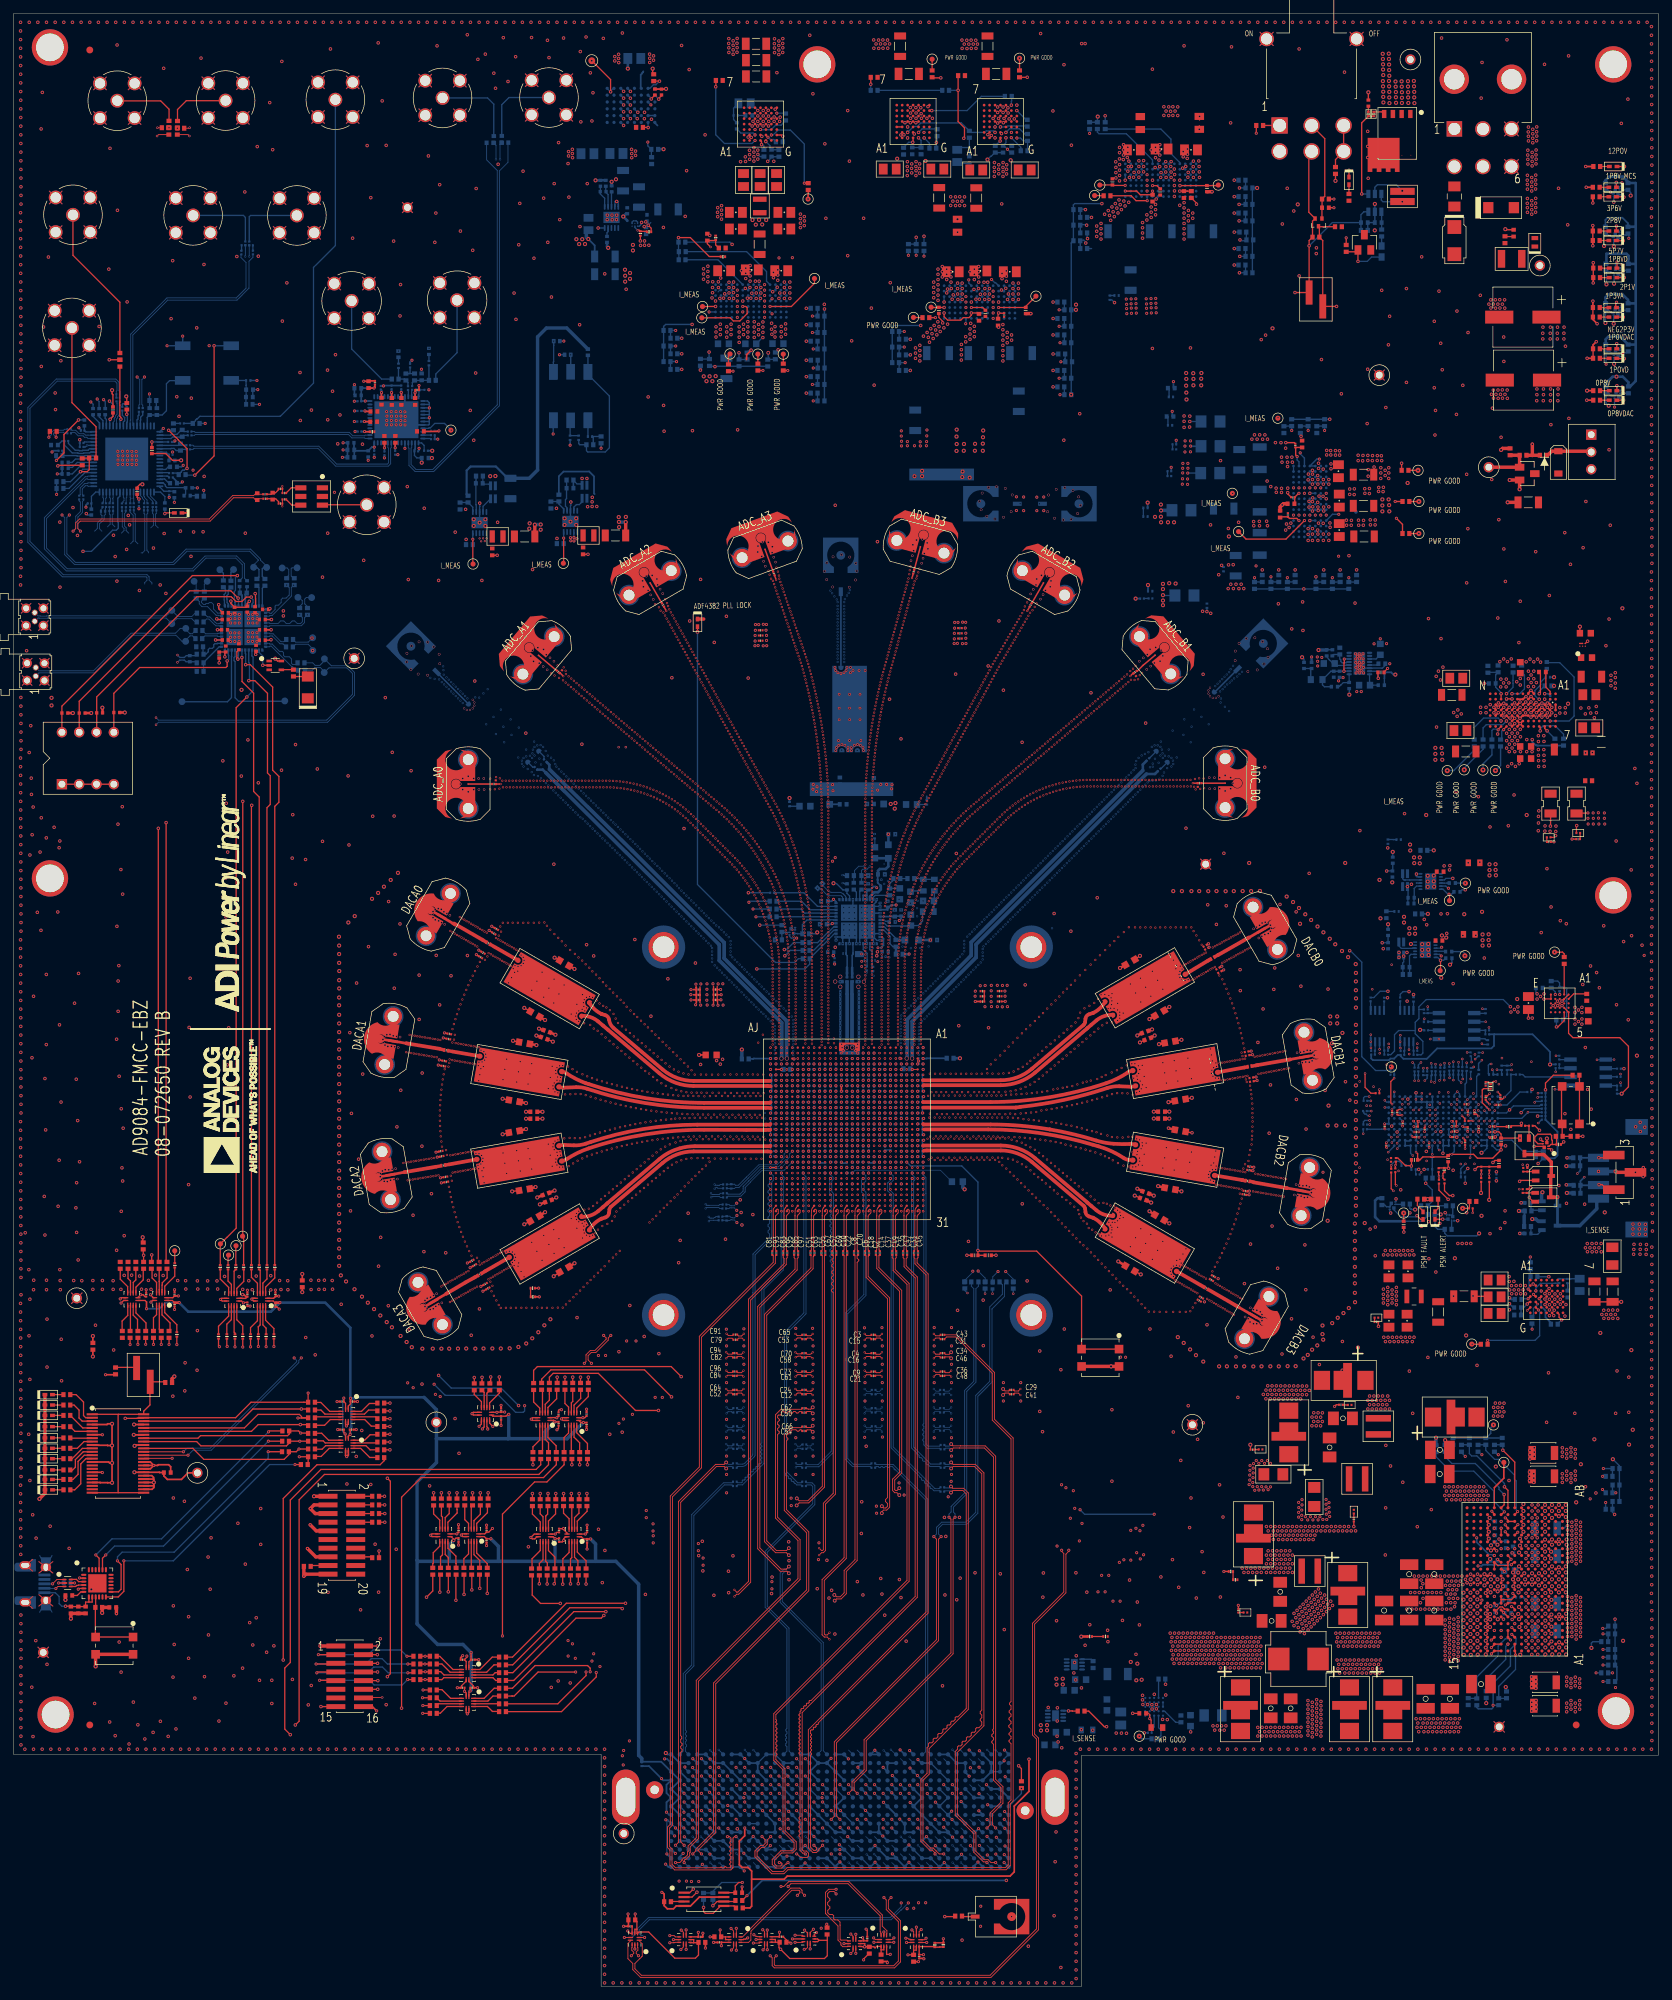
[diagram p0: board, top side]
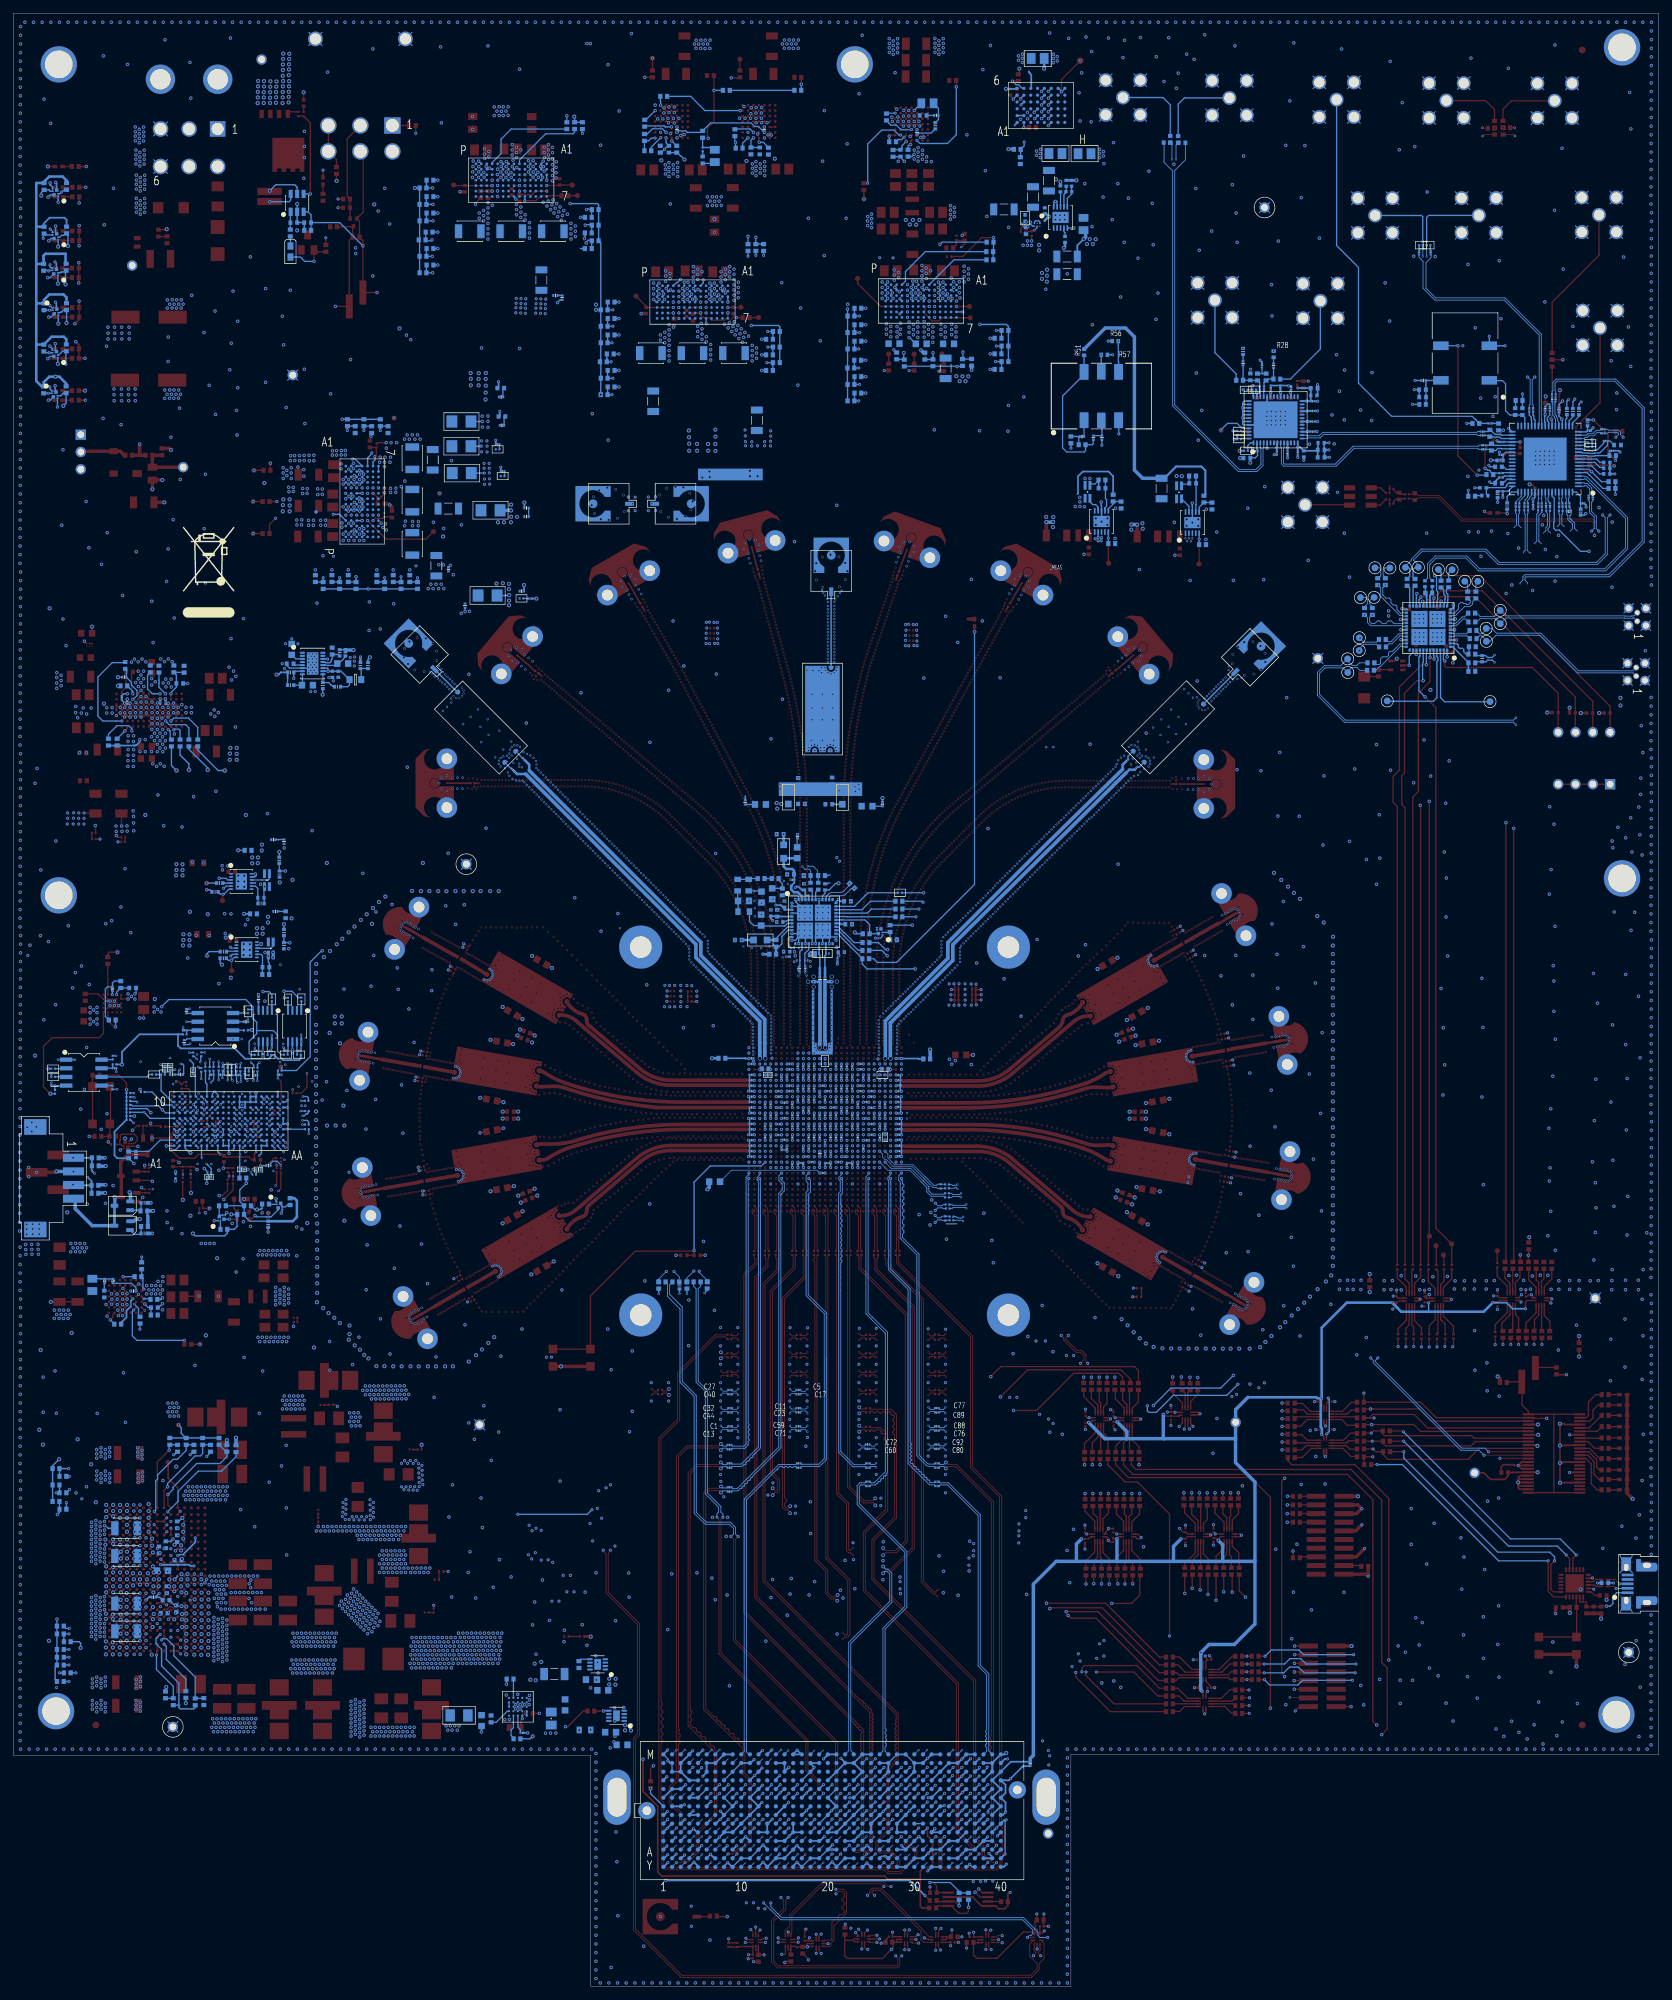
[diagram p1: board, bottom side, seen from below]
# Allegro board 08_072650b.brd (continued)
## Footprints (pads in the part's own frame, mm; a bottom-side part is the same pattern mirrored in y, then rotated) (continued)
BGA330_22X15H337
  round 0.457 smd: A1(-10.5,-7) A2(-10.5,-6) A3(-10.5,-5) A4(-10.5,-4) A5(-10.5,-3) A6(-10.5,-2) A7(-10.5,-1) A8(-10.5,0) A9(-10.5,1) A10(-10.5,2) A11(-10.5,3) A12(-10.5,4) A13(-10.5,5) A14(-10.5,6) A15(-10.5,7) AA1(9.5,-7) AA2(9.5,-6) AA3(9.5,-5) AA4(9.5,-4) AA5(9.5,-3) AA6(9.5,-2) AA7(9.5,-1) AA8(9.5,0) AA9(9.5,1) AA10(9.5,2) AA11(9.5,3) AA12(9.5,4) AA13(9.5,5) AA14(9.5,6) AA15(9.5,7) AB1(10.5,-7) AB2(10.5,-6) AB3(10.5,-5) AB4(10.5,-4) AB5(10.5,-3) AB6(10.5,-2) AB7(10.5,-1) AB8(10.5,0) AB9(10.5,1) AB10(10.5,2) AB11(10.5,3) AB12(10.5,4) AB13(10.5,5) AB14(10.5,6) AB15(10.5,7) B1(-9.5,-7) B2(-9.5,-6) B3(-9.5,-5) B4(-9.5,-4) B5(-9.5,-3) B6(-9.5,-2) B7(-9.5,-1) B8(-9.5,0) B9(-9.5,1) B10(-9.5,2) B11(-9.5,3) B12(-9.5,4) B13(-9.5,5) B14(-9.5,6) B15(-9.5,7) C1(-8.5,-7) C2(-8.5,-6) C3(-8.5,-5) C4(-8.5,-4) C5(-8.5,-3) C6(-8.5,-2) C7(-8.5,-1) C8(-8.5,0) C9(-8.5,1) C10(-8.5,2) C11(-8.5,3) C12(-8.5,4) C13(-8.5,5) C14(-8.5,6) C15(-8.5,7) D1(-7.5,-7) D2(-7.5,-6) D3(-7.5,-5) D4(-7.5,-4) D5(-7.5,-3) D6(-7.5,-2) D7(-7.5,-1) D8(-7.5,0) D9(-7.5,1) D10(-7.5,2) D11(-7.5,3) D12(-7.5,4) D13(-7.5,5) D14(-7.5,6) D15(-7.5,7) E1(-6.5,-7) E2(-6.5,-6) E3(-6.5,-5) E4(-6.5,-4) E5(-6.5,-3) E6(-6.5,-2) E7(-6.5,-1) E8(-6.5,0) E9(-6.5,1) E10(-6.5,2) E11(-6.5,3) E12(-6.5,4) E13(-6.5,5) E14(-6.5,6) E15(-6.5,7) F1(-5.5,-7) F2(-5.5,-6) F3(-5.5,-5) F4(-5.5,-4) F5(-5.5,-3) F6(-5.5,-2) F7(-5.5,-1) F8(-5.5,0) F9(-5.5,1) F10(-5.5,2) F11(-5.5,3) F12(-5.5,4) F13(-5.5,5) F14(-5.5,6) F15(-5.5,7) G1(-4.5,-7) G2(-4.5,-6) G3(-4.5,-5) G4(-4.5,-4) G5(-4.5,-3) G6(-4.5,-2) G7(-4.5,-1) G8(-4.5,0) G9(-4.5,1) G10(-4.5,2) G11(-4.5,3) G12(-4.5,4) G13(-4.5,5) G14(-4.5,6) G15(-4.5,7) H1(-3.5,-7) H2(-3.5,-6) H3(-3.5,-5) H4(-3.5,-4) H5(-3.5,-3) H6(-3.5,-2) H7(-3.5,-1) H8(-3.5,0) H9(-3.5,1) H10(-3.5,2) H11(-3.5,3) H12(-3.5,4) H13(-3.5,5) H14(-3.5,6) H15(-3.5,7) J1(-2.5,-7) J2(-2.5,-6) J3(-2.5,-5) J4(-2.5,-4) J5(-2.5,-3) J6(-2.5,-2) J7(-2.5,-1) J8(-2.5,0) J9(-2.5,1) J10(-2.5,2) J11(-2.5,3) J12(-2.5,4) J13(-2.5,5) J14(-2.5,6) J15(-2.5,7) K1(-1.5,-7) K2(-1.5,-6) K3(-1.5,-5) K4(-1.5,-4) K5(-1.5,-3) K6(-1.5,-2) K7(-1.5,-1) K8(-1.5,0) K9(-1.5,1) K10(-1.5,2) K11(-1.5,3) K12(-1.5,4) K13(-1.5,5) K14(-1.5,6) K15(-1.5,7) L1(-0.5,-7) L2(-0.5,-6) L3(-0.5,-5) L4(-0.5,-4) L5(-0.5,-3) L6(-0.5,-2) L7(-0.5,-1) L8(-0.5,0) L9(-0.5,1) L10(-0.5,2) L11(-0.5,3) L12(-0.5,4) L13(-0.5,5) L14(-0.5,6) L15(-0.5,7) M1(0.5,-7) M2(0.5,-6) M3(0.5,-5) M4(0.5,-4) M5(0.5,-3) M6(0.5,-2) M7(0.5,-1) M8(0.5,0) M9(0.5,1) M10(0.5,2) M11(0.5,3) M12(0.5,4) M13(0.5,5) M14(0.5,6) M15(0.5,7) N1(1.5,-7) N2(1.5,-6) N3(1.5,-5) N4(1.5,-4) N5(1.5,-3) N6(1.5,-2) N7(1.5,-1) N8(1.5,0) N9(1.5,1) N10(1.5,2) N11(1.5,3) N12(1.5,4) N13(1.5,5) N14(1.5,6) N15(1.5,7) P1(2.5,-7) P2(2.5,-6) P3(2.5,-5) P4(2.5,-4) P5(2.5,-3) P6(2.5,-2) P7(2.5,-1) P8(2.5,0) P9(2.5,1) P10(2.5,2) P11(2.5,3) P12(2.5,4) P13(2.5,5) P14(2.5,6) P15(2.5,7) R1(3.5,-7) R2(3.5,-6) R3(3.5,-5) R4(3.5,-4) R5(3.5,-3) R6(3.5,-2) R7(3.5,-1) R8(3.5,0) R9(3.5,1) R10(3.5,2) R11(3.5,3) R12(3.5,4) R13(3.5,5) R14(3.5,6) R15(3.5,7) T1(4.5,-7) T2(4.5,-6) T3(4.5,-5) T4(4.5,-4) T5(4.5,-3) T6(4.5,-2) T7(4.5,-1) T8(4.5,0) T9(4.5,1) T10(4.5,2) T11(4.5,3) T12(4.5,4) T13(4.5,5) T14(4.5,6) T15(4.5,7) U1(5.5,-7) U2(5.5,-6) U3(5.5,-5) U4(5.5,-4) U5(5.5,-3) U6(5.5,-2) U7(5.5,-1) U8(5.5,0) U9(5.5,1) U10(5.5,2) U11(5.5,3) U12(5.5,4) U13(5.5,5) U14(5.5,6) U15(5.5,7) V1(6.5,-7) V2(6.5,-6) V3(6.5,-5) V4(6.5,-4) V5(6.5,-3) V6(6.5,-2) V7(6.5,-1) V8(6.5,0) V9(6.5,1) V10(6.5,2) V11(6.5,3) V12(6.5,4) V13(6.5,5) V14(6.5,6) V15(6.5,7) W1(7.5,-7) W2(7.5,-6) W3(7.5,-5) W4(7.5,-4) W5(7.5,-3) W6(7.5,-2) W7(7.5,-1) W8(7.5,0) W9(7.5,1) W10(7.5,2) W11(7.5,3) W12(7.5,4) W13(7.5,5) W14(7.5,6) W15(7.5,7) Y1(8.5,-7) Y2(8.5,-6) Y3(8.5,-5) Y4(8.5,-4) Y5(8.5,-3) Y6(8.5,-2) Y7(8.5,-1) Y8(8.5,0) Y9(8.5,1) Y10(8.5,2) Y11(8.5,3) Y12(8.5,4) Y13(8.5,5) Y14(8.5,6) Y15(8.5,7)
BGA899
  round 0.356 smd: A1(-11.2,-12) A2(-11.2,-11.2) A3(-11.2,-10.4) A4(-11.2,-9.6) A5(-11.2,-8.8) A6(-11.2,-8) A7(-11.2,-7.2) A8(-11.2,-6.4) A9(-11.2,-5.6) A10(-11.2,-4.8) A11(-11.2,-4) A12(-11.2,-3.2) A13(-11.2,-2.4) A14(-11.2,-1.6) A15(-11.2,-0.8) A16(-11.2,0) A17(-11.2,0.8) A18(-11.2,1.6) A19(-11.2,2.4) A20(-11.2,3.2) A21(-11.2,4) A22(-11.2,4.8) A23(-11.2,5.6) A24(-11.2,6.4) A25(-11.2,7.2) A26(-11.2,8) A27(-11.2,8.8) A28(-11.2,9.6) A29(-11.2,10.4) A30(-11.2,11.2) A31(-11.2,12) AA1(4.8,-12) AA2(4.8,-11.2) AA3(4.8,-10.4) AA4(4.8,-9.6) AA5(4.8,-8.8) AA6(4.8,-8) AA7(4.8,-7.2) AA8(4.8,-6.4) AA9(4.8,-5.6) AA10(4.8,-4.8) AA11(4.8,-4) AA12(4.8,-3.2) AA13(4.8,-2.4) AA14(4.8,-1.6) AA15(4.8,-0.8) AA16(4.8,0) AA17(4.8,0.8) AA18(4.8,1.6) AA19(4.8,2.4) AA20(4.8,3.2) AA21(4.8,4) AA22(4.8,4.8) AA23(4.8,5.6) AA24(4.8,6.4) AA25(4.8,7.2) AA26(4.8,8) AA27(4.8,8.8) AA28(4.8,9.6) AA29(4.8,10.4) AA30(4.8,11.2) AA31(4.8,12) AB1(5.6,-12) AB2(5.6,-11.2) AB3(5.6,-10.4) AB4(5.6,-9.6) AB5(5.6,-8.8) AB6(5.6,-8) AB7(5.6,-7.2) AB8(5.6,-6.4) AB9(5.6,-5.6) AB10(5.6,-4.8) AB11(5.6,-4) AB12(5.6,-3.2) AB13(5.6,-2.4) AB14(5.6,-1.6) AB15(5.6,-0.8) AB16(5.6,0) AB17(5.6,0.8) AB18(5.6,1.6) AB19(5.6,2.4) AB20(5.6,3.2) AB21(5.6,4) AB22(5.6,4.8) AB23(5.6,5.6) AB24(5.6,6.4) AB25(5.6,7.2) AB26(5.6,8) AB27(5.6,8.8) AB28(5.6,9.6) AB29(5.6,10.4) AB30(5.6,11.2) AB31(5.6,12) AC1(6.4,-12) AC2(6.4,-11.2) AC3(6.4,-10.4) AC4(6.4,-9.6) AC5(6.4,-8.8) AC6(6.4,-8) AC7(6.4,-7.2) AC8(6.4,-6.4) AC9(6.4,-5.6) AC10(6.4,-4.8) AC11(6.4,-4) AC12(6.4,-3.2) AC13(6.4,-2.4) AC14(6.4,-1.6) AC15(6.4,-0.8) AC16(6.4,0) AC17(6.4,0.8) AC18(6.4,1.6) AC19(6.4,2.4) AC20(6.4,3.2) AC21(6.4,4) AC22(6.4,4.8) AC23(6.4,5.6) AC24(6.4,6.4) AC25(6.4,7.2) AC26(6.4,8) AC27(6.4,8.8) AC28(6.4,9.6) AC29(6.4,10.4) AC30(6.4,11.2) AC31(6.4,12) AD1(7.2,-12) AD2(7.2,-11.2) AD3(7.2,-10.4) AD4(7.2,-9.6) AD5(7.2,-8.8) AD6(7.2,-8) AD7(7.2,-7.2) AD8(7.2,-6.4) AD9(7.2,-5.6) AD10(7.2,-4.8) AD11(7.2,-4) AD12(7.2,-3.2) AD13(7.2,-2.4) AD14(7.2,-1.6) AD15(7.2,-0.8) AD16(7.2,0) AD17(7.2,0.8) AD18(7.2,1.6) AD19(7.2,2.4) AD20(7.2,3.2) AD21(7.2,4) AD22(7.2,4.8) AD23(7.2,5.6) AD24(7.2,6.4) AD25(7.2,7.2) AD26(7.2,8) AD27(7.2,8.8) AD28(7.2,9.6) AD29(7.2,10.4) AD30(7.2,11.2) AD31(7.2,12) AE1(8,-12) AE2(8,-11.2) AE3(8,-10.4) AE4(8,-9.6) AE5(8,-8.8) AE6(8,-8) AE7(8,-7.2) AE8(8,-6.4) AE9(8,-5.6) AE10(8,-4.8) AE11(8,-4) AE12(8,-3.2) AE13(8,-2.4) AE14(8,-1.6) AE15(8,-0.8) AE16(8,0) AE17(8,0.8) AE18(8,1.6) AE19(8,2.4) AE20(8,3.2) AE21(8,4) AE22(8,4.8) AE23(8,5.6) AE24(8,6.4) AE25(8,7.2) AE26(8,8) AE27(8,8.8) AE28(8,9.6) AE29(8,10.4) AE30(8,11.2) AE31(8,12) AF1(8.8,-12) AF2(8.8,-11.2) AF3(8.8,-10.4) AF4(8.8,-9.6) AF5(8.8,-8.8) AF6(8.8,-8) AF7(8.8,-7.2) AF8(8.8,-6.4) AF9(8.8,-5.6) AF10(8.8,-4.8) AF11(8.8,-4) AF12(8.8,-3.2) AF13(8.8,-2.4) AF14(8.8,-1.6) AF15(8.8,-0.8) AF16(8.8,0) AF17(8.8,0.8) AF18(8.8,1.6) AF19(8.8,2.4) AF20(8.8,3.2) AF21(8.8,4) AF22(8.8,4.8) AF23(8.8,5.6) AF24(8.8,6.4) AF25(8.8,7.2) AF26(8.8,8) AF27(8.8,8.8) AF28(8.8,9.6) AF29(8.8,10.4) AF30(8.8,11.2) AF31(8.8,12) AG1(9.6,-12) AG2(9.6,-11.2) AG3(9.6,-10.4) AG4(9.6,-9.6) AG5(9.6,-8.8) AG6(9.6,-8) AG7(9.6,-7.2) AG8(9.6,-6.4) AG9(9.6,-5.6) AG10(9.6,-4.8) AG11(9.6,-4) AG12(9.6,-3.2) AG13(9.6,-2.4) AG14(9.6,-1.6) AG15(9.6,-0.8) AG16(9.6,0) AG17(9.6,0.8) AG18(9.6,1.6) AG19(9.6,2.4) AG20(9.6,3.2) AG21(9.6,4) AG22(9.6,4.8) AG23(9.6,5.6) AG24(9.6,6.4) AG25(9.6,7.2) AG26(9.6,8) AG27(9.6,8.8) AG28(9.6,9.6) AG29(9.6,10.4) AG30(9.6,11.2) AG31(9.6,12) AH1(10.4,-12) AH2(10.4,-11.2) AH3(10.4,-10.4) AH4(10.4,-9.6) AH5(10.4,-8.8) AH6(10.4,-8) AH7(10.4,-7.2) AH8(10.4,-6.4) AH9(10.4,-5.6) AH10(10.4,-4.8) AH11(10.4,-4) AH12(10.4,-3.2) AH13(10.4,-2.4) AH14(10.4,-1.6) AH15(10.4,-0.8) AH16(10.4,0) AH17(10.4,0.8) AH18(10.4,1.6) AH19(10.4,2.4) AH20(10.4,3.2) AH21(10.4,4) AH22(10.4,4.8) AH23(10.4,5.6) AH24(10.4,6.4) AH25(10.4,7.2) AH26(10.4,8) AH27(10.4,8.8) AH28(10.4,9.6) AH29(10.4,10.4) AH30(10.4,11.2) AH31(10.4,12) AJ1(11.2,-12) AJ2(11.2,-11.2) AJ3(11.2,-10.4) AJ4(11.2,-9.6) AJ5(11.2,-8.8) AJ6(11.2,-8) AJ7(11.2,-7.2) AJ8(11.2,-6.4) AJ9(11.2,-5.6) AJ10(11.2,-4.8) AJ11(11.2,-4) AJ12(11.2,-3.2) AJ13(11.2,-2.4) AJ14(11.2,-1.6) AJ15(11.2,-0.8) AJ16(11.2,0) AJ17(11.2,0.8) AJ18(11.2,1.6) AJ19(11.2,2.4) AJ20(11.2,3.2) AJ21(11.2,4) AJ22(11.2,4.8) AJ23(11.2,5.6) AJ24(11.2,6.4) AJ25(11.2,7.2) AJ26(11.2,8) AJ27(11.2,8.8) AJ28(11.2,9.6) AJ29(11.2,10.4) AJ30(11.2,11.2) AJ31(11.2,12) B1(-10.4,-12) B2(-10.4,-11.2) B3(-10.4,-10.4) B4(-10.4,-9.6) B5(-10.4,-8.8) B6(-10.4,-8) B7(-10.4,-7.2) B8(-10.4,-6.4) B9(-10.4,-5.6) B10(-10.4,-4.8) B11(-10.4,-4) B12(-10.4,-3.2) B13(-10.4,-2.4) B14(-10.4,-1.6) B15(-10.4,-0.8) B16(-10.4,0) B17(-10.4,0.8) B18(-10.4,1.6) B19(-10.4,2.4) B20(-10.4,3.2) B21(-10.4,4) B22(-10.4,4.8) B23(-10.4,5.6) B24(-10.4,6.4) B25(-10.4,7.2) B26(-10.4,8) B27(-10.4,8.8) B28(-10.4,9.6) B29(-10.4,10.4) B30(-10.4,11.2) B31(-10.4,12) C1(-9.6,-12) C2(-9.6,-11.2) C3(-9.6,-10.4) C4(-9.6,-9.6) C5(-9.6,-8.8) C6(-9.6,-8) C7(-9.6,-7.2) C8(-9.6,-6.4) C9(-9.6,-5.6) C10(-9.6,-4.8) C11(-9.6,-4) C12(-9.6,-3.2) C13(-9.6,-2.4) C14(-9.6,-1.6) C15(-9.6,-0.8) C16(-9.6,0) C17(-9.6,0.8) C18(-9.6,1.6) C19(-9.6,2.4) C20(-9.6,3.2) C21(-9.6,4) C22(-9.6,4.8) C23(-9.6,5.6) C24(-9.6,6.4) C25(-9.6,7.2) C26(-9.6,8) C27(-9.6,8.8) C28(-9.6,9.6) C29(-9.6,10.4) C30(-9.6,11.2) C31(-9.6,12) D1(-8.8,-12) D2(-8.8,-11.2) D3(-8.8,-10.4) D4(-8.8,-9.6) D5(-8.8,-8.8) D6(-8.8,-8) D7(-8.8,-7.2) D8(-8.8,-6.4) D9(-8.8,-5.6) D10(-8.8,-4.8) D11(-8.8,-4) D12(-8.8,-3.2) D13(-8.8,-2.4) D14(-8.8,-1.6) D15(-8.8,-0.8) D16(-8.8,0) D17(-8.8,0.8) D18(-8.8,1.6) D19(-8.8,2.4) D20(-8.8,3.2) D21(-8.8,4) D22(-8.8,4.8) D23(-8.8,5.6) D24(-8.8,6.4) D25(-8.8,7.2) D26(-8.8,8) D27(-8.8,8.8) D28(-8.8,9.6) D29(-8.8,10.4) D30(-8.8,11.2) D31(-8.8,12) E1(-8,-12) E2(-8,-11.2) E3(-8,-10.4) E4(-8,-9.6) E5(-8,-8.8) E6(-8,-8) E7(-8,-7.2) E8(-8,-6.4) E9(-8,-5.6) E10(-8,-4.8) E11(-8,-4) E12(-8,-3.2) E13(-8,-2.4) E14(-8,-1.6) E15(-8,-0.8) E16(-8,0) E17(-8,0.8) E18(-8,1.6) E19(-8,2.4) E20(-8,3.2) E21(-8,4) E22(-8,4.8) E23(-8,5.6) E24(-8,6.4) E25(-8,7.2) E26(-8,8) E27(-8,8.8) E28(-8,9.6) E29(-8,10.4) E30(-8,11.2) E31(-8,12) F1(-7.2,-12) F2(-7.2,-11.2) F3(-7.2,-10.4) F4(-7.2,-9.6) F5(-7.2,-8.8) F6(-7.2,-8) F7(-7.2,-7.2) F8(-7.2,-6.4) F9(-7.2,-5.6) F10(-7.2,-4.8) F11(-7.2,-4) F12(-7.2,-3.2) F13(-7.2,-2.4) F14(-7.2,-1.6) F15(-7.2,-0.8) F16(-7.2,0) F17(-7.2,0.8) F18(-7.2,1.6) F19(-7.2,2.4) F20(-7.2,3.2) F21(-7.2,4) F22(-7.2,4.8) F23(-7.2,5.6) F24(-7.2,6.4) F25(-7.2,7.2) F26(-7.2,8) F27(-7.2,8.8) F28(-7.2,9.6) F29(-7.2,10.4) F30(-7.2,11.2) F31(-7.2,12) G1(-6.4,-12) G2(-6.4,-11.2) G3(-6.4,-10.4) G4(-6.4,-9.6) G5(-6.4,-8.8) G6(-6.4,-8) G7(-6.4,-7.2) G8(-6.4,-6.4) G9(-6.4,-5.6) G10(-6.4,-4.8) G11(-6.4,-4) G12(-6.4,-3.2) G13(-6.4,-2.4) G14(-6.4,-1.6) G15(-6.4,-0.8) G16(-6.4,0) G17(-6.4,0.8) G18(-6.4,1.6) G19(-6.4,2.4) G20(-6.4,3.2) G21(-6.4,4) G22(-6.4,4.8) G23(-6.4,5.6) G24(-6.4,6.4) G25(-6.4,7.2) G26(-6.4,8) G27(-6.4,8.8) G28(-6.4,9.6) G29(-6.4,10.4) G30(-6.4,11.2) G31(-6.4,12) H1(-5.6,-12) H2(-5.6,-11.2) H3(-5.6,-10.4) H4(-5.6,-9.6) H5(-5.6,-8.8) H6(-5.6,-8) H7(-5.6,-7.2) H8(-5.6,-6.4) H9(-5.6,-5.6) H10(-5.6,-4.8) H11(-5.6,-4) H12(-5.6,-3.2) H13(-5.6,-2.4) H14(-5.6,-1.6) H15(-5.6,-0.8) H16(-5.6,0) H17(-5.6,0.8) H18(-5.6,1.6) H19(-5.6,2.4) H20(-5.6,3.2) H21(-5.6,4) H22(-5.6,4.8) H23(-5.6,5.6) H24(-5.6,6.4) H25(-5.6,7.2) H26(-5.6,8) H27(-5.6,8.8) H28(-5.6,9.6) H29(-5.6,10.4) H30(-5.6,11.2) H31(-5.6,12) J1(-4.8,-12) J2(-4.8,-11.2) J3(-4.8,-10.4) J4(-4.8,-9.6) J5(-4.8,-8.8) J6(-4.8,-8) J7(-4.8,-7.2) J8(-4.8,-6.4) J9(-4.8,-5.6) J10(-4.8,-4.8) J11(-4.8,-4) J12(-4.8,-3.2) J13(-4.8,-2.4) J14(-4.8,-1.6) J15(-4.8,-0.8) J16(-4.8,0) J17(-4.8,0.8) J18(-4.8,1.6) J19(-4.8,2.4) J20(-4.8,3.2) J21(-4.8,4) J22(-4.8,4.8) J23(-4.8,5.6) J24(-4.8,6.4) J25(-4.8,7.2) J26(-4.8,8) J27(-4.8,8.8) J28(-4.8,9.6) J29(-4.8,10.4) J30(-4.8,11.2) J31(-4.8,12) K1(-4,-12) K2(-4,-11.2) K3(-4,-10.4) K4(-4,-9.6) K5(-4,-8.8) K6(-4,-8) K7(-4,-7.2) K8(-4,-6.4) K9(-4,-5.6) K10(-4,-4.8) K11(-4,-4) K12(-4,-3.2) K13(-4,-2.4) K14(-4,-1.6) K15(-4,-0.8) K16(-4,0) K17(-4,0.8) K18(-4,1.6) K19(-4,2.4) K20(-4,3.2) K21(-4,4) K22(-4,4.8) K23(-4,5.6) K24(-4,6.4) K25(-4,7.2) K26(-4,8) K27(-4,8.8) K28(-4,9.6) K29(-4,10.4) K30(-4,11.2) K31(-4,12) L1(-3.2,-12) L2(-3.2,-11.2) L3(-3.2,-10.4) L4(-3.2,-9.6) L5(-3.2,-8.8) L6(-3.2,-8) L7(-3.2,-7.2) L8(-3.2,-6.4) L9(-3.2,-5.6) L10(-3.2,-4.8) L11(-3.2,-4) L12(-3.2,-3.2) L13(-3.2,-2.4) L14(-3.2,-1.6) L15(-3.2,-0.8) L16(-3.2,0) L17(-3.2,0.8) L18(-3.2,1.6) L19(-3.2,2.4) L20(-3.2,3.2) L21(-3.2,4) L22(-3.2,4.8) L23(-3.2,5.6) L24(-3.2,6.4) L25(-3.2,7.2) L26(-3.2,8) L27(-3.2,8.8) L28(-3.2,9.6) L29(-3.2,10.4) L30(-3.2,11.2) L31(-3.2,12) M1(-2.4,-12) M2(-2.4,-11.2) M3(-2.4,-10.4) M4(-2.4,-9.6) M5(-2.4,-8.8) M6(-2.4,-8) M7(-2.4,-7.2) M8(-2.4,-6.4) M9(-2.4,-5.6) M10(-2.4,-4.8) M11(-2.4,-4) M12(-2.4,-3.2) M13(-2.4,-2.4) M14(-2.4,-1.6) M15(-2.4,-0.8) M16(-2.4,0) M17(-2.4,0.8) M18(-2.4,1.6) M19(-2.4,2.4) M20(-2.4,3.2) M21(-2.4,4) M22(-2.4,4.8) M23(-2.4,5.6) M24(-2.4,6.4) M25(-2.4,7.2) M26(-2.4,8) M27(-2.4,8.8) M28(-2.4,9.6) M29(-2.4,10.4) M30(-2.4,11.2) M31(-2.4,12) N1(-1.6,-12) N2(-1.6,-11.2) N3(-1.6,-10.4) N4(-1.6,-9.6) N5(-1.6,-8.8) N6(-1.6,-8) N7(-1.6,-7.2) N8(-1.6,-6.4) N9(-1.6,-5.6) N10(-1.6,-4.8) N11(-1.6,-4) N12(-1.6,-3.2) N13(-1.6,-2.4) N14(-1.6,-1.6) N15(-1.6,-0.8) N16(-1.6,0) N17(-1.6,0.8) N18(-1.6,1.6) N19(-1.6,2.4) N20(-1.6,3.2) N21(-1.6,4) N22(-1.6,4.8) N23(-1.6,5.6) N24(-1.6,6.4) N25(-1.6,7.2) N26(-1.6,8) N27(-1.6,8.8) N28(-1.6,9.6) N29(-1.6,10.4) N30(-1.6,11.2) N31(-1.6,12) P1(-0.8,-12) P2(-0.8,-11.2) P3(-0.8,-10.4) P4(-0.8,-9.6) P5(-0.8,-8.8) P6(-0.8,-8) P7(-0.8,-7.2) P8(-0.8,-6.4) P9(-0.8,-5.6) P10(-0.8,-4.8) P11(-0.8,-4) P12(-0.8,-3.2) P13(-0.8,-2.4) P14(-0.8,-1.6) P15(-0.8,-0.8) P16(-0.8,0) P17(-0.8,0.8) P18(-0.8,1.6) P19(-0.8,2.4) P20(-0.8,3.2) P21(-0.8,4) P22(-0.8,4.8) P23(-0.8,5.6) P24(-0.8,6.4) P25(-0.8,7.2) P26(-0.8,8) P27(-0.8,8.8) P28(-0.8,9.6) P29(-0.8,10.4) P30(-0.8,11.2) P31(-0.8,12) R1(0,-12) R2(0,-11.2) R3(0,-10.4) R4(0,-9.6) R5(0,-8.8) R6(0,-8) R7(0,-7.2) R8(0,-6.4) R9(0,-5.6) R10(0,-4.8) R11(0,-4) R12(0,-3.2) R13(0,-2.4) R14(0,-1.6) R15(0,-0.8) R16(0,0) R17(0,0.8) R18(0,1.6) R19(0,2.4) R20(0,3.2) R21(0,4) R22(0,4.8) R23(0,5.6) R24(0,6.4) R25(0,7.2) R26(0,8) R27(0,8.8) R28(0,9.6) R29(0,10.4) R30(0,11.2) R31(0,12) T1(0.8,-12) T2(0.8,-11.2) T3(0.8,-10.4) T4(0.8,-9.6) T5(0.8,-8.8) T6(0.8,-8) T7(0.8,-7.2) T8(0.8,-6.4) T9(0.8,-5.6) T10(0.8,-4.8) T11(0.8,-4) T12(0.8,-3.2) T13(0.8,-2.4) T14(0.8,-1.6) T15(0.8,-0.8) T16(0.8,0) T17(0.8,0.8) T18(0.8,1.6) T19(0.8,2.4) T20(0.8,3.2) T21(0.8,4) T22(0.8,4.8) T23(0.8,5.6) T24(0.8,6.4) T25(0.8,7.2) T26(0.8,8) T27(0.8,8.8) T28(0.8,9.6) T29(0.8,10.4) T30(0.8,11.2) T31(0.8,12) U1(1.6,-12) U2(1.6,-11.2) U3(1.6,-10.4) U4(1.6,-9.6) U5(1.6,-8.8) U6(1.6,-8) U7(1.6,-7.2) U8(1.6,-6.4) U9(1.6,-5.6) U10(1.6,-4.8) U11(1.6,-4) U12(1.6,-3.2) U13(1.6,-2.4) U14(1.6,-1.6) U15(1.6,-0.8) U16(1.6,0) U17(1.6,0.8) U18(1.6,1.6) U19(1.6,2.4) U20(1.6,3.2) U21(1.6,4) U22(1.6,4.8) U23(1.6,5.6) U24(1.6,6.4) U25(1.6,7.2) U26(1.6,8) U27(1.6,8.8) U28(1.6,9.6) U29(1.6,10.4) U30(1.6,11.2) U31(1.6,12) V1(2.4,-12) V2(2.4,-11.2) V3(2.4,-10.4) V4(2.4,-9.6) V5(2.4,-8.8) V6(2.4,-8) V7(2.4,-7.2) V8(2.4,-6.4) V9(2.4,-5.6) V10(2.4,-4.8) V11(2.4,-4) V12(2.4,-3.2) V13(2.4,-2.4) V14(2.4,-1.6) V15(2.4,-0.8) V16(2.4,0) V17(2.4,0.8) V18(2.4,1.6) V19(2.4,2.4) V20(2.4,3.2) V21(2.4,4) V22(2.4,4.8) V23(2.4,5.6) V24(2.4,6.4) V25(2.4,7.2) V26(2.4,8) V27(2.4,8.8) V28(2.4,9.6) V29(2.4,10.4) V30(2.4,11.2) V31(2.4,12) W1(3.2,-12) W2(3.2,-11.2) W3(3.2,-10.4) W4(3.2,-9.6) W5(3.2,-8.8) W6(3.2,-8) W7(3.2,-7.2) W8(3.2,-6.4) W9(3.2,-5.6) W10(3.2,-4.8) W11(3.2,-4) W12(3.2,-3.2) W13(3.2,-2.4) W14(3.2,-1.6) W15(3.2,-0.8) W16(3.2,0) W17(3.2,0.8) W18(3.2,1.6) W19(3.2,2.4) W20(3.2,3.2) W21(3.2,4) W22(3.2,4.8) W23(3.2,5.6) W24(3.2,6.4) W25(3.2,7.2) W26(3.2,8) W27(3.2,8.8) W28(3.2,9.6) W29(3.2,10.4) W30(3.2,11.2) W31(3.2,12) Y1(4,-12) Y2(4,-11.2) Y3(4,-10.4) Y4(4,-9.6) Y5(4,-8.8) Y6(4,-8) Y7(4,-7.2) Y8(4,-6.4) Y9(4,-5.6) Y10(4,-4.8) Y11(4,-4) Y12(4,-3.2) Y13(4,-2.4) Y14(4,-1.6) Y15(4,-0.8) Y16(4,0) Y17(4,0.8) Y18(4,1.6) Y19(4,2.4) Y20(4,3.2) Y21(4,4) Y22(4,4.8) Y23(4,5.6) Y24(4,6.4) Y25(4,7.2) Y26(4,8) Y27(4,8.8) Y28(4,9.6) Y29(4,10.4) Y30(4,11.2) Y31(4,12)
C0201
  rect 0.305x0.33 smd: 1(-0.27,0) 2(0.27,0)
C0402
  rect 0.584x0.66 smd: 1(-0.5,0) 2(0.5,0)
C0402#2
  rect 0.483x0.559 smd: 1(-0.438,0) 2(0.438,0)
C0402H22
  rect 0.483x0.559 smd: 1(-0.438,0) 2(0.438,0)
C0402H22#2
  rect 0.559x0.508 smd: 1(-0.479,0) 2(0.479,0)
C0603
  rect 0.94x0.991 smd: 1(-0.8,0) 2(0.8,0)
C0805H53
  rect 1.295x1.6 smd: 1(-0.953,0) 2(0.953,0)
C0805H55
  rect 1.143x1.448 smd: 1(-0.9,0) 2(0.9,0)
C0805H60
  rect 1.295x1.6 smd: 1(-0.953,0) 2(0.953,0)
C0805H60_SP
  rect 1.295x0.457 smd: 1(-0.953,-0.356) 2(0.953,-0.356) 3(0.953,0.356) 4(-0.953,0.356)
C1206
  rect 1.143x1.803 smd: 1(-1.5,0) 2(1.5,0)
C1206H71
  rect 1.6x2.007 smd: 1(-1.397,0) 2(1.397,0)
C1210
  rect 1.575x2.692 smd: 1(-1.397,0) 2(1.397,0)
C1210H106
  rect 1.092x2.057 smd: 1(-1.646,0) 2(1.646,0)
C7343H79
  rect 2.388x2.794 smd: N1(3.194,0) P(-3.194,0)
  custom 0.673x0.673 smd: N2(0.138,0)
CNAMPHENOLSF1521-60070-XS
  round 2.616 hole 1.6 unplated: (-3.581,0) (3.581,0)
  custom 0.102x0.102 smd: 1(0,0)
  custom 1.206x1.206 smd: 2(0,1.27)
CNAMPHENOLSF1521-60070-XS#2
  round 2.616 hole 1.6 unplated: (-3.581,0) (3.581,0)
  round 0.254 smd: 1(0,0)
  custom 1.41x1.41 smd: 2(0,1.791)
CNFCI10103594-0001LF
  rect 0.406x1.753 smd: 1(-1.3,4.524) 2(-0.65,4.524) 3(0,4.524) 4(0.65,4.524) 5(1.3,4.524)
  oval 1.219x1.702 hole 0.711x1.194: 6(2.725,1.7) 7(-2.725,1.7)
  oval 1.168x1.549 hole 1.041x0.66: 8(2.425,4.73) 9(-2.425,4.73)
CNHDR2X8H251
  rect 0.737x2.794 smd: 1(-4.445,-2.032) 2(-4.445,2.032) 3(-3.175,-2.032) 4(-3.175,2.032) 5(-1.905,-2.032) 6(-1.905,2.032) 7(-0.635,-2.032) 8(-0.635,2.032) 9(0.635,-2.032) 10(0.635,2.032) 11(1.905,-2.032) 12(1.905,2.032) 13(3.175,-2.032) 14(3.175,2.032) 15(4.445,-2.032) 16(4.445,2.032)
CNHDR2X10H251
  rect 0.737x2.794 smd: 1(-5.715,-2.032) 2(-5.715,2.032) 3(-4.445,-2.032) 4(-4.445,2.032) 5(-3.175,-2.032) 6(-3.175,2.032) 7(-1.905,-2.032) 8(-1.905,2.032) 9(-0.635,-2.032) 10(-0.635,2.032) 11(0.635,-2.032) 12(0.635,2.032) 13(1.905,-2.032) 14(1.905,2.032) 15(3.175,-2.032) 16(3.175,2.032) 17(4.445,-2.032) 18(4.445,2.032) 19(5.715,-2.032) 20(5.715,2.032)
CNHDRRA2X3H451
  round 4.318 hole 2.997 unplated: (-0.013,7.29) (8.395,7.29)
  rect 2.286x2.286 hole 1.778: 1(0,0)
  round 2.286 hole 1.778: 2(4.191,0) 3(8.382,0) 4(0,-5.512) 5(4.191,-5.512) 6(8.382,-5.512)
CNHIROSEDF3EA-2P-2H
  rect 1.194x3.099 smd: 1(-3,4.749) 2(-1,4.749) 3(1,4.749) 4(3,4.749)
  rect 2.311x3.302 smd: G1(-7.526,-0.849) G2(7.526,-0.849)
CNJOHNSON142-0701-201
  round 2.032 hole 1.524: 1(0,0) 2(-2.54,2.54) 3(2.54,2.54) 4(2.54,-2.54) 5(-2.54,-2.54)
CNKEY5001TP
  round 1.524 hole 1.016: 1(0,0)
CNMOLEX22-23-2031
  rect 1.524x1.524 hole 1.016: 1(0,0)
  round 1.524 hole 1.016: 2(2.54,0) 3(5.08,0)
CNSAMTECASP-188588-01
  round 2.54 hole 1.27 unplated: (-27.191,0) (27.191,3.048)
  round 0.635 smd: A1(-24.765,-5.715) A2(-23.495,-5.715) A3(-22.225,-5.715) A4(-20.955,-5.715) A5(-19.685,-5.715) A6(-18.415,-5.715) A7(-17.145,-5.715) A8(-15.875,-5.715) A9(-14.605,-5.715) A10(-13.335,-5.715) A11(-12.065,-5.715) A12(-10.795,-5.715) A13(-9.525,-5.715) A14(-8.255,-5.715) A15(-6.985,-5.715) A16(-5.715,-5.715) A17(-4.445,-5.715) A18(-3.175,-5.715) A19(-1.905,-5.715) A20(-0.635,-5.715) A21(0.635,-5.715) A22(1.905,-5.715) A23(3.175,-5.715) A24(4.445,-5.715) A25(5.715,-5.715) A26(6.985,-5.715) A27(8.255,-5.715) A28(9.525,-5.715) A29(10.795,-5.715) A30(12.065,-5.715) A31(13.335,-5.715) A32(14.605,-5.715) A33(15.875,-5.715) A34(17.145,-5.715) A35(18.415,-5.715) A36(19.685,-5.715) A37(20.955,-5.715) A38(22.225,-5.715) A39(23.495,-5.715) A40(24.765,-5.715) B1(-24.765,-4.445) B2(-23.495,-4.445) B3(-22.225,-4.445) B4(-20.955,-4.445) B5(-19.685,-4.445) B6(-18.415,-4.445) B7(-17.145,-4.445) B8(-15.875,-4.445) B9(-14.605,-4.445) B10(-13.335,-4.445) B11(-12.065,-4.445) B12(-10.795,-4.445) B13(-9.525,-4.445) B14(-8.255,-4.445) B15(-6.985,-4.445) B16(-5.715,-4.445) B17(-4.445,-4.445) B18(-3.175,-4.445) B19(-1.905,-4.445) B20(-0.635,-4.445) B21(0.635,-4.445) B22(1.905,-4.445) B23(3.175,-4.445) B24(4.445,-4.445) B25(5.715,-4.445) B26(6.985,-4.445) B27(8.255,-4.445) B28(9.525,-4.445) B29(10.795,-4.445) B30(12.065,-4.445) B31(13.335,-4.445) B32(14.605,-4.445) B33(15.875,-4.445) B34(17.145,-4.445) B35(18.415,-4.445) B36(19.685,-4.445) B37(20.955,-4.445) B38(22.225,-4.445) B39(23.495,-4.445) B40(24.765,-4.445) C1(-24.765,-3.175) C2(-23.495,-3.175) C3(-22.225,-3.175) C4(-20.955,-3.175) C5(-19.685,-3.175) C6(-18.415,-3.175) C7(-17.145,-3.175) C8(-15.875,-3.175) C9(-14.605,-3.175) C10(-13.335,-3.175) C11(-12.065,-3.175) C12(-10.795,-3.175) C13(-9.525,-3.175) C14(-8.255,-3.175) C15(-6.985,-3.175) C16(-5.715,-3.175) C17(-4.445,-3.175) C18(-3.175,-3.175) C19(-1.905,-3.175) C20(-0.635,-3.175) C21(0.635,-3.175) C22(1.905,-3.175) C23(3.175,-3.175) C24(4.445,-3.175) C25(5.715,-3.175) C26(6.985,-3.175) C27(8.255,-3.175) C28(9.525,-3.175) C29(10.795,-3.175) C30(12.065,-3.175) C31(13.335,-3.175) C32(14.605,-3.175) C33(15.875,-3.175) C34(17.145,-3.175) C35(18.415,-3.175) C36(19.685,-3.175) C37(20.955,-3.175) C38(22.225,-3.175) C39(23.495,-3.175) C40(24.765,-3.175) D1(-24.765,-1.905) D2(-23.495,-1.905) D3(-22.225,-1.905) D4(-20.955,-1.905) D5(-19.685,-1.905) D6(-18.415,-1.905) D7(-17.145,-1.905) D8(-15.875,-1.905) D9(-14.605,-1.905) D10(-13.335,-1.905) D11(-12.065,-1.905) D12(-10.795,-1.905) D13(-9.525,-1.905) D14(-8.255,-1.905) D15(-6.985,-1.905) D16(-5.715,-1.905) D17(-4.445,-1.905) D18(-3.175,-1.905) D19(-1.905,-1.905) D20(-0.635,-1.905) D21(0.635,-1.905) D22(1.905,-1.905) D23(3.175,-1.905) D24(4.445,-1.905) D25(5.715,-1.905) D26(6.985,-1.905) D27(8.255,-1.905) D28(9.525,-1.905) D29(10.795,-1.905) D30(12.065,-1.905) D31(13.335,-1.905) D32(14.605,-1.905) D33(15.875,-1.905) D34(17.145,-1.905) D35(18.415,-1.905) D36(19.685,-1.905) D37(20.955,-1.905) D38(22.225,-1.905) D39(23.495,-1.905) D40(24.765,-1.905) E1(-24.765,-0.635) E2(-23.495,-0.635) E3(-22.225,-0.635) E4(-20.955,-0.635) E5(-19.685,-0.635) E6(-18.415,-0.635) E7(-17.145,-0.635) E8(-15.875,-0.635) E9(-14.605,-0.635) E10(-13.335,-0.635) E11(-12.065,-0.635) E12(-10.795,-0.635) E13(-9.525,-0.635) E14(-8.255,-0.635) E15(-6.985,-0.635) E16(-5.715,-0.635) E17(-4.445,-0.635) E18(-3.175,-0.635) E19(-1.905,-0.635) E20(-0.635,-0.635) E21(0.635,-0.635) E22(1.905,-0.635) E23(3.175,-0.635) E24(4.445,-0.635) E25(5.715,-0.635) E26(6.985,-0.635) E27(8.255,-0.635) E28(9.525,-0.635) E29(10.795,-0.635) E30(12.065,-0.635) E31(13.335,-0.635) E32(14.605,-0.635) E33(15.875,-0.635) E34(17.145,-0.635) E35(18.415,-0.635) E36(19.685,-0.635) E37(20.955,-0.635) E38(22.225,-0.635) E39(23.495,-0.635) E40(24.765,-0.635) F1(-24.765,0.635) F2(-23.495,0.635) F3(-22.225,0.635) F4(-20.955,0.635) F5(-19.685,0.635) F6(-18.415,0.635) F7(-17.145,0.635) F8(-15.875,0.635) F9(-14.605,0.635) F10(-13.335,0.635) F11(-12.065,0.635) F12(-10.795,0.635) F13(-9.525,0.635) F14(-8.255,0.635) F15(-6.985,0.635) F16(-5.715,0.635) F17(-4.445,0.635) F18(-3.175,0.635) F19(-1.905,0.635) F20(-0.635,0.635) F21(0.635,0.635) F22(1.905,0.635) F23(3.175,0.635) F24(4.445,0.635) F25(5.715,0.635) F26(6.985,0.635) F27(8.255,0.635) F28(9.525,0.635) F29(10.795,0.635) F30(12.065,0.635) F31(13.335,0.635) F32(14.605,0.635) F33(15.875,0.635) F34(17.145,0.635) F35(18.415,0.635) F36(19.685,0.635) F37(20.955,0.635) F38(22.225,0.635) F39(23.495,0.635) F40(24.765,0.635) G1(-24.765,1.905) G2(-23.495,1.905) G3(-22.225,1.905) G4(-20.955,1.905) G5(-19.685,1.905) G6(-18.415,1.905) G7(-17.145,1.905) G8(-15.875,1.905) G9(-14.605,1.905) G10(-13.335,1.905) G11(-12.065,1.905) G12(-10.795,1.905) G13(-9.525,1.905) G14(-8.255,1.905) G15(-6.985,1.905) G16(-5.715,1.905) G17(-4.445,1.905) G18(-3.175,1.905) G19(-1.905,1.905) G20(-0.635,1.905) G21(0.635,1.905) G22(1.905,1.905) G23(3.175,1.905) G24(4.445,1.905) G25(5.715,1.905) G26(6.985,1.905) G27(8.255,1.905) G28(9.525,1.905) G29(10.795,1.905) G30(12.065,1.905) G31(13.335,1.905) G32(14.605,1.905) G33(15.875,1.905) G34(17.145,1.905) G35(18.415,1.905) G36(19.685,1.905) G37(20.955,1.905) G38(22.225,1.905) G39(23.495,1.905) G40(24.765,1.905) H1(-24.765,3.175) H2(-23.495,3.175) H3(-22.225,3.175) H4(-20.955,3.175) H5(-19.685,3.175) H6(-18.415,3.175) H7(-17.145,3.175) H8(-15.875,3.175) H9(-14.605,3.175) H10(-13.335,3.175) H11(-12.065,3.175) H12(-10.795,3.175) H13(-9.525,3.175) H14(-8.255,3.175) H15(-6.985,3.175) H16(-5.715,3.175) H17(-4.445,3.175) H18(-3.175,3.175) H19(-1.905,3.175) H20(-0.635,3.175) H21(0.635,3.175) H22(1.905,3.175) H23(3.175,3.175) H24(4.445,3.175) H25(5.715,3.175) H26(6.985,3.175) H27(8.255,3.175) H28(9.525,3.175) H29(10.795,3.175) H30(12.065,3.175) H31(13.335,3.175) H32(14.605,3.175) H33(15.875,3.175) H34(17.145,3.175) H35(18.415,3.175) H36(19.685,3.175) H37(20.955,3.175) H38(22.225,3.175) H39(23.495,3.175) H40(24.765,3.175) J1(-24.765,4.445) J2(-23.495,4.445) J3(-22.225,4.445) J4(-20.955,4.445) J5(-19.685,4.445) J6(-18.415,4.445) J7(-17.145,4.445) J8(-15.875,4.445) J9(-14.605,4.445) J10(-13.335,4.445) J11(-12.065,4.445) J12(-10.795,4.445) J13(-9.525,4.445) J14(-8.255,4.445) J15(-6.985,4.445) J16(-5.715,4.445) J17(-4.445,4.445) J18(-3.175,4.445) J19(-1.905,4.445) J20(-0.635,4.445) J21(0.635,4.445) J22(1.905,4.445) J23(3.175,4.445) J24(4.445,4.445) J25(5.715,4.445) J26(6.985,4.445) J27(8.255,4.445) J28(9.525,4.445) J29(10.795,4.445) J30(12.065,4.445) J31(13.335,4.445) J32(14.605,4.445) J33(15.875,4.445) J34(17.145,4.445) J35(18.415,4.445) J36(19.685,4.445) J37(20.955,4.445) J38(22.225,4.445) J39(23.495,4.445) J40(24.765,4.445) K1(-24.765,5.715) K2(-23.495,5.715) K3(-22.225,5.715) K4(-20.955,5.715) K5(-19.685,5.715) K6(-18.415,5.715) K7(-17.145,5.715) K8(-15.875,5.715) K9(-14.605,5.715) K10(-13.335,5.715) K11(-12.065,5.715) K12(-10.795,5.715) K13(-9.525,5.715) K14(-8.255,5.715) K15(-6.985,5.715) K16(-5.715,5.715) K17(-4.445,5.715) K18(-3.175,5.715) K19(-1.905,5.715) K20(-0.635,5.715) K21(0.635,5.715) K22(1.905,5.715) K23(3.175,5.715) K24(4.445,5.715) K25(5.715,5.715) K26(6.985,5.715) K27(8.255,5.715) K28(9.525,5.715) K29(10.795,5.715) K30(12.065,5.715) K31(13.335,5.715) K32(14.605,5.715) K33(15.875,5.715) K34(17.145,5.715) K35(18.415,5.715) K36(19.685,5.715) K37(20.955,5.715) K38(22.225,5.715) K39(23.495,5.715) K40(24.765,5.715) L1(-24.765,6.985) L2(-23.495,6.985) L3(-22.225,6.985) L4(-20.955,6.985) L5(-19.685,6.985) L6(-18.415,6.985) L7(-17.145,6.985) L8(-15.875,6.985) L9(-14.605,6.985) L10(-13.335,6.985) L11(-12.065,6.985) L12(-10.795,6.985) L13(-9.525,6.985) L14(-8.255,6.985) L15(-6.985,6.985) L16(-5.715,6.985) L17(-4.445,6.985) L18(-3.175,6.985) L19(-1.905,6.985) L20(-0.635,6.985) L21(0.635,6.985) L22(1.905,6.985) L23(3.175,6.985) L24(4.445,6.985) L25(5.715,6.985) L26(6.985,6.985) L27(8.255,6.985) L28(9.525,6.985) L29(10.795,6.985) L30(12.065,6.985) L31(13.335,6.985) L32(14.605,6.985) L33(15.875,6.985) L34(17.145,6.985) L35(18.415,6.985) L36(19.685,6.985) L37(20.955,6.985) L38(22.225,6.985) L39(23.495,6.985) L40(24.765,6.985) M1(-24.765,8.255) M2(-23.495,8.255) M3(-22.225,8.255) M4(-20.955,8.255) M5(-19.685,8.255) M6(-18.415,8.255) M7(-17.145,8.255) M8(-15.875,8.255) M9(-14.605,8.255) M10(-13.335,8.255) M11(-12.065,8.255) M12(-10.795,8.255) M13(-9.525,8.255) M14(-8.255,8.255) M15(-6.985,8.255) M16(-5.715,8.255) M17(-4.445,8.255) M18(-3.175,8.255) M19(-1.905,8.255) M20(-0.635,8.255) M21(0.635,8.255) M22(1.905,8.255) M23(3.175,8.255) M24(4.445,8.255) M25(5.715,8.255) M26(6.985,8.255) M27(8.255,8.255) M28(9.525,8.255) M29(10.795,8.255) M30(12.065,8.255) M31(13.335,8.255) M32(14.605,8.255) M33(15.875,8.255) M34(17.145,8.255) M35(18.415,8.255) M36(19.685,8.255) M37(20.955,8.255) M38(22.225,8.255) M39(23.495,8.255) M40(24.765,8.255) Y1(-24.765,-8.255) Y2(-23.495,-8.255) Y3(-22.225,-8.255) Y4(-20.955,-8.255) Y5(-19.685,-8.255) Y6(-18.415,-8.255) Y7(-17.145,-8.255) Y8(-15.875,-8.255) Y9(-14.605,-8.255) Y10(-13.335,-8.255) Y11(-12.065,-8.255) Y12(-10.795,-8.255) Y13(-9.525,-8.255) Y14(-8.255,-8.255) Y15(-6.985,-8.255) Y16(-5.715,-8.255) Y17(-4.445,-8.255) Y18(-3.175,-8.255) Y19(-1.905,-8.255) Y20(-0.635,-8.255) Y21(0.635,-8.255) Y22(1.905,-8.255) Y23(3.175,-8.255) Y24(4.445,-8.255) Y25(5.715,-8.255) Y26(6.985,-8.255) Y27(8.255,-8.255) Y28(9.525,-8.255) Y29(10.795,-8.255) Y30(12.065,-8.255) Y31(13.335,-8.255) Y32(14.605,-8.255) Y33(15.875,-8.255) Y34(17.145,-8.255) Y35(18.415,-8.255) Y36(19.685,-8.255) Y37(20.955,-8.255) Y38(22.225,-8.255) Y39(23.495,-8.255) Y40(24.765,-8.255) Z1(-24.765,-6.985) Z2(-23.495,-6.985) Z3(-22.225,-6.985) Z4(-20.955,-6.985) Z5(-19.685,-6.985) Z6(-18.415,-6.985) Z7(-17.145,-6.985) Z8(-15.875,-6.985) Z9(-14.605,-6.985) Z10(-13.335,-6.985) Z11(-12.065,-6.985) Z12(-10.795,-6.985) Z13(-9.525,-6.985) Z14(-8.255,-6.985) Z15(-6.985,-6.985) Z16(-5.715,-6.985) Z17(-4.445,-6.985) Z18(-3.175,-6.985) Z19(-1.905,-6.985) Z20(-0.635,-6.985) Z21(0.635,-6.985) Z22(1.905,-6.985) Z23(3.175,-6.985) Z24(4.445,-6.985) Z25(5.715,-6.985) Z26(6.985,-6.985) Z27(8.255,-6.985) Z28(9.525,-6.985) Z29(10.795,-6.985) Z30(12.065,-6.985) Z31(13.335,-6.985) Z32(14.605,-6.985) Z33(15.875,-6.985) Z34(17.145,-6.985) Z35(18.415,-6.985) Z36(19.685,-6.985) Z37(20.955,-6.985) Z38(22.225,-6.985) Z39(23.495,-6.985) Z40(24.765,-6.985)
CNSAMTECCJT-T-P-GF-RA-TH1
  round 0.889 hole 0.635: 1(0,0) 2(1.27,0)
  round 1.397 hole 0.889: GND1(-0.635,-1.27) GND2(1.905,-1.27) GND3(1.905,1.27) GND4(-0.635,1.27)
CNSAMTECTMM-102-01-G-S-SM
  rect 1.016x3.556 smd: 1(-1,1.017) 2(1,-1.017)
CNSM1X3H380
  rect 1.27x3.175 smd: 1(-2.54,1.587) 2(0,-1.587) 3(2.54,1.587)
CNSMASQ197H161
  rect 0.61x1.295 smd: 1(0,-3.051)
  custom 1.302x1.302 smd: 2(0,2.299)
CPLSMSQ327H472
  rect 4.14x1.905 smd: N(3.47,0) P(-3.47,0)
D0603H33
  rect 1.092x0.889 smd: A(0.813,0) C(-0.813,0)
DFN6_1_3X1
  oval 0.203x0.381 smd: 1(-0.535,-0.41) 2(-0.182,-0.41) 4(0.535,0.41) 5(0.182,0.41)
  rect 0.508x0.508 smd: 3(0.344,-0.194) 6(-0.344,0.194)
DFN10_3X3_PAD2_38X1_64
  oval 0.254x0.889 smd: 1(-1,-1.555) 2(-0.5,-1.555) 3(0,-1.555) 4(0.5,-1.555) 5(1,-1.555) 6(1,1.555) 7(0.5,1.555) 8(0,1.555) 9(-0.5,1.555) 10(-1,1.555)
  rect 2.388x1.651 smd: PAD(0,0)
DFN12_3X3_PAD2_38X1_65
  oval 0.254x0.61 smd: 1(-1.125,-1.5) 2(-0.675,-1.5) 3(-0.225,-1.5) 4(0.225,-1.5) 5(0.675,-1.5) 6(1.125,-1.5) 7(1.125,1.5) 8(0.675,1.5) 9(0.225,1.5) 10(-0.225,1.5) 11(-0.675,1.5) 12(-1.125,1.5)
  rect 2.388x1.651 smd: PAD(0,0)
DFN16_4X3_PAD3_3X1_7
  oval 0.305x0.787 smd: 1(-1.575,-1.5) 2(-1.125,-1.5) 3(-0.675,-1.5) 4(-0.225,-1.5) 5(0.225,-1.5) 6(0.675,-1.5) 7(1.125,-1.5) 8(1.575,-1.5) 9(1.575,1.5) 10(1.125,1.5) 11(0.675,1.5) 12(0.225,1.5) 13(-0.225,1.5) 14(-0.675,1.5) 15(-1.125,1.5) 16(-1.575,1.5)
  rect 3.302x1.702 smd: PAD(0,0)
DO214AC_A
  rect 1.524x1.651 smd: A(1.88,0) C(-1.88,0)
F1206H46
  rect 1.448x1.803 smd: 1(-1.473,0) 2(1.473,0)
L0201
  rect 0.305x0.33 smd: 1(-0.27,0) 2(0.27,0)
L0201_A
  rect 0.203x0.406 smd: 1(-0.217,0) 2(0.217,0)
L0402
  rect 0.508x0.559 smd: 1(-0.434,0) 2(0.434,0)
L0402#2
  rect 0.584x0.711 smd: 1(-0.475,0) 2(0.475,0)
L0603
  rect 0.94x0.991 smd: 1(-0.8,0) 2(0.8,0)
L0603_A
  rect 0.991x0.991 smd: 1(-0.995,0) 2(0.995,0)
L0806
  rect 0.914x1.016 smd: 1(-0.857,0) 2(0.857,0)
L0806_DFE
  rect 0.787x1.803 smd: 1(-0.794,0) 2(0.794,0)
L1008H47
  rect 0.787x2.007 smd: 1(-0.994,0) 2(0.994,0)
L1206-3
  rect 1.6x1.803 smd: 1(-1.397,0) 2(1.397,0)
L1206H71
  rect 1.194x1.803 smd: 1(-1.45,0) 2(1.45,0)
L1210H47
  rect 1.092x2.616 smd: 1(-1.491,0) 2(1.491,0)
L2520H47
  rect 0.711x2.007 smd: 1(-1.056,0) 2(1.056,0)
LCC4H210
  rect 1.27x2.286 smd: 1(-2.54,-3.556) 2(2.54,-3.556) 3(2.54,3.556) 4(-2.54,3.556)
LED0402_A
  rect 0.711x0.508 smd: A(0.555,0) C(-0.555,0)
LED0402H24
  rect 0.711x0.508 smd: A(0.555,0) C(-0.555,0)
LEDSML126W63H43
  rect 1.499x1.753 smd: A(1.6,0) C(-1.6,0)
LGA48_7X7_PAD2_375X2_375
  custom 0.089x0.089 smd: 1(-2.75,-3.226) 12(2.75,-3.226) 13(3.226,-2.75) 24(3.226,2.75) 25(2.75,3.226) 36(-2.75,3.226) 37(-3.226,2.75) 48(-3.226,-2.75)
  rect 0.356x0.483 smd: 2(-2.25,-3.226) 3(-1.75,-3.226) 4(-1.25,-3.226) 5(-0.75,-3.226) 6(-0.25,-3.226) 7(0.25,-3.226) 8(0.75,-3.226) 9(1.25,-3.226) 10(1.75,-3.226) 11(2.25,-3.226) 26(2.25,3.226) 27(1.75,3.226) 28(1.25,3.226) 29(0.75,3.226) 30(0.25,3.226) 31(-0.25,3.226) 32(-0.75,3.226) 33(-1.25,3.226) 34(-1.75,3.226) 35(-2.25,3.226)
  rect 0.483x0.356 smd: 14(3.226,-2.25) 15(3.226,-1.75) 16(3.226,-1.25) 17(3.226,-0.75) 18(3.226,-0.25) 19(3.226,0.25) 20(3.226,0.75) 21(3.226,1.25) 22(3.226,1.75) 23(3.226,2.25) 38(-3.226,2.25) 39(-3.226,1.75) 40(-3.226,1.25) 41(-3.226,0.75) 42(-3.226,0.25) 43(-3.226,-0.25) 44(-3.226,-0.75) 45(-3.226,-1.25) 46(-3.226,-1.75) 47(-3.226,-2.25)
  rect 2.388x2.388 smd: PAD1(-1.312,-1.312) PAD2(1.312,-1.312) PAD3(1.312,1.312) PAD4(-1.312,1.312)
LSML299W295H195
  rect 3.15x3.327 smd: 1(-2.88,0) 2(2.88,0)
LSMSQ157H122
  rect 0.965x3.708 smd: 1(-1.181,0) 2(1.181,0)
MLP12_1_8X1_8
  oval 0.203x0.813 smd: 1(-0.2,-0.9) 2(0.2,-0.9) 7(0.2,0.9) 8(-0.2,0.9)
  oval 0.813x0.203 smd: 3(0.9,-0.6) 4(0.9,-0.2) 5(0.9,0.2) 6(0.9,0.6) 9(-0.9,0.6) 10(-0.9,0.2) 11(-0.9,-0.2) 12(-0.9,-0.6)
MSOP8
  rect 0.305x1.321 smd: 1(-0.975,-2.3) 2(-0.325,-2.3) 3(0.325,-2.3) 4(0.975,-2.3) 5(0.975,2.3) 6(0.325,2.3) 7(-0.325,2.3) 8(-0.975,2.3)
QFN8_2X2_PAD1_6X1
  oval 0.305x0.864 smd: 1(-0.75,-1.13) 2(-0.25,-1.13) 3(0.25,-1.13) 4(0.75,-1.13) 5(0.75,1.13) 6(0.25,1.13) 7(-0.25,1.13) 8(-0.75,1.13)
  rect 1.6x0.991 smd: PAD(0,0)
QFN10_1_6X1_3
  oval 0.61x0.203 smd: 1(-0.8,-0.4) 4(0.8,-0.4) 5(0.8,0) 6(0.8,0.4) 9(-0.8,0.4) 10(-0.8,0)
  oval 0.203x0.813 smd: 2(-0.2,-0.65) 3(0.2,-0.65) 7(0.2,0.65) 8(-0.2,0.65)
QFN24_4X4_PAD2_7X2_7
  oval 0.305x0.787 smd: 1(-1.25,-2) 2(-0.75,-2) 3(-0.25,-2) 4(0.25,-2) 5(0.75,-2) 6(1.25,-2) 13(1.25,2) 14(0.75,2) 15(0.25,2) 16(-0.25,2) 17(-0.75,2) 18(-1.25,2)
  oval 0.787x0.305 smd: 7(2,-1.25) 8(2,-0.75) 9(2,-0.25) 10(2,0.25) 11(2,0.75) 12(2,1.25) 19(-2,1.25) 20(-2,0.75) 21(-2,0.25) 22(-2,-0.25) 23(-2,-0.75) 24(-2,-1.25)
  rect 2.692x2.692 smd: PAD(0,0)
QFN52_8X7_PAD6_45X5_41
  oval 0.279x0.762 smd: 1(-3.25,-3.386) 2(-2.75,-3.386) 3(-2.25,-3.386) 4(-1.75,-3.386) 5(-1.25,-3.386) 6(-0.75,-3.386) 7(-0.25,-3.386) 8(0.25,-3.386) 9(0.75,-3.386) 10(1.25,-3.386) 11(1.75,-3.386) 12(2.25,-3.386) 13(2.75,-3.386) 14(3.25,-3.386) 27(3.25,3.386) 28(2.75,3.386) 29(2.25,3.386) 30(1.75,3.386) 31(1.25,3.386) 32(0.75,3.386) 33(0.25,3.386) 34(-0.25,3.386) 35(-0.75,3.386) 36(-1.25,3.386) 37(-1.75,3.386) 38(-2.25,3.386) 39(-2.75,3.386) 40(-3.25,3.386)
  oval 0.762x0.279 smd: 15(3.886,-2.75) 16(3.886,-2.25) 17(3.886,-1.75) 18(3.886,-1.25) 19(3.886,-0.75) 20(3.886,-0.25) 21(3.886,0.25) 22(3.886,0.75) 23(3.886,1.25) 24(3.886,1.75) 25(3.886,2.25) 26(3.886,2.75) 41(-3.886,2.75) 42(-3.886,2.25) 43(-3.886,1.75) 44(-3.886,1.25) 45(-3.886,0.75) 46(-3.886,0.25) 47(-3.886,-0.25) 48(-3.886,-0.75) 49(-3.886,-1.25) 50(-3.886,-1.75) 51(-3.886,-2.25) 52(-3.886,-2.75)
  rect 6.452x5.41 smd: PAD(0,0)
QFN68_10X10_PAD6_3X6_3
  oval 0.254x1.041 smd: 1(-4,-4.851) 2(-3.5,-4.851) 3(-3,-4.851) 4(-2.5,-4.851) 5(-2,-4.851) 6(-1.5,-4.851) 7(-1,-4.851) 8(-0.5,-4.851) 9(0,-4.851) 10(0.5,-4.851) 11(1,-4.851) 12(1.5,-4.851) 13(2,-4.851) 14(2.5,-4.851) 15(3,-4.851) 16(3.5,-4.851) 17(4,-4.851) 35(4,4.851) 36(3.5,4.851) 37(3,4.851) 38(2.5,4.851) 39(2,4.851) 40(1.5,4.851) 41(1,4.851) 42(0.5,4.851) 43(0,4.851) 44(-0.5,4.851) 45(-1,4.851) 46(-1.5,4.851) 47(-2,4.851) 48(-2.5,4.851) 49(-3,4.851) 50(-3.5,4.851) 51(-4,4.851)
  oval 1.041x0.254 smd: 18(4.851,-4) 19(4.851,-3.5) 20(4.851,-3) 21(4.851,-2.5) 22(4.851,-2) 23(4.851,-1.5) 24(4.851,-1) 25(4.851,-0.5) 26(4.851,0) 27(4.851,0.5) 28(4.851,1) 29(4.851,1.5) 30(4.851,2) 31(4.851,2.5) 32(4.851,3) 33(4.851,3.5) 34(4.851,4) 52(-4.851,4) 53(-4.851,3.5) 54(-4.851,3) 55(-4.851,2.5) 56(-4.851,2) 57(-4.851,1.5) 58(-4.851,1) 59(-4.851,0.5) 60(-4.851,0) 61(-4.851,-0.5) 62(-4.851,-1) 63(-4.851,-1.5) 64(-4.851,-2) 65(-4.851,-2.5) 66(-4.851,-3) 67(-4.851,-3.5) 68(-4.851,-4)
  rect 6.299x6.299 smd: PAD(0,0)
R0201
  rect 0.305x0.33 smd: 1(-0.27,0) 2(0.27,0)
R0402
  rect 0.635x0.737 smd: 1(-0.5,0) 2(0.5,0)
R0402#2
  rect 0.483x0.508 smd: 1(-0.43,0) 2(0.43,0)
R0603
  rect 0.787x0.991 smd: 1(-0.85,0) 2(0.85,0)
R0805
  rect 1.041x1.397 smd: 1(-0.95,0) 2(0.95,0)
R1206
  rect 1.041x1.753 smd: 1(-1.5,0) 2(1.5,0)
R1206-2
  rect 1.397x1.803 smd: 1(-1.298,0) 2(1.298,0)
R1206H20
  rect 1.041x3.607 smd: 1(-0.75,0) 2(0.75,0)
SC70-5
  rect 0.406x0.813 smd: 1(-0.65,-0.89) 2(0,-0.89) 3(0.65,-0.89) 4(0.65,0.89) 5(-0.65,0.89)
SC-70-3
  rect 0.584x1.118 smd: 1(-0.65,-1.144) 2(0.65,-1.144) 3(0,1.144)
SMA
  rect 2.032x2.032 smd: A(1.994,0) C(-1.994,0)
SO8NB-5
  rect 0.635x1.829 smd: 1(-1.905,-2.591) 2(-0.635,-2.591) 3(0.635,-2.591) 4(1.905,-2.591) 5(1.905,2.591) 6(0.635,2.591) 7(-0.635,2.591) 8(-1.905,2.591)
SOD123-2
  rect 0.914x1.219 smd: A(1.638,0) C(-1.638,0)
SOD523FH33
  rect 0.61x0.991 smd: A(0.622,0) C(-0.622,0)
SON8
  rect 0.66x1.194 smd: 1(-1.92,-2.828) 2(-0.64,-2.828) 3(0.64,-2.828) 4(1.92,-2.828)
  custom 1.175x1.175 smd: 5(2,3.171)
  round 0.127 smd: 6(0.678,3.211) 7(-0.68,3.236) 8(-2.002,3.223)
SOT23
  rect 1.016x1.397 smd: 1(-0.94,-1.118) 2(0.94,-1.118) 3(0,1.118)
SOT523F
  rect 0.508x0.66 smd: 1(-0.5,-0.57) 2(0.5,-0.57) 3(0,0.57)
SWDIP8H335
  rect 1.524x1.524 hole 1.016: 1A(0,0)
  round 1.524 hole 1.016: 1B(0,7.62) 2A(2.54,0) 2B(2.54,7.62) 3A(5.08,0) 3B(5.08,7.62) 4A(7.62,0) 4B(7.62,7.62)
SWSMSQ197H165-2
  rect 1.27x1.27 smd: 1A(-2.75,-1.27) 1B(2.75,-1.27) 2A(-2.75,1.27) 2B(2.75,1.27)
SWTHRAL500W900H450
  rect 2.413x2.413 hole 1.905: 1(0,0)
  round 2.413 hole 1.905: 2(4.699,0) 3(9.398,0) 4(0,-3.81) 5(4.699,-3.81) 6(9.398,-3.81)
  round 2.159 hole 1.651: GND1(-1.905,12.7) GND2(11.303,12.7)
TPSMC30
  round 0.762 smd: 1(0,0)
TPSMC40
  round 1.016 smd: 1(0,0)
TSML150W160H160
  rect 0.762x1.651 smd: 1(-1.27,1.587) 2(0,1.587) 3(1.27,1.587) 4(1.27,-1.587) 5(0,-1.587) 6(-1.27,-1.587)
TSML500W200H110
  custom 0.159x0.159 smd: 1(-6.032,1.27) 2(6.032,-1.143) 3(6.032,1.143)
  custom 1.27x1.27 smd: PAD(0,0)
TSOT23_6
  rect 0.61x1.219 smd: 1(-0.95,-1.31) 2(0,-1.31) 3(0.95,-1.31) 4(0.95,1.31) 5(0,1.31) 6(-0.95,1.31)
TSSOP8
  rect 0.33x1.651 smd: 1(-0.975,-2.92) 2(-0.325,-2.92) 3(0.325,-2.92) 4(0.975,-2.92) 5(0.975,2.92) 6(0.325,2.92) 7(-0.325,2.92) 8(-0.975,2.92)
TSSOP48
  rect 0.305x1.651 smd: 1(-5.75,-3.774) 2(-5.25,-3.774) 3(-4.75,-3.774) 4(-4.25,-3.774) 5(-3.75,-3.774) 6(-3.25,-3.774) 7(-2.75,-3.774) 8(-2.25,-3.774) 9(-1.75,-3.774) 10(-1.25,-3.774) 11(-0.75,-3.774) 12(-0.25,-3.774) 13(0.25,-3.774) 14(0.75,-3.774) 15(1.25,-3.774) 16(1.75,-3.774) 17(2.25,-3.774) 18(2.75,-3.774) 19(3.25,-3.774) 20(3.75,-3.774) 21(4.25,-3.774) 22(4.75,-3.774) 23(5.25,-3.774) 24(5.75,-3.774) 25(5.75,3.774) 26(5.25,3.774) 27(4.75,3.774) 28(4.25,3.774) 29(3.75,3.774) 30(3.25,3.774) 31(2.75,3.774) 32(2.25,3.774) 33(1.75,3.774) 34(1.25,3.774) 35(0.75,3.774) 36(0.25,3.774) 37(-0.25,3.774) 38(-0.75,3.774) 39(-1.25,3.774) 40(-1.75,3.774) 41(-2.25,3.774) 42(-2.75,3.774) 43(-3.25,3.774) 44(-3.75,3.774) 45(-4.25,3.774) 46(-4.75,3.774) 47(-5.25,3.774) 48(-5.75,3.774)
unnamed#2
  round 4.445 hole 3.175 unplated: (0,0)
unnamed#3
  rect 0.305x0.33 smd: 1(-0.27,0) 2(0.27,0)
UQFN6_1_45X1
  oval 0.254x0.66 smd: 1(-0.508,-0.483) 2(0,-0.483) 3(0.508,-0.483) 4(0.508,0.483) 5(0,0.483) 6(-0.508,0.483)
WLCSP6_B
  round 0.203 smd: A1(-0.4,-0.2) A2(-0.4,0.2) B1(0,-0.2) B2(0,0.2) C1(0.4,-0.2) C2(0.4,0.2)
YSML560W360H210_6P
  rect 1.27x2.286 smd: 1(-2.54,-3.556) 2(0,-3.556) 3(2.54,-3.556) 4(2.54,3.556) 5(0,3.556) 6(-2.54,3.556)

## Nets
5VBIAS: C649.2(N2) R31.2(N2) R33.2(N2) R35.2(N2) R38.2(N2) R40.2(N2) R42.2(N2) R44.2(N2) R46.2(N2) R48.2(N2) R83.2(N2) R85.2(N2) R87.2(N2) R89.2(N2) R91.2(N2) R93.2(N2) R95.2(N2) R97.2(N2) R99.2(N2) R104.2(N2) R106.2(N2) R108.2(N2) R110.2(N2) R112.2(N2) R114.2(N2) R116.2(N2) R118.2(N2) R120.2(N2) R746.2(N2) R748.2(N2) R754.2(N2) R765.2(N2) R767.2(N2) R769.2(N2) R771.2(N2) R773.2(N2) R775.2(N2) U7.A3 U7.A4 U7.F4 U7.L4 U8.A3 U8.A4 U8.F3 U8.F4 U8.L3 U8.L4 U34.A4 U34.F4 U34.L4 U52.A3 U52.A4 U52.F4 U52.L4 U53.A2(VOUT) U53.B2
AVDD1P0_CK: C105.1 C120.1 C121.1 C204.1 C205.1 C206.1 C207.1 E27.2(N2) R557.1 U1A.AB6 U1A.AC6 U1A.G6 U1A.H6 U1A.P6 U1A.R6 U1A.T6
AVDD1P0_MCS: C430.1 C433.1 E24.2(N2) R560.1 U1A.AC10 U1A.G10
AVDD1P0_PLL_SYN: C459.1 E26.2(N2) R559.1 U1A.U12
AVDD1P8: C447.1 C452.1 E20.2(N2) R572.1 U1A.A4 U1A.AJ4
AVDD1P8_ADC: C337.1 C342.1 C347.1 C351.1 C354.1 C359.1 C364.1 C369.1 E23.2(N2) R575.1 U1A.K8 U1A.L8 U1A.M8 U1A.N8 U1A.U8 U1A.V8 U1A.W8 U1A.Y8
AVDD1P8_MCS: C443.1 C448.1 E21.2(N2) R573.1 U1A.AC9 U1A.G9
AVDD1P8_PLL: C461.1 E22.2(N2) R574.1 U1A.R12
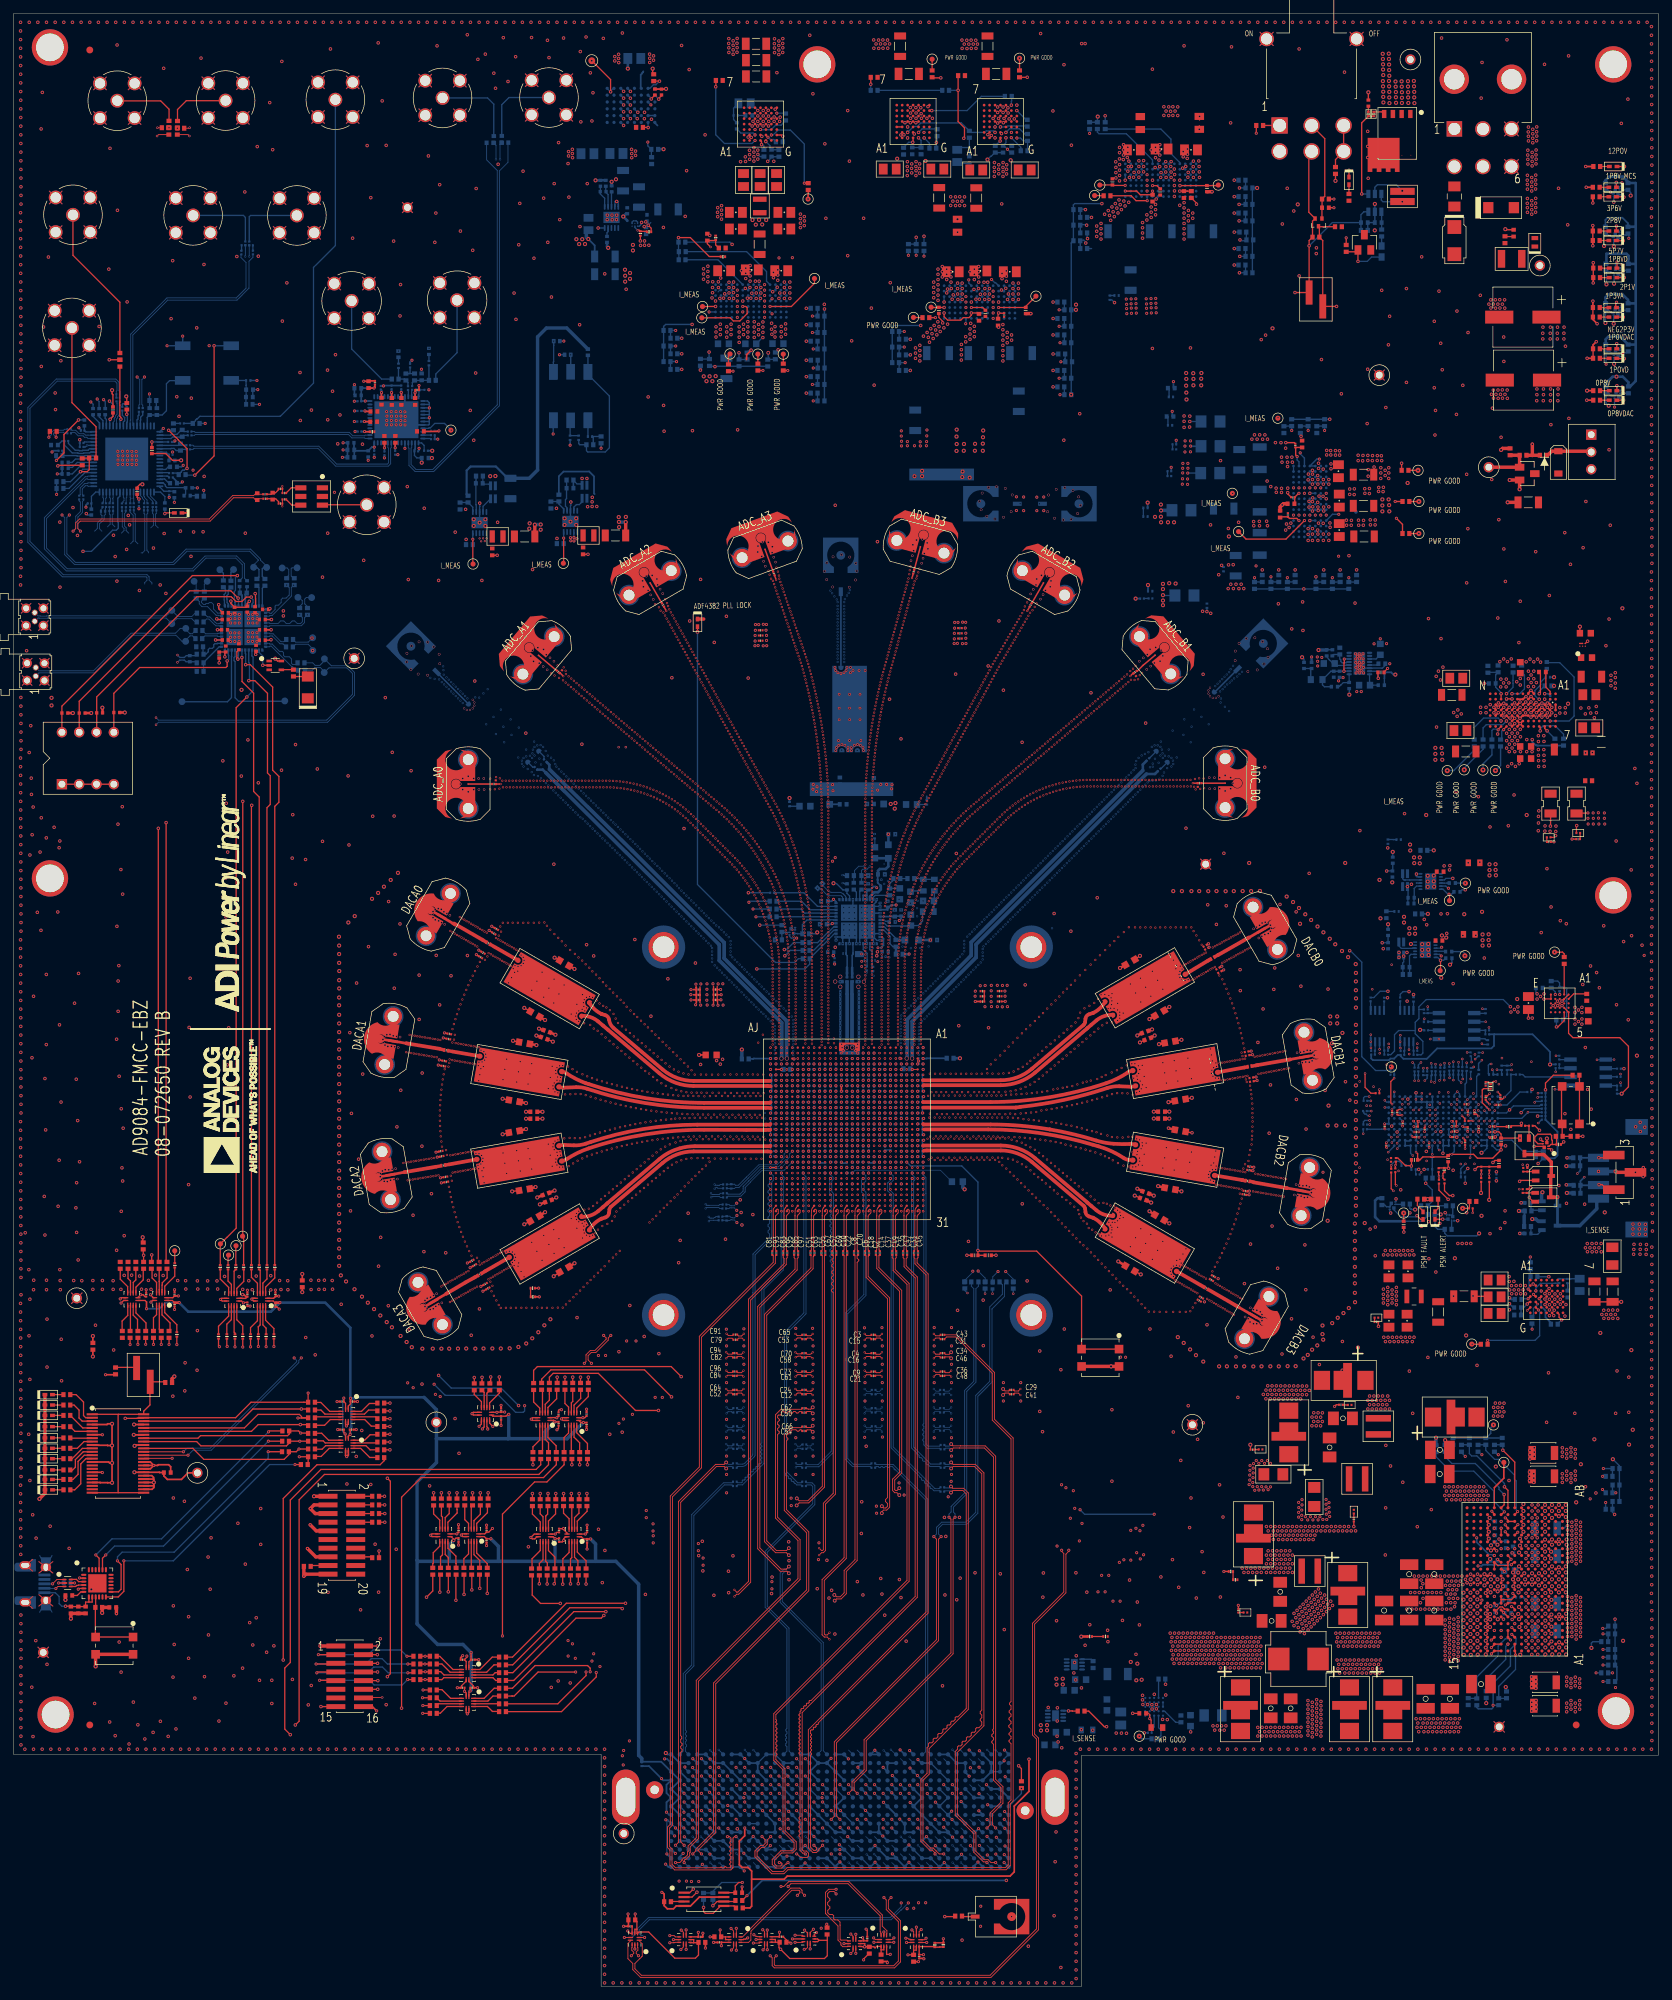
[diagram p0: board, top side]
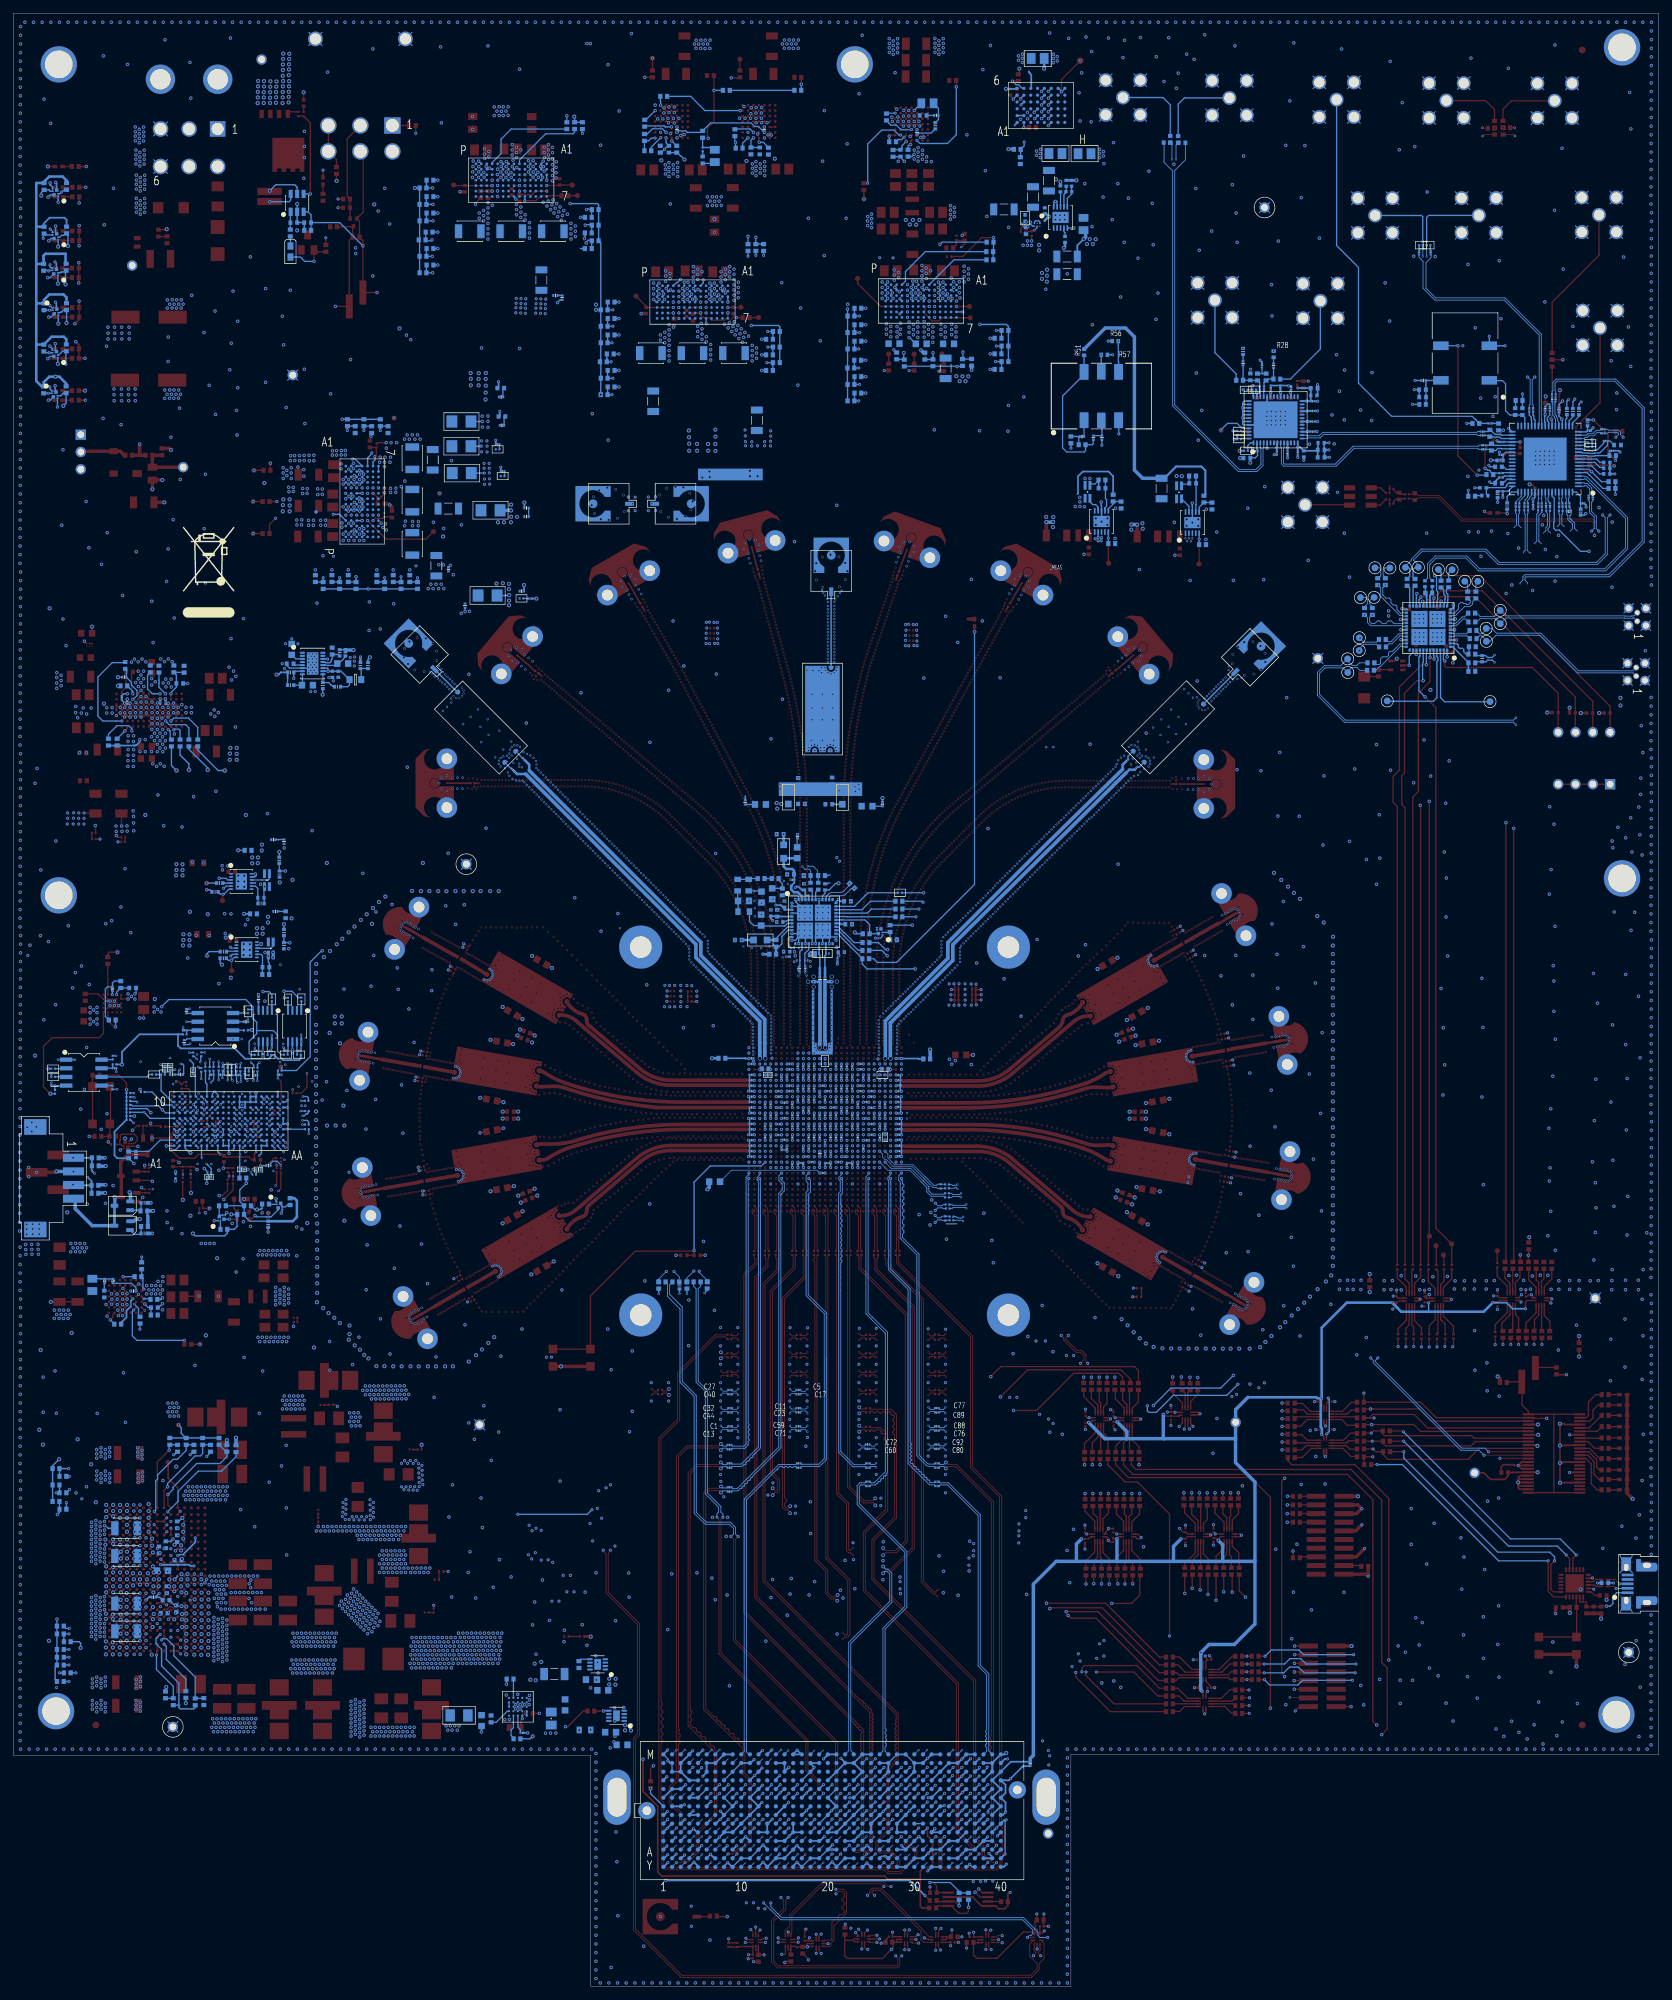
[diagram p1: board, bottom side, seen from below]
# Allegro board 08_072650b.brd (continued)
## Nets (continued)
DGND: A1.8 A2.8 A3.1 A4.1 ADC_A0.2 ADC_A1.2 ADC_A2.2 ADC_A3.2 ADC_B0.2 ADC_B1.2 ADC_B2.2 ADC_B3.2 C1WA.2(N2) C1WB.2(N2) C1XA.2(N2) C1XB.2(N2) C1YA.2(N2) C1YB.2(N2) C1ZA.2(N2) C1ZB.2(N2) C2WA.2(N2) C2WB.2(N2) C2XA.2(N2) C2XB.2(N2) C2YA.2(N2) C2YB.2(N2) C2ZA.2(N2) C2ZB.2(N2) C3WA.2(N2) C3WB.2(N2) C3XA.2(N2) C3XB.2(N2) C3YA.2(N2) C3YB.2(N2) C3ZA.2(N2) C3ZB.2(N2) C4WA.2(N2) C4WB.2(N2) C4XA.2(N2) C4XB.2(N2) C4YA.2(N2) C4YB.2(N2) C4ZA.2(N2) C4ZB.2(N2) C6WA.2(N2) C6WB.2(N2) C6XA.2(N2) C6XB.2(N2) C6YA.2(N2) C6YB.2(N2) C6ZA.2(N2) C6ZB.2(N2) C7WA.2(N2) C7WB.2(N2) C7XA.2(N2) C7XB.2(N2) C7YA.2(N2) C7YB.2(N2) C7ZA.2(N2) C7ZB.2(N2) C98.2(N2) C99.2(N2) C100.2(N2) C101.2(N2) C102.2(N2) C103.2(N2) C104.2(N2) C105.2(N2) C107.2(N2) C108.2(N2) C109.2(N2) C110.2(N2) C111.2(N2) C112.2(N2) C113.1 C114.2(N2) C117.2(N2) C118.2(N2) C119.2(N2) C120.2(N2) C121.2(N2) C122.2(N2) C123.2(N2) C124.2(N2) C125.2(N2) C126.2(N2) C128.2(N2) C130.2(N2) C131.2(N2) C132.1 C133.1 C134.1 C135.1 C135.4(N4) C136.1 C137.1 C138.1 C139.1 C140.1 C141.2(N2) C142.2(N2) C143.1 C144.2(N2) C145.2(N2) C146.2(N2) C147.2(N2) C148.2(N2) C149.2(N2) C150.1 C151.2(N2) C152.2(N2) C153.1 C157.1 C158.1 C159.1 C160.1 C161.1 C162.1 C163.1 C164.1 C165.1 C166.1 C167.1 C168.1 C169.1 C170.1 C171.1 C172.1 C173.1 C174.1 C175.1 C177.2(N2) C178.1 C179.1 C180.1 C181.1 C182.1 C183.1 C184.1 C185.1 C186.1 C187.1 C188.1 C189.1 C190.1 C191.1 C192.1 C193.1 C194.1 C195.1 C196.1 C197.1 C197.4(N4) C198.1 C198.4(N4) C199.1 C200.1 C201.2(N2) C202.2(N2) C203.2(N2) C204.2(N2) C205.2(N2) C206.2(N2) C207.2(N2) C208.2(N2) C209.2(N2) C210.2(N2) C211.2(N2) C215.1 C218.1 C219.1 C220.1 C221.1 C222.2(N2) C223.1 C224.2(N2) C225.2(N2) C226.1 C227.2(N2) C228.2(N2) C229.2(N2) C234.1 C235.1 C236.1 C237.2(N2) C238.1 C239.1 C240.1 C241.2(N2) C242.2(N2) C243.2(N2) C244.2(N2) C245.2(N2) C246.2(N2) C247.2(N2) C248.2(N2) C249.1 C250.2(N2) C251.2(N2) C252.2(N2) C253.1 C254.2(N2) C255.1 C256.2(N2) C257.2(N2) C258.2(N2) C259.1 C260.2(N2) C261.2(N2) C262.1 C263.1 C264.1 C265.1 C266.1 C267.1 C268.1 C269.2(N2) C270.2(N2) C271.2(N2) C272.2(N2) C273.1 C274.1 C275.1 C276.2(N2) C277.2(N2) C278.2(N2) C279.2(N2) C280.2(N2) C281.2(N2) C282.2(N2) C283.2(N2) C284.2(N2) C285.2(N2) C286.2(N2) C287.2(N2) C288.2(N2) C289.2(N2) C290.2(N2) C291.2(N2) C292.2(N2) C293.2(N2) C294.2(N2) C295.2(N2) C296.2(N2) C297.2(N2) C298.2(N2) C299.2(N2) C300.2(N2) C301.2(N2) C302.2(N2) C303.2(N2) C304.2(N2) C305.2(N2) C306.2(N2) C307.2(N2) C308.2(N2) C309.2(N2) C310.2(N2) C316.1 C320.1 C321.1 C322.1 C336.2(N2) C337.2(N2) C338.2(N2) C341.2(N2) C342.2(N2) C343.2(N2) C346.2(N2) C347.2(N2) C348.2(N2) C351.2(N2) C352.2(N2) C354.2(N2) C355.2(N2) C356.2(N2) C357.2(N2) C359.2(N2) C360.2(N2) C362.2(N2) C364.2(N2) C365.2(N2) C367.2(N2) C369.2(N2) C370.2(N2) C371.2(N2) C372.2(N2) C373.2(N2) C374.2(N2) C376.2(N2) C377.2(N2) C378.2(N2) C379.2(N2) C380.2(N2) C382.2(N2) C383.2(N2) C384.2(N2) C386.2(N2) C387.2(N2) C388.2(N2) C390.2(N2) C391.2(N2) C392.2(N2) C394.2(N2) C395.2(N2) C396.2(N2) C398.2(N2) C399.2(N2) C400.2(N2) C402.2(N2) C403.2(N2) C404.2(N2) C406.2(N2) C407.2(N2) C408.2(N2) C409.2(N2) C410.2(N2) C411.2(N2) C412.2(N2) C413.2(N2) C414.2(N2) C415.2(N2) C416.2(N2) C417.2(N2) C418.2(N2) C419.2(N2) C420.2(N2) C421.2(N2) C422.2(N2) C423.2(N2) C424.2(N2) C425.2(N2) C426.2(N2) C427.2(N2) C428.2(N2) C429.2(N2) C430.2(N2) C431.2(N2) C432.2(N2) C433.2(N2) C434.2(N2) C435.2(N2) C436.2(N2) C437.2(N2) C438.2(N2) C439.2(N2) C440.2(N2) C441.2(N2) C442.2(N2) C443.2(N2) C444.2(N2) C445.2(N2) C446.2(N2) C447.2(N2) C448.2(N2) C449.2(N2) C450.2(N2) C451.2(N2) C452.2(N2) C453.2(N2) C454.2(N2) C455.2(N2) C456.2(N2) C457.2(N2) C458.2(N2) C459.2(N2) C460.2(N2) C461.2(N2) C462.2(N2) C463.2(N2) C464.2(N2) C465.2(N2) C466.2(N2) C467.2(N2) C468.2(N2) C469.2(N2) C470.2(N2) C471.2(N2) C472.2(N2) C473.2(N2) C474.2(N2) C475.2(N2) C476.2(N2) C477.2(N2) C478.2(N2) C479.2(N2) C480.2(N2) C481.2(N2) C482.2(N2) C483.2(N2) C484.2(N2) C485.2(N2) C486.2(N2) C487.2(N2) C488.2(N2) C489.2(N2) C490.2(N2) C491.2(N2) C492.2(N2) C493.2(N2) C494.2(N2) C495.2(N2) C496.2(N2) C497.2(N2) C498.2(N2) C499.2(N2) C500.2(N2) C501.2(N2) C502.2(N2) C503.2(N2) C504.2(N2) C505.2(N2) C506.2(N2) C507.2(N2) C508.2(N2) C509.2(N2) C510.2(N2) C511.2(N2) C512.1 C513.1 C514.1 C515.1 C516.1 C517.2(N2) C518.1 C519.1 C520.1 C521.1 C522.1 C523.1 C524.1 C525.1 C526.1 C527.1 C528.1 C529.1 C530.1 C531.1 C534.1 C535.1 C538.1 C540.2(N2) C544.2(N2) C548.2(N2) C549.2(N2) C550.2(N2) C551.2(N2) C552.2(N2) C553.1 C572.1 C573.1 C574.2(N2) C575.2(N2) C576.2(N2) C577.1 C578.1 C579.1 C580.1 C581.1 C582.1 C583.1 C584.N1 C584.N2 C585.N1 C585.N2 C586.1 C587.1 C588.1 C589.1 C590.1 C591.1 C592.N1 C592.N2 C593.N1 C593.N2 C594.N1 C594.N2 C595.N1 C595.N2 C596.N1 C596.N2 C597.1 C598.1 C599.1 C600.N1 C600.N2 C601.1 C602.1 C603.1 C603.4(N4) C604.1 C605.2(N2) C606.1 C607.1 C608.1 C609.1 C610.1 C611.1 C612.1 C613.1 C614.1 C615.1 C616.1 C617.1 C618.2(N2) C619.2(N2) C620.2(N2) C622.1 C623.2(N2) C624.2(N2) C625.2(N2) C626.2(N2) C627.2(N2) C628.2(N2) C630.2(N2) C631.2(N2) C632.2(N2) C633.2(N2) C634.2(N2) C635.2(N2) C636.2(N2) C637.1 C638.2(N2) C639.1 C640.1 C641.1 C642.1 C643.1 C644.1 C645.1 C648.1 C649.1 C663.2(N2) C664.2(N2) C665.2(N2) C666.2(N2) C667.2(N2) C668.2(N2) C669.2(N2) C670.2(N2) C671.2(N2) C672.2(N2) C673.2(N2) C674.2(N2) C675.2(N2) C676.2(N2) C677.2(N2) C678.1 C679.1 C680.1 C681.2(N2) C682.2(N2) C683.2(N2) C684.1 C685.1 C686.2(N2) C687.2(N2) C688.1 C689.1 C690.2(N2) C691.2(N2) C692.2(N2) C693.2(N2) C694.2(N2) C695.2(N2) C696.2(N2) C697.2(N2) C704.N(N2) C705.N(N2) C706.2(N2) C707.1 C708.1 C709.2(N2) C710.2(N2) C711.2(N2) C712.2(N2) C713.2(N2) C714.1 C715.2(N2) C716.2(N2) C717.2(N2) C719.1 C720.2(N2) C721.2(N2) C722.2(N2) C748.2(N2) C753.1 C754.1 C755.1 C756.1 C757.1 C758.1 C759.1 C763.1 C764.1 C773.2(N2) C774.2(N2) C775.2(N2) C776.2(N2) C777.2(N2) C778.2(N2) C779.2(N2) C780.2(N2) C781.2(N2) C782.2(N2) C783.2(N2) C784.2(N2) C785.2(N2) C786.2(N2) C845.2(N2) C847.2(N2) C852.2(N2) C853.2(N2) C854.2(N2) C855.2(N2) C856.2(N2) C857.2(N2) C858.2(N2) C859.2(N2) C864.2(N2) CLK.2(SHIELD) CLK_A.2(SHIELD) CLK_B.2(SHIELD) D2.A(P) D3.A(P) DACA0.2 DACA1.2 DACA2.2 DACA3.2 DACB0.2 DACB1.2 DACB2.2 DACB3.2 DS1.C DS2.C DS3.C DS16.C DS18.C DS19.C DS20.C DS21.C DS22.C DS23.C DS24.C DS25.C DS26.C DS27.C DS29.C EXT_HMCREF.2 EXT_HMCREF.3 EXT_HMCREF.4 EXT_HMCREF.5(SH4) EXT_SYNC.2 EXT_SYNC.3 EXT_SYNC.4 EXT_SYNC.5(SH4) EXT_SYS_N.2 EXT_SYS_N.3 EXT_SYS_N.4 EXT_SYS_N.5(SH4) EXT_SYS_P.2 EXT_SYS_P.3 EXT_SYS_P.4 EXT_SYS_P.5(SH4) EXT_TRIG.2 EXT_TRIG.3 EXT_TRIG.4 EXT_TRIG.5(SH4) GND1.1(N1) GND2.1(N1) GND3.1(N1) GND4.1(N1) GND5.1(N1) GND6.1(N1) GND7.1(N1) GND8.1(N1) J3.2(SHIELD) J12.2 J12.3 J12.4 J12.5(SH4) J13.2 J13.3 J13.4 J13.5(SH4) J17.2 J17.3 J17.4 J17.5(SH4) J18.2 J18.3 J18.4 J18.5(SH4) JP1.1 JP1.2(S2) JP2.1 JP2.2(S2) P1.A1 P1.A4 P1.A5 P1.A8 P1.A9 P1.A12 P1.A13 P1.A16 P1.A17 P1.A20 P1.A21 P1.A24 P1.A25 P1.A28 P1.A29 P1.A32 P1.A33 P1.A36 P1.A37 P1.A40 P1.B2 P1.B3 P1.B6 P1.B7 P1.B10 P1.B11 P1.B14 P1.B15 P1.B18 P1.B19 P1.B22 P1.B23 P1.B26 P1.B27 P1.B30 P1.B31 P1.B34 P1.B35 P1.B38 P1.B39 P1.C1 P1.C4 P1.C5 P1.C8 P1.C9 P1.C12 P1.C13 P1.C16 P1.C17 P1.C20 P1.C21 P1.C24 P1.C25 P1.C28 P1.C29 P1.C32 P1.C33 P1.C36 P1.C38 P1.C40 P1.D2 P1.D3 P1.D6 P1.D7 P1.D10 P1.D13 P1.D16 P1.D19 P1.D22 P1.D25 P1.D28 P1.D37 P1.D39 P1.E1 P1.E4 P1.E5 P1.E8 P1.E11 P1.E14 P1.E17 P1.E20 P1.E23 P1.E26 P1.E29 P1.E32 P1.E35 P1.E38 P1.E40 P1.F2 P1.F3 P1.F6 P1.F9 P1.F12 P1.F15 P1.F18 P1.F21 P1.F24 P1.F27 P1.F30 P1.F33 P1.F36 P1.F39 P1.G1 P1.G4 P1.G5 P1.G8 P1.G11 P1.G14 P1.G17 P1.G20 P1.G23 P1.G26 P1.G29 P1.G32 P1.G35 P1.G38 P1.G40 P1.H2 P1.H3 P1.H6 P1.H9 P1.H12 P1.H15 P1.H18 P1.H21 P1.H24 P1.H27 P1.H30 P1.H33 P1.H36 P1.H39 P1.J1 P1.J4 P1.J5 P1.J8 P1.J11 P1.J14 P1.J17 P1.J20 P1.J23 P1.J26 P1.J29 P1.J32 P1.J35 P1.J38 P1.J40 P1.K2 P1.K3 P1.K6 P1.K9 P1.K12 P1.K15 P1.K18 P1.K21 P1.K24 P1.K27 P1.K30 P1.K33 P1.K36 P1.K39 P1.L2 P1.L3 P1.L6 P1.L7 P1.L10 P1.L11 P1.L14 P1.L15 P1.L18 P1.L19 P1.L22 P1.L23 P1.L26 P1.L27 P1.L30 P1.L31 P1.L34 P1.L35 P1.L38 P1.L39 P1.M1 P1.M4 P1.M5 P1.M8 P1.M9 P1.M12 P1.M13 P1.M16 P1.M17 P1.M20 P1.M21 P1.M24 P1.M25 P1.M28 P1.M29 P1.M32 P1.M33 P1.M36 P1.M37 P1.M40 P1.Y1 P1.Y4 P1.Y5 P1.Y8 P1.Y9 P1.Y12 P1.Y13 P1.Y16 P1.Y17 P1.Y20 P1.Y21 P1.Y24 P1.Y25 P1.Y28 P1.Y29 P1.Y32 P1.Y33 P1.Y36 P1.Y37 P1.Y40(GND_238) P1.Z1 P1.Z2 P1.Z3 P1.Z6 P1.Z7 P1.Z10 P1.Z11 P1.Z14 P1.Z15 P1.Z18 P1.Z19 P1.Z22 P1.Z23 P1.Z26 P1.Z27 P1.Z30 P1.Z31 P1.Z34 P1.Z35 P1.Z38 P1.Z39 P2.16(N8) P3.3 P3.5 P3.9 P3.15 P3.19 P4.5(N5) P4.6 P4.7 P4.8 P4.9 P5.2 P5.G1 P5.G2 P7.2 P18.GND1 P18.GND2 P18.GND3 P18.GND4(N6) P19.GND1 P19.GND2 P19.GND3 P19.GND4(N6) P22.3 P22.6(N6) Q1.1 Q1.4(S2) Q2.1 Q2.4(S2) Q3.1 Q3.4(S2) Q4.1 Q4.4(S2) Q5.1 Q5.4(S2) Q6.1 Q6.4(S2) Q8.1 Q9.1 Q9.4(S2) Q10.1 Q10.4(S2) Q11.1 Q11.4(S2) Q17.2(S) R2.2(N2) R8.2(N2) R9.2(N2) R10.2(N2) R11.2(N2) R26.2(N2) R32.1 R34.1 R36.1 R39.1 R41.1 R43.1 R45.1 R47.1 R50.1 R53.2(N2) R54.1 R56.2(N2) R57.2(N2) R59.1 R61.1 R64.2(N2) R72.2(N2) R75.2(N2) R76.2(N2) R77.2(N2) R84.1 R86.1 R88.1 R90.1 R92.1 R94.1 R96.1 R98.1 R100.1 R105.1 R107.1 R109.1 R111.1 R113.1 R115.1 R117.1 R119.1 R121.1 R124.2(N2) R125.2(N2) R126.1 R127.1 R128.1 R129.1 R133.2(N2) R140.1 R144.2(N2) R145.2(N2) R161.2(N2) R163.2(N2) R292.2(N2) R296.1 R308.1 R309.1 R310.1 R312.1 R313.2(N2) R314.2(N2) R334.2(N2) R368.1 R372.1 R380.2(N2) R381.2(N2) R382.2(N2) R396.2(N2) R397.2(N2) R398.2(N2) R399.2(N2) R400.2(N2) R401.2(N2) R402.2(N2) R403.2(N2) R419.1 R441.2(N2) R442.2(N2) R443.2(N2) R444.1 R445.1 R447.1 R449.1 R450.1 R455.2(N2) R456.1 R472.1 R474.2(N2) R485.1 R487.1 R490.2(N2) R491.2(N2) R495.2(N2) R504.2(N2) R507.1 R510.1 R511.1 R515.2(N2) R518.1 R529.1 R533.2(N2) R536.1 R538.2(N2) R551.2(N2) R577.1 R579.1 R595.2(N2) R615.1 R616.1 R621.1 R630.1 R632.2(N2) R637.2(N2) R640.1 R641.1 R642.1 R651.2(N2) R660.2(N2) R677.1 R682.1 R686.2(N2) R709.2(N2) R710.2(N2) R729.2(N2) R730.2(N2) R731.2(N2) R736.2(N2) R737.2(N2) R738.2(N2) R739.2(N2) R747.1 R753.1 R755.1 R757.1 R759.1 R762.1 R766.1 R768.1 R770.1 R772.1 R774.1 R776.1 R778.2(N2) R780.2(N2) R781.2(N2) R786.2(N2) R788.2(N2) R797.2(N2) R807.1 R809.2(N2) R811.2(N2) R816.1 REFCLK.2 REFCLK.3 REFCLK.4 REFCLK.5(SH4) REFN.2 REFN.3 REFN.4 REFN.5(SH4) REFP.2 REFP.3 REFP.4 REFP.5(SH4) RFOUT_2N.2(SHIELD) RFOUT_2P.2(SHIELD) S1.2A S1.2B(N4) S2.2A S2.2B(N4) S4.GND1 S4.GND2 T1.PAD T2.PAD T3.PAD T4.1 T4.2 T4.5 U1.B1 U1.B2 U1.B4 U1.C4 U1.C5 U1.C6 U1.C7 U1.D2 U1.D4 U1.D5 U1.D6 U1.D7 U1.E3 U1.E4 U1.E5 U1.E6 U1.E7 U1.F4 U1.F5 U1.G4 U1.G5 U1.G7 U1A.A1 U1A.A2 U1A.A5 U1A.A22 U1A.A23 U1A.A26 U1A.A27 U1A.A30 U1A.A31 U1A.AA1 U1A.AA2 U1A.AA3 U1A.AA6 U1A.AA7 U1A.AA10 U1A.AA11 U1A.AA13 U1A.AA16 U1A.AA18 U1A.AA23 U1A.AA24 U1A.AA25 U1A.AA28 U1A.AA29 U1A.AB2 U1A.AB3 U1A.AB4 U1A.AB5 U1A.AB7 U1A.AB8 U1A.AB9 U1A.AB10 U1A.AB11 U1A.AB12 U1A.AB13 U1A.AB14 U1A.AB15 U1A.AB16 U1A.AB17 U1A.AB18 U1A.AB20 U1A.AB21 U1A.AB22 U1A.AB23 U1A.AB24 U1A.AB25 U1A.AB26 U1A.AB27 U1A.AB30 U1A.AB31 U1A.AC1 U1A.AC2 U1A.AC3 U1A.AC4 U1A.AC5 U1A.AC7 U1A.AC8 U1A.AC13 U1A.AC16 U1A.AC23 U1A.AC26 U1A.AC27 U1A.AC28 U1A.AC29 U1A.AC30 U1A.AC31 U1A.AD1 U1A.AD2 U1A.AD3 U1A.AD4 U1A.AD5 U1A.AD6 U1A.AD7 U1A.AD8 U1A.AD9 U1A.AD10 U1A.AD11 U1A.AD13 U1A.AD16 U1A.AD18 U1A.AD23 U1A.AD24 U1A.AD25 U1A.AD28 U1A.AD29 U1A.AE2 U1A.AE3 U1A.AE4 U1A.AE5 U1A.AE7 U1A.AE8 U1A.AE9 U1A.AE11 U1A.AE13 U1A.AE16 U1A.AE18 U1A.AE24 U1A.AE25 U1A.AE26 U1A.AE27 U1A.AE30 U1A.AE31 U1A.AF1 U1A.AF2 U1A.AF4 U1A.AF5 U1A.AF9 U1A.AF10 U1A.AF11 U1A.AF13 U1A.AF16 U1A.AF18 U1A.AF23 U1A.AF24 U1A.AF25 U1A.AF28 U1A.AF29 U1A.AG1 U1A.AG2 U1A.AG4 U1A.AG6 U1A.AG7 U1A.AG8 U1A.AG9 U1A.AG10 U1A.AG11 U1A.AG12 U1A.AG13 U1A.AG14 U1A.AG18 U1A.AG19 U1A.AG20 U1A.AG22 U1A.AG23 U1A.AG26 U1A.AG27 U1A.AG30 U1A.AG31 U1A.AH2 U1A.AH3 U1A.AH4 U1A.AH7 U1A.AH8 U1A.AH11 U1A.AH12 U1A.AH15 U1A.AH16 U1A.AH19 U1A.AH20 U1A.AH22 U1A.AH23 U1A.AH24 U1A.AH25 U1A.AH28 U1A.AH29 U1A.AJ1 U1A.AJ2 U1A.AJ5 U1A.AJ22 U1A.AJ23 U1A.AJ26 U1A.AJ27 U1A.AJ30 U1A.AJ31(GND_498) U1A.B2 U1A.B3 U1A.B4 U1A.B7 U1A.B8 U1A.B11 U1A.B12 U1A.B15 U1A.B16 U1A.B19 U1A.B20 U1A.B22 U1A.B23 U1A.B24 U1A.B25 U1A.B28 U1A.B29 U1A.C1 U1A.C2 U1A.C4 U1A.C6 U1A.C7 U1A.C8 U1A.C9 U1A.C10 U1A.C11 U1A.C12 U1A.C13 U1A.C14 U1A.C18 U1A.C19 U1A.C20 U1A.C22 U1A.C23 U1A.C26 U1A.C27 U1A.C30 U1A.C31 U1A.D1 U1A.D2 U1A.D4 U1A.D5 U1A.D9 U1A.D10 U1A.D11 U1A.D13 U1A.D16 U1A.D18 U1A.D23 U1A.D24 U1A.D25 U1A.D28 U1A.D29 U1A.E2 U1A.E3 U1A.E4 U1A.E5 U1A.E7 U1A.E8 U1A.E9 U1A.E11 U1A.E13 U1A.E16 U1A.E18 U1A.E24 U1A.E25 U1A.E26 U1A.E27 U1A.E30 U1A.E31 U1A.F1 U1A.F2 U1A.F3 U1A.F4 U1A.F5 U1A.F6 U1A.F7 U1A.F8 U1A.F9 U1A.F10 U1A.F11 U1A.F13 U1A.F16 U1A.F18 U1A.F23 U1A.F24 U1A.F25 U1A.F28 U1A.F29 U1A.G1 U1A.G2 U1A.G3 U1A.G4 U1A.G5 U1A.G7 U1A.G8 U1A.G13 U1A.G16 U1A.G23 U1A.G26 U1A.G27 U1A.G28 U1A.G29 U1A.G30 U1A.G31 U1A.H2 U1A.H3 U1A.H4 U1A.H5 U1A.H7 U1A.H8 U1A.H9 U1A.H10 U1A.H11 U1A.H12 U1A.H13 U1A.H14 U1A.H15 U1A.H16 U1A.H17 U1A.H18 U1A.H20 U1A.H21 U1A.H22 U1A.H23 U1A.H24 U1A.H25 U1A.H26 U1A.H27 U1A.H30 U1A.H31 U1A.J1 U1A.J2 U1A.J3 U1A.J6 U1A.J7 U1A.J10 U1A.J11 U1A.J13 U1A.J16 U1A.J18 U1A.J23 U1A.J24 U1A.J25 U1A.J28 U1A.J29 U1A.K1 U1A.K2 U1A.K3 U1A.K4 U1A.K7 U1A.K9 U1A.K11 U1A.K12 U1A.K14 U1A.K15 U1A.K17 U1A.K18 U1A.K23 U1A.K24 U1A.K25 U1A.K26 U1A.K27 U1A.K30 U1A.K31 U1A.L2 U1A.L3 U1A.L4 U1A.L7 U1A.L9 U1A.L11 U1A.L13 U1A.L20 U1A.L22 U1A.L23 U1A.L24 U1A.L25 U1A.L28 U1A.L29 U1A.M1 U1A.M2 U1A.M3 U1A.M4 U1A.M7 U1A.M9 U1A.M11 U1A.M13 U1A.M15 U1A.M17 U1A.M20 U1A.M21 U1A.M22 U1A.M23 U1A.M26 U1A.M27 U1A.M30 U1A.M31 U1A.N1 U1A.N2 U1A.N3 U1A.N4 U1A.N7 U1A.N9 U1A.N11 U1A.N13 U1A.N15 U1A.N17 U1A.N23 U1A.N24 U1A.N25 U1A.N28 U1A.N29 U1A.P3 U1A.P4 U1A.P5 U1A.P7 U1A.P10 U1A.P11 U1A.P12 U1A.P13 U1A.P15 U1A.P17 U1A.P20 U1A.P23 U1A.P26 U1A.P27 U1A.P30 U1A.P31 U1A.R5 U1A.R7 U1A.R8 U1A.R9 U1A.R10 U1A.R13 U1A.R15 U1A.R17 U1A.R19 U1A.R20 U1A.R22 U1A.R23 U1A.R24 U1A.R25 U1A.R28 U1A.R29 U1A.T1 U1A.T2 U1A.T3 U1A.T4 U1A.T5 U1A.T7 U1A.T10 U1A.T11 U1A.T12 U1A.T13 U1A.T15 U1A.T17 U1A.T20 U1A.T23 U1A.T26 U1A.T27 U1A.T30 U1A.T31 U1A.U1 U1A.U2 U1A.U3 U1A.U4 U1A.U7 U1A.U9 U1A.U11 U1A.U13 U1A.U15 U1A.U17 U1A.U23 U1A.U24 U1A.U25 U1A.U28 U1A.U29 U1A.V1 U1A.V2 U1A.V3 U1A.V4 U1A.V7 U1A.V9 U1A.V11 U1A.V13 U1A.V15 U1A.V17 U1A.V20 U1A.V21 U1A.V22 U1A.V23 U1A.V26 U1A.V27 U1A.V30 U1A.V31 U1A.W2 U1A.W3 U1A.W4 U1A.W7 U1A.W9 U1A.W11 U1A.W13 U1A.W20 U1A.W22 U1A.W23 U1A.W24 U1A.W25 U1A.W28 U1A.W29 U1A.Y1 U1A.Y2 U1A.Y3 U1A.Y4 U1A.Y7 U1A.Y9 U1A.Y11 U1A.Y12 U1A.Y14 U1A.Y15 U1A.Y17 U1A.Y18 U1A.Y23 U1A.Y24 U1A.Y25 U1A.Y26 U1A.Y27 U1A.Y30 U1A.Y31 U1B.35 U1B.PAD U2.36 U2.41 U2.42 U2.43 U2.44 U2.45 U2.46 U2.47 U2.48 U2.PAD U3.4 U3.PAD U4.8 U4.PAD U5.B1 U5.B2 U5.B4 U5.C4 U5.C5 U5.C6 U5.C7 U5.D2 U5.D4 U5.D5 U5.D6 U5.D7 U5.E3 U5.E4 U5.E5 U5.E6 U5.E7 U5.F4 U5.F5 U5.G4 U5.G5 U5.G7 U6.E1 U6.E2(VOUT_2) U7.A2 U7.A7 U7.B1 U7.B2 U7.B7 U7.F2 U7.F7 U7.G1 U7.G2 U7.G7 U7.L2 U7.L7 U7.M1 U7.M2 U7.M7 U8.A2 U8.A7 U8.B1 U8.B2 U8.B7 U8.F2 U8.F7 U8.G1 U8.G2 U8.G7 U8.L2 U8.L7 U8.M1 U8.M2 U8.M7 U9.9 U10.9 U11.A10 U11.AA5 U11.AA6 U11.AA8 U11.AA9 U11.B8 U11.B9 U11.B10 U11.C3 U11.C4 U11.C10 U11.D3 U11.D4 U11.D10 U11.E3 U11.E4 U11.E6 U11.E8 U11.E9 U11.F3 U11.F5 U11.F8 U11.F10 U11.G5 U11.G6 U11.G8 U11.G9 U11.H9 U11.H10 U11.J10 U11.K3 U11.K4 U11.K10 U11.L3 U11.L4 U11.L10 U11.M4 U11.M9 U11.N3 U11.N5 U11.N8 U11.N9 U11.N10 U11.P5 U11.P6 U11.P8 U11.P9 U11.R9 U11.R10 U11.T9 U11.T10 U11.U3 U11.U4 U11.U9 U11.U10 U11.V3 U11.V4 U11.V10 U11.W3 U11.W4 U11.W6 U11.W8 U11.W9 U11.Y5 U11.Y8 U11.Y10 U12.10 U13.10 U14.10 U15.10 U16.10 U17.10 U18.10 U19.10 U20.4 U20.7(WC_N) U21.2 U22.2 U22.PAD U23.7 U23.8 U24.7 U24.8 U25.7 U25.8 U26.7 U26.8 U27.7 U27.8 U28.7 U28.8 U29.7 U29.8 U30.1 U30.2 U30.4 U30.10 U30.12 U30.14 U30.16 U30.18 U30.19 U30.21 U30.23 U30.25 U30.26 U30.41 U30.48 U30.PAD1 U30.PAD2 U30.PAD3 U30.PAD4 U31.B1 U31.B2 U31.B4 U31.C4 U31.C5 U31.C6 U31.C7 U31.D2 U31.D4 U31.D5 U31.D6 U31.D7 U31.E3 U31.E4 U31.E5 U31.E6 U31.E7 U31.F4 U31.F5 U31.G4 U31.G5 U31.G7 U32.B3 U32.B4 U32.B5 U32.C3 U32.C4 U32.C5 U32.D3 U32.D4 U32.D5 U32.E1 U32.E2 U32.E3 U32.E4 U32.E5 U32.F1 U32.F2 U32.F3 U32.F4 U32.F5 U32.G2 U32.G3 U32.G4 U32.G5 U32.G6 U32.G7 U32.H2 U32.H3 U32.H4 U32.H5 U32.H6 U32.H7 U32.J3 U32.J4 U32.J5 U32.J6 U32.J7 U32.K3 U32.K4 U32.K5 U32.L3 U32.L4 U32.L5 U32.M3 U32.M4 U32.M5 U33.A1 U33.A2 U33.A3 U33.A4 U33.A7 U33.A12 U33.AA1 U33.AA2 U33.AA3 U33.AA4 U33.AA7 U33.AA12 U33.AB1 U33.AB2 U33.AB3 U33.AB4 U33.AB7 U33.AB12 U33.B1 U33.B2 U33.B3 U33.B4 U33.B7 U33.B12 U33.C3 U33.C4 U33.C7 U33.C12 U33.D3 U33.D4 U33.D7 U33.D12 U33.E3 U33.E4 U33.E7 U33.E9 U33.E12 U33.F1 U33.F2 U33.F3 U33.F4 U33.F7 U33.F8 U33.F10 U33.F11 U33.F12 U33.G3 U33.G4 U33.G7 U33.G12 U33.H3 U33.H4 U33.H7 U33.H11 U33.H12 U33.J3 U33.J4 U33.J7 U33.J12 U33.K1 U33.K2 U33.K3 U33.K4 U33.K7 U33.K8 U33.K9 U33.K10 U33.K11 U33.K12 U33.L1 U33.L2 U33.L3 U33.L4 U33.L5 U33.L6 U33.L7 U33.L8 U33.L9 U33.L10 U33.L11 U33.L12 U33.L13 U33.L14 U33.L15 U33.M1 U33.M2 U33.M3 U33.M4 U33.M5 U33.M6 U33.M7 U33.M8 U33.M9 U33.M10 U33.M11 U33.M12 U33.M13 U33.M14 U33.M15 U33.N1 U33.N2 U33.N3 U33.N4 U33.N7 U33.N8 U33.N12 U33.P3 U33.P4 U33.P7 U33.P12 U33.R3 U33.R4 U33.R7 U33.R8 U33.R12 U33.T3 U33.T4 U33.T7 U33.T11 U33.T12 U33.U1 U33.U2 U33.U3 U33.U4 U33.U7 U33.U10 U33.U11(SGND23_2) U33.U12 U33.V3 U33.V4 U33.V7 U33.V12 U33.W3 U33.W4 U33.W7 U33.W12 U33.Y3 U33.Y4 U33.Y7 U33.Y11 U33.Y12 U34.A2 U34.A7 U34.B1 U34.B2 U34.B7 U34.F2 U34.F7 U34.G1 U34.G2 U34.G7 U34.L2 U34.L7 U34.M1 U34.M2 U34.M7 U35.4 U35.10 U35.15 U35.21 U35.26 U35.27 U35.28 U35.29 U35.30 U35.32 U35.33 U35.34 U35.39 U35.45 U36.B1 U36.B2 U36.B4 U36.C4 U36.C5 U36.C6 U36.C7 U36.D2 U36.D4 U36.D5 U36.D6 U36.D7 U36.E3 U36.E4 U36.E5 U36.E6 U36.E7 U36.F4 U36.F5 U36.G4 U36.G5 U36.G7 U37.1 U37.2 U37.6 U37.PAD U38.8 U38.PAD U39.2 U40.A1 U40.A5 U40.B2 U40.B3 U40.B4 U40.C2 U40.C3 U40.C4 U40.C5 U40.D2 U40.D3 U40.D4 U40.E3 U40.E4 U40.E5 U41.7 U41.8 U42.7 U42.8 U43.7 U43.8 U44.7 U44.8 U45.7 U45.8 U46.7 U46.8 U47.7 U47.8 U48.7 U48.8 U49.3 U50.1 U50.3 U51.37 U51.PAD1 U51.PAD2 U51.PAD3 U51.PAD4 U52.A2 U52.A7 U52.B1 U52.B2 U52.B7 U52.F2 U52.F7 U52.G1 U52.G2 U52.G7 U52.L2 U52.L7 U52.M1 U52.M2 U52.M7 U53.C2 U54.4 U54.PAD U72.A1 U72.A6 U72.B3 U72.C1 U72.C2 U72.D1 U72.D2 U72.D3 U72.D4 U72.D5 U72.D6 U72.E1 U72.E2 U72.E3 U72.E4 U72.E5 U72.E6 U72.F1 U72.F2 U72.F3 U72.F4 U72.F5 U72.F6 U73.PAD U74.C2 Y1.2 Y3.2
SVDD1P0_RX: C431.1 C434.1 C437.1 C440.1 C444.1 C449.1 E30.2(N2) R567.1 U1A.AA22 U1A.J22 U1A.K22 U1A.Y22
SVDD1P0_TX: C458.1 C460.1 C466.1 C470.1 C474.1 E31.2(N2) R566.1 U1A.N22 U1A.P22 U1A.T22 U1A.U22
VCC23: U32.A3 U32.A4
VDD_1P8_MCS_I+: R412.2(N2) R541.1 R652.1
VDD_1P8_MCS_I-: R369.1 R541.2(N2) R648.1
VDD_1V8: C785.1 C864.1 E15.2(N2) R815.2(N2) S5.1A S5.2A S5.3A S5.4A(N4) U51.44 U74.A2(VOUT)
VDD_3V3_ADF4030: C773.1 C774.1 C775.1 C776.1 C777.1 C778.1 C779.1 C780.1 C781.1 C782.1 C783.1 C784.1 C859.1 R363.2(N2) R364.2(N2) U50.5 U51.3 U51.6 U51.9 U51.12 U51.15 U51.20 U51.22 U51.25 U51.28 U51.31 U51.34 U51.39(VDD33_TDC)
VDDA1P0_ADC: C480.1 C484.1 C487.1 C492.1 C496.1 C501.1 C506.1 C510.1 C660.1 C661.1 C662.1 C669.1 C670.1 C671.1 R134.1 R562.2(N2) U1A.K5 U1A.L5 U1A.M5 U1A.N5 U1A.U5 U1A.V5 U1A.W5 U1A.Y5
VDDA1P0_ADC_EN: R20.1 R150.1 R763.1 U11.A7
VDDA1P0_ADC_REF: C713.1 C763.2(N2) R498.2(N2) R789.1 U7.L6(VREF3)
VDDA1P0_ADC_SCLK: C479.1 C483.1 C486.1 C491.1 C495.1 C500.1 C505.1 C509.1 C663.1 C664.1 C665.1 C672.1 C673.1 C674.1 C759.2(N2) R558.1 U1A.K6 U1A.L6 U1A.M6 U1A.N6 U1A.U6 U1A.V6 U1A.W6 U1A.Y6 U52.M5 U52.M6 U52.N5 U52.N6 U52.N7 U52.P5 U52.P6 U52.P7
VDDA1P0_ADCBK: C202.1 C203.1 C478.1 C490.1 C494.1 C499.1 C504.1 C508.1 C666.1 C667.1 C668.1 C675.1 C676.1 C677.1 R492.1 R756.2(N2) U1A.K10 U1A.L10 U1A.M10 U1A.N10 U1A.U10 U1A.V10 U1A.W10 U1A.Y10
VDDA1P0_ADCBK_EN: R21.1 R58.1 R157.1 U11.A6
VDDA1P0_ADCBK_REF: C707.2(N2) C710.1 R505.2(N2) U7.A6 U7.F6
VDDA1P0_CK: E24.1 E26.1 E27.1 R135.1 R493.2(N2)
VDDA1P0_CK_IMON: R670.1 TP8.1(N1) U8.A5
VDDA1P0_DAC: C481.1 C485.1 C488.1 C493.1 C497.1 C502.1 C507.1 C511.1 R568.2(N2) R777.2(N2) U1A.AA12 U1A.AA14 U1A.AA15 U1A.AA17 U1A.J12 U1A.J14 U1A.J15 U1A.J17
VDDA1P0_DAC_IMON: R664.1 R762.2(N2) TP36.1(N1) U52.A5 UNK80B_V4.1
VDDA1P0_EN: R151.1 R517.1 R542.1 R761.1 U8.E3 U11.D7
VDDA1P0_REF: C321.2(N2) C712.1 C753.2(N2) R499.2(N2) U8.A6 U52.A6 U52.F6
VDDA1P0_SCLK_IMON: R759.2(N2) TP39.1(N1) U52.L5
VDDA_1P8: E23.1 R139.1 R494.2(N2)
VDDA_1P8_DAC: C1WA.1 C1WB.1 C1XA.1 C1XB.1 C1YA.1 C1YB.1 C1ZA.1 C1ZB.1 C2WA.1 C2WB.1 C2XA.1 C2XB.1 C2YA.1 C2YB.1 C2ZA.1 C2ZB.1 C3WA.1 C3WB.1 C3XA.1 C3XB.1 C3YA.1 C3YB.1 C3ZA.1 C3ZB.1 C4WA.1 C4WB.1 C4XA.1 C4XB.1 C4YA.1 C4YB.1 C4ZA.1 C4ZB.1 C6WA.1 C6WB.1 C6XA.1 C6XB.1 C6YA.1 C6YB.1 C6ZA.1 C6ZB.1 C7WA.1 C7WB.1 C7XA.1 C7XB.1 C7YA.1 C7YB.1 C7ZA.1 C7ZB.1 C335.1 C338.1 C339.1 C340.1 C343.1 C344.1 C345.1 C348.1 C349.1 C350.1 C352.1 C353.1 C355.1 C358.1 C360.1 C361.1 C363.1 C365.1 C366.1 C368.1 C370.1 C375.1 C378.1 C381.1 C382.1 C385.1 C386.1 C389.1 C390.1 C393.1 C394.1 C397.1 C398.1 C401.1 C402.1 C405.1 C406.1 C418.1 C419.1 C420.1 C421.1 C422.1 C423.1 C424.1 C425.1 C426.1 C427.1 C629.1 C698.2(N2) C699.2(N2) C700.2(N2) C701.2(N2) C702.2(N2) C703.2(N2) E20.1 R141.1 R476.1 R479.2(N2) R506.2(N2) R576.1 T1WA.PAD T1WB.PAD T1XA.PAD T1XB.PAD T1YA.PAD T1YB.PAD T1ZA.PAD T1ZB.PAD U1A.A6 U1A.A9 U1A.A10 U1A.A13 U1A.A14 U1A.A17 U1A.A18 U1A.A21 U1A.AD12 U1A.AD14 U1A.AD15 U1A.AD17 U1A.AE12 U1A.AE14 U1A.AE15 U1A.AE17 U1A.AJ6 U1A.AJ9 U1A.AJ10 U1A.AJ13 U1A.AJ14 U1A.AJ17 U1A.AJ18 U1A.AJ21 U1A.E12 U1A.E14 U1A.E15 U1A.E17 U1A.F12 U1A.F14 U1A.F15 U1A.F17
VDDA_1P8_DAC_EN: R154.1 R418.1 U8.L1 U11.D6
VDDA_1P8_DAC_IMON: R663.1 TP10.1(N1) U8.L5
VDDA_1P8_DAC_REF: C320.2(N2) C709.1 R502.2(N2) U8.L6(VREF3)
VDDA_1P8_EN: R153.1 U8.F1 U11.B7
VDDA_1P8_IMON: R662.1 TP9.1(N1) U8.F5
VDDA_1P8_REF: C606.2(N2) C711.1 R501.2(N2) U8.F6
VDDD_0P8: C371.1 C372.1 C373.1 C374.1 C376.1 C377.1 C379.1 C380.1 C383.1 C384.1 C387.1 C388.1 C391.1 C392.1 C395.1 C396.1 C399.1 C400.1 C403.1 C404.1 C407.1 C408.1 C409.1 C410.1 C597.2(N2) C598.2(N2) C599.2(N2) C600.P(N3) L5.2(N2) R571.2(N2) U1A.L19 U1A.L21 U1A.M14 U1A.M16 U1A.M18 U1A.M19 U1A.N14 U1A.N16 U1A.N18 U1A.P14 U1A.P16 U1A.P18 U1A.R14 U1A.R16 U1A.T14 U1A.T16 U1A.T18 U1A.U14 U1A.U16 U1A.U18 U1A.V14 U1A.V16 U1A.V18 U1A.V19 U1A.W19 U1A.W21
VDDD_1P0: C454.1 C457.1 C467.1 C471.1 C590.2(N2) C594.P(N3) L9.2(N2) R565.2(N2) U1A.AB19 U1A.H19 U1A.R21 U1A.T21
VDDD_1P0_ADC: C442.1 C446.1 C451.1 C455.1 C589.2(N2) C593.P(N3) L8.2(N2) R564.2(N2) U1A.L12 U1A.M12 U1A.V12 U1A.W12
VDDD_1P0_SERDES: C591.2(N2) C595.P(N3) E30.1 E31.1 L18.2(N2)
VDDD_1P8: C150.2(N2) C453.1 C456.1 C477.1 R138.1 R326.1 R556.2(N2) U1A.AC19 U1A.G19 U1A.P21 U1A.R18 U3.1 U3.2 U3.3(VOUT_SENSE)
VDDD_1P8_EN: C172.2(N2) R152.1 R534.1 U11.C7 U32.C2
VDDD_1P8_GP: C144.1 C169.2(N2) C265.2(N2) C266.2(N2) C267.2(N2) C268.2(N2) C273.2(N2) C274.2(N2) C275.2(N2) C637.2(N2) C678.2(N2) C679.2(N2) C680.2(N2) C684.2(N2) C685.2(N2) C688.2(N2) C689.2(N2) P2.1 P3.1 R469.1 R687.1 U22.5(VIO) U23.2 U24.2 U25.2 U26.2 U27.2 U28.2 U29.2 U41.2 U42.2 U43.2 U44.2 U45.2 U46.2 U47.2 U48.2 U54.1 U54.2 U54.3(VOUT_SENSE)
VDDD_1P8_I+: C132.2(N2) C153.2(N2) L11.2(N2) R25.2(N2) R496.1 R649.1 U54.7 U54.8
VDDD_1P8_I-: C143.2(N2) R496.2(N2) R645.1 U3.7 U3.8
VDDD_1P8_MCS: E21.1 E22.1 R369.2(N2)
0P8V_PG: Q1.2 R331.1 R530.1
0P8V_PG_LED: DS6.C Q1.6
0P8VADC_PG: Q1.5 R333.1 R531.1
0P8VADC_PG_LED: DS7.C Q1.3
1P0VD: C579.2(N2) C582.2(N2) C585.P(N3) L9.1 L18.1 R524.2(N2) U33.AA13 U33.AA14 U33.AA15 U33.AB13 U33.AB14 U33.AB15 U33.R11 U33.V13 U33.V14 U33.V15 U33.W13 U33.W14 U33.W15 U33.Y13 U33.Y14 U33.Y15
1P0VD_PG: Q3.2 R338.1 R532.1
1P0VD_PG_LED: DS8.C Q3.6
1P0VDAC: C438.1 C441.1 C445.1 C450.1 C610.2(N2) C611.2(N2) C612.2(N2) C613.2(N2) L21.2(N2) R563.2(N2) U1A.K13 U1A.K16 U1A.Y13 U1A.Y16
1P0VDAC_PG: Q3.5 R342.1 R522.2(N2) TP18.1(N1)
1P0VDAC_PG_LED: DS9.C Q3.3
1P0VDACDIG_I+: C529.2(N2) C535.2(N2) C609.2(N2) R521.2(N2) R523.1 R624.1 U1.A1 U1.A2 U1.A3 U1.B3 U1.F3 U1.G1 U1.G2 U1.G3(VOUT_8)
1P0VDACDIG_I-: L21.1 R523.2(N2) R524.1 R625.1 U1.F1
1P0VDACINTVCC: R520.1 U1.D3
1P3V_I-_ADC1PO: C181.2(N2) C182.2(N2) C183.2(N2) R415.2(N2) R669.1 U7.B3 U7.B4 U7.C1 U7.C2 U7.C3 U7.C4 U7.D1 U7.D2 U7.D3 U7.D4 U7.G3 U7.G4 U7.H1 U7.H2 U7.H3 U7.H4 U7.J1 U7.J2 U7.J3 U7.J4 U7.M3 U7.M4 U7.N1 U7.N2 U7.N3 U7.N4 U7.P1 U7.P2 U7.P3 U7.P4
1P3V_I-_DAC1PO: C754.2(N2) C755.2(N2) R760.2(N2) U52.B3 U52.B4 U52.C1 U52.C2 U52.C3 U52.C4 U52.D1 U52.D2 U52.D3 U52.D4 U52.G3 U52.G4 U52.H1 U52.H2 U52.H3 U52.H4 U52.J1 U52.J2 U52.J3 U52.J4
1P3V_I-_SCLK: C756.2(N2) R656.1 R758.2(N2) U52.M3 U52.M4 U52.N1 U52.N2 U52.N3 U52.N4 U52.P1 U52.P2 U52.P3 U52.P4
1P3VA_PG: Q5.2 R340.2(N2) R357.1 TP2.1(N1)
1P3VA_PG_LED: DS10.C Q5.6
1P3VAINTVCC_A: R147.1 U31.D3
1P4V: R101.1 R365.2(N2) R366.2(N2) R415.1 R655.1 R668.1 R758.1 R760.1
1P8V_MCS_PG: Q6.5 R360.1 R387.2(N2) TP5.1(N1)
1P8V_MCS_PG_LED: DS15.C Q6.3
1P8VD_PG: Q4.5 R343.1 R537.2(N2) TP21.1(N1)
1P8VD_PG_LED: DS11.C Q4.3
2P1V: R102.1 R411.2(N2) R644.1 R779.2(N2)
2P1V_PG: Q4.2 R339.1 R386.2(N2) TP4.1(N1)
2P1V_PG_LED: DS12.C Q4.6
2P1V_VOUT4_PG: Q2.5 R336.1 R408.2(N2) TP7.1(N1)
2P8V_PG_LED: DS13.C Q2.3
3P6V_PG: Q6.2 R63.2(N2) R358.1 TP27.1(N1)
3P6V_PG_LED: DS5.C Q6.6
3P6VAINTVCC: R60.1 U36.D3
3P8V: C531.2(N2) C534.2(N2) C604.2(N2) C616.2(N2) L20.2(N2) R361.1 R416.1 R550.1
5P7V_PG: Q2.2 R332.1 R388.2(N2) TP6.1(N1)
5P7V_PG_LED: DS4.C Q2.6
5P88V: R331.2(N2) R332.2(N2) R333.2(N2) R336.2(N2) R338.2(N2) R339.2(N2) R342.2(N2) R343.2(N2) R357.2(N2) R358.2(N2) R359.2(N2) R360.2(N2) R409.2(N2) R417.1 R516.1 R546.1 R606.1 R608.1 R706.1 R707.1 U32.A5 U32.N3
2980_RESETB: R142.2(N2) U11.B2 U11.J2 U11.T2
ADC_A0: C533.1 R72.1 U1A.AH1
ADC_A0_CONN: ADC_A0.1(N1) C533.2(N2)
ADC_A1: C545.1 R76.1 U1A.AE1
ADC_A1_CONN: ADC_A1.1(N1) C545.2(N2)
ADC_A2: C532.1 U1A.AB1
ADC_A2_CONN: ADC_A2.1(N1) C532.2(N2)
ADC_A3: C546.1 U1A.W1
ADC_A3_CONN: ADC_A3.1(N1) C546.2(N2)
ADC_B0: C647.1 R77.1 U1A.B1
ADC_B0_CONN: ADC_B0.1(N1) C647.2(N2)
ADC_B1: C536.1 R75.1 U1A.E1
ADC_B1_CONN: ADC_B1.1(N1) C536.2(N2)
ADC_B2: C646.1 U1A.H1
ADC_B2_CONN: ADC_B2.1(N1) C646.2(N2)
ADC_B3: C537.1 U1A.L1
ADC_B3_CONN: ADC_B3.1(N1) C537.2(N2)
ADDR0: R736.1 S5.1B U51.16
ADDR1: R737.1 S5.2B U51.17
ADDR2: R738.1 S5.3B U51.21
ADDR3: R739.1 S5.4B U51.47
ADF4030_3P3V: R304.2(N2) R363.1
ADF4382_3P3_1: C112.1 C118.1 C119.1 C122.1 C123.1 C201.1 C752.1 E4.2(N2) R303.1 U30.3 U30.30 U30.36 U30.40 U30.44 U30.45
ADF4382_3P3_2: C102.1 C114.1 C117.1 C131.1 C255.2(N2) C259.2(N2) C310.1 C750.1 E5.2(N2) L1.1 L3.1 L4.2(N2) L10.2(N2) R290.2(N2) U30.5 U30.11 U30.13 U30.24
ADF4382_3P3V: C125.1 C130.1 C184.2(N2) E4.1 E5.1 R304.1 U34.B5 U34.B6 U34.C5 U34.C6 U34.C7 U34.D5 U34.D6 U34.D7
ADF4382_5P0V: C108.1 C111.1 C135.2 E2.1 E3.1 R19.1 U4.10
ADF4382_CE: Q8.6 R303.2(N2) U30.31
ADF4382_CE_LS: R240.1 R318.1
ADF4382_LKDET: R259.1 R295.1 U30.27
ADF4382_OUTN: C325.1 L4.1 U30.20
ADF4382_OUTP: C323.1 L3.2(N2) U30.22
ADS10_HMC7044_REFCLK_N: C565.1 U1B.30
ADS10_HMC7044_REFCLK_P: C564.1 U1B.29
ADS10_REFCLK_N: C565.2(N2) P1.L25
ADS10_REFCLK_P: C564.2(N2) P1.L24
AION_REFIN_N: C771.1 U1B.4
AION_REFIN_P: C772.1 U1B.3
APOLLO_DELADJ: R316.1 U30.28
APOLLO_DELSTR: R317.1 U30.29
APOLLO_RESET: R325.2(N2) R326.2(N2) S2.1A S2.1B U1A.D22
APOLLO_RESET_LS: R255.1 R325.1
APOLLO_SYSREF_N: R14.1 R724.2(N2) TP51.1(N1)
APOLLO_SYSREF_P: R12.1 R723.2(N2) TP50.1(N1)
APOLLO_TRIG_A0: R525.1 U1B.24
ARTEMIS_REFIN_N: C311.1 U2.3
ARTEMIS_REFIN_P: C314.1 U2.4
ARTEMIS_SYNC_N: C233.2(N2) R713.1
ARTEMIS_SYNC_P: C232.2(N2) R714.1
AUX_GPIO0_FMC: P1.H38 R273.2(N2)
AUX_GPIO1_FMC: P1.E34 R267.2(N2)
AUX_GPIO2: R5.1 R245.1
AUX_GPIO2_FMC: P1.F37 R264.2(N2)
AUX_GPIO3_FMC: P1.F38 R270.2(N2)
AUX_GPIO4_FMC: P1.E36 R276.2(N2)
AUX_GPIO5_FMC: P1.E37 R285.2(N2)
BRD_12V: Q16.5 Q16.6 Q16.7 Q16.8 R71.2(N2) R337.2(N2) R643.1 U39.5
BSYNC0_N: R385.2(N2) R721.2(N2) R722.2(N2) U1B.14
BSYNC0_P: R103.2(N2) R720.2(N2) R722.1 U1B.13
BSYNC1_N: R745.1 U51.4
BSYNC1_P: R740.1 U51.5
BSYNC2_N: R752.1 U51.7
BSYNC2_P: R751.1 U51.8
BSYNC3_N: R733.1 U51.10
BSYNC3_P: R732.1 U51.11
BSYNC4_N: R750.1 U51.13
BSYNC4_P: R749.1 U51.14
BSYNC5_N: R724.1 U51.23
BSYNC5_P: R723.1 U51.24
BSYNC6_N: R716.2(N2) R744.1 U51.26
BSYNC6_P: R718.2(N2) R743.1 U51.27
BSYNC7_N: R719.2(N2) R726.1 U51.29
BSYNC7_P: R717.2(N2) R725.1 U51.30
BSYNC8_N: R742.1 U51.32
BSYNC8_P: R741.1 U51.33
BSYNC9_N: R17.1 U51.35
BSYNC9_P: R16.1 U51.36
CLK_M2C_N_0: C569.2(N2) P1.H5 R394.2(N2)
CLK_M2C_N_1: C571.2(N2) P1.G3 R395.2(N2)
CLK_M2C_P_0: C568.2(N2) P1.H4 R394.1
CLK_M2C_P_1: C570.2(N2) P1.G2 R395.1
CLKA_N: C328.1 U1A.AF3
CLKA_P: C329.1 U1A.AG3
CLKB_N: C327.1 U1A.D3
CLKB_P: C326.1 U1A.C3
CLKC_N: C323.2(N2) C324.1 U1A.R1
CLKC_P: C325.2(N2) C330.1 U1A.P1
DACA0_N: T1WA.2 U1A.AJ8
DACA0_P: T1WA.3 U1A.AJ7
DACA1_N: T1XA.3 U1A.AJ11
DACA1_P: T1XA.2 U1A.AJ12
DACA2_N: T1YA.2 U1A.AJ16
DACA2_P: T1YA.3 U1A.AJ15
DACA3_N: T1ZA.3 U1A.AJ19
DACA3_P: T1ZA.2 U1A.AJ20
DACB0_N: T1WB.3 U1A.A8
DACB0_P: T1WB.2 U1A.A7
DACB1_N: T1XB.2 U1A.A11
DACB1_P: T1XB.3 U1A.A12
DACB2_N: T1YB.3 U1A.A16
DACB2_P: T1YB.2 U1A.A15
DACB3_N: T1ZB.2 U1A.A19
DACB3_P: T1ZB.3 U1A.A20
DUT_CSB: R176.2(N2) R177.1 U1A.T19
DUT_CSB_FMC: P1.H8 R218.2(N2)
DUT_CSB_HDR: P2.5 R176.1
DUT_SCLK: R180.2(N2) R181.1 U1A.U19
DUT_SCLK_FMC: P1.H7 R230.2(N2)
DUT_SCLK_HDR: P2.3 R180.1
DUT_SDIO: R173.2(N2) R174.1 U1A.P19
DUT_SDIO_FMC: P1.G9 R210.2(N2)
DUT_SDIO_HDR: P2.7 R173.1
DUT_SDO: R170.2(N2) R171.1 U1A.N19
DUT_SDO_FMC: P1.G10 R206.2(N2)
DUT_SDO_HDR: P2.9 R170.1
EXT_3P3V: P5.4(N4) Q13.3 Q14.3 Q15.3 Q18.3 Q22.3
EXT_CLK: REFCLK.1 T4.3
EXT_REF: C213.1 EXT_HMCREF.1 R2.1
EXT_SYNC: EXT_SYNC.1 R7.2(N2)
FAN_PWM: FANPWM.1(N1) Q17.1 R61.2(N2) R337.1
FMC_3P3V: C250.1 C251.1 C254.1 C256.1 C257.1 C258.1 C260.1 C261.1 C605.1 P1.C39 P1.D36 P1.D38 P1.D40 P1.Z40 R458.2(N2) U12.6(VDD) U13.6(VDD) U14.6(VDD) U15.6(VDD) U16.6(VDD) U17.6(VDD) U18.6(VDD) U19.6(VDD) U35.7 U35.18 U35.31 U35.42(VCC_4) UNK3P3V.1
FMC_3P3VAUX: C141.1 P1.D32 R711.1 R712.1 U20.8
FMC_12P0V: FMC12O.1(N1) P1.C35 P1.C37 P1.L36 P1.L37 P1.L40
FMC_GA0: P1.C34 U20.2
FMC_GA1: P1.D35 U20.1
FMC_SCL: P1.C30 R160.2(N2) R433.2(N2)
FMC_SDA: P1.C31 R162.1 R434.2(N2)
FMC_VADJ: C269.1 C270.1 C271.1 C272.1 C276.1 C277.1 C278.1 C638.1 C681.1 C682.1 C683.1 C686.1 C687.1 C690.1 C691.1 P1.E39 P1.F40 P1.G39 P1.H40 P1.J39 P1.K40 U23.1(VCCB) U24.1(VCCB) U25.1(VCCB) U26.1(VCCB) U27.1(VCCB) U28.1(VCCB) U29.1(VCCB) U41.1(VCCB) U42.1(VCCB) U43.1(VCCB) U44.1(VCCB) U45.1(VCCB) U46.1(VCCB) U47.1(VCCB) U48.1(VCCB) UNK1P8V.1
FPGA_REFCLK_0_N: C555.2(N2) P1.D5 R389.2(N2)
FPGA_REFCLK_0_P: C554.2(N2) P1.D4 R389.1
FPGA_REFCLK_1_N: C557.2(N2) P1.B21 R390.2(N2)
FPGA_REFCLK_1_P: C556.2(N2) P1.B20 R390.1
FPGA_REFCLK_2_N: C559.2(N2) P1.L13 R391.2(N2)
FPGA_REFCLK_2_P: C558.2(N2) P1.L12 R391.1
FPGA_REFCLK_3_N: C561.2(N2) P1.L9 R392.2(N2)
FPGA_REFCLK_3_P: C560.2(N2) P1.L8 R392.1
FPGA_REFCLK_4_N: C563.2(N2) P1.L5 R393.2(N2)
FPGA_REFCLK_4_P: C562.2(N2) P1.L4 R393.1
FPGA_REFCLK_5_N: C567.2(N2) P1.Z21 R715.2(N2)
FPGA_REFCLK_5_P: C566.2(N2) P1.Z20 R715.1
GPIO0: R178.1 U1A.AC22
GPIO0_FMC: P1.K25 R213.2(N2)
GPIO1: R172.1 U1A.AD22
GPIO1_FMC: P1.K26 R221.2(N2)
GPIO2: R175.1 U1A.AE23
GPIO2_FMC: P1.J24 R231.2(N2)
GPIO3: R179.1 U1A.AG21
GPIO3_FMC: P1.J25 R225.2(N2)
GPIO4: P2.15 R191.1 U1A.AD19 U35.47
GPIO4_FMC: P1.F22 R232.2(N2)
GPIO5: P2.2 R182.1 U1A.AA21 U35.46
GPIO5_FMC: P1.F23 R219.2(N2)
GPIO6: P2.4 R197.1 U1A.Y21 U35.44
GPIO6_FMC: P1.E21 R211.2(N2)
GPIO7: P2.6 R184.1 U1A.W18 U35.43
GPIO7_FMC: P1.E22 R207.2(N2)
GPIO8: P2.8 R198.1 R407.2(N2) U1A.W17 U35.41
GPIO8_FMC: P1.F25 R214.2(N2)
GPIO8_HDR: R407.1 U22.21
GPIO9: P2.10 R185.1 R406.2(N2) U1A.W16 U35.40
GPIO9_FMC: P1.F26 R222.2(N2)
GPIO9_HDR: R406.1 U22.20
GPIO10: P2.12 R192.1 R405.2(N2) U1A.W15 U35.38
GPIO10_FMC: P1.E24 R233.2(N2)
GPIO10_HDR: R405.1 U22.13
GPIO11: R199.1 R404.2(N2) U1A.W14
GPIO11_FMC: P1.E25 R226.2(N2)
GPIO11_HDR: R404.1 U22.12
GPIO12: R193.1 U1A.L14
GPIO12_FMC: P1.K28 R234.2(N2)
GPIO13: R183.1 U1A.L15
GPIO13_FMC: P1.K29 R220.2(N2)
GPIO14: R200.1 U1A.L16
GPIO14_FMC: P1.J27 R212.2(N2)
GPIO15: R186.1 R317.2(N2) U1A.L17
GPIO15_FMC: P1.C10 R208.2(N2)
GPIO16: R201.1 R316.2(N2) U1A.L18
GPIO16_FMC: P1.C11 R215.2(N2)
GPIO17: R187.1 U1A.K21
GPIO17_FMC: P1.H13 R223.2(N2)
GPIO18: R194.1 U1A.J21
GPIO18_FMC: P1.H14 R235.2(N2)
GPIO19: R202.1 U1A.F19
GPIO19_FMC: P1.H16 R227.2(N2)
GPIO20: R195.1 U1A.C21
GPIO20_FMC: P1.H17 R236.2(N2)
GPIO21: R188.1 U1A.E23
GPIO21_FMC: P1.G15 R224.2(N2)
GPIO22: R203.1 U1A.F22
GPIO22_FMC: P1.G16 R216.2(N2)
GPIO23: R189.1 U1A.G22
GPIO23_FMC: P1.C18 R209.2(N2)
GPIO24: R204.1 U1A.E19
GPIO24_FMC: P1.C19 R217.2(N2)
GPIO25: R190.1 U1A.E20
GPIO25_FMC: P1.H19 R228.2(N2)
GPIO26: R166.2(N2) R196.1 U1A.D19
GPIO26_FMC: P1.H20 R237.2(N2)
GPIO27: R168.2(N2) R205.1 U1A.D20
GPIO27_FMC: P1.C22 R229.2(N2)
GPIO28: R165.2(N2) R247.1 U1A.E21
GPIO28_FMC: P1.C23 R280.2(N2)
GPIO29: R167.2(N2) R238.1 U1A.E22
GPIO29_FMC: P1.H22 R271.2(N2)
GPIO30: R164.2(N2) R253.1 U1A.D21
GPIO30_FMC: P1.H23 R265.2(N2)
GPIO31: R241.1 U1A.N20
GPIO31_FMC: P1.J28 R262.2(N2)
GPIO32: R254.1 U1A.N21
GPIO32_FMC: P1.F34 R268.2(N2)
GPIO33: R242.1 U1A.U20
GPIO33_FMC: P1.F35 R274.2(N2)
GPIO34: R248.1 U1A.U21
GPIO34_FMC: P1.K37 R281.2(N2)
HMC7044_3P3V: C185.2(N2) E1.1 E2B.1 E7.1 E8.2(N2) E9.2(N2) E10.2(N2) E11.2(N2) E12.2(N2) E13.2(N2) E14.2(N2) R103.1 R385.1 U34.G5 U34.G6 U34.H5 U34.H6 U34.H7 U34.J5 U34.J6 U34.J7
HMC7044_CLK0_N: C231.2(N2) C318.1 L15.1
HMC7044_CLK0_P: C230.2(N2) C318.2(N2) L16.1
HMC7044_CLK2_N: C567.1 U1B.16
HMC7044_CLK2_P: C566.1 U1B.15
HMC7044_CLK5_N: C563.1 U1B.23
HMC7044_CLK5_P: C562.1 U1B.22
HMC7044_CLK8_N: C569.1 U1B.56
HMC7044_CLK8_P: C568.1 U1B.55
HMC7044_CLK9_N: C571.1 U1B.54
HMC7044_CLK9_P: C570.1 U1B.53
HMC7044_CLK10_N: C555.1 U1B.59
HMC7044_CLK10_P: C554.1 U1B.58
HMC7044_CLK11_N: C557.1 U1B.61
HMC7044_CLK11_P: C556.1 U1B.60
HMC7044_CLK12_N: C559.1 U1B.67
HMC7044_CLK12_P: C558.1 U1B.66
HMC7044_CLK13_N: C561.1 U1B.65
HMC7044_CLK13_P: C560.1 U1B.64
HMC7044_FIN_N: C156.1 U2.15
HMC7044_FIN_P: C155.1 U2.16
HMC7044_GPIO3: R260.1 R687.2(N2) U1B.62
HMC7044_REFIN_N: C217.1 U2.9
HMC7044_REFIN_P: C216.1 U2.10
HMC_CPOUT1: C128.1 C129.1 U1B.32 Y1.1
HSCI_CKIN_N: R319.1 R321.1 U1A.AE20
HSCI_CKIN_N_FMC: P1.C27 R321.2(N2)
HSCI_CKIN_P: R319.2(N2) R322.1 U1A.AF20
HSCI_CKIN_P_FMC: P1.C26 R322.2(N2)
HSCI_CKO_N: R327.1 U1A.AE22
HSCI_CKO_N_FMC: P1.G34 R327.2(N2)
HSCI_CKO_P: R328.1 U1A.AF22
HSCI_CKO_P_FMC: P1.G33 R328.2(N2)
HSCI_DIN_N: R320.1 R323.1 U1A.AE19
HSCI_DIN_N_FMC: P1.G28 R323.2(N2)
HSCI_DIN_P: R320.2(N2) R324.1 U1A.AF19
HSCI_DIN_P_FMC: P1.G27 R324.2(N2)
HSCI_DO_N: R329.1 U1A.AE21
HSCI_DO_N_FMC: P1.H32 R329.2(N2)
HSCI_DO_P: R330.1 U1A.AF21
HSCI_DO_P_FMC: P1.H31 R330.2(N2)
LTC6955_3P3V: C186.2(N2) C279.1 C280.1 C281.1 C282.1 C283.1 C284.1 C285.1 C286.1 C287.1 C288.1 C289.1 C290.1 C291.1 C292.1 C293.1 C294.1 C295.1 C296.1 C297.1 C298.1 C299.1 C300.1 C301.1 C302.1 C303.1 C304.1 C305.1 C306.1 C307.1 C308.1 C309.1 R307.1 R311.1 U2.2 U2.5 U2.8 U2.11 U2.14 U2.17 U2.20 U2.23 U2.26 U2.29(VOUT+_9) U2.32 U2.35 U2.39 U34.M5 U34.M6 U34.N5 U34.N6 U34.N7 U34.P5 U34.P6 U34.P7
LTM4681_VDD25_01: R435.1 R436.1 R437.1 R438.1 R439.1 R440.1 TP19.1(N1) U33.C8
LTM4681_VDD25_23: TP20.1(N1) U33.AB11
LTM4681_VDD33_01: Q14.2(S) R379.2(N2) R425.2(N2) R426.2(N2) R427.2(N2) R428.2(N2) R429.2(N2) R430.2(N2) R431.2(N2) R432.2(N2) U33.E8
LTM4681_VDD33_23: Q15.2(S) U33.Y10
LTM4681_VOUT01: C577.2(N2) C580.2(N2) C583.2(N2) C586.2(N2) C587.2(N2) C588.2(N2) C592.P(N3) C596.P(N3) L5.1 U33.A13 U33.A14 U33.A15 U33.B13 U33.B14 U33.B15 U33.C13 U33.C14 U33.C15 U33.D13 U33.D14 U33.D15 U33.E13 U33.E14 U33.E15 U33.F13 U33.F14 U33.F15 U33.G8 U33.G13 U33.G14 U33.G15 U33.H13 U33.H14 U33.H15 U33.J11 U33.J13 U33.J14 U33.J15 U33.K13 U33.K14 U33.K15
LTM4681_VOUT2: C578.2(N2) C581.2(N2) C584.P(N3) L8.1 U33.N13 U33.N14 U33.N15 U33.P8 U33.P13 U33.P14 U33.P15 U33.R13 U33.R14 U33.R15 U33.T13 U33.T14 U33.T15 U33.U13 U33.U14 U33.U15
MUXOUT1: TP42.1(N1) U51.45
MUXOUT2: TP43.1(N1) U51.46
NEG2P3V_PG_LED: DS14.C Q5.3
NEG2P4V: C176.1 C177.1 R18.1 R79.1 R81.1 R123.1 R497.2(N2) R500.2(N2) R596.1 R607.1 R704.1 R705.1 U6.A1 U6.A5 U6.B2 U6.B3 U6.B4 U6.C2 U6.C3 U6.C4 U6.C5 U6.D2 U6.D3 U6.D4 U6.E3 U6.E4 U6.E5
NEG2P4V_PG: Q5.5 R359.1 R540.2(N2) TP22.1(N1)
PG_C2M: P1.D1 R482.1
PG_M2C: P1.F1 R586.2(N2)
PSM_ALERT: R528.2(N2) R604.1 R633.1 U11.F2 U11.N2 U11.Y2
PSM_CONTROL: Q9.6 R136.2(N2) R628.1 U11.AA3 U11.F1 U11.G3 U11.N1 U11.P3 U11.Y1
PSM_FAULT: R62.1 R602.1 R634.1 U11.C1 U11.C2 U11.D1 U11.D2 U11.K1 U11.K2 U11.L1 U11.L2 U11.U1 U11.U2 U11.V1 U11.V2
PSM_PGOOD: R555.2(N2) R586.1 TP33.1(N1)
PSM_RUN: Q9.3 R136.1 R429.1 U33.B10 U33.B11 U33.Y8 U33.Y9
PSM_SCL: P5.3 P7.1 R149.2(N2) R433.1 R597.1 R646.1 R672.1
PSM_SDA: P5.1 P7.3(N3) R374.2(N2) R434.1 R598.1 R647.1 R673.1
PSM_SHARE_CLK: R143.2(N2) R379.1 R653.2(N2) R679.2(N2) U11.B1 U11.J1 U11.T1 U33.AA11 U33.D8
PSM_VDD3_A: C210.1 Q18.2(S) R142.1 R143.1 R150.2(N2) R151.2(N2) R152.2(N2) R153.2(N2) R154.2(N2) R155.2(N2) R156.2(N2) R157.2(N2) R599.1 R600.1 R602.2(N2) R603.2(N2) R604.2(N2) R626.1 R628.2(N2) R629.1 R635.2(N2) R636.2(N2) R665.2(N2) R666.2(N2) U11.A4 U11.B4
PSM_VDD3_B: C721.1 Q22.2(S) R78.1 R676.1 R679.1 R708.1 U11.R4 U11.T4
PSM_VDD3_C: C716.1 Q13.2(S) R68.1 R650.1 R653.1 R703.1 U11.H4 U11.J4
RBIAS_EXT_F_A: R314.1 U1A.AG5 U1A.AH5
RBIAS_EXT_F_B: R313.1 U1A.B5 U1A.C5
REFCLK_N: C333.2(N2) C334.1 U1A.P2
REFCLK_P: C331.2(N2) C332.1 U1A.R2
REFIN_DUT_N: C771.2(N2) R735.1 U51.18
REFIN_DUT_P: C772.2(N2) R735.2(N2) U51.19
REFN_OSC: C766.1 R29.2(N2)
REFP_OSC: C765.1 R28.2(N2)
RESETB_FMC: P1.D8 R277.2(N2)
SPI2_CS0: R243.1 R584.2(N2)
SPI2_CS0_FMC: P1.D27 R263.2(N2)
SPI2_CS1: R257.1 R514.1 TP64.1(N1)
SPI2_CS1_FMC: P1.G30 R269.2(N2)
SPI2_CS2: R244.1 TP58.1(N1)
SPI2_CS2_FMC: P1.G31 R275.2(N2)
SPI2_CS3: R250.1 TP41.1(N1)
SPI2_CS3_FMC: P1.H34 R283.2(N2)
SPI2_CS4: R258.1 TP40.1(N1) U51.40
SPI2_CS4_FMC: P1.H35 R278.2(N2)
SPI2_CS5: R251.1 TP59.1(N1)
SPI2_CS5_FMC: P1.H37 R284.2(N2)
SPI2_SCLK: R249.1 R413.1 R582.2(N2) U51.42
SPI2_SCLK_FMC: P1.H28 R282.2(N2)
SPI2_SDIO: R239.1 R410.1 R583.2(N2) U51.41
SPI2_SDIO_FMC: P1.H29 R272.2(N2)
SPI2_SDO: R256.1 R581.2(N2) U51.43
SPI2_SDO_FMC: P1.D26 R266.2(N2)
SRXA_0N: C86.2(N2) U1A.AG25
SRXA_0N_FMC: C86.1 P1.M39
SRXA_0P: C74.2(N2) U1A.AG24
SRXA_0P_FMC: C74.1 P1.M38
SRXA_1N: C87.2(N2) U1A.AJ25
SRXA_1N_FMC: C87.1 P1.A39
SRXA_1P: C75.2(N2) U1A.AJ24
SRXA_1P_FMC: C75.1 P1.A38
SRXA_2N: C88.2(N2) U1A.AF27
SRXA_2N_FMC: C88.1 P1.M35
SRXA_2P: C76.2(N2) U1A.AF26
SRXA_2P_FMC: C76.1 P1.M34
SRXA_3N: C89.2(N2) U1A.AH27
SRXA_3N_FMC: C89.1 P1.B37
SRXA_3P: C77.2(N2) U1A.AH26
SRXA_3P_FMC: C77.1 P1.B36
SRXA_4N: C90.2(N2) U1A.AC25
SRXA_4N_FMC: C90.1 P1.M27
SRXA_4P: C78.2(N2) U1A.AC24
SRXA_4P_FMC: C78.1 P1.M26
SRXA_5N: C91.2(N2) U1A.AJ29
SRXA_5N_FMC: C91.1 P1.A35
SRXA_5P: C79.2(N2) U1A.AJ28
SRXA_5P_FMC: C79.1 P1.A34
SRXA_6N: C92.2(N2) U1A.AD27
SRXA_6N_FMC: C92.1 P1.M31
SRXA_6P: C80.2(N2) U1A.AD26
SRXA_6P_FMC: C80.1 P1.M30
SRXA_7N: C93.2(N2) U1A.AH31
SRXA_7N_FMC: C93.1 P1.B33
SRXA_7P: C81.2(N2) U1A.AH30
SRXA_7P_FMC: C81.1 P1.B32
SRXA_8N: C94.2(N2) U1A.AG29
SRXA_8N_FMC: C94.1 P1.Y31
SRXA_8P: C82.2(N2) U1A.AG28
SRXA_8P_FMC: C82.1 P1.Y30
SRXA_9N: C95.2(N2) U1A.AF31
SRXA_9N_FMC: C95.1 P1.M19
SRXA_9P: C83.2(N2) U1A.AF30
SRXA_9P_FMC: C83.1 P1.M18
SRXA_10N: C96.2(N2) U1A.AE29
SRXA_10N_FMC: C96.1 P1.Z29
SRXA_10P: C84.2(N2) U1A.AE28
SRXA_10P_FMC: C84.1 P1.Z28
SRXA_11N: C97.2(N2) U1A.AD31
SRXA_11N_FMC: C97.1 P1.M23
SRXA_11P: C85.2(N2) U1A.AD30
SRXA_11P_FMC: C85.1 P1.M22
SRXB_0N: C38.2(N2) U1A.C25
SRXB_0N_FMC: C38.1 P1.Y3
SRXB_0P: C25.2(N2) U1A.C24
SRXB_0P_FMC: C25.1 P1.Y2
SRXB_1N: C39.2(N2) U1A.A25
SRXB_1N_FMC: C39.1 P1.C3
SRXB_1P: C26.2(N2) U1A.A24
SRXB_1P_FMC: C26.1 P1.C2
SRXB_2N: C40.2(N2) U1A.D27
SRXB_2N_FMC: C40.1 P1.Z5
SRXB_2P: C27.2(N2) U1A.D26
SRXB_2P_FMC: C27.1 P1.Z4
SRXB_3N: C41.2(N2) U1A.B27
SRXB_3N_FMC: C41.1 P1.A31
SRXB_3P: C29.2(N2) U1A.B26
SRXB_3P_FMC: C29.1 P1.A30
SRXB_4N: C42.2(N2) U1A.G25
SRXB_4N_FMC: C42.1 P1.Z9
SRXB_4P: C30.2(N2) U1A.G24
SRXB_4P_FMC: C30.1 P1.Z8
SRXB_5N: C43.2(N2) U1A.A29
SRXB_5N_FMC: C43.1 P1.B29
SRXB_5P: C31.2(N2) U1A.A28
SRXB_5P_FMC: C31.1 P1.B28
SRXB_6N: C44.2(N2) U1A.F27
SRXB_6N_FMC: C44.1 P1.Y7
SRXB_6P: C32.2(N2) U1A.F26
SRXB_6P_FMC: C32.1 P1.Y6
SRXB_7N: C45.2(N2) U1A.B31
SRXB_7N_FMC: C45.1 P1.A23
SRXB_7P: C33.2(N2) U1A.B30
SRXB_7P_FMC: C33.1 P1.A22
SRXB_8N: C46.2(N2) U1A.C29
SRXB_8N_FMC: C46.1 P1.B25
SRXB_8P: C34.2(N2) U1A.C28
SRXB_8P_FMC: C34.1 P1.B24
SRXB_9N: C47.2(N2) U1A.D31
SRXB_9N_FMC: C47.1 P1.Z25
SRXB_9P: C35.2(N2) U1A.D30
SRXB_9P_FMC: C35.1 P1.Z24
SRXB_10N: C48.2(N2) U1A.E29
SRXB_10N_FMC: C48.1 P1.A27
SRXB_10P: C36.2(N2) U1A.E28
SRXB_10P_FMC: C36.1 P1.A26
SRXB_11N: C49.2(N2) U1A.F31
SRXB_11N_FMC: C49.1 P1.Y27
SRXB_11P: C37.2(N2) U1A.F30
SRXB_11P_FMC: C37.1 P1.Y26
STATUS_LED: DS1.A(P) R4.2(N2)
STXA_0N: C62.2(N2) U1A.AA27
STXA_0N_FMC: C62.1 P1.Y39
STXA_0P: C50.2(N2) U1A.AA26
STXA_0P_FMC: C50.1 P1.Y38
STXA_1N: C63.2(N2) U1A.AA31
STXA_1N_FMC: C63.1 P1.Y19
STXA_1P: C51.2(N2) U1A.AA30
STXA_1P_FMC: C51.1 P1.Y18
STXA_2N: C64.2(N2) U1A.AB29
STXA_2N_FMC: C64.1 P1.Y23
STXA_2P: C52.2(N2) U1A.AB28
STXA_2P_FMC: C52.1 P1.Y22
STXA_3N: C65.2(N2) U1A.Y29
STXA_3N_FMC: C65.1 P1.A19
STXA_3P: C53.2(N2) U1A.Y28
STXA_3P_FMC: C53.1 P1.A18
STXA_4N: C66.2(N2) U1A.W27
STXA_4N_FMC: C66.1 P1.Z37
STXA_4P: C54.2(N2) U1A.W26
STXA_4P_FMC: C54.1 P1.Z36
STXA_5N: C67.2(N2) U1A.W31
STXA_5N_FMC: C67.1 P1.Z17
STXA_5P: C55.2(N2) U1A.W30
STXA_5P_FMC: C55.1 P1.Z16
STXA_6N: C68.2(N2) U1A.V25
STXA_6N_FMC: C68.1 P1.Y35
STXA_6P: C56.2(N2) U1A.V24
STXA_6P_FMC: C56.1 P1.Y34
STXA_7N: C69.2(N2) U1A.U31
STXA_7N_FMC: C69.1 P1.Y15
STXA_7P: C57.2(N2) U1A.U30
STXA_7P_FMC: C57.1 P1.Y14
STXA_8N: C70.2(N2) U1A.V29
STXA_8N_FMC: C70.1 P1.B17
STXA_8P: C58.2(N2) U1A.V28
STXA_8P_FMC: C58.1 P1.B16
STXA_9N: C71.2(N2) U1A.R27
STXA_9N_FMC: C71.1 P1.B13
STXA_9P: C59.2(N2) U1A.R26
STXA_9P_FMC: C59.1 P1.B12
STXA_10N: C72.2(N2) U1A.U27
STXA_10N_FMC: C72.1 P1.Z33
STXA_10P: C60.2(N2) U1A.U26
STXA_10P_FMC: C60.1 P1.Z32
STXA_11N: C73.2(N2) U1A.T29
STXA_11N_FMC: C73.1 P1.A15
STXA_11P: C61.2(N2) U1A.T28
STXA_11P_FMC: C61.1 P1.A14
STXB_0N: C13.2(N2) U1A.J27
STXB_0N_FMC: C13.1 P1.M3
STXB_0P: C1.2(N2) U1A.J26
STXB_0P_FMC: C1.1 P1.M2
STXB_1N: C14.2(N2) U1A.J31
STXB_1N_FMC: C14.1 P1.B5
STXB_1P: C2.2(N2) U1A.J30
STXB_1P_FMC: C2.1 P1.B4
STXB_2N: C15.2(N2) U1A.H29
STXB_2N_FMC: C15.1 P1.A3
STXB_2P: C3.2(N2) U1A.H28
STXB_2P_FMC: C3.1 P1.A2
STXB_3N: C16.2(N2) U1A.K29
STXB_3N_FMC: C16.1 P1.C7
STXB_3P: C4.2(N2) U1A.K28
STXB_3P_FMC: C4.1 P1.C6
STXB_4N: C17.2(N2) U1A.L27
STXB_4N_FMC: C17.1 P1.M7
STXB_4P: C5.2(N2) U1A.L26
STXB_4P_FMC: C5.1 P1.M6
STXB_5N: C18.2(N2) U1A.L31
STXB_5N_FMC: C18.1 P1.A7
STXB_5P: C6.2(N2) U1A.L30
STXB_5P_FMC: C6.1 P1.A6
STXB_6N: C19.2(N2) U1A.M25
STXB_6N_FMC: C19.1 P1.M11
STXB_6P: C7.2(N2) U1A.M24
STXB_6P_FMC: C7.1 P1.M10
STXB_7N: C20.2(N2) U1A.N31
STXB_7N_FMC: C20.1 P1.A11
STXB_7P: C8.2(N2) U1A.N30
STXB_7P_FMC: C8.1 P1.A10
STXB_8N: C21.2(N2) U1A.M29
STXB_8N_FMC: C21.1 P1.B9
STXB_8P: C9.2(N2) U1A.M28
STXB_8P_FMC: C9.1 P1.B8
STXB_9N: C22.2(N2) U1A.R31
STXB_9N_FMC: C22.1 P1.Z13
STXB_9P: C10.2(N2) U1A.R30
STXB_9P_FMC: C10.1 P1.Z12
STXB_10N: C23.2(N2) U1A.N27
STXB_10N_FMC: C23.1 P1.M15
STXB_10P: C11.2(N2) U1A.N26
STXB_10P_FMC: C11.1 P1.M14
STXB_11N: C24.2(N2) U1A.P29
STXB_11N_FMC: C24.1 P1.Y11
STXB_11P: C12.2(N2) U1A.P28
STXB_11P_FMC: C12.1 P1.Y10
SYNC_B: R159.1 U31.F7
SYNC_IN: R5.2(N2) R7.1 R8.1 U1B.6
SYNCINB_A0_N: U1A.Y19 U12.8
SYNCINB_A0_N_FMC: P1.H11 U12.7
SYNCINB_A0_N_GPIO_FMC: P1.J34 U12.9
SYNCINB_A0_P: U1A.AA19 U12.2
SYNCINB_A0_P_FMC: P1.H10 U12.3
SYNCINB_A0_P_GPIO_FMC: P1.J33 U12.1
SYNCINB_A1_N: U1A.Y20 U13.8 U35.35
SYNCINB_A1_N_FMC: P1.E28 U13.7
SYNCINB_A1_N_GPIO_FMC: P1.G22 U13.9
SYNCINB_A1_P: U1A.AA20 U13.2
SYNCINB_A1_P_FMC: P1.E27 U13.3
SYNCINB_A1_P_GPIO_FMC: P1.G21 U13.1
SYNCINB_AB_SEL_0_FMC: P1.K38 R396.1 R398.1 U12.4 U12.5 U14.4 U14.5
SYNCINB_AB_SEL_1_FMC: P1.J36 R397.1 R399.1 U13.4 U13.5 U15.4 U15.5
SYNCINB_B0_N: U1A.K19 U14.8
SYNCINB_B0_N_FMC: P1.G13 U14.7
SYNCINB_B0_N_GPIO_FMC: P1.K35 U14.9
SYNCINB_B0_P: U1A.J19 U14.2
SYNCINB_B0_P_FMC: P1.G12 U14.3
SYNCINB_B0_P_GPIO_FMC: P1.K34 U14.1
SYNCINB_B1_N: U1A.K20 U15.8
SYNCINB_B1_N_FMC: P1.K32 U15.7
SYNCINB_B1_N_GPIO_FMC: P1.G25 U15.9
SYNCINB_B1_P: U1A.J20 U15.2
SYNCINB_B1_P_FMC: P1.K31 U15.3
SYNCINB_B1_P_GPIO_FMC: P1.G24 U15.1
SYNCOUTB_A0_N: U1A.AC21 U16.8
SYNCOUTB_A0_N_FMC: P1.D12 U16.7
SYNCOUTB_A0_N_GPIO_FMC: P1.E31 U16.9
SYNCOUTB_A0_P: U1A.AD21 U16.2
SYNCOUTB_A0_P_FMC: P1.D11 U16.3
SYNCOUTB_A0_P_GPIO_FMC: P1.E30 U16.1
SYNCOUTB_A1_N: P2.14 U1A.AC20 U17.8 U35.37
SYNCOUTB_A1_N_FMC: P1.F29 U17.7
SYNCOUTB_A1_N_GPIO_FMC: P1.H26 U17.9
SYNCOUTB_A1_P: U1A.AD20 U17.2 U35.36
SYNCOUTB_A1_P_FMC: P1.F28 U17.3
SYNCOUTB_A1_P_GPIO_FMC: P1.H25 U17.1
SYNCOUTB_AB_SEL_0_FMC: P1.J37 R400.1 R402.1 U16.4 U16.5 U18.4 U18.5
SYNCOUTB_AB_SEL_1_FMC: P1.E33 R401.1 R403.1 U17.4 U17.5 U19.4 U19.5
SYNCOUTB_B0_N: U1A.G21 U18.8
SYNCOUTB_B0_N_FMC: P1.D15 U18.7
SYNCOUTB_B0_N_GPIO_FMC: P1.F32 U18.9
SYNCOUTB_B0_P: U1A.F21 U18.2
SYNCOUTB_B0_P_FMC: P1.D14 U18.3
SYNCOUTB_B0_P_GPIO_FMC: P1.F31 U18.1
SYNCOUTB_B1_N: U1A.G20 U19.8
SYNCOUTB_B1_N_FMC: P1.J31 U19.7
SYNCOUTB_B1_N_GPIO_FMC: P1.D24 U19.9
SYNCOUTB_B1_P: U1A.F20 U19.2
SYNCOUTB_B1_P_FMC: P1.J30 U19.3
SYNCOUTB_B1_P_GPIO_FMC: P1.D23 U19.1
SYS_12V: C166.2(N2) C167.2(N2) C171.2(N2) C175.2(N2) C199.2(N2) C200.2(N2) C264.2(N2) C512.2(N2) C513.2(N2) C514.2(N2) C515.2(N2) C516.2(N2) C524.2(N2) C525.2(N2) C614.2(N2) C704.P C705.P C845.1 Q16.1 Q16.2 Q16.3(S3) R49.1 R137.1 R158.2(N2) R344.2(N2) R345.2(N2) R346.2(N2) R347.2(N2) R348.2(N2) R349.2(N2) R350.2(N2) R351.2(N2) R352.2(N2) R353.2(N2) R354.2(N2) R355.2(N2) R356.2(N2) R367.1 R371.1 R373.1 R446.1 R448.1 R451.1 R452.1 R453.1 R578.1 R601.1 R605.2(N2) R631.1 R658.1 R659.1 R684.1 R685.1 R794.1 U6.A3 U6.A4 U11.B5 U11.J5 U11.T5 U32.E7 U32.F7 U32.G1 U32.H1 U33.A5 U33.A6 U33.AA5 U33.AA6 U33.AB5 U33.AB6 U33.B5 U33.B6 U33.C5 U33.C6 U33.D5 U33.D6 U33.E5 U33.E6 U33.F5 U33.F6 U33.G5 U33.G6 U33.H5 U33.H6 U33.J5 U33.J6 U33.K5 U33.K6 U33.N5 U33.N6 U33.P5 U33.P6 U33.R5 U33.R6 U33.T5 U33.T6 U33.U5 U33.U6 U33.V5 U33.V6 U33.W5 U33.W6 U33.Y5 U33.Y6 U36.A4 U36.A5 U36.A6 U36.A7 U36.B5 U36.B6 U36.B7 U72.C3 U72.C4 U72.C5 U72.C6 UNK12P0V.1
SYSREF_A_N: R299.2(N2) R589.1 R716.1 U1A.AF6
SYSREF_A_N_FMC: P1.G19 R589.2(N2)
SYSREF_A_P: R299.1 R561.1 R718.1 U1A.AE6
SYSREF_A_P_FMC: P1.G18 R561.2(N2)
SYSREF_B_N: R300.2(N2) R588.1 R719.1 U1A.D6
SYSREF_B_N_FMC: P1.D21 R588.2(N2)
SYSREF_B_P: R300.1 R587.1 R717.1 U1A.E6
SYSREF_B_P_FMC: P1.D20 R587.2(N2)
SYSREF_IN_N_FMC: P1.G37 R742.2(N2) TP47.1(N1)
SYSREF_IN_P_FMC: P1.G36 R741.2(N2) TP46.1(N1)
SYSREF_N: R14.2(N2) R15.1 R298.2(N2) R783.1 U1A.R3
SYSREF_N_FMC: P1.G7 R783.2(N2)
SYSREF_OUT_N_FMC: P1.K5 R17.2(N2) TP45.1(N1)
SYSREF_OUT_P_FMC: P1.K4 R16.2(N2) TP44.1(N1)
SYSREF_P: R12.2(N2) R298.1 R526.1 R782.1 U1A.R4
SYSREF_P_FMC: P1.G6 R782.2(N2)
TRIG_A0: R525.2(N2) R527.1 R593.1 U1A.AF7
TRIG_A0_FMC: P1.C14 U41.12
TRIG_A1: R591.1 U1A.AF8
TRIG_A1_FMC: P1.C15 U41.11
TRIG_B0: R594.1 U1A.D7
TRIG_B0_FMC: P1.D17 U41.10
TRIG_B1: R592.1 U1A.D8
TRIG_B1_FMC: P1.D18 U41.9
TRIG_IN_FMC: P1.D9 R590.1
UART_RST: R469.2(N2) S1.1A S1.1B U22.9
UNNAMED_7_CAP_I46_N1: C5WB.1 T1WB.1(IN)
UNNAMED_7_CAP_I46_N2: C5WB.2(N2) DACB0.1(N1)
UNNAMED_7_CAP_I61_N1: C5XB.1 T1XB.1(IN)
UNNAMED_7_CAP_I61_N2: C5XB.2(N2) DACB1.1(N1)
UNNAMED_7_CAP_I73_N1: C5WA.1 T1WA.1(IN)
UNNAMED_7_CAP_I73_N2: C5WA.2(N2) DACA0.1(N1)
UNNAMED_7_CAP_I85_N1: C5XA.1 T1XA.1(IN)
UNNAMED_7_CAP_I85_N2: C5XA.2(N2) DACA1.1(N1)
UNNAMED_7_CAP_I103_N1: C5YA.1 T1YA.1(IN)
UNNAMED_7_CAP_I103_N2: C5YA.2(N2) DACA2.1(N1)
UNNAMED_7_CAP_I117_N1: C5ZA.1 T1ZA.1(IN)
UNNAMED_7_CAP_I117_N2: C5ZA.2(N2) DACA3.1(N1)
UNNAMED_7_CAP_I131_N1: C5YB.1 T1YB.1(IN)
UNNAMED_7_CAP_I131_N2: C5YB.2(N2) DACB2.1(N1)
UNNAMED_7_CAP_I145_N1: C5ZB.1 T1ZB.1(IN)
UNNAMED_7_CAP_I145_N2: C5ZB.2(N2) DACB3.1(N1)
UNNAMED_9_CAP_I66_N1: C319.1 C333.1 L15.2(N2)
UNNAMED_9_CAP_I66_N2: C319.2(N2) C331.1 L16.2(N2)
UNNAMED_9_CAP_I76_N2: C324.2(N2) T3.3
UNNAMED_9_CAP_I78_N2: C330.2(N2) T3.2
UNNAMED_9_CAP_I79_N2: C329.2(N2) T2.3
UNNAMED_9_CAP_I80_N2: C328.2(N2) T2.2
UNNAMED_9_CAP_I81_N2: C327.2(N2) T1.3
UNNAMED_9_CAP_I82_N2: C326.2(N2) T1.2
UNNAMED_9_CAP_I85_N2: C332.2(N2) T4.4
UNNAMED_9_CAP_I87_N2: C334.2(N2) T4.6(SEC_DOT)
UNNAMED_9_CNBNC2P_I100_CNTR: CLK_A.1 T2.1(IN)
UNNAMED_9_CNBNC2P_I101_CNTR: CLK_B.1 T1.1(IN)
UNNAMED_9_CNBNC2P_I102_CNTR: CLK.1 T3.1(IN)
UNNAMED_10_ADLTC6955_I209_FLT: R311.2(N2) R312.2(N2) U2.40
UNNAMED_10_ADLTC6955_I209_IN: C106.2(N2) U2.37
UNNAMED_10_ADLTC6955_I209_IN_1: C315.2(N2) U2.38
UNNAMED_10_ADLTC6955_I209_SEL0: R307.2(N2) U2.50
UNNAMED_10_ADLTC6955_I209_SEL1: R309.2(N2) U2.51
UNNAMED_10_ADLTC6955_I209_SEL2: R310.2(N2) U2.52
UNNAMED_10_ADLTC6955_I209_SEL3: R308.2(N2) U2.1
UNNAMED_10_ADLTC6955_I209_TEMP: TP1.1(N1) U2.49
UNNAMED_10_CAP_I161_N2: C316.2(N2) R305.2(N2) R306.1
UNNAMED_10_CAP_I193_N2: C315.1 C322.2(N2) C766.2(N2) R306.2(N2) R639.2(N2)
UNNAMED_10_CAP_I207_N1: C106.1 C765.2(N2) R305.1 R638.2(N2)
UNNAMED_10_CAP_I211_N2: C749.2(N2) U49.1 Y3.1
UNNAMED_10_CNBNC5P_I196_CNTR: J17.1 R638.1
UNNAMED_10_CNBNC5P_I201_CNTR: J18.1 R639.1
UNNAMED_10_RES_I166_N1: C749.1 R52.2(N2) R53.1
UNNAMED_10_RES_I169_N1: R51.2(N2) R52.1 R473.1 U49.6(VDD) Y3.4(VDD)
UNNAMED_10_RES_I171_N1: R28.1 R56.1 U49.4 Y3.3
UNNAMED_10_RES_I173_N1: R29.1 R57.1 U49.5
UNNAMED_10_RES_I184_N2: R473.2(N2) R474.1 U49.2
UNNAMED_11_ADHMC7044_I155_BGABYP1: C98.1 U1B.7
UNNAMED_11_ADHMC7044_I155_CLKIN0: C216.2(N2) R6.1 U1B.39
UNNAMED_11_ADHMC7044_I155_CLKIN0N: C217.2(N2) R6.2(N2) U1B.40
UNNAMED_11_ADHMC7044_I155_CLKIN1: C155.2(N2) R132.1 U1B.36
UNNAMED_11_ADHMC7044_I155_CLKIN1N: C156.2(N2) R132.2(N2) U1B.37
UNNAMED_11_ADHMC7044_I155_CLKOUT0: C230.1 U1B.1
UNNAMED_11_ADHMC7044_I155_CLKOUT0N: C231.1 U1B.2
UNNAMED_11_ADHMC7044_I155_CLKOUT4N: C748.1 U1B.25
UNNAMED_11_ADHMC7044_I155_CLKOUT6: C232.1 U1B.27
UNNAMED_11_ADHMC7044_I155_CLKOUT6N: C233.1 U1B.28
UNNAMED_11_ADHMC7044_I155_CPOUT2: C126.1 C127.1 U1B.50
UNNAMED_11_ADHMC7044_I155_GPIO2: R4.1 U1B.52
UNNAMED_11_ADHMC7044_I155_LDOBYP2: C99.1 U1B.8
UNNAMED_11_ADHMC7044_I155_LDOBYP3: C101.1 U1B.9
UNNAMED_11_ADHMC7044_I155_LDOBYP4: C103.1 C212.2(N2) U1B.11
UNNAMED_11_ADHMC7044_I155_LDOBYP5: C212.1 U1B.12
UNNAMED_11_ADHMC7044_I155_LDOBYP6: C107.1 U1B.46
UNNAMED_11_ADHMC7044_I155_LDOBYP7: C110.1 U1B.49
UNNAMED_11_ADHMC7044_I155_OSCIN: C214.2(N2) U1B.47
UNNAMED_11_ADHMC7044_I155_OSCINN: C215.2(N2) U1B.48
UNNAMED_11_ADHMC7044_I155_RESET: R9.1 U1B.5
UNNAMED_11_ADHMC7044_I155_SCLK: R413.2(N2) U1B.19
UNNAMED_11_ADHMC7044_I155_SDATA: R410.2(N2) U1B.20
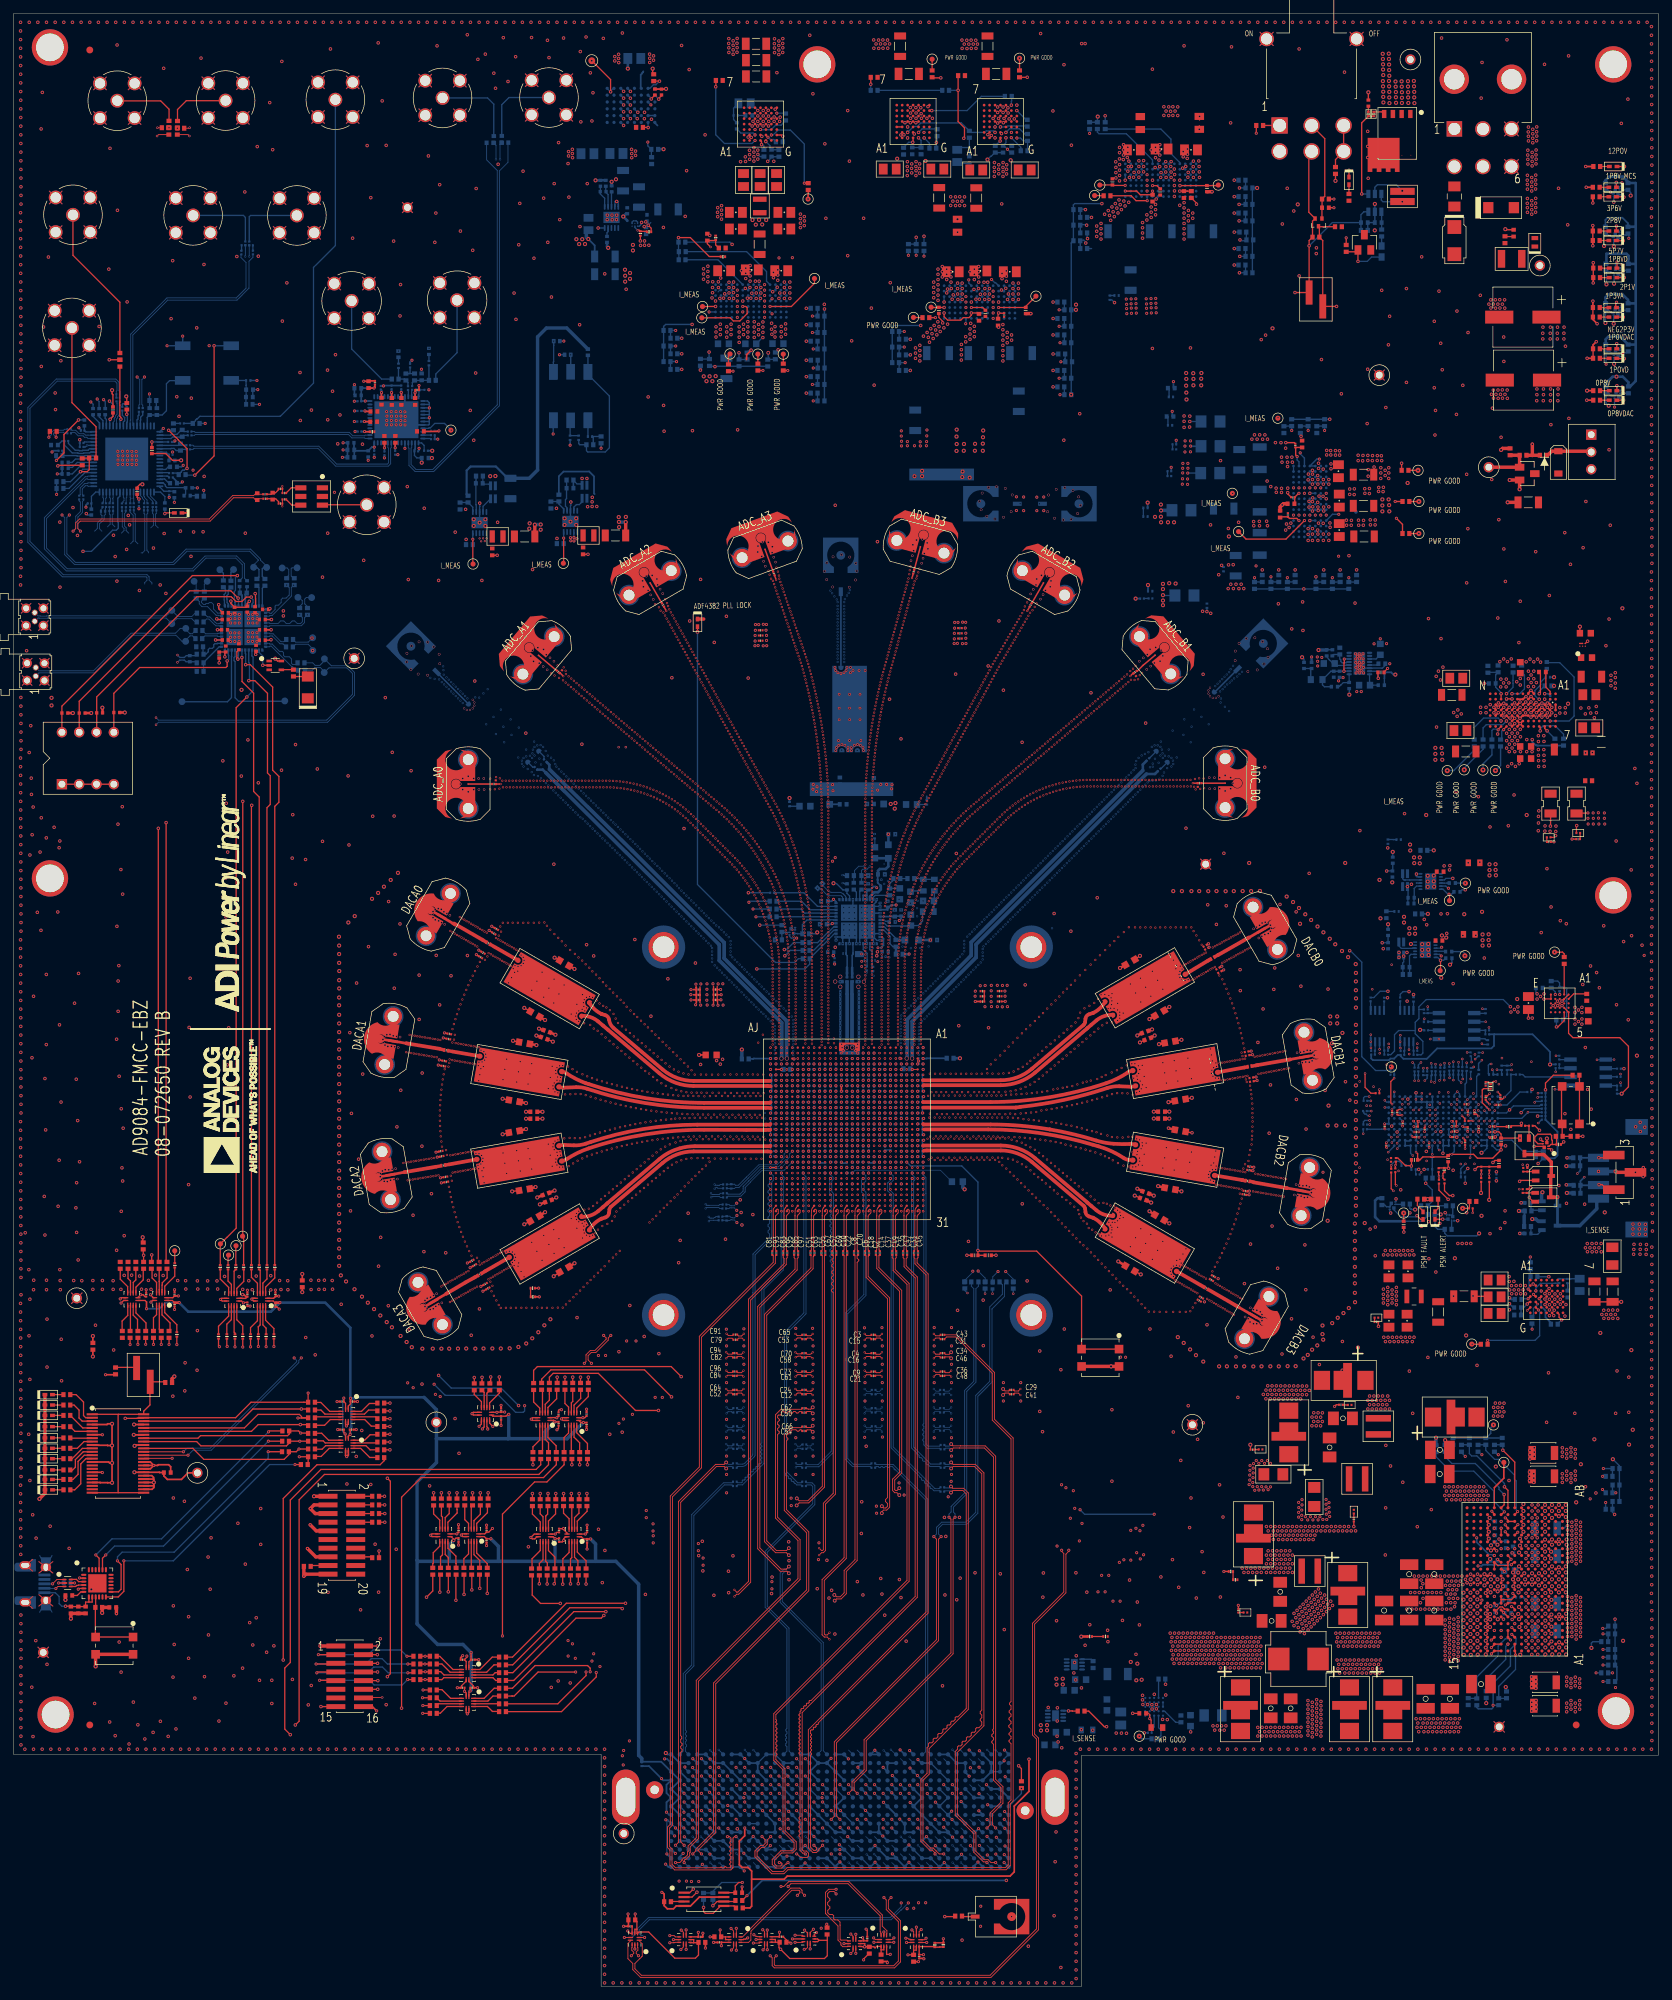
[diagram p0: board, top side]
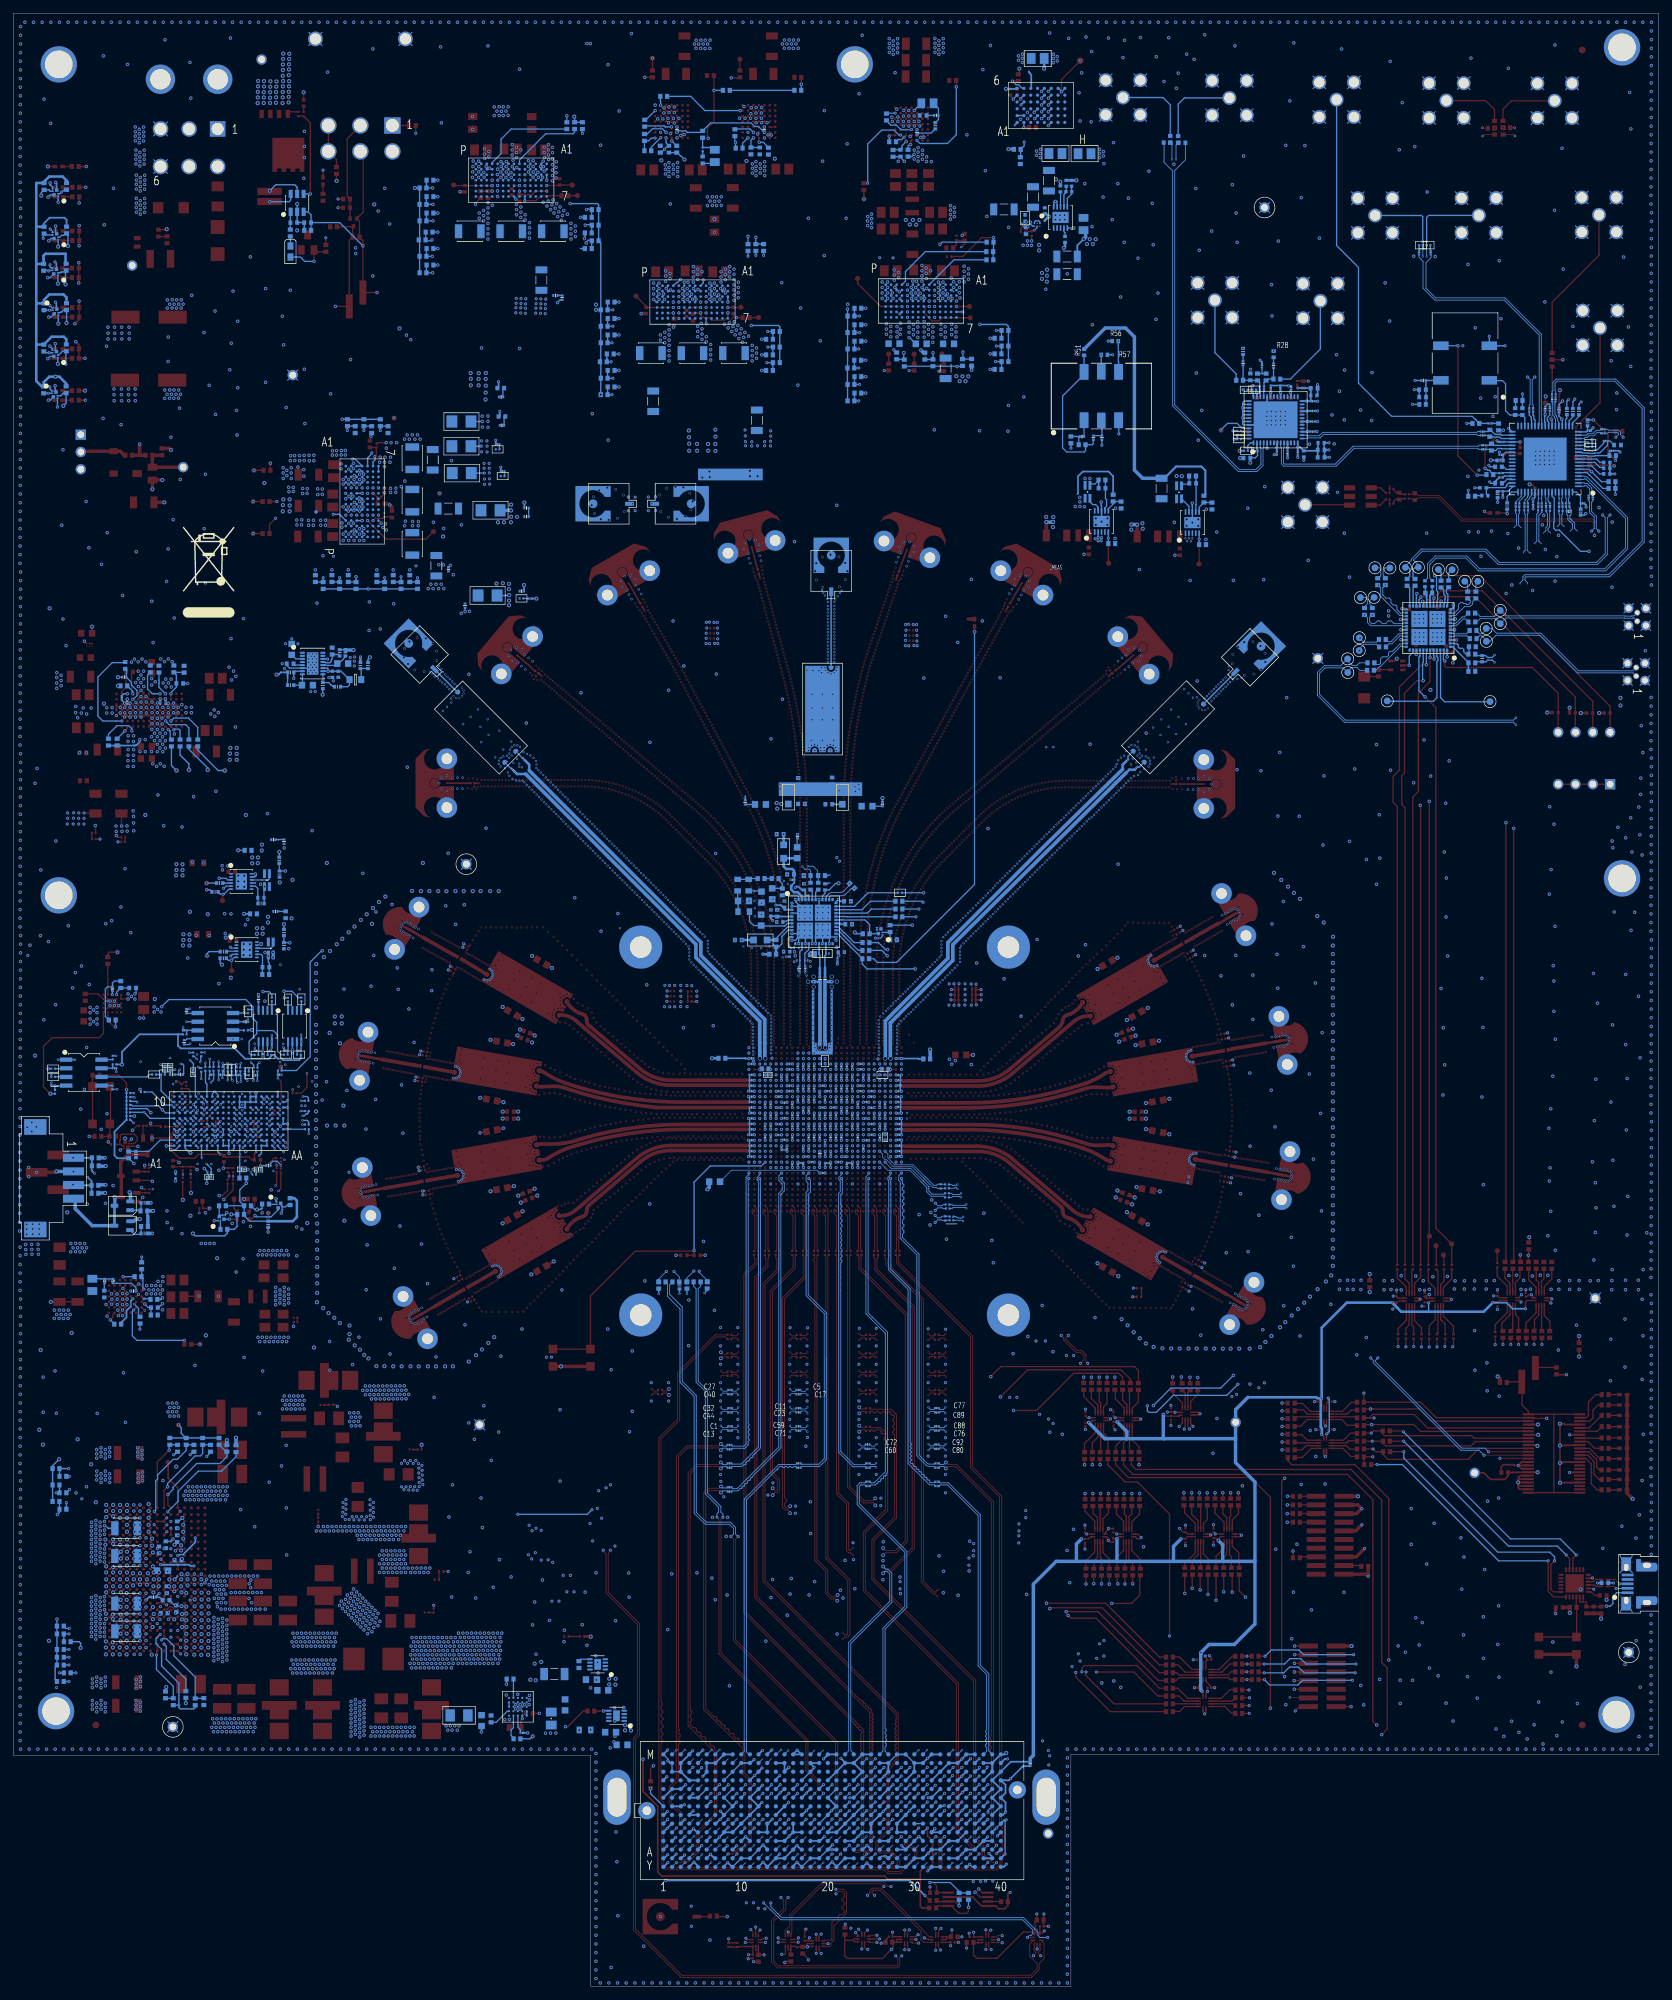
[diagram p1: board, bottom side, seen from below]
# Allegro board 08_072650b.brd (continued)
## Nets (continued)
UNNAMED_11_ADHMC7044_I155_SLEN: R514.2(N2) U1B.18
UNNAMED_11_ADHMC7044_I155_VCC1VCO: C218.2(N2) E7.2(N2) U1B.10
UNNAMED_11_ADHMC7044_I155_VCC2OUT: C219.2(N2) E1.2(N2) U1B.17
UNNAMED_11_ADHMC7044_I155_VCC3SYSREF: C220.2(N2) E8.1 U1B.21
UNNAMED_11_ADHMC7044_I155_VCC4OUT: C221.2(N2) E10.1 U1B.26
UNNAMED_11_ADHMC7044_I155_VCC5PLL1: C223.2(N2) E14.1 U1B.38
UNNAMED_11_ADHMC7044_I155_VCC6OSCOUT: C226.2(N2) E9.1 U1B.41
UNNAMED_11_ADHMC7044_I155_VCC7PLL2: C229.1 E13.1 U1B.51
UNNAMED_11_ADHMC7044_I155_VCC8OUT: C228.1 E11.1 U1B.57
UNNAMED_11_ADHMC7044_I155_VCC9OUT: C227.1 E12.1 U1B.68(VCC9_OUT)
UNNAMED_11_CAP_I254_N2: C127.2(N2) R10.1
UNNAMED_11_CAP_I257_N2: C129.2(N2) R11.1
UNNAMED_11_CAP_I291_N1: C100.1 C104.1 C208.1 E2B.2(N2) Y1.4(VDD)
UNNAMED_11_CAP_I307_N2: C213.2(N2) R3.1
UNNAMED_11_CAP_I323_N1: C214.1 R1.2(N2) R3.2(N2)
UNNAMED_11_CNBNC2P_I350_CNTR: J3.1 R590.2(N2)
UNNAMED_11_CNBNC5P_I351_CNTR: EXT_SYS_P.1 R526.2(N2)
UNNAMED_11_CNBNC5P_I353_CNTR: EXT_SYS_N.1 R15.2(N2)
UNNAMED_11_CNBNC5P_I356_CNTR: EXT_TRIG.1 R527.2(N2)
UNNAMED_11_RES_I294_N1: R1.1 Y1.3
UNNAMED_14_ADLTC4210_I253_GATE: R488.1 R489.2(N2) U39.4
UNNAMED_14_ADLTC4210_I253_ON: C640.2(N2) PWRDBG.2(N2) Q7.2(S) R55.2(N2) R485.2(N2) S4.5 U39.3
UNNAMED_14_ADLTC4210_I253_TIMER: C607.2(N2) R486.1 U39.1
UNNAMED_14_ADLTC4210_I253_VCC: D2.C D4.C D6.3 F1.2(N2) R65.2(N2) R71.1 R484.2(N2) U39.6(VCC)
UNNAMED_14_CAP_I258_N2: C608.2(N2) R489.1
UNNAMED_14_CAP_I283_N2: C136.2(N2) R483.1
UNNAMED_14_CN3P_I249_N2: D1.C P23.2 R643.2(N2)
UNNAMED_14_CN3P_I249_N3: D1.A(P) P23.3(N3) Q17.3 R334.1
UNNAMED_14_CN6P_I246_N1: F1.1 P22.1 P22.4
UNNAMED_14_DIO_I266_N: D5.C R486.2(N2)
UNNAMED_14_DIO_I266_P: D5.A(P) D6.1(P) R487.2(N2)
UNNAMED_14_DIOLED_I232_P: DS3.A(P) R344.1
UNNAMED_14_DIOLED_I233_P: DS4.A(P) R345.1
UNNAMED_14_DIOLED_I234_P: DS5.A(P) R346.1
UNNAMED_14_DIOLED_I235_P: DS6.A(P) R347.1
UNNAMED_14_DIOLED_I236_P: DS7.A(P) R348.1
UNNAMED_14_DIOLED_I237_P: DS8.A(P) R349.1
UNNAMED_14_DIOLED_I238_P: DS9.A(P) R350.1
UNNAMED_14_DIOLED_I239_P: DS10.A(P) R351.1
UNNAMED_14_DIOLED_I240_P: DS11.A(P) R352.1
UNNAMED_14_DIOLED_I241_P: DS12.A(P) R353.1
UNNAMED_14_DIOLED_I242_P: DS13.A(P) R354.1
UNNAMED_14_DIOLED_I243_P: DS14.A(P) R355.1
UNNAMED_14_DIOLED_I244_P: DS15.A(P) R356.1
UNNAMED_14_DIOLED_I280_P: DS16.A(P) R65.1
UNNAMED_14_DIOSCHOTTKY_I285_P: D4.A(P) L17.1 R483.2(N2)
UNNAMED_14_DIOSCHOTTKY_I318_N: D3.C FMC12I.1(N1) L17.2(N2)
UNNAMED_14_RES_I259_N2: Q16.4 R488.2(N2)
UNNAMED_14_RES_I262_N1: PWRDBG.1 Q7.3 R55.1 R484.1
UNNAMED_14_RES_I274_N1: R64.1 S4.3 S4.6(NO2)
UNNAMED_14_RES_I288_N2: R482.2(N2) S4.1
UNNAMED_14_RES_I322_N2: C639.2(N2) Q7.1 R529.2(N2) S4.2
UNNAMED_15_ADLTM4681_I3_ALERT01N: R528.1 U33.C11 U33.W8
UNNAMED_15_ADLTM4681_I3_ASEL01: R449.2(N2) U33.B9
UNNAMED_15_ADLTM4681_I3_ASEL23: R450.2(N2) U33.AA10
UNNAMED_15_ADLTM4681_I3_COMP0A: C518.2(N2) U33.G9 U33.G11
UNNAMED_15_ADLTM4681_I3_COMP0B: C519.2(N2) U33.F9 U33.G10
UNNAMED_15_ADLTM4681_I3_COMP2A: C520.2(N2) U33.T8
UNNAMED_15_ADLTM4681_I3_COMP2B: C521.2(N2) U33.T9
UNNAMED_15_ADLTM4681_I3_COMP3A: C572.2(N2) U33.V11
UNNAMED_15_ADLTM4681_I3_COMP3B: C573.2(N2) U33.W11
UNNAMED_15_ADLTM4681_I3_FAULT0N: R62.2(N2) R428.1 U33.A10 U33.A11 U33.V10 U33.W10
UNNAMED_15_ADLTM4681_I3_INTVCC01: C574.1 U33.J9
UNNAMED_15_ADLTM4681_I3_INTVCC23: C575.1 U33.P10
UNNAMED_15_ADLTM4681_I3_PGOOD0: R427.1 R530.2(N2) U33.H8 U33.H9
UNNAMED_15_ADLTM4681_I3_PGOOD2: R426.1 R531.2(N2) U33.R10
UNNAMED_15_ADLTM4681_I3_PGOOD3: R425.1 R532.2(N2) U33.T10
UNNAMED_15_ADLTM4681_I3_RUNP: C517.1 R578.2(N2) U33.H10 U33.J8 U33.J10 U33.N9 U33.N11 U33.P9 U33.P11 U33.R9
UNNAMED_15_ADLTM4681_I3_SCL01: R149.1 R430.1 U33.D10 U33.W9
UNNAMED_15_ADLTM4681_I3_SDA01: R374.1 R431.1 U33.C10 U33.V8
UNNAMED_15_ADLTM4681_I3_SYNC01: R432.1 U33.D11 U33.V9
UNNAMED_15_ADLTM4681_I3_VBIAS: C576.1 U33.N10
UNNAMED_15_ADLTM4681_I3_VOUT0CFG: R438.2(N2) R444.2(N2) U33.A8 U33.B8
UNNAMED_15_ADLTM4681_I3_VOUT2CFG: R439.2(N2) R445.2(N2) U33.AA8
UNNAMED_15_ADLTM4681_I3_VOUT3CFG: R440.2(N2) R447.2(N2) U33.AB8
UNNAMED_15_ADLTM4681_I3_VTRIM0CFG: R435.2(N2) R441.1 U33.C9 U33.D9
UNNAMED_15_ADLTM4681_I3_VTRIM2CFG: R436.2(N2) R442.1 U33.AB10
UNNAMED_15_ADLTM4681_I3_VTRIM3CFG: R437.2(N2) R443.1 U33.AB9
UNNAMED_15_RES_I202_N2: Q14.1 R446.2(N2) R490.1
UNNAMED_15_RES_I206_N2: Q15.1 R448.2(N2) R491.1
UNNAMED_32_CAP_I380_N2: C660.2(N2) C661.2(N2) C662.2(N2)
UNNAMED_33_CAP_I144_N1: C237.1 R556.1
UNNAMED_34_AD90888T8RSEB0_I517_VPLL1P0VREG: C432.1 C435.1 U1A.R11
UNNAMED_34_AD90888T8RSEB0_I517_VSPLL1P0VREG: C428.1 C429.1 U1A.P24
UNNAMED_34_CAP_I450_N1: C619.1 R559.2(N2)
UNNAMED_34_CAP_I453_N1: C620.1 R560.2(N2)
UNNAMED_34_CAP_I473_N1: C626.1 R566.2(N2)
UNNAMED_34_CAP_I476_N1: C627.1 R567.2(N2)
UNNAMED_34_CAP_I479_N1: C624.1 R564.1
UNNAMED_34_CAP_I483_N1: C625.1 R565.1
UNNAMED_34_CAP_I486_N1: C628.1 R568.1
UNNAMED_34_CAP_I490_N1: C623.1 R563.1
UNNAMED_34_CAP_I504_N1: C436.1 R557.2(N2)
UNNAMED_34_CAP_I505_N1: C439.1 R558.2(N2)
UNNAMED_35_CAP_I439_N1: C635.1 R575.2(N2)
UNNAMED_35_CAP_I451_N1: C636.1 R576.2(N2)
UNNAMED_35_CAP_I457_N1: C630.1 R570.1
UNNAMED_35_CAP_I466_N1: C631.1 R571.1
UNNAMED_35_CAP_I468_N1: C633.1 R573.2(N2)
UNNAMED_35_CAP_I470_N1: C634.1 R574.2(N2)
UNNAMED_35_CAP_I484_N1: C356.1 R569.1
UNNAMED_35_CAP_I524_N1: C632.1 R572.2(N2)
UNNAMED_36_ADF4382_I312_CP: R291.2(N2) U30.47
UNNAMED_36_ADF4382_I312_CSB: R584.1 U30.32
UNNAMED_36_ADF4382_I312_REFN: C115.2(N2) U30.43
UNNAMED_36_ADF4382_I312_REFP: C116.2(N2) U30.42
UNNAMED_36_ADF4382_I312_RFOUT2N: C317.2(N2) L1.2(N2) U30.15
UNNAMED_36_ADF4382_I312_RFOUT2P: C28.2(N2) L10.1 U30.17
UNNAMED_36_ADF4382_I312_SCLK: R582.1 U30.34
UNNAMED_36_ADF4382_I312_SDIO: R583.1 U30.33
UNNAMED_36_ADF4382_I312_SDO: R581.1 U30.35
UNNAMED_36_ADF4382_I312_SYNCN: R293.1 R297.1 R713.2(N2) U30.39
UNNAMED_36_ADF4382_I312_SYNCP: R294.1 R297.2(N2) R714.2(N2) U30.38
UNNAMED_36_ADF4382_I312_V5CAL: E2.2(N2) R288.1 U30.8
UNNAMED_36_ADF4382_I312_V5CP: C113.2(N2) C253.2(N2) C751.1 E3.2(N2) U30.46
UNNAMED_36_ADF4382_I312_V5VCO: R288.2(N2) R290.1 U30.9
UNNAMED_36_ADF4382_I312_VGBIAS: C109.1 U30.6
UNNAMED_36_ADF4382_I312_VTUNE: C242.1 R286.2(N2) U30.7(VTUNE)
UNNAMED_36_CAP_I371_N1: C115.1 C311.2(N2) C312.2(N2) R292.1
UNNAMED_36_CAP_I372_N1: C116.1 C313.2(N2) C314.2(N2) R296.2(N2)
UNNAMED_36_CAP_I396_N1: C317.1 RFOUT_2N.1
UNNAMED_36_CAP_I397_N1: C28.1 RFOUT_2P.1
UNNAMED_36_CAP_I403_N1: C312.1 REFN.1
UNNAMED_36_CAP_I404_N1: C313.1 REFP.1
UNNAMED_36_CAP_I433_N1: C241.1 R286.1 R287.1
UNNAMED_36_CAP_I434_N1: C252.1 R291.1 R315.2(N2)
UNNAMED_36_CAP_I436_N1: C243.1 R289.2(N2)
UNNAMED_36_CAP_I441_N2: C752.2(N2) R731.1
UNNAMED_36_CAP_I444_N2: C751.2(N2) R730.1
UNNAMED_36_CAP_I446_N2: C750.2(N2) R729.1
UNNAMED_36_CNBNC5P_I422_CNTR: J12.1 R293.2(N2)
UNNAMED_36_CNBNC5P_I424_CNTR: J13.1 R294.2(N2)
UNNAMED_36_DIOLED_I317_P: DS2.A(P) R295.2(N2)
UNNAMED_36_RES_I357_N1: R13.1 R287.2(N2) R289.1
UNNAMED_36_RES_I357_N2: R13.2(N2) R315.1
UNNAMED_36_RES_I398_N2: Q8.2 R318.2(N2) R595.1
UNNAMED_36_TRANNMOSFETV11_I414_G2: Q8.4(S2) Q8.5
UNNAMED_38_ADLTM4702_I15_COMPA: R73.1 R470.1 U1.C2
UNNAMED_38_ADLTM4702_I15_COMPB: R470.2(N2) U1.C3
UNNAMED_38_ADLTM4702_I15_PG: R522.1 U1.F2
UNNAMED_38_ADLTM4702_I15_PGSET: R521.1 U1.E2
UNNAMED_38_ADLTM4702_I15_RT: R518.2(N2) U1.D1
UNNAMED_38_ADLTM4702_I15_RUN: R517.2(N2) R519.1 U1.C1
UNNAMED_38_ADLTM4702_I15_SET: C191.2(N2) R515.1 U1.E1
UNNAMED_38_ADLTM4702_I15_SVIN: C192.2(N2) C617.2(N2) R451.2(N2) R519.2(N2) U1.A4 U1.A5 U1.A6 U1.A7 U1.B5 U1.B6 U1.B7
UNNAMED_38_ADLTM4702_I15_SYNC: R520.2(N2) U1.G6
UNNAMED_38_ADP124_I99_EN: R534.2(N2) U3.5
UNNAMED_38_ADP124_I100_EN: R25.1 U54.5
UNNAMED_38_CAP_I48_N2: C235.2(N2) R452.2(N2) R535.2(N2) U40.A3 U40.A4
UNNAMED_38_CAP_I49_N2: C234.2(N2) U40.C1
UNNAMED_38_CAP_I52_N2: C236.2(N2) C621.2(N2) L11.1 U40.E1 U40.E2(VOUT_2)
UNNAMED_38_CAP_I85_N2: C641.2(N2) R66.2(N2) R73.2(N2)
UNNAMED_38_CAP_I86_N2: C553.2(N2) R66.1
UNNAMED_38_CAP_I92_N1: C621.1 R538.1 U40.D1
UNNAMED_38_LINLTM8074_I46_PG: R537.1 U40.B1
UNNAMED_38_LINLTM8074_I46_RT: R536.2(N2) U40.B5
UNNAMED_38_LINLTM8074_I46_RUN: R535.1 U40.A2
UNNAMED_39_ADLTM4702_I7_COMPB: R69.2(N2) U31.C3
UNNAMED_39_ADLTM4702_I7_PG: R340.1 U31.F2
UNNAMED_39_ADLTM4702_I7_PGSET: R169.1 U31.E2
UNNAMED_39_ADLTM4702_I7_RT: R140.2(N2) U31.D1
UNNAMED_39_ADLTM4702_I7_RUN: R22.1 R146.2(N2) U31.C1
UNNAMED_39_ADLTM4702_I7_SVIN: C159.2(N2) R22.2(N2) R137.2(N2) U31.A4 U31.A5 U31.A6 U31.A7 U31.B5 U31.B6 U31.B7
UNNAMED_39_ADLTM4702_I7_SYNC: R147.2(N2) U31.G6
UNNAMED_39_ADLTM4702_I7_VOSNS: R727.1 U31.F1
UNNAMED_39_ADLTM4702_I7_VOUT1: C161.2(N2) C164.2(N2) R169.2(N2) R365.1 R727.2(N2) U31.A1 U31.A2 U31.A3 U31.B3 U31.F3 U31.G1 U31.G2 U31.G3(VOUT_8)
UNNAMED_39_ADLTM4702_I63_COMPA: R69.1 R70.1 R74.2(N2) U5.C2 U31.C2
UNNAMED_39_ADLTM4702_I63_COMPB: R70.2(N2) U5.C3
UNNAMED_39_ADLTM4702_I63_PG: R341.1 U5.F2
UNNAMED_39_ADLTM4702_I63_PGSET: R335.1 U5.E2
UNNAMED_39_ADLTM4702_I63_RT: R145.1 U5.D1
UNNAMED_39_ADLTM4702_I63_RUN: R148.2(N2) R512.1 U5.C1
UNNAMED_39_ADLTM4702_I63_SET: C157.2(N2) C158.2(N2) R133.1 R144.1 U5.E1 U31.E1
UNNAMED_39_ADLTM4702_I63_SVIN: C160.2(N2) R49.2(N2) R512.2(N2) U5.A4 U5.A5 U5.A6 U5.A7 U5.B5 U5.B6 U5.B7
UNNAMED_39_ADLTM4702_I63_SYNC: R159.2(N2) U5.G6
UNNAMED_39_ADLTM4702_I63_VOSNS: R728.1 U5.F1
UNNAMED_39_ADLTM4702_I63_VOUT1: C162.2(N2) C165.2(N2) R335.2(N2) R366.1 R728.2(N2) U5.A1 U5.A2 U5.A3 U5.B3 U5.F3 U5.G1 U5.G2 U5.G3(VOUT_8)
UNNAMED_39_CAP_I75_N2: C642.2(N2) R67.1
UNNAMED_39_CAP_I78_N2: C643.2(N2) R67.2(N2) R74.1
UNNAMED_39_NCTESTPAD_I70_N1: R341.2(N2) TP3.1(N1)
UNNAMED_39_RES_I53_N1: R146.1 R148.1
UNNAMED_40_ADLTM8051_I7_FB1: C760.2(N2) R380.1 R382.1 U32.L1 U32.L2
UNNAMED_40_ADLTM8051_I7_FB2: C761.2(N2) R381.1 U32.D2
UNNAMED_40_ADLTM8051_I7_FB3: C762.1 R778.1 U32.D1
UNNAMED_40_ADLTM8051_I7_PG1: R386.1 U32.L6
UNNAMED_40_ADLTM8051_I7_PG2: R387.1 U32.K6
UNNAMED_40_ADLTM8051_I7_PG3: R388.1 U32.K7
UNNAMED_40_ADLTM8051_I7_PG4: R408.1 U32.L7
UNNAMED_40_ADLTM8051_I7_RT14: R368.2(N2) U32.K1
UNNAMED_40_ADLTM8051_I7_RT23: R372.2(N2) U32.J1
UNNAMED_40_ADLTM8051_I7_RUN14: R367.2(N2) U32.D7
UNNAMED_40_ADLTM8051_I7_RUN23: R371.2(N2) U32.C7
UNNAMED_40_ADLTM8051_I7_TRSS1: C168.2(N2) C174.2(N2) U32.J2 U32.K2
UNNAMED_40_ADLTM8051_I7_TRSS3: C173.2(N2) U32.C1
UNNAMED_40_ADLTM8051_I7_VOUT11: C190.2(N2) C760.1 R411.1 U32.M1 U32.M2 U32.N1 U32.N2
UNNAMED_40_ADLTM8051_I7_VOUT21: C178.2(N2) C761.1 R412.1 U32.A6 U32.A7 U32.B6 U32.B7
UNNAMED_40_ADLTM8051_I7_VOUT31: C179.2(N2) C648.2(N2) C762.2(N2) R409.1 U32.A1 U32.A2 U32.B1 U32.B2 U53.A1 U53.C1
UNNAMED_40_ADLTM8051_I7_VOUT41: C180.2(N2) R779.1 U32.M6 U32.M7 U32.N6 U32.N7(VOUT4_4)
UNNAMED_40_CAP_I214_N2: C176.2(N2) U6.C1
UNNAMED_40_CAP_I312_N2: C622.2(N2) R500.1 U6.D1
UNNAMED_40_LINLTM8074_I217_PG: R540.1 U6.B1
UNNAMED_40_LINLTM8074_I217_RT: R497.1 U6.B5
UNNAMED_40_LINLTM8074_I217_RUN: R373.2(N2) U6.A2
UNNAMED_41_ADLTM4709_I2_EN1: R58.2(N2) U7.E3
UNNAMED_41_ADLTM4709_I2_EN2: R21.2(N2) U7.F1
UNNAMED_41_ADLTM4709_I2_EN3: R20.2(N2) U7.L1
UNNAMED_41_ADLTM4709_I2_IMON1: R642.2(N2) TP15.1(N1) U7.A5
UNNAMED_41_ADLTM4709_I2_IMON2: R640.2(N2) U7.F5
UNNAMED_41_ADLTM4709_I2_IMON3: R641.2(N2) TP65.1(N1) U7.L5
UNNAMED_41_ADLTM4709_I2_PG1: R547.1 U7.E7
UNNAMED_41_ADLTM4709_I2_VO10: R95.1 R96.2(N2) U7.E4
UNNAMED_41_ADLTM4709_I2_VO11: R89.1 R90.2(N2) U7.E5
UNNAMED_41_ADLTM4709_I2_VO12: R83.1 R84.2(N2) U7.E6
UNNAMED_41_ADLTM4709_I2_VO20: R97.1 R98.2(N2) U7.K5
UNNAMED_41_ADLTM4709_I2_VO21: R91.1 R92.2(N2) U7.K6
UNNAMED_41_ADLTM4709_I2_VO22: R85.1 R86.2(N2) U7.K7
UNNAMED_41_ADLTM4709_I2_VO30: R99.1 R100.2(N2) U7.K2
UNNAMED_41_ADLTM4709_I2_VO31: R93.1 R94.2(N2) U7.K3
UNNAMED_41_ADLTM4709_I2_VO32: R87.1 R88.2(N2) U7.K4
UNNAMED_41_ADLTM4709_I2_VOUT11: C249.2(N2) C262.2(N2) R756.1 U7.B5 U7.B6 U7.C5 U7.C6 U7.C7 U7.D5 U7.D6 U7.D7 U7.G5 U7.G6 U7.H5 U7.H6 U7.H7 U7.J5 U7.J6 U7.J7
UNNAMED_41_ADLTM4709_I2_VOUT31: C263.2(N2) R562.1 U7.M5 U7.M6 U7.N5 U7.N6 U7.N7 U7.P5 U7.P6 U7.P7
UNNAMED_41_ADLTM4709_I15_PG1: R543.1 U8.E7
UNNAMED_41_ADLTM4709_I15_PG2: R544.1 U8.E2
UNNAMED_41_ADLTM4709_I15_PG3: R545.1 U8.K1
UNNAMED_41_ADLTM4709_I15_VIN11: C187.2(N2) R101.2(N2) U8.B3 U8.B4 U8.C1 U8.C2 U8.C3 U8.C4 U8.D1 U8.D2 U8.D3 U8.D4
UNNAMED_41_ADLTM4709_I15_VIN21: C188.2(N2) R102.2(N2) U8.G3 U8.G4 U8.H1 U8.H2 U8.H3 U8.H4 U8.J1 U8.J2 U8.J3 U8.J4
UNNAMED_41_ADLTM4709_I15_VIN31: C189.2(N2) R644.2(N2) U8.M3 U8.M4 U8.N1 U8.N2 U8.N3 U8.N4 U8.P1 U8.P2 U8.P3 U8.P4
UNNAMED_41_ADLTM4709_I15_VO10: R116.1 R117.2(N2) U8.E4
UNNAMED_41_ADLTM4709_I15_VO11: R110.1 R111.2(N2) U8.E5
UNNAMED_41_ADLTM4709_I15_VO12: R104.1 R105.2(N2) U8.E6
UNNAMED_41_ADLTM4709_I15_VO20: R118.1 R119.2(N2) U8.K5
UNNAMED_41_ADLTM4709_I15_VO21: R112.1 R113.2(N2) U8.K6
UNNAMED_41_ADLTM4709_I15_VO22: R106.1 R107.2(N2) U8.K7
UNNAMED_41_ADLTM4709_I15_VO30: R120.1 R121.2(N2) U8.K2
UNNAMED_41_ADLTM4709_I15_VO31: R114.1 R115.2(N2) U8.K3
UNNAMED_41_ADLTM4709_I15_VO32: R108.1 R109.2(N2) U8.K4
UNNAMED_41_ADLTM4709_I15_VOUT11: C238.2(N2) R493.1 U8.B5 U8.B6 U8.C5 U8.C6 U8.C7 U8.D5 U8.D6 U8.D7
UNNAMED_41_ADLTM4709_I15_VOUT21: C239.2(N2) R494.1 U8.G5 U8.G6 U8.H5 U8.H6 U8.H7 U8.J5 U8.J6 U8.J7
UNNAMED_41_ADLTM4709_I15_VOUT31: C240.2(N2) R506.1 U8.M5 U8.M6 U8.N5 U8.N6 U8.N7 U8.P5 U8.P6 U8.P7
UNNAMED_41_CAP_I140_N1: C245.1 U37.3
UNNAMED_41_CAP_I142_N1: C246.1 U37.5
UNNAMED_41_CAP_I151_N1: C247.1 R421.1 U37.8
UNNAMED_41_CAP_I153_N1: C248.1 R423.1 U37.12
UNNAMED_41_CAP_I168_N2: C196.2(N2) R127.2(N2) U10.8
UNNAMED_41_CAP_I180_N2: C195.2(N2) R126.2(N2) U9.8
UNNAMED_41_CAP_I205_N1: C140.2(N2) C244.1 L2.2(N2) R420.1 U37.10 U37.11 U37.14
UNNAMED_41_CAPSP_I345_N2: C197.2 U9.10
UNNAMED_41_CAPSP_I347_N2: C198.2 U10.10
UNNAMED_41_IND_I208_N1: L2.1 R416.2(N2) R417.2(N2)
UNNAMED_41_LINLT3094_I169_ILIM: R124.1 TP17.1(N1) U10.6
UNNAMED_41_LINLT3094_I169_PG: R549.1 U10.4
UNNAMED_41_LINLT3094_I169_PGFB: R129.2(N2) R131.1 U10.5
UNNAMED_41_LINLT3094_I176_ILIM: R125.1 TP23.1(N1) U9.6
UNNAMED_41_LINLT3094_I176_PG: R548.1 U9.4
UNNAMED_41_LINLT3094_I176_PGFB: R128.2(N2) R130.1 U9.5
UNNAMED_41_LINLT6658_I148_ODN: R418.2(N2) R420.2(N2) U37.9
UNNAMED_41_LINLT6658_I148_VOUT1S: R424.1 R579.2(N2) U37.13
UNNAMED_41_LINLT6658_I148_VOUT2S: R422.1 R507.2(N2) U37.7(VOUT2_S)
UNNAMED_41_NCTESTPAD_I283_N1: R547.2(N2) TP16.1(N1)
UNNAMED_41_NCTESTPAD_I289_N1: R543.2(N2) TP11.1(N1)
UNNAMED_41_NCTESTPAD_I290_N1: R544.2(N2) TP13.1(N1)
UNNAMED_41_NCTESTPAD_I291_N1: R545.2(N2) TP12.1(N1)
UNNAMED_42_ADLTM4709_I91_EN1: R761.2(N2) U52.E3
UNNAMED_42_ADLTM4709_I91_EN2: R542.2(N2) U52.F1
UNNAMED_42_ADLTM4709_I91_EN3: R763.2(N2) U52.L1
UNNAMED_42_ADLTM4709_I91_IMON2: R757.2(N2) U52.F5
UNNAMED_42_ADLTM4709_I91_PG1: R764.1 U52.E7
UNNAMED_42_ADLTM4709_I91_VO10: R754.1 R755.2(N2) U52.E4
UNNAMED_42_ADLTM4709_I91_VO11: R748.1 R753.2(N2) U52.E5
UNNAMED_42_ADLTM4709_I91_VO12: R746.1 R747.2(N2) U52.E6
UNNAMED_42_ADLTM4709_I91_VO20: R773.1 R774.2(N2) U52.K5
UNNAMED_42_ADLTM4709_I91_VO21: R769.1 R770.2(N2) U52.K6
UNNAMED_42_ADLTM4709_I91_VO22: R765.1 R766.2(N2) U52.K7
UNNAMED_42_ADLTM4709_I91_VO30: R775.1 R776.2(N2) U52.K2
UNNAMED_42_ADLTM4709_I91_VO31: R771.1 R772.2(N2) U52.K3
UNNAMED_42_ADLTM4709_I91_VO32: R767.1 R768.2(N2) U52.K4
UNNAMED_42_ADLTM4709_I91_VOUT11: C757.2(N2) C758.2(N2) R777.1 U52.B5 U52.B6 U52.C5 U52.C6 U52.C7 U52.D5 U52.D6 U52.D7 U52.G5 U52.G6 U52.H5 U52.H6 U52.H7 U52.J5 U52.J6 U52.J7
UNNAMED_42_ADLTM4709_I91_VREF3: C764.2(N2) R789.2(N2) U52.L6(VREF3)
UNNAMED_42_NCTESTPAD_I74_N1: R764.2(N2) TP37.1(N1)
UNNAMED_43_ADLTM4702_I295_COMPA: R471.1 R680.2(N2) U36.C2
UNNAMED_43_ADLTM4702_I295_COMPB: R471.2(N2) U36.C3
UNNAMED_43_ADLTM4702_I295_PG: R63.1 U36.F2
UNNAMED_43_ADLTM4702_I295_PGSET: R539.1 U36.E2
UNNAMED_43_ADLTM4702_I295_RT: R504.1 U36.D1
UNNAMED_43_ADLTM4702_I295_RUN: R453.2(N2) U36.C1
UNNAMED_43_ADLTM4702_I295_SET: C163.2(N2) R54.2(N2) U36.E1
UNNAMED_43_ADLTM4702_I295_SYNC: R60.2(N2) U36.G6
UNNAMED_43_ADLTM4702_I295_VOSNS: C170.2(N2) C528.2(N2) C615.2(N2) L20.1 R539.2(N2) U36.A1 U36.A2 U36.A3 U36.B3 U36.F1 U36.F3 U36.G1 U36.G2 U36.G3(VOUT_8)
UNNAMED_43_ADLTM4709_I340_EN1: R617.2(N2) U34.E3
UNNAMED_43_ADLTM4709_I340_EN2: R619.2(N2) U34.F1
UNNAMED_43_ADLTM4709_I340_EN3: R620.2(N2) U34.L1
UNNAMED_43_ADLTM4709_I340_IMON1: TP28.1(N1) U34.A5
UNNAMED_43_ADLTM4709_I340_IMON2: TP34.1(N1) U34.F5
UNNAMED_43_ADLTM4709_I340_IMON3: TP35.1(N1) U34.L5
UNNAMED_43_ADLTM4709_I340_PG1: R552.1 U34.E7
UNNAMED_43_ADLTM4709_I340_PG2: R553.1 U34.E2
UNNAMED_43_ADLTM4709_I340_PG3: R554.1 U34.K1
UNNAMED_43_ADLTM4709_I340_VIN11: C137.2(N2) C138.2(N2) C139.2(N2) R550.2(N2) R585.1 R787.1 U34.B3 U34.B4 U34.C1 U34.C2 U34.C3 U34.C4 U34.D1 U34.D2 U34.D3 U34.D4 U34.G3 U34.G4 U34.H1 U34.H2 U34.H3 U34.H4 U34.J1 U34.J2 U34.J3 U34.J4 U34.M3 U34.M4 U34.N1 U34.N2 U34.N3 U34.N4 U34.P1 U34.P2 U34.P3 U34.P4
UNNAMED_43_ADLTM4709_I340_VO10: R44.1 R45.2(N2) U34.E4
UNNAMED_43_ADLTM4709_I340_VO11: R38.1 R39.2(N2) U34.E5
UNNAMED_43_ADLTM4709_I340_VO12: R31.1 R32.2(N2) U34.E6
UNNAMED_43_ADLTM4709_I340_VO20: R46.1 R47.2(N2) U34.K5
UNNAMED_43_ADLTM4709_I340_VO21: R40.1 R41.2(N2) U34.K6
UNNAMED_43_ADLTM4709_I340_VO22: R33.1 R34.2(N2) U34.K7
UNNAMED_43_ADLTM4709_I340_VO30: R48.1 R50.2(N2) U34.K2
UNNAMED_43_ADLTM4709_I340_VO31: R42.1 R43.2(N2) U34.K3
UNNAMED_43_ADLTM4709_I340_VO32: R35.1 R36.2(N2) U34.K4
UNNAMED_43_ADLTM4709_I340_VREF1: R23.2(N2) R615.2(N2) U34.A6
UNNAMED_43_ADLTM4709_I340_VREF2: R24.2(N2) R616.2(N2) U34.F6
UNNAMED_43_ADLTM4709_I340_VREF3: R618.2(N2) R621.2(N2) U34.L6(VREF3)
UNNAMED_43_CAP_I177_N2: C133.2(N2) L6.2(N2) U4.1 U4.2 U4.3
UNNAMED_43_CAP_I180_N2: C134.2(N2) R59.2(N2) U4.7(SET)
UNNAMED_43_CAP_I257_N2: C601.2(N2) L19.2(N2) U38.1 U38.2 U38.3
UNNAMED_43_CAP_I261_N2: C602.2(N2) R456.2(N2) U38.7(SET)
UNNAMED_43_CAP_I418_N2: C708.2(N2) R23.1 R24.1 R585.2(N2) R618.1 R786.1
UNNAMED_43_CAP_I420_N2: C644.2(N2) R681.1
UNNAMED_43_CAP_I423_N2: C645.2(N2) R680.1 R681.2(N2)
UNNAMED_43_CAPSP_I428_N2: C603.2 R457.1 U38.10
UNNAMED_43_CAPSP_I428_N3: C603.3 U38.9
UNNAMED_43_CAPSP_I429_N3: C135.3 U4.9
UNNAMED_43_IND_I175_N1: L6.1 R546.2(N2)
UNNAMED_43_IND_I260_N1: L19.1 R516.2(N2)
UNNAMED_43_LINLT3045V2_I181_ILIM: R551.1 TP29.1(N1) U4.5
UNNAMED_43_LINLT3045V2_I181_PGFB: R19.2(N2) R26.1 U4.6
UNNAMED_43_LINLT3045V2_I256_ILIM: R533.1 TP26.1(N1) U38.5
UNNAMED_43_LINLT3045V2_I256_PGFB: R454.2(N2) R455.1 U38.6
UNNAMED_43_NCTESTPAD_I395_N1: R552.2(N2) TP30.1(N1)
UNNAMED_43_NCTESTPAD_I396_N1: R553.2(N2) TP31.1(N1)
UNNAMED_43_NCTESTPAD_I397_N1: R554.2(N2) TP32.1(N1)
UNNAMED_43_RES_I405_N1: R617.1 R619.1 R620.1 R787.2(N2)
UNNAMED_44_ADLT1990_I356_: A3.2 R370.2(N2)
UNNAMED_44_ADLT1990_I356__1: A3.3 R682.2(N2)
UNNAMED_44_ADLT1990_I356_GAIN1: A3.8 R577.2(N2)
UNNAMED_44_ADLT1990_I356_GAIN2: A3.5 R472.2(N2)
UNNAMED_44_ADLT1990_I356_OUT: A3.6 R609.1
UNNAMED_44_ADLT1990_I356_V: A3.4(V-) C714.2(N2) R596.2(N2)
UNNAMED_44_ADLT1990_I356_V_1: A3.7 C530.2(N2) R606.2(N2)
UNNAMED_44_ADLT1990_I365_: A4.2 R683.2(N2)
UNNAMED_44_ADLT1990_I365__1: A4.3 R419.2(N2)
UNNAMED_44_ADLT1990_I365_GAIN1: A4.8 R511.2(N2)
UNNAMED_44_ADLT1990_I365_GAIN2: A4.5 R510.2(N2)
UNNAMED_44_ADLT1990_I365_OUT: A4.6 R667.1
UNNAMED_44_ADLT1990_I365_V: A4.4(V-) C538.2(N2) R607.2(N2)
UNNAMED_44_ADLT1990_I365_V_1: A4.7 C719.2(N2) R608.2(N2)
UNNAMED_44_ADLTC298024_I313_PWRGD: R555.1 R603.1 U11.A1
UNNAMED_44_ADLTC298024_I313_REFM: C154.2(N2) U11.G1
UNNAMED_44_ADLTC298024_I313_REFP: C154.1 U11.G2
UNNAMED_44_ADLTC298024_I313_SCL: R597.2(N2) R599.2(N2) U11.E2
UNNAMED_44_ADLTC298024_I313_SDA: R598.2(N2) R600.2(N2) U11.E1
UNNAMED_44_ADLTC298024_I313_VDACP0: R498.1 U11.F4
UNNAMED_44_ADLTC298024_I313_VDACP1: R499.1 U11.F6
UNNAMED_44_ADLTC298024_I313_VDACP3: R501.1 U11.G10
UNNAMED_44_ADLTC298024_I313_VDACP4: R502.1 U11.E10
UNNAMED_44_ADLTC298024_I313_VDACP7: R505.1 U11.C8
UNNAMED_44_ADLTC298024_I313_VDD251: C211.1 U11.A3 U11.B3
UNNAMED_44_ADLTC298024_I313_VPWR: C209.1 R631.2(N2) U11.A5
UNNAMED_44_ADLTC298024_I313_VSENSEP0: C618.1 R134.2(N2) U11.G4
UNNAMED_44_ADLTC298024_I313_VSENSEP1: C152.1 R135.2(N2) U11.E5
UNNAMED_44_ADLTC298024_I313_VSENSEP2: C151.1 R138.2(N2) U11.F7
UNNAMED_44_ADLTC298024_I313_VSENSEP3: C149.1 R139.2(N2) U11.E7
UNNAMED_44_ADLTC298024_I313_VSENSEP4: C148.1 R141.2(N2) U11.F9
UNNAMED_44_ADLTC298024_I313_VSENSEP5: C147.1 R609.2(N2) R622.2(N2) U11.C9
UNNAMED_44_ADLTC298024_I313_VSENSEP6: C146.1 R623.2(N2) R667.2(N2) U11.A9
UNNAMED_44_ADLTC298024_I313_VSENSEP7: C145.1 R492.2(N2) U11.A8
UNNAMED_44_ADLTC298024_I313_WP: R495.1 R626.2(N2) U11.A2
UNNAMED_44_CAP_I261_N1: C706.1 Q9.2 Q9.5 R627.1
UNNAMED_44_DIOLED_I227_N: DS31.C Q11.3
UNNAMED_44_DIOLED_I227_P: DS31.A(P) R605.1
UNNAMED_44_DIOLED_I310_N: DS17.C Q10.3
UNNAMED_44_DIOLED_I310_P: DS17.A(P) R158.1
UNNAMED_44_RES_I240_N2: Q18.1 R601.2(N2) R632.1
UNNAMED_44_RES_I260_N2: R627.2(N2) R630.2(N2) S3.2A S3.2B(N4)
UNNAMED_44_RES_I282_N2: R629.2(N2) S3.1A S3.1B
UNNAMED_44_RES_I286_N1: Q11.5 Q11.6 R636.1
UNNAMED_44_RES_I292_N1: Q10.5 Q10.6 R635.1
UNNAMED_44_RES_I295_N2: Q11.2 R634.2(N2)
UNNAMED_44_RES_I296_N2: Q10.2 R633.2(N2)
UNNAMED_45_ADLT199010_I200_: A1.4 R80.2(N2)
UNNAMED_45_ADLT199010_I200__1: A1.1 R79.2(N2)
UNNAMED_45_ADLT199010_I200_OUT: A1.6 R661.1
UNNAMED_45_ADLT199010_I200_V: A1.7 C522.2(N2) R706.2(N2)
UNNAMED_45_ADLT199010_I200_V_1: A1.5(V-) C523.2(N2) R704.2(N2)
UNNAMED_45_ADLT199010_I201_: A2.4 R671.2(N2)
UNNAMED_45_ADLT199010_I201__1: A2.1 R81.2(N2)
UNNAMED_45_ADLT199010_I201_OUT: A2.6 R657.1
UNNAMED_45_ADLT199010_I201_V: A2.7 C526.2(N2) R707.2(N2)
UNNAMED_45_ADLT199010_I201_V_1: A2.5(V-) C527.2(N2) R705.2(N2)
UNNAMED_45_ADLTC298024_I19_REFM: C723.2(N2) U11.AA1
UNNAMED_45_ADLTC298024_I19_REFP: C723.1 U11.AA2
UNNAMED_45_ADLTC298024_I19_SCL: R672.2(N2) R708.2(N2) U11.W2
UNNAMED_45_ADLTC298024_I19_SDA: R78.2(N2) R673.2(N2) U11.W1
UNNAMED_45_ADLTC298024_I19_VDD251: C722.1 U11.R3 U11.T3
UNNAMED_45_ADLTC298024_I19_VPWR: C720.1 R684.2(N2) U11.R5
UNNAMED_45_ADLTC298024_I19_VSENSEM7: C547.2(N2) R656.2(N2) U11.T8
UNNAMED_45_ADLTC298024_I19_VSENSEP0: C549.1 R662.2(N2) U11.AA4
UNNAMED_45_ADLTC298024_I19_VSENSEP1: C550.1 R663.2(N2) U11.W5
UNNAMED_45_ADLTC298024_I19_VSENSEP2: C551.1 R661.2(N2) U11.Y7
UNNAMED_45_ADLTC298024_I19_VSENSEP3: C548.1 R657.2(N2) U11.W7
UNNAMED_45_ADLTC298024_I19_VSENSEP4: C552.1 R664.2(N2) U11.Y9
UNNAMED_45_ADLTC298024_I19_VSENSEP7: C547.1 R655.2(N2) U11.R8
UNNAMED_45_ADLTC298024_I19_WP: R676.2(N2) R677.2(N2) U11.R2(WP)
UNNAMED_45_RES_I109_N1: Q22.1 R685.2(N2) R686.1
UNNAMED_46_ADLTC298024_I23_REFM: C718.2(N2) U11.P1
UNNAMED_46_ADLTC298024_I23_REFP: C718.1 U11.P2
UNNAMED_46_ADLTC298024_I23_SCL: R68.2(N2) R646.2(N2) U11.M2
UNNAMED_46_ADLTC298024_I23_SDA: R647.2(N2) R703.2(N2) U11.M1
UNNAMED_46_ADLTC298024_I23_VDD251: C717.1 U11.H3 U11.J3
UNNAMED_46_ADLTC298024_I23_VPWR: C715.1 R658.2(N2) U11.H5
UNNAMED_46_ADLTC298024_I23_VSENSEM1: C539.2(N2) R669.2(N2) U11.M6
UNNAMED_46_ADLTC298024_I23_VSENSEM3: C541.2(N2) R625.2(N2) U11.M8
UNNAMED_46_ADLTC298024_I23_VSENSEM5: C542.2(N2) R645.2(N2) U11.J9
UNNAMED_46_ADLTC298024_I23_VSENSEM7: C543.2(N2) R648.2(N2) U11.J8
UNNAMED_46_ADLTC298024_I23_VSENSEP0: C544.1 R654.1 U11.P4
UNNAMED_46_ADLTC298024_I23_VSENSEP1: C539.1 R668.2(N2) U11.M5
UNNAMED_46_ADLTC298024_I23_VSENSEP2: C540.1 R670.2(N2) U11.N7
UNNAMED_46_ADLTC298024_I23_VSENSEP3: C541.1 R624.2(N2) U11.M7
UNNAMED_46_ADLTC298024_I23_VSENSEP5: C542.1 R649.2(N2) U11.K9
UNNAMED_46_ADLTC298024_I23_VSENSEP7: C543.1 R652.2(N2) U11.H8
UNNAMED_46_ADLTC298024_I23_WP: R650.2(N2) R651.1 U11.H2
UNNAMED_46_NCTESTPAD_I77_N1: R654.2(N2) R788.1 UNK80A_V0.1
UNNAMED_46_RES_I50_N2: Q13.1 R659.2(N2) R660.1
UNNAMED_47_CN560PYMV2_I18_TDI: P1.D30 P1.D31
UNNAMED_48_FXLA104_I244_A0: R593.2(N2) U41.3
UNNAMED_48_FXLA104_I244_A1: R591.2(N2) U41.4
UNNAMED_48_FXLA104_I244_A2: R594.2(N2) U41.5
UNNAMED_48_FXLA104_I244_A3: R592.2(N2) U41.6
UNNAMED_48_FXLA104_I257_A0: R178.2(N2) U24.3
UNNAMED_48_FXLA104_I257_A1: R172.2(N2) U24.4
UNNAMED_48_FXLA104_I257_A2: R175.2(N2) U24.5
UNNAMED_48_FXLA104_I257_A3: R179.2(N2) U24.6
UNNAMED_48_FXLA104_I257_B0: R213.1 U24.12
UNNAMED_48_FXLA104_I257_B1: R221.1 U24.11
UNNAMED_48_FXLA104_I257_B2: R231.1 U24.10
UNNAMED_48_FXLA104_I257_B3: R225.1 U24.9
UNNAMED_48_FXLA104_I258_A0: R181.2(N2) U23.3
UNNAMED_48_FXLA104_I258_A1: R177.2(N2) U23.4
UNNAMED_48_FXLA104_I258_A2: R174.2(N2) U23.5
UNNAMED_48_FXLA104_I258_A3: R171.2(N2) U23.6
UNNAMED_48_FXLA104_I258_B0: R230.1 U23.12
UNNAMED_48_FXLA104_I258_B1: R218.1 U23.11
UNNAMED_48_FXLA104_I258_B2: R210.1 U23.10
UNNAMED_48_FXLA104_I258_B3: R206.1 U23.9
UNNAMED_48_FXLA104_I264_A0: R191.2(N2) U25.3
UNNAMED_48_FXLA104_I264_A1: R182.2(N2) U25.4
UNNAMED_48_FXLA104_I264_A2: R197.2(N2) U25.5
UNNAMED_48_FXLA104_I264_A3: R184.2(N2) U25.6
UNNAMED_48_FXLA104_I264_B0: R232.1 U25.12
UNNAMED_48_FXLA104_I264_B1: R219.1 U25.11
UNNAMED_48_FXLA104_I264_B2: R211.1 U25.10
UNNAMED_48_FXLA104_I264_B3: R207.1 U25.9
UNNAMED_48_FXLA104_I265_A0: R198.2(N2) U26.3
UNNAMED_48_FXLA104_I265_A1: R185.2(N2) U26.4
UNNAMED_48_FXLA104_I265_A2: R192.2(N2) U26.5
UNNAMED_48_FXLA104_I265_A3: R199.2(N2) U26.6
UNNAMED_48_FXLA104_I265_B0: R214.1 U26.12
UNNAMED_48_FXLA104_I265_B1: R222.1 U26.11
UNNAMED_48_FXLA104_I265_B2: R233.1 U26.10
UNNAMED_48_FXLA104_I265_B3: R226.1 U26.9
UNNAMED_48_FXLA104_I271_A0: R193.2(N2) U27.3
UNNAMED_48_FXLA104_I271_A1: R183.2(N2) U27.4
UNNAMED_48_FXLA104_I271_A2: R200.2(N2) U27.5
UNNAMED_48_FXLA104_I271_A3: R186.2(N2) U27.6
UNNAMED_48_FXLA104_I271_B0: R234.1 U27.12
UNNAMED_48_FXLA104_I271_B1: R220.1 U27.11
UNNAMED_48_FXLA104_I271_B2: R212.1 U27.10
UNNAMED_48_FXLA104_I271_B3: R208.1 U27.9
UNNAMED_48_FXLA104_I276_A0: R201.2(N2) U28.3
UNNAMED_48_FXLA104_I276_A1: R187.2(N2) U28.4
UNNAMED_48_FXLA104_I276_A2: R194.2(N2) U28.5
UNNAMED_48_FXLA104_I276_A3: R202.2(N2) U28.6
UNNAMED_48_FXLA104_I276_B0: R215.1 U28.12
UNNAMED_48_FXLA104_I276_B1: R223.1 U28.11
UNNAMED_48_FXLA104_I276_B2: R235.1 U28.10
UNNAMED_48_FXLA104_I276_B3: R227.1 U28.9
UNNAMED_48_FXLA104_I281_A0: R195.2(N2) U29.3
UNNAMED_48_FXLA104_I281_A1: R188.2(N2) U29.4
UNNAMED_48_FXLA104_I281_A2: R203.2(N2) U29.5
UNNAMED_48_FXLA104_I281_A3: R189.2(N2) U29.6
UNNAMED_48_FXLA104_I281_B0: R236.1 U29.12
UNNAMED_48_FXLA104_I281_B1: R224.1 U29.11
UNNAMED_48_FXLA104_I281_B2: R216.1 U29.10
UNNAMED_48_FXLA104_I281_B3: R209.1 U29.9
UNNAMED_48_FXLA104_I287_A0: R254.2(N2) U44.3
UNNAMED_48_FXLA104_I287_A1: R242.2(N2) U44.4
UNNAMED_48_FXLA104_I287_A2: R248.2(N2) U44.5
UNNAMED_48_FXLA104_I287_A3: R255.2(N2) U44.6
UNNAMED_48_FXLA104_I287_B0: R268.1 U44.12
UNNAMED_48_FXLA104_I287_B1: R274.1 U44.11
UNNAMED_48_FXLA104_I287_B2: R281.1 U44.10
UNNAMED_48_FXLA104_I287_B3: R277.1 U44.9
UNNAMED_48_FXLA104_I293_A0: R204.2(N2) U42.3
UNNAMED_48_FXLA104_I293_A1: R190.2(N2) U42.4
UNNAMED_48_FXLA104_I293_A2: R196.2(N2) U42.5
UNNAMED_48_FXLA104_I293_A3: R205.2(N2) U42.6
UNNAMED_48_FXLA104_I293_B0: R217.1 U42.12
UNNAMED_48_FXLA104_I293_B1: R228.1 U42.11
UNNAMED_48_FXLA104_I293_B2: R237.1 U42.10
UNNAMED_48_FXLA104_I293_B3: R229.1 U42.9
UNNAMED_48_FXLA104_I296_A0: R247.2(N2) U43.3
UNNAMED_48_FXLA104_I296_A1: R238.2(N2) U43.4
UNNAMED_48_FXLA104_I296_A2: R253.2(N2) U43.5
UNNAMED_48_FXLA104_I296_A3: R241.2(N2) U43.6
UNNAMED_48_FXLA104_I296_B0: R280.1 U43.12
UNNAMED_48_FXLA104_I296_B1: R271.1 U43.11
UNNAMED_48_FXLA104_I296_B2: R265.1 U43.10
UNNAMED_48_FXLA104_I296_B3: R262.1 U43.9
UNNAMED_48_FXLA104_I300_A0: R249.2(N2) U45.3
UNNAMED_48_FXLA104_I300_A1: R239.2(N2) U45.4
UNNAMED_48_FXLA104_I300_A2: R256.2(N2) U45.5
UNNAMED_48_FXLA104_I300_A3: R243.2(N2) U45.6
UNNAMED_48_FXLA104_I300_B0: R282.1 U45.12
UNNAMED_48_FXLA104_I300_B1: R272.1 U45.11
UNNAMED_48_FXLA104_I300_B2: R266.1 U45.10
UNNAMED_48_FXLA104_I300_B3: R263.1 U45.9
UNNAMED_48_FXLA104_I305_A0: R257.2(N2) U46.3
UNNAMED_48_FXLA104_I305_A1: R244.2(N2) U46.4
UNNAMED_48_FXLA104_I305_A2: R250.2(N2) U46.5
UNNAMED_48_FXLA104_I305_A3: R258.2(N2) U46.6
UNNAMED_48_FXLA104_I305_B0: R269.1 U46.12
UNNAMED_48_FXLA104_I305_B1: R275.1 U46.11
UNNAMED_48_FXLA104_I305_B2: R283.1 U46.10
UNNAMED_48_FXLA104_I305_B3: R278.1 U46.9
UNNAMED_48_FXLA104_I312_A0: R260.2(N2) U48.3
UNNAMED_48_FXLA104_I312_A1: R246.2(N2) U48.4
UNNAMED_48_FXLA104_I312_A2: R252.2(N2) U48.5
UNNAMED_48_FXLA104_I312_A3: R261.2(N2) U48.6
UNNAMED_48_FXLA104_I312_B0: R270.1 U48.12
UNNAMED_48_FXLA104_I312_B1: R276.1 U48.11
UNNAMED_48_FXLA104_I312_B2: R285.1 U48.10
UNNAMED_48_FXLA104_I312_B3: R279.1 U48.9
UNNAMED_48_FXLA104_I318_A0: R251.2(N2) U47.3
UNNAMED_48_FXLA104_I318_A1: R240.2(N2) U47.4
UNNAMED_48_FXLA104_I318_A2: R259.2(N2) U47.5
UNNAMED_48_FXLA104_I318_A3: R245.2(N2) U47.6
UNNAMED_48_FXLA104_I318_B0: R284.1 U47.12
UNNAMED_48_FXLA104_I318_B1: R273.1 U47.11
UNNAMED_48_FXLA104_I318_B2: R267.1 U47.10
UNNAMED_48_FXLA104_I318_B3: R264.1 U47.9
UNNAMED_50_7416244V3_I101_O0: R468.1 U35.2
UNNAMED_50_7416244V3_I101_O1: R467.1 U35.3
UNNAMED_50_7416244V3_I101_O2: R466.1 U35.5
UNNAMED_50_7416244V3_I101_O3: R465.1 U35.6
UNNAMED_50_7416244V3_I101_O4: R464.1 U35.8
UNNAMED_50_7416244V3_I101_O5: R462.1 U35.9
UNNAMED_50_7416244V3_I101_O6: R461.1 U35.11
UNNAMED_50_7416244V3_I101_O7: R463.1 U35.12
UNNAMED_50_7416244V3_I101_O8: R460.1 U35.13
UNNAMED_50_7416244V3_I101_O9: R459.1 U35.14
UNNAMED_50_7416244V3_I101_OE1N: BUFDIS.2(N2) R637.1 U35.1 U35.24 U35.25 U35.48
UNNAMED_50_CAP_I45_N1: C225.1 U22.6
UNNAMED_50_CAP_I132_N1: C124.1 U21.5
UNNAMED_50_CN2P_I136_N1: BUFDIS.1 R458.1
UNNAMED_50_CN20PV2_I15_N9: P3.17 R163.1
UNNAMED_50_CN20PV2_I16_N1: P3.2 R164.1
UNNAMED_50_CN20PV2_I16_N2: P3.4 R167.1
UNNAMED_50_CN20PV2_I16_N3: P3.6 R165.1
UNNAMED_50_CN20PV2_I16_N4: P3.8 R168.1
UNNAMED_50_CN20PV2_I16_N8: P3.16 R166.1
UNNAMED_50_DIOLED_I70_P: DS27.A(P) R468.2(N2)
UNNAMED_50_DIOLED_I73_P: DS26.A(P) R467.2(N2)
UNNAMED_50_DIOLED_I76_P: DS25.A(P) R466.2(N2)
UNNAMED_50_DIOLED_I79_P: DS24.A(P) R465.2(N2)
UNNAMED_50_DIOLED_I82_P: DS23.A(P) R464.2(N2)
UNNAMED_50_DIOLED_I85_P: DS22.A(P) R463.2(N2)
UNNAMED_50_DIOLED_I88_P: DS21.A(P) R462.2(N2)
UNNAMED_50_DIOLED_I91_P: DS20.A(P) R461.2(N2)
UNNAMED_50_DIOLED_I94_P: DS19.A(P) R460.2(N2)
UNNAMED_50_DIOLED_I97_P: DS18.A(P) R459.2(N2)
UNNAMED_50_ICM24CXX_I130_E2: R161.1 U20.3
UNNAMED_50_ICM24CXX_I130_SCL: R160.1 R711.2(N2) U20.6
UNNAMED_50_ICM24CXX_I130_SDA: R162.2(N2) R712.2(N2) U20.5
UNNAMED_51_ADP7112_I30_EN: C858.1 R361.2(N2) R362.2(N2) U74.A1 U74.C1
UNNAMED_51_ADP7112_I30_SENSE: R815.1 R816.2(N2) U74.B2
UNNAMED_51_ADP7159V2_I59_BYP: C852.1 U73.4
UNNAMED_51_ADP7159V2_I59_EN: C855.1 R362.1 R784.2(N2) U73.5 U73.9 U73.10
UNNAMED_51_ADP7159V2_I59_REF: C857.1 R808.1 U73.7
UNNAMED_51_ADP7159V2_I59_REFSENSE: R808.2(N2) R809.1 U73.6
UNNAMED_51_ADP7159V2_I59_VOUT1: R364.1 U73.1 U73.2 U73.3
UNNAMED_51_ADP7159V2_I59_VREG: C854.1 U73.8(VREG)
UNNAMED_51_CAP_I15_N1: C853.1 C856.1 R784.1 R810.1 TP78.1(N1) U72.G1 U72.G2 U72.G3 U72.G4 U72.G5 U72.G6 U72.H1 U72.H2 U72.H3(VOUT_9) U72.H4 U72.H5 U72.H6
UNNAMED_51_CAP_I20_N1: C847.1 U72.B5
UNNAMED_51_LINLTM8053_I4_AUX: U72.A2 U72.B2
UNNAMED_51_LINLTM8053_I4_FB: R807.2(N2) U72.B1
UNNAMED_51_LINLTM8053_I4_RT: R797.1 U72.A5
UNNAMED_51_LINLTM8053_I4_RUN: R794.2(N2) U72.B6
UNNAMED_51_LINLTM8053_I4_SYNC: R810.2(N2) R811.1 U72.B4
UNNAMED_52_741G04_I115_A: U50.2 U51.38
UNNAMED_52_741G04_I115_Y: R734.2(N2) U50.4(Y)
UNNAMED_52_ADF4030_I1_BSYNC0: R721.1 R781.1 U51.1
UNNAMED_52_ADF4030_I1_BSYNC0_1: R720.1 R780.1 U51.2
UNNAMED_52_ADF4030_I1_VDD18TDC: C786.1 E15.1 U51.48
UNNAMED_52_CN2P4GNDV2_I35_N1: P19.1 R752.2(N2) TP63.1(N1)
UNNAMED_52_CN2P4GNDV2_I35_N2: P19.2 R751.2(N2) TP62.1(N1)
UNNAMED_52_CN2P4GNDV2_I39_N1: P18.1 R745.2(N2) TP61.1(N1)
UNNAMED_52_CN2P4GNDV2_I39_N2: P18.2 R740.2(N2) TP60.1(N1)
UNNAMED_52_DIOLED_I118_P: DS29.A(P) R734.1
UNNAMED_52_NCTESTPAD_I164_N1: R732.2(N2) TP54.1(N1)
UNNAMED_52_NCTESTPAD_I165_N1: R749.2(N2) TP56.1(N1)
UNNAMED_52_NCTESTPAD_I167_N1: R743.2(N2) TP48.1(N1)
UNNAMED_52_NCTESTPAD_I168_N1: R733.2(N2) TP55.1(N1)
UNNAMED_52_NCTESTPAD_I170_N1: R744.2(N2) TP49.1(N1)
UNNAMED_52_NCTESTPAD_I175_N1: R725.2(N2) TP52.1(N1)
UNNAMED_52_NCTESTPAD_I176_N1: R726.2(N2) TP53.1(N1)
UNNAMED_52_NCTESTPAD_I177_N1: R750.2(N2) TP57.1(N1)
USB_DN: P4.2 U21.3
USB_DP: P4.3 U21.1
USB_UART_DN: U21.4(I/O2_1) U22.4
USB_UART_DP: U21.6 U22.3
VCMA_A0: C482.1 U1A.AA5
VCMA_A1: C489.1 U1A.AA4
VCMA_B0: C498.1 U1A.J5
VCMA_B1: C503.1 U1A.J4
VCMD_A: C465.1 C469.1 C473.1 C476.1 R476.2(N2) U1A.AF12 U1A.AF14 U1A.AF15 U1A.AF17
VCMD_B: C464.1 C468.1 C472.1 C475.1 R479.1 U1A.D12 U1A.D14 U1A.D15 U1A.D17
VNEGM1P0_ADC: C198.3 C411.1 C412.1 C413.1 C414.1 C415.1 C416.1 C417.1 R131.2(N2) R570.2(N2) R683.1 R710.1 U1A.AA8 U1A.AA9 U1A.J8 U1A.J9 U1A.P8 U1A.P9 U1A.T8 U1A.T9 U10.11 U10.12
VNEGM1P0_ADC_I+: C194.2(N2) R18.2(N2) R671.1 U10.1 U10.2 U10.PAD
VNEGM1P0_ADC_PG: R549.2(N2) R623.1 R665.1 TP25.1(N1)
VNEGM1P0_DAC: C197.3 C335.2(N2) C336.1 C339.2(N2) C340.2(N2) C341.1 C344.2(N2) C345.2(N2) C346.1 C349.2(N2) C350.2(N2) C353.2(N2) C357.1 C358.2(N2) C361.2(N2) C362.1 C363.2(N2) C366.2(N2) C367.1 C368.2(N2) C375.2(N2) C381.2(N2) C385.2(N2) C389.2(N2) C393.2(N2) C397.2(N2) C401.2(N2) C405.2(N2) C629.2(N2) C692.1 C693.1 C694.1 C695.1 C696.1 C697.1 C698.1 C699.1 C700.1 C701.1 C702.1 C703.1 R130.2(N2) R370.1 R569.2(N2) R709.1 U1A.AC11 U1A.AC12 U1A.AC14 U1A.AC15 U1A.AC17 U1A.AC18 U1A.AH6 U1A.AH9 U1A.AH10 U1A.AH13 U1A.AH14 U1A.AH17 U1A.AH18 U1A.AH21 U1A.B6 U1A.B9 U1A.B10 U1A.B13 U1A.B14 U1A.B17 U1A.B18 U1A.B21 U1A.G11 U1A.G12 U1A.G14 U1A.G15 U1A.G17 U1A.G18 U9.11 U9.12
VNEGM1P0_DAC_I+: C193.2(N2) R80.1 R123.2(N2) U9.1 U9.2 U9.PAD
VNEGM1P0_DAC_PG: R548.2(N2) R622.1 R666.1 TP24.1(N1)
VNEGM1P0_EN_ADC: R156.1 U10.3 U11.B6
VNEGM1P0_EN_DAC: R155.1 U9.3 U11.C6
VREF_1P2_A: C462.1 R302.1 U1A.AJ3
VREF_1P2_A_F: R302.2(N2) R423.2(N2) R424.2(N2)
VREF_1P2_B: C463.1 R301.1 U1A.A3
VREF_1P2_B_F: R301.2(N2) R421.2(N2) R422.2(N2)
VSUP_VCXO: R51.1 R454.1 R457.2(N2)
VUSB: C142.1 C222.1 C224.1 P4.1 U22.7 U22.8

Pads without a net: A1 2 3; A2 2 3; D6 2; NOREF#39 1 2; P1 B1 B40 D29 D33 D34 E2 E3 E6 E7 E9 E10 E12 E13 E15 E16 E18 E19 F4 F5 F7 F8 F10 F11 F13 F14 F16 F17 F19 F20 H1 J2 J3 J6 J7 J9 J10 J12 J13 J15 J16 J18 J19 J21 J22 K1 K7 K8 K10 K11 K13 K14 K16 K17 K19 K20 K22 K23 L1 L16 L17 L20 L21 L28 L29 L32 L33; P2 11 13; P3 7 10 11 12 13 14 18 20; P4 4; P22 2 5; P23 1; Q8 3; R246 1; R252 1; R261 1; R279 2; S4 4; U1 F6 F7; U1A AE10 AG15 AG16 AG17 C15 C16 C17 E10 N12 P25 T24 T25; U1B 31 33 34 42 43 44 45 63; U2 6 7 12 13 18 19 21 22 24 25 27 28 30 31 33 34; U3 6; U4 4; U5 D3 F6 F7; U6 D5; U7 A1 E1 E2 F3 K1 L3; U8 A1 E1; U9 7; U10 7; U11 AA7 AA10 C5 D5 D8 D9 G7 H1 H6 H7 J6 J7 K5 K6 K7 K8 L5 L6 L7 L8 L9 M3 M10 N4 N6 P7 P10 R1 R6 R7 T6 T7 U5 U6 U7 U8 V5 V6 V7 V8 V9 W10 Y3 Y4 Y6; U22 1 10 11 14 15 16 17 18 19 22 23 24; U30 37; U31 F6; U32 C6 D6 E6 F6 N4 N5; U33 A9 AA9 C1 C2 D1 D2 E1 E2 E10 E11 G1 G2 H1 H2 J1 J2 P1 P2 R1 R2 T1 T2 U8 U9 V1 V2 W1 W2 Y1 Y2; U34 A1 A3 E1 F3 L3; U35 16 17 19 20 22 23; U36 F6 F7; U37 4 15 16; U38 4; U40 D5; U52 A1 E1 E2 F3 K1 L3; U53 B1; U54 6; U72 A3 A4; U74 B1

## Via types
v1: diameter 0.508, hole 0.254, TOP to BOTTOM, 4260 vias
v2: diameter 0.356, hole 0.203, TOP to BOTTOM, 255 vias
v3: diameter 0.61, hole 0.305, TOP to BOTTOM, 758 vias
v4: diameter 0.457, hole 0.203, TOP to BOTTOM, 1934 vias
v5: diameter 0.33, hole 0.178, TOP to L2_GROUND, 4096 vias
v6: diameter 0.406, hole 0.203, TOP to BOTTOM, 102 vias
v7: diameter 0.356, hole 0.203, L2_GROUND to L3_SIGNAL, 3898 vias
v8: diameter 0.356, hole 0.178, L24_SIGNAL to L25_GROUND, 217 vias
v9: diameter 0.33, hole 0.178, L25_GROUND to BOTTOM, 866 vias
v10: diameter 0.559, hole 0.305, TOP to BOTTOM, 30 vias
v11: diameter 0.305, hole 0.152, TOP to BOTTOM, 5 vias
v12: diameter 0.61, hole 0.457, TOP to BOTTOM, 12 vias
v13: diameter 0.381, hole 0.305, TOP to BOTTOM, 55 vias
v14: diameter 0.305, hole 0.254, TOP to BOTTOM, 14 vias
v15: diameter 0.356, hole 0.254, TOP to BOTTOM, 192 vias

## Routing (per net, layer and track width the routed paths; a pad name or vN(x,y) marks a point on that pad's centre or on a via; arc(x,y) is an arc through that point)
5VBIAS: length 440.8
  TOP w0.197: C649.2 v3(229.91,199.49) ; U53.B2 U53.A2
  L3_SIGNAL w0.203: 139.75,253.59 142.42,253.59 144.53,251.48 144.53,247.17 v1(144.58,247.12) 145.16,247.12 146,246.28 150.29,246.28 151.87,247.85 153.42,247.85 155.3,245.97 v3(155.93,245.97) ; 139.75,253.59 138.94,253.59 138.51,253.16 135.33,253.16 134.04,251.87 134.04,247.88 135.05,246.86 136.33,246.86 v1(136.58,247.12) ; 139.75,253.59 139.75,249.33 140.58,248.49 v1(140.58,247.12) ; 166.34,271.48 168.68,271.48 170.89,269.27 170.89,266.17 171.13,265.93 171.13,265.05 v1(171.18,265) 171.56,264.62 175.79,264.62 177.27,263.14 181.81,263.14 v3(182.52,263.86) ; 166.34,271.48 166.34,268.91 166.9,268.35 166.9,266.68 167.18,266.41 v1(167.18,265) ; 166.34,271.48 162.36,271.48 160.63,269.75 160.63,264.97 161.24,264.36 162.53,264.36 v1(163.17,265)
  L18_POWER w0.508: v1(193.19,229.92) 184.37,238.75 163.16,238.75 v3(155.93,245.97) 155.93,253.09 150.72,258.29 130.51,258.29 v1(119,246.79) 119,246.13 v1(119.02,246.1)
  L24_SIGNAL w0.203: 194.97,219.86 194.64,219.53 192.41,219.53 192.05,219.18 190.39,219.18 v1(190.27,219.06) ; 194.97,219.86 195.34,220.23 195.34,228.66 194.08,229.92 v1(193.19,229.92) 193.32,229.79 193.32,226.97 191.67,225.32 v4(191.67,224.08) ; 194.97,219.86 195.38,219.46 195.38,215.77 194.78,215.18 193.02,215.18 193.01,215.16 191.32,215.16 191.21,215.06 v1(190.27,215.06) 189.13,213.91 189.13,205.28 v1(189.38,205.03) ; 110.69,254.63 115.54,254.63 119.89,250.29 119.89,247.68 v1(119,246.79) ; 110.69,254.63 106.17,254.63 ; 110.69,254.63 110.69,248.23 v4(111.33,247.6) ; v1(99.59,243.83) 99.59,246.86 100.67,247.94 ; 100.67,247.94 101.35,247.27 102.31,247.27 102.32,247.26 102.71,247.26 102.72,247.27 v1(103.03,247.27) ; 100.67,247.94 100.05,248.56 100.05,252.94 100.06,252.96 100.06,253.2 101.5,254.63 106.17,254.63 ; v1(159.74,261.56) 163.17,264.99 v1(163.17,265) ; v1(136.58,247.12) v1(133.15,243.68) ; 106.17,254.63 106.17,251.56 106.76,250.97 106.76,248.16 107.03,247.88 v1(107.03,247.27)
  L24_SIGNAL w0.254: v3(155.94,246.74) v3(155.93,245.97) ; v3(229.91,199.49) 229.95,199.53 229.95,201.02 225.93,205.03 v1(189.38,205.03)
  L24_SIGNAL w0.508: v1(119.02,246.1) 119,246.13 v1(119,246.79)
  BOTTOM w0.203: R31.2 R38.2 R44.2 95.41,243.54 95.7,243.83 v1(99.59,243.83) ; v1(189.38,205.03) 189.5,205.03 189.51,205.04 ; R85.2 155.24,238.23 ; 155.24,238.23 R87.2 R93.2 R99.2 ; 155.24,238.23 R91.2 v3(155.24,233.53) ; v1(119.02,246.1) 119.02,246.09 R48.2 R42.2 R35.2 119.02,237.46 R33.2 119.04,235.05 R40.2 R46.2 ; 181.83,256.11 R767.2 R771.2 R775.2 v3(182.52,263.86) ; 181.83,256.11 R769.2 R773.2 ; 181.83,256.11 R765.2 ; R99.2 155.24,255.79 R746.2 R748.2 R754.2 155.56,261.37 155.75,261.56 v1(159.74,261.56) ; R99.2 v3(155.93,245.97) ; R83.2 R89.2 R95.2 128.96,243.49 129.16,243.68 v1(133.15,243.68) ; U8.A3 U8.A4 191.29,224.08 v4(191.67,224.08) ; U34.L4 111.03,247.3 v4(111.33,247.6) ; R104.2 R110.2 R116.2 192.44,229.92 v1(193.19,229.92) ; 189.51,205.04 R108.2 R114.2 R120.2 ; 189.51,205.04 R106.2 R112.2 R118.2 ; U52.A3 U52.A4 ; U8.L3 v1(190.27,215.06) ; U7.A3 v1(136.58,247.12) ; U8.F3 v1(190.27,219.06)
AVDD1P0_CK: length 2
  BOTTOM w0.191: E27.2 v1(172.64,229.59) ; C207.1 116.72,133.71 v4(116.7,133.73) ; C105.1 v4(115.9,133.73) ; C204.1 121.52,133.71 v4(121.5,133.73)
  vias: v1(171.81,230.4) v1(171.81,229.62) v1(171.81,228.73) v1(172.64,230.38) v1(172.62,228.78) v4(122.3,133.73) v4(123.1,133.73) v4(127.9,133.73) v4(128.7,133.73)
AVDD1P0_MCS: length 1.8
  BOTTOM w0.254: v4(172.77,225.98) 172.77,225.96 E24.2 ; v4(128.7,130.53) 128.72,130.54 C430.1
  vias: v4(115.9,130.53) v4(171.96,226.75) v4(171.93,225.98) v4(171.93,225.12) v4(172.75,226.75) v4(172.75,225.15)
AVDD1P0_PLL_SYN: length 1.9
  BOTTOM w0.191: E26.2 v4(172.34,222.02)
  vias: v4(120.7,128.93) v4(171.58,221.18) v4(171.55,220.4) v4(171.63,223.44) v4(171.6,222.73) v4(171.6,222.05) v4(172.36,223.44) v4(172.36,222.73) v4(172.31,221.16) v4(172.31,220.37)
AVDD1P8: length 1.9
  BOTTOM w0.191: v3(168.71,204.11) 168.76,204.06 E20.2 ; v4(133.5,135.33) 133.49,135.35 C447.1
  vias: v3(168.71,205.77) v3(168.71,205) v3(168.71,203.33) v3(168.71,202.64) v3(169.62,205.87) v3(170.56,205.82) v4(111.1,135.33)
AVDD1P8_ADC: length 1.6
  BOTTOM w0.508: v3(168.43,216.54) 168.45,216.56 E23.2
  vias: v3(167.54,215.6) v3(168.4,217.4) v3(168.4,215.62) v3(168.43,214.81) v3(169.44,214.81) v3(170.33,214.81) v4(118.3,132.13) v4(119.1,132.13) v4(119.9,132.13) v4(120.7,132.13) v4(123.9,132.13) v4(124.7,132.13) v4(125.5,132.13) v4(126.3,132.13)
AVDD1P8_MCS: length 2.8
  TOP w0.191: v4(231.09,172.16) 231.06,172.14 229.41,172.14 ; v1(229.44,170.31) 229.4,170.27 R573.1
  vias: v4(115.9,131.33) v4(128.7,131.33) v4(231.09,171.37) v4(231.11,170.54) v4(231.85,172.16) v4(231.88,171.37) v4(231.88,170.54) v4(232.61,172.19) v4(232.64,171.4) v4(232.69,170.54) v4(233.5,172.16) v4(233.5,171.37) v4(233.55,170.54)
AVDD1P8_PLL: length 2.8
  TOP w0.191: R574.1 226.09,168.58 v1(226.34,168.83) ; v1(225.58,170.23) 225.6,170.26 E22.2 225.6,172.14
  vias: v1(223.88,172.47) v1(223.82,171.65) v1(223.82,170.69) v1(223.8,169.55) v1(224.76,169.49) v1(224.79,170.26) v1(225.53,169.47) v1(226.36,169.44) v1(226.39,170.23) v4(122.3,128.93)
DGND: length 9487.6
  TOP w0.152: J13.2 24.74,261.44 ; J13.2 22.88,261.44 ; J13.2 24.74,263.3 ; J13.2 22.88,263.3 ; J12.4 45.05,258.21 ; J12.4 43.19,256.35 ; J12.4 43.19,258.21 ; J12.4 45.05,256.35 ; 48.37,218.99 REFCLK.4 ; REFCLK.4 50.23,220.84 ; REFCLK.4 48.37,220.84 ; REFCLK.4 50.23,218.99 ; P18.GND4 2.68,190.89 ; P18.GND4 1.28,190.89 ; P18.GND4 1.28,192.3 ; EXT_TRIG.5 7.1,256.45 ; EXT_TRIG.5 5.24,256.45 ; EXT_TRIG.5 5.24,258.31 ; EXT_TRIG.5 7.1,258.31 ; J13.3 29.82,263.3 ; J13.3 27.96,263.3 ; J13.3 29.82,261.44 ; J13.3 27.96,261.44 ; 38.11,261.43 J12.2 ; J12.2 38.11,263.29 ; J12.2 39.97,263.29 ; J12.2 39.97,261.43 ; EXT_SYNC.3 12.03,246.79 ; EXT_SYNC.3 12.03,244.93 ; EXT_SYNC.3 10.17,246.79 ; EXT_SYNC.3 10.17,244.93 ; EXT_SYS_P.4 34.58,275.07 ; EXT_SYS_P.4 32.73,275.07 ; EXT_SYS_P.4 32.73,273.21 ; EXT_SYS_P.4 34.58,273.21 ; 174.23,165.39 GND8.1 ; GND8.1 175.73,165.39 ; GND8.1 174.23,163.9 ; GND8.1 175.73,163.9 ; REFP.2 76.97,278.73 ; REFP.2 76.97,280.59 ; REFP.2 75.12,278.73 ; REFP.2 75.12,280.59 ; 182.95,284.75 S4.GND1 ; S4.GND1 184.89,286.7 ; S4.GND1 182.95,286.7 ; S4.GND1 184.89,284.75 ; 59.49,275.45 REFN.5 ; REFN.5 61.35,273.6 ; REFN.5 61.35,275.45 ; REFN.5 59.49,273.6 ; 51.22,250.75 J17.2 ; J17.2 53.08,248.9 ; J17.2 53.08,250.75 ; J17.2 51.22,248.9 ; EXT_HMCREF.3 45.62,275.2 ; EXT_HMCREF.3 43.76,275.2 ; EXT_HMCREF.3 43.76,273.34 ; EXT_HMCREF.3 45.62,273.34 ; GND6.1 218.83,38.84 ; GND6.1 217.29,37.3 ; GND6.1 218.83,37.3 ; GND6.1 217.29,38.84 ; REFP.3 82.05,280.59 ; REFP.3 80.2,278.73 ; REFP.3 80.2,280.59 ; REFP.3 82.05,278.73 ; J12.5 39.97,258.21 ; J12.5 39.97,256.35 ; J12.5 38.11,258.21 ; J12.5 38.11,256.35 ; 5.24,261.53 EXT_TRIG.2 ; EXT_TRIG.2 7.1,261.53 ; EXT_TRIG.2 7.1,263.39 ; EXT_TRIG.2 5.24,263.39 ; 10.17,239.85 EXT_SYNC.4 ; EXT_SYNC.4 10.17,241.71 ; EXT_SYNC.4 12.03,239.85 ; EXT_SYNC.4 12.03,241.71 ; 2.81,55.47 P4.7 2.81,57.19 ; 16.83,280.12 EXT_SYS_N.3 ; EXT_SYS_N.3 16.83,278.27 ; EXT_SYS_N.3 18.68,278.27 ; EXT_SYS_N.3 18.68,280.12 ; 3.57,49.77 GND5.1 ; GND5.1 5.11,49.77 ; GND5.1 3.57,48.23 ; GND5.1 5.11,48.23 ; 46.14,250.75 J17.5 ; J17.5 46.14,248.9 ; J17.5 48,250.75 ; J17.5 48,248.9 ; 48.37,213.91 REFCLK.3 ; REFCLK.3 50.23,215.76 ; REFCLK.3 48.37,215.76 ; REFCLK.3 50.23,213.91 ; EXT_SYS_N.2 13.6,278.27 ; EXT_SYS_N.2 11.75,278.27 ; EXT_SYS_N.2 11.75,280.12 ; EXT_SYS_N.2 13.6,280.12 ; REFP.4 82.05,273.65 ; REFP.4 82.05,275.51 ; REFP.4 80.2,275.51 ; REFP.4 80.2,273.65 ; EXT_SYNC.2 6.95,244.93 ; EXT_SYNC.2 5.09,244.93 ; EXT_SYNC.2 5.09,246.79 ; EXT_SYNC.2 6.95,246.79 ; P22.3 220.88,271.5 ; P22.3 218.85,273.53 ; P22.3 218.85,271.5 ; P22.3 220.88,273.53 ; REFN.3 66.43,280.53 ; REFN.3 64.57,278.68 ; REFN.3 66.43,278.68 ; REFN.3 64.57,280.53 ; EXT_SYS_P.3 34.58,278.29 ; EXT_SYS_P.3 34.58,280.15 ; EXT_SYS_P.3 32.73,278.29 ; EXT_SYS_P.3 32.73,280.15 ; EXT_SYS_P.5 29.5,275.07 ; EXT_SYS_P.5 29.5,273.21 ; EXT_SYS_P.5 27.65,275.07 ; EXT_SYS_P.5 27.65,273.21 ; 27.96,256.36 J13.4 ; J13.4 29.82,258.22 ; J13.4 29.82,256.36 ; J13.4 27.96,258.22 ; P4.9 5.76,57.47 ; P4.9 3.7,57.47 ; P4.9 3.7,55.79 ; P4.9 5.76,55.79 ; 8.5,101.73 GND1.1 ; GND1.1 10.04,101.73 ; GND1.1 10.04,100.2 ; GND1.1 8.5,100.2 ; 27.65,278.29 EXT_SYS_P.2 ; EXT_SYS_P.2 29.5,278.29 ; EXT_SYS_P.2 27.65,280.15 ; EXT_SYS_P.2 29.5,280.15 ; 61.63,245.77 J18.2 ; J18.2 63.48,243.92 ; J18.2 61.63,243.92 ; J18.2 63.48,245.77 ; 57.06,260.24 GND3.1 ; GND3.1 57.06,261.73 ; GND3.1 58.56,261.73 ; GND3.1 58.56,260.24 ; 59.49,280.53 REFN.2 ; REFN.2 59.49,278.68 ; REFN.2 61.35,280.53 ; REFN.2 61.35,278.68 ; EXT_HMCREF.2 50.7,275.2 ; EXT_HMCREF.2 48.84,273.34 ; EXT_HMCREF.2 50.7,273.34 ; EXT_HMCREF.2 48.84,275.2 ; 46.14,243.82 J17.4 ; J17.4 46.14,245.67 ; J17.4 48,245.67 ; J17.4 48,243.82 ; GND2.1 201.2,235.65 ; GND2.1 201.2,237.15 ; GND2.1 199.71,237.15 ; GND2.1 199.71,235.65 ; J18.5 68.56,243.92 ; J18.5 66.71,245.77 ; J18.5 66.71,243.92 ; J18.5 68.56,245.77 ; 48.84,280.28 EXT_HMCREF.5 ; EXT_HMCREF.5 50.7,280.28 ; EXT_HMCREF.5 50.7,278.42 ; EXT_HMCREF.5 48.84,278.42 ; 22.88,258.22 J13.5 ; J13.5 22.88,256.36 ; J13.5 24.74,256.36 ; J13.5 24.74,258.22 ; 53.45,220.84 REFCLK.5 ; REFCLK.5 55.31,218.99 ; REFCLK.5 53.45,218.99 ; REFCLK.5 55.31,220.84 ; P18.GND1 5.22,192.3 ; P18.GND1 5.22,190.89 ; P18.GND1 3.82,190.89 ; 5.09,239.85 EXT_SYNC.5 ; EXT_SYNC.5 6.95,239.85 ; EXT_SYNC.5 6.95,241.71 ; EXT_SYNC.5 5.09,241.71 ; P18.GND2 5.22,193.43 ; P18.GND2 3.82,194.84 ; P18.GND2 5.22,194.84 ; P19.GND2 5.07,202.89 ; P19.GND2 5.07,201.48 ; P19.GND2 3.67,202.89 ; 64.57,273.6 REFN.4 ; REFN.4 64.57,275.45 ; REFN.4 66.43,273.6 ; REFN.4 66.43,275.45 ; GND7.1 173.79,81.63 ; GND7.1 173.79,83.17 ; GND7.1 172.26,83.17 ; GND7.1 172.26,81.63 ; 3.67,198.94 P19.GND1 ; P19.GND1 5.07,198.94 ; P19.GND1 5.07,200.35 ; EXT_TRIG.4 12.18,256.45 ; EXT_TRIG.4 10.32,256.45 ; EXT_TRIG.4 12.18,258.31 ; EXT_TRIG.4 10.32,258.31 ; 1.28,193.43 P18.GND3 ; P18.GND3 2.68,194.84 ; P18.GND3 1.28,194.84 ; 196.16,284.75 S4.GND2 ; S4.GND2 198.1,286.7 ; S4.GND2 196.16,286.7 ; S4.GND2 198.1,284.75 ; EXT_SYS_N.4 18.68,273.19 ; EXT_SYS_N.4 16.83,273.19 ; EXT_SYS_N.4 16.83,275.04 ; EXT_SYS_N.4 18.68,275.04 ; 218.85,268.02 P22.6 ; P22.6 220.88,268.02 ; P22.6 218.85,265.99 ; P22.6 220.88,265.99 ; 43.19,263.29 J12.3 ; J12.3 43.19,261.43 ; J12.3 45.05,263.29 ; J12.3 45.05,261.43 ; 1.13,200.35 P19.GND4 ; P19.GND4 2.53,198.94 ; P19.GND4 1.13,198.94 ; EXT_TRIG.3 12.18,263.39 ; EXT_TRIG.3 12.18,261.53 ; EXT_TRIG.3 10.32,263.39 ; EXT_TRIG.3 10.32,261.53 ; J17.3 53.08,243.82 ; J17.3 53.08,245.67 ; J17.3 51.22,243.82 ; J17.3 51.22,245.67 ; 11.75,273.19 EXT_SYS_N.5 ; EXT_SYS_N.5 13.6,275.04 ; EXT_SYS_N.5 13.6,273.19 ; EXT_SYS_N.5 11.75,275.04 ; J18.4 68.56,249 ; J18.4 66.71,250.85 ; J18.4 68.56,250.85 ; J18.4 66.71,249 ; GND4.1 50.73,194.1 ; GND4.1 49.24,195.59 ; GND4.1 50.73,195.59 ; GND4.1 49.24,194.1 ; 43.76,278.42 EXT_HMCREF.4 ; EXT_HMCREF.4 45.62,280.28 ; EXT_HMCREF.4 43.76,280.28 ; EXT_HMCREF.4 45.62,278.42 ; 3.7,62.32 P4.8 ; P4.8 5.76,60.64 ; P4.8 3.7,60.64 ; P4.8 5.76,62.32 ; 61.63,249 J18.3 ; J18.3 63.48,250.85 ; J18.3 61.63,250.85 ; J18.3 63.48,249 ; REFP.5 76.97,275.51 ; REFP.5 75.12,273.65 ; REFP.5 76.97,273.65 ; REFP.5 75.12,275.51 ; 2.81,60.92 P4.6 2.81,62.64 ; 53.45,215.76 REFCLK.2 ; REFCLK.2 55.31,213.91 ; REFCLK.2 55.31,215.76 ; REFCLK.2 53.45,213.91 ; P19.GND3 2.53,202.89 ; P19.GND3 1.13,201.48 ; P19.GND3 1.13,202.89
  TOP w0.178: v1(136.37,244.05) 136.37,244.29 135.81,244.84 R642.1 ; C549.2 201.24,126.57 v2(201.24,126.57) ; v1(93.14,258.39) 93.59,257.95 R816.1 ; v4(201.68,193.36) 201.16,192.84 R507.1 ; 211.12,150.14 210.88,149.89 v3(210.84,149.89) ; C4YB.2 181.12,116.68 v4(181.39,116.68) ; v2(202.31,128.65) 202.31,128.49 C551.2 ; Q9.1 225.55,122.91 v1(225.76,122.71) ; v2(216.66,130.99) 216.32,130.65 C147.2 ; U6.E1 U6.E2 224.65,144.87 v1(224.64,144.86) ; Q9.4 224.46,123.98 v1(224.13,124.31) ; C146.2 218.24,130.84 v2(217.86,131.22) ; v2(203.89,126.95) C550.2
  TOP w0.191: C261.2 125.3,8.23 v4(125.13,8.39) ; U47.8 20.4,100.64 v4(20.15,100.39) ; U45.8 35.23,100.56 v4(34.96,100.83) 35.1,100.96 U45.7 ; U12.10 v4(96.85,6.86) ; U18.10 v4(108.98,6.88) ; U46.8 30.61,100.56 v4(30.38,100.79) 30.55,100.96 U46.7 ; v4(20.09,101.47) 20.53,101.04 U47.7 ; U16.10 v4(114.33,6.96) ; C625.2 194.14,85.33 v4(193.9,85.09) ; U44.8 76.18,83.03 v4(75.98,83.22) 76.19,83.43 U44.7 ; 212.59,126.19 v2(212.7,126.19) 212.81,126.08 C618.2 ; C626.2 v1(196.72,67.46) ; DS3.C v3(236.4,267) ; R632.2 223.32,126.26 v1(223.98,125.6) ; v4(114.1,6.32) 113.94,6.48 R402.2 113.44,6.81 C260.2 ; v4(38.99,99.36) 38.66,99.69 C277.2 ; v2(203.81,128.65) 203.28,128.65 C548.2 ; R403.2 125.55,4.81 124.76,4.02 v4(124.76,3.89) ; U23.7 66.43,44.78 65.74,44.1 65.74,43.92 C678.1 ; R630.1 v1(230.33,124.71) ; v4(15.77,100.25) 16.15,100.63 U48.8 ; C149.2 214.72,127.97 v2(215.01,127.69) ; U22.2 9.71,59.88 v4(9.68,59.92) ; C706.2 227.15,123.52 v1(227.53,123.9) ; 207.18,127.07 v2(207.06,126.95) ; C275.1 v4(23.62,102.21) ; v4(15.65,100.86) 15.82,101.03 U48.7 ; C717.2 210.93,124.61 v2(210.88,124.66) ; U15.10 107.11,6.86 107.19,6.93 107.47,6.93 107.65,7.11 v4(107.75,7.11) ; v2(205.27,124.74) 205.42,124.59 C722.2 ; C721.2 v2(205.55,125.35) ; v4(177.65,60.87) 177.66,60.88 177.94,60.88 177.95,60.87 C624.2 ; U21.2 v4(6.6,59.18) ; C631.2 179.78,55.91 v4(179.77,55.91) ; C690.2 v4(34.71,99.81) ; C274.1 v4(38.43,102.16) ; C683.2 67.48,43.92 67.48,44.1 66.83,44.75 U23.8 ; U13.10 v4(132.51,8.69) ; U14.10 v4(91.19,5.49) ; C627.2 181.56,79.44 v3(181.53,79.46) ; C133.1 v1(84.31,210.11) ; U17.10 v4(127.74,7.98) ; U19.10 v4(121.88,6.27) ; C192.1 C617.1 v3(235.97,100.43) ; C688.1 v4(34.32,102.13) ; v5(111.9,120.13) v5(111.1,120.13)
  TOP w0.197: v1(231.04,197.36) 230.7,197.02 U53.C2
  TOP w0.198: U42.8 61.42,65.99 v4(61.21,66.19) 61.41,66.39 U42.7 ; U27.8 81.03,65.96 80.75,65.68 v4(80.75,65.43) 80.53,65.21 C681.2 ; C638.2 v4(71.55,82.3) ; U29.7 65.88,66.39 v4(65.71,66.22) 65.94,65.99 U29.8 ; U24.7 66.43,40.15 v4(66.6,39.98) 66.83,40.21 U24.8 ; C680.1 80.69,67.15 v4(80.72,67.18) 80.72,67.02 81.23,66.51 U27.7 ; U41.7 67.48,84.22 v4(67.28,84.02) 67.48,83.82 U41.8 ; U28.8 76.81,65.96 76.5,65.66 76.12,65.66 v4(75.92,65.86) 76.42,66.36 U28.7 ; v4(80.42,84.61) 80.39,84.63 80.11,84.63 79.98,84.51 C685.1 ; C687.2 79.98,81.89 v4(79.76,81.66) ; U43.8 80.64,83.03 v4(80.42,83.26) 80.59,83.43 U43.7
  TOP w0.203: C341.2 v3(77.63,127.3) ; C601.1 v1(70.98,209.96) ; C6YA.2 v4(62,122.39) ; C257.2 136.45,6.39 C258.2 v4(136.47,6.98) ; C7XA.2 v4(62.49,135.93) ; C7XB.2 v4(181.84,136.69) ; C3XA.2 v4(63.07,139.15) ; C689.1 v4(19.46,102.21) ; C4YA.2 v4(62.18,121.66) ; C3XB.2 v4(182.37,133.41) ; C7WA.2 v4(68.28,152.03) ; C3YB.2 181.73,119.67 v4(181.91,119.67) ; C2WB.2 v3(165.33,151.19) ; 100.75,144.32 C669.2 C670.2 C671.2 100.75,146.64 ; C6XA.2 v4(62.33,135.17) ; C634.2 v4(226.11,167.92) ; C2YA.2 v3(73.18,116.63) ; C362.2 v3(167.36,127.32) ; v1(186.74,226.49) 187.98,226.49 C712.2 ; C3YA.2 v4(62.66,118.63) ; C6YB.2 v4(182.04,120.18) ; C3WB.2 v4(175.39,152.97) ; C2YB.2 v3(171.42,116.65) ; C1ZA.2 v3(74.96,111.81) ; C357.2 v3(165.33,138.49) ; v1(200.34,96.84) 200.31,96.87 C623.2 ; C1YA.2 v3(71.78,125.02) ; C336.2 v3(79.15,138.61) ; C633.2 v4(228.75,168.33) ; C1ZB.2 v3(169.64,111.95) ; C608.1 v3(198.86,277.89) ; v1(187.02,219.15) 187.02,218.98 C711.2 ; C2XB.2 v3(172.95,130.36) ; C2ZA.2 v3(79.28,104.19) ; R64.2 v3(194.03,264.9) ; C7YB.2 180.92,116.14 v4(181.35,116.14) ; C4WB.2 v4(177.34,149.67) ; C639.1 v4(193.8,260.96) ; C3WA.2 v4(69.8,154.93) ; R487.1 v4(195.61,256.54) ; C3ZA.2 v4(68.58,102.7) ; C2WA.2 v3(74.96,143.56) ; C636.2 v4(77.06,102.44) ; C6ZA.2 v4(67.01,105.45) ; C4WA.2 v4(70.18,155.54) ; R529.1 v4(193.8,262.23) ; 78.97,115.39 v3(79.66,115.75) ; C367.2 v3(164.56,116.01) ; 102.73,146.73 C675.2 C676.2 C677.2 102.73,144.19 ; C1XA.2 v3(73.31,138.73) ; C2XA.2 v3(71.78,130.22) ; C136.1 219.04,257.73 v3(218.96,257.81) ; C6WA.2 v4(67.92,151.37) ; C1WA.2 v3(79.4,150.92) ; DS16.C v4(196.01,266.47) ; C7ZA.2 v4(68.89,101.99) ; C2ZB.2 v3(165.45,104.46) ; C4XA.2 v4(63.25,139.89) ; C1YB.2 v1(172.97,125.23) ; C1WB.2 v3(169.64,143.7) ; C7WB.2 v4(177.62,149.14) ; C4ZA.2 v4(66.6,106.13) ; R538.2 168.67,38.07 ; C6XB.2 v4(181.66,137.22) ; C278.2 v4(23.62,99.31) ; C6WB.2 v4(175.49,152.46) ; C4XB.2 v4(182.52,132.9) ; U25.7 48.72,82.34 v4(48.84,82.22) 49.12,82.5 U25.8 ; C1XB.2 v3(171.42,138.87) ; C7YA.2 v4(62.79,117.89)
  TOP w0.254: v3(14.45,76.8) 14.09,76.8 13.95,76.93 U35.15 ; v3(14.45,76.8) v3(14.45,79.35) ; v3(14.45,76.8) v3(14.45,73.89) 13.81,73.89 13.8,73.9 12.73,73.9 12.7,73.93 U35.21 ; C250.2 101.17,7.26 v4(101.17,7.8) ; v1(220.33,185.27) 219.94,184.87 U32.J7 ; U32.G4 221.56,187.25 v1(221.96,187.64) ; v1(224.33,186.87) 223.94,186.47 U32.D5 ; v4(89.53,8.81) C254.2 90.24,8.81 R398.2 90.2,9.75 v4(90.2,10.62) ; v3(17.76,79.3) 17.82,79.3 17.95,79.43 U35.39 ; U21.2 7.76,59.18 ; v1(221.12,188.44) 220.74,188.06 U32.H3 ; v1(221.96,188.44) 221.56,188.05 U32.G3 ; C271.2 v4(84.18,64.16) ; 20.54,74.43 20.58,74.39 v3(20.58,73.94) ; 20.54,74.43 U35.29 ; 20.54,74.43 20.54,74.68 20.28,74.93 U35.30 ; C266.1 v4(47.47,85.8) ; C683.2 v4(68.1,43.81) ; JP2.1 v3(42.37,104.52) ; v1(221.13,185.27) 220.75,185.65 U32.H6 ; v1(221.13,185.27) 220.74,184.87 U32.H7 ; v1(221.13,185.27) 221.54,184.86 U32.G7 ; v1(221.13,185.27) 221.51,185.65 U32.G6 ; U35.33 v4(20.57,76.43) ; v4(20.57,76.43) 20.07,76.93 U35.34 ; v4(20.57,76.43) 20.07,75.93 U35.32 ; v4(20.57,76.43) 21.13,76.43 21.23,76.53 22.76,76.53 23.06,76.23 C605.2 ; v4(119.35,9.12) 119.35,8.62 R400.2 ; C281.2 v4(59.5,234.87) ; C682.2 v4(50.29,81.69) ; C251.2 133.6,4.11 133.6,4.04 v4(133.61,4.04) ; U32.J6 v1(220.33,186.04) 219.94,186.44 U32.J5 ; v1(222.73,186.87) 223.11,187.25 U32.E4 223.14,187.27 v1(223.53,187.67) 223.91,188.05 U32.D3 ; U32.J4 219.94,187.27 v1(220.33,187.67) ; C141.2 v4(106.93,14.6) ; v1(223.47,188.37) 223.15,188.05 U32.E3 ; U1.D2 223.41,101.22 v4(223.1,101.52) ; C679.1 v4(47.57,81.69) ; 219.53,186.06 219.14,186.45 U32.K5 ; v1(218.72,186.86) 218.34,186.47 U32.L5 ; R396.2 101.55,6.45 v4(101.55,5.61) ; U32.F3 v1(222.73,188.44) ; U32.B4 225.53,187.25 v1(225.12,187.66) 224.74,188.04 U32.C3 ; U32.E2 223.13,188.85 v1(222.73,189.24) U32.F2 ; U32.M4 217.54,187.4 v1(217.28,187.66) ; U32.F4 v1(222.73,187.64) ; U26.7 48.73,77.89 v4(48.89,77.72) 49.13,77.96 U26.8 ; v1(218.73,187.66) 218.34,187.26 U32.L4 ; C276.2 v4(84.1,81.71) ; v4(65.91,48.51) 65.63,48.23 C265.1 ; 221.95,189.23 221.56,188.85 U32.G2 U32.H2 ; v1(223.53,186.87) 223.56,186.87 U32.D4 223.94,187.26 v1(224.33,187.66) U32.C4 ; U35.28 20.57,73.93 v3(20.58,73.94) ; v1(222.73,186.22) 222.96,186.45 U32.E5 ; 107.59,238.68 107.59,239.4 v1(108.25,240.06) ; C678.1 v4(65.13,43.81) ; JP1.1 v3(11.63,95.41) ; U32.B3 225.31,188.28 v1(225.13,188.28) ; v3(14.45,79.35) 13.81,79.35 13.77,79.39 12.51,79.39 12.5,79.4 11.57,79.4 U35.10 ; v3(14.45,79.35) v3(14.45,82.54) 13.81,82.54 13.7,82.43 U35.4 ; DS1.C 25.3,216.18 v4(25.53,216.41) ; U32.K4 219.14,187.26 v1(219.53,187.66) ; U32.M3 217.55,188.05 v1(217.93,187.67) 218.31,188.05 U32.L3 ; 20.58,73.41 20.55,73.43 U35.27 ; 20.58,73.41 20.58,73.19 20.32,72.93 U35.26 ; 20.58,73.41 v3(20.58,73.94) ; C270.2 v4(50.47,85.8) ; R397.2 v4(132.82,3.63) ; U32.F5 U32.G5 221.51,186.45 v1(221.11,186.04) 220.74,186.41 U32.H5 ; R399.2 v4(102.24,7.26) ; C256.2 v4(102.74,6.45) ; U32.H4 v1(221.13,187.64) ; U32.C5 v1(225.13,186.84) ; C267.1 v4(84.18,67.67) ; v3(17.68,82.43) U35.45 ; v1(217.93,186.87) 217.54,186.47 U32.M5 ; U32.E1 223.14,189.73 v1(222.72,190.14) 222.34,189.76 U32.F1 ; JP1.2 v3(11.63,92.41) ; C269.2 v4(68.28,47.93) ; C273.1 v4(84.1,84.68) ; C686.2 v4(65.3,64.74) ; C272.2 v4(69.42,64.67) ; v4(53.29,40.41) 52.65,41.05 P2.16 ; v3(95.77,278.39) 95.73,278.36 R797.2 94.14,278.36 C847.2 ; 168.16,262.82 R757.1 ; JP2.2 v3(42.37,101.85) ; U20.7 100.66,13.1 99.35,11.8 U20.4 97.27,11.8 96.85,11.38 95.96,11.38 95.49,11.85 R161.2 95.49,13.54 95.23,13.79 v4(95.15,13.79) ; R401.2 128.24,3.65 v4(128.24,3.48) ; C268.1 v4(69.42,67.67) ; C435.2 v3(100.61,136.65) ; C684.1 v4(65.3,67.74) ; C308.2 52.14,235.55 C307.2 v4(51.39,235.5) ; C637.1 v4(71.55,85.24)
  TOP w0.381: R736.2 v3(8.7,186.82) ; v3(13.02,187.6) 13.05,187.57 R738.2 ; R737.2 v3(11.39,186.82) ; R739.2 v3(16.32,186.89)
  TOP w0.508: v4(15.09,54.69) 15.09,55.6 C144.2 ; S2.2B v3(161.09,90.96) S2.2A ; v4(43.54,67.72) 44.42,66.83 P3.9 ; P3.19 42.89,60.48 v4(42.6,60.19) R163.2 ; P3.3 44.09,70.64 v4(43.55,70.09) 44.27,69.37 P3.5 ; C606.1 186.39,217.53 v1(186.21,217.35) 185.9,217.04 C320.1 ; v3(221.06,219.65) Q17.2 v3(219.61,221.01) ; R334.2 v3(219.3,217.73) ; v3(8.41,53.95) C224.2 C142.2 C222.2 ; P3.15 44.35,63.02 v4(43.13,64.24) ; v3(235.14,119.57) 235.28,119.43 v1(238.06,119.43) ; C225.2 v3(7.6,56.7) ; DS27.C DS26.C DS25.C DS24.C DS23.C DS21.C DS20.C DS22.C DS19.C 4.6,74.36 DS18.C 4.6,72.34 v3(3.78,71.53) ; R641.1 v1(149.31,245.42) ; R637.2 23.26,89.15 v3(23.6,89.48) ; S1.2A S1.2B v3(12.03,46.95) ; R61.1 218.56,225.65 v3(218.34,225.43) ; R759.1 v1(175.9,263.3) ; DS2.C 101.29,200.61
  L2_GROUND w0.152: J12.3 45.05,263.29 ; J12.3 43.19,261.43 ; J12.3 45.05,261.43 ; J12.3 43.19,263.29 ; 3.7,55.79 P4.9 ; P4.9 3.7,57.47 ; P4.9 5.76,57.47 ; P4.9 5.76,55.79 ; 75.12,278.73 REFP.2 ; REFP.2 76.97,278.73 ; REFP.2 76.97,280.59 ; REFP.2 75.12,280.59 ; 51.22,250.75 J17.2 ; J17.2 53.08,248.9 ; J17.2 51.22,248.9 ; J17.2 53.08,250.75 ; GND8.1 175.73,163.9 ; GND8.1 174.23,163.9 ; GND8.1 175.73,165.39 ; GND8.1 174.23,165.39 ; 64.57,275.45 REFN.4 ; REFN.4 66.43,273.6 ; REFN.4 64.57,273.6 ; REFN.4 66.43,275.45 ; 27.65,280.15 EXT_SYS_P.2 ; EXT_SYS_P.2 29.5,280.15 ; EXT_SYS_P.2 27.65,278.29 ; EXT_SYS_P.2 29.5,278.29 ; 80.2,273.65 REFP.4 ; REFP.4 82.05,275.51 ; REFP.4 82.05,273.65 ; REFP.4 80.2,275.51 ; REFN.2 61.35,280.53 ; REFN.2 61.35,278.68 ; REFN.2 59.49,278.68 ; REFN.2 59.49,280.53 ; 43.76,278.42 EXT_HMCREF.4 ; EXT_HMCREF.4 45.62,278.42 ; EXT_HMCREF.4 43.76,280.28 ; EXT_HMCREF.4 45.62,280.28 ; 199.71,235.65 GND2.1 ; GND2.1 201.2,237.15 ; GND2.1 199.71,237.15 ; GND2.1 201.2,235.65 ; 1.13,201.48 P19.GND3 ; P19.GND3 2.53,202.89 ; P19.GND3 1.13,202.89 ; REFCLK.5 55.31,218.99 ; REFCLK.5 55.31,220.84 ; REFCLK.5 53.45,220.84 ; REFCLK.5 53.45,218.99 ; 5.09,239.85 EXT_SYNC.5 ; EXT_SYNC.5 6.95,239.85 ; EXT_SYNC.5 5.09,241.71 ; EXT_SYNC.5 6.95,241.71 ; 196.16,286.7 S4.GND2 ; S4.GND2 196.16,284.75 ; S4.GND2 198.1,286.7 ; S4.GND2 198.1,284.75 ; 5.09,246.79 EXT_SYNC.2 ; EXT_SYNC.2 6.95,244.93 ; EXT_SYNC.2 5.09,244.93 ; EXT_SYNC.2 6.95,246.79 ; REFP.3 82.05,278.73 ; REFP.3 80.2,278.73 ; REFP.3 80.2,280.59 ; REFP.3 82.05,280.59 ; J12.4 45.05,256.35 ; J12.4 45.05,258.21 ; J12.4 43.19,258.21 ; J12.4 43.19,256.35 ; 61.63,243.92 J18.2 ; J18.2 63.48,245.77 ; J18.2 63.48,243.92 ; J18.2 61.63,245.77 ; 10.17,241.71 EXT_SYNC.4 ; EXT_SYNC.4 10.17,239.85 ; EXT_SYNC.4 12.03,239.85 ; EXT_SYNC.4 12.03,241.71 ; 3.7,60.64 P4.8 ; P4.8 5.76,60.64 ; P4.8 5.76,62.32 ; P4.8 3.7,62.32 ; EXT_TRIG.4 12.18,256.45 ; EXT_TRIG.4 10.32,258.31 ; EXT_TRIG.4 12.18,258.31 ; EXT_TRIG.4 10.32,256.45 ; 66.71,250.85 J18.4 ; J18.4 68.56,249 ; J18.4 68.56,250.85 ; J18.4 66.71,249 ; 11.75,278.27 EXT_SYS_N.2 ; EXT_SYS_N.2 13.6,278.27 ; EXT_SYS_N.2 13.6,280.12 ; EXT_SYS_N.2 11.75,280.12 ; P18.GND2 5.22,193.43 ; P18.GND2 5.22,194.84 ; P18.GND2 3.82,194.84 ; 1.28,194.84 P18.GND3 ; P18.GND3 2.68,194.84 ; P18.GND3 1.28,193.43 ; 57.06,261.73 GND3.1 ; GND3.1 58.56,261.73 ; GND3.1 57.06,260.24 ; GND3.1 58.56,260.24 ; 3.57,48.23 GND5.1 ; GND5.1 3.57,49.77 ; GND5.1 5.11,49.77 ; GND5.1 5.11,48.23 ; 48.37,220.84 REFCLK.4 ; REFCLK.4 48.37,218.99 ; REFCLK.4 50.23,218.99 ; REFCLK.4 50.23,220.84 ; REFN.3 66.43,278.68 ; REFN.3 66.43,280.53 ; REFN.3 64.57,280.53 ; REFN.3 64.57,278.68 ; EXT_HMCREF.5 50.7,280.28 ; EXT_HMCREF.5 48.84,280.28 ; EXT_HMCREF.5 50.7,278.42 ; EXT_HMCREF.5 48.84,278.42 ; 1.13,200.35 P19.GND4 ; P19.GND4 2.53,198.94 ; P19.GND4 1.13,198.94 ; REFCLK.3 50.23,215.76 ; REFCLK.3 50.23,213.91 ; REFCLK.3 48.37,213.91 ; REFCLK.3 48.37,215.76 ; 61.63,249 J18.3 ; J18.3 63.48,249 ; J18.3 63.48,250.85 ; J18.3 61.63,250.85 ; 66.71,245.77 J18.5 ; J18.5 66.71,243.92 ; J18.5 68.56,245.77 ; J18.5 68.56,243.92 ; 51.22,243.82 J17.3 ; J17.3 53.08,243.82 ; J17.3 51.22,245.67 ; J17.3 53.08,245.67 ; 53.45,215.76 REFCLK.2 ; REFCLK.2 55.31,215.76 ; REFCLK.2 53.45,213.91 ; REFCLK.2 55.31,213.91 ; EXT_SYS_P.3 34.58,280.15 ; EXT_SYS_P.3 34.58,278.29 ; EXT_SYS_P.3 32.73,278.29 ; EXT_SYS_P.3 32.73,280.15 ; J13.5 24.74,258.22 ; J13.5 24.74,256.36 ; J13.5 22.88,256.36 ; J13.5 22.88,258.22 ; EXT_SYS_N.3 18.68,278.27 ; EXT_SYS_N.3 18.68,280.12 ; EXT_SYS_N.3 16.83,280.12 ; EXT_SYS_N.3 16.83,278.27 ; GND1.1 10.04,101.73 ; GND1.1 10.04,100.2 ; GND1.1 8.5,101.73 ; GND1.1 8.5,100.2 ; REFP.5 76.97,273.65 ; REFP.5 75.12,273.65 ; REFP.5 76.97,275.51 ; REFP.5 75.12,275.51 ; 48.84,275.2 EXT_HMCREF.2 ; EXT_HMCREF.2 48.84,273.34 ; EXT_HMCREF.2 50.7,273.34 ; EXT_HMCREF.2 50.7,275.2 ; 46.14,245.67 J17.4 ; J17.4 48,245.67 ; J17.4 46.14,243.82 ; J17.4 48,243.82 ; P19.GND1 5.07,198.94 ; P19.GND1 3.67,198.94 ; P19.GND1 5.07,200.35 ; 16.83,275.04 EXT_SYS_N.4 ; EXT_SYS_N.4 18.68,275.04 ; EXT_SYS_N.4 16.83,273.19 ; EXT_SYS_N.4 18.68,273.19 ; S4.GND1 184.89,286.7 ; S4.GND1 182.95,286.7 ; S4.GND1 184.89,284.75 ; S4.GND1 182.95,284.75 ; REFN.5 61.35,273.6 ; REFN.5 61.35,275.45 ; REFN.5 59.49,273.6 ; REFN.5 59.49,275.45 ; 27.96,258.22 J13.4 ; J13.4 29.82,256.36 ; J13.4 27.96,256.36 ; J13.4 29.82,258.22 ; 5.24,256.45 EXT_TRIG.5 ; EXT_TRIG.5 7.1,258.31 ; EXT_TRIG.5 5.24,258.31 ; EXT_TRIG.5 7.1,256.45 ; 49.24,194.1 GND4.1 ; GND4.1 50.73,194.1 ; GND4.1 49.24,195.59 ; GND4.1 50.73,195.59 ; 10.32,263.39 EXT_TRIG.3 ; EXT_TRIG.3 12.18,261.53 ; EXT_TRIG.3 10.32,261.53 ; EXT_TRIG.3 12.18,263.39 ; J13.2 24.74,261.44 ; J13.2 22.88,261.44 ; J13.2 22.88,263.3 ; J13.2 24.74,263.3 ; EXT_HMCREF.3 45.62,275.2 ; EXT_HMCREF.3 43.76,273.34 ; EXT_HMCREF.3 45.62,273.34 ; EXT_HMCREF.3 43.76,275.2 ; 2.81,55.47 P4.7 2.81,57.19 ; EXT_TRIG.2 7.1,261.53 ; EXT_TRIG.2 7.1,263.39 ; EXT_TRIG.2 5.24,261.53 ; EXT_TRIG.2 5.24,263.39 ; 11.75,275.04 EXT_SYS_N.5 ; EXT_SYS_N.5 13.6,275.04 ; EXT_SYS_N.5 13.6,273.19 ; EXT_SYS_N.5 11.75,273.19 ; P19.GND2 5.07,202.89 ; P19.GND2 5.07,201.48 ; P19.GND2 3.67,202.89 ; 27.65,273.21 EXT_SYS_P.5 ; EXT_SYS_P.5 29.5,273.21 ; EXT_SYS_P.5 29.5,275.07 ; EXT_SYS_P.5 27.65,275.07 ; 3.82,190.89 P18.GND1 ; P18.GND1 5.22,192.3 ; P18.GND1 5.22,190.89 ; GND6.1 218.83,38.84 ; GND6.1 217.29,38.84 ; GND6.1 218.83,37.3 ; GND6.1 217.29,37.3 ; 38.11,263.29 J12.2 ; J12.2 39.97,261.43 ; J12.2 39.97,263.29 ; J12.2 38.11,261.43 ; 32.73,273.21 EXT_SYS_P.4 ; EXT_SYS_P.4 34.58,275.07 ; EXT_SYS_P.4 32.73,275.07 ; EXT_SYS_P.4 34.58,273.21 ; P22.3 220.88,271.5 ; P22.3 218.85,271.5 ; P22.3 218.85,273.53 ; P22.3 220.88,273.53 ; 1.28,192.3 P18.GND4 ; P18.GND4 2.68,190.89 ; P18.GND4 1.28,190.89 ; 172.26,81.63 GND7.1 ; GND7.1 173.79,83.17 ; GND7.1 172.26,83.17 ; GND7.1 173.79,81.63 ; 2.81,60.92 P4.6 2.81,62.64 ; J17.5 48,250.75 ; J17.5 46.14,250.75 ; J17.5 46.14,248.9 ; J17.5 48,248.9 ; 218.85,265.99 P22.6 ; P22.6 218.85,268.02 ; P22.6 220.88,265.99 ; P22.6 220.88,268.02 ; 38.11,256.35 J12.5 ; J12.5 39.97,256.35 ; J12.5 38.11,258.21 ; J12.5 39.97,258.21 ; J13.3 29.82,261.44 ; J13.3 29.82,263.3 ; J13.3 27.96,261.44 ; J13.3 27.96,263.3 ; EXT_SYNC.3 12.03,246.79 ; EXT_SYNC.3 12.03,244.93 ; EXT_SYNC.3 10.17,246.79 ; EXT_SYNC.3 10.17,244.93
  L2_GROUND w0.178: v7(176.41,103.16) v7(176.74,102.95) v7(177.07,102.77) v7(177.39,102.56) v7(177.72,102.38) v7(178.05,102.17) v7(178.38,102) v7(178.71,101.79) v7(179.04,101.61) v7(179.36,101.4) v7(179.69,101.22) v7(180.02,101.01) v7(180.35,100.84) ; v7(64.04,100.4) v7(64.36,100.6) v7(64.71,100.78) v7(65.03,100.97) v7(65.37,101.15) v7(65.69,101.35) v7(66.03,101.53) v7(66.35,101.72) v7(66.7,101.91) v7(67.01,102.1) v7(67.36,102.28) v7(67.68,102.48) v7(68.02,102.66) ; v7(62.77,102.69) v7(63.09,102.88) v7(63.44,103.06) v7(63.76,103.26) v7(64.1,103.44) v7(64.42,103.64) v7(64.76,103.82) v7(65.08,104.01) v7(65.43,104.19) v7(65.74,104.39) v7(66.09,104.57) v7(66.41,104.76) v7(66.75,104.94) ; v7(175.19,100.87) v7(175.52,100.66) v7(175.85,100.48) v7(176.18,100.27) v7(176.5,100.1) v7(176.83,99.89) v7(177.16,99.71) v7(177.49,99.5) v7(177.82,99.32) v7(178.15,99.11) v7(178.47,98.94) v7(178.8,98.73) v7(179.13,98.55) ; v7(65.49,156.88) v7(65.82,156.68) v7(66.15,156.5) v7(66.48,156.29) v7(66.81,156.12) v7(67.14,155.91) v7(67.47,155.74) v7(67.8,155.53) v7(68.13,155.36) v7(68.46,155.15) v7(68.79,154.98) v7(69.12,154.77) v7(69.45,154.6) ; v7(176.02,152.43) v7(176.37,152.6) v7(176.69,152.79) v7(177.03,152.97) v7(177.35,153.16) v7(177.7,153.34) v7(178.02,153.53) v7(178.37,153.7) v7(178.69,153.9) v7(179.04,154.07) v7(179.36,154.26) v7(179.7,154.44) v7(180.03,154.63) ; v7(181.42,152.37) v7(181.1,152.18) v7(180.75,152) v7(180.43,151.81) v7(180.09,151.64) v7(179.77,151.44) v7(179.42,151.27) v7(179.1,151.08) v7(178.75,150.9) v7(178.43,150.71) v7(178.08,150.53) v7(177.76,150.34) v7(177.42,150.17) ; v7(68.05,152.56) v7(67.73,152.74) v7(67.4,152.94) v7(67.07,153.12) v7(66.74,153.33) v7(66.41,153.5) v7(66.08,153.71) v7(65.75,153.88) v7(65.42,154.09) v7(65.09,154.26) v7(64.76,154.47) v7(64.43,154.64) v7(64.1,154.85)
  L2_GROUND w0.191: 110.26,139.09 v7(109.65,139.09) ; 109.73,138.46 v7(109.3,138.46)
  L2_GROUND w0.203: v7(62.13,136.31) 62.08,136.36 v7(61.76,136.36) 61.68,136.44 v7(61.38,136.44) 61.33,136.48 v7(61,136.48) 60.93,136.56 v7(60.62,136.56) 60.58,136.61 v7(60.25,136.61) 60.18,136.69 v7(59.87,136.69) 59.82,136.73 v7(59.5,136.73) 59.42,136.81 v7(59.12,136.81) 59.07,136.86 v7(58.75,136.86) 58.67,136.93 v7(58.37,136.93) 58.32,136.98 v7(58,136.98) 57.92,137.06 v7(57.62,137.06) ; v7(187.22,134.72) 186.94,134.72 v7(186.86,134.64) 186.53,134.64 v7(186.47,134.58) 186.19,134.58 v7(186.11,134.5) 185.78,134.5 v7(185.72,134.44) 185.44,134.44 v7(185.36,134.36) 185.3,134.3 v7(184.98,134.3) 184.89,134.22 v7(184.61,134.22) 184.55,134.16 v7(184.23,134.16) 184.14,134.08 v7(183.86,134.08) 183.8,134.02 v7(183.48,134.02) 183.4,133.94 v7(183.11,133.94) 183.05,133.88 v7(182.73,133.88) ; v7(186.66,137.23) 186.38,137.23 v7(186.3,137.15) 185.97,137.15 v7(185.91,137.09) 185.63,137.09 v7(185.55,137.01) 185.22,137.01 v7(185.17,136.95) 184.88,136.95 v7(184.8,136.87) 184.48,136.87 v7(184.42,136.81) 184.34,136.73 v7(184.05,136.73) 183.99,136.67 v7(183.67,136.67) 183.59,136.59 v7(183.3,136.59) 183.24,136.53 v7(182.92,136.53) 182.84,136.45 v7(182.55,136.45) 182.49,136.39 v7(182.17,136.39) ; v7(62.63,138.85) 62.59,138.9 v7(62.26,138.9) 62.19,138.98 v7(61.88,138.98) 61.84,139.02 v7(61.51,139.02) 61.44,139.1 v7(61.13,139.1) 61.08,139.15 v7(60.76,139.15) 60.68,139.23 v7(60.38,139.23) 60.06,139.23 v7(60.01,139.27) 59.93,139.35 v7(59.63,139.35) 59.58,139.4 v7(59.26,139.4) 59.18,139.47 v7(58.88,139.47) 58.83,139.52 v7(58.51,139.52) 58.43,139.6 v7(58.12,139.6) ; v7(57.85,118.27) 58.14,118.27 v7(58.21,118.34) 58.55,118.34 v7(58.6,118.39) 58.89,118.39 v7(58.97,118.46) 59.3,118.46 v7(59.35,118.51) 59.65,118.51 v7(59.72,118.58) 60.05,118.58 v7(60.1,118.63) 60.4,118.63 v7(60.47,118.7) 60.81,118.7 v7(60.86,118.75) 61.15,118.75 v7(61.22,118.82) 61.56,118.82 v7(61.61,118.87) 61.68,118.95 v7(61.97,118.95) 62.02,118.99 v7(62.36,118.99) ; v7(57.21,120.81) 57.28,120.88 v7(57.58,120.88) 57.63,120.93 v7(57.96,120.93) 58.04,121 v7(58.33,121) 58.38,121.05 v7(58.72,121.05) 58.79,121.12 v7(59.08,121.12) 59.13,121.17 v7(59.47,121.17) 59.54,121.24 v7(59.84,121.24) 59.88,121.29 v7(60.22,121.29) 60.29,121.36 v7(60.59,121.36) 60.64,121.41 v7(60.97,121.41) 61.05,121.49 v7(61.34,121.49) 61.39,121.53 v7(61.73,121.53) ; v7(182.26,119.23) 182.57,119.23 v7(182.65,119.15) 182.97,119.15 v7(183.02,119.1) 183.32,119.1 v7(183.4,119.03) 183.72,119.03 v7(183.77,118.98) 184.07,118.98 v7(184.15,118.9) 184.47,118.9 v7(184.52,118.85) 184.82,118.85 v7(184.9,118.77) 185.22,118.77 v7(185.27,118.72) 185.57,118.72 v7(185.65,118.65) 185.97,118.65 v7(186.02,118.6) 186.33,118.6 v7(186.4,118.52) 186.72,118.52 v7(186.77,118.47) ; v7(186.44,115.88) 186.12,115.88 v7(186.07,115.93) 185.77,115.93 v7(185.69,116.01) 185.37,116.01 v7(185.32,116.06) 185.02,116.06 v7(184.94,116.13) 184.62,116.13 v7(184.57,116.18) 184.27,116.18 v7(184.19,116.26) 183.87,116.26 v7(183.82,116.31) 183.51,116.31 v7(183.44,116.39) 183.12,116.39 v7(183.07,116.44) 182.76,116.44 v7(182.69,116.51) 182.36,116.51 v7(182.32,116.56) 182.01,116.56 v7(181.93,116.64)
  L3_SIGNAL w0.152: EXT_TRIG.3 12.18,263.39 ; EXT_TRIG.3 12.18,261.53 ; EXT_TRIG.3 10.32,261.53 ; EXT_TRIG.3 10.32,263.39 ; EXT_TRIG.5 7.1,256.45 ; EXT_TRIG.5 5.24,258.31 ; EXT_TRIG.5 7.1,258.31 ; EXT_TRIG.5 5.24,256.45 ; REFCLK.4 50.23,218.99 ; REFCLK.4 48.37,218.99 ; REFCLK.4 50.23,220.84 ; REFCLK.4 48.37,220.84 ; 80.2,278.73 REFP.3 ; REFP.3 80.2,280.59 ; REFP.3 82.05,278.73 ; REFP.3 82.05,280.59 ; J12.2 39.97,263.29 ; J12.2 38.11,263.29 ; J12.2 38.11,261.43 ; J12.2 39.97,261.43 ; 218.85,265.99 P22.6 ; P22.6 220.88,265.99 ; P22.6 218.85,268.02 ; P22.6 220.88,268.02 ; 49.24,194.1 GND4.1 ; GND4.1 49.24,195.59 ; GND4.1 50.73,194.1 ; GND4.1 50.73,195.59 ; P19.GND2 5.07,202.89 ; P19.GND2 5.07,201.48 ; P19.GND2 3.67,202.89 ; 51.22,243.82 J17.3 ; J17.3 53.08,243.82 ; J17.3 53.08,245.67 ; J17.3 51.22,245.67 ; 48.37,213.91 REFCLK.3 ; REFCLK.3 50.23,213.91 ; REFCLK.3 50.23,215.76 ; REFCLK.3 48.37,215.76 ; EXT_SYS_N.4 18.68,275.04 ; EXT_SYS_N.4 16.83,273.19 ; EXT_SYS_N.4 18.68,273.19 ; EXT_SYS_N.4 16.83,275.04 ; 59.49,275.45 REFN.5 ; REFN.5 59.49,273.6 ; REFN.5 61.35,273.6 ; REFN.5 61.35,275.45 ; 22.88,261.44 J13.2 ; J13.2 24.74,261.44 ; J13.2 22.88,263.3 ; J13.2 24.74,263.3 ; 66.71,243.92 J18.5 ; J18.5 68.56,243.92 ; J18.5 68.56,245.77 ; J18.5 66.71,245.77 ; EXT_TRIG.4 12.18,256.45 ; EXT_TRIG.4 12.18,258.31 ; EXT_TRIG.4 10.32,258.31 ; EXT_TRIG.4 10.32,256.45 ; 199.71,237.15 GND2.1 ; GND2.1 199.71,235.65 ; GND2.1 201.2,235.65 ; GND2.1 201.2,237.15 ; 3.82,194.84 P18.GND2 ; P18.GND2 5.22,194.84 ; P18.GND2 5.22,193.43 ; 64.57,280.53 REFN.3 ; REFN.3 64.57,278.68 ; REFN.3 66.43,280.53 ; REFN.3 66.43,278.68 ; 32.73,273.21 EXT_SYS_P.4 ; EXT_SYS_P.4 32.73,275.07 ; EXT_SYS_P.4 34.58,275.07 ; EXT_SYS_P.4 34.58,273.21 ; 38.11,256.35 J12.5 ; J12.5 39.97,258.21 ; J12.5 38.11,258.21 ; J12.5 39.97,256.35 ; 5.09,241.71 EXT_SYNC.5 ; EXT_SYNC.5 6.95,239.85 ; EXT_SYNC.5 6.95,241.71 ; EXT_SYNC.5 5.09,239.85 ; J12.4 45.05,258.21 ; J12.4 43.19,256.35 ; J12.4 45.05,256.35 ; J12.4 43.19,258.21 ; 61.63,243.92 J18.2 ; J18.2 63.48,243.92 ; J18.2 63.48,245.77 ; J18.2 61.63,245.77 ; 182.95,284.75 S4.GND1 ; S4.GND1 184.89,284.75 ; S4.GND1 184.89,286.7 ; S4.GND1 182.95,286.7 ; P22.3 220.88,273.53 ; P22.3 218.85,273.53 ; P22.3 220.88,271.5 ; P22.3 218.85,271.5 ; 1.28,192.3 P18.GND4 ; P18.GND4 1.28,190.89 ; P18.GND4 2.68,190.89 ; 27.65,278.29 EXT_SYS_P.2 ; EXT_SYS_P.2 27.65,280.15 ; EXT_SYS_P.2 29.5,278.29 ; EXT_SYS_P.2 29.5,280.15 ; 27.96,261.44 J13.3 ; J13.3 29.82,263.3 ; J13.3 27.96,263.3 ; J13.3 29.82,261.44 ; 27.65,273.21 EXT_SYS_P.5 ; EXT_SYS_P.5 29.5,275.07 ; EXT_SYS_P.5 27.65,275.07 ; EXT_SYS_P.5 29.5,273.21 ; EXT_HMCREF.4 45.62,278.42 ; EXT_HMCREF.4 43.76,280.28 ; EXT_HMCREF.4 45.62,280.28 ; EXT_HMCREF.4 43.76,278.42 ; EXT_SYS_N.5 13.6,275.04 ; EXT_SYS_N.5 11.75,275.04 ; EXT_SYS_N.5 11.75,273.19 ; EXT_SYS_N.5 13.6,273.19 ; 10.17,244.93 EXT_SYNC.3 ; EXT_SYNC.3 10.17,246.79 ; EXT_SYNC.3 12.03,244.93 ; EXT_SYNC.3 12.03,246.79 ; GND3.1 58.56,260.24 ; GND3.1 57.06,261.73 ; GND3.1 58.56,261.73 ; GND3.1 57.06,260.24 ; REFP.5 76.97,273.65 ; REFP.5 75.12,275.51 ; REFP.5 75.12,273.65 ; REFP.5 76.97,275.51 ; J17.5 48,248.9 ; J17.5 48,250.75 ; J17.5 46.14,248.9 ; J17.5 46.14,250.75 ; 5.24,261.53 EXT_TRIG.2 ; EXT_TRIG.2 5.24,263.39 ; EXT_TRIG.2 7.1,261.53 ; EXT_TRIG.2 7.1,263.39 ; REFCLK.2 55.31,215.76 ; REFCLK.2 53.45,213.91 ; REFCLK.2 53.45,215.76 ; REFCLK.2 55.31,213.91 ; REFN.4 66.43,273.6 ; REFN.4 66.43,275.45 ; REFN.4 64.57,273.6 ; REFN.4 64.57,275.45 ; J13.4 29.82,256.36 ; J13.4 27.96,256.36 ; J13.4 29.82,258.22 ; J13.4 27.96,258.22 ; 43.19,263.29 J12.3 ; J12.3 45.05,261.43 ; J12.3 43.19,261.43 ; J12.3 45.05,263.29 ; 59.49,278.68 REFN.2 ; REFN.2 61.35,278.68 ; REFN.2 61.35,280.53 ; REFN.2 59.49,280.53 ; EXT_HMCREF.5 50.7,280.28 ; EXT_HMCREF.5 48.84,280.28 ; EXT_HMCREF.5 48.84,278.42 ; EXT_HMCREF.5 50.7,278.42 ; EXT_SYNC.2 6.95,246.79 ; EXT_SYNC.2 6.95,244.93 ; EXT_SYNC.2 5.09,246.79 ; EXT_SYNC.2 5.09,244.93 ; 66.71,249 J18.4 ; J18.4 66.71,250.85 ; J18.4 68.56,249 ; J18.4 68.56,250.85 ; P19.GND4 2.53,198.94 ; P19.GND4 1.13,200.35 ; P19.GND4 1.13,198.94 ; EXT_HMCREF.3 45.62,275.2 ; EXT_HMCREF.3 45.62,273.34 ; EXT_HMCREF.3 43.76,273.34 ; EXT_HMCREF.3 43.76,275.2 ; 16.83,278.27 EXT_SYS_N.3 ; EXT_SYS_N.3 18.68,280.12 ; EXT_SYS_N.3 16.83,280.12 ; EXT_SYS_N.3 18.68,278.27 ; J17.4 48,245.67 ; J17.4 48,243.82 ; J17.4 46.14,245.67 ; J17.4 46.14,243.82 ; 3.67,198.94 P19.GND1 ; P19.GND1 5.07,200.35 ; P19.GND1 5.07,198.94 ; EXT_HMCREF.2 50.7,273.34 ; EXT_HMCREF.2 50.7,275.2 ; EXT_HMCREF.2 48.84,273.34 ; EXT_HMCREF.2 48.84,275.2 ; 10.17,241.71 EXT_SYNC.4 ; EXT_SYNC.4 10.17,239.85 ; EXT_SYNC.4 12.03,239.85 ; EXT_SYNC.4 12.03,241.71 ; 53.45,220.84 REFCLK.5 ; REFCLK.5 53.45,218.99 ; REFCLK.5 55.31,218.99 ; REFCLK.5 55.31,220.84 ; 3.82,190.89 P18.GND1 ; P18.GND1 5.22,190.89 ; P18.GND1 5.22,192.3 ; 80.2,273.65 REFP.4 ; REFP.4 82.05,275.51 ; REFP.4 80.2,275.51 ; REFP.4 82.05,273.65 ; 11.75,278.27 EXT_SYS_N.2 ; EXT_SYS_N.2 11.75,280.12 ; EXT_SYS_N.2 13.6,278.27 ; EXT_SYS_N.2 13.6,280.12 ; REFP.2 76.97,278.73 ; REFP.2 76.97,280.59 ; REFP.2 75.12,280.59 ; REFP.2 75.12,278.73 ; EXT_SYS_P.3 34.58,278.29 ; EXT_SYS_P.3 34.58,280.15 ; EXT_SYS_P.3 32.73,280.15 ; EXT_SYS_P.3 32.73,278.29 ; S4.GND2 198.1,284.75 ; S4.GND2 198.1,286.7 ; S4.GND2 196.16,284.75 ; S4.GND2 196.16,286.7 ; 175.73,165.39 GND8.1 174.23,165.39 ; 51.22,248.9 J17.2 ; J17.2 51.22,250.75 ; J17.2 53.08,248.9 ; J17.2 53.08,250.75 ; 22.88,258.22 J13.5 ; J13.5 22.88,256.36 ; J13.5 24.74,256.36 ; J13.5 24.74,258.22 ; 61.63,249 J18.3 ; J18.3 63.48,250.85 ; J18.3 63.48,249 ; J18.3 61.63,250.85 ; 1.13,201.48 P19.GND3 ; P19.GND3 1.13,202.89 ; P19.GND3 2.53,202.89 ; P18.GND3 2.68,194.84 ; P18.GND3 1.28,193.43 ; P18.GND3 1.28,194.84
  L3_SIGNAL w0.203: 218.94,170.09 218.95,170.07
  L4_GROUND w0.152: 218.85,273.53 P22.3 ; P22.3 218.85,271.5 ; P22.3 220.88,271.5 ; P22.3 220.88,273.53 ; 32.73,278.29 EXT_SYS_P.3 ; EXT_SYS_P.3 34.58,280.15 ; EXT_SYS_P.3 34.58,278.29 ; EXT_SYS_P.3 32.73,280.15 ; EXT_SYS_P.4 34.58,273.21 ; EXT_SYS_P.4 32.73,273.21 ; EXT_SYS_P.4 34.58,275.07 ; EXT_SYS_P.4 32.73,275.07 ; 11.75,278.27 EXT_SYS_N.2 ; EXT_SYS_N.2 13.6,278.27 ; EXT_SYS_N.2 11.75,280.12 ; EXT_SYS_N.2 13.6,280.12 ; 27.96,258.22 J13.4 ; J13.4 27.96,256.36 ; J13.4 29.82,256.36 ; J13.4 29.82,258.22 ; 80.2,275.51 REFP.4 ; REFP.4 82.05,273.65 ; REFP.4 82.05,275.51 ; REFP.4 80.2,273.65 ; 61.63,250.85 J18.3 ; J18.3 63.48,250.85 ; J18.3 63.48,249 ; J18.3 61.63,249 ; S4.GND1 184.89,284.75 ; S4.GND1 184.89,286.7 ; S4.GND1 182.95,286.7 ; S4.GND1 182.95,284.75 ; GND3.1 58.56,260.24 ; GND3.1 57.06,260.24 ; GND3.1 57.06,261.73 ; GND3.1 58.56,261.73 ; EXT_SYS_N.4 18.68,273.19 ; EXT_SYS_N.4 16.83,275.04 ; EXT_SYS_N.4 16.83,273.19 ; EXT_SYS_N.4 18.68,275.04 ; 217.29,38.84 GND6.1 ; GND6.1 218.83,37.3 ; GND6.1 217.29,37.3 ; GND6.1 218.83,38.84 ; 1.13,201.48 P19.GND3 ; P19.GND3 2.53,202.89 ; P19.GND3 1.13,202.89 ; 10.17,246.79 EXT_SYNC.3 ; EXT_SYNC.3 12.03,246.79 ; EXT_SYNC.3 12.03,244.93 ; EXT_SYNC.3 10.17,244.93 ; P18.GND2 5.22,193.43 ; P18.GND2 5.22,194.84 ; P18.GND2 3.82,194.84 ; REFP.2 76.97,280.59 ; REFP.2 76.97,278.73 ; REFP.2 75.12,280.59 ; REFP.2 75.12,278.73 ; 46.14,243.82 J17.4 ; J17.4 48,243.82 ; J17.4 48,245.67 ; J17.4 46.14,245.67 ; EXT_TRIG.2 7.1,263.39 ; EXT_TRIG.2 5.24,261.53 ; EXT_TRIG.2 7.1,261.53 ; EXT_TRIG.2 5.24,263.39 ; 199.71,235.65 GND2.1 ; GND2.1 201.2,235.65 ; GND2.1 201.2,237.15 ; GND2.1 199.71,237.15 ; REFN.4 66.43,275.45 ; REFN.4 64.57,275.45 ; REFN.4 64.57,273.6 ; REFN.4 66.43,273.6 ; EXT_HMCREF.3 45.62,275.2 ; EXT_HMCREF.3 45.62,273.34 ; EXT_HMCREF.3 43.76,273.34 ; EXT_HMCREF.3 43.76,275.2 ; 49.24,194.1 GND4.1 ; GND4.1 50.73,195.59 ; GND4.1 49.24,195.59 ; GND4.1 50.73,194.1 ; REFN.3 66.43,280.53 ; REFN.3 64.57,280.53 ; REFN.3 64.57,278.68 ; REFN.3 66.43,278.68 ; 51.22,243.82 J17.3 ; J17.3 53.08,245.67 ; J17.3 51.22,245.67 ; J17.3 53.08,243.82 ; GND8.1 175.73,163.9 ; GND8.1 174.23,165.39 ; GND8.1 175.73,165.39 ; GND8.1 174.23,163.9 ; GND7.1 173.79,81.63 ; GND7.1 172.26,81.63 ; GND7.1 173.79,83.17 ; GND7.1 172.26,83.17 ; 10.32,256.45 EXT_TRIG.4 ; EXT_TRIG.4 10.32,258.31 ; EXT_TRIG.4 12.18,256.45 ; EXT_TRIG.4 12.18,258.31 ; 53.45,215.76 REFCLK.2 ; REFCLK.2 55.31,215.76 ; REFCLK.2 53.45,213.91 ; REFCLK.2 55.31,213.91 ; P22.6 220.88,268.02 ; P22.6 218.85,265.99 ; P22.6 220.88,265.99 ; P22.6 218.85,268.02 ; P4.9 5.76,55.79 ; P4.9 5.76,57.47 ; P4.9 3.7,55.79 ; P4.9 3.7,57.47 ; J12.3 45.05,261.43 ; J12.3 45.05,263.29 ; J12.3 43.19,263.29 ; J12.3 43.19,261.43 ; J18.4 68.56,250.85 ; J18.4 68.56,249 ; J18.4 66.71,249 ; J18.4 66.71,250.85 ; 16.83,280.12 EXT_SYS_N.3 ; EXT_SYS_N.3 18.68,280.12 ; EXT_SYS_N.3 18.68,278.27 ; EXT_SYS_N.3 16.83,278.27 ; J18.5 68.56,245.77 ; J18.5 66.71,245.77 ; J18.5 66.71,243.92 ; J18.5 68.56,243.92 ; EXT_SYS_P.2 29.5,280.15 ; EXT_SYS_P.2 27.65,280.15 ; EXT_SYS_P.2 27.65,278.29 ; EXT_SYS_P.2 29.5,278.29 ; S4.GND2 198.1,286.7 ; S4.GND2 196.16,286.7 ; S4.GND2 198.1,284.75 ; S4.GND2 196.16,284.75 ; 10.17,239.85 EXT_SYNC.4 ; EXT_SYNC.4 12.03,241.71 ; EXT_SYNC.4 10.17,241.71 ; EXT_SYNC.4 12.03,239.85 ; REFCLK.5 55.31,218.99 ; REFCLK.5 53.45,220.84 ; REFCLK.5 55.31,220.84 ; REFCLK.5 53.45,218.99 ; 11.75,273.19 EXT_SYS_N.5 ; EXT_SYS_N.5 13.6,275.04 ; EXT_SYS_N.5 11.75,275.04 ; EXT_SYS_N.5 13.6,273.19 ; 2.81,57.19 P4.7 2.81,55.47 ; 2.81,62.64 P4.6 2.81,60.92 ; REFN.5 61.35,275.45 ; REFN.5 59.49,275.45 ; REFN.5 59.49,273.6 ; REFN.5 61.35,273.6 ; P18.GND1 5.22,192.3 ; P18.GND1 3.82,190.89 ; P18.GND1 5.22,190.89 ; 10.32,261.53 EXT_TRIG.3 ; EXT_TRIG.3 12.18,261.53 ; EXT_TRIG.3 12.18,263.39 ; EXT_TRIG.3 10.32,263.39 ; 3.67,198.94 P19.GND1 ; P19.GND1 5.07,200.35 ; P19.GND1 5.07,198.94 ; REFN.2 61.35,280.53 ; REFN.2 59.49,280.53 ; REFN.2 59.49,278.68 ; REFN.2 61.35,278.68 ; 38.11,258.21 J12.5 ; J12.5 38.11,256.35 ; J12.5 39.97,256.35 ; J12.5 39.97,258.21 ; EXT_HMCREF.5 50.7,280.28 ; EXT_HMCREF.5 50.7,278.42 ; EXT_HMCREF.5 48.84,278.42 ; EXT_HMCREF.5 48.84,280.28 ; P18.GND3 2.68,194.84 ; P18.GND3 1.28,194.84 ; P18.GND3 1.28,193.43 ; GND5.1 5.11,48.23 ; GND5.1 3.57,49.77 ; GND5.1 5.11,49.77 ; GND5.1 3.57,48.23 ; 51.22,250.75 J17.2 ; J17.2 51.22,248.9 ; J17.2 53.08,248.9 ; J17.2 53.08,250.75 ; EXT_SYS_P.5 29.5,273.21 ; EXT_SYS_P.5 27.65,275.07 ; EXT_SYS_P.5 29.5,275.07 ; EXT_SYS_P.5 27.65,273.21 ; J13.2 24.74,261.44 ; J13.2 22.88,263.3 ; J13.2 22.88,261.44 ; J13.2 24.74,263.3 ; EXT_HMCREF.4 45.62,278.42 ; EXT_HMCREF.4 43.76,278.42 ; EXT_HMCREF.4 43.76,280.28 ; EXT_HMCREF.4 45.62,280.28 ; P19.GND2 5.07,202.89 ; P19.GND2 5.07,201.48 ; P19.GND2 3.67,202.89 ; EXT_TRIG.5 7.1,258.31 ; EXT_TRIG.5 5.24,256.45 ; EXT_TRIG.5 5.24,258.31 ; EXT_TRIG.5 7.1,256.45 ; EXT_HMCREF.2 50.7,273.34 ; EXT_HMCREF.2 48.84,275.2 ; EXT_HMCREF.2 50.7,275.2 ; EXT_HMCREF.2 48.84,273.34 ; 48.37,213.91 REFCLK.3 ; REFCLK.3 48.37,215.76 ; REFCLK.3 50.23,215.76 ; REFCLK.3 50.23,213.91 ; J18.2 63.48,245.77 ; J18.2 61.63,243.92 ; J18.2 63.48,243.92 ; J18.2 61.63,245.77 ; 27.96,261.44 J13.3 ; J13.3 29.82,261.44 ; J13.3 29.82,263.3 ; J13.3 27.96,263.3 ; 22.88,258.22 J13.5 ; J13.5 24.74,256.36 ; J13.5 22.88,256.36 ; J13.5 24.74,258.22 ; 1.28,192.3 P18.GND4 ; P18.GND4 2.68,190.89 ; P18.GND4 1.28,190.89 ; 38.11,261.43 J12.2 ; J12.2 39.97,263.29 ; J12.2 38.11,263.29 ; J12.2 39.97,261.43 ; J12.4 45.05,258.21 ; J12.4 43.19,256.35 ; J12.4 43.19,258.21 ; J12.4 45.05,256.35 ; J17.5 48,248.9 ; J17.5 48,250.75 ; J17.5 46.14,248.9 ; J17.5 46.14,250.75 ; 3.7,62.32 P4.8 ; P4.8 5.76,62.32 ; P4.8 3.7,60.64 ; P4.8 5.76,60.64 ; REFP.3 82.05,278.73 ; REFP.3 80.2,278.73 ; REFP.3 80.2,280.59 ; REFP.3 82.05,280.59 ; EXT_SYNC.2 6.95,244.93 ; EXT_SYNC.2 5.09,244.93 ; EXT_SYNC.2 5.09,246.79 ; EXT_SYNC.2 6.95,246.79 ; 8.5,101.73 GND1.1 ; GND1.1 10.04,101.73 ; GND1.1 10.04,100.2 ; GND1.1 8.5,100.2 ; 1.13,198.94 P19.GND4 ; P19.GND4 1.13,200.35 ; P19.GND4 2.53,198.94 ; REFCLK.4 50.23,220.84 ; REFCLK.4 50.23,218.99 ; REFCLK.4 48.37,220.84 ; REFCLK.4 48.37,218.99 ; 75.12,273.65 REFP.5 ; REFP.5 76.97,275.51 ; REFP.5 76.97,273.65 ; REFP.5 75.12,275.51 ; 5.09,239.85 EXT_SYNC.5 ; EXT_SYNC.5 5.09,241.71 ; EXT_SYNC.5 6.95,239.85 ; EXT_SYNC.5 6.95,241.71
  L5_MIXED w0.152: 16.83,280.12 EXT_SYS_N.3 ; EXT_SYS_N.3 18.68,278.27 ; EXT_SYS_N.3 16.83,278.27 ; EXT_SYS_N.3 18.68,280.12 ; EXT_SYS_N.5 13.6,273.19 ; EXT_SYS_N.5 11.75,273.19 ; EXT_SYS_N.5 11.75,275.04 ; EXT_SYS_N.5 13.6,275.04 ; 199.71,235.65 GND2.1 ; GND2.1 201.2,237.15 ; GND2.1 201.2,235.65 ; GND2.1 199.71,237.15 ; REFN.5 61.35,273.6 ; REFN.5 59.49,273.6 ; REFN.5 59.49,275.45 ; REFN.5 61.35,275.45 ; REFCLK.2 55.31,215.76 ; REFCLK.2 53.45,215.76 ; REFCLK.2 53.45,213.91 ; REFCLK.2 55.31,213.91 ; REFP.3 82.05,278.73 ; REFP.3 82.05,280.59 ; REFP.3 80.2,278.73 ; REFP.3 80.2,280.59 ; 53.45,218.99 REFCLK.5 ; REFCLK.5 55.31,220.84 ; REFCLK.5 53.45,220.84 ; REFCLK.5 55.31,218.99 ; REFCLK.3 50.23,213.91 ; REFCLK.3 48.37,213.91 ; REFCLK.3 48.37,215.76 ; REFCLK.3 50.23,215.76 ; REFP.2 76.97,280.59 ; REFP.2 75.12,280.59 ; REFP.2 76.97,278.73 ; REFP.2 75.12,278.73 ; 16.83,273.19 EXT_SYS_N.4 ; EXT_SYS_N.4 18.68,275.04 ; EXT_SYS_N.4 16.83,275.04 ; EXT_SYS_N.4 18.68,273.19 ; 27.65,273.21 EXT_SYS_P.5 ; EXT_SYS_P.5 29.5,273.21 ; EXT_SYS_P.5 29.5,275.07 ; EXT_SYS_P.5 27.65,275.07 ; 196.16,284.75 S4.GND2 ; S4.GND2 198.1,284.75 ; S4.GND2 196.16,286.7 ; S4.GND2 198.1,286.7 ; 48.37,220.84 REFCLK.4 ; REFCLK.4 50.23,220.84 ; REFCLK.4 50.23,218.99 ; REFCLK.4 48.37,218.99 ; 1.28,194.84 P18.GND3 ; P18.GND3 2.68,194.84 ; P18.GND3 1.28,193.43 ; P4.8 5.76,60.64 ; P4.8 3.7,62.32 ; P4.8 5.76,62.32 ; P4.8 3.7,60.64 ; P19.GND2 5.07,201.48 ; P19.GND2 3.67,202.89 ; P19.GND2 5.07,202.89 ; EXT_HMCREF.3 45.62,273.34 ; EXT_HMCREF.3 45.62,275.2 ; EXT_HMCREF.3 43.76,273.34 ; EXT_HMCREF.3 43.76,275.2 ; 3.67,198.94 P19.GND1 ; P19.GND1 5.07,200.35 ; P19.GND1 5.07,198.94 ; S4.GND1 184.89,286.7 ; S4.GND1 182.95,284.75 ; S4.GND1 182.95,286.7 ; S4.GND1 184.89,284.75 ; 27.65,280.15 EXT_SYS_P.2 ; EXT_SYS_P.2 29.5,278.29 ; EXT_SYS_P.2 29.5,280.15 ; EXT_SYS_P.2 27.65,278.29 ; 32.73,278.29 EXT_SYS_P.3 ; EXT_SYS_P.3 34.58,280.15 ; EXT_SYS_P.3 34.58,278.29 ; EXT_SYS_P.3 32.73,280.15 ; P18.GND1 5.22,192.3 ; P18.GND1 3.82,190.89 ; P18.GND1 5.22,190.89 ; 8.5,100.2 GND1.1 ; GND1.1 10.04,100.2 ; GND1.1 8.5,101.73 ; GND1.1 10.04,101.73 ; 3.57,48.23 GND5.1 ; GND5.1 5.11,48.23 ; GND5.1 3.57,49.77 ; GND5.1 5.11,49.77 ; 3.7,57.47 P4.9 ; P4.9 5.76,57.47 ; P4.9 5.76,55.79 ; P4.9 3.7,55.79 ; 59.49,280.53 REFN.2 ; REFN.2 61.35,280.53 ; REFN.2 59.49,278.68 ; REFN.2 61.35,278.68 ; REFN.4 66.43,275.45 ; REFN.4 66.43,273.6 ; REFN.4 64.57,275.45 ; REFN.4 64.57,273.6 ; REFP.4 82.05,273.65 ; REFP.4 82.05,275.51 ; REFP.4 80.2,273.65 ; REFP.4 80.2,275.51 ; 48.84,278.42 EXT_HMCREF.5 ; EXT_HMCREF.5 50.7,280.28 ; EXT_HMCREF.5 50.7,278.42 ; EXT_HMCREF.5 48.84,280.28 ; 217.29,37.3 GND6.1 ; GND6.1 218.83,37.3 ; GND6.1 217.29,38.84 ; GND6.1 218.83,38.84 ; P18.GND4 2.68,190.89 ; P18.GND4 1.28,192.3 ; P18.GND4 1.28,190.89 ; 32.73,275.07 EXT_SYS_P.4 ; EXT_SYS_P.4 34.58,275.07 ; EXT_SYS_P.4 34.58,273.21 ; EXT_SYS_P.4 32.73,273.21 ; P19.GND4 2.53,198.94 ; P19.GND4 1.13,198.94 ; P19.GND4 1.13,200.35 ; 43.76,278.42 EXT_HMCREF.4 ; EXT_HMCREF.4 43.76,280.28 ; EXT_HMCREF.4 45.62,278.42 ; EXT_HMCREF.4 45.62,280.28 ; 2.81,57.19 P4.7 2.81,55.47 ; REFP.5 76.97,273.65 ; REFP.5 76.97,275.51 ; REFP.5 75.12,273.65 ; REFP.5 75.12,275.51 ; 1.13,202.89 P19.GND3 ; P19.GND3 1.13,201.48 ; P19.GND3 2.53,202.89 ; EXT_HMCREF.2 50.7,275.2 ; EXT_HMCREF.2 48.84,273.34 ; EXT_HMCREF.2 50.7,273.34 ; EXT_HMCREF.2 48.84,275.2 ; REFN.3 66.43,280.53 ; REFN.3 64.57,280.53 ; REFN.3 64.57,278.68 ; REFN.3 66.43,278.68 ; GND8.1 175.73,163.9 ; GND8.1 175.73,165.39 ; GND8.1 174.23,163.9 ; GND8.1 174.23,165.39 ; EXT_SYS_N.2 13.6,280.12 ; EXT_SYS_N.2 11.75,280.12 ; EXT_SYS_N.2 11.75,278.27 ; EXT_SYS_N.2 13.6,278.27 ; 218.85,268.02 P22.6 ; P22.6 218.85,265.99 ; P22.6 220.88,268.02 ; P22.6 220.88,265.99 ; 49.24,195.59 GND4.1 ; GND4.1 49.24,194.1 ; GND4.1 50.73,194.1 ; GND4.1 50.73,195.59 ; 218.85,271.5 P22.3 ; P22.3 220.88,273.53 ; P22.3 218.85,273.53 ; P22.3 220.88,271.5 ; 3.82,194.84 P18.GND2 ; P18.GND2 5.22,193.43 ; P18.GND2 5.22,194.84 ; 2.81,60.92 P4.6 2.81,62.64
  L5_MIXED w0.203: 189.46,211.9 189.46,211.91
  L6_GROUND w0.152: EXT_SYS_N.3 18.68,280.12 ; EXT_SYS_N.3 16.83,278.27 ; EXT_SYS_N.3 16.83,280.12 ; EXT_SYS_N.3 18.68,278.27 ; 46.14,245.67 J17.4 ; J17.4 48,243.82 ; J17.4 48,245.67 ; J17.4 46.14,243.82 ; 5.09,241.71 EXT_SYNC.5 ; EXT_SYNC.5 6.95,241.71 ; EXT_SYNC.5 6.95,239.85 ; EXT_SYNC.5 5.09,239.85 ; J12.3 45.05,261.43 ; J12.3 45.05,263.29 ; J12.3 43.19,263.29 ; J12.3 43.19,261.43 ; REFCLK.5 55.31,218.99 ; REFCLK.5 55.31,220.84 ; REFCLK.5 53.45,220.84 ; REFCLK.5 53.45,218.99 ; REFP.3 82.05,278.73 ; REFP.3 80.2,278.73 ; REFP.3 80.2,280.59 ; REFP.3 82.05,280.59 ; 51.22,245.67 J17.3 ; J17.3 53.08,243.82 ; J17.3 53.08,245.67 ; J17.3 51.22,243.82 ; P4.8 5.76,62.32 ; P4.8 3.7,60.64 ; P4.8 3.7,62.32 ; P4.8 5.76,60.64 ; P18.GND1 5.22,190.89 ; P18.GND1 3.82,190.89 ; P18.GND1 5.22,192.3 ; 182.95,286.7 S4.GND1 ; S4.GND1 184.89,286.7 ; S4.GND1 184.89,284.75 ; S4.GND1 182.95,284.75 ; GND1.1 10.04,100.2 ; GND1.1 8.5,101.73 ; GND1.1 8.5,100.2 ; GND1.1 10.04,101.73 ; 5.24,256.45 EXT_TRIG.5 ; EXT_TRIG.5 5.24,258.31 ; EXT_TRIG.5 7.1,258.31 ; EXT_TRIG.5 7.1,256.45 ; J13.4 29.82,256.36 ; J13.4 29.82,258.22 ; J13.4 27.96,258.22 ; J13.4 27.96,256.36 ; EXT_SYS_N.5 13.6,273.19 ; EXT_SYS_N.5 11.75,273.19 ; EXT_SYS_N.5 13.6,275.04 ; EXT_SYS_N.5 11.75,275.04 ; 11.75,280.12 EXT_SYS_N.2 ; EXT_SYS_N.2 13.6,278.27 ; EXT_SYS_N.2 13.6,280.12 ; EXT_SYS_N.2 11.75,278.27 ; 10.32,263.39 EXT_TRIG.3 ; EXT_TRIG.3 12.18,261.53 ; EXT_TRIG.3 10.32,261.53 ; EXT_TRIG.3 12.18,263.39 ; 43.76,278.42 EXT_HMCREF.4 ; EXT_HMCREF.4 45.62,278.42 ; EXT_HMCREF.4 45.62,280.28 ; EXT_HMCREF.4 43.76,280.28 ; J17.5 48,250.75 ; J17.5 48,248.9 ; J17.5 46.14,248.9 ; J17.5 46.14,250.75 ; EXT_HMCREF.2 50.7,275.2 ; EXT_HMCREF.2 48.84,273.34 ; EXT_HMCREF.2 50.7,273.34 ; EXT_HMCREF.2 48.84,275.2 ; 1.28,194.84 P18.GND3 ; P18.GND3 1.28,193.43 ; P18.GND3 2.68,194.84 ; 16.83,275.04 EXT_SYS_N.4 ; EXT_SYS_N.4 18.68,275.04 ; EXT_SYS_N.4 16.83,273.19 ; EXT_SYS_N.4 18.68,273.19 ; 217.29,37.3 GND6.1 ; GND6.1 217.29,38.84 ; GND6.1 218.83,38.84 ; GND6.1 218.83,37.3 ; 10.17,246.79 EXT_SYNC.3 ; EXT_SYNC.3 10.17,244.93 ; EXT_SYNC.3 12.03,246.79 ; EXT_SYNC.3 12.03,244.93 ; 64.57,278.68 REFN.3 ; REFN.3 66.43,280.53 ; REFN.3 66.43,278.68 ; REFN.3 64.57,280.53 ; 43.76,273.34 EXT_HMCREF.3 ; EXT_HMCREF.3 45.62,275.2 ; EXT_HMCREF.3 43.76,275.2 ; EXT_HMCREF.3 45.62,273.34 ; 5.24,261.53 EXT_TRIG.2 ; EXT_TRIG.2 7.1,263.39 ; EXT_TRIG.2 5.24,263.39 ; EXT_TRIG.2 7.1,261.53 ; GND2.1 201.2,237.15 ; GND2.1 199.71,235.65 ; GND2.1 199.71,237.15 ; GND2.1 201.2,235.65 ; 48.37,218.99 REFCLK.4 ; REFCLK.4 50.23,220.84 ; REFCLK.4 50.23,218.99 ; REFCLK.4 48.37,220.84 ; 27.65,278.29 EXT_SYS_P.2 ; EXT_SYS_P.2 29.5,278.29 ; EXT_SYS_P.2 29.5,280.15 ; EXT_SYS_P.2 27.65,280.15 ; 66.71,243.92 J18.5 ; J18.5 66.71,245.77 ; J18.5 68.56,245.77 ; J18.5 68.56,243.92 ; 3.7,57.47 P4.9 ; P4.9 5.76,57.47 ; P4.9 5.76,55.79 ; P4.9 3.7,55.79 ; 27.96,263.3 J13.3 ; J13.3 29.82,261.44 ; J13.3 27.96,261.44 ; J13.3 29.82,263.3 ; GND4.1 50.73,194.1 ; GND4.1 50.73,195.59 ; GND4.1 49.24,194.1 ; GND4.1 49.24,195.59 ; P19.GND2 5.07,202.89 ; P19.GND2 5.07,201.48 ; P19.GND2 3.67,202.89 ; 10.32,256.45 EXT_TRIG.4 ; EXT_TRIG.4 10.32,258.31 ; EXT_TRIG.4 12.18,258.31 ; EXT_TRIG.4 12.18,256.45 ; J17.2 53.08,248.9 ; J17.2 51.22,248.9 ; J17.2 51.22,250.75 ; J17.2 53.08,250.75 ; 196.16,286.7 S4.GND2 ; S4.GND2 196.16,284.75 ; S4.GND2 198.1,286.7 ; S4.GND2 198.1,284.75 ; REFN.5 61.35,273.6 ; REFN.5 61.35,275.45 ; REFN.5 59.49,275.45 ; REFN.5 59.49,273.6 ; EXT_SYNC.2 6.95,246.79 ; EXT_SYNC.2 5.09,244.93 ; EXT_SYNC.2 5.09,246.79 ; EXT_SYNC.2 6.95,244.93 ; P19.GND1 5.07,198.94 ; P19.GND1 5.07,200.35 ; P19.GND1 3.67,198.94 ; 38.11,258.21 J12.5 ; J12.5 39.97,258.21 ; J12.5 39.97,256.35 ; J12.5 38.11,256.35 ; 64.57,273.6 REFN.4 ; REFN.4 64.57,275.45 ; REFN.4 66.43,275.45 ; REFN.4 66.43,273.6 ; J13.2 24.74,261.44 ; J13.2 22.88,261.44 ; J13.2 24.74,263.3 ; J13.2 22.88,263.3 ; 1.13,201.48 P19.GND3 ; P19.GND3 2.53,202.89 ; P19.GND3 1.13,202.89 ; EXT_SYS_P.3 34.58,280.15 ; EXT_SYS_P.3 32.73,278.29 ; EXT_SYS_P.3 34.58,278.29 ; EXT_SYS_P.3 32.73,280.15 ; 66.71,250.85 J18.4 ; J18.4 66.71,249 ; J18.4 68.56,250.85 ; J18.4 68.56,249 ; 22.88,256.36 J13.5 ; J13.5 24.74,258.22 ; J13.5 22.88,258.22 ; J13.5 24.74,256.36 ; GND7.1 173.79,83.17 ; GND7.1 172.26,83.17 ; GND7.1 172.26,81.63 ; GND7.1 173.79,81.63 ; 218.85,268.02 P22.6 ; P22.6 218.85,265.99 ; P22.6 220.88,265.99 ; P22.6 220.88,268.02 ; EXT_HMCREF.5 50.7,280.28 ; EXT_HMCREF.5 48.84,278.42 ; EXT_HMCREF.5 50.7,278.42 ; EXT_HMCREF.5 48.84,280.28 ; 2.81,55.47 P4.7 2.81,57.19 ; J12.2 39.97,263.29 ; J12.2 38.11,261.43 ; J12.2 39.97,261.43 ; J12.2 38.11,263.29 ; J18.3 63.48,249 ; J18.3 61.63,249 ; J18.3 63.48,250.85 ; J18.3 61.63,250.85 ; 75.12,278.73 REFP.2 ; REFP.2 76.97,280.59 ; REFP.2 75.12,280.59 ; REFP.2 76.97,278.73 ; 1.13,198.94 P19.GND4 ; P19.GND4 2.53,198.94 ; P19.GND4 1.13,200.35 ; P18.GND2 5.22,193.43 ; P18.GND2 3.82,194.84 ; P18.GND2 5.22,194.84 ; 2.81,62.64 P4.6 2.81,60.92 ; 1.28,192.3 P18.GND4 ; P18.GND4 2.68,190.89 ; P18.GND4 1.28,190.89 ; GND5.1 5.11,48.23 ; GND5.1 5.11,49.77 ; GND5.1 3.57,48.23 ; GND5.1 3.57,49.77 ; 80.2,275.51 REFP.4 ; REFP.4 82.05,273.65 ; REFP.4 80.2,273.65 ; REFP.4 82.05,275.51 ; EXT_SYS_P.4 34.58,275.07 ; EXT_SYS_P.4 34.58,273.21 ; EXT_SYS_P.4 32.73,275.07 ; EXT_SYS_P.4 32.73,273.21 ; REFCLK.3 50.23,213.91 ; REFCLK.3 50.23,215.76 ; REFCLK.3 48.37,215.76 ; REFCLK.3 48.37,213.91 ; EXT_SYS_P.5 29.5,273.21 ; EXT_SYS_P.5 27.65,273.21 ; EXT_SYS_P.5 27.65,275.07 ; EXT_SYS_P.5 29.5,275.07 ; 43.19,258.21 J12.4 ; J12.4 43.19,256.35 ; J12.4 45.05,258.21 ; J12.4 45.05,256.35 ; J18.2 63.48,245.77 ; J18.2 61.63,245.77 ; J18.2 63.48,243.92 ; J18.2 61.63,243.92 ; 53.45,213.91 REFCLK.2 ; REFCLK.2 55.31,213.91 ; REFCLK.2 53.45,215.76 ; REFCLK.2 55.31,215.76 ; GND8.1 175.73,165.39 ; GND8.1 174.23,165.39 ; GND8.1 174.23,163.9 ; GND8.1 175.73,163.9 ; P22.3 220.88,271.5 ; P22.3 220.88,273.53 ; P22.3 218.85,271.5 ; P22.3 218.85,273.53 ; 75.12,275.51 REFP.5 ; REFP.5 76.97,273.65 ; REFP.5 76.97,275.51 ; REFP.5 75.12,273.65 ; GND3.1 58.56,261.73 ; GND3.1 58.56,260.24 ; GND3.1 57.06,260.24 ; GND3.1 57.06,261.73 ; 59.49,278.68 REFN.2 ; REFN.2 59.49,280.53 ; REFN.2 61.35,280.53 ; REFN.2 61.35,278.68 ; 10.17,241.71 EXT_SYNC.4 ; EXT_SYNC.4 12.03,241.71 ; EXT_SYNC.4 10.17,239.85 ; EXT_SYNC.4 12.03,239.85
  L7_POWER w0.152: 2.81,62.64 P4.6 2.81,60.92 ; EXT_HMCREF.4 45.62,278.42 ; EXT_HMCREF.4 45.62,280.28 ; EXT_HMCREF.4 43.76,278.42 ; EXT_HMCREF.4 43.76,280.28 ; EXT_TRIG.2 7.1,261.53 ; EXT_TRIG.2 7.1,263.39 ; EXT_TRIG.2 5.24,263.39 ; EXT_TRIG.2 5.24,261.53 ; REFP.2 76.97,280.59 ; REFP.2 75.12,278.73 ; REFP.2 75.12,280.59 ; REFP.2 76.97,278.73 ; J17.2 53.08,248.9 ; J17.2 51.22,248.9 ; J17.2 51.22,250.75 ; J17.2 53.08,250.75 ; 46.14,248.9 J17.5 ; J17.5 46.14,250.75 ; J17.5 48,248.9 ; J17.5 48,250.75 ; REFN.5 61.35,273.6 ; REFN.5 59.49,275.45 ; REFN.5 59.49,273.6 ; REFN.5 61.35,275.45 ; 8.5,100.2 GND1.1 ; GND1.1 10.04,100.2 ; GND1.1 8.5,101.73 ; GND1.1 10.04,101.73 ; 16.83,278.27 EXT_SYS_N.3 ; EXT_SYS_N.3 18.68,278.27 ; EXT_SYS_N.3 18.68,280.12 ; EXT_SYS_N.3 16.83,280.12 ; EXT_SYS_N.4 18.68,275.04 ; EXT_SYS_N.4 16.83,273.19 ; EXT_SYS_N.4 16.83,275.04 ; EXT_SYS_N.4 18.68,273.19 ; 5.24,258.31 EXT_TRIG.5 ; EXT_TRIG.5 7.1,256.45 ; EXT_TRIG.5 5.24,256.45 ; EXT_TRIG.5 7.1,258.31 ; 32.73,280.15 EXT_SYS_P.3 ; EXT_SYS_P.3 34.58,278.29 ; EXT_SYS_P.3 32.73,278.29 ; EXT_SYS_P.3 34.58,280.15 ; REFP.4 82.05,273.65 ; REFP.4 80.2,273.65 ; REFP.4 82.05,275.51 ; REFP.4 80.2,275.51 ; 22.88,258.22 J13.5 ; J13.5 22.88,256.36 ; J13.5 24.74,256.36 ; J13.5 24.74,258.22 ; 3.7,60.64 P4.8 ; P4.8 5.76,62.32 ; P4.8 3.7,62.32 ; P4.8 5.76,60.64 ; 22.88,263.3 J13.2 ; J13.2 24.74,263.3 ; J13.2 24.74,261.44 ; J13.2 22.88,261.44 ; 3.7,55.79 P4.9 ; P4.9 3.7,57.47 ; P4.9 5.76,55.79 ; P4.9 5.76,57.47 ; 66.71,245.77 J18.5 68.56,245.77 ; REFCLK.5 55.31,218.99 ; REFCLK.5 55.31,220.84 ; REFCLK.5 53.45,220.84 ; REFCLK.5 53.45,218.99 ; EXT_TRIG.4 12.18,256.45 ; EXT_TRIG.4 10.32,256.45 ; EXT_TRIG.4 10.32,258.31 ; EXT_TRIG.4 12.18,258.31 ; P19.GND3 2.53,202.89 ; P19.GND3 1.13,202.89 ; P19.GND3 1.13,201.48 ; EXT_HMCREF.2 50.7,275.2 ; EXT_HMCREF.2 50.7,273.34 ; EXT_HMCREF.2 48.84,275.2 ; EXT_HMCREF.2 48.84,273.34 ; 43.19,261.43 J12.3 ; J12.3 45.05,263.29 ; J12.3 43.19,263.29 ; J12.3 45.05,261.43 ; GND4.1 50.73,195.59 ; GND4.1 49.24,194.1 ; GND4.1 50.73,194.1 ; GND4.1 49.24,195.59 ; 2.81,55.47 P4.7 2.81,57.19 ; 66.71,249 J18.4 ; J18.4 68.56,249 ; J18.4 68.56,250.85 ; J18.4 66.71,250.85 ; 1.28,192.3 P18.GND4 ; P18.GND4 2.68,190.89 ; P18.GND4 1.28,190.89 ; 64.57,273.6 REFN.4 ; REFN.4 64.57,275.45 ; REFN.4 66.43,275.45 ; REFN.4 66.43,273.6 ; 59.49,280.53 REFN.2 ; REFN.2 59.49,278.68 ; REFN.2 61.35,280.53 ; REFN.2 61.35,278.68 ; P19.GND4 2.53,198.94 ; P19.GND4 1.13,200.35 ; P19.GND4 1.13,198.94 ; P22.6 220.88,268.02 ; P22.6 218.85,268.02 ; P22.6 218.85,265.99 ; P22.6 220.88,265.99 ; 218.85,273.53 P22.3 ; P22.3 218.85,271.5 ; P22.3 220.88,273.53 ; P22.3 220.88,271.5 ; 10.32,263.39 EXT_TRIG.3 ; EXT_TRIG.3 12.18,261.53 ; EXT_TRIG.3 12.18,263.39 ; EXT_TRIG.3 10.32,261.53 ; 63.48,245.77 J18.2 61.63,245.77 ; EXT_SYNC.2 6.95,246.79 ; EXT_SYNC.2 6.95,244.93 ; EXT_SYNC.2 5.09,244.93 ; EXT_SYNC.2 5.09,246.79 ; P19.GND2 5.07,201.48 ; P19.GND2 5.07,202.89 ; P19.GND2 3.67,202.89 ; 75.12,275.51 REFP.5 ; REFP.5 76.97,273.65 ; REFP.5 76.97,275.51 ; REFP.5 75.12,273.65 ; EXT_SYNC.5 6.95,241.71 ; EXT_SYNC.5 6.95,239.85 ; EXT_SYNC.5 5.09,241.71 ; EXT_SYNC.5 5.09,239.85 ; 43.19,258.21 J12.4 ; J12.4 45.05,258.21 ; J12.4 43.19,256.35 ; J12.4 45.05,256.35 ; 172.26,83.17 GND7.1 ; GND7.1 173.79,81.63 ; GND7.1 172.26,81.63 ; GND7.1 173.79,83.17 ; 53.45,213.91 REFCLK.2 ; REFCLK.2 55.31,215.76 ; REFCLK.2 53.45,215.76 ; REFCLK.2 55.31,213.91 ; REFCLK.4 50.23,218.99 ; REFCLK.4 48.37,218.99 ; REFCLK.4 50.23,220.84 ; REFCLK.4 48.37,220.84 ; S4.GND1 184.89,284.75 ; S4.GND1 182.95,284.75 ; S4.GND1 182.95,286.7 ; S4.GND1 184.89,286.7 ; S4.GND2 198.1,286.7 ; S4.GND2 196.16,284.75 ; S4.GND2 198.1,284.75 ; S4.GND2 196.16,286.7 ; 46.14,245.67 J17.4 48,245.67 ; REFCLK.3 50.23,213.91 ; REFCLK.3 48.37,215.76 ; REFCLK.3 48.37,213.91 ; REFCLK.3 50.23,215.76 ; 1.28,193.43 P18.GND3 ; P18.GND3 1.28,194.84 ; P18.GND3 2.68,194.84 ; 38.11,261.43 J12.2 ; J12.2 39.97,261.43 ; J12.2 38.11,263.29 ; J12.2 39.97,263.29 ; J18.3 63.48,250.85 ; J18.3 61.63,250.85 ; J18.3 63.48,249 ; J18.3 61.63,249 ; GND3.1 58.56,260.24 ; GND3.1 57.06,261.73 ; GND3.1 58.56,261.73 ; GND3.1 57.06,260.24 ; 48.84,280.28 EXT_HMCREF.5 ; EXT_HMCREF.5 50.7,278.42 ; EXT_HMCREF.5 50.7,280.28 ; EXT_HMCREF.5 48.84,278.42 ; 10.17,244.93 EXT_SYNC.3 ; EXT_SYNC.3 10.17,246.79 ; EXT_SYNC.3 12.03,244.93 ; EXT_SYNC.3 12.03,246.79 ; 51.22,245.67 J17.3 53.08,245.67 ; 80.2,280.59 REFP.3 ; REFP.3 82.05,278.73 ; REFP.3 82.05,280.59 ; REFP.3 80.2,278.73 ; REFN.3 66.43,280.53 ; REFN.3 66.43,278.68 ; REFN.3 64.57,278.68 ; REFN.3 64.57,280.53 ; EXT_SYS_P.5 29.5,275.07 ; EXT_SYS_P.5 27.65,275.07 ; EXT_SYS_P.5 29.5,273.21 ; EXT_SYS_P.5 27.65,273.21 ; 3.82,190.89 P18.GND1 ; P18.GND1 5.22,190.89 ; P18.GND1 5.22,192.3 ; EXT_SYS_P.2 29.5,280.15 ; EXT_SYS_P.2 29.5,278.29 ; EXT_SYS_P.2 27.65,278.29 ; EXT_SYS_P.2 27.65,280.15 ; 10.17,239.85 EXT_SYNC.4 ; EXT_SYNC.4 10.17,241.71 ; EXT_SYNC.4 12.03,239.85 ; EXT_SYNC.4 12.03,241.71 ; 27.96,256.36 J13.4 ; J13.4 29.82,258.22 ; J13.4 27.96,258.22 ; J13.4 29.82,256.36 ; EXT_SYS_N.5 13.6,273.19 ; EXT_SYS_N.5 11.75,273.19 ; EXT_SYS_N.5 13.6,275.04 ; EXT_SYS_N.5 11.75,275.04 ; 3.57,48.23 GND5.1 ; GND5.1 5.11,48.23 ; GND5.1 5.11,49.77 ; GND5.1 3.57,49.77 ; J13.3 29.82,263.3 ; J13.3 29.82,261.44 ; J13.3 27.96,263.3 ; J13.3 27.96,261.44 ; 217.29,38.84 GND6.1 ; GND6.1 218.83,38.84 ; GND6.1 217.29,37.3 ; GND6.1 218.83,37.3 ; P19.GND1 5.07,200.35 ; P19.GND1 3.67,198.94 ; P19.GND1 5.07,198.94 ; 32.73,275.07 EXT_SYS_P.4 ; EXT_SYS_P.4 32.73,273.21 ; EXT_SYS_P.4 34.58,275.07 ; EXT_SYS_P.4 34.58,273.21 ; 38.11,258.21 J12.5 ; J12.5 39.97,256.35 ; J12.5 39.97,258.21 ; J12.5 38.11,256.35 ; P18.GND2 5.22,193.43 ; P18.GND2 5.22,194.84 ; P18.GND2 3.82,194.84 ; EXT_HMCREF.3 45.62,275.2 ; EXT_HMCREF.3 43.76,273.34 ; EXT_HMCREF.3 43.76,275.2 ; EXT_HMCREF.3 45.62,273.34 ; 11.75,278.27 EXT_SYS_N.2 ; EXT_SYS_N.2 13.6,280.12 ; EXT_SYS_N.2 11.75,280.12 ; EXT_SYS_N.2 13.6,278.27
  L8_GROUND w0.152: EXT_SYS_N.2 13.6,278.27 ; EXT_SYS_N.2 11.75,280.12 ; EXT_SYS_N.2 13.6,280.12 ; EXT_SYS_N.2 11.75,278.27 ; J12.2 39.97,261.43 ; J12.2 39.97,263.29 ; J12.2 38.11,263.29 ; J12.2 38.11,261.43 ; 1.13,201.48 P19.GND3 ; P19.GND3 2.53,202.89 ; P19.GND3 1.13,202.89 ; GND3.1 58.56,261.73 ; GND3.1 57.06,261.73 ; GND3.1 57.06,260.24 ; GND3.1 58.56,260.24 ; 59.49,278.68 REFN.2 ; REFN.2 61.35,278.68 ; REFN.2 61.35,280.53 ; REFN.2 59.49,280.53 ; 199.71,237.15 GND2.1 ; GND2.1 199.71,235.65 ; GND2.1 201.2,235.65 ; GND2.1 201.2,237.15 ; 5.09,241.71 EXT_SYNC.5 ; EXT_SYNC.5 6.95,239.85 ; EXT_SYNC.5 5.09,239.85 ; EXT_SYNC.5 6.95,241.71 ; 10.17,244.93 EXT_SYNC.3 ; EXT_SYNC.3 12.03,244.93 ; EXT_SYNC.3 10.17,246.79 ; EXT_SYNC.3 12.03,246.79 ; 27.96,263.3 J13.3 ; J13.3 29.82,263.3 ; J13.3 29.82,261.44 ; J13.3 27.96,261.44 ; EXT_SYS_P.3 34.58,278.29 ; EXT_SYS_P.3 32.73,278.29 ; EXT_SYS_P.3 32.73,280.15 ; EXT_SYS_P.3 34.58,280.15 ; 1.28,192.3 P18.GND4 ; P18.GND4 2.68,190.89 ; P18.GND4 1.28,190.89 ; P18.GND2 5.22,193.43 ; P18.GND2 5.22,194.84 ; P18.GND2 3.82,194.84 ; J13.5 24.74,258.22 ; J13.5 22.88,258.22 ; J13.5 24.74,256.36 ; J13.5 22.88,256.36 ; J18.4 68.56,250.85 ; J18.4 68.56,249 ; J18.4 66.71,250.85 ; J18.4 66.71,249 ; 43.19,261.43 J12.3 ; J12.3 43.19,263.29 ; J12.3 45.05,263.29 ; J12.3 45.05,261.43 ; EXT_HMCREF.5 50.7,278.42 ; EXT_HMCREF.5 48.84,278.42 ; EXT_HMCREF.5 50.7,280.28 ; EXT_HMCREF.5 48.84,280.28 ; J13.2 24.74,263.3 ; J13.2 24.74,261.44 ; J13.2 22.88,263.3 ; J13.2 22.88,261.44 ; 3.67,202.89 P19.GND2 ; P19.GND2 5.07,201.48 ; P19.GND2 5.07,202.89 ; 49.24,195.59 GND4.1 ; GND4.1 49.24,194.1 ; GND4.1 50.73,195.59 ; GND4.1 50.73,194.1 ; 196.16,286.7 S4.GND2 ; S4.GND2 196.16,284.75 ; S4.GND2 198.1,284.75 ; S4.GND2 198.1,286.7 ; EXT_TRIG.4 12.18,256.45 ; EXT_TRIG.4 12.18,258.31 ; EXT_TRIG.4 10.32,258.31 ; EXT_TRIG.4 10.32,256.45 ; EXT_SYS_P.2 29.5,280.15 ; EXT_SYS_P.2 27.65,278.29 ; EXT_SYS_P.2 29.5,278.29 ; EXT_SYS_P.2 27.65,280.15 ; 182.95,286.7 S4.GND1 ; S4.GND1 184.89,284.75 ; S4.GND1 182.95,284.75 ; S4.GND1 184.89,286.7 ; 218.85,265.99 P22.6 ; P22.6 220.88,265.99 ; P22.6 218.85,268.02 ; P22.6 220.88,268.02 ; 1.28,193.43 P18.GND3 ; P18.GND3 1.28,194.84 ; P18.GND3 2.68,194.84 ; 11.75,275.04 EXT_SYS_N.5 ; EXT_SYS_N.5 11.75,273.19 ; EXT_SYS_N.5 13.6,275.04 ; EXT_SYS_N.5 13.6,273.19 ; 64.57,280.53 REFN.3 ; REFN.3 64.57,278.68 ; REFN.3 66.43,278.68 ; REFN.3 66.43,280.53 ; 16.83,275.04 EXT_SYS_N.4 ; EXT_SYS_N.4 18.68,273.19 ; EXT_SYS_N.4 18.68,275.04 ; EXT_SYS_N.4 16.83,273.19 ; REFCLK.5 55.31,218.99 ; REFCLK.5 55.31,220.84 ; REFCLK.5 53.45,218.99 ; REFCLK.5 53.45,220.84 ; 48.37,215.76 REFCLK.3 ; REFCLK.3 50.23,215.76 ; REFCLK.3 48.37,213.91 ; REFCLK.3 50.23,213.91 ; EXT_TRIG.5 7.1,256.45 ; EXT_TRIG.5 5.24,258.31 ; EXT_TRIG.5 7.1,258.31 ; EXT_TRIG.5 5.24,256.45 ; J17.3 53.08,243.82 ; J17.3 51.22,243.82 ; J17.3 53.08,245.67 ; J17.3 51.22,245.67 ; EXT_TRIG.3 12.18,261.53 ; EXT_TRIG.3 10.32,263.39 ; EXT_TRIG.3 12.18,263.39 ; EXT_TRIG.3 10.32,261.53 ; REFN.4 66.43,275.45 ; REFN.4 66.43,273.6 ; REFN.4 64.57,273.6 ; REFN.4 64.57,275.45 ; 2.81,57.19 P4.7 2.81,55.47 ; 32.73,275.07 EXT_SYS_P.4 ; EXT_SYS_P.4 34.58,273.21 ; EXT_SYS_P.4 34.58,275.07 ; EXT_SYS_P.4 32.73,273.21 ; 3.57,48.23 GND5.1 ; GND5.1 5.11,48.23 ; GND5.1 3.57,49.77 ; GND5.1 5.11,49.77 ; J12.5 39.97,258.21 ; J12.5 39.97,256.35 ; J12.5 38.11,256.35 ; J12.5 38.11,258.21 ; 8.5,101.73 GND1.1 ; GND1.1 8.5,100.2 ; GND1.1 10.04,101.73 ; GND1.1 10.04,100.2 ; J18.3 63.48,250.85 ; J18.3 61.63,250.85 ; J18.3 63.48,249 ; J18.3 61.63,249 ; 80.2,278.73 REFP.3 ; REFP.3 82.05,278.73 ; REFP.3 80.2,280.59 ; REFP.3 82.05,280.59 ; P4.9 5.76,57.47 ; P4.9 3.7,57.47 ; P4.9 3.7,55.79 ; P4.9 5.76,55.79 ; 51.22,248.9 J17.2 ; J17.2 53.08,250.75 ; J17.2 51.22,250.75 ; J17.2 53.08,248.9 ; 80.2,273.65 REFP.4 ; REFP.4 82.05,273.65 ; REFP.4 82.05,275.51 ; REFP.4 80.2,275.51 ; REFP.2 76.97,280.59 ; REFP.2 75.12,280.59 ; REFP.2 75.12,278.73 ; REFP.2 76.97,278.73 ; 3.7,60.64 P4.8 ; P4.8 5.76,60.64 ; P4.8 3.7,62.32 ; P4.8 5.76,62.32 ; 27.96,256.36 J13.4 ; J13.4 27.96,258.22 ; J13.4 29.82,258.22 ; J13.4 29.82,256.36 ; EXT_HMCREF.2 50.7,275.2 ; EXT_HMCREF.2 50.7,273.34 ; EXT_HMCREF.2 48.84,275.2 ; EXT_HMCREF.2 48.84,273.34 ; 5.09,246.79 EXT_SYNC.2 ; EXT_SYNC.2 6.95,244.93 ; EXT_SYNC.2 6.95,246.79 ; EXT_SYNC.2 5.09,244.93 ; P19.GND1 5.07,198.94 ; P19.GND1 3.67,198.94 ; P19.GND1 5.07,200.35 ; REFCLK.4 50.23,218.99 ; REFCLK.4 48.37,218.99 ; REFCLK.4 48.37,220.84 ; REFCLK.4 50.23,220.84 ; 1.13,200.35 P19.GND4 ; P19.GND4 2.53,198.94 ; P19.GND4 1.13,198.94 ; 10.17,241.71 EXT_SYNC.4 ; EXT_SYNC.4 10.17,239.85 ; EXT_SYNC.4 12.03,239.85 ; EXT_SYNC.4 12.03,241.71 ; EXT_SYS_P.5 29.5,273.21 ; EXT_SYS_P.5 29.5,275.07 ; EXT_SYS_P.5 27.65,275.07 ; EXT_SYS_P.5 27.65,273.21 ; 5.24,261.53 EXT_TRIG.2 ; EXT_TRIG.2 7.1,263.39 ; EXT_TRIG.2 7.1,261.53 ; EXT_TRIG.2 5.24,263.39 ; 217.29,38.84 GND6.1 ; GND6.1 218.83,37.3 ; GND6.1 218.83,38.84 ; GND6.1 217.29,37.3 ; 16.83,280.12 EXT_SYS_N.3 ; EXT_SYS_N.3 18.68,278.27 ; EXT_SYS_N.3 18.68,280.12 ; EXT_SYS_N.3 16.83,278.27 ; REFCLK.2 55.31,213.91 ; REFCLK.2 53.45,213.91 ; REFCLK.2 55.31,215.76 ; REFCLK.2 53.45,215.76 ; EXT_HMCREF.3 45.62,275.2 ; EXT_HMCREF.3 43.76,273.34 ; EXT_HMCREF.3 45.62,273.34 ; EXT_HMCREF.3 43.76,275.2 ; 46.14,243.82 J17.4 ; J17.4 46.14,245.67 ; J17.4 48,243.82 ; J17.4 48,245.67 ; 2.81,62.64 P4.6 2.81,60.92 ; J17.5 48,248.9 ; J17.5 48,250.75 ; J17.5 46.14,248.9 ; J17.5 46.14,250.75 ; EXT_HMCREF.4 45.62,280.28 ; EXT_HMCREF.4 43.76,280.28 ; EXT_HMCREF.4 43.76,278.42 ; EXT_HMCREF.4 45.62,278.42 ; REFN.5 61.35,273.6 ; REFN.5 61.35,275.45 ; REFN.5 59.49,275.45 ; REFN.5 59.49,273.6 ; 43.19,258.21 J12.4 ; J12.4 45.05,256.35 ; J12.4 45.05,258.21 ; J12.4 43.19,256.35 ; 61.63,243.92 J18.2 ; J18.2 63.48,243.92 ; J18.2 61.63,245.77 ; J18.2 63.48,245.77 ; REFP.5 76.97,273.65 ; REFP.5 75.12,273.65 ; REFP.5 76.97,275.51 ; REFP.5 75.12,275.51 ; GND7.1 173.79,83.17 ; GND7.1 173.79,81.63 ; GND7.1 172.26,83.17 ; GND7.1 172.26,81.63 ; J18.5 68.56,243.92 ; J18.5 66.71,245.77 ; J18.5 68.56,245.77 ; J18.5 66.71,243.92 ; 3.82,190.89 P18.GND1 ; P18.GND1 5.22,192.3 ; P18.GND1 5.22,190.89 ; P22.3 220.88,271.5 ; P22.3 220.88,273.53 ; P22.3 218.85,273.53 ; P22.3 218.85,271.5 ; 174.23,165.39 GND8.1 ; GND8.1 175.73,163.9 ; GND8.1 174.23,163.9 ; GND8.1 175.73,165.39
  L9_POWER w0.152: 3.7,57.47 P4.9 ; P4.9 3.7,55.79 ; P4.9 5.76,57.47 ; P4.9 5.76,55.79 ; 80.2,278.73 REFP.3 ; REFP.3 80.2,280.59 ; REFP.3 82.05,280.59 ; REFP.3 82.05,278.73 ; 3.57,49.77 GND5.1 ; GND5.1 3.57,48.23 ; GND5.1 5.11,48.23 ; GND5.1 5.11,49.77 ; 64.57,278.68 REFN.3 ; REFN.3 64.57,280.53 ; REFN.3 66.43,278.68 ; REFN.3 66.43,280.53 ; REFCLK.5 55.31,220.84 ; REFCLK.5 53.45,220.84 ; REFCLK.5 53.45,218.99 ; REFCLK.5 55.31,218.99 ; EXT_TRIG.4 12.18,256.45 ; EXT_TRIG.4 10.32,256.45 ; EXT_TRIG.4 12.18,258.31 ; EXT_TRIG.4 10.32,258.31 ; EXT_HMCREF.4 45.62,278.42 ; EXT_HMCREF.4 43.76,280.28 ; EXT_HMCREF.4 45.62,280.28 ; EXT_HMCREF.4 43.76,278.42 ; EXT_SYNC.2 6.95,246.79 ; EXT_SYNC.2 6.95,244.93 ; EXT_SYNC.2 5.09,244.93 ; EXT_SYNC.2 5.09,246.79 ; 59.49,280.53 REFN.2 ; REFN.2 59.49,278.68 ; REFN.2 61.35,278.68 ; REFN.2 61.35,280.53 ; P19.GND2 5.07,202.89 ; P19.GND2 3.67,202.89 ; P19.GND2 5.07,201.48 ; EXT_HMCREF.2 50.7,275.2 ; EXT_HMCREF.2 48.84,273.34 ; EXT_HMCREF.2 50.7,273.34 ; EXT_HMCREF.2 48.84,275.2 ; REFP.4 82.05,275.51 ; REFP.4 82.05,273.65 ; REFP.4 80.2,273.65 ; REFP.4 80.2,275.51 ; EXT_TRIG.5 7.1,258.31 ; EXT_TRIG.5 5.24,258.31 ; EXT_TRIG.5 5.24,256.45 ; EXT_TRIG.5 7.1,256.45 ; GND2.1 201.2,237.15 ; GND2.1 201.2,235.65 ; GND2.1 199.71,235.65 ; GND2.1 199.71,237.15 ; 48.37,215.76 REFCLK.3 ; REFCLK.3 50.23,215.76 ; REFCLK.3 48.37,213.91 ; REFCLK.3 50.23,213.91 ; 1.13,198.94 P19.GND4 ; P19.GND4 2.53,198.94 ; P19.GND4 1.13,200.35 ; 43.19,263.29 J12.3 ; J12.3 45.05,261.43 ; J12.3 43.19,261.43 ; J12.3 45.05,263.29 ; EXT_SYS_N.4 18.68,273.19 ; EXT_SYS_N.4 16.83,275.04 ; EXT_SYS_N.4 18.68,275.04 ; EXT_SYS_N.4 16.83,273.19 ; S4.GND2 198.1,286.7 ; S4.GND2 196.16,284.75 ; S4.GND2 198.1,284.75 ; S4.GND2 196.16,286.7 ; 48.84,280.28 EXT_HMCREF.5 ; EXT_HMCREF.5 50.7,278.42 ; EXT_HMCREF.5 50.7,280.28 ; EXT_HMCREF.5 48.84,278.42 ; 27.96,263.3 J13.3 ; J13.3 29.82,261.44 ; J13.3 29.82,263.3 ; J13.3 27.96,261.44 ; EXT_SYNC.3 12.03,244.93 ; EXT_SYNC.3 12.03,246.79 ; EXT_SYNC.3 10.17,246.79 ; EXT_SYNC.3 10.17,244.93 ; 1.28,194.84 P18.GND3 ; P18.GND3 1.28,193.43 ; P18.GND3 2.68,194.84 ; 11.75,280.12 EXT_SYS_N.2 ; EXT_SYS_N.2 13.6,280.12 ; EXT_SYS_N.2 11.75,278.27 ; EXT_SYS_N.2 13.6,278.27 ; 48.37,218.99 REFCLK.4 ; REFCLK.4 50.23,220.84 ; REFCLK.4 50.23,218.99 ; REFCLK.4 48.37,220.84 ; 32.73,275.07 EXT_SYS_P.4 ; EXT_SYS_P.4 34.58,273.21 ; EXT_SYS_P.4 32.73,273.21 ; EXT_SYS_P.4 34.58,275.07 ; EXT_TRIG.3 12.18,261.53 ; EXT_TRIG.3 10.32,263.39 ; EXT_TRIG.3 12.18,263.39 ; EXT_TRIG.3 10.32,261.53 ; EXT_SYS_N.5 13.6,275.04 ; EXT_SYS_N.5 11.75,275.04 ; EXT_SYS_N.5 11.75,273.19 ; EXT_SYS_N.5 13.6,273.19 ; EXT_HMCREF.3 45.62,273.34 ; EXT_HMCREF.3 43.76,273.34 ; EXT_HMCREF.3 43.76,275.2 ; EXT_HMCREF.3 45.62,275.2 ; 49.24,194.1 GND4.1 ; GND4.1 50.73,194.1 ; GND4.1 49.24,195.59 ; GND4.1 50.73,195.59 ; GND3.1 58.56,260.24 ; GND3.1 58.56,261.73 ; GND3.1 57.06,260.24 ; GND3.1 57.06,261.73 ; J13.2 24.74,263.3 ; J13.2 22.88,261.44 ; J13.2 24.74,261.44 ; J13.2 22.88,263.3 ; 22.88,258.22 J13.5 ; J13.5 24.74,258.22 ; J13.5 22.88,256.36 ; J13.5 24.74,256.36 ; 32.73,278.29 EXT_SYS_P.3 ; EXT_SYS_P.3 34.58,280.15 ; EXT_SYS_P.3 32.73,280.15 ; EXT_SYS_P.3 34.58,278.29 ; 27.65,280.15 EXT_SYS_P.2 ; EXT_SYS_P.2 29.5,278.29 ; EXT_SYS_P.2 29.5,280.15 ; EXT_SYS_P.2 27.65,278.29 ; EXT_SYNC.5 6.95,239.85 ; EXT_SYNC.5 6.95,241.71 ; EXT_SYNC.5 5.09,241.71 ; EXT_SYNC.5 5.09,239.85 ; REFP.5 76.97,273.65 ; REFP.5 75.12,273.65 ; REFP.5 75.12,275.51 ; REFP.5 76.97,275.51 ; REFN.5 61.35,275.45 ; REFN.5 61.35,273.6 ; REFN.5 59.49,275.45 ; REFN.5 59.49,273.6 ; GND1.1 10.04,100.2 ; GND1.1 10.04,101.73 ; GND1.1 8.5,100.2 ; GND1.1 8.5,101.73 ; 1.28,190.89 P18.GND4 ; P18.GND4 1.28,192.3 ; P18.GND4 2.68,190.89 ; EXT_SYS_N.3 18.68,280.12 ; EXT_SYS_N.3 18.68,278.27 ; EXT_SYS_N.3 16.83,278.27 ; EXT_SYS_N.3 16.83,280.12 ; 2.81,62.64 P4.6 2.81,60.92 ; 218.85,268.02 P22.6 ; P22.6 218.85,265.99 ; P22.6 220.88,268.02 ; P22.6 220.88,265.99 ; 75.12,278.73 REFP.2 ; REFP.2 76.97,280.59 ; REFP.2 76.97,278.73 ; REFP.2 75.12,280.59 ; REFN.4 66.43,273.6 ; REFN.4 64.57,273.6 ; REFN.4 64.57,275.45 ; REFN.4 66.43,275.45 ; EXT_TRIG.2 7.1,261.53 ; EXT_TRIG.2 5.24,263.39 ; EXT_TRIG.2 5.24,261.53 ; EXT_TRIG.2 7.1,263.39 ; P22.3 220.88,273.53 ; P22.3 218.85,271.5 ; P22.3 220.88,271.5 ; P22.3 218.85,273.53 ; 27.65,275.07 EXT_SYS_P.5 ; EXT_SYS_P.5 29.5,275.07 ; EXT_SYS_P.5 29.5,273.21 ; EXT_SYS_P.5 27.65,273.21 ; 217.29,37.3 GND6.1 ; GND6.1 218.83,38.84 ; GND6.1 218.83,37.3 ; GND6.1 217.29,38.84 ; 3.82,190.89 P18.GND1 ; P18.GND1 5.22,190.89 ; P18.GND1 5.22,192.3 ; J12.2 39.97,263.29 ; J12.2 38.11,263.29 ; J12.2 39.97,261.43 ; J12.2 38.11,261.43 ; 1.13,202.89 P19.GND3 ; P19.GND3 1.13,201.48 ; P19.GND3 2.53,202.89 ; 2.81,55.47 P4.7 2.81,57.19 ; P19.GND1 5.07,198.94 ; P19.GND1 5.07,200.35 ; P19.GND1 3.67,198.94 ; S4.GND1 184.89,284.75 ; S4.GND1 182.95,286.7 ; S4.GND1 182.95,284.75 ; S4.GND1 184.89,286.7 ; REFCLK.2 55.31,215.76 ; REFCLK.2 55.31,213.91 ; REFCLK.2 53.45,215.76 ; REFCLK.2 53.45,213.91 ; P18.GND2 5.22,194.84 ; P18.GND2 3.82,194.84 ; P18.GND2 5.22,193.43 ; 3.7,62.32 P4.8 ; P4.8 5.76,62.32 ; P4.8 5.76,60.64 ; P4.8 3.7,60.64
  L10_GROUND w0.152: P18.GND1 5.22,192.3 ; P18.GND1 3.82,190.89 ; P18.GND1 5.22,190.89 ; REFCLK.5 55.31,220.84 ; REFCLK.5 53.45,220.84 ; REFCLK.5 55.31,218.99 ; REFCLK.5 53.45,218.99 ; 218.85,271.5 P22.3 ; P22.3 218.85,273.53 ; P22.3 220.88,271.5 ; P22.3 220.88,273.53 ; EXT_TRIG.2 7.1,263.39 ; EXT_TRIG.2 5.24,261.53 ; EXT_TRIG.2 5.24,263.39 ; EXT_TRIG.2 7.1,261.53 ; GND3.1 58.56,260.24 ; GND3.1 58.56,261.73 ; GND3.1 57.06,260.24 ; GND3.1 57.06,261.73 ; J17.4 48,245.67 ; J17.4 46.14,245.67 ; J17.4 48,243.82 ; J17.4 46.14,243.82 ; 27.96,256.36 J13.4 ; J13.4 29.82,258.22 ; J13.4 27.96,258.22 ; J13.4 29.82,256.36 ; 59.49,273.6 REFN.5 ; REFN.5 59.49,275.45 ; REFN.5 61.35,273.6 ; REFN.5 61.35,275.45 ; 43.19,263.29 J12.3 ; J12.3 45.05,261.43 ; J12.3 43.19,261.43 ; J12.3 45.05,263.29 ; 27.65,273.21 EXT_SYS_P.5 ; EXT_SYS_P.5 29.5,273.21 ; EXT_SYS_P.5 29.5,275.07 ; EXT_SYS_P.5 27.65,275.07 ; 38.11,263.29 J12.2 ; J12.2 38.11,261.43 ; J12.2 39.97,263.29 ; J12.2 39.97,261.43 ; 10.32,261.53 EXT_TRIG.3 ; EXT_TRIG.3 12.18,261.53 ; EXT_TRIG.3 12.18,263.39 ; EXT_TRIG.3 10.32,263.39 ; 5.09,246.79 EXT_SYNC.2 ; EXT_SYNC.2 6.95,244.93 ; EXT_SYNC.2 6.95,246.79 ; EXT_SYNC.2 5.09,244.93 ; P18.GND3 2.68,194.84 ; P18.GND3 1.28,193.43 ; P18.GND3 1.28,194.84 ; 1.13,198.94 P19.GND4 ; P19.GND4 1.13,200.35 ; P19.GND4 2.53,198.94 ; 182.95,284.75 S4.GND1 ; S4.GND1 184.89,286.7 ; S4.GND1 182.95,286.7 ; S4.GND1 184.89,284.75 ; 53.45,215.76 REFCLK.2 ; REFCLK.2 53.45,213.91 ; REFCLK.2 55.31,215.76 ; REFCLK.2 55.31,213.91 ; 32.73,280.15 EXT_SYS_P.3 ; EXT_SYS_P.3 32.73,278.29 ; EXT_SYS_P.3 34.58,280.15 ; EXT_SYS_P.3 34.58,278.29 ; 196.16,286.7 S4.GND2 ; S4.GND2 198.1,286.7 ; S4.GND2 196.16,284.75 ; S4.GND2 198.1,284.75 ; EXT_SYS_P.2 29.5,278.29 ; EXT_SYS_P.2 27.65,278.29 ; EXT_SYS_P.2 29.5,280.15 ; EXT_SYS_P.2 27.65,280.15 ; J13.3 29.82,263.3 ; J13.3 29.82,261.44 ; J13.3 27.96,261.44 ; J13.3 27.96,263.3 ; GND1.1 10.04,101.73 ; GND1.1 8.5,101.73 ; GND1.1 10.04,100.2 ; GND1.1 8.5,100.2 ; EXT_TRIG.4 12.18,256.45 ; EXT_TRIG.4 10.32,256.45 ; EXT_TRIG.4 12.18,258.31 ; EXT_TRIG.4 10.32,258.31 ; J18.3 63.48,249 ; J18.3 63.48,250.85 ; J18.3 61.63,250.85 ; J18.3 61.63,249 ; EXT_SYNC.4 12.03,239.85 ; EXT_SYNC.4 12.03,241.71 ; EXT_SYNC.4 10.17,239.85 ; EXT_SYNC.4 10.17,241.71 ; EXT_SYS_N.5 13.6,273.19 ; EXT_SYS_N.5 11.75,273.19 ; EXT_SYS_N.5 11.75,275.04 ; EXT_SYS_N.5 13.6,275.04 ; GND6.1 218.83,37.3 ; GND6.1 217.29,37.3 ; GND6.1 218.83,38.84 ; GND6.1 217.29,38.84 ; 43.76,278.42 EXT_HMCREF.4 ; EXT_HMCREF.4 45.62,278.42 ; EXT_HMCREF.4 45.62,280.28 ; EXT_HMCREF.4 43.76,280.28 ; J17.3 53.08,243.82 ; J17.3 53.08,245.67 ; J17.3 51.22,245.67 ; J17.3 51.22,243.82 ; 51.22,248.9 J17.2 ; J17.2 51.22,250.75 ; J17.2 53.08,250.75 ; J17.2 53.08,248.9 ; 5.09,239.85 EXT_SYNC.5 ; EXT_SYNC.5 6.95,239.85 ; EXT_SYNC.5 6.95,241.71 ; EXT_SYNC.5 5.09,241.71 ; EXT_SYNC.3 12.03,244.93 ; EXT_SYNC.3 12.03,246.79 ; EXT_SYNC.3 10.17,246.79 ; EXT_SYNC.3 10.17,244.93 ; REFCLK.3 50.23,215.76 ; REFCLK.3 50.23,213.91 ; REFCLK.3 48.37,213.91 ; REFCLK.3 48.37,215.76 ; 61.63,243.92 J18.2 ; J18.2 63.48,245.77 ; J18.2 61.63,245.77 ; J18.2 63.48,243.92 ; GND2.1 201.2,237.15 ; GND2.1 201.2,235.65 ; GND2.1 199.71,235.65 ; GND2.1 199.71,237.15 ; J17.5 48,248.9 ; J17.5 46.14,250.75 ; J17.5 48,250.75 ; J17.5 46.14,248.9 ; EXT_HMCREF.2 50.7,275.2 ; EXT_HMCREF.2 48.84,273.34 ; EXT_HMCREF.2 48.84,275.2 ; EXT_HMCREF.2 50.7,273.34 ; 11.75,278.27 EXT_SYS_N.2 ; EXT_SYS_N.2 13.6,280.12 ; EXT_SYS_N.2 11.75,280.12 ; EXT_SYS_N.2 13.6,278.27 ; REFN.4 66.43,273.6 ; REFN.4 64.57,273.6 ; REFN.4 66.43,275.45 ; REFN.4 64.57,275.45 ; REFP.4 82.05,275.51 ; REFP.4 80.2,273.65 ; REFP.4 82.05,273.65 ; REFP.4 80.2,275.51 ; 3.67,202.89 P19.GND2 ; P19.GND2 5.07,201.48 ; P19.GND2 5.07,202.89 ; 43.19,256.35 J12.4 ; J12.4 45.05,258.21 ; J12.4 45.05,256.35 ; J12.4 43.19,258.21 ; 16.83,278.27 EXT_SYS_N.3 ; EXT_SYS_N.3 18.68,278.27 ; EXT_SYS_N.3 16.83,280.12 ; EXT_SYS_N.3 18.68,280.12 ; 80.2,278.73 REFP.3 ; REFP.3 82.05,278.73 ; REFP.3 80.2,280.59 ; REFP.3 82.05,280.59 ; EXT_SYS_P.4 34.58,275.07 ; EXT_SYS_P.4 32.73,273.21 ; EXT_SYS_P.4 32.73,275.07 ; EXT_SYS_P.4 34.58,273.21 ; 1.28,190.89 P18.GND4 ; P18.GND4 1.28,192.3 ; P18.GND4 2.68,190.89 ; 2.81,55.47 P4.7 2.81,57.19 ; EXT_HMCREF.3 45.62,273.34 ; EXT_HMCREF.3 43.76,275.2 ; EXT_HMCREF.3 43.76,273.34 ; EXT_HMCREF.3 45.62,275.2 ; 38.11,256.35 J12.5 ; J12.5 39.97,256.35 ; J12.5 39.97,258.21 ; J12.5 38.11,258.21 ; 22.88,258.22 J13.5 ; J13.5 24.74,258.22 ; J13.5 24.74,256.36 ; J13.5 22.88,256.36 ; 48.37,218.99 REFCLK.4 ; REFCLK.4 48.37,220.84 ; REFCLK.4 50.23,220.84 ; REFCLK.4 50.23,218.99 ; REFN.3 66.43,278.68 ; REFN.3 64.57,278.68 ; REFN.3 66.43,280.53 ; REFN.3 64.57,280.53 ; 174.23,163.9 GND8.1 ; GND8.1 174.23,165.39 ; GND8.1 175.73,163.9 ; GND8.1 175.73,165.39 ; P19.GND3 2.53,202.89 ; P19.GND3 1.13,201.48 ; P19.GND3 1.13,202.89 ; P22.6 220.88,265.99 ; P22.6 218.85,268.02 ; P22.6 218.85,265.99 ; P22.6 220.88,268.02 ; P4.8 5.76,60.64 ; P4.8 3.7,62.32 ; P4.8 5.76,62.32 ; P4.8 3.7,60.64 ; 172.26,83.17 GND7.1 ; GND7.1 173.79,83.17 ; GND7.1 173.79,81.63 ; GND7.1 172.26,81.63 ; 16.83,273.19 EXT_SYS_N.4 ; EXT_SYS_N.4 16.83,275.04 ; EXT_SYS_N.4 18.68,273.19 ; EXT_SYS_N.4 18.68,275.04 ; 75.12,275.51 REFP.5 ; REFP.5 76.97,275.51 ; REFP.5 76.97,273.65 ; REFP.5 75.12,273.65 ; GND5.1 5.11,48.23 ; GND5.1 5.11,49.77 ; GND5.1 3.57,48.23 ; GND5.1 3.57,49.77 ; P18.GND2 5.22,193.43 ; P18.GND2 5.22,194.84 ; P18.GND2 3.82,194.84 ; 48.84,278.42 EXT_HMCREF.5 ; EXT_HMCREF.5 48.84,280.28 ; EXT_HMCREF.5 50.7,280.28 ; EXT_HMCREF.5 50.7,278.42 ; REFP.2 76.97,280.59 ; REFP.2 76.97,278.73 ; REFP.2 75.12,278.73 ; REFP.2 75.12,280.59 ; J13.2 24.74,261.44 ; J13.2 22.88,263.3 ; J13.2 22.88,261.44 ; J13.2 24.74,263.3 ; J18.4 68.56,249 ; J18.4 66.71,250.85 ; J18.4 68.56,250.85 ; J18.4 66.71,249 ; 49.24,194.1 GND4.1 ; GND4.1 50.73,195.59 ; GND4.1 50.73,194.1 ; GND4.1 49.24,195.59 ; J18.5 68.56,245.77 ; J18.5 68.56,243.92 ; J18.5 66.71,245.77 ; J18.5 66.71,243.92 ; 3.7,57.47 P4.9 ; P4.9 5.76,57.47 ; P4.9 3.7,55.79 ; P4.9 5.76,55.79 ; 5.24,256.45 EXT_TRIG.5 ; EXT_TRIG.5 7.1,256.45 ; EXT_TRIG.5 7.1,258.31 ; EXT_TRIG.5 5.24,258.31 ; 3.67,198.94 P19.GND1 ; P19.GND1 5.07,198.94 ; P19.GND1 5.07,200.35 ; 59.49,280.53 REFN.2 ; REFN.2 61.35,280.53 ; REFN.2 61.35,278.68 ; REFN.2 59.49,278.68 ; 2.81,62.64 P4.6 2.81,60.92
  L11_POWER w0.152: EXT_SYS_N.2 13.6,280.12 ; EXT_SYS_N.2 11.75,278.27 ; EXT_SYS_N.2 11.75,280.12 ; EXT_SYS_N.2 13.6,278.27 ; EXT_TRIG.3 12.18,263.39 ; EXT_TRIG.3 10.32,261.53 ; EXT_TRIG.3 10.32,263.39 ; EXT_TRIG.3 12.18,261.53 ; REFCLK.3 50.23,215.76 ; REFCLK.3 50.23,213.91 ; REFCLK.3 48.37,213.91 ; REFCLK.3 48.37,215.76 ; 2.81,62.64 P4.6 2.81,60.92 ; 27.96,256.36 J13.4 ; J13.4 29.82,258.22 ; J13.4 27.96,258.22 ; J13.4 29.82,256.36 ; REFCLK.2 55.31,213.91 ; REFCLK.2 53.45,215.76 ; REFCLK.2 53.45,213.91 ; REFCLK.2 55.31,215.76 ; J17.2 53.08,248.9 ; J17.2 53.08,250.75 ; J17.2 51.22,250.75 ; J17.2 51.22,248.9 ; 1.13,202.89 P19.GND3 ; P19.GND3 1.13,201.48 ; P19.GND3 2.53,202.89 ; REFN.4 66.43,275.45 ; REFN.4 64.57,275.45 ; REFN.4 64.57,273.6 ; REFN.4 66.43,273.6 ; EXT_SYS_P.3 34.58,278.29 ; EXT_SYS_P.3 32.73,280.15 ; EXT_SYS_P.3 32.73,278.29 ; EXT_SYS_P.3 34.58,280.15 ; J18.2 63.48,243.92 ; J18.2 61.63,243.92 ; J18.2 63.48,245.77 ; J18.2 61.63,245.77 ; EXT_SYNC.4 12.03,241.71 ; EXT_SYNC.4 12.03,239.85 ; EXT_SYNC.4 10.17,239.85 ; EXT_SYNC.4 10.17,241.71 ; GND3.1 58.56,260.24 ; GND3.1 58.56,261.73 ; GND3.1 57.06,260.24 ; GND3.1 57.06,261.73 ; REFN.3 66.43,280.53 ; REFN.3 66.43,278.68 ; REFN.3 64.57,280.53 ; REFN.3 64.57,278.68 ; 3.7,60.64 P4.8 ; P4.8 5.76,60.64 ; P4.8 3.7,62.32 ; P4.8 5.76,62.32 ; 16.83,275.04 EXT_SYS_N.4 ; EXT_SYS_N.4 18.68,273.19 ; EXT_SYS_N.4 18.68,275.04 ; EXT_SYS_N.4 16.83,273.19 ; J17.3 53.08,245.67 ; J17.3 53.08,243.82 ; J17.3 51.22,245.67 ; J17.3 51.22,243.82 ; EXT_HMCREF.5 50.7,278.42 ; EXT_HMCREF.5 48.84,280.28 ; EXT_HMCREF.5 50.7,280.28 ; EXT_HMCREF.5 48.84,278.42 ; EXT_TRIG.5 7.1,256.45 ; EXT_TRIG.5 5.24,258.31 ; EXT_TRIG.5 5.24,256.45 ; EXT_TRIG.5 7.1,258.31 ; REFP.5 76.97,273.65 ; REFP.5 75.12,275.51 ; REFP.5 75.12,273.65 ; REFP.5 76.97,275.51 ; J13.2 24.74,261.44 ; J13.2 22.88,261.44 ; J13.2 24.74,263.3 ; J13.2 22.88,263.3 ; 61.63,249 J18.3 ; J18.3 61.63,250.85 ; J18.3 63.48,250.85 ; J18.3 63.48,249 ; 1.28,194.84 P18.GND3 ; P18.GND3 1.28,193.43 ; P18.GND3 2.68,194.84 ; 48.84,275.2 EXT_HMCREF.2 ; EXT_HMCREF.2 50.7,275.2 ; EXT_HMCREF.2 50.7,273.34 ; EXT_HMCREF.2 48.84,273.34 ; 66.71,245.77 J18.5 ; J18.5 68.56,243.92 ; J18.5 66.71,243.92 ; J18.5 68.56,245.77 ; GND2.1 201.2,237.15 ; GND2.1 201.2,235.65 ; GND2.1 199.71,235.65 ; GND2.1 199.71,237.15 ; 59.49,278.68 REFN.2 ; REFN.2 59.49,280.53 ; REFN.2 61.35,280.53 ; REFN.2 61.35,278.68 ; 10.17,244.93 EXT_SYNC.3 ; EXT_SYNC.3 12.03,246.79 ; EXT_SYNC.3 12.03,244.93 ; EXT_SYNC.3 10.17,246.79 ; 22.88,256.36 J13.5 ; J13.5 24.74,258.22 ; J13.5 22.88,258.22 ; J13.5 24.74,256.36 ; EXT_SYS_P.2 29.5,280.15 ; EXT_SYS_P.2 27.65,280.15 ; EXT_SYS_P.2 29.5,278.29 ; EXT_SYS_P.2 27.65,278.29 ; EXT_SYNC.5 6.95,239.85 ; EXT_SYNC.5 5.09,239.85 ; EXT_SYNC.5 6.95,241.71 ; EXT_SYNC.5 5.09,241.71 ; J12.3 45.05,261.43 ; J12.3 45.05,263.29 ; J12.3 43.19,261.43 ; J12.3 43.19,263.29 ; 1.28,190.89 P18.GND4 ; P18.GND4 2.68,190.89 ; P18.GND4 1.28,192.3 ; J18.4 68.56,250.85 ; J18.4 66.71,250.85 ; J18.4 68.56,249 ; J18.4 66.71,249 ; 10.32,256.45 EXT_TRIG.4 ; EXT_TRIG.4 12.18,256.45 ; EXT_TRIG.4 12.18,258.31 ; EXT_TRIG.4 10.32,258.31 ; 38.11,261.43 J12.2 ; J12.2 39.97,263.29 ; J12.2 39.97,261.43 ; J12.2 38.11,263.29 ; 3.57,48.23 GND5.1 ; GND5.1 3.57,49.77 ; GND5.1 5.11,48.23 ; GND5.1 5.11,49.77 ; 49.24,194.1 GND4.1 ; GND4.1 49.24,195.59 ; GND4.1 50.73,195.59 ; GND4.1 50.73,194.1 ; P18.GND1 5.22,192.3 ; P18.GND1 3.82,190.89 ; P18.GND1 5.22,190.89 ; P19.GND1 5.07,200.35 ; P19.GND1 3.67,198.94 ; P19.GND1 5.07,198.94 ; 3.7,55.79 P4.9 ; P4.9 3.7,57.47 ; P4.9 5.76,57.47 ; P4.9 5.76,55.79 ; REFP.3 82.05,280.59 ; REFP.3 82.05,278.73 ; REFP.3 80.2,280.59 ; REFP.3 80.2,278.73 ; P19.GND4 2.53,198.94 ; P19.GND4 1.13,200.35 ; P19.GND4 1.13,198.94 ; 8.5,101.73 GND1.1 ; GND1.1 10.04,100.2 ; GND1.1 8.5,100.2 ; GND1.1 10.04,101.73 ; 43.76,280.28 EXT_HMCREF.4 ; EXT_HMCREF.4 43.76,278.42 ; EXT_HMCREF.4 45.62,280.28 ; EXT_HMCREF.4 45.62,278.42 ; EXT_SYS_P.4 34.58,273.21 ; EXT_SYS_P.4 32.73,275.07 ; EXT_SYS_P.4 34.58,275.07 ; EXT_SYS_P.4 32.73,273.21 ; 27.65,273.21 EXT_SYS_P.5 ; EXT_SYS_P.5 29.5,275.07 ; EXT_SYS_P.5 27.65,275.07 ; EXT_SYS_P.5 29.5,273.21 ; 43.76,275.2 EXT_HMCREF.3 ; EXT_HMCREF.3 43.76,273.34 ; EXT_HMCREF.3 45.62,275.2 ; EXT_HMCREF.3 45.62,273.34 ; 75.12,280.59 REFP.2 ; REFP.2 76.97,278.73 ; REFP.2 76.97,280.59 ; REFP.2 75.12,278.73 ; J13.3 29.82,263.3 ; J13.3 27.96,261.44 ; J13.3 27.96,263.3 ; J13.3 29.82,261.44 ; J12.4 45.05,258.21 ; J12.4 43.19,256.35 ; J12.4 43.19,258.21 ; J12.4 45.05,256.35 ; 11.75,273.19 EXT_SYS_N.5 ; EXT_SYS_N.5 13.6,275.04 ; EXT_SYS_N.5 13.6,273.19 ; EXT_SYS_N.5 11.75,275.04 ; 198.1,286.7 S4.GND2 196.16,286.7 ; EXT_SYS_N.3 18.68,280.12 ; EXT_SYS_N.3 16.83,278.27 ; EXT_SYS_N.3 16.83,280.12 ; EXT_SYS_N.3 18.68,278.27 ; P19.GND2 5.07,201.48 ; P19.GND2 3.67,202.89 ; P19.GND2 5.07,202.89 ; 5.24,261.53 EXT_TRIG.2 ; EXT_TRIG.2 5.24,263.39 ; EXT_TRIG.2 7.1,263.39 ; EXT_TRIG.2 7.1,261.53 ; 53.45,220.84 REFCLK.5 ; REFCLK.5 55.31,220.84 ; REFCLK.5 53.45,218.99 ; REFCLK.5 55.31,218.99 ; REFN.5 61.35,273.6 ; REFN.5 59.49,275.45 ; REFN.5 61.35,275.45 ; REFN.5 59.49,273.6 ; 46.14,248.9 J17.5 ; J17.5 46.14,250.75 ; J17.5 48,248.9 ; J17.5 48,250.75 ; J12.5 39.97,256.35 ; J12.5 39.97,258.21 ; J12.5 38.11,256.35 ; J12.5 38.11,258.21 ; J17.4 48,243.82 ; J17.4 48,245.67 ; J17.4 46.14,245.67 ; J17.4 46.14,243.82 ; REFP.4 82.05,273.65 ; REFP.4 80.2,273.65 ; REFP.4 80.2,275.51 ; REFP.4 82.05,275.51 ; REFCLK.4 50.23,220.84 ; REFCLK.4 50.23,218.99 ; REFCLK.4 48.37,220.84 ; REFCLK.4 48.37,218.99 ; EXT_SYNC.2 6.95,246.79 ; EXT_SYNC.2 6.95,244.93 ; EXT_SYNC.2 5.09,246.79 ; EXT_SYNC.2 5.09,244.93 ; 2.81,55.47 P4.7 2.81,57.19 ; 3.82,194.84 P18.GND2 ; P18.GND2 5.22,193.43 ; P18.GND2 5.22,194.84 ; 182.95,286.7 S4.GND1 184.89,286.7
  L12_GROUND w0.152: 217.29,37.3 GND6.1 ; GND6.1 218.83,38.84 ; GND6.1 218.83,37.3 ; GND6.1 217.29,38.84 ; GND7.1 173.79,81.63 ; GND7.1 172.26,83.17 ; GND7.1 172.26,81.63 ; GND7.1 173.79,83.17 ; REFP.3 82.05,278.73 ; REFP.3 82.05,280.59 ; REFP.3 80.2,280.59 ; REFP.3 80.2,278.73 ; J12.3 45.05,263.29 ; J12.3 45.05,261.43 ; J12.3 43.19,261.43 ; J12.3 43.19,263.29 ; REFCLK.4 50.23,220.84 ; REFCLK.4 48.37,220.84 ; REFCLK.4 50.23,218.99 ; REFCLK.4 48.37,218.99 ; EXT_TRIG.4 12.18,256.45 ; EXT_TRIG.4 12.18,258.31 ; EXT_TRIG.4 10.32,258.31 ; EXT_TRIG.4 10.32,256.45 ; GND8.1 175.73,163.9 ; GND8.1 174.23,163.9 ; GND8.1 175.73,165.39 ; GND8.1 174.23,165.39 ; 66.71,250.85 J18.4 ; J18.4 68.56,249 ; J18.4 68.56,250.85 ; J18.4 66.71,249 ; EXT_SYNC.2 6.95,246.79 ; EXT_SYNC.2 5.09,246.79 ; EXT_SYNC.2 5.09,244.93 ; EXT_SYNC.2 6.95,244.93 ; 3.82,194.84 P18.GND2 ; P18.GND2 5.22,193.43 ; P18.GND2 5.22,194.84 ; 48.84,275.2 EXT_HMCREF.2 ; EXT_HMCREF.2 48.84,273.34 ; EXT_HMCREF.2 50.7,273.34 ; EXT_HMCREF.2 50.7,275.2 ; 10.17,239.85 EXT_SYNC.4 ; EXT_SYNC.4 10.17,241.71 ; EXT_SYNC.4 12.03,241.71 ; EXT_SYNC.4 12.03,239.85 ; 46.14,243.82 J17.4 ; J17.4 46.14,245.67 ; J17.4 48,245.67 ; J17.4 48,243.82 ; EXT_SYS_N.4 18.68,275.04 ; EXT_SYS_N.4 16.83,275.04 ; EXT_SYS_N.4 16.83,273.19 ; EXT_SYS_N.4 18.68,273.19 ; P19.GND4 2.53,198.94 ; P19.GND4 1.13,200.35 ; P19.GND4 1.13,198.94 ; J12.4 45.05,258.21 ; J12.4 43.19,258.21 ; J12.4 43.19,256.35 ; J12.4 45.05,256.35 ; 53.45,218.99 REFCLK.5 ; REFCLK.5 55.31,218.99 ; REFCLK.5 53.45,220.84 ; REFCLK.5 55.31,220.84 ; S4.GND1 184.89,286.7 ; S4.GND1 182.95,286.7 ; S4.GND1 182.95,284.75 ; S4.GND1 184.89,284.75 ; 8.5,100.2 GND1.1 ; GND1.1 10.04,100.2 ; GND1.1 10.04,101.73 ; GND1.1 8.5,101.73 ; 59.49,278.68 REFN.2 ; REFN.2 61.35,280.53 ; REFN.2 61.35,278.68 ; REFN.2 59.49,280.53 ; J12.2 39.97,263.29 ; J12.2 38.11,261.43 ; J12.2 39.97,261.43 ; J12.2 38.11,263.29 ; REFP.5 76.97,275.51 ; REFP.5 75.12,275.51 ; REFP.5 76.97,273.65 ; REFP.5 75.12,273.65 ; EXT_SYS_N.2 13.6,280.12 ; EXT_SYS_N.2 13.6,278.27 ; EXT_SYS_N.2 11.75,278.27 ; EXT_SYS_N.2 11.75,280.12 ; 32.73,275.07 EXT_SYS_P.4 ; EXT_SYS_P.4 34.58,275.07 ; EXT_SYS_P.4 32.73,273.21 ; EXT_SYS_P.4 34.58,273.21 ; 27.65,273.21 EXT_SYS_P.5 ; EXT_SYS_P.5 29.5,273.21 ; EXT_SYS_P.5 27.65,275.07 ; EXT_SYS_P.5 29.5,275.07 ; EXT_SYS_P.2 29.5,280.15 ; EXT_SYS_P.2 27.65,278.29 ; EXT_SYS_P.2 27.65,280.15 ; EXT_SYS_P.2 29.5,278.29 ; P18.GND1 5.22,192.3 ; P18.GND1 3.82,190.89 ; P18.GND1 5.22,190.89 ; 66.71,245.77 J18.5 ; J18.5 68.56,243.92 ; J18.5 66.71,243.92 ; J18.5 68.56,245.77 ; REFP.2 76.97,280.59 ; REFP.2 75.12,278.73 ; REFP.2 76.97,278.73 ; REFP.2 75.12,280.59 ; 1.13,202.89 P19.GND3 ; P19.GND3 1.13,201.48 ; P19.GND3 2.53,202.89 ; 218.85,268.02 P22.6 ; P22.6 220.88,268.02 ; P22.6 220.88,265.99 ; P22.6 218.85,265.99 ; REFN.3 66.43,280.53 ; REFN.3 66.43,278.68 ; REFN.3 64.57,278.68 ; REFN.3 64.57,280.53 ; 48.37,215.76 REFCLK.3 ; REFCLK.3 50.23,215.76 ; REFCLK.3 50.23,213.91 ; REFCLK.3 48.37,213.91 ; GND5.1 5.11,49.77 ; GND5.1 3.57,48.23 ; GND5.1 3.57,49.77 ; GND5.1 5.11,48.23 ; EXT_SYS_P.3 34.58,278.29 ; EXT_SYS_P.3 32.73,280.15 ; EXT_SYS_P.3 34.58,280.15 ; EXT_SYS_P.3 32.73,278.29 ; 5.09,241.71 EXT_SYNC.5 ; EXT_SYNC.5 6.95,241.71 ; EXT_SYNC.5 6.95,239.85 ; EXT_SYNC.5 5.09,239.85 ; J17.5 48,248.9 ; J17.5 46.14,250.75 ; J17.5 46.14,248.9 ; J17.5 48,250.75 ; 218.85,271.5 P22.3 ; P22.3 220.88,271.5 ; P22.3 218.85,273.53 ; P22.3 220.88,273.53 ; P19.GND1 5.07,200.35 ; P19.GND1 5.07,198.94 ; P19.GND1 3.67,198.94 ; 1.28,194.84 P18.GND3 ; P18.GND3 2.68,194.84 ; P18.GND3 1.28,193.43 ; J13.3 29.82,261.44 ; J13.3 27.96,261.44 ; J13.3 27.96,263.3 ; J13.3 29.82,263.3 ; EXT_HMCREF.4 45.62,278.42 ; EXT_HMCREF.4 43.76,278.42 ; EXT_HMCREF.4 43.76,280.28 ; EXT_HMCREF.4 45.62,280.28 ; EXT_TRIG.5 7.1,258.31 ; EXT_TRIG.5 5.24,256.45 ; EXT_TRIG.5 7.1,256.45 ; EXT_TRIG.5 5.24,258.31 ; 3.7,60.64 P4.8 ; P4.8 3.7,62.32 ; P4.8 5.76,60.64 ; P4.8 5.76,62.32 ; J13.2 24.74,261.44 ; J13.2 22.88,261.44 ; J13.2 24.74,263.3 ; J13.2 22.88,263.3 ; REFN.4 66.43,273.6 ; REFN.4 66.43,275.45 ; REFN.4 64.57,275.45 ; REFN.4 64.57,273.6 ; REFN.5 61.35,273.6 ; REFN.5 61.35,275.45 ; REFN.5 59.49,273.6 ; REFN.5 59.49,275.45 ; EXT_SYS_N.3 18.68,278.27 ; EXT_SYS_N.3 16.83,280.12 ; EXT_SYS_N.3 16.83,278.27 ; EXT_SYS_N.3 18.68,280.12 ; 61.63,245.77 J18.2 ; J18.2 61.63,243.92 ; J18.2 63.48,245.77 ; J18.2 63.48,243.92 ; 80.2,275.51 REFP.4 ; REFP.4 82.05,275.51 ; REFP.4 82.05,273.65 ; REFP.4 80.2,273.65 ; 3.67,202.89 P19.GND2 ; P19.GND2 5.07,201.48 ; P19.GND2 5.07,202.89 ; 53.45,213.91 REFCLK.2 ; REFCLK.2 53.45,215.76 ; REFCLK.2 55.31,215.76 ; REFCLK.2 55.31,213.91 ; J18.3 63.48,249 ; J18.3 63.48,250.85 ; J18.3 61.63,250.85 ; J18.3 61.63,249 ; 57.06,260.24 GND3.1 ; GND3.1 58.56,260.24 ; GND3.1 58.56,261.73 ; GND3.1 57.06,261.73 ; J13.4 29.82,258.22 ; J13.4 29.82,256.36 ; J13.4 27.96,258.22 ; J13.4 27.96,256.36 ; EXT_SYNC.3 12.03,244.93 ; EXT_SYNC.3 10.17,244.93 ; EXT_SYNC.3 10.17,246.79 ; EXT_SYNC.3 12.03,246.79 ; EXT_TRIG.3 12.18,261.53 ; EXT_TRIG.3 10.32,263.39 ; EXT_TRIG.3 10.32,261.53 ; EXT_TRIG.3 12.18,263.39 ; J13.5 24.74,258.22 ; J13.5 22.88,258.22 ; J13.5 24.74,256.36 ; J13.5 22.88,256.36 ; J17.2 53.08,250.75 ; J17.2 53.08,248.9 ; J17.2 51.22,250.75 ; J17.2 51.22,248.9 ; 2.81,57.19 P4.7 2.81,55.47 ; EXT_SYS_N.5 13.6,275.04 ; EXT_SYS_N.5 13.6,273.19 ; EXT_SYS_N.5 11.75,275.04 ; EXT_SYS_N.5 11.75,273.19 ; 2.81,62.64 P4.6 2.81,60.92 ; EXT_TRIG.2 7.1,261.53 ; EXT_TRIG.2 5.24,263.39 ; EXT_TRIG.2 7.1,263.39 ; EXT_TRIG.2 5.24,261.53 ; 199.71,237.15 GND2.1 ; GND2.1 199.71,235.65 ; GND2.1 201.2,235.65 ; GND2.1 201.2,237.15 ; 48.84,280.28 EXT_HMCREF.5 ; EXT_HMCREF.5 48.84,278.42 ; EXT_HMCREF.5 50.7,278.42 ; EXT_HMCREF.5 50.7,280.28 ; GND4.1 50.73,194.1 ; GND4.1 49.24,194.1 ; GND4.1 50.73,195.59 ; GND4.1 49.24,195.59 ; J12.5 39.97,258.21 ; J12.5 38.11,258.21 ; J12.5 38.11,256.35 ; J12.5 39.97,256.35 ; 3.7,55.79 P4.9 ; P4.9 3.7,57.47 ; P4.9 5.76,57.47 ; P4.9 5.76,55.79 ; P18.GND4 2.68,190.89 ; P18.GND4 1.28,190.89 ; P18.GND4 1.28,192.3 ; 43.76,275.2 EXT_HMCREF.3 ; EXT_HMCREF.3 45.62,273.34 ; EXT_HMCREF.3 43.76,273.34 ; EXT_HMCREF.3 45.62,275.2 ; J17.3 53.08,245.67 ; J17.3 51.22,245.67 ; J17.3 51.22,243.82 ; J17.3 53.08,243.82 ; 196.16,286.7 S4.GND2 ; S4.GND2 198.1,284.75 ; S4.GND2 196.16,284.75 ; S4.GND2 198.1,286.7
  L13_GROUND w0.108: 128.3,121.26 128.27,121.29
  L13_GROUND w0.152: 10.17,244.93 EXT_SYNC.3 ; EXT_SYNC.3 12.03,244.93 ; EXT_SYNC.3 10.17,246.79 ; EXT_SYNC.3 12.03,246.79 ; REFN.2 61.35,280.53 ; REFN.2 61.35,278.68 ; REFN.2 59.49,280.53 ; REFN.2 59.49,278.68 ; 5.24,263.39 EXT_TRIG.2 ; EXT_TRIG.2 7.1,261.53 ; EXT_TRIG.2 5.24,261.53 ; EXT_TRIG.2 7.1,263.39 ; 27.65,273.21 EXT_SYS_P.5 ; EXT_SYS_P.5 27.65,275.07 ; EXT_SYS_P.5 29.5,273.21 ; EXT_SYS_P.5 29.5,275.07 ; 8.5,100.2 GND1.1 ; GND1.1 10.04,101.73 ; GND1.1 8.5,101.73 ; GND1.1 10.04,100.2 ; 43.19,261.43 J12.3 ; J12.3 45.05,261.43 ; J12.3 45.05,263.29 ; J12.3 43.19,263.29 ; EXT_SYS_N.5 13.6,275.04 ; EXT_SYS_N.5 11.75,273.19 ; EXT_SYS_N.5 13.6,273.19 ; EXT_SYS_N.5 11.75,275.04 ; 75.12,275.51 REFP.5 ; REFP.5 76.97,273.65 ; REFP.5 76.97,275.51 ; REFP.5 75.12,273.65 ; REFN.5 61.35,275.45 ; REFN.5 59.49,275.45 ; REFN.5 61.35,273.6 ; REFN.5 59.49,273.6 ; 27.96,263.3 J13.3 ; J13.3 29.82,263.3 ; J13.3 29.82,261.44 ; J13.3 27.96,261.44 ; REFN.4 66.43,273.6 ; REFN.4 64.57,273.6 ; REFN.4 64.57,275.45 ; REFN.4 66.43,275.45 ; GND7.1 173.79,83.17 ; GND7.1 173.79,81.63 ; GND7.1 172.26,81.63 ; GND7.1 172.26,83.17 ; GND8.1 175.73,163.9 ; GND8.1 175.73,165.39 ; GND8.1 174.23,163.9 ; GND8.1 174.23,165.39 ; 3.57,49.77 GND5.1 ; GND5.1 5.11,48.23 ; GND5.1 5.11,49.77 ; GND5.1 3.57,48.23 ; P19.GND2 5.07,201.48 ; P19.GND2 5.07,202.89 ; P19.GND2 3.67,202.89 ; EXT_TRIG.4 12.18,256.45 ; EXT_TRIG.4 12.18,258.31 ; EXT_TRIG.4 10.32,256.45 ; EXT_TRIG.4 10.32,258.31 ; J17.3 53.08,243.82 ; J17.3 51.22,245.67 ; J17.3 51.22,243.82 ; J17.3 53.08,245.67 ; J17.2 53.08,250.75 ; J17.2 53.08,248.9 ; J17.2 51.22,250.75 ; J17.2 51.22,248.9 ; EXT_SYNC.2 6.95,244.93 ; EXT_SYNC.2 5.09,244.93 ; EXT_SYNC.2 6.95,246.79 ; EXT_SYNC.2 5.09,246.79 ; 3.7,60.64 P4.8 ; P4.8 3.7,62.32 ; P4.8 5.76,60.64 ; P4.8 5.76,62.32 ; J12.4 45.05,258.21 ; J12.4 43.19,258.21 ; J12.4 43.19,256.35 ; J12.4 45.05,256.35 ; 46.14,248.9 J17.5 ; J17.5 48,248.9 ; J17.5 46.14,250.75 ; J17.5 48,250.75 ; EXT_SYS_N.3 18.68,278.27 ; EXT_SYS_N.3 16.83,280.12 ; EXT_SYS_N.3 18.68,280.12 ; EXT_SYS_N.3 16.83,278.27 ; EXT_TRIG.3 12.18,263.39 ; EXT_TRIG.3 10.32,263.39 ; EXT_TRIG.3 12.18,261.53 ; EXT_TRIG.3 10.32,261.53 ; 2.81,55.47 P4.7 2.81,57.19 ; 16.83,275.04 EXT_SYS_N.4 ; EXT_SYS_N.4 16.83,273.19 ; EXT_SYS_N.4 18.68,273.19 ; EXT_SYS_N.4 18.68,275.04 ; P4.9 5.76,55.79 ; P4.9 3.7,57.47 ; P4.9 5.76,57.47 ; P4.9 3.7,55.79 ; 27.65,280.15 EXT_SYS_P.2 ; EXT_SYS_P.2 27.65,278.29 ; EXT_SYS_P.2 29.5,278.29 ; EXT_SYS_P.2 29.5,280.15 ; P18.GND2 5.22,193.43 ; P18.GND2 5.22,194.84 ; P18.GND2 3.82,194.84 ; 182.95,284.75 S4.GND1 ; S4.GND1 184.89,284.75 ; S4.GND1 184.89,286.7 ; S4.GND1 182.95,286.7 ; 75.12,278.73 REFP.2 ; REFP.2 76.97,278.73 ; REFP.2 76.97,280.59 ; REFP.2 75.12,280.59 ; 46.14,243.82 J17.4 ; J17.4 48,245.67 ; J17.4 48,243.82 ; J17.4 46.14,245.67 ; 66.71,243.92 J18.5 ; J18.5 68.56,245.77 ; J18.5 68.56,243.92 ; J18.5 66.71,245.77 ; REFP.4 82.05,275.51 ; REFP.4 82.05,273.65 ; REFP.4 80.2,273.65 ; REFP.4 80.2,275.51 ; REFCLK.2 55.31,213.91 ; REFCLK.2 55.31,215.76 ; REFCLK.2 53.45,213.91 ; REFCLK.2 53.45,215.76 ; P19.GND1 5.07,198.94 ; P19.GND1 3.67,198.94 ; P19.GND1 5.07,200.35 ; 48.37,218.99 REFCLK.4 ; REFCLK.4 50.23,220.84 ; REFCLK.4 48.37,220.84 ; REFCLK.4 50.23,218.99 ; 48.84,273.34 EXT_HMCREF.2 ; EXT_HMCREF.2 50.7,273.34 ; EXT_HMCREF.2 48.84,275.2 ; EXT_HMCREF.2 50.7,275.2 ; 1.13,202.89 P19.GND3 ; P19.GND3 2.53,202.89 ; P19.GND3 1.13,201.48 ; 64.57,278.68 REFN.3 ; REFN.3 66.43,278.68 ; REFN.3 66.43,280.53 ; REFN.3 64.57,280.53 ; 22.88,256.36 J13.5 ; J13.5 24.74,256.36 ; J13.5 22.88,258.22 ; J13.5 24.74,258.22 ; P22.6 220.88,265.99 ; P22.6 218.85,265.99 ; P22.6 220.88,268.02 ; P22.6 218.85,268.02 ; REFCLK.5 55.31,220.84 ; REFCLK.5 53.45,218.99 ; REFCLK.5 53.45,220.84 ; REFCLK.5 55.31,218.99 ; 43.76,280.28 EXT_HMCREF.4 ; EXT_HMCREF.4 45.62,280.28 ; EXT_HMCREF.4 43.76,278.42 ; EXT_HMCREF.4 45.62,278.42 ; 43.76,275.2 EXT_HMCREF.3 ; EXT_HMCREF.3 45.62,273.34 ; EXT_HMCREF.3 43.76,273.34 ; EXT_HMCREF.3 45.62,275.2 ; 48.84,280.28 EXT_HMCREF.5 ; EXT_HMCREF.5 50.7,278.42 ; EXT_HMCREF.5 50.7,280.28 ; EXT_HMCREF.5 48.84,278.42 ; GND6.1 218.83,37.3 ; GND6.1 217.29,38.84 ; GND6.1 218.83,38.84 ; GND6.1 217.29,37.3 ; J18.2 63.48,243.92 ; J18.2 61.63,245.77 ; J18.2 61.63,243.92 ; J18.2 63.48,245.77 ; EXT_SYS_P.4 34.58,275.07 ; EXT_SYS_P.4 32.73,273.21 ; EXT_SYS_P.4 34.58,273.21 ; EXT_SYS_P.4 32.73,275.07 ; 48.37,215.76 REFCLK.3 ; REFCLK.3 48.37,213.91 ; REFCLK.3 50.23,215.76 ; REFCLK.3 50.23,213.91 ; 1.28,190.89 P18.GND4 ; P18.GND4 1.28,192.3 ; P18.GND4 2.68,190.89 ; 1.28,193.43 P18.GND3 ; P18.GND3 2.68,194.84 ; P18.GND3 1.28,194.84 ; 1.13,200.35 P19.GND4 ; P19.GND4 1.13,198.94 ; P19.GND4 2.53,198.94 ; 80.2,280.59 REFP.3 ; REFP.3 80.2,278.73 ; REFP.3 82.05,280.59 ; REFP.3 82.05,278.73 ; J13.2 24.74,263.3 ; J13.2 22.88,261.44 ; J13.2 22.88,263.3 ; J13.2 24.74,261.44 ; S4.GND2 198.1,284.75 ; S4.GND2 198.1,286.7 ; S4.GND2 196.16,284.75 ; S4.GND2 196.16,286.7 ; J12.5 39.97,256.35 ; J12.5 38.11,258.21 ; J12.5 39.97,258.21 ; J12.5 38.11,256.35 ; EXT_TRIG.5 7.1,258.31 ; EXT_TRIG.5 7.1,256.45 ; EXT_TRIG.5 5.24,258.31 ; EXT_TRIG.5 5.24,256.45 ; 61.63,250.85 J18.3 ; J18.3 63.48,250.85 ; J18.3 63.48,249 ; J18.3 61.63,249 ; 10.17,241.71 EXT_SYNC.4 ; EXT_SYNC.4 10.17,239.85 ; EXT_SYNC.4 12.03,241.71 ; EXT_SYNC.4 12.03,239.85 ; 5.09,239.85 EXT_SYNC.5 ; EXT_SYNC.5 6.95,239.85 ; EXT_SYNC.5 5.09,241.71 ; EXT_SYNC.5 6.95,241.71 ; 218.85,273.53 P22.3 ; P22.3 220.88,273.53 ; P22.3 220.88,271.5 ; P22.3 218.85,271.5 ; 66.71,249 J18.4 ; J18.4 68.56,250.85 ; J18.4 68.56,249 ; J18.4 66.71,250.85 ; GND4.1 50.73,195.59 ; GND4.1 49.24,194.1 ; GND4.1 49.24,195.59 ; GND4.1 50.73,194.1 ; J13.4 29.82,258.22 ; J13.4 27.96,256.36 ; J13.4 29.82,256.36 ; J13.4 27.96,258.22 ; 199.71,237.15 GND2.1 ; GND2.1 201.2,237.15 ; GND2.1 201.2,235.65 ; GND2.1 199.71,235.65 ; P18.GND1 5.22,190.89 ; P18.GND1 3.82,190.89 ; P18.GND1 5.22,192.3 ; 57.06,261.73 GND3.1 ; GND3.1 58.56,261.73 ; GND3.1 57.06,260.24 ; GND3.1 58.56,260.24 ; 38.11,263.29 J12.2 ; J12.2 38.11,261.43 ; J12.2 39.97,261.43 ; J12.2 39.97,263.29 ; 32.73,280.15 EXT_SYS_P.3 ; EXT_SYS_P.3 34.58,280.15 ; EXT_SYS_P.3 34.58,278.29 ; EXT_SYS_P.3 32.73,278.29 ; EXT_SYS_N.2 13.6,280.12 ; EXT_SYS_N.2 11.75,280.12 ; EXT_SYS_N.2 11.75,278.27 ; EXT_SYS_N.2 13.6,278.27 ; 2.81,62.64 P4.6 2.81,60.92
  L14_POWER w0.152: GND2.1 201.2,235.65 ; GND2.1 199.71,235.65 ; GND2.1 199.71,237.15 ; GND2.1 201.2,237.15 ; EXT_SYS_P.5 29.5,273.21 ; EXT_SYS_P.5 27.65,275.07 ; EXT_SYS_P.5 29.5,275.07 ; EXT_SYS_P.5 27.65,273.21 ; 27.96,258.22 J13.4 ; J13.4 27.96,256.36 ; J13.4 29.82,258.22 ; J13.4 29.82,256.36 ; P18.GND3 2.68,194.84 ; P18.GND3 1.28,194.84 ; P18.GND3 1.28,193.43 ; GND5.1 5.11,48.23 ; GND5.1 3.57,48.23 ; GND5.1 5.11,49.77 ; GND5.1 3.57,49.77 ; 48.84,275.2 EXT_HMCREF.2 ; EXT_HMCREF.2 50.7,275.2 ; EXT_HMCREF.2 50.7,273.34 ; EXT_HMCREF.2 48.84,273.34 ; J12.5 39.97,258.21 ; J12.5 38.11,258.21 ; J12.5 39.97,256.35 ; J12.5 38.11,256.35 ; EXT_HMCREF.3 45.62,273.34 ; EXT_HMCREF.3 45.62,275.2 ; EXT_HMCREF.3 43.76,275.2 ; EXT_HMCREF.3 43.76,273.34 ; REFP.3 82.05,280.59 ; REFP.3 80.2,280.59 ; REFP.3 82.05,278.73 ; REFP.3 80.2,278.73 ; 59.49,278.68 REFN.2 ; REFN.2 61.35,280.53 ; REFN.2 61.35,278.68 ; REFN.2 59.49,280.53 ; 75.12,273.65 REFP.5 ; REFP.5 75.12,275.51 ; REFP.5 76.97,273.65 ; REFP.5 76.97,275.51 ; 53.45,215.76 REFCLK.2 ; REFCLK.2 53.45,213.91 ; REFCLK.2 55.31,213.91 ; REFCLK.2 55.31,215.76 ; P18.GND2 5.22,194.84 ; P18.GND2 3.82,194.84 ; P18.GND2 5.22,193.43 ; 32.73,280.15 EXT_SYS_P.3 ; EXT_SYS_P.3 32.73,278.29 ; EXT_SYS_P.3 34.58,280.15 ; EXT_SYS_P.3 34.58,278.29 ; P19.GND1 5.07,200.35 ; P19.GND1 5.07,198.94 ; P19.GND1 3.67,198.94 ; J18.4 68.56,250.85 ; J18.4 66.71,250.85 ; J18.4 68.56,249 ; J18.4 66.71,249 ; EXT_SYS_N.3 18.68,278.27 ; EXT_SYS_N.3 18.68,280.12 ; EXT_SYS_N.3 16.83,278.27 ; EXT_SYS_N.3 16.83,280.12 ; J17.2 53.08,250.75 ; J17.2 51.22,248.9 ; J17.2 53.08,248.9 ; J17.2 51.22,250.75 ; J12.2 39.97,263.29 ; J12.2 39.97,261.43 ; J12.2 38.11,263.29 ; J12.2 38.11,261.43 ; P4.9 5.76,57.47 ; P4.9 3.7,55.79 ; P4.9 5.76,55.79 ; P4.9 3.7,57.47 ; 5.24,261.53 EXT_TRIG.2 ; EXT_TRIG.2 7.1,261.53 ; EXT_TRIG.2 5.24,263.39 ; EXT_TRIG.2 7.1,263.39 ; GND3.1 58.56,260.24 ; GND3.1 57.06,261.73 ; GND3.1 58.56,261.73 ; GND3.1 57.06,260.24 ; EXT_TRIG.3 12.18,263.39 ; EXT_TRIG.3 10.32,263.39 ; EXT_TRIG.3 10.32,261.53 ; EXT_TRIG.3 12.18,261.53 ; 22.88,263.3 J13.2 ; J13.2 22.88,261.44 ; J13.2 24.74,261.44 ; J13.2 24.74,263.3 ; 174.23,165.39 GND8.1 ; GND8.1 175.73,163.9 ; GND8.1 174.23,163.9 ; GND8.1 175.73,165.39 ; 48.84,280.28 EXT_HMCREF.5 ; EXT_HMCREF.5 50.7,280.28 ; EXT_HMCREF.5 48.84,278.42 ; EXT_HMCREF.5 50.7,278.42 ; P19.GND4 2.53,198.94 ; P19.GND4 1.13,198.94 ; P19.GND4 1.13,200.35 ; 27.96,261.44 J13.3 ; J13.3 29.82,263.3 ; J13.3 29.82,261.44 ; J13.3 27.96,263.3 ; J18.2 63.48,245.77 ; J18.2 61.63,243.92 ; J18.2 61.63,245.77 ; J18.2 63.48,243.92 ; EXT_TRIG.5 7.1,256.45 ; EXT_TRIG.5 5.24,258.31 ; EXT_TRIG.5 5.24,256.45 ; EXT_TRIG.5 7.1,258.31 ; 10.32,258.31 EXT_TRIG.4 ; EXT_TRIG.4 12.18,258.31 ; EXT_TRIG.4 12.18,256.45 ; EXT_TRIG.4 10.32,256.45 ; 10.17,244.93 EXT_SYNC.3 ; EXT_SYNC.3 12.03,244.93 ; EXT_SYNC.3 12.03,246.79 ; EXT_SYNC.3 10.17,246.79 ; J17.4 48,245.67 ; J17.4 46.14,243.82 ; J17.4 46.14,245.67 ; J17.4 48,243.82 ; REFN.3 66.43,280.53 ; REFN.3 66.43,278.68 ; REFN.3 64.57,278.68 ; REFN.3 64.57,280.53 ; 53.45,218.99 REFCLK.5 ; REFCLK.5 53.45,220.84 ; REFCLK.5 55.31,218.99 ; REFCLK.5 55.31,220.84 ; 5.09,241.71 EXT_SYNC.5 ; EXT_SYNC.5 6.95,239.85 ; EXT_SYNC.5 5.09,239.85 ; EXT_SYNC.5 6.95,241.71 ; 16.83,273.19 EXT_SYS_N.4 ; EXT_SYS_N.4 18.68,273.19 ; EXT_SYS_N.4 18.68,275.04 ; EXT_SYS_N.4 16.83,275.04 ; EXT_SYS_P.4 34.58,273.21 ; EXT_SYS_P.4 32.73,275.07 ; EXT_SYS_P.4 34.58,275.07 ; EXT_SYS_P.4 32.73,273.21 ; EXT_SYS_N.5 13.6,275.04 ; EXT_SYS_N.5 13.6,273.19 ; EXT_SYS_N.5 11.75,273.19 ; EXT_SYS_N.5 11.75,275.04 ; 43.76,278.42 EXT_HMCREF.4 ; EXT_HMCREF.4 43.76,280.28 ; EXT_HMCREF.4 45.62,280.28 ; EXT_HMCREF.4 45.62,278.42 ; REFP.4 82.05,273.65 ; REFP.4 80.2,275.51 ; REFP.4 80.2,273.65 ; REFP.4 82.05,275.51 ; 3.7,62.32 P4.8 ; P4.8 5.76,60.64 ; P4.8 5.76,62.32 ; P4.8 3.7,60.64 ; 3.67,202.89 P19.GND2 ; P19.GND2 5.07,201.48 ; P19.GND2 5.07,202.89 ; J18.5 68.56,243.92 ; J18.5 68.56,245.77 ; J18.5 66.71,245.77 ; J18.5 66.71,243.92 ; 27.65,280.15 EXT_SYS_P.2 ; EXT_SYS_P.2 27.65,278.29 ; EXT_SYS_P.2 29.5,280.15 ; EXT_SYS_P.2 29.5,278.29 ; 5.09,244.93 EXT_SYNC.2 ; EXT_SYNC.2 6.95,244.93 ; EXT_SYNC.2 5.09,246.79 ; EXT_SYNC.2 6.95,246.79 ; REFN.5 61.35,275.45 ; REFN.5 59.49,275.45 ; REFN.5 61.35,273.6 ; REFN.5 59.49,273.6 ; REFP.2 76.97,280.59 ; REFP.2 76.97,278.73 ; REFP.2 75.12,280.59 ; REFP.2 75.12,278.73 ; 64.57,275.45 REFN.4 ; REFN.4 66.43,273.6 ; REFN.4 66.43,275.45 ; REFN.4 64.57,273.6 ; 3.82,190.89 P18.GND1 ; P18.GND1 5.22,190.89 ; P18.GND1 5.22,192.3 ; 48.37,213.91 REFCLK.3 ; REFCLK.3 50.23,215.76 ; REFCLK.3 50.23,213.91 ; REFCLK.3 48.37,215.76 ; 2.81,57.19 P4.7 2.81,55.47 ; J13.5 24.74,256.36 ; J13.5 22.88,258.22 ; J13.5 22.88,256.36 ; J13.5 24.74,258.22 ; 43.19,263.29 J12.3 ; J12.3 43.19,261.43 ; J12.3 45.05,263.29 ; J12.3 45.05,261.43 ; 51.22,243.82 J17.3 ; J17.3 51.22,245.67 ; J17.3 53.08,245.67 ; J17.3 53.08,243.82 ; P19.GND3 2.53,202.89 ; P19.GND3 1.13,202.89 ; P19.GND3 1.13,201.48 ; 46.14,250.75 J17.5 ; J17.5 48,248.9 ; J17.5 46.14,248.9 ; J17.5 48,250.75 ; 48.37,218.99 REFCLK.4 ; REFCLK.4 48.37,220.84 ; REFCLK.4 50.23,220.84 ; REFCLK.4 50.23,218.99 ; J12.4 45.05,256.35 ; J12.4 43.19,258.21 ; J12.4 43.19,256.35 ; J12.4 45.05,258.21 ; EXT_SYNC.4 12.03,241.71 ; EXT_SYNC.4 10.17,241.71 ; EXT_SYNC.4 12.03,239.85 ; EXT_SYNC.4 10.17,239.85 ; 61.63,250.85 J18.3 ; J18.3 61.63,249 ; J18.3 63.48,249 ; J18.3 63.48,250.85 ; 49.24,195.59 GND4.1 ; GND4.1 49.24,194.1 ; GND4.1 50.73,195.59 ; GND4.1 50.73,194.1 ; GND1.1 10.04,101.73 ; GND1.1 10.04,100.2 ; GND1.1 8.5,100.2 ; GND1.1 8.5,101.73 ; 2.81,60.92 P4.6 2.81,62.64 ; P18.GND4 2.68,190.89 ; P18.GND4 1.28,190.89 ; P18.GND4 1.28,192.3 ; EXT_SYS_N.2 13.6,280.12 ; EXT_SYS_N.2 13.6,278.27 ; EXT_SYS_N.2 11.75,278.27 ; EXT_SYS_N.2 11.75,280.12
  L15_GROUND w0.152: P18.GND4 2.68,190.89 ; P18.GND4 1.28,192.3 ; P18.GND4 1.28,190.89 ; 43.76,278.42 EXT_HMCREF.4 ; EXT_HMCREF.4 45.62,280.28 ; EXT_HMCREF.4 45.62,278.42 ; EXT_HMCREF.4 43.76,280.28 ; GND2.1 201.2,237.15 ; GND2.1 201.2,235.65 ; GND2.1 199.71,237.15 ; GND2.1 199.71,235.65 ; 11.75,280.12 EXT_SYS_N.2 ; EXT_SYS_N.2 13.6,278.27 ; EXT_SYS_N.2 13.6,280.12 ; EXT_SYS_N.2 11.75,278.27 ; REFP.5 76.97,273.65 ; REFP.5 75.12,273.65 ; REFP.5 76.97,275.51 ; REFP.5 75.12,275.51 ; 22.88,263.3 J13.2 ; J13.2 24.74,261.44 ; J13.2 24.74,263.3 ; J13.2 22.88,261.44 ; 3.7,60.64 P4.8 ; P4.8 5.76,62.32 ; P4.8 3.7,62.32 ; P4.8 5.76,60.64 ; J18.4 68.56,250.85 ; J18.4 68.56,249 ; J18.4 66.71,250.85 ; J18.4 66.71,249 ; EXT_SYNC.2 6.95,246.79 ; EXT_SYNC.2 5.09,246.79 ; EXT_SYNC.2 5.09,244.93 ; EXT_SYNC.2 6.95,244.93 ; 75.12,280.59 REFP.2 ; REFP.2 76.97,280.59 ; REFP.2 76.97,278.73 ; REFP.2 75.12,278.73 ; REFCLK.5 55.31,218.99 ; REFCLK.5 53.45,220.84 ; REFCLK.5 55.31,220.84 ; REFCLK.5 53.45,218.99 ; 48.37,213.91 REFCLK.3 ; REFCLK.3 48.37,215.76 ; REFCLK.3 50.23,213.91 ; REFCLK.3 50.23,215.76 ; EXT_SYS_P.5 29.5,273.21 ; EXT_SYS_P.5 27.65,273.21 ; EXT_SYS_P.5 29.5,275.07 ; EXT_SYS_P.5 27.65,275.07 ; 27.96,261.44 J13.3 ; J13.3 29.82,263.3 ; J13.3 27.96,263.3 ; J13.3 29.82,261.44 ; EXT_SYS_N.5 13.6,273.19 ; EXT_SYS_N.5 11.75,275.04 ; EXT_SYS_N.5 11.75,273.19 ; EXT_SYS_N.5 13.6,275.04 ; REFN.5 61.35,273.6 ; REFN.5 61.35,275.45 ; REFN.5 59.49,273.6 ; REFN.5 59.49,275.45 ; J12.2 39.97,261.43 ; J12.2 38.11,263.29 ; J12.2 39.97,263.29 ; J12.2 38.11,261.43 ; GND5.1 5.11,49.77 ; GND5.1 3.57,49.77 ; GND5.1 5.11,48.23 ; GND5.1 3.57,48.23 ; GND7.1 173.79,83.17 ; GND7.1 173.79,81.63 ; GND7.1 172.26,81.63 ; GND7.1 172.26,83.17 ; EXT_SYNC.3 12.03,244.93 ; EXT_SYNC.3 12.03,246.79 ; EXT_SYNC.3 10.17,246.79 ; EXT_SYNC.3 10.17,244.93 ; 2.81,57.19 P4.7 2.81,55.47 ; 64.57,278.68 REFN.3 ; REFN.3 66.43,278.68 ; REFN.3 66.43,280.53 ; REFN.3 64.57,280.53 ; 10.32,263.39 EXT_TRIG.3 ; EXT_TRIG.3 10.32,261.53 ; EXT_TRIG.3 12.18,263.39 ; EXT_TRIG.3 12.18,261.53 ; EXT_SYS_P.3 34.58,278.29 ; EXT_SYS_P.3 32.73,280.15 ; EXT_SYS_P.3 32.73,278.29 ; EXT_SYS_P.3 34.58,280.15 ; 32.73,273.21 EXT_SYS_P.4 ; EXT_SYS_P.4 32.73,275.07 ; EXT_SYS_P.4 34.58,275.07 ; EXT_SYS_P.4 34.58,273.21 ; 10.32,256.45 EXT_TRIG.4 ; EXT_TRIG.4 12.18,258.31 ; EXT_TRIG.4 10.32,258.31 ; EXT_TRIG.4 12.18,256.45 ; 49.24,195.59 GND4.1 ; GND4.1 49.24,194.1 ; GND4.1 50.73,194.1 ; GND4.1 50.73,195.59 ; S4.GND2 198.1,284.75 ; S4.GND2 196.16,284.75 ; S4.GND2 198.1,286.7 ; S4.GND2 196.16,286.7 ; J13.5 24.74,256.36 ; J13.5 22.88,258.22 ; J13.5 22.88,256.36 ; J13.5 24.74,258.22 ; REFCLK.4 50.23,218.99 ; REFCLK.4 48.37,218.99 ; REFCLK.4 50.23,220.84 ; REFCLK.4 48.37,220.84 ; 80.2,275.51 REFP.4 ; REFP.4 80.2,273.65 ; REFP.4 82.05,275.51 ; REFP.4 82.05,273.65 ; 1.28,194.84 P18.GND3 ; P18.GND3 1.28,193.43 ; P18.GND3 2.68,194.84 ; EXT_HMCREF.5 50.7,278.42 ; EXT_HMCREF.5 48.84,280.28 ; EXT_HMCREF.5 48.84,278.42 ; EXT_HMCREF.5 50.7,280.28 ; REFN.4 66.43,275.45 ; REFN.4 64.57,273.6 ; REFN.4 64.57,275.45 ; REFN.4 66.43,273.6 ; 1.13,201.48 P19.GND3 ; P19.GND3 2.53,202.89 ; P19.GND3 1.13,202.89 ; 174.23,163.9 GND8.1 ; GND8.1 175.73,163.9 ; GND8.1 175.73,165.39 ; GND8.1 174.23,165.39 ; EXT_HMCREF.3 45.62,273.34 ; EXT_HMCREF.3 45.62,275.2 ; EXT_HMCREF.3 43.76,273.34 ; EXT_HMCREF.3 43.76,275.2 ; 10.17,239.85 EXT_SYNC.4 ; EXT_SYNC.4 12.03,241.71 ; EXT_SYNC.4 12.03,239.85 ; EXT_SYNC.4 10.17,241.71 ; GND6.1 218.83,38.84 ; GND6.1 217.29,37.3 ; GND6.1 217.29,38.84 ; GND6.1 218.83,37.3 ; 43.19,256.35 J12.4 ; J12.4 45.05,256.35 ; J12.4 43.19,258.21 ; J12.4 45.05,258.21 ; 46.14,245.67 J17.4 ; J17.4 48,243.82 ; J17.4 48,245.67 ; J17.4 46.14,243.82 ; 3.82,190.89 P18.GND1 ; P18.GND1 5.22,192.3 ; P18.GND1 5.22,190.89 ; 61.63,245.77 J18.2 ; J18.2 63.48,243.92 ; J18.2 61.63,243.92 ; J18.2 63.48,245.77 ; 16.83,275.04 EXT_SYS_N.4 ; EXT_SYS_N.4 18.68,273.19 ; EXT_SYS_N.4 16.83,273.19 ; EXT_SYS_N.4 18.68,275.04 ; P19.GND2 5.07,202.89 ; P19.GND2 5.07,201.48 ; P19.GND2 3.67,202.89 ; J17.2 53.08,248.9 ; J17.2 51.22,250.75 ; J17.2 53.08,250.75 ; J17.2 51.22,248.9 ; J12.5 39.97,258.21 ; J12.5 38.11,256.35 ; J12.5 39.97,256.35 ; J12.5 38.11,258.21 ; 5.24,256.45 EXT_TRIG.5 ; EXT_TRIG.5 7.1,258.31 ; EXT_TRIG.5 5.24,258.31 ; EXT_TRIG.5 7.1,256.45 ; 3.7,57.47 P4.9 ; P4.9 5.76,57.47 ; P4.9 5.76,55.79 ; P4.9 3.7,55.79 ; S4.GND1 184.89,286.7 ; S4.GND1 182.95,286.7 ; S4.GND1 184.89,284.75 ; S4.GND1 182.95,284.75 ; 43.19,263.29 J12.3 ; J12.3 45.05,263.29 ; J12.3 43.19,261.43 ; J12.3 45.05,261.43 ; EXT_HMCREF.2 50.7,275.2 ; EXT_HMCREF.2 48.84,275.2 ; EXT_HMCREF.2 48.84,273.34 ; EXT_HMCREF.2 50.7,273.34 ; 2.81,60.92 P4.6 2.81,62.64 ; J13.4 29.82,256.36 ; J13.4 27.96,256.36 ; J13.4 29.82,258.22 ; J13.4 27.96,258.22 ; EXT_SYS_N.3 18.68,278.27 ; EXT_SYS_N.3 16.83,278.27 ; EXT_SYS_N.3 16.83,280.12 ; EXT_SYS_N.3 18.68,280.12 ; 80.2,278.73 REFP.3 ; REFP.3 82.05,280.59 ; REFP.3 82.05,278.73 ; REFP.3 80.2,280.59 ; 8.5,100.2 GND1.1 ; GND1.1 8.5,101.73 ; GND1.1 10.04,101.73 ; GND1.1 10.04,100.2 ; EXT_TRIG.2 7.1,263.39 ; EXT_TRIG.2 5.24,261.53 ; EXT_TRIG.2 7.1,261.53 ; EXT_TRIG.2 5.24,263.39 ; REFCLK.2 55.31,215.76 ; REFCLK.2 53.45,215.76 ; REFCLK.2 53.45,213.91 ; REFCLK.2 55.31,213.91 ; 61.63,250.85 J18.3 ; J18.3 63.48,250.85 ; J18.3 63.48,249 ; J18.3 61.63,249 ; 27.65,278.29 EXT_SYS_P.2 ; EXT_SYS_P.2 29.5,280.15 ; EXT_SYS_P.2 27.65,280.15 ; EXT_SYS_P.2 29.5,278.29 ; 218.85,273.53 P22.3 ; P22.3 220.88,273.53 ; P22.3 220.88,271.5 ; P22.3 218.85,271.5 ; 218.85,265.99 P22.6 ; P22.6 218.85,268.02 ; P22.6 220.88,265.99 ; P22.6 220.88,268.02 ; P19.GND1 5.07,200.35 ; P19.GND1 3.67,198.94 ; P19.GND1 5.07,198.94 ; J17.5 48,250.75 ; J17.5 48,248.9 ; J17.5 46.14,250.75 ; J17.5 46.14,248.9 ; J17.3 53.08,245.67 ; J17.3 51.22,243.82 ; J17.3 53.08,243.82 ; J17.3 51.22,245.67 ; 1.13,200.35 P19.GND4 ; P19.GND4 2.53,198.94 ; P19.GND4 1.13,198.94 ; EXT_SYNC.5 6.95,241.71 ; EXT_SYNC.5 5.09,239.85 ; EXT_SYNC.5 6.95,239.85 ; EXT_SYNC.5 5.09,241.71 ; 59.49,280.53 REFN.2 ; REFN.2 61.35,280.53 ; REFN.2 61.35,278.68 ; REFN.2 59.49,278.68 ; 3.82,194.84 P18.GND2 ; P18.GND2 5.22,193.43 ; P18.GND2 5.22,194.84 ; J18.5 68.56,243.92 ; J18.5 68.56,245.77 ; J18.5 66.71,245.77 ; J18.5 66.71,243.92 ; 57.06,260.24 GND3.1 ; GND3.1 58.56,261.73 ; GND3.1 58.56,260.24 ; GND3.1 57.06,261.73
  L16_POWER w0.152: 16.83,278.27 EXT_SYS_N.3 ; EXT_SYS_N.3 18.68,280.12 ; EXT_SYS_N.3 16.83,280.12 ; EXT_SYS_N.3 18.68,278.27 ; REFCLK.3 50.23,215.76 ; REFCLK.3 48.37,213.91 ; REFCLK.3 48.37,215.76 ; REFCLK.3 50.23,213.91 ; EXT_SYS_P.2 29.5,278.29 ; EXT_SYS_P.2 29.5,280.15 ; EXT_SYS_P.2 27.65,278.29 ; EXT_SYS_P.2 27.65,280.15 ; 66.71,243.92 J18.5 ; J18.5 68.56,243.92 ; J18.5 68.56,245.77 ; J18.5 66.71,245.77 ; 43.76,275.2 EXT_HMCREF.3 ; EXT_HMCREF.3 45.62,275.2 ; EXT_HMCREF.3 45.62,273.34 ; EXT_HMCREF.3 43.76,273.34 ; REFP.2 76.97,278.73 ; REFP.2 75.12,278.73 ; REFP.2 76.97,280.59 ; REFP.2 75.12,280.59 ; S4.GND1 184.89,286.7 ; S4.GND1 182.95,284.75 ; S4.GND1 182.95,286.7 ; S4.GND1 184.89,284.75 ; 43.19,261.43 J12.3 ; J12.3 45.05,263.29 ; J12.3 43.19,263.29 ; J12.3 45.05,261.43 ; 46.14,245.67 J17.4 ; J17.4 48,243.82 ; J17.4 48,245.67 ; J17.4 46.14,243.82 ; EXT_TRIG.2 7.1,263.39 ; EXT_TRIG.2 5.24,261.53 ; EXT_TRIG.2 5.24,263.39 ; EXT_TRIG.2 7.1,261.53 ; REFN.4 66.43,275.45 ; REFN.4 66.43,273.6 ; REFN.4 64.57,273.6 ; REFN.4 64.57,275.45 ; 5.24,258.31 EXT_TRIG.5 ; EXT_TRIG.5 7.1,256.45 ; EXT_TRIG.5 5.24,256.45 ; EXT_TRIG.5 7.1,258.31 ; 80.2,273.65 REFP.4 ; REFP.4 82.05,273.65 ; REFP.4 82.05,275.51 ; REFP.4 80.2,275.51 ; 11.75,278.27 EXT_SYS_N.2 ; EXT_SYS_N.2 13.6,278.27 ; EXT_SYS_N.2 11.75,280.12 ; EXT_SYS_N.2 13.6,280.12 ; 22.88,256.36 J13.5 ; J13.5 22.88,258.22 ; J13.5 24.74,256.36 ; J13.5 24.74,258.22 ; 49.24,194.1 GND4.1 ; GND4.1 49.24,195.59 ; GND4.1 50.73,195.59 ; GND4.1 50.73,194.1 ; J12.4 45.05,258.21 ; J12.4 45.05,256.35 ; J12.4 43.19,256.35 ; J12.4 43.19,258.21 ; 10.32,261.53 EXT_TRIG.3 ; EXT_TRIG.3 12.18,263.39 ; EXT_TRIG.3 12.18,261.53 ; EXT_TRIG.3 10.32,263.39 ; J12.5 39.97,256.35 ; J12.5 38.11,258.21 ; J12.5 38.11,256.35 ; J12.5 39.97,258.21 ; P19.GND2 5.07,201.48 ; P19.GND2 3.67,202.89 ; P19.GND2 5.07,202.89 ; EXT_SYNC.4 12.03,241.71 ; EXT_SYNC.4 10.17,239.85 ; EXT_SYNC.4 12.03,239.85 ; EXT_SYNC.4 10.17,241.71 ; EXT_SYS_N.5 13.6,275.04 ; EXT_SYS_N.5 11.75,275.04 ; EXT_SYS_N.5 13.6,273.19 ; EXT_SYS_N.5 11.75,273.19 ; 32.73,275.07 EXT_SYS_P.4 ; EXT_SYS_P.4 34.58,273.21 ; EXT_SYS_P.4 34.58,275.07 ; EXT_SYS_P.4 32.73,273.21 ; 218.85,271.5 P22.3 ; P22.3 220.88,273.53 ; P22.3 218.85,273.53 ; P22.3 220.88,271.5 ; 32.73,280.15 EXT_SYS_P.3 ; EXT_SYS_P.3 34.58,278.29 ; EXT_SYS_P.3 32.73,278.29 ; EXT_SYS_P.3 34.58,280.15 ; 53.45,213.91 REFCLK.2 ; REFCLK.2 55.31,215.76 ; REFCLK.2 53.45,215.76 ; REFCLK.2 55.31,213.91 ; REFN.3 66.43,280.53 ; REFN.3 64.57,280.53 ; REFN.3 64.57,278.68 ; REFN.3 66.43,278.68 ; 61.63,249 J18.3 ; J18.3 63.48,250.85 ; J18.3 63.48,249 ; J18.3 61.63,250.85 ; 199.71,235.65 GND2.1 ; GND2.1 201.2,237.15 ; GND2.1 201.2,235.65 ; GND2.1 199.71,237.15 ; P4.8 5.76,60.64 ; P4.8 5.76,62.32 ; P4.8 3.7,62.32 ; P4.8 3.7,60.64 ; 38.11,261.43 J12.2 ; J12.2 39.97,261.43 ; J12.2 39.97,263.29 ; J12.2 38.11,263.29 ; EXT_HMCREF.4 45.62,278.42 ; EXT_HMCREF.4 45.62,280.28 ; EXT_HMCREF.4 43.76,280.28 ; EXT_HMCREF.4 43.76,278.42 ; 3.57,49.77 GND5.1 ; GND5.1 5.11,49.77 ; GND5.1 5.11,48.23 ; GND5.1 3.57,48.23 ; P22.6 220.88,265.99 ; P22.6 220.88,268.02 ; P22.6 218.85,268.02 ; P22.6 218.85,265.99 ; EXT_SYS_N.4 18.68,273.19 ; EXT_SYS_N.4 16.83,275.04 ; EXT_SYS_N.4 16.83,273.19 ; EXT_SYS_N.4 18.68,275.04 ; 22.88,263.3 J13.2 ; J13.2 24.74,263.3 ; J13.2 22.88,261.44 ; J13.2 24.74,261.44 ; P4.9 5.76,55.79 ; P4.9 3.7,57.47 ; P4.9 3.7,55.79 ; P4.9 5.76,57.47 ; 1.28,190.89 P18.GND4 ; P18.GND4 2.68,190.89 ; P18.GND4 1.28,192.3 ; EXT_TRIG.4 12.18,258.31 ; EXT_TRIG.4 10.32,256.45 ; EXT_TRIG.4 10.32,258.31 ; EXT_TRIG.4 12.18,256.45 ; EXT_SYNC.5 6.95,241.71 ; EXT_SYNC.5 6.95,239.85 ; EXT_SYNC.5 5.09,239.85 ; EXT_SYNC.5 5.09,241.71 ; 1.13,202.89 P19.GND3 ; P19.GND3 2.53,202.89 ; P19.GND3 1.13,201.48 ; 53.45,218.99 REFCLK.5 ; REFCLK.5 55.31,218.99 ; REFCLK.5 55.31,220.84 ; REFCLK.5 53.45,220.84 ; EXT_HMCREF.5 50.7,280.28 ; EXT_HMCREF.5 50.7,278.42 ; EXT_HMCREF.5 48.84,278.42 ; EXT_HMCREF.5 48.84,280.28 ; 27.96,263.3 J13.3 ; J13.3 27.96,261.44 ; J13.3 29.82,263.3 ; J13.3 29.82,261.44 ; 59.49,278.68 REFN.2 ; REFN.2 61.35,280.53 ; REFN.2 61.35,278.68 ; REFN.2 59.49,280.53 ; GND6.1 218.83,37.3 ; GND6.1 217.29,37.3 ; GND6.1 218.83,38.84 ; GND6.1 217.29,38.84 ; REFCLK.4 50.23,220.84 ; REFCLK.4 48.37,220.84 ; REFCLK.4 50.23,218.99 ; REFCLK.4 48.37,218.99 ; EXT_SYNC.3 12.03,246.79 ; EXT_SYNC.3 10.17,244.93 ; EXT_SYNC.3 10.17,246.79 ; EXT_SYNC.3 12.03,244.93 ; 5.09,244.93 EXT_SYNC.2 ; EXT_SYNC.2 6.95,246.79 ; EXT_SYNC.2 6.95,244.93 ; EXT_SYNC.2 5.09,246.79 ; P19.GND1 5.07,198.94 ; P19.GND1 3.67,198.94 ; P19.GND1 5.07,200.35 ; 8.5,101.73 GND1.1 ; GND1.1 10.04,101.73 ; GND1.1 8.5,100.2 ; GND1.1 10.04,100.2 ; J13.4 29.82,258.22 ; J13.4 29.82,256.36 ; J13.4 27.96,256.36 ; J13.4 27.96,258.22 ; EXT_SYS_P.5 29.5,273.21 ; EXT_SYS_P.5 27.65,275.07 ; EXT_SYS_P.5 27.65,273.21 ; EXT_SYS_P.5 29.5,275.07 ; P18.GND1 5.22,190.89 ; P18.GND1 3.82,190.89 ; P18.GND1 5.22,192.3 ; 66.71,250.85 J18.4 ; J18.4 68.56,250.85 ; J18.4 68.56,249 ; J18.4 66.71,249 ; GND8.1 175.73,163.9 ; GND8.1 175.73,165.39 ; GND8.1 174.23,163.9 ; GND8.1 174.23,165.39 ; EXT_HMCREF.2 50.7,275.2 ; EXT_HMCREF.2 48.84,273.34 ; EXT_HMCREF.2 50.7,273.34 ; EXT_HMCREF.2 48.84,275.2 ; 51.22,248.9 J17.2 ; J17.2 51.22,250.75 ; J17.2 53.08,250.75 ; J17.2 53.08,248.9 ; J17.3 53.08,245.67 ; J17.3 53.08,243.82 ; J17.3 51.22,243.82 ; J17.3 51.22,245.67 ; 57.06,261.73 GND3.1 ; GND3.1 58.56,261.73 ; GND3.1 57.06,260.24 ; GND3.1 58.56,260.24 ; REFP.5 76.97,273.65 ; REFP.5 75.12,273.65 ; REFP.5 76.97,275.51 ; REFP.5 75.12,275.51 ; 2.81,55.47 P4.7 2.81,57.19 ; 59.49,275.45 REFN.5 ; REFN.5 61.35,275.45 ; REFN.5 59.49,273.6 ; REFN.5 61.35,273.6 ; 1.28,193.43 P18.GND3 ; P18.GND3 1.28,194.84 ; P18.GND3 2.68,194.84 ; 2.81,60.92 P4.6 2.81,62.64 ; J18.2 63.48,243.92 ; J18.2 63.48,245.77 ; J18.2 61.63,243.92 ; J18.2 61.63,245.77 ; REFP.3 82.05,280.59 ; REFP.3 82.05,278.73 ; REFP.3 80.2,280.59 ; REFP.3 80.2,278.73 ; 1.13,198.94 P19.GND4 ; P19.GND4 2.53,198.94 ; P19.GND4 1.13,200.35 ; 46.14,248.9 J17.5 ; J17.5 48,250.75 ; J17.5 48,248.9 ; J17.5 46.14,250.75 ; 196.16,286.7 S4.GND2 ; S4.GND2 198.1,284.75 ; S4.GND2 196.16,284.75 ; S4.GND2 198.1,286.7 ; P18.GND2 5.22,194.84 ; P18.GND2 3.82,194.84 ; P18.GND2 5.22,193.43
  L17_GROUND w0.152: EXT_SYNC.5 6.95,239.85 ; EXT_SYNC.5 5.09,241.71 ; EXT_SYNC.5 6.95,241.71 ; EXT_SYNC.5 5.09,239.85 ; 75.12,280.59 REFP.2 ; REFP.2 76.97,280.59 ; REFP.2 75.12,278.73 ; REFP.2 76.97,278.73 ; 61.63,245.77 J18.2 ; J18.2 61.63,243.92 ; J18.2 63.48,245.77 ; J18.2 63.48,243.92 ; 75.12,275.51 REFP.5 ; REFP.5 76.97,273.65 ; REFP.5 75.12,273.65 ; REFP.5 76.97,275.51 ; J17.2 53.08,250.75 ; J17.2 51.22,248.9 ; J17.2 53.08,248.9 ; J17.2 51.22,250.75 ; P22.3 220.88,271.5 ; P22.3 220.88,273.53 ; P22.3 218.85,271.5 ; P22.3 218.85,273.53 ; P19.GND2 5.07,202.89 ; P19.GND2 5.07,201.48 ; P19.GND2 3.67,202.89 ; EXT_TRIG.5 7.1,258.31 ; EXT_TRIG.5 5.24,258.31 ; EXT_TRIG.5 5.24,256.45 ; EXT_TRIG.5 7.1,256.45 ; GND3.1 58.56,261.73 ; GND3.1 57.06,260.24 ; GND3.1 58.56,260.24 ; GND3.1 57.06,261.73 ; 38.11,258.21 J12.5 ; J12.5 39.97,256.35 ; J12.5 38.11,256.35 ; J12.5 39.97,258.21 ; 80.2,278.73 REFP.3 ; REFP.3 80.2,280.59 ; REFP.3 82.05,280.59 ; REFP.3 82.05,278.73 ; 46.14,245.67 J17.4 ; J17.4 48,245.67 ; J17.4 48,243.82 ; J17.4 46.14,243.82 ; 48.84,275.2 EXT_HMCREF.2 ; EXT_HMCREF.2 50.7,275.2 ; EXT_HMCREF.2 50.7,273.34 ; EXT_HMCREF.2 48.84,273.34 ; J13.5 24.74,258.22 ; J13.5 22.88,256.36 ; J13.5 24.74,256.36 ; J13.5 22.88,258.22 ; REFCLK.4 50.23,218.99 ; REFCLK.4 48.37,218.99 ; REFCLK.4 48.37,220.84 ; REFCLK.4 50.23,220.84 ; GND4.1 50.73,195.59 ; GND4.1 49.24,195.59 ; GND4.1 49.24,194.1 ; GND4.1 50.73,194.1 ; 3.7,57.47 P4.9 ; P4.9 5.76,57.47 ; P4.9 3.7,55.79 ; P4.9 5.76,55.79 ; 27.65,280.15 EXT_SYS_P.2 ; EXT_SYS_P.2 27.65,278.29 ; EXT_SYS_P.2 29.5,280.15 ; EXT_SYS_P.2 29.5,278.29 ; EXT_SYS_N.4 18.68,273.19 ; EXT_SYS_N.4 16.83,273.19 ; EXT_SYS_N.4 16.83,275.04 ; EXT_SYS_N.4 18.68,275.04 ; GND5.1 5.11,49.77 ; GND5.1 3.57,48.23 ; GND5.1 5.11,48.23 ; GND5.1 3.57,49.77 ; P4.8 5.76,62.32 ; P4.8 3.7,62.32 ; P4.8 5.76,60.64 ; P4.8 3.7,60.64 ; J12.2 39.97,263.29 ; J12.2 38.11,263.29 ; J12.2 38.11,261.43 ; J12.2 39.97,261.43 ; J17.3 53.08,245.67 ; J17.3 51.22,245.67 ; J17.3 51.22,243.82 ; J17.3 53.08,243.82 ; 11.75,278.27 EXT_SYS_N.2 ; EXT_SYS_N.2 11.75,280.12 ; EXT_SYS_N.2 13.6,280.12 ; EXT_SYS_N.2 13.6,278.27 ; 8.5,101.73 GND1.1 ; GND1.1 10.04,100.2 ; GND1.1 8.5,100.2 ; GND1.1 10.04,101.73 ; 1.13,200.35 P19.GND4 ; P19.GND4 2.53,198.94 ; P19.GND4 1.13,198.94 ; 48.37,213.91 REFCLK.3 ; REFCLK.3 48.37,215.76 ; REFCLK.3 50.23,213.91 ; REFCLK.3 50.23,215.76 ; REFP.4 82.05,275.51 ; REFP.4 80.2,273.65 ; REFP.4 82.05,273.65 ; REFP.4 80.2,275.51 ; REFN.2 61.35,278.68 ; REFN.2 61.35,280.53 ; REFN.2 59.49,280.53 ; REFN.2 59.49,278.68 ; 66.71,250.85 J18.4 ; J18.4 66.71,249 ; J18.4 68.56,249 ; J18.4 68.56,250.85 ; 16.83,278.27 EXT_SYS_N.3 ; EXT_SYS_N.3 18.68,280.12 ; EXT_SYS_N.3 16.83,280.12 ; EXT_SYS_N.3 18.68,278.27 ; 10.17,244.93 EXT_SYNC.3 ; EXT_SYNC.3 10.17,246.79 ; EXT_SYNC.3 12.03,244.93 ; EXT_SYNC.3 12.03,246.79 ; J13.2 24.74,263.3 ; J13.2 22.88,263.3 ; J13.2 24.74,261.44 ; J13.2 22.88,261.44 ; GND7.1 173.79,83.17 ; GND7.1 172.26,83.17 ; GND7.1 173.79,81.63 ; GND7.1 172.26,81.63 ; 2.81,62.64 P4.6 2.81,60.92 ; 217.29,37.3 GND6.1 ; GND6.1 218.83,37.3 ; GND6.1 217.29,38.84 ; GND6.1 218.83,38.84 ; 10.32,258.31 EXT_TRIG.4 ; EXT_TRIG.4 12.18,256.45 ; EXT_TRIG.4 12.18,258.31 ; EXT_TRIG.4 10.32,256.45 ; J18.5 68.56,243.92 ; J18.5 66.71,243.92 ; J18.5 68.56,245.77 ; J18.5 66.71,245.77 ; 3.82,194.84 P18.GND2 ; P18.GND2 5.22,193.43 ; P18.GND2 5.22,194.84 ; J13.4 29.82,258.22 ; J13.4 29.82,256.36 ; J13.4 27.96,258.22 ; J13.4 27.96,256.36 ; 11.75,273.19 EXT_SYS_N.5 ; EXT_SYS_N.5 13.6,273.19 ; EXT_SYS_N.5 13.6,275.04 ; EXT_SYS_N.5 11.75,275.04 ; P18.GND1 5.22,190.89 ; P18.GND1 5.22,192.3 ; P18.GND1 3.82,190.89 ; 27.96,261.44 J13.3 ; J13.3 29.82,261.44 ; J13.3 27.96,263.3 ; J13.3 29.82,263.3 ; 64.57,273.6 REFN.4 ; REFN.4 64.57,275.45 ; REFN.4 66.43,273.6 ; REFN.4 66.43,275.45 ; EXT_TRIG.2 7.1,261.53 ; EXT_TRIG.2 5.24,261.53 ; EXT_TRIG.2 5.24,263.39 ; EXT_TRIG.2 7.1,263.39 ; S4.GND2 198.1,286.7 ; S4.GND2 196.16,284.75 ; S4.GND2 198.1,284.75 ; S4.GND2 196.16,286.7 ; EXT_SYS_P.5 29.5,273.21 ; EXT_SYS_P.5 27.65,273.21 ; EXT_SYS_P.5 27.65,275.07 ; EXT_SYS_P.5 29.5,275.07 ; REFCLK.5 55.31,218.99 ; REFCLK.5 53.45,220.84 ; REFCLK.5 55.31,220.84 ; REFCLK.5 53.45,218.99 ; 1.13,201.48 P19.GND3 ; P19.GND3 2.53,202.89 ; P19.GND3 1.13,202.89 ; P22.6 220.88,268.02 ; P22.6 218.85,265.99 ; P22.6 218.85,268.02 ; P22.6 220.88,265.99 ; EXT_HMCREF.5 50.7,280.28 ; EXT_HMCREF.5 48.84,280.28 ; EXT_HMCREF.5 48.84,278.42 ; EXT_HMCREF.5 50.7,278.42 ; 199.71,235.65 GND2.1 ; GND2.1 199.71,237.15 ; GND2.1 201.2,237.15 ; GND2.1 201.2,235.65 ; REFCLK.2 55.31,215.76 ; REFCLK.2 53.45,215.76 ; REFCLK.2 53.45,213.91 ; REFCLK.2 55.31,213.91 ; EXT_TRIG.3 12.18,261.53 ; EXT_TRIG.3 10.32,263.39 ; EXT_TRIG.3 12.18,263.39 ; EXT_TRIG.3 10.32,261.53 ; REFN.5 61.35,273.6 ; REFN.5 59.49,275.45 ; REFN.5 61.35,275.45 ; REFN.5 59.49,273.6 ; J18.3 63.48,249 ; J18.3 61.63,250.85 ; J18.3 61.63,249 ; J18.3 63.48,250.85 ; EXT_HMCREF.3 45.62,275.2 ; EXT_HMCREF.3 43.76,273.34 ; EXT_HMCREF.3 45.62,273.34 ; EXT_HMCREF.3 43.76,275.2 ; P19.GND1 5.07,200.35 ; P19.GND1 5.07,198.94 ; P19.GND1 3.67,198.94 ; J17.5 48,250.75 ; J17.5 48,248.9 ; J17.5 46.14,250.75 ; J17.5 46.14,248.9 ; S4.GND1 184.89,286.7 ; S4.GND1 182.95,286.7 ; S4.GND1 184.89,284.75 ; S4.GND1 182.95,284.75 ; REFN.3 66.43,280.53 ; REFN.3 64.57,280.53 ; REFN.3 64.57,278.68 ; REFN.3 66.43,278.68 ; EXT_HMCREF.4 45.62,278.42 ; EXT_HMCREF.4 43.76,278.42 ; EXT_HMCREF.4 45.62,280.28 ; EXT_HMCREF.4 43.76,280.28 ; 2.81,57.19 P4.7 2.81,55.47 ; 43.19,256.35 J12.4 ; J12.4 45.05,258.21 ; J12.4 43.19,258.21 ; J12.4 45.05,256.35 ; EXT_SYS_P.4 34.58,273.21 ; EXT_SYS_P.4 32.73,273.21 ; EXT_SYS_P.4 32.73,275.07 ; EXT_SYS_P.4 34.58,275.07 ; EXT_SYNC.2 6.95,244.93 ; EXT_SYNC.2 5.09,244.93 ; EXT_SYNC.2 6.95,246.79 ; EXT_SYNC.2 5.09,246.79 ; EXT_SYNC.4 12.03,241.71 ; EXT_SYNC.4 12.03,239.85 ; EXT_SYNC.4 10.17,241.71 ; EXT_SYNC.4 10.17,239.85 ; 174.23,165.39 GND8.1 ; GND8.1 175.73,165.39 ; GND8.1 174.23,163.9 ; GND8.1 175.73,163.9 ; 1.28,194.84 P18.GND3 ; P18.GND3 2.68,194.84 ; P18.GND3 1.28,193.43 ; J12.3 45.05,263.29 ; J12.3 45.05,261.43 ; J12.3 43.19,261.43 ; J12.3 43.19,263.29 ; 32.73,278.29 EXT_SYS_P.3 ; EXT_SYS_P.3 32.73,280.15 ; EXT_SYS_P.3 34.58,280.15 ; EXT_SYS_P.3 34.58,278.29 ; 1.28,192.3 P18.GND4 ; P18.GND4 1.28,190.89 ; P18.GND4 2.68,190.89
  L18_POWER w0.152: GND3.1 58.56,260.24 ; GND3.1 57.06,260.24 ; GND3.1 58.56,261.73 ; GND3.1 57.06,261.73 ; 3.67,202.89 P19.GND2 ; P19.GND2 5.07,202.89 ; P19.GND2 5.07,201.48 ; 27.96,261.44 J13.3 ; J13.3 29.82,261.44 ; J13.3 27.96,263.3 ; J13.3 29.82,263.3 ; 182.95,284.75 S4.GND1 ; S4.GND1 184.89,284.75 ; S4.GND1 182.95,286.7 ; S4.GND1 184.89,286.7 ; 48.84,275.2 EXT_HMCREF.2 ; EXT_HMCREF.2 50.7,275.2 ; EXT_HMCREF.2 50.7,273.34 ; EXT_HMCREF.2 48.84,273.34 ; 16.83,280.12 EXT_SYS_N.3 ; EXT_SYS_N.3 18.68,280.12 ; EXT_SYS_N.3 16.83,278.27 ; EXT_SYS_N.3 18.68,278.27 ; P4.9 5.76,57.47 ; P4.9 3.7,57.47 ; P4.9 3.7,55.79 ; P4.9 5.76,55.79 ; P18.GND4 2.68,190.89 ; P18.GND4 1.28,190.89 ; P18.GND4 1.28,192.3 ; GND6.1 218.83,37.3 ; GND6.1 217.29,38.84 ; GND6.1 217.29,37.3 ; GND6.1 218.83,38.84 ; 5.09,241.71 EXT_SYNC.5 ; EXT_SYNC.5 5.09,239.85 ; EXT_SYNC.5 6.95,241.71 ; EXT_SYNC.5 6.95,239.85 ; REFN.2 61.35,278.68 ; REFN.2 61.35,280.53 ; REFN.2 59.49,278.68 ; REFN.2 59.49,280.53 ; EXT_HMCREF.4 45.62,280.28 ; EXT_HMCREF.4 45.62,278.42 ; EXT_HMCREF.4 43.76,278.42 ; EXT_HMCREF.4 43.76,280.28 ; J12.3 45.05,261.43 ; J12.3 45.05,263.29 ; J12.3 43.19,261.43 ; J12.3 43.19,263.29 ; 10.17,244.93 EXT_SYNC.3 ; EXT_SYNC.3 12.03,244.93 ; EXT_SYNC.3 10.17,246.79 ; EXT_SYNC.3 12.03,246.79 ; 11.75,273.19 EXT_SYS_N.5 ; EXT_SYS_N.5 11.75,275.04 ; EXT_SYS_N.5 13.6,273.19 ; EXT_SYS_N.5 13.6,275.04 ; EXT_TRIG.3 12.18,263.39 ; EXT_TRIG.3 10.32,263.39 ; EXT_TRIG.3 12.18,261.53 ; EXT_TRIG.3 10.32,261.53 ; 80.2,275.51 REFP.4 ; REFP.4 82.05,275.51 ; REFP.4 80.2,273.65 ; REFP.4 82.05,273.65 ; EXT_SYS_N.4 18.68,273.19 ; EXT_SYS_N.4 16.83,273.19 ; EXT_SYS_N.4 16.83,275.04 ; EXT_SYS_N.4 18.68,275.04 ; 22.88,258.22 J13.5 ; J13.5 24.74,256.36 ; J13.5 24.74,258.22 ; J13.5 22.88,256.36 ; P19.GND1 5.07,200.35 ; P19.GND1 3.67,198.94 ; P19.GND1 5.07,198.94 ; 1.28,193.43 P18.GND3 ; P18.GND3 2.68,194.84 ; P18.GND3 1.28,194.84 ; 32.73,275.07 EXT_SYS_P.4 ; EXT_SYS_P.4 34.58,275.07 ; EXT_SYS_P.4 34.58,273.21 ; EXT_SYS_P.4 32.73,273.21 ; REFCLK.4 50.23,220.84 ; REFCLK.4 48.37,220.84 ; REFCLK.4 48.37,218.99 ; REFCLK.4 50.23,218.99 ; REFN.5 61.35,273.6 ; REFN.5 59.49,273.6 ; REFN.5 61.35,275.45 ; REFN.5 59.49,275.45 ; 43.19,256.35 J12.4 ; J12.4 43.19,258.21 ; J12.4 45.05,258.21 ; 22.88,261.44 J13.2 ; J13.2 22.88,263.3 ; J13.2 24.74,261.44 ; J13.2 24.74,263.3 ; 218.85,265.99 P22.6 ; P22.6 220.88,265.99 ; P22.6 220.88,268.02 ; P22.6 218.85,268.02 ; 196.16,284.75 S4.GND2 ; S4.GND2 198.1,286.7 ; S4.GND2 196.16,286.7 ; S4.GND2 198.1,284.75 ; 5.09,246.79 EXT_SYNC.2 ; EXT_SYNC.2 6.95,244.93 ; EXT_SYNC.2 5.09,244.93 ; EXT_SYNC.2 6.95,246.79 ; 53.45,220.84 REFCLK.5 ; REFCLK.5 55.31,220.84 ; REFCLK.5 53.45,218.99 ; REFCLK.5 55.31,218.99 ; 27.96,256.36 J13.4 ; J13.4 29.82,258.22 ; J13.4 27.96,258.22 ; J13.4 29.82,256.36 ; 5.24,258.31 EXT_TRIG.5 ; EXT_TRIG.5 7.1,256.45 ; EXT_TRIG.5 7.1,258.31 ; EXT_TRIG.5 5.24,256.45 ; REFP.5 76.97,275.51 ; REFP.5 76.97,273.65 ; REFP.5 75.12,273.65 ; REFP.5 75.12,275.51 ; 32.73,280.15 EXT_SYS_P.3 ; EXT_SYS_P.3 34.58,280.15 ; EXT_SYS_P.3 32.73,278.29 ; EXT_SYS_P.3 34.58,278.29 ; EXT_HMCREF.5 50.7,280.28 ; EXT_HMCREF.5 48.84,280.28 ; EXT_HMCREF.5 48.84,278.42 ; EXT_HMCREF.5 50.7,278.42 ; EXT_SYNC.4 12.03,241.71 ; EXT_SYNC.4 12.03,239.85 ; EXT_SYNC.4 10.17,241.71 ; EXT_SYNC.4 10.17,239.85 ; 27.65,280.15 EXT_SYS_P.2 ; EXT_SYS_P.2 27.65,278.29 ; EXT_SYS_P.2 29.5,278.29 ; EXT_SYS_P.2 29.5,280.15 ; GND5.1 5.11,49.77 ; GND5.1 3.57,49.77 ; GND5.1 3.57,48.23 ; GND5.1 5.11,48.23 ; REFN.4 66.43,275.45 ; REFN.4 64.57,275.45 ; REFN.4 64.57,273.6 ; REFN.4 66.43,273.6 ; EXT_SYS_P.5 29.5,273.21 ; EXT_SYS_P.5 29.5,275.07 ; EXT_SYS_P.5 27.65,273.21 ; EXT_SYS_P.5 27.65,275.07 ; GND1.1 10.04,101.73 ; GND1.1 10.04,100.2 ; GND1.1 8.5,100.2 ; GND1.1 8.5,101.73 ; P18.GND2 5.22,193.43 ; P18.GND2 3.82,194.84 ; P18.GND2 5.22,194.84 ; 64.57,280.53 REFN.3 ; REFN.3 66.43,278.68 ; REFN.3 64.57,278.68 ; REFN.3 66.43,280.53 ; 1.13,201.48 P19.GND3 ; P19.GND3 2.53,202.89 ; P19.GND3 1.13,202.89 ; GND2.1 201.2,237.15 ; GND2.1 199.71,235.65 ; GND2.1 201.2,235.65 ; GND2.1 199.71,237.15 ; P18.GND1 5.22,190.89 ; P18.GND1 5.22,192.3 ; P18.GND1 3.82,190.89 ; 53.45,213.91 REFCLK.2 ; REFCLK.2 55.31,213.91 ; REFCLK.2 53.45,215.76 ; REFCLK.2 55.31,215.76 ; 38.11,256.35 J12.5 ; J12.5 38.11,258.21 ; J12.5 39.97,258.21 ; J12.5 39.97,256.35 ; 2.81,57.19 P4.7 2.81,55.47 ; 218.85,273.53 P22.3 ; P22.3 218.85,271.5 ; P22.3 220.88,273.53 ; P22.3 220.88,271.5 ; 80.2,280.59 REFP.3 ; REFP.3 82.05,280.59 ; REFP.3 82.05,278.73 ; REFP.3 80.2,278.73 ; J12.2 39.97,261.43 ; J12.2 38.11,261.43 ; J12.2 38.11,263.29 ; J12.2 39.97,263.29 ; 2.81,60.92 P4.6 2.81,62.64 ; REFP.2 76.97,280.59 ; REFP.2 75.12,278.73 ; REFP.2 76.97,278.73 ; REFP.2 75.12,280.59 ; EXT_SYS_N.2 13.6,280.12 ; EXT_SYS_N.2 11.75,278.27 ; EXT_SYS_N.2 11.75,280.12 ; EXT_SYS_N.2 13.6,278.27 ; 3.7,60.64 P4.8 ; P4.8 5.76,62.32 ; P4.8 3.7,62.32 ; P4.8 5.76,60.64 ; 43.76,273.34 EXT_HMCREF.3 ; EXT_HMCREF.3 45.62,273.34 ; EXT_HMCREF.3 45.62,275.2 ; EXT_HMCREF.3 43.76,275.2 ; 174.23,163.9 GND8.1 ; GND8.1 175.73,163.9 ; GND8.1 174.23,165.39 ; GND8.1 175.73,165.39 ; 1.13,198.94 P19.GND4 ; P19.GND4 1.13,200.35 ; P19.GND4 2.53,198.94 ; 48.37,215.76 REFCLK.3 ; REFCLK.3 48.37,213.91 ; REFCLK.3 50.23,213.91 ; REFCLK.3 50.23,215.76 ; EXT_TRIG.2 7.1,261.53 ; EXT_TRIG.2 5.24,263.39 ; EXT_TRIG.2 5.24,261.53 ; EXT_TRIG.2 7.1,263.39 ; 10.32,258.31 EXT_TRIG.4 ; EXT_TRIG.4 12.18,256.45 ; EXT_TRIG.4 12.18,258.31 ; EXT_TRIG.4 10.32,256.45
  L19_GROUND w0.152: REFCLK.4 50.23,220.84 ; REFCLK.4 50.23,218.99 ; REFCLK.4 48.37,218.99 ; REFCLK.4 48.37,220.84 ; 174.23,165.39 GND8.1 ; GND8.1 174.23,163.9 ; GND8.1 175.73,163.9 ; GND8.1 175.73,165.39 ; REFN.2 61.35,280.53 ; REFN.2 59.49,278.68 ; REFN.2 59.49,280.53 ; REFN.2 61.35,278.68 ; GND7.1 173.79,83.17 ; GND7.1 172.26,83.17 ; GND7.1 173.79,81.63 ; GND7.1 172.26,81.63 ; EXT_HMCREF.5 50.7,278.42 ; EXT_HMCREF.5 48.84,278.42 ; EXT_HMCREF.5 50.7,280.28 ; EXT_HMCREF.5 48.84,280.28 ; 218.85,273.53 P22.3 ; P22.3 220.88,273.53 ; P22.3 218.85,271.5 ; P22.3 220.88,271.5 ; J13.5 24.74,256.36 ; J13.5 22.88,258.22 ; J13.5 22.88,256.36 ; J13.5 24.74,258.22 ; 66.71,245.77 J18.5 ; J18.5 68.56,245.77 ; J18.5 66.71,243.92 ; J18.5 68.56,243.92 ; 53.45,215.76 REFCLK.2 ; REFCLK.2 55.31,213.91 ; REFCLK.2 55.31,215.76 ; REFCLK.2 53.45,213.91 ; 11.75,273.19 EXT_SYS_N.5 ; EXT_SYS_N.5 13.6,275.04 ; EXT_SYS_N.5 13.6,273.19 ; EXT_SYS_N.5 11.75,275.04 ; S4.GND2 198.1,286.7 ; S4.GND2 198.1,284.75 ; S4.GND2 196.16,284.75 ; S4.GND2 196.16,286.7 ; 218.85,265.99 P22.6 ; P22.6 220.88,268.02 ; P22.6 218.85,268.02 ; P22.6 220.88,265.99 ; 2.81,57.19 P4.7 2.81,55.47 ; J12.2 39.97,261.43 ; J12.2 38.11,261.43 ; J12.2 39.97,263.29 ; J12.2 38.11,263.29 ; EXT_SYS_P.3 34.58,280.15 ; EXT_SYS_P.3 32.73,280.15 ; EXT_SYS_P.3 34.58,278.29 ; EXT_SYS_P.3 32.73,278.29 ; 217.29,38.84 GND6.1 ; GND6.1 218.83,37.3 ; GND6.1 218.83,38.84 ; GND6.1 217.29,37.3 ; 27.65,273.21 EXT_SYS_P.5 ; EXT_SYS_P.5 29.5,273.21 ; EXT_SYS_P.5 29.5,275.07 ; EXT_SYS_P.5 27.65,275.07 ; 48.84,273.34 EXT_HMCREF.2 ; EXT_HMCREF.2 50.7,275.2 ; EXT_HMCREF.2 48.84,275.2 ; EXT_HMCREF.2 50.7,273.34 ; J12.5 39.97,256.35 ; J12.5 39.97,258.21 ; J12.5 38.11,256.35 ; J12.5 38.11,258.21 ; 1.13,201.48 P19.GND3 ; P19.GND3 2.53,202.89 ; P19.GND3 1.13,202.89 ; P18.GND3 2.68,194.84 ; P18.GND3 1.28,194.84 ; P18.GND3 1.28,193.43 ; J12.3 45.05,263.29 ; J12.3 43.19,263.29 ; J12.3 45.05,261.43 ; J12.3 43.19,261.43 ; EXT_SYS_N.2 13.6,278.27 ; EXT_SYS_N.2 13.6,280.12 ; EXT_SYS_N.2 11.75,278.27 ; EXT_SYS_N.2 11.75,280.12 ; 10.17,246.79 EXT_SYNC.3 ; EXT_SYNC.3 12.03,246.79 ; EXT_SYNC.3 10.17,244.93 ; EXT_SYNC.3 12.03,244.93 ; 61.63,249 J18.3 ; J18.3 63.48,250.85 ; J18.3 61.63,250.85 ; J18.3 63.48,249 ; 53.45,220.84 REFCLK.5 ; REFCLK.5 55.31,218.99 ; REFCLK.5 53.45,218.99 ; REFCLK.5 55.31,220.84 ; REFP.5 76.97,273.65 ; REFP.5 75.12,273.65 ; REFP.5 76.97,275.51 ; REFP.5 75.12,275.51 ; EXT_SYNC.4 12.03,241.71 ; EXT_SYNC.4 12.03,239.85 ; EXT_SYNC.4 10.17,239.85 ; EXT_SYNC.4 10.17,241.71 ; J13.2 24.74,263.3 ; J13.2 22.88,263.3 ; J13.2 24.74,261.44 ; J13.2 22.88,261.44 ; 5.09,241.71 EXT_SYNC.5 ; EXT_SYNC.5 5.09,239.85 ; EXT_SYNC.5 6.95,241.71 ; EXT_SYNC.5 6.95,239.85 ; EXT_SYS_P.4 34.58,275.07 ; EXT_SYS_P.4 32.73,273.21 ; EXT_SYS_P.4 32.73,275.07 ; EXT_SYS_P.4 34.58,273.21 ; 3.7,57.47 P4.9 ; P4.9 5.76,57.47 ; P4.9 5.76,55.79 ; P4.9 3.7,55.79 ; S4.GND1 184.89,284.75 ; S4.GND1 184.89,286.7 ; S4.GND1 182.95,286.7 ; S4.GND1 182.95,284.75 ; 66.71,250.85 J18.4 ; J18.4 66.71,249 ; J18.4 68.56,250.85 ; J18.4 68.56,249 ; GND5.1 5.11,49.77 ; GND5.1 5.11,48.23 ; GND5.1 3.57,48.23 ; GND5.1 3.57,49.77 ; 80.2,273.65 REFP.4 ; REFP.4 82.05,275.51 ; REFP.4 82.05,273.65 ; REFP.4 80.2,275.51 ; GND2.1 201.2,237.15 ; GND2.1 199.71,235.65 ; GND2.1 199.71,237.15 ; GND2.1 201.2,235.65 ; 1.13,200.35 P19.GND4 ; P19.GND4 1.13,198.94 ; P19.GND4 2.53,198.94 ; 61.63,243.92 J18.2 ; J18.2 61.63,245.77 ; J18.2 63.48,245.77 ; J18.2 63.48,243.92 ; 46.14,245.67 J17.4 ; J17.4 48,243.82 ; J17.4 48,245.67 ; J17.4 46.14,243.82 ; P19.GND1 5.07,198.94 ; P19.GND1 5.07,200.35 ; P19.GND1 3.67,198.94 ; 10.32,261.53 EXT_TRIG.3 ; EXT_TRIG.3 12.18,261.53 ; EXT_TRIG.3 12.18,263.39 ; EXT_TRIG.3 10.32,263.39 ; 51.22,243.82 J17.3 ; J17.3 51.22,245.67 ; J17.3 53.08,245.67 ; J17.3 53.08,243.82 ; 46.14,248.9 J17.5 ; J17.5 48,250.75 ; J17.5 46.14,250.75 ; J17.5 48,248.9 ; REFN.4 66.43,273.6 ; REFN.4 64.57,273.6 ; REFN.4 64.57,275.45 ; REFN.4 66.43,275.45 ; EXT_SYS_P.2 29.5,280.15 ; EXT_SYS_P.2 27.65,280.15 ; EXT_SYS_P.2 29.5,278.29 ; EXT_SYS_P.2 27.65,278.29 ; 80.2,280.59 REFP.3 ; REFP.3 80.2,278.73 ; REFP.3 82.05,280.59 ; REFP.3 82.05,278.73 ; EXT_HMCREF.4 45.62,280.28 ; EXT_HMCREF.4 45.62,278.42 ; EXT_HMCREF.4 43.76,278.42 ; EXT_HMCREF.4 43.76,280.28 ; REFN.3 66.43,280.53 ; REFN.3 64.57,280.53 ; REFN.3 66.43,278.68 ; REFN.3 64.57,278.68 ; P18.GND4 2.68,190.89 ; P18.GND4 1.28,190.89 ; P18.GND4 1.28,192.3 ; EXT_SYNC.2 6.95,246.79 ; EXT_SYNC.2 6.95,244.93 ; EXT_SYNC.2 5.09,246.79 ; EXT_SYNC.2 5.09,244.93 ; J17.2 53.08,250.75 ; J17.2 51.22,248.9 ; J17.2 51.22,250.75 ; J17.2 53.08,248.9 ; P4.8 5.76,62.32 ; P4.8 3.7,62.32 ; P4.8 5.76,60.64 ; P4.8 3.7,60.64 ; REFP.2 76.97,278.73 ; REFP.2 75.12,280.59 ; REFP.2 75.12,278.73 ; REFP.2 76.97,280.59 ; EXT_SYS_N.4 18.68,275.04 ; EXT_SYS_N.4 16.83,275.04 ; EXT_SYS_N.4 16.83,273.19 ; EXT_SYS_N.4 18.68,273.19 ; 8.5,101.73 GND1.1 ; GND1.1 8.5,100.2 ; GND1.1 10.04,100.2 ; GND1.1 10.04,101.73 ; 57.06,261.73 GND3.1 ; GND3.1 58.56,261.73 ; GND3.1 57.06,260.24 ; GND3.1 58.56,260.24 ; 27.96,261.44 J13.3 ; J13.3 29.82,261.44 ; J13.3 29.82,263.3 ; J13.3 27.96,263.3 ; P18.GND2 5.22,194.84 ; P18.GND2 3.82,194.84 ; P18.GND2 5.22,193.43 ; 2.81,62.64 P4.6 2.81,60.92 ; 59.49,275.45 REFN.5 ; REFN.5 61.35,273.6 ; REFN.5 59.49,273.6 ; REFN.5 61.35,275.45 ; EXT_TRIG.5 7.1,258.31 ; EXT_TRIG.5 5.24,258.31 ; EXT_TRIG.5 5.24,256.45 ; EXT_TRIG.5 7.1,256.45 ; 48.37,213.91 REFCLK.3 ; REFCLK.3 50.23,215.76 ; REFCLK.3 48.37,215.76 ; REFCLK.3 50.23,213.91 ; EXT_SYS_N.3 18.68,278.27 ; EXT_SYS_N.3 18.68,280.12 ; EXT_SYS_N.3 16.83,278.27 ; EXT_SYS_N.3 16.83,280.12 ; P18.GND1 5.22,192.3 ; P18.GND1 5.22,190.89 ; P18.GND1 3.82,190.89 ; 10.32,258.31 EXT_TRIG.4 ; EXT_TRIG.4 12.18,258.31 ; EXT_TRIG.4 12.18,256.45 ; EXT_TRIG.4 10.32,256.45 ; EXT_HMCREF.3 45.62,273.34 ; EXT_HMCREF.3 43.76,273.34 ; EXT_HMCREF.3 45.62,275.2 ; EXT_HMCREF.3 43.76,275.2 ; J13.4 29.82,258.22 ; J13.4 27.96,256.36 ; J13.4 29.82,256.36 ; J13.4 27.96,258.22 ; J12.4 45.05,258.21 ; J12.4 43.19,256.35 ; J12.4 45.05,256.35 ; J12.4 43.19,258.21 ; 49.24,194.1 GND4.1 ; GND4.1 49.24,195.59 ; GND4.1 50.73,194.1 ; GND4.1 50.73,195.59 ; 5.24,261.53 EXT_TRIG.2 ; EXT_TRIG.2 5.24,263.39 ; EXT_TRIG.2 7.1,261.53 ; EXT_TRIG.2 7.1,263.39 ; P19.GND2 5.07,202.89 ; P19.GND2 5.07,201.48 ; P19.GND2 3.67,202.89
  L20_POWER w0.152: 27.65,273.21 EXT_SYS_P.5 ; EXT_SYS_P.5 29.5,273.21 ; EXT_SYS_P.5 27.65,275.07 ; EXT_SYS_P.5 29.5,275.07 ; 218.85,271.5 P22.3 ; P22.3 220.88,273.53 ; P22.3 220.88,271.5 ; P22.3 218.85,273.53 ; J18.3 63.48,250.85 ; J18.3 61.63,250.85 ; J18.3 63.48,249 ; J18.3 61.63,249 ; 3.7,60.64 P4.8 ; P4.8 5.76,60.64 ; P4.8 3.7,62.32 ; P4.8 5.76,62.32 ; 48.84,275.2 EXT_HMCREF.2 ; EXT_HMCREF.2 50.7,273.34 ; EXT_HMCREF.2 48.84,273.34 ; EXT_HMCREF.2 50.7,275.2 ; 61.63,245.77 J18.2 ; J18.2 63.48,243.92 ; J18.2 63.48,245.77 ; J18.2 61.63,243.92 ; 27.96,263.3 J13.3 ; J13.3 29.82,261.44 ; J13.3 27.96,261.44 ; J13.3 29.82,263.3 ; 49.24,194.1 GND4.1 ; GND4.1 50.73,194.1 ; GND4.1 49.24,195.59 ; GND4.1 50.73,195.59 ; 80.2,280.59 REFP.3 ; REFP.3 82.05,280.59 ; REFP.3 80.2,278.73 ; REFP.3 82.05,278.73 ; EXT_HMCREF.3 45.62,275.2 ; EXT_HMCREF.3 43.76,275.2 ; EXT_HMCREF.3 43.76,273.34 ; EXT_HMCREF.3 45.62,273.34 ; EXT_SYS_P.4 34.58,273.21 ; EXT_SYS_P.4 32.73,273.21 ; EXT_SYS_P.4 34.58,275.07 ; EXT_SYS_P.4 32.73,275.07 ; 59.49,273.6 REFN.5 ; REFN.5 61.35,275.45 ; REFN.5 61.35,273.6 ; REFN.5 59.49,275.45 ; REFP.4 82.05,275.51 ; REFP.4 80.2,273.65 ; REFP.4 80.2,275.51 ; REFP.4 82.05,273.65 ; J17.2 53.08,250.75 ; J17.2 51.22,248.9 ; J17.2 51.22,250.75 ; J17.2 53.08,248.9 ; 2.81,60.92 P4.6 2.81,62.64 ; 64.57,278.68 REFN.3 ; REFN.3 66.43,278.68 ; REFN.3 64.57,280.53 ; REFN.3 66.43,280.53 ; P19.GND2 5.07,202.89 ; P19.GND2 5.07,201.48 ; P19.GND2 3.67,202.89 ; 53.45,215.76 REFCLK.2 ; REFCLK.2 53.45,213.91 ; REFCLK.2 55.31,213.91 ; REFCLK.2 55.31,215.76 ; J12.2 39.97,261.43 ; J12.2 39.97,263.29 ; J12.2 38.11,261.43 ; J12.2 38.11,263.29 ; J17.4 48,243.82 ; J17.4 46.14,245.67 ; J17.4 48,245.67 ; J17.4 46.14,243.82 ; 59.49,280.53 REFN.2 ; REFN.2 61.35,280.53 ; REFN.2 61.35,278.68 ; REFN.2 59.49,278.68 ; REFP.5 76.97,275.51 ; REFP.5 75.12,275.51 ; REFP.5 75.12,273.65 ; REFP.5 76.97,273.65 ; EXT_SYNC.3 12.03,246.79 ; EXT_SYNC.3 10.17,246.79 ; EXT_SYNC.3 10.17,244.93 ; EXT_SYNC.3 12.03,244.93 ; 43.76,280.28 EXT_HMCREF.4 ; EXT_HMCREF.4 43.76,278.42 ; EXT_HMCREF.4 45.62,280.28 ; EXT_HMCREF.4 45.62,278.42 ; REFCLK.5 55.31,218.99 ; REFCLK.5 53.45,218.99 ; REFCLK.5 53.45,220.84 ; REFCLK.5 55.31,220.84 ; 46.14,248.9 J17.5 ; J17.5 46.14,250.75 ; J17.5 48,248.9 ; J17.5 48,250.75 ; P19.GND1 5.07,200.35 ; P19.GND1 3.67,198.94 ; P19.GND1 5.07,198.94 ; 11.75,280.12 EXT_SYS_N.2 ; EXT_SYS_N.2 13.6,280.12 ; EXT_SYS_N.2 11.75,278.27 ; EXT_SYS_N.2 13.6,278.27 ; 8.5,101.73 GND1.1 ; GND1.1 8.5,100.2 ; GND1.1 10.04,100.2 ; GND1.1 10.04,101.73 ; 218.85,265.99 P22.6 ; P22.6 218.85,268.02 ; P22.6 220.88,268.02 ; P22.6 220.88,265.99 ; 38.11,258.21 J12.5 ; J12.5 39.97,258.21 ; J12.5 38.11,256.35 ; J12.5 39.97,256.35 ; J13.2 24.74,261.44 ; J13.2 22.88,261.44 ; J13.2 24.74,263.3 ; J13.2 22.88,263.3 ; J12.4 45.05,256.35 ; J12.4 43.19,256.35 ; J12.4 43.19,258.21 ; J12.4 45.05,258.21 ; 32.73,278.29 EXT_SYS_P.3 ; EXT_SYS_P.3 34.58,280.15 ; EXT_SYS_P.3 32.73,280.15 ; EXT_SYS_P.3 34.58,278.29 ; P18.GND1 5.22,190.89 ; P18.GND1 3.82,190.89 ; P18.GND1 5.22,192.3 ; 182.95,286.7 S4.GND1 ; S4.GND1 184.89,286.7 ; S4.GND1 182.95,284.75 ; S4.GND1 184.89,284.75 ; 51.22,245.67 J17.3 ; J17.3 53.08,243.82 ; J17.3 53.08,245.67 ; J17.3 51.22,243.82 ; J13.5 24.74,256.36 ; J13.5 24.74,258.22 ; J13.5 22.88,258.22 ; J13.5 22.88,256.36 ; EXT_HMCREF.5 50.7,278.42 ; EXT_HMCREF.5 48.84,280.28 ; EXT_HMCREF.5 48.84,278.42 ; EXT_HMCREF.5 50.7,280.28 ; REFCLK.4 50.23,218.99 ; REFCLK.4 48.37,218.99 ; REFCLK.4 48.37,220.84 ; REFCLK.4 50.23,220.84 ; EXT_SYS_N.5 13.6,273.19 ; EXT_SYS_N.5 13.6,275.04 ; EXT_SYS_N.5 11.75,273.19 ; EXT_SYS_N.5 11.75,275.04 ; 1.28,192.3 P18.GND4 ; P18.GND4 2.68,190.89 ; P18.GND4 1.28,190.89 ; 3.57,48.23 GND5.1 ; GND5.1 5.11,48.23 ; GND5.1 3.57,49.77 ; GND5.1 5.11,49.77 ; P4.9 5.76,57.47 ; P4.9 3.7,57.47 ; P4.9 3.7,55.79 ; P4.9 5.76,55.79 ; 217.29,38.84 GND6.1 ; GND6.1 217.29,37.3 ; GND6.1 218.83,38.84 ; GND6.1 218.83,37.3 ; 75.12,280.59 REFP.2 ; REFP.2 76.97,278.73 ; REFP.2 75.12,278.73 ; REFP.2 76.97,280.59 ; EXT_SYNC.4 12.03,239.85 ; EXT_SYNC.4 12.03,241.71 ; EXT_SYNC.4 10.17,241.71 ; EXT_SYNC.4 10.17,239.85 ; EXT_SYS_P.2 29.5,278.29 ; EXT_SYS_P.2 27.65,278.29 ; EXT_SYS_P.2 27.65,280.15 ; EXT_SYS_P.2 29.5,280.15 ; J12.3 45.05,263.29 ; J12.3 43.19,261.43 ; J12.3 43.19,263.29 ; J12.3 45.05,261.43 ; 5.24,263.39 EXT_TRIG.2 ; EXT_TRIG.2 7.1,261.53 ; EXT_TRIG.2 7.1,263.39 ; EXT_TRIG.2 5.24,261.53 ; EXT_TRIG.3 12.18,261.53 ; EXT_TRIG.3 10.32,261.53 ; EXT_TRIG.3 12.18,263.39 ; EXT_TRIG.3 10.32,263.39 ; 16.83,280.12 EXT_SYS_N.3 ; EXT_SYS_N.3 16.83,278.27 ; EXT_SYS_N.3 18.68,280.12 ; EXT_SYS_N.3 18.68,278.27 ; J18.4 68.56,249 ; J18.4 68.56,250.85 ; J18.4 66.71,250.85 ; J18.4 66.71,249 ; EXT_TRIG.4 12.18,258.31 ; EXT_TRIG.4 10.32,258.31 ; EXT_TRIG.4 12.18,256.45 ; EXT_TRIG.4 10.32,256.45 ; REFCLK.3 50.23,215.76 ; REFCLK.3 48.37,213.91 ; REFCLK.3 48.37,215.76 ; REFCLK.3 50.23,213.91 ; 5.24,256.45 EXT_TRIG.5 ; EXT_TRIG.5 7.1,258.31 ; EXT_TRIG.5 5.24,258.31 ; EXT_TRIG.5 7.1,256.45 ; 64.57,275.45 REFN.4 ; REFN.4 66.43,273.6 ; REFN.4 66.43,275.45 ; REFN.4 64.57,273.6 ; 2.81,57.19 P4.7 2.81,55.47 ; 27.96,256.36 J13.4 ; J13.4 29.82,258.22 ; J13.4 29.82,256.36 ; J13.4 27.96,258.22 ; EXT_SYNC.5 6.95,241.71 ; EXT_SYNC.5 6.95,239.85 ; EXT_SYNC.5 5.09,239.85 ; EXT_SYNC.5 5.09,241.71 ; 5.09,244.93 EXT_SYNC.2 ; EXT_SYNC.2 5.09,246.79 ; EXT_SYNC.2 6.95,246.79 ; EXT_SYNC.2 6.95,244.93 ; 1.13,202.89 P19.GND3 ; P19.GND3 1.13,201.48 ; P19.GND3 2.53,202.89 ; GND3.1 58.56,261.73 ; GND3.1 57.06,261.73 ; GND3.1 57.06,260.24 ; GND3.1 58.56,260.24 ; EXT_SYS_N.4 18.68,275.04 ; EXT_SYS_N.4 16.83,275.04 ; EXT_SYS_N.4 18.68,273.19 ; EXT_SYS_N.4 16.83,273.19 ; P18.GND2 5.22,194.84 ; P18.GND2 5.22,193.43 ; P18.GND2 3.82,194.84 ; 1.28,194.84 P18.GND3 ; P18.GND3 1.28,193.43 ; P18.GND3 2.68,194.84 ; GND2.1 201.2,235.65 ; GND2.1 199.71,235.65 ; GND2.1 199.71,237.15 ; GND2.1 201.2,237.15 ; J18.5 68.56,245.77 ; J18.5 66.71,245.77 ; J18.5 66.71,243.92 ; J18.5 68.56,243.92 ; 1.13,200.35 P19.GND4 ; P19.GND4 2.53,198.94 ; P19.GND4 1.13,198.94 ; S4.GND2 198.1,284.75 ; S4.GND2 198.1,286.7 ; S4.GND2 196.16,284.75 ; S4.GND2 196.16,286.7
  L21_GROUND w0.152: 53.45,220.84 REFCLK.5 ; REFCLK.5 53.45,218.99 ; REFCLK.5 55.31,218.99 ; REFCLK.5 55.31,220.84 ; J17.4 48,243.82 ; J17.4 46.14,243.82 ; J17.4 46.14,245.67 ; J17.4 48,245.67 ; 2.81,62.64 P4.6 2.81,60.92 ; 64.57,273.6 REFN.4 ; REFN.4 64.57,275.45 ; REFN.4 66.43,275.45 ; REFN.4 66.43,273.6 ; 75.12,278.73 REFP.2 ; REFP.2 76.97,278.73 ; REFP.2 75.12,280.59 ; REFP.2 76.97,280.59 ; 43.76,275.2 EXT_HMCREF.3 ; EXT_HMCREF.3 43.76,273.34 ; EXT_HMCREF.3 45.62,273.34 ; EXT_HMCREF.3 45.62,275.2 ; 46.14,250.75 J17.5 ; J17.5 46.14,248.9 ; J17.5 48,248.9 ; J17.5 48,250.75 ; REFP.3 82.05,278.73 ; REFP.3 80.2,280.59 ; REFP.3 80.2,278.73 ; REFP.3 82.05,280.59 ; 59.49,280.53 REFN.2 ; REFN.2 59.49,278.68 ; REFN.2 61.35,278.68 ; REFN.2 61.35,280.53 ; 53.45,213.91 REFCLK.2 ; REFCLK.2 55.31,215.76 ; REFCLK.2 55.31,213.91 ; REFCLK.2 53.45,215.76 ; GND3.1 58.56,261.73 ; GND3.1 58.56,260.24 ; GND3.1 57.06,260.24 ; GND3.1 57.06,261.73 ; EXT_SYS_N.2 13.6,278.27 ; EXT_SYS_N.2 11.75,278.27 ; EXT_SYS_N.2 13.6,280.12 ; EXT_SYS_N.2 11.75,280.12 ; 43.19,263.29 J12.3 ; J12.3 45.05,261.43 ; J12.3 45.05,263.29 ; J12.3 43.19,261.43 ; REFN.5 61.35,275.45 ; REFN.5 59.49,273.6 ; REFN.5 59.49,275.45 ; REFN.5 61.35,273.6 ; J18.4 68.56,249 ; J18.4 68.56,250.85 ; J18.4 66.71,250.85 ; J18.4 66.71,249 ; P4.8 5.76,60.64 ; P4.8 3.7,62.32 ; P4.8 5.76,62.32 ; P4.8 3.7,60.64 ; 27.96,263.3 J13.3 ; J13.3 27.96,261.44 ; J13.3 29.82,263.3 ; J13.3 29.82,261.44 ; P22.3 220.88,271.5 ; P22.3 218.85,273.53 ; P22.3 218.85,271.5 ; P22.3 220.88,273.53 ; REFCLK.3 50.23,215.76 ; REFCLK.3 50.23,213.91 ; REFCLK.3 48.37,213.91 ; REFCLK.3 48.37,215.76 ; EXT_SYS_P.5 29.5,273.21 ; EXT_SYS_P.5 27.65,273.21 ; EXT_SYS_P.5 29.5,275.07 ; EXT_SYS_P.5 27.65,275.07 ; GND5.1 5.11,49.77 ; GND5.1 5.11,48.23 ; GND5.1 3.57,49.77 ; GND5.1 3.57,48.23 ; 10.32,256.45 EXT_TRIG.4 ; EXT_TRIG.4 12.18,256.45 ; EXT_TRIG.4 12.18,258.31 ; EXT_TRIG.4 10.32,258.31 ; EXT_TRIG.3 12.18,261.53 ; EXT_TRIG.3 10.32,263.39 ; EXT_TRIG.3 10.32,261.53 ; EXT_TRIG.3 12.18,263.39 ; 182.95,284.75 S4.GND1 ; S4.GND1 184.89,284.75 ; S4.GND1 184.89,286.7 ; S4.GND1 182.95,286.7 ; 61.63,249 J18.3 ; J18.3 63.48,250.85 ; J18.3 63.48,249 ; J18.3 61.63,250.85 ; 51.22,248.9 J17.2 ; J17.2 53.08,250.75 ; J17.2 51.22,250.75 ; J17.2 53.08,248.9 ; 217.29,37.3 GND6.1 ; GND6.1 218.83,38.84 ; GND6.1 218.83,37.3 ; GND6.1 217.29,38.84 ; 22.88,261.44 J13.2 ; J13.2 22.88,263.3 ; J13.2 24.74,263.3 ; J13.2 24.74,261.44 ; EXT_TRIG.2 7.1,263.39 ; EXT_TRIG.2 5.24,261.53 ; EXT_TRIG.2 7.1,261.53 ; EXT_TRIG.2 5.24,263.39 ; EXT_HMCREF.4 45.62,280.28 ; EXT_HMCREF.4 43.76,280.28 ; EXT_HMCREF.4 45.62,278.42 ; EXT_HMCREF.4 43.76,278.42 ; 218.85,268.02 P22.6 ; P22.6 220.88,265.99 ; P22.6 218.85,265.99 ; P22.6 220.88,268.02 ; REFP.4 82.05,273.65 ; REFP.4 80.2,275.51 ; REFP.4 82.05,275.51 ; REFP.4 80.2,273.65 ; J17.3 53.08,245.67 ; J17.3 53.08,243.82 ; J17.3 51.22,245.67 ; J17.3 51.22,243.82 ; 64.57,280.53 REFN.3 ; REFN.3 66.43,278.68 ; REFN.3 66.43,280.53 ; REFN.3 64.57,278.68 ; EXT_SYS_N.3 18.68,280.12 ; EXT_SYS_N.3 16.83,280.12 ; EXT_SYS_N.3 16.83,278.27 ; EXT_SYS_N.3 18.68,278.27 ; 5.24,256.45 EXT_TRIG.5 ; EXT_TRIG.5 7.1,256.45 ; EXT_TRIG.5 5.24,258.31 ; EXT_TRIG.5 7.1,258.31 ; 196.16,286.7 S4.GND2 ; S4.GND2 198.1,286.7 ; S4.GND2 198.1,284.75 ; S4.GND2 196.16,284.75 ; 48.84,278.42 EXT_HMCREF.5 ; EXT_HMCREF.5 50.7,280.28 ; EXT_HMCREF.5 48.84,280.28 ; EXT_HMCREF.5 50.7,278.42 ; GND7.1 173.79,83.17 ; GND7.1 173.79,81.63 ; GND7.1 172.26,83.17 ; GND7.1 172.26,81.63 ; GND8.1 175.73,165.39 ; GND8.1 174.23,163.9 ; GND8.1 174.23,165.39 ; GND8.1 175.73,163.9 ; 3.7,57.47 P4.9 ; P4.9 5.76,55.79 ; P4.9 3.7,55.79 ; P4.9 5.76,57.47 ; 38.11,258.21 J12.5 ; J12.5 39.97,256.35 ; J12.5 39.97,258.21 ; J12.5 38.11,256.35 ; 199.71,237.15 GND2.1 ; GND2.1 201.2,237.15 ; GND2.1 201.2,235.65 ; GND2.1 199.71,235.65 ; EXT_HMCREF.2 50.7,273.34 ; EXT_HMCREF.2 50.7,275.2 ; EXT_HMCREF.2 48.84,275.2 ; EXT_HMCREF.2 48.84,273.34 ; 48.37,218.99 REFCLK.4 ; REFCLK.4 48.37,220.84 ; REFCLK.4 50.23,220.84 ; REFCLK.4 50.23,218.99 ; 27.65,280.15 EXT_SYS_P.2 ; EXT_SYS_P.2 27.65,278.29 ; EXT_SYS_P.2 29.5,280.15 ; EXT_SYS_P.2 29.5,278.29 ; 38.11,261.43 J12.2 ; J12.2 38.11,263.29 ; J12.2 39.97,261.43 ; J12.2 39.97,263.29 ; 8.5,100.2 GND1.1 ; GND1.1 10.04,100.2 ; GND1.1 10.04,101.73 ; GND1.1 8.5,101.73 ; 61.63,245.77 J18.2 ; J18.2 63.48,243.92 ; J18.2 63.48,245.77 ; J18.2 61.63,243.92 ; EXT_SYS_P.4 34.58,273.21 ; EXT_SYS_P.4 32.73,275.07 ; EXT_SYS_P.4 32.73,273.21 ; EXT_SYS_P.4 34.58,275.07 ; REFP.5 76.97,275.51 ; REFP.5 75.12,275.51 ; REFP.5 76.97,273.65 ; REFP.5 75.12,273.65 ; 43.19,256.35 J12.4 ; J12.4 45.05,256.35 ; J12.4 43.19,258.21 ; J12.4 45.05,258.21 ; GND4.1 50.73,195.59 ; GND4.1 49.24,195.59 ; GND4.1 50.73,194.1 ; GND4.1 49.24,194.1 ; J13.5 24.74,258.22 ; J13.5 24.74,256.36 ; J13.5 22.88,258.22 ; J13.5 22.88,256.36 ; EXT_SYS_N.4 18.68,275.04 ; EXT_SYS_N.4 18.68,273.19 ; EXT_SYS_N.4 16.83,275.04 ; EXT_SYS_N.4 16.83,273.19 ; 66.71,245.77 J18.5 ; J18.5 66.71,243.92 ; J18.5 68.56,245.77 ; J18.5 68.56,243.92 ; EXT_SYS_P.3 34.58,278.29 ; EXT_SYS_P.3 32.73,280.15 ; EXT_SYS_P.3 32.73,278.29 ; EXT_SYS_P.3 34.58,280.15 ; J13.4 29.82,258.22 ; J13.4 27.96,258.22 ; J13.4 29.82,256.36 ; J13.4 27.96,256.36 ; 11.75,273.19 EXT_SYS_N.5 ; EXT_SYS_N.5 11.75,275.04 ; EXT_SYS_N.5 13.6,275.04 ; EXT_SYS_N.5 13.6,273.19 ; 2.81,55.47 P4.7 2.81,57.19
  L22_MIXED w0.152: 11.75,278.27 EXT_SYS_N.2 ; EXT_SYS_N.2 13.6,280.12 ; EXT_SYS_N.2 13.6,278.27 ; EXT_SYS_N.2 11.75,280.12 ; 59.49,280.53 REFN.2 ; REFN.2 61.35,278.68 ; REFN.2 59.49,278.68 ; REFN.2 61.35,280.53 ; EXT_TRIG.3 12.18,263.39 ; EXT_TRIG.3 10.32,261.53 ; EXT_TRIG.3 10.32,263.39 ; EXT_TRIG.3 12.18,261.53 ; REFN.3 66.43,280.53 ; REFN.3 64.57,278.68 ; REFN.3 66.43,278.68 ; REFN.3 64.57,280.53 ; 48.84,273.34 EXT_HMCREF.2 ; EXT_HMCREF.2 48.84,275.2 ; EXT_HMCREF.2 50.7,275.2 ; EXT_HMCREF.2 50.7,273.34 ; 80.2,275.51 REFP.4 ; REFP.4 82.05,275.51 ; REFP.4 80.2,273.65 ; REFP.4 82.05,273.65 ; REFN.4 66.43,275.45 ; REFN.4 64.57,273.6 ; REFN.4 64.57,275.45 ; REFN.4 66.43,273.6 ; 46.14,245.67 J17.4 ; J17.4 48,243.82 ; J17.4 48,245.67 ; J17.4 46.14,243.82 ; EXT_SYS_P.4 34.58,275.07 ; EXT_SYS_P.4 32.73,275.07 ; EXT_SYS_P.4 32.73,273.21 ; EXT_SYS_P.4 34.58,273.21 ; P22.3 220.88,273.53 ; P22.3 218.85,271.5 ; P22.3 220.88,271.5 ; P22.3 218.85,273.53 ; 196.16,286.7 S4.GND2 ; S4.GND2 196.16,284.75 ; S4.GND2 198.1,284.75 ; S4.GND2 198.1,286.7 ; P22.6 220.88,268.02 ; P22.6 220.88,265.99 ; P22.6 218.85,268.02 ; P22.6 218.85,265.99 ; 59.49,273.6 REFN.5 ; REFN.5 61.35,275.45 ; REFN.5 61.35,273.6 ; REFN.5 59.49,275.45 ; REFP.2 76.97,278.73 ; REFP.2 75.12,280.59 ; REFP.2 75.12,278.73 ; REFP.2 76.97,280.59 ; 22.88,258.22 J13.5 ; J13.5 24.74,256.36 ; J13.5 22.88,256.36 ; J13.5 24.74,258.22 ; J13.4 29.82,258.22 ; J13.4 29.82,256.36 ; J13.4 27.96,258.22 ; J13.4 27.96,256.36 ; EXT_TRIG.2 7.1,263.39 ; EXT_TRIG.2 5.24,263.39 ; EXT_TRIG.2 7.1,261.53 ; EXT_TRIG.2 5.24,261.53 ; GND7.1 173.79,83.17 ; GND7.1 173.79,81.63 ; GND7.1 172.26,83.17 ; GND7.1 172.26,81.63 ; 61.63,250.85 J18.3 ; J18.3 63.48,250.85 ; J18.3 61.63,249 ; J18.3 63.48,249 ; 46.14,250.75 J17.5 ; J17.5 48,250.75 ; J17.5 48,248.9 ; J17.5 46.14,248.9 ; 16.83,278.27 EXT_SYS_N.3 ; EXT_SYS_N.3 18.68,278.27 ; EXT_SYS_N.3 18.68,280.12 ; EXT_SYS_N.3 16.83,280.12 ; 75.12,275.51 REFP.5 ; REFP.5 75.12,273.65 ; REFP.5 76.97,273.65 ; REFP.5 76.97,275.51 ; EXT_SYS_P.5 29.5,275.07 ; EXT_SYS_P.5 29.5,273.21 ; EXT_SYS_P.5 27.65,273.21 ; EXT_SYS_P.5 27.65,275.07 ; 43.19,258.21 J12.4 ; J12.4 45.05,256.35 ; J12.4 45.05,258.21 ; J12.4 43.19,256.35 ; 217.29,38.84 GND6.1 ; GND6.1 218.83,38.84 ; GND6.1 218.83,37.3 ; GND6.1 217.29,37.3 ; 49.24,195.59 GND4.1 ; GND4.1 49.24,194.1 ; GND4.1 50.73,195.59 ; GND4.1 50.73,194.1 ; 16.83,275.04 EXT_SYS_N.4 ; EXT_SYS_N.4 16.83,273.19 ; EXT_SYS_N.4 18.68,273.19 ; EXT_SYS_N.4 18.68,275.04 ; EXT_HMCREF.4 45.62,278.42 ; EXT_HMCREF.4 45.62,280.28 ; EXT_HMCREF.4 43.76,280.28 ; EXT_HMCREF.4 43.76,278.42 ; 43.19,261.43 J12.3 ; J12.3 45.05,263.29 ; J12.3 43.19,263.29 ; J12.3 45.05,261.43 ; J17.2 53.08,248.9 ; J17.2 51.22,248.9 ; J17.2 51.22,250.75 ; J17.2 53.08,250.75 ; EXT_HMCREF.3 45.62,275.2 ; EXT_HMCREF.3 43.76,273.34 ; EXT_HMCREF.3 45.62,273.34 ; EXT_HMCREF.3 43.76,275.2 ; EXT_TRIG.4 12.18,256.45 ; EXT_TRIG.4 10.32,256.45 ; EXT_TRIG.4 12.18,258.31 ; EXT_TRIG.4 10.32,258.31 ; 66.71,245.77 J18.5 ; J18.5 66.71,243.92 ; J18.5 68.56,245.77 ; J18.5 68.56,243.92 ; REFCLK.3 50.23,215.76 ; REFCLK.3 48.37,213.91 ; REFCLK.3 48.37,215.76 ; REFCLK.3 50.23,213.91 ; S4.GND1 184.89,286.7 ; S4.GND1 182.95,286.7 ; S4.GND1 182.95,284.75 ; S4.GND1 184.89,284.75 ; J18.4 68.56,250.85 ; J18.4 66.71,250.85 ; J18.4 68.56,249 ; J18.4 66.71,249 ; 27.65,278.29 EXT_SYS_P.2 ; EXT_SYS_P.2 29.5,278.29 ; EXT_SYS_P.2 27.65,280.15 ; EXT_SYS_P.2 29.5,280.15 ; EXT_HMCREF.5 50.7,278.42 ; EXT_HMCREF.5 48.84,278.42 ; EXT_HMCREF.5 50.7,280.28 ; EXT_HMCREF.5 48.84,280.28 ; 22.88,263.3 J13.2 ; J13.2 22.88,261.44 ; J13.2 24.74,263.3 ; J13.2 24.74,261.44 ; REFP.3 82.05,280.59 ; REFP.3 80.2,280.59 ; REFP.3 80.2,278.73 ; REFP.3 82.05,278.73 ; GND3.1 58.56,261.73 ; GND3.1 57.06,260.24 ; GND3.1 58.56,260.24 ; GND3.1 57.06,261.73 ; REFCLK.2 55.31,213.91 ; REFCLK.2 55.31,215.76 ; REFCLK.2 53.45,215.76 ; REFCLK.2 53.45,213.91 ; 48.37,220.84 REFCLK.4 ; REFCLK.4 50.23,220.84 ; REFCLK.4 48.37,218.99 ; REFCLK.4 50.23,218.99 ; J17.3 53.08,245.67 ; J17.3 51.22,245.67 ; J17.3 51.22,243.82 ; J17.3 53.08,243.82 ; 32.73,280.15 EXT_SYS_P.3 ; EXT_SYS_P.3 34.58,278.29 ; EXT_SYS_P.3 32.73,278.29 ; EXT_SYS_P.3 34.58,280.15 ; 53.45,220.84 REFCLK.5 ; REFCLK.5 55.31,220.84 ; REFCLK.5 53.45,218.99 ; REFCLK.5 55.31,218.99 ; J13.3 29.82,261.44 ; J13.3 27.96,261.44 ; J13.3 27.96,263.3 ; J13.3 29.82,263.3 ; J18.2 63.48,243.92 ; J18.2 63.48,245.77 ; J18.2 61.63,243.92 ; J18.2 61.63,245.77 ; EXT_SYS_N.5 13.6,273.19 ; EXT_SYS_N.5 13.6,275.04 ; EXT_SYS_N.5 11.75,273.19 ; EXT_SYS_N.5 11.75,275.04 ; J12.5 39.97,258.21 ; J12.5 39.97,256.35 ; J12.5 38.11,256.35 ; J12.5 38.11,258.21 ; J12.2 39.97,261.43 ; J12.2 39.97,263.29 ; J12.2 38.11,263.29 ; J12.2 38.11,261.43 ; 5.24,256.45 EXT_TRIG.5 ; EXT_TRIG.5 7.1,258.31 ; EXT_TRIG.5 7.1,256.45 ; EXT_TRIG.5 5.24,258.31
  L22_MIXED w0.191: 162.38,247.4 161.95,247.4 v1(161.59,247.04)
  L23_GROUND w0.152: EXT_HMCREF.5 50.7,280.28 ; EXT_HMCREF.5 50.7,278.42 ; EXT_HMCREF.5 48.84,280.28 ; EXT_HMCREF.5 48.84,278.42 ; 32.73,278.29 EXT_SYS_P.3 ; EXT_SYS_P.3 34.58,280.15 ; EXT_SYS_P.3 34.58,278.29 ; EXT_SYS_P.3 32.73,280.15 ; J12.4 45.05,258.21 ; J12.4 43.19,256.35 ; J12.4 43.19,258.21 ; J12.4 45.05,256.35 ; EXT_SYNC.4 12.03,239.85 ; EXT_SYNC.4 10.17,241.71 ; EXT_SYNC.4 10.17,239.85 ; EXT_SYNC.4 12.03,241.71 ; 61.63,249 J18.3 ; J18.3 63.48,250.85 ; J18.3 61.63,250.85 ; J18.3 63.48,249 ; GND5.1 5.11,49.77 ; GND5.1 3.57,49.77 ; GND5.1 5.11,48.23 ; GND5.1 3.57,48.23 ; 16.83,280.12 EXT_SYS_N.3 ; EXT_SYS_N.3 16.83,278.27 ; EXT_SYS_N.3 18.68,278.27 ; EXT_SYS_N.3 18.68,280.12 ; REFN.3 66.43,280.53 ; REFN.3 64.57,280.53 ; REFN.3 66.43,278.68 ; REFN.3 64.57,278.68 ; 5.09,241.71 EXT_SYNC.5 ; EXT_SYNC.5 5.09,239.85 ; EXT_SYNC.5 6.95,241.71 ; EXT_SYNC.5 6.95,239.85 ; 66.71,245.77 J18.5 ; J18.5 68.56,245.77 ; J18.5 68.56,243.92 ; J18.5 66.71,243.92 ; 199.71,237.15 GND2.1 ; GND2.1 201.2,235.65 ; GND2.1 199.71,235.65 ; GND2.1 201.2,237.15 ; P18.GND4 2.68,190.89 ; P18.GND4 1.28,192.3 ; P18.GND4 1.28,190.89 ; P4.8 5.76,60.64 ; P4.8 5.76,62.32 ; P4.8 3.7,62.32 ; P4.8 3.7,60.64 ; 174.23,163.9 GND8.1 ; GND8.1 174.23,165.39 ; GND8.1 175.73,163.9 ; GND8.1 175.73,165.39 ; P4.9 5.76,57.47 ; P4.9 3.7,57.47 ; P4.9 3.7,55.79 ; P4.9 5.76,55.79 ; 57.06,260.24 GND3.1 ; GND3.1 58.56,260.24 ; GND3.1 57.06,261.73 ; GND3.1 58.56,261.73 ; 27.65,273.21 EXT_SYS_P.5 ; EXT_SYS_P.5 29.5,273.21 ; EXT_SYS_P.5 27.65,275.07 ; EXT_SYS_P.5 29.5,275.07 ; GND4.1 50.73,195.59 ; GND4.1 50.73,194.1 ; GND4.1 49.24,195.59 ; GND4.1 49.24,194.1 ; 46.14,248.9 J17.5 ; J17.5 48,250.75 ; J17.5 46.14,250.75 ; J17.5 48,248.9 ; 27.96,263.3 J13.3 ; J13.3 29.82,263.3 ; J13.3 29.82,261.44 ; J13.3 27.96,261.44 ; 22.88,261.44 J13.2 ; J13.2 24.74,263.3 ; J13.2 24.74,261.44 ; J13.2 22.88,263.3 ; 8.5,100.2 GND1.1 ; GND1.1 10.04,100.2 ; GND1.1 8.5,101.73 ; GND1.1 10.04,101.73 ; 217.29,37.3 GND6.1 ; GND6.1 218.83,38.84 ; GND6.1 218.83,37.3 ; GND6.1 217.29,38.84 ; 3.67,198.94 P19.GND1 ; P19.GND1 5.07,200.35 ; P19.GND1 5.07,198.94 ; 75.12,273.65 REFP.5 ; REFP.5 76.97,275.51 ; REFP.5 76.97,273.65 ; REFP.5 75.12,275.51 ; EXT_HMCREF.3 45.62,275.2 ; EXT_HMCREF.3 45.62,273.34 ; EXT_HMCREF.3 43.76,275.2 ; EXT_HMCREF.3 43.76,273.34 ; 53.45,220.84 REFCLK.5 ; REFCLK.5 53.45,218.99 ; REFCLK.5 55.31,220.84 ; REFCLK.5 55.31,218.99 ; REFP.4 82.05,275.51 ; REFP.4 80.2,275.51 ; REFP.4 80.2,273.65 ; REFP.4 82.05,273.65 ; 2.81,57.19 P4.7 2.81,55.47 ; 51.22,250.75 J17.2 ; J17.2 51.22,248.9 ; J17.2 53.08,250.75 ; J17.2 53.08,248.9 ; EXT_TRIG.3 12.18,263.39 ; EXT_TRIG.3 10.32,261.53 ; EXT_TRIG.3 10.32,263.39 ; EXT_TRIG.3 12.18,261.53 ; EXT_SYNC.2 6.95,244.93 ; EXT_SYNC.2 6.95,246.79 ; EXT_SYNC.2 5.09,246.79 ; EXT_SYNC.2 5.09,244.93 ; EXT_SYNC.3 12.03,244.93 ; EXT_SYNC.3 10.17,246.79 ; EXT_SYNC.3 10.17,244.93 ; EXT_SYNC.3 12.03,246.79 ; 53.45,213.91 REFCLK.2 ; REFCLK.2 53.45,215.76 ; REFCLK.2 55.31,213.91 ; REFCLK.2 55.31,215.76 ; 27.96,258.22 J13.4 ; J13.4 29.82,256.36 ; J13.4 27.96,256.36 ; J13.4 29.82,258.22 ; J12.2 39.97,263.29 ; J12.2 38.11,261.43 ; J12.2 39.97,261.43 ; J12.2 38.11,263.29 ; 196.16,284.75 S4.GND2 ; S4.GND2 198.1,286.7 ; S4.GND2 198.1,284.75 ; S4.GND2 196.16,286.7 ; 5.24,258.31 EXT_TRIG.5 ; EXT_TRIG.5 7.1,256.45 ; EXT_TRIG.5 7.1,258.31 ; EXT_TRIG.5 5.24,256.45 ; 11.75,280.12 EXT_SYS_N.2 ; EXT_SYS_N.2 13.6,278.27 ; EXT_SYS_N.2 11.75,278.27 ; EXT_SYS_N.2 13.6,280.12 ; EXT_HMCREF.4 45.62,280.28 ; EXT_HMCREF.4 43.76,280.28 ; EXT_HMCREF.4 43.76,278.42 ; EXT_HMCREF.4 45.62,278.42 ; 66.71,250.85 J18.4 ; J18.4 66.71,249 ; J18.4 68.56,250.85 ; J18.4 68.56,249 ; 2.81,62.64 P4.6 2.81,60.92 ; 32.73,273.21 EXT_SYS_P.4 ; EXT_SYS_P.4 34.58,275.07 ; EXT_SYS_P.4 32.73,275.07 ; EXT_SYS_P.4 34.58,273.21 ; 48.84,273.34 EXT_HMCREF.2 ; EXT_HMCREF.2 48.84,275.2 ; EXT_HMCREF.2 50.7,273.34 ; EXT_HMCREF.2 50.7,275.2 ; 5.24,261.53 EXT_TRIG.2 ; EXT_TRIG.2 5.24,263.39 ; EXT_TRIG.2 7.1,261.53 ; EXT_TRIG.2 7.1,263.39 ; 1.13,202.89 P19.GND3 ; P19.GND3 1.13,201.48 ; P19.GND3 2.53,202.89 ; 48.37,220.84 REFCLK.4 ; REFCLK.4 48.37,218.99 ; REFCLK.4 50.23,218.99 ; REFCLK.4 50.23,220.84 ; 59.49,280.53 REFN.2 ; REFN.2 61.35,280.53 ; REFN.2 61.35,278.68 ; REFN.2 59.49,278.68 ; J12.5 39.97,256.35 ; J12.5 38.11,258.21 ; J12.5 38.11,256.35 ; J12.5 39.97,258.21 ; 27.65,278.29 EXT_SYS_P.2 ; EXT_SYS_P.2 29.5,278.29 ; EXT_SYS_P.2 27.65,280.15 ; EXT_SYS_P.2 29.5,280.15 ; REFN.4 66.43,273.6 ; REFN.4 64.57,273.6 ; REFN.4 66.43,275.45 ; REFN.4 64.57,275.45 ; P22.6 220.88,265.99 ; P22.6 220.88,268.02 ; P22.6 218.85,265.99 ; P22.6 218.85,268.02 ; REFCLK.3 50.23,215.76 ; REFCLK.3 48.37,213.91 ; REFCLK.3 50.23,213.91 ; REFCLK.3 48.37,215.76 ; 3.82,194.84 P18.GND2 ; P18.GND2 5.22,194.84 ; P18.GND2 5.22,193.43 ; 3.67,202.89 P19.GND2 ; P19.GND2 5.07,201.48 ; P19.GND2 5.07,202.89 ; REFP.2 76.97,278.73 ; REFP.2 76.97,280.59 ; REFP.2 75.12,278.73 ; REFP.2 75.12,280.59 ; J13.5 24.74,256.36 ; J13.5 24.74,258.22 ; J13.5 22.88,256.36 ; J13.5 22.88,258.22 ; 59.49,275.45 REFN.5 ; REFN.5 59.49,273.6 ; REFN.5 61.35,275.45 ; REFN.5 61.35,273.6 ; 3.82,190.89 P18.GND1 ; P18.GND1 5.22,190.89 ; P18.GND1 5.22,192.3 ; J12.3 45.05,263.29 ; J12.3 43.19,263.29 ; J12.3 43.19,261.43 ; J12.3 45.05,261.43 ; 61.63,245.77 J18.2 ; J18.2 63.48,245.77 ; J18.2 63.48,243.92 ; J18.2 61.63,243.92 ; REFP.3 82.05,278.73 ; REFP.3 80.2,280.59 ; REFP.3 80.2,278.73 ; REFP.3 82.05,280.59 ; J17.4 48,245.67 ; J17.4 48,243.82 ; J17.4 46.14,243.82 ; J17.4 46.14,245.67 ; 10.32,258.31 EXT_TRIG.4 ; EXT_TRIG.4 12.18,256.45 ; EXT_TRIG.4 12.18,258.31 ; EXT_TRIG.4 10.32,256.45 ; 1.13,200.35 P19.GND4 ; P19.GND4 1.13,198.94 ; P19.GND4 2.53,198.94 ; EXT_SYS_N.5 13.6,273.19 ; EXT_SYS_N.5 13.6,275.04 ; EXT_SYS_N.5 11.75,273.19 ; EXT_SYS_N.5 11.75,275.04 ; GND7.1 173.79,83.17 ; GND7.1 173.79,81.63 ; GND7.1 172.26,83.17 ; GND7.1 172.26,81.63 ; 1.28,193.43 P18.GND3 ; P18.GND3 1.28,194.84 ; P18.GND3 2.68,194.84 ; P22.3 220.88,271.5 ; P22.3 220.88,273.53 ; P22.3 218.85,273.53 ; P22.3 218.85,271.5 ; J17.3 53.08,245.67 ; J17.3 51.22,243.82 ; J17.3 51.22,245.67 ; J17.3 53.08,243.82 ; EXT_SYS_N.4 18.68,273.19 ; EXT_SYS_N.4 16.83,275.04 ; EXT_SYS_N.4 16.83,273.19 ; EXT_SYS_N.4 18.68,275.04 ; 182.95,284.75 S4.GND1 ; S4.GND1 184.89,286.7 ; S4.GND1 184.89,284.75 ; S4.GND1 182.95,286.7
  L24_SIGNAL w0.152: J12.4 45.05,256.35 ; J12.4 45.05,258.21 ; J12.4 43.19,256.35 ; J12.4 43.19,258.21 ; 48.84,273.34 EXT_HMCREF.2 ; EXT_HMCREF.2 48.84,275.2 ; EXT_HMCREF.2 50.7,275.2 ; EXT_HMCREF.2 50.7,273.34 ; 48.37,215.76 REFCLK.3 ; REFCLK.3 50.23,213.91 ; REFCLK.3 50.23,215.76 ; REFCLK.3 48.37,213.91 ; 1.13,198.94 P19.GND4 ; P19.GND4 1.13,200.35 ; P19.GND4 2.53,198.94 ; J18.3 63.48,250.85 ; J18.3 61.63,249 ; J18.3 63.48,249 ; J18.3 61.63,250.85 ; REFP.3 82.05,278.73 ; REFP.3 80.2,280.59 ; REFP.3 82.05,280.59 ; REFP.3 80.2,278.73 ; 5.24,256.45 EXT_TRIG.5 ; EXT_TRIG.5 5.24,258.31 ; EXT_TRIG.5 7.1,258.31 ; EXT_TRIG.5 7.1,256.45 ; 16.83,278.27 EXT_SYS_N.3 ; EXT_SYS_N.3 18.68,280.12 ; EXT_SYS_N.3 16.83,280.12 ; EXT_SYS_N.3 18.68,278.27 ; 38.11,263.29 J12.2 ; J12.2 39.97,261.43 ; J12.2 38.11,261.43 ; J12.2 39.97,263.29 ; J18.2 63.48,245.77 ; J18.2 63.48,243.92 ; J18.2 61.63,245.77 ; J18.2 61.63,243.92 ; REFP.4 82.05,275.51 ; REFP.4 80.2,275.51 ; REFP.4 80.2,273.65 ; REFP.4 82.05,273.65 ; 1.28,190.89 P18.GND4 ; P18.GND4 1.28,192.3 ; P18.GND4 2.68,190.89 ; J17.5 48,248.9 ; J17.5 48,250.75 ; J17.5 46.14,250.75 ; J17.5 46.14,248.9 ; P18.GND1 5.22,190.89 ; P18.GND1 5.22,192.3 ; P18.GND1 3.82,190.89 ; 46.14,243.82 J17.4 ; J17.4 48,243.82 ; J17.4 46.14,245.67 ; J17.4 48,245.67 ; GND4.1 50.73,195.59 ; GND4.1 49.24,195.59 ; GND4.1 49.24,194.1 ; GND4.1 50.73,194.1 ; REFN.2 61.35,280.53 ; REFN.2 61.35,278.68 ; REFN.2 59.49,280.53 ; REFN.2 59.49,278.68 ; 10.32,256.45 EXT_TRIG.4 ; EXT_TRIG.4 12.18,256.45 ; EXT_TRIG.4 10.32,258.31 ; EXT_TRIG.4 12.18,258.31 ; 59.49,275.45 REFN.5 ; REFN.5 59.49,273.6 ; REFN.5 61.35,275.45 ; REFN.5 61.35,273.6 ; 10.17,244.93 EXT_SYNC.3 ; EXT_SYNC.3 12.03,244.93 ; EXT_SYNC.3 10.17,246.79 ; EXT_SYNC.3 12.03,246.79 ; J13.5 24.74,258.22 ; J13.5 24.74,256.36 ; J13.5 22.88,258.22 ; J13.5 22.88,256.36 ; 57.06,260.24 GND3.1 ; GND3.1 57.06,261.73 ; GND3.1 58.56,260.24 ; GND3.1 58.56,261.73 ; J13.3 29.82,263.3 ; J13.3 27.96,263.3 ; J13.3 27.96,261.44 ; J13.3 29.82,261.44 ; EXT_SYS_P.5 29.5,273.21 ; EXT_SYS_P.5 29.5,275.07 ; EXT_SYS_P.5 27.65,275.07 ; EXT_SYS_P.5 27.65,273.21 ; J13.2 24.74,261.44 ; J13.2 22.88,261.44 ; J13.2 24.74,263.3 ; J13.2 22.88,263.3 ; EXT_HMCREF.5 50.7,278.42 ; EXT_HMCREF.5 50.7,280.28 ; EXT_HMCREF.5 48.84,278.42 ; EXT_HMCREF.5 48.84,280.28 ; GND2.1 201.2,235.65 ; GND2.1 201.2,237.15 ; GND2.1 199.71,235.65 ; GND2.1 199.71,237.15 ; 43.19,261.43 J12.3 ; J12.3 43.19,263.29 ; J12.3 45.05,263.29 ; J12.3 45.05,261.43 ; REFP.2 76.97,280.59 ; REFP.2 76.97,278.73 ; REFP.2 75.12,280.59 ; REFP.2 75.12,278.73 ; 48.37,218.99 REFCLK.4 ; REFCLK.4 50.23,220.84 ; REFCLK.4 50.23,218.99 ; REFCLK.4 48.37,220.84 ; J17.2 53.08,250.75 ; J17.2 51.22,250.75 ; J17.2 53.08,248.9 ; J17.2 51.22,248.9 ; EXT_SYS_N.5 13.6,273.19 ; EXT_SYS_N.5 11.75,275.04 ; EXT_SYS_N.5 13.6,275.04 ; EXT_SYS_N.5 11.75,273.19 ; 32.73,280.15 EXT_SYS_P.3 ; EXT_SYS_P.3 32.73,278.29 ; EXT_SYS_P.3 34.58,280.15 ; EXT_SYS_P.3 34.58,278.29 ; REFN.4 66.43,275.45 ; REFN.4 64.57,275.45 ; REFN.4 66.43,273.6 ; REFN.4 64.57,273.6 ; 5.09,241.71 EXT_SYNC.5 ; EXT_SYNC.5 6.95,241.71 ; EXT_SYNC.5 6.95,239.85 ; EXT_SYNC.5 5.09,239.85 ; 5.24,263.39 EXT_TRIG.2 ; EXT_TRIG.2 5.24,261.53 ; EXT_TRIG.2 7.1,263.39 ; EXT_TRIG.2 7.1,261.53 ; 43.76,273.34 EXT_HMCREF.3 ; EXT_HMCREF.3 45.62,273.34 ; EXT_HMCREF.3 45.62,275.2 ; EXT_HMCREF.3 43.76,275.2 ; J17.3 53.08,243.82 ; J17.3 51.22,245.67 ; J17.3 53.08,245.67 ; J17.3 51.22,243.82 ; 218.85,273.53 P22.3 ; P22.3 218.85,271.5 ; P22.3 220.88,273.53 ; P22.3 220.88,271.5 ; 27.65,280.15 EXT_SYS_P.2 ; EXT_SYS_P.2 27.65,278.29 ; EXT_SYS_P.2 29.5,278.29 ; EXT_SYS_P.2 29.5,280.15 ; 64.57,280.53 REFN.3 ; REFN.3 64.57,278.68 ; REFN.3 66.43,278.68 ; REFN.3 66.43,280.53 ; 53.45,220.84 REFCLK.5 ; REFCLK.5 53.45,218.99 ; REFCLK.5 55.31,218.99 ; REFCLK.5 55.31,220.84 ; P19.GND3 2.53,202.89 ; P19.GND3 1.13,202.89 ; P19.GND3 1.13,201.48 ; GND8.1 175.73,163.9 ; GND8.1 174.23,163.9 ; GND8.1 174.23,165.39 ; GND8.1 175.73,165.39 ; EXT_TRIG.3 12.18,263.39 ; EXT_TRIG.3 10.32,263.39 ; EXT_TRIG.3 12.18,261.53 ; EXT_TRIG.3 10.32,261.53 ; EXT_SYNC.4 12.03,239.85 ; EXT_SYNC.4 10.17,239.85 ; EXT_SYNC.4 10.17,241.71 ; EXT_SYNC.4 12.03,241.71 ; 218.85,268.02 P22.6 ; P22.6 220.88,268.02 ; P22.6 220.88,265.99 ; P22.6 218.85,265.99 ; J12.5 39.97,258.21 ; J12.5 38.11,258.21 ; J12.5 38.11,256.35 ; J12.5 39.97,256.35 ; 66.71,249 J18.4 ; J18.4 66.71,250.85 ; J18.4 68.56,249 ; J18.4 68.56,250.85 ; 53.45,215.76 REFCLK.2 ; REFCLK.2 55.31,215.76 ; REFCLK.2 53.45,213.91 ; REFCLK.2 55.31,213.91 ; J18.5 68.56,245.77 ; J18.5 68.56,243.92 ; J18.5 66.71,243.92 ; J18.5 66.71,245.77 ; 27.96,256.36 J13.4 ; J13.4 29.82,258.22 ; J13.4 27.96,258.22 ; J13.4 29.82,256.36 ; S4.GND2 198.1,286.7 ; S4.GND2 196.16,284.75 ; S4.GND2 196.16,286.7 ; S4.GND2 198.1,284.75 ; 43.76,280.28 EXT_HMCREF.4 ; EXT_HMCREF.4 45.62,280.28 ; EXT_HMCREF.4 43.76,278.42 ; EXT_HMCREF.4 45.62,278.42 ; EXT_SYS_N.2 13.6,278.27 ; EXT_SYS_N.2 11.75,280.12 ; EXT_SYS_N.2 11.75,278.27 ; EXT_SYS_N.2 13.6,280.12 ; 5.09,246.79 EXT_SYNC.2 ; EXT_SYNC.2 6.95,246.79 ; EXT_SYNC.2 5.09,244.93 ; EXT_SYNC.2 6.95,244.93 ; 75.12,275.51 REFP.5 ; REFP.5 75.12,273.65 ; REFP.5 76.97,275.51 ; REFP.5 76.97,273.65 ; EXT_SYS_P.4 34.58,275.07 ; EXT_SYS_P.4 32.73,273.21 ; EXT_SYS_P.4 34.58,273.21 ; EXT_SYS_P.4 32.73,275.07 ; P19.GND2 5.07,201.48 ; P19.GND2 5.07,202.89 ; P19.GND2 3.67,202.89 ; 182.95,284.75 S4.GND1 ; S4.GND1 184.89,284.75 ; S4.GND1 182.95,286.7 ; S4.GND1 184.89,286.7 ; 1.28,194.84 P18.GND3 ; P18.GND3 1.28,193.43 ; P18.GND3 2.68,194.84 ; P18.GND2 5.22,193.43 ; P18.GND2 3.82,194.84 ; P18.GND2 5.22,194.84 ; 16.83,275.04 EXT_SYS_N.4 ; EXT_SYS_N.4 18.68,275.04 ; EXT_SYS_N.4 16.83,273.19 ; EXT_SYS_N.4 18.68,273.19 ; P19.GND1 5.07,198.94 ; P19.GND1 5.07,200.35 ; P19.GND1 3.67,198.94
  L25_GROUND w0.152: REFP.2 76.97,278.73 ; REFP.2 76.97,280.59 ; REFP.2 75.12,280.59 ; REFP.2 75.12,278.73 ; 5.09,244.93 EXT_SYNC.2 ; EXT_SYNC.2 6.95,244.93 ; EXT_SYNC.2 6.95,246.79 ; EXT_SYNC.2 5.09,246.79 ; EXT_SYS_N.4 18.68,275.04 ; EXT_SYS_N.4 16.83,275.04 ; EXT_SYS_N.4 18.68,273.19 ; EXT_SYS_N.4 16.83,273.19 ; J12.4 45.05,258.21 ; J12.4 45.05,256.35 ; J12.4 43.19,256.35 ; J12.4 43.19,258.21 ; 51.22,250.75 J17.2 ; J17.2 53.08,248.9 ; J17.2 53.08,250.75 ; J17.2 51.22,248.9 ; 51.22,245.67 J17.3 ; J17.3 53.08,245.67 ; J17.3 51.22,243.82 ; J17.3 53.08,243.82 ; P18.GND2 5.22,194.84 ; P18.GND2 5.22,193.43 ; P18.GND2 3.82,194.84 ; 59.49,278.68 REFN.2 ; REFN.2 59.49,280.53 ; REFN.2 61.35,280.53 ; REFN.2 61.35,278.68 ; 66.71,249 J18.4 ; J18.4 68.56,249 ; J18.4 66.71,250.85 ; J18.4 68.56,250.85 ; 27.65,273.21 EXT_SYS_P.5 ; EXT_SYS_P.5 29.5,273.21 ; EXT_SYS_P.5 27.65,275.07 ; EXT_SYS_P.5 29.5,275.07 ; S4.GND2 198.1,286.7 ; S4.GND2 196.16,284.75 ; S4.GND2 196.16,286.7 ; S4.GND2 198.1,284.75 ; EXT_TRIG.2 7.1,261.53 ; EXT_TRIG.2 5.24,261.53 ; EXT_TRIG.2 7.1,263.39 ; EXT_TRIG.2 5.24,263.39 ; EXT_SYNC.4 12.03,241.71 ; EXT_SYNC.4 10.17,239.85 ; EXT_SYNC.4 12.03,239.85 ; EXT_SYNC.4 10.17,241.71 ; 3.7,60.64 P4.8 ; P4.8 5.76,62.32 ; P4.8 5.76,60.64 ; P4.8 3.7,62.32 ; 53.45,220.84 REFCLK.5 ; REFCLK.5 55.31,218.99 ; REFCLK.5 55.31,220.84 ; REFCLK.5 53.45,218.99 ; 1.13,202.89 P19.GND3 ; P19.GND3 1.13,201.48 ; P19.GND3 2.53,202.89 ; GND5.1 5.11,48.23 ; GND5.1 3.57,49.77 ; GND5.1 3.57,48.23 ; GND5.1 5.11,49.77 ; EXT_SYS_N.2 13.6,280.12 ; EXT_SYS_N.2 11.75,278.27 ; EXT_SYS_N.2 13.6,278.27 ; EXT_SYS_N.2 11.75,280.12 ; GND6.1 218.83,37.3 ; GND6.1 217.29,37.3 ; GND6.1 218.83,38.84 ; GND6.1 217.29,38.84 ; P19.GND1 5.07,198.94 ; P19.GND1 3.67,198.94 ; P19.GND1 5.07,200.35 ; 66.71,243.92 J18.5 ; J18.5 68.56,243.92 ; J18.5 68.56,245.77 ; J18.5 66.71,245.77 ; EXT_SYS_N.5 13.6,273.19 ; EXT_SYS_N.5 11.75,273.19 ; EXT_SYS_N.5 13.6,275.04 ; EXT_SYS_N.5 11.75,275.04 ; J12.3 45.05,263.29 ; J12.3 43.19,263.29 ; J12.3 45.05,261.43 ; J12.3 43.19,261.43 ; EXT_TRIG.5 7.1,256.45 ; EXT_TRIG.5 5.24,256.45 ; EXT_TRIG.5 5.24,258.31 ; EXT_TRIG.5 7.1,258.31 ; 27.65,278.29 EXT_SYS_P.2 ; EXT_SYS_P.2 27.65,280.15 ; EXT_SYS_P.2 29.5,280.15 ; EXT_SYS_P.2 29.5,278.29 ; 2.81,62.64 P4.6 2.81,60.92 ; 10.17,246.79 EXT_SYNC.3 ; EXT_SYNC.3 10.17,244.93 ; EXT_SYNC.3 12.03,244.93 ; EXT_SYNC.3 12.03,246.79 ; 48.37,215.76 REFCLK.3 ; REFCLK.3 50.23,215.76 ; REFCLK.3 48.37,213.91 ; REFCLK.3 50.23,213.91 ; 22.88,261.44 J13.2 ; J13.2 24.74,261.44 ; J13.2 24.74,263.3 ; J13.2 22.88,263.3 ; 3.7,55.79 P4.9 ; P4.9 5.76,57.47 ; P4.9 5.76,55.79 ; P4.9 3.7,57.47 ; S4.GND1 184.89,284.75 ; S4.GND1 182.95,284.75 ; S4.GND1 182.95,286.7 ; S4.GND1 184.89,286.7 ; EXT_TRIG.3 12.18,261.53 ; EXT_TRIG.3 10.32,263.39 ; EXT_TRIG.3 10.32,261.53 ; EXT_TRIG.3 12.18,263.39 ; P18.GND1 5.22,190.89 ; P18.GND1 5.22,192.3 ; P18.GND1 3.82,190.89 ; 46.14,248.9 J17.5 ; J17.5 48,250.75 ; J17.5 48,248.9 ; J17.5 46.14,250.75 ; REFP.5 76.97,273.65 ; REFP.5 75.12,273.65 ; REFP.5 75.12,275.51 ; REFP.5 76.97,275.51 ; REFN.3 66.43,278.68 ; REFN.3 66.43,280.53 ; REFN.3 64.57,280.53 ; REFN.3 64.57,278.68 ; P19.GND2 5.07,201.48 ; P19.GND2 5.07,202.89 ; P19.GND2 3.67,202.89 ; 57.06,261.73 GND3.1 ; GND3.1 57.06,260.24 ; GND3.1 58.56,261.73 ; GND3.1 58.56,260.24 ; GND2.1 201.2,237.15 ; GND2.1 199.71,235.65 ; GND2.1 201.2,235.65 ; GND2.1 199.71,237.15 ; REFN.5 61.35,273.6 ; REFN.5 59.49,273.6 ; REFN.5 59.49,275.45 ; REFN.5 61.35,275.45 ; EXT_SYNC.5 6.95,241.71 ; EXT_SYNC.5 5.09,241.71 ; EXT_SYNC.5 5.09,239.85 ; EXT_SYNC.5 6.95,239.85 ; 32.73,275.07 EXT_SYS_P.4 ; EXT_SYS_P.4 34.58,273.21 ; EXT_SYS_P.4 32.73,273.21 ; EXT_SYS_P.4 34.58,275.07 ; EXT_TRIG.4 12.18,256.45 ; EXT_TRIG.4 10.32,256.45 ; EXT_TRIG.4 10.32,258.31 ; EXT_TRIG.4 12.18,258.31 ; 218.85,268.02 P22.6 ; P22.6 220.88,265.99 ; P22.6 218.85,265.99 ; P22.6 220.88,268.02 ; 61.63,249 J18.3 ; J18.3 61.63,250.85 ; J18.3 63.48,249 ; J18.3 63.48,250.85 ; 27.96,258.22 J13.4 ; J13.4 29.82,258.22 ; J13.4 27.96,256.36 ; J13.4 29.82,256.36 ; P22.3 220.88,271.5 ; P22.3 218.85,271.5 ; P22.3 220.88,273.53 ; P22.3 218.85,273.53 ; REFP.3 82.05,278.73 ; REFP.3 80.2,280.59 ; REFP.3 80.2,278.73 ; REFP.3 82.05,280.59 ; EXT_SYS_N.3 18.68,278.27 ; EXT_SYS_N.3 16.83,280.12 ; EXT_SYS_N.3 16.83,278.27 ; EXT_SYS_N.3 18.68,280.12 ; 1.28,192.3 P18.GND4 ; P18.GND4 1.28,190.89 ; P18.GND4 2.68,190.89 ; REFP.4 82.05,275.51 ; REFP.4 82.05,273.65 ; REFP.4 80.2,273.65 ; REFP.4 80.2,275.51 ; 1.13,200.35 P19.GND4 ; P19.GND4 1.13,198.94 ; P19.GND4 2.53,198.94 ; J12.2 39.97,261.43 ; J12.2 38.11,261.43 ; J12.2 38.11,263.29 ; J12.2 39.97,263.29 ; 27.96,261.44 J13.3 ; J13.3 29.82,263.3 ; J13.3 29.82,261.44 ; J13.3 27.96,263.3 ; 48.37,220.84 REFCLK.4 ; REFCLK.4 50.23,218.99 ; REFCLK.4 48.37,218.99 ; REFCLK.4 50.23,220.84 ; EXT_HMCREF.2 50.7,275.2 ; EXT_HMCREF.2 48.84,273.34 ; EXT_HMCREF.2 48.84,275.2 ; EXT_HMCREF.2 50.7,273.34 ; 22.88,256.36 J13.5 ; J13.5 24.74,256.36 ; J13.5 24.74,258.22 ; J13.5 22.88,258.22 ; J12.5 39.97,258.21 ; J12.5 39.97,256.35 ; J12.5 38.11,258.21 ; J12.5 38.11,256.35 ; GND7.1 173.79,83.17 ; GND7.1 173.79,81.63 ; GND7.1 172.26,83.17 ; GND7.1 172.26,81.63 ; EXT_HMCREF.3 45.62,275.2 ; EXT_HMCREF.3 43.76,273.34 ; EXT_HMCREF.3 45.62,273.34 ; EXT_HMCREF.3 43.76,275.2 ; 49.24,195.59 GND4.1 ; GND4.1 50.73,195.59 ; GND4.1 50.73,194.1 ; GND4.1 49.24,194.1 ; 174.23,163.9 GND8.1 ; GND8.1 175.73,163.9 ; GND8.1 174.23,165.39 ; GND8.1 175.73,165.39 ; P18.GND3 2.68,194.84 ; P18.GND3 1.28,194.84 ; P18.GND3 1.28,193.43 ; REFN.4 66.43,273.6 ; REFN.4 66.43,275.45 ; REFN.4 64.57,273.6 ; REFN.4 64.57,275.45 ; EXT_HMCREF.5 50.7,278.42 ; EXT_HMCREF.5 50.7,280.28 ; EXT_HMCREF.5 48.84,278.42 ; EXT_HMCREF.5 48.84,280.28 ; 32.73,278.29 EXT_SYS_P.3 ; EXT_SYS_P.3 34.58,280.15 ; EXT_SYS_P.3 34.58,278.29 ; EXT_SYS_P.3 32.73,280.15 ; 43.76,278.42 EXT_HMCREF.4 ; EXT_HMCREF.4 45.62,280.28 ; EXT_HMCREF.4 45.62,278.42 ; EXT_HMCREF.4 43.76,280.28 ; GND1.1 10.04,100.2 ; GND1.1 8.5,101.73 ; GND1.1 10.04,101.73 ; GND1.1 8.5,100.2 ; 61.63,245.77 J18.2 ; J18.2 63.48,245.77 ; J18.2 63.48,243.92 ; J18.2 61.63,243.92 ; 2.81,55.47 P4.7 2.81,57.19 ; 53.45,215.76 REFCLK.2 ; REFCLK.2 55.31,215.76 ; REFCLK.2 53.45,213.91 ; REFCLK.2 55.31,213.91 ; 46.14,243.82 J17.4 ; J17.4 48,245.67 ; J17.4 46.14,245.67 ; J17.4 48,243.82
  BOTTOM w0.127: C338.2 111.66,126.53 v4(111.9,126.53) ; v4(111.9,123.33) 111.89,123.34 C355.2 ; C343.2 111.7,125.73 v4(111.9,125.73) ; 111.67,122.53 C352.2 111.88,122.55 v4(111.9,122.53) 111.67,122.53
  BOTTOM w0.152: EXT_TRIG.4 12.18,256.45 ; EXT_TRIG.4 12.18,258.31 ; EXT_TRIG.4 10.32,256.45 ; EXT_TRIG.4 10.32,258.31 ; REFP.2 76.97,278.73 ; REFP.2 75.12,280.59 ; REFP.2 75.12,278.73 ; REFP.2 76.97,280.59 ; 10.17,244.93 EXT_SYNC.3 ; EXT_SYNC.3 12.03,244.93 ; EXT_SYNC.3 10.17,246.79 ; EXT_SYNC.3 12.03,246.79 ; REFCLK.5 55.31,220.84 ; REFCLK.5 53.45,220.84 ; REFCLK.5 55.31,218.99 ; REFCLK.5 53.45,218.99 ; P18.GND1 5.22,190.89 ; P18.GND1 3.82,190.89 ; P18.GND1 5.22,192.3 ; 48.37,215.76 REFCLK.3 ; REFCLK.3 50.23,213.91 ; REFCLK.3 50.23,215.76 ; REFCLK.3 48.37,213.91 ; S4.GND2 198.1,286.7 ; S4.GND2 196.16,284.75 ; S4.GND2 198.1,284.75 ; S4.GND2 196.16,286.7 ; 3.67,202.89 P19.GND2 ; P19.GND2 5.07,201.48 ; P19.GND2 5.07,202.89 ; J12.3 45.05,263.29 ; J12.3 43.19,261.43 ; J12.3 45.05,261.43 ; J12.3 43.19,263.29 ; 38.11,263.29 J12.2 ; J12.2 38.11,261.43 ; J12.2 39.97,261.43 ; J12.2 39.97,263.29 ; 27.96,258.22 J13.4 ; J13.4 29.82,256.36 ; J13.4 27.96,256.36 ; J13.4 29.82,258.22 ; J18.3 63.48,249 ; J18.3 61.63,250.85 ; J18.3 63.48,250.85 ; J18.3 61.63,249 ; 38.11,258.21 J12.5 ; J12.5 38.11,256.35 ; J12.5 39.97,258.21 ; J12.5 39.97,256.35 ; EXT_HMCREF.5 50.7,278.42 ; EXT_HMCREF.5 50.7,280.28 ; EXT_HMCREF.5 48.84,278.42 ; EXT_HMCREF.5 48.84,280.28 ; P22.6 220.88,265.99 ; P22.6 218.85,268.02 ; P22.6 220.88,268.02 ; P22.6 218.85,265.99 ; P18.GND3 2.68,194.84 ; P18.GND3 1.28,193.43 ; P18.GND3 1.28,194.84 ; 11.75,275.04 EXT_SYS_N.5 ; EXT_SYS_N.5 13.6,273.19 ; EXT_SYS_N.5 13.6,275.04 ; EXT_SYS_N.5 11.75,273.19 ; GND5.1 5.11,48.23 ; GND5.1 3.57,48.23 ; GND5.1 3.57,49.77 ; GND5.1 5.11,49.77 ; 1.13,200.35 P19.GND4 ; P19.GND4 1.13,198.94 ; P19.GND4 2.53,198.94 ; P19.GND1 5.07,200.35 ; P19.GND1 5.07,198.94 ; P19.GND1 3.67,198.94 ; 16.83,275.04 EXT_SYS_N.4 ; EXT_SYS_N.4 18.68,273.19 ; EXT_SYS_N.4 18.68,275.04 ; EXT_SYS_N.4 16.83,273.19 ; 80.2,275.51 REFP.4 ; REFP.4 82.05,273.65 ; REFP.4 80.2,273.65 ; REFP.4 82.05,275.51 ; 1.28,190.89 P18.GND4 ; P18.GND4 1.28,192.3 ; P18.GND4 2.68,190.89 ; REFP.5 76.97,273.65 ; REFP.5 75.12,275.51 ; REFP.5 76.97,275.51 ; REFP.5 75.12,273.65 ; 51.22,248.9 J17.2 ; J17.2 53.08,248.9 ; J17.2 53.08,250.75 ; J17.2 51.22,250.75 ; P22.3 220.88,273.53 ; P22.3 220.88,271.5 ; P22.3 218.85,273.53 ; P22.3 218.85,271.5 ; 11.75,280.12 EXT_SYS_N.2 ; EXT_SYS_N.2 13.6,278.27 ; EXT_SYS_N.2 13.6,280.12 ; EXT_SYS_N.2 11.75,278.27 ; 10.17,241.71 EXT_SYNC.4 ; EXT_SYNC.4 12.03,239.85 ; EXT_SYNC.4 10.17,239.85 ; EXT_SYNC.4 12.03,241.71 ; 16.83,280.12 EXT_SYS_N.3 ; EXT_SYS_N.3 16.83,278.27 ; EXT_SYS_N.3 18.68,280.12 ; EXT_SYS_N.3 18.68,278.27 ; 8.5,100.2 GND1.1 ; GND1.1 8.5,101.73 ; GND1.1 10.04,101.73 ; GND1.1 10.04,100.2 ; EXT_TRIG.3 12.18,261.53 ; EXT_TRIG.3 12.18,263.39 ; EXT_TRIG.3 10.32,261.53 ; EXT_TRIG.3 10.32,263.39 ; EXT_SYS_P.2 29.5,280.15 ; EXT_SYS_P.2 27.65,280.15 ; EXT_SYS_P.2 27.65,278.29 ; EXT_SYS_P.2 29.5,278.29 ; 43.76,275.2 EXT_HMCREF.3 ; EXT_HMCREF.3 45.62,275.2 ; EXT_HMCREF.3 43.76,273.34 ; EXT_HMCREF.3 45.62,273.34 ; 5.09,246.79 EXT_SYNC.2 ; EXT_SYNC.2 6.95,244.93 ; EXT_SYNC.2 5.09,244.93 ; EXT_SYNC.2 6.95,246.79 ; GND3.1 58.56,260.24 ; GND3.1 58.56,261.73 ; GND3.1 57.06,261.73 ; GND3.1 57.06,260.24 ; 32.73,273.21 EXT_SYS_P.4 ; EXT_SYS_P.4 32.73,275.07 ; EXT_SYS_P.4 34.58,275.07 ; EXT_SYS_P.4 34.58,273.21 ; 59.49,273.6 REFN.5 ; REFN.5 61.35,273.6 ; REFN.5 61.35,275.45 ; REFN.5 59.49,275.45 ; EXT_SYNC.5 6.95,241.71 ; EXT_SYNC.5 5.09,239.85 ; EXT_SYNC.5 5.09,241.71 ; EXT_SYNC.5 6.95,239.85 ; S4.GND1 184.89,284.75 ; S4.GND1 182.95,286.7 ; S4.GND1 182.95,284.75 ; S4.GND1 184.89,286.7 ; EXT_TRIG.2 7.1,261.53 ; EXT_TRIG.2 5.24,263.39 ; EXT_TRIG.2 7.1,263.39 ; EXT_TRIG.2 5.24,261.53 ; 32.73,278.29 EXT_SYS_P.3 ; EXT_SYS_P.3 32.73,280.15 ; EXT_SYS_P.3 34.58,278.29 ; EXT_SYS_P.3 34.58,280.15 ; EXT_TRIG.5 7.1,256.45 ; EXT_TRIG.5 5.24,256.45 ; EXT_TRIG.5 5.24,258.31 ; EXT_TRIG.5 7.1,258.31 ; 59.49,278.68 REFN.2 ; REFN.2 61.35,278.68 ; REFN.2 59.49,280.53 ; REFN.2 61.35,280.53 ; 48.84,275.2 EXT_HMCREF.2 ; EXT_HMCREF.2 48.84,273.34 ; EXT_HMCREF.2 50.7,273.34 ; EXT_HMCREF.2 50.7,275.2 ; P4.8 5.64,63.22 ; P4.8 3.82,60.7 ; P4.8 3.82,63.22 ; P4.8 5.64,60.7 ; 80.2,280.59 REFP.3 ; REFP.3 82.05,278.73 ; REFP.3 82.05,280.59 ; REFP.3 80.2,278.73 ; 53.45,215.76 REFCLK.2 ; REFCLK.2 55.31,213.91 ; REFCLK.2 53.45,213.91 ; REFCLK.2 55.31,215.76 ; EXT_HMCREF.4 45.62,280.28 ; EXT_HMCREF.4 43.76,280.28 ; EXT_HMCREF.4 43.76,278.42 ; EXT_HMCREF.4 45.62,278.42 ; EXT_SYS_P.5 29.5,275.07 ; EXT_SYS_P.5 29.5,273.21 ; EXT_SYS_P.5 27.65,275.07 ; EXT_SYS_P.5 27.65,273.21 ; J12.4 45.05,258.21 ; J12.4 43.19,256.35 ; J12.4 45.05,256.35 ; J12.4 43.19,258.21 ; J18.4 68.56,250.85 ; J18.4 66.71,250.85 ; J18.4 68.56,249 ; J18.4 66.71,249 ; 49.24,195.59 GND4.1 ; GND4.1 49.24,194.1 ; GND4.1 50.73,194.1 ; GND4.1 50.73,195.59 ; J17.5 48,250.75 ; J17.5 48,248.9 ; J17.5 46.14,250.75 ; J17.5 46.14,248.9 ; 48.37,220.84 REFCLK.4 ; REFCLK.4 50.23,218.99 ; REFCLK.4 48.37,218.99 ; REFCLK.4 50.23,220.84 ; P18.GND2 5.22,193.43 ; P18.GND2 3.82,194.84 ; P18.GND2 5.22,194.84 ; REFN.4 66.43,273.6 ; REFN.4 66.43,275.45 ; REFN.4 64.57,275.45 ; REFN.4 64.57,273.6 ; GND7.1 173.79,81.63 ; GND7.1 172.26,81.63 ; GND7.1 173.79,83.17 ; GND7.1 172.26,83.17 ; REFN.3 66.43,278.68 ; REFN.3 64.57,278.68 ; REFN.3 64.57,280.53 ; REFN.3 66.43,280.53 ; J17.4 48,245.67 ; J17.4 46.14,243.82 ; J17.4 46.14,245.67 ; J17.4 48,243.82 ; J18.5 68.56,245.77 ; J18.5 66.71,243.92 ; J18.5 68.56,243.92 ; J18.5 66.71,245.77 ; GND6.1 218.83,38.84 ; GND6.1 218.83,37.3 ; GND6.1 217.29,37.3 ; GND6.1 217.29,38.84 ; 174.23,165.39 GND8.1 ; GND8.1 175.73,163.9 ; GND8.1 174.23,163.9 ; GND8.1 175.73,165.39 ; 22.88,261.44 J13.2 ; J13.2 24.74,263.3 ; J13.2 22.88,263.3 ; J13.2 24.74,261.44 ; P19.GND3 2.53,202.89 ; P19.GND3 1.13,202.89 ; P19.GND3 1.13,201.48 ; 3.82,54.89 P4.9 5.64,54.89 ; J13.3 29.82,261.44 ; J13.3 27.96,261.44 ; J13.3 27.96,263.3 ; J13.3 29.82,263.3 ; J13.5 24.74,258.22 ; J13.5 22.88,256.36 ; J13.5 22.88,258.22 ; J13.5 24.74,256.36 ; 199.71,237.15 GND2.1 ; GND2.1 201.2,237.15 ; GND2.1 199.71,235.65 ; GND2.1 201.2,235.65 ; 61.63,243.92 J18.2 ; J18.2 61.63,245.77 ; J18.2 63.48,243.92 ; J18.2 63.48,245.77 ; 51.22,243.82 J17.3 ; J17.3 53.08,243.82 ; J17.3 51.22,245.67 ; J17.3 53.08,245.67
  BOTTOM w0.178: v1(89.53,278.03) 89.07,278.5 89.05,278.5 ; v1(90.53,275.03) 90.07,275.5 90.05,275.5 ; v2(226.39,136.52) 226.41,136.54 R511.1 ; C530.1 216.58,140.67 v2(216.56,140.69) ; 82.17,220.95 82.69,220.43 83.24,220.43 C135.4 ; v1(89.53,276.03) 89.07,276.5 89.05,276.5 ; Q8.1 113.89,154.06 114.15,153.8 v4(114.94,153.8) ; v2(232.41,135.94) 232.56,135.94 232.59,135.97 A4.1 v2(234.92,135.97) ; v1(89.53,277.03) 89.07,277.5 89.05,277.5 ; 216.05,143.35 215.68,143.35 v2(215.6,143.43) ; C526.1 203.59,137.63 v2(203.56,137.67) 203.52,137.7 v2(203.52,138.59) 203.52,139.51 v2(203.56,139.55) ; 93.53,258.78 v1(93.14,258.39) ; 91.05,275.5 91.07,275.5 91.6,274.96 v1(91.62,274.96) ; 89.05,274.5 89.07,274.5 v1(89.53,274.03) ; 90.05,276.5 90.07,276.5 v1(90.53,276.03) ; 203.89,150.1 203.89,150.15 204.05,150.31 v1(204.05,151.16) ; U7.B2 137.38,248.84 v1(137.64,249.1) ; 90.05,274.5 90.07,274.5 v1(90.53,274.03) ; 235.88,133.43 R419.1 235.88,133.84 v2(235.86,133.86) ; C540.2 v2(207.49,134.72) ; U11.J10 211.45,130.81 v2(211.91,131.27) 212.25,130.92 U11.H10 ; U8.A7 U8.B7 ; R510.1 226.25,131.61 v2(226.24,131.62) ; P1.Z27 113.33,19.1 v4(113.51,19.1) 114,19.1 P1.Z26 ; v1(145,248.88) 145.17,248.72 U7.M2 ; v9(121.65,163.04) 121.84,163.04 121.92,162.97 R296.1 ; 16.05,232.21 15.95,232.11 C748.2 ; C522.1 199.27,137.66 v2(199.24,137.69) 199.2,137.73 v2(199.2,138.59) 199.2,139.61 v2(199.21,139.62) ; 216.2,124.95 U11.C3 216.25,124.94 v2(216.59,124.61) ; 91.05,274.5 91.07,274.5 v1(91.54,274.03) ; v1(171.6,266.76) 171.76,266.6 U52.M2 ; v2(206.02,137.72) 206.04,137.7 C527.1 ; U52.B2 163.98,266.73 164.23,266.98 ; v1(213.45,120) 212.97,119.52 R651.2 ; U11.F10 213.84,130.55 v2(213.39,130.1) ; v1(90.53,277.03) 90.07,277.5 90.05,277.5 ; v1(112.08,249.29) 112.01,249.29 111.83,249.11 U34.M2 ; 92,258.39 92.18,258.57 v1(92.18,258.8) ; U34.B2 103.66,248.87 103.41,248.61 ; v4(236.06,257.82) 235.71,257.47 Q2.4 ; v2(235.86,132.59) 235.91,132.55 C538.1 ; v9(121.68,161.87) 121.87,161.87 121.98,161.77 C119.2 ; R381.2 v3(226.11,192.07) ; v1(90.53,278.03) 90.07,278.5 90.05,278.5 ; v1(108.08,249.25) 107.83,249 U34.G2 ; v1(89.53,273.03) 89.07,273.5 89.05,273.5 ; C622.1 223.45,145.79 v1(223.62,145.62) ; 216.25,125.75 U11.C4 216.26,125.75 v2(216.61,125.4) ; 89.05,275.5 89.07,275.5 v1(89.53,275.03) ; v3(226.11,190.8) R778.2 225.56,190.8 ; 226.35,134.7 v2(226.35,134.18) ; U11.T9 U11.T10 ; U11.P8 U11.N8 ; Q10.1 v1(211.97,112.34) ; v3(210.84,149.89) 211.12,150.17 ; R710.2 v3(208.46,166.67)
  BOTTOM w0.191: v3(142.95,268.02) 143.45,268.52 143.51,268.52 144.04,269.04 R140.1 C157.1 ; v4(59.51,225.65) 59.51,225.36 C283.2 ; U11.E9 214.67,129.75 v2(215.04,129.39) 214.65,129.01 U11.E8 ; C124.2 6.63,59.21 v4(6.6,59.18) ; v2(201.27,130) 201.52,129.75 U11.AA9 ; P1.F15 v4(127.69,27) ; v1(109.23,275.22) 108.41,276.05 108.16,276.05 ; U11.F8 213.83,128.95 213.77,128.89 213.7,128.89 v2(213.41,128.6) 213.06,128.95 U11.G8 ; P1.J17 124.46,31.5 ; P1.F33 104.95,26.42 v4(104.83,26.54) ; 205.29,124.59 205.29,124.71 v2(205.27,124.74) U11.U3 ; v1(228.09,67.59) 227.95,67.59 227.56,67.21 C200.1 ; R456.1 68.88,220.55 C602.1 68.98,220.4 69.76,220.4 C603.4 ; P1.L27 P1.M28 ; C221.1 16.17,232.21 16.05,232.21 ; v1(161.59,247.04) 161.2,247.43 C628.2 ; R447.1 217.8,78 v4(217.93,78) ; v4(215.52,78) 215.08,78.44 R445.1 ; R126.1 203.92,149.5 C195.1 203.89,150.1 ; v3(219.02,43.92) 219.13,43.81 R444.1 ; U11.G5 213.05,126.54 v2(212.7,126.19) ; 209.09,79.39 R450.1 ; v2(211.89,130.12) 212.25,129.76 U11.H9 ; U11.G9 213.05,129.77 v2(213.39,130.1) ; R127.1 204.65,159.69 C196.1 204.68,161.27 v1(204.6,161.35) ; v1(218.04,65.62) 218.37,65.3 C521.1 ; 212.54,78.44 212.54,78.3 v4(213.08,77.76) ; C572.1 217.42,65.18 v3(217.81,64.8) ; v2(208.74,125.4) 208.71,125.4 U11.N3 ; v4(101.09,17.91) 100.71,17.53 P1.Y37 ; P1.E8 P1.F9 P1.G8 P1.H9 ; P1.L2 144.78,31.5 143.51,31.5 ; P1.Z19 P1.A20 ; v1(213.08,160.88) 212.62,160.88 R124.2 ; v1(202.92,115.54) 202.92,115.18 Q11.1 ; C234.1 165.99,37.21 v1(165.96,37.19) ; v4(142.98,26.64) 143.13,26.64 143.23,26.54 143.38,26.54 P1.F3 ; P1.F39 98.4,25.81 v4(98.4,25.55) ; P1.A12 P1.Z11 P1.Z10 P1.Y9 ; v4(132.66,30.94) 132.64,30.94 132.08,31.5 ; U11.E6 214.67,127.35 v2(215.01,127.69) ; P1.J8 P1.L10 ; v3(225.73,55.69) 226.19,56.16 C515.1 ; v3(225.73,52.77) 226.4,52.1 C516.1 ; v4(118.67,27.69) P1.G23 P1.H24 ; 127.77,164.66 127.79,164.68 ; 217.42,60.23 217.42,60.1 v3(217.81,59.72) ; v1(210.13,113.51) 210.36,113.29 Q10.4 ; R449.1 v3(216.15,41.55) ; v3(146.35,267.92) 146.51,268.07 ; v1(202.13,113.46) 202,113.59 Q11.4 ; v2(215.52,138.3) 215.63,138.19 R577.1 ; P1.M1 145.39,33.38 v4(145.39,33.1) ; P1.E20 P1.D19 ; C454.2 127.97,122.72 C456.2 ; C573.1 217.18,68.22 v3(216.66,68.73) ; P1.Z18 P1.Y17 ; C199.1 226.31,63.14 v3(225.68,63.78) ; P1.L30 P1.M29 ; R53.2 v4(86.23,225.67) ; 211,124.61 210.66,124.95 U11.K3 U11.K4 210.67,125.75 ; C643.1 138.69,267.47 C642.1 ; P1.G32 v4(107.19,27.69) ; C714.1 v2(207.57,143.74) ; v2(205.55,125.35) 205.46,125.35 U11.U4 ; C226.1 v4(23.33,225.11) ; C574.2 v3(218.62,58.69) ; P1.H21 P1.G20
  BOTTOM w0.197: 92,258.39 91.85,258.25 U74.C2
  BOTTOM w0.203: v2(203.81,128.65) 203.51,128.95 U11.W8 ; v2(208.74,125.4) 209.05,125.72 U11.M4 ; v1(81.79,217.78) 81.79,217.31 81.74,217.26 U4.8 U4.PAD v3(81.74,214.9) ; v2(207.06,126.95) 207.45,127.34 U11.P6 ; R50.1 v1(116.36,246.2) ; R776.1 v1(179.17,265) ; v1(224.33,188.28) 224.49,188.12 224.71,188.12 224.76,188.17 C172.1 ; v1(220.32,188.3) 220.3,188.3 ; 61.01,232.11 61,232.09 U2.42 ; 61.01,232.11 61.01,231.62 ; 61.01,232.11 61.01,232.34 60.76,232.59 U2.41 ; v1(219.57,100.16) 220.13,99.59 C191.1 220.24,99.57 ; R45.1 v1(98.07,241.81) ; v9(120.73,153.46) v9(120.73,153.96) 121.7,153.96 ; v4(236.12,234.67) 236.07,234.62 236.07,234.34 Q1.1 ; U11.U9 v2(204.74,129.44) ; Q6.1 v1(234.89,261.77) ; v9(127.18,153.46) 126.7,153.46 126.2,153.96 ; R766.1 v1(179.17,257.38) ; v9(123.2,159.44) 123.2,158.46 v9(123.37,158.29) 122.64,157.56 ; Q4.4 235.92,252.12 236.09,252.29 v4(236.09,252.58) ; v1(110.69,267.77) 111.25,268.33 C163.1 111.28,268.44 R54.1 ; 121.7,153.96 v9(121.92,154.18) U30.PAD3 ; 121.7,153.96 v9(121.7,152.98) ; C110.2 24.57,220.53 v4(24.77,220.73) ; 219.96,188.19 219.91,188.19 C168.1 ; v4(19.94,233.63) R11.2 19.96,232.66 C128.2 ; R88.1 v1(152.58,242.29) ; v2(202.31,128.65) 202.61,128.95 U11.Y8 ; v1(203.07,125.35) 203.45,125.73 U11.W4 ; 205.05,125.73 U11.U4 ; U11.W9 203.5,129.75 v2(203.84,129.41) ; U11.U10 205.02,130.55 v1(204.65,130.18) ; v9(122.66,154.14) 122.66,153.02 v9(122.7,152.98) ; v9(124.2,152.98) 124.2,153.84 U30.PAD2 126.2,153.96 ; U11.N9 U11.P9 U11.R9 ; U11.N9 U11.N10 ; U11.N9 U11.N8 ; 61.01,231.62 60.98,231.59 U2.43 ; 61.01,231.62 61.01,231.11 ; v4(35.84,234.27) C100.2 35.11,234.24 C104.2 ; U2.45 60.97,230.59 61.01,230.63 ; R43.1 v1(116.36,243.79) ; v9(123.49,154.15) 123.7,153.95 v9(123.7,152.98) ; 61.01,229.57 60.98,229.59 U2.47 ; 61.01,229.57 61.01,230.1 ; 61.01,229.57 61.01,229.18 60.92,229.09 U2.48 ; v9(125.2,152.98) 125.2,153.99 v9(125.33,154.12) ; R747.1 158.22,254.97 ; v9(122.64,157.52) v9(123.43,157.52) ; v9(122.64,157.52) v9(121.84,158.32) ; v9(122.64,157.52) v9(121.83,157.52) ; v9(122.64,157.52) v9(123.47,156.69) ; v9(122.64,157.52) 122.64,157.56 ; v9(122.64,157.52) 122.64,157.46 ; v9(126.7,159.44) 126.62,159.35 126.62,159.16 126.6,159.14 126.6,159.1 126.2,158.7 126.2,158.46 ; v4(24.89,223.16) 24.67,222.94 C107.2 ; Q2.1 v3(234.89,255.24) ; R768.1 v1(179.17,260.17) ; C208.2 v4(35.71,235.61) ; 209.52,124.61 209.85,124.94 U11.L3 ; R774.1 v1(179.17,252.55) ; v4(6.3,218.89) R9.2 R8.2 ; v2(203.89,130.18) 204.25,130.54 U11.V10 ; v1(172.77,37.34) 172.75,37.36 C235.1 ; 126.2,153.96 v9(126.2,152.98) ; v4(24.82,242.11) Y1.2 v4(22.52,240.71) ; C220.1 14.58,232.08 v1(14.07,232.59) ; U11.AA6 U11.AA5 ; 122.64,157.46 v9(121.89,156.72) ; 122.64,157.46 v9(122.64,156.68) ; v4(217.68,55.9) 217.78,55.9 C517.2 ; v9(122.64,158.31) 122.64,157.56 ; U11.T10 v1(205.85,131.1) ; C126.2 v4(26.97,219.86) ; 126.2,158.46 v9(127.18,158.46) v9(127.18,158.96) ; 126.2,158.46 U30.PAD1 ; v1(157.63,256.43) 157.63,256.52 157.57,256.58 R753.1 ; U2.44 60.99,231.09 61.01,231.11 ; R474.2 v4(81.69,226.11) ; R92.1 v1(152.58,237.08) ; U11.P5 v2(207.17,126.26) ; R504.2 109.56,268.46 v1(109.25,268.78) ; v1(169.09,44.32) 169.05,44.36 R536.1 ; Q6.4 235.71,263.98 235.96,264.24 236.07,264.24 v1(236.07,264.59) ; R56.2 v4(80.76,241.39) ; Q3.1 v3(234.92,238.05) ; U11.Y5 202.62,126.55 v1(202.29,126.21) ; v1(112.22,240.11) 111.83,239.72 R621.1 ; 61.01,231.11 61.01,230.63 ; Q3.4 235.75,240.29 v1(236.11,240.65) ; 204.26,125.72 204.25,125.72 U11.V4 ; 207.92,126.26 208.21,126.55 U11.N5 ; R57.2 v4(80.12,239.38) ; U11.T9 U11.R9 ; U11.R9 U11.R10 ; R2.2 v4(28.12,229.31) ; U2.46 61.01,230.09 61.01,230.1 ; Q5.4 v3(234.87,243.95) ; 211.12,150.17 R125.2 ; C246.2 201.34,193.82 200.93,193.41 U37.6 198.21,193.41 U37.PAD ; U10.9 205.92,161.88 205.92,161.87 ; U11.N3 208.25,124.94 ; C173.1 225.55,188.7 v1(225.13,188.28) ; P1.G5 P1.H6 ; 61.01,230.1 61.01,230.63 ; v2(203.89,126.95) 203.49,127.35 U11.W6 ; C174.1 219.07,188.12 218.86,188.12 v1(218.73,188.25) ; R86.1 v1(152.58,239.5) ; R98.1 v1(152.58,234.67) ; v3(68.4,214.76) U38.8 68.4,217.12 68.42,217.14 v1(68.42,217.61) ; v9(126.07,157.52) 126.13,157.46 v9(127.18,157.46) ; R34.1 v1(116.36,238.58) ; 79.2,229.8 v4(79.2,227.76) ; R100.1 v1(152.58,247.12) ; R36.1 v1(116.36,241.38) ; R39.1 v1(98.07,239.52) ; v1(209.5,125.4) 209.85,125.75 U11.L4 ; R772.1 v1(179.17,262.59) ; 181.07,116.76 v4(181.39,116.68) ; R47.1 v1(116.36,233.76) ; v3(234.92,249.81) Q4.1 ; v9(126.16,154.13) 126.49,154.46 v9(127.18,154.46) ; C228.2 v4(18.39,216.79) ; R10.2 v4(27.9,219.49) ; R96.1 v1(131.62,241.66) ; U11.E3 215.04,124.57 ; R32.1 v1(98.07,237.24) ; R90.1 v1(131.62,239.37) ; Q1.4 v4(234.99,231.71) ; R41.1 v1(116.36,236.17) ; R84.1 v1(131.62,237.08) ; v4(236.11,246.62) 235.76,246.28 Q5.1 ; v3(199.81,261.51) U39.2 199.81,258.78 C607.1 C640.1 R485.1 ; R94.1 v1(152.58,244.7) ; R770.1 v1(179.17,254.97) ; R755.1 v1(158.22,259.54)
  BOTTOM w0.254: v4(131.52,29.51) P1.H12 P1.G11 P1.F12 ; C229.2 v4(22.83,218.47) ; C305.2 v3(61.39,224.23) ; R729.2 v3(113.89,174.35) ; C294.2 v4(50.11,228.12) ; P1.E5 P1.E4 142.24,25.2 v4(141.68,25.76) ; P1.J14 129.54,30.38 v4(128.98,30.94) ; v4(145.39,18.16) 146.02,17.53 P1.Y1 ; P1.G32 P1.H33 ; P1.C8 P1.C9 P1.D10 P1.E11 P1.F12 ; P1.C8 137.16,22.71 v4(136.53,23.34) ; P1.C8 137.16,22.56 v4(137.82,21.89) 138.38,21.34 P1.B7 ; v4(132.74,33.27) 133.25,32.77 P1.L11 P1.L10 ; P1.E38 99.06,24.99 v4(99.64,24.41) 100.18,23.88 P1.D37 ; R59.1 82.17,220.95 82.16,220.95 C134.1 ; P1.J23 116.84,31.5 P1.L23 ; P1.C36 P1.B35 P1.B34 P1.A33 P1.A32 106.68,20.04 v4(107.19,19.53) 107.92,18.8 P1.Z31 P1.Z30 109.22,18.72 v9(109.8,18.14) 110.41,17.53 P1.Y29 P1.Y28 ; v4(50.02,234.99) C286.2 50.02,233.53 C289.2 ; C468.2 131.1,128.04 v4(131.1,128.13) ; P1.Y36 101.47,17.53 v4(101.09,17.91) ; v4(137.69,25.7) 137.16,25.17 P1.E8 137.16,25.07 v4(137.74,24.49) 138.35,23.88 P1.D7 ; P1.A12 132.08,20.09 v4(131.42,20.75) 130.81,20.14 P1.A13 ; P1.A5 140.97,20.12 v4(140.44,20.65) ; P1.B3 143.51,21.36 v4(142.88,22) ; C290.2 v4(48.36,225.43) ; C290.2 49.05,225.48 C287.2 v4(48.36,226.47) ; C290.2 C293.2 v4(48.26,224.33) ; P1.A40 96.57,20.07 v4(97.13,19.51) ; P1.J5 P1.J4 143.51,31.5 P1.L3 P1.M4 142.24,34.09 v4(141.76,34.57) ; P1.Y24 116.76,17.53 v4(116.18,18.11) 115.6,17.53 P1.Y25 ; P1.B39 P1.B38 ; P1.B38 P1.A37 P1.A36 P1.Z35 P1.Z34 ; P1.B38 v4(98.45,21.95) ; P1.F24 P1.E23 P1.D22 P1.C21 P1.C20 121.92,22.71 v4(121.31,23.32) ; P1.G1 P1.H2 P1.H3 143.43,28.96 v4(142.8,29.59) ; P1.B18 P1.B19 123.06,21.34 v4(122.43,21.97) ; v4(10.62,217.02) 10.62,217.31 C227.2 ; C394.2 132.84,126.53 v4(132.7,126.53) ; P1.Z18 P1.Z19 ; P1.Z38 P1.Z39 97.79,19.02 v4(98.27,19.51) ; P1.M25 P1.M24 P1.L23 ; P1.J40 96.49,30.23 ; 96.49,30.23 95.35,30.23 v4(95.1,30.48) 93.26,32.32 C691.2 ; 96.49,30.23 95.83,29.57 95.83,28.37 P1.G40 95.83,27 v4(95.83,25.55) 96.24,25.15 P1.E40 ; P1.C29 P1.C28 P1.D28 P1.E29 110.49,25.22 v4(109.93,25.78) 109.3,26.42 P1.F30 ; P1.L39 P1.M40 95.94,34.04 v3(95.73,34.24) ; P1.L39 P1.L38 ; P1.L39 97.79,31.5 97.82,31.5 99.06,30.25 P1.J38 ; P1.M21 P1.M20 121.92,33.99 v4(122.53,33.38) ; P1.G38 v4(98.41,28.33) P1.H39 ; P1.D6 139.7,23.9 v9(139.12,24.49) ; v4(135.29,20.64) 135.86,20.07 P1.A9 ; C219.1 9.86,228.39 v4(9.58,228.68) ; v4(142.93,19.28) 143.41,18.8 P1.Z3 ; P1.J1 146.05,30.25 v4(145.54,30.76) ; C619.2 v4(169.92,222.87) ; v4(107.24,16.94) 106.68,17.5 P1.Y32 P1.Y33 ; C296.2 v4(56.4,224.72) ; P1.G35 102.87,27.76 v4(102.16,28.47) 101.68,28.96 P1.H36 ; P1.F27 v4(113.77,25.68) P1.E26 P1.D25 P1.C25 P1.C24 116.87,22.61 v4(117.47,22) 118.11,21.36 P1.B23 v2(118.75,21.34) P1.B22 ; P1.C17 P1.C16 ; P1.C16 127.03,22.61 v4(127.58,22.05) 128.27,21.36 P1.B15 P1.B14 ; P1.C16 P1.D16 ; v1(106.22,23.11) 106.68,22.66 P1.C32 P1.C33 v4(104.85,23.16) ; v4(132.66,30.94) 133.35,30.25 P1.J11 ; P1.G17 v4(125.07,28.35) P1.H18 ; v3(95.77,278.39) 94.4,278.39 94.32,278.47 U72.A6 94.05,278.5 ; P1.F36 v4(102.21,25.81) P1.E35 ; v4(119.99,33.45) 119.38,32.84 P1.L22 ; P1.C40 96.52,22.58 v4(97.03,22.07) ; P1.M5 140.89,34.04 v4(140.26,34.67) ; C306.2 v4(50.01,232.56) ; v4(140.26,30.84) 139.7,31.39 P1.L6 P1.L7 P1.M8 P1.M9 ; P1.E17 125.7,25.15 v4(125.04,25.81) 124.46,26.39 P1.F18 ; P1.A4 142.24,20.19 v4(141.76,20.68) ; v4(111.9,132.93) 111.82,132.93 C420.2 ; C452.2 v3(166.51,205.6) ; P1.L22 P1.J20 ; P1.L22 P1.L23 ; P1.C1 146.05,22.63 v4(145.49,23.19) 144.81,23.88 P1.D2 ; v4(131.6,26.97) 132.08,26.49 P1.F12 ; P1.B11 v4(133.99,21.97) P1.B10 ; P1.Y5 140.97,17.65 v4(141.55,18.24) 142.24,17.55 P1.Y4 ; v4(141.71,28.27) 142.24,27.74 P1.G4 P1.G5 ; 60.78,234.24 R312.1 v4(60.96,234.24) ; P1.M1 146.05,34.06 v4(145.44,34.67) ; P1.Y20 121.92,17.63 v4(121.28,18.26) 120.65,17.63 P1.Y21 P1.Z22 P1.Z23 ; P1.L26 P1.L27 113.03,31.47 v4(113.65,30.85) 114.27,30.23 P1.J26 ; R709.2 v3(207.59,157.35) ; C482.2 116.84,134.53 v4(116.7,134.53) ; P1.M33 P1.M32 P1.L31 P1.L30 109.22,31.5 P1.J29 ; P1.Y8 137.16,17.6 v4(136.6,18.16) 135.97,17.53 P1.Y9 ; P1.A25 v4(116.18,20.68) 116.79,20.07 P1.A24 ; P1.L2 145.06,32.77 v4(145.39,33.1) ; R518.1 219.82,100.79 v1(219.59,101.02) ; P1.C4 142.16,22.61 v4(141.63,23.14) 141.1,22.61 P1.C5 ; C279.2 v4(50.01,229.59) ; C110.2 23.97,220.78 C215.1 ; R731.2 134.04,174.6 ; v2(201.24,126.57) 201.26,126.55 U11.AA5 ; P1.Z1 145.95,18.8 v4(145.41,19.33) ; v4(121.21,20.78) P1.A20 v4(121.28,20.07) P1.A21 ; P1.A17 125.83,20.07 v4(126.44,20.68) 127,20.12 P1.A16 P1.Z15 P1.Z14 ; v4(112.34,29.59) 112.98,28.96 P1.H27 P1.G26 ; v4(139.19,21.92) 139.7,21.41 P1.B6 ; P1.J32 P1.L34 P1.L35 102.82,32.77 v4(102.24,33.35) 101.6,33.99 P1.M36 P1.M37 ; U11.Y10 v2(202.65,131.24) ; P1.Z14 129.54,18.87 v4(128.98,19.43) ; P1.Z14 P1.Y13 130.81,17.6 v4(131.42,18.21) 132.08,17.55 P1.Y12 ; R308.1 v3(61.44,225.3) ; v4(58.47,238.58) 58.19,238.3 C316.1 ; v4(145.47,25.65) 145.97,25.15 P1.E1 ; 124.46,31.5 123.93,32.03 v4(123.93,32.16) 124.46,32.69 P1.L18 P1.L19 ; P1.Y17 125.76,17.53 v4(126.44,18.21) 127,17.65 P1.Y16 ; v4(130.12,34.7) 130.78,34.04 P1.M13 ; C101.2 C99.2 C98.2 v4(6.41,221.9) ; P1.Y40 96.11,17.53 v4(95.71,17.93) ; P1.G14 129.54,27.76 v4(128.91,28.4) 128.35,28.96 P1.H15 ; C300.2 v4(52.93,224.33) ; v4(132.7,132.13) 132.84,132.13 C382.2 ; U11.P9 U11.P8 ; v4(136.68,20.62) 137.16,20.14 P1.A8 ; P1.B26 P1.B27 113.03,21.41 v9(112.5,21.95) ; v4(132.7,129.73) 132.84,129.73 C386.2 ; 94.05,273.5 94.05,273.49 94.51,273.02 ; C302.2 C291.2 54.35,234.86 v4(54.3,234.81) C285.2 ; U11.R10 U11.T10 ; 125.81,34.04 v4(126.42,34.65) 127,34.06 P1.M16 125.81,34.04 ; 125.81,34.04 P1.M17 ; C489.2 116.84,135.33 v4(116.7,135.33) ; P1.F33 P1.E32 ; v4(139.08,27.11) 139.7,26.49 P1.F6 ; C635.2 v3(166.46,217.69) ; C259.1 v4(120.51,149.99) ; v4(127.63,32.13) 128.27,31.5 P1.L15 P1.L14 ; P1.B2 v4(144.25,21.87) ; P1.J35 v4(102.26,30.84) 101.6,31.5 ; U11.AA8 v2(201.27,128.95) ; 132.08,31.5 132.08,31.52 v4(131.57,32.03) ; P1.B31 107.95,21.39 v4(108.56,22) P1.B30 P1.A29 ; C304.2 v4(50.04,231.14) ; P1.M12 v4(131.52,34.59) ; P1.A1 v4(145.52,20.6) ; v4(23.67,226.75) 23.52,226.59 C223.1 ; C620.2 v4(170.65,226.84) ; 170.07,230.33 v4(170.07,231.08) ; P1.A29 v4(111.07,20.65) ; P1.A29 P1.A28 ; P1.F9 135.89,26.44 v4(135.31,27.03) ; R309.1 R310.1 v4(62.26,227) ; P1.F15 P1.E14 ; P1.C12 P1.C13 P1.D13 130.73,23.88 v4(130.07,24.54) ; v4(108.66,29.57) 109.22,29.01 P1.H30 ; U2.48 58.26,229.09 57.69,228.52 57.22,228.52 56.9,228.85 56.9,229.13 U2.PAD 57.43,231.09 U2.36 ; P1.F2 P1.F3 ; P1.G20 P1.F21 120.73,26.42 v4(121.36,25.78) 121.92,25.22 P1.E20 ; P1.D3 142.91,24.47 v4(142.88,24.47) ; v4(21.97,228.57) 21.48,228.09 U1B.35 ; P1.D39 97.79,23.83 v4(98.37,23.24) 99.01,22.61 P1.C38 ; v2(201.85,137.77) 201.74,137.66 C523.1 ; P1.Z27 v9(112.42,19.41) ; v4(132.7,132.93) 132.84,132.93 C378.2 ; C298.2 v4(54.43,224.26) ; 170.24,234.49 v4(170.24,235.45) ; v4(5.64,225.12) 5.82,225.3 C218.1 ; P1.G29 v4(109.85,28.32) ; P1.Z6 139.7,18.82 v4(139.14,19.38) 138.56,18.8 P1.Z7 ; v4(132.7,125.73) 132.84,125.73 C398.2 ; C632.2 v3(164.69,203.61) ; P1.M28 P1.M29 ; C297.2 v4(52.04,223.9) ; P1.Z2 v4(144.17,19.41)
  BOTTOM w0.381: C854.2 v3(87.78,264.77) ; v3(87.27,255.07) 87.1,255.24 C852.2 ; v3(95.4,269.54) 95.38,269.57 94.66,269.57 R811.2 ; C855.2 89.88,260.06 v3(89.48,259.66) 90.07,259.08 90.07,259.04 ; C845.2 v3(90.16,281.37) ; C857.2 86.14,264.98 R809.2 v3(85.42,264.97)
  BOTTOM w0.508: v3(139.6,116.94) 139.33,117.21 C429.2 ; R442.2 v3(210.13,80.15) ; 197.03,216.31 197.05,216.33 ; v1(108.25,240.06) 107.89,239.69 R616.1 ; R615.1 v1(100.81,237.13) ; R450.1 v3(208.79,80.49) ; v1(232.64,119.57) v3(235.14,119.57) ; R491.2 v1(221.08,110.46) ; R490.2 v1(221.28,114.96)
  vias: v1(1.02,288.16) v1(1.02,286.89) v1(1.02,285.62) v1(1.02,284.35) v1(1.03,283.08) v1(1.03,281.81) v1(1.03,280.54) v1(1.04,279.27) v1(1.04,278) v1(1.04,276.73) v1(1.05,275.46) v1(1.05,274.19) v1(1.05,272.92) v1(1.06,271.65) v1(1.06,270.38) v1(1.06,269.11) v1(1.07,267.84) v1(1.07,266.57) v1(1.07,265.3) v1(1.08,264.03) v1(1.08,262.76) v1(1.08,261.49) v1(1.02,260.22) v1(1.02,258.95) v1(1.02,257.68) v1(1.03,256.41) v1(1.03,255.14) v1(1.03,253.87) v1(1.04,252.6) v1(1.04,251.33) v1(1.04,250.06) v1(1.05,248.79) v1(1.05,247.52) v1(1.05,246.25) v1(1.06,244.98) v1(1.06,243.71) v1(1.06,242.44) v1(1.07,241.17) v1(1.07,239.9) v1(1.07,238.63) v1(1.08,237.36) v1(1.08,236.09) v1(1.08,234.82) v1(1.02,233.55) v1(1.02,232.28) v1(1.02,231.01) v1(1.03,229.74) v1(1.03,228.47) v1(1.03,227.2) v1(1.04,225.93) v1(1.04,224.66) v1(1.04,223.39) v1(1.05,222.12) v1(1.05,220.85) v1(1.05,219.58) v1(1.06,218.31) v1(1.06,217.04) v1(1.06,215.77) v1(1.07,214.5) v1(1.07,213.23) v1(1.07,211.96) v1(1.08,210.69) v1(1.08,209.42) v1(1.08,208.15) v1(1.02,206.88) v1(1.02,205.61) v1(1.06,189.1) v1(1.07,187.83) v1(1.07,186.56) v1(1.07,185.29) v1(1.08,184.02) v1(1.08,182.75) v1(1.08,181.48) v1(1.02,180.21) v1(1.02,178.94) v1(1.02,177.67) v1(1.03,176.4) v1(1.03,175.13) v1(1.03,173.86) v1(1.04,172.59) v1(1.04,171.32) v1(1.04,170.05) v1(1.05,168.78) v1(1.05,167.51) v1(1.05,166.24) v1(1.06,164.97) v1(1.06,163.7) v1(1.06,162.43) v1(1.07,161.16) v1(1.07,159.89) v1(1.07,158.62) v1(1.08,157.35) v1(1.08,156.08) v1(1.08,154.81) v1(1.02,153.54) v1(1.02,152.27) v1(1.02,151) v1(1.03,149.73) v1(1.03,148.46) v1(1.03,147.19) v1(1.04,145.92) v1(1.04,144.65) v1(1.04,143.38) v1(1.05,142.11) v1(1.05,140.84) v1(1.05,139.57) v1(1.06,138.3) v1(1.06,137.03) v1(1.06,135.76) v1(1.07,134.49) v1(1.07,133.22) v1(1.07,131.95) v1(1.08,130.68) v1(1.08,129.41) v1(1.08,128.14) v1(1.02,126.87) v1(1.02,125.6) v1(1.02,124.33) v1(1.03,123.06) v1(1.03,121.79) v1(1.03,120.52) v1(1.04,119.25) v1(1.04,117.98) v1(1.04,116.71) v1(1.05,115.44) v1(1.05,114.17) v1(1.05,112.9) v1(1.06,111.63) v1(1.06,110.36) v1(1.06,109.09) v1(1.07,107.82) v1(1.07,106.55) v1(1.07,105.28) v1(1.08,104.01) v1(1.08,101.47) v1(1.02,100.2) v1(1.02,98.93) v1(1.02,97.66) v1(1.03,96.39) v1(1.03,95.12) v1(1.03,93.85) v1(1.04,92.58) v1(1.04,91.31) v1(1.04,90.04) v1(1.05,88.77) v1(1.05,87.5) v1(1.05,86.23) v1(1.06,84.96) v1(1.06,83.69) v1(1.06,82.42) v1(1.07,81.15) v1(1.07,79.88) v1(1.07,78.61) v1(1.08,77.34) v1(1.08,76.07) v1(1.08,74.8) v1(1.02,73.53) v1(1.02,72.26) v1(1.02,70.99) v1(1.03,69.72) v1(1.03,68.45) v1(1.03,67.18) v1(1.04,65.91) v1(1.04,64.64) v1(1.04,63.37) v1(1.07,54.48) v1(1.07,53.21) v1(1.07,51.94) v1(1.08,50.67) v1(1.08,49.4) v1(1.08,48.13) v1(1.07,46.86) v1(1.07,45.59) v1(1.07,44.32) v1(1.08,43.05) v1(1.08,41.78) v1(1.08,40.51) v1(1.07,39.24) v1(1.07,37.97) v1(1.07,36.7) v1(1.08,35.43) v1(1.65,34.8) v1(1.7,110.57) v1(1.91,195.96) v1(2.24,105.16) v1(2.26,95.45) v1(2.21,81) v1(2.29,288.16) v1(2.29,181.03) v1(2.39,165.99) v1(2.39,100.81) v1(2.39,89.05) v1(2.39,74.22) v1(2.51,184.96) v1(2.59,177.27) v1(2.62,174.88) v1(2.67,43.89) v1(2.72,168.96) v1(2.69,136.25) v1(2.87,173.02) v1(2.79,69.19) v1(2.84,36.65) v1(2.92,145.26) v1(2.95,103.61) v1(2.92,102.21) v1(2.92,34.8) v1(3.25,50.72) v1(3.3,65.76) v1(3.48,157.58) v1(3.56,288.16) v1(3.89,166.42) v1(4.04,272.52) v1(4.06,237.67) v1(4.06,171.45) v1(4.01,154.94) v1(4.22,277.88) v1(4.19,34.8) v1(4.39,243.46) v1(4.5,115.9) v1(4.6,133.2) v1(4.6,110.24) v1(4.7,125.65) v1(4.83,288.16) v1(4.8,168.5) v1(4.8,148.46) v1(4.8,138.18) v1(4.83,103.61) v1(4.83,102.21) v1(4.9,97.89) v1(4.9,90.86) v1(4.9,47.24) v1(5.11,253.72) v1(5.36,67.51) v1(5.46,34.8) v1(5.94,170.05) v1(6.1,288.16) v1(6.1,233.78) v1(6.15,231.34) v1(6.48,157.63) v1(6.53,114.45) v1(6.68,167.06) v1(6.68,121.21) v1(6.78,214.83) v1(6.78,168.05) v1(6.73,141.07) v1(6.78,105.16) v1(6.73,34.8) v1(6.81,205.28) v1(6.83,103.56) v1(6.86,102.21) v1(6.93,238.51) v1(6.96,129.74) v1(6.98,94.95) v1(7.04,88.85) v1(7.37,288.16) v1(8,34.8) v1(8.15,64.26) v1(8.64,288.16) v1(8.71,216.97) v1(8.81,103.56) v1(8.94,144.25) v1(9.14,114.22) v1(9.19,133.1) v1(9.25,117.91) v1(9.25,110.62) v1(9.27,34.8) v1(9.37,212.88) v1(9.4,127.03) v1(9.47,106.58) v1(9.52,148.62) v1(9.68,120.98) v1(9.91,288.16) v1(10.01,103.53) v1(10.54,34.8) v1(11.18,288.16) v1(11.63,103.56) v1(11.63,102.26) v1(11.81,34.8) v1(11.89,41.5) v1(12.01,97) v1(12.45,288.16) v1(12.55,243.54) v1(13.03,103.56) v1(13.03,102.26) v1(13.08,34.8) v1(13.72,288.16) v1(13.97,251.94) v1(14.15,269.67) v1(14.1,38.79) v1(14.35,34.8) v1(14.66,212.9) v1(14.61,103.53) v1(14.61,102.26) v1(14.68,93.37) v1(14.91,209.78) v1(14.91,36.78) v1(14.99,288.16) v1(15.16,206.17) v1(15.16,155.52) v1(15.11,138.96) v1(15.11,108) v1(15.19,284.84) v1(15.24,260.58) v1(15.32,170.51) v1(15.34,147.5) v1(15.34,143.05) v1(15.44,149.76) v1(15.49,133.53) v1(15.49,50.52) v1(15.62,34.8) v1(15.75,163.86) v1(15.75,102.26) v1(15.77,46.1) v1(15.8,128.75) v1(15.8,113.72) v1(15.95,173.08) v1(15.9,120.09) v1(16,160.25) v1(16.08,125.91) v1(16,118.16) v1(16.26,288.16) v1(16.23,110.13) v1(16.23,104.32) v1(16.66,247.14) v1(16.59,210.82) v1(16.83,215.81) v1(16.89,34.8) v1(17.02,214.43) v1(17.32,104.34) v1(17.53,288.16) v1(17.58,41.71) v1(18.16,34.8) v1(18.47,204.8) v1(18.49,104.22) v1(18.77,102.29) v1(18.8,288.16) v1(19.43,34.8) v1(19.79,103.58) v1(20.07,288.16) v1(20.17,102.26) v1(20.52,211.02) v1(20.7,34.8) v1(20.83,104.34) v1(21.34,288.16) v1(21.51,205.61) v1(21.95,104.29) v1(21.97,34.8) v1(22.02,281.41) v1(22.1,213.16) v1(22.35,204.37) v1(22.61,288.16) v1(23.11,244.68) v1(23.24,34.8) v1(23.34,253.19) v1(23.37,86.59) v1(23.44,71.65) v1(23.44,55.83) v1(23.39,45.36) v1(23.57,50.16) v1(23.88,288.16) v1(23.95,233.22) v1(24.08,103.56) v1(24.28,230.35) v1(24.49,213.51) v1(24.51,34.8) v1(25.07,71.17) v1(25.15,288.16) v1(25.17,91.49) v1(25.12,87.38) v1(25.25,103.53) v1(25.27,102.31) v1(25.5,61.16) v1(25.68,117.63) v1(25.68,54.23) v1(25.68,48.13) v1(25.76,140.69) v1(25.78,34.8) v1(25.91,147.9) v1(25.91,130.48) v1(26.09,233.02) v1(26.04,209.8) v1(26.42,288.16) v1(26.42,213.39) v1(26.59,42.29) v1(26.87,243.33) v1(26.97,103.51) v1(26.97,96.22) v1(26.92,90.4) v1(27.03,102.31) v1(27.05,34.8) v1(27.51,282.91) v1(27.69,288.16) v1(27.81,213.41) v1(27.94,252.63) v1(27.97,221.54) v1(28.02,45.44) v1(28.32,34.8) v1(28.47,103.51) v1(28.47,102.31) v1(28.55,62.99) v1(28.6,51.56) v1(28.85,58.27) v1(28.96,288.16) v1(28.98,65.81) v1(29.59,34.8) v1(29.84,103.51) v1(29.95,102.31) v1(30.23,288.16) v1(30.71,179.81) v1(30.86,34.8) v1(30.94,151.18) v1(30.96,104.17) v1(31.12,162.61) v1(31.17,156.9) v1(31.22,173.58) v1(31.37,135.2) v1(31.42,166.42) v1(31.5,288.16) v1(31.57,140.64) v1(31.62,130.78) v1(31.9,146.41) v1(32.13,34.8) v1(32.77,288.16) v1(32.77,253.8) v1(32.92,67.94) v1(33.1,104.11) v1(33.43,177.57) v1(33.4,34.8) v1(33.63,102.26) v1(33.93,263.27) v1(34.04,288.16) v1(34.01,213.21) v1(34.01,61.95) v1(34.39,182.88) v1(34.52,103.53) v1(34.67,34.8) v1(35.03,102.21) v1(35.1,50.09) v1(35.31,288.16) v1(35.61,104.22) v1(35.76,269.93) v1(35.92,253.85) v1(35.92,176.58) v1(35.94,34.8) v1(36.09,44.91) v1(36.27,70.1) v1(36.27,64.85) v1(36.58,288.16) v1(37.21,34.8) v1(37.59,276.38) v1(37.74,104.27) v1(37.74,102.18) v1(37.85,288.16) v1(37.9,44.91) v1(37.9,41.5) v1(38.02,269.47) v1(38.48,34.8) v1(39.04,103.56) v1(39.12,288.16) v1(39.24,102.23) v1(39.37,282.42) v1(39.32,178.44) v1(39.45,244.32) v1(39.6,201.8) v1(39.6,201.07) v1(39.75,34.8) v1(40.11,249.94) v1(40.23,103.53) v1(40.26,102.21) v1(40.39,288.16) v1(40.97,171.91) v1(40.89,165.53) v1(40.92,45.03) v1(41.02,34.8) v1(41.38,182.19) v1(41.38,161.7) v1(41.66,288.16) v1(42.04,236.78) v1(42.09,229.74) v1(42.29,34.8) v1(42.85,165.33) v1(42.88,95.2) v1(42.93,288.16) v1(43.26,41.3) v1(43.56,34.8) v1(43.64,103.61) v1(43.66,102.23) v1(43.71,231.27) v1(43.69,44.15) v1(44.2,288.16) v1(44.27,92.66) v1(44.58,178.61) v1(44.78,103.58) v1(44.81,102.26) v1(44.83,34.8) v1(45.34,206.76) v1(45.34,168) v1(45.47,288.16) v1(45.62,103.61) v1(45.62,102.26) v1(46.08,237.13) v1(46.1,229.84) v1(46.1,213.21) v1(46.15,57.81) v1(46.1,34.8) v1(46.51,284.25) v1(46.74,288.16) v1(46.76,103.56) v1(46.81,234.04) v1(46.81,102.29) v1(47.24,239.4) v1(47.37,34.8) v1(47.57,226.31) v1(47.9,230.56) v1(48.01,288.16) v1(48.08,100.08) v1(48.64,34.8) v1(48.92,73.71) v1(49.1,177.6) v1(49.28,288.16) v1(49.23,167.46) v1(49.76,256.49) v1(49.91,34.8) v1(50.29,77.75) v1(50.55,288.16) v1(50.93,55.25) v1(51.1,81.56) v1(51.18,34.8) v1(51.21,226.26) v1(51.38,209.22) v1(51.82,288.16) v1(51.89,270.08) v1(52.43,262.43) v1(52.43,73.63) v1(52.45,34.8) v1(52.6,95.43) v1(52.7,171.68) v1(53.09,288.16) v1(53.06,64.87) v1(53.52,285.14) v1(53.57,57.84) v1(53.72,34.8) v1(53.82,51) v1(54.1,276.63) v1(54.36,288.16) v1(54.56,189.08) v1(54.69,270.1) v1(54.69,41.33) v1(54.99,34.8) v1(55.58,181.05) v1(55.63,288.16) v1(55.78,256.06) v1(55.85,171.7) v1(56.16,64.14) v1(56.26,34.8) v1(56.72,245.08) v1(56.79,249.68) v1(56.9,288.16) v1(57.53,34.8) v1(57.78,220.04) v1(57.94,206.4) v1(58.17,288.16) v1(58.34,178.36) v1(58.8,34.8) v1(59.44,288.16) v1(59.94,88.37) v1(60.07,34.8) v1(60.27,216.87) v1(60.71,288.16) v1(60.88,268.55) v1(61.06,73.43) v1(61.34,34.8) v1(61.82,255.88) v1(61.85,178.51) v1(61.98,288.16) v1(61.98,260.17) v1(62.15,284.71) v1(62.38,206.27) v1(62.53,264.34) v1(62.61,34.8) v1(63.25,288.16) v1(63.88,34.8) v1(64.52,288.16) v1(64.82,213.36) v1(64.8,83.31) v1(65.15,34.8) v1(65.38,78.21) v1(65.58,257.53) v1(65.79,288.16) v1(66.34,216.71) v1(66.42,212.29) v1(66.42,34.8) v1(66.6,286.33) v1(67.06,288.16) v1(67.03,231.22) v1(67.39,254.71) v1(67.54,226.85) v1(67.69,191.52) v1(67.69,34.8) v1(67.82,236.7) v1(67.89,263.78) v1(68.15,282.73) v1(68.33,288.16) v1(68.73,206.27) v1(68.96,34.8) v1(69.24,283.49) v1(69.6,288.16) v1(70.23,34.8) v1(70.48,280.7) v1(70.74,278.49) v1(70.87,288.16) v1(71.04,214.81) v1(71.12,267.34) v1(71.5,34.8) v1(71.88,285.9) v1(72.14,288.16) v1(72.57,279.48) v1(72.77,34.8) v1(73.41,288.16) v1(73.46,248.44) v1(73.69,283.11) v1(73.74,244.58) v1(74.04,34.8) v1(74.14,255.52) v1(74.3,261.59) v1(74.68,288.16) v1(74.78,266.32) v1(75.18,183.87) v1(75.31,34.8) v1(75.56,64.49) v1(75.95,288.16) v1(76.02,285.93) v1(76.17,207.87) v1(76.38,253.54) v1(76.58,34.8) v1(77.22,288.16) v1(77.8,262.36) v1(77.85,34.8) v1(78.36,285.52) v1(78.41,255.88) v1(78.49,288.16) v1(78.59,282.98) v1(78.94,247.85) v1(79.12,34.8) v1(79.35,264.49) v1(79.3,164.64) v1(79.68,216.86) v1(79.76,288.16) v1(79.76,212.44) v1(79.98,270.51) v1(80.16,259.21) v1(80.39,34.8) v1(80.72,285.85) v1(81.03,288.16) v1(81.38,267.44) v1(81.46,269.19) v1(81.46,268.55) v1(81.51,262.51) v1(81.66,34.8) v1(82.02,269.52) v1(82.02,268.91) v1(82.04,268.3) v1(82.3,288.16) v1(82.7,98.12) v1(82.93,34.8) v1(83.08,243.79) v1(83.19,283.87) v1(83.13,258.19) v1(83.26,273.56) v1(83.44,221.23) v1(83.41,182.25) v1(83.57,288.16) v1(84.02,286) v1(84.15,221.23) v1(84.2,264.49) v1(84.2,34.8) v1(84.66,280.75) v1(84.84,288.16) v1(84.89,273.69) v1(85.04,277.83) v1(85.14,151.18) v1(85.47,34.8) v1(85.85,67.06) v1(86.11,288.16) v1(86.41,59.23) v1(86.56,285.8) v1(86.77,251.26) v1(86.74,34.8) v1(86.74,33.53) v1(86.74,32.26) v1(86.74,30.99) v1(86.74,29.72) v1(86.74,28.45) v1(86.74,27.18) v1(86.74,25.91) v1(86.74,24.64) v1(86.74,23.37) v1(86.74,22.1) v1(86.74,20.83) v1(86.74,19.56) v1(86.74,18.29) v1(86.74,17.02) v1(86.74,15.75) v1(86.74,14.48) v1(86.74,13.21) v1(86.74,11.94) v1(86.74,10.67) v1(86.74,9.4) v1(86.74,8.13) v1(86.74,6.86) v1(86.74,5.59) v1(86.74,4.32) v1(86.74,3.05) v1(86.74,1.78) v1(86.74,0.51) v1(86.79,63.96) v1(87.15,259.87) v1(87.12,259.21) v1(87.38,288.16) v1(87.5,81) v1(87.83,259.87) v1(87.86,259.18) v1(88.01,0.51) v1(88.24,283.13) v1(88.24,282.5) v1(88.52,259.87) v1(88.49,259.21) v1(88.65,288.16) v1(88.8,283.46) v1(88.8,282.85) v1(88.82,282.24) v1(88.85,93.12) v1(89.28,0.51) v1(89.36,286.59) v1(89.33,81.31) v1(89.92,288.16) v1(89.92,249) v1(90.45,99.9) v1(90.55,0.51) v1(90.7,269.52) v1(90.73,268.91) v1(90.73,268.3) v1(91.19,288.16) v1(91.19,153.59) v1(91.29,269.27) v1(91.29,268.63) v1(91.82,0.51) v1(92.46,288.16) v1(92.58,274.02) v1(92.56,258.19) v1(92.56,95.35) v1(92.61,274.96) v1(92.74,57.51) v1(92.79,258.88) v1(93.14,233.2) v1(93.09,0.51) v1(93.55,142.34) v1(93.62,273.94) v1(93.73,288.16) v1(94.36,0.51) v1(94.72,92.84) v1(95,288.16) v1(95.38,258.06) v1(95.4,231.95) v1(95.48,228.17) v1(95.63,0.51) v1(96.04,147.83) v1(96.27,288.16) v1(96.62,192) v1(96.9,0.51) v1(97.54,288.16) v1(97.61,106.17) v1(97.84,109.45) v1(98.04,284.76) v1(98.17,0.51) v1(98.4,169.88) v1(98.58,259.69) v1(98.78,266.4) v1(98.81,288.16) v1(99.01,113.44) v1(99.16,281.23) v1(99.23,200.33) v1(99.44,0.51) v1(99.64,228.24) v1(100.08,288.16) v1(100.08,150.14) v1(100.56,63.2) v1(100.71,0.51) v1(100.84,206.43) v1(100.84,135.25) v1(101.09,65.3) v1(101.17,60.96) v1(101.27,251.99) v1(101.27,251.23) v1(101.27,250.47) v1(101.35,288.16) v1(101.5,271.65) v1(101.9,252.37) v1(101.9,251.61) v1(101.9,250.85) v1(101.9,250.09) v1(101.98,0.51) v1(102.18,256.9) v1(102.51,247.73) v1(102.62,288.16) v1(102.62,250.09) v1(102.59,249.25) v1(102.59,248.49) v1(102.84,197.18) v1(102.79,57.38) v1(103.1,243.48) v1(103.1,242.72) v1(103.1,241.99) v1(103.25,0.51) v1(103.34,260.97) v1(103.33,260.28) v1(103.34,259.65) v1(103.45,250.09) v1(103.45,249.25) v1(103.78,250.65) v1(103.73,243.87) v1(103.73,243.1) v1(103.73,242.34) v1(103.89,288.16) v1(103.91,261.26) v1(103.91,260.6) v1(103.91,259.94) v1(103.91,259.28) v1(104.5,109.63) v1(104.52,0.51) v1(104.62,201.02) v1(104.93,60.91) v1(104.95,57.76) v1(105.16,288.16) v1(105.59,63.17) v1(105.79,0.51) v1(106.27,228.37) v1(106.43,288.16) v1(106.5,243.48) v1(106.5,242.72) v1(106.5,241.96) v1(106.5,241.2) v1(106.65,115.39) v1(106.71,267.72) v1(106.78,113.54) v1(106.83,251.71) v1(106.91,111.71) v1(107.06,0.51) v1(107.14,243.87) v1(107.14,243.1) v1(107.14,242.34) v1(107.41,268.42) v1(107.43,267.74) v1(107.47,252.1) v1(107.47,251.33) v1(107.47,250.57) v1(107.41,249.12) v1(107.7,288.16) v1(107.77,244.25) v1(107.77,243.48) v1(107.77,242.72) v1(107.77,241.96) v1(107.82,271.32) v1(107.82,191.95) v1(108.01,269.39) v1(108.03,268.75) v1(108.04,268.06) v1(108.1,252.48) v1(108.1,251.71) v1(108.1,250.95) v1(108.1,250.19) v1(108.28,271.27) v1(108.33,0.51) v1(108.41,272.95) v1(108.53,273.63) v1(108.51,113.23) v1(108.66,269.77) v1(108.66,269.11) v1(108.66,268.45) v1(108.66,267.79) v1(108.97,288.16) v1(109.23,274.42) v1(109.23,273.62) v1(109.21,272.95) v1(109.23,269.41) v1(109.23,268.09) v1(109.6,0.51) v1(109.83,271.42) v1(110.03,275.22) v1(110.03,274.42) v1(110.03,273.62) v1(110.01,272.95) v1(110.24,288.16) v1(110.76,275.25) v1(110.81,274.4) v1(110.83,273.62) v1(110.81,272.95) v1(110.87,0.51) v1(111.26,244.01) v1(111.25,243.13) v1(111.25,57.63) v1(111.3,242.39) v1(111.33,60.05) v1(111.42,248.63) v1(111.51,288.16) v1(111.58,267.77) v1(111.53,251.46) v1(111.53,250.7) v1(111.69,285.74) v1(111.67,285.03) v1(111.69,284.4) v1(111.63,274.27) v1(111.63,273.62) v1(111.69,283.71) v1(111.79,275.41) v1(111.76,243.51) v1(111.76,242.75) v1(111.76,241.99) v1(112.04,280.77) v1(112.17,251.84) v1(112.17,251.08) v1(112.17,250.32) v1(112.14,0.51) v1(112.32,285.42) v1(112.32,284.76) v1(112.32,284.1) v1(112.32,283.44) v1(112.43,273.62) v1(112.52,274.24) v1(112.78,288.16) v1(112.9,285.77) v1(112.89,285.06) v1(112.9,284.42) v1(112.89,283.74) v1(113.41,0.51) v1(113.77,65.23) v1(113.82,62.46) v1(113.82,59.66) v1(114.05,288.16) v1(114.68,0.51) v1(115.32,288.16) v1(115.49,260.02) v1(115.49,259.36) v1(115.49,258.7) v1(115.49,258.04) v1(115.95,0.51) v1(116.06,259.66) v1(116.08,259.02) v1(116.06,258.34) v1(116.59,288.16) v1(116.87,286.26) v1(117.22,0.51) v1(117.32,277.67) v1(117.86,288.16) v1(117.96,58.34) v1(118.49,0.51) v1(119.08,270.33) v1(119.13,288.16) v1(119.23,259.41) v1(119.38,62.51) v1(119.68,56.97) v1(119.76,0.51) v1(120.07,58.12) v1(120.4,288.16) v1(120.55,51.69) v1(120.6,217.3) v1(121.03,0.51) v1(121.67,288.16) v1(122.3,0.51) v1(122.43,275.21) v1(122.43,253.92) v1(122.68,267.79) v1(122.94,288.16) v1(123.01,241.43) v1(123.57,0.51) v1(123.85,59.39) v1(124.21,288.16) v1(124.49,71.09) v1(124.43,66.45) v1(124.66,57.43) v1(124.76,259.41) v1(124.84,0.51) v1(125.15,79.25) v1(125.48,288.16) v1(125.91,246.23) v1(126.11,0.51) v1(126.31,234.92) v1(126.75,288.16) v1(126.8,211.96) v1(127.28,59.84) v1(127.38,0.51) v1(127.46,57.56) v1(127.86,54.46) v1(128.02,288.16) v1(128.57,188.85) v1(128.68,249.96) v1(128.65,0.51) v1(129.29,288.16) v1(129.92,0.51) v1(130.02,59.69) v1(130.23,271.63) v1(130.25,183.03) v1(130.25,57.05) v1(130.56,288.16) v1(130.68,271.65) v1(130.84,273.43) v1(131.01,50.65) v1(131.17,267) v1(131.17,265.68) v1(131.19,267.71) v1(131.19,266.39) v1(131.19,0.51) v1(131.64,275.65) v1(131.66,274.85) v1(131.66,274.08) v1(131.62,273.43) v1(131.83,288.16) v1(131.83,267.39) v1(131.8,266.73) v1(131.83,266.06) v1(132.21,271.78) v1(132.38,240.39) v1(132.38,239.62) v1(132.38,238.86) v1(132.44,275.65) v1(132.46,274.85) v1(132.46,274.08) v1(132.44,273.43) v1(132.46,267.71) v1(132.44,267) v1(132.46,266.39) v1(132.44,265.68) v1(132.46,0.51) v1(132.97,266.73) v1(132.97,266.04) v1(132.99,267.39) v1(133.02,240.77) v1(133.02,240) v1(133.02,239.24) v1(133.02,238.48) v1(133.1,288.16) v1(133.16,275.63) v1(133.21,274.75) v1(133.26,274.08) v1(133.55,242.12) v1(133.73,0.51) v1(134.06,274.08) v1(134.09,242.66) v1(134.21,275.79) v1(134.27,241.94) v1(134.37,288.16) v1(134.44,241.23) v1(134.62,243.2) v1(134.86,274.08) v1(134.8,242.48) v1(134.97,241.77) v1(135.05,250.04) v1(135.05,249.28) v1(135.05,248.51) v1(135.05,247.75) v1(135,0.51) v1(135.12,243.69) v1(135.34,243.02) v1(135.51,242.31) v1(135.64,288.16) v1(135.66,244.22) v1(135.69,251.94) v1(135.69,251.18) v1(135.69,250.42) v1(135.69,249.66) v1(135.69,248.89) v1(135.69,248.13) v1(135.69,247.37) v1(135.83,243.51) v1(136.01,242.8) v1(136.27,0.51) v1(136.32,252.32) v1(136.32,251.56) v1(136.32,250.8) v1(136.35,44.09) v1(136.55,243.33) v1(136.63,68.81) v1(136.7,57.43) v1(136.83,66.01) v1(136.91,288.16) v1(136.96,251.94) v1(136.96,251.18) v1(136.96,250.42) v1(136.96,248.46) v1(137.08,249.02) v1(137.09,243.87) v1(137.54,0.51) v1(137.59,251.56) v1(137.59,250.8) v1(137.59,250.04) v1(138.18,288.16) v1(138.28,192.53) v1(138.38,166.22) v1(138.43,56.72) v1(138.56,99.19) v1(138.73,140.94) v1(138.84,68.81) v1(138.81,0.51) v1(138.94,59.89) v1(139.12,240.89) v1(139.12,240.13) v1(139.12,239.37) v1(139.12,238.61) v1(139.22,6.78) v1(139.45,288.16) v1(139.75,242.04) v1(139.75,241.27) v1(140.08,0.51) v1(140.16,109.3) v1(140.39,251.56) v1(140.39,243.18) v1(140.39,242.42) v1(140.39,241.66) v1(140.49,243.99) v1(140.72,288.16) v1(140.96,248.97) v1(141.02,251.94) v1(141.02,251.18) v1(141.02,250.42) v1(141.02,243.56) v1(141.02,242.8) v1(141.02,242.04) v1(141.12,60.68) v1(141.35,0.51) v1(141.66,252.32) v1(141.66,251.56) v1(141.66,250.8) v1(141.66,250.04) v1(141.64,249.1) v1(141.99,288.16) v1(142.32,100.69) v1(142.34,94.01) v1(142.62,0.51) v1(143,271.68) v1(143.05,193.73) v1(143.1,140.64) v1(143.26,288.16) v1(143.51,271.55) v1(143.78,274.05) v1(143.97,267.58) v1(143.95,266.87) v1(143.97,266.26) v1(143.95,265.55) v1(143.89,0.51) v1(144.44,275.73) v1(144.44,274.93) v1(144.45,273.38) v1(144.53,288.16) v1(144.58,274.05) v1(144.58,266.6) v1(144.58,243.43) v1(144.6,267.26) v1(144.6,265.94) v1(144.63,200.33) v1(144.83,60.53) v1(145.01,271.83) v1(145.03,261.52) v1(145.08,251.31) v1(145.08,250.55) v1(145.16,0.51) v1(145.24,275.73) v1(145.24,274.93) v1(145.24,267.58) v1(145.22,266.87) v1(145.24,266.26) v1(145.22,265.55) v1(145.21,243.81) v1(145.21,243.05) v1(145.21,242.29) v1(145.21,241.53) v1(145.21,240.77) v1(145.21,240) v1(145.21,239.24) v1(145.21,238.48) v1(145.38,274.05) v1(145.29,273.43) v1(145.29,190.17) v1(145.41,52.35) v1(145.64,249.14) v1(145.77,267.26) v1(145.75,266.6) v1(145.75,265.91) v1(145.72,251.69) v1(145.72,250.93) v1(145.72,250.16) v1(145.8,288.16) v1(145.85,242.67) v1(145.85,241.91) v1(145.85,241.15) v1(145.95,275.62) v1(145.99,274.85) v1(146.13,273.99) v1(146.48,242.29) v1(146.48,241.53) v1(146.43,0.51) v1(146.89,273.99) v1(147.07,288.16) v1(147.26,276.01) v1(147.7,0.51) v1(148.03,182.52) v1(148.06,114.81) v1(148.34,288.16) v1(148.49,146.94) v1(148.77,103.51) v1(148.95,5.89) v1(148.97,0.51) v1(149.61,288.16) v1(150.24,0.51) v1(150.62,93.22) v1(150.62,84.35) v1(150.75,286.51) v1(150.88,288.16) v1(151.03,81.38) v1(151.08,57.1) v1(151.16,60.66) v1(151.51,0.51) v1(151.87,40.92) v1(152.15,288.16) v1(152.55,275.16) v1(152.73,157.4) v1(152.73,10.36) v1(152.78,0.51) v1(152.88,18.29) v1(153.09,53.64) v1(153.01,22.66) v1(153.16,36.7) v1(153.21,40.87) v1(153.19,38.94) v1(153.31,35.86) v1(153.42,288.16) v1(153.72,90.47) v1(153.72,2.77) v1(153.85,35) v1(154.05,0.51) v1(154.18,281.94) v1(154.15,226.85) v1(154.23,96.44) v1(154.69,288.16) v1(155.27,270.13) v1(155.19,154.81) v1(155.32,0.51) v1(155.63,45.99) v1(155.73,47.52) v1(155.96,288.16) v1(155.93,60.68) v1(155.98,48.5) v1(155.91,44.96) v1(155.96,34.16) v1(155.96,32.89) v1(155.96,31.62) v1(155.96,30.35) v1(155.96,29.08) v1(155.96,27.81) v1(155.96,26.54) v1(155.96,25.27) v1(155.96,24) v1(155.96,22.73) v1(155.96,21.46) v1(155.96,20.19) v1(155.96,18.92) v1(155.96,17.65) v1(155.96,16.38) v1(155.96,15.11) v1(155.96,13.84) v1(155.96,12.57) v1(155.96,11.3) v1(155.96,10.03) v1(155.96,8.76) v1(155.96,7.49) v1(155.96,6.22) v1(155.96,4.95) v1(155.96,3.68) v1(155.96,2.41) v1(155.96,1.14) v1(156.49,230.73) v1(156.59,34.8) v1(156.77,285.04) v1(156.74,43.79) v1(157.23,288.16) v1(157.28,285.04) v1(157.28,50.04) v1(157.53,57.84) v1(157.86,34.8) v1(157.96,53.06) v1(158.14,189.79) v1(158.5,288.16) v1(158.98,258.27) v1(158.98,257.51) v1(158.98,256.74) v1(159.05,159.72) v1(159.13,34.8) v1(159.61,258.65) v1(159.61,257.89) v1(159.61,257.12) v1(159.61,256.36) v1(159.77,288.16) v1(160.14,260) v1(160.4,34.8) v1(160.58,52.25) v1(160.68,260.54) v1(160.63,50.57) v1(160.86,259.82) v1(160.96,102.18) v1(161.04,288.16) v1(161.03,259.11) v1(161.22,261.08) v1(161.21,84.61) v1(161.21,74.12) v1(161.4,260.36) v1(161.57,259.65) v1(161.67,34.8) v1(161.77,267.69) v1(161.72,261.57) v1(161.8,266.88) v1(161.8,266.12) v1(161.8,265.33) v1(161.85,37.16) v1(161.94,260.9) v1(162.11,260.19) v1(162.26,262.11) v1(162.31,288.16) v1(162.33,269.8) v1(162.33,269.04) v1(162.33,268.12) v1(162.33,267.28) v1(162.33,266.47) v1(162.33,265.68) v1(162.33,264.9) v1(162.43,261.4) v1(162.61,260.68) v1(162.61,37.16) v1(162.76,53.7) v1(162.92,270.21) v1(162.92,269.44) v1(162.92,268.68) v1(162.89,268.02) v1(162.97,261.93) v1(162.94,34.8) v1(163.15,261.22) v1(163.35,37.13) v1(163.47,268.33) v1(163.58,288.16) v1(163.55,269.82) v1(163.55,269.06) v1(163.55,266.32) v1(163.63,266.98) v1(163.68,261.76) v1(163.7,267.79) v1(163.8,59.61) v1(164.08,267.03) v1(164.21,34.8) v1(164.74,48.72) v1(164.85,288.16) v1(164.95,56.39) v1(165.25,53.04) v1(165.48,34.8) v1(165.71,258.78) v1(165.71,258.01) v1(165.71,257.25) v1(165.71,256.49) v1(165.71,42.7) v1(165.71,42.04) v1(165.76,41.35) v1(166.12,288.16) v1(166.17,185.34) v1(166.34,259.92) v1(166.34,259.16) v1(166.45,41.35) v1(166.75,34.8) v1(166.8,96.44) v1(166.98,269.44) v1(166.98,261.06) v1(166.98,260.3) v1(166.98,259.54) v1(167.08,41.33) v1(167.16,281.28) v1(167.16,240.31) v1(167.11,40.69) v1(167.39,288.16) v1(167.44,42.85) v1(167.56,266.85) v1(167.61,269.82) v1(167.61,269.06) v1(167.61,268.3) v1(167.61,261.44) v1(167.61,260.68) v1(167.61,259.92) v1(167.72,262.23) v1(167.74,41.35) v1(167.74,40.72) v1(168.02,34.8) v1(168.12,267.94) v1(168.25,270.21) v1(168.25,269.44) v1(168.25,268.68) v1(168.23,266.98) v1(168.4,60.07) v1(168.66,288.16) v1(168.66,39.17) v1(169.11,42.75) v1(169.34,39.14) v1(169.29,34.8) v1(169.93,288.16) v1(169.9,92.46) v1(170.1,62.61) v1(170.23,81.33) v1(170.56,34.8) v1(171.02,58.55) v1(171.17,261.32) v1(171.2,288.16) v1(171.32,77.17) v1(171.68,269.19) v1(171.68,268.43) v1(171.81,284.71) v1(171.81,261.7) v1(171.81,260.93) v1(171.81,260.17) v1(171.81,259.41) v1(171.81,258.65) v1(171.81,257.89) v1(171.81,257.12) v1(171.81,256.36) v1(171.83,34.8) v1(172.05,267.02) v1(172.09,169.93) v1(172.26,268.2) v1(172.31,269.57) v1(172.31,268.81) v1(172.47,288.16) v1(172.44,260.55) v1(172.44,259.79) v1(172.44,259.03) v1(172.42,85.19) v1(172.62,67.31) v1(172.75,240.39) v1(172.82,71.65) v1(173.08,260.17) v1(173.08,259.41) v1(173.1,34.8) v1(173.61,56.97) v1(173.74,288.16) v1(173.79,80.26) v1(174.37,34.8) v1(174.45,63.78) v1(174.6,192.51) v1(174.62,82.68) v1(174.7,60.73) v1(175.01,288.16) v1(175.64,34.8) v1(176.28,288.16) v1(176.91,34.8) v1(177.01,73.58) v1(177.14,57.12) v1(177.55,288.16) v1(177.52,68.86) v1(177.65,166.24) v1(178.18,34.8) v1(178.64,273.41) v1(178.77,284.56) v1(178.82,288.16) v1(179.45,34.8) v1(179.71,86.41) v1(179.81,214.81) v1(180.09,288.16) v1(180.72,34.8) v1(181.36,288.16) v1(181.76,227) v1(182.02,214.91) v1(182.04,214.3) v1(181.99,34.8) v1(182.14,227.63) v1(182.52,227) v1(182.63,288.16) v1(182.63,38) v1(182.63,36.73) v1(182.85,214.93) v1(182.88,214.3) v1(182.88,37.36) v1(182.91,227.63) v1(183.13,241.6) v1(183.26,38) v1(183.26,36.73) v1(183.26,34.8) v1(183.34,226.99) v1(183.29,207.82) v1(183.44,86.85) v1(183.67,227.63) v1(183.64,178.87) v1(183.64,37.36) v1(183.83,87.48) v1(183.82,86.21) v1(183.9,288.16) v1(183.92,214.96) v1(183.9,67.46) v1(183.9,38) v1(183.9,36.73) v1(184.05,227) v1(184,220.85) v1(184.05,214.3) v1(184.08,86.84) v1(184.09,88.11) v1(184.15,66.83) v1(184.28,37.36) v1(184.46,87.47) v1(184.45,86.2) v1(184.53,220.04) v1(184.53,67.46) v1(184.53,38) v1(184.53,36.73) v1(184.53,34.8) v1(184.66,66.19) v1(184.72,88.11) v1(184.71,86.84) v1(184.91,66.83) v1(184.91,65.56) v1(184.91,37.36) v1(185.17,288.16) v1(185.1,87.47) v1(185.09,86.2) v1(185.17,67.46) v1(185.17,38) v1(185.17,36.73) v1(185.22,226.49) v1(185.32,219.81) v1(185.34,219.2) v1(185.36,88.1) v1(185.35,86.83) v1(185.29,66.19) v1(185.55,66.83) v1(185.55,37.36) v1(185.67,65.56) v1(185.7,207.82) v1(185.73,87.46) v1(185.72,86.19) v1(185.8,67.46) v1(185.8,38) v1(185.8,36.73) v1(185.8,34.8) v1(185.98,86.83) v1(185.93,66.19) v1(186.03,226.48) v1(185.99,88.1) v1(186.11,224.36) v1(186.18,223.62) v1(186.11,219.79) v1(186.11,219.18) v1(186.18,66.83) v1(186.18,37.36) v1(186.23,258.57) v1(186.37,87.46) v1(186.36,86.19) v1(186.31,65.56) v1(186.44,288.16) v1(186.44,67.46) v1(186.44,38) v1(186.44,36.73) v1(186.56,66.19) v1(186.63,88.09) v1(186.62,86.82) v1(186.72,213.66) v1(186.84,214.55) v1(186.82,66.83) v1(186.82,37.36) v1(186.94,263.8) v1(186.92,224.35) v1(186.94,65.56) v1(186.99,223.61) v1(186.99,222.99) v1(187.02,219.81) v1(187,87.46) v1(186.99,86.19) v1(187.07,67.46) v1(187.07,38) v1(187.07,36.73) v1(187.07,34.8) v1(187.22,214.05) v1(187.26,88.1) v1(187.25,86.83) v1(187.2,66.19) v1(187.48,214.68) v1(187.45,66.83) v1(187.45,37.36) v1(187.58,65.56) v1(187.63,224.36) v1(187.63,87.46) v1(187.62,86.19) v1(187.67,53.55) v1(187.71,288.16) v1(187.71,223.62) v1(187.71,67.46) v1(187.71,38) v1(187.71,36.73) v1(187.88,86.82) v1(187.83,66.19) v1(187.89,88.09) v1(187.94,54.72) v1(187.94,52.92) v1(188.11,207.82) v1(188.09,66.83) v1(188.09,37.36) v1(188.27,87.45) v1(188.26,86.18) v1(188.21,65.56) v1(188.21,54.09) v1(188.34,67.46) v1(188.34,38) v1(188.34,36.73) v1(188.34,34.8) v1(188.47,66.19) v1(188.39,55.17) v1(188.39,53.37) v1(188.53,88.09) v1(188.52,86.82) v1(188.57,52.65) v1(188.66,54.54) v1(188.7,284.25) v1(188.72,66.83) v1(188.72,37.36) v1(188.85,65.56) v1(188.84,55.62) v1(188.84,53.82) v1(188.84,52.02) v1(188.98,288.16) v1(188.98,227.41) v1(188.9,87.45) v1(188.89,86.18) v1(188.98,67.46) v1(188.98,38) v1(188.98,36.73) v1(189.16,88.08) v1(189.15,86.81) v1(189.1,66.19) v1(189.11,54.99) v1(189.11,53.19) v1(189.2,203.12) v1(189.26,198.93) v1(189.36,66.83) v1(189.29,56.07) v1(189.29,54.27) v1(189.29,52.47) v1(189.48,65.56) v1(189.47,51.76) v1(189.54,87.44) v1(189.56,55.44) v1(189.56,53.64) v1(189.61,67.46) v1(189.61,34.8) v1(189.74,66.19) v1(189.74,56.51) v1(189.74,54.72) v1(189.74,52.92) v1(189.8,88.08) v1(189.79,86.81) v1(189.99,66.83) v1(190.01,55.89) v1(190.01,54.09) v1(190.01,52.29) v1(189.99,41.94) v1(189.99,41.3) v1(189.99,40.67) v1(189.99,40.03) v1(189.99,39.4) v1(189.99,38.76) v1(189.99,38.13) v1(189.99,37.49) v1(189.99,36.86) v1(190.17,163.3) v1(190.17,87.44) v1(190.12,65.56) v1(190.25,288.16) v1(190.25,67.46) v1(190.19,56.96) v1(190.19,55.17) v1(190.19,53.37) v1(190.37,66.19) v1(190.46,56.34) v1(190.46,54.54) v1(190.46,52.74) v1(190.58,83.52) v1(190.57,82.25) v1(190.63,66.83) v1(190.64,57.41) v1(190.64,55.62) v1(190.64,53.82) v1(190.63,41.68) v1(190.63,41.05) v1(190.63,40.41) v1(190.63,39.78) v1(190.63,39.14) v1(190.63,38.51) v1(190.63,37.87) v1(190.63,37.24) v1(190.63,36.6) v1(190.75,65.56) v1(190.84,84.15) v1(190.83,82.88) v1(190.88,67.46) v1(190.88,34.8) v1(190.91,56.78) v1(190.91,54.99) v1(190.91,53.19) v1(191.01,66.19) v1(191.08,57.86) v1(191.08,56.07) v1(191.08,54.27) v1(191.24,255.07) v1(191.21,254.23) v1(191.22,83.52) v1(191.21,82.25) v1(191.26,66.83) v1(191.26,42.06) v1(191.26,41.43) v1(191.26,40.79) v1(191.26,40.16) v1(191.26,39.52) v1(191.26,38.89) v1(191.26,38.25) v1(191.26,37.62) v1(191.26,36.98) v1(191.35,57.23) v1(191.35,55.44) v1(191.35,53.64) v1(191.48,84.15) v1(191.47,82.88) v1(191.52,288.16) v1(191.54,223.47) v1(191.54,222.71) v1(191.54,214.68) v1(191.52,67.46) v1(191.53,58.31) v1(191.53,56.51) v1(191.53,54.72) v1(191.62,218.64) v1(191.67,91.24) v1(191.85,83.51) v1(191.84,82.24) v1(191.8,57.68) v1(191.8,55.89) v1(191.8,54.09) v1(191.97,238.68) v1(191.9,66.83) v1(191.98,56.96) v1(191.98,55.17) v1(191.9,41.81) v1(191.9,41.17) v1(191.9,40.54) v1(191.9,39.9) v1(191.9,39.27) v1(191.9,38.63) v1(191.9,38) v1(191.9,37.36) v1(191.9,36.73) v1(192.11,84.14) v1(192.1,82.87) v1(192.15,67.46) v1(192.15,34.8) v1(192.23,222.61) v1(192.2,218.62) v1(192.23,214.66) v1(192.25,56.34) v1(192.25,54.54) v1(192.3,207.82) v1(192.43,57.41) v1(192.43,55.62) v1(192.53,66.83) v1(192.67,218.26) v1(192.79,288.16) v1(192.74,225.35) v1(192.74,224.69) v1(192.79,67.46) v1(192.7,56.78) v1(192.7,54.99) v1(192.88,56.07) v1(192.94,146.31) v1(193.17,66.83) v1(193.15,55.44) v1(193.22,214.71) v1(193.24,214.07) v1(193.32,225.32) v1(193.34,224.69) v1(193.37,223.37) v1(193.37,222.66) v1(193.33,56.51) v1(193.42,67.46) v1(193.42,34.8) v1(193.6,55.89) v1(193.8,66.83) v1(194.06,288.16) v1(194.03,225.32) v1(194.03,224.66) v1(194.06,67.46) v1(194.44,66.83) v1(194.61,225.3) v1(194.64,224.66) v1(194.72,207.82) v1(194.69,67.46) v1(194.69,34.8) v1(194.89,233.65) v1(195.05,94.61) v1(195.02,90.4) v1(195.07,66.83) v1(195.33,288.16) v1(195.35,280.85) v1(195.33,67.46) v1(195.63,215.11) v1(195.66,214.38) v1(195.71,66.83) v1(195.96,67.46) v1(195.96,34.8) v1(196.11,219.68) v1(196.11,218.9) v1(196.14,130.03) v1(196.37,215.09) v1(196.34,214.38) v1(196.34,66.83) v1(196.6,288.16) v1(196.77,218.87) v1(196.8,219.71) v1(196.9,202.95) v1(196.98,66.83) v1(197.13,207.82) v1(197.23,34.8) v1(197.36,224.64) v1(197.36,223.85) v1(197.41,215.11) v1(197.43,214.38) v1(197.61,169.57) v1(197.87,288.16) v1(198.07,224.61) v1(198.02,223.82) v1(198.15,215.09) v1(198.12,214.38) v1(198.32,219.74) v1(198.35,219.05) v1(198.5,34.8) v1(198.68,229.29) v1(198.75,272.16) v1(198.75,269.95) v1(198.75,268.33) v1(198.75,237.26) v1(198.78,224.61) v1(198.78,223.88) v1(198.83,265.28) v1(199.01,219.76) v1(199.01,219.02) v1(199.14,288.16) v1(199.14,215.16) v1(199.16,214.43) v1(199.47,224.59) v1(199.44,223.85) v1(199.77,34.8) v1(199.87,215.14) v1(199.85,214.43) v1(199.87,107.19) v1(200.18,224.59) v1(200.15,223.88) v1(200.38,219.91) v1(200.36,219.33) v1(200.41,288.16) v1(200.76,224.56) v1(200.81,248.84) v1(200.81,223.85) v1(201.07,219.94) v1(201.02,219.3) v1(201.04,152.25) v1(201.04,34.8) v1(201.09,107.32) v1(201.11,95.23) v1(201.35,107.95) v1(201.37,94.6) v1(201.35,63.3) v1(201.42,231.65) v1(201.42,79.38) v1(201.4,70.21) v1(201.68,288.16) v1(201.7,167.03) v1(201.73,107.32) v1(201.75,95.23) v1(201.8,240.84) v1(201.98,245.03) v1(202,94.6) v1(202.11,107.95) v1(202.11,76.35) v1(202.36,107.32) v1(202.38,95.23) v1(202.31,34.8) v1(202.64,94.6) v1(202.75,107.95) v1(202.95,288.16) v1(203,107.32) v1(203.02,95.23) v1(203.27,94.6) v1(203.35,151.69) v1(203.35,150.98) v1(203.38,107.95) v1(203.58,34.8) v1(203.61,116.87) v1(203.63,107.32) v1(203.65,95.23) v1(203.91,94.6) v1(203.91,73.96) v1(204.01,107.95) v1(204.17,172.06) v1(204.22,288.16) v1(204.27,107.32) v1(204.29,95.23) v1(204.44,249.1) v1(204.44,235.33) v1(204.52,151.69) v1(204.55,144.55) v1(204.54,94.6) v1(204.5,55.35) v1(204.65,107.95) v1(204.88,90.27) v1(204.85,34.8) v1(204.95,113.49) v1(204.9,107.32) v1(204.92,95.23) v1(205.05,57.78) v1(205.18,161.7) v1(205.29,107.95) v1(205.26,55.35) v1(205.31,94.6) v1(205.36,84.07) v1(205.49,288.16) v1(205.54,107.32) v1(205.56,95.23) v1(205.61,60.2) v1(205.69,57.78) v1(205.87,39.27) v1(205.89,55.35) v1(206.04,67.44) v1(205.99,38) v1(206.12,38.63) v1(206.12,34.8) v1(206.25,60.2) v1(206.25,37.36) v1(206.32,57.78) v1(206.5,56.29) v1(206.53,55.35) v1(206.5,39.27) v1(206.68,253.75) v1(206.6,59.61) v1(206.63,58.5) v1(206.63,38) v1(206.76,288.16) v1(206.88,60.2) v1(206.86,59.08) v1(206.88,56.92) v1(206.88,38.63) v1(206.96,57.78) v1(207.01,37.36) v1(207.16,55.35) v1(207.14,39.27) v1(207.26,38) v1(207.37,122.5) v1(207.39,34.8) v1(207.52,60.2) v1(207.52,38.63) v1(207.59,92.28) v1(207.59,57.78) v1(207.65,37.36) v1(207.7,112.19) v1(207.75,106.76) v1(207.77,39.27) v1(207.8,55.35) v1(207.9,38) v1(208.03,288.16) v1(208.1,69.95) v1(208.15,60.2) v1(208.15,38.63) v1(208.23,57.78) v1(208.28,37.36) v1(208.43,55.35) v1(208.41,39.27) v1(208.53,244.3) v1(208.53,234.54) v1(208.53,38) v1(208.64,227.61) v1(208.66,34.8) v1(208.71,231.22) v1(208.76,104.8) v1(208.81,192.2) v1(208.86,184.76) v1(208.79,60.2) v1(208.86,57.78) v1(208.79,38.63) v1(208.91,37.36) v1(209.07,55.35) v1(209.04,39.27) v1(209.14,192.96) v1(209.17,38) v1(209.22,248.72) v1(209.3,288.16) v1(209.35,111.94) v1(209.47,241.07) v1(209.45,191.67) v1(209.42,60.2) v1(209.42,38.63) v1(209.52,197.74) v1(209.5,57.78) v1(209.55,37.36) v1(209.6,285.85) v1(209.68,39.27) v1(209.7,237.19) v1(209.7,55.35) v1(209.8,193.55) v1(209.8,38) v1(209.98,164.39) v1(209.93,34.8) v1(210.07,73.3) v1(210.07,72.03) v1(210.06,60.2) v1(210.06,38.63) v1(210.19,58.83) v1(210.19,37.36) v1(210.36,154.48) v1(210.33,72.66) v1(210.33,71.39) v1(210.31,57.56) v1(210.31,56.29) v1(210.34,55.35) v1(210.31,39.27) v1(210.44,59.46) v1(210.44,38) v1(210.57,288.16) v1(210.57,58.19) v1(210.77,163.8) v1(210.71,73.3) v1(210.71,72.03) v1(210.69,60.2) v1(210.69,56.92) v1(210.69,38.63) v1(210.82,164.44) v1(210.82,58.83) v1(210.82,37.36) v1(210.95,57.56) v1(210.95,56.29) v1(210.97,55.35) v1(210.95,39.27) v1(211.07,59.46) v1(211.07,38) v1(211.09,72.66) v1(211.09,71.39) v1(211.2,58.19) v1(211.2,34.8) v1(211.38,186.89) v1(211.3,147.12) v1(211.3,119.74) v1(211.34,73.3) v1(211.34,72.03) v1(211.33,60.2) v1(211.33,56.92) v1(211.33,38.63) v1(211.46,58.83) v1(211.46,37.36) v1(211.58,57.56) v1(211.58,56.29) v1(211.51,55.7) v1(211.58,39.27) v1(211.79,230.63) v1(211.73,175.34) v1(211.72,72.66) v1(211.72,71.39) v1(211.71,59.46) v1(211.71,38) v1(211.84,288.16) v1(211.86,245.8) v1(211.84,58.19) v1(211.89,186.33) v1(211.98,73.3) v1(211.98,72.03) v1(211.96,60.2) v1(211.96,56.92) v1(211.96,38.63) v1(211.99,187.27) v1(211.99,109) v1(212.09,58.83) v1(212.09,37.36) v1(212.22,39.27) v1(212.36,72.66) v1(212.36,71.39) v1(212.34,59.46) v1(212.34,38) v1(212.47,34.8) v1(212.5,186.69) v1(212.63,109) v1(212.61,73.3) v1(212.61,72.03) v1(212.6,60.2) v1(212.72,234.9) v1(212.72,58.95) v1(212.99,72.66) v1(212.99,71.39) v1(213.11,288.16) v1(213.11,59.72) v1(213.28,221.84) v1(213.28,205.92) v1(213.28,113.51) v1(213.26,109) v1(213.25,73.3) v1(213.25,72.03) v1(213.35,59.22) v1(213.46,213.87) v1(213.49,242.65) v1(213.63,72.66) v1(213.63,71.39) v1(213.74,34.8) v1(213.88,73.3) v1(213.88,72.03) v1(213.87,60.48) v1(213.87,58.95) v1(213.9,109) v1(214.26,72.66) v1(214.26,71.39) v1(214.38,288.16) v1(214.52,73.3) v1(214.52,72.03) v1(214.81,91.11) v1(214.88,60.48) v1(214.88,58.95) v1(214.9,72.66) v1(214.9,71.39) v1(215.01,174.55) v1(215.04,125.38) v1(215.01,34.8) v1(215.15,73.3) v1(215.15,72.03) v1(215.29,248.11) v1(215.33,187.67) v1(215.33,186.87) v1(215.42,277.04) v1(215.54,282.27) v1(215.53,72.66) v1(215.53,71.39) v1(215.65,288.16) v1(215.79,73.3) v1(215.79,72.03) v1(216.13,187.66) v1(216.13,186.87) v1(216.17,72.66) v1(216.17,71.39) v1(216.28,34.8) v1(216.42,72.03) v1(216.55,246.81) v1(216.71,170.1) v1(216.82,247.44) v1(216.85,246.24) v1(216.92,288.16) v1(216.93,233.58) v1(216.97,221.08) v1(217.07,231.55) v1(217.21,246.81) v1(217.2,234.2) v1(217.23,233.01) v1(217.28,186.86) v1(217.24,84.94) v1(217.23,83.67) v1(217.51,247.45) v1(217.53,246.23) v1(217.5,85.58) v1(217.49,84.31) v1(217.55,34.8) v1(217.59,233.58) v1(217.68,63.91) v1(217.87,246.81) v1(217.86,200.76) v1(217.83,183.74) v1(217.88,84.94) v1(217.86,83.67) v1(217.89,234.21) v1(217.91,232.99) v1(217.95,188.3) v1(218.01,215.19) v1(218.14,247.46) v1(218.17,246.24) v1(218.16,194.36) v1(218.13,85.57) v1(218.12,84.3) v1(218.19,288.16) v1(218.25,233.58) v1(218.34,227.28) v1(218.31,191.8) v1(218.29,190.65) v1(218.53,246.81) v1(218.52,234.23) v1(218.55,233.01) v1(218.51,84.93) v1(218.5,83.66) v1(218.72,241.99) v1(218.74,238.4) v1(218.74,210.9) v1(218.72,194.75) v1(218.71,191.24) v1(218.76,186.22) v1(218.77,85.56) v1(218.76,84.3) v1(218.69,53.87) v1(218.85,247.45) v1(218.88,246.23) v1(218.82,34.8) v1(218.91,233.58) v1(218.97,206.12) v1(218.92,113.79) v1(218.9,112.06) v1(219.07,190.65) v1(219.1,191.8) v1(219.15,183.86) v1(219.15,182.77) v1(219.15,181.67) v1(219.2,285.6) v1(219.23,234.21) v1(219.26,232.99) v1(219.28,194.36) v1(219.33,178.99) v1(219.46,288.16) v1(219.48,191.24) v1(219.41,170.28) v1(219.53,186.86) v1(219.54,184.42) v1(219.56,183.34) v1(219.56,182.25) v1(219.53,181.15) v1(219.52,104.14) v1(219.54,103.41) v1(219.57,99.26) v1(219.66,186.08) v1(219.63,185.2) v1(219.6,102.18) v1(219.84,194.75) v1(219.87,102.81) v1(219.95,183.87) v1(219.95,182.78) v1(219.95,181.69) v1(219.89,179.39) v1(219.89,101.62) v1(219.96,63.6) v1(219.96,54.6) v1(219.96,53.83) v1(220.09,34.8) v1(220.24,174.8) v1(220.22,103.44) v1(220.26,102.18) v1(220.33,186.87) v1(220.34,184.42) v1(220.34,183.34) v1(220.34,182.25) v1(220.34,181.15) v1(220.45,178.99) v1(220.55,102.82) v1(220.58,101.6) v1(220.73,288.16) v1(220.75,183.87) v1(220.75,182.78) v1(220.95,197.15) v1(220.92,102.18) v1(221.01,179.39) v1(221.16,203.23) v1(221.11,186.87) v1(221.16,184.43) v1(221.18,183.34) v1(221.18,181.15) v1(221.19,102.84) v1(221.21,101.62) v1(221.36,34.8) v1(221.58,102.18) v1(221.93,186.84) v1(221.9,102.82) v1(221.93,101.6) v1(222,288.16) v1(222.02,194.34) v1(222,189.23) v1(222.18,265) v1(222.18,261.6) v1(222.26,269.4) v1(222.25,268.69) v1(222.26,268.05) v1(222.27,267.37) v1(222.2,265.72) v1(222.2,264.37) v1(222.21,263.68) v1(222.2,262.31) v1(222.2,260.97) v1(222.21,260.28) v1(222.35,272.79) v1(222.34,272.08) v1(222.35,271.44) v1(222.36,270.76) v1(222.35,192.96) v1(222.35,191.85) v1(222.33,190.7) v1(222.58,194.73) v1(222.63,34.8) v1(222.75,192.41) v1(222.75,191.29) v1(222.83,265.39) v1(222.83,264.73) v1(222.83,264.07) v1(222.83,263.41) v1(222.83,261.99) v1(222.83,261.33) v1(222.83,260.67) v1(222.83,260.01) v1(222.9,269.07) v1(222.9,268.41) v1(222.9,267.75) v1(222.9,267.09) v1(222.99,272.47) v1(222.99,271.81) v1(222.99,271.15) v1(222.99,270.48) v1(223.05,103.05) v1(223.14,194.34) v1(223.14,192.96) v1(223.14,191.85) v1(223.11,190.7) v1(223.27,288.16) v1(223.48,269.42) v1(223.47,268.71) v1(223.48,268.08) v1(223.47,267.39) v1(223.42,265.74) v1(223.4,265.03) v1(223.42,264.39) v1(223.4,263.71) v1(223.42,262.34) v1(223.4,261.63) v1(223.42,260.99) v1(223.4,260.31) v1(223.42,210.49) v1(223.57,272.81) v1(223.55,272.1) v1(223.57,271.47) v1(223.55,270.78) v1(223.52,191.29) v1(223.53,186.22) v1(223.62,144.86) v1(223.7,194.73) v1(223.81,183.49) v1(223.82,182.64) v1(223.81,181.46) v1(223.82,180.61) v1(223.84,179.83) v1(223.85,178.98) v1(223.9,34.8) v1(224.13,194.28) v1(224.13,145.24) v1(224.23,154.61) v1(224.33,186.22) v1(224.54,288.16) v1(224.61,183.49) v1(224.64,182.65) v1(224.61,181.46) v1(224.64,180.62) v1(224.64,179.83) v1(224.66,178.99) v1(224.64,145.62) v1(224.71,281.99) v1(224.78,101.64) v1(224.78,100.84) v1(224.79,100.04) v1(225.07,163.98) v1(225.02,82.75) v1(225.13,186.22) v1(225.17,34.8) v1(225.3,90.02) v1(225.43,204.06) v1(225.39,102.39) v1(225.43,101.64) v1(225.43,100.81) v1(225.44,100.01) v1(225.44,99.24) v1(225.44,98.41) v1(225.65,229.13) v1(225.68,158.37) v1(225.78,187.66) v1(225.78,186.84) v1(225.81,288.16) v1(226.06,98.41) v1(226.14,99.21) v1(226.25,101.59) v1(226.23,100.81) v1(226.21,100.04) v1(226.44,34.8) v1(226.77,263.8) v1(226.82,117.5) v1(226.96,187.62) v1(226.96,186.82) v1(227.08,288.16) v1(227.05,101.61) v1(227.03,100.81) v1(227.04,100.09) v1(227.33,79.02) v1(227.33,78.38) v1(227.33,77.75) v1(227.33,75.21) v1(227.33,74.57) v1(227.33,73.94) v1(227.69,213.28) v1(227.76,187.6) v1(227.76,186.82) v1(227.71,128.04) v1(227.71,98.34) v1(227.71,34.8) v1(227.79,240.64) v1(227.86,100.04) v1(227.94,114.88) v1(227.96,78.77) v1(227.96,78.13) v1(227.96,77.5) v1(227.96,75.59) v1(227.96,74.96) v1(227.96,74.32) v1(227.96,45.36) v1(227.96,44.73) v1(227.96,44.09) v1(227.96,41.55) v1(227.96,40.92) v1(227.96,40.28) v1(228.12,258.44) v1(228.09,68.22) v1(228.09,66.95) v1(228.09,66.32) v1(228.09,64.16) v1(228.09,63.53) v1(228.09,62.89) v1(228.09,62.26) v1(228.09,57.18) v1(228.09,56.54) v1(228.09,55.91) v1(228.09,55.27) v1(228.09,53.24) v1(228.09,52.6) v1(228.09,51.97) v1(228.09,51.33) v1(228.24,283.24) v1(228.35,288.16) v1(228.3,230.05) v1(228.52,208.64) v1(228.57,125.73) v1(228.6,79.02) v1(228.6,78.38) v1(228.6,77.75) v1(228.6,75.21) v1(228.6,74.57) v1(228.6,73.94) v1(228.6,45.11) v1(228.6,44.48) v1(228.6,43.84) v1(228.6,41.94) v1(228.6,41.3) v1(228.6,40.67) v1(228.73,68.1) v1(228.73,67.46) v1(228.73,66.83) v1(228.73,66.19) v1(228.73,65.56) v1(228.73,64.92) v1(228.73,64.29) v1(228.73,63.65) v1(228.73,63.02) v1(228.73,62.38) v1(228.73,57.05) v1(228.73,56.41) v1(228.73,55.78) v1(228.73,55.14) v1(228.73,54.51) v1(228.73,53.87) v1(228.73,53.24) v1(228.73,52.6) v1(228.73,51.97) v1(228.73,51.33) v1(228.98,34.8) v1(229.18,141.94) v1(229.18,141.17) v1(229.16,84.07) v1(229.24,78.77) v1(229.24,78.13) v1(229.24,77.5) v1(229.24,75.59) v1(229.24,74.96) v1(229.24,74.32) v1(229.24,45.36) v1(229.24,44.73) v1(229.24,44.09) v1(229.24,41.55) v1(229.24,40.92) v1(229.24,40.28) v1(229.36,68.35) v1(229.36,67.72) v1(229.36,67.08) v1(229.36,66.45) v1(229.36,65.81) v1(229.36,65.18) v1(229.36,64.54) v1(229.36,63.91) v1(229.36,63.27) v1(229.36,62.64) v1(229.36,62) v1(229.36,57.3) v1(229.36,56.67) v1(229.36,56.03) v1(229.36,55.4) v1(229.36,54.76) v1(229.36,54.13) v1(229.36,53.49) v1(229.36,52.86) v1(229.36,52.22) v1(229.36,51.59) v1(229.36,50.95) v1(229.62,288.16) v1(229.69,141.55) v1(229.87,45.11) v1(229.87,44.48) v1(229.87,43.84) v1(229.87,41.94) v1(229.87,41.3) v1(229.87,40.67) v1(230.05,187.55) v1(230,68.1) v1(230,67.46) v1(230,66.83) v1(230,66.19) v1(230,65.56) v1(230,64.92) v1(230,64.29) v1(230,63.65) v1(230,63.02) v1(230,62.38) v1(230,57.05) v1(230,56.41) v1(230,55.78) v1(230,55.14) v1(230,54.51) v1(230,53.87) v1(230,53.24) v1(230,52.6) v1(230,51.97) v1(230,51.33) v1(230.2,141.94) v1(230.2,141.17) v1(230.25,34.8) v1(230.38,211.07) v1(230.33,146.99) v1(230.61,114.76) v1(230.78,217.86) v1(230.71,186.69) v1(230.71,137.74) v1(230.89,288.16) v1(231.04,131.6) v1(231.22,187.58) v1(231.47,149.71) v1(231.5,186.82) v1(231.57,128.7) v1(231.52,34.8) v1(232.03,186.13) v1(232.16,288.16) v1(232.31,187.78) v1(232.33,186.87) v1(232.36,148.74) v1(232.77,146.51) v1(232.79,34.8) v1(233.13,98.58) v1(233.43,288.16) v1(233.4,155.6) v1(233.41,99.2) v1(233.43,98.01) v1(233.73,196.7) v1(233.79,98.58) v1(234.06,34.8) v1(234.09,99.21) v1(234.12,97.99) v1(234.19,225.45) v1(234.19,200.61) v1(234.37,214.38) v1(234.45,98.58) v1(234.7,288.16) v1(234.73,99.23) v1(234.75,98.01) v1(235.12,98.58) v1(235.15,84.07) v1(235.23,168.05) v1(235.28,144.02) v1(235.36,90.3) v1(235.33,34.8) v1(235.44,99.21) v1(235.46,97.99) v1(235.97,288.16) v1(235.99,273.33) v1(236.32,153.29) v1(236.6,34.8) v1(236.96,276.89) v1(237.01,141.81) v1(237.08,89.38) v1(237.08,84.23) v1(237.24,288.16) v1(237.44,163.8) v1(237.49,154.15) v1(237.69,111.84) v1(237.69,111.12) v1(237.69,110.36) v1(237.85,108.86) v1(237.82,108.13) v1(237.79,107.42) v1(237.87,34.8) v1(238.09,126.11) v1(238.51,288.16) v1(238.63,111.84) v1(238.63,111.12) v1(238.63,110.36) v1(238.75,126.77) v1(238.77,125.43) v1(238.79,108.86) v1(238.76,108.13) v1(238.73,107.42) v1(239.03,152.76) v1(239.14,34.8) v1(239.21,120.13) v1(239.19,118.8) v1(239.43,126.05) v1(239.52,111.81) v1(239.52,111.1) v1(239.52,110.34) v1(239.67,108.84) v1(239.65,108.1) v1(239.62,107.39) v1(239.78,288.16) v1(240.41,287.53) v1(240.41,286.26) v1(240.42,284.99) v1(240.42,283.72) v1(240.42,282.45) v1(240.43,281.18) v1(240.43,279.91) v1(240.43,278.64) v1(240.44,277.37) v1(240.44,276.1) v1(240.44,274.83) v1(240.45,273.56) v1(240.45,272.29) v1(240.45,271.02) v1(240.46,269.75) v1(240.46,268.48) v1(240.46,267.21) v1(240.47,265.94) v1(240.47,264.67) v1(240.48,263.4) v1(240.48,262.13) v1(240.41,260.86) v1(240.41,259.59) v1(240.42,258.32) v1(240.42,257.05) v1(240.42,255.78) v1(240.43,254.51) v1(240.43,253.24) v1(240.43,251.97) v1(240.44,250.7) v1(240.44,249.43) v1(240.44,248.16) v1(240.45,246.89) v1(240.45,245.62) v1(240.45,244.35) v1(240.46,243.08) v1(240.46,241.81) v1(240.46,240.54) v1(240.47,239.27) v1(240.47,238) v1(240.48,236.73) v1(240.48,235.46) v1(240.41,234.19) v1(240.41,232.92) v1(240.42,231.65) v1(240.42,230.38) v1(240.42,229.11) v1(240.43,227.84) v1(240.43,226.57) v1(240.43,225.3) v1(240.44,224.03) v1(240.44,222.76) v1(240.44,221.49) v1(240.45,220.22) v1(240.45,218.95) v1(240.45,217.68) v1(240.46,216.41) v1(240.46,215.14) v1(240.46,213.87) v1(240.47,212.6) v1(240.47,211.33) v1(240.48,210.06) v1(240.48,208.79) v1(240.41,207.52) v1(240.41,206.25) v1(240.42,204.98) v1(240.42,203.71) v1(240.42,202.44) v1(240.43,201.17) v1(240.43,199.9) v1(240.43,198.63) v1(240.44,197.36) v1(240.44,196.09) v1(240.44,194.82) v1(240.45,193.55) v1(240.45,192.28) v1(240.45,191.01) v1(240.46,189.74) v1(240.46,188.47) v1(240.46,187.2) v1(240.47,185.93) v1(240.47,184.66) v1(240.48,183.39) v1(240.48,182.12) v1(240.41,180.85) v1(240.41,179.58) v1(240.42,178.31) v1(240.42,177.04) v1(240.42,175.77) v1(240.43,174.5) v1(240.43,173.23) v1(240.43,171.96) v1(240.44,170.69) v1(240.44,169.42) v1(240.44,168.15) v1(240.45,166.88) v1(240.45,165.61) v1(240.45,164.34) v1(240.46,163.07) v1(240.46,161.8) v1(240.46,160.53) v1(240.47,159.26) v1(240.47,157.99) v1(240.48,156.72) v1(240.48,155.45) v1(240.41,154.18) v1(240.41,152.91) v1(240.42,151.64) v1(240.42,150.37) v1(240.42,149.1) v1(240.43,147.83) v1(240.43,146.56) v1(240.43,145.29) v1(240.44,144.02) v1(240.44,142.75) v1(240.44,141.48) v1(240.45,140.21) v1(240.45,138.94) v1(240.45,137.67) v1(240.46,136.4) v1(240.46,135.13) v1(240.46,133.86) v1(240.47,132.59) v1(240.47,131.32) v1(240.48,130.05) v1(240.48,128.78) v1(240.46,108.46) v1(240.46,107.19) v1(240.47,105.92) v1(240.47,104.65) v1(240.48,103.38) v1(240.48,102.11) v1(240.41,100.84) v1(240.41,99.57) v1(240.42,98.3) v1(240.42,97.03) v1(240.42,95.76) v1(240.43,94.49) v1(240.43,93.22) v1(240.43,91.95) v1(240.44,90.68) v1(240.44,89.41) v1(240.44,88.14) v1(240.45,86.87) v1(240.45,85.6) v1(240.45,84.33) v1(240.46,83.06) v1(240.46,81.79) v1(240.46,80.52) v1(240.47,79.25) v1(240.47,77.98) v1(240.48,76.71) v1(240.48,75.44) v1(240.41,74.17) v1(240.41,72.9) v1(240.42,71.63) v1(240.42,70.36) v1(240.42,69.09) v1(240.43,67.82) v1(240.43,66.55) v1(240.43,65.28) v1(240.44,64.01) v1(240.41,62.74) v1(240.44,61.47) v1(240.45,60.2) v1(240.45,58.93) v1(240.41,57.66) v1(240.41,56.39) v1(240.46,55.12) v1(240.46,53.85) v1(240.47,52.58) v1(240.47,51.31) v1(240.48,50.04) v1(240.48,48.77) v1(240.46,47.5) v1(240.46,46.23) v1(240.47,44.96) v1(240.47,43.69) v1(240.48,42.42) v1(240.48,41.15) v1(240.46,39.88) v1(240.46,38.61) v1(240.47,37.34) v1(240.47,36.07) v1(240.41,34.8) v1(240.49,127.43) v1(240.49,126.16) v1(240.49,124.89) v1(240.5,123.62) v1(240.5,122.35) v1(240.5,121.08) v1(240.51,119.76) v1(240.52,118.49) v1(240.52,117.22) v1(240.52,115.95) v1(240.53,114.68) v1(240.53,113.41) v1(240.55,112.09) v1(240.55,110.82) v2(200.53,136.91) v2(201.85,138.28) v2(203.12,124.64) v2(204.85,136.78) v2(205.51,126.16) v2(205.84,130.15) v2(206.04,138.3) v2(206.6,119.43) v2(206.71,131.04) v2(206.71,130.15) v2(207.06,141.96) v2(207.87,129.34) v2(207.85,128.57) v2(207.86,126.95) v2(207.85,126.15) v2(207.95,138.99) v2(207.9,130.94) v2(209.22,138.99) v2(209.25,131.17) v2(209.35,129.54) v2(209.5,126.16) v2(210.59,131.17) v2(211.09,126.14) v2(211.03,125.35) v2(214.27,131.01) v2(214.3,130.2) v2(214.5,136.73) v2(216.66,130.18) v2(216.65,126.14) v2(217.42,129.34) v2(218.02,132.38) v2(221.01,116.97) v2(221.51,120.55) v3(11.4,58.24) v3(33.45,190.22) v3(47.76,154) v3(47.78,152.7) v3(47.78,151.46) v3(47.78,150.16) v3(47.78,147.62) v3(47.78,145.08) v3(47.78,143.94) v3(47.78,142.54) v3(47.78,141.27) v3(47.78,140) v3(47.78,138.73) v3(47.78,137.46) v3(47.78,136.19) v3(47.78,134.92) v3(47.78,133.78) v3(47.78,132.38) v3(47.78,131.11) v3(47.78,129.84) v3(47.78,128.57) v3(47.78,127.3) v3(47.78,126.03) v3(47.78,124.76) v3(47.78,123.49) v3(47.78,122.22) v3(47.78,120.95) v3(47.78,119.68) v3(47.78,118.54) v3(47.78,117.14) v3(47.78,116) v3(47.78,114.6) v3(47.78,113.33) v3(47.78,112.06) v3(47.78,110.92) v3(47.78,109.52) v3(47.78,108.25) v3(47.78,106.98) v3(47.78,105.71) v3(47.8,148.96) v3(47.79,146.41) v3(48.03,104.32) v3(48.8,103.43) v3(49.13,156.09) v3(50.07,157.02) v3(50.04,102.29) v3(51.13,101.19) v3(51.99,100.3) v3(52.61,159.56) v3(52.91,99.36) v3(53.5,160.43) v3(53.82,98.42) v3(54.36,161.34) v3(54.77,97.46) v3(55.35,162.33) v3(55.53,96.7) v3(56.42,163.37) v3(56.8,95.43) v3(57.69,94.54) v3(58.45,93.77) v3(60,93.56) v3(61.52,93.56) v3(62.79,93.56) v3(63.93,93.56) v3(65.22,93.57) v3(66.43,93.58) v3(67.54,215.24) v3(67.54,214.27) v3(67.78,93.57) v3(68.97,93.58) v3(69.24,215.24) v3(69.24,214.27) v3(69.95,221.56) v3(70.27,93.59) v3(70.71,221.59) v3(71.51,93.58) v3(72.81,93.61) v3(74.09,93.81) v3(75.24,94.32) v3(76.13,95.08) v3(77.01,95.97) v3(77.9,96.99) v3(78.79,97.88) v3(80.87,215.38) v3(80.87,214.42) v3(82.58,215.38) v3(82.58,214.42) v3(88.42,265.13) v3(90.91,255.5) v3(90.91,254.69) v3(129.69,268.15) v3(132.23,221.56) v3(133.35,222.35) v3(133.35,221.56) v3(133.86,267.82) v3(139.24,221.44) v3(139.29,222.25) v3(140.34,221.36) v3(163.98,47.6) v3(164.8,44.91) v3(164.95,47.35) v3(165.58,44.98) v3(170.22,160.69) v3(170.89,95.25) v3(171.49,160.69) v3(171.75,94.41) v3(172.69,93.45) v3(172.88,160.69) v3(173.55,92.61) v3(174.03,160.69) v3(174.62,91.67) v3(175.35,160.68) v3(176.57,160.69) v3(176.95,90.97) v3(177.91,160.68) v3(178.09,90.97) v3(179.11,160.69) v3(179.42,90.96) v3(180.4,160.69) v3(180.63,90.97) v3(181.65,160.69) v3(181.97,90.95) v3(182.94,160.72) v3(183.17,90.97) v3(184.47,90.97) v3(185.71,90.97) v3(186.87,159.89) v3(187,90.99) v3(187.8,159.09) v3(188.19,90.99) v3(188.68,158.21) v3(189.34,92.12) v3(189.6,157.29) v3(189.96,92.64) v3(190.46,156.46) v3(190.6,93.41) v3(191.36,94.04) v3(191.39,155.5) v3(192.26,154.65) v3(192.23,94.88) v3(193.19,153.7) v3(193.55,97.31) v3(194,152.89) v3(194.36,98.09) v3(194.98,151.9) v3(195.2,98.78) v3(195.88,151.01) v3(195.99,99.52) v3(196.88,111.91) v3(196.88,110.64) v3(196.88,109.37) v3(196.88,108.1) v3(196.88,106.83) v3(196.88,105.56) v3(196.88,104.29) v3(196.88,103.15) v3(196.88,101.75) v3(196.9,100.38) v3(197,149.98) v3(197.03,148.69) v3(197.03,147.45) v3(197.03,146.15) v3(197.04,144.95) v3(197.03,143.61) v3(197.03,141.07) v3(197.03,139.93) v3(197.03,138.53) v3(197.03,137.26) v3(197.03,135.99) v3(197.03,134.72) v3(197.03,133.45) v3(197.03,132.18) v3(197.03,130.91) v3(197.03,129.77) v3(197.03,128.37) v3(197.03,127.1) v3(197.03,125.83) v3(197.03,124.56) v3(197.03,123.29) v3(197.03,122.02) v3(197.03,120.75) v3(197.03,119.48) v3(197.03,118.21) v3(197.03,116.94) v3(197.03,115.67) v3(197.03,114.53) v3(197.03,113.13) v3(199.8,257.63) v3(200.63,156.69) v3(202.36,161.98) v3(209.55,147.98) v3(209.65,154.18) v3(210.29,153.87) v3(213.87,59.72) v3(214.88,59.72) v3(215.9,60.48) v3(215.9,59.72) v3(215.9,58.83) v3(216.08,52.72) v3(216.09,57.71) v3(216.09,55.71) v3(216.09,54.71) v3(216.09,53.71) v3(216.09,51.72) v3(216.09,50.71) v3(216.09,49.71) v3(216.09,48.71) v3(216.53,67.72) v3(216.53,66.7) v3(216.53,65.68) v3(216.73,62.71) v3(216.71,54.63) v3(216.73,53.83) v3(216.71,52.72) v3(216.85,64.71) v3(216.85,63.96) v3(216.79,60.48) v3(216.84,59.71) v3(216.84,58.69) v3(216.79,57.81) v3(216.79,55.78) v3(217.85,58.69) v3(217.84,57.96) v3(217.85,53.87) v3(218.57,59.72) v3(220.09,60.73) v3(220.09,59.72) v3(220.14,58.69) v3(220.85,60.71) v3(220.85,59.72) v3(220.85,54.64) v3(220.98,63.65) v3(220.98,61.62) v3(220.9,58.69) v3(220.9,57.8) v3(220.98,55.65) v3(220.98,53.87) v3(221.03,52.72) v3(221.11,65.68) v3(221.11,64.67) v3(221.16,48.66) v3(221.62,70.76) v3(221.62,69.75) v3(221.62,68.73) v3(221.62,67.72) v3(221.62,66.7) v3(221.74,60.6) v3(221.87,59.72) v3(221.87,58.95) v3(222.88,60.6) v3(222.88,59.72) v3(222.88,58.95) v3(223.77,59.72) v3(223.9,60.6) v3(223.9,58.83) v3(224.79,70.64) v3(224.79,69.75) v3(224.79,68.73) v3(224.79,67.72) v3(224.79,66.7) v3(224.79,65.56) v3(224.79,64.67) v3(224.79,63.78) v3(224.79,62.76) v3(224.79,61.75) v3(224.79,60.73) v3(224.79,59.72) v3(224.79,58.7) v3(224.84,57.71) v3(224.84,56.71) v3(224.84,55.69) v3(224.84,54.68) v3(224.84,53.66) v3(224.84,52.77) v3(224.84,51.75) v3(224.84,50.74) v3(224.84,49.72) v3(224.84,48.71) v3(225.68,62.76) v3(225.68,57.81) v3(225.73,56.71) v3(225.73,54.55) v3(225.73,53.79) v3(225.73,51.75) v3(225.73,50.61) v3(225.81,70.64) v3(225.81,69.75) v3(225.81,68.73) v3(225.81,65.56) v3(225.81,64.8) v3(225.81,61.62) v3(225.81,60.73) v3(225.81,59.72) v3(225.81,58.7) v3(225.85,49.72) v3(225.85,48.71) v3(226.82,70.64) v3(226.82,69.75) v3(226.82,68.99) v3(226.82,65.56) v3(226.82,64.92) v3(226.82,61.49) v3(226.82,60.73) v3(226.82,59.72) v3(226.82,58.7) v3(226.82,57.81) v3(226.87,54.55) v3(226.87,53.91) v3(226.87,50.48) v3(226.87,49.72) v3(226.87,48.71) v3(227.84,70.64) v3(227.84,69.75) v3(227.84,68.86) v3(227.84,61.62) v3(227.84,60.73) v3(227.84,59.72) v3(227.84,58.7) v3(227.84,57.81) v3(227.88,54.68) v3(227.88,53.91) v3(227.88,50.61) v3(227.88,49.72) v3(227.88,48.71) v3(227.96,65.56) v3(227.96,64.8) v4(15.29,225.22) v4(15.34,224.56) v4(15.32,223.93) v4(15.32,223.29) v4(15.98,225.22) v4(16.03,224.56) v4(16,223.93) v4(16,223.29) v4(16.69,225.22) v4(16.74,224.56) v4(16.71,223.93) v4(16.71,223.29) v4(17.35,225.22) v4(17.37,223.93) v4(17.37,223.29) v4(17.4,224.56) v4(17.98,225.2) v4(18.03,224.54) v4(18.01,223.9) v4(18.01,223.27) v4(26.34,222.45) v4(28.7,240.72) v4(31.85,201.3) v4(31.85,200.66) v4(31.85,200.02) v4(31.83,198.58) v4(31.83,197.94) v4(31.83,197.31) v4(32.46,198.58) v4(32.46,197.94) v4(32.46,197.31) v4(32.49,201.3) v4(32.49,200.66) v4(32.49,200.02) v4(33.12,201.3) v4(33.12,200.66) v4(33.12,200.02) v4(33.1,198.58) v4(33.1,197.94) v4(33.1,197.31) v4(34.47,201.3) v4(34.47,200.66) v4(34.47,200.02) v4(34.44,198.6) v4(34.44,197.97) v4(34.44,197.33) v4(35.08,198.6) v4(35.08,197.97) v4(35.08,197.33) v4(35.1,201.3) v4(35.1,200.66) v4(35.1,200.02) v4(35.74,201.3) v4(35.74,200.66) v4(35.74,200.02) v4(35.71,198.6) v4(35.71,197.97) v4(35.71,197.33) v4(47.09,219.2) v4(54.74,231.04) v4(54.76,229.74) v4(54.76,229.11) v4(54.79,230.38) v4(55.42,231.04) v4(55.47,230.38) v4(55.45,229.74) v4(55.45,229.11) v4(56.13,231.04) v4(56.18,230.38) v4(56.16,229.74) v4(56.16,229.11) v4(56.79,231.04) v4(56.85,230.38) v4(56.82,229.74) v4(56.82,229.11) v4(57.43,231.01) v4(57.48,230.35) v4(57.45,229.72) v4(57.45,229.08) v4(59.87,237.26) v4(61.03,231.59) v4(61.03,230.14) v4(99.49,15.39) v4(100.57,15.39) v4(100.87,147.07) v4(100.85,143.96) v4(101.78,147.09) v4(101.77,146.29) v4(101.77,145.49) v4(101.75,144.69) v4(101.8,143.98) v4(102.21,19.41) v4(102.66,147.09) v4(102.67,143.96) v4(104.62,96.42) v4(104.65,93.96) v4(104.65,91.27) v4(104.65,88.58) v4(104.65,85.88) v4(104.65,83.19) v4(104.65,80.49) v4(104.65,77.8) v4(104.65,75.11) v4(104.65,72.41) v4(107.19,96.47) v4(107.19,93.96) v4(107.19,91.27) v4(107.19,88.58) v4(107.19,85.88) v4(107.19,83.19) v4(107.19,80.49) v4(107.19,77.8) v4(107.31,33.43) v4(110.05,199.83) v4(110.03,196.68) v4(110.44,198.97) v4(110.5,199.81) v4(110.52,198.21) v4(110.52,197.47) v4(110.54,196.7) v4(111.1,134.53) v4(111.1,120.93) v4(111.91,136.14) v4(111.9,135.33) v4(111.9,132.13) v4(111.9,129.73) v4(111.9,128.93) v4(111.9,120.93) v4(112.7,135.33) v4(112.7,133.73) v4(112.7,132.93) v4(112.7,132.13) v4(112.7,131.33) v4(112.7,130.53) v4(112.7,129.73) v4(112.7,128.93) v4(112.7,128.13) v4(112.7,127.33) v4(112.7,124.15) v4(112.7,123.33) v4(112.7,122.53) v4(113.51,135.36) v4(113.5,131.33) v4(113.5,130.53) v4(113.5,129.73) v4(113.5,128.13) v4(113.5,125.73) v4(113.5,124.15) v4(114.12,71.63) v4(114.15,70.54) v4(114.3,135.33) v4(114.3,134.53) v4(114.3,132.93) v4(114.3,132.13) v4(114.3,131.33) v4(114.3,129.73) v4(114.3,128.13) v4(114.3,125.73) v4(114.3,124.15) v4(114.3,117.73) v4(114.55,136.07) v4(114.81,96.55) v4(114.81,93.96) v4(114.81,91.27) v4(114.81,88.58) v4(114.81,85.88) v4(114.81,83.19) v4(114.81,80.49) v4(114.81,77.8) v4(114.81,75.11) v4(115.1,135.33) v4(115.1,134.53) v4(115.1,133.73) v4(115.1,132.93) v4(115.1,132.13) v4(115.1,131.33) v4(115.1,130.53) v4(115.1,129.73) v4(115.1,128.13) v4(115.1,125.73) v4(115.1,124.13) v4(115.1,120.13) v4(115.9,135.33) v4(115.9,134.53) v4(115.9,132.93) v4(115.9,132.13) v4(115.9,128.13) v4(115.9,125.73) v4(115.9,120.13) v4(116.7,132.93) v4(116.7,132.13) v4(116.7,131.33) v4(116.7,130.53) v4(116.7,129.73) v4(116.7,128.93) v4(116.7,128.13) v4(116.7,127.33) v4(116.7,126.53) v4(116.7,125.73) v4(116.7,124.93) v4(116.7,124.13) v4(116.7,122.53) v4(116.7,121.73) v4(116.7,120.93) v4(116.7,120.13) v4(117.27,96.55) v4(117.35,93.96) v4(117.35,91.27) v4(117.35,88.58) v4(117.35,85.88) v4(117.35,83.19) v4(117.35,80.49) v4(117.35,77.8) v4(117.35,75.11) v4(117.5,133.73) v4(117.5,132.93) v4(117.5,130.53) v4(117.5,129.73) v4(117.5,128.13) v4(117.5,125.73) v4(117.5,124.13) v4(117.5,120.14) v4(118.14,62.61) v4(118.21,65.07) v4(118.3,135.33) v4(118.3,132.93) v4(118.3,131.33) v4(118.3,129.73) v4(118.38,128.93) v4(118.3,127.33) v4(118.3,126.53) v4(118.3,124.93) v4(118.3,124.13) v4(118.3,120.13) v4(118.3,117.73) v4(118.54,8.53) v4(119.1,135.33) v4(119.1,132.93) v4(119.1,131.33) v4(119.1,129.73) v4(119.1,128.13) v4(119.1,122.53) v4(119.1,120.13) v4(119.1,119.33) v4(119.9,135.33) v4(119.9,132.93) v4(119.9,131.33) v4(119.9,129.73) v4(119.9,128.13) v4(119.9,126.53) v4(119.9,124.93) v4(119.9,122.53) v4(119.9,121.73) v4(119.9,120.93) v4(119.9,120.13) v4(120.7,135.33) v4(120.7,132.93) v4(120.7,131.33) v4(120.7,129.73) v4(120.7,128.13) v4(120.7,126.53) v4(120.7,124.93) v4(120.7,120.13) v4(120.7,119.33) v4(121.54,138.23) v4(121.5,135.33) v4(121.5,134.53) v4(121.5,132.93) v4(121.5,130.53) v4(121.5,129.73) v4(121.5,128.93) v4(121.5,128.13) v4(121.5,126.53) v4(121.5,124.93) v4(121.5,122.53) v4(121.5,120.13) v4(121.5,117.73) v4(121.62,137.73) v4(121.77,137.26) v4(122.3,134.53) v4(122.3,132.93) v4(122.3,132.13) v4(122.3,131.33) v4(122.3,130.53) v4(122.3,128.13) v4(122.3,126.53) v4(122.3,124.93) v4(122.3,123.33) v4(122.3,122.53) v4(122.3,120.13) v4(122.3,119.33) v4(123.1,136.13) v4(123.1,135.33) v4(123.1,134.53) v4(123.1,132.93) v4(123.1,130.53) v4(123.1,129.73) v4(123.1,128.93) v4(123.1,128.13) v4(123.1,126.53) v4(123.1,124.93) v4(123.1,122.53) v4(123.1,120.13) v4(123.1,117.73) v4(123.62,137.29) v4(123.88,138.23) v4(123.79,137.73) v4(123.9,136.93) v4(123.9,136.13) v4(123.9,135.33) v4(123.9,132.93) v4(123.9,131.33) v4(123.9,129.73) v4(123.9,128.13) v4(123.9,126.53) v4(123.9,124.93) v4(123.9,120.13) v4(124.7,136.93) v4(124.7,136.13) v4(124.7,135.33) v4(124.7,132.93) v4(124.7,131.33) v4(124.7,129.73) v4(124.7,128.13) v4(124.7,126.53) v4(124.7,124.93) v4(124.7,122.53) v4(124.7,121.73) v4(124.7,120.93) v4(124.7,120.13) v4(124.89,96.62) v4(124.97,93.96) v4(124.97,91.27) v4(124.97,88.58) v4(124.97,85.88) v4(124.97,83.19) v4(124.92,80.54) v4(125.5,136.93) v4(125.5,136.13) v4(125.5,135.33) v4(125.5,132.93) v4(125.5,131.33) v4(125.5,129.73) v4(125.5,128.13) v4(125.5,122.53) v4(125.5,120.13) v4(125.5,119.33) v4(126.3,136.93) v4(126.3,136.13) v4(126.3,135.33) v4(126.3,132.93) v4(126.3,131.33) v4(126.3,129.73) v4(126.3,128.93) v4(126.3,127.33) v4(126.3,126.53) v4(126.3,124.93) v4(126.3,124.13) v4(126.3,120.13) v4(126.3,117.73) v4(126.64,70.46) v4(126.67,69.42) v4(127.1,133.73) v4(127.1,132.93) v4(127.1,130.53) v4(127.1,129.73) v4(127.1,128.13) v4(127.1,125.73) v4(127.1,124.13) v4(127.1,120.13) v4(127.46,96.65) v4(127.51,93.96) v4(127.51,91.27) v4(127.51,88.58) v4(127.51,85.88) v4(127.51,83.19) v4(127.53,80.59) v4(127.9,135.33) v4(127.9,134.53) v4(127.9,132.93) v4(127.9,132.13) v4(127.9,131.33) v4(127.9,130.53) v4(127.9,129.73) v4(127.9,128.93) v4(127.9,128.13) v4(127.9,127.33) v4(127.9,126.53) v4(127.9,125.73) v4(127.9,124.93) v4(127.9,124.13) v4(127.9,122.53) v4(127.9,121.73) v4(127.9,120.93) v4(127.9,120.13) v4(128.7,135.33) v4(128.7,134.53) v4(128.7,132.93) v4(128.7,132.13) v4(128.7,128.13) v4(128.7,125.73) v4(128.7,120.13) v4(129.5,135.33) v4(129.5,134.53) v4(129.5,133.73) v4(129.5,132.93) v4(129.5,132.13) v4(129.5,131.33) v4(129.5,130.53) v4(129.5,129.73) v4(129.5,128.13) v4(129.5,125.73) v4(129.5,124.13) v4(129.5,120.13) v4(129.97,73.86) v4(130.1,136.17) v4(130.3,135.33) v4(130.3,134.53) v4(130.3,132.93) v4(130.3,132.13) v4(130.3,131.33) v4(130.3,129.73) v4(130.3,128.13) v4(130.3,125.73) v4(130.3,124.13) v4(130.3,117.73) v4(130.71,72.09) v4(131.1,135.33) v4(131.1,131.33) v4(131.1,130.53) v4(131.1,129.73) v4(131.1,125.73) v4(131.1,124.13) v4(131.9,135.33) v4(131.9,133.73) v4(131.9,132.93) v4(131.9,132.13) v4(131.9,131.33) v4(131.9,130.53) v4(131.9,129.73) v4(131.9,128.93) v4(131.9,128.13) v4(131.9,127.33) v4(131.9,124.13) v4(131.9,123.33) v4(131.9,122.53) v4(131.9,120.93) v4(132.7,135.33) v4(132.7,128.93) v4(132.7,123.33) v4(132.7,122.53) v4(132.7,120.93) v4(132.84,135.76) v4(133.5,137.73) v4(133.5,136.93) v4(133.5,134.53) v4(133.5,120.93) v4(135.13,96.66) v4(135.13,93.96) v4(135.13,91.27) v4(135.13,88.58) v4(135.13,85.88) v4(135.13,83.19) v4(135.13,80.49) v4(137.19,71.83) v4(137.67,96.66) v4(137.67,93.96) v4(137.67,91.27) v4(137.67,88.58) v4(137.67,85.88) v4(137.67,83.19) v4(137.67,80.49) v4(137.67,77.8) v4(137.67,75.11) v4(137.62,74.09) v4(139.28,197) v4(139.29,200.15) v4(139.75,200.13) v4(139.69,199.29) v4(139.76,198.53) v4(139.76,197.79) v4(139.79,197.02) v4(141.96,11.76) v4(141.94,8.81) v4(142.58,143.74) v4(142.6,146.84) v4(143.48,144.46) v4(143.51,146.86) v4(143.5,146.06) v4(143.5,145.26) v4(143.54,143.75) v4(144.39,146.87) v4(144.4,143.73) v4(145.29,88.58) v4(145.29,85.88) v4(146.49,10.24) v4(147.19,218.54) v4(147.19,216.54) v4(147.83,88.58) v4(147.83,85.88) v4(148.26,218.52) v4(148.26,216.51) v4(150.19,218.49) v4(150.19,216.51) v4(151.21,218.52) v4(151.21,216.51) v4(174.8,100.43) v4(176.81,103.84) v4(191.36,195.05) v4(191.41,194.41) v4(191.41,193.73) v4(192.02,194.97) v4(192.2,119.44) v4(194.49,191.54) v4(195.15,192.02) v4(196.98,195.5) v4(197,194.77) v4(197,194.26) v4(197.03,193.52) v4(197.05,192.71) v4(197.15,189.97) v4(197.26,195.15) v4(197.28,193.9) v4(197.31,193.09) v4(197.51,195.5) v4(197.54,194.77) v4(197.54,194.26) v4(197.56,193.52) v4(197.59,192.71) v4(197.76,195.15) v4(197.79,193.9) v4(197.82,193.09) v4(197.82,189.97) v4(198.07,195.5) v4(198.09,194.77) v4(198.09,194.26) v4(198.12,193.52) v4(198.15,192.71) v4(199.69,196.98) v4(200.61,197.71) v4(201.52,197) v4(202,194.06) v4(239.34,151.26) v5(69.95,177.19) v5(69.95,175.62) v5(70.64,175.64) v5(70.82,177.42) v5(71.37,177.24) v5(71.3,175.72) v5(71.73,176.89) v5(71.84,175.92) v5(72.24,176.89) v5(72.34,175.92) v5(72.75,176.89) v5(72.85,175.92) v5(73.25,176.89) v5(73.36,175.92) v5(73.76,176.89) v5(73.87,175.92) v5(74.27,176.89) v5(74.38,175.92) v5(74.78,176.89) v5(74.88,175.92) v5(75.29,176.89) v5(75.39,175.92) v5(75.79,176.89) v5(75.9,175.92) v5(76.3,176.89) v5(76.41,175.92) v5(76.81,176.89) v5(76.92,175.92) v5(77.32,176.89) v5(77.42,175.92) v5(77.83,176.89) v5(77.93,175.92) v5(78.33,176.89) v5(78.44,175.92) v5(78.84,176.89) v5(78.92,192.66) v5(78.95,175.92) v5(79.35,176.89) v5(79.4,192.33) v5(79.46,175.92) v5(79.86,193.8) v5(79.86,176.89) v5(79.96,175.92) v5(80.06,191.97) v5(80.37,176.89) v5(80.47,175.92) v5(80.65,191.62) v5(80.75,193.52) v5(80.87,176.89) v5(80.98,175.92) v5(81.03,193.01) v5(81.08,192.53) v5(81.03,191.29) v5(81.38,176.89) v5(81.46,192.21) v5(81.42,190.96) v5(81.49,175.92) v5(81.85,191.88) v5(81.81,190.63) v5(81.89,176.89) v5(82,175.92) v5(82.24,191.55) v5(82.2,190.3) v5(82.4,176.89) v5(82.5,175.92) v5(82.63,191.22) v5(82.59,189.98) v5(82.97,189.65) v5(82.91,176.89) v5(83.02,190.89) v5(83.01,175.92) v5(83.36,189.32) v5(83.4,190.57) v5(83.41,176.89) v5(83.52,175.92) v5(83.75,188.99) v5(83.79,190.24) v5(83.92,176.89) v5(84.03,175.92) v5(84.18,189.91) v5(84.14,188.67) v5(84.43,176.89) v5(84.57,189.58) v5(84.53,188.34) v5(84.54,175.92) v5(84.96,189.25) v5(84.91,188.01) v5(84.94,176.89) v5(85.04,175.92) v5(85.35,188.93) v5(85.3,187.68) v5(85.45,176.89) v5(85.55,175.92) v5(85.73,188.6) v5(85.69,187.35) v5(85.95,176.89) v5(86.08,187.03) v5(86.06,175.92) v5(86.12,188.27) v5(86.47,186.7) v5(86.46,176.89) v5(86.51,187.94) v5(86.57,175.92) v5(86.86,186.37) v5(86.9,187.62) v5(86.97,176.89) v5(87.08,175.92) v5(87.29,187.29) v5(87.24,186.04) v5(87.48,176.88) v5(87.58,175.91) v5(87.67,186.96) v5(87.63,185.71) v5(87.99,176.86) v5(88.06,186.63) v5(88.02,185.39) v5(88.09,175.89) v5(88.45,186.3) v5(88.41,185.06) v5(88.49,176.83) v5(88.6,175.85) v5(88.84,185.98) v5(88.8,184.73) v5(89,176.79) v5(89.18,184.4) v5(89.1,175.8) v5(89.23,185.65) v5(89.57,184.08) v5(89.5,176.72) v5(89.61,185.32) v5(89.61,175.74) v5(89.96,183.75) v5(90,184.99) v5(90,176.65) v5(90.11,175.65) v5(90.35,183.42) v5(90.39,184.66) v5(90.5,176.56) v5(90.61,175.56) v5(90.78,184.34) v5(90.74,183.09) v5(91,176.46) v5(91.17,184.01) v5(91.12,182.76) v5(91.1,175.44) v5(91.55,183.68) v5(91.51,182.44) v5(91.5,176.34) v5(91.59,175.32) v5(91.94,183.35) v5(91.9,182.11) v5(91.99,176.21) v5(92.08,175.18) v5(92.33,183.03) v5(92.29,181.78) v5(92.47,176.07) v5(92.57,175.02) v5(92.68,181.45) v5(92.72,182.7) v5(92.96,175.91) v5(93.06,181.12) v5(93.04,174.85) v5(93.11,182.37) v5(93.45,180.8) v5(93.43,175.73) v5(93.49,182.04) v5(93.52,174.67) v5(93.88,181.71) v5(93.84,180.47) v5(93.91,175.55) v5(93.99,174.47) v5(94.18,202.79) v5(94.27,181.39) v5(94.23,180.14) v5(94.38,175.35) v5(94.45,174.26) v5(94.66,181.06) v5(94.62,179.81) v5(94.72,202.34) v5(94.84,175.14) v5(94.97,201.83) v5(94.9,174.03) v5(95.05,180.73) v5(95,179.49) v5(95.37,201.57) v5(95.29,174.91) v5(95.35,173.79) v5(95.43,180.4) v5(95.39,179.16) v5(95.63,203.5) v5(95.62,201.12) v5(95.78,178.83) v5(95.74,174.68) v5(95.86,200.68) v5(95.82,180.07) v5(95.79,173.54) v5(95.91,202.95) v5(96.06,202.51) v5(96.1,200.23) v5(96.17,178.5) v5(96.18,174.43) v5(96.23,202.04) v5(96.21,179.75) v5(96.22,173.27) v5(96.35,199.79) v5(96.48,201.59) v5(96.56,178.17) v5(96.59,199.34) v5(96.6,179.42) v5(96.62,174.16) v5(96.65,172.99) v5(96.72,201.15) v5(96.84,198.89) v5(96.96,200.7) v5(96.99,179.09) v5(96.94,177.85) v5(97.08,198.45) v5(97.05,173.89) v5(97.07,172.7) v5(97.21,200.25) v5(97.32,198) v5(97.37,178.76) v5(97.33,177.52) v5(97.45,199.81) v5(97.47,173.6) v5(97.47,172.4) v5(97.57,197.56) v5(97.69,199.36) v5(97.76,178.44) v5(97.72,177.19) v5(97.81,197.11) v5(97.88,173.3) v5(97.87,172.08) v5(97.94,198.92) v5(98.05,196.67) v5(98.18,198.47) v5(98.15,178.11) v5(98.11,176.86) v5(98.28,172.99) v5(98.26,171.76) v5(98.3,196.22) v5(98.43,198.03) v5(98.54,195.77) v5(98.54,177.78) v5(98.5,176.53) v5(98.67,197.58) v5(98.67,172.67) v5(98.64,171.42) v5(98.79,195.33) v5(98.88,176.21) v5(98.91,197.13) v5(98.93,177.45) v5(99.03,194.88) v5(99.06,172.34) v5(99.01,171.07) v5(99.16,196.69) v5(99.27,194.44) v5(99.27,175.88) v5(99.31,177.12) v5(99.37,170.71) v5(99.4,196.24) v5(99.43,172) v5(99.52,193.99) v5(99.64,195.8) v5(99.66,175.55) v5(99.76,193.54) v5(99.7,176.8) v5(99.73,170.35) v5(99.8,171.65) v5(99.89,195.35) v5(100,193.1) v5(100.05,175.22) v5(100.09,169.99) v5(100.13,194.91) v5(100.09,176.47) v5(100.16,171.29) v5(100.25,192.65) v5(100.37,194.46) v5(100.48,176.14) v5(100.44,174.9) v5(100.45,169.63) v5(100.49,192.21) v5(100.52,170.93) v5(100.62,194.01) v5(100.74,191.76) v5(100.86,193.57) v5(100.87,175.81) v5(100.82,174.57) v5(100.88,170.57) v5(100.8,169.27) v5(100.98,191.32) v5(101.11,193.12) v5(101.16,168.92) v5(101.22,190.87) v5(101.25,175.48) v5(101.21,174.24) v5(101.23,170.21) v5(101.35,192.68) v5(101.47,190.42) v5(101.52,168.56) v5(101.59,192.23) v5(101.64,175.16) v5(101.6,173.91) v5(101.59,169.85) v5(101.71,189.98) v5(101.84,191.79) v5(101.88,168.2) v5(101.95,189.53) v5(101.95,169.49) v5(102.08,191.34) v5(102.03,174.83) v5(101.99,173.58) v5(102.2,189.09) v5(102.24,167.84) v5(102.32,190.89) v5(102.38,173.26) v5(102.31,169.13) v5(102.44,188.64) v5(102.42,174.5) v5(102.57,190.45) v5(102.68,188.2) v5(102.67,168.77) v5(102.6,167.48) v5(102.77,172.93) v5(102.81,190) v5(102.81,174.17) v5(102.93,187.75) v5(102.96,167.12) v5(103.06,189.56) v5(103.03,168.41) v5(103.17,187.3) v5(103.16,172.61) v5(103.19,173.85) v5(103.3,189.11) v5(103.32,166.76) v5(103.42,186.86) v5(103.39,168.05) v5(103.54,188.67) v5(103.55,172.28) v5(103.66,186.41) v5(103.59,173.52) v5(103.68,166.4) v5(103.75,167.69) v5(103.79,188.22) v5(103.9,185.97) v5(103.98,173.2) v5(103.93,171.94) v5(104.03,187.77) v5(104.04,166.04) v5(104.15,185.52) v5(104.11,167.34) v5(104.27,187.33) v5(104.36,172.86) v5(104.3,171.6) v5(104.39,185.08) v5(104.47,166.98) v5(104.4,165.68) v5(104.52,186.88) v5(104.63,184.63) v5(104.67,171.25) v5(104.76,186.44) v5(104.74,172.52) v5(104.76,165.32) v5(104.88,184.18) v5(104.83,166.62) v5(105,185.99) v5(105.03,170.89) v5(105.12,183.74) v5(105.11,172.18) v5(105.11,164.96) v5(105.25,185.54) v5(105.19,166.26) v5(105.37,183.29) v5(105.48,171.83) v5(105.39,170.53) v5(105.47,164.6) v5(105.49,185.1) v5(105.55,165.9) v5(105.61,182.85) v5(105.74,184.65) v5(105.74,170.16) v5(105.85,182.4) v5(105.84,171.47) v5(105.81,164.23) v5(105.98,184.21) v5(105.9,165.54) v5(106.08,169.79) v5(106.1,181.96) v5(106.15,163.84) v5(106.22,183.76) v5(106.19,171.11) v5(106.25,165.17) v5(106.34,181.51) v5(106.47,183.32) v5(106.42,169.41) v5(106.48,163.46) v5(106.58,181.06) v5(106.54,170.74) v5(106.6,164.8) v5(106.71,182.87) v5(106.75,169.02) v5(106.83,180.62) v5(106.88,170.36) v5(106.79,163.06) v5(106.95,182.42) v5(106.93,164.41) v5(107.07,180.17) v5(107.07,168.63) v5(107.1,162.65) v5(107.2,181.98) v5(107.22,169.98) v5(107.26,164.02) v5(107.31,179.73) v5(107.44,181.53) v5(107.39,168.24) v5(107.4,162.24) v5(107.56,179.28) v5(107.55,169.59) v5(107.57,163.63) v5(107.69,181.09) v5(107.7,167.84) v5(107.69,161.83) v5(107.8,178.84) v5(107.87,169.2) v5(107.88,163.22) v5(107.93,180.64) v5(107.97,161.4) v5(108.05,178.39) v5(108.01,167.43) v5(108.17,180.2) v5(108.18,162.81) v5(108.19,168.8) v5(108.24,160.97) v5(108.29,177.94) v5(108.3,167.02) v5(108.42,179.75) v5(108.47,162.39) v5(108.53,177.5) v5(108.5,168.4) v5(108.5,160.53) v5(108.66,179.3) v5(108.59,166.6) v5(108.78,177.05) v5(108.75,161.97) v5(108.75,160.09) v5(108.8,168) v5(108.88,166.18) v5(108.9,178.86) v5(108.98,159.64) v5(109.02,176.61) v5(109.02,161.54) v5(109.15,178.41) v5(109.1,167.58) v5(109.15,165.75) v5(109.26,176.16) v5(109.28,161.1) v5(109.21,159.19) v5(109.39,177.97) v5(109.39,167.17) v5(109.42,165.32) v5(109.43,158.73) v5(109.51,175.72) v5(109.53,160.66) v5(109.63,177.52) v5(109.67,166.74) v5(109.68,164.88) v5(109.64,158.27) v5(109.75,175.27) v5(109.77,160.22) v5(109.88,177.08) v5(109.83,157.8) v5(109.95,166.32) v5(109.94,164.44) v5(109.98,139.62) v5(109.99,174.82) v5(110.01,159.76) v5(110.02,157.32) v5(110.12,176.63) v5(110.18,164) v5(110.24,174.38) v5(110.22,165.89) v5(110.23,159.31) v5(110.19,156.85) v5(110.37,176.18) v5(110.35,156.37) v5(110.48,173.93) v5(110.48,165.45) v5(110.42,163.55) v5(110.44,158.84) v5(110.5,155.88) v5(110.61,175.74) v5(110.65,163.1) v5(110.64,158.38) v5(110.64,155.39) v5(110.73,173.49) v5(110.74,165.01) v5(110.77,154.9) v5(110.82,207.7) v5(110.85,175.29) v5(110.88,162.64) v5(110.83,157.91) v5(110.97,207.11) v5(110.97,173.04) v5(110.99,164.57) v5(110.89,154.41) v5(111.01,157.43) v5(110.99,153.91) v5(111.18,206.53) v5(111.1,174.85) v5(111.09,162.18) v5(111.17,156.95) v5(111.09,153.41) v5(111.17,152.91) v5(111.1,137.73) v5(111.1,136.93) v5(111.1,117.73) v5(111.1,116.93) v5(111.1,114.53) v5(111.1,113.73) v5(111.21,172.6) v5(111.23,164.12) v5(111.24,152.41) v5(111.34,174.4) v5(111.3,161.72) v5(111.33,156.47) v5(111.3,151.9) v5(111.35,151.39) v5(111.38,150.89) v5(111.46,206.21) v5(111.45,172.15) v5(111.46,163.67) v5(111.48,155.98) v5(111.4,150.38) v5(111.41,149.87) v5(111.42,149.36) v5(111.42,148.86) v5(111.42,148.35) v5(111.42,147.84) v5(111.42,147.33) v5(111.42,146.82) v5(111.42,146.32) v5(111.42,145.81) v5(111.42,145.3) v5(111.42,144.79) v5(111.42,144.28) v5(111.42,143.78) v5(111.42,143.27) v5(111.42,142.76) v5(111.42,142.25) v5(111.42,141.74) v5(111.42,141.24) v5(111.42,140.73) v5(111.42,140.22) v5(111.42,139.71) v5(111.42,139.2) v5(111.42,138.7) v5(111.42,138.19) v5(111.58,173.96) v5(111.5,161.25) v5(111.62,205.73) v5(111.67,171.69) v5(111.69,163.22) v5(111.62,155.49) v5(111.69,160.78) v5(111.74,155) v5(111.79,205.25) v5(111.83,173.51) v5(111.87,160.31) v5(111.85,154.51) v5(111.96,208.15) v5(111.95,204.77) v5(111.89,171.23) v5(111.9,162.76) v5(111.96,154.01) v5(111.9,136.93) v5(111.9,119.33) v5(111.9,118.53) v5(111.9,116.13) v5(111.9,115.33) v5(112.07,173.06) v5(112.05,159.83) v5(112.05,153.51) v5(112.12,204.29) v5(112.1,170.77) v5(112.11,162.3) v5(112.13,153.01) v5(112.19,207.57) v5(112.28,203.81) v5(112.22,159.35) v5(112.2,152.5) v5(112.26,152) v5(112.34,206.98) v5(112.38,206.53) v5(112.31,172.61) v5(112.31,170.3) v5(112.32,161.83) v5(112.38,158.87) v5(112.31,151.49) v5(112.34,150.99) v5(112.37,150.48) v5(112.38,149.97) v5(112.38,149.46) v5(112.38,148.95) v5(112.38,148.45) v5(112.38,147.94) v5(112.38,147.43) v5(112.38,146.92) v5(112.38,146.41) v5(112.38,145.91) v5(112.38,145.4) v5(112.38,144.89) v5(112.38,144.38) v5(112.38,143.87) v5(112.38,143.37) v5(112.38,142.86) v5(112.38,142.35) v5(112.38,141.84) v5(112.38,141.33) v5(112.38,140.83) v5(112.38,140.32) v5(112.38,139.81) v5(112.38,139.3) v5(112.38,138.79) v5(112.38,138.29) v5(112.44,203.33) v5(112.55,206.05) v5(112.53,172.16) v5(112.51,169.84) v5(112.51,161.36) v5(112.53,158.38) v5(112.61,202.85) v5(112.67,157.9) v5(112.71,205.57) v5(112.77,202.37) v5(112.75,171.7) v5(112.71,169.37) v5(112.7,160.89) v5(112.7,137.73) v5(112.7,136.93) v5(112.7,120.93) v5(112.7,120.13) v5(112.7,117.73) v5(112.7,116.93) v5(112.7,114.53) v5(112.7,113.73) v5(112.88,205.09) v5(112.88,160.41) v5(112.81,157.41) v5(112.94,201.89) v5(112.96,171.24) v5(112.9,168.9) v5(112.93,156.91) v5(113.04,204.61) v5(113.08,168.43) v5(113.05,159.93) v5(113.05,156.42) v5(113.1,201.41) v5(113.17,170.77) v5(113.16,155.92) v5(113.21,204.13) v5(113.26,200.93) v5(113.27,167.95) v5(113.21,159.45) v5(113.26,155.43) v5(113.37,203.65) v5(113.37,170.31) v5(113.37,158.97) v5(113.35,154.93) v5(113.43,200.45) v5(113.44,167.48) v5(113.44,154.43) v5(113.53,203.17) v5(113.57,169.84) v5(113.52,158.48) v5(113.51,153.92) v5(113.58,153.42) v5(113.5,137.73) v5(113.5,136.93) v5(113.5,134.53) v5(113.5,120.13) v5(113.5,119.33) v5(113.5,118.53) v5(113.5,116.13) v5(113.5,115.33) v5(113.59,199.97) v5(113.61,167) v5(113.66,158) v5(113.64,152.92) v5(113.7,202.68) v5(113.76,199.48) v5(113.76,169.37) v5(113.78,166.52) v5(113.69,152.41) v5(113.73,151.9) v5(113.76,151.4) v5(113.86,202.2) v5(113.79,157.51) v5(113.79,150.89) v5(113.8,150.38) v5(113.81,149.87) v5(113.81,149.37) v5(113.81,148.86) v5(113.81,148.35) v5(113.81,147.84) v5(113.81,147.33) v5(113.81,146.83) v5(113.81,146.32) v5(113.81,145.81) v5(113.81,145.3) v5(113.81,144.79) v5(113.81,144.29) v5(113.81,143.78) v5(113.81,143.27) v5(113.81,142.76) v5(113.81,142.25) v5(113.81,141.75) v5(113.81,141.24) v5(113.81,140.73) v5(113.81,140.22) v5(113.81,139.71) v5(113.81,139.21) v5(113.81,138.7) v5(113.81,138.19) v5(113.92,199) v5(113.95,168.9) v5(113.94,166.03) v5(113.91,157.01) v5(114.03,201.72) v5(114.09,198.52) v5(114.03,156.52) v5(114.13,168.42) v5(114.09,165.55) v5(114.14,156.02) v5(114.19,201.24) v5(114.25,198.04) v5(114.24,165.06) v5(114.24,155.52) v5(114.35,200.76) v5(114.31,167.95) v5(114.33,155.02) v5(114.3,136.93) v5(114.3,119.33) v5(114.3,118.53) v5(114.3,116.93) v5(114.3,114.53) v5(114.3,113.73) v5(114.41,197.56) v5(114.48,167.47) v5(114.39,164.58) v5(114.41,154.52) v5(114.52,200.28) v5(114.58,197.08) v5(114.53,164.09) v5(114.49,154.02) v5(114.55,153.52) v5(114.68,199.8) v5(114.65,166.99) v5(114.66,163.6) v5(114.61,153.01) v5(114.66,152.51) v5(114.74,196.6) v5(114.7,152) v5(114.74,151.49) v5(114.76,150.99) v5(114.78,150.48) v5(114.85,199.32) v5(114.81,166.51) v5(114.79,163.11) v5(114.79,149.97) v5(114.79,149.46) v5(114.79,148.95) v5(114.79,148.45) v5(114.79,147.94) v5(114.79,147.43) v5(114.79,146.92) v5(114.79,146.41) v5(114.79,145.91) v5(114.79,145.4) v5(114.79,144.89) v5(114.79,144.38) v5(114.79,143.87) v5(114.79,143.37) v5(114.79,142.86) v5(114.79,142.35) v5(114.79,141.84) v5(114.79,141.33) v5(114.79,140.83) v5(114.79,140.32) v5(114.79,139.81) v5(114.79,139.3) v5(114.79,138.79) v5(114.79,138.29) v5(114.91,196.12) v5(114.97,166.03) v5(114.91,162.61) v5(115.01,198.84) v5(115.07,195.64) v5(115.03,162.12) v5(115.18,198.36) v5(115.12,165.54) v5(115.14,161.62) v5(115.1,136.93) v5(115.1,136.13) v5(115.1,119.33) v5(115.1,118.53) v5(115.1,116.13) v5(115.1,115.33) v5(115.23,195.16) v5(115.27,165.05) v5(115.24,161.13) v5(115.34,197.88) v5(115.34,160.63) v5(115.4,194.68) v5(115.41,164.57) v5(115.44,160.13) v5(115.5,197.4) v5(115.56,194.2) v5(115.54,164.08) v5(115.53,159.63) v5(115.67,196.92) v5(115.67,163.59) v5(115.61,159.13) v5(115.71,193.71) v5(115.69,158.63) v5(115.77,158.13) v5(115.83,196.43) v5(115.84,193.22) v5(115.8,163.09) v5(115.83,157.62) v5(115.98,192.73) v5(115.92,162.6) v5(115.89,157.12) v5(115.95,156.61) v5(115.9,136.93) v5(115.9,136.13) v5(115.9,117.73) v5(115.9,116.93) v5(115.9,116.13) v5(115.9,115.33) v5(115.9,114.53) v5(115.9,113.73) v5(116,195.95) v5(116.03,162.11) v5(116,156.11) v5(116.05,155.6) v5(116.16,195.47) v5(116.1,192.24) v5(116.14,161.61) v5(116.09,155.09) v5(116.12,154.59) v5(116.15,154.08) v5(116.17,153.57) v5(116.23,191.75) v5(116.25,161.11) v5(116.19,153.07) v5(116.2,152.56) v5(116.21,152.05) v5(116.21,151.54) v5(116.21,151.03) v5(116.21,150.53) v5(116.21,150.02) v5(116.21,149.51) v5(116.21,149) v5(116.21,148.49) v5(116.21,147.99) v5(116.21,147.48) v5(116.21,146.97) v5(116.21,146.46) v5(116.21,145.95) v5(116.21,145.45) v5(116.21,144.94) v5(116.21,144.43) v5(116.21,143.92) v5(116.21,143.41) v5(116.21,142.91) v5(116.21,142.4) v5(116.21,141.89) v5(116.21,141.38) v5(116.21,140.87) v5(116.21,140.37) v5(116.21,139.86) v5(116.21,139.35) v5(116.21,138.84) v5(116.21,138.33) v5(116.32,194.99) v5(116.35,191.25) v5(116.34,160.61) v5(116.47,190.76) v5(116.44,160.11) v5(116.49,194.51) v5(116.52,159.61) v5(116.64,194.03) v5(116.59,190.26) v5(116.61,159.11) v5(116.68,158.61) v5(116.77,193.54) v5(116.7,189.77) v5(116.75,158.11) v5(116.7,136.93) v5(116.7,136.13) v5(116.7,119.33) v5(116.7,118.53) v5(116.7,117.73) v5(116.7,116.93) v5(116.7,114.53) v5(116.7,113.73) v5(116.81,189.27) v5(116.82,157.6) v5(116.88,157.1) v5(116.9,193.05) v5(116.92,188.78) v5(116.94,156.59) v5(117.03,192.55) v5(117.02,188.28) v5(116.99,156.09) v5(117.03,155.58) v5(117.07,155.08) v5(117.16,192.06) v5(117.12,187.78) v5(117.1,154.57) v5(117.13,154.06) v5(117.15,153.55) v5(117.17,153.05) v5(117.18,152.54) v5(117.28,191.57) v5(117.22,187.28) v5(117.19,152.03) v5(117.19,151.52) v5(117.19,151.01) v5(117.19,150.51) v5(117.19,150) v5(117.19,149.49) v5(117.19,148.98) v5(117.19,148.47) v5(117.19,147.97) v5(117.19,147.46) v5(117.19,146.95) v5(117.19,146.44) v5(117.19,145.93) v5(117.19,145.43) v5(117.19,144.92) v5(117.19,144.41) v5(117.19,143.9) v5(117.19,143.39) v5(117.19,142.89) v5(117.19,142.38) v5(117.19,141.87) v5(117.19,141.36) v5(117.19,140.85) v5(117.19,140.35) v5(117.19,139.84) v5(117.19,139.33) v5(117.19,138.82) v5(117.19,138.31) v5(117.31,186.78) v5(117.4,191.08) v5(117.4,186.28) v5(117.52,190.58) v5(117.49,185.78) v5(117.57,185.28) v5(117.5,137.73) v5(117.5,136.93) v5(117.5,136.13) v5(117.5,119.33) v5(117.5,118.53) v5(117.5,116.13) v5(117.5,115.33) v5(117.63,190.09) v5(117.65,184.78) v5(117.74,189.59) v5(117.73,184.28) v5(117.85,189.09) v5(117.81,183.78) v5(117.88,183.27) v5(117.95,188.6) v5(117.94,182.77) v5(118.05,188.1) v5(118.01,182.26) v5(118.07,181.76) v5(118.15,187.6) v5(118.13,181.26) v5(118.18,180.75) v5(118.25,187.1) v5(118.23,180.25) v5(118.28,179.74) v5(118.34,186.6) v5(118.33,179.23) v5(118.37,178.73) v5(118.3,136.93) v5(118.3,136.13) v5(118.3,119.33) v5(118.3,118.53) v5(118.3,116.93) v5(118.3,114.53) v5(118.3,113.73) v5(118.43,186.1) v5(118.41,178.22) v5(118.44,177.71) v5(118.47,177.21) v5(118.51,185.6) v5(118.5,176.7) v5(118.53,176.19) v5(118.55,175.68) v5(118.57,175.18) v5(118.58,174.67) v5(118.59,185.1) v5(118.67,184.6) v5(118.59,174.16) v5(118.6,173.65) v5(118.61,173.15) v5(118.61,172.64) v5(118.61,172.13) v5(118.61,171.62) v5(118.61,171.11) v5(118.61,170.61) v5(118.61,170.1) v5(118.61,169.59) v5(118.61,169.08) v5(118.61,168.57) v5(118.61,168.07) v5(118.61,167.56) v5(118.61,167.05) v5(118.61,166.54) v5(118.61,166.03) v5(118.61,165.53) v5(118.61,165.02) v5(118.61,164.51) v5(118.61,164) v5(118.61,163.49) v5(118.61,162.99) v5(118.61,162.48) v5(118.61,161.97) v5(118.61,161.46) v5(118.61,160.95) v5(118.61,160.45) v5(118.61,159.94) v5(118.61,159.43) v5(118.61,158.92) v5(118.61,158.41) v5(118.61,157.91) v5(118.61,157.4) v5(118.61,156.89) v5(118.61,156.38) v5(118.61,155.87) v5(118.61,155.37) v5(118.61,154.86) v5(118.61,154.35) v5(118.61,153.84) v5(118.61,153.33) v5(118.61,152.83) v5(118.61,152.32) v5(118.61,151.81) v5(118.61,151.3) v5(118.61,150.79) v5(118.61,150.29) v5(118.61,149.78) v5(118.61,149.27) v5(118.61,148.76) v5(118.61,148.25) v5(118.61,147.75) v5(118.61,147.24) v5(118.61,146.73) v5(118.61,146.22) v5(118.61,145.71) v5(118.61,145.21) v5(118.61,144.7) v5(118.61,144.19) v5(118.61,143.68) v5(118.61,143.17) v5(118.61,142.67) v5(118.61,142.16) v5(118.61,141.65) v5(118.61,141.14) v5(118.61,140.63) v5(118.61,140.13) v5(118.61,139.62) v5(118.61,139.11) v5(118.61,138.6) v5(118.61,138.09) v5(118.75,184.09) v5(118.82,183.59) v5(118.89,183.09) v5(118.95,182.58) v5(119.02,182.08) v5(119.08,181.58) v5(119.13,181.07) v5(119.18,180.57) v5(119.1,136.93) v5(119.1,136.13) v5(119.1,120.93) v5(119.1,118.53) v5(119.1,116.13) v5(119.1,115.33) v5(119.23,180.06) v5(119.28,179.55) v5(119.32,179.05) v5(119.36,178.54) v5(119.4,178.04) v5(119.43,177.53) v5(119.46,177.02) v5(119.49,176.51) v5(119.51,176.01) v5(119.53,175.5) v5(119.55,174.99) v5(119.56,174.48) v5(119.58,173.98) v5(119.58,173.47) v5(119.59,172.96) v5(119.59,172.45) v5(119.59,171.94) v5(119.59,171.44) v5(119.59,170.93) v5(119.59,170.42) v5(119.59,169.91) v5(119.59,169.4) v5(119.59,168.9) v5(119.59,168.39) v5(119.59,167.88) v5(119.59,167.37) v5(119.59,166.86) v5(119.59,166.36) v5(119.59,165.85) v5(119.59,165.34) v5(119.59,164.83) v5(119.59,164.32) v5(119.59,163.82) v5(119.59,163.31) v5(119.59,162.8) v5(119.59,162.29) v5(119.59,161.78) v5(119.59,161.28) v5(119.59,160.77) v5(119.59,160.26) v5(119.59,159.75) v5(119.59,159.24) v5(119.59,158.74) v5(119.59,158.23) v5(119.59,157.72) v5(119.59,157.21) v5(119.59,156.7) v5(119.59,156.2) v5(119.59,155.69) v5(119.59,155.18) v5(119.59,154.67) v5(119.59,154.16) v5(119.59,153.66) v5(119.59,153.15) v5(119.59,152.64) v5(119.59,152.13) v5(119.59,151.62) v5(119.59,151.12) v5(119.59,150.61) v5(119.59,150.1) v5(119.59,149.59) v5(119.59,149.08) v5(119.59,148.58) v5(119.59,148.07) v5(119.59,147.56) v5(119.59,147.05) v5(119.59,146.54) v5(119.59,146.04) v5(119.59,145.53) v5(119.59,145.02) v5(119.59,144.51) v5(119.59,144) v5(119.59,143.5) v5(119.59,142.99) v5(119.59,142.48) v5(119.59,141.97) v5(119.59,141.46) v5(119.59,140.96) v5(119.59,140.45) v5(119.59,139.94) v5(119.59,139.43) v5(119.59,138.92) v5(119.59,138.42) v5(119.9,137.73) v5(119.9,136.93) v5(119.9,136.13) v5(119.9,117.73) v5(119.9,116.93) v5(119.9,114.53) v5(119.9,113.73) v5(120.4,139.06) v5(120.42,138.38) v5(120.7,137.74) v5(120.7,136.93) v5(120.7,136.13) v5(120.7,118.53) v5(120.7,116.13) v5(120.7,115.33) v5(121.49,136.93) v5(121.49,136.14) v5(121.5,116.93) v5(121.5,114.53) v5(121.5,113.73) v5(122.3,120.93) v5(122.3,118.53) v5(122.3,116.13) v5(122.3,115.33) v5(123.1,116.93) v5(123.1,114.53) v5(123.1,113.73) v5(123.9,119.33) v5(123.9,118.53) v5(123.9,116.13) v5(123.9,115.33) v5(124.09,138.6) v5(124.69,137.74) v5(124.7,117.73) v5(124.7,116.93) v5(124.7,114.53) v5(124.7,113.73) v5(125.07,175.78) v5(125.06,175.27) v5(125.04,174.76) v5(125.03,174.26) v5(125.02,173.75) v5(125.01,173.24) v5(125.01,172.73) v5(125.01,172.23) v5(125.01,171.72) v5(125.01,171.21) v5(125.01,170.7) v5(125.01,170.19) v5(125.01,169.69) v5(125.01,169.18) v5(125.01,168.67) v5(125.01,168.16) v5(125.01,167.65) v5(125.01,167.15) v5(125.01,166.64) v5(125.01,166.13) v5(125.01,165.62) v5(125.01,165.11) v5(125.01,164.61) v5(125.01,164.1) v5(125.01,163.59) v5(125.01,163.08) v5(125.01,162.57) v5(125.01,162.07) v5(125.01,161.56) v5(125.01,161.05) v5(125.01,160.54) v5(125.01,160.03) v5(125.01,159.53) v5(125.01,159.02) v5(125.01,158.51) v5(125.01,158) v5(125.01,157.49) v5(125.01,156.99) v5(125.01,156.48) v5(125.01,155.97) v5(125.01,155.46) v5(125.01,154.95) v5(125.01,154.45) v5(125.01,153.94) v5(125.01,153.43) v5(125.01,152.92) v5(125.01,152.41) v5(125.01,151.91) v5(125.01,151.4) v5(125.01,150.89) v5(125.01,150.38) v5(125.01,149.87) v5(125.01,149.37) v5(125.01,148.86) v5(125.01,148.35) v5(125.01,147.84) v5(125.01,146.83) v5(125.01,146.32) v5(125.01,145.81) v5(125.01,145.3) v5(125.01,144.79) v5(125.01,144.29) v5(125.01,143.78) v5(125.01,143.27) v5(125.01,142.76) v5(125.01,142.25) v5(125.01,141.75) v5(125.01,141.24) v5(125.01,140.73) v5(125.01,140.22) v5(125.01,139.71) v5(125.01,139.21) v5(125.01,138.7) v5(125.01,138.19) v5(125.18,177.81) v5(125.15,177.3) v5(125.12,176.8) v5(125.1,176.29) v5(125.26,178.82) v5(125.22,178.32) v5(125.34,179.84) v5(125.3,179.33) v5(125.44,180.85) v5(125.39,180.34) v5(125.55,181.86) v5(125.5,181.35) v5(125.5,120.93) v5(125.5,118.53) v5(125.5,116.13) v5(125.5,115.33) v5(125.68,182.86) v5(125.62,182.36) v5(125.75,183.37) v5(125.82,183.87) v5(125.97,184.88) v5(125.89,184.37) v5(126.05,185.38) v5(126.08,176.39) v5(126.06,175.88) v5(126.04,175.37) v5(126.02,174.86) v5(126.01,174.35) v5(126,173.85) v5(125.99,173.34) v5(125.99,172.83) v5(125.99,172.32) v5(125.99,171.81) v5(125.99,171.31) v5(125.99,170.8) v5(125.99,170.29) v5(125.99,169.78) v5(125.99,169.27) v5(125.99,168.77) v5(125.99,168.26) v5(125.99,167.75) v5(125.99,167.24) v5(125.99,166.73) v5(125.99,166.23) v5(125.99,165.72) v5(125.99,165.21) v5(125.99,164.7) v5(125.99,164.19) v5(125.99,163.69) v5(125.99,163.18) v5(125.99,162.67) v5(125.99,162.16) v5(125.99,161.65) v5(125.99,161.15) v5(125.99,160.64) v5(125.99,160.13) v5(125.99,159.62) v5(125.99,159.11) v5(125.99,158.61) v5(125.99,158.1) v5(125.99,157.59) v5(125.99,157.08) v5(125.99,156.57) v5(125.99,156.07) v5(125.99,155.56) v5(125.99,155.05) v5(125.99,154.54) v5(125.99,154.03) v5(125.99,153.53) v5(125.99,153.02) v5(125.99,152.51) v5(125.99,152) v5(125.99,151.49) v5(125.99,150.99) v5(125.99,150.48) v5(125.99,149.97) v5(125.99,149.46) v5(125.99,148.95) v5(125.99,148.45) v5(125.99,147.94) v5(125.99,147.43) v5(125.99,146.92) v5(125.99,146.41) v5(125.99,145.91) v5(125.99,145.4) v5(125.99,144.89) v5(125.99,144.38) v5(125.99,143.87) v5(125.99,143.37) v5(125.99,142.86) v5(125.99,142.35) v5(125.99,141.84) v5(125.99,141.33) v5(125.99,140.83) v5(125.99,140.32) v5(125.99,139.81) v5(125.99,139.3) v5(125.99,138.79) v5(125.99,138.29) v5(126.13,185.88) v5(126.17,177.91) v5(126.14,177.4) v5(126.11,176.89) v5(126.22,186.38) v5(126.24,178.92) v5(126.21,178.41) v5(126.31,186.88) v5(126.38,180.44) v5(126.33,179.93) v5(126.29,179.43) v5(126.3,119.33) v5(126.3,118.53) v5(126.3,116.93) v5(126.3,114.53) v5(126.3,113.73) v5(126.4,187.38) v5(126.44,180.94) v5(126.5,187.88) v5(126.55,181.95) v5(126.49,181.45) v5(126.6,188.38) v5(126.68,182.96) v5(126.61,182.46) v5(126.7,188.87) v5(126.75,183.46) v5(126.81,189.37) v5(126.82,183.97) v5(126.92,189.87) v5(126.97,184.97) v5(126.89,184.47) v5(127.03,190.36) v5(127.06,185.47) v5(127.14,190.86) v5(127.14,185.97) v5(127.1,137.73) v5(127.1,136.93) v5(127.1,136.12) v5(127.1,119.33) v5(127.1,118.53) v5(127.1,116.13) v5(127.1,115.33) v5(127.26,191.35) v5(127.23,186.47) v5(127.38,191.84) v5(127.32,186.97) v5(127.42,187.47) v5(127.46,153.94) v5(127.44,153.43) v5(127.42,152.92) v5(127.41,152.41) v5(127.41,151.91) v5(127.41,151.4) v5(127.41,150.89) v5(127.41,150.38) v5(127.41,149.87) v5(127.41,149.37) v5(127.41,148.86) v5(127.41,148.35) v5(127.41,147.84) v5(127.41,147.33) v5(127.41,146.83) v5(127.41,146.32) v5(127.41,145.81) v5(127.41,145.3) v5(127.41,144.79) v5(127.41,144.29) v5(127.41,143.78) v5(127.41,143.27) v5(127.41,142.76) v5(127.41,142.25) v5(127.41,141.75) v5(127.41,141.24) v5(127.41,140.73) v5(127.41,140.22) v5(127.41,139.71) v5(127.41,139.21) v5(127.41,138.7) v5(127.41,138.19) v5(127.51,192.34) v5(127.51,187.97) v5(127.56,155.46) v5(127.52,154.95) v5(127.49,154.44) v5(127.64,192.83) v5(127.61,188.47) v5(127.65,156.47) v5(127.6,155.96) v5(127.77,193.32) v5(127.72,188.96) v5(127.76,157.48) v5(127.7,156.97) v5(127.83,189.46) v5(127.9,193.81) v5(127.94,189.96) v5(127.97,158.99) v5(127.9,158.49) v5(127.9,136.93) v5(127.89,136.14) v5(127.9,119.33) v5(127.9,118.53) v5(127.9,117.73) v5(127.9,116.93) v5(127.9,114.53) v5(127.9,113.73) v5(128.04,194.3) v5(128.05,190.45) v5(128.05,159.49) v5(128.17,194.79) v5(128.17,190.95) v5(128.14,159.99) v5(128.23,160.49) v5(128.3,195.28) v5(128.29,191.44) v5(128.33,160.99) v5(128.44,195.77) v5(128.41,191.93) v5(128.43,161.49) v5(128.47,154.54) v5(128.44,154.03) v5(128.42,153.53) v5(128.41,153.02) v5(128.39,152.51) v5(128.39,152) v5(128.39,151.49) v5(128.39,150.99) v5(128.39,150.48) v5(128.39,149.97) v5(128.39,149.46) v5(128.39,148.95) v5(128.39,148.45) v5(128.39,147.94) v5(128.39,147.43) v5(128.39,146.92) v5(128.39,146.41) v5(128.39,145.91) v5(128.39,145.4) v5(128.39,144.89) v5(128.39,144.38) v5(128.39,143.87) v5(128.39,143.37) v5(128.39,142.86) v5(128.39,142.35) v5(128.39,141.84) v5(128.39,141.33) v5(128.39,140.83) v5(128.39,140.32) v5(128.39,139.81) v5(128.39,139.3) v5(128.39,138.79) v5(128.39,138.29) v5(128.57,196.26) v5(128.54,192.42) v5(128.54,161.98) v5(128.55,155.55) v5(128.51,155.05) v5(128.67,192.92) v5(128.65,162.48) v5(128.64,156.57) v5(128.59,156.06) v5(128.7,196.75) v5(128.77,162.97) v5(128.76,157.57) v5(128.7,157.07) v5(128.7,136.93) v5(128.7,136.12) v5(128.7,117.73) v5(128.7,116.93) v5(128.7,116.13) v5(128.7,115.33) v5(128.7,114.53) v5(128.7,113.73) v5(128.83,197.24) v5(128.8,193.41) v5(128.82,158.08) v5(128.97,197.73) v5(128.94,193.89) v5(128.89,163.46) v5(128.98,159.08) v5(128.9,158.58) v5(129.08,194.38) v5(129.02,163.96) v5(129.06,159.58) v5(129.1,198.22) v5(129.16,164.45) v5(129.15,160.08) v5(129.23,198.71) v5(129.21,194.88) v5(129.24,160.58) v5(129.36,199.2) v5(129.34,195.37) v5(129.3,164.93) v5(129.34,161.08) v5(129.47,195.86) v5(129.44,165.42) v5(129.45,161.58) v5(129.5,199.69) v5(129.56,162.07) v5(129.5,136.93) v5(129.49,136.14) v5(129.5,119.33) v5(129.5,118.53) v5(129.5,116.13) v5(129.5,115.33) v5(129.63,200.18) v5(129.61,196.35) v5(129.59,165.91) v5(129.68,162.57) v5(129.76,200.67) v5(129.74,196.84) v5(129.75,166.39) v5(129.87,197.33) v5(129.8,163.06) v5(129.85,151.4) v5(129.83,150.89) v5(129.82,150.38) v5(129.81,149.87) v5(129.81,149.37) v5(129.81,148.86) v5(129.81,148.35) v5(129.81,147.84) v5(129.81,147.33) v5(129.81,146.83) v5(129.81,146.32) v5(129.81,145.81) v5(129.81,145.3) v5(129.81,144.79) v5(129.81,144.29) v5(129.81,143.78) v5(129.81,143.27) v5(129.81,142.76) v5(129.81,142.25) v5(129.81,141.75) v5(129.81,141.24) v5(129.81,140.73) v5(129.81,140.22) v5(129.81,139.71) v5(129.81,139.21) v5(129.81,138.7) v5(129.81,138.19) v5(129.89,201.16) v5(129.91,166.87) v5(129.93,163.55) v5(129.97,152.92) v5(129.93,152.41) v5(129.89,151.9) v5(130.02,201.65) v5(130,197.82) v5(130.07,167.35) v5(130.06,164.04) v5(130.03,153.42) v5(130.16,202.14) v5(130.13,198.31) v5(130.17,154.43) v5(130.1,153.92) v5(130.27,198.8) v5(130.24,167.83) v5(130.2,164.53) v5(130.25,154.93) v5(130.29,202.63) v5(130.34,165.02) v5(130.34,155.43) v5(130.3,136.93) v5(130.3,119.33) v5(130.3,118.53) v5(130.3,116.93) v5(130.3,114.53) v5(130.3,113.73) v5(130.42,203.12) v5(130.4,199.29) v5(130.42,168.31) v5(130.44,155.93) v5(130.55,203.62) v5(130.53,199.78) v5(130.49,165.51) v5(130.55,156.42) v5(130.66,200.27) v5(130.6,168.78) v5(130.64,165.99) v5(130.66,156.92) v5(130.69,204.11) v5(130.78,157.41) v5(130.82,204.6) v5(130.8,200.76) v5(130.79,169.25) v5(130.8,166.47) v5(130.87,152) v5(130.84,151.49) v5(130.81,150.99) v5(130.8,150.48) v5(130.79,149.97) v5(130.79,149.46) v5(130.79,148.95) v5(130.79,148.45) v5(130.79,147.94) v5(130.79,147.43) v5(130.79,146.92) v5(130.79,146.41) v5(130.79,145.91) v5(130.79,145.4) v5(130.79,144.89) v5(130.79,144.38) v5(130.79,143.87) v5(130.79,143.37) v5(130.79,142.86) v5(130.79,142.35) v5(130.79,141.84) v5(130.79,141.33) v5(130.79,140.83) v5(130.79,140.32) v5(130.79,139.81) v5(130.79,139.3) v5(130.79,138.79) v5(130.79,138.29) v5(130.95,205.09) v5(130.93,201.25) v5(130.98,169.72) v5(130.97,166.95) v5(130.91,157.9) v5(130.97,153.01) v5(130.92,152.51) v5(131.08,205.58) v5(131.06,201.74) v5(131.05,158.39) v5(131.03,153.52) v5(131.18,170.19) v5(131.14,167.43) v5(131.17,154.52) v5(131.1,154.02) v5(131.1,137.73) v5(131.1,136.93) v5(131.1,134.53) v5(131.1,120.13) v5(131.1,119.33) v5(131.1,118.53) v5(131.1,116.13) v5(131.1,115.33) v5(131.22,206.07) v5(131.19,202.23) v5(131.2,158.88) v5(131.26,155.02) v5(131.35,206.56) v5(131.33,202.72) v5(131.38,170.66) v5(131.31,167.91) v5(131.35,159.36) v5(131.35,155.52) v5(131.47,207.19) v5(131.46,203.21) v5(131.46,156.02) v5(131.55,207.77) v5(131.58,171.12) v5(131.5,168.38) v5(131.51,159.84) v5(131.57,156.52) v5(131.65,208.33) v5(131.59,203.7) v5(131.68,168.86) v5(131.68,160.32) v5(131.72,204.19) v5(131.69,157.01) v5(131.86,204.68) v5(131.8,171.59) v5(131.87,169.33) v5(131.86,160.8) v5(131.82,157.5) v5(131.95,157.99) v5(131.9,137.73) v5(131.9,136.93) v5(131.9,120.13) v5(131.9,117.73) v5(131.9,116.93) v5(131.9,114.53) v5(131.9,113.73) v5(131.99,205.17) v5(132.01,172.04) v5(132.07,169.79) v5(132.05,161.27) v5(132.12,205.67) v5(132.1,158.48) v5(132.25,206.16) v5(132.23,172.5) v5(132.27,170.26) v5(132.24,161.74) v5(132.25,158.96) v5(132.26,150.89) v5(132.23,150.38) v5(132.22,149.87) v5(132.22,149.37) v5(132.22,148.86) v5(132.22,148.35) v5(132.22,147.84) v5(132.22,147.33) v5(132.22,146.83) v5(132.22,146.32) v5(132.22,145.81) v5(132.22,145.3) v5(132.22,144.79) v5(132.22,144.29) v5(132.22,143.78) v5(132.22,143.27) v5(132.22,142.76) v5(132.22,142.25) v5(132.22,141.75) v5(132.22,141.24) v5(132.22,140.73) v5(132.22,140.22) v5(132.22,139.71) v5(132.22,139.21) v5(132.22,138.7) v5(132.22,138.19) v5(132.33,151.9) v5(132.29,151.4) v5(132.46,172.95) v5(132.48,170.72) v5(132.44,162.21) v5(132.41,159.44) v5(132.46,152.91) v5(132.39,152.41) v5(132.51,206.55) v5(132.58,159.92) v5(132.54,153.41) v5(132.61,206.96) v5(132.65,162.67) v5(132.63,153.91) v5(132.7,173.4) v5(132.69,171.19) v5(132.76,160.4) v5(132.73,154.41) v5(132.7,136.93) v5(132.7,120.13) v5(132.7,119.33) v5(132.7,118.53) v5(132.7,116.13) v5(132.7,115.33) v5(132.79,207.47) v5(132.87,163.13) v5(132.84,154.91) v5(132.94,208) v5(132.94,173.85) v5(132.91,171.65) v5(132.94,160.87) v5(132.96,155.4) v5(133.18,174.3) v5(133.13,172.1) v5(133.09,163.58) v5(133.14,161.34) v5(133.1,155.89) v5(133.18,149.97) v5(133.17,149.46) v5(133.17,148.95) v5(133.17,148.45) v5(133.17,147.94) v5(133.17,147.43) v5(133.17,146.92) v5(133.17,146.41) v5(133.17,145.91) v5(133.17,145.4) v5(133.17,144.89) v5(133.17,144.38) v5(133.17,143.87) v5(133.17,143.37) v5(133.17,142.86) v5(133.17,142.35) v5(133.17,141.84) v5(133.17,141.33) v5(133.17,140.83) v5(133.17,140.32) v5(133.17,139.81) v5(133.17,139.3) v5(133.17,138.79) v5(133.17,138.29) v5(133.24,156.38) v5(133.25,151.49) v5(133.22,150.98) v5(133.19,150.48) v5(133.36,172.55) v5(133.33,164.04) v5(133.34,161.81) v5(133.36,152.5) v5(133.3,152) v5(133.42,174.75) v5(133.4,156.86) v5(133.44,153) v5(133.56,164.48) v5(133.55,162.27) v5(133.56,157.34) v5(133.52,153.5) v5(133.5,120.13) v5(133.5,117.73) v5(133.5,116.93) v5(133.5,114.53) v5(133.5,113.73) v5(133.66,175.19) v5(133.6,173) v5(133.62,154) v5(133.76,162.73) v5(133.74,157.82) v5(133.72,154.5) v5(133.84,173.45) v5(133.81,164.93) v5(133.84,154.99) v5(133.9,175.64) v5(133.93,158.29) v5(133.97,155.49) v5(134.08,173.9) v5(134.06,165.37) v5(133.99,163.19) v5(134.14,176.09) v5(134.13,158.76) v5(134.11,155.97) v5(134.22,163.64) v5(134.27,156.46) v5(134.38,176.54) v5(134.32,174.35) v5(134.33,165.81) v5(134.34,159.22) v5(134.46,164.08) v5(134.43,156.94) v5(134.56,174.79) v5(134.56,159.68) v5(134.62,176.99) v5(134.59,166.24) v5(134.61,157.41) v5(134.71,164.53) v5(134.79,160.13) v5(134.86,177.43) v5(134.8,175.24) v5(134.87,166.66) v5(134.8,157.89) v5(134.96,164.97) v5(135.04,175.69) v5(135.02,160.58) v5(134.99,158.35) v5(135.1,177.88) v5(135.15,167.09) v5(135.28,176.14) v5(135.23,165.4) v5(135.27,161.02) v5(135.2,158.82) v5(135.34,178.33) v5(135.44,167.5) v5(135.42,159.28) v5(135.58,178.78) v5(135.52,176.59) v5(135.5,165.83) v5(135.53,161.46) v5(135.65,159.73) v5(135.76,177.03) v5(135.74,167.92) v5(135.77,166.26) v5(135.82,179.22) v5(135.8,161.89) v5(135.89,160.18) v5(136.06,179.67) v5(136,177.48) v5(136.04,168.33) v5(136.06,166.68) v5(136.08,162.31) v5(136.14,160.62) v5(136.24,177.93) v5(136.3,180.12) v5(136.35,168.73) v5(136.35,167.1) v5(136.37,162.73) v5(136.48,178.38) v5(136.4,161.05) v5(136.54,180.57) v5(136.66,169.13) v5(136.65,167.51) v5(136.67,163.14) v5(136.67,161.48) v5(136.78,181.02) v5(136.72,178.83) v5(136.96,179.27) v5(136.99,169.52) v5(136.95,167.91) v5(136.97,163.55) v5(136.96,161.91) v5(137.02,181.46) v5(137.26,181.91) v5(137.2,179.72) v5(137.26,168.31) v5(137.25,162.32) v5(137.31,169.91) v5(137.29,163.95) v5(137.43,180.17) v5(137.5,182.36) v5(137.58,168.71) v5(137.55,162.73) v5(137.67,180.62) v5(137.65,170.29) v5(137.61,164.34) v5(137.74,182.81) v5(137.86,163.14) v5(137.98,183.26) v5(137.91,181.06) v5(137.91,169.1) v5(137.94,164.72) v5(137.99,170.66) v5(138.15,181.51) v5(138.18,163.53) v5(138.22,183.7) v5(138.24,169.48) v5(138.28,165.1) v5(138.34,171.03) v5(138.46,184.15) v5(138.39,181.96) v5(138.58,169.86) v5(138.5,163.92) v5(138.63,182.41) v5(138.63,165.47) v5(138.7,184.6) v5(138.69,171.4) v5(138.87,182.86) v5(138.84,164.3) v5(138.94,185.05) v5(138.93,170.23) v5(139.05,171.76) v5(138.99,165.83) v5(139.18,185.49) v5(139.11,183.3) v5(139.28,170.6) v5(139.19,164.67) v5(139.35,183.75) v5(139.35,166.19) v5(139.42,185.94) v5(139.42,172.11) v5(139.54,165.03) v5(139.66,186.39) v5(139.59,184.2) v5(139.63,170.96) v5(139.71,166.55) v5(139.83,184.65) v5(139.79,172.46) v5(139.9,186.84) v5(139.9,165.39) v5(140.07,185.1) v5(140,171.32) v5(140.07,166.91) v5(140.14,187.29) v5(140.16,172.8) v5(140.26,165.75) v5(140.38,187.73) v5(140.31,185.54) v5(140.37,171.66) v5(140.43,167.27) v5(140.55,185.99) v5(140.55,173.13) v5(140.62,188.18) v5(140.62,166.11) v5(140.74,172.01) v5(140.86,188.63) v5(140.79,186.44) v5(140.79,167.63) v5(140.93,173.46) v5(140.98,166.47) v5(141.03,186.89) v5(141.09,189.08) v5(141.12,172.34) v5(141.15,167.98) v5(141.27,187.33) v5(141.33,189.53) v5(141.33,173.78) v5(141.34,166.83) v5(141.57,189.97) v5(141.51,187.78) v5(141.51,172.67) v5(141.51,168.34) v5(141.75,188.23) v5(141.72,174.11) v5(141.7,167.19) v5(141.81,190.42) v5(141.87,168.7) v5(141.9,172.99) v5(142.05,190.87) v5(141.99,188.68) v5(142.06,167.55) v5(142.1,174.44) v5(142.23,189.13) v5(142.22,169.06) v5(142.29,191.32) v5(142.29,173.32) v5(142.47,189.57) v5(142.42,167.91) v5(142.53,191.77) v5(142.49,174.77) v5(142.58,169.42) v5(142.68,173.65) v5(142.77,192.21) v5(142.71,190.02) v5(142.78,168.27) v5(142.88,175.09) v5(142.95,190.47) v5(142.94,169.78) v5(143.01,192.66) v5(143.07,173.98) v5(143.13,168.63) v5(143.25,193.11) v5(143.19,190.92) v5(143.27,175.42) v5(143.3,170.14) v5(143.43,191.37) v5(143.46,174.3) v5(143.49,193.56) v5(143.49,168.98) v5(143.67,191.81) v5(143.66,175.75) v5(143.66,170.5) v5(143.73,194) v5(143.85,174.63) v5(143.85,169.34) v5(143.98,194.45) v5(143.91,192.26) v5(144.04,176.08) v5(144.02,170.86) v5(144.15,192.71) v5(144.24,194.89) v5(144.23,174.96) v5(144.21,169.7) v5(144.38,171.22) v5(144.39,193.16) v5(144.43,176.41) v5(144.49,195.33) v5(144.57,170.06) v5(144.63,193.6) v5(144.62,175.29) v5(144.74,195.77) v5(144.74,171.58) v5(144.88,194.05) v5(144.82,176.74) v5(144.93,170.42) v5(145,196.21) v5(145.01,175.62) v5(145.13,194.49) v5(145.1,171.93) v5(145.25,196.65) v5(145.21,177.06) v5(145.29,170.78) v5(145.39,194.93) v5(145.4,175.94) v5(145.47,172.28) v5(145.51,197.09) v5(145.64,195.37) v5(145.59,177.39) v5(145.65,171.14) v5(145.76,197.53) v5(145.79,176.27) v5(145.86,172.61) v5(145.9,195.81) v5(145.98,177.72) v5(146.01,197.97) v5(146.02,171.49) v5(146.15,196.25) v5(146.17,176.6) v5(146.27,198.41) v5(146.25,172.94) v5(146.37,178.05) v5(146.4,196.69) v5(146.4,171.82) v5(146.52,198.85) v5(146.56,176.93) v5(146.66,197.13) v5(146.65,173.25) v5(146.78,199.29) v5(146.76,178.38) v5(146.79,172.15) v5(146.91,197.57) v5(146.95,177.26) v5(147.03,199.73) v5(147.06,173.55) v5(147.17,198) v5(147.15,178.7) v5(147.28,200.17) v5(147.19,172.46) v5(147.34,177.58) v5(147.42,198.44) v5(147.47,173.84) v5(147.54,200.61) v5(147.53,179.03) v5(147.67,198.88) v5(147.6,172.77) v5(147.72,177.91) v5(147.79,201.05) v5(147.93,199.32) v5(147.92,179.36) v5(147.9,174.12) v5(148.05,201.49) v5(148.01,173.06) v5(148.18,199.76) v5(148.11,178.24) v5(148.3,201.93) v5(148.31,179.69) v5(148.33,174.39) v5(148.44,202.46) v5(148.44,200.2) v5(148.44,173.33) v5(148.5,178.57) v5(148.77,203.05) v5(148.69,200.64) v5(148.7,180.02) v5(148.77,174.64) v5(148.87,173.6) v5(148.94,201.08) v5(148.89,178.9) v5(149.05,203.5) v5(149.08,180.34) v5(149.2,201.52) v5(149.28,179.23) v5(149.22,174.88) v5(149.31,173.85) v5(149.47,180.67) v5(149.56,201.9) v5(149.66,179.55) v5(149.67,175.11) v5(149.76,174.09) v5(149.89,202.39) v5(149.86,181) v5(150.05,179.88) v5(150.16,202.9) v5(150.13,175.33) v5(150.25,181.33) v5(150.21,174.32) v5(150.44,180.21) v5(150.64,181.66) v5(150.59,175.54) v5(150.68,174.54) v5(150.83,180.54) v5(151.02,181.99) v5(151.06,175.73) v5(151.14,174.74) v5(151.21,180.87) v5(151.41,182.31) v5(151.54,175.91) v5(151.6,181.19) v5(151.61,174.92) v5(151.8,182.64) v5(151.99,181.52) v5(152.02,176.08) v5(152.09,175.1) v5(152.19,182.97) v5(152.38,181.85) v5(152.57,183.3) v5(152.5,176.23) v5(152.58,175.25) v5(152.77,182.18) v5(152.96,183.63) v5(152.99,176.37) v5(153.06,175.4) v5(153.15,182.51) v5(153.35,183.95) v5(153.48,176.49) v5(153.54,182.83) v5(153.55,175.53) v5(153.74,184.28) v5(153.93,183.16) v5(153.98,176.61) v5(154.05,175.65) v5(154.13,184.61) v5(154.32,183.49) v5(154.48,176.7) v5(154.51,184.94) v5(154.55,175.75) v5(154.7,183.82) v5(154.9,185.27) v5(154.98,176.79) v5(155.05,175.84) v5(155.09,184.15) v5(155.29,185.59) v5(155.48,184.48) v5(155.48,176.86) v5(155.55,175.91) v5(155.68,185.92) v5(155.87,184.8) v5(155.99,176.92) v5(156.06,186.25) v5(156.05,175.97) v5(156.26,185.13) v5(156.45,186.58) v5(156.49,176.96) v5(156.56,176.01) v5(156.64,185.46) v5(156.84,186.91) v5(157.03,185.79) v5(157,176.99) v5(157.07,176.04) v5(157.23,187.24) v5(157.42,186.12) v5(157.51,177) v5(157.57,176.05) v5(157.62,187.56) v5(157.81,186.44) v5(158,187.89) v5(158.02,177.01) v5(158.08,176.05) v5(158.2,186.77) v5(158.39,188.22) v5(158.58,187.1) v5(158.52,177.01) v5(158.59,176.05) v5(158.78,188.55) v5(158.97,187.43) v5(159.03,177.01) v5(159.17,188.88) v5(159.1,176.05) v5(159.36,187.76) v5(159.56,189.2) v5(159.54,177.01) v5(159.61,176.05) v5(159.75,188.08) v5(159.94,189.53) v5(160.05,177.01) v5(160.13,188.41) v5(160.11,176.05) v5(160.33,189.86) v5(160.52,188.74) v5(160.56,177.01) v5(160.62,176.05) v5(160.72,190.19) v5(160.91,189.07) v5(161.06,177.01) v5(161.11,190.52) v5(161.13,176.05) v5(161.3,189.4) v5(161.49,190.84) v5(161.57,177.01) v5(161.69,189.73) v5(161.64,176.05) v5(161.88,191.17) v5(162.07,190.05) v5(162.08,177.01) v5(162.15,176.05) v5(162.27,191.5) v5(162.46,190.38) v5(162.66,191.83) v5(162.59,177.01) v5(162.65,176.05) v5(162.85,190.71) v5(163.05,192.16) v5(163.1,177.01) v5(163.16,176.05) v5(163.24,191.04) v5(163.43,192.49) v5(163.62,191.37) v5(163.6,177.01) v5(163.67,176.05) v5(163.91,192.99) v5(164.01,191.69) v5(164.11,177.01) v5(164.18,176.05) v5(164.31,193.32) v5(164.54,191.67) v5(164.62,177.01) v5(164.69,193.75) v5(164.69,176.05) v5(165.05,191.77) v5(165.13,177.01) v5(165.19,176.05) v5(165.3,192.38) v5(165.63,192.71) v5(165.64,177.01) v5(165.7,176.05) v5(166.14,177.01) v5(166.21,176.05) v5(166.65,177.01) v5(166.72,176.05) v5(167.16,177.01) v5(167.23,176.05) v5(167.67,177.01) v5(167.73,176.05) v5(168.18,177.01) v5(168.24,176.05) v5(168.68,177.01) v5(168.75,176.05) v5(169.19,177.01) v5(169.26,176.05) v5(169.7,177.01) v5(169.77,176.05) v5(170.21,177.01) v5(170.27,176.05) v5(170.72,177.01) v5(170.78,176.05) v5(171.22,177.01) v5(171.29,176.05) v5(171.73,177.01) v5(171.8,176.05) v5(172.24,177.01) v5(172.31,176.05) v5(172.75,177.01) v5(172.81,176.05) v5(173.28,176) v5(173.41,177.14) v5(173.51,175.62) v5(174.02,177.24) v5(174.17,175.69) v5(174.68,177.22) v5(174.75,175.79) v6(120.55,193.5) v6(120.67,193.05) v6(120.68,181.31) v6(120.79,181.75) v6(120.99,192.73) v6(121.06,182.79) v6(121.18,189.57) v6(121.18,187.53) v6(121.18,185.83) v6(121.12,182.08) v6(121.44,192.61) v6(121.56,182.19) v6(121.88,192.73) v6(122.01,182.08) v6(122.21,193.05) v6(122.33,193.5) v6(122.46,181.75) v6(122.45,181.31) v6(122.71,189.57) v6(122.71,187.53) v6(122.71,185.83) v6(122.71,182.79) v6(122.83,193.5) v6(122.83,192.74) v6(122.95,181.75) v6(122.96,181.31) v6(123.22,193.05) v6(123.41,182.08) v6(123.85,182.19) v6(124.1,193.05) v6(124.23,189.57) v6(124.23,187.53) v6(124.23,185.83) v6(124.36,182.79) v6(124.29,182.08) v6(124.67,181.75) v6(124.74,181.31) v6(124.99,193.05) v7(69.95,177.19) v7(69.95,175.62) v7(70.64,175.64) v7(70.82,177.42) v7(71.37,177.24) v7(71.3,175.72) v7(71.73,176.89) v7(71.84,175.92) v7(72.24,176.89) v7(72.34,175.92) v7(72.75,176.89) v7(72.85,175.92) v7(73.25,176.89) v7(73.36,175.92) v7(73.76,176.89) v7(73.87,175.92) v7(74.27,176.89) v7(74.38,175.92) v7(74.78,176.89) v7(74.88,175.92) v7(75.29,176.89) v7(75.39,175.92) v7(75.79,176.89) v7(75.9,175.92) v7(76.3,176.89) v7(76.41,175.92) v7(76.81,176.89) v7(76.92,175.92) v7(77.32,176.89) v7(77.42,175.92) v7(77.83,176.89) v7(77.93,175.92) v7(78.33,176.89) v7(78.44,175.92) v7(78.84,176.89) v7(78.92,192.66) v7(78.95,175.92) v7(79.35,176.89) v7(79.4,192.33) v7(79.46,175.92) v7(79.86,193.8) v7(79.86,176.89) v7(79.96,175.92) v7(80.06,191.97) v7(80.37,176.89) v7(80.47,175.92) v7(80.65,191.62) v7(80.75,193.52) v7(80.87,176.89) v7(80.98,175.92) v7(81.03,193.01) v7(81.08,192.53) v7(81.03,191.29) v7(81.38,176.89) v7(81.46,192.21) v7(81.42,190.96) v7(81.49,175.92) v7(81.85,191.88) v7(81.81,190.63) v7(81.89,176.89) v7(82,175.92) v7(82.24,191.55) v7(82.2,190.3) v7(82.4,176.89) v7(82.5,175.92) v7(82.63,191.22) v7(82.59,189.98) v7(82.97,189.65) v7(82.91,176.89) v7(83.02,190.89) v7(83.01,175.92) v7(83.36,189.32) v7(83.4,190.57) v7(83.41,176.89) v7(83.52,175.92) v7(83.75,188.99) v7(83.79,190.24) v7(83.92,176.89) v7(84.03,175.92) v7(84.18,189.91) v7(84.14,188.67) v7(84.43,176.89) v7(84.57,189.58) v7(84.53,188.34) v7(84.54,175.92) v7(84.96,189.25) v7(84.91,188.01) v7(84.94,176.89) v7(85.04,175.92) v7(85.35,188.93) v7(85.3,187.68) v7(85.45,176.89) v7(85.55,175.92) v7(85.73,188.6) v7(85.69,187.35) v7(85.95,176.89) v7(86.08,187.03) v7(86.06,175.92) v7(86.12,188.27) v7(86.47,186.7) v7(86.46,176.89) v7(86.51,187.94) v7(86.57,175.92) v7(86.86,186.37) v7(86.9,187.62) v7(86.97,176.89) v7(87.08,175.92) v7(87.29,187.29) v7(87.24,186.04) v7(87.48,176.88) v7(87.58,175.91) v7(87.67,186.96) v7(87.63,185.71) v7(87.99,176.86) v7(88.06,186.63) v7(88.02,185.39) v7(88.09,175.89) v7(88.45,186.3) v7(88.41,185.06) v7(88.49,176.83) v7(88.6,175.85) v7(88.84,185.98) v7(88.8,184.73) v7(89,176.79) v7(89.18,184.4) v7(89.1,175.8) v7(89.23,185.65) v7(89.57,184.08) v7(89.5,176.72) v7(89.61,185.32) v7(89.61,175.74) v7(89.96,183.75) v7(90,184.99) v7(90,176.65) v7(90.11,175.65) v7(90.35,183.42) v7(90.39,184.66) v7(90.5,176.56) v7(90.61,175.56) v7(90.78,184.34) v7(90.74,183.09) v7(91,176.46) v7(91.17,184.01) v7(91.12,182.76) v7(91.1,175.44) v7(91.55,183.68) v7(91.51,182.44) v7(91.5,176.34) v7(91.59,175.32) v7(91.94,183.35) v7(91.9,182.11) v7(91.99,176.21) v7(92.08,175.18) v7(92.33,183.03) v7(92.29,181.78) v7(92.47,176.07) v7(92.57,175.02) v7(92.68,181.45) v7(92.72,182.7) v7(92.96,175.91) v7(93.06,181.12) v7(93.04,174.85) v7(93.11,182.37) v7(93.45,180.8) v7(93.43,175.73) v7(93.49,182.04) v7(93.52,174.67) v7(93.88,181.71) v7(93.84,180.47) v7(93.91,175.55) v7(93.99,174.47) v7(94.18,202.79) v7(94.27,181.39) v7(94.23,180.14) v7(94.38,175.35) v7(94.45,174.26) v7(94.66,181.06) v7(94.62,179.81) v7(94.72,202.34) v7(94.84,175.14) v7(94.97,201.83) v7(94.9,174.03) v7(95.05,180.73) v7(95,179.49) v7(95.37,201.57) v7(95.29,174.91) v7(95.35,173.79) v7(95.43,180.4) v7(95.39,179.16) v7(95.63,203.5) v7(95.62,201.12) v7(95.78,178.83) v7(95.74,174.68) v7(95.86,200.68) v7(95.82,180.07) v7(95.79,173.54) v7(95.91,202.95) v7(96.06,202.51) v7(96.1,200.23) v7(96.17,178.5) v7(96.18,174.43) v7(96.23,202.04) v7(96.21,179.75) v7(96.22,173.27) v7(96.35,199.79) v7(96.48,201.59) v7(96.56,178.17) v7(96.59,199.34) v7(96.6,179.42) v7(96.62,174.16) v7(96.65,172.99) v7(96.72,201.15) v7(96.84,198.89) v7(96.96,200.7) v7(96.99,179.09) v7(96.94,177.85) v7(97.08,198.45) v7(97.05,173.89) v7(97.07,172.7) v7(97.21,200.25) v7(97.32,198) v7(97.37,178.76) v7(97.33,177.52) v7(97.45,199.81) v7(97.47,173.6) v7(97.47,172.4) v7(97.57,197.56) v7(97.69,199.36) v7(97.76,178.44) v7(97.72,177.19) v7(97.81,197.11) v7(97.88,173.3) v7(97.87,172.08) v7(97.94,198.92) v7(98.05,196.67) v7(98.18,198.47) v7(98.15,178.11) v7(98.11,176.86) v7(98.28,172.99) v7(98.26,171.76) v7(98.3,196.22) v7(98.43,198.03) v7(98.54,195.77) v7(98.54,177.78) v7(98.5,176.53) v7(98.67,197.58) v7(98.67,172.67) v7(98.64,171.42) v7(98.79,195.33) v7(98.88,176.21) v7(98.91,197.13) v7(98.93,177.45) v7(99.03,194.88) v7(99.06,172.34) v7(99.01,171.07) v7(99.16,196.69) v7(99.27,194.44) v7(99.27,175.88) v7(99.31,177.12) v7(99.37,170.71) v7(99.4,196.24) v7(99.43,172) v7(99.52,193.99) v7(99.64,195.8) v7(99.66,175.55) v7(99.76,193.54) v7(99.7,176.8) v7(99.73,170.35) v7(99.8,171.65) v7(99.89,195.35) v7(100,193.1) v7(100.05,175.22) v7(100.09,169.99) v7(100.13,194.91) v7(100.09,176.47) v7(100.16,171.29) v7(100.25,192.65) v7(100.37,194.46) v7(100.48,176.14) v7(100.44,174.9) v7(100.45,169.63) v7(100.49,192.21) v7(100.52,170.93) v7(100.62,194.01) v7(100.74,191.76) v7(100.86,193.57) v7(100.87,175.81) v7(100.82,174.57) v7(100.88,170.57) v7(100.8,169.27) v7(100.98,191.32) v7(101.11,193.12) v7(101.16,168.92) v7(101.22,190.87) v7(101.25,175.48) v7(101.21,174.24) v7(101.23,170.21) v7(101.35,192.68) v7(101.47,190.42) v7(101.52,168.56) v7(101.59,192.23) v7(101.64,175.16) v7(101.6,173.91) v7(101.59,169.85) v7(101.71,189.98) v7(101.84,191.79) v7(101.88,168.2) v7(101.95,189.53) v7(101.95,169.49) v7(102.08,191.34) v7(102.03,174.83) v7(101.99,173.58) v7(102.2,189.09) v7(102.24,167.84) v7(102.32,190.89) v7(102.38,173.26) v7(102.31,169.13) v7(102.44,188.64) v7(102.42,174.5) v7(102.57,190.45) v7(102.68,188.2) v7(102.67,168.77) v7(102.6,167.48) v7(102.77,172.93) v7(102.81,190) v7(102.81,174.17) v7(102.93,187.75) v7(102.96,167.12) v7(103.06,189.56) v7(103.03,168.41) v7(103.17,187.3) v7(103.16,172.61) v7(103.19,173.85) v7(103.3,189.11) v7(103.32,166.76) v7(103.42,186.86) v7(103.39,168.05) v7(103.54,188.67) v7(103.55,172.28) v7(103.66,186.41) v7(103.59,173.52) v7(103.68,166.4) v7(103.75,167.69) v7(103.79,188.22) v7(103.9,185.97) v7(103.98,173.2) v7(103.93,171.94) v7(104.03,187.77) v7(104.04,166.04) v7(104.15,185.52) v7(104.11,167.34) v7(104.27,187.33) v7(104.36,172.86) v7(104.3,171.6) v7(104.39,185.08) v7(104.47,166.98) v7(104.4,165.68) v7(104.52,186.88) v7(104.63,184.63) v7(104.67,171.25) v7(104.76,186.44) v7(104.74,172.52) v7(104.76,165.32) v7(104.88,184.18) v7(104.83,166.62) v7(105,185.99) v7(105.03,170.89) v7(105.12,183.74) v7(105.11,172.18) v7(105.11,164.96) v7(105.25,185.54) v7(105.19,166.26) v7(105.37,183.29) v7(105.48,171.83) v7(105.39,170.53) v7(105.47,164.6) v7(105.49,185.1) v7(105.55,165.9) v7(105.61,182.85) v7(105.74,184.65) v7(105.74,170.16) v7(105.85,182.4) v7(105.84,171.47) v7(105.81,164.23) v7(105.98,184.21) v7(105.9,165.54) v7(106.08,169.79) v7(106.1,181.96) v7(106.15,163.84) v7(106.22,183.76) v7(106.19,171.11) v7(106.25,165.17) v7(106.34,181.51) v7(106.47,183.32) v7(106.42,169.41) v7(106.48,163.46) v7(106.58,181.06) v7(106.54,170.74) v7(106.6,164.8) v7(106.71,182.87) v7(106.75,169.02) v7(106.83,180.62) v7(106.88,170.36) v7(106.79,163.06) v7(106.95,182.42) v7(106.93,164.41) v7(107.07,180.17) v7(107.07,168.63) v7(107.1,162.65) v7(107.2,181.98) v7(107.22,169.98) v7(107.26,164.02) v7(107.31,179.73) v7(107.44,181.53) v7(107.39,168.24) v7(107.4,162.24) v7(107.56,179.28) v7(107.55,169.59) v7(107.57,163.63) v7(107.69,181.09) v7(107.7,167.84) v7(107.69,161.83) v7(107.8,178.84) v7(107.87,169.2) v7(107.88,163.22) v7(107.93,180.64) v7(107.97,161.4) v7(108.05,178.39) v7(108.01,167.43) v7(108.17,180.2) v7(108.18,162.81) v7(108.19,168.8) v7(108.24,160.97) v7(108.29,177.94) v7(108.3,167.02) v7(108.42,179.75) v7(108.47,162.39) v7(108.53,177.5) v7(108.5,168.4) v7(108.5,160.53) v7(108.66,179.3) v7(108.59,166.6) v7(108.78,177.05) v7(108.75,161.97) v7(108.75,160.09) v7(108.8,168) v7(108.88,166.18) v7(108.9,178.86) v7(108.98,159.64) v7(109.02,176.61) v7(109.02,161.54) v7(109.15,178.41) v7(109.1,167.58) v7(109.15,165.75) v7(109.26,176.16) v7(109.28,161.1) v7(109.21,159.19) v7(109.39,177.97) v7(109.39,167.17) v7(109.42,165.32) v7(109.43,158.73) v7(109.51,175.72) v7(109.53,160.66) v7(109.63,177.52) v7(109.67,166.74) v7(109.68,164.88) v7(109.64,158.27) v7(109.75,175.27) v7(109.77,160.22) v7(109.88,177.08) v7(109.83,157.8) v7(109.95,166.32) v7(109.94,164.44) v7(109.98,139.62) v7(109.99,174.82) v7(110.01,159.76) v7(110.02,157.32) v7(110.12,176.63) v7(110.18,164) v7(110.24,174.38) v7(110.22,165.89) v7(110.23,159.31) v7(110.19,156.85) v7(110.37,176.18) v7(110.35,156.37) v7(110.48,173.93) v7(110.48,165.45) v7(110.42,163.55) v7(110.44,158.84) v7(110.5,155.88) v7(110.61,175.74) v7(110.65,163.1) v7(110.64,158.38) v7(110.64,155.39) v7(110.73,173.49) v7(110.74,165.01) v7(110.77,154.9) v7(110.82,207.7) v7(110.85,175.29) v7(110.88,162.64) v7(110.83,157.91) v7(110.97,207.11) v7(110.97,173.04) v7(110.99,164.57) v7(110.89,154.41) v7(111.01,157.43) v7(110.99,153.91) v7(111.18,206.53) v7(111.1,174.85) v7(111.09,162.18) v7(111.17,156.95) v7(111.09,153.41) v7(111.17,152.91) v7(111.21,172.6) v7(111.23,164.12) v7(111.24,152.41) v7(111.34,174.4) v7(111.3,161.72) v7(111.33,156.47) v7(111.3,151.9) v7(111.35,151.39) v7(111.38,150.89) v7(111.46,206.21) v7(111.45,172.15) v7(111.46,163.67) v7(111.48,155.98) v7(111.4,150.38) v7(111.41,149.87) v7(111.42,149.36) v7(111.42,148.86) v7(111.42,148.35) v7(111.42,147.84) v7(111.42,147.33) v7(111.42,146.82) v7(111.42,146.32) v7(111.42,145.81) v7(111.42,145.3) v7(111.42,144.79) v7(111.42,144.28) v7(111.42,143.78) v7(111.42,143.27) v7(111.42,142.76) v7(111.42,142.25) v7(111.42,141.74) v7(111.42,141.24) v7(111.42,140.73) v7(111.42,140.22) v7(111.42,139.71) v7(111.42,139.2) v7(111.42,138.7) v7(111.42,138.19) v7(111.58,173.96) v7(111.5,161.25) v7(111.62,205.73) v7(111.67,171.69) v7(111.69,163.22) v7(111.62,155.49) v7(111.69,160.78) v7(111.74,155) v7(111.79,205.25) v7(111.83,173.51) v7(111.87,160.31) v7(111.85,154.51) v7(111.96,208.15) v7(111.95,204.77) v7(111.89,171.23) v7(111.9,162.76) v7(111.96,154.01) v7(112.07,173.06) v7(112.05,159.83) v7(112.05,153.51) v7(112.12,204.29) v7(112.1,170.77) v7(112.11,162.3) v7(112.13,153.01) v7(112.19,207.57) v7(112.28,203.81) v7(112.22,159.35) v7(112.2,152.5) v7(112.26,152) v7(112.34,206.98) v7(112.38,206.53) v7(112.31,172.61) v7(112.31,170.3) v7(112.32,161.83) v7(112.38,158.87) v7(112.31,151.49) v7(112.34,150.99) v7(112.37,150.48) v7(112.38,149.97) v7(112.38,149.46) v7(112.38,148.95) v7(112.38,148.45) v7(112.38,147.94) v7(112.38,147.43) v7(112.38,146.92) v7(112.38,146.41) v7(112.38,145.91) v7(112.38,145.4) v7(112.38,144.89) v7(112.38,144.38) v7(112.38,143.87) v7(112.38,143.37) v7(112.38,142.86) v7(112.38,142.35) v7(112.38,141.84) v7(112.38,141.33) v7(112.38,140.83) v7(112.38,140.32) v7(112.38,139.81) v7(112.38,139.3) v7(112.38,138.79) v7(112.38,138.29) v7(112.44,203.33) v7(112.55,206.05) v7(112.53,172.16) v7(112.51,169.84) v7(112.51,161.36) v7(112.53,158.38) v7(112.61,202.85) v7(112.67,157.9) v7(112.71,205.57) v7(112.77,202.37) v7(112.75,171.7) v7(112.71,169.37) v7(112.7,160.89) v7(112.88,205.09) v7(112.88,160.41) v7(112.81,157.41) v7(112.94,201.89) v7(112.96,171.24) v7(112.9,168.9) v7(112.93,156.91) v7(113.04,204.61) v7(113.08,168.43) v7(113.05,159.93) v7(113.05,156.42) v7(113.1,201.41) v7(113.17,170.77) v7(113.16,155.92) v7(113.21,204.13) v7(113.26,200.93) v7(113.27,167.95) v7(113.21,159.45) v7(113.26,155.43) v7(113.37,203.65) v7(113.37,170.31) v7(113.37,158.97) v7(113.35,154.93) v7(113.43,200.45) v7(113.44,167.48) v7(113.44,154.43) v7(113.53,203.17) v7(113.57,169.84) v7(113.52,158.48) v7(113.51,153.92) v7(113.58,153.42) v7(113.59,199.97) v7(113.61,167) v7(113.66,158) v7(113.64,152.92) v7(113.7,202.68) v7(113.76,199.48) v7(113.76,169.37) v7(113.78,166.52) v7(113.69,152.41) v7(113.73,151.9) v7(113.76,151.4) v7(113.86,202.2) v7(113.79,157.51) v7(113.79,150.89) v7(113.8,150.38) v7(113.81,149.87) v7(113.81,149.37) v7(113.81,148.86) v7(113.81,148.35) v7(113.81,147.84) v7(113.81,147.33) v7(113.81,146.83) v7(113.81,146.32) v7(113.81,145.81) v7(113.81,145.3) v7(113.81,144.79) v7(113.81,144.29) v7(113.81,143.78) v7(113.81,143.27) v7(113.81,142.76) v7(113.81,142.25) v7(113.81,141.75) v7(113.81,141.24) v7(113.81,140.73) v7(113.81,140.22) v7(113.81,139.71) v7(113.81,139.21) v7(113.81,138.7) v7(113.81,138.19) v7(113.92,199) v7(113.95,168.9) v7(113.94,166.03) v7(113.91,157.01) v7(114.03,201.72) v7(114.09,198.52) v7(114.03,156.52) v7(114.13,168.42) v7(114.09,165.55) v7(114.14,156.02) v7(114.19,201.24) v7(114.25,198.04) v7(114.24,165.06) v7(114.24,155.52) v7(114.35,200.76) v7(114.31,167.95) v7(114.33,155.02) v7(114.41,197.56) v7(114.48,167.47) v7(114.39,164.58) v7(114.41,154.52) v7(114.52,200.28) v7(114.58,197.08) v7(114.53,164.09) v7(114.49,154.02) v7(114.55,153.52) v7(114.68,199.8) v7(114.65,166.99) v7(114.66,163.6) v7(114.61,153.01) v7(114.66,152.51) v7(114.74,196.6) v7(114.7,152) v7(114.74,151.49) v7(114.76,150.99) v7(114.78,150.48) v7(114.85,199.32) v7(114.81,166.51) v7(114.79,163.11) v7(114.79,149.97) v7(114.79,149.46) v7(114.79,148.95) v7(114.79,148.45) v7(114.79,147.94) v7(114.79,147.43) v7(114.79,146.92) v7(114.79,146.41) v7(114.79,145.91) v7(114.79,145.4) v7(114.79,144.89) v7(114.79,144.38) v7(114.79,143.87) v7(114.79,143.37) v7(114.79,142.86) v7(114.79,142.35) v7(114.79,141.84) v7(114.79,141.33) v7(114.79,140.83) v7(114.79,140.32) v7(114.79,139.81) v7(114.79,139.3) v7(114.79,138.79) v7(114.79,138.29) v7(114.91,196.12) v7(114.97,166.03) v7(114.91,162.61) v7(115.01,198.84) v7(115.07,195.64) v7(115.03,162.12) v7(115.18,198.36) v7(115.12,165.54) v7(115.14,161.62) v7(115.23,195.16) v7(115.27,165.05) v7(115.24,161.13) v7(115.34,197.88) v7(115.34,160.63) v7(115.4,194.68) v7(115.41,164.57) v7(115.44,160.13) v7(115.5,197.4) v7(115.56,194.2) v7(115.54,164.08) v7(115.53,159.63) v7(115.67,196.92) v7(115.67,163.59) v7(115.61,159.13) v7(115.71,193.71) v7(115.69,158.63) v7(115.77,158.13) v7(115.83,196.43) v7(115.84,193.22) v7(115.8,163.09) v7(115.83,157.62) v7(115.98,192.73) v7(115.92,162.6) v7(115.89,157.12) v7(115.95,156.61) v7(115.9,136.93) v7(116,195.95) v7(116.03,162.11) v7(116,156.11) v7(116.05,155.6) v7(116.16,195.47) v7(116.1,192.24) v7(116.14,161.61) v7(116.09,155.09) v7(116.12,154.59) v7(116.15,154.08) v7(116.17,153.57) v7(116.23,191.75) v7(116.25,161.11) v7(116.19,153.07) v7(116.2,152.56) v7(116.21,152.05) v7(116.21,151.54) v7(116.21,151.03) v7(116.21,150.53) v7(116.21,150.02) v7(116.21,149.51) v7(116.21,149) v7(116.21,148.49) v7(116.21,147.99) v7(116.21,147.48) v7(116.21,146.97) v7(116.21,146.46) v7(116.21,145.95) v7(116.21,145.45) v7(116.21,144.94) v7(116.21,144.43) v7(116.21,143.92) v7(116.21,143.41) v7(116.21,142.91) v7(116.21,142.4) v7(116.21,141.89) v7(116.21,141.38) v7(116.21,140.87) v7(116.21,140.37) v7(116.21,139.86) v7(116.21,139.35) v7(116.21,138.84) v7(116.21,138.33) v7(116.32,194.99) v7(116.35,191.25) v7(116.34,160.61) v7(116.47,190.76) v7(116.44,160.11) v7(116.49,194.51) v7(116.52,159.61) v7(116.64,194.03) v7(116.59,190.26) v7(116.61,159.11) v7(116.68,158.61) v7(116.77,193.54) v7(116.7,189.77) v7(116.75,158.11) v7(116.7,136.93) v7(116.81,189.27) v7(116.82,157.6) v7(116.88,157.1) v7(116.9,193.05) v7(116.92,188.78) v7(116.94,156.59) v7(117.03,192.55) v7(117.02,188.28) v7(116.99,156.09) v7(117.03,155.58) v7(117.07,155.08) v7(117.16,192.06) v7(117.12,187.78) v7(117.1,154.57) v7(117.13,154.06) v7(117.15,153.55) v7(117.17,153.05) v7(117.18,152.54) v7(117.28,191.57) v7(117.22,187.28) v7(117.19,152.03) v7(117.19,151.52) v7(117.19,151.01) v7(117.19,150.51) v7(117.19,150) v7(117.19,149.49) v7(117.19,148.98) v7(117.19,148.47) v7(117.19,147.97) v7(117.19,147.46) v7(117.19,146.95) v7(117.19,146.44) v7(117.19,145.93) v7(117.19,145.43) v7(117.19,144.92) v7(117.19,144.41) v7(117.19,143.9) v7(117.19,143.39) v7(117.19,142.89) v7(117.19,142.38) v7(117.19,141.87) v7(117.19,141.36) v7(117.19,140.85) v7(117.19,140.35) v7(117.19,139.84) v7(117.19,139.33) v7(117.19,138.82) v7(117.19,138.31) v7(117.31,186.78) v7(117.4,191.08) v7(117.4,186.28) v7(117.52,190.58) v7(117.49,185.78) v7(117.57,185.28) v7(117.5,137.73) v7(117.5,136.93) v7(117.63,190.09) v7(117.65,184.78) v7(117.74,189.59) v7(117.73,184.28) v7(117.85,189.09) v7(117.81,183.78) v7(117.88,183.27) v7(117.95,188.6) v7(117.94,182.77) v7(118.05,188.1) v7(118.01,182.26) v7(118.07,181.76) v7(118.15,187.6) v7(118.13,181.26) v7(118.18,180.75) v7(118.25,187.1) v7(118.23,180.25) v7(118.28,179.74) v7(118.34,186.6) v7(118.33,179.23) v7(118.37,178.73) v7(118.3,136.93) v7(118.43,186.1) v7(118.41,178.22) v7(118.44,177.71) v7(118.47,177.21) v7(118.51,185.6) v7(118.5,176.7) v7(118.53,176.19) v7(118.55,175.68) v7(118.57,175.18) v7(118.58,174.67) v7(118.59,185.1) v7(118.67,184.6) v7(118.59,174.16) v7(118.6,173.65) v7(118.61,173.15) v7(118.61,172.64) v7(118.61,172.13) v7(118.61,171.62) v7(118.61,171.11) v7(118.61,170.61) v7(118.61,170.1) v7(118.61,169.59) v7(118.61,169.08) v7(118.61,168.57) v7(118.61,168.07) v7(118.61,167.56) v7(118.61,167.05) v7(118.61,166.54) v7(118.61,166.03) v7(118.61,165.53) v7(118.61,165.02) v7(118.61,164.51) v7(118.61,164) v7(118.61,163.49) v7(118.61,162.99) v7(118.61,162.48) v7(118.61,161.97) v7(118.61,161.46) v7(118.61,160.95) v7(118.61,160.45) v7(118.61,159.94) v7(118.61,159.43) v7(118.61,158.92) v7(118.61,158.41) v7(118.61,157.91) v7(118.61,157.4) v7(118.61,156.89) v7(118.61,156.38) v7(118.61,155.87) v7(118.61,155.37) v7(118.61,154.86) v7(118.61,154.35) v7(118.61,153.84) v7(118.61,153.33) v7(118.61,152.83) v7(118.61,152.32) v7(118.61,151.81) v7(118.61,151.3) v7(118.61,150.79) v7(118.61,150.29) v7(118.61,149.78) v7(118.61,149.27) v7(118.61,148.76) v7(118.61,148.25) v7(118.61,147.75) v7(118.61,147.24) v7(118.61,146.73) v7(118.61,146.22) v7(118.61,145.71) v7(118.61,145.21) v7(118.61,144.7) v7(118.61,144.19) v7(118.61,143.68) v7(118.61,143.17) v7(118.61,142.67) v7(118.61,142.16) v7(118.61,141.65) v7(118.61,141.14) v7(118.61,140.63) v7(118.61,140.13) v7(118.61,139.62) v7(118.61,139.11) v7(118.61,138.6) v7(118.61,138.09) v7(118.75,184.09) v7(118.82,183.59) v7(118.89,183.09) v7(118.95,182.58) v7(119.02,182.08) v7(119.08,181.58) v7(119.13,181.07) v7(119.18,180.57) v7(119.1,136.93) v7(119.23,180.06) v7(119.28,179.55) v7(119.32,179.05) v7(119.36,178.54) v7(119.4,178.04) v7(119.43,177.53) v7(119.46,177.02) v7(119.49,176.51) v7(119.51,176.01) v7(119.53,175.5) v7(119.55,174.99) v7(119.56,174.48) v7(119.58,173.98) v7(119.58,173.47) v7(119.59,172.96) v7(119.59,172.45) v7(119.59,171.94) v7(119.59,171.44) v7(119.59,170.93) v7(119.59,170.42) v7(119.59,169.91) v7(119.59,169.4) v7(119.59,168.9) v7(119.59,168.39) v7(119.59,167.88) v7(119.59,167.37) v7(119.59,166.86) v7(119.59,166.36) v7(119.59,165.85) v7(119.59,165.34) v7(119.59,164.83) v7(119.59,164.32) v7(119.59,163.82) v7(119.59,163.31) v7(119.59,162.8) v7(119.59,162.29) v7(119.59,161.78) v7(119.59,161.28) v7(119.59,160.77) v7(119.59,160.26) v7(119.59,159.75) v7(119.59,159.24) v7(119.59,158.74) v7(119.59,158.23) v7(119.59,157.72) v7(119.59,157.21) v7(119.59,156.7) v7(119.59,156.2) v7(119.59,155.69) v7(119.59,155.18) v7(119.59,154.67) v7(119.59,154.16) v7(119.59,153.66) v7(119.59,153.15) v7(119.59,152.64) v7(119.59,152.13) v7(119.59,151.62) v7(119.59,151.12) v7(119.59,150.61) v7(119.59,150.1) v7(119.59,149.59) v7(119.59,149.08) v7(119.59,148.58) v7(119.59,148.07) v7(119.59,147.56) v7(119.59,147.05) v7(119.59,146.54) v7(119.59,146.04) v7(119.59,145.53) v7(119.59,145.02) v7(119.59,144.51) v7(119.59,144) v7(119.59,143.5) v7(119.59,142.99) v7(119.59,142.48) v7(119.59,141.97) v7(119.59,141.46) v7(119.59,140.96) v7(119.59,140.45) v7(119.59,139.94) v7(119.59,139.43) v7(119.59,138.92) v7(119.59,138.42) v7(119.9,137.73) v7(119.9,136.93) v7(120.4,139.06) v7(120.42,138.38) v7(124.09,138.6) v7(124.69,137.74) v7(125.07,175.78) v7(125.06,175.27) v7(125.04,174.76) v7(125.03,174.26) v7(125.02,173.75) v7(125.01,173.24) v7(125.01,172.73) v7(125.01,172.23) v7(125.01,171.72) v7(125.01,171.21) v7(125.01,170.7) v7(125.01,170.19) v7(125.01,169.69) v7(125.01,169.18) v7(125.01,168.67) v7(125.01,168.16) v7(125.01,167.65) v7(125.01,167.15) v7(125.01,166.64) v7(125.01,166.13) v7(125.01,165.62) v7(125.01,165.11) v7(125.01,164.61) v7(125.01,164.1) v7(125.01,163.59) v7(125.01,163.08) v7(125.01,162.57) v7(125.01,162.07) v7(125.01,161.56) v7(125.01,161.05) v7(125.01,160.54) v7(125.01,160.03) v7(125.01,159.53) v7(125.01,159.02) v7(125.01,158.51) v7(125.01,158) v7(125.01,157.49) v7(125.01,156.99) v7(125.01,156.48) v7(125.01,155.97) v7(125.01,155.46) v7(125.01,154.95) v7(125.01,154.45) v7(125.01,153.94) v7(125.01,153.43) v7(125.01,152.92) v7(125.01,152.41) v7(125.01,151.91) v7(125.01,151.4) v7(125.01,150.89) v7(125.01,150.38) v7(125.01,149.87) v7(125.01,149.37) v7(125.01,148.86) v7(125.01,148.35) v7(125.01,147.84) v7(125.01,146.83) v7(125.01,146.32) v7(125.01,145.81) v7(125.01,145.3) v7(125.01,144.79) v7(125.01,144.29) v7(125.01,143.78) v7(125.01,143.27) v7(125.01,142.76) v7(125.01,142.25) v7(125.01,141.75) v7(125.01,141.24) v7(125.01,140.73) v7(125.01,140.22) v7(125.01,139.71) v7(125.01,139.21) v7(125.01,138.7) v7(125.01,138.19) v7(125.18,177.81) v7(125.15,177.3) v7(125.12,176.8) v7(125.1,176.29) v7(125.26,178.82) v7(125.22,178.32) v7(125.34,179.84) v7(125.3,179.33) v7(125.44,180.85) v7(125.39,180.34) v7(125.55,181.86) v7(125.5,181.35) v7(125.68,182.86) v7(125.62,182.36) v7(125.75,183.37) v7(125.82,183.87) v7(125.97,184.88) v7(125.89,184.37) v7(126.05,185.38) v7(126.08,176.39) v7(126.06,175.88) v7(126.04,175.37) v7(126.02,174.86) v7(126.01,174.35) v7(126,173.85) v7(125.99,173.34) v7(125.99,172.83) v7(125.99,172.32) v7(125.99,171.81) v7(125.99,171.31) v7(125.99,170.8) v7(125.99,170.29) v7(125.99,169.78) v7(125.99,169.27) v7(125.99,168.77) v7(125.99,168.26) v7(125.99,167.75) v7(125.99,167.24) v7(125.99,166.73) v7(125.99,166.23) v7(125.99,165.72) v7(125.99,165.21) v7(125.99,164.7) v7(125.99,164.19) v7(125.99,163.69) v7(125.99,163.18) v7(125.99,162.67) v7(125.99,162.16) v7(125.99,161.65) v7(125.99,161.15) v7(125.99,160.64) v7(125.99,160.13) v7(125.99,159.62) v7(125.99,159.11) v7(125.99,158.61) v7(125.99,158.1) v7(125.99,157.59) v7(125.99,157.08) v7(125.99,156.57) v7(125.99,156.07) v7(125.99,155.56) v7(125.99,155.05) v7(125.99,154.54) v7(125.99,154.03) v7(125.99,153.53) v7(125.99,153.02) v7(125.99,152.51) v7(125.99,152) v7(125.99,151.49) v7(125.99,150.99) v7(125.99,150.48) v7(125.99,149.97) v7(125.99,149.46) v7(125.99,148.95) v7(125.99,148.45) v7(125.99,147.94) v7(125.99,147.43) v7(125.99,146.92) v7(125.99,146.41) v7(125.99,145.91) v7(125.99,145.4) v7(125.99,144.89) v7(125.99,144.38) v7(125.99,143.87) v7(125.99,143.37) v7(125.99,142.86) v7(125.99,142.35) v7(125.99,141.84) v7(125.99,141.33) v7(125.99,140.83) v7(125.99,140.32) v7(125.99,139.81) v7(125.99,139.3) v7(125.99,138.79) v7(125.99,138.29) v7(126.13,185.88) v7(126.17,177.91) v7(126.14,177.4) v7(126.11,176.89) v7(126.22,186.38) v7(126.24,178.92) v7(126.21,178.41) v7(126.31,186.88) v7(126.38,180.44) v7(126.33,179.93) v7(126.29,179.43) v7(126.4,187.38) v7(126.44,180.94) v7(126.5,187.88) v7(126.55,181.95) v7(126.49,181.45) v7(126.6,188.38) v7(126.68,182.96) v7(126.61,182.46) v7(126.7,188.87) v7(126.75,183.46) v7(126.81,189.37) v7(126.82,183.97) v7(126.92,189.87) v7(126.97,184.97) v7(126.89,184.47) v7(127.03,190.36) v7(127.06,185.47) v7(127.14,190.86) v7(127.14,185.97) v7(127.1,137.73) v7(127.1,136.93) v7(127.26,191.35) v7(127.23,186.47) v7(127.38,191.84) v7(127.32,186.97) v7(127.42,187.47) v7(127.46,153.94) v7(127.44,153.43) v7(127.42,152.92) v7(127.41,152.41) v7(127.41,151.91) v7(127.41,151.4) v7(127.41,150.89) v7(127.41,150.38) v7(127.41,149.87) v7(127.41,149.37) v7(127.41,148.86) v7(127.41,148.35) v7(127.41,147.84) v7(127.41,147.33) v7(127.41,146.83) v7(127.41,146.32) v7(127.41,145.81) v7(127.41,145.3) v7(127.41,144.79) v7(127.41,144.29) v7(127.41,143.78) v7(127.41,143.27) v7(127.41,142.76) v7(127.41,142.25) v7(127.41,141.75) v7(127.41,141.24) v7(127.41,140.73) v7(127.41,140.22) v7(127.41,139.71) v7(127.41,139.21) v7(127.41,138.7) v7(127.41,138.19) v7(127.51,192.34) v7(127.51,187.97) v7(127.56,155.46) v7(127.52,154.95) v7(127.49,154.44) v7(127.64,192.83) v7(127.61,188.47) v7(127.65,156.47) v7(127.6,155.96) v7(127.77,193.32) v7(127.72,188.96) v7(127.76,157.48) v7(127.7,156.97) v7(127.83,189.46) v7(127.9,193.81) v7(127.94,189.96) v7(127.97,158.99) v7(127.9,158.49) v7(127.9,136.93) v7(128.04,194.3) v7(128.05,190.45) v7(128.05,159.49) v7(128.17,194.79) v7(128.17,190.95) v7(128.14,159.99) v7(128.23,160.49) v7(128.3,195.28) v7(128.29,191.44) v7(128.33,160.99) v7(128.44,195.77) v7(128.41,191.93) v7(128.43,161.49) v7(128.47,154.54) v7(128.44,154.03) v7(128.42,153.53) v7(128.41,153.02) v7(128.39,152.51) v7(128.39,152) v7(128.39,151.49) v7(128.39,150.99) v7(128.39,150.48) v7(128.39,149.97) v7(128.39,149.46) v7(128.39,148.95) v7(128.39,148.45) v7(128.39,147.94) v7(128.39,147.43) v7(128.39,146.92) v7(128.39,146.41) v7(128.39,145.91) v7(128.39,145.4) v7(128.39,144.89) v7(128.39,144.38) v7(128.39,143.87) v7(128.39,143.37) v7(128.39,142.86) v7(128.39,142.35) v7(128.39,141.84) v7(128.39,141.33) v7(128.39,140.83) v7(128.39,140.32) v7(128.39,139.81) v7(128.39,139.3) v7(128.39,138.79) v7(128.39,138.29) v7(128.57,196.26) v7(128.54,192.42) v7(128.54,161.98) v7(128.55,155.55) v7(128.51,155.05) v7(128.67,192.92) v7(128.65,162.48) v7(128.64,156.57) v7(128.59,156.06) v7(128.7,196.75) v7(128.77,162.97) v7(128.76,157.57) v7(128.7,157.07) v7(128.7,136.93) v7(128.83,197.24) v7(128.8,193.41) v7(128.82,158.08) v7(128.97,197.73) v7(128.94,193.89) v7(128.89,163.46) v7(128.98,159.08) v7(128.9,158.58) v7(129.08,194.38) v7(129.02,163.96) v7(129.06,159.58) v7(129.1,198.22) v7(129.16,164.45) v7(129.15,160.08) v7(129.23,198.71) v7(129.21,194.88) v7(129.24,160.58) v7(129.36,199.2) v7(129.34,195.37) v7(129.3,164.93) v7(129.34,161.08) v7(129.47,195.86) v7(129.44,165.42) v7(129.45,161.58) v7(129.5,199.69) v7(129.56,162.07) v7(129.63,200.18) v7(129.61,196.35) v7(129.59,165.91) v7(129.68,162.57) v7(129.76,200.67) v7(129.74,196.84) v7(129.75,166.39) v7(129.87,197.33) v7(129.8,163.06) v7(129.85,151.4) v7(129.83,150.89) v7(129.82,150.38) v7(129.81,149.87) v7(129.81,149.37) v7(129.81,148.86) v7(129.81,148.35) v7(129.81,147.84) v7(129.81,147.33) v7(129.81,146.83) v7(129.81,146.32) v7(129.81,145.81) v7(129.81,145.3) v7(129.81,144.79) v7(129.81,144.29) v7(129.81,143.78) v7(129.81,143.27) v7(129.81,142.76) v7(129.81,142.25) v7(129.81,141.75) v7(129.81,141.24) v7(129.81,140.73) v7(129.81,140.22) v7(129.81,139.71) v7(129.81,139.21) v7(129.81,138.7) v7(129.81,138.19) v7(129.89,201.16) v7(129.91,166.87) v7(129.93,163.55) v7(129.97,152.92) v7(129.93,152.41) v7(129.89,151.9) v7(130.02,201.65) v7(130,197.82) v7(130.07,167.35) v7(130.06,164.04) v7(130.03,153.42) v7(130.16,202.14) v7(130.13,198.31) v7(130.17,154.43) v7(130.1,153.92) v7(130.27,198.8) v7(130.24,167.83) v7(130.2,164.53) v7(130.25,154.93) v7(130.29,202.63) v7(130.34,165.02) v7(130.34,155.43) v7(130.42,203.12) v7(130.4,199.29) v7(130.42,168.31) v7(130.44,155.93) v7(130.55,203.62) v7(130.53,199.78) v7(130.49,165.51) v7(130.55,156.42) v7(130.66,200.27) v7(130.6,168.78) v7(130.64,165.99) v7(130.66,156.92) v7(130.69,204.11) v7(130.78,157.41) v7(130.82,204.6) v7(130.8,200.76) v7(130.79,169.25) v7(130.8,166.47) v7(130.87,152) v7(130.84,151.49) v7(130.81,150.99) v7(130.8,150.48) v7(130.79,149.97) v7(130.79,149.46) v7(130.79,148.95) v7(130.79,148.45) v7(130.79,147.94) v7(130.79,147.43) v7(130.79,146.92) v7(130.79,146.41) v7(130.79,145.91) v7(130.79,145.4) v7(130.79,144.89) v7(130.79,144.38) v7(130.79,143.87) v7(130.79,143.37) v7(130.79,142.86) v7(130.79,142.35) v7(130.79,141.84) v7(130.79,141.33) v7(130.79,140.83) v7(130.79,140.32) v7(130.79,139.81) v7(130.79,139.3) v7(130.79,138.79) v7(130.79,138.29) v7(130.95,205.09) v7(130.93,201.25) v7(130.98,169.72) v7(130.97,166.95) v7(130.91,157.9) v7(130.97,153.01) v7(130.92,152.51) v7(131.08,205.58) v7(131.06,201.74) v7(131.05,158.39) v7(131.03,153.52) v7(131.18,170.19) v7(131.14,167.43) v7(131.17,154.52) v7(131.1,154.02) v7(131.22,206.07) v7(131.19,202.23) v7(131.2,158.88) v7(131.26,155.02) v7(131.35,206.56) v7(131.33,202.72) v7(131.38,170.66) v7(131.31,167.91) v7(131.35,159.36) v7(131.35,155.52) v7(131.47,207.19) v7(131.46,203.21) v7(131.46,156.02) v7(131.55,207.77) v7(131.58,171.12) v7(131.5,168.38) v7(131.51,159.84) v7(131.57,156.52) v7(131.65,208.33) v7(131.59,203.7) v7(131.68,168.86) v7(131.68,160.32) v7(131.72,204.19) v7(131.69,157.01) v7(131.86,204.68) v7(131.8,171.59) v7(131.87,169.33) v7(131.86,160.8) v7(131.82,157.5) v7(131.95,157.99) v7(131.99,205.17) v7(132.01,172.04) v7(132.07,169.79) v7(132.05,161.27) v7(132.12,205.67) v7(132.1,158.48) v7(132.25,206.16) v7(132.23,172.5) v7(132.27,170.26) v7(132.24,161.74) v7(132.25,158.96) v7(132.26,150.89) v7(132.23,150.38) v7(132.22,149.87) v7(132.22,149.37) v7(132.22,148.86) v7(132.22,148.35) v7(132.22,147.84) v7(132.22,147.33) v7(132.22,146.83) v7(132.22,146.32) v7(132.22,145.81) v7(132.22,145.3) v7(132.22,144.79) v7(132.22,144.29) v7(132.22,143.78) v7(132.22,143.27) v7(132.22,142.76) v7(132.22,142.25) v7(132.22,141.75) v7(132.22,141.24) v7(132.22,140.73) v7(132.22,140.22) v7(132.22,139.71) v7(132.22,139.21) v7(132.22,138.7) v7(132.22,138.19) v7(132.33,151.9) v7(132.29,151.4) v7(132.46,172.95) v7(132.48,170.72) v7(132.44,162.21) v7(132.41,159.44) v7(132.46,152.91) v7(132.39,152.41) v7(132.51,206.55) v7(132.58,159.92) v7(132.54,153.41) v7(132.61,206.96) v7(132.65,162.67) v7(132.63,153.91) v7(132.7,173.4) v7(132.69,171.19) v7(132.76,160.4) v7(132.73,154.41) v7(132.79,207.47) v7(132.87,163.13) v7(132.84,154.91) v7(132.94,208) v7(132.94,173.85) v7(132.91,171.65) v7(132.94,160.87) v7(132.96,155.4) v7(133.18,174.3) v7(133.13,172.1) v7(133.09,163.58) v7(133.14,161.34) v7(133.1,155.89) v7(133.18,149.97) v7(133.17,149.46) v7(133.17,148.95) v7(133.17,148.45) v7(133.17,147.94) v7(133.17,147.43) v7(133.17,146.92) v7(133.17,146.41) v7(133.17,145.91) v7(133.17,145.4) v7(133.17,144.89) v7(133.17,144.38) v7(133.17,143.87) v7(133.17,143.37) v7(133.17,142.86) v7(133.17,142.35) v7(133.17,141.84) v7(133.17,141.33) v7(133.17,140.83) v7(133.17,140.32) v7(133.17,139.81) v7(133.17,139.3) v7(133.17,138.79) v7(133.17,138.29) v7(133.17,137.78) v7(133.24,156.38) v7(133.25,151.49) v7(133.22,150.98) v7(133.19,150.48) v7(133.36,172.55) v7(133.33,164.04) v7(133.34,161.81) v7(133.36,152.5) v7(133.3,152) v7(133.42,174.75) v7(133.4,156.86) v7(133.44,153) v7(133.56,164.48) v7(133.55,162.27) v7(133.56,157.34) v7(133.52,153.5) v7(133.66,175.19) v7(133.6,173) v7(133.62,154) v7(133.76,162.73) v7(133.74,157.82) v7(133.72,154.5) v7(133.84,173.45) v7(133.81,164.93) v7(133.84,154.99) v7(133.9,175.64) v7(133.93,158.29) v7(133.97,155.49) v7(134.08,173.9) v7(134.06,165.37) v7(133.99,163.19) v7(134.14,176.09) v7(134.13,158.76) v7(134.11,155.97) v7(134.22,163.64) v7(134.27,156.46) v7(134.38,176.54) v7(134.32,174.35) v7(134.33,165.81) v7(134.34,159.22) v7(134.46,164.08) v7(134.43,156.94) v7(134.56,174.79) v7(134.56,159.68) v7(134.62,176.99) v7(134.59,166.24) v7(134.61,157.41) v7(134.71,164.53) v7(134.79,160.13) v7(134.86,177.43) v7(134.8,175.24) v7(134.87,166.66) v7(134.8,157.89) v7(134.96,164.97) v7(135.04,175.69) v7(135.02,160.58) v7(134.99,158.35) v7(135.1,177.88) v7(135.15,167.09) v7(135.28,176.14) v7(135.23,165.4) v7(135.27,161.02) v7(135.2,158.82) v7(135.34,178.33) v7(135.44,167.5) v7(135.42,159.28) v7(135.58,178.78) v7(135.52,176.59) v7(135.5,165.83) v7(135.53,161.46) v7(135.65,159.73) v7(135.76,177.03) v7(135.74,167.92) v7(135.77,166.26) v7(135.82,179.22) v7(135.8,161.89) v7(135.89,160.18) v7(136.06,179.67) v7(136,177.48) v7(136.04,168.33) v7(136.06,166.68) v7(136.08,162.31) v7(136.14,160.62) v7(136.24,177.93) v7(136.3,180.12) v7(136.35,168.73) v7(136.35,167.1) v7(136.37,162.73) v7(136.48,178.38) v7(136.4,161.05) v7(136.54,180.57) v7(136.66,169.13) v7(136.65,167.51) v7(136.67,163.14) v7(136.67,161.48) v7(136.78,181.02) v7(136.72,178.83) v7(136.96,179.27) v7(136.99,169.52) v7(136.95,167.91) v7(136.97,163.55) v7(136.96,161.91) v7(137.02,181.46) v7(137.26,181.91) v7(137.2,179.72) v7(137.26,168.31) v7(137.25,162.32) v7(137.31,169.91) v7(137.29,163.95) v7(137.43,180.17) v7(137.5,182.36) v7(137.58,168.71) v7(137.55,162.73) v7(137.67,180.62) v7(137.65,170.29) v7(137.61,164.34) v7(137.74,182.81) v7(137.86,163.14) v7(137.98,183.26) v7(137.91,181.06) v7(137.91,169.1) v7(137.94,164.72) v7(137.99,170.66) v7(138.15,181.51) v7(138.18,163.53) v7(138.22,183.7) v7(138.24,169.48) v7(138.28,165.1) v7(138.34,171.03) v7(138.46,184.15) v7(138.39,181.96) v7(138.58,169.86) v7(138.5,163.92) v7(138.63,182.41) v7(138.63,165.47) v7(138.7,184.6) v7(138.69,171.4) v7(138.87,182.86) v7(138.84,164.3) v7(138.94,185.05) v7(138.93,170.23) v7(139.05,171.76) v7(138.99,165.83) v7(139.18,185.49) v7(139.11,183.3) v7(139.28,170.6) v7(139.19,164.67) v7(139.35,183.75) v7(139.35,166.19) v7(139.42,185.94) v7(139.42,172.11) v7(139.54,165.03) v7(139.66,186.39) v7(139.59,184.2) v7(139.63,170.96) v7(139.71,166.55) v7(139.83,184.65) v7(139.79,172.46) v7(139.9,186.84) v7(139.9,165.39) v7(140.07,185.1) v7(140,171.32) v7(140.07,166.91) v7(140.14,187.29) v7(140.16,172.8) v7(140.26,165.75) v7(140.38,187.73) v7(140.31,185.54) v7(140.37,171.66) v7(140.43,167.27) v7(140.55,185.99) v7(140.55,173.13) v7(140.62,188.18) v7(140.62,166.11) v7(140.74,172.01) v7(140.86,188.63) v7(140.79,186.44) v7(140.79,167.63) v7(140.93,173.46) v7(140.98,166.47) v7(141.03,186.89) v7(141.09,189.08) v7(141.12,172.34) v7(141.15,167.98) v7(141.27,187.33) v7(141.33,189.53) v7(141.33,173.78) v7(141.34,166.83) v7(141.57,189.97) v7(141.51,187.78) v7(141.51,172.67) v7(141.51,168.34) v7(141.75,188.23) v7(141.72,174.11) v7(141.7,167.19) v7(141.81,190.42) v7(141.87,168.7) v7(141.9,172.99) v7(142.05,190.87) v7(141.99,188.68) v7(142.06,167.55) v7(142.1,174.44) v7(142.23,189.13) v7(142.22,169.06) v7(142.29,191.32) v7(142.29,173.32) v7(142.47,189.57) v7(142.42,167.91) v7(142.53,191.77) v7(142.49,174.77) v7(142.58,169.42) v7(142.68,173.65) v7(142.77,192.21) v7(142.71,190.02) v7(142.78,168.27) v7(142.88,175.09) v7(142.95,190.47) v7(142.94,169.78) v7(143.01,192.66) v7(143.07,173.98) v7(143.13,168.63) v7(143.25,193.11) v7(143.19,190.92) v7(143.27,175.42) v7(143.3,170.14) v7(143.43,191.37) v7(143.46,174.3) v7(143.49,193.56) v7(143.49,168.98) v7(143.67,191.81) v7(143.66,175.75) v7(143.66,170.5) v7(143.73,194) v7(143.85,174.63) v7(143.85,169.34) v7(143.98,194.45) v7(143.91,192.26) v7(144.04,176.08) v7(144.02,170.86) v7(144.15,192.71) v7(144.24,194.89) v7(144.23,174.96) v7(144.21,169.7) v7(144.38,171.22) v7(144.39,193.16) v7(144.43,176.41) v7(144.49,195.33) v7(144.57,170.06) v7(144.63,193.6) v7(144.62,175.29) v7(144.74,195.77) v7(144.74,171.58) v7(144.88,194.05) v7(144.82,176.74) v7(144.93,170.42) v7(145,196.21) v7(145.01,175.62) v7(145.13,194.49) v7(145.1,171.93) v7(145.25,196.65) v7(145.21,177.06) v7(145.29,170.78) v7(145.39,194.93) v7(145.4,175.94) v7(145.47,172.28) v7(145.51,197.09) v7(145.64,195.37) v7(145.59,177.39) v7(145.65,171.14) v7(145.76,197.53) v7(145.79,176.27) v7(145.86,172.61) v7(145.9,195.81) v7(145.98,177.72) v7(146.01,197.97) v7(146.02,171.49) v7(146.15,196.25) v7(146.17,176.6) v7(146.27,198.41) v7(146.25,172.94) v7(146.37,178.05) v7(146.4,196.69) v7(146.4,171.82) v7(146.52,198.85) v7(146.56,176.93) v7(146.66,197.13) v7(146.65,173.25) v7(146.78,199.29) v7(146.76,178.38) v7(146.79,172.15) v7(146.91,197.57) v7(146.95,177.26) v7(147.03,199.73) v7(147.06,173.55) v7(147.17,198) v7(147.15,178.7) v7(147.28,200.17) v7(147.19,172.46) v7(147.34,177.58) v7(147.42,198.44) v7(147.47,173.84) v7(147.54,200.61) v7(147.53,179.03) v7(147.67,198.88) v7(147.6,172.77) v7(147.72,177.91) v7(147.79,201.05) v7(147.93,199.32) v7(147.92,179.36) v7(147.9,174.12) v7(148.05,201.49) v7(148.01,173.06) v7(148.18,199.76) v7(148.11,178.24) v7(148.3,201.93) v7(148.31,179.69) v7(148.33,174.39) v7(148.44,202.46) v7(148.44,200.2) v7(148.44,173.33) v7(148.5,178.57) v7(148.77,203.05) v7(148.69,200.64) v7(148.7,180.02) v7(148.77,174.64) v7(148.87,173.6) v7(148.94,201.08) v7(148.89,178.9) v7(149.05,203.5) v7(149.08,180.34) v7(149.2,201.52) v7(149.28,179.23) v7(149.22,174.88) v7(149.31,173.85) v7(149.47,180.67) v7(149.56,201.9) v7(149.66,179.55) v7(149.67,175.11) v7(149.76,174.09) v7(149.89,202.39) v7(149.86,181) v7(150.05,179.88) v7(150.16,202.9) v7(150.13,175.33) v7(150.25,181.33) v7(150.21,174.32) v7(150.44,180.21) v7(150.64,181.66) v7(150.59,175.54) v7(150.68,174.54) v7(150.83,180.54) v7(151.02,181.99) v7(151.06,175.73) v7(151.14,174.74) v7(151.21,180.87) v7(151.41,182.31) v7(151.54,175.91) v7(151.6,181.19) v7(151.61,174.92) v7(151.8,182.64) v7(151.99,181.52) v7(152.02,176.08) v7(152.09,175.1) v7(152.19,182.97) v7(152.38,181.85) v7(152.57,183.3) v7(152.5,176.23) v7(152.58,175.25) v7(152.77,182.18) v7(152.96,183.63) v7(152.99,176.37) v7(153.06,175.4) v7(153.15,182.51) v7(153.35,183.95) v7(153.48,176.49) v7(153.54,182.83) v7(153.55,175.53) v7(153.74,184.28) v7(153.93,183.16) v7(153.98,176.61) v7(154.05,175.65) v7(154.13,184.61) v7(154.32,183.49) v7(154.48,176.7) v7(154.51,184.94) v7(154.55,175.75) v7(154.7,183.82) v7(154.9,185.27) v7(154.98,176.79) v7(155.05,175.84) v7(155.09,184.15) v7(155.29,185.59) v7(155.48,184.48) v7(155.48,176.86) v7(155.55,175.91) v7(155.68,185.92) v7(155.87,184.8) v7(155.99,176.92) v7(156.06,186.25) v7(156.05,175.97) v7(156.26,185.13) v7(156.45,186.58) v7(156.49,176.96) v7(156.56,176.01) v7(156.64,185.46) v7(156.84,186.91) v7(157.03,185.79) v7(157,176.99) v7(157.07,176.04) v7(157.23,187.24) v7(157.42,186.12) v7(157.51,177) v7(157.57,176.05) v7(157.62,187.56) v7(157.81,186.44) v7(158,187.89) v7(158.02,177.01) v7(158.08,176.05) v7(158.2,186.77) v7(158.39,188.22) v7(158.58,187.1) v7(158.52,177.01) v7(158.59,176.05) v7(158.78,188.55) v7(158.97,187.43) v7(159.03,177.01) v7(159.17,188.88) v7(159.1,176.05) v7(159.36,187.76) v7(159.56,189.2) v7(159.54,177.01) v7(159.61,176.05) v7(159.75,188.08) v7(159.94,189.53) v7(160.05,177.01) v7(160.13,188.41) v7(160.11,176.05) v7(160.33,189.86) v7(160.52,188.74) v7(160.56,177.01) v7(160.62,176.05) v7(160.72,190.19) v7(160.91,189.07) v7(161.06,177.01) v7(161.11,190.52) v7(161.13,176.05) v7(161.3,189.4) v7(161.49,190.84) v7(161.57,177.01) v7(161.69,189.73) v7(161.64,176.05) v7(161.88,191.17) v7(162.07,190.05) v7(162.08,177.01) v7(162.15,176.05) v7(162.27,191.5) v7(162.46,190.38) v7(162.66,191.83) v7(162.59,177.01) v7(162.65,176.05) v7(162.85,190.71) v7(163.05,192.16) v7(163.1,177.01) v7(163.16,176.05) v7(163.24,191.04) v7(163.43,192.49) v7(163.62,191.37) v7(163.6,177.01) v7(163.67,176.05) v7(163.91,192.99) v7(164.01,191.69) v7(164.11,177.01) v7(164.18,176.05) v7(164.31,193.32) v7(164.54,191.67) v7(164.62,177.01) v7(164.69,193.75) v7(164.69,176.05) v7(165.05,191.77) v7(165.13,177.01) v7(165.19,176.05) v7(165.3,192.38) v7(165.63,192.71) v7(165.64,177.01) v7(165.7,176.05) v7(166.14,177.01) v7(166.21,176.05) v7(166.65,177.01) v7(166.72,176.05) v7(167.16,177.01) v7(167.23,176.05) v7(167.67,177.01) v7(167.73,176.05) v7(168.18,177.01) v7(168.24,176.05) v7(168.68,177.01) v7(168.75,176.05) v7(169.19,177.01) v7(169.26,176.05) v7(169.7,177.01) v7(169.77,176.05) v7(170.21,177.01) v7(170.27,176.05) v7(170.72,177.01) v7(170.78,176.05) v7(171.22,177.01) v7(171.29,176.05) v7(171.73,177.01) v7(171.8,176.05) v7(172.24,177.01) v7(172.31,176.05) v7(172.75,177.01) v7(172.81,176.05) v7(173.28,176) v7(173.41,177.14) v7(173.51,175.62) v7(174.02,177.24) v7(174.17,175.69) v7(174.68,177.22) v7(174.75,175.79) v8(110.29,128.14) v8(110.31,127.33) v8(120.45,180.44) v8(120.8,179.81) v8(121.16,179.02) v8(121.16,178.36) v8(121.16,177.75) v8(121.18,177.09) v8(121.18,176.5) v8(121.18,175.84) v8(121.18,175.21) v8(121.16,174.57) v8(121.18,173.99) v8(121.16,173.3) v8(121.16,172.69) v8(121.16,172.14) v8(121.16,171.45) v8(121.16,170.87) v8(121.16,170.26) v8(121.16,169.6) v8(121.16,168.83) v8(121.16,168.22) v8(121.18,167.59) v8(121.16,166.95) v8(121.16,166.32) v8(121.16,165.66) v8(121.16,165.02) v8(121.16,164.41) v8(121.18,163.8) v8(121.16,163.12) v8(121.18,162.46) v8(121.16,161.85) v8(121.16,161.24) v8(121.18,160.6) v8(121.11,159.99) v8(121.13,159.38) v8(121.13,158.78) v8(121.13,158.17) v8(121.13,157.53) v8(121.16,156.92) v8(121.18,156.16) v8(121.16,155.55) v8(121.16,154.94) v8(121.16,154.31) v8(121.16,153.67) v8(121.18,153.06) v8(121.16,152.4) v8(121.18,151.64) v8(121.18,151.03) v8(121.16,150.47) v8(121.16,149.86) v8(121.16,149.28) v8(121.16,148.59) v8(123.98,151) v8(123.98,150.5) v8(124.03,149.86) v8(124.03,149.23) v8(124.1,179.07) v8(124.1,178.44) v8(124.1,177.83) v8(124.1,177.22) v8(124.1,176.58) v8(124.1,175.92) v8(124.1,175.29) v8(124.1,174.68) v8(124.1,174.07) v8(124.1,173.43) v8(124.13,172.77) v8(124.13,172.14) v8(124.13,171.53) v8(124.13,170.92) v8(124.13,170.28) v8(124.13,169.52) v8(124.13,168.88) v8(124.13,168.27) v8(124.13,167.67) v8(124.13,167.03) v8(124.16,166.32) v8(124.16,165.68) v8(124.16,165.07) v8(124.16,164.46) v8(124.16,163.83) v8(124.13,163.17) v8(124.13,162.53) v8(124.13,161.93) v8(124.13,161.32) v8(124.13,160.68) v8(124.16,160.05) v8(124.16,159.41) v8(124.16,158.8) v8(124.16,158.19) v8(124.16,157.56) v8(124.18,156.82) v8(124.18,156.18) v8(124.18,155.57) v8(124.18,154.97) v8(124.13,154.08) v8(124.13,153.47) v8(124.13,152.91) v8(124.1,152.43) v8(124.1,151.84) v8(124.13,148.64) v8(124.38,179.93) v8(124.89,180.49) v8(125.04,148.29) v8(126.23,148.27) v8(127.15,148.97) v9(61.16,191.97) v9(61.8,191.82) v9(62.46,191.76) v9(62.85,191.36) v9(63.04,193.68) v9(63.09,193.12) v9(63.14,192.44) v9(63.2,191.02) v9(63.54,192.04) v9(63.54,190.68) v9(63.88,191.7) v9(63.88,190.34) v9(64.22,191.36) v9(64.22,190) v9(64.56,191.02) v9(64.56,189.65) v9(64.9,190.68) v9(64.9,189.31) v9(65.24,190.34) v9(65.24,188.97) v9(65.58,190) v9(65.58,188.63) v9(65.93,189.65) v9(65.93,188.29) v9(66.27,189.31) v9(66.61,188.97) v9(67.75,189.12) v9(68.33,189.08) v9(68.96,189.7) v9(69.36,185.17) v9(69.59,190.32) v9(70.44,186.25) v9(70.8,183.74) v9(71.52,187.33) v9(71.88,184.82) v9(72,182.53) v9(72.95,185.89) v9(73.08,183.61) v9(74.06,180.29) v9(74.16,184.69) v9(74.62,179.83) v9(74.62,179.37) v9(74.85,180.23) v9(74.85,178.97) v9(75.23,181.46) v9(75.24,180.46) v9(75.46,178.61) v9(75.79,180.55) v9(76.05,178.16) v9(76.14,180.9) v9(76.1,180.23) v9(76.23,181.45) v9(76.38,177.72) v9(76.4,182.63) v9(76.46,181.85) v9(76.46,180.59) v9(76.61,179.58) v9(76.86,182.08) v9(76.96,177.57) v9(77.17,180.14) v9(77.36,182.11) v9(77.42,179.27) v9(77.41,177.25) v9(77.72,181.85) v9(77.77,176.9) v9(78.11,181.25) v9(78.13,176.54) v9(78.41,180.57) v9(78.49,176.18) v9(78.85,175.82) v9(78.89,180.26) v9(79.22,175.47) v9(79.3,179.88) v9(79.5,179.32) v9(79.58,175.11) v9(79.67,178.94) v9(79.94,174.75) v9(80.04,178.59) v9(80.3,174.39) v9(80.4,178.23) v9(80.66,174.04) v9(80.76,177.88) v9(81.02,173.68) v9(81.12,177.52) v9(81.38,173.32) v9(81.49,177.17) v9(81.74,172.96) v9(81.85,176.81) v9(82.1,172.61) v9(82.21,176.45) v9(82.46,172.25) v9(82.57,176.1) v9(82.82,171.89) v9(82.94,175.74) v9(83.18,171.53) v9(83.3,175.39) v9(83.55,171.3) v9(83.66,175.03) v9(83.91,170.94) v9(84.02,174.67) v9(84.27,170.59) v9(84.39,174.32) v9(84.63,170.23) v9(84.75,173.96) v9(84.99,169.87) v9(85.11,173.61) v9(85.35,169.51) v9(85.47,173.25) v9(85.71,169.16) v9(85.84,172.9) v9(86.07,168.8) v9(86.2,172.54) v9(86.43,168.44) v9(86.56,172.18) v9(86.82,168.11) v9(86.92,171.83) v9(87.18,167.75) v9(87.29,171.47) v9(87.54,167.39) v9(87.65,171.12) v9(87.9,167.04) v9(88.01,170.76) v9(88.26,166.68) v9(88.35,170.46) v9(88.62,166.32) v9(88.71,170.1) v9(88.98,165.96) v9(89.07,169.74) v9(89.34,165.61) v9(89.44,169.39) v9(89.7,165.25) v9(89.8,169.03) v9(90.07,164.89) v9(90.16,168.68) v9(90.43,164.53) v9(90.53,168.32) v9(90.79,164.18) v9(90.89,167.97) v9(91.15,163.82) v9(91.25,167.61) v9(91.51,163.46) v9(91.59,167.25) v9(91.87,163.1) v9(91.95,166.89) v9(92.23,162.75) v9(92.31,166.53) v9(92.66,166.18) v9(92.59,162.39) v9(92.95,162.03) v9(93.02,165.82) v9(93.38,165.46) v9(93.31,161.67) v9(93.67,161.31) v9(93.74,165.1) v9(94.03,160.96) v9(94.1,164.74) v9(94.49,164.38) v9(94.4,160.6) v9(94.76,160.24) v9(94.84,164.02) v9(95.12,159.88) v9(95.2,163.66) v9(95.48,159.53) v9(95.56,163.3) v9(95.84,159.17) v9(95.92,162.94) v9(96.28,162.58) v9(96.22,158.76) v9(96.59,158.4) v9(96.64,162.22) v9(96.95,158.05) v9(97,161.86) v9(97.36,161.51) v9(97.31,157.69) v9(97.67,161.12) v9(97.67,157.33) v9(98.03,160.76) v9(98.03,156.97) v9(98.39,160.4) v9(98.39,156.62) v9(98.75,160.04) v9(98.75,156.26) v9(99.1,159.68) v9(99.11,155.9) v9(99.46,159.33) v9(99.47,155.54) v9(99.82,158.97) v9(99.83,155.19) v9(100.18,158.61) v9(100.19,154.83) v9(100.55,154.47) v9(100.62,158.17) v9(100.98,157.81) v9(100.92,154.11) v9(101.28,153.75) v9(101.34,157.45) v9(101.64,153.4) v9(101.7,157.09) v9(102.05,156.73) v9(102,153.04) v9(102.36,152.68) v9(102.41,156.38) v9(102.52,152.34) v9(102.52,151.83) v9(102.52,151.32) v9(102.52,150.82) v9(102.52,150.31) v9(102.77,156.02) v9(102.9,149.81) v9(103.13,155.66) v9(103.26,149.45) v9(103.54,155.37) v9(103.62,149.09) v9(103.9,155.01) v9(103.98,148.73) v9(104.26,154.66) v9(104.34,148.37) v9(104.62,154.3) v9(104.7,148.01) v9(104.98,153.94) v9(105.06,147.65) v9(105.24,153.36) v9(105.24,152.85) v9(105.24,152.34) v9(105.24,151.83) v9(105.24,151.32) v9(105.42,147.29) v9(105.49,150.99) v9(105.77,146.93) v9(105.85,150.63) v9(106.13,146.57) v9(106.21,150.27) v9(106.57,149.91) v9(106.49,146.22) v9(106.85,145.86) v9(106.93,149.55) v9(107.21,145.47) v9(107.29,149.19) v9(107.57,145.11) v9(107.65,148.83) v9(107.93,144.75) v9(108.01,148.47) v9(108.37,148.11) v9(108.29,144.39) v9(108.65,144.03) v9(108.72,147.75) v9(109.08,147.39) v9(109.01,143.68) v9(109.37,143.32) v9(109.44,147.03) v9(109.73,142.96) v9(109.8,146.68) v9(110.06,142.67) v9(110.16,146.32) v9(110.29,128.14) v9(110.31,127.33) v9(110.42,142.31) v9(110.52,145.96) v9(110.78,141.96) v9(110.88,145.62) v9(111.14,141.6) v9(111.24,145.26) v9(111.5,141.24) v9(111.6,144.9) v9(111.77,153.54) v9(111.74,140.91) v9(111.74,140.4) v9(111.74,139.89) v9(111.74,139.39) v9(111.74,138.88) v9(111.74,138.37) v9(111.74,137.86) v9(111.74,137.35) v9(111.74,136.85) v9(111.96,144.55) v9(112.32,144.19) v9(112.68,143.83) v9(113.04,143.47) v9(113.36,143.13) v9(113.77,142.75) v9(114.22,142.29) v9(114.43,141.75) v9(114.43,141.24) v9(114.43,140.73) v9(114.43,140.23) v9(114.43,139.72) v9(114.43,139.21) v9(114.43,138.7) v9(114.43,138.19) v9(114.43,137.69) v9(114.43,137.18) v9(114.43,136.67) v9(118.35,155.83) v9(118.54,159.21) v9(119.49,151.74) v9(119.89,204.77) v9(120.14,204.39) v9(120.47,203.94) v9(120.83,203.48) v9(120.95,203.1) v9(120.95,202.54) v9(120.95,202.06) v9(120.95,201.57) v9(120.95,201.09) v9(120.95,200.61) v9(120.95,200.13) v9(120.95,199.64) v9(120.95,199.16) v9(120.95,198.68) v9(120.95,198.2) v9(120.95,197.71) v9(120.95,197.23) v9(120.95,196.72) v9(120.95,196.24) v9(120.95,195.76) v9(120.95,195.28) v9(120.95,194.79) v9(120.95,194.31) v9(121.34,145.8) v9(121.34,145.19) v9(121.34,144.53) v9(121.34,143.92) v9(121.34,143.23) v9(121.34,142.47) v9(121.34,141.73) v9(121.34,141) v9(121.34,140.23) v9(121.34,139.47) v9(121.34,138.71) v9(121.87,155.78) v9(121.85,154.98) v9(121.92,203.1) v9(121.92,202.54) v9(121.92,202.06) v9(121.92,201.57) v9(121.92,201.09) v9(121.92,200.61) v9(121.92,200.13) v9(121.92,199.64) v9(121.92,199.16) v9(121.92,198.68) v9(121.92,198.2) v9(121.92,197.71) v9(121.92,197.23) v9(121.92,196.72) v9(121.92,196.24) v9(121.92,195.76) v9(121.92,195.28) v9(121.92,194.79) v9(121.92,194.31) v9(122.02,203.53) v9(122.33,204.06) v9(122.58,204.44) v9(122.66,155.77) v9(122.66,154.98) v9(122.76,204.85) v9(123.39,155.75) v9(123.45,154.98) v9(124.08,145.77) v9(124.08,145.21) v9(124.08,144.65) v9(124.08,144.04) v9(124.08,143.31) v9(124.08,142.54) v9(124.08,141.76) v9(124.08,140.97) v9(124.08,140.23) v9(124.08,139.5) v9(124.08,138.73) v9(124.49,158.32) v9(124.47,157.52) v9(124.54,156.72) v9(124.54,155.75) v9(124.52,154.96) v9(124.59,154.15) v9(125.04,148.29) v9(125.28,173.48) v9(125.28,158.31) v9(125.28,157.52) v9(125.28,156.68) v9(125.2,152.43) v9(125.33,155.74) v9(125.33,154.96) v9(125.43,162.99) v9(125.43,161.77) v9(126.01,158.29) v9(126.06,155.73) v9(126.11,156.69) v9(126.12,154.96) v9(126.14,152.32) v9(126.26,177.28) v9(126.23,148.27) v9(126.37,169.06) v9(127.37,162.36) v9(127.88,163.14) v9(127.79,161.75) v9(128.01,151.08) v9(128.35,162.18) v9(128.32,159.21) v9(128.39,151.82) v9(128.55,150.98) v9(129.34,157.9) v9(129.44,169.06) v9(129.41,156.18) v9(129.97,159.49) v9(130.28,157.93) v9(130.22,141.97) v9(130.22,141.47) v9(130.22,140.96) v9(130.22,140.45) v9(130.22,139.94) v9(130.22,139.43) v9(130.22,138.93) v9(130.22,138.42) v9(130.22,137.91) v9(130.21,137.4) v9(130.21,136.89) v9(130.29,142.45) v9(130.48,152.55) v9(130.65,142.81) v9(131.01,143.17) v9(131.37,143.53) v9(131.65,158.92) v9(131.7,157.24) v9(131.7,152.32) v9(131.73,143.89) v9(132.08,144.25) v9(132.44,144.61) v9(132.61,158.19) v9(132.61,157) v9(132.69,159.26) v9(132.8,144.97) v9(132.88,140.76) v9(132.88,140.25) v9(132.88,139.74) v9(132.88,139.23) v9(132.88,138.73) v9(132.88,138.22) v9(132.88,137.71) v9(132.88,137.2) v9(132.88,136.69) v9(132.98,141.24) v9(133.1,152.35) v9(133.16,145.33) v9(133.34,141.6) v9(133.49,159.26) v9(133.52,145.68) v9(133.7,141.96) v9(133.88,146.04) v9(134.06,142.32) v9(134.24,146.4) v9(134.32,152.58) v9(134.41,142.68) v9(134.6,146.76) v9(134.77,143.04) v9(134.96,147.12) v9(135.13,143.4) v9(135.32,147.48) v9(135.55,153.52) v9(135.49,143.76) v9(135.68,147.84) v9(135.85,144.12) v9(136.04,148.2) v9(136.21,144.48) v9(136.4,148.56) v9(136.57,144.84) v9(136.75,148.92) v9(136.93,145.2) v9(137.11,149.28) v9(137.29,145.55) v9(137.47,149.64) v9(137.65,145.91) v9(137.83,149.99) v9(138.01,146.27) v9(138.19,150.35) v9(138.37,146.63) v9(138.55,150.71) v9(138.72,146.99) v9(138.91,151.07) v9(139.08,147.35) v9(139.27,151.43) v9(139.44,147.71) v9(139.53,153.39) v9(139.53,152.88) v9(139.53,152.37) v9(139.53,151.86) v9(139.8,148.07) v9(139.97,154.01) v9(140.16,148.43) v9(140.33,154.37) v9(140.52,148.79) v9(140.69,154.73) v9(140.88,149.15) v9(141.05,155.09) v9(141.24,149.51) v9(141.41,155.45) v9(141.6,149.87) v9(141.77,155.81) v9(141.96,150.22) v9(142.13,156.17) v9(142.25,152.19) v9(142.25,151.68) v9(142.25,151.18) v9(142.25,150.67) v9(142.36,152.59) v9(142.49,156.53) v9(142.72,152.95) v9(142.85,156.89) v9(143.08,153.3) v9(143.2,157.25) v9(143.44,153.66) v9(143.56,157.61) v9(143.8,154.02) v9(143.92,157.97) v9(144.16,154.38) v9(144.28,158.32) v9(144.52,154.74) v9(144.64,158.68) v9(144.88,155.1) v9(145,159.04) v9(145.24,155.46) v9(145.36,159.4) v9(145.6,155.82) v9(145.72,159.76) v9(145.96,156.18) v9(146.08,160.12) v9(146.31,156.54) v9(146.44,160.48) v9(146.67,156.9) v9(146.8,160.84) v9(147.03,157.26) v9(147.16,161.2) v9(147.39,157.61) v9(147.52,161.56) v9(147.75,157.97) v9(147.87,161.92) v9(148.11,158.33) v9(148.23,162.28) v9(148.47,158.69) v9(148.59,162.64) v9(148.83,159.05) v9(148.95,162.99) v9(149.19,159.41) v9(149.31,163.35) v9(149.55,159.77) v9(149.67,163.71) v9(149.91,160.13) v9(150.03,164.07) v9(150.27,160.49) v9(150.39,164.43) v9(150.63,160.85) v9(150.75,164.79) v9(150.98,161.21) v9(151.11,165.15) v9(151.37,161.57) v9(151.47,165.51) v9(151.73,161.93) v9(151.83,165.87) v9(152.18,166.23) v9(152.09,162.28) v9(152.45,162.64) v9(152.43,155.24) v9(152.54,166.59) v9(152.81,163) v9(152.9,166.95) v9(153.17,163.36) v9(153.26,167.3) v9(153.52,163.72) v9(153.62,167.66) v9(153.88,164.08) v9(153.98,168.02) v9(154.24,164.44) v9(154.34,168.38) v9(154.6,164.8) v9(154.7,168.74) v9(154.96,165.16) v9(155.06,169.1) v9(155.32,165.52) v9(155.42,169.46) v9(155.68,165.88) v9(155.78,169.82) v9(156.04,166.24) v9(156.14,170.18) v9(156.4,166.6) v9(156.5,170.54) v9(156.76,166.95) v9(156.85,170.9) v9(157.12,167.31) v9(157.21,171.26) v9(157.48,167.67) v9(157.57,171.62) v9(157.83,168.03) v9(157.93,171.97) v9(158.19,168.39) v9(158.29,172.33) v9(158.55,168.75) v9(158.65,172.69) v9(158.91,169.11) v9(159.01,173.05) v9(159.27,169.47) v9(159.37,173.41) v9(159.63,169.83) v9(159.73,173.77) v9(159.99,170.19) v9(160.09,174.13) v9(160.35,170.55) v9(160.45,174.49) v9(160.71,170.91) v9(160.81,174.85) v9(161.07,171.26) v9(161.17,175.21) v9(161.43,171.62) v9(161.52,175.57) v9(161.88,175.93) v9(161.79,171.98) v9(162.15,172.34) v9(162.24,176.29) v9(162.5,172.7) v9(162.6,176.64) v9(162.86,173.06) v9(162.96,177) v9(163.22,173.42) v9(163.32,177.36) v9(163.58,173.78) v9(163.68,177.72) v9(163.94,174.14) v9(164.04,178.08) v9(164.3,174.5) v9(164.4,178.44) v9(164.67,179.25) v9(164.66,174.86) v9(164.77,179.78) v9(164.69,178.74) v9(165.02,175.22) v9(165.13,180.24) v9(165.38,175.58) v9(165.58,180.59) v9(165.74,175.93) v9(166.07,180.82) v9(166.1,176.29) v9(166.46,176.65) v9(166.57,181.08) v9(166.73,176.86) v9(166.8,178.87) v9(167.07,181.85) v9(167.18,176.89) v9(167.21,179.4) v9(167.21,178.94) v9(167.47,182.08) v9(167.54,180.11) v9(167.67,176.94) v9(167.93,182.08) v9(168.07,179.53) v9(168.2,177.17) v9(168.33,181.85) v9(168.33,180.59) v9(168.39,182.63) v9(168.56,181.45) v9(168.65,180.9) v9(168.66,177.6) v9(168.69,180.24) v9(168.86,178.1) v9(169,180.56) v9(169.32,178.74) v9(169.56,181.47) v9(169.55,180.47) v9(169.95,180.24) v9(169.95,178.98) v9(170.13,184.24) v9(170.18,179.84) v9(170.21,179.34) v9(170.73,180.3) v9(171.71,183.62) v9(171.84,185.9) v9(172.79,182.54) v9(172.91,184.82) v9(173.27,187.33) v9(174.35,186.26) v9(175.43,185.18) v9(176.38,190.77) v9(176.72,191.11) v9(177.06,191.45) v9(177.09,189.99) v9(177.18,188.36) v9(177.22,188.95) v9(177.4,191.79) v9(177.47,190.32) v9(177.74,192.13) v9(177.77,190.68) v9(177.8,187.73) v9(178.08,192.47) v9(178.13,191.01) v9(178.42,192.81) v9(178.42,187.11) v9(178.51,191.29) v9(178.64,193.24) v9(178.82,191.59) v9(178.99,193.75) v9(179.15,191.9) v9(179.6,192.18) v9(179.93,192.53) v9(180.31,192.86) v12(120.6,147.42) v12(121.34,148.13) v12(121.34,146.66) v12(124,148.13) v12(124,146.66) v12(124.82,147.4) v13(57.73,195.58) v13(57.7,194.31) v13(58.3,193.2) v13(58.4,196.66) v13(59.38,192.53) v13(59.51,197.26) v13(60.78,197.23) v13(60.77,192.37) v13(61.69,196.52) v13(62.46,195.45) v13(62.55,194.05) v13(119.03,207.63) v13(119.38,208.85) v13(119.34,206.4) v13(120.28,209.73) v13(120.22,205.31) v13(121.51,210.04) v13(122.67,205.28) v13(122.73,209.7) v13(123.58,206.34) v13(123.62,208.79) v13(123.77,207.64) v13(141.77,217.89) v13(142.02,216.64) v13(142.17,219.09) v13(142.86,215.69) v13(143.12,219.93) v13(144.06,215.29) v13(144.27,220.03) v13(145.3,215.54) v13(145.57,219.77) v13(146.43,216.37) v13(146.58,218.81) v13(151.77,216.36) v13(151.92,218.81) v13(152.78,215.4) v13(153.04,219.63) v13(154.08,215.15) v13(154.29,219.89) v13(155.23,215.25) v13(155.49,219.48) v13(156.18,216.09) v13(156.33,218.54) v13(156.58,217.29) v13(179.33,195.91) v13(179.31,194.51) v13(179.88,197.05) v13(180.93,197.76) v13(181.17,192.91) v13(182.19,197.86) v13(182.55,193.14) v13(183.34,197.31) v13(183.53,194.02) v13(184.05,196.26) v13(184.14,195) v14(66.13,187.5) v14(66.53,187.27) v14(66.99,187.27) v14(67.39,188.76) v14(67.39,187.5) v14(67.62,188.36) v14(67.62,187.9) v14(175.39,190.13) v14(175.39,189.67) v14(175.62,190.53) v14(175.62,189.28) v14(176.02,189.05) v14(176.48,189.05) v14(176.87,189.28) v15(53.86,119.25) v15(53.82,118.8) v15(54.02,118.38) v15(54.13,119.63) v15(54.21,138.94) v15(54.25,138.48) v15(54.41,139.35) v15(54.4,118.11) v15(54.51,138.1) v15(54.55,119.83) v15(54.78,139.62) v15(54.85,118.07) v15(54.93,137.91) v15(55.07,119.8) v15(55.24,139.66) v15(55.33,118.28) v15(55.45,137.93) v15(55.57,119.89) v15(55.72,139.46) v15(55.84,118.36) v15(55.95,137.84) v15(56.07,119.98) v15(56.22,139.37) v15(56.34,118.45) v15(56.45,137.75) v15(56.72,139.28) v15(60.26,100.19) v15(60.38,100.63) v15(60.38,99.75) v15(60.7,100.96) v15(60.7,99.42) v15(61.15,99.3) v15(61.2,101.11) v15(61.44,157.24) v15(61.56,157.69) v15(61.56,156.8) v15(61.64,101.37) v15(61.59,99.42) v15(61.89,158.01) v15(61.89,156.47) v15(61.98,99.77) v15(62.08,101.62) v15(62.33,158.13) v15(62.38,156.32) v15(62.42,100.03) v15(62.78,158.01) v15(62.82,156.06) v15(62.86,100.28) v15(63.16,157.66) v15(63.26,155.81) v15(63.6,157.41) v15(64.04,157.15) v15(65.59,176.4) v15(65.92,177.21) v15(65.92,175.59) v15(66.73,177.55) v15(66.73,175.26) v15(67.54,177.21) v15(67.54,175.59) v15(68.25,177.21) v15(68.3,175.59) v15(69.01,177.21) v15(69.06,175.59) v15(75.91,195.18) v15(76.17,196.01) v15(76.31,194.4) v15(76.95,196.41) v15(77.15,194.14) v15(77.78,196.15) v15(77.73,193.65) v15(78.19,195.37) v15(78.32,193.16) v15(78.73,194.92) v15(79.32,194.43) v15(92.33,206.21) v15(92.44,205.34) v15(92.86,206.9) v15(93.13,204.81) v15(93.52,204.15) v15(93.73,207.02) v15(93.9,203.49) v15(94.42,206.48) v15(94.53,205.62) v15(94.89,205) v15(95.27,204.34) v15(109.26,211.32) v15(109.22,210.44) v15(109.82,209.8) v15(109.91,211.91) v15(110.08,209.08) v15(110.34,208.36) v15(110.78,211.87) v15(111.37,211.22) v15(111.33,210.35) v15(111.58,209.68) v15(111.84,208.96) v15(131.72,209.17) v15(131.91,209.9) v15(132,211.5) v15(132.11,210.64) v15(132.53,212.2) v15(133.29,208.8) v15(133.4,212.31) v15(133.49,209.53) v15(133.67,210.22) v15(134.09,211.78) v15(134.21,210.91) v15(149.3,204.3) v15(149.68,204.96) v15(150.06,205.62) v15(150.18,206.48) v15(150.73,203.53) v15(150.87,207.02) v15(151.11,204.19) v15(151.46,204.81) v15(151.74,206.9) v15(152.16,205.34) v15(152.27,206.21) v15(165.24,194.42) v15(165.83,194.91) v15(166.32,193.22) v15(166.41,195.4) v15(166.81,196.18) v15(166.9,193.7) v15(167.45,194.16) v15(167.65,196.44) v15(168.28,194.43) v15(168.42,196.04) v15(168.69,195.2) v15(175.5,177.34) v15(175.55,175.72) v15(176.26,177.34) v15(176.31,175.72) v15(177.02,177.34) v15(177.02,175.72) v15(177.83,177.67) v15(177.83,175.39) v15(178.64,177.34) v15(178.64,175.72) v15(178.98,176.53) v15(180.76,98.21) v15(181.2,97.95) v15(181.54,99.55) v15(181.49,97.47) v15(181.98,99.3) v15(182.01,155.15) v15(182,97.22) v15(182.45,155.41) v15(182.47,97.23) v15(182.49,99.19) v15(182.78,153.81) v15(182.89,155.66) v15(182.91,97.35) v15(182.99,98.96) v15(183.27,156.02) v15(183.22,154.07) v15(183.24,98.56) v15(183.24,97.67) v15(183.36,98.12) v15(183.66,154.32) v15(183.71,156.13) v15(184.16,156.02) v15(184.16,154.48) v15(184.48,155.69) v15(184.48,154.8) v15(184.6,155.25) v15(187.98,116.11) v15(188.25,117.64) v15(188.39,136.97) v15(188.48,116.02) v15(188.66,135.44) v15(188.75,117.55) v15(188.89,137.05) v15(188.98,115.94) v15(189.16,135.53) v15(189.25,117.46) v15(189.39,137.14) v15(189.46,115.73) v15(189.66,135.62) v15(189.77,117.49) v15(189.87,137.34) v15(189.92,115.77) v15(190.18,135.59) v15(190.19,117.29) v15(190.33,137.3) v15(190.3,116.05) v15(190.45,116.91) v15(190.49,116.46) v15(190.6,135.79) v15(190.71,137.04) v15(190.86,136.16) v15(190.9,136.62)
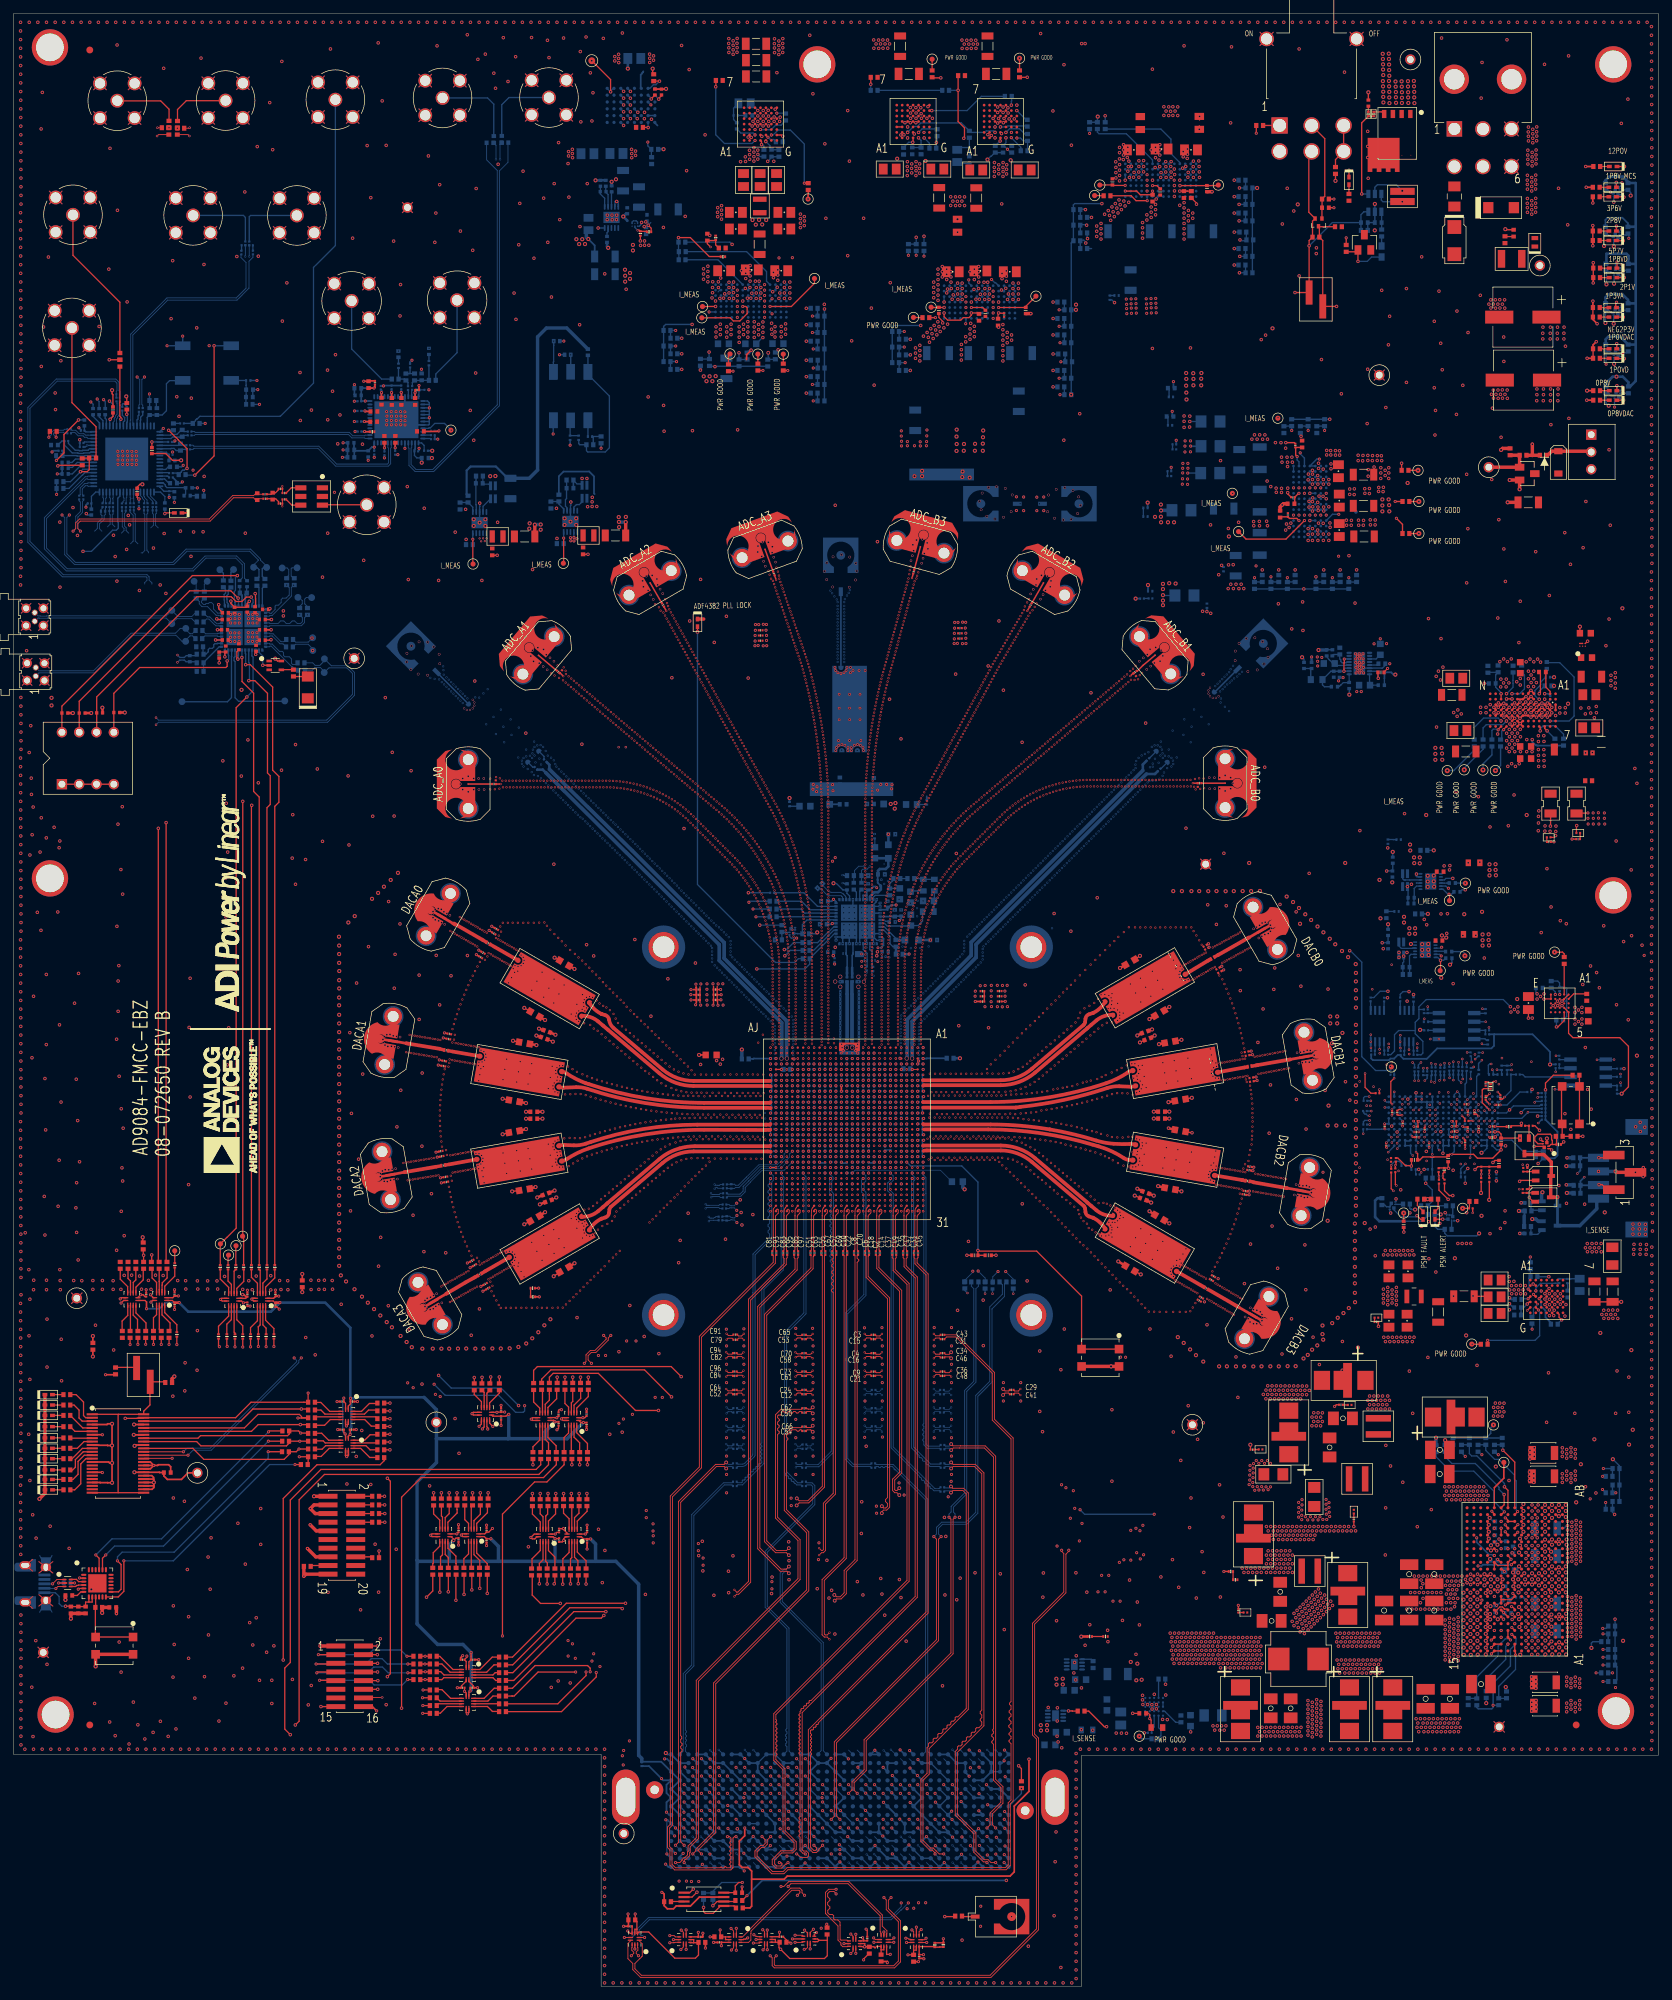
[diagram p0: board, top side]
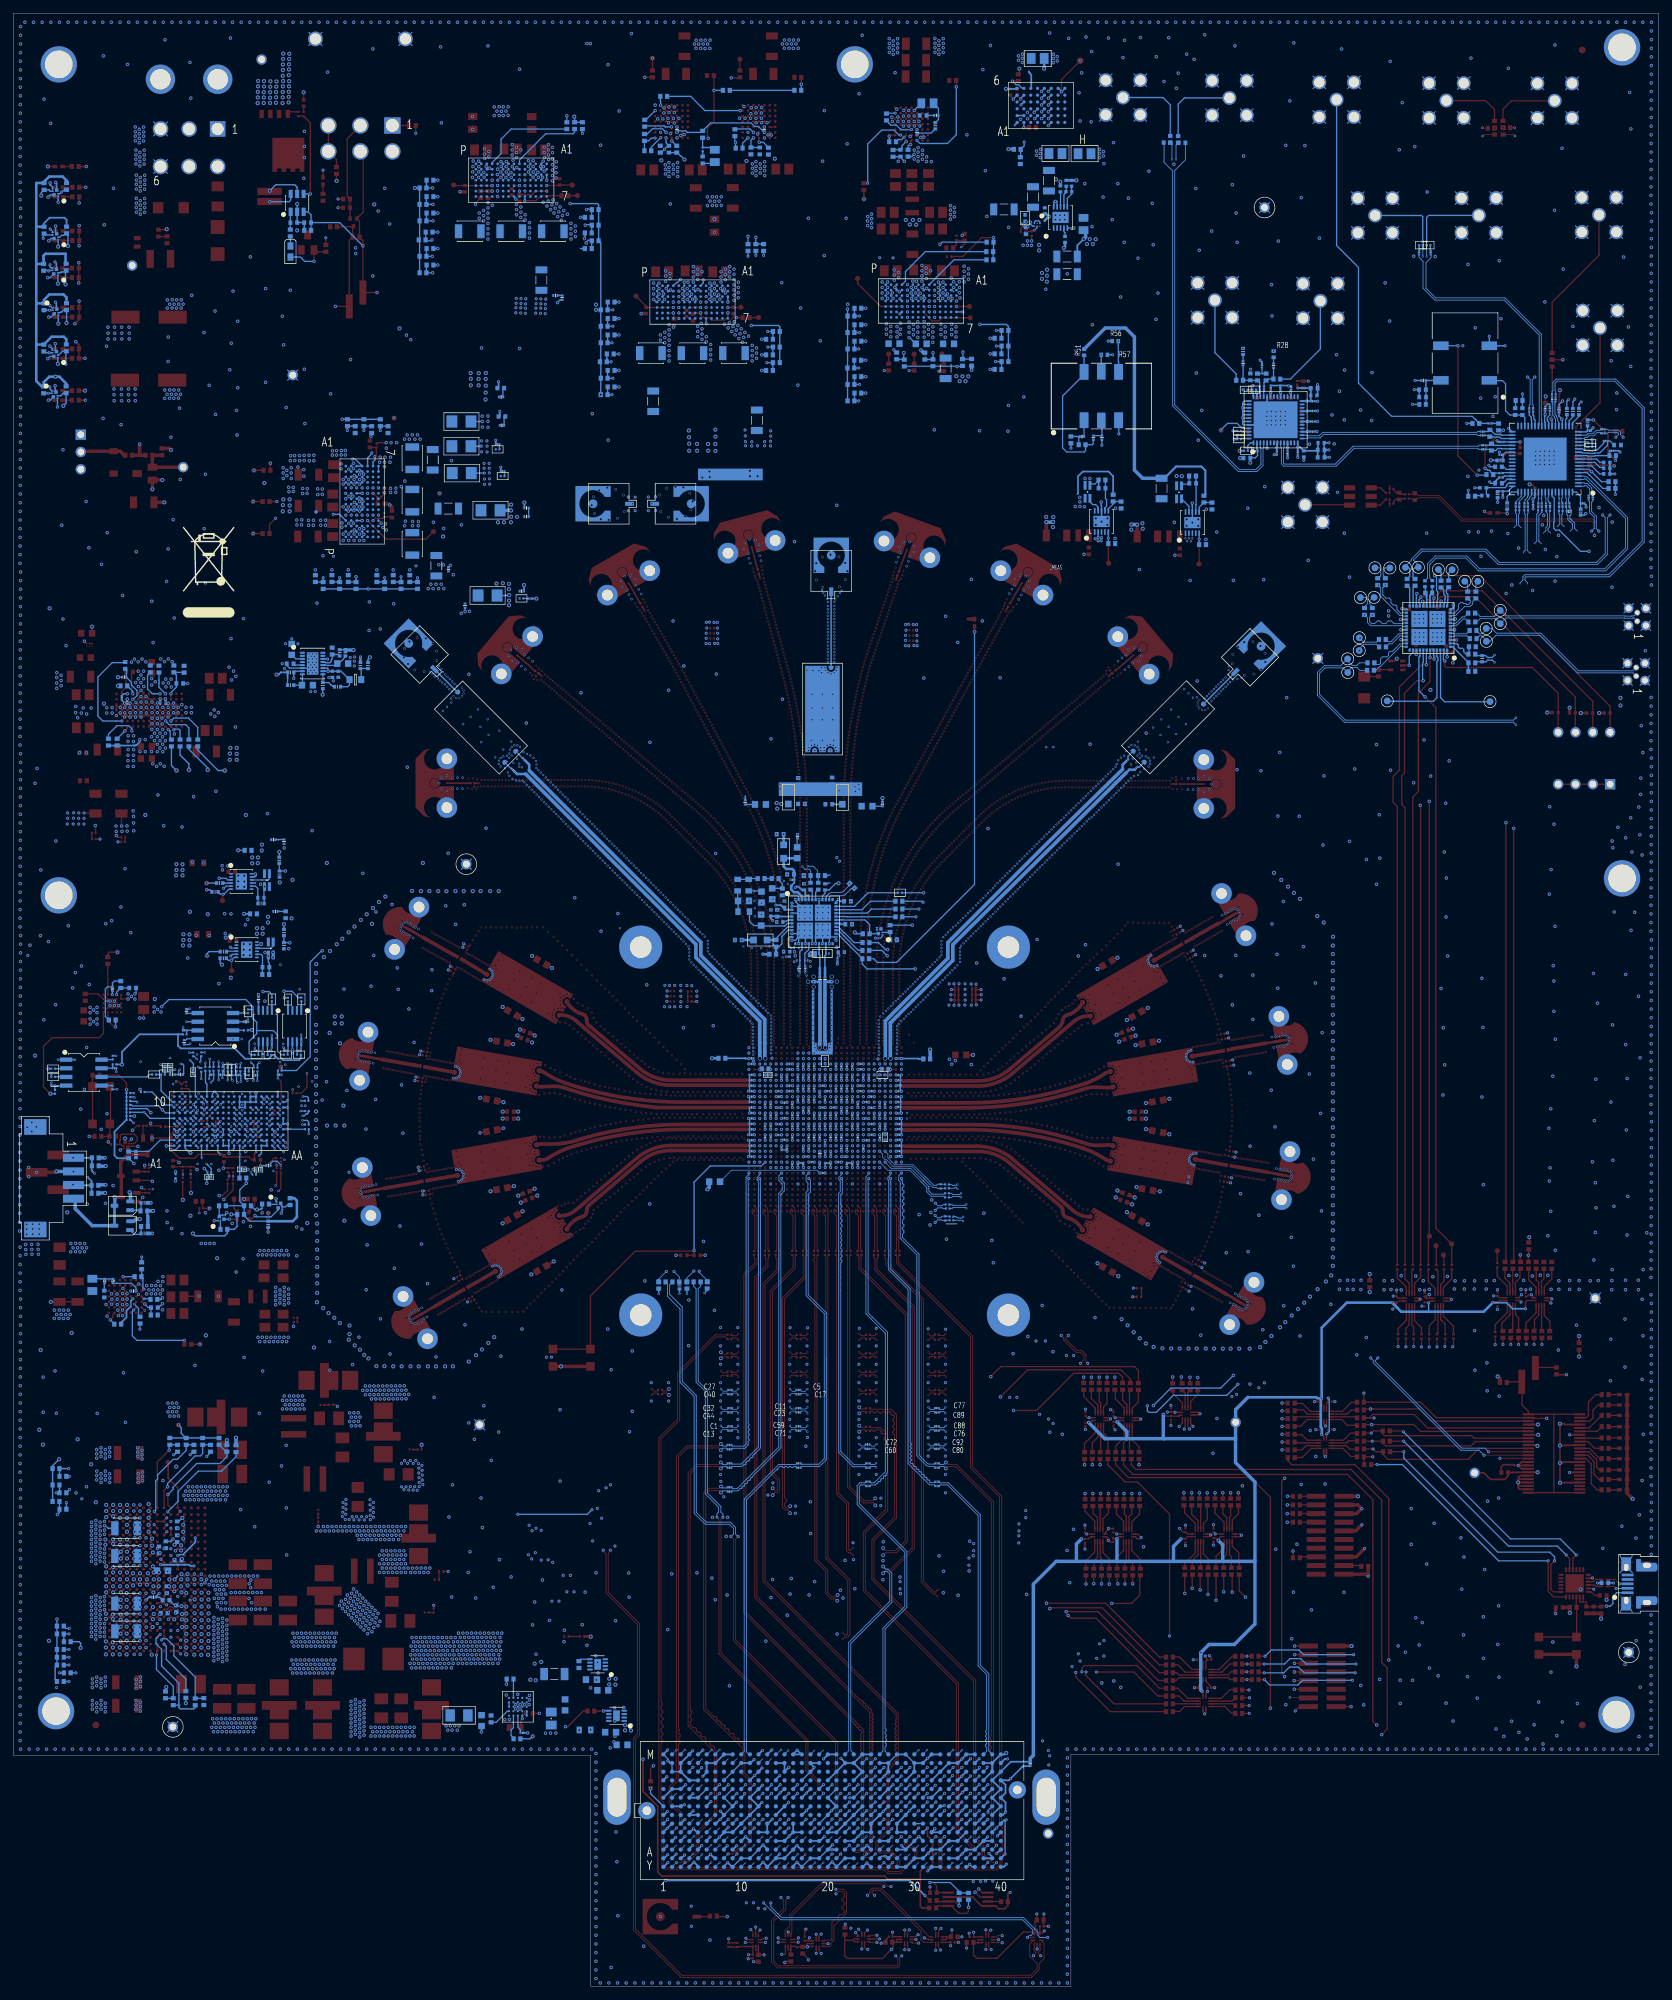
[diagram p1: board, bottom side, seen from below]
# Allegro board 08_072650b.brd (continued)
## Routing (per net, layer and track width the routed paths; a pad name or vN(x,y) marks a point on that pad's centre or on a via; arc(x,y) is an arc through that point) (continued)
SVDD1P0_RX: length 1.9
  BOTTOM w0.127: v4(118.3,120.93) 118.42,120.81 C444.1
  BOTTOM w0.254: C437.1 C434.1 ; C449.1 118.42,120.81 ; v4(117.5,120.93) 117.5,120.93 117.52,120.91 117.52,120.82 C440.1
  vias: v4(126.3,120.93) v4(127.1,120.93) v4(181.36,73.62) v4(181.47,75.72) v4(181.44,75.02) v4(181.44,74.28) v4(181.5,76.43) v4(181.95,76.03) v4(181.95,75.32) v4(181.93,74.64) v4(181.89,73.93) v4(181.89,73.32) v4(182,76.7) v4(182.18,72.78) v4(182.4,77.15) v4(182.55,73.32) v4(182.78,76.73) v4(182.79,72.82) v4(183.21,77.14) v4(183.2,73.32) v4(183.44,72.82) v4(183.62,76.73) v4(183.83,73.29) v4(184.04,77.14) v4(184.14,72.87) v4(184.49,76.73) v4(184.49,73.29)
SVDD1P0_TX: length 0.8
  BOTTOM w0.254: C474.1 121.55,120.79 C460.1
  vias: v4(120.7,120.93) v4(121.5,120.93) v4(123.1,120.93) v4(123.9,120.93) v4(188.62,71.01) v4(188.65,70.24) v4(188.62,69.55) v4(188.62,68.85) v4(189.08,69.88) v4(189.08,69.11) v4(189.08,68.48) v4(189.12,71.41) v4(189.12,70.64) v4(189.61,68.91) v4(189.95,68.44) v4(190.35,68.91) v4(190.72,68.44) v4(191.08,68.91) v4(191.48,68.44) v4(191.74,68.91) v4(192.18,68.5) v4(192.65,71.44) v4(192.65,70.74) v4(192.65,70) v4(192.68,69.28) v4(192.75,68.5) v4(193.08,70.98) v4(193.08,70.27) v4(193.12,69.57) v4(193.18,68.94)
VCC23: length 0.8
  TOP w0.254: U32.A3 U32.A4
VDD_1P8_MCS_I+: length 69.3
  L3_SIGNAL w0.254: v1(230.74,180.98) 230.91,180.81 230.91,179.48 227.15,175.72 227.15,156.46 v1(227.04,156.35)
  L22_MIXED w0.254: v2(212.65,136.07) 212.65,137.67 213.64,138.66 213.64,149.54 212.52,150.66 212.52,151.75 213.77,153 213.77,155.37 212.47,156.67 211.18,156.67 v1(210.46,157.38)
  L24_SIGNAL w0.254: v1(227.04,156.35) 226.98,156.35 226.97,156.36 212.12,156.36 211.1,157.38 v1(210.46,157.38)
  BOTTOM w0.191: R652.1 v2(212.65,136.07)
VDD_1P8_MCS_I-: length 72
  L3_SIGNAL w0.254: v1(231.74,181.01) 231.52,180.79 231.52,178.99 228.09,175.56 228.09,156.08 v1(227.91,155.91)
  L22_MIXED w0.191: v2(212.09,135.59) 212.19,135.69
  L22_MIXED w0.254: 212.19,135.69 212.19,138.13 213.08,139.01 213.08,149.38 212.06,150.39 212.06,152.07 213.31,153.31 213.31,155.19 212.28,156.21 210.99,156.21 210.94,156.26 210.62,156.26 v1(209.52,157.35)
  L24_SIGNAL w0.254: v1(227.91,155.91) 227.29,155.91 227.24,155.85 226.83,155.85 226.78,155.91 211.93,155.91 210.95,156.88 210.26,156.88 209.79,157.35 v1(209.52,157.35)
  BOTTOM w0.191: R648.1 v2(212.09,135.59)
VDD_1V8: length 12
  TOP w0.191: C785.1 32.77,195.81 32.77,194.88 v1(32.92,194.73) ; S5.1A S5.2A S5.3A S5.4A ; R815.2 v1(92,256.08) ; E15.2 v1(30.18,194.18)
  BOTTOM w0.191: U51.44 33.01,195.25 32.95,195.2 32.95,194.77 v1(32.92,194.73)
  vias: v1(92.02,255.42) v1(92.61,256.08) v1(92.61,255.45) v1(93.24,255.45)
VDD_3V3_ADF4030: length 28.7
  TOP w0.191: v1(35.45,204.34) 35.51,204.29 35.51,202.49 C780.1
  TOP w0.203: v1(37.85,200.54) 37.84,200.53 C781.1 ; C773.1 29.92,200.53 v1(29.82,200.63) ; C782.1 37.71,197.51 v1(37.78,197.57) ; C779.1 30.65,201.57 30.1,202.12 30.1,202.71 v1(30.1,202.72) ; v3(38.4,194.79) 38.74,194.45 U50.5 ; v1(31.89,203.24) 31.89,202.89 C775.1 34.14,202.34 C783.1 34.29,202.91 v1(34.59,203.21) ; C774.1 29.65,197.54 v1(29.64,197.54)
  TOP w0.254: C776.1 v1(29.92,199.03) ; C784.1 35.59,195.48 v1(35.53,195.43) ; C778.1 v1(37.8,199.03)
  BOTTOM w0.191: U51.25 37.52,202.04 v1(37.62,202.13) ; v1(35.45,204.34) 35.51,204.29 35.51,203.63 35.53,203.6 35.53,202.82 35.51,202.79 U51.22 ; 32.01,202.77 32.01,203.12 v1(31.89,203.24)
  BOTTOM w0.203: 32.01,202.77 U51.15
  BOTTOM w0.254: v1(29.92,199.03) 29.93,199.04 U51.6 ; U51.34 37.72,197.54 37.76,197.57 v1(37.78,197.57) ; U51.3 v1(29.64,197.54) ; U51.31 36.99,199.03 v1(37.8,199.03) ; U51.9 29.92,200.54 v1(29.82,200.63) ; v1(30.1,202.72) 30.1,202.71 30.1,202.31 30.37,202.04 U51.12 ; v3(84.35,256.36) 85.29,255.42 R364.2 ; U51.20 34.51,203.13 v1(34.59,203.21) ; U51.39 35.51,195.46 v1(35.53,195.43) ; U51.28 v1(37.85,200.54)
  BOTTOM w0.508: C859.1 84.07,257.36 84.07,256.65 v3(84.35,256.36)
  vias: v3(82.6,256.34) v3(83.01,255.63) v3(83.46,256.34) v3(83.87,255.63)
VDDA1P0_ADC: length 132.9
  TOP w0.254: C660.1 141.93,144.5 v4(141.16,144.5) ; C669.1 99.8,144.72 ; C669.1 100.21,144.31 ; C669.1 C670.1 ; C671.1 100.21,146.54 100.18,146.57 100.18,146.62 ; C671.1 99.77,146.24 ; C671.1 C670.1 ; C670.1 99.8,145.48
  L3_SIGNAL w0.254: v2(197.58,132.77) 197.58,144.72 197.59,144.72 197.59,145.18 197.58,145.18 197.58,151.46 185.52,163.53 149.1,163.53 141.81,156.24 141.81,146.89 v4(141.88,146.81)
  L22_MIXED w0.254: v1(217.65,118.19) 217.04,117.58 214.93,117.58 214.27,116.92 205.31,116.92 203.15,119.08 198.6,119.08 v2(197.56,120.12)
  L24_SIGNAL w0.254: v2(197.58,132.77) 197.87,132.48 197.87,126.42 198.75,125.53 198.75,121.31 v2(197.56,120.12)
  BOTTOM w0.191: R134.1 v1(217.65,118.19)
  BOTTOM w0.254: C484.1 119.12,134.55 v4(119.1,134.53) ; v4(118.3,134.53) 118.32,134.55 C480.1 ; C492.1 120.7,134.65 v4(120.7,134.53) ; v4(119.9,134.53) 119.9,134.65 C487.1
  vias: v3(138.43,228.4) v3(138.4,227.38) v3(138.43,226.29) v3(138.4,225.27) v3(139.47,225.3) v3(139.5,226.29) v3(141.12,226.31) v3(141.1,225.3) v3(142.27,226.34) v3(142.27,225.3) v3(142.32,228.27) v3(142.29,227.28) v4(99.43,146.24) v4(99.4,145.5) v4(99.43,144.73) v4(100.15,147.04) v4(100.1,144.02) v4(123.9,134.53) v4(124.7,134.53) v4(125.5,134.53) v4(126.3,134.53) v4(141.16,146.01) v4(141.14,145.28)
VDDA1P0_ADC_EN: length 239.6
  L3_SIGNAL w0.191: v1(160.22,274.45) 160.22,271.91 155.63,267.31 155.63,250.49 168.43,237.69 193.65,237.69 208.18,223.16 208.18,209.42 204.52,205.77 204.52,199.26 205.71,198.07 205.71,179.43 218.44,166.7 218.44,140.72 220.5,138.66 220.5,129.64 219.58,128.73 v1(219.58,128.6)
  L24_SIGNAL w0.191: v1(133.63,256.77) 133.63,262.03 135.51,263.91 147.22,263.91 158.62,275.31 159.36,275.31 v1(160.22,274.45)
  BOTTOM w0.191: R763.1 v1(160.22,274.45) ; R150.1 224.15,129.34 223.99,129.17 220.15,129.17 v1(219.58,128.6) 219.13,128.15 U11.A7 ; R20.1 v1(133.63,256.77)
VDDA1P0_ADC_REF: length 186.7
  TOP w0.191: R789.1 173.63,261.63 v1(173.63,261.47) ; v2(198.37,133.93) 198.37,131.9 199.24,131.04 R498.2 ; C713.1 144.62,245.48 v1(144.58,245.52) 144.5,245.43 C763.2
  L3_SIGNAL w0.191: v2(198.37,133.93) 198.37,151.69 183.06,167 183.06,186.44 168.1,201.4 165.1,201.4 161.47,205.03 161.47,238.05 156.76,242.75 152.39,242.75 152.35,242.72 148.18,242.72 145.39,245.52 v1(144.58,245.52)
  L5_MIXED w0.191: v1(144.58,245.52) 147.75,245.52 154.31,252.07 169.39,252.07 173.63,256.31 v1(173.63,261.47)
VDDA1P0_ADC_SCLK: length 0.6
  L5_MIXED w0.127: 116.7,137.73 116.69,137.82
  BOTTOM w0.191: v4(118.3,133.73) 118.32,133.71 C479.1 ; v4(120.7,133.73) 120.72,133.71 C491.1 ; v4(119.1,133.73) 119.12,133.71 C483.1 ; v4(119.9,133.73) 119.92,133.71 C486.1
  vias: v3(172.11,236.7) v3(172.14,235.84) v3(172.11,234.85) v3(172.14,233.83) v3(172.16,232.82) v3(173.15,236.68) v3(173.18,235.84) v3(173.18,234.9) v3(174.35,236.7) v3(174.32,235.86) v3(174.32,234.9) v4(108.88,198.96) v4(108.84,198.2) v4(108.84,197.38) v4(108.81,196.7) v4(108.89,199.8) v4(109.28,196.72) v4(109.37,199.8) v4(123.9,133.73) v4(124.7,133.73) v4(125.5,133.73) v4(126.3,133.73) v4(138.06,197.02) v4(138.14,200.11) v4(138.13,199.28) v4(138.09,198.51) v4(138.09,197.7) v4(138.53,197.04) v4(138.62,200.11)
VDDA1P0_ADCBK: length 171.5
  TOP w0.191: C668.1 145.54,144.5 v4(145.55,144.51) ; C675.1 103.27,146.74 ; C675.1 103.66,146.25 ; C675.1 C676.1 ; 145.97,143.64 v4(145.87,143.74) ; 103.33,144.18 103.33,144.49 103.3,144.52 103.3,144.71 C677.1 ; C677.1 103.78,144.73 ; C677.1 C676.1 ; C676.1 103.71,145.49
  L3_SIGNAL w0.191: v1(222.88,131.6) 224.18,132.89 224.18,143.64 223.16,144.66 223.16,144.68 219.91,147.93 219.91,173 215.75,177.17 209.63,177.17 207.68,179.11 v1(207.68,200.67)
  L24_SIGNAL w0.191: v1(207.68,200.67) 205.27,198.26 186.96,198.26 185.76,199.45 178.6,199.45 154.46,223.6 136.02,223.6 134.59,225.02 134.59,225.43 v4(133.99,226.03)
  BOTTOM w0.191: v1(222.88,131.6) 222.75,131.46 R492.1
  vias: v4(103.41,147.08) v4(103.39,143.94) v4(103.77,146.25) v4(103.86,145.49) v4(103.82,144.74) v4(104.1,147.09) v4(104.14,143.97) v4(118.3,130.53) v4(119.1,130.53) v4(119.9,130.53) v4(120.7,130.53) v4(123.9,130.53) v4(124.7,130.53) v4(125.5,130.53) v4(126.3,130.53) v4(130.3,228.22) v4(130.3,227.46) v4(130.33,226.69) v4(130.33,226.01) v4(131.19,226.64) v4(131.19,226.03) v4(132.23,226.03) v4(133.07,226.62) v4(133.1,226.01) v4(134.06,228.35) v4(134.04,227.48) v4(134.01,226.64) v4(145.15,146.85) v4(145.12,143.71) v4(145.5,146.02) v4(145.53,145.28) v4(145.83,146.86)
VDDA1P0_ADCBK_EN: length 264.7
  L3_SIGNAL w0.191: v2(222.28,128.24) 222.28,132.23 223.47,133.43 223.47,142.6 221.21,144.86 v3(220.7,144.86) ; v3(181.36,164.82) 182.12,165.58 182.12,186.26 167.94,200.43 164.19,200.43 154.28,210.34 141.05,210.34 125.02,226.36 105.84,226.36 95.28,236.93 95.28,252.78 99.85,257.35 101.99,257.35 101.99,257.36 102.38,257.36 102.38,257.35 131.75,257.35 v1(132.49,256.62)
  L5_MIXED w0.198: v2(202.27,149.9) 201.73,150.44 201.73,153.95 199.97,155.7 199.97,158.52 195.45,163.04 v3(195.45,164.82)
  L24_SIGNAL w0.198: v3(181.36,164.82) v3(195.45,164.82) ; v3(220.7,144.86) 211.02,144.86 206.27,149.61 202.56,149.61 v2(202.27,149.9)
  BOTTOM w0.191: R58.1 R21.1 v1(132.49,256.62) ; U11.A6 221.38,127.35 v2(222.28,128.24) 224.29,128.24 R157.1
VDDA1P0_ADCBK_REF: length 175.3
  TOP w0.191: C710.1 216.46,132.68 R505.2 217.21,132.77 v2(217.58,132.77) ; C707.2 141.57,245.52 v1(140.58,245.52) 140.58,245.18 140.23,244.83 139.4,244.83 139.03,244.46 137.1,244.46 136.58,244.98 v1(136.58,245.52)
  L5_MIXED w0.191: 207.37,138.39 206.22,137.24 206,137.24 204.42,135.66 204.42,132.79 204.62,132.59 204.65,132.59 205.49,131.75 214.76,131.75 215.77,132.77 216.61,132.77
  L5_MIXED w0.198: v1(187.6,199.16) 187.99,199.54 195.83,199.54 199.42,195.96 199.42,168.12 198.75,167.46 198.75,161.77 202.74,157.78 202.74,150.72 208.43,145.03 208.43,141.12 207.37,140.06 207.37,138.39 ; 216.61,132.77 v2(217.58,132.77)
  L24_SIGNAL w0.191: v1(140.58,245.52) 140.58,245.14 141.66,244.07 141.66,237.6 178.67,200.58 186.18,200.58 v1(187.6,199.16)
VDDA1P0_CK: length 108.6
  L3_SIGNAL w0.203: v1(177.16,223.85) 177.16,222.19 172.97,218.01 172.97,199.03 187.1,184.91 187.1,165.3 200.18,152.22 200.18,145.59 199.9,145.31 199.9,133.99 198.2,132.28 198.2,129.62 v2(198.6,129.21)
VDDA1P0_CK_IMON: length 129.6
  L3_SIGNAL w0.203: v4(188.85,224.99) 185.62,224.99 184.53,226.09 184.53,229.08 v4(185.6,230.15)
  L5_MIXED w0.203: v2(206.93,134.72) 206.93,134.85 207.34,135.25 207.34,136.35 209.96,138.96 209.96,145.06 208.58,146.43 208.58,159.49 209.42,160.33 209.42,166.57 208.53,167.46 208.53,174.19 206.35,176.38 206.35,193.52 212.22,199.39 212.22,219.76 205.56,226.42 190.27,226.42 v4(188.85,224.99)
  BOTTOM w0.203: U8.A5 189.47,224.23 188.85,224.85 v4(188.85,224.99) ; R670.1 206.93,134.26 v2(206.93,134.72)
VDDA1P0_DAC:
  vias: v4(117.5,128.93) v4(117.5,127.33) v4(117.5,126.53) v4(117.5,124.93) v4(127.1,128.93) v4(127.1,127.33) v4(127.1,126.53) v4(127.1,124.93) v4(163.32,247.55) v4(163.37,246.79) v4(163.37,246.15) v4(163.4,245.41) v4(164.03,247.57) v4(164.03,246.86) v4(164.06,246.23) v4(164.08,245.47) v4(164.72,247.6) v4(164.74,246.89) v4(164.77,246.23) v4(164.8,245.49) v4(166.24,247.6) v4(166.29,246.84) v4(166.29,246.2) v4(166.32,245.47) v4(166.95,247.62) v4(166.95,246.91) v4(166.98,246.28) v4(167,245.52) v4(167.64,247.65) v4(167.67,246.94) v4(167.69,246.28) v4(167.72,245.54)
VDDA1P0_DAC_IMON: length 178.4
  TOP w0.191: v4(163.16,264.23) 161.36,264.23 R762.2 159.44,264.29 TP36.1
  L3_SIGNAL w0.191: v1(188.7,250.95) 181.66,250.95 180.95,250.24 170.15,250.24 164.16,256.24 164.16,260.2 165.13,261.16 165.13,262.94 163.84,264.23 v4(163.16,264.23)
  L5_MIXED w0.191: v1(188.7,250.95) 188.7,248.95 188.64,248.89 188.64,248.28 188.32,247.96 187.71,247.96 187.6,247.86 187.59,247.86 181.21,241.48 181.21,226.77 181.53,226.45 181.78,226.45 182.96,225.27 182.96,219.43 184.6,217.79 184.6,212.16 180.87,208.43 180.87,206.32 182.12,205.08 182.12,201.8 177.44,197.13 177.44,192.94 185.47,184.91 185.47,162.59 v1(196.11,151.94)
  BOTTOM w0.191: v2(202.09,134.98) R664.1 199.92,134.37 197.89,136.4 197.89,150.27 196.22,151.94 v1(196.11,151.94)
VDDA1P0_EN: length 281.5
  L3_SIGNAL w0.203: v3(215.54,157.66) 215.54,156.41 213.82,154.69 213.82,140.84 217.17,137.49 217.17,136.23 218.59,134.81 218.59,132.23 218.08,131.72 216.64,131.72 216.05,131.14 216.05,129.18 215.39,128.52 v2(214.99,128.52)
  L5_MIXED w0.197: v3(200.49,162.34) 200.49,165.39 200.94,165.84
  L5_MIXED w0.203: 200.94,165.84 200.94,181.56 204.72,185.34 204.72,194.41 210.62,200.3 210.62,217.98 208.03,220.57 v3(204.62,220.57) 195.35,220.57 194.62,219.84 192.7,219.84 192.18,219.32 191.6,219.32 v4(191.07,219.86)
  L24_SIGNAL w0.203: v2(214.99,128.52) 215.39,128.93 215.39,129.19 215.43,129.22 215.43,132.85 216.2,133.63 222,133.63 223.75,131.88 v2(223.75,131.04) 224.23,131.04 225.09,130.18 232.92,130.18 233.63,129.46 233.63,116.36 234.67,115.32 234.67,113.23 231.5,110.06 224.33,110.06 222.63,108.36 v4(222.63,107.01) ; v3(215.54,157.66) 214.73,158.47 201.27,158.47 200.49,159.25 v3(200.49,162.34) ; v3(204.62,220.57) 204.91,220.87 204.91,230.92 203.43,232.41 203.43,241.48 192.56,252.35 188.29,252.35 183.57,257.07 183.57,267.79 177.95,273.41 160.05,273.41 v3(159.13,274.33)
  BOTTOM w0.203: R761.1 R542.1 159.08,274.28 v3(159.13,274.33) ; U11.D7 215.08,128.52 v2(214.99,128.52) ; R517.1 v4(222.63,107.01) ; v2(223.75,131.04) 223.77,131.06 R151.1
VDDA1P0_REF: length 204.3
  TOP w0.203: v4(188.4,224.45) 188.19,224.67 188.19,225.74 C712.1 189.13,225.79 C321.2 ; v4(167.18,263.4) 167.18,263.39 C753.2 165.38,262.86 164.84,263.4 v4(163.18,263.4) ; v2(212.6,127.74) 213.01,127.32 R499.2
  L3_SIGNAL w0.203: v2(199.43,146.29) 199.43,146.47 199.19,146.71 199.19,152.02 185.39,165.81 185.39,185.19 172.11,198.48 172.11,218.77 173.74,220.4 173.74,222.91 175.79,224.97 179.37,224.97 182.32,222.02 187.81,222.02 188.4,222.62 v4(188.4,224.45)
  L5_MIXED w0.203: v2(199.43,146.29) 200.03,146.9 202.12,146.9 202.67,146.35 202.67,137.9 200.66,135.89 200.66,133.05 v2(199.62,132)
  L24_SIGNAL w0.203: v2(212.6,127.74) 211.9,127.74 207.71,131.93 205.21,131.93 204.7,132.44 200.05,132.44 v2(199.62,132) ; v4(167.18,263.4) 167.92,263.4 168.35,262.97 168.35,254.05 171.83,250.57 179.71,250.57 185.75,244.53 185.75,233.5 188.4,230.85 v4(188.4,224.45)
  BOTTOM w0.203: U8.A6 188.67,223.68 188.4,223.95 v4(188.4,224.45)
VDDA1P0_SCLK_IMON: length 5.7
  TOP w0.191: v1(171.2,264.2) R759.2 176.75,264.2 TP39.1
VDDA_1P8: length 100.6
  L3_SIGNAL w0.254: v3(212.93,157.3) 212.32,157.3 209.47,160.15 209.47,169.27 208.91,169.82 201.47,169.82 192.15,179.15 192.15,188.65 187.76,193.04 187.76,196.57 180.59,203.73 178.23,203.73 175.9,206.07 175.9,214.22 v1(175.69,214.43)
  L5_MIXED w0.254: v2(215.64,137) 214.71,137.93 214.71,151.05 213.77,151.99 213.77,156.46 v3(212.93,157.3)
  BOTTOM w0.191: R139.1 v2(215.64,137)
VDDA_1P8_DAC: length 203.1
  TOP w0.198: T1ZB.PAD v7(166.16,108.99) ; T1YB.PAD v5(170.63,121.26) ; T1XB.PAD v7(170.63,134.32) ; T1WB.PAD v7(166.16,146.59)
  TOP w0.254: R576.1 v4(77.17,101.17)
  TOP w0.381: C1WB.1 v3(166.72,141.92) ; C2WA.1 v3(78.01,141.78) ; C629.1 v3(167.36,116.01) ; C2ZA.1 v3(82.32,106.09) ; C1YB.1 v1(169.52,125.92) ; C339.1 v3(77.12,140.51) ; C2YB.1 v3(167.99,117.41) ; C361.1 v3(167.1,140.4) ; C2XA.1 v3(75.21,129.59) ; C349.1 v3(76.86,115.75) ; C366.1 v3(169.64,128.34) ; T1XA.PAD v7(74.1,134.18) ; C1WA.1 v3(82.32,149.27) ; C2XB.1 v3(169.52,129.73) ; C1XA.1 v3(76.74,138.1) ; C2ZB.1 v3(162.15,106.36) ; v7(78.57,108.85) T1ZA.PAD ; T1YA.PAD v7(74.1,121.12) ; C1YA.1 v3(75.21,125.78) ; C1ZA.1 v3(78.01,113.59) ; T1WA.PAD v7(78.57,146.45) ; C1XB.1 v3(168.12,138.24) ; C344.1 v3(75.21,128.32) ; C1ZB.1 v3(166.72,113.73) ; C2YA.1 v3(76.61,117.27) ; C2WB.1 v3(162.4,149.41)
  L5_MIXED w0.254: v3(236.14,202.18) 236.14,175.36 238.86,172.64 238.86,154.28 238.28,153.7 v3(238.28,136.55)
  L24_SIGNAL w0.254: v1(179.86,205.07) 179.86,204.57 180.29,204.14 186.08,204.14 187.86,202.36 220.42,202.36 224.41,198.37 233.98,198.37 236.14,200.53 v3(236.14,202.18) ; v2(214.33,134.9) 215.32,134.9 218.66,138.24 227.9,138.24 232.84,133.3 237.21,133.3 238.28,134.37 v3(238.28,136.55)
  BOTTOM w0.203: v4(133.58,127.34) 133.4,127.34 C393.1 C394.1 C398.1 C397.1 133.4,124.94 v4(133.58,124.94) ; C426.1 130.3,127.49 v4(130.3,127.33) ; v4(111.1,121.73) 111.11,121.74 C700.2 C352.1 C355.1 111.11,124.14 v4(111.1,124.15) 111.11,124.15 C698.2 ; v4(114.3,126.53) 114.3,126.46 C365.1 ; C390.1 C389.1 v4(133.4,128.14) ; C422.1 130.3,124.78 v4(130.3,124.93) ; C418.1 115.11,127.34 v4(115.1,127.33) ; v4(133.58,124.14) 133.4,124.14 C401.1 C402.1 C406.1 C405.1 133.4,121.74 v4(133.58,121.74) ; v4(115.1,126.53) 115.24,126.53 C368.1 ; C353.1 129.35,128.93 v4(129.5,128.93) ; 111.19,131.42 C340.1 111.25,131.33 v4(111.1,131.33) 111.19,131.41 111.19,131.42 ; 111.19,131.42 111.28,131.51 111.28,132.09 C421.1 111.26,132.26 C420.1 C345.1 111.24,133.73 v4(111.1,133.73) ; C423.1 114.3,127.44 v4(114.3,127.33) ; v4(129.5,126.53) 129.34,126.53 C703.2 ; v4(114.3,124.93) 114.3,124.86 C360.1 ; v4(133.58,130.54) 133.57,130.54 C385.1 C386.1 ; v4(133.58,131.34) 133.4,131.34 C381.1 C382.1 C378.1 C375.1 ; C358.1 129.39,124.93 v4(129.5,124.93) ; v4(111.1,124.93) 111.11,124.94 C699.2 C343.1 C338.1 111.11,127.32 v4(111.1,127.33) C702.2 ; v4(115.1,124.93) 115.24,124.93 C363.1 ; C425.1 129.5,127.45 v4(129.5,127.33) ; C370.1 130.3,126.38 v4(130.3,126.53) ; v4(111.1,130.53) C335.1 C419.1 C348.1 111.24,128.26 v4(111.1,128.13) 111.17,128.13 C701.2 ; v4(130.3,128.93) 130.3,128.93 C427.1
  BOTTOM w0.254: v2(214.33,134.9) 214.16,134.74 R141.1
  vias: v1(175.17,97.07) v1(175.27,158.68) v1(176.55,155.81) v1(178,158.55) v1(178.28,205.08) v1(178.66,205.71) v1(179.04,205.08) v1(179.43,205.71) v1(179.42,92.35) v1(180.19,205.71) v1(180.57,205.08) v1(180.67,103.1) v1(181.56,108.91) v1(182.65,138.49) v1(184.3,125.17) v1(184.49,132.26) v1(184.72,111.55) v1(185.54,105.36) v1(185.89,158.74) v1(186.18,92.78) v1(187.58,97.94) v1(188.26,157.65) v1(188.29,130.12) v1(188.57,151.25) v1(189.54,108.79) v1(189.67,102.21) v1(189.71,125.78) v1(190.74,95.24) v1(192.51,131.45) v1(195.5,132.73) v3(188.83,155.9) v3(192.12,96.96) v3(192.12,95.69) v3(192.88,126.3) v3(192.88,112.33) v3(193.01,129.22) v3(193.27,142.3) v3(193.27,141.29) v3(193.52,138.36) v3(194.15,126.3) v3(194.28,142.3) v3(194.28,141.29) v3(195.04,139.89) v3(195.42,126.3) v4(114.3,128.93) v4(115.1,128.93) v5(62.57,128.52) v5(62.56,127.75) v5(62.57,126.99) v5(62.64,130.04) v5(62.6,129.28) v5(62.6,126.23) v5(62.64,125.47) v5(62.71,130.8) v5(62.7,124.71) v5(62.78,123.95) v5(62.88,132.31) v5(62.79,131.56) v5(62.88,123.2) v5(63,133.07) v5(63.13,133.82) v5(63.28,134.56) v5(63.47,122.69) v5(63.6,121.98) v5(63.83,134.93) v5(63.95,135.49) v5(63.9,117.3) v5(64,136) v5(64.03,116.55) v5(64.1,121.94) v5(64.17,118.93) v5(64.19,115.81) v5(64.38,135.9) v5(64.33,118.19) v5(64.35,115.06) v5(64.42,140.45) v5(64.4,138.48) v5(64.47,121.99) v5(64.44,119.39) v5(64.54,114.32) v5(64.63,141.19) v5(64.64,138.9) v5(64.77,139.61) v5(64.75,135.83) v5(64.73,113.59) v5(64.85,141.91) v5(64.85,122.07) v5(64.83,119.45) v5(64.89,138.39) v5(64.95,112.85) v5(65.09,142.64) v5(65.13,135.77) v5(65.18,112.13) v5(65.28,138.33) v5(65.22,122.13) v5(65.19,119.53) v5(65.33,143.36) v5(65.42,111.41) v5(65.5,135.7) v5(65.58,119.59) v5(65.59,144.08) v5(65.64,138.26) v5(65.6,122.21) v5(65.68,110.69) v5(65.86,144.79) v5(65.88,135.64) v5(65.97,122.26) v5(65.94,119.66) v5(65.96,109.98) v5(66.03,138.2) v5(66.15,145.49) v5(66.25,135.57) v5(66.24,109.27) v5(66.35,122.34) v5(66.33,119.72) v5(66.44,146.2) v5(66.39,138.13) v5(66.55,108.57) v5(66.63,135.51) v5(66.75,146.9) v5(66.78,138.07) v5(66.72,122.39) v5(66.69,119.79) v5(66.87,107.88) v5(67.06,147.59) v5(67.01,135.44) v5(67.08,119.85) v5(67.14,138) v5(67.1,122.48) v5(67.2,107.19) v5(67.38,135.38) v5(67.39,148.28) v5(67.47,122.53) v5(67.44,119.93) v5(67.53,137.94) v5(67.73,148.96) v5(67.76,135.3) v5(67.83,119.99) v5(67.89,137.87) v5(68.08,149.63) v5(68.02,106.89) v5(68.28,137.81) v5(68.21,135.09) v5(68.27,132.89) v5(68.25,119.96) v5(68.32,106.36) v5(68.45,150.3) v5(68.43,133.76) v5(68.42,105.88) v5(68.58,134.64) v5(68.76,119.66) v5(68.77,106.07) v5(68.96,134.96) v5(69,120.09) v5(69.08,106.26) v5(69.19,150.61) v5(69.43,106.45) v5(69.54,151.11) v5(69.72,151.6) v5(69.74,106.64) v5(69.7,103.74) v5(69.97,103.39) v5(70.06,151.42) v5(70.02,103.93) v5(70.09,106.84) v5(70.14,101.99) v5(70.28,102.78) v5(70.38,151.22) v5(70.36,104.12) v5(70.4,107.02) v5(70.5,101.32) v5(70.68,104.31) v5(70.72,151.04) v5(70.75,107.22) v5(70.81,153.81) v5(70.86,100.64) v5(71.04,150.84) v5(71.06,107.41) v5(71.01,104.5) v5(71.14,153.62) v5(71.22,154.16) v5(71.21,99.97) v5(71.38,150.66) v5(71.34,104.7) v5(71.43,155.5) v5(71.47,153.43) v5(71.41,107.6) v5(71.55,154.75) v5(71.51,99.54) v5(71.67,104.88) v5(71.7,150.46) v5(71.72,107.79) v5(71.81,156.04) v5(71.8,153.24) v5(71.84,133.03) v5(71.84,122.27) v5(72.04,150.28) v5(72,105.08) v5(72.13,153.05) v5(72.1,134.53) v5(72.1,120.77) v5(72.26,99.55) v5(72.36,150.08) v5(72.37,136.03) v5(72.37,119.27) v5(72.33,105.27) v5(72.46,152.86) v5(72.54,156.04) v5(72.65,147.23) v5(72.66,105.46) v5(72.7,149.91) v5(72.79,152.67) v5(72.98,99.55) v5(73.02,149.7) v5(72.99,105.65) v5(73.12,152.48) v5(73.09,148) v5(73.26,156.04) v5(73.34,149.32) v5(73.45,152.29) v5(73.47,105.76) v5(73.54,148.77) v5(73.78,152.1) v5(73.74,99.55) v5(73.84,132.68) v5(73.84,122.62) v5(74.02,156.04) v5(74,148.94) v5(74.04,105.65) v5(74.11,151.91) v5(74.13,106.14) v5(74.37,135.68) v5(74.37,119.62) v5(74.49,104.88) v5(74.53,99.55) v5(74.8,156.04) v5(74.93,104.11) v5(75.26,99.55) v5(75.54,156.04) v5(75.51,132.38) v5(75.51,122.92) v5(75.78,133.89) v5(75.78,121.42) v5(76.05,146.15) v5(76.04,135.39) v5(76.04,119.92) v5(76.05,109.16) v5(76.07,99.55) v5(76.35,156.04) v5(76.81,147.47) v5(76.81,107.84) v5(76.86,99.58) v5(77.14,156.07) v5(77.57,148.79) v5(77.57,106.52) v5(77.55,99.55) v5(77.81,145.13) v5(77.81,110.17) v5(77.9,156.09) v5(78.28,155.6) v5(78.28,99.55) v5(78.49,131.73) v5(78.49,123.57) v5(78.77,155.03) v5(78.77,133.36) v5(78.77,121.95) v5(79.06,134.98) v5(79.06,120.32) v5(79.16,132.13) v5(79.16,123.18) v5(79.1,99.55) v5(79.28,144.28) v5(79.2,131.67) v5(79.2,123.63) v5(79.28,111.02) v5(79.38,154.39) v5(79.33,147.77) v5(79.36,132.54) v5(79.36,122.76) v5(79.33,107.53) v5(79.46,131.24) v5(79.47,124.01) v5(79.56,134.38) v5(79.56,120.92) v5(79.6,133.92) v5(79.6,121.38) v5(79.75,134.8) v5(79.76,132.93) v5(79.76,122.37) v5(79.75,120.51) v5(79.84,133.42) v5(79.88,131.1) v5(79.88,124.21) v5(79.84,121.88) v5(79.88,99.58) v5(79.94,153.83) v5(80.04,145.6) v5(80.04,109.7) v5(80.13,135.06) v5(80.14,120.19) v5(80.28,133.35) v5(80.19,132.85) v5(80.19,122.45) v5(80.28,121.95) v5(80.47,153.33) v5(80.59,135.1) v5(80.59,120.2) v5(80.6,99.58) v5(80.8,146.92) v5(80.82,124.42) v5(80.8,108.38) v5(80.95,130.87) v5(81.02,152.71) v5(81.08,100.05) v5(81.38,134.96) v5(81.48,120.34) v5(81.61,124.48) v5(81.61,100.57) v5(81.69,152.06) v5(81.71,130.9) v5(81.85,142.65) v5(81.85,112.65) v5(82.04,134.57) v5(82.13,120.74) v5(82.17,101.11) v5(82.37,124.45) v5(82.39,151.48) v5(82.47,130.93) v5(82.5,142.35) v5(82.5,112.96) v5(82.68,144.08) v5(82.62,142.79) v5(82.6,141.86) v5(82.62,113.4) v5(82.62,112.51) v5(82.68,111.22) v5(82.62,101.56) v5(82.69,134.18) v5(82.79,121.13) v5(82.92,150.96) v5(82.95,143.12) v5(82.95,141.58) v5(82.95,113.73) v5(82.95,112.19) v5(83.13,124.45) v5(83.15,102.08) v5(83.23,130.92) v5(83.46,150.5) v5(83.46,143.35) v5(83.46,121.47) v5(83.46,111.96) v5(83.5,145.51) v5(83.49,133.83) v5(83.5,109.79) v5(83.65,144.33) v5(83.65,110.98) v5(83.65,102.62) v5(83.76,144.77) v5(83.7,143.77) v5(83.75,141.31) v5(83.77,113.94) v5(83.7,111.53) v5(83.76,110.53) v5(83.84,143.12) v5(83.88,124.59) v5(83.84,112.19) v5(83.97,149.97) v5(83.97,130.76) v5(84.09,145.1) v5(84.09,143.56) v5(84.16,121.77) v5(84.09,111.75) v5(84.09,110.21) v5(84.19,133.52) v5(84.21,103.16) v5(84.43,114.1) v5(84.5,149.45) v5(84.53,145.22) v5(84.56,110.04) v5(84.63,141.06) v5(84.61,124.82) v5(84.68,103.64) v5(84.7,130.52) v5(84.88,122.03) v5(84.95,148.93) v5(84.98,145.1) v5(84.9,133.25) v5(84.98,110.21) v5(85.06,114.49) v5(85.16,140.52) v5(85.22,104.15) v5(85.33,125.05) v5(85.43,130.29) v5(85.39,110.52) v5(85.49,148.44) v5(85.57,144.66) v5(85.63,133.02) v5(85.61,122.27) v5(85.64,114.98) v5(85.73,140.2) v5(85.78,111.02) v5(85.77,104.69) v5(86,147.91) v5(86.01,144.21) v5(86.06,125.27) v5(86.16,130.08) v5(86.22,115.47) v5(86.22,105.15) v5(86.31,139.7) v5(86.36,132.79) v5(86.33,122.49) v5(86.41,111.56) v5(86.5,147.34) v5(86.54,143.85) v5(86.75,105.66) v5(86.8,125.48) v5(86.81,115.97) v5(86.98,146.82) v5(86.89,139.21) v5(86.89,129.87) v5(87.01,143.63) v5(87.07,122.71) v5(87.09,132.57) v5(87.15,111.86) v5(87.47,138.72) v5(87.39,116.46) v5(87.41,106.38) v5(87.5,146.34) v5(87.53,143.23) v5(87.53,125.67) v5(87.63,129.68) v5(87.82,132.37) v5(87.8,122.91) v5(87.83,112.29) v5(87.97,116.95) v5(87.97,106.92) v5(88,145.8) v5(88.05,142.68) v5(88.05,138.23) v5(88.27,125.86) v5(88.23,112.96) v5(88.38,141.99) v5(88.36,129.49) v5(88.48,113.68) v5(88.44,107.39) v5(88.56,145.26) v5(88.56,132.18) v5(88.54,123.1) v5(88.55,117.44) v5(88.64,137.74) v5(88.72,141.35) v5(88.98,107.91) v5(89.01,126.04) v5(89.05,114.18) v5(89.09,144.74) v5(89.11,129.31) v5(89.13,117.93) v5(89.22,137.24) v5(89.28,123.29) v5(89.3,140.85) v5(89.3,131.99) v5(89.55,144.3) v5(89.63,114.68) v5(89.75,126.21) v5(89.71,118.43) v5(89.88,140.36) v5(89.8,136.75) v5(89.85,129.15) v5(89.99,143.72) v5(90.04,131.82) v5(90.02,123.46) v5(90.21,115.17) v5(90.38,136.26) v5(90.3,118.92) v5(90.46,139.87) v5(90.54,143.18) v5(90.5,126.36) v5(90.6,128.99) v5(90.78,131.66) v5(90.76,123.62) v5(90.88,119.41) v5(90.79,115.66) v5(90.96,135.77) v5(91.07,142.66) v5(91.04,139.38) v5(91.25,126.51) v5(91.34,128.85) v5(91.37,116.15) v5(91.46,119.9) v5(91.53,142.22) v5(91.55,135.28) v5(91.53,131.51) v5(91.51,123.77) v5(91.62,138.88) v5(91.95,116.65) v5(92,126.64) v5(92.04,120.39) v5(92.09,141.68) v5(92.13,134.79) v5(92.09,128.71) v5(92.2,138.39) v5(92.28,131.36) v5(92.26,123.91) v5(92.53,117.14) v5(92.62,141.16) v5(92.62,120.89) v5(92.79,137.9) v5(92.71,134.29) v5(92.75,126.77) v5(92.84,128.59) v5(93.03,131.24) v5(93.01,124.03) v5(93.11,140.7) v5(93.11,117.63) v5(93.21,121.38) v5(93.37,137.4) v5(93.29,133.93) v5(93.34,112.09) v5(93.5,126.88) v5(93.67,140.15) v5(93.6,128.48) v5(93.78,131.12) v5(93.77,124.15) v5(93.7,118.12) v5(93.87,133.44) v5(93.79,121.87) v5(93.79,112.54) v5(93.95,136.91) v5(94.2,139.63) v5(94.25,126.99) v5(94.28,118.62) v5(94.35,128.37) v5(94.37,122.36) v5(94.32,113.05) v5(94.46,132.95) v5(94.53,136.42) v5(94.54,131.01) v5(94.52,124.26) v5(94.71,139.12) v5(94.86,119.11) v5(94.88,113.67) v5(95.08,132.51) v5(95.01,127.08) v5(94.99,122.81) v5(95.11,135.93) v5(95.11,128.28) v5(95.27,138.58) v5(95.28,124.35) v5(95.29,130.91) v5(95.44,119.6) v5(95.44,114.21) v5(95.64,123.2) v5(95.69,135.43) v5(95.74,132.12) v5(95.77,127.17) v5(95.8,138.06) v5(95.87,128.2) v5(95.91,114.68) v5(96.05,130.83) v5(96.03,124.44) v5(96.02,120.1) v5(96.26,137.62) v5(96.28,134.95) v5(96.32,123.54) v5(96.44,115.2) v5(96.55,131.8) v5(96.53,127.24) v5(96.62,128.13) v5(96.63,120.55) v5(96.82,137.08) v5(96.81,130.75) v5(96.79,124.51) v5(96.92,134.53) v5(97,115.74) v5(97.11,127.32) v5(97.16,123.81) v5(97.27,131.53) v5(97.35,136.56) v5(97.38,128.06) v5(97.3,120.92) v5(97.45,116.2) v5(97.57,130.69) v5(97.55,124.57) v5(97.6,134.2) v5(97.77,127.35) v5(97.88,136.02) v5(97.89,124.02) v5(97.98,116.71) v5(98,131.33) v5(98,121.2) v5(98.14,128.01) v5(98.32,133.95) v5(98.33,130.64) v5(98.31,124.62) v5(98.44,135.48) v5(98.48,127.38) v5(98.51,117.37) v5(98.64,124.17) v5(98.75,131.2) v5(98.74,121.4) v5(98.97,134.96) v5(98.9,127.97) v5(99.07,133.79) v5(99.01,130.67) v5(99.07,124.66) v5(99.07,117.92) v5(99.21,127.4) v5(99.4,124.24) v5(99.5,134.42) v5(99.51,131.13) v5(99.49,121.5) v5(99.54,118.39) v5(99.66,127.94) v5(99.78,130.64) v5(99.84,124.69) v5(99.98,133.77) v5(99.97,127.43) v5(100.07,118.91) v5(100.27,131.12) v5(100.26,124.27) v5(100.38,121.53) v5(100.43,127.92) v5(100.54,130.62) v5(100.63,119.45) v5(100.76,127.45) v5(100.71,124.7) v5(100.88,133.78) v5(100.96,131.12) v5(101.08,119.9) v5(101.17,124.29) v5(101.17,121.53) v5(101.19,127.91) v5(101.39,130.58) v5(101.57,127.43) v5(101.65,133.77) v5(101.65,124.7) v5(101.61,120.42) v5(101.73,131.1) v5(101.96,127.9) v5(102.03,124.29) v5(102.01,121.53) v5(102.16,120.99) v5(102.21,130.62) v5(102.39,127.47) v5(102.52,133.77) v5(102.52,124.7) v5(102.59,131.1) v5(102.82,127.9) v5(102.95,124.29) v5(102.92,121.45) v5(103.07,130.64) v5(103.25,127.49) v5(103.43,133.77) v5(103.43,124.7) v5(103.51,131.1) v5(103.74,127.9) v5(103.79,121.45) v5(103.86,124.29) v5(103.99,130.64) v5(104.17,127.49) v5(104.34,133.77) v5(104.34,124.7) v5(104.42,131.1) v5(104.65,127.9) v5(104.73,124.27) v5(104.7,121.45) v5(104.85,130.62) v5(105.03,127.47) v5(105.21,133.79) v5(105.28,131.08) v5(105.21,124.67) v5(105.51,127.88) v5(105.64,124.27) v5(105.61,121.45) v5(105.77,130.62) v5(105.94,127.47) v5(106.12,133.79) v5(106.12,124.67) v5(106.2,131.08) v5(106.43,127.88) v5(106.45,124.27) v5(106.48,121.42) v5(106.58,130.62) v5(106.76,127.47) v5(106.94,133.79) v5(106.94,124.67) v5(107.01,131.08) v5(107.24,127.88) v5(107.27,124.27) v5(107.39,130.62) v5(107.39,121.42) v5(107.57,127.47) v5(107.75,133.79) v5(107.75,124.67) v5(107.82,131.08) v5(108.05,127.88) v5(108.03,124.27) v5(108.15,130.62) v5(108.21,121.42) v5(108.33,127.47) v5(108.51,133.79) v5(108.51,124.67) v5(108.59,131.08) v5(108.82,127.88) v5(108.84,124.27) v5(108.97,130.62) v5(109.02,121.42) v5(109.15,127.47) v5(109.22,133.77) v5(109.22,124.65) v5(109.3,131.05) v5(109.53,127.85) v5(109.55,124.24) v5(109.63,130.64) v5(109.78,121.42) v5(109.86,127.44) v5(110.03,133.77) v5(110.03,124.65) v5(110.11,131.05) v5(110.31,124.24) v5(133.5,133.73) v5(134.14,124.36) v5(134.23,130.65) v5(134.32,121.31) v5(134.4,127.46) v5(134.49,133.9) v5(134.5,128.04) v5(134.52,124.66) v5(134.72,131.2) v5(134.75,121.59) v5(135.03,124.37) v5(135.1,130.69) v5(135.25,133.9) v5(135.2,127.47) v5(135.2,121.23) v5(135.38,124.71) v5(135.44,131.2) v5(135.54,127.98) v5(135.64,121.56) v5(135.75,124.37) v5(135.82,130.69) v5(135.92,127.47) v5(136.02,133.9) v5(136.07,124.71) v5(136.04,121.23) v5(136.16,131.2) v5(136.26,127.98) v5(136.46,124.37) v5(136.45,121.59) v5(136.54,130.69) v5(136.64,127.47) v5(136.78,133.9) v5(136.88,131.2) v5(136.8,124.71) v5(136.98,127.98) v5(136.91,121.26) v5(137.18,124.37) v5(137.26,130.69) v5(137.36,127.47) v5(137.31,121.59) v5(137.54,133.9) v5(137.57,124.69) v5(137.78,131.2) v5(137.72,121.22) v5(137.88,127.98) v5(138.08,124.37) v5(138.16,130.69) v5(138.1,121.56) v5(138.26,127.47) v5(138.3,133.9) v5(138.4,124.71) v5(138.49,131.2) v5(138.51,121.25) v5(138.6,127.98) v5(138.88,130.69) v5(138.8,124.37) v5(138.98,127.47) v5(138.91,121.59) v5(139.06,133.9) v5(139.14,124.69) v5(139.21,131.2) v5(139.31,127.98) v5(139.29,121.26) v5(139.52,124.37) v5(139.59,130.69) v5(139.7,127.47) v5(139.73,121.62) v5(139.83,133.9) v5(139.98,124.69) v5(140.08,121.26) v5(140.11,131.2) v5(140.21,127.98) v5(140.42,124.37) v5(140.49,130.69) v5(140.54,121.59) v5(140.59,133.9) v5(140.59,127.47) v5(140.87,124.69) v5(140.92,121.26) v5(141.01,131.2) v5(141.11,127.98) v5(141.35,133.9) v5(141.31,124.37) v5(141.39,130.69) v5(141.4,121.59) v5(141.49,127.47) v5(141.66,124.71) v5(141.73,131.2) v5(141.76,121.26) v5(141.83,127.98) v5(142.03,124.37) v5(142.11,133.9) v5(142.11,130.69) v5(142.14,121.62) v5(142.21,127.47) v5(142.45,131.2) v5(142.42,124.71) v5(142.47,121.26) v5(142.55,127.98) v5(142.75,124.37) v5(142.88,134.59) v5(142.83,130.69) v5(142.93,133.96) v5(142.93,127.47) v5(142.9,121.62) v5(143.17,131.2) v5(143.1,124.69) v5(143.27,127.98) v5(143.28,121.26) v5(143.43,135.28) v5(143.47,124.37) v5(143.55,130.69) v5(143.65,127.47) v5(143.69,133.91) v5(143.69,121.59) v5(143.89,131.2) v5(143.81,124.69) v5(143.99,127.98) v5(144.07,121.26) v5(144.12,135.94) v5(144.27,130.69) v5(144.19,124.37) v5(144.37,127.47) v5(144.45,124.66) v5(144.58,133.9) v5(144.5,121.59) v5(144.6,131.2) v5(144.68,120.96) v5(144.71,127.98) v5(144.78,124.43) v5(144.81,136.58) v5(144.99,130.69) v5(145.09,127.47) v5(145.16,124.64) v5(145.11,121.56) v5(145.12,120.47) v5(145.29,133.95) v5(145.47,137.26) v5(145.58,131.25) v5(145.57,127.97) v5(145.54,124.4) v5(145.66,130.8) v5(145.71,119.98) v5(145.93,127.47) v5(145.97,121.44) v5(146.05,137.87) v5(146.05,124.56) v5(146.1,134.02) v5(146.28,128.05) v5(146.26,119.45) v5(146.34,131.33) v5(146.42,130.83) v5(146.5,124.21) v5(146.69,138.48) v5(146.69,121.29) v5(146.79,134.23) v5(146.69,127.43) v5(146.8,118.92) v5(146.91,124.61) v5(147.02,127.97) v5(147.09,131.48) v5(147.18,130.87) v5(147.24,124) v5(147.35,139.17) v5(147.35,120.98) v5(147.34,118.39) v5(147.47,134.58) v5(147.45,127.38) v5(147.67,124.55) v5(147.82,131.69) v5(147.83,128.07) v5(147.94,130.92) v5(147.98,123.77) v5(147.89,117.85) v5(148.01,139.83) v5(148.01,120.62) v5(148.13,134.91) v5(148.23,127.24) v5(148.43,124.49) v5(148.43,117.32) v5(148.53,131.96) v5(148.58,128.13) v5(148.56,123.45) v5(148.62,140.44) v5(148.64,120.24) v5(148.78,135.36) v5(148.7,130.99) v5(148.98,116.79) v5(148.99,127.17) v5(149.19,124.42) v5(149.22,141) v5(149.24,135.79) v5(149.22,132.3) v5(149.25,123.12) v5(149.25,119.74) v5(149.34,128.2) v5(149.46,131.06) v5(149.52,116.25) v5(149.75,127.09) v5(149.83,136.24) v5(149.87,132.69) v5(149.81,119.2) v5(149.91,141.63) v5(149.94,124.33) v5(149.9,122.73) v5(150.07,115.72) v5(150.1,128.29) v5(150.21,131.14) v5(150.38,136.71) v5(150.48,133.14) v5(150.39,118.72) v5(150.52,142.24) v5(150.5,127) v5(150.52,122.29) v5(150.61,115.19) v5(150.7,124.23) v5(150.86,128.51) v5(150.97,131.24) v5(150.95,118.31) v5(150.99,137.25) v5(151.07,133.63) v5(151.1,142.8) v5(151.11,121.81) v5(151.19,114.63) v5(151.45,124.13) v5(151.54,126.92) v5(151.51,117.81) v5(151.6,137.79) v5(151.65,134.12) v5(151.61,128.61) v5(151.71,143.46) v5(151.73,131.35) v5(151.69,121.31) v5(151.76,114.12) v5(152.12,117.3) v5(152.2,138.29) v5(152.23,134.61) v5(152.21,124.01) v5(152.27,120.82) v5(152.32,144.07) v5(152.36,128.73) v5(152.35,126.8) v5(152.29,113.58) v5(152.6,131.58) v5(152.7,116.79) v5(152.83,138.8) v5(152.81,135.1) v5(152.86,120.33) v5(152.82,113.03) v5(152.93,144.65) v5(152.96,123.88) v5(153.03,126.67) v5(153.11,128.85) v5(153.24,131.71) v5(153.24,116.31) v5(153.35,112.48) v5(153.47,139.36) v5(153.4,135.6) v5(153.44,119.84) v5(153.49,145.24) v5(153.77,126.54) v5(153.71,123.74) v5(153.86,128.99) v5(153.88,111.93) v5(153.98,136.09) v5(153.91,115.82) v5(154.05,145.82) v5(154,131.84) v5(154.02,119.35) v5(154.13,139.89) v5(154.41,123.49) v5(154.41,111.38) v5(154.56,136.58) v5(154.53,126.39) v5(154.52,115.37) v5(154.61,146.38) v5(154.65,140.38) v5(154.63,131.96) v5(154.61,129.13) v5(154.6,118.85) v5(154.94,110.83) v5(155.14,137.07) v5(155.17,123.34) v5(155.18,118.36) v5(155.1,114.88) v5(155.19,146.94) v5(155.26,140.88) v5(155.27,126.26) v5(155.36,129.29) v5(155.4,132.09) v5(155.46,110.28) v5(155.68,114.39) v5(155.72,137.56) v5(155.77,117.87) v5(155.8,147.57) v5(155.87,141.42) v5(155.91,123.14) v5(156.08,126.06) v5(155.99,109.73) v5(156.13,132.33) v5(156.1,129.46) v5(156.27,113.9) v5(156.3,142.07) v5(156.31,138.06) v5(156.35,117.38) v5(156.41,113.3) v5(156.51,148.34) v5(156.55,142.86) v5(156.52,109.19) v5(156.64,122.96) v5(156.67,112.79) v5(156.84,129.63) v5(156.79,125.88) v5(156.89,138.55) v5(156.95,132.59) v5(156.93,116.89) v5(157.05,112.28) v5(157.03,108.73) v5(157.18,143.5) v5(157.3,149.12) v5(157.35,122.76) v5(157.47,139.04) v5(157.51,132.74) v5(157.58,129.82) v5(157.56,125.65) v5(157.51,116.39) v5(157.55,111.9) v5(157.6,108.23) v5(157.81,111.26) v5(157.91,143.86) v5(158.05,139.53) v5(158.04,122.58) v5(158.09,149.91) v5(158.12,132.89) v5(158.09,115.9) v5(158.14,107.69) v5(158.31,130.02) v5(158.29,125.48) v5(158.32,111.01) v5(158.62,144.29) v5(158.63,140.02) v5(158.68,115.41) v5(158.66,107.14) v5(158.78,150.6) v5(158.78,122.35) v5(158.82,110.63) v5(158.95,125.32) v5(159.05,133.12) v5(159.05,130.23) v5(159.18,144.87) v5(159.21,140.51) v5(159.26,114.92) v5(159.19,106.59) v5(159.3,110.36) v5(159.46,151.28) v5(159.56,122.07) v5(159.62,145.49) v5(159.61,125.07) v5(159.69,110.1) v5(159.72,133.43) v5(159.78,130.45) v5(159.72,106.04) v5(159.8,141) v5(159.97,114.95) v5(160.17,145.53) v5(160.22,152.04) v5(160.2,121.79) v5(160.25,105.49) v5(160.3,133.71) v5(160.32,110.1) v5(160.46,141.37) v5(160.48,114.82) v5(160.5,130.67) v5(160.55,124.84) v5(160.66,143.47) v5(160.77,145.36) v5(160.78,121.53) v5(160.77,112.1) v5(160.77,110.22) v5(160.78,104.94) v5(160.91,152.73) v5(160.98,114.57) v5(161.02,143.51) v5(161.03,111.67) v5(161.09,145.04) v5(161.15,144.04) v5(161.09,110.55) v5(161.23,145.65) v5(161.21,144.59) v5(161.22,141.44) v5(161.19,134.09) v5(161.23,130.91) v5(161.21,124.61) v5(161.27,112.1) v5(161.21,111.37) v5(161.21,110.99) v5(161.23,109.93) v5(161.34,121.2) v5(161.31,104.39) v5(161.57,153.37) v5(161.53,143.49) v5(161.53,114.49) v5(161.65,114.1) v5(161.65,112.07) v5(161.83,103.84) v5(161.95,134.42) v5(161.98,131.05) v5(162.05,144.22) v5(162.04,143.26) v5(162.04,141.72) v5(162,124.56) v5(162.04,113.87) v5(162.04,112.33) v5(162.05,111.36) v5(162.15,153.97) v5(162.1,120.8) v5(162.36,142.93) v5(162.35,142.49) v5(162.36,142.04) v5(162.36,112.65) v5(162.36,103.29) v5(162.39,113.59) v5(162.48,113.1) v5(162.64,134.75) v5(162.74,131.05) v5(162.88,142.79) v5(162.79,124.54) v5(162.88,112.79) v5(162.87,102.79) v5(162.97,154.69) v5(162.92,120.41) v5(163.4,135.14) v5(163.44,102.29) v5(163.5,131.01) v5(163.63,124.64) v5(163.7,155.4) v5(163.73,120.29) v5(163.92,147.06) v5(163.92,108.52) v5(163.98,101.74) v5(164.14,135.37) v5(164.29,130.82) v5(164.21,124.64) v5(164.25,122.41) v5(164.27,120.22) v5(164.41,133.24) v5(164.51,101.19) v5(164.61,155.37) v5(164.59,135.38) v5(164.69,145.74) v5(164.72,120.26) v5(164.69,109.84) v5(164.84,131.11) v5(164.84,124.35) v5(164.89,133.56) v5(164.97,133.07) v5(164.97,122.51) v5(164.89,122.02) v5(165.03,100.64) v5(165.1,135.06) v5(165.13,133.93) v5(165.1,120.52) v5(165.26,131.31) v5(165.27,124.2) v5(165.26,121.52) v5(165.37,155.37) v5(165.3,134.52) v5(165.37,132.81) v5(165.3,121.06) v5(165.4,147.91) v5(165.45,144.42) v5(165.45,111.16) v5(165.4,107.67) v5(165.53,131.68) v5(165.5,122.9) v5(165.56,100.09) v5(165.67,135.12) v5(165.65,123.77) v5(165.67,120.46) v5(165.69,132.27) v5(165.69,123.32) v5(165.95,133.5) v5(165.95,122.09) v5(166.13,155.37) v5(166.09,99.55) v5(166.24,131.87) v5(166.24,123.71) v5(166.62,99) v5(166.9,155.37) v5(166.92,145.27) v5(166.92,110.31) v5(167.16,148.93) v5(167.16,106.66) v5(167.41,98.98) v5(167.59,155.33) v5(167.92,147.61) v5(167.92,107.98) v5(168.22,98.96) v5(168.29,155.37) v5(168.68,146.29) v5(168.69,135.53) v5(168.69,120.06) v5(168.68,109.3) v5(168.95,134.03) v5(168.95,121.56) v5(169.05,155.37) v5(169.22,132.52) v5(169.22,123.06) v5(169.19,98.96) v5(169.82,155.37) v5(169.8,151.33) v5(170.24,150.56) v5(170.21,98.96) v5(170.36,135.82) v5(170.36,119.76) v5(170.58,155.37) v5(170.5,103.58) v5(170.69,149.79) v5(170.6,149.3) v5(170.73,106.5) v5(170.84,103.38) v5(170.89,132.82) v5(170.89,122.76) v5(171.16,103.2) v5(171.17,98.96) v5(171.26,149.68) v5(171.19,106.67) v5(171.34,155.37) v5(171.39,106.12) v5(171.5,103) v5(171.64,107.44) v5(171.76,149.8) v5(171.71,105.75) v5(171.82,102.82) v5(172.07,149.99) v5(172.08,108.21) v5(172.03,105.57) v5(172.06,98.96) v5(172.1,155.37) v5(172.16,102.62) v5(172.36,136.17) v5(172.36,119.41) v5(172.37,105.37) v5(172.42,150.18) v5(172.48,102.44) v5(172.63,134.67) v5(172.63,120.91) v5(172.73,150.37) v5(172.69,105.19) v5(172.72,99.06) v5(172.86,155.37) v5(172.82,102.24) v5(172.89,133.17) v5(172.89,122.41) v5(173.08,150.56) v5(173.04,147.67) v5(173.03,104.99) v5(173.08,99.6) v5(173.15,102.06) v5(173.2,154.82) v5(173.35,147.85) v5(173.35,104.81) v5(173.39,150.76) v5(173.46,101.88) v5(173.47,100.25) v5(173.61,154.19) v5(173.74,150.95) v5(173.69,148.05) v5(173.69,104.61) v5(173.76,101.7) v5(174.03,153.48) v5(174.05,151.14) v5(174.01,148.24) v5(174.02,104.43) v5(174.35,148.44) v5(174.35,104.23) v5(174.4,152.82) v5(174.4,151.33) v5(174.67,148.62) v5(174.68,104.05) v5(174.71,151.52) v5(175.02,151.67) v5(175.01,148.82) v5(175.03,103.84) v5(175.33,149) v5(175.67,149.2) v5(175.66,137.53) v5(175.73,135.35) v5(175.77,120.48) v5(175.82,136.65) v5(175.97,135.78) v5(175.96,104.9) v5(175.99,149.39) v5(176.15,120.8) v5(176.32,149.56) v5(176.3,121.68) v5(176.33,105.56) v5(176.48,135.48) v5(176.46,122.56) v5(176.52,120.35) v5(176.5,117.63) v5(176.69,106.24) v5(176.86,117.56) v5(176.97,148.32) v5(177.01,135.44) v5(177.04,120.11) v5(177.04,106.91) v5(177.25,117.5) v5(177.38,107.6) v5(177.42,147.75) v5(177.4,135.52) v5(177.44,132.94) v5(177.41,120.04) v5(177.61,117.42) v5(177.73,147.06) v5(177.76,135.58) v5(177.71,108.28) v5(177.8,132.99) v5(177.79,119.98) v5(178.03,146.36) v5(178,117.37) v5(178.02,108.98) v5(178.15,135.65) v5(178.19,133.07) v5(178.16,119.91) v5(178.32,145.65) v5(178.36,117.29) v5(178.32,109.68) v5(178.51,135.71) v5(178.55,133.12) v5(178.54,119.85) v5(178.59,144.94) v5(178.61,110.39) v5(178.75,117.24) v5(178.85,144.22) v5(178.9,135.79) v5(178.94,133.21) v5(178.91,119.78) v5(178.89,111.1) v5(179.1,143.5) v5(179.11,117.16) v5(179.15,111.81) v5(179.26,135.84) v5(179.34,142.78) v5(179.3,133.26) v5(179.29,119.72) v5(179.4,112.53) v5(179.56,142.05) v5(179.5,117.11) v5(179.65,135.92) v5(179.69,133.34) v5(179.67,119.65) v5(179.64,113.38) v5(179.77,141.32) v5(179.86,117.03) v5(179.86,114.11) v5(179.97,140.58) v5(180.01,135.98) v5(180.05,133.39) v5(180.04,119.59) v5(180,116.3) v5(180.07,114.84) v5(180.16,139.84) v5(180.25,137) v5(180.25,116.94) v5(180.27,115.58) v5(180.33,139.1) v5(180.38,136.49) v5(180.4,136.05) v5(180.43,133.45) v5(180.42,119.52) v5(180.49,138.35) v5(180.5,119.98) v5(180.63,137.61) v5(180.76,136.11) v5(180.76,120.62) v5(180.8,133.52) v5(180.88,133.06) v5(180.79,119.46) v5(181.01,132.68) v5(181.11,133.58) v5(181.25,121.1) v5(181.39,121.98) v5(181.49,132.15) v5(181.51,122.71) v5(181.59,131.52) v5(181.67,130.89) v5(181.73,130.26) v5(181.76,124.26) v5(181.71,123.52) v5(181.81,129.52) v5(181.84,128.78) v5(181.84,128.12) v5(181.84,127.48) v5(181.86,126.9) v5(181.84,126.14) v5(181.81,125.45) v5(181.79,124.79) v6(67.86,122.21) v6(68.16,120.46) v6(68.3,135.59) v6(68.31,122.17) v6(68.58,120.66) v6(68.61,137.34) v6(68.76,135.63) v6(68.69,121.91) v6(68.89,121.49) v6(68.85,121.03) v6(68.91,118.79) v6(69.02,137.15) v6(69.07,117.91) v6(69.13,135.9) v6(69.29,136.77) v6(69.33,136.31) v6(72.32,107.74) v6(72.77,107.86) v6(73.21,107.74) v6(73.21,106.2) v6(73.54,107.42) v6(73.54,106.53) v6(73.59,149.76) v6(73.66,106.97) v6(74.04,149.64) v6(74.48,151.3) v6(74.48,149.76) v6(74.81,150.98) v6(74.81,150.09) v6(74.93,150.53) v6(169.8,104.91) v6(169.92,105.36) v6(169.92,104.47) v6(170.24,105.68) v6(170.24,104.14) v6(170.69,105.8) v6(171.07,148.47) v6(171.13,105.68) v6(171.19,148.92) v6(171.19,148.03) v6(171.51,149.24) v6(171.51,147.7) v6(171.96,147.58) v6(172.4,147.7) v6(175.4,119.13) v6(175.44,118.67) v6(175.6,119.55) v6(175.71,118.3) v6(175.88,134.41) v6(175.84,133.95) v6(175.97,119.81) v6(176.04,133.53) v6(176.15,134.79) v6(176.12,118.1) v6(176.41,133.27) v6(176.43,119.85) v6(176.56,134.98) v6(176.87,133.23) v7(62.57,128.52) v7(62.56,127.75) v7(62.57,126.99) v7(62.64,130.04) v7(62.6,129.28) v7(62.6,126.23) v7(62.64,125.47) v7(62.71,130.8) v7(62.7,124.71) v7(62.78,123.95) v7(62.88,132.31) v7(62.79,131.56) v7(62.88,123.2) v7(63,133.07) v7(63.13,133.82) v7(63.28,134.56) v7(63.47,122.69) v7(63.6,121.98) v7(63.83,134.93) v7(63.95,135.49) v7(63.9,117.3) v7(64,136) v7(64.03,116.55) v7(64.1,121.94) v7(64.17,118.93) v7(64.19,115.81) v7(64.38,135.9) v7(64.33,118.19) v7(64.35,115.06) v7(64.42,140.45) v7(64.4,138.48) v7(64.47,121.99) v7(64.44,119.39) v7(64.54,114.32) v7(64.63,141.19) v7(64.64,138.9) v7(64.77,139.61) v7(64.75,135.83) v7(64.73,113.59) v7(64.85,141.91) v7(64.85,122.07) v7(64.83,119.45) v7(64.89,138.39) v7(64.95,112.85) v7(65.09,142.64) v7(65.13,135.77) v7(65.18,112.13) v7(65.28,138.33) v7(65.22,122.13) v7(65.19,119.53) v7(65.33,143.36) v7(65.42,111.41) v7(65.5,135.7) v7(65.58,119.59) v7(65.59,144.08) v7(65.64,138.26) v7(65.6,122.21) v7(65.68,110.69) v7(65.86,144.79) v7(65.88,135.64) v7(65.97,122.26) v7(65.94,119.66) v7(65.96,109.98) v7(66.03,138.2) v7(66.15,145.49) v7(66.25,135.57) v7(66.24,109.27) v7(66.35,122.34) v7(66.33,119.72) v7(66.44,146.2) v7(66.39,138.13) v7(66.55,108.57) v7(66.63,135.51) v7(66.75,146.9) v7(66.78,138.07) v7(66.72,122.39) v7(66.69,119.79) v7(66.87,107.88) v7(67.06,147.59) v7(67.01,135.44) v7(67.08,119.85) v7(67.14,138) v7(67.1,122.48) v7(67.2,107.19) v7(67.38,135.38) v7(67.39,148.28) v7(67.47,122.53) v7(67.44,119.93) v7(67.53,137.94) v7(67.73,148.96) v7(67.76,135.3) v7(67.83,119.99) v7(67.89,137.87) v7(68.08,149.63) v7(68.02,106.89) v7(68.28,137.81) v7(68.21,135.09) v7(68.27,132.89) v7(68.25,119.96) v7(68.32,106.36) v7(68.45,150.3) v7(68.43,133.76) v7(68.42,105.88) v7(68.58,134.64) v7(68.76,119.66) v7(68.77,106.07) v7(68.96,134.96) v7(69,120.09) v7(69.08,106.26) v7(69.19,150.61) v7(69.43,106.45) v7(69.54,151.11) v7(69.72,151.6) v7(69.74,106.64) v7(69.7,103.74) v7(69.97,103.39) v7(70.06,151.42) v7(70.02,103.93) v7(70.09,106.84) v7(70.14,101.99) v7(70.28,102.78) v7(70.38,151.22) v7(70.36,104.12) v7(70.4,107.02) v7(70.5,101.32) v7(70.68,104.31) v7(70.72,151.04) v7(70.75,107.22) v7(70.81,153.81) v7(70.86,100.64) v7(71.04,150.84) v7(71.06,107.41) v7(71.01,104.5) v7(71.14,153.62) v7(71.22,154.16) v7(71.21,99.97) v7(71.38,150.66) v7(71.34,104.7) v7(71.43,155.5) v7(71.47,153.43) v7(71.41,107.6) v7(71.55,154.75) v7(71.51,99.54) v7(71.67,104.88) v7(71.7,150.46) v7(71.72,107.79) v7(71.81,156.04) v7(71.8,153.24) v7(71.84,133.03) v7(71.84,122.27) v7(72.04,150.28) v7(72,105.08) v7(72.13,153.05) v7(72.1,134.53) v7(72.1,120.77) v7(72.26,99.55) v7(72.36,150.08) v7(72.37,136.03) v7(72.37,119.27) v7(72.33,105.27) v7(72.46,152.86) v7(72.54,156.04) v7(72.65,147.23) v7(72.66,105.46) v7(72.7,149.91) v7(72.79,152.67) v7(72.98,99.55) v7(73.02,149.7) v7(72.99,105.65) v7(73.12,152.48) v7(73.09,148) v7(73.26,156.04) v7(73.34,149.32) v7(73.45,152.29) v7(73.47,105.76) v7(73.54,148.77) v7(73.78,152.1) v7(73.74,99.55) v7(73.84,132.68) v7(73.84,122.62) v7(74.02,156.04) v7(74,148.94) v7(74.04,105.65) v7(74.11,151.91) v7(74.13,106.14) v7(74.37,135.68) v7(74.37,119.62) v7(74.49,104.88) v7(74.53,99.55) v7(74.8,156.04) v7(74.93,104.11) v7(75.26,99.55) v7(75.54,156.04) v7(75.51,132.38) v7(75.51,122.92) v7(75.78,133.89) v7(75.78,121.42) v7(76.05,146.15) v7(76.04,135.39) v7(76.04,119.92) v7(76.05,109.16) v7(76.07,99.55) v7(76.35,156.04) v7(76.81,147.47) v7(76.81,107.84) v7(76.86,99.58) v7(77.14,156.07) v7(77.57,148.79) v7(77.57,106.52) v7(77.55,99.55) v7(77.81,145.13) v7(77.81,110.17) v7(77.9,156.09) v7(78.28,155.6) v7(78.28,99.55) v7(78.49,131.73) v7(78.49,123.57) v7(78.77,155.03) v7(78.77,133.36) v7(78.77,121.95) v7(79.06,134.98) v7(79.06,120.32) v7(79.16,132.13) v7(79.16,123.18) v7(79.1,99.55) v7(79.28,144.28) v7(79.2,131.67) v7(79.2,123.63) v7(79.28,111.02) v7(79.38,154.39) v7(79.33,147.77) v7(79.36,132.54) v7(79.36,122.76) v7(79.33,107.53) v7(79.46,131.24) v7(79.47,124.01) v7(79.56,134.38) v7(79.56,120.92) v7(79.6,133.92) v7(79.6,121.38) v7(79.75,134.8) v7(79.76,132.93) v7(79.76,122.37) v7(79.75,120.51) v7(79.84,133.42) v7(79.88,131.1) v7(79.88,124.21) v7(79.84,121.88) v7(79.88,99.58) v7(79.94,153.83) v7(80.04,145.6) v7(80.04,109.7) v7(80.13,135.06) v7(80.14,120.19) v7(80.28,133.35) v7(80.19,132.85) v7(80.19,122.45) v7(80.28,121.95) v7(80.47,153.33) v7(80.59,135.1) v7(80.59,120.2) v7(80.6,99.58) v7(80.8,146.92) v7(80.82,124.42) v7(80.8,108.38) v7(80.95,130.87) v7(81.02,152.71) v7(81.08,100.05) v7(81.38,134.96) v7(81.48,120.34) v7(81.61,124.48) v7(81.61,100.57) v7(81.69,152.06) v7(81.71,130.9) v7(81.85,142.65) v7(81.85,112.65) v7(82.04,134.57) v7(82.13,120.74) v7(82.17,101.11) v7(82.37,124.45) v7(82.39,151.48) v7(82.47,130.93) v7(82.5,142.35) v7(82.5,112.96) v7(82.68,144.08) v7(82.62,142.79) v7(82.6,141.86) v7(82.62,113.4) v7(82.62,112.51) v7(82.68,111.22) v7(82.62,101.56) v7(82.69,134.18) v7(82.79,121.13) v7(82.92,150.96) v7(82.95,143.12) v7(82.95,141.58) v7(82.95,113.73) v7(82.95,112.19) v7(83.13,124.45) v7(83.15,102.08) v7(83.23,130.92) v7(83.46,150.5) v7(83.46,143.35) v7(83.46,121.47) v7(83.46,111.96) v7(83.5,145.51) v7(83.49,133.83) v7(83.5,109.79) v7(83.65,144.33) v7(83.65,102.62) v7(83.76,144.77) v7(83.7,143.77) v7(83.75,141.31) v7(83.77,113.94) v7(83.7,111.53) v7(83.76,110.53) v7(83.84,143.12) v7(83.88,124.59) v7(83.84,112.19) v7(83.97,149.97) v7(83.97,130.76) v7(84.09,145.1) v7(84.09,143.56) v7(84.16,121.77) v7(84.09,111.75) v7(84.09,110.21) v7(84.19,133.52) v7(84.21,103.16) v7(84.43,114.1) v7(84.5,149.45) v7(84.53,145.22) v7(84.56,110.04) v7(84.63,141.06) v7(84.61,124.82) v7(84.68,103.64) v7(84.7,130.52) v7(84.88,122.03) v7(84.95,148.93) v7(84.98,145.1) v7(84.9,133.25) v7(84.98,110.21) v7(85.06,114.49) v7(85.16,140.52) v7(85.22,104.15) v7(85.33,125.05) v7(85.43,130.29) v7(85.39,110.52) v7(85.49,148.44) v7(85.57,144.66) v7(85.63,133.02) v7(85.61,122.27) v7(85.64,114.98) v7(85.73,140.2) v7(85.78,111.02) v7(85.77,104.69) v7(86,147.91) v7(86.01,144.21) v7(86.06,125.27) v7(86.16,130.08) v7(86.22,115.47) v7(86.22,105.15) v7(86.31,139.7) v7(86.36,132.79) v7(86.33,122.49) v7(86.41,111.56) v7(86.5,147.34) v7(86.54,143.85) v7(86.75,105.66) v7(86.8,125.48) v7(86.81,115.97) v7(86.98,146.82) v7(86.89,139.21) v7(86.89,129.87) v7(87.01,143.63) v7(87.07,122.71) v7(87.09,132.57) v7(87.15,111.86) v7(87.47,138.72) v7(87.39,116.46) v7(87.41,106.38) v7(87.5,146.34) v7(87.53,143.23) v7(87.53,125.67) v7(87.63,129.68) v7(87.82,132.37) v7(87.8,122.91) v7(87.83,112.29) v7(87.97,116.95) v7(87.97,106.92) v7(88,145.8) v7(88.05,142.68) v7(88.27,125.86) v7(88.23,112.96) v7(88.38,141.99) v7(88.36,129.49) v7(88.48,113.68) v7(88.44,107.39) v7(88.56,145.26) v7(88.56,132.18) v7(88.54,123.1) v7(88.55,117.44) v7(88.64,137.74) v7(88.72,141.35) v7(88.98,107.91) v7(89.01,126.04) v7(89.05,114.18) v7(89.09,144.74) v7(89.11,129.31) v7(89.13,117.93) v7(89.22,137.24) v7(89.28,123.29) v7(89.3,140.85) v7(89.3,131.99) v7(89.55,144.3) v7(89.63,114.68) v7(89.75,126.21) v7(89.71,118.43) v7(89.88,140.36) v7(89.8,136.75) v7(89.85,129.15) v7(89.99,143.72) v7(90.04,131.82) v7(90.02,123.46) v7(90.21,115.17) v7(90.38,136.26) v7(90.3,118.92) v7(90.46,139.87) v7(90.54,143.18) v7(90.5,126.36) v7(90.6,128.99) v7(90.78,131.66) v7(90.76,123.62) v7(90.88,119.41) v7(90.79,115.66) v7(90.96,135.77) v7(91.07,142.66) v7(91.04,139.38) v7(91.25,126.51) v7(91.34,128.85) v7(91.37,116.15) v7(91.46,119.9) v7(91.53,142.22) v7(91.55,135.28) v7(91.53,131.51) v7(91.51,123.77) v7(91.62,138.88) v7(91.95,116.65) v7(92,126.64) v7(92.04,120.39) v7(92.09,141.68) v7(92.13,134.79) v7(92.09,128.71) v7(92.2,138.39) v7(92.28,131.36) v7(92.26,123.91) v7(92.53,117.14) v7(92.62,141.16) v7(92.62,120.89) v7(92.79,137.9) v7(92.71,134.29) v7(92.75,126.77) v7(92.84,128.59) v7(93.03,131.24) v7(93.01,124.03) v7(93.11,140.7) v7(93.11,117.63) v7(93.21,121.38) v7(93.37,137.4) v7(93.29,133.93) v7(93.34,112.09) v7(93.5,126.88) v7(93.67,140.15) v7(93.6,128.48) v7(93.78,131.12) v7(93.77,124.15) v7(93.7,118.12) v7(93.87,133.44) v7(93.79,121.87) v7(93.79,112.54) v7(93.95,136.91) v7(94.2,139.63) v7(94.25,126.99) v7(94.28,118.62) v7(94.35,128.37) v7(94.37,122.36) v7(94.32,113.05) v7(94.46,132.95) v7(94.53,136.42) v7(94.54,131.01) v7(94.52,124.26) v7(94.71,139.12) v7(94.86,119.11) v7(94.88,113.67) v7(95.08,132.51) v7(95.01,127.08) v7(94.99,122.81) v7(95.11,135.93) v7(95.11,128.28) v7(95.27,138.58) v7(95.28,124.35) v7(95.29,130.91) v7(95.44,119.6) v7(95.44,114.21) v7(95.64,123.2) v7(95.69,135.43) v7(95.74,132.12) v7(95.77,127.17) v7(95.8,138.06) v7(95.87,128.2) v7(95.91,114.68) v7(96.05,130.83) v7(96.03,124.44) v7(96.02,120.1) v7(96.26,137.62) v7(96.28,134.95) v7(96.32,123.54) v7(96.44,115.2) v7(96.55,131.8) v7(96.53,127.24) v7(96.62,128.13) v7(96.63,120.55) v7(96.82,137.08) v7(96.81,130.75) v7(96.79,124.51) v7(96.92,134.53) v7(97,115.74) v7(97.11,127.32) v7(97.16,123.81) v7(97.27,131.53) v7(97.35,136.56) v7(97.38,128.06) v7(97.3,120.92) v7(97.45,116.2) v7(97.57,130.69) v7(97.55,124.57) v7(97.6,134.2) v7(97.77,127.35) v7(97.88,136.02) v7(97.89,124.02) v7(97.98,116.71) v7(98,131.33) v7(98,121.2) v7(98.14,128.01) v7(98.32,133.95) v7(98.33,130.64) v7(98.31,124.62) v7(98.44,135.48) v7(98.48,127.38) v7(98.51,117.37) v7(98.64,124.17) v7(98.75,131.2) v7(98.74,121.4) v7(98.97,134.96) v7(98.9,127.97) v7(99.07,133.79) v7(99.01,130.67) v7(99.07,124.66) v7(99.07,117.92) v7(99.21,127.4) v7(99.4,124.24) v7(99.5,134.42) v7(99.51,131.13) v7(99.49,121.5) v7(99.54,118.39) v7(99.66,127.94) v7(99.78,130.64) v7(99.84,124.69) v7(99.98,133.77) v7(99.97,127.43) v7(100.07,118.91) v7(100.27,131.12) v7(100.26,124.27) v7(100.38,121.53) v7(100.43,127.92) v7(100.54,130.62) v7(100.63,119.45) v7(100.76,127.45) v7(100.71,124.7) v7(100.88,133.78) v7(100.96,131.12) v7(101.08,119.9) v7(101.17,124.29) v7(101.17,121.53) v7(101.19,127.91) v7(101.39,130.58) v7(101.57,127.43) v7(101.65,133.77) v7(101.65,124.7) v7(101.61,120.42) v7(101.73,131.1) v7(101.96,127.9) v7(102.03,124.29) v7(102.01,121.53) v7(102.16,120.99) v7(102.21,130.62) v7(102.39,127.47) v7(102.52,133.77) v7(102.52,124.7) v7(102.59,131.1) v7(102.82,127.9) v7(102.95,124.29) v7(102.92,121.45) v7(103.07,130.64) v7(103.25,127.49) v7(103.43,133.77) v7(103.43,124.7) v7(103.51,131.1) v7(103.74,127.9) v7(103.79,121.45) v7(103.86,124.29) v7(103.99,130.64) v7(104.17,127.49) v7(104.34,133.77) v7(104.34,124.7) v7(104.42,131.1) v7(104.65,127.9) v7(104.73,124.27) v7(104.7,121.45) v7(104.85,130.62) v7(105.03,127.47) v7(105.21,133.79) v7(105.28,131.08) v7(105.21,124.67) v7(105.51,127.88) v7(105.64,124.27) v7(105.61,121.45) v7(105.77,130.62) v7(105.94,127.47) v7(106.12,133.79) v7(106.12,124.67) v7(106.2,131.08) v7(106.43,127.88) v7(106.45,124.27) v7(106.48,121.42) v7(106.58,130.62) v7(106.76,127.47) v7(106.94,133.79) v7(106.94,124.67) v7(107.01,131.08) v7(107.24,127.88) v7(107.27,124.27) v7(107.39,130.62) v7(107.39,121.42) v7(107.57,127.47) v7(107.75,133.79) v7(107.75,124.67) v7(107.82,131.08) v7(108.05,127.88) v7(108.03,124.27) v7(108.15,130.62) v7(108.21,121.42) v7(108.33,127.47) v7(108.51,133.79) v7(108.51,124.67) v7(108.59,131.08) v7(108.82,127.88) v7(108.84,124.27) v7(108.97,130.62) v7(109.02,121.42) v7(109.15,127.47) v7(109.22,133.77) v7(109.22,124.65) v7(109.3,131.05) v7(109.53,127.85) v7(109.55,124.24) v7(109.63,130.64) v7(109.78,121.42) v7(109.86,127.44) v7(110.03,133.77) v7(110.03,124.65) v7(110.11,131.05) v7(110.31,124.24) v7(133.5,133.73) v7(134.14,124.36) v7(134.23,130.65) v7(134.32,121.31) v7(134.4,127.46) v7(134.49,133.9) v7(134.5,128.04) v7(134.52,124.66) v7(134.72,131.2) v7(134.75,121.59) v7(135.03,124.37) v7(135.1,130.69) v7(135.25,133.9) v7(135.2,127.47) v7(135.2,121.23) v7(135.38,124.71) v7(135.44,131.2) v7(135.54,127.98) v7(135.64,121.56) v7(135.75,124.37) v7(135.82,130.69) v7(135.92,127.47) v7(136.02,133.9) v7(136.07,124.71) v7(136.04,121.23) v7(136.16,131.2) v7(136.26,127.98) v7(136.46,124.37) v7(136.45,121.59) v7(136.54,130.69) v7(136.64,127.47) v7(136.78,133.9) v7(136.88,131.2) v7(136.8,124.71) v7(136.98,127.98) v7(136.91,121.26) v7(137.18,124.37) v7(137.26,130.69) v7(137.36,127.47) v7(137.31,121.59) v7(137.54,133.9) v7(137.57,124.69) v7(137.78,131.2) v7(137.72,121.22) v7(137.88,127.98) v7(138.08,124.37) v7(138.16,130.69) v7(138.1,121.56) v7(138.26,127.47) v7(138.3,133.9) v7(138.4,124.71) v7(138.49,131.2) v7(138.51,121.25) v7(138.6,127.98) v7(138.88,130.69) v7(138.8,124.37) v7(138.98,127.47) v7(138.91,121.59) v7(139.06,133.9) v7(139.14,124.69) v7(139.21,131.2) v7(139.31,127.98) v7(139.29,121.26) v7(139.52,124.37) v7(139.59,130.69) v7(139.7,127.47) v7(139.73,121.62) v7(139.83,133.9) v7(139.98,124.69) v7(140.08,121.26) v7(140.11,131.2) v7(140.21,127.98) v7(140.42,124.37) v7(140.49,130.69) v7(140.54,121.59) v7(140.59,133.9) v7(140.59,127.47) v7(140.87,124.69) v7(140.92,121.26) v7(141.01,131.2) v7(141.11,127.98) v7(141.35,133.9) v7(141.31,124.37) v7(141.39,130.69) v7(141.4,121.59) v7(141.49,127.47) v7(141.66,124.71) v7(141.73,131.2) v7(141.76,121.26) v7(141.83,127.98) v7(142.03,124.37) v7(142.11,133.9) v7(142.11,130.69) v7(142.14,121.62) v7(142.21,127.47) v7(142.45,131.2) v7(142.42,124.71) v7(142.47,121.26) v7(142.55,127.98) v7(142.75,124.37) v7(142.88,134.59) v7(142.83,130.69) v7(142.93,133.96) v7(142.93,127.47) v7(142.9,121.62) v7(143.17,131.2) v7(143.1,124.69) v7(143.27,127.98) v7(143.28,121.26) v7(143.43,135.28) v7(143.47,124.37) v7(143.55,130.69) v7(143.65,127.47) v7(143.69,133.91) v7(143.69,121.59) v7(143.89,131.2) v7(143.81,124.69) v7(143.99,127.98) v7(144.07,121.26) v7(144.12,135.94) v7(144.27,130.69) v7(144.19,124.37) v7(144.37,127.47) v7(144.45,124.66) v7(144.58,133.9) v7(144.5,121.59) v7(144.6,131.2) v7(144.68,120.96) v7(144.71,127.98) v7(144.78,124.43) v7(144.81,136.58) v7(144.99,130.69) v7(145.09,127.47) v7(145.16,124.64) v7(145.11,121.56) v7(145.12,120.47) v7(145.29,133.95) v7(145.47,137.26) v7(145.58,131.25) v7(145.57,127.97) v7(145.54,124.4) v7(145.66,130.8) v7(145.71,119.98) v7(145.93,127.47) v7(145.97,121.44) v7(146.05,137.87) v7(146.05,124.56) v7(146.1,134.02) v7(146.28,128.05) v7(146.26,119.45) v7(146.34,131.33) v7(146.42,130.83) v7(146.5,124.21) v7(146.69,138.48) v7(146.69,121.29) v7(146.79,134.23) v7(146.69,127.43) v7(146.8,118.92) v7(146.91,124.61) v7(147.02,127.97) v7(147.09,131.48) v7(147.18,130.87) v7(147.24,124) v7(147.35,139.17) v7(147.35,120.98) v7(147.34,118.39) v7(147.47,134.58) v7(147.45,127.38) v7(147.67,124.55) v7(147.82,131.69) v7(147.83,128.07) v7(147.94,130.92) v7(147.98,123.77) v7(147.89,117.85) v7(148.01,139.83) v7(148.01,120.62) v7(148.13,134.91) v7(148.23,127.24) v7(148.43,124.49) v7(148.43,117.32) v7(148.53,131.96) v7(148.58,128.13) v7(148.56,123.45) v7(148.62,140.44) v7(148.64,120.24) v7(148.78,135.36) v7(148.7,130.99) v7(148.98,116.79) v7(148.99,127.17) v7(149.19,124.42) v7(149.22,141) v7(149.24,135.79) v7(149.22,132.3) v7(149.25,123.12) v7(149.25,119.74) v7(149.34,128.2) v7(149.46,131.06) v7(149.52,116.25) v7(149.75,127.09) v7(149.83,136.24) v7(149.87,132.69) v7(149.81,119.2) v7(149.91,141.63) v7(149.94,124.33) v7(149.9,122.73) v7(150.07,115.72) v7(150.1,128.29) v7(150.21,131.14) v7(150.38,136.71) v7(150.48,133.14) v7(150.39,118.72) v7(150.52,142.24) v7(150.5,127) v7(150.52,122.29) v7(150.61,115.19) v7(150.7,124.23) v7(150.86,128.51) v7(150.97,131.24) v7(150.95,118.31) v7(150.99,137.25) v7(151.07,133.63) v7(151.1,142.8) v7(151.11,121.81) v7(151.19,114.63) v7(151.45,124.13) v7(151.54,126.92) v7(151.51,117.81) v7(151.6,137.79) v7(151.65,134.12) v7(151.61,128.61) v7(151.71,143.46) v7(151.73,131.35) v7(151.69,121.31) v7(151.76,114.12) v7(152.12,117.3) v7(152.2,138.29) v7(152.23,134.61) v7(152.21,124.01) v7(152.27,120.82) v7(152.32,144.07) v7(152.36,128.73) v7(152.35,126.8) v7(152.29,113.58) v7(152.6,131.58) v7(152.7,116.79) v7(152.83,138.8) v7(152.81,135.1) v7(152.86,120.33) v7(152.82,113.03) v7(152.93,144.65) v7(152.96,123.88) v7(153.03,126.67) v7(153.11,128.85) v7(153.24,131.71) v7(153.24,116.31) v7(153.35,112.48) v7(153.47,139.36) v7(153.4,135.6) v7(153.44,119.84) v7(153.49,145.24) v7(153.77,126.54) v7(153.71,123.74) v7(153.86,128.99) v7(153.88,111.93) v7(153.98,136.09) v7(153.91,115.82) v7(154.05,145.82) v7(154,131.84) v7(154.02,119.35) v7(154.13,139.89) v7(154.41,123.49) v7(154.41,111.38) v7(154.56,136.58) v7(154.53,126.39) v7(154.52,115.37) v7(154.61,146.38) v7(154.65,140.38) v7(154.63,131.96) v7(154.61,129.13) v7(154.6,118.85) v7(154.94,110.83) v7(155.14,137.07) v7(155.17,123.34) v7(155.18,118.36) v7(155.1,114.88) v7(155.19,146.94) v7(155.26,140.88) v7(155.27,126.26) v7(155.36,129.29) v7(155.4,132.09) v7(155.46,110.28) v7(155.68,114.39) v7(155.72,137.56) v7(155.77,117.87) v7(155.8,147.57) v7(155.87,141.42) v7(155.91,123.14) v7(156.08,126.06) v7(155.99,109.73) v7(156.13,132.33) v7(156.1,129.46) v7(156.27,113.9) v7(156.3,142.07) v7(156.31,138.06) v7(156.35,117.38) v7(156.41,113.3) v7(156.51,148.34) v7(156.55,142.86) v7(156.52,109.19) v7(156.64,122.96) v7(156.67,112.79) v7(156.84,129.63) v7(156.79,125.88) v7(156.89,138.55) v7(156.95,132.59) v7(156.93,116.89) v7(157.05,112.28) v7(157.03,108.73) v7(157.18,143.5) v7(157.3,149.12) v7(157.35,122.76) v7(157.47,139.04) v7(157.51,132.74) v7(157.58,129.82) v7(157.56,125.65) v7(157.51,116.39) v7(157.55,111.9) v7(157.6,108.23) v7(157.81,111.26) v7(157.91,143.86) v7(158.05,139.53) v7(158.04,122.58) v7(158.09,149.91) v7(158.12,132.89) v7(158.09,115.9) v7(158.14,107.69) v7(158.31,130.02) v7(158.29,125.48) v7(158.32,111.01) v7(158.62,144.29) v7(158.63,140.02) v7(158.68,115.41) v7(158.66,107.14) v7(158.78,150.6) v7(158.78,122.35) v7(158.82,110.63) v7(158.95,125.32) v7(159.05,133.12) v7(159.05,130.23) v7(159.18,144.87) v7(159.21,140.51) v7(159.26,114.92) v7(159.19,106.59) v7(159.3,110.36) v7(159.46,151.28) v7(159.56,122.07) v7(159.62,145.49) v7(159.61,125.07) v7(159.69,110.1) v7(159.72,133.43) v7(159.78,130.45) v7(159.72,106.04) v7(159.8,141) v7(159.97,114.95) v7(160.17,145.53) v7(160.22,152.04) v7(160.2,121.79) v7(160.25,105.49) v7(160.3,133.71) v7(160.32,110.1) v7(160.46,141.37) v7(160.48,114.82) v7(160.5,130.67) v7(160.55,124.84) v7(160.66,143.47) v7(160.77,145.36) v7(160.78,121.53) v7(160.77,112.1) v7(160.77,110.22) v7(160.78,104.94) v7(160.91,152.73) v7(160.98,114.57) v7(161.02,143.51) v7(161.03,111.67) v7(161.09,145.04) v7(161.15,144.04) v7(161.09,110.55) v7(161.23,145.65) v7(161.21,144.59) v7(161.22,141.44) v7(161.19,134.09) v7(161.23,130.91) v7(161.21,124.61) v7(161.27,112.1) v7(161.21,111.37) v7(161.21,110.99) v7(161.23,109.93) v7(161.34,121.2) v7(161.31,104.39) v7(161.57,153.37) v7(161.53,143.49) v7(161.53,114.49) v7(161.65,114.1) v7(161.65,112.07) v7(161.83,103.84) v7(161.95,134.42) v7(161.98,131.05) v7(162.05,144.22) v7(162.04,143.26) v7(162.04,141.72) v7(162,124.56) v7(162.04,113.87) v7(162.04,112.33) v7(162.05,111.36) v7(162.15,153.97) v7(162.1,120.8) v7(162.36,142.93) v7(162.35,142.49) v7(162.36,142.04) v7(162.36,112.65) v7(162.36,103.29) v7(162.39,113.59) v7(162.48,113.1) v7(162.64,134.75) v7(162.74,131.05) v7(162.88,142.79) v7(162.79,124.54) v7(162.88,112.79) v7(162.87,102.79) v7(162.97,154.69) v7(162.92,120.41) v7(163.4,135.14) v7(163.44,102.29) v7(163.5,131.01) v7(163.63,124.64) v7(163.7,155.4) v7(163.73,120.29) v7(163.92,147.06) v7(163.92,108.52) v7(163.98,101.74) v7(164.14,135.37) v7(164.29,130.82) v7(164.21,124.64) v7(164.25,122.41) v7(164.27,120.22) v7(164.41,133.24) v7(164.51,101.19) v7(164.61,155.37) v7(164.59,135.38) v7(164.69,145.74) v7(164.72,120.26) v7(164.69,109.84) v7(164.84,131.11) v7(164.84,124.35) v7(164.89,133.56) v7(164.97,133.07) v7(164.97,122.51) v7(164.89,122.02) v7(165.03,100.64) v7(165.1,135.06) v7(165.13,133.93) v7(165.1,120.52) v7(165.26,131.31) v7(165.27,124.2) v7(165.26,121.52) v7(165.37,155.37) v7(165.3,134.52) v7(165.37,132.81) v7(165.3,121.06) v7(165.4,147.91) v7(165.45,144.42) v7(165.45,111.16) v7(165.4,107.67) v7(165.53,131.68) v7(165.5,122.9) v7(165.56,100.09) v7(165.67,135.12) v7(165.65,123.77) v7(165.67,120.46) v7(165.69,132.27) v7(165.69,123.32) v7(165.95,133.5) v7(165.95,122.09) v7(166.13,155.37) v7(166.09,99.55) v7(166.24,131.87) v7(166.24,123.71) v7(166.62,99) v7(166.9,155.37) v7(166.92,145.27) v7(166.92,110.31) v7(167.16,148.93) v7(167.16,106.66) v7(167.41,98.98) v7(167.59,155.33) v7(167.92,147.61) v7(167.92,107.98) v7(168.22,98.96) v7(168.29,155.37) v7(168.68,146.29) v7(168.69,135.53) v7(168.68,109.3) v7(168.95,134.03) v7(169.05,155.37) v7(169.22,132.52) v7(169.19,98.96) v7(169.82,155.37) v7(169.8,151.33) v7(170.24,150.56) v7(170.21,98.96) v7(170.36,135.82) v7(170.58,155.37) v7(170.5,103.58) v7(170.69,149.79) v7(170.6,149.3) v7(170.73,106.5) v7(170.84,103.38) v7(170.89,132.82) v7(171.16,103.2) v7(171.17,98.96) v7(171.26,149.68) v7(171.19,106.67) v7(171.34,155.37) v7(171.39,106.12) v7(171.5,103) v7(171.64,107.44) v7(171.76,149.8) v7(171.71,105.75) v7(171.82,102.82) v7(172.07,149.99) v7(172.08,108.21) v7(172.03,105.57) v7(172.06,98.96) v7(172.1,155.37) v7(172.16,102.62) v7(172.36,136.17) v7(172.37,105.37) v7(172.42,150.18) v7(172.48,102.44) v7(172.63,134.67) v7(172.73,150.37) v7(172.69,105.19) v7(172.72,99.06) v7(172.86,155.37) v7(172.82,102.24) v7(172.89,133.17) v7(173.08,150.56) v7(173.04,147.67) v7(173.03,104.99) v7(173.08,99.6) v7(173.15,102.06) v7(173.2,154.82) v7(173.35,147.85) v7(173.35,104.81) v7(173.39,150.76) v7(173.46,101.88) v7(173.47,100.25) v7(173.61,154.19) v7(173.74,150.95) v7(173.69,148.05) v7(173.69,104.61) v7(173.76,101.7) v7(174.03,153.48) v7(174.05,151.14) v7(174.01,148.24) v7(174.02,104.43) v7(174.35,148.44) v7(174.35,104.23) v7(174.4,152.82) v7(174.4,151.33) v7(174.67,148.62) v7(174.68,104.05) v7(174.71,151.52) v7(175.02,151.67) v7(175.01,148.82) v7(175.03,103.84) v7(175.33,149) v7(175.67,149.2) v7(175.66,137.53) v7(175.73,135.35) v7(175.82,136.65) v7(175.97,135.78) v7(175.96,104.9) v7(175.99,149.39) v7(176.32,149.56) v7(176.33,105.56) v7(176.48,135.48) v7(176.5,117.63) v7(176.69,106.24) v7(176.86,117.56) v7(176.97,148.32) v7(177.01,135.44) v7(177.04,120.11) v7(177.04,106.91) v7(177.25,117.5) v7(177.38,107.6) v7(177.42,147.75) v7(177.4,135.52) v7(177.44,132.94) v7(177.41,120.04) v7(177.61,117.42) v7(177.73,147.06) v7(177.76,135.58) v7(177.71,108.28) v7(177.8,132.99) v7(177.79,119.98) v7(178.03,146.36) v7(178,117.37) v7(178.02,108.98) v7(178.15,135.65) v7(178.19,133.07) v7(178.16,119.91) v7(178.32,145.65) v7(178.36,117.29) v7(178.32,109.68) v7(178.51,135.71) v7(178.55,133.12) v7(178.54,119.85) v7(178.59,144.94) v7(178.61,110.39) v7(178.75,117.24) v7(178.85,144.22) v7(178.9,135.79) v7(178.94,133.21) v7(178.91,119.78) v7(178.89,111.1) v7(179.1,143.5) v7(179.11,117.16) v7(179.15,111.81) v7(179.26,135.84) v7(179.34,142.78) v7(179.3,133.26) v7(179.29,119.72) v7(179.4,112.53) v7(179.56,142.05) v7(179.5,117.11) v7(179.65,135.92) v7(179.69,133.34) v7(179.67,119.65) v7(179.64,113.38) v7(179.77,141.32) v7(179.86,117.03) v7(179.86,114.11) v7(179.97,140.58) v7(180.01,135.98) v7(180.05,133.39) v7(180.04,119.59) v7(180,116.3) v7(180.07,114.84) v7(180.16,139.84) v7(180.25,137) v7(180.25,116.94) v7(180.27,115.58) v7(180.33,139.1) v7(180.38,136.49) v7(180.4,136.05) v7(180.43,133.45) v7(180.42,119.52) v7(180.49,138.35) v7(180.5,119.98) v7(180.63,137.61) v7(180.76,136.11) v7(180.76,120.62) v7(180.8,133.52) v7(180.88,133.06) v7(180.79,119.46) v7(181.01,132.68) v7(181.11,133.58) v7(181.25,121.1) v7(181.39,121.98) v7(181.49,132.15) v7(181.51,122.71) v7(181.59,131.52) v7(181.67,130.89) v7(181.73,130.26) v7(181.76,124.26) v7(181.71,123.52) v7(181.81,129.52) v7(181.84,128.78) v7(181.84,128.12) v7(181.84,127.48) v7(181.86,126.9) v7(181.84,126.14) v7(181.81,125.45) v7(181.79,124.79)
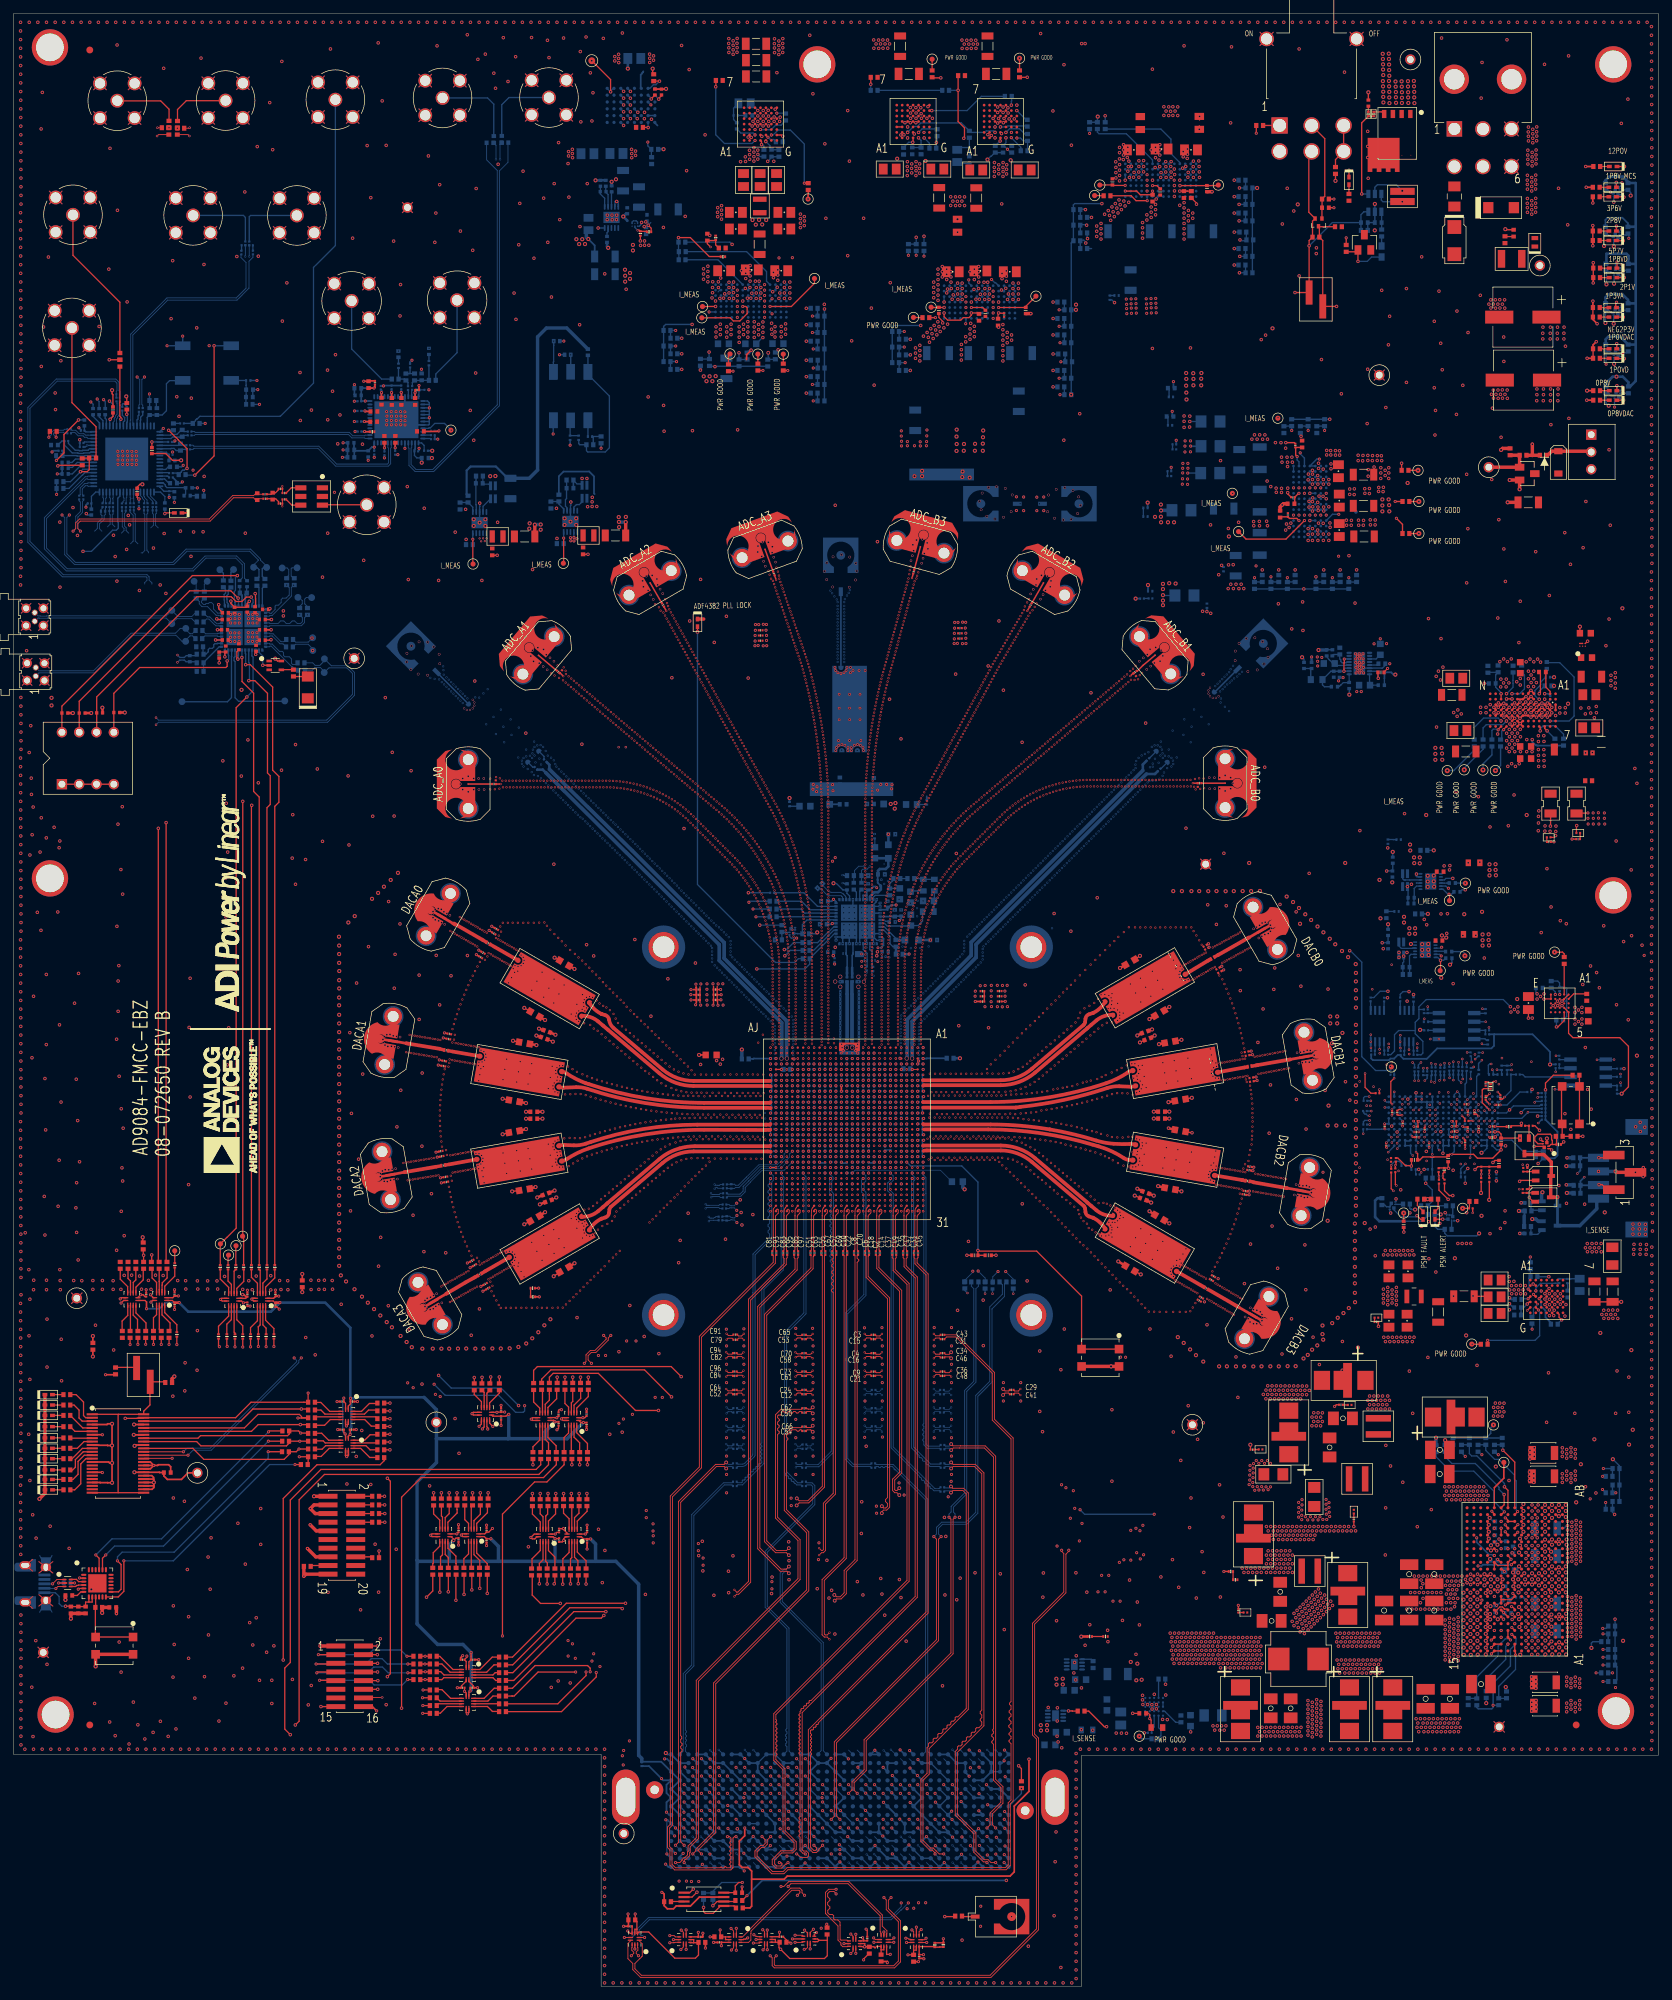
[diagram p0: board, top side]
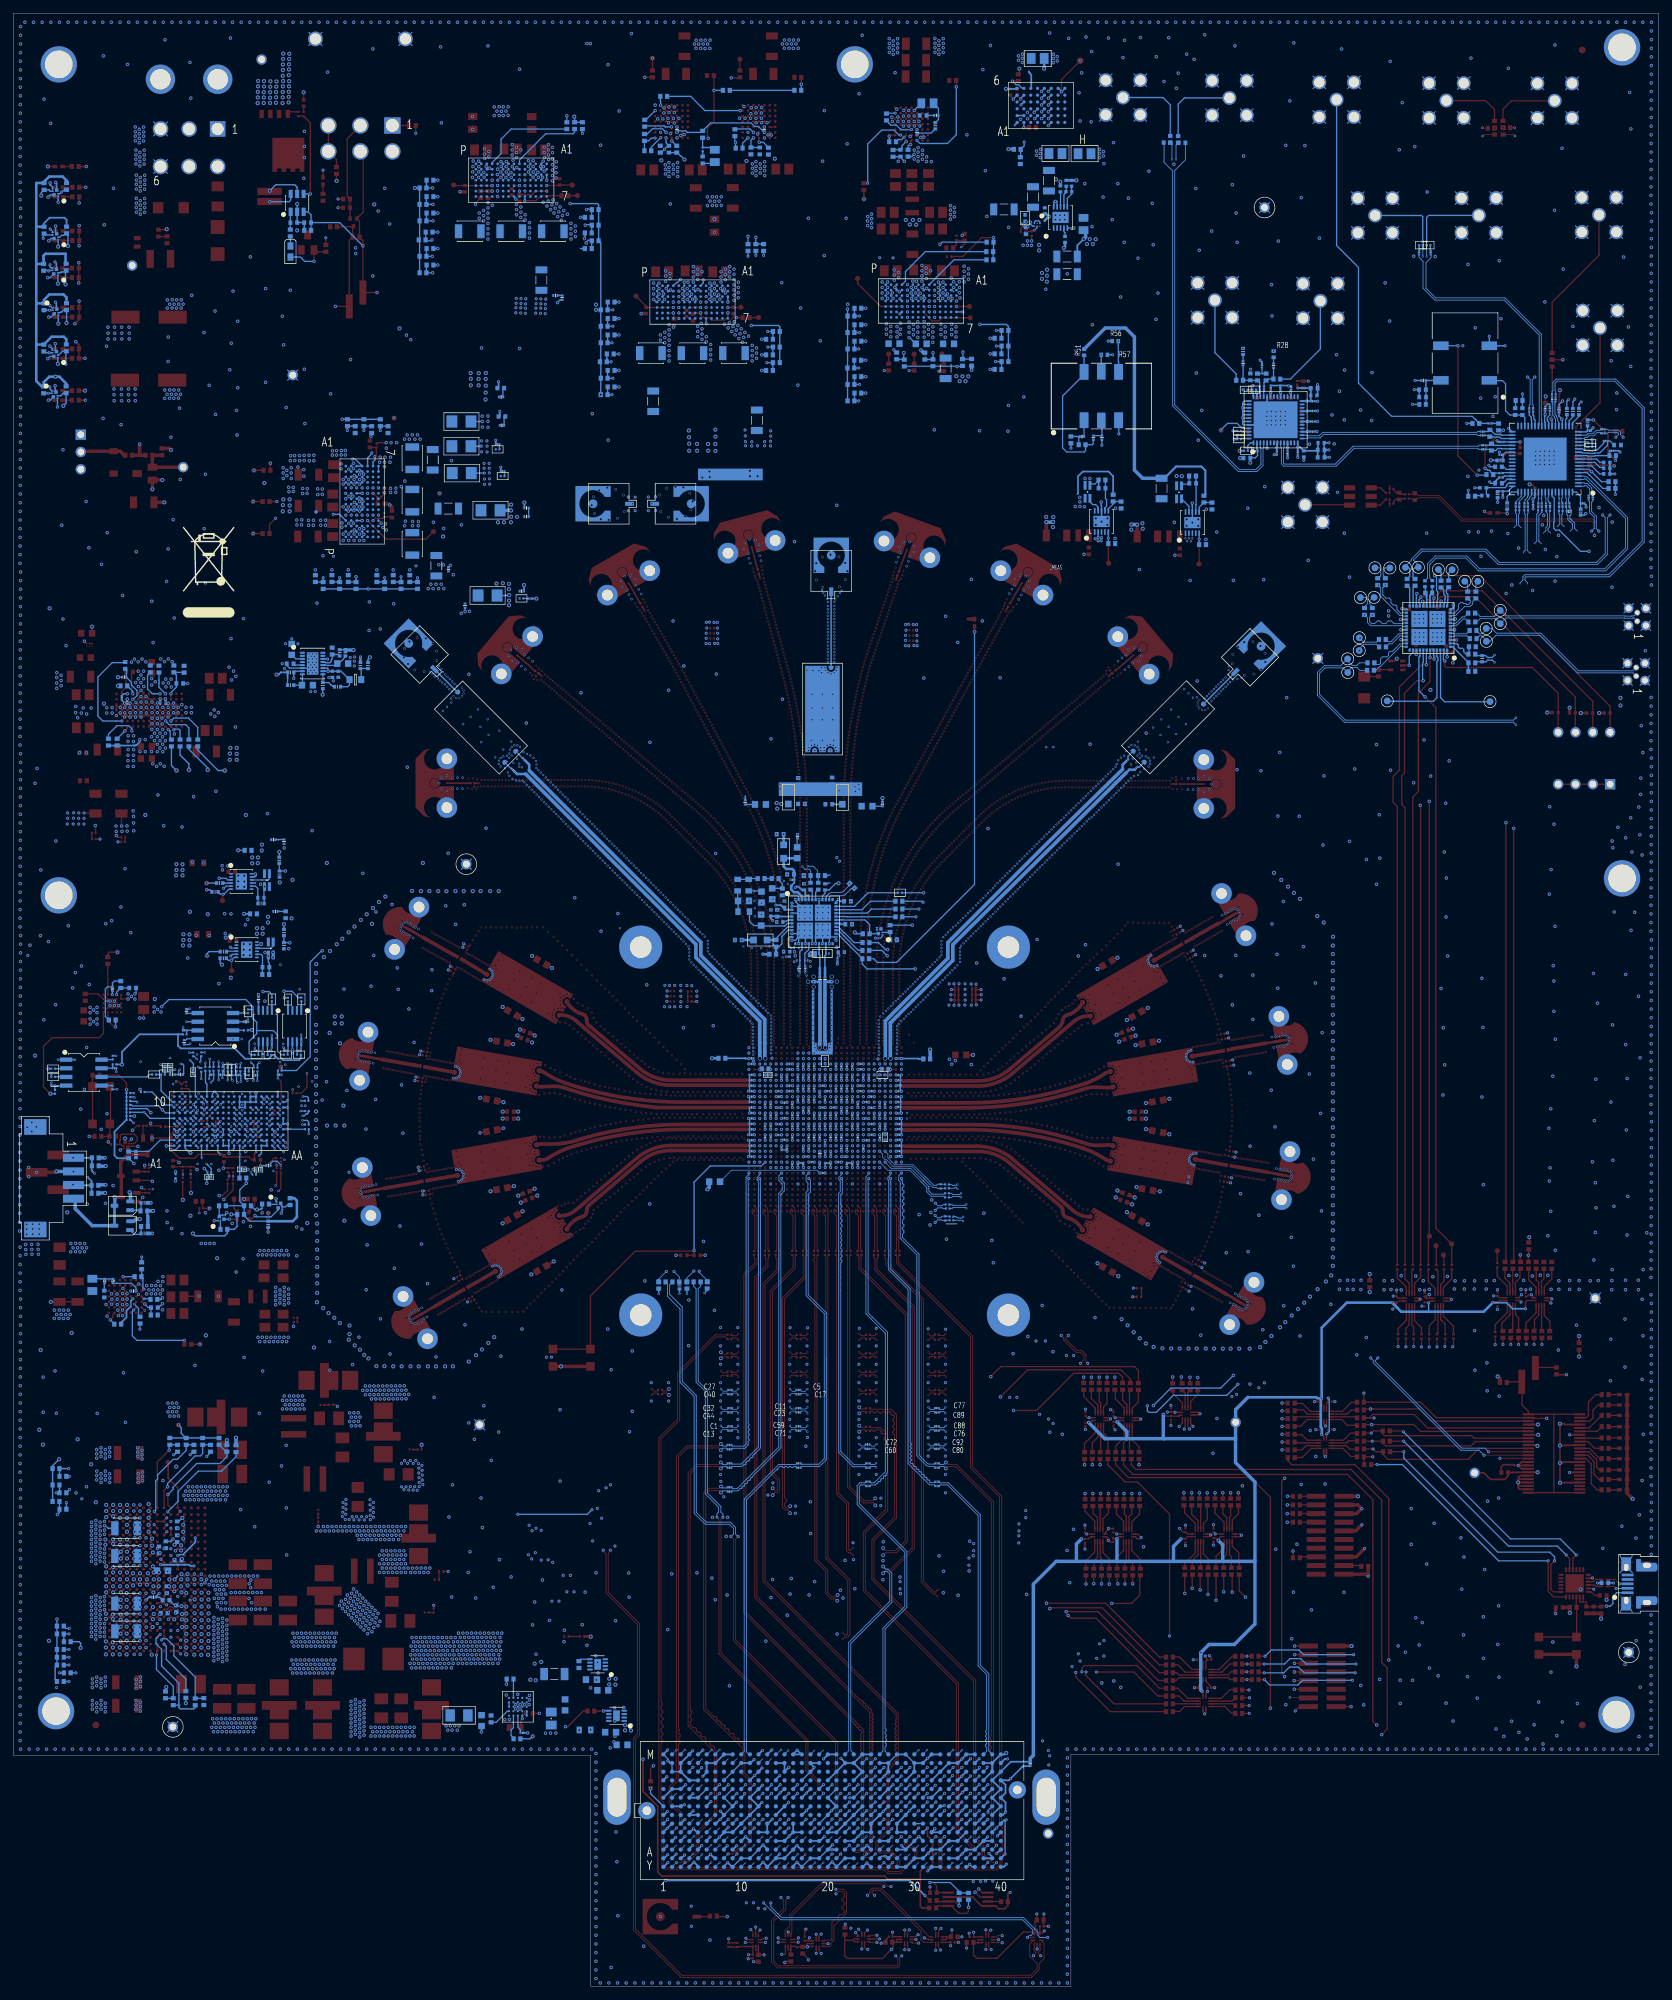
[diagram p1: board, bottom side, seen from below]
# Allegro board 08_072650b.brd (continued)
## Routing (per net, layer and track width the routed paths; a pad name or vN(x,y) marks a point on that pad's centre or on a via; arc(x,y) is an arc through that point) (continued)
VDDA_1P8_DAC_EN: length 142.8
  L3_SIGNAL w0.203: v3(207.34,171.86) 207.34,172.92 195.78,184.48 195.78,189.23 v3(196.06,189.51) 196.22,189.66 196.22,198.02 200.61,202.41 200.61,215.34 199.97,215.98 v4(194.51,215.98) ; v2(223.8,126.67) 227.69,126.67 229.36,128.35 229.36,137.21 232.3,140.15 232.3,146.7 229.21,149.78 225.15,149.78 222.1,152.83 v3(222.1,171.86)
  L5_MIXED w0.203: v2(215.06,126.97) 215.22,127.13 215.24,127.13 215.57,127.45 215.57,127.48 215.73,127.64 221.59,127.64 222.55,126.67 v2(223.8,126.67)
  L24_SIGNAL w0.203: v3(222.1,171.86) v3(207.34,171.86)
  BOTTOM w0.203: v3(196.06,189.51) 196.06,190.38 R418.1 ; R154.1 224.28,127.15 v2(223.8,126.67) ; U11.D6 215.44,127.35 v2(215.06,126.97) ; v4(194.51,215.98) 193.59,215.98 U8.L1
VDDA_1P8_DAC_IMON: length 111.1
  TOP w0.203: v4(189.47,215.06) 186.76,212.34 180.9,212.34 TP10.1
  L5_MIXED w0.203: v2(199.03,127.05) 200.1,127.05 200.74,127.69 200.74,129.95 199.14,131.55 199.14,136.5 199.72,137.08 199.72,144.91 198.63,146 198.63,152.65 192.58,158.7 192.58,189.97 188.01,194.54 188.01,195.68 184.68,199.01 184.68,204.39 186.08,205.79 186.08,207.11 187.53,208.56 187.53,212.73 189.47,214.67 v4(189.47,215.06)
  BOTTOM w0.203: v2(199.03,127.05) 198.33,127.05 198.13,126.85 R663.1
VDDA_1P8_DAC_REF: length 112.7
  TOP w0.203: C320.2 186.01,215.6 C709.1 187.28,215.37 188.35,215.37 v4(188.67,215.06)
  L3_SIGNAL w0.203: v4(188.67,215.06) 188.67,213.87 186.82,212.01 181.99,212.01 180.37,210.39 180.37,206.93 181.94,205.36 185.47,205.36 193.98,196.85 193.98,181.86 200.91,174.93 201.93,174.93 204.33,172.53 204.36,172.53 206.1,170.79 209.75,170.79 213.79,166.75 213.79,165.23 213.98,165.04 213.98,164.65 213.79,164.46 213.79,156.64 210.13,152.98 210.13,141.86 215.52,136.47 v2(215.52,135.89)
  BOTTOM w0.203: v2(215.52,135.89) 215.04,135.41 215.04,134.48 R502.2
VDDA_1P8_EN: length 120.2
  L3_SIGNAL w0.203: v4(192.67,219.06) 193.48,219.06 194.89,220.47 202.92,220.47 204.63,218.76 204.63,207.93 203.58,206.88 203.58,198.78 204.63,197.73 204.63,177.16 209.09,172.69 209.65,172.69 214.63,167.72 214.63,159.79 217.63,156.79 217.63,140.56 219.46,138.73 219.46,129.77 218.19,128.5 v2(217.4,128.5)
  L24_SIGNAL w0.203: v2(223.27,129.69) 223.01,129.44 219.53,129.44 218.59,128.5 v2(217.4,128.5)
  BOTTOM w0.203: U11.B7 217.05,128.15 v2(217.4,128.5) ; v2(223.27,129.69) 223.42,129.85 224.24,129.85 R153.1
VDDA_1P8_IMON: length 116.2
  L3_SIGNAL w0.203: v4(178.94,219.05) 181.13,216.87 187.83,216.87 189.47,218.5 v4(189.47,219.06)
  L5_MIXED w0.203: v2(198.1,125.1) 197.64,125.56 197.64,130.23 198.32,130.91 198.32,133.2 197.79,133.73 197.79,152.15 186.95,162.98 186.95,194.4 183.77,197.59 183.77,207.51 185.98,209.73 185.98,215.57 v4(189.47,219.06)
  BOTTOM w0.203: v2(198.1,125.1) R662.1
VDDA_1P8_REF: length 126.6
  TOP w0.203: C606.2 188.05,217.57 C711.1 188.62,219.06 v4(188.67,219.06)
  L3_SIGNAL w0.203: v2(201.55,135.23) 201.55,137.31 201.19,137.67 201.19,144.02 200.94,144.27 200.94,150.7 201.6,151.36 201.6,153.9 188.95,166.55 188.95,188.75 184.98,192.72 184.98,197.55 180.26,202.26 177.88,202.26 174.83,205.31 174.83,216.89 177.88,219.94 181.2,219.94 182.65,218.49 188.11,218.49 v4(188.67,219.06)
  L24_SIGNAL w0.203: v2(213.28,135.51) 211.68,133.91 201.98,133.91 201.45,134.44 201.45,135.13 v2(201.55,135.23)
  BOTTOM w0.203: R501.2 v2(213.28,135.51)
VDDD_0P8:
  vias: v1(169.77,51.83) v1(169.9,50.56) v1(169.95,49.29) v1(170.03,51.19) v1(170.08,48.02) v1(170.15,49.92) v1(170.21,48.65) v1(170.33,47.38) v1(170.41,51.83) v1(170.54,50.56) v1(170.59,49.29) v1(170.71,48.02) v1(170.79,51.19) v1(170.92,49.92) v1(170.97,48.65) v1(171.04,51.83) v1(171.17,50.56) v1(171.09,47.38) v1(171.22,49.29) v1(171.35,48.02) v1(171.42,51.19) v1(171.55,49.92) v1(171.68,51.83) v1(171.6,48.65) v1(171.73,47.38) v1(171.81,50.56) v1(171.86,49.29) v1(171.98,48.02) v1(172.06,51.19) v1(172.19,49.92) v1(172.24,48.65) v1(172.31,51.83) v1(172.36,47.38) v1(172.44,50.56) v1(172.49,49.29) v1(172.62,48.02) v1(172.69,51.19) v1(172.82,49.92) v1(172.87,48.65) v1(172.95,51.83) v1(173.08,50.56) v1(173,47.38) v1(173.13,49.29) v1(173.25,48.02) v1(173.33,51.19) v1(173.46,49.92) v1(173.58,51.83) v1(173.51,48.65) v1(173.63,47.38) v1(173.71,50.56) v1(173.76,49.29) v1(173.96,51.19) v1(173.89,48.02) v1(174.09,49.92) v1(174.14,48.65) v1(174.22,51.83) v1(174.27,47.38) v1(174.35,50.56) v1(174.4,49.29) v1(174.52,48.02) v1(174.6,51.19) v1(174.73,49.92) v1(174.78,48.65) v1(174.85,51.83) v1(174.98,50.56) v1(174.9,47.38) v1(175.03,49.29) v1(175.16,48.02) v1(175.23,51.19) v1(175.36,49.92) v1(175.41,48.65) v1(175.49,51.83) v1(175.54,47.38) v1(175.62,50.56) v1(175.67,49.29) v1(175.87,51.19) v1(175.79,48.02) v1(176,49.92) v1(176.05,48.65) v1(176.12,51.83) v1(176.17,47.38) v1(176.25,50.56) v1(176.3,49.29) v1(176.43,48.02) v1(176.61,51.18) v1(176.73,49.91) v1(176.78,48.64) v1(176.86,50.55) v1(176.91,47.37) v1(176.99,49.28) v1(177.04,48.01) v1(177.16,46.74) v1(177.24,51.18) v1(177.37,49.91) v1(177.42,48.64) v1(177.55,47.37) v1(177.62,50.55) v1(177.75,49.28) v1(177.88,51.18) v1(177.8,48.01) v1(177.93,46.74) v1(178,49.91) v1(178.05,48.64) v1(178.18,47.37) v1(178.26,50.55) v1(178.38,49.28) v1(178.44,48.01) v1(178.51,51.18) v1(178.56,46.74) v1(178.64,49.91) v1(178.69,48.64) v1(178.82,47.37) v1(178.89,50.55) v1(179.02,49.28) v1(179.07,48.01) v1(179.15,51.18) v1(179.27,49.91) v1(179.2,46.74) v1(179.32,48.64) v1(179.45,47.37) v1(179.53,50.55) v1(179.65,49.28) v1(179.78,51.18) v1(179.71,48.01) v1(179.83,46.74) v1(179.91,49.91) v1(179.96,48.64) v1(180.16,50.55) v1(180.09,47.37) v1(180.29,49.28) v1(180.34,48.01) v1(180.42,51.18) v1(180.47,46.74) v1(180.54,49.91) v1(180.59,48.64) v1(180.72,47.37) v1(180.8,50.55) v1(180.92,49.28) v1(180.97,48.01) v1(181.05,51.18) v1(181.18,49.91) v1(181.1,46.74) v1(181.23,48.64) v1(181.36,47.37) v1(181.43,50.55) v1(181.56,49.28) v1(181.61,48.01) v1(181.69,51.18) v1(181.74,46.74) v1(181.81,49.91) v1(181.86,48.64) v1(182.07,50.55) v1(181.99,47.37) v1(182.19,49.28) v1(182.25,48.01) v1(182.32,51.18) v1(182.37,46.74) v1(182.45,49.91) v1(182.5,48.64) v1(182.63,47.37) v1(182.7,50.55) v1(182.83,49.28) v1(182.88,48.01) v1(182.96,51.18) v1(183.08,49.91) v1(183.01,46.74) v1(183.13,48.64) v1(183.26,47.37) v4(119.1,123.33) v4(119.1,121.73) v4(119.9,127.33) v4(119.9,125.73) v4(119.9,124.13) v4(119.9,123.33) v4(120.7,127.33) v4(120.7,125.73) v4(120.7,124.13) v4(121.5,127.33) v4(121.5,125.73) v4(121.5,124.13) v4(122.3,127.33) v4(122.3,125.73) v4(123.1,127.33) v4(123.1,125.73) v4(123.1,124.13) v4(123.9,127.33) v4(123.9,125.73) v4(123.9,124.13) v4(124.7,127.33) v4(124.7,125.73) v4(124.7,124.13) v4(124.7,123.33) v4(125.5,123.33) v4(125.5,121.73)
VDDD_1P0:
  vias: v1(198.78,85.98) v1(198.78,84.71) v1(199.03,86.61) v1(199.03,85.34) v1(199.42,85.98) v1(199.42,84.71) v1(199.67,86.61) v1(199.67,85.34) v1(200.05,85.98) v1(200.05,84.71) v1(200.3,86.61) v1(200.3,85.34) v1(200.69,85.98) v1(200.69,84.71) v1(200.94,86.61) v1(200.94,85.34) v1(201.32,85.98) v1(201.32,84.71) v1(201.57,85.34) v1(201.7,86.61) v1(201.96,85.98) v1(201.96,84.71) v4(116.7,123.33) v4(121.5,121.73) v4(122.3,121.73) v4(127.9,123.33)
VDDD_1P0_ADC:
  vias: v1(180.34,61.37) v1(180.59,60.73) v1(180.97,61.37) v1(181.23,60.73) v1(181.61,61.37) v1(181.86,60.73) v1(182.25,61.37) v1(182.5,60.73) v1(182.88,61.37) v1(183.13,60.73) v1(183.52,61.37) v1(183.9,63.27) v1(183.9,62) v1(183.9,60.73) v1(184.15,63.91) v1(184.15,62.64) v1(184.15,61.37) v1(184.53,63.27) v1(184.53,62) v1(184.53,60.73) v1(184.78,63.91) v1(184.78,62.64) v1(184.78,61.37) v1(185.17,63.27) v1(185.17,62) v1(185.17,60.73) v1(185.42,63.91) v1(185.42,62.64) v1(185.42,61.37) v1(185.8,63.27) v1(185.8,62) v1(185.8,60.73) v1(186.06,63.91) v1(186.06,62.64) v1(186.06,61.37) v1(186.44,63.27) v1(186.44,62) v1(186.44,60.73) v1(186.69,63.91) v1(186.69,62.64) v1(186.69,61.37) v1(187.07,63.27) v1(187.07,62) v1(187.07,60.73) v1(187.32,63.91) v1(187.32,62.64) v1(187.32,61.37) v1(187.71,63.27) v1(187.71,62) v1(187.71,60.73) v4(119.1,128.93) v4(119.9,128.93) v4(124.7,128.93) v4(125.5,128.93)
VDDD_1P8: length 176.1
  TOP w0.198: R326.1 v1(144.2,107.26)
  TOP w0.381: v3(156.72,51.31) 156.74,51.33 R556.2
  L5_MIXED w0.178: 163.32,43.48 161.04,41.2 154.41,41.2
  L5_MIXED w0.191: v3(198.32,111.99) 200.43,114.1 200.43,123.93 202.16,125.66 202.51,125.66 202.84,125.98 202.84,126.18 203.05,126.39 203.05,129.87 201.68,131.24 201.68,133.4 202.84,134.57 202.84,135.53 202.77,135.61 v2(202.31,135.61)
  L5_MIXED w0.203: v3(211.56,106.83) 212.47,105.92 212.47,97.94 212.01,97.49 212.01,85.37 205,78.36 205,63.96 201.85,60.81 201.85,45.19 200.74,44.07 169.62,44.07 169.04,43.48 163.32,43.48 ; 154.41,41.2 151.82,38.61 151.82,38.46 v3(151.69,38.33)
  L24_SIGNAL w0.178: v2(202.31,135.61) 203,136.3 205.94,136.3 206.67,137.02 v2(213.35,137.02)
  L24_SIGNAL w0.203: v3(211.56,106.83) 208.86,109.52 203.73,109.52 201.27,111.99 v3(198.32,111.99)
  BOTTOM w0.127: C453.1 122.3,124.04
  BOTTOM w0.178: R138.1 v2(213.35,137.02)
  BOTTOM w0.254: 122.3,124.04 v4(122.3,124.13)
  vias: v3(150.77,38.33) v3(150.8,37.54) v3(151.69,37.57) v4(115.9,123.33) v4(123.1,121.73) v4(128.7,123.33)
VDDD_1P8_EN: length 243.9
  TOP w0.203: R534.1 157.82,40.39 160.1,38.1 v1(160.43,38.1)
  L3_SIGNAL w0.203: v2(223.7,130.41) 225.96,130.41 227.2,131.65 227.2,137.39 231.14,141.33 231.14,144.68 229.03,146.79 224.33,146.79 220.85,150.27 220.85,174.24 228.23,181.62 228.23,188 228.12,188.11 228.12,188.19 v3(228.17,188.19) ; v1(160.43,38.1) 175.01,38.1 183.17,46.27 183.2,46.27 183.48,46.54 183.48,46.57 185.37,48.46 185.37,51.49 182.55,54.31 173.28,54.31 171.65,55.93 171.65,65.07 179.22,72.64 179.22,75.58 190.26,86.61 190.26,86.65 v3(197.33,93.73) ; v3(213.21,95.5) 217.5,99.8 217.5,111.58 220.22,114.3 220.22,125.12 217.53,127.81 216.56,127.81 v2(215.9,128.47)
  L24_SIGNAL w0.203: v2(223.7,130.41) 223.52,130.23 220.88,130.23 219.38,131.72 216.57,131.72 215.9,131.05 v2(215.9,128.47) ; v1(224.74,188.85) 227.38,188.85 228.12,188.11 228.12,188.19 v3(228.17,188.19) ; v3(197.33,93.73) 197.49,93.88 211.58,93.88 v3(213.21,95.5)
  BOTTOM w0.203: R152.1 223.77,130.48 v2(223.7,130.41) ; U11.C7 216.22,128.15 v2(215.9,128.47)
VDDD_1P8_GP: length 46.1
  TOP w0.191: C679.2 48.48,81.23 v4(48.66,81.05) 48.73,80.99 U26.2 ; U28.2 v4(79.5,66.36) 79.75,66.61 C680.2 ; U43.2 v4(83.57,83.43) 83.84,83.43 C273.2 ; C684.2 v4(65.06,66.39) U42.2 ; v4(48.46,86.31) C266.2 48.72,85.54 U25.2 ; U41.2 v4(70.94,84.22) 70.98,84.26 C637.2 v4(72.08,84.26) ; C267.2 v4(83.92,66.36) U27.2 ; v4(9.49,58.27) 9.59,58.38 U22.5 ; U23.2 66.43,47.67 C265.2 66.52,48.29 v4(66.52,48.46) ; U44.2 78.75,83.45 79.43,83.45 79.45,83.43 v4(79.74,83.43) C685.2 ; v4(70.28,67.18) 69.75,66.65 C268.2 69.16,66.39 U29.2 ; v4(18.64,101.47) 18.25,101.08 U48.2 ; C678.2 v4(66.18,43.29) 66.43,43.04 U24.2
  TOP w0.198: C274.2 38.17,100.96 U45.2 ; C275.2 23.36,101.04 U47.2
  TOP w0.203: U46.2 33.36,100.96 33.36,100.95 33.53,100.95 33.54,100.94 34.05,100.94 C688.2 ; v4(18.64,101.47) 19,101.47 19.27,101.2 C689.2
  TOP w0.254: C274.2 38.48,101.27 v4(38.91,101.27) ; R687.1 18.95,109.21 v3(18.95,109.91) ; v1(33.6,101.5) 33.79,101.5 34.09,101.2 C688.2 ; C275.2 v4(24.18,101.3)
  TOP w0.508: P3.1 v3(44.09,71.91) ; P2.1 v3(45.03,49.94) ; C144.1 R469.1 v3(13,54.8)
  L7_POWER w0.203: 17.98,102.11 17.98,108.76 ; v4(18.64,101.47) 18.62,101.47
  L7_POWER w0.254: v3(18.95,109.91) 17.98,108.94 17.98,108.76
  BOTTOM w0.203: v4(48.46,86.31) 48.31,86.16 48.31,81.4 v4(48.66,81.05)
  vias: v3(153.06,45.14) v3(153.09,44.27) v3(154,45.14) v3(154,44.3)
VDDD_1P8_I+: length 127.4
  L3_SIGNAL w0.191: v1(158.41,37.59) 158.59,37.77 158.59,39.19 158.5,39.27 158.5,44.81 167,53.31 167,66.37 169.42,68.78 169.42,72.37 182.46,85.42 182.46,88.33 183.78,89.65 191.05,89.65 198.73,97.33 198.73,107.8 200.99,110.06 200.99,119.95 200.47,120.47 200.47,124.28 201.82,125.64 201.82,126.4 202.9,127.49 202.9,130.84 203.48,131.41 203.48,132.65 204.97,134.15 209.48,134.15 v2(210.74,135.41)
  BOTTOM w0.191: R649.1 v2(210.74,135.41)
VDDD_1P8_I-: length 132.7
  L3_SIGNAL w0.254: v1(156.73,37.65) 156.73,36.62 157,36.35 158.98,36.35 159.46,36.83 159.46,38.91 159.18,39.19 159.18,44.65 167.72,53.19 167.72,65.38 170.21,67.87 170.21,72.56 182.89,85.24 182.89,88.15 183.96,89.22 191.22,89.22 199.15,97.15 199.15,107.41 201.42,109.68 201.42,120.12 200.89,120.65 200.89,124.1 203.33,126.54 203.33,130.66 203.9,131.24 203.9,132.48 205.15,133.72 209.66,133.72 211.33,135.39 v2(211.33,135.66)
  BOTTOM w0.191: R645.1 v2(211.33,135.66)
0P8V_PG: length 200.6
  L3_SIGNAL w0.203: v3(236.25,50.7) 236.25,51.13 236.27,51.16 236.27,93.5 236.63,93.85 236.63,102.36 235.38,103.61 235.38,114.55 236.27,115.44 236.27,127.1 237.26,128.09 237.26,141.4 237.48,141.61 237.48,150.41 231.5,156.39 231.5,163.47 236.14,168.12 236.14,174.52 235.05,175.62 235.05,188.85 233.76,190.14 233.76,193.42 234.57,194.23 234.57,197.69 233.65,198.6 233.65,218.16 235.69,220.19 235.69,233.53 235.89,233.73 v4(236.35,233.73)
  L24_SIGNAL w0.203: v3(236.25,50.7) 232.56,50.7 231.6,49.73 v3(231.6,49.66)
  BOTTOM w0.203: Q1.2 v4(236.35,233.73) 237.02,233.73 R331.1 ; R530.1 231.8,50.57 231.6,50.37 v3(231.6,49.66)
0P8V_PG_LED: length 1.7
  TOP w0.191: DS6.C v1(235.34,234.84)
  BOTTOM w0.191: v1(235.34,234.84) 235.34,234.02 Q1.6
0P8VADC_PG: length 176
  L3_SIGNAL w0.203: v4(233.69,70.99) 233.69,73.03 234.44,73.79 234.44,75.91 233.74,76.61 233.74,92.75 231.88,94.61 231.88,100.41 234.59,103.12 234.59,115.34 233.95,115.99 233.95,134.05 236.32,136.42 236.32,149.78 230.17,155.93 230.17,163.93 235.31,169.06 235.31,174.02 234.29,175.03 234.29,188.57 232.8,190.06 232.8,218.6 234.92,220.73 234.92,230.3 234.14,231.09 v3(234.14,231.9)
  BOTTOM w0.203: R531.1 v4(233.69,70.99) ; Q1.5 234.5,233.37 234.11,233.75 R333.1 233.72,232.32 v3(234.14,231.9)
0P8VADC_PG_LED: length 1.9
  TOP w0.191: DS7.C v1(236.32,232.72)
  BOTTOM w0.191: Q1.3 236.08,232.72 v1(236.32,232.72)
1P0VD: length 4
  BOTTOM w0.191: 216.57,63.34 216.99,63.34 217.12,63.22
  BOTTOM w0.254: 216.57,63.34 214.76,65.16 v4(214.76,65.81) ; 217.12,63.22 v4(217.35,63.22)
1P0VD_PG: length 180.4
  L3_SIGNAL w0.203: v4(233.76,238) 232.03,236.27 232.03,229.97 233.4,228.6 233.4,220.7 231.67,218.97 231.67,190.3 233.73,188.24 233.73,174.68 234.34,174.07 234.34,169.98 229.21,164.85 229.21,154.94 234.81,149.34 234.81,139.23 232.92,137.34 232.92,123.57 231.65,122.3 231.65,111.46 230.15,109.96 230.15,94.36 232.74,91.77 232.74,79.93 232.16,79.35 232.16,75.11 233.22,74.04 v4(233.22,72.9)
  BOTTOM w0.203: R532.1 233.69,72.43 v4(233.22,72.9) ; Q3.2 234.84,239.32 234.26,239.9 R338.1 233.76,239.83 v4(233.76,238)
1P0VD_PG_LED: length 2.2
  TOP w0.191: DS8.C 235.37,238.81 v1(236.42,238.81)
  BOTTOM w0.191: Q3.6 236.08,239.16 v1(236.42,238.81)
1P0VDAC: length 0.5
  BOTTOM w0.254: C438.1 118.3,128.04 v4(118.3,128.13) ; v4(118.3,125.73) 118.3,125.85 C441.1 ; 126.3,128.04 C445.1 126.33,128.11 v4(126.3,128.13) 126.3,128.04
  vias: v1(201.07,102.3) v1(201.07,101.54) v1(201.07,100.9) v1(201.07,100.27) v1(201.7,102.55) v1(201.7,101.92) v1(201.7,101.28) v1(201.7,100.65) v1(201.7,100.01) v1(202.34,102.17) v1(202.34,101.54) v1(202.34,100.9) v1(202.34,100.27) v1(202.97,102.55) v1(202.97,101.92) v1(202.97,101.28) v1(202.97,100.65) v1(202.97,100.01) v4(126.3,125.73)
1P0VDAC_PG: length 177.8
  TOP w0.203: TP18.1 214.06,94.21 v4(214.1,94.21) R522.2
  L3_SIGNAL w0.203: v4(236.22,239.68) 235.58,239.05 235.58,237.92 236.9,236.6 236.9,233.97 236.91,233.96 236.91,233.5 236.9,233.5 236.9,220.09 235.33,218.52 235.33,195.78 235.89,195.22 235.89,176.07 238.94,173.02 238.94,154.45 238.53,154.04 238.53,138.3 238.99,137.85 238.99,134.67 238.48,134.16 238.48,127.64 237.46,126.62 237.46,115.01 236.17,113.72 236.17,103.78 237.46,102.49 v3(237.46,93.35)
  L24_SIGNAL w0.203: v3(237.46,93.35) 214.78,93.35 214.1,94.03 v4(214.1,94.21)
  BOTTOM w0.203: R342.1 236.79,239.68 v4(236.22,239.68) Q3.5
1P0VDAC_PG_LED: length 2
  TOP w0.191: DS9.C v1(235.31,241)
  BOTTOM w0.191: v1(235.31,241) 235.31,240.01 Q3.3
1P0VDACDIG_I+: length 57.5
  TOP w0.191: v1(214.22,101.3) 214.27,101.24 R523.1 216.36,101.24 C609.2 ; 216.43,103.66 C529.2
  L3_SIGNAL w0.191: v2(208.08,135.42) 207.52,135.98 204.36,135.98 201.81,133.44 201.81,131.16 200.37,129.71 200.37,125.9 199.25,124.77 199.25,114.87 199.72,114.4 199.72,111.57 v1(199.88,111.4)
  L24_SIGNAL w0.191: v1(199.88,111.4) 199.88,111.08 199.16,110.36 199.16,105.73 199.74,105.16 206.32,105.16 209.65,101.83 213.69,101.83 v1(214.22,101.3)
  BOTTOM w0.191: R521.2 222.9,97.21 v4(222.9,96.42) ; v2(208.08,135.42) 208.15,135.35 R624.1
1P0VDACDIG_I-: length 66.8
  TOP w0.191: R523.2 211.63,101.49 ; R523.2 211.63,101 ; R523.2 v1(211.36,101.28) ; U1.F1 v2(222.17,99.16)
  L3_SIGNAL w0.191: v1(199.11,111.1) 199.33,111.32 199.33,114.23 198.86,114.71 198.86,124.94 199.96,126.04 199.96,129.86 201.42,131.32 201.42,133.6 204.2,136.37 207.78,136.37 208.71,135.44 v2(208.71,135.31)
  L24_SIGNAL w0.191: v1(211.36,101.28) 209.49,101.28 206.15,104.62 199.72,104.62 198.7,105.64 198.7,110.69 v1(199.11,111.1)
  L24_SIGNAL w0.198: v2(222.17,99.16) 221.79,98.78 215.65,98.78 213.15,101.28 v1(211.36,101.28)
  BOTTOM w0.191: R625.1 v2(208.71,135.31)
1P0VDACINTVCC: length 4.9
  TOP w0.254: U1.D3 223.93,100.91 v4(223.93,100.89)
  BOTTOM w0.203: 224.41,99.59 224.21,99.8 224.21,100.58 224.19,100.6 224.19,100.62 v4(223.93,100.89)
  BOTTOM w0.254: R520.1 225.65,97.38 224.85,98.17 224.85,99.15 224.41,99.59
1P3V_I-_ADC1PO: length 191.2
  L5_MIXED w0.191: v2(209.45,135.2) 209.45,136.17 212.14,138.86 212.14,149.95 211.41,150.68 211.41,158.01 211.82,158.42 211.82,172.78 211.86,172.82 211.86,173.02 213.94,175.11 213.94,195.12 214.73,195.91 214.73,237.06 210.01,241.78 184.25,241.78 v1(183.77,242.27)
  L24_SIGNAL w0.191: v1(183.77,242.27) 183.2,242.83 162.91,242.83 147.57,258.17 139.04,258.17 138.56,257.68 v1(138.56,257.37)
  BOTTOM w0.191: v2(209.45,135.2) 209.42,135.18 R669.1 ; v1(147.49,247.5) 147.11,247.12 U7.P4
  vias: v1(137.76,247.54) v1(137.93,248.17) v1(138.56,249.9) v1(138.56,249.1) v1(138.56,248.3) v1(138.61,247.5) v1(139.23,249.9) v1(139.24,249.1) v1(139.24,248.3) v1(139.24,247.5) v1(141.26,247.54) v1(141.76,247.54) v1(141.91,248.26) v1(142.44,250.02) v1(142.56,249.1) v1(142.56,248.3) v1(142.54,247.5) v1(142.98,250.02) v1(143.18,247.5) v1(143.24,249.1) v1(143.24,248.3) v1(145.89,247.5) v1(146.02,248.3) v1(146.69,249.9) v1(146.69,249.1) v1(146.69,248.3) v1(146.69,247.5) v1(147.49,249.9) v1(147.49,249.1) v1(147.49,248.3)
1P3V_I-_DAC1PO: length 0.5
  BOTTOM w0.191: v1(169.11,267.72) 168.8,267.4 U52.H1
  vias: v1(163.78,265.4) v1(164.47,266.14) v1(164.39,265.43) v1(165.18,267.84) v1(165.18,267) v1(165.15,266.19) v1(165.18,265.43) v1(165.86,267.87) v1(165.86,267) v1(165.86,266.22) v1(168.38,265.4) v1(168.43,266.12) v1(169.14,266.98) v1(169.11,266.19) v1(169.16,265.4) v1(169.85,267) v1(169.9,267.72) v1(169.9,266.19) v1(169.9,265.4)
1P3V_I-_SCLK: length 175.9
  TOP w0.191: v1(174.07,265.4) 174.23,265.4 ; v1(174.04,272.46) 174.04,272.97
  L5_MIXED w0.191: v1(187.91,260.48) 187.91,256.82 185.67,254.58 185.67,248.97 179.65,242.95 179.65,225.81 180.75,224.71 180.75,214.4 180.24,213.89 v1(178.31,213.89)
  L22_MIXED w0.114: v2(205.35,135.55) 205.71,135.91 206.93,135.91 211.66,140.64 211.66,146.51 211.48,146.69 211.13,146.69 210.36,147.46 210.36,150.09 210.82,150.55 210.82,154.75 210.55,155.02 209.33,155.02 208.21,156.14 208.21,158.45 206.45,160.21 206.45,161.2 202.34,165.31 201.75,165.31 198.17,168.88 198.17,172.53 196.24,174.47 196.24,183.66 193.82,186.08 190.01,186.08 185.32,190.77 185.32,196.16 174.7,206.78 ; 177.65,270.74 175.95,272.44 174.06,272.44 v1(174.04,272.46)
  L22_MIXED w0.191: 177.65,270.74 v1(187.91,260.48) ; 174.7,206.78 174.7,209.93 178.31,213.54 v1(178.31,213.89)
  BOTTOM w0.191: v1(173.18,267.79) 172.78,267.4 U52.N1 ; R656.1 205.64,135.25 v2(205.35,135.55)
  vias: v1(172.36,265.43) v1(172.42,266.14) v1(173.15,266.98) v1(173.15,266.22) v1(173.18,265.4) v1(173.96,267.82) v1(174.02,267) v1(174.04,266.22)
1P3VA_PG: length 123
  TOP w0.203: v1(147.65,282.91) TP2.1 R340.2
  L24_SIGNAL w0.203: v4(236.17,245.92) 236.31,246.06 236.34,246.06 236.66,246.39 236.66,246.42 238,247.75 238,263 237.24,263.76 237.24,269.6 231.75,275.08 199.75,275.08 196.42,278.41 152.15,278.41 v1(147.65,282.91)
  BOTTOM w0.203: R357.1 236.96,245.92 v4(236.17,245.92) Q5.2
1P3VA_PG_LED: length 2
  TOP w0.203: v4(235.29,247.1) 235.16,246.97 235.16,246.43 DS10.C
  BOTTOM w0.203: v4(235.29,247.1) 235.15,246.96 235.15,246.16 Q5.6
1P3VAINTVCC_A: length 4
  BOTTOM w0.191: v1(144.86,272.81) 145.79,272.81 145.94,272.96 148.69,272.96 R147.1
1P4V: length 370.9
  TOP w0.191: 174.08,273.82 v1(174.08,274.36)
  TOP w0.254: v1(174.08,274.36) R758.1
  L5_MIXED w0.191: v3(188.49,261.44) 188.49,256.59 186.31,254.41 186.31,248.69 180.21,242.6 180.21,226.06 181.15,225.12 181.15,214.12 180.39,213.36 179.02,213.36 v3(178.38,212.73)
  L5_MIXED w0.254: v3(184.78,243.26) 185.5,242.54 210.77,242.54 215.24,238.07 215.24,195.5 214.58,194.84 214.58,174.94 212.24,172.61 212.24,158.24 211.84,157.84 211.84,150.85 212.56,150.12 212.56,138.69 210.03,136.16 v2(210.03,135.46)
  L22_MIXED w0.191: 178.46,271.25 188.26,261.44 v3(188.49,261.44) ; v3(178.38,212.73) 175.16,209.5 175.16,206.91 185.83,196.24 185.83,190.98 190.22,186.59 194.03,186.59 196.75,183.87 196.75,174.68 198.6,172.82 198.6,168.95 201.79,165.76 202.39,165.76 206.8,161.34 206.8,160.35 208.56,158.6 208.56,156.29 209.47,155.37 210.69,155.37 211.17,154.89 211.17,150.28 211.35,150.11 211.35,149.79 212.04,149.1 212.04,140.28 207.31,135.56 v2(206.58,135.56)
  L22_MIXED w0.254: v1(174.08,274.36) 174.22,274.22 175.49,274.22 178.46,271.25
  L24_SIGNAL w0.191: v2(206.58,135.56) 206.58,135.59 206.98,135.99 209.5,135.99 v2(210.03,135.46)
  L24_SIGNAL w0.254: v3(138.56,259.27) 139.18,258.65 147.68,258.65 147.74,258.59 147.75,258.59 163.08,243.26 v3(184.78,243.26)
  BOTTOM w0.191: R655.1 206.2,135.18 v2(206.58,135.56)
  BOTTOM w0.254: v2(210.03,135.46) 210.03,134.79 R668.1
  vias: v1(137.55,262.56) v1(137.55,261.29) v1(137.87,261.93) v1(138.26,262.54) v1(138.26,261.27) v1(138.53,261.9) v1(138.87,262.56) v1(138.87,261.29) v1(139.19,261.93) v1(139.58,262.54) v1(139.58,261.27) v1(168.84,275.77) v1(168.84,274.5) v1(169.16,275.13) v1(169.55,275.75) v1(169.55,274.48) v1(169.82,275.11) v1(170.16,275.77) v1(170.16,274.5) v1(170.49,275.13) v1(170.87,275.75) v1(170.87,274.48) v1(198.83,222.53) v1(198.83,221.56) v1(199.69,222.91) v1(200.69,222.81) v1(200.69,222.05) v1(200.68,221.23) v1(201.32,222.43) v1(201.32,221.67) v1(201.85,222.81) v1(201.85,222.05) v1(201.85,221.23)
1P8V_MCS_PG: length 120.8
  L3_SIGNAL w0.203: v1(238.28,176.5) 239.52,177.75 239.52,260.58 v3(237.36,262.74)
  L24_SIGNAL w0.203: v3(212.93,178.49) 214.91,176.5 v1(238.28,176.5)
  BOTTOM w0.203: R387.2 215.7,181.51 212.93,178.74 v3(212.93,178.49) ; v3(237.36,262.74) 237.36,263.17 R360.1 236.3,263.58 236.27,263.6 236.05,263.38 Q6.5
1P8V_MCS_PG_LED: length 1.9
  TOP w0.191: v1(235.26,264.67) 235.27,264.65 DS15.C
  BOTTOM w0.191: v1(235.26,264.67) 235.1,264.51 Q6.3
1P8VD_PG: length 296.5
  L3_SIGNAL w0.203: v1(165.23,36.7) 165.58,36.7 166.17,36.12 237.36,36.12 238.89,37.64 238.89,102.18 236.88,104.19 236.88,113 239.8,115.93 239.8,125.76 239.9,125.86 239.9,126.25 239.8,126.35 239.8,173.61 236.8,176.61 236.8,198.42 237.97,199.59 237.97,249.99 v4(236.27,251.69)
  BOTTOM w0.203: Q4.5 236.17,251.77 236.25,251.69 v4(236.27,251.69) 236.35,251.77 236.97,251.77 R343.1 ; v1(165.23,36.7) 165.61,36.32 R537.2
1P8VD_PG_LED: length 2.1
  TOP w0.191: DS11.C 235.36,252.12 v4(235.36,253.01)
  BOTTOM w0.191: Q4.3 235.14,252.79 v4(235.36,253.01)
2P1V:
  vias: v3(200.91,218.16) v3(200.91,217.27) v3(200.91,216.41) v3(201.83,218.16) v3(201.9,217.32) v3(201.93,216.41) v3(208.69,181.71) v3(208.69,180.82) v3(208.69,179.96) v3(209.6,181.71) v3(209.68,180.87) v3(209.7,179.96)
2P1V_PG: length 93.2
  L3_SIGNAL w0.203: v3(233.81,249.71) 233.35,249.25 228.14,249.25 210.77,231.88 210.77,179.58 210.44,179.25 v3(210.44,178.38)
  BOTTOM w0.203: v3(233.81,249.71) 233.81,251.64 ; 233.81,251.64 233.91,251.54 234.43,251.54 234.35,251.46 234.57,251.46 234.62,251.41 Q4.2 ; 233.81,251.64 R339.1 ; R386.2 214.4,181.38 211.4,178.38 v3(210.44,178.38)
2P1V_PG_LED: length 2.2
  TOP w0.191: DS12.C v1(236.42,250.7)
  BOTTOM w0.191: v1(236.42,250.7) 236.07,250.7 Q4.6
2P1V_VOUT4_PG: length 108.1
  L3_SIGNAL w0.203: v4(237.08,256.46) 238.73,254.81 238.73,179.45 v1(237.97,178.69)
  L24_SIGNAL w0.203: v1(237.97,178.69) 236.73,177.44 216.74,177.44 v3(215.7,178.49)
  BOTTOM w0.203: Q2.5 236.76,256.96 R336.1 237.08,257.03 v4(237.08,256.46) ; v3(215.7,178.49) 215.7,179.37 216.99,180.67 R408.2
2P8V_PG_LED: length 1.9
  TOP w0.191: DS13.C v1(235.27,258.25)
  BOTTOM w0.191: Q2.3 235.27,257.29 v1(235.27,258.25)
3P6V_PG: length 136.2
  TOP w0.203: R63.2 116.64,262.86 116.61,262.84 v1(116.61,262.23)
  L24_SIGNAL w0.203: v1(116.61,262.23) 131.32,262.23 133.93,264.85 146.56,264.85 158.45,276.73 196.27,276.73 199.01,273.99 230.56,273.99 234.4,270.14 v4(234.4,263.26)
  BOTTOM w0.203: Q6.2 234.65,263.01 v4(234.4,263.26) 234.3,263.26 233.97,263.59 R358.1
3P6V_PG_LED: length 2.1
  TOP w0.203: v1(236.37,262.51) 236.32,262.56 DS5.C
  BOTTOM w0.203: v1(236.37,262.51) 236.03,262.85 Q6.6
3P6VAINTVCC: length 4.3
  BOTTOM w0.191: R60.1 112.99,273.44 112.99,273.39 112.66,273.07 111.85,273.07 111.21,272.43 111.07,272.43 111.04,272.4 109.78,272.4 109.75,272.43 v4(109.63,272.43)
3P8V: length 121
  L16_POWER w0.508: v3(109.42,259.16) 109.7,259.45 109.7,259.47 110.15,259.92 110.78,259.92 111.23,259.47 111.23,257.61 ; 111.23,257.61 110.77,257.61 v3(109.88,258.5) ; 111.23,257.61 124.31,244.53 124.31,228.02 138.76,213.56 156.26,213.56 170.79,199.03 185.1,199.03 v3(189.13,195)
  BOTTOM w0.191: v3(189.13,195) 189.41,194.72 R416.1
  BOTTOM w0.508: R361.1 97.36,260.91 97.36,261.32
  vias: v3(108.46,259.16) v3(108.94,258.47) v3(110.46,259.16)
5P7V_PG: length 98.9
  L3_SIGNAL w0.203: v3(233.45,255.35) 233.45,252.27 235.61,250.11 235.61,249.07 234.85,248.31 228.63,248.31 222.5,242.19 222.5,229.11 222.12,228.73 222.12,202.29 214.27,194.44 214.27,181.64 v3(217.53,178.38)
  BOTTOM w0.203: Q2.2 234.7,256.6 234.4,256.9 234.11,256.9 233.83,257.18 R332.1 233.45,256.98 v3(233.45,255.35) ; v3(217.53,178.38) 218.26,179.12 R388.2
5P7V_PG_LED: length 1.9
  TOP w0.191: v1(236.27,256.11) 235.31,256.11 DS4.C
  BOTTOM w0.191: Q2.6 235.94,256.44 v1(236.27,256.11)
5P88V: length 107.7
  TOP w0.508: v3(76.51,214.45) R516.1 ; R546.1 v3(89.84,214.83)
  BOTTOM w0.191: 226.32,135.25 R608.1
  BOTTOM w0.254: R332.2 233.65,259.18 233.96,259.49 236.14,259.49 236.96,258.67 R336.2 ; R606.1 217.32,139.67 ; 217.32,139.67 217.3,139.65 217.3,138 216.92,137.62 208.97,137.62 207.44,136.09 204,136.09 203.59,136.5 R707.1 203.17,136.65 202.64,136.12 202.1,136.12 201.87,135.89 199.53,135.89 199.27,136.14 R706.1 ; 217.32,139.67 222.96,139.67 225.53,137.11 v3(225.53,135.25) 226.32,135.25
  BOTTOM w0.381: 238.1,252.65 238.04,252.72 R343.2 237.02,253.43 237.06,253.47 237.06,253.9 236.75,254.2 233.81,254.2 233.81,252.82 R339.2 ; 238.1,252.65 238.1,258.16 ; 238.1,252.65 238.1,246.93 ; R358.2 233.65,264.95 234.24,265.53 236.19,265.53 236.96,264.77 R360.2 238.1,264.58 238.1,258.16 ; 238.1,258.16 R336.2 ; 238.1,240.88 R342.2 235.84,242.04 234.07,242.04 233.69,241.66 R338.2 ; 238.1,240.88 238.1,235.53 237.3,234.73 R331.2 237.02,235.34 236.19,236.17 v3(235.28,236.17) 234.72,236.17 233.72,235.17 R333.2 ; 238.1,240.88 238.1,246.93 ; R359.2 233.67,247.79 234.11,248.23 236.17,248.23 236.97,247.43 R357.2 238.1,246.93 ; R417.1 v4(190.53,195.05)
  BOTTOM w0.508: v3(76.51,214.45) 76.53,214.48 v3(77.37,214.48) ; v3(88.85,214.86) 88.88,214.83 v3(89.84,214.83)
  vias: v1(216.74,188.05) v1(226.34,186.45) v1(234.47,192.35) v1(234.47,191.59) v1(234.47,190.83) v1(235.1,192.74) v1(235.11,192.02) v1(235.1,191.21) v1(235.1,190.45) v3(75.74,214.66) v3(75.69,213.87) v3(77.37,213.72) v3(88.82,215.57) v3(88.87,214.1) v3(89.87,215.6)
2980_RESETB: length 31.2
  TOP w0.191: R142.2 217.44,121.18 v1(217.14,120.88)
  L3_SIGNAL w0.191: v2(206.17,123.8) 205.28,123.8 204.01,122.53 204.01,120.5 203.43,119.91 203.43,119.78 v2(203.29,119.64) ; v2(212.42,120.65) 212.12,120.95 212.12,123.51 v2(211.84,123.79)
  L24_SIGNAL w0.114: v1(217.14,120.88) 216.48,120.88 214.71,119.1 213.28,119.1 212.42,119.96 v2(212.42,120.65) 212.29,120.52 206.91,120.52 206.63,120.8 204.32,120.8 203.43,119.91 203.43,119.78 v2(203.29,119.64)
  L24_SIGNAL w0.191: v2(217.44,123.79) 217.14,123.5 v1(217.14,120.88)
  BOTTOM w0.191: U11.J2 211.47,124.15 v2(211.84,123.79) ; v2(217.44,123.79) 217.07,124.15 U11.B2 ; v2(206.17,123.8) 206.17,123.84 U11.T2
ADC_A0: length 67.8
  TOP w0.222: C533.1 v5(71.48,176.4)
  L2_GROUND w0.102: 111.9,137.76 111.9,149.64 arc(110.2,158.16) 105.38,165.38 99.49,171.27 arc(93.81,175.07) 87.1,176.4 v5(71.48,176.4)
  L2_GROUND w0.127: v5(111.9,137.73) 111.9,137.76
ADC_A0_CONN: length 3.5
  TOP w0.222: C533.2 ADC_A0.1
ADC_A1: length 69.1
  TOP w0.222: C545.1 R76.1 80.23,192.68 v5(80.68,192.22)
  L2_GROUND w0.114: v5(80.68,192.22) 102.87,173.48 arc(111.29,162.91) 114.3,149.72 114.3,137.76 v5(114.3,137.73)
ADC_A1_CONN: length 3.5
  TOP w0.222: C545.2 79.58,193.15 ADC_A1.1
ADC_A2: length 69.6
  TOP w0.222: v5(95.8,201.8) C532.1
  L2_GROUND w0.114: v5(116.7,137.73) 116.7,137.76 116.7,151.74 arc(115.45,162.45) 111.78,172.58 v5(95.8,201.8)
ADC_A2_CONN: length 3.5
  TOP w0.222: ADC_A2.1 95.08,203.05 C532.2
ADC_A3: length 70.3
  TOP w0.222: C546.1 v5(111.92,206.37)
  L2_GROUND w0.114: v5(111.92,206.37) 116.08,194.21 arc(118.34,183.49) 119.1,172.57 v5(119.1,137.73)
ADC_A3_CONN: length 3.5
  TOP w0.222: ADC_A3.1 111.43,207.73 111.43,207.63 C546.2
ADC_B0: length 67.8
  TOP w0.222: C647.1 v5(173.09,176.53)
  L2_GROUND w0.114: v5(132.7,137.73) 132.7,137.76 132.7,149.64 arc(134.39,158.16) 139.22,165.38 145.11,171.27 arc(150.93,175.16) 157.8,176.53 v5(173.09,176.53)
ADC_B0_CONN: length 3.5
  TOP w0.222: C647.2 ADC_B0.1
ADC_B1: length 69
  TOP w0.222: v5(163.91,192.25) 164.32,192.65 R75.1
  L2_GROUND w0.114: v5(163.91,192.25) 141.73,173.48 arc(133.3,162.91) 130.3,149.72 130.3,137.76 v5(130.3,137.73)
ADC_B1_CONN: length 3.6
  TOP w0.222: ADC_B1.1 165.77,193.81 164.96,193 C536.2
ADC_B2: length 69.6
  TOP w0.222: 149.14,202.43 v5(148.79,201.8)
  L2_GROUND w0.114: v5(127.9,137.73) 127.9,137.76 127.9,151.74 arc(129.15,162.45) 132.82,172.58 144.23,193.89 v5(148.79,201.8)
ADC_B2_CONN: length 3.5
  TOP w0.222: C646.2 149.41,202.95 149.52,203.05 ADC_B2.1
ADC_B3: length 70.3
  TOP w0.222: C537.1 v5(131.87,206.63)
  L2_GROUND w0.114: v5(125.5,137.73) 125.5,137.76 125.5,172.57 arc(126.26,183.49) 128.52,194.21 v5(131.87,206.63)
ADC_B3_CONN: length 3.5
  TOP w0.222: C537.2 132.2,207.97 132.25,208.02 ADC_B3.1
ADDR0: length 42.2
  TOP w0.191: v1(32.84,206.98) 26.24,206.98 7.09,187.83 R736.1 7.09,184 S5.1B
  BOTTOM w0.191: U51.16 32.51,203.01 32.45,203.07 32.45,203.4 32.4,203.45 32.4,204.65 32.56,204.8 32.56,206.7 v1(32.84,206.98)
ADDR1: length 36.2
  TOP w0.191: v1(32.95,203.68) 31.88,204.75 25.83,204.75 9.63,188.55 R737.1 9.63,184 S5.2B
  BOTTOM w0.191: U51.17 33.01,203.47 32.95,203.52 v1(32.95,203.68)
ADDR2: length 36
  TOP w0.191: S5.3B 12.19,184.02 R738.1 12.19,189.18 26.9,203.89 31.93,203.89 32.08,203.74 32.1,203.74 32.66,203.18 33.51,203.18 34.16,203.83 v1(34.87,203.83)
  BOTTOM w0.191: U51.21 35.01,202.85 35.14,202.98 35.14,203.44 34.87,203.71 v1(34.87,203.83)
ADDR3: length 26.5
  TOP w0.191: v1(31.34,194.46) 31.34,193.69 31.15,193.5 18.49,193.5 14.71,189.71 R739.1 14.71,184 S5.4B
  BOTTOM w0.191: U51.47 31.51,195.35 31.56,195.29 31.56,194.68 v1(31.34,194.46)
ADF4030_3P3V:
  vias: v3(89.74,251.87) v3(89.76,250.98) v3(89.76,250.11) v3(90.47,251.38) v3(90.47,250.52) v3(101.3,236.22) v3(101.7,235.51) v3(102.16,236.22) v3(102.57,235.51) v3(103.05,236.25)
ADF4382_3P3_1: length 15.5
  BOTTOM w0.191: U30.40 122.7,159.98 122.33,160.35 C119.1 121.73,160.87 120.8,161.8 120.4,161.8 v3(120.35,161.85)
  BOTTOM w0.203: R303.1 117.75,154.43 v3(117.96,154.64)
  BOTTOM w0.254: v4(129.54,158.65) 129.51,158.62 128.78,158.62 128.48,158.33 C112.1 128.3,157.94 128.28,157.96 U30.3 ; 125.22,160.07 125.22,159.44 U30.45 ; 125.22,160.07 125.22,160.87 C123.1 125.74,160.87 126.23,161.35 126.53,161.35 v6(126.7,161.19) ; 125.22,160.07 124.7,160.07 U30.44 ; U30.36 120.73,159.11 v4(120.35,159.49) 120.07,159.21 C122.1 ; C118.1 120.07,155.83 v4(120.17,155.93) 120.2,155.96 U30.30
  vias: v3(128.75,173.48) v3(129.34,172.8) v3(129.44,173.61)
ADF4382_3P3_2: length 8.5
  BOTTOM w0.254: v4(130,156.38) 130.28,156.66 C310.1 129.41,157.03 C102.1 129.18,156.95 129.18,156.96 U30.5 ; E5.2 119.79,173.43 C131.1 ; U30.11 127.45,153.96 127.67,153.74 127.67,153.67 127.67,153.67 127.67,152.74 127.3,152.37 127.2,152.37
  BOTTOM w0.381: v4(131.44,151.46) 131.42,151.43 R290.2
  vias: v1(120.32,151.23) v1(120.6,152.45) v1(126.7,151.21) v1(126.8,151.79) v4(120.2,165.08) v4(120.6,165.61) v6(124.46,151.46) v6(124.49,150.39) v6(124.49,149.63) v6(126.87,152.37) v6(126.85,150.34)
ADF4382_3P3V: length 0.5
  BOTTOM w0.191: E5.1 v4(120.27,175.42)
  vias: v1(104.67,243.48) v1(104.67,242.72) v1(104.67,241.96) v1(105.31,243.87) v1(105.31,243.1) v1(105.31,242.34) v4(117.37,176.35) v4(117.32,175.64) v4(117.86,175.29) v4(117.93,176) v4(120.21,176.32) v4(126.82,175.51) v4(127.28,176.35) v4(128.14,176.35) v4(128.88,175.69) v4(128.93,176.3)
ADF4382_5P0V: length 14.4
  BOTTOM w0.254: R19.1 80.04,221.56 80.72,222.25 84.48,222.25 85.19,221.54 85.19,219.04 85.29,218.94
  BOTTOM w0.381: v1(128.4,169.04) 128.4,167.5 ; C108.1 E2.1
  BOTTOM w0.406: 128.4,167.5 E3.1
  vias: v1(84.25,217.09) v1(84.94,218.47) v1(84.91,217.81) v1(84.91,217.12) v1(85.6,217.12) v1(134.57,153.52)
ADF4382_CE: length 7.9
  BOTTOM w0.191: U30.31 120.34,156.46 120.32,156.48 119.86,156.48 119.84,156.46 116.45,156.46 115.78,155.79 R303.2 115.08,154.43 115.05,154.47 Q8.6
ADF4382_CE_LS: length 170.2
  TOP w0.191: R240.1 22.38,106.42 v1(22.38,170.74)
  L24_SIGNAL w0.114: v1(109.52,155.69) 101.02,155.69 99.64,157.07 82.25,157.07 70.89,168.43 29.18,168.43 25.1,172.52 21.58,172.52 20.19,171.13 20.19,169.59 20.78,169 22.16,169 22.38,169.23 v1(22.38,170.74)
  BOTTOM w0.191: v1(109.52,155.69) R318.1
ADF4382_LKDET: length 176.5
  TOP w0.191: v1(21.24,169.9) 21.24,106.42 R259.1
  L24_SIGNAL w0.114: v1(109.09,149.28) 106.07,149.28 98.91,156.44 81.23,156.44 70.74,166.93 28.96,166.93 24,171.88 22.35,171.88 21.24,170.77 v1(21.24,169.9)
  BOTTOM w0.191: v1(109.09,149.28) 116.15,149.28 116.86,149.98 R295.1 116.86,150.83 120.49,154.46 U30.27
ADF4382_OUTN: length 4.5
  BOTTOM w0.133: L4.1 123.2,151.4
  BOTTOM w0.222: 123.2,151.4 123.09,151.28 123.09,149.45 ; U30.20 L4.1
  BOTTOM w0.381: 123.09,149.45 123.09,148.51
ADF4382_OUTP: length 4.4
  BOTTOM w0.133: L3.2 122.19,151.37
  BOTTOM w0.222: 122.19,151.37 122.34,151.21 122.34,149.5 122.33,149.48 ; L3.2 122.2,151.55 U30.22
  BOTTOM w0.381: 122.33,149.48 122.33,148.62
ADS10_HMC7044_REFCLK_N: length 2.2
  BOTTOM w0.191: C565.1 18.95,230.53 18.65,230.23 18.65,229.8 18.61,229.76 U1B.30
ADS10_HMC7044_REFCLK_P: length 2.2
  BOTTOM w0.191: C564.1 18.39,230.52 18.26,230.39 18.26,229.96 18.11,229.81 U1B.29
ADS10_REFCLK_N: length 315.7
  L22_MIXED w0.102: v4(19.21,236.12) 18.79,236.53 18.79,236.93 18.89,237.03 20.73,237.03 20.83,236.93 20.83,233.2 14,226.36 14,222.48 9.55,218.03 9.55,215.72 7.96,214.12 7.96,185.93 8.1,185.78 8.1,172.85 10.42,170.53 10.42,154.82 7.75,152.15 7.75,72.19 12.39,67.54 16.28,67.54 20.17,63.66 20.17,46.64 26.26,40.54 42.47,40.54 44.96,38.06 112.11,38.06 115.45,34.72 115.45,33.91 v4(114.94,33.4)
  BOTTOM w0.127: P1.L25 v4(114.94,33.4)
  BOTTOM w0.133: v4(19.21,236.12) 18.82,235.74 18.82,232.12 18.95,231.99 C565.2
ADS10_REFCLK_P: length 316.5
  L22_MIXED w0.102: v4(18.13,236.12) 18.55,236.53 18.55,237.03 18.79,237.28 20.83,237.28 21.08,237.03 21.08,233.09 14.24,226.26 14.24,222.38 9.8,217.93 9.8,215.61 8.2,214.02 8.2,186.03 8.35,185.88 8.35,172.95 10.67,170.63 10.67,154.72 8,152.05 8,72.29 12.5,67.79 16.38,67.79 20.42,63.76 20.42,46.74 26.37,40.79 42.57,40.79 45.06,38.3 112.22,38.3 115.69,34.83 115.69,33.91 v4(116.21,33.4)
  BOTTOM w0.127: P1.L24 v4(116.21,33.4)
  BOTTOM w0.133: v4(18.13,236.12) 18.51,235.74 18.51,232.12 18.39,231.99 C564.2
AION_REFIN_N: length 48.4
  BOTTOM w0.133: U1B.4 10.93,221.59 10.83,221.49 10.51,221.49 4.51,215.49 4.51,210.89 7.74,207.67 26.37,207.67 28.24,209.54 32.61,209.54 33.57,208.59 33.57,206.65 C771.1
AION_REFIN_P: length 47.9
  BOTTOM w0.133: U1B.3 10.93,221.09 10.83,221.18 10.64,221.18 4.83,215.36 4.83,211.02 7.87,207.98 26.24,207.98 28.11,209.85 32.74,209.85 33.88,208.71 33.88,206.61 C772.1
APOLLO_DELADJ: length 5.1
  BOTTOM w0.191: U30.28 120.39,154.96 117.42,151.99 R316.1
APOLLO_DELSTR: length 4.9
  BOTTOM w0.191: U30.29 120.44,155.46 120.39,155.4 120.35,155.4 119.54,154.59 119.47,154.59 118.01,153.14 R317.1
APOLLO_RESET: length 54.7
  TOP w0.191: S2.1A S2.1B 156.76,101.28 150.16,107.87 141.64,107.87 v1(141.55,107.97) R325.2 R326.2
  BOTTOM w0.191: v4(131.1,120.93) 131.66,120.37 139.17,120.37 141.55,117.99 v1(141.55,107.97)
APOLLO_RESET_LS: length 75.2
  TOP w0.191: R325.1 v1(139.93,107.26) ; v1(97.99,89.46) 96.52,90.93 83.57,90.93 83.57,90.93 76.89,90.93 76.33,90.37 R255.1
  L22_MIXED w0.191: v1(97.99,89.46) 97.99,90.91 108.94,101.85 133.68,101.85 139.09,107.26 v1(139.93,107.26)
APOLLO_SYSREF_N: length 106.3
  TOP w0.133: R14.1 v2(21.11,272.69)
  L24_SIGNAL w0.108: v2(21.11,272.69) 23.01,272.69 23.22,272.49 23.22,269.56 18.9,265.25 18.9,265.11 18.87,265.07 18.87,245.39 7.44,233.96 7.44,216.21 v4(7.11,215.87)
  BOTTOM w0.133: v4(7.11,215.87) 7.49,215.49 7.49,210.06 8.94,208.61 23.5,208.61 25.44,210.56 34.64,210.56 35.93,209.27 35.93,209.25 35.23,208.54 TP51.1
  BOTTOM w0.191: TP51.1 35.69,208.2 36.02,207.87 36.02,206.8 R724.2
APOLLO_SYSREF_P: length 106.8
  TOP w0.133: v2(25.83,272.69) 25.76,272.62 R12.1
  L24_SIGNAL w0.108: v4(8.18,215.87) 7.74,216.31 7.74,233.8 19.2,245.26 19.2,265.13 23.52,269.44 23.52,272.51 23.7,272.69 v2(25.83,272.69)
  BOTTOM w0.133: TP50.1 37.13,208.36 36.25,209.25 36.25,209.4 34.77,210.87 25.32,210.87 23.37,208.92 9.07,208.92 7.8,210.19 7.8,215.5 v4(8.18,215.87)
  BOTTOM w0.191: R723.2 36.5,206.88 36.5,207.99 36.69,208.18 TP50.1
APOLLO_TRIG_A0: length 8.8
  TOP w0.191: v1(15.75,229.94) 15.75,230.2 15.6,230.35 15.6,231.99 15.58,232.01 15.58,232.4 15.6,232.42 R525.1
  BOTTOM w0.191: U1B.24 15.61,229.8 v1(15.75,229.94)
ARTEMIS_REFIN_N: length 59.2
  BOTTOM w0.133: U2.3 58.43,225.77 58.34,225.67 58.34,223.28 59.06,222.56 61.52,222.56 70.99,232.03 70.99,266.42 69.43,267.98 C311.1
ARTEMIS_REFIN_P: length 60.1
  BOTTOM w0.133: C314.1 72.56,270.46 72.56,267.6 71.3,266.35 71.3,231.9 61.65,222.25 58.93,222.25 58.03,223.15 58.03,225.67 57.93,225.77 U2.4
ARTEMIS_SYNC_N: length 0.8
  BOTTOM w0.191: R713.1 35.12,254.66 C233.2
ARTEMIS_SYNC_P: length 0.8
  BOTTOM w0.191: R714.1 33.46,254.69 C232.2
AUX_GPIO0_FMC: length 141.7
  TOP w0.191: R273.2 v4(22.81,94.18)
  L3_SIGNAL w0.114: v4(22.81,94.18) 22.69,94.05 v1(22.69,36.68)
  L5_MIXED w0.114: v4(98.42,29.59) 97.49,30.53 97.49,34.94 95.2,37.22 89.96,37.22 89.16,36.41 41.34,36.41 40.97,36.04 39.42,36.04 38.79,36.68 v1(22.69,36.68)
  BOTTOM w0.191: P1.H38 v4(98.42,29.59)
AUX_GPIO1_FMC: length 151.4
  TOP w0.191: R267.2 v4(21.67,94.18)
  L3_SIGNAL w0.114: v1(21.54,38.89) 21.54,94.05 v4(21.67,94.18)
  L5_MIXED w0.114: v4(103.5,25.78) 103.02,26.27 103.02,32.63 103.84,33.45 103.84,34.32 98.6,39.55 98.24,39.55 98.23,39.55 88.93,39.55 88.92,39.55 88.87,39.55 88.31,38.98 51.99,38.98 51.66,39.31 32.96,39.31 32.8,39.47 28.58,39.47 28,38.89 v1(21.54,38.89)
  BOTTOM w0.191: P1.E34 v4(103.5,25.78)
AUX_GPIO2: length 130.1
  TOP w0.191: v1(6.49,223.08) 6.59,223.17 R5.1 ; R245.1 20.27,106.34 v1(20.27,107.32)
  L3_SIGNAL w0.114: v1(6.49,223.08) 4.93,221.51 4.93,213.49 6.81,211.61 11.33,211.61 17.55,205.38 17.55,199.34 20.27,196.62 v1(20.27,107.32)
AUX_GPIO2_FMC: length 147.2
  TOP w0.191: R264.2 v4(20.53,94.18)
  L3_SIGNAL w0.114: v1(20.47,37.26) 20.1,37.63 20.1,93.76 v4(20.53,94.18)
  L5_MIXED w0.114: v4(99.69,27.05) 98.96,27.78 98.96,29.76 97.8,30.92 97.8,35.28 95.55,37.54 89.83,37.54 89.02,36.73 41.14,36.73 40.83,36.42 39.91,36.42 39.07,37.26 23.62,37.26 23.61,37.26 v1(20.47,37.26)
  BOTTOM w0.191: P1.F37 v4(99.69,27.05)
AUX_GPIO3_FMC: length 147.6
  TOP w0.191: R270.2 v4(19.38,94.21)
  L3_SIGNAL w0.114: v1(19.26,36.3) 19.26,94.08 v4(19.38,94.21)
  L5_MIXED w0.114: v1(19.26,36.3) 22.34,36.3 22.47,36.16 22.9,36.16 23.03,36.3 38.46,36.3 39.02,35.73 41.1,35.73 41.36,35.99 89.18,35.99 90.09,36.91 94.87,36.91 97.05,34.72 97.05,28.42 v4(98.42,27.05)
  BOTTOM w0.191: P1.F38 v4(98.42,27.05)
AUX_GPIO4_FMC: length 151.4
  TOP w0.191: R276.2 v4(18.24,94.19)
  L3_SIGNAL w0.114: v1(18.24,38.38) 18.6,38.74 18.6,93.83 v4(18.24,94.19)
  L5_MIXED w0.114: v4(100.97,25.78) 100.38,26.37 100.38,30.97 100.5,31.09 100.5,33.18 100.48,33.2 100.48,34.35 96.22,38.61 89.38,38.61 88.61,37.84 40.57,37.84 40.03,38.38 v1(18.24,38.38)
  BOTTOM w0.191: P1.E36 v4(100.97,25.78)
AUX_GPIO5_FMC: length 152.5
  TOP w0.191: R285.2 v4(17.1,94.16)
  L3_SIGNAL w0.114: v4(17.1,94.16) 16.97,94.03 16.97,35.59 v1(16.94,35.56)
  L5_MIXED w0.114: v4(99.69,25.78) 98.86,25.78 98.6,26.04 98.19,26.04 96.63,27.6 96.63,34.47 94.55,36.55 90.19,36.55 89.21,35.56 ; v1(16.94,35.56) 19.79,35.56 19.91,35.69 38.25,35.69 38.55,35.39 41.29,35.39
  L5_MIXED w0.133: 89.21,35.56 41.58,35.56 41.42,35.4 41.3,35.4 41.29,35.39
  BOTTOM w0.191: P1.E37 v4(99.69,25.78)
BRD_12V: length 58.2
  TOP w0.508: R337.2 222.95,224.64 ; 222.95,224.64 222.93,224.61 v1(222.93,226.26) ; 222.95,224.64 R643.1
  L18_POWER w0.546: v1(222.93,226.26) 220.2,228.98 217.47,228.98 214.38,232.08 214.38,256.84 207.78,263.44 v3(203.84,263.44)
  BOTTOM w0.203: U39.5 199.81,263.96 200.18,264.33 202.95,264.33 v3(203.84,263.44)
BSYNC0_N: length 45.1
  L24_SIGNAL w0.114: v9(10.8,226.59) 10.61,226.59 10.43,226.4 9.36,226.4 8.69,225.73 8.69,220.79 9.43,220.05 9.43,215.17 10.97,213.63 10.97,213.39 10.98,213.38 10.98,207.17 23.44,194.71 23.59,194.71 v2(24.04,194.26)
  BOTTOM w0.191: R721.2 26.72,194.34 R722.2 25.31,194.34 25.07,194.58 24.37,194.58 v2(24.04,194.26) ; R385.2 10.4,226.59 v9(10.8,226.59) U1B.14
BSYNC0_P: length 43.9
  L24_SIGNAL w0.114: v2(24.04,195.33) 23.76,195.05 23.55,195.05 11.29,207.3 11.29,213.51 11.29,213.52 11.29,213.76 9.75,215.3 9.75,220.18 9.01,220.92 9.01,225.6 9.49,226.09 v9(10.77,226.09)
  BOTTOM w0.191: v2(24.04,195.33) 24.4,194.97 24.96,194.97 25.07,194.97 25.34,195.24 R722.1 26.67,195.24 R720.2 ; R103.2 10.54,225.86 v9(10.77,226.09) U1B.13
BSYNC1_N: length 3.1
  BOTTOM w0.133: R745.1 28.07,198.13 29.89,198.13 29.98,198.04 U51.4
BSYNC1_P: length 3.1
  BOTTOM w0.133: R740.1 28.19,198.44 29.89,198.44 29.95,198.51 30.14,198.51 30.17,198.54 U51.5
BSYNC2_N: length 3.3
  BOTTOM w0.133: R752.1 28.31,200.61 28.66,200.61 29.47,199.8 29.51,199.8 29.7,199.61 30.17,199.61 30.18,199.6 30.47,199.6 U51.7
BSYNC2_P: length 3.3
  BOTTOM w0.133: R751.1 28.46,200.92 28.79,200.92 29.6,200.11 29.64,200.11 29.83,199.92 30.13,199.92 30.18,199.97 30.47,199.97 U51.8
BSYNC3_N: length 5
  BOTTOM w0.133: U51.10 30.47,201.1 30.09,201.1 30.04,201.16 29.73,201.16 28.45,202.43 27.65,202.43 27.25,202.83 27.25,203.19 R733.1
BSYNC3_P: length 5
  BOTTOM w0.133: U51.11 30.47,201.47 29.95,201.47 29.34,202.08 29.34,202.74 29.06,203.02 28.73,203.02 28.59,202.88 28.26,202.88 28.12,202.74 27.87,202.74 27.56,203.05 27.56,203.21 R732.1
BSYNC4_N: length 3
  BOTTOM w0.191: R750.1 31.11,204.94 31.11,204.42 30.9,204.21 30.9,203.41 30.94,203.37 30.94,202.85 31.01,202.79 U51.13
BSYNC4_P: length 3.1
  BOTTOM w0.191: R749.1 31.5,204.84 31.5,204.26 31.29,204.05 31.29,203.57 31.34,203.53 31.34,203.01 31.51,202.84 U51.14
BSYNC5_N: length 3.1
  BOTTOM w0.191: R724.1 36.01,205.2 U51.23
BSYNC5_P: length 3.1
  BOTTOM w0.191: U51.24 36.51,205.12 R723.1
BSYNC6_N: length 202.6
  L24_SIGNAL w0.108: v2(140,101.73) 140.82,101.73 141.15,102.06 141.15,103.15 141.74,103.73 145.28,103.73 148.89,107.34 148.89,128.12 137.92,139.09 116.13,139.09 111.3,143.92 111.3,160.63 94.49,177.44 94.49,187.39 79.75,202.14 51.71,202.14 48.28,198.71 41.94,198.71 40.44,200.21 40.44,205.35 40.33,205.46 40.19,205.46 40.08,205.57 v9(40.08,205.6)
  BOTTOM w0.133: v9(40.08,205.6) 40.46,205.22 40.46,204.13 40,203.68 39.5,203.68 39.27,203.45 39.27,203.02 38.89,202.64 38.51,202.64 38.38,202.51 38.38,202.01 37.82,201.44 37.63,201.44 37.53,201.54 U51.26
  BOTTOM w0.191: v2(140,101.73) 139.62,102.11 R716.2
BSYNC6_P: length 202.5
  L24_SIGNAL w0.108: v2(142.6,101.63) 142.47,101.75 141.76,101.75 141.45,102.06 141.45,103.02 141.86,103.43 145.41,103.43 149.19,107.22 149.19,128.24 138.05,139.39 116.25,139.39 111.6,144.04 111.6,160.75 94.79,177.56 94.79,187.52 79.87,202.44 51.59,202.44 48.16,199.01 42.06,199.01 40.74,200.33 40.74,205.35 40.85,205.46 40.99,205.46 v9(41.1,205.57)
  BOTTOM w0.133: U51.27 37.53,201.04 37.63,201.13 37.95,201.13 40.77,203.95 40.77,205.24 v9(41.1,205.57)
  BOTTOM w0.191: R718.2 v2(142.6,101.63)
BSYNC7_N: length 196.2
  L24_SIGNAL w0.108: v9(41.99,201.23) 42.41,200.8 42.41,200.48 43.16,199.73 47.09,199.73 51.03,203.66 81.32,203.66 95.56,189.43 95.56,178.11 112.27,161.4 112.27,144.4 116.56,140.11 138.34,140.11 149.91,128.54 149.91,107.18 145.04,102.31 145.04,102.01 144.65,101.63 v2(143.69,101.63)
  BOTTOM w0.133: U51.29 37.53,200.04 37.63,199.94 38.81,199.94 39.2,200.33 39.65,200.33 40.04,199.94 40.51,199.94 40.9,200.33 41.25,200.33 41.64,199.94 42.11,199.94 42.39,200.22 42.39,200.83 v9(41.99,201.23)
  BOTTOM w0.191: R719.2 v2(143.69,101.63)
BSYNC7_P: length 196.2
  L24_SIGNAL w0.108: v9(43.13,201.23) 42.71,200.8 42.71,200.6 43.28,200.02 46.96,200.02 50.9,203.96 81.45,203.96 95.86,189.55 95.86,178.23 112.57,161.52 112.57,144.52 116.68,140.4 138.47,140.4 150.21,128.66 150.21,107.05 145.34,102.18 145.34,101.99 145.65,101.68 146.69,101.68 v2(146.74,101.63)
  BOTTOM w0.133: U51.30 37.53,199.54 37.63,199.63 42.24,199.63 42.7,200.09 42.7,200.79 v9(43.13,201.23)
  BOTTOM w0.191: R717.2 v2(146.74,101.63)
BSYNC8_N: length 3.7
  BOTTOM w0.133: R742.1 39.69,197.29 39.25,197.29 38.09,198.44 37.63,198.44 37.53,198.54 U51.32
BSYNC8_P: length 3.7
  BOTTOM w0.133: U51.33 37.53,198.04 37.63,198.13 37.96,198.13 39.12,196.98 39.53,196.98 R741.1
BSYNC9_N: length 6.7
  BOTTOM w0.133: U51.35 37.53,197.04 37.63,196.94 37.95,196.94 39.03,195.86 39.45,195.86 39.61,195.7 39.61,195.28 39.82,195.07 40.48,195.07 40.79,194.76 40.79,194.1 40.95,193.94 41.44,193.94 R17.1
BSYNC9_P: length 6.3
  BOTTOM w0.133: U51.36 37.53,196.54 37.63,196.63 37.82,196.63 40.82,193.62 40.94,193.62 41.48,193.09 R16.1
CLK_M2C_N_0: length 288.1
  L22_MIXED w0.102: 18.71,210.31 19,210.31 19.18,210.13 19.18,209.78 20.8,208.16 20.8,194.95 23.53,192.22 23.53,109.6 25.69,107.44 25.69,78.97 43.75,60.92 90.12,60.92 102.57,48.47 136.3,48.47 142.49,42.27 142.49,31.52 140.57,29.59 140.34,29.59
  BOTTOM w0.127: P1.H5 140.34,29.59
  BOTTOM w0.133: 18.71,210.31 18.9,210.31 19.25,210.66 19.25,215.99 19.14,216.11 R394.2 19.14,217.04 C569.2
CLK_M2C_N_1: length 287.1
  L22_MIXED w0.102: 142.88,28.32 143.33,28.78 143.33,43.72 137.67,49.38 103.58,49.38 102.38,50.58 102.38,50.58 90.27,62.69 46.11,62.69 27.81,80.99 27.81,170.49 26.19,172.11 26.19,206.82 26.12,206.89 20.52,212.49 20.52,213.87 20.4,214 20.14,214
  BOTTOM w0.127: P1.G3 142.88,28.32
  BOTTOM w0.133: C571.2 20.41,217.04 R395.2 20.41,216.11 20.52,215.99 20.52,214.38 20.14,214
CLK_M2C_P_0: length 287.5
  L22_MIXED w0.102: 141.6,29.59 141.29,29.91 141.29,29.96 142.76,31.43 142.76,42.35 136.4,48.72 102.67,48.72 90.23,61.16 43.85,61.16 25.94,79.07 25.94,107.54 23.78,109.7 23.78,192.32 21.05,195.05 21.05,208.26 19.42,209.89 19.42,210.15 19.58,210.31 19.79,210.31
  BOTTOM w0.127: P1.H4 141.6,29.59
  BOTTOM w0.133: 19.79,210.31 19.79,210.46 19.56,210.69 19.56,215.99 19.68,216.11 R394.1 19.68,217.04 C568.2
CLK_M2C_P_1: length 287.2
  L22_MIXED w0.102: 144.15,28.32 144.01,28.46 143.93,28.46 143.6,28.79 143.6,43.8 137.77,49.63 103.68,49.63 102.56,50.76 102.56,50.76 90.39,62.93 46.21,62.93 28.05,81.09 28.05,170.59 26.44,172.21 26.44,206.92 26.37,206.99 26.37,206.99 20.77,212.59 20.77,213.84 20.92,214 21.21,214
  BOTTOM w0.127: P1.G2 144.15,28.32
  BOTTOM w0.133: 21.21,214 20.83,214.38 20.83,215.99 20.95,216.11 R395.1 20.95,217.04 C570.2
CLKA_N: length 58.2
  BOTTOM w0.381: 78.64,178.56 78.64,179.22 C328.1
  BOTTOM w0.546: 78.64,178.56 90.81,166.62 104.29,153.14 104.29,150.83 113.46,141.65 113.46,136.17 v12(113.5,136.13)
CLKA_P: length 57.8
  BOTTOM w0.381: 78.13,178.05 77.67,178.51 C329.1
  BOTTOM w0.546: v12(112.7,136.13) 112.74,136.17 112.74,141.35 103.57,150.53 103.57,152.84 78.13,178.05
CLKB_N: length 58.2
  BOTTOM w0.381: 165.75,178.38 165.75,179.26 C327.1
  BOTTOM w0.546: 165.75,178.38 140.55,153.18 140.55,151.25 131.17,141.87 131.17,138.43 131.17,137.14 131.17,136.21 v12(131.09,136.14)
CLKB_P: length 57.8
  BOTTOM w0.381: 166.27,177.88 167.54,177.88 C326.1
  BOTTOM w0.546: v12(131.89,136.14) 131.89,137.14 131.9,138.43 131.9,141.57 141.27,150.95 141.27,152.88 166.27,177.88
CLKC_N: length 7.8
  BOTTOM w0.546: 122.34,145.54 122.34,138.73 122.3,138.69 v12(122.3,137.73)
CLKC_P: length 7.8
  BOTTOM w0.546: v12(123.1,137.73) 123.1,138.69 123.06,138.73 123.06,145.54
DACA0_N: length 31.3
  TOP w0.381: 111.13,132.05 111.1,132.08 U1A.AJ8
  TOP w0.546: T1WA.2 arc(84.64,142.22) 85.79,141.58 86.53,140.95 87.21,140.37 94.79,133.97 arc(97.14,132.58) 99.82,132.1 110.67,132.1 arc(110.9,132.09) 111.13,132.05
DACA0_P: length 31.2
  TOP w0.381: 111.08,132.84 111.1,132.86 U1A.AJ7
  TOP w0.546: 111.08,132.84 99.84,132.84 arc(97.4,133.27) 95.26,134.52 88.05,140.61 arc(87.61,141.16) 87.4,141.84 arc(87.23,142.24) 86.88,142.48 86.3,142.67 86.27,142.68 arc(85.25,143.38) T1WA.3
DACA1_N: length 31.5
  TOP w0.546: U1A.AJ11 111,129.63 101.35,129.63 arc(92.77,130.32) 84.42,132.38 arc(84.21,132.45) 83.99,132.5 arc(82.53,133.15) 81.16,133.96 arc(80.78,134.15) T1XA.3
DACA1_P: length 31.6
  TOP w0.381: U1A.AJ12 111.1,128.88 111.13,128.85
  TOP w0.546: T1XA.2 arc(80.37,131.88) 80.77,131.85 82.55,131.93 arc(83.38,131.88) 84.19,131.69 arc(92.65,129.61) 101.35,128.9 110.41,128.9 arc(110.77,128.89) 111.13,128.85
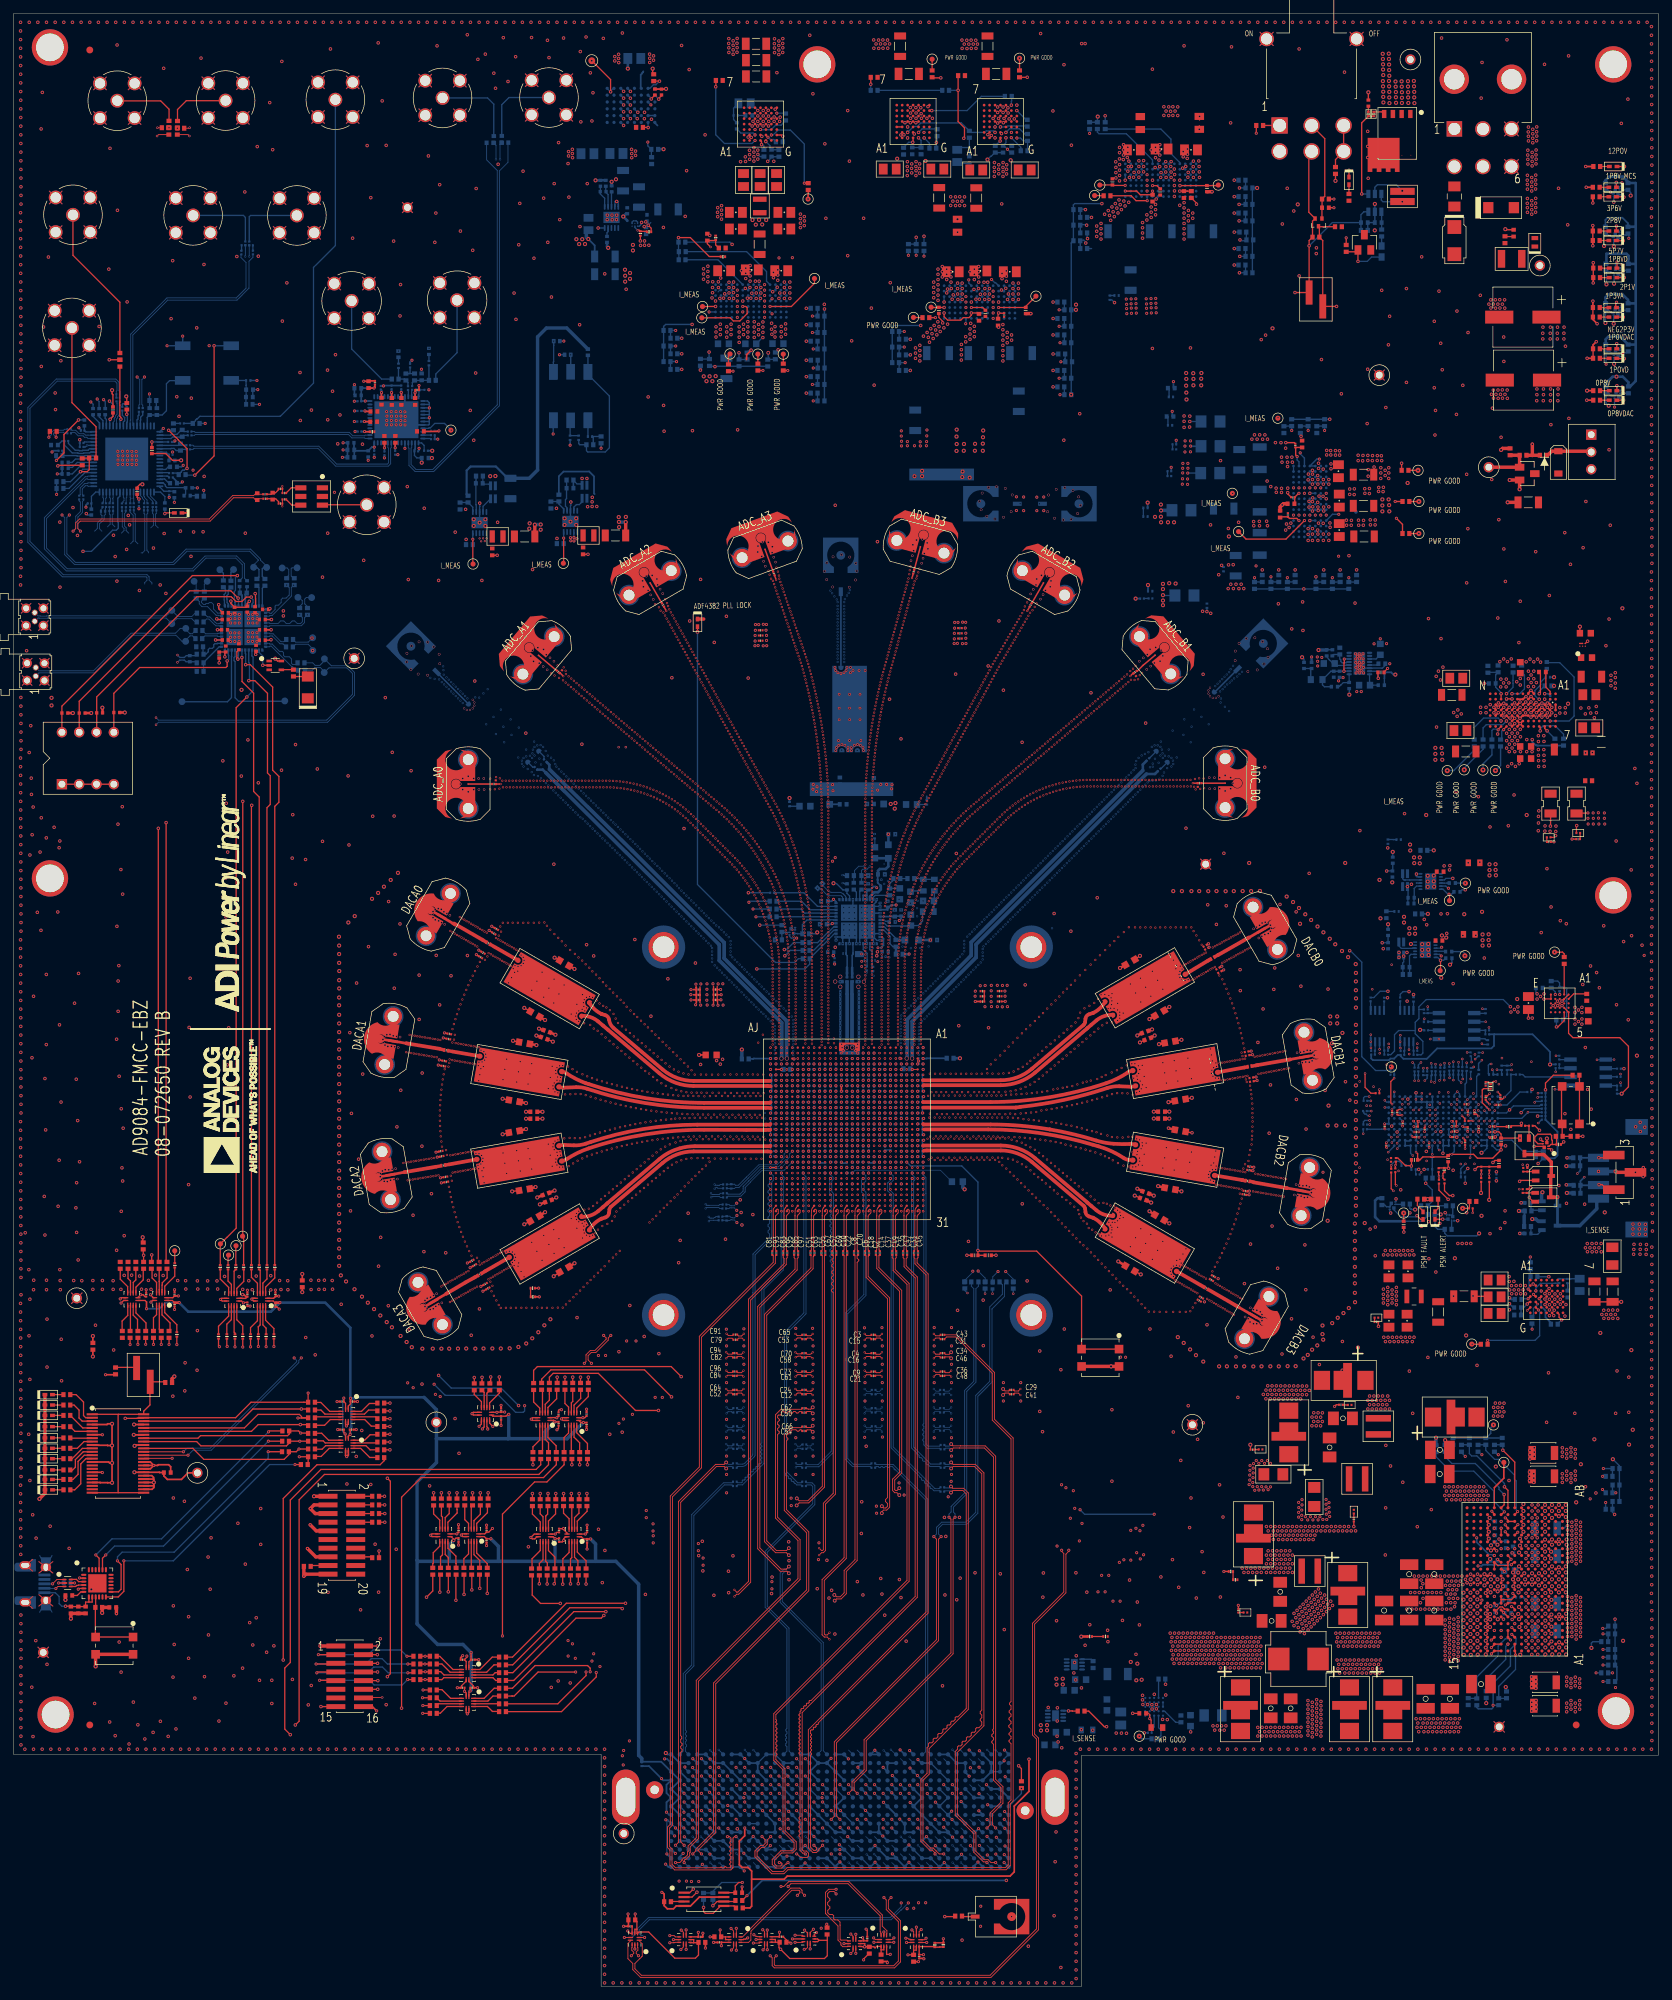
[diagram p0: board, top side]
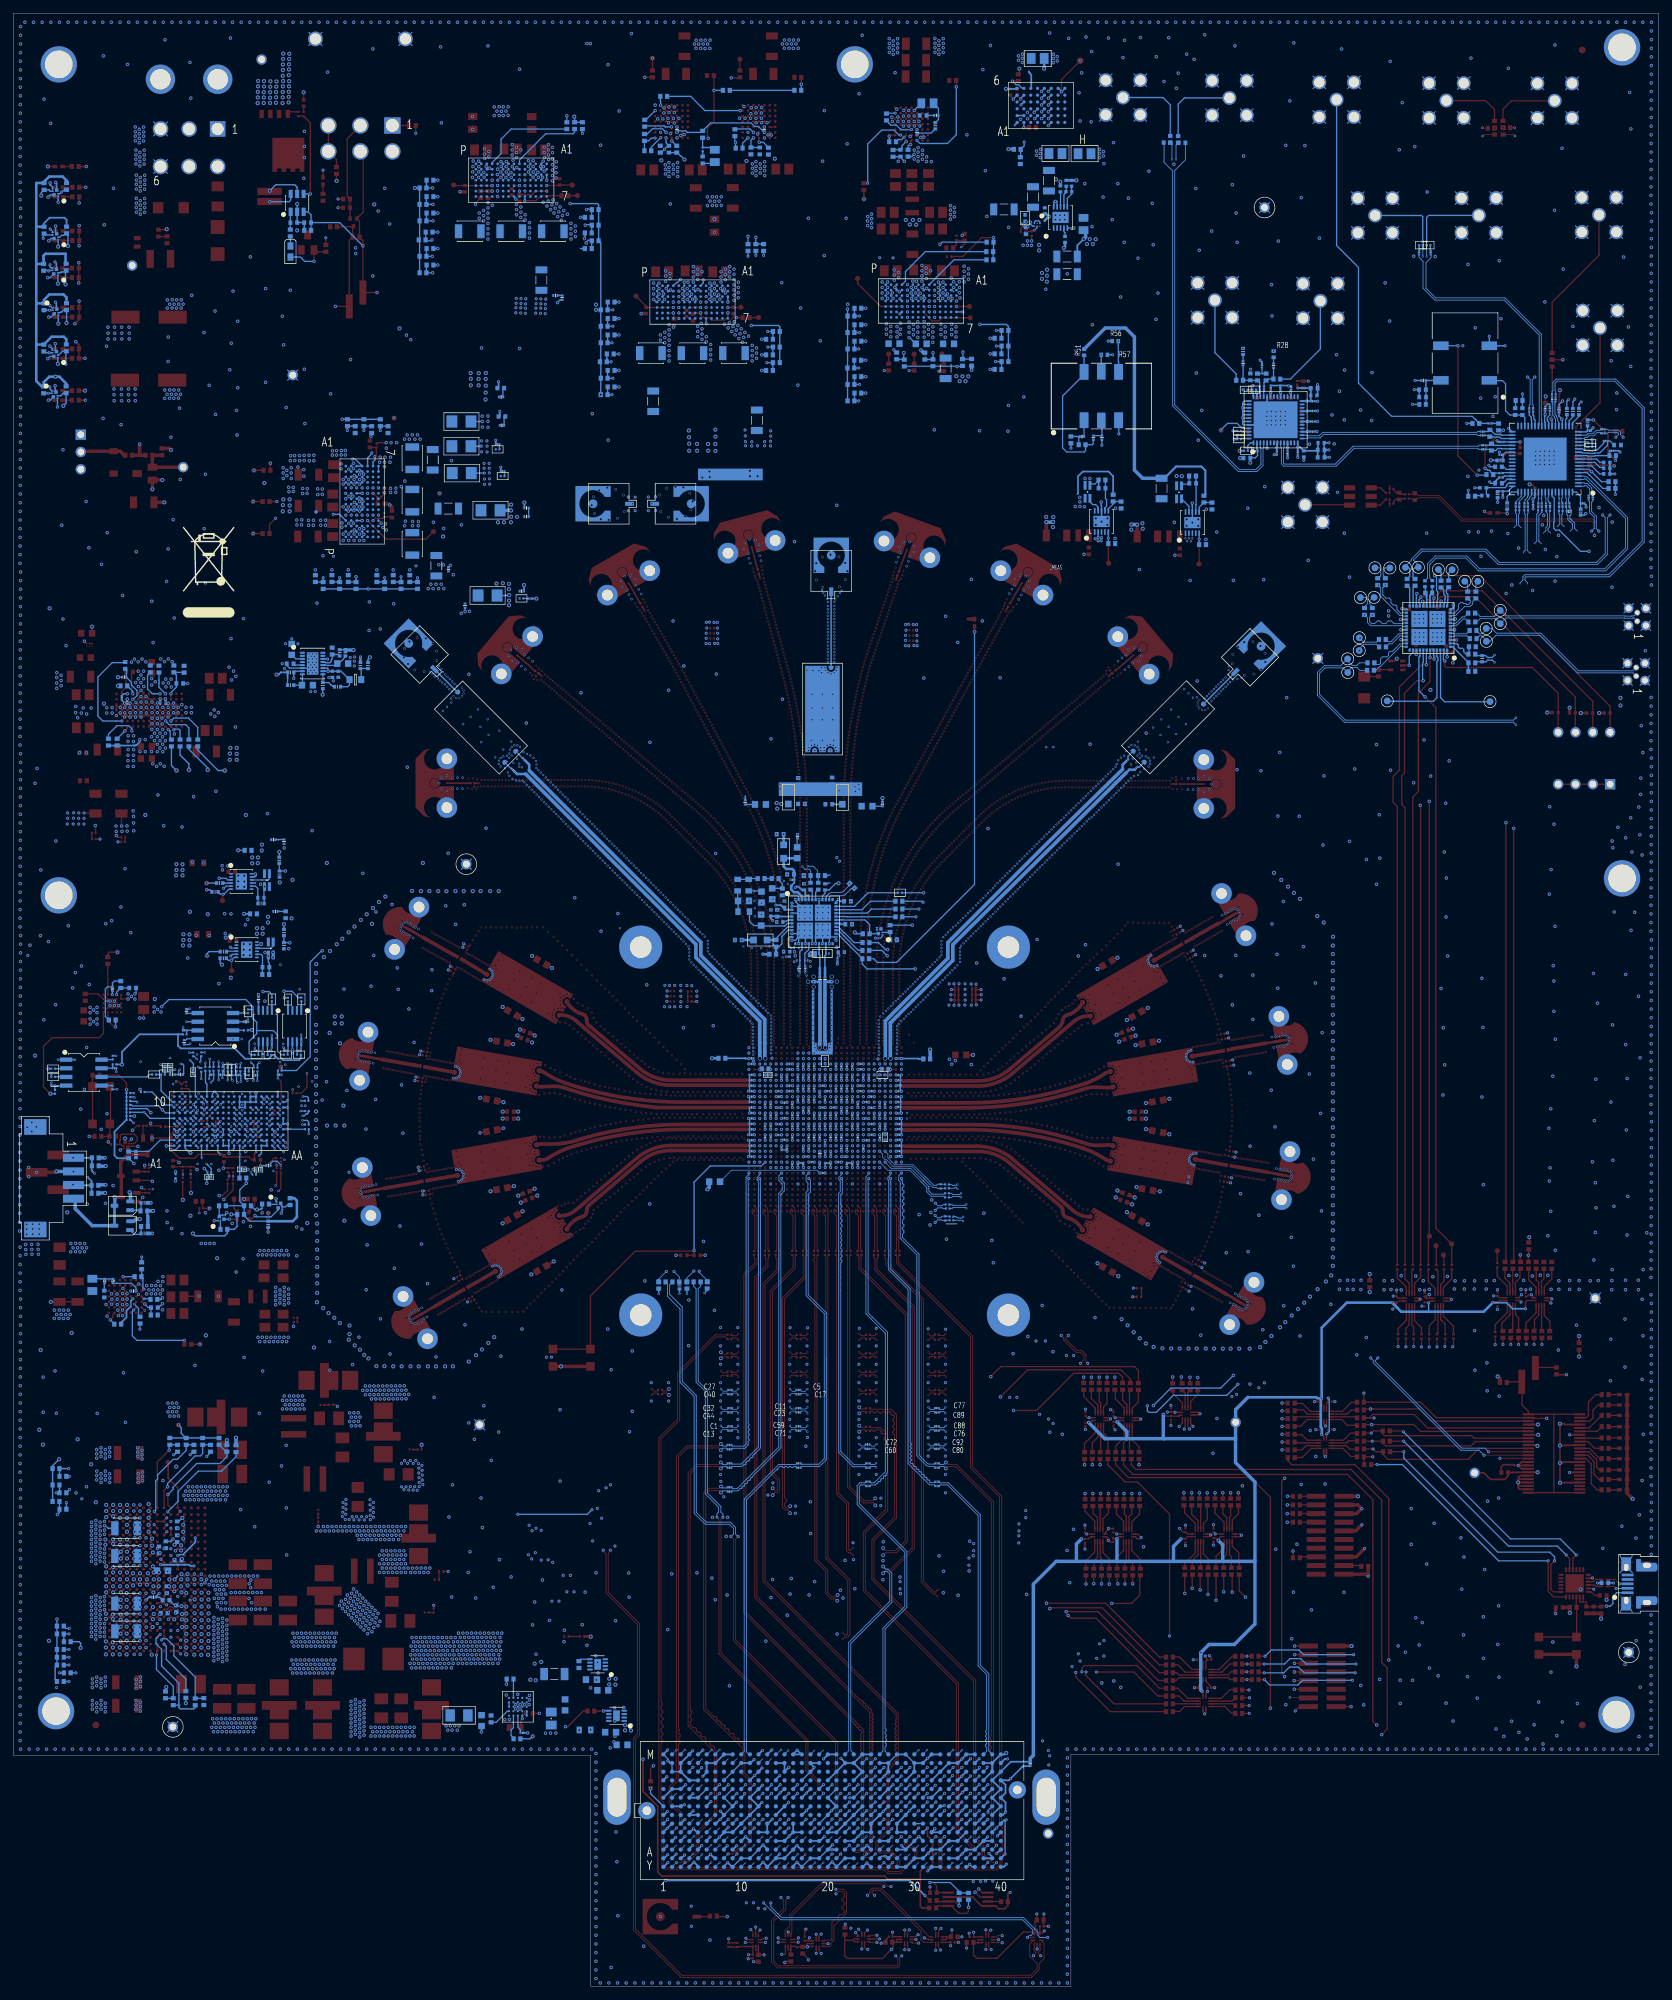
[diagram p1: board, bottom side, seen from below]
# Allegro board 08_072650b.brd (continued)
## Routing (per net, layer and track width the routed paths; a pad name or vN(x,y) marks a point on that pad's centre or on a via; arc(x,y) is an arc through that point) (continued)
DACA2_N: length 31.5
  TOP w0.381: U1A.AJ16 111.1,125.72 111.04,125.66
  TOP w0.546: T1YA.2 80.37,121.07 arc(80.78,121.16) 81.16,121.35 arc(82.73,122.26) 84.41,122.95 arc(92.78,125) 101.37,125.68 107.57,125.65 110.13,125.65 arc(110.26,125.65) 110.4,125.65 110.9,125.67 arc(110.97,125.67) 111.04,125.66
DACA2_P: length 31.5
  TOP w0.546: U1A.AJ15 111,126.43 110.46,126.43 arc(110.43,126.43) 110.41,126.43 100.35,126.43 arc(92.42,125.78) 84.69,123.87 83.99,123.64 arc(83.12,123.44) 82.23,123.39 80.77,123.45 arc(80.37,123.43) T1YA.3
DACA3_N: length 31.2
  TOP w0.546: U1A.AJ19 111.04,123.27 100,123.27 arc(98.88,123.19) 97.78,122.95 arc(96.2,122.32) 94.78,121.36 87.19,114.93 arc(87.13,114.87) 87.07,114.81 86.53,114.35 85.79,113.73 arc(84.64,113.09) T1ZA.3
DACA3_P: length 31.3
  TOP w0.381: 111.13,122.45 111.1,122.48 U1A.AJ20
  TOP w0.546: T1ZA.2 arc(85.25,111.92) 86.27,112.63 86.3,112.63 86.88,112.82 arc(87.23,113.07) 87.4,113.46 87.46,113.99 arc(87.52,114.2) 87.66,114.37 95.25,120.81 arc(97.39,122.07) 99.83,122.5 110.67,122.5 arc(110.9,122.49) 111.13,122.45
DACB0_N: length 31.4
  TOP w0.546: U1A.A8 133.59,132.22 144.9,132.22 arc(147.59,132.7) 149.95,134.08 157.54,140.52 arc(157.6,140.58) 157.66,140.64 158.2,141.09 158.94,141.72 arc(160.09,142.36) T1WB.3
DACB0_P: length 31.3
  TOP w0.546: T1WB.2 160.25,144.5 arc(159.48,143.52) 158.45,142.82 158.43,142.81 157.85,142.62 arc(157.5,142.38) 157.33,141.98 157.27,141.45 arc(157.21,141.24) 157.07,141.07 149.48,134.63 arc(147.34,133.38) 144.9,132.94 133.51,132.94 U1A.A7
DACB1_N: length 31.6
  TOP w0.546: U1A.A11 133.51,129.74 143.38,129.74 arc(151.96,130.43) 160.32,132.5 arc(162,133.19) 163.57,134.1 arc(163.95,134.29) T1XB.2
DACB1_P: length 31.6
  TOP w0.546: U1A.A12 147.06,128.93 arc(147.1,128.93) 147.14,128.94 147.79,129.04 arc(154.25,130.08) 160.55,131.81 arc(161.42,132.02) 162.31,132.06 163.96,131.99 arc(164.36,132.02) T1XB.3
DACB2_N: length 31.6
  TOP w0.198: U1A.A16 133.66,125.73
  TOP w0.546: 133.66,125.73 143.06,125.73 arc(150.82,125.17) 158.41,123.49 159.22,123.25 arc(161.18,122.52) 163,121.49 arc(163.3,121.35) 163.62,121.27 164.35,121.21 arc(164.35,121.21) T1YB.3
DACB2_P: length 31.6
  TOP w0.546: U1A.A15 133.58,126.45 143.4,126.45 arc(147.74,126.27) 152.06,125.73 arc(152.08,125.73) 152.11,125.72 arc(155.54,125.03) 158.91,124.1 arc(160.18,123.79) 161.47,123.62 arc(162.68,123.57) 163.9,123.59 163.96,123.59 arc(164.36,123.57) T1YB.2
DACB3_N: length 31.4
  TOP w0.546: U1A.A19 133.54,123.37 144.9,123.37 arc(147.59,122.89) 149.95,121.5 157.54,115.07 arc(157.6,115.01) 157.66,114.95 158.2,114.49 158.94,113.87 arc(160.09,113.23) T1ZB.2
DACB3_P: length 31.3
  TOP w0.198: 133.6,122.59 133.54,122.53 U1A.A20
  TOP w0.546: T1ZB.3 160.25,111.09 arc(159.48,112.06) 158.45,112.77 158.43,112.77 157.85,112.96 arc(157.5,113.21) 157.33,113.6 157.27,114.13 arc(157.21,114.34) 157.07,114.51 149.48,120.95 arc(147.34,122.21) 144.9,122.64 134.06,122.64 arc(133.83,122.63) 133.6,122.59
DUT_CSB: length 119.7
  TOP w0.191: R176.2 v4(60.38,47.29) R177.1
  L24_SIGNAL w0.114: v4(121.5,123.33) 121.1,123.73 121.1,124.29 120.87,124.53 118.11,124.53 118.11,124.56 117.9,124.76 117.9,126.85 117.82,126.93 103.97,126.93 95.61,118.57 95.61,116.26 81.33,101.98 81.33,96.55 73.23,88.46 73.23,60.15 v4(60.38,47.29)
DUT_CSB_FMC: length 85.2
  TOP w0.191: 72.26,47.17 73.25,47.17 81.64,55.55 89.2,55.55 v1(89.33,55.42)
  L5_MIXED w0.114: v1(89.33,55.42) 120.7,55.42 135.94,40.18 135.94,32.79 136.53,32.21 v4(136.53,29.59)
  BOTTOM w0.191: P1.H8 v4(136.53,29.59)
DUT_CSB_HDR: length 17.9
  TOP w0.191: P2.5 47.19,47.29 v4(44.4,47.29) ; R176.1 v4(57.86,47.29)
  BOTTOM w0.191: v4(57.86,47.29) 54.86,47.29 54.08,48.08 52.5,48.08 51.71,47.29 v4(44.4,47.29)
DUT_SCLK: length 120
  TOP w0.191: R180.2 v4(60.4,48.44) R181.1
  L24_SIGNAL w0.114: v4(120.7,123.33) 120.3,123.73 117.3,123.73 117.09,123.93 117.09,123.96 117.1,123.96 117.1,125.9 116.87,126.13 104.41,126.13 97.08,118.8 97.08,116.66 81.97,101.55 81.97,96.75 73.54,88.33 73.54,59.73 60.53,46.71 60.15,46.71 59.92,46.94 59.92,47.96 v4(60.4,48.44)
DUT_SCLK_FMC: length 86.4
  TOP w0.191: v1(89.81,56.21) 81.13,56.21 73.23,48.31 72.26,48.31
  L5_MIXED w0.114: v1(89.81,56.21) 90.17,55.86 121.18,55.86 137.29,39.75 137.29,33.58 137.79,33.07 v4(137.79,29.59)
  BOTTOM w0.191: P1.H7 v4(137.79,29.59)
DUT_SCLK_HDR: length 17.2
  TOP w0.191: R180.1 v4(57.73,48.44) ; v4(44.73,48.67) P2.3
  BOTTOM w0.191: v4(57.73,48.44) 56.82,49.35 52.76,49.35 52.07,48.67 v4(44.73,48.67)
DUT_SDIO: length 114.9
  TOP w0.191: R174.1 v4(60.43,46.15) R173.2
  L24_SIGNAL w0.108: 119.89,121.33 119.78,121.33 119.61,121.33 118.81,120.53 113.34,120.53 103.33,120.53
  L24_SIGNAL w0.114: 103.33,120.53 84.63,101.83 84.63,96.77 77.28,89.42 77.28,85.96 74.62,83.3 74.62,60.34 v4(60.43,46.15) ; 119.89,121.33 120.07,121.34 120.3,121.56 120.3,121.9 120.54,122.13 120.87,122.13 121.67,122.13 121.9,122.36 121.9,122.7 122.14,122.93 122.7,122.93 v4(123.1,123.33)
DUT_SDIO_FMC: length 85.2
  TOP w0.191: v1(86.93,54.98) 82.23,54.98 73.28,46.02 72.26,46.02
  L5_MIXED w0.114: v4(135.25,28.32) 135.25,29.64 134.21,30.68 134.21,40.51 120.17,54.56 87.35,54.56
  L5_MIXED w0.133: 87.35,54.56 v1(86.93,54.98)
  BOTTOM w0.191: P1.G9 v4(135.25,28.32)
DUT_SDIO_HDR: length 17.8
  TOP w0.191: v4(44.5,46) 44.63,46.13 P2.7 ; v4(57.86,46) 58.54,46 R173.1
  BOTTOM w0.191: v4(57.86,46) 54.99,46 54.15,46.84 52.83,46.84 51.99,46 v4(44.5,46)
DUT_SDO: length 117.6
  TOP w0.191: R171.1 v4(60.4,45.01) R170.2
  L24_SIGNAL w0.114: v4(123.9,123.33) 123.5,122.93 123.5,122.26 123.37,122.13 122.94,122.13 122.7,121.89 122.7,119.96 122.47,119.73 103.17,119.73 85.01,101.57 85.01,96.04 79.17,90.2 79.17,87.38 74.93,83.14 74.93,60.21 60.91,46.19 60.91,45.52 v4(60.4,45.01)
DUT_SDO_FMC: length 84.5
  TOP w0.191: 72.26,44.88 73.41,44.88 82.55,54.02 86.25,54.02 v1(86.64,54.42)
  L5_MIXED w0.114: v4(134.11,28.3) 134.11,28.45 134.47,28.81 134.47,29.81 133.65,30.63 133.65,40.23 119.74,54.15 86.9,54.15 v1(86.64,54.42)
  BOTTOM w0.191: v4(134.11,28.3) 134.11,28.19 P1.G10
DUT_SDO_HDR: length 16.8
  TOP w0.191: v4(44.91,44.91) 47.24,44.91 P2.9 ; R170.1 v4(57.84,45.01)
  BOTTOM w0.191: v4(44.91,44.91) 52.22,44.91 52.91,44.22 57.05,44.22 v4(57.84,45.01)
EXT_3P3V: length 23.2
  TOP w0.508: Q18.3 221.89,122.05 224.61,122.05 225.71,120.95 Q13.3 225.63,118.82 Q22.3 226.57,115.77 v3(226.59,115.8)
  BOTTOM w0.406: Q15.3 Q14.3
  BOTTOM w0.508: Q14.3 226.57,114.58 226.57,115.77 v3(226.59,115.8) ; P5.4 232.38,115.31 232.38,114.1 229.9,111.61 Q15.3
EXT_CLK: length 6.5
  TOP w0.191: T4.3 45.38,217.37 REFCLK.1
EXT_REF: length 64.4
  BOTTOM w0.191: C213.1 R2.1 26.69,229.71 26.69,229.8 26.86,229.97 26.95,229.97 27.34,230.35 39.14,230.35 44.02,235.23 44.02,252.2 47.23,255.41 EXT_HMCREF.1
EXT_SYNC: length 20.6
  TOP w0.191: EXT_SYNC.1 8.56,243.32 8.56,232.36 12.1,228.82 R7.2
FAN_PWM: length 7.7
  TOP w0.191: 221.06,224.65 R337.1 221.06,224.63
  TOP w0.508: R61.2 221.06,224.65 ; 221.06,224.63 Q17.1 FANPWM.1
FMC_3P3V: length 183.4
  TOP w0.178: v4(128.68,4.7) 128.17,4.7 128.14,4.68 ; C256.1 v4(103.89,5.97) ; v4(90.14,8.13) 90.5,7.77 U14.6 ; C260.1 v4(112.42,7.95) ; C250.1 v4(100.5,7.93) ; C251.1 v4(133.56,4.65)
  TOP w0.191: v4(117.83,7.9) 117.53,7.59 U16.6 ; v4(124.61,7.14) 124.66,7.09 124.66,6.98 124.76,6.88 124.76,6.67 ; U12.6 99.31,7.26 C250.1 ; U19.6 124.76,6.67 ; 124.76,6.67 125.3,6.67 C261.1 ; C256.1 103.89,6.46 U15.6 ; U14.6 90.79,8.79 C254.1 ; U17.6 128.14,5.87 128.14,4.68 ; C260.1 112.42,7.28 U18.6 ; 132.92,5.84 C251.1
  TOP w0.203: U13.6 135.12,5.84 C257.1 135.94,5.75 135.97,5.78 C258.1
  TOP w0.254: v3(17.73,75.43) U35.31 21.39,75.43 21.43,75.39 C605.1 22.06,74.89 22.56,74.38 24.64,74.38 25.59,75.34 UNK3P3V.1 ; R458.2 14.9,89.74 v4(13.49,89.74) ; U35.18 12.97,75.43 v4(13.02,75.38) ; U35.42 19.08,80.92 v3(17.64,80.92) ; U35.7 v4(13.02,80.93)
  L7_POWER w0.254: v4(13.02,80.93) v4(13.02,75.38) ; v4(13.02,80.93) 13.04,80.92 v3(17.64,80.92) 17.7,80.92 17.21,80.43 17.21,79.65 17.12,79.56 17.12,79.04 17.21,78.94 17.21,77.29 17.12,77.19 17.12,76.67 17.21,76.58 17.21,75.79 17.58,75.43 v3(17.73,75.43) ; v4(13.02,80.93) 13.02,89.27 v4(13.49,89.74)
  L14_POWER w0.508: UNK3P3V.1 26.97,48.64 39.7,35.92 84.91,35.92 86.74,37.74 93.42,37.74 94.41,36.75 94.41,32.74 95.89,31.27 95.89,27.18 94.79,26.09 94.79,25.37 v4(95.73,24.43)
  BOTTOM w0.178: v4(97.16,23.24) P1.D40
  BOTTOM w0.191: v4(95.73,24.43) 95.89,24.28 v4(95.89,19.43)
  BOTTOM w0.254: P1.C39 v4(97.16,23.24) ; P1.Z40 v4(95.89,19.43) ; P1.D36 v4(100.97,24.51) ; P1.D38 v4(98.42,24.51) ; P1.D40 95.96,24.43 v4(95.73,24.43)
FMC_3P3VAUX: length 21.3
  TOP w0.191: v4(106.96,15.24) 106.43,15.24 105.93,14.74 C141.1 105.92,13.75 U20.8
  L5_MIXED w0.133: v4(106.04,24.51) 106.55,24.51 106.78,24.28 106.78,19.83 106.69,19.74 106.69,19.33 106.73,19.28 106.73,15.47 v4(106.96,15.24)
  BOTTOM w0.191: R712.1 R711.1 102.64,13.94 103.94,15.24 v4(106.96,15.24) ; P1.D32 v4(106.04,24.51)
FMC_12P0V: length 7.3
  L5_MIXED w0.254: v4(102.24,23.24) v4(99.69,23.24)
  BOTTOM w0.254: P1.L37 v4(99.69,33.4) ; v4(95.55,33.38) 95.91,33.38 P1.L40 ; P1.C37 v4(99.69,23.24) ; P1.C35 v4(102.24,23.24) ; P1.L36 v4(100.97,33.4)
FMC_GA0: length 17.9
  TOP w0.191: U20.2 99.59,13.1 v1(100.3,13.82)
  L5_MIXED w0.114: v1(100.3,13.82) 100.3,14.67 100.19,14.79 99.56,14.79 99.55,14.79 97.65,14.79 97.2,15.24 97.2,15.94 100.27,19.01 100.27,19.84 103.02,22.59 103.02,22.75 v4(103.5,23.24)
  BOTTOM w0.191: P1.C34 v4(103.5,23.24)
FMC_GA1: length 19.4
  TOP w0.191: U20.1 99.25,13.75 v1(99.77,14.27)
  L5_MIXED w0.114: v1(99.77,14.27) 97.51,14.27 96.44,15.34 96.44,16.71 97.76,18.03 97.76,19.93 98.02,20.19 100,20.19 102.72,22.92 102.72,24.02 v4(102.24,24.51)
  BOTTOM w0.191: P1.D35 v4(102.24,24.51)
FMC_SCL: length 221.9
  TOP w0.191: v4(107.65,13.31) 106.95,12.62 R160.2
  L5_MIXED w0.254: v4(107.65,13.31) 107.87,13.54 107.87,22.53 v4(108.59,23.24) ; v1(145.72,15.54) 146.84,16.66 146.84,26.47 149.22,28.85 149.22,32.6 149.92,33.3 154.2,33.3 156.39,35.48 198.65,35.48 203.89,40.72 203.89,59.72 207.34,63.17 207.34,71.75 209.75,74.17 218.19,74.17 221.47,77.46 221.47,83.25 228.96,90.73 228.96,117.25 228.6,117.6 v1(227.91,117.6)
  BOTTOM w0.191: P1.C30 v4(108.59,23.24)
  BOTTOM w0.254: v1(145.72,15.54) 109.88,15.54 v4(107.65,13.31)
  BOTTOM w0.508: v1(227.91,117.6) 228.91,117.6 R433.2
FMC_SDA: length 228.3
  TOP w0.254: 108.33,15.72 108.33,11.76 108.08,11.51 R162.1 ; 108.33,15.72 113.11,15.72 113.56,16.18 146.26,16.18 146.88,16.79 146.88,26.44 149.04,28.61 v1(149.04,33.32) ; 108.33,15.72 108.33,16.92 107.8,17.45 106.91,17.45 106.52,17.84 106.52,21.3 107.31,22.1 v4(107.31,23.24)
  L5_MIXED w0.254: v1(149.04,33.32) 149.31,33.32 149.73,33.75 154.01,33.75 156.2,35.94 198.24,35.94 203.35,41.05 203.35,60.12 206.89,63.66 206.89,71.94 209.56,74.62 209.65,74.62 209.8,74.78 218.14,74.78 220.95,77.6 220.95,83.59 228.42,91.06 228.42,99.77 228.45,99.8 228.45,100.28 228.42,100.31 228.42,112.29 225.58,115.14 225.58,119.13 v1(228.02,121.56)
  BOTTOM w0.191: P1.C31 v4(107.31,23.24)
  BOTTOM w0.508: R434.2 v1(228.02,121.56)
FMC_VADJ: length 255.5
  TOP w0.191: C278.1 23.3,100.64 U47.1 ; U44.1 79.2,83.03 ; 19.51,100.42 19.3,100.63 U48.1 ; U45.1 38.11,100.56 C277.1 ; C686.1 64.94,65.78 v1(64.59,65.43) 64.59,65.61 64.21,65.99 U42.1 ; C690.1 33.8,100.35 v4(33.73,100.28) 33.47,100.54 33.07,100.54 U46.1 ; U29.1 69.09,65.99 C272.1 v4(70.06,65.67)
  TOP w0.198: U23.1 66.83,47.61 C269.1 67.15,48.44 ; U24.1 66.83,43.16 v4(67.01,43.33) ; U28.1 79.2,65.96 v4(79.48,65.68) 79.99,65.68 C681.1 ; U25.1 49.12,85.14 49.45,85.46 C270.1 ; C271.1 83.66,65.64 83.34,65.96 U27.1 ; v4(72.68,83.92) 72.54,83.92 72.28,83.66 C638.1 70.33,83.66 U41.1 ; C682.1 49.4,81.62 v4(49.4,80.98) 49.13,80.7 ; C687.1 79.46,82.82 v4(79.45,82.83) ; U43.1 83.26,82.73 v4(83.63,82.73) 83.65,82.71 C276.1
  TOP w0.203: 49.13,80.7 U26.1 ; v4(67.15,48.97) 67.15,48.44
  TOP w0.254: v4(19.51,99.42) 19.51,100.42 ; C270.1 v4(49.45,86.28) ; C271.1 v4(84.69,65.64) ; v4(79.45,82.83) 79.25,83.03 79.2,83.03 ; C683.1 67.04,43.37 v4(67.01,43.33)
  TOP w0.381: C278.1 v4(24.3,100.31) ; C277.1 38.51,100.31 v4(39.08,100.31)
  BOTTOM w0.203: 33.76,98.98 33.73,99.01 v4(33.73,100.28)
  BOTTOM w0.254: P1.E39 P1.F40 P1.G39 P1.H40 P1.J39 95.06,32.96 C691.1 ; v4(24.3,100.31) 22.28,100.31 21.39,99.42 v4(19.51,99.42)
  BOTTOM w0.381: v4(49.45,86.28) 49.56,86.18 49.56,82.05 49.4,81.9 v4(49.4,80.98) ; v4(49.45,86.28) 49.43,86.3 49.43,96.62 45.74,100.31 v4(39.08,100.31) 38.76,99.99 38.73,99.99 38.37,99.62 38.37,99.59 37.76,98.98 25.63,98.98 v4(24.3,100.31) ; v4(49.45,86.28) 50.07,86.28 50.21,86.42 60.25,86.42
  BOTTOM w0.508: 71.17,62.36 71.17,64.55 v4(70.06,65.67) ; 71.17,62.36 79.5,62.36 ; 71.17,62.36 63.88,62.36 ; 59.22,62.51 59.22,53.17 62.23,50.16 65.96,50.16 v4(67.15,48.97) 67.15,48.77 67.18,48.74 67.18,43.51 v4(67.01,43.33) ; 59.22,62.51 59.37,62.36 63.88,62.36 ; 59.22,62.51 59.22,74 62.07,76.85 62.07,80.35 ; 85.42,62.36 85.42,64.91 v4(84.69,65.64) ; 85.42,62.36 88.39,62.36 91.74,59 91.74,33.9 92.2,33.44 C691.1 ; 85.42,62.36 79.5,62.36 ; v4(79.45,82.83) 78.03,81.41 78.03,80.35 ; 72.56,80.35 72.68,80.48 v4(72.68,83.92) ; 72.56,80.35 62.07,80.35 ; 72.56,80.35 78.03,80.35 ; 62.07,80.35 62.07,82.74 UNK1P8V.1 62.05,84.62 60.25,86.42 ; 79.5,62.36 79.48,62.38 v4(79.48,65.68) ; 78.03,80.35 81.26,80.35 v4(83.63,82.73) ; 63.88,62.36 63.96,62.43 63.96,64.8 v1(64.59,65.43)
FPGA_REFCLK_0_N: length 298
  L22_MIXED w0.102: 140.34,24.51 140.85,25.02 140.85,25.17 140.28,25.74 138.89,25.74 136.92,27.7 136.92,31.91 137.21,32.2 137.21,37.19 130.53,43.87 94.54,43.87 83.98,54.43 54.86,54.43 53.37,55.93 36.99,55.93 18.29,74.63 18.29,84.81 15.37,87.73 15.37,98.52 16.54,99.69 16.54,102.46 14.35,104.65 14.35,120.85 17.79,124.29 17.79,211.35 17.48,211.66 17.16,211.66
  BOTTOM w0.127: P1.D5 140.34,24.51
  BOTTOM w0.133: 17.16,211.66 17.55,212.04 17.55,215.83 17.1,216.28 R389.2 17.1,217.04 C555.2
FPGA_REFCLK_0_P: length 297.6
  L22_MIXED w0.102: 141.6,24.51 141.09,25.02 141.09,25.27 140.38,25.98 138.99,25.98 137.17,27.81 137.17,31.81 137.46,32.1 137.46,37.29 130.63,44.11 94.65,44.11 84.08,54.68 54.97,54.68 53.47,56.18 37.09,56.18 18.54,74.73 18.54,84.91 15.61,87.83 15.61,98.42 16.78,99.59 16.78,102.57 14.6,104.75 14.6,120.75 18.03,124.19 18.03,211.56 18.14,211.66 18.24,211.66
  BOTTOM w0.127: P1.D4 141.6,24.51
  BOTTOM w0.133: 18.24,211.66 17.86,212.04 17.86,216 17.64,216.21 R389.1 17.64,217.04 C554.2
FPGA_REFCLK_1_N: length 312.2
  L22_MIXED w0.102: 15.82,213.21 16.23,213.62 16.23,214.35 15.72,214.86 11.89,214.86 10.92,213.89 10.92,212.27 9.75,211.1 9.75,188.7 10.92,187.53 10.92,172.14 11.63,171.42 11.63,152.97 10.92,152.25 10.92,100.13 9.19,98.4 9.19,72.85 13.39,68.66 17.07,68.66 21.95,63.78 21.95,48.28 26.79,43.43 44.22,43.43 48.41,39.24 115.62,39.24 118.12,36.75 118.12,26.79 118.41,26.49 122.78,26.49 123.24,26.03 123.24,21.82 122.73,21.31 121.66,21.31 121.59,21.24 120.98,21.24 120.55,21.67 120.55,21.91 120.5,21.97 120.02,21.97
  BOTTOM w0.127: P1.B21 120.02,21.97
  BOTTOM w0.133: 15.82,213.21 16.2,213.59 16.2,213.9 15.95,214.14 15.95,216.44 R390.2 15.91,217.11 15.9,217.12 C557.2
FPGA_REFCLK_1_P: length 312.1
  L22_MIXED w0.102: 121.28,21.97 121.24,22.02 120.9,22.02 120.8,21.91 120.8,21.77 121.08,21.49 121.49,21.49 121.56,21.56 122.63,21.56 122.99,21.92 122.99,25.93 122.68,26.24 118.31,26.24 117.87,26.69 117.87,36.65 115.52,39 48.31,39 44.12,43.19 26.69,43.19 21.7,48.18 21.7,63.68 16.97,68.41 13.28,68.41 8.95,72.74 8.95,98.51 10.67,100.23 10.67,152.35 11.39,153.07 11.39,171.32 10.67,172.03 10.67,187.43 9.51,188.59 9.51,211.21 10.67,212.37 10.67,213.99 11.78,215.11 15.83,215.11 16.48,214.45 16.48,213.62 16.89,213.21
  BOTTOM w0.127: P1.B20 121.28,21.97
  BOTTOM w0.133: C556.2 16.48,216.52 R390.1 16.45,216.25 16.27,216.07 16.27,214.27 16.51,214.03 16.51,213.59 16.89,213.21
FPGA_REFCLK_2_N: length 287.9
  L22_MIXED w0.102: 11.89,213.51 12.3,213.1 12.3,203.68 13.49,202.49 13.49,186.26 13.18,185.95 13.18,173.81 12.3,172.93 12.3,99.88 10.34,97.92 10.34,74.02 14.94,69.42 17.61,69.42 23.09,63.94 23.09,60.58 31.24,52.43 52.41,52.43 52.96,51.87 69.14,51.87 80.39,40.62 126.9,40.62 130.69,36.83 130.69,33.91 130.18,33.4
  BOTTOM w0.127: P1.L13 130.18,33.4
  BOTTOM w0.133: 11.89,213.51 12.29,213.91 12.29,214.7 12.76,215.16 12.77,215.17 12.79,215.18 12.83,215.2 12.9,215.27 12.91,215.27 12.98,215.34 12.98,215.77 12.81,215.93 R391.2 12.81,216.66 13.06,216.9 C559.2
FPGA_REFCLK_2_P: length 287.8
  L22_MIXED w0.102: 131.44,33.4 130.93,33.91 130.93,36.93 127,40.87 80.49,40.87 69.25,52.11 53.07,52.11 52.51,52.67 31.34,52.67 23.34,60.68 23.34,64.04 17.71,69.67 15.04,69.67 10.59,74.12 10.59,97.81 12.55,99.78 12.55,172.77 13.43,173.65 13.43,185.85 13.74,186.16 13.74,202.59 12.55,203.78 12.55,213.1 12.95,213.51
  BOTTOM w0.127: P1.L12 131.44,33.4
  BOTTOM w0.133: 12.95,213.51 12.6,213.86 12.6,214.57 12.93,214.89 12.94,214.9 12.95,214.91 12.99,214.92 13.03,214.96 13.04,214.96 13.29,215.21 13.29,215.77 13.45,215.93 R391.1 13.45,216.75 13.49,216.79 13.49,216.98 C558.2
FPGA_REFCLK_3_N: length 289.4
  L22_MIXED w0.102: 13.79,214.15 13.79,213.42 13.49,213.13 13.49,209.55 16.95,206.09 16.95,176 13.49,172.54 13.49,91.67 11.77,89.95 11.77,74.55 15.78,70.54 18.06,70.54 34.1,54.5 53.6,54.5 54.57,53.53 82.75,53.53 93.71,42.57 127.97,42.57 135.77,34.77 135.77,33.91 135.25,33.4
  BOTTOM w0.127: P1.L9 135.25,33.4
  BOTTOM w0.133: C561.2 14.06,217.04 R392.2 14.06,216 14.17,215.89 14.17,214.53 13.79,214.15
FPGA_REFCLK_3_P: length 289.7
  L22_MIXED w0.102: 136.53,33.4 136.01,33.91 136.01,34.87 128.07,42.82 93.81,42.82 82.85,53.78 54.67,53.78 53.7,54.74 34.2,54.74 18.16,70.78 15.88,70.78 12.01,74.65 12.01,89.84 13.74,91.57 13.74,172.44 17.2,175.89 17.2,206.2 13.74,209.65 13.74,213.03 14.86,214.15
  BOTTOM w0.127: P1.L8 136.53,33.4
  BOTTOM w0.133: C560.2 14.6,217.04 R392.1 14.6,216 14.48,215.89 14.48,214.53 14.86,214.15
FPGA_REFCLK_4_N: length 332.7
  L22_MIXED w0.102: 140.34,33.4 140.82,33.88 140.82,41.84 135.3,47.35 100.68,47.35 100.31,47.73 100.28,47.73 90.08,57.92 73.86,57.92 72.46,59.32 40.07,59.32 22.31,77.09 22.31,91.26 24.76,93.72 24.76,96.22 22.98,98 22.98,190 19.61,193.38 19.61,205.37 19.23,205.74
  BOTTOM w0.127: P1.L5 140.34,33.4
  BOTTOM w0.133: C563.2 15.61,233.1 R393.2 15.61,233.97 15.47,234.11 15.47,235.35 15,235.82 6.26,235.82 2.08,231.64 2.08,211.88 7.15,206.81 19.44,206.81 19.58,206.67 19.58,206.29 19.23,205.95 19.23,205.74
FPGA_REFCLK_4_P: length 331.8
  L22_MIXED w0.102: 20.29,205.74 19.86,205.3 19.86,193.48 23.23,190.11 23.23,98.1 25.01,96.32 25.01,93.62 22.56,91.16 22.56,77.19 40.18,59.57 72.56,59.57 73.96,58.17 90.21,58.17 100.79,47.6 135.41,47.6 141.07,41.94 141.07,33.94 141.6,33.4
  BOTTOM w0.127: P1.L4 141.6,33.4
  BOTTOM w0.133: C562.2 15.07,233.1 R393.1 15.07,234.03 15.16,234.12 15.16,235.22 14.87,235.51 6.39,235.51 2.39,231.51 2.39,212.01 7.28,207.12 19.57,207.12 19.89,206.8 19.89,206.32 20.29,205.92 20.29,205.74
FPGA_REFCLK_5_N: length 318.2
  TOP w0.133: v4(5.17,227.28) 5.17,228 R715.2
  L22_MIXED w0.102: v4(120.02,19.43) 120.53,19.94 120.53,20.09 119.14,21.47 119.14,21.48 118.09,22.53 118.09,24.74 116.62,26.21 116.62,29.39 115.92,30.08 112.01,30.08 111.52,30.57 111.52,32.66 106.83,37.34 43.94,37.34 41.71,39.58 25.62,39.58 18.49,46.71 18.49,63.71 16.2,66 12.22,66 5.74,72.47 5.74,151.94 9.71,155.91 9.71,169.31 5.74,173.28 5.74,185.62 7.23,187.1 7.31,187.1 7.41,187.21 7.41,210.06 3.96,213.5 3.96,225.07 4.95,226.05 5.36,226.05 5.54,226.24 5.54,226.91 v4(5.17,227.28)
  BOTTOM w0.127: P1.Z21 v4(120.02,19.43)
  BOTTOM w0.133: C567.2 7.46,228.45 7.32,228.31 5.87,228.31 5.55,228 5.55,227.66 v4(5.17,227.28)
FPGA_REFCLK_5_P: length 317.7
  TOP w0.133: R715.1 6.25,228.07 v4(6.25,227.28)
  L22_MIXED w0.102: v4(121.28,19.43) 120.77,19.94 120.77,20.19 119.39,21.58 119.39,21.58 118.34,22.63 118.34,24.84 116.87,26.31 116.87,29.49 116.03,30.33 112.12,30.33 111.77,30.68 111.77,32.76 106.93,37.59 44.04,37.59 41.81,39.83 25.72,39.83 18.74,46.81 18.74,63.81 16.31,66.24 12.32,66.24 5.99,72.57 5.99,151.84 9.96,155.8 9.96,169.41 5.99,173.38 5.99,185.52 7.33,186.86 7.41,186.86 7.65,187.1 7.65,210.16 4.21,213.6 4.21,224.97 5.05,225.81 5.46,225.81 5.79,226.14 5.79,226.82 v4(6.25,227.28)
  BOTTOM w0.127: P1.Z20 v4(121.28,19.43)
  BOTTOM w0.133: C566.2 7.46,227.86 7.32,228 6,228 5.86,227.87 5.86,227.66 v4(6.25,227.28)
GPIO0: length 116.1
  TOP w0.191: R178.1 v4(60.1,43.48)
  L22_MIXED w0.114: v4(62.61,86.54) 74.22,86.54 89.89,102.21 102.08,102.21 115.5,115.63 115.5,120.53 v4(115.9,120.93)
  L24_SIGNAL w0.114: v4(60.1,43.48) 59.44,44.15 59.44,83.36 v4(62.61,86.54)
GPIO0_FMC: length 51.4
  TOP w0.191: 72.26,43.74 73.22,43.74 76.55,47.07 84.25,47.07 84.63,46.69 v4(84.63,46.15)
  L5_MIXED w0.114: v4(114.94,32.13) 101.78,45.28 85.5,45.28 v4(84.63,46.15)
  BOTTOM w0.191: 115.57,31.5 v4(114.94,32.13)
GPIO1: length 117.2
  TOP w0.191: R172.1 v4(60.02,42.34)
  L22_MIXED w0.114: v4(115.1,120.93) 115.1,120.92 114.7,120.52 114.7,115.95 101.52,102.77 89.79,102.77 74.07,87.05 62.1,87.05 v4(61.91,86.86)
  L24_SIGNAL w0.114: v4(61.91,86.86) 59,83.95 59,43.36 v4(60.02,42.34)
GPIO1_FMC: length 49.6
  TOP w0.191: v4(82.49,46.12) 76.98,46.12 73.46,42.6 73.18,42.6 73.18,42.6 73.17,42.6 72.26,42.6
  L5_MIXED w0.114: v4(113.66,32.13) 113.66,32.28 101.29,44.65 84.05,44.65 82.58,46.12 v4(82.49,46.12)
  BOTTOM w0.191: 114.3,31.5 v4(113.66,32.13)
GPIO2: length 119.6
  TOP w0.191: R175.1 v4(60.07,41.2)
  L22_MIXED w0.114: v4(58.65,87.83) 74.23,87.83 89.83,103.43 101.52,103.43 113.9,115.81 113.9,119.73 v4(114.3,120.13)
  L24_SIGNAL w0.114: v4(60.07,41.2) 58.65,42.62 v4(58.65,87.83)
GPIO2_FMC: length 57.4
  TOP w0.191: v4(84.02,46.13) 84.02,45.6 79.88,41.45 72.26,41.45
  L5_MIXED w0.114: v4(116.21,30.86) 116.74,31.39 116.74,35.06 105.37,46.44 85.87,46.44 85.57,46.74 84.14,46.74 84.02,46.62 v4(84.02,46.13)
  BOTTOM w0.191: P1.J24 v4(116.21,30.86)
GPIO3: length 122.6
  TOP w0.191: R179.1 v4(60.05,40.06)
  L22_MIXED w0.114: v4(57.84,88.54) 59.94,90.65 73.99,90.65 87.93,104.6 100.99,104.6 112.34,115.95 112.34,118.32 111.94,118.73 111.94,120.19 112.7,120.96 v4(112.7,121.73)
  L24_SIGNAL w0.114: v4(57.84,88.54) 57.84,88.41 58.25,88 58.25,47.47 58.26,47.46 58.26,47.13 58.25,47.12 58.25,46.18 58.26,46.17 58.26,45.83 58.25,45.82 58.25,41.85 v4(60.05,40.06)
GPIO3_FMC: length 56.1
  TOP w0.191: v4(85.52,46.05) 85.52,45.4 80.43,40.31 72.26,40.31
  L5_MIXED w0.114: v4(85.52,46.05) 85.97,45.6 105.16,45.6 115.62,35.14 115.62,31.55 v4(114.94,30.86)
  BOTTOM w0.191: P1.J25 v4(114.94,30.86)
GPIO4: length 188
  TOP w0.191: v1(16.38,83.34) 18.11,83.34 18.15,83.37 18.98,83.37 19.03,83.41 U35.47 32.58,83.43 34.85,85.7 42.61,85.7 42.62,85.7 R191.1 43.23,85.7 v4(43.23,87.05) ; P2.15 v1(45.11,41.05)
  L5_MIXED w0.114: v1(16.38,83.34) 16.38,71.63 26.62,61.39 26.62,47.98 34.16,40.44 44.5,40.44 v1(45.11,41.05)
  L24_SIGNAL w0.108: 108.43,123.75 114.66,123.75
  L24_SIGNAL w0.114: 114.66,123.75 114.68,123.75 v4(115.1,123.33) ; v1(74.12,85.22) 74.12,87.29 83.77,96.94 83.77,102.11 105.41,123.75 108.43,123.75 ; v1(62.38,89.64) 61.75,89.64
  L24_SIGNAL w0.191: 61.75,89.64 61.65,89.74 45.92,89.74 v4(43.23,87.05)
  BOTTOM w0.191: v1(74.12,85.22) 71.55,87.78 64.24,87.78 v1(62.38,89.64)
GPIO4_FMC: length 112.4
  TOP w0.191: R232.2 v1(55.24,85.58)
  L5_MIXED w0.114: v4(118.75,27.05) 119.23,27.54 119.23,29.79 119.06,29.97 119.06,33.79 119.05,33.8 119.05,43.29 113.09,49.25 103.59,49.25 103.58,49.26 85.37,49.26 85.34,49.28 83.48,49.28 83,49.76 81.83,49.76 81.82,49.77 80.38,49.77 74.6,55.55 63.4,55.55 60.15,58.8 60.15,80.67 v1(55.24,85.58)
  BOTTOM w0.191: P1.F22 v4(118.75,27.05)
GPIO5: length 170.6
  TOP w0.191: P2.2 v1(53.39,49.94) ; U35.46 33.35,82.93 35.13,84.71 v1(42.24,84.71) 43.08,84.71 R182.1
  L3_SIGNAL w0.114: v1(42.24,84.71) 44.37,82.58 44.37,75.29 41.99,72.9 41.99,53.54 45.12,50.41 45.23,50.41 45.51,50.13 45.51,50.02 45.59,49.94 v1(53.39,49.94)
  L22_MIXED w0.114: v1(42.24,84.71) 44.98,87.45 54.99,87.45 56.44,86 89.79,86 116.3,112.52 116.3,121.9 116.54,122.13 117.1,122.13 v4(117.5,121.73)
GPIO5_FMC: length 107.1
  TOP w0.191: R219.2 v1(55.24,84.43)
  L5_MIXED w0.114: v1(55.24,84.43) 59.77,79.9 59.77,56.92 61.85,54.84 74.3,54.84 80.13,49.01 82.28,49.01 84.05,47.24 85.22,47.24 85.47,47.49 106.1,47.49 117.46,36.12 117.46,30.54 116.99,30.07 116.99,29.39 117.04,29.33 117.04,28.45 117.47,28.02 v4(117.47,27.05)
  BOTTOM w0.191: P1.F23 v4(117.47,27.05)
GPIO6: length 177.1
  TOP w0.191: v4(41.73,83.39) 43.2,83.39 R197.1 42.26,83.42 42.26,83.61 41.95,83.92 35.86,83.92 33.87,81.93 U35.44 ; P2.4 v1(53.39,48.67)
  L3_SIGNAL w0.114: v4(41.73,83.39) 43.87,81.25 43.87,75.46 41.5,73.1 41.5,53.16 44.56,50.11 44.56,49.74 44.84,49.46 45.21,49.46 46,48.67 v1(53.39,48.67)
  L24_SIGNAL w0.108: v4(118.3,121.73) 118.22,121.73 117.83,121.33 107.65,121.33
  L24_SIGNAL w0.114: v4(41.73,83.39) 41.73,84.84 46.08,89.18 60.63,89.18 61.47,88.34 v4(61.72,88.34) ; v4(75.01,85.19) 75.01,87.73 84.15,96.88 84.15,101.85 103.63,121.33 107.65,121.33
  BOTTOM w0.191: v4(61.72,88.34) 63.35,86.72 71.2,86.72 73.69,84.23 74.82,84.23 75.01,84.42 v4(75.01,85.19)
GPIO6_FMC: length 118.2
  TOP w0.191: R211.2 v1(55.24,83.29)
  L3_SIGNAL w0.114: v4(81.38,50.74) 81.38,48.97 81.4,48.95 v4(81.4,48.46)
  L5_MIXED w0.114: v4(81.4,48.46) 81.31,48.55 79.47,48.55 73.55,54.47 61.69,54.47 59.45,56.7 59.45,79.08 v1(55.24,83.29) ; v4(120.02,25.78) 120.93,26.7 120.93,28.69 120.48,29.14 120.48,29.15 120.24,29.39 120.24,29.96 120.48,30.19 120.48,43.31 113.86,49.94 83.74,49.94 83.11,50.57 83.09,50.57 82.92,50.74 82.24,50.74 82.23,50.74 81.88,50.74 81.87,50.74 v4(81.38,50.74)
  BOTTOM w0.191: P1.E21 v4(120.02,25.78)
GPIO7: length 175.9
  TOP w0.191: P2.6 v1(53.42,47.4) ; R184.1 43.08,82.42 v1(42.09,82.42) 35.9,82.42 34.91,81.43 U35.43
  L3_SIGNAL w0.114: v1(53.42,47.4) 45.29,47.4 41.12,51.56 41.12,73.69 43.54,76.1 43.54,80.98 v1(42.09,82.42)
  L22_MIXED w0.114: v4(119.1,124.13) 118.7,123.73 118.47,123.73 118.47,123.73 113.7,123.73 113.1,123.13 113.1,120.47 112.93,120.29 112.93,119.67 113.23,119.36 113.23,118.03 112.88,117.67 112.88,115.52 101.35,103.99 89.94,103.99 76.12,90.17 60.05,90.17 57.94,88.06 43.28,88.06 41.05,85.83 41.05,82.8 41.43,82.42 v1(42.09,82.42)
GPIO7_FMC: length 117.8
  TOP w0.191: R207.2 v1(55.24,82.15)
  L3_SIGNAL w0.114: v4(82.03,50.25) 82.03,49.76 81.97,49.7 81.97,48.62 v4(82.45,48.13)
  L5_MIXED w0.114: v4(82.03,50.25) 82.98,50.25 83.64,49.6 85.47,49.6 85.49,49.58 113.39,49.58 119.38,43.59 119.38,38.75 119.39,38.74 119.39,30.43 119.58,30.25 119.58,29.45 120.5,28.52 120.5,27.74 118.75,25.98 v4(118.75,25.78) ; v4(82.45,48.13) 81.83,47.52 80.02,47.52 73.38,54.15 61.34,54.15 59.14,56.36 59.14,78.25 v1(55.24,82.15)
  BOTTOM w0.191: P1.E22 v4(118.75,25.78)
GPIO8: length 188.3
  TOP w0.191: R198.1 43.18,81.18 v4(42.14,81.18) 41.83,81.49 R407.2 40.45,81.03 40.21,80.8 27.43,80.8 27.07,80.43 U35.41 ; P2.8 v1(53.42,46.13)
  L3_SIGNAL w0.114: v4(42.14,81.18) 42.95,80.37 42.95,76.25 40.59,73.89 40.59,50.39 44.32,46.66 45.09,46.66 45.62,46.13 v1(53.42,46.13)
  L24_SIGNAL w0.114: v4(119.1,124.93) 118.7,125.33 118.7,127.5 118.47,127.73 118.14,127.73 118.13,127.74 117.67,127.74 117.67,127.73 117.34,127.73 117.33,127.73 103.22,127.73 94.61,119.13 94.61,116.31 80.47,102.16 80.47,96.98 73.41,89.92 73.41,89.51 71.68,87.78 65.15,87.78 62.53,90.4 42.44,90.4 39.27,87.22 39.27,82.45 40.87,80.85 41.05,80.85 41.06,80.83 41.79,80.83 v4(42.14,81.18)
GPIO8_FMC: length 99.6
  TOP w0.191: R214.2 v1(55.24,81)
  L5_MIXED w0.114: v4(114.94,27.05) 115.54,27.66 115.54,29.67 115.14,30.08 114.92,30.08 114.41,30.58 114.41,32.09 101.53,44.97 84.37,44.97 82.32,47.02 80.04,47.02 73.24,53.81 61,53.81 58.82,55.99 58.82,77.42 v1(55.24,81)
  BOTTOM w0.191: P1.F25 v4(114.94,27.05)
GPIO8_HDR: length 37.3
  TOP w0.191: v4(12.07,63.3) 12.54,62.82 U22.21 ; v4(37.41,81.36) 37.54,81.49 R407.1
  BOTTOM w0.191: v4(12.07,63.3) 14.43,65.66 21.72,65.66 v4(37.41,81.36)
GPIO9: length 191.9
  TOP w0.191: R185.1 v4(42.01,79.99) R406.2 40.42,79.68 40.04,79.3 27.5,79.3 26.86,79.93 U35.40 ; P2.10 v1(53.47,44.86)
  L3_SIGNAL w0.114: v1(53.47,44.86) 52.86,45.47 44.17,45.47 40.16,49.48 40.16,74.35 42.55,76.73 42.55,79.45 v4(42.01,79.99)
  L24_SIGNAL w0.114: v4(119.1,125.73) 119.5,126.13 119.5,128.35 119.32,128.53 101.35,128.53 93.9,121.08 93.9,116.54 79.6,102.23 79.6,96.98 73.06,90.44 73.06,89.63 71.56,88.12 65.29,88.12 62.68,90.74 42.3,90.74 38.93,87.37 38.93,82.31 40.73,80.51 41.49,80.51 v4(42.01,79.99)
GPIO9_FMC: length 98.2
  TOP w0.191: R222.2 v1(55.24,79.86)
  L5_MIXED w0.114: v1(55.24,79.86) 58.14,76.96 58.14,55.4 60.05,53.49 73.03,53.49 73.17,53.35 73.18,53.35 81.14,45.39 82.09,45.39 83.14,44.34 100.99,44.34 101.03,44.3 101.08,44.3 113.16,32.22 113.16,30.65 113.48,30.33 113.93,30.33 114.25,30.01 114.25,28.71 113.66,28.13 v4(113.66,27.05)
  BOTTOM w0.191: P1.F26 v4(113.66,27.05)
GPIO9_HDR: length 35.2
  TOP w0.191: v4(13.53,63.3) 13.04,62.81 U22.20 ; R406.1 v4(37.39,79.99)
  BOTTOM w0.191: v4(37.39,79.99) 21.99,64.59 14.82,64.59 v4(13.53,63.3)
GPIO10: length 181.7
  TOP w0.191: P2.12 v1(53.44,43.59) ; U35.38 26.31,78.93 27.93,77.32 39.7,77.32 40.4,78.01 R405.2 41.48,78.44 v4(41.88,78.84) 43.23,78.84 R192.1
  L3_SIGNAL w0.114: v1(53.44,43.59) 52.91,43.05 45.64,43.05 39.6,49.1 39.6,76.56 v4(41.88,78.84)
  L22_MIXED w0.114: v4(41.88,78.84) 41.91,78.82 45.24,78.82 47.68,76.38 60.13,76.38 64.71,80.95 84.23,80.95 88.7,85.42 90.09,85.42 118.7,114.03 118.7,117.56 118.7,117.56 118.7,117.9 118.7,117.9 118.7,119.96 118.7,119.96 118.7,120.19 118.7,120.19 118.7,121.1 118.94,121.33 119.29,121.33 119.5,121.54 119.5,122.7 119.5,122.7 119.5,123.16 119.5,123.16 119.5,126.14 119.11,126.53 v4(119.1,126.53)
GPIO10_FMC: length 111.2
  TOP w0.191: v1(54.86,74.55) 55.3,74.12 55.3,45.87 v1(54.86,45.44) ; R233.2 v1(55.24,78.72)
  L5_MIXED w0.114: v1(54.86,74.55) 55.24,74.92 v1(55.24,78.72) ; v4(116.21,25.78) 114.13,23.71 109.94,23.71 107.8,25.84 107.8,28.52 107.52,28.81 107.51,28.81 107.31,29.01 106.91,29.01 106.62,29.3 106.62,32.29 106.02,32.89 106.02,34.19 99.4,40.81 99.29,40.81 99.28,40.81 88.41,40.81 88.4,40.81 72.1,40.81 68.53,44.37 62.66,44.37 62.26,43.97 59.89,43.97 59.84,43.92 56.39,43.92 v1(54.86,45.44)
  BOTTOM w0.191: P1.E24 v4(116.21,25.78)
GPIO10_HDR: length 37.7
  TOP w0.191: R405.1 v4(37.37,78.44) ; U22.13 15.39,57.88 15.77,58.27 15.77,61.9 v4(15.24,62.43)
  BOTTOM w0.191: v4(37.37,78.44) 37.37,77.5 23.57,63.7 15.93,63.7 15.24,63.02 v4(15.24,62.43)
GPIO11: length 111.3
  TOP w0.191: v4(41.93,77.7) R199.1 43.23,76.63 R404.2
  L22_MIXED w0.114: v4(119.1,127.33) 119.5,126.93 119.73,126.93 119.74,126.93 120.07,126.93 120.3,126.7 120.3,123.16 120.3,123.16 120.3,122.7 120.3,122.7 120.3,122.36 120.3,122.36 120.3,121.9 120.3,121.9 120.3,121.56 120.06,121.33 119.74,121.33 119.5,121.1 119.5,119.96 119.51,119.96 119.51,119.48 119.5,119.48 119.5,118.34 119.5,118.34 119.5,113.94 90.5,84.94 88.9,84.94 84.58,80.62 64.82,80.62 60.17,75.97 47.45,75.97 45.69,77.72 41.95,77.72 v4(41.93,77.7)
GPIO11_FMC: length 133
  TOP w0.191: v1(39.57,47.88) 39.57,71.58 44.53,76.53 53.8,76.53 54.39,77.13 R226.2
  L5_MIXED w0.114: v4(114.94,25.78) 114.94,25.29 114.96,25.27 114.96,25.11 114.15,24.31 113.87,24.02 110.52,24.02 109.15,25.39 109.15,30.99 108.24,31.9 108.24,32.06 108.24,32.54 107.84,32.93 107.11,32.93 106.81,33.24 106.81,34.35 99.72,41.44 99.55,41.44 99.54,41.44 88.15,41.44 88.14,41.44 75.38,41.44 70.13,46.69 57.15,46.69 55.83,48.01 39.7,48.01 v1(39.57,47.88)
  BOTTOM w0.191: P1.E25 v4(114.94,25.78)
GPIO11_HDR: length 39.3
  TOP w0.191: R404.1 v4(41.3,76.56) ; U22.12 15.35,57.13 16.18,57.96 v4(16.18,62.43)
  BOTTOM w0.191: v4(16.18,62.43) 23.44,62.43 37.57,76.56 v4(41.3,76.56)
GPIO12: length 179.8
  TOP w0.191: R193.1 v1(84.15,72.31)
  L3_SIGNAL w0.114: v4(162.31,62.2) 162.15,62.36 162.15,90.8 162.48,91.14 v4(162.48,92.32)
  L22_MIXED w0.114: v4(125.5,127.33) 125.1,126.93 122.14,126.93 121.9,126.7 121.9,122.36 121.9,122.36 121.9,121.9 121.9,121.9 121.9,121.56 121.9,121.56 121.9,121.1 121.9,121.1 121.9,120.76 121.9,120.76 121.9,120.3 121.9,120.3 121.9,119.96 121.9,119.96 121.9,118.84 122.7,118.04 122.7,114.85 125.72,111.83 141.81,111.83 146.57,107.06 148.85,107.06 162.48,93.43 v4(162.48,92.32) ; v4(162.31,62.2) 122.81,62.2 119.09,65.93 100.82,65.93 100.8,65.95 100.76,65.99 100.53,65.99 93.65,72.87 84.72,72.87 v1(84.15,72.31)
GPIO12_FMC: length 55.1
  TOP w0.191: R234.2 v1(84.03,59.03)
  L3_SIGNAL w0.114: v1(79.94,44.81) 80.04,44.91 80.17,44.91 83.29,48.03 83.29,51.94 84.48,53.14 84.48,58.57 v1(84.03,59.03)
  L5_MIXED w0.114: v1(79.94,44.81) 81.7,43.05 100.34,43.05 109.81,33.57 109.81,33.56 110.72,32.66 110.72,32.54 v4(111.12,32.13)
  BOTTOM w0.191: 111.76,31.5 v4(111.12,32.13)
GPIO13: length 179.1
  TOP w0.191: R183.1 v1(83.01,72.31)
  L3_SIGNAL w0.114: v4(163.22,92.3) 163.22,90.8 162.97,90.55 v4(162.97,62.59)
  L22_MIXED w0.114: v1(83.01,72.31) 83.95,73.25 93.81,73.25 100.74,66.32 100.88,66.32 100.95,66.24 119.61,66.24 123.21,62.64 162.49,62.64 162.54,62.59 v4(162.97,62.59) ; v4(125.5,126.53) 125.1,126.13 124.54,126.13 124.53,126.13 122.94,126.13 122.7,125.9 122.7,122.36 122.7,122.36 122.7,121.9 122.7,121.9 122.7,118.8 123.5,118 123.5,115.74 127.1,112.14 142.02,112.14 146.72,107.44 149.25,107.44 163.22,93.47 v4(163.22,92.3)
GPIO13_FMC: length 55.1
  TOP w0.191: R220.2 v1(82.88,59.08)
  L3_SIGNAL w0.114: v1(82.88,59.08) 82.88,57.1 78.92,53.14 v1(78.92,43.87)
  L5_MIXED w0.114: v4(109.85,32.13) 109.85,32.61 109.18,33.28 109.18,33.31 100.08,42.42 80.37,42.42 v1(78.92,43.87)
  BOTTOM w0.191: 110.49,31.5 v4(109.85,32.13)
GPIO14: length 178.9
  TOP w0.191: R200.1 v1(81.87,72.31)
  L3_SIGNAL w0.114: v4(163.98,62.53) v4(163.98,66.9)
  L22_MIXED w0.114: v4(125.5,125.73) 125.5,125.68 125.15,125.33 124.54,125.33 124.3,125.1 124.3,123.16 124.54,122.93 124.87,122.93 125.1,122.7 125.1,122.36 125.1,122.36 125.1,121.9 125.1,121.9 125.1,121.56 125.1,121.56 125.1,121.1 125.1,121.1 125.1,120.76 125.1,120.76 125.1,120.3 125.1,120.3 125.1,118.82 125.19,118.73 125.19,118.11 125.01,117.93 125.01,116.29 128.02,113.28 142.16,113.28 146.93,108.52 149.17,108.52 164.48,93.22 164.48,68.54 163.98,68.05 v4(163.98,66.9) ; v4(163.98,62.53) 163.53,62.99 155.49,62.99 155.46,62.96 123.44,62.96 119.84,66.56 101.09,66.56 101.06,66.58 100.98,66.66 100.92,66.66 100.86,66.73 100.8,66.73 93.94,73.58 83.14,73.58 v1(81.87,72.31)
GPIO14_FMC: length 59.8
  TOP w0.191: R212.2 v1(81.74,59.05)
  L3_SIGNAL w0.114: v1(81.74,59.05) 81.79,59.1 81.79,59.6 81.9,59.72 85,59.72 85.27,59.45 85.27,53.37 83.9,51.99 83.9,46.71 v1(81.7,44.51)
  L5_MIXED w0.114: v4(112.34,30.86) 112,31.21 112,31.46 111.93,31.53 111.93,32.46 111.46,32.93 111.38,32.93 100.64,43.68 82.55,43.68 81.71,44.51 v1(81.7,44.51)
  BOTTOM w0.191: P1.J27 112.4,30.86 v4(112.34,30.86)
GPIO15: length 217.9
  TOP w0.191: R186.1 v1(80.72,72.31)
  L3_SIGNAL w0.114: v4(165.38,62.71) 165.33,62.76 v4(165.33,66.85)
  L22_MIXED w0.108: v4(125.5,124.93) 125.5,124.97 125.9,125.36 125.9,133.89 125.66,134.13 125.34,134.13 125.1,134.37 125.1,137.09
  L22_MIXED w0.114: v1(80.72,72.31) 82.35,73.94 94.09,73.94 101.05,66.98 101.11,66.98 101.22,66.87 119.97,66.87 123.57,63.27 155.33,63.27 155.36,63.3 163.9,63.3 164.49,62.71 v4(165.38,62.71) ; v4(125.5,124.93) 125.1,124.53 125.1,123.17 125.1,123.17 125.34,122.93 125.67,122.93 126.7,121.9 126.7,116.5 129.16,114.05 142.53,114.05 147.43,109.15 149.43,109.15 165.33,93.25 v4(165.33,66.85) ; 125.1,137.09 125.1,139.16 121.6,142.66 117.27,142.66 112.99,146.94 112.99,150.53 112.86,150.66 112.86,150.95 112.78,151.03 112.78,151.38 112.86,151.46 112.86,151.8 113.13,152.07 v1(113.13,152.12)
  BOTTOM w0.191: v1(113.13,152.12) 113.46,152.12 114.48,153.14 R317.2
GPIO15_FMC: length 79.9
  TOP w0.191: R208.2 v1(80.6,59.01)
  L5_MIXED w0.114: v1(80.6,59.01) 81.07,58.54 81.34,58.54 86.09,53.79 118,53.79 118.01,53.78 119.42,53.78 133.27,39.93 133.27,29.95 133.2,29.88 133.2,29.39 133.12,29.31 133.12,28.52 133.5,28.15 133.5,28.12 133.78,27.83 133.81,27.83 133.99,27.66 133.99,23.36 v4(134.09,23.26)
  BOTTOM w0.191: P1.C10 134.09,23.14 v4(134.09,23.26)
GPIO16: length 218
  TOP w0.191: R201.1 v1(79.58,72.31)
  L3_SIGNAL w0.114: v4(165.76,67.64) 165.94,67.46 165.94,63.5 165.86,63.42 v4(165.86,63.32)
  L22_MIXED w0.108: v4(125.5,124.13) 125.5,124.15 125.88,124.53 126.47,124.53 126.7,124.77 126.7,133.89 126.46,134.13 126.14,134.13 125.9,134.37 125.9,137.41
  L22_MIXED w0.114: v4(165.76,67.64) 165.76,93.27 149.56,109.46 147.56,109.46 142.42,114.6 129.74,114.6 127.59,116.76 127.59,117.93 127.5,118.02 127.5,122.05 125.5,124.05 v4(125.5,124.13) ; 125.9,137.41 125.9,137.52 125.6,137.82 125.6,139.1 121.73,142.98 117.4,142.98 113.31,147.07 113.31,150.88 113.21,150.98 v1(113.21,151.21) ; v4(165.86,63.32) 165.37,63.32 165.22,63.17 164.56,63.17 164.11,63.62 155.23,63.62 155.2,63.59 124.37,63.59 120.77,67.19 101.35,67.19 101.33,67.21 94.24,74.3 81.57,74.3 v1(79.58,72.31)
  BOTTOM w0.191: v1(113.21,151.21) 114,151.99 R316.2
GPIO16_FMC: length 79.5
  TOP w0.191: R215.2 79.45,59.16 v1(79.35,59.05)
  L5_MIXED w0.114: v1(79.35,59.05) 80.2,58.21 81.07,58.21 81.11,58.18 81.24,58.18 85.95,53.48 117.87,53.48 132.11,39.24 132.11,28.98 132.28,28.81 132.28,24.76 132.23,24.71 132.23,24.31 132.36,24.17 132.36,23.6 v4(132.72,23.24)
  BOTTOM w0.191: P1.C11 v4(132.72,23.24)
GPIO17: length 177
  TOP w0.191: R187.1 v1(78.44,72.31)
  L3_SIGNAL w0.114: v4(164.85,63.63) 164.74,63.73 v4(164.74,67.21)
  L22_MIXED w0.114: v1(78.44,72.31) 80.85,74.73 94.25,74.73 101.48,67.5 121.12,67.5 124.56,64.06 153.34,64.06 153.85,64.57 162.56,64.57 162.89,64.24 164.24,64.24 v4(164.85,63.63) ; v4(164.74,67.21) 164.74,67.74 164.92,67.92 164.92,93.21 149.3,108.83 147.2,108.83 142.39,113.64 128.8,113.64 125.9,116.54 125.9,121.28 126.3,121.68 v4(126.3,121.73)
GPIO17_FMC: length 73.3
  TOP w0.191: R223.2 v1(78.31,59.03)
  L5_MIXED w0.114: v1(78.31,59.03) 79.45,57.89 80.94,57.89 80.98,57.86 81.12,57.86 85.81,53.16 117.74,53.16 130.84,40.07 130.84,32.82 130.18,32.16 v4(130.18,29.59)
  BOTTOM w0.191: P1.H13 v4(130.18,29.59)
GPIO18: length 153
  TOP w0.191: R194.1 v1(77.3,72.31)
  L22_MIXED w0.114: v1(77.3,72.31) 77.39,72.31 80.16,75.08 94.92,75.08 102.18,67.82 121.54,67.82 124.76,64.6 v4(153.16,64.6)
  L24_SIGNAL w0.108: 128.5,118.9 127.72,118.9
  L24_SIGNAL w0.114: v4(127.1,121.73) 127.22,121.73 127.5,121.44 127.5,119.11 127.72,118.9 ; v4(153.16,64.6) 153.16,82.56 135.52,100.2 135.52,100.24 135.38,100.38 135.38,115.96 133.28,118.06 133.07,118.06 133,118.13 132.88,118.13 132.87,118.14 132.53,118.14 132.52,118.13 131.74,118.13 131.64,118.22 131.38,118.22 130.68,118.93 128.54,118.93 128.5,118.9 128.5,118.9
GPIO18_FMC: length 73.7
  TOP w0.191: R235.2 v1(77.17,59.06)
  L5_MIXED w0.114: v4(128.91,29.59) 129.59,30.28 129.59,40.85 117.59,52.84 85.69,52.84 80.99,57.54 80.85,57.54 80.81,57.58 78.65,57.58 v1(77.17,59.06)
  BOTTOM w0.191: P1.H14 v4(128.91,29.59)
GPIO19: length 159.4
  TOP w0.191: R202.1 v1(76.15,72.31)
  L22_MIXED w0.114: v4(156.44,65.35) 156.09,65.01 125.01,65.01 121.88,68.13 102.33,68.13 94.97,75.49 79.5,75.49 76.32,72.31 v1(76.15,72.31)
  L24_SIGNAL w0.114: v4(156.44,65.35) 156.44,67.74 156.42,67.75 156.42,68.31 157,68.89 157,82.14 156.91,82.24 156.91,82.27 156.06,83.12 156.06,83.18 143.77,95.46 143.77,96.88 138.38,102.27 138.38,119.28 134.72,122.94 134.72,122.93 129.93,122.93 129.53,123.33 v4(129.5,123.33)
GPIO19_FMC: length 73.3
  TOP w0.191: R227.2 76.12,60.21 76.12,57.4 77.34,56.18 v1(80.24,56.18)
  L5_MIXED w0.114: v4(126.37,29.59) 125.81,30.15 125.81,43.26 117.24,51.82 117.17,51.82 117.15,51.84 84.58,51.84 v1(80.24,56.18)
  BOTTOM w0.191: P1.H16 v4(126.37,29.59)
GPIO20: length 184.3
  TOP w0.191: R195.1 v1(69.65,72.41)
  L22_MIXED w0.114: v4(131.9,121.73) 132.3,121.33 132.3,120.76 132.76,120.3 141.1,120.3 141.9,119.5 141.92,119.5 149.75,111.67 150.48,111.67 168.05,94.09 168.05,64.67 167.94,64.56 163.25,64.56 161.85,65.96 153.59,65.96 153.11,65.48 126.59,65.48 123.63,68.45 103.51,68.45 94.72,77.24 74.48,77.24 v1(69.65,72.41)
GPIO20_FMC: length 79.3
  TOP w0.191: R236.2 v1(69.52,57.65)
  L5_MIXED w0.114: v1(69.52,57.65) 76.68,57.65 79.45,54.88 81.1,54.88 84.45,51.53 117.02,51.53 117.04,51.51 117.11,51.51 125.49,43.13 125.49,29.99 v4(125.09,29.59)
  BOTTOM w0.191: P1.H17 v4(125.09,29.59)
GPIO21: length 183.1
  TOP w0.191: R188.1 v1(68.51,72.41)
  L22_MIXED w0.114: v4(130.3,120.14) 130.3,119.33 131.67,117.96 131.67,116.61 132.16,116.13 143.37,116.13 148.77,110.72 150.09,110.72 166.83,93.98 166.83,68.53 167.11,68.25 167.11,66.8 165.86,65.56 162.7,65.56 161.76,66.5 126.14,66.5 123.87,68.76 103.8,68.76 94.92,77.65 73.74,77.65 v1(68.51,72.41)
GPIO21_FMC: length 83.4
  TOP w0.191: v1(68.43,58.39) 68.43,60.36 R224.2
  L5_MIXED w0.114: v4(127.63,28.32) 128.24,28.93 128.24,35.84 127.15,36.93 127.15,42.84 117.48,52.51 85.43,52.51 80.68,57.26 77.97,57.26 76.95,58.28 70.07,58.28 69.87,58.48 68.51,58.48 v1(68.43,58.39)
  BOTTOM w0.191: P1.G15 v4(127.63,28.32)
GPIO22: length 186.9
  TOP w0.191: R203.1 v1(67.36,72.41)
  L22_MIXED w0.114: v1(67.36,72.41) 73.06,78.11 95,78.11 104.02,69.08 124.06,69.08 126.16,66.98 161.72,66.98 162.61,66.09 165.91,66.09 166.51,66.69 166.51,67.95 166.39,68.08 166.39,93.53 149.82,110.09 148.22,110.09 142.8,115.52 129.91,115.52 128.22,117.21 128.22,118.19 128.21,118.2 128.21,119.43 128.51,119.73 128.87,119.73 129.1,119.96 129.1,120.53 v4(129.5,120.93)
GPIO22_FMC: length 84
  TOP w0.191: R216.2 67.26,60.39 v1(67.26,58.17)
  L5_MIXED w0.114: v4(126.37,28.32) 126.37,28.47 126.95,29.06 126.95,36.69 126.84,36.8 126.84,42.71 117.45,52.1 117.41,52.1 117.37,52.14 117.3,52.14 117.28,52.16 85.2,52.16 80.47,56.88 77.89,56.88 76.81,57.97 69.94,57.97 69.74,58.17 69.31,58.17 69.02,57.88 67.54,57.88 v1(67.26,58.17)
  BOTTOM w0.191: P1.G16 v4(126.37,28.32)
GPIO23: length 187.1
  TOP w0.191: R189.1 v1(66.22,72.41)
  L22_MIXED w0.114: v1(66.22,72.41) 72.32,78.51 95.15,78.51 104.27,69.39 124.4,69.39 126.21,67.58 126.22,67.58 126.39,67.41 161.77,67.41 162.77,66.41 165.51,66.41 166.2,67.1 166.2,67.82 166.08,67.94 166.08,93.4 149.69,109.78 147.9,109.78 142.57,115.11 129.87,115.11 127.94,117.04 127.94,119.61 128.3,119.96 128.3,120.3 128.3,120.3 128.3,120.52 v4(128.7,120.93)
GPIO23_FMC: length 87.2
  TOP w0.191: v1(66.12,57.51) 66.12,60.39 R209.2
  L5_MIXED w0.114: v1(66.12,57.51) 66.48,57.14 69.74,57.14 69.94,57.34 76.41,57.34 76.61,57.14 76.63,57.14 79.21,54.56 80.91,54.56 84.26,51.21 115.22,51.21 123.16,43.27 123.16,23.95 123.82,23.29 v4(123.82,23.24)
  BOTTOM w0.191: P1.C18 v4(123.82,23.24)
GPIO24: length 170.3
  TOP w0.191: R204.1 v1(65.08,72.41)
  L22_MIXED w0.114: v4(156.82,67.92) 126.31,67.92 124.46,69.77 104.39,69.77 95.22,78.94 71.61,78.94 v1(65.08,72.41)
  L24_SIGNAL w0.114: v4(130.3,123.33) 130.7,123.73 135.03,123.73 138.89,119.87 138.89,116.95 138.89,116.95 138.89,102.26 144.2,96.95 144.2,95.48 156.37,83.31 156.37,83.25 157.22,82.4 157.22,82.37 157.31,82.27 157.31,81.98 157.71,81.59 157.71,68.81 v4(156.82,67.92)
GPIO24_FMC: length 87.2
  TOP w0.191: v1(64.92,56.64) 64.92,60.38 R217.2
  L5_MIXED w0.114: v4(122.56,23.24) 122.56,27.51 120.8,29.27 120.8,29.79 120.85,29.84 120.85,43.82 114.42,50.25 83.88,50.25 83.24,50.88 83.23,50.88 80.64,53.47 78.83,53.47 76.1,56.19 65.37,56.19 v1(64.92,56.64)
  BOTTOM w0.191: P1.C19 v4(122.56,23.24)
GPIO25: length 166.3
  TOP w0.191: R190.1 v1(63.94,72.41)
  L22_MIXED w0.114: v1(63.94,72.41) 70.9,79.38 95.43,79.38 104.71,70.09 124.7,70.09 124.92,69.88 124.92,69.88 126.47,68.33 154.76,68.33 v4(155.12,68.68)
  L24_SIGNAL w0.114: v4(155.12,68.68) 155.12,72.53 155.11,72.54 155.11,82.79 142.66,95.24 142.66,96.57 137.06,102.17 137.06,118.74 135.27,120.53 130.93,120.53 130.7,120.75 130.7,122.13 v4(130.3,122.53)
GPIO25_FMC: length 82
  TOP w0.191: R228.2 v1(63.81,57.88)
  L5_MIXED w0.114: v4(122.56,29.59) 121.95,30.2 121.95,43.98 115.03,50.9 84.13,50.9 80.85,54.18 79.15,54.18 76.5,56.82 65.94,56.82 64.87,57.88 v1(63.81,57.88)
  BOTTOM w0.191: P1.H19 v4(122.56,29.59)
GPIO26: length 203.3
  TOP w0.191: R166.2 v1(53.64,63.87) ; R196.1 v1(62.79,72.41)
  L3_SIGNAL w0.114: v1(53.64,63.87) 54.25,63.87 v1(62.79,72.41)
  L22_MIXED w0.114: v1(62.79,72.41) 70.16,79.78 95.91,79.78 104.83,70.87 112.06,70.87 113.33,72.14 126.39,72.14 129.24,69.29 155.78,69.29 156.41,69.93 v4(156.54,69.93) ; v4(167.42,69.27) 167.42,93.83 150.22,111.04 149.49,111.04 141.66,118.87 141.64,118.87 140.52,119.99 131.44,119.99 130.7,120.73 130.7,122.93 v4(131.1,123.33)
  BOTTOM w0.191: v4(167.42,69.27) 157.2,69.27 v4(156.54,69.93)
GPIO26_FMC: length 82.7
  TOP w0.191: v1(62.56,57.84) 62.56,60.3 R237.2
  L5_MIXED w0.114: v4(121.28,29.59) 121.63,29.94 121.63,43.7 114.74,50.58 83.99,50.58 83.37,51.2 83.36,51.2 80.78,53.78 78.98,53.78 76.26,56.51 65.78,56.51 65.14,57.16 63.24,57.16 v1(62.56,57.84)
  BOTTOM w0.191: P1.H20 v4(121.28,29.59)
GPIO27: length 178.8
  TOP w0.191: R205.1 v1(61.65,72.41) ; R168.2 v1(54.48,68.1)
  L22_MIXED w0.114: v1(54.48,68.1) 57.33,68.1 v1(61.65,72.41) 69.37,80.14 96.06,80.14 104.97,71.22 111.92,71.22 113.04,72.34 113.09,72.34 113.2,72.45 126.58,72.45 129.38,69.65 155.26,69.65 v4(155.75,70.14)
  L24_SIGNAL w0.108: 133.34,122.13 133.38,122.17 134.11,122.17
  L24_SIGNAL w0.114: v4(131.1,122.53) 131.5,122.13 133.34,122.13 ; v4(155.75,70.14) 156.59,70.97 156.59,82.14 155.74,82.99 155.74,83.05 143.46,95.33 143.46,96.75 137.97,102.24 137.97,119.01 135.61,121.38 135.61,121.4 135.42,121.59 135.4,121.59 134.81,122.17 134.11,122.17
GPIO27_FMC: length 84.9
  TOP w0.191: v1(60.6,57.1) 61.52,58.02 R229.2
  L5_MIXED w0.114: v4(118.75,23.24) 118.75,24.43 118.15,25.03 118.15,37.67 107.52,48.3 84.02,48.3 82.87,49.45 81.7,49.45 81.69,49.45 80.24,49.45 74.47,55.22 62.33,55.22 60.6,56.95 v1(60.6,57.1)
  BOTTOM w0.191: P1.C22 v4(118.75,23.24)
GPIO28: length 179.1
  TOP w0.191: R165.2 v1(54.48,69.37) ; R247.1 v1(84.36,89.38)
  L3_SIGNAL w0.114: v1(84.36,89.38) 82.58,87.6 72.9,87.6 55.02,69.73 54.85,69.73 v1(54.48,69.37)
  L22_MIXED w0.114: v4(90.83,83.93) 94.02,83.93 104.47,73.48 126.87,73.48 126.9,73.45 126.91,73.45 129.74,70.62 150.85,70.62 v4(153.82,73.6)
  L24_SIGNAL w0.108: 129.9,120.09 129.9,119.95 130.12,119.73 134.5,119.73
  L24_SIGNAL w0.114: 134.5,119.73 135.84,118.39 135.84,101.13 153.77,83.2 153.77,73.65 v4(153.82,73.6) ; v1(84.36,89.38) 89.81,83.93 v4(90.83,83.93) ; v4(130.3,121.73) 130.29,121.73 129.89,121.33 129.89,121.11 129.9,121.1 129.9,120.76 129.89,120.75 129.89,120.31 129.9,120.3 129.9,120.09
GPIO28_FMC: length 82.9
  TOP w0.191: R280.2 v1(84.23,76.53)
  L3_SIGNAL w0.114: v4(86.07,46.93) 86.07,47.42 88.57,49.92 88.57,72.19 v1(84.23,76.53)
  L5_MIXED w0.114: v4(117.47,23.24) 117.47,23.72 116.72,24.48 116.72,28.75 116.43,29.04 116.43,30.22 117.07,30.85 117.07,35.55 105.69,46.93 v4(86.07,46.93)
  BOTTOM w0.191: P1.C23 v4(117.47,23.24)
GPIO29: length 178.6
  TOP w0.191: R167.2 v1(54.46,70.64) ; R238.1 v1(83.21,89.38)
  L3_SIGNAL w0.114: v1(83.21,89.38) 81.82,87.99 72.67,87.99 55.32,70.64 v1(54.46,70.64)
  L22_MIXED w0.114: v4(89.51,83.24) 90,83.24 90.01,83.22 94.24,83.22 104.31,73.15 126.72,73.15 126.74,73.14 126.78,73.14 129.61,70.31 151.61,70.31 v4(154.46,73.16)
  L24_SIGNAL w0.114: v4(154.46,73.16) 154.46,82.96 142.34,95.07 142.34,96.44 136.47,102.31 136.47,118.54 134.8,120.22 130.9,120.22 130.47,120.66 130.47,120.77 v4(130.3,120.93) ; v1(83.21,89.38) 89.36,83.24 v4(89.51,83.24)
GPIO29_FMC: length 79.6
  TOP w0.191: R271.2 v1(83.09,76.53)
  L3_SIGNAL w0.114: v1(83.09,76.53) 88.11,71.5 88.11,51.26 85.65,48.79 v4(85.14,48.79)
  L5_MIXED w0.114: v4(85.14,48.79) 107.94,48.79 118.62,38.11 118.62,30.21 118.75,30.08 v4(118.75,29.59)
  BOTTOM w0.191: P1.H22 v4(118.75,29.59)
GPIO30: length 181
  TOP w0.191: R164.2 v1(54.43,71.91) ; R253.1 v1(82.07,89.38)
  L3_SIGNAL w0.114: v1(82.07,89.38) 81.01,88.32 72.39,88.32 55.98,71.91 v1(54.43,71.91)
  L22_MIXED w0.114: v4(88.85,82.6) 94.41,82.6 104.19,72.82 126.65,72.82 129.51,69.96 152.79,69.96 v4(155.55,72.72)
  L24_SIGNAL w0.114: v4(88.85,82.6) v1(82.07,89.38) ; v4(155.55,72.72) 156.06,73.23 156.06,82.22 155.43,82.85 155.43,82.92 143.13,95.21 143.13,96.62 137.52,102.23 137.52,119.02 135.2,121.34 132.87,121.34 132.87,121.33 131.4,121.33 131.1,121.63 131.1,121.68
  L24_SIGNAL w0.127: 131.1,121.68 v4(131.1,121.73)
GPIO30_FMC: length 79.3
  TOP w0.191: R265.2 v1(81.94,76.53)
  L3_SIGNAL w0.114: v4(84.89,47.73) 84.54,48.07 84.54,50.25 87.73,53.44 87.73,70.74 v1(81.94,76.53)
  L5_MIXED w0.114: v4(84.89,47.73) 84.97,47.81 106.88,47.81 117.82,36.87 117.82,30.42 117.47,30.08 v4(117.47,29.59)
  BOTTOM w0.191: P1.H23 v4(117.47,29.59)
GPIO31: length 66.4
  TOP w0.191: R241.1 v1(80.93,89.38)
  L24_SIGNAL w0.114: v4(123.9,122.53) 124.25,122.18 124.27,122.18 124.33,122.13 124.94,122.13 125.1,121.96 125.1,118.82 125.19,118.73 125.19,118.33 124.9,118.04 124.29,118.04 124.1,118.22 120.5,118.22 120.41,118.14 120.2,118.14 120.19,118.13 119.61,118.13 119.6,118.14 119.39,118.14 119.38,118.14 116.21,118.14 116.19,118.13 115.61,118.13 115.6,118.14 112.88,118.14 112.87,118.13 112.54,118.13 112.52,118.14 111.28,118.14 111.27,118.13 102.75,118.13 85.9,101.28 85.9,94.35 v1(80.93,89.38)
GPIO31_FMC: length 80.1
  TOP w0.191: v4(71.75,51.41) 71.75,69.29 76.47,74 78.27,74 80.8,76.53 R262.2
  L5_MIXED w0.114: v4(111.12,30.86) 111.12,31.35 110.4,32.07 110.4,32.52 109.5,33.43 109.5,33.44 100.21,42.73 81.07,42.73 72.39,51.41 v4(71.75,51.41)
  BOTTOM w0.191: P1.J28 v4(111.12,30.86)
GPIO32: length 64.1
  TOP w0.191: R254.1 v1(79.78,89.38)
  L24_SIGNAL w0.114: v1(79.78,89.38) 85.52,95.12 85.52,101.45 103.1,119.02 110.5,119.02 110.6,118.93 123.68,118.93 124.3,119.55 124.3,121.44 124.01,121.73 v4(123.9,121.73)
GPIO32_FMC: length 116.8
  TOP w0.191: v1(56.95,40.82) 56.95,71.77 59.83,74.65 77.78,74.65 79.66,76.53 R268.2
  L5_MIXED w0.114: v1(56.95,40.82) 57.05,40.72 59.86,40.72 59.87,40.71 67.24,40.71 67.77,40.18 88.66,40.18 88.67,40.18 98.95,40.18 105.13,34 105.13,31.67 105.26,31.54 105.26,27.72 104.6,27.05 v4(103.5,27.05)
  BOTTOM w0.191: P1.F34 v4(103.5,27.05)
GPIO33: length 159.7
  TOP w0.191: R242.1 78.64,89.38 79.2,89.94 85.83,89.94 91.27,84.49 v1(94.65,84.49)
  L22_MIXED w0.114: v4(120.7,122.53) 120.7,122.53 121.1,122.13 121.1,119.5 121.1,119.5 121.1,118.85 121.9,118.05 121.9,117.56 121.79,117.46 121.79,115.19 125.53,111.45 141.7,111.45 146.47,106.68 148.78,106.68 157.43,98.03 157.43,81.53 150.34,74.45 141.02,74.45 137.51,70.94 129.9,70.94 127.03,73.81 104.65,73.81 94.65,83.81 v1(94.65,84.49)
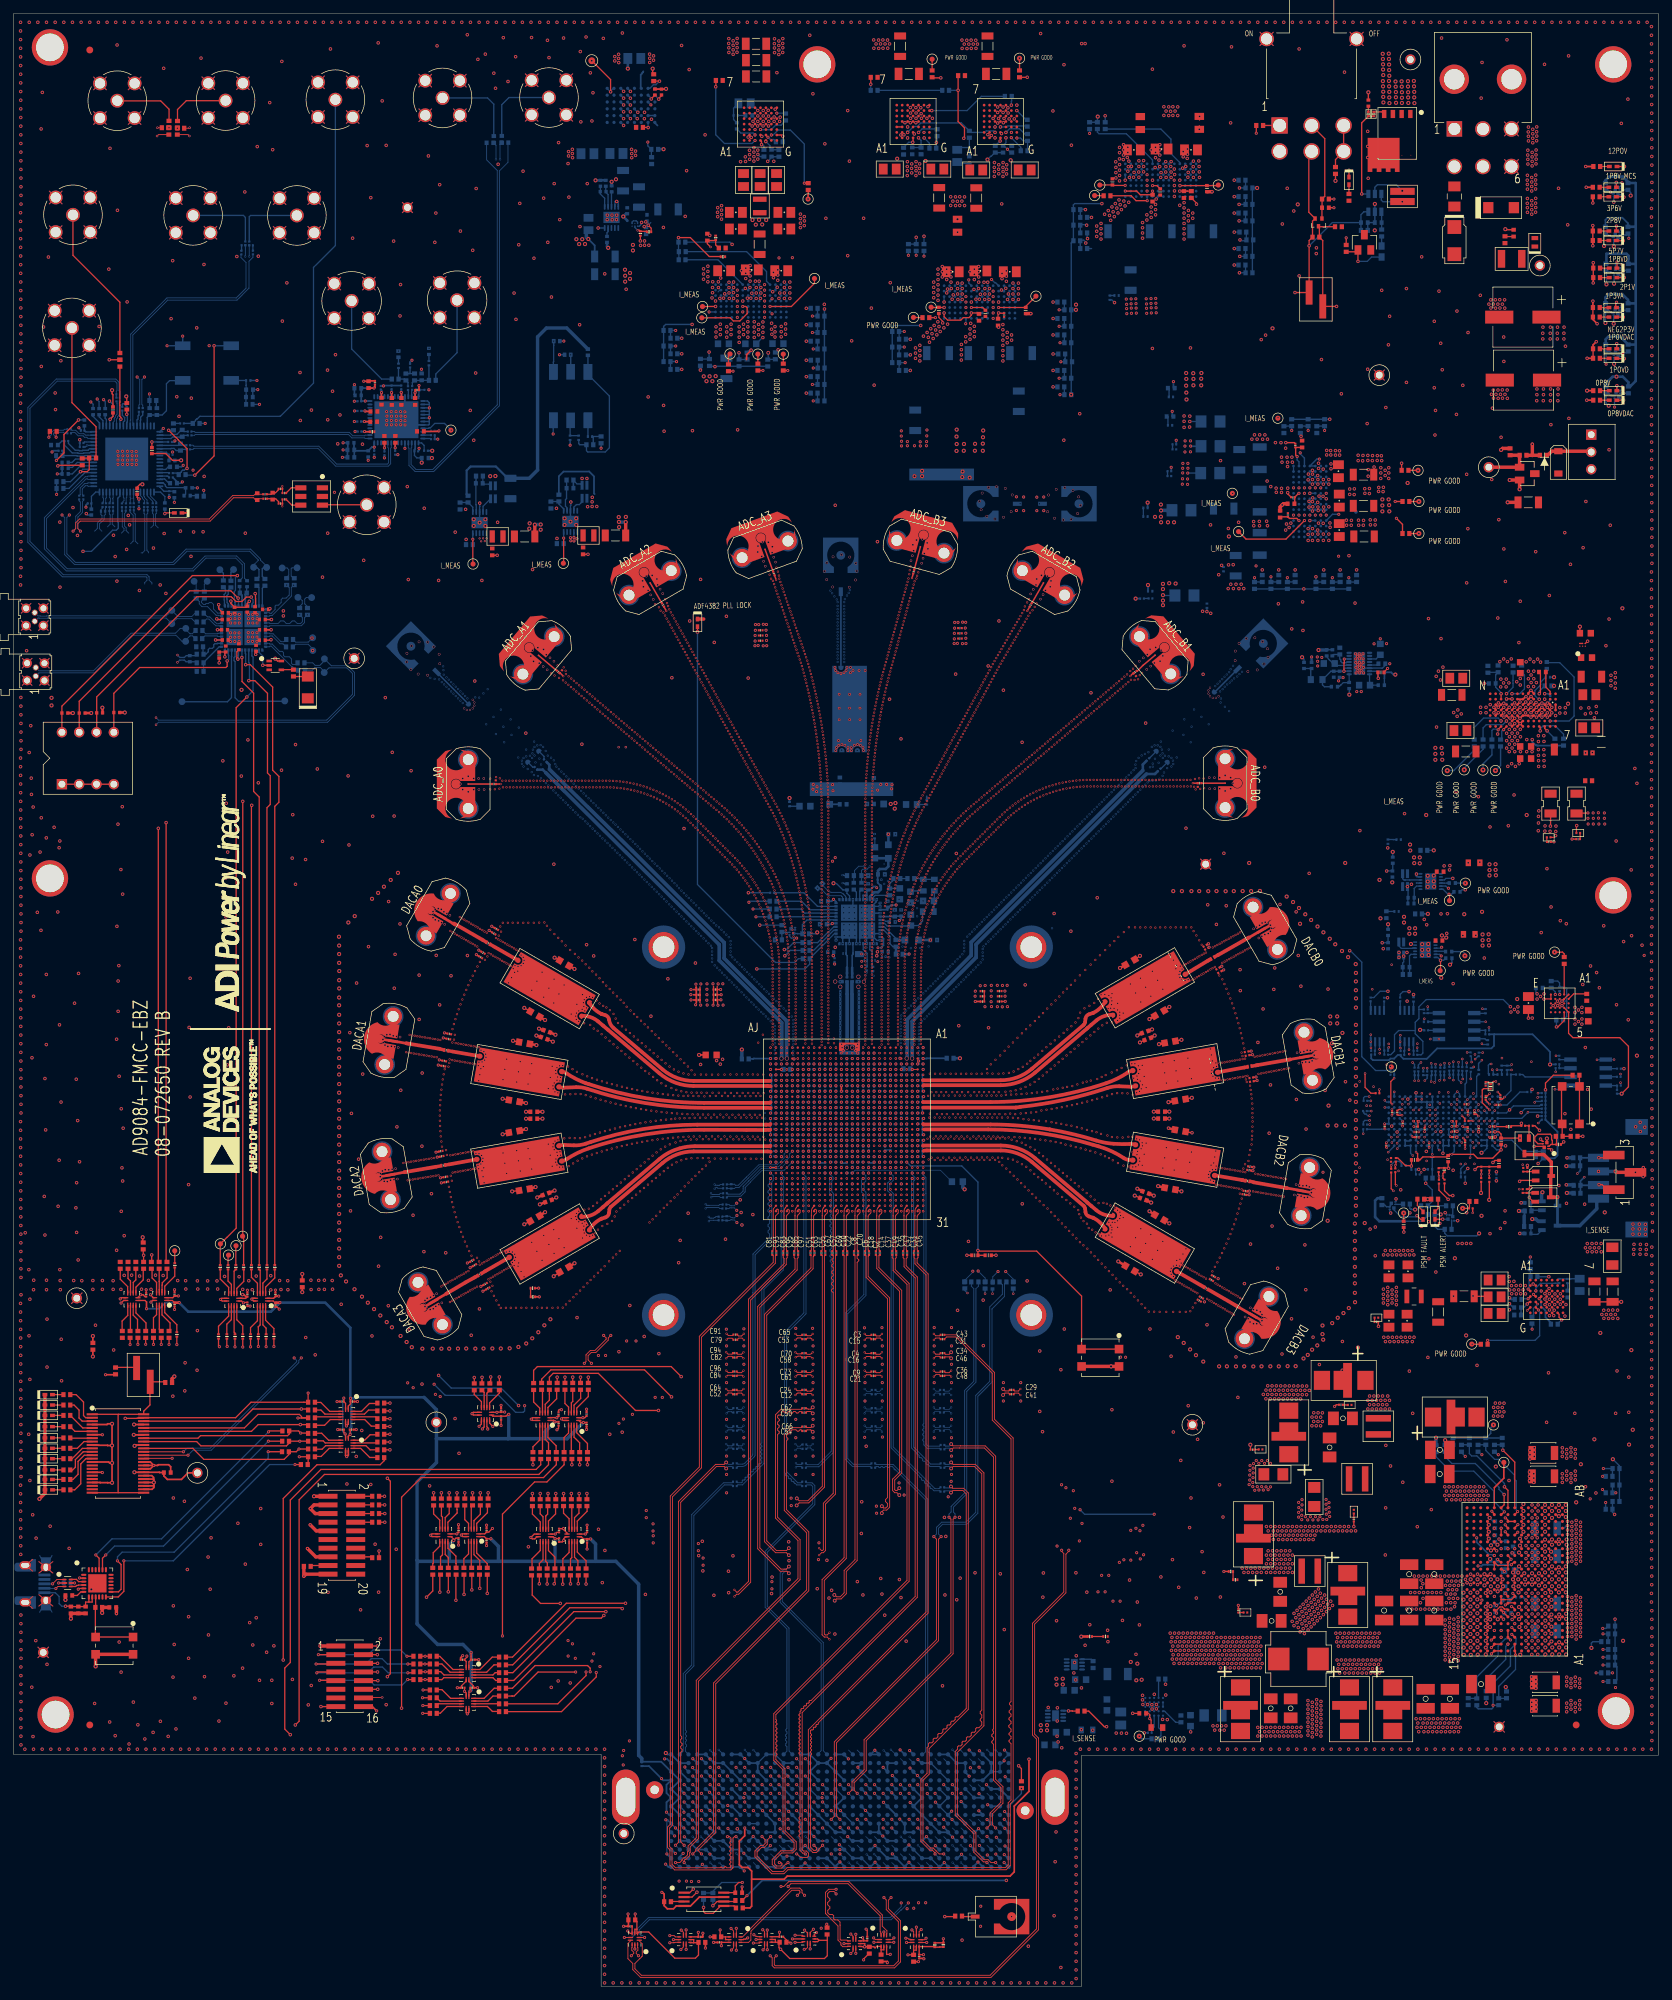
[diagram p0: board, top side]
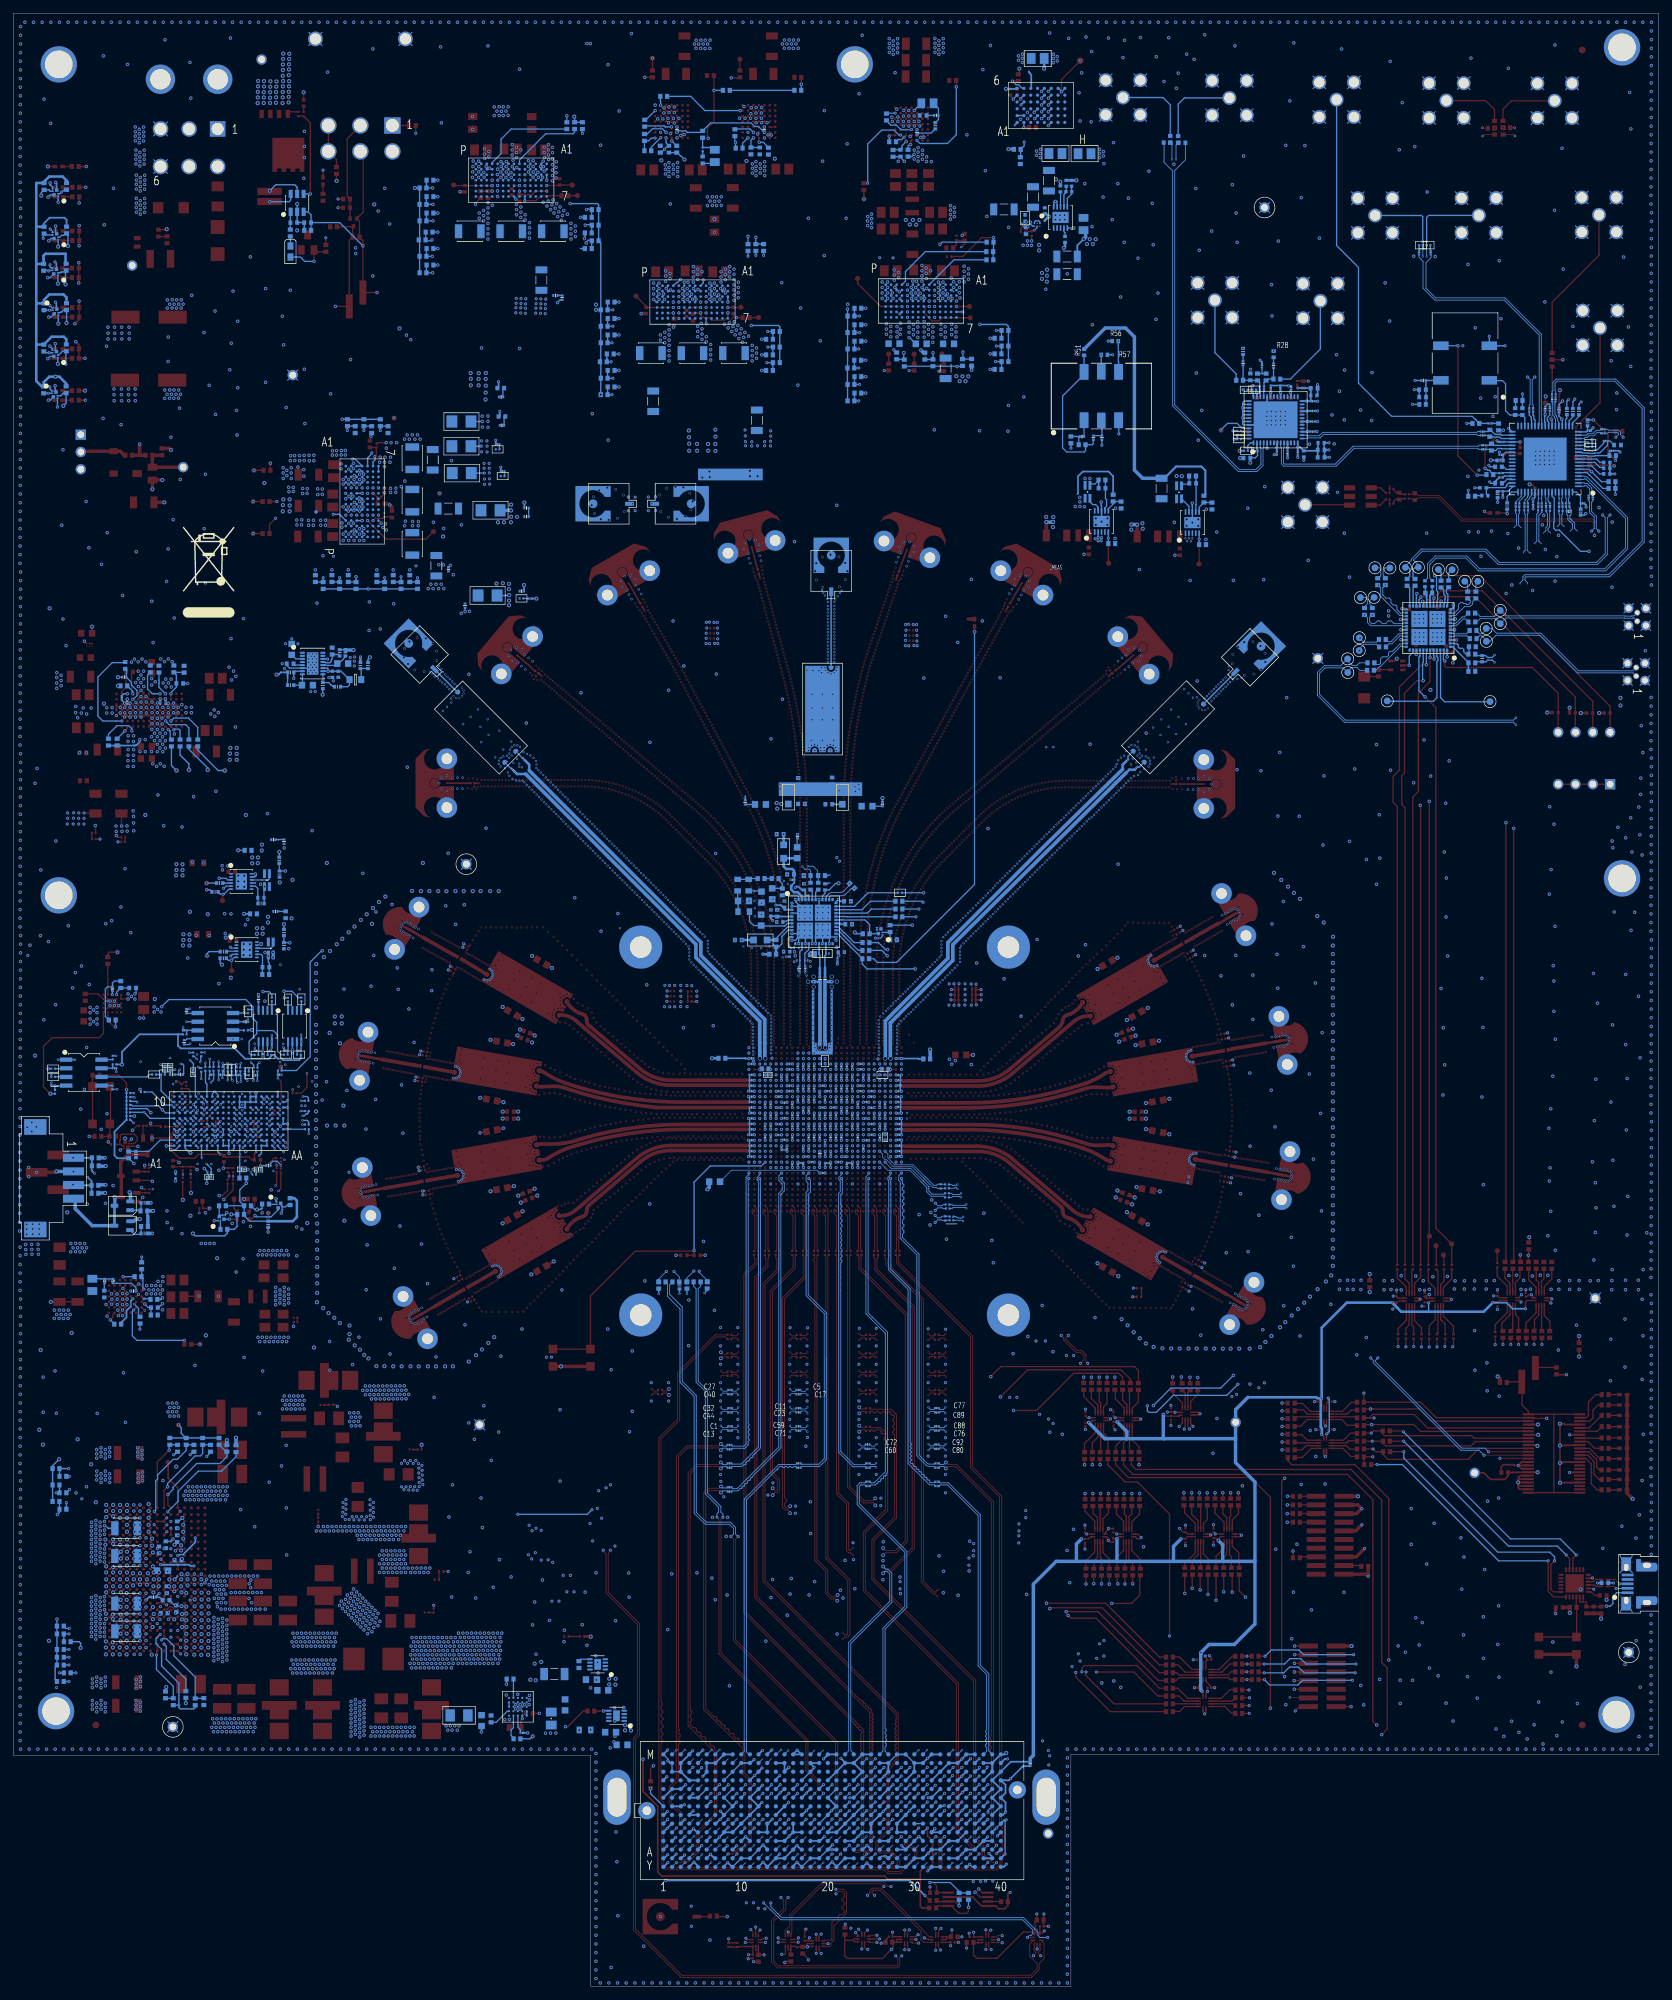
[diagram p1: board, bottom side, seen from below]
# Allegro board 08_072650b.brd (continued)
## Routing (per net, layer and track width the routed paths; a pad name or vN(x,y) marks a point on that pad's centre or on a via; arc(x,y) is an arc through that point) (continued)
GPIO33_FMC: length 143.6
  TOP w0.191: v1(41.35,38.35) 41.91,38.91 41.91,71.4 45.62,75.11 77.09,75.11 78.51,76.53 R274.2
  L5_MIXED w0.114: v4(102.24,27.05) 101.71,27.58 101.71,28.27 101.4,28.57 101.4,30.61 101.45,30.66 101.45,31.06 101.4,31.11 101.4,32.94 101.45,32.99 101.45,34.22 96.75,38.92 89.19,38.92 88.62,38.35 v1(41.35,38.35)
  BOTTOM w0.191: P1.F35 v4(102.24,27.05)
GPIO34: length 161.9
  TOP w0.191: v1(96.57,86.49) 92.61,90.45 78.87,90.45 77.5,89.08 R248.1
  L22_MIXED w0.114: v4(120.7,121.73) 120.7,121.62 120.62,121.53 120.62,121.43 120.3,121.12 120.3,121.1 120.3,121.1 120.3,118.82 120.39,118.73 120.39,118.33 119.89,117.83 119.89,116.65 125.51,111.03 141.35,111.03 146.08,106.3 148.72,106.3 157,98.02 157,81.71 150.05,74.76 140.89,74.76 137.45,71.32 129.97,71.32 127.16,74.13 104.78,74.13 96.57,82.34 v1(96.57,86.49)
GPIO34_FMC: length 138.9
  TOP w0.191: v1(40.61,36.93) 39.8,37.74 39.8,46.71 40.61,47.52 40.61,71.35 45.11,75.84 76.69,75.84 77.37,76.53 R281.2
  L5_MIXED w0.114: v1(40.61,36.93) 40.77,37.08 88.87,37.08 89.59,37.81 89.6,37.81 89.71,37.92 95.77,37.92 98.27,35.42 98.27,33.43 99.25,32.45 99.32,32.45 v4(99.67,32.11)
  BOTTOM w0.191: 100.33,31.5 100.03,31.8 99.85,31.8 99.67,31.98 v4(99.67,32.11)
HMC7044_3P3V: length 32.2
  TOP w0.203: v4(6.27,223.87) 7.39,224.99 7.39,227.69 v1(9.53,229.82) ; v3(24.59,223.9) 23.32,223.9 22.33,224.89 E14.2 ; v3(16.54,233.27) 16.61,233.2 E10.2 ; v3(14.45,234.19) 14.45,233.65 14.58,233.53 E8.2 ; E11.2 18.14,219.96 18.54,220.37 v3(18.9,220.37)
  L3_SIGNAL w0.203: v3(14.45,234.19) 11.53,234.19 9.53,232.18 v1(9.53,229.82)
  BOTTOM w0.203: E2B.1 v4(36.09,232.11) ; R103.1 R385.1 v1(9.71,226.91) ; E13.2 v4(23.6,217.73) ; v1(10.67,216.08) 10.87,215.87 E12.2 ; C185.2 109.92,241.91 v1(109.98,241.91) ; E1.1 v1(9.53,229.82) ; v4(6.27,223.87) 6.23,223.91 E7.1 ; v3(24.59,223.9) 24.21,223.9 24.18,223.88 E9.2
  vias: v1(108.71,244.22) v1(108.71,243.46) v1(108.71,242.7) v1(108.71,241.94) v1(109.35,243.84) v1(109.35,243.08) v1(109.35,242.32) v1(109.98,244.2) v1(109.98,243.43) v1(109.98,242.67)
HMC7044_CLK0_N: length 35.9
  TOP w0.133: v4(8.73,213.51) 9.11,213.89 9.11,214.73 9.67,215.29 28.72,215.29 32.16,218.72 35.23,218.72 35.58,219.07 C318.1 35.91,218.92 L15.1
  BOTTOM w0.133: C231.2 9.63,217.94 9.8,217.77 9.8,216.38 9.11,215.69 9.11,213.89 v4(8.73,213.51)
HMC7044_CLK0_P: length 35.5
  TOP w0.133: L16.1 35.96,218.26 C318.2 35.66,218.17 35.51,218.17 35.47,218.21 35.41,218.21 35.21,218.41 32.29,218.41 28.85,214.98 9.8,214.98 9.42,214.6 9.42,213.89 v4(9.8,213.51)
  BOTTOM w0.133: C230.2 10.24,217.98 10.11,217.86 10.11,216.25 9.42,215.56 9.42,213.89 v4(9.8,213.51)
HMC7044_CLK2_N: length 3.7
  BOTTOM w0.133: U1B.16 10.93,227.59 10.92,227.58 10.54,227.58 10.32,227.81 9.6,227.81 9.11,228.3 8.57,228.3 C567.1
HMC7044_CLK2_P: length 3.8
  BOTTOM w0.133: C566.1 8.55,227.99 8.98,227.99 9.47,227.5 10.19,227.5 10.41,227.27 10.74,227.27 10.93,227.09 U1B.15
HMC7044_CLK5_N: length 3.8
  BOTTOM w0.133: U1B.23 15.11,229.68 15.08,229.7 15.08,229.94 15.25,230.11 15.25,230.3 15.5,230.55 15.5,232.26 15.52,232.28 15.52,232.47 C563.1
HMC7044_CLK5_P: length 3.9
  BOTTOM w0.133: C562.1 15.16,232.47 15.16,232.28 15.19,232.25 15.19,230.68 14.94,230.43 14.94,230.24 14.77,230.07 14.77,229.65 14.61,229.49 U1B.22
HMC7044_CLK8_N: length 1.9
  BOTTOM w0.133: U1B.56 18.61,218.73 18.91,218.43 18.91,218.3 19.2,218.01 19.2,217.64 C569.1
HMC7044_CLK8_P: length 1.9
  BOTTOM w0.133: C568.1 19.59,217.67 19.59,218.06 19.22,218.43 19.22,218.56 19.11,218.67 U1B.55
HMC7044_CLK9_N: length 2
  BOTTOM w0.133: U1B.54 19.61,218.69 20.42,217.88 C571.1
HMC7044_CLK9_P: length 2
  BOTTOM w0.133: U1B.53 20.11,218.63 20.93,217.81 C570.1
HMC7044_CLK10_N: length 1.7
  BOTTOM w0.133: U1B.59 17.11,218.41 17.2,218.31 17.2,218.29 17.12,218.2 C555.1
HMC7044_CLK10_P: length 1.7
  BOTTOM w0.133: U1B.58 17.61,218.41 17.53,218.33 17.63,218.24 C554.1
HMC7044_CLK11_N: length 1.8
  BOTTOM w0.133: C557.1 16.05,217.72 16.05,217.83 16.21,217.99 16.21,218.35 16.11,218.45 16.11,218.49 U1B.61
HMC7044_CLK11_P: length 1.7
  BOTTOM w0.133: U1B.60 16.61,218.46 16.52,218.37 16.52,217.6 C556.1
HMC7044_CLK12_N: length 1.7
  BOTTOM w0.133: U1B.67 13.11,218.41 13.2,218.31 13.2,217.93 13.13,217.86 13.13,217.67 C559.1
HMC7044_CLK12_P: length 1.7
  BOTTOM w0.133: U1B.66 13.61,218.41 13.51,218.31 13.51,217.64 C558.1
HMC7044_CLK13_N: length 1.7
  BOTTOM w0.133: U1B.65 14.11,218.41 14.2,218.31 14.2,217.91 14.14,217.86 14.14,217.67 C561.1
HMC7044_CLK13_P: length 1.7
  BOTTOM w0.133: U1B.64 14.61,218.41 14.51,218.31 14.51,218.3 14.58,218.24 C560.1
HMC7044_FIN_N: length 26.5
  BOTTOM w0.133: U2.15 51.61,227.09 51.51,227.19 49.65,227.19 49.15,227.68 26.66,227.68 26.53,227.56 C156.1
HMC7044_FIN_P: length 26.5
  BOTTOM w0.133: C155.1 26.53,228.12 26.66,227.99 49.28,227.99 49.77,227.5 51.51,227.5 51.61,227.59 U2.16
HMC7044_GPIO3: length 121.3
  TOP w0.191: R260.1 v1(19.08,107.27) 19.02,107.32 R687.2
  L3_SIGNAL w0.114: v1(19.08,107.27) 19.63,107.82 19.63,195.81 10.19,205.26 v1(10.19,210.54)
  BOTTOM w0.191: v1(10.19,210.54) 11.43,210.54 14.54,213.65 15.07,213.65 15.36,213.94 15.36,214.79 15.29,214.86 15.29,218.34 15.61,218.66 U1B.62
HMC7044_REFIN_N: length 33.8
  BOTTOM w0.133: U2.9 55.43,225.77 55.34,225.67 55.34,223.39 54.99,223.04 47.29,223.04 44.67,225.65 26.47,225.65 26.32,225.5 C217.1
HMC7044_REFIN_P: length 33.3
  BOTTOM w0.133: U2.10 54.93,225.77 55.03,225.67 55.03,223.52 54.86,223.35 47.42,223.35 44.8,225.96 26.47,225.96 26.32,226.11 C216.1
HMC_CPOUT1: length 11
  BOTTOM w0.191: U1B.32 19.61,230.19 C128.1 C129.1 21.81,230.55 22.43,231.17 22.43,235.13 22.89,235.59 24.78,235.59 Y1.1
HSCI_CKIN_N: length 12.2
  BOTTOM w0.108: v4(114.3,122.53) 113.89,122.12 113.89,121.67 113.52,121.3 113.33,121.3 112.27,120.25 109.5,120.25 107.87,118.62 107.87,118.61 107.78,118.52
  BOTTOM w0.127: 107.78,118.52 106.49,117.22 105.97,117.22 105.8,117.06 R319.1 104.73,117.06 R321.1
HSCI_CKIN_N_FMC: length 137.5
  L5_MIXED w0.114: v4(112.52,23.12) 112.89,22.79 112.89,22.73 112.91,22.44 113.71,21.64 114.08,21.64 114.42,21.3 114.42,20.84 114.03,20.44 114.03,19.05 114.57,18.51 114.57,18.18 109.12,12.73 105.74,12.73 104.99,13.48 104.99,15.43 103.44,16.98 99.01,16.98 97.92,15.89 97.92,15.67 v4(97.69,15.44)
  L24_SIGNAL w0.108: v9(102.9,117.02) 103.33,117.02 103.49,116.86 103.49,87.28 96.82,80.62 96.82,37.95 98.94,35.84 98.94,17.72 98.08,16.86 98.08,15.83 v4(97.69,15.44)
  BOTTOM w0.127: P1.C27 v4(112.52,23.12) ; 103.25,117.22 103.37,117.09 R321.2
  BOTTOM w0.133: v9(102.9,117.02) 103.1,117.22 103.25,117.22
HSCI_CKIN_P: length 11.3
  BOTTOM w0.108: v4(113.5,122.53) 113.1,122.13 113.1,121.57 112.07,120.53 109.38,120.53 107.6,118.75 107.59,118.75 107.57,118.73
  BOTTOM w0.127: R322.1 104.73,117.69 R319.2 105.8,117.69 105.97,117.53 106.36,117.53 107.57,118.73
HSCI_CKIN_P_FMC: length 138.1
  L5_MIXED w0.114: v4(98.76,15.44) 98.76,16.03 99.21,16.48 103.24,16.48 104.5,15.23 104.5,13.27 105.54,12.23 109.32,12.23 115.06,17.97 115.06,18.72 114.52,19.26 114.52,20.24 114.92,20.63 114.92,21.51 114.29,22.14 113.92,22.14 113.39,22.66 113.38,22.82 v4(113.71,23.2)
  L24_SIGNAL w0.108: v4(98.76,15.44) 98.37,15.83 98.37,16.74 99.23,17.6 99.23,35.96 97.12,38.07 97.12,80.5 103.78,87.16 103.78,116.82 103.79,116.82 103.79,117.2 103.33,117.65 v9(102.9,117.65)
  BOTTOM w0.127: P1.C26 v4(113.71,23.2) ; 103.25,117.53 103.37,117.53 103.38,117.53 103.61,117.53 103.74,117.65 R322.2
  BOTTOM w0.133: 103.25,117.53 103.02,117.53 v9(102.9,117.65)
HSCI_CKO_N: length 12.2
  BOTTOM w0.108: 108.13,117.96 108.14,117.97 108.14,117.99 108.21,118.05 108.21,118.07 109.87,119.73 113.1,119.73 v4(114.3,120.93)
  BOTTOM w0.127: 107.39,117.22 107.39,116.98 107.38,116.98 107.38,116.57 106.74,115.93 104.87,115.93 R327.1
  BOTTOM w0.133: 108.13,117.96 107.39,117.22
HSCI_CKO_N_FMC: length 103.8
  L22_MIXED w0.102: v4(93.86,67.86) 94.2,67.51 95.33,67.51 100.41,62.43 100.8,62.43 v4(101.21,62.84)
  L24_SIGNAL w0.108: v4(103.5,28.32) 104,28.82 104,47.8 100.27,51.53 100.27,62.18 100.56,62.46 100.83,62.46 v4(101.21,62.84) ; v4(93.86,67.86) 93.48,67.48 92.74,67.48 92.41,67.82 92.41,70.38 92.81,70.79 92.81,77.01 94.17,78.38 94.17,82.31 100,88.14 100,114.2 101.71,115.9 102.26,115.9 v9(102.39,115.77)
  BOTTOM w0.127: 102.76,115.87 103.61,115.87 103.74,115.75 R327.2 ; P1.G34 v4(103.5,28.32)
  BOTTOM w0.133: 102.76,115.87 102.49,115.87 v9(102.39,115.77)
HSCI_CKO_P: length 11.2
  BOTTOM w0.108: 107.91,118.18 109.75,120.02 112.59,120.02 v4(113.5,120.93)
  BOTTOM w0.127: R328.1 104.76,116.36 104.88,116.23 106.62,116.23 107.08,116.69 107.08,117.1 107.08,117.11 107.08,117.35 107.15,117.41 107.15,117.42 107.9,118.16
  BOTTOM w0.133: 107.91,118.18 107.9,118.16
HSCI_CKO_P_FMC: length 104.3
  L22_MIXED w0.102: v4(101.21,61.79) 100.81,62.19 100.3,62.19 95.22,67.27 94.32,67.27 v4(93.86,66.81)
  L24_SIGNAL w0.108: v9(102.36,116.36) 102.21,116.2 101.58,116.2 99.7,114.32 99.7,88.26 93.88,82.44 93.88,78.5 92.51,77.14 92.51,70.91 92.11,70.51 92.11,67.69 92.62,67.18 93.48,67.18 v4(93.86,66.81) ; v4(104.78,28.32) 104.3,28.79 104.3,47.92 100.57,51.65 100.57,62.06 100.68,62.17 100.83,62.17 v4(101.21,61.79)
  BOTTOM w0.127: 102.76,116.19 102.89,116.19 102.89,116.18 103.56,116.18 103.74,116.36 R328.2 ; P1.G33 v4(104.78,28.32)
  BOTTOM w0.133: 102.76,116.19 102.53,116.19 v9(102.36,116.36)
HSCI_DIN_N: length 20.7
  L3_SIGNAL w0.108: v7(114.3,123.33) 114.7,122.93 115.26,122.93 115.5,122.69 115.5,119.14 115.28,118.93 110.94,118.93 110.45,118.44 110.44,118.44 108.77,116.77 108.77,116.56 108.77,116.56 108.77,116.46 108.78,116.45 108.78,115.78 107.7,114.7 107.7,113.74 106.84,112.89 106.27,112.89 106.17,112.99 v4(106.17,113.11)
  BOTTOM w0.127: v4(106.17,113.11) 105.8,112.75 105.56,112.75 105.5,112.82 105.31,112.82 105.13,112.99 R320.1
  BOTTOM w0.133: R323.1 104.09,112.99 R320.1
HSCI_DIN_N_FMC: length 107.9
  L22_MIXED w0.102: v4(93.89,65.06) 94.35,65.52 95.24,65.52 101.98,58.78 110.84,58.78 v4(111.3,58.32)
  L24_SIGNAL w0.108: v4(93.89,65.06) 94.26,65.44 95.16,65.44 95.65,65.94 95.65,80.69 103,88.04 103,112.43 102.71,112.71 102.44,112.71 102.25,112.9 v9(102.03,112.9) ; v4(111.12,28.32) 111.61,28.81 111.61,57.13 112.27,57.79 112.27,58.57 112.12,58.72 111.7,58.72 v4(111.3,58.32)
  BOTTOM w0.127: R323.2 103.08,112.93 102.96,112.8 102.85,112.8 102.75,112.71 102.44,112.71 ; P1.G28 v4(111.12,28.32)
  BOTTOM w0.133: v9(102.03,112.9) 102.23,112.71 102.44,112.71
HSCI_DIN_P: length 24.2
  L3_SIGNAL w0.108: v4(106.17,112.06) 106.17,112.37 106.38,112.59 106.97,112.59 107.99,113.61 107.99,114.57 109.08,115.66 109.08,116.59 110.63,118.13 114.91,118.13 115.71,118.93 116.07,118.93 116.3,119.17 116.3,123.49 116.07,123.73 114.48,123.73 114.47,123.73 113.91,123.73 v7(113.5,123.33)
  BOTTOM w0.127: v4(106.17,112.06) 105.79,112.44 105.44,112.44 105.37,112.51 105.29,112.51 105.13,112.36 R320.2
  BOTTOM w0.133: R324.1 104.64,112.39 R320.2
HSCI_DIN_P_FMC: length 107.8
  L22_MIXED w0.102: v4(111.3,59.37) 110.96,59.03 102.08,59.03 95.34,65.77 94.23,65.77 v4(93.89,66.11)
  L24_SIGNAL w0.108: v4(93.89,66.11) 94.26,65.74 95.03,65.74 95.36,66.06 95.36,80.82 102.7,88.16 102.7,112.31 102.59,112.41 102.44,112.41 102.29,112.27 v9(102.06,112.27) ; v4(112.4,28.32) 111.91,28.81 111.91,33.88 111.95,33.92 111.95,34.07 111.91,34.11 111.91,34.26 112,34.35 112,34.5 111.91,34.59 111.91,34.75 111.96,34.8 111.96,34.95 111.91,35 111.91,35.2 111.99,35.28 111.99,35.43 111.91,35.51 111.91,35.66 112,35.75 112,35.9 111.91,35.99 111.91,36.22 112.04,36.35 112.04,36.5 111.91,36.63 111.91,36.83 111.99,36.91 111.99,37.06 111.91,37.13 111.91,37.39 112.05,37.53 112.05,37.68 111.94,37.79 111.94,37.95 112.05,38.06 112.05,38.21 111.95,38.32 111.95,38.47 112.04,38.56 112.04,38.71 111.91,38.84 111.91,57 112.57,57.67 112.57,58.7 112.25,59.02 111.65,59.02 v4(111.3,59.37)
  BOTTOM w0.127: P1.G27 v4(112.4,28.32) ; R324.2 102.74,112.39
  BOTTOM w0.133: 102.74,112.39 102.18,112.39 v9(102.06,112.27)
HSCI_DO_N: length 14.3
  L3_SIGNAL w0.108: v4(106.14,113.86) 106.59,114.31 106.69,114.31 108.18,115.79 108.18,116.97 111.44,120.23 113.62,120.23 113.9,120.51 113.9,121.24 114.3,121.64 v7(114.3,121.73)
  BOTTOM w0.127: R329.1 105,114.1 105.14,114.23 105.38,114.22 105.78,114.22 v4(106.14,113.86)
HSCI_DO_N_FMC: length 101.9
  L22_MIXED w0.102: v4(92.86,68.76) 93.32,69.22 94.73,69.22 99.51,64.44 99.99,64.44 v4(100.51,63.92)
  L24_SIGNAL w0.108: v4(100.51,63.92) 100.88,64.29 101.04,64.29 101.83,63.5 101.83,51.9 106.56,47.18 106.56,36.68 106.43,36.55 106.43,36.4 106.53,36.3 106.53,36.14 106.44,36.06 106.44,35.9 106.56,35.79 106.56,35.59 106.45,35.48 106.45,35.33 106.56,35.23 106.56,35 106.45,34.9 106.45,34.75 106.56,34.65 106.56,34.44 106.43,34.32 106.43,34.16 106.56,34.04 106.56,33.88 106.42,33.74 106.42,33.59 106.56,33.45 106.56,29.99 v4(106.13,29.5) ; v4(92.86,68.76) 93.24,69.14 93.5,69.14 95.05,70.69 95.05,81.53 101.3,87.78 101.3,110.87 100.71,111.46 100.71,113.96 100.9,114.15 v9(101.57,114.15)
  BOTTOM w0.127: R329.2 103.64,114.14 103.51,114.28 101.94,114.28 ; P1.H32 v4(106.13,29.5)
  BOTTOM w0.133: v9(101.57,114.15) 101.7,114.28 101.94,114.28
HSCI_DO_P: length 13.2
  L3_SIGNAL w0.108: v4(106.14,114.91) 106.44,114.6 106.57,114.6 107.88,115.92 107.88,117.09 111.31,120.53 112.86,120.53 113.1,120.77 113.1,121.09 113.5,121.49 v7(113.5,121.73)
  BOTTOM w0.127: v4(106.14,114.91) 105.76,114.53 105.38,114.53 105.16,114.54 105.02,114.69 R330.1
HSCI_DO_P_FMC: length 101.9
  L22_MIXED w0.102: v4(100.51,64.97) 100.03,64.97 99.8,64.74 99.56,64.74 94.84,69.47 93.2,69.47 v4(92.86,69.81)
  L24_SIGNAL w0.108: v9(101.57,114.76) 101.04,114.76 100.41,114.13 100.41,111.33 101,110.75 101,87.91 94.75,81.66 94.75,70.81 93.37,69.44 93.24,69.44 v4(92.86,69.81) ; v4(100.51,64.97) 100.88,64.59 101.16,64.59 102.13,63.62 102.13,52.02 106.85,47.3 106.85,29.99 v4(107.31,29.59)
  BOTTOM w0.127: 101.94,114.59 102.07,114.59 102.07,114.58 103.51,114.58 103.66,114.72 R330.2 ; P1.H31 v4(107.31,29.59)
  BOTTOM w0.133: v9(101.57,114.76) 101.74,114.59 101.94,114.59
LTC6955_3P3V: length 38.9
  TOP w0.254: v4(51.51,228.12) 51.54,228.09 C288.1 ; C299.1 56.92,233.83 v4(56.9,233.86) ; C303.1 62.36,228.14 v4(62.43,228.22) ; v4(56.01,225.73) 56.01,226.45 C280.1 ; C309.1 55.5,233.81 v4(55.47,233.83) ; C284.1 51.64,231.06 v4(51.56,231.14) ; C281.1 58.96,233.84 v4(58.93,233.81) C295.1 ; C308.1 53.04,234.64 v4(52.9,234.5) C307.1 ; C301.1 54.43,226.47 v4(54.43,225.73) ; C292.1 v4(54,233.83) ; C282.1 51.51,229.57 v4(51.49,229.59)
  BOTTOM w0.191: v3(59.9,223.55) C305.1 59.88,224.26 59.18,224.26 58.84,224.6
  BOTTOM w0.197: 58.84,224.6 C283.1 ; U2.5 v4(57.43,225.65)
  BOTTOM w0.254: U2.2 58.93,225.55 58.84,225.45 C283.1 ; C298.1 54.43,225.73 v4(54.43,225.73) U2.11 ; v4(52.9,234.5) 51.05,234.5 C286.1 51.02,234.47 C289.1 51.02,233.42 C306.1 51.05,232.59 v4(51.61,232.59) U2.26 ; U2.35 56.93,233.82 v4(56.9,233.86) C302.1 ; C304.1 v4(51.56,231.14) 51.61,231.09 U2.23 ; R307.1 v4(62.43,228.22) ; C296.1 v4(56.01,225.73) 56.01,225.98 55.96,226.02 55.96,226.43 U2.8 ; U2.29 53.93,233.77 v4(54,233.83) 54,234.17 C285.1 ; C290.1 C293.1 ; C290.1 50.14,225.29 C297.1 52.59,225.83 v4(52.93,225.83) ; C290.1 49.95,225.48 C287.1 ; v4(52.93,225.83) C300.1 ; v4(52.93,225.83) U2.14 ; C279.1 v4(51.49,229.59) 51.49,229.59 U2.20 ; U2.17 51.53,228.09 v4(51.51,228.12) C294.1 ; R311.1 59.06,233.94 v4(58.93,233.81) 58.93,233.8 U2.39 ; C291.1 v4(55.47,233.83) 55.43,233.79 U2.32
  vias: v1(112.67,243.54) v1(112.67,242.77) v1(112.67,242.01) v1(113.31,243.92) v1(113.31,243.15) v1(113.31,242.39)
LTM4681_VDD25_01: length 105.7
  TOP w0.203: U33.C8 220.33,51.22 v4(219.91,51.64)
  L3_SIGNAL w0.203: v4(217.17,41.24) 218.51,41.24 220.54,43.27 230.95,43.27 231.08,43.4 235.9,43.4 237.67,45.16 v3(237.67,81.66)
  L24_SIGNAL w0.203: v1(217.22,82.37) 217.93,81.66 v3(237.67,81.66)
  BOTTOM w0.203: v4(217.17,41.24) 217.97,41.24 R438.1 ; v4(217.17,41.24) 217.17,44.48 219.71,47.02 219.71,49.45 220.52,50.27 220.52,51.03 v4(219.91,51.64) ; v4(217.17,41.24) 217.17,40.92 216.97,40.72 214.98,40.72 214.77,40.92 R435.1 ; 216.15,80.46 216.83,81.14 216.83,81.98 v1(217.22,82.37) ; 216.15,80.46 R440.1 ; 216.15,80.46 R439.1 R437.1 R436.1
LTM4681_VDD25_23: length 7.2
  TOP w0.191: 217.35,73.17 U33.AB11
  TOP w0.254: 217.35,73.17 218.74,74.57 TP20.1
LTM4681_VDD33_01: length 130.1
  L5_MIXED w0.508: v1(235.07,53.87) 238.73,57.54 238.73,77.29 ; v3(234.75,77.34) 238.68,77.34 238.73,77.29 ; 238.73,77.29 238.73,94.72 236.88,96.57 236.88,121.77 235.36,123.29 228.13,123.29 224.28,119.44 224.28,116.64 v3(224.41,116.51)
  L24_SIGNAL w0.203: v4(220.34,53.22) 220.39,53.17 220.39,52.58 221.16,51.82 221.16,49.68 222.65,48.19 228.1,48.19 233.79,53.87 v1(235.07,53.87)
  BOTTOM w0.203: R426.2 R425.2 R428.2 235.7,76.39 v3(234.75,77.34) ; v1(235.07,53.87) R379.2 R427.2 R430.2 R431.2 R432.2 235.33,46.88 235.33,44.99 R429.2
  BOTTOM w0.508: v3(224.41,116.51) 224.28,116.38 224.28,115.23 Q14.2
LTM4681_VDD33_23: length 51
  L5_MIXED w0.508: v3(217.56,76.26) 216.92,76.91 216.92,78.89 215.57,80.24 215.57,106.73 221.41,112.57 v3(222.91,112.57)
  L24_SIGNAL w0.191: v3(217.56,76.26) 217.75,76.07 217.75,71.98
  L24_SIGNAL w0.203: 217.75,71.98 217.96,71.78 217.96,68.53 218.27,68.22 v4(218.35,68.22)
  BOTTOM w0.191: 223.76,112.26 Q15.2
  BOTTOM w0.508: v3(222.91,112.57) 223.44,112.57 223.76,112.26
LTM4681_VOUT01: length 6
  TOP w0.203: v4(219.88,55.72) 219.98,55.72 220.34,55.35 U33.G8
  L24_SIGNAL w0.203: v4(219.88,55.72) 218.97,56.62 217.94,56.62 v4(217.35,57.22) 216.8,56.67 v4(215.52,56.67)
  vias: v1(194.08,51.82) v1(194.21,50.55) v1(194.26,47.88) v1(194.34,51.18) v1(194.46,49.91) v1(194.39,46.61) v1(194.51,47.24) v1(194.64,45.97) v1(194.72,51.82) v1(194.84,50.55) v1(194.89,47.88) v1(195.02,46.61) v1(195.1,51.18) v1(195.22,49.91) v1(195.28,47.24) v1(195.35,51.82) v1(195.48,50.55) v1(195.4,45.97) v1(195.53,47.88) v1(195.66,46.61) v1(195.73,51.18) v1(195.86,49.91) v1(195.91,47.24) v1(195.99,51.82) v1(196.04,45.97) v1(196.11,50.55) v1(196.16,47.88) v1(196.37,51.18) v1(196.29,46.61) v1(196.49,49.91) v1(196.55,47.24) v1(196.62,51.82) v1(196.67,45.97) v1(196.75,50.55) v1(196.8,47.88) v1(196.93,46.61) v1(197,51.18) v1(197.13,49.91) v1(197.18,47.24) v1(197.26,51.82) v1(197.38,50.55) v1(197.31,45.97) v1(197.43,47.88) v1(197.56,46.61) v1(197.64,51.18) v1(197.76,49.91) v1(197.82,47.24) v1(197.89,51.82) v1(197.94,45.97) v1(198.02,50.55) v1(198.07,47.88) v1(198.27,51.18) v1(198.2,46.61) v1(198.4,49.91) v1(198.45,47.24) v1(198.53,51.82) v1(198.58,45.97) v1(198.65,50.55) v1(198.7,47.88) v1(198.83,46.61) v1(198.91,51.18) v1(199.03,49.91) v1(199.09,47.24) v1(199.16,51.82) v1(199.21,45.97) v1(199.29,50.55) v1(199.34,47.88) v1(199.47,46.61) v1(199.54,51.18) v1(199.67,49.91) v1(199.72,47.24) v1(199.8,51.82) v1(199.85,45.97) v1(199.92,50.55) v1(199.97,47.88) v1(200.18,51.18) v1(200.1,46.61) v1(200.3,49.91) v1(200.36,47.24) v1(200.43,51.82) v1(200.48,45.97) v1(200.56,50.55) v1(200.61,47.88) v1(200.74,46.61) v1(210.13,53.75) v1(210.13,52.98) v1(210.13,52.35) v1(210.13,51.71) v1(210.13,51.08) v1(210.13,50.44) v1(210.13,49.81) v1(210.13,49.17) v1(210.13,48.54) v1(210.13,47.9) v1(210.77,54) v1(210.77,53.37) v1(210.77,52.73) v1(210.77,52.1) v1(210.77,51.46) v1(210.77,50.83) v1(210.77,50.19) v1(210.77,49.56) v1(210.77,48.92) v1(210.77,48.29) v1(210.77,47.65) v1(211.4,53.87) v1(211.4,53.11) v1(211.4,52.48) v1(211.4,51.84) v1(211.4,51.21) v1(211.4,50.57) v1(211.4,49.94) v1(211.4,49.3) v1(211.4,48.67) v1(211.4,48.03) v1(212.04,54.13) v1(212.04,53.49) v1(212.04,52.86) v1(212.04,52.22) v1(212.04,51.59) v1(212.04,50.95) v1(212.04,50.32) v1(212.04,49.68) v1(212.04,49.05) v1(212.04,48.41) v1(212.04,47.78) v3(212.83,57.76) v3(212.83,56.74) v3(212.83,55.73) v3(212.83,54.71) v3(212.83,53.72) v3(212.83,52.7) v3(212.83,51.69) v3(212.83,50.67) v3(212.85,49.71) v3(212.88,48.64) v3(213.84,57.76) v3(213.84,56.74) v3(213.84,55.73) v3(213.84,54.71) v3(213.84,53.72) v3(213.84,52.7) v3(213.84,51.69) v3(213.84,50.67) v3(213.87,49.71) v3(213.89,48.64) v3(214.86,57.78) v3(214.86,56.77) v3(214.86,55.75) v3(214.86,54.74) v3(214.86,53.75) v3(214.86,52.73) v3(214.86,51.71) v3(214.86,50.7) v3(214.88,49.73) v3(214.91,48.67)
LTM4681_VOUT2: length 5.6
  TOP w0.198: v4(219.85,61.87) 220.19,62.22 U33.P8
  BOTTOM w0.254: v4(214.96,61.69) 215.49,61.69 215.67,61.87 216.37,61.87 216.37,61.86 217.22,61.86 217.23,61.87 217.37,61.87 217.37,61.86 218.22,61.86 218.23,61.87 v4(219.85,61.87)
MUXOUT1: length 14.7
  BOTTOM w0.191: U51.45 32.51,195.1 32.37,194.96 32.37,194.5 32.51,194.36 32.51,189.06 33.02,188.54 39.75,188.54 TP42.1
MUXOUT2: length 14.5
  BOTTOM w0.191: TP43.1 24.74,188.47 31.37,188.47 31.97,189.07 31.97,195.12 32,195.15 32,196.06 U51.46
NEG2P3V_PG_LED: length 2
  TOP w0.191: DS14.C v1(236.27,244.91)
  BOTTOM w0.191: Q5.3 235.96,244.91 v1(236.27,244.91)
NEG2P4V: length 144
  TOP w0.191: v1(227.27,144.55) 227.41,144.68 227.41,144.68 U6.B2 U6.A1 ; v3(236.03,130.97) 237.03,131.97 237.03,137.92 235.76,139.19 228.88,139.19 228.25,139.82 U6.A5 U6.B4 ; C177.1 v1(222.35,142.06)
  L3_SIGNAL w0.114: v1(207.42,155.75) 207.49,155.82 207.49,156.72 205.55,158.65 203.33,158.65 202.79,158.12 202.79,155.57 203.29,155.07 203.29,154.08 202.3,153.09 202.3,150.51 202.62,150.18 202.62,146.59 202.03,146 v1(201.73,146)
  L24_SIGNAL w0.114: v1(204.83,145.95) 204.83,146.96 204.4,147.39 201.75,147.39 197.21,151.93 197.21,167 200.61,170.41 210.77,170.41 215.21,165.96 v1(215.21,164.95) ; v1(207.42,155.75) 207.9,155.27 210.77,155.27 211.2,154.84 212.67,154.84 213.3,154.2 v1(214.63,154.2)
  BOTTOM w0.191: 227.96,144.55 227.96,146.33 227.65,146.65 C176.1 226.92,147.22 226.65,147.49 R500.2 ; 227.96,144.55 v1(227.27,144.55) ; 227.96,144.55 227.96,142.3 R497.2 ; 206.27,143.32 R596.1 ; 206.27,143.32 206.27,141.99 205.74,141.45 205.74,140.23 ; 206.27,143.32 206.27,143.71 207.34,144.78 218.66,144.78 v1(219.71,143.73) ; 205.74,140.23 203.3,140.23 202.69,139.62 202.69,137.24 202.16,136.7 R704.1 ; 205.74,140.23 205.74,139.76 206.86,138.65 206.86,136.93 206.6,136.68 R705.1 ; R79.1 199.66,145.08 200.58,146 v1(201.73,146) ; R607.1 v3(236.03,130.97) ; v1(204.83,145.95) 203.94,145.95 203.53,145.54 R81.1
  vias: v1(219.79,142.95) v1(220.29,143.33) v1(220.8,143.71) v1(220.8,142.95) v1(222.91,142.06) v1(225.98,143.89) v1(226.62,144.55) v1(226.64,143.89) v1(227.28,143.89) v3(215.62,154.33) v3(215.62,153.49) v3(215.62,152.7) v3(216.51,154.36) v3(216.51,153.52) v3(216.56,152.73) v3(216.64,164.62) v3(216.64,163.78) v3(216.64,162.99) v3(217.53,164.64) v3(217.53,163.8) v3(217.58,163.02)
NEG2P4V_PG: length 103.2
  TOP w0.197: R540.2 227.61,151.49 227.36,151.74 v1(226.19,151.74)
  L3_SIGNAL w0.203: v3(233.65,244.04) 229.79,240.18 229.79,208.36 229.06,207.62 229.06,180.88 227.93,179.75 227.93,179.74 223.09,174.9 223.09,158.83 226.19,155.73 v1(226.19,151.74)
  BOTTOM w0.203: Q5.5 234.6,245.56 234.51,245.65 234.38,245.65 234.08,245.94 R359.1 233.65,245.93 v3(233.65,244.04)
PG_C2M: length 319.5
  TOP w0.191: R482.1 v4(182.41,271.89)
  L5_MIXED w0.191: 193.59,189.42 196.11,186.9 196.11,168.88 194.08,166.85 194.08,161.26 199.09,156.26 199.09,153.52 200,152.6 200,150.47 203.71,146.76 203.71,140.07 204.03,139.74 204.03,137.47 203.66,137.1 203.66,134.14 203.43,133.91 203.43,132.23 205.22,130.44 205.22,129.24 204.68,128.7 204.68,125.86 203.94,125.12 203.94,119.13 204.16,118.9 204.16,115.13 203.05,114.02 203.05,111.33 199.11,107.39 199.11,87.94 197.64,86.46 197.64,58.88 185.39,46.63 183.69,46.63 183.24,46.18 162.38,46.18 159.11,42.91 147.56,42.91 144.83,40.18 144.83,25.12 145.41,24.54 v4(145.41,24.51) ; 185.65,199.67 v1(185.65,202.84) ; v1(176.89,207.11) 176.48,207.52 176.48,209.42 176.89,209.83 176.89,213.79 178.18,215.09 178.18,244.78 184.4,251 184.4,261.8 183.85,262.36 183.85,270.45 v4(182.41,271.89)
  L5_MIXED w0.198: 193.59,189.42 193.59,196.58 192.53,197.64 187.68,197.64 185.65,199.67
  L24_SIGNAL w0.191: v1(185.65,202.84) 179.4,202.84 176.89,205.36 v1(176.89,207.11)
  BOTTOM w0.191: P1.D1 v4(145.41,24.51)
PG_M2C: length 3.5
  TOP w0.191: R586.2 v1(147.93,29.03)
  BOTTOM w0.191: P1.F1 147.93,28.3 v1(147.93,29.03)
PSM_ALERT: length 120.5
  L3_SIGNAL w0.203: v2(201.68,121.29) 202.31,121.91 v2(202.31,123.8) ; v3(209.47,113.26) 208.31,114.43 208.31,120.22 v2(207.42,121.11) ; v3(232.91,95.87) 232.91,94.7 234.24,93.37 234.24,77.57 234.23,77.56 234.23,77.13 234.24,77.12 234.24,76.89 234.98,76.15 234.98,73.48 234.47,72.97 234.47,46.23 v4(234.7,46) ; v2(214.43,120.68) 214.43,121.89 213.89,122.43 213.89,123.55 v2(214.17,123.83)
  L5_MIXED w0.203: v2(207.42,121.11) 208.53,121.11 208.81,121.39 208.81,122.45 208.59,122.67 v2(208.59,123.8)
  L24_SIGNAL w0.203: v2(214.43,120.68) 214.22,120.88 213.69,120.88 213.45,121.12 207.43,121.12 v2(207.42,121.11) 207.06,121.46 201.85,121.46 v2(201.68,121.29) ; v3(215.11,110.46) 220.37,105.21 225.66,105.21 230.02,100.84 230.02,98.76 v3(232.91,95.87)
  BOTTOM w0.203: v3(215.11,110.46) 214.77,110.12 210.43,110.12 210.07,110.48 R633.1 209.04,111.07 208.64,111.48 208.64,113.23 R604.1 v3(209.47,113.26) ; U11.Y2 v2(202.31,123.8) ; v2(214.17,123.83) 213.85,124.14 U11.F2 ; U11.N2 208.59,123.81 v2(208.59,123.8) ; R528.2 v4(234.7,46)
PSM_CONTROL: length 48.5
  TOP w0.191: Q9.6 224.53,123.24 v1(223.19,123.24)
  L5_MIXED w0.191: v1(223.19,123.24) 221.51,121.56 v2(213.79,121.56)
  L22_MIXED w0.191: v2(201.78,122.39) 200.85,122.39 200.66,122.58 200.66,124.12 201.13,124.59 v2(202.23,124.59)
  L24_SIGNAL w0.114: v2(201.78,122.39) 203.42,122.39 204.11,123.09 206.17,123.09 207.22,122.04 208.21,122.04 v2(208.24,122.07)
  L24_SIGNAL w0.191: v2(208.24,122.07) 208.76,121.56 211.31,121.56 211.32,121.56 v2(213.79,121.56) 213.79,122.96 213.41,123.34 v2(213.41,124.63) ; 207.63,124.6 v2(207.11,124.6)
  L24_SIGNAL w0.198: 211.94,121.56 211.94,122.66 209.99,124.6 207.63,124.6
  BOTTOM w0.191: U11.AA3 201.87,124.95 v2(202.23,124.59) ; U11.F1 213.85,121.63 v2(213.79,121.56) ; U11.P3 v2(207.11,124.6) ; U11.G3 213.09,124.95 v2(213.41,124.63) ; U11.Y1 202.56,123.25 202.56,123.17 v2(201.78,122.39) ; U11.N1 208.25,122.85 208.24,122.83 v2(208.24,122.07) R136.2 208.24,118.62 R628.1
PSM_FAULT: length 104.8
  L3_SIGNAL w0.203: v2(205.38,121.89) 204.47,120.98 204.47,115.22 v3(205.72,113.97) ; v3(215.47,122.3) 215.91,121.86 215.91,113.5 v3(215.47,113.06) ; v4(233.25,74.83) 232.74,75.34 232.74,79.1 233.22,79.58 233.22,92.33 231.17,94.39 231.17,101.19 233.81,103.84 233.81,113.31 v3(233.55,113.56)
  L22_MIXED w0.203: v3(215.47,122.3) 213,122.3 211.94,121.23 210.79,121.23 v1(209.8,122.22) 209.22,121.64 205.64,121.64 v2(205.38,121.89)
  L24_SIGNAL w0.203: v3(215.47,113.06) 219.71,113.06 220.85,111.91 231.9,111.91 v3(233.55,113.56)
  BOTTOM w0.203: R62.1 v4(233.25,74.83) ; v2(205.38,121.89) 205.05,122.22 U11.U1 U11.V1 U11.V2 204.27,124.15 204.39,124.03 204.85,124.03 204.97,124.15 U11.U2 ; U11.C1 216.25,122.96 215.75,122.45 215.45,122.45 215.45,122.47 215.42,122.43 215.42,122.35 v3(215.47,122.3) ; U11.C1 U11.C2 U11.D2 ; U11.C1 U11.D1 ; v1(209.8,122.22) 209.8,122.34 209.85,122.39 U11.L1 ; U11.L1 U11.L2 ; U11.L1 U11.K1 U11.K2 ; R602.1 206.03,113.97 v3(205.72,113.97) 205.26,113.97 205.18,114.05 205.04,114.05 204.94,114.14 R634.1
PSM_PGOOD: length 130.5
  TOP w0.191: R555.2 TP33.1 ; R586.1 147.93,31.95 v1(147.52,32.36)
  L5_MIXED w0.191: v1(147.52,32.36) 147.52,41.15 148.89,42.52 159.57,42.52 162.84,45.79 183.4,45.79 183.43,45.82 186.66,45.82 200.1,59.26 200.1,75.87 206.69,82.46 206.69,109.74 204.06,112.37 v1(204.06,113.46)
PSM_RUN: length 165.8
  TOP w0.203: U33.B10 U33.B11 217.35,50.14 v4(216.92,49.71) ; U33.Y8 U33.Y9 219.36,68.34 219.07,68.72 v4(218.95,68.73) ; Q9.3 v3(225.06,124.39)
  L3_SIGNAL w0.203: v4(233.3,44.73) 233.3,46.08 230.67,48.7 230.67,50.04 231.06,50.43 231.06,69.89 229.97,70.98 229.97,76.53 v3(230.05,76.61) 230.05,79.76 218.24,91.57 v1(218.24,111.2) ; v1(206.65,111.51) 206.65,111.68 207.11,112.14 207.11,114.17 206.71,114.58 206.71,118.8 207.04,119.13 v1(207.04,119.86)
  L24_SIGNAL w0.203: v1(207.04,119.86) 208.79,118.11 210.49,118.11 211.33,117.27 219.18,117.27 219.76,117.86 219.76,119.76 222.22,122.22 224,122.22 225.06,123.28 v3(225.06,124.39) ; v4(216.92,49.71) 216.92,49.48 217.3,49.09 217.3,49.02 217.36,48.97 217.36,44.29 218.82,42.82 232.18,42.82 233.3,43.94 v4(233.3,44.73) ; v4(218.95,68.73) 218.92,68.73 218.36,69.29 218.36,71.92 218.31,71.97 218.31,74.65 220.47,76.81 229.84,76.81 v3(230.05,76.61) ; v1(218.24,111.2) 217.32,112.12 212.62,112.12 211.89,111.38 209.61,111.38 209.59,111.35 209.1,111.35 209.08,111.38 206.78,111.38 v1(206.65,111.51)
  BOTTOM w0.203: R429.1 v4(233.3,44.73) ; R136.1 v1(207.04,119.86)
PSM_SCL: length 49
  TOP w0.191: R646.1 209.22,116.81 v1(210.57,115.47) ; v1(232.71,117.63) 233.17,117.63 233.91,116.89 P7.1 ; R597.1 216.61,115.42 v3(216.59,115.39) ; v2(202.53,116.71) 202.21,117.04 R672.1
  L24_SIGNAL w0.254: v2(202.53,116.71) 203.04,116.2 209.83,116.2 v1(210.57,115.47) 216.51,115.47 v3(216.59,115.39) 220.15,115.39 221.65,113.89 228.68,113.89 230.56,115.77 v2(230.56,118.72)
  BOTTOM w0.254: R433.1 232.6,117.53 P5.3 ; R433.1 229.99,118.15 v2(230.56,118.72) ; R433.1 R149.2
PSM_SDA: length 46.8
  TOP w0.191: R647.1 210.03,116.74 210.74,116.03 v1(211.25,116.03) ; R598.1 215.42,116.43 v3(215.39,116.41) ; v2(202.97,117.5) 202.82,117.65 R673.1 ; v1(232.69,121.56) 234.48,121.56 P7.3
  L24_SIGNAL w0.254: v2(229.54,119.25) 230.1,118.69 230.1,115.96 228.49,114.35 222.6,114.35 221.01,115.94 215.86,115.94 v3(215.39,116.41) 215.01,116.03 v1(211.25,116.03) 210.24,117.04 206.25,117.04 205.93,117.36 203.11,117.36 v2(202.97,117.5)
  BOTTOM w0.254: v2(229.54,119.25) 229.97,119.68 229.97,120.36 R374.2 R434.1 229.94,121.57 P5.1
PSM_SHARE_CLK: length 154.1
  TOP w0.203: v4(216.98,69.7) 217.04,69.64 217.35,69.23 U33.AA11 ; U33.D8 v4(219.91,52.65) ; v2(205.85,122.39) 206.09,122.16 R679.2 206.43,121.26 206.86,121.69 208.01,121.69 208.06,121.64 208.42,121.64 208.47,121.69 210.37,121.69 R653.2 210.75,122.07 v2(211.1,122.07) 214.3,122.07 214.86,121.51 217.12,121.51 v1(218.34,122.73) R143.2
  L3_SIGNAL w0.203: v4(233.26,52.52) 233.26,70.63 232.82,71.07 232.82,72.68 232.78,72.71 232.78,73.72 231.65,74.85 231.65,79.88 v3(232.03,80.26) ; v2(211.1,122.07) 211.38,121.79 211.38,120.49 212.17,119.71 212.17,115.6 211.38,114.81 211.38,112.1 211.4,112.08 211.4,107.87 215.93,103.35 215.93,100.03 212.37,96.47 212.37,82.45 216.98,77.84 v4(216.98,69.7)
  L24_SIGNAL w0.203: v4(216.98,69.7) 216.98,70.24 216.92,70.31 216.92,73.3 216.08,74.14 216.08,77.17 219.18,80.26 v3(232.03,80.26) ; v4(233.26,52.52) 232.88,52.14 232.71,52.14 228.35,47.78 220.18,47.78 219.98,47.98 219.98,49.06 220.63,49.71 220.63,51.74 219.91,52.45 v4(219.91,52.65)
  BOTTOM w0.203: R379.1 233.73,52.52 v4(233.26,52.52) ; U11.T1 v2(205.85,122.39) ; U11.J1 211.45,122.45 211.1,122.1 v2(211.1,122.07) ; U11.B1 217.67,122.73 v1(218.34,122.73)
PSM_VDD3_A: length 84.5
  TOP w0.191: R142.1 218.02,120.26 R599.1 R600.1 214.93,120.26 v1(214.51,119.84) ; v1(217.45,125.37) 218.01,125.37 218.34,125.04 R143.1 221.11,124.45 v1(221.12,124.46) ; v1(217.45,125.37) 217.42,125.35 C210.1 217.31,125.37 v1(217.45,125.37) ; v1(224.86,131.54) 224.86,132.53 226.01,133.68 R629.1
  L9_POWER w0.381: v1(221.12,124.46) 223.02,124.46 224.08,123.41 224.08,121.04 v1(223.77,120.73) 222.45,119.41 220.65,119.41 219.91,120.14 214.81,120.14 v1(214.51,119.84) 213.84,119.18 212.95,119.18 211.1,121.03 209.73,121.03 207.27,118.58 v1(207.27,117.82)
  L24_SIGNAL w0.254: v1(224.86,131.54) 224.86,132.45 222.05,135.25 v2(219.89,135.25)
  BOTTOM w0.191: U11.B4 217.07,125.75 v1(217.45,125.37) 217.82,125.75 U11.A4 ; R603.2 206.77,112.26 207.6,113.09 R604.2 207.59,113.27 R602.2 ; R154.2 R155.2 R157.2 R156.2 R150.2 R153.2 R152.2 R151.2 v1(224.86,131.54) ; R666.2 R665.2 219.72,135.09 v2(219.89,135.25) ; R602.2 R635.2 ; R602.2 208.23,115.17 208.23,116.87 v1(207.27,117.82) R628.2 ; v1(223.77,120.73) R626.1
  BOTTOM w0.254: R626.1 226.19,121.5 226.62,121.92 226.62,125.39 R154.2
  BOTTOM w0.381: R636.2 200.21,115.64 199.85,115.28 199.85,112.88 200.46,112.26 R603.2
PSM_VDD3_B: length 36.1
  TOP w0.191: v2(206.27,125.37) 206.25,125.35 C721.1 ; Q22.2 223.05,115.12 222.48,115.7 v1(222.48,115.76) ; R78.1 203.18,121.53 204.29,120.42 205.1,120.42 v1(205.17,120.36) 205.19,120.38 R679.1
  L5_MIXED w0.254: v1(205.17,120.36) 204.85,120.68 204.85,123.34 205.8,124.29 205.8,124.81 205.87,124.88 205.87,124.94 206.27,125.35 v2(206.27,125.37)
  L9_POWER w0.381: v1(222.48,115.76) 222.42,115.7 219.48,115.7 218.31,114.53 215.52,114.53 214.58,115.47 212.06,115.47 211.2,114.6 210.01,114.6 208.08,116.54 205.87,116.54 205.17,117.23 v1(205.17,120.36)
  BOTTOM w0.191: R676.1 v1(205.17,120.36) 205.1,120.42 R708.1 ; U11.T4 U11.R4 206.28,125.37 v2(206.27,125.37)
PSM_VDD3_C: length 25.1
  TOP w0.191: v1(221.06,118.11) 221.19,118.25 Q13.2 ; R653.1 210.57,120.09 210.58,120.08 ; 210.58,120.08 v1(210.63,120.03) ; 210.58,120.08 R703.1 209.22,120.08 R68.1
  L3_SIGNAL w0.254: v1(211.86,125.45) 211.33,124.92 211.33,123.85 210.52,123.04 210.52,120.15 v1(210.63,120.03)
  L9_POWER w0.381: v1(221.06,118.11) 219.56,118.11 218.78,117.34 216.01,117.34 215.52,117.83 v1(213.08,117.83) 212.09,117.83 210.63,119.29 v1(210.63,120.03)
  BOTTOM w0.191: U11.J4 211.78,125.43 211.84,125.43 v1(211.86,125.45) 211.96,125.45 U11.H4 ; v1(213.08,117.83) 213.08,118.73 R650.1
RBIAS_EXT_F_A: length 0.8
  TOP w0.191: v4(112.7,134.53) U1A.AH5
RBIAS_EXT_F_B: length 0.8
  TOP w0.127: v4(131.9,134.53) U1A.B5
REFCLK_N: length 140.9
  TOP w0.133: C334.1 39.46,219.69 C333.2 v7(39.44,220.1)
  L3_SIGNAL w0.108: v7(123.1,136.93) 122.8,136.63 122.54,136.63 122.46,136.55 121.66,136.55 121.23,136.12 115.33,136.12 114.74,136.71 109.83,136.71 108.99,135.87 106.22,135.87 104.17,137.92 101.38,137.92 87.86,151.44 87.86,153.31 73.43,167.75 65.88,167.75 52.91,180.72 52.91,205.54 52.91,205.66 46.82,211.75 42.36,211.75 38.05,216.06 38.05,218.23 38.6,218.78 39.33,218.78 39.44,218.89 v7(39.44,220.1)
REFCLK_P: length 139
  TOP w0.133: C332.1 39.46,217.57 C331.2 v7(39.44,217.16)
  L3_SIGNAL w0.108: v7(122.3,136.93) 122.22,136.84 121.54,136.84 121.11,136.42 115.45,136.42 114.86,137.01 109.7,137.01 108.86,136.17 106.34,136.17 104.29,138.22 101.5,138.22 88.16,151.57 88.16,151.69 88.16,151.69 88.16,153.44 73.55,168.05 66,168.05 53.21,180.84 53.21,205.78 46.94,212.05 42.48,212.05 38.35,216.19 38.35,218.1 38.73,218.48 39.33,218.48 39.44,218.37 v7(39.44,217.16)
REFIN_DUT_N: length 3
  BOTTOM w0.191: R735.1 33.21,205.34 C771.2
  BOTTOM w0.254: R735.1 33.51,204.12 33.51,204.03 33.53,204 33.53,203.93 33.53,203.92 33.53,203.44 33.53,203.44 33.53,203.29 33.51,203.26 U51.18
REFIN_DUT_P: length 2.9
  BOTTOM w0.191: R735.2 34.21,205.29 C772.2
  BOTTOM w0.254: R735.2 34.01,204.22 U51.19
REFN_OSC: length 1
  BOTTOM w0.191: C766.1 R29.2
REFP_OSC: length 0.9
  BOTTOM w0.191: C765.1 56.49,239 R28.2
RESETB_FMC: length 98.1
  TOP w0.191: R277.2 v1(76.23,76.53)
  L5_MIXED w0.114: v4(136.53,24.51) 136.53,28.93 136.35,29.1 136.32,29.1 136.04,29.39 136.04,29.42 134.54,30.91 134.54,40.77 120.29,55.02 89.65,55.02 89.54,54.91 88.87,54.91 75.29,68.49 75.29,75.59 v1(76.23,76.53)
  BOTTOM w0.191: P1.D8 v4(136.53,24.51)
SPI2_CS0: length 150.3
  TOP w0.191: v1(34.95,173.28) 34.9,173.23 R243.1
  L24_SIGNAL w0.114: v1(34.95,173.28) 38.81,169.42 71.32,169.42 82.91,157.84 100.15,157.84 101.07,156.92 v4(108.97,156.92)
  BOTTOM w0.191: R584.2 v4(108.97,156.92)
SPI2_CS0_FMC: length 136.4
  TOP w0.191: v4(34.78,93.83) R263.2
  L3_SIGNAL w0.114: v4(34.78,93.83) 34.65,93.7 v1(34.65,53.37)
  L5_MIXED w0.114: v1(34.65,53.37) 35.82,52.2 73.29,52.2 82.13,43.36 100.47,43.36 110.1,33.73 110.14,33.73 111.25,32.62 111.33,32.62 111.61,32.33 111.61,30.02 111.73,29.9 111.73,25.17 v4(112.4,24.51)
  BOTTOM w0.191: P1.D27 v4(112.4,24.51)
SPI2_CS1: length 143.3
  TOP w0.191: v1(33.63,173.86) 33.63,110.19 33.6,110.16 TP64.1 33.76,109.9 R257.1
  L24_SIGNAL w0.114: 29.21,178.29 v1(33.63,173.86)
  L24_SIGNAL w0.133: 29.21,178.29 27.38,180.12 27.38,216.91 28.85,218.39 28.85,223.47 21.08,231.24 12.6,231.24 11.38,232.46 v4(11.33,232.46)
  BOTTOM w0.191: R514.1 11.66,232.13 v4(11.33,232.46)
SPI2_CS1_FMC: length 134.7
  TOP w0.191: v4(33.63,93.8) R269.2
  L3_SIGNAL w0.114: v4(33.63,93.8) 33.51,93.67 33.51,46.78 v1(33.6,46.69)
  L5_MIXED w0.114: v1(33.6,46.69) 55.73,46.69 56.85,45.57 57.6,45.57 57.66,45.51 58.06,45.51 58.12,45.57 70.18,45.57 74.62,41.12 88.27,41.12 88.28,41.13 99.41,41.13 99.42,41.12 99.53,41.12 99.59,41.12 106.38,34.34 106.38,32.98 106.74,32.62 107.52,32.62 107.92,32.21 107.92,28.98 v4(108.59,28.32)
  BOTTOM w0.191: P1.G30 v4(108.59,28.32)
SPI2_CS2: length 2.8
  TOP w0.191: TP58.1 32.62,108.64 R244.1
SPI2_CS2_FMC: length 135.4
  TOP w0.191: v4(32.49,93.82) R275.2
  L3_SIGNAL w0.114: v1(32.33,45.57) 32.36,45.6 32.36,93.7 v4(32.49,93.82)
  L5_MIXED w0.114: v4(107.31,28.32) 106.63,28.32 105.94,29.01 105.93,29.01 105.64,29.3 105.64,31.84 105.56,31.93 105.56,32.33 105.64,32.42 105.64,34 99.15,40.5 88.54,40.5 88.53,40.49 67.9,40.49 67.37,41.02 67.36,41.02 65.51,42.88 35.02,42.88 v1(32.33,45.57)
  BOTTOM w0.191: P1.G31 v4(107.31,28.32)
SPI2_CS3: length 1.5
  TOP w0.191: TP41.1 31.47,107.22 R250.1
SPI2_CS3_FMC: length 136.2
  TOP w0.191: v4(31.35,93.88) 31.3,93.93 R283.2
  L3_SIGNAL w0.114: v1(31.17,41.55) 31.22,41.6 31.22,93.75 v4(31.35,93.88)
  L5_MIXED w0.114: v4(103.5,29.59) 104.29,30.37 104.29,31.06 104.38,31.16 104.38,34.3 98.86,39.83 98.77,39.83 98.73,39.86 98.37,39.86 98.36,39.87 88.8,39.87 88.79,39.86 88.74,39.86 88.18,39.3 52.17,39.3 51.84,39.62 33.09,39.62 v1(31.17,41.55)
  BOTTOM w0.191: P1.H34 v4(103.5,29.59)
SPI2_CS4: length 92.3
  TOP w0.191: R258.1 30.33,108.72 30.35,108.74 TP40.1 31.29,109.88 31.31,109.88 32.66,111.24 32.66,187.6 v1(34.24,189.18)
  BOTTOM w0.191: U51.40 34.98,196.04 34.98,195.19 35.15,195.02 35.15,190.09 v1(34.24,189.18)
SPI2_CS4_FMC: length 137.9
  TOP w0.191: v4(30.2,93.85) 30.08,93.98 R278.2
  L3_SIGNAL w0.114: v1(30.13,38.92) 30.08,38.98 30.08,93.72 v4(30.2,93.85)
  L5_MIXED w0.114: v4(102.24,29.59) 101.72,30.11 101.72,30.48 101.77,30.53 101.77,31.19 101.72,31.25 101.72,32.27 101.75,32.3 101.75,32.33 102.03,32.62 102.2,32.62 102.72,33.15 102.72,34.82 98.32,39.22 98.12,39.22 98.1,39.24 89.06,39.24 88.49,38.67 51.86,38.67 51.6,38.92 v1(30.13,38.92)
  BOTTOM w0.191: P1.H35 v4(102.24,29.59)
SPI2_CS5: length 1.8
  TOP w0.191: TP59.1 23.65,107.92 R251.1
SPI2_CS5_FMC: length 143.3
  TOP w0.191: R284.2 v4(23.96,94.15)
  L3_SIGNAL w0.114: v4(23.96,94.15) 24.47,93.64 24.47,38.41 v1(23.83,37.77)
  L5_MIXED w0.114: v1(23.83,37.77) 40.19,37.77 40.44,37.52 88.78,37.52 89.51,38.25 96,38.25 98.64,35.61 98.64,33.63 99.36,32.91 99.61,32.91 100.18,32.33 100.18,31.64 99.9,31.35 99.12,31.35 99.01,31.24 99.01,30.28 v4(99.69,29.59)
  BOTTOM w0.191: P1.H37 v4(99.69,29.59)
SPI2_SCLK: length 325.6
  TOP w0.191: R249.1 38.33,173.13 38.94,173.74 38.94,177.52 38.02,178.44 38.02,190.63 34.74,193.91 v1(34.06,193.91)
  L3_SIGNAL w0.191: v4(12.27,232.89) 12.27,233.44 12.46,233.63 13.97,233.63 14.96,232.64 16.61,232.64 16.99,232.26 28.35,232.26 30.1,230.5 30.1,210.57 28.17,208.64 28.17,194.87 29.69,193.34 33.49,193.34 v1(34.06,193.91)
  L24_SIGNAL w0.114: v4(107.92,159.05) 91.36,159.05 65.51,184.91 49.35,184.91 39.47,175.03 38.2,175.03 38.2,175.89 31.78,182.32 31.78,190.55
  L24_SIGNAL w0.133: 31.78,190.55 31.78,195.93 31.17,196.55 31.17,229.67 25.53,235.31 13.36,235.31 12.27,234.21 v4(12.27,232.89)
  BOTTOM w0.191: R413.1 12.55,232.51 12.27,232.79 v4(12.27,232.89) ; v1(34.06,193.91) 34.06,195.5 34.01,195.55 U51.42 ; R582.2 108.08,159.21 v4(107.92,159.05)
SPI2_SCLK_FMC: length 128.7
  TOP w0.191: v4(38.2,93.88) R282.2
  L3_SIGNAL w0.114: v4(38.2,93.88) 38.08,93.75 38.08,50.09 v1(38.2,49.96)
  L5_MIXED w0.114: v4(111.12,29.59) 111.12,30.12 108.87,32.38 108.87,33.18 99.95,42.1 79.72,42.1 71.35,50.47 45.3,50.47 45.27,50.5 44.8,50.5 44.77,50.47 38.71,50.47 v1(38.2,49.96)
  BOTTOM w0.191: P1.H28 v4(111.12,29.59)
SPI2_SDIO: length 315.7
  TOP w0.191: v1(34.52,191.57) 35.41,191.57 37.26,189.71 37.26,178.03 37.67,177.62 37.67,173.41 37.19,172.93 R239.1
  L3_SIGNAL w0.191: v1(34.52,191.57) 29.64,191.57 26.85,194.36 26.85,208.69 29.11,210.95 29.11,229.79 27.64,231.27 13.72,231.27 13.21,231.78 v4(13.21,232.79)
  L24_SIGNAL w0.114: v4(108.53,158.06) 101.3,158.06 100.91,158.45 84.18,158.45 72.52,170.1 41.05,170.1 37.06,174.09 34.98,174.09 30.53,178.54
  L24_SIGNAL w0.133: v4(13.21,232.79) 13.21,233.76 14.12,234.67 21.21,234.67 29.9,225.98 29.9,203.94 30.65,203.19 30.65,196.86 29.74,195.96 29.74,179.33 30.53,178.54
  BOTTOM w0.191: R410.1 13.44,232.56 v4(13.21,232.79) ; v1(34.52,191.57) 34.61,191.66 34.61,194.14 34.51,194.24 U51.41 ; R583.2 v4(108.53,158.06)
SPI2_SDIO_FMC: length 129.8
  TOP w0.191: v4(37.06,93.85) R272.2
  L3_SIGNAL w0.114: v4(37.06,93.85) 36.93,93.72 36.93,49.22 v1(37.13,49.02)
  L5_MIXED w0.114: v4(109.85,29.59) 109.85,30.89 108.55,32.19 108.55,33.05 99.82,41.78 78.54,41.78 70.48,49.83 54.02,49.83 53.6,49.42 45.32,49.42 45.27,49.37 44.8,49.37 44.75,49.42 38.81,49.42 38.41,49.02 v1(37.13,49.02)
  BOTTOM w0.191: P1.H29 v4(109.85,29.59)
SPI2_SDO: length 183.1
  TOP w0.191: R256.1 36.05,174.49 35.23,175.31 35.23,189.74 33.53,191.44 33.53,194.95 v1(33.51,194.97)
  L24_SIGNAL w0.114: v1(107.85,160.45) 90.86,160.45 63.81,187.5 41.63,187.5 34.16,194.97 v1(33.51,194.97)
  BOTTOM w0.191: U51.43 v1(33.51,194.97) ; R581.2 v1(107.85,160.45)
SPI2_SDO_FMC: length 136.4
  TOP w0.191: v4(35.92,93.88) R266.2
  L3_SIGNAL w0.114: v1(35.61,54.08) 35.61,93.57 v4(35.92,93.88)
  L5_MIXED w0.114: v4(113.66,24.51) 112.88,25.29 112.88,28.52 112.83,28.57 112.83,32.05 100.86,44.02 82.92,44.02 81.91,45.03 81.06,45.03 73.05,53.04 73.04,53.04 72.89,53.18 59.92,53.18 58.84,54.25 35.79,54.25 v1(35.61,54.08)
  BOTTOM w0.191: P1.D26 v4(113.66,24.51)
SRXA_0N: length 49.4
  BOTTOM w0.127: 112.7,118.41 v4(112.7,118.53)
  BOTTOM w0.133: C86.2 106.28,73.89 106.86,73.89 106.95,73.98 106.95,74.2 107.04,74.29 107.26,74.29 107.37,74.4 107.37,74.61 107.46,74.7 107.67,74.7 107.76,74.79 107.76,75.01 107.85,75.1 108.07,75.1 108.16,75.19 108.16,75.4 108.25,75.49 108.46,75.49 108.55,75.58 108.55,75.8 108.64,75.89 108.86,75.89 108.95,75.98 108.95,76.19 109.04,76.28 109.25,76.28 109.37,76.4 109.37,76.62 109.46,76.71 109.68,76.71 109.82,76.85 109.82,77.05 109.67,77.2 109.67,77.33 109.82,77.48 109.82,77.61 109.67,77.76 109.67,77.89 109.82,78.04 109.82,78.19 109.67,78.35 109.67,78.47 109.82,78.63 109.82,78.75 109.67,78.91 109.67,79.03 109.82,79.18 109.82,79.31 109.67,79.46 109.67,79.59 109.82,79.74 109.82,102.39 112.67,105.23 112.67,118.03 112.67,118.04 112.67,118.38 112.7,118.41
SRXA_0N_FMC: length 44
  BOTTOM w0.133: C86.1 105.44,73.88 104.2,73.88 99.54,69.22 99.54,47.14 98.29,45.9 98.29,34.54 P1.M39
SRXA_0P: length 49.4
  BOTTOM w0.127: v4(112.7,119.33) 112.7,119.09 112.86,118.93
  BOTTOM w0.133: C74.2 106.31,73.58 106.99,73.58 110.13,76.73 110.13,102.26 112.98,105.1 112.98,117.91 112.98,117.91 112.98,118.25 113.01,118.28 113.1,118.37 113.1,118.69 112.87,118.93 112.86,118.93
SRXA_0P_FMC: length 43.9
  BOTTOM w0.133: C74.1 105.44,73.57 104.33,73.57 99.85,69.09 99.85,47.01 98.6,45.77 98.6,37.58 98.76,37.43 98.76,37.3 98.6,37.15 98.6,36.94 98.76,36.79 98.76,36.66 98.6,36.51 98.6,36.31 98.76,36.16 98.76,36.03 98.6,35.88 98.6,35.59 98.77,35.42 98.77,35.23 98.6,35.06 98.6,34.49 P1.M38
SRXA_1N: length 46.1
  BOTTOM w0.127: 110.95,118.15 110.95,118.16 111.1,118.31 v4(111.1,118.53)
  BOTTOM w0.133: C87.2 106.16,76.71 arc(106.26,76.65) 106.38,76.62 106.97,76.62 arc(107.18,76.66) 107.35,76.78 108.41,77.83 arc(108.48,77.94) 108.5,78.06 108.5,101.79 108.53,101.81 108.53,107.44 110.97,109.89 110.97,110.36 110.74,110.59 110.74,110.85 110.97,111.07 110.97,111.3 110.74,111.54 110.74,111.73 110.97,111.96 110.97,112.42 110.72,112.67 110.72,112.86 110.97,113.11 110.97,113.46 110.72,113.71 110.72,113.9 110.97,114.15 110.97,114.45 110.74,114.69 110.74,114.88 110.95,115.09 110.95,115.29 110.74,115.49 110.74,115.77 110.97,116 110.97,116.23 110.72,116.48 110.72,116.67 110.97,116.92 110.97,117.17 110.74,117.4 110.74,117.6 110.95,117.81 110.95,118.15
SRXA_1N_FMC: length 62.1
  TOP w0.133: v4(97.16,20.7) 97.6,21.15 97.6,71.08 97.61,71.1 97.62,71.12 97.62,71.17 103.04,76.58 104.16,76.58 104.28,76.6 arc(104.32,76.61) 104.35,76.64 104.55,76.82 v10(104.6,76.87)
  BOTTOM w0.127: P1.A39 v4(97.16,20.7)
  BOTTOM w0.133: C87.1 105.44,76.58 104.89,76.58 v10(104.6,76.87)
SRXA_1P: length 46.1
  BOTTOM w0.127: v4(111.1,119.33) 111.5,118.93 111.5,118.23 111.28,118.01 111.28,117.78
  BOTTOM w0.133: C75.2 106.26,76.22 arc(106.32,76.27) 106.4,76.28 106.96,76.28 arc(107.27,76.34) 107.53,76.52 108.74,77.72 arc(108.81,77.84) 108.84,77.97 108.84,107.32 111.28,109.76 111.28,117.78
SRXA_1P_FMC: length 62.1
  TOP w0.133: v4(98.42,20.7) 97.91,21.21 97.91,34.34 98.12,34.54 98.12,34.77 97.91,34.98 97.91,35.2 98.12,35.41 98.12,35.61 97.91,35.82 97.91,36.22 98.07,36.37 98.07,36.63 97.91,36.78 97.91,71.02 103.16,76.27 103.17,76.27 104.31,76.27 v10(104.6,75.98)
  BOTTOM w0.127: P1.A38 v4(98.42,20.7)
  BOTTOM w0.133: v10(104.6,75.98) 104.88,76.27 105.43,76.27 105.6,76.1 C75.1
SRXA_2N: length 41.5
  L24_SIGNAL w0.108: v9(107.14,82.26) 107.41,81.99 107.82,81.99 107.9,82.07 108.05,82.07 108.15,81.97 108.48,81.97 108.61,82.1 108.76,82.1 108.89,81.97 109.21,81.97 109.32,82.08 109.32,82.45 109.25,82.52 109.25,82.75 109.32,82.83 109.32,83.13 109.19,83.26 109.19,83.46 109.32,83.59 109.32,83.87 109.22,83.97 109.22,84.25 109.32,84.35 109.32,84.58 109.22,84.68 109.22,84.91 109.32,85.01 109.32,103.06 arc(109.37,103.29) 109.5,103.48 113.35,107.33 113.35,107.34 arc(113.43,107.47) 113.46,107.62 113.46,116.15 arc(113.43,116.3) 113.35,116.43 113.16,116.61 arc(113.06,116.77) 113.02,116.97 arc(113.04,117.06) 113.09,117.14 113.09,117.14 arc(113.24,117.22) 113.39,117.17 113.39,117.16 arc(113.47,117.06) U1A.AF27
  BOTTOM w0.133: v9(107.14,82.26) 106.85,81.97 106.39,81.97 C88.2
SRXA_2N_FMC: length 54
  L24_SIGNAL w0.108: v9(102.24,34.65) 102.55,34.65 102.71,34.8 102.71,46.69 99.47,49.94 99.47,66.54 101.33,68.41 101.33,79.65 103.64,81.96 104.3,81.96 v9(104.6,82.26)
  BOTTOM w0.133: C88.1 105.45,81.97 104.89,81.97 v9(104.6,82.26) ; P1.M35 102.84,34.04 v9(102.24,34.65)
SRXA_2P: length 41.5
  L24_SIGNAL w0.108: U1A.AF26 113.69,117.54 arc(113.79,117.42) 113.86,117.29 arc(113.88,117.24) 113.91,117.2 arc(113.99,116.94) 113.91,116.67 arc(113.89,116.63) 113.87,116.59 arc(113.8,116.4) 113.78,116.21 113.78,107.52 arc(113.75,107.36) 113.65,107.21 109.71,103.27 arc(109.64,103.17) 109.62,103.06 109.62,81.95 109.34,81.67 107.44,81.67 v9(107.14,81.37)
  BOTTOM w0.133: C76.2 106.26,81.53 106.39,81.66 106.85,81.66 v9(107.14,81.37)
SRXA_2P_FMC: length 54
  L24_SIGNAL w0.108: v9(104.6,81.37) 104.31,81.66 103.76,81.66 101.63,79.53 101.63,68.28 99.76,66.42 99.76,50.1 103.03,46.83 103.03,39.27 103.15,39.15 103.15,39 103.03,38.89 103.03,38.66 103.12,38.57 103.12,38.42 103.03,38.33 103.03,38.07 103.11,38 103.11,37.85 103.03,37.77 103.03,37.52 103.11,37.44 103.11,37.29 103.02,37.2 103.02,37.01 103.12,36.91 103.12,36.68 103.03,36.59 103.03,36.36 103.12,36.27 103.12,36.12 103.05,36.05 103.05,35.89 103.12,35.82 103.12,35.61 103.05,35.54 103.05,34.8 103.16,34.7 v9(103.5,34.7)
  BOTTOM w0.133: v9(103.5,34.7) 104.14,34.06 P1.M34 ; v9(104.6,81.37) 104.88,81.66 105.45,81.66 105.57,81.53 C76.1
SRXA_3N: length 36.7
  L24_SIGNAL w0.108: v9(107.14,84.06) 107.43,84.36 107.86,84.36 108.64,85.14 108.64,85.53 108.79,85.69 108.79,85.81 108.64,85.97 108.64,86.19 108.79,86.35 108.79,86.47 108.64,86.63 108.64,86.96 108.79,87.11 108.79,87.24 108.64,87.39 108.64,87.74 108.79,87.9 108.79,88.02 108.64,88.18 108.64,111.2 111.69,114.26 111.69,116.72 U1A.AH27
  BOTTOM w0.133: v9(107.14,84.06) 106.88,84.32 106.31,84.32 C89.2
SRXA_3N_FMC: length 71.9
  L24_SIGNAL w0.108: v9(104.65,84.07) 104.37,84.35 103.86,84.35 99.35,79.84 99.35,68.46 98.42,67.54 98.42,49.19 101.73,45.89 101.73,21.59 101.35,21.21 100.43,21.21 v9(99.67,21.97)
  BOTTOM w0.133: v9(104.65,84.07) 104.9,84.32 105.35,84.32 105.47,84.2 C89.1 ; v9(99.67,21.97) 100.3,21.34 P1.B37
SRXA_3P: length 36.7
  L24_SIGNAL w0.108: U1A.AH26 111.9,117.51 111.4,117.01 111.4,114.38 108.34,111.32 108.34,85.26 107.73,84.66 107.43,84.66 v9(107.14,84.95)
  BOTTOM w0.133: v9(107.14,84.95) 106.82,84.64 106.39,84.64 C77.2
SRXA_3P_FMC: length 71.9
  L24_SIGNAL w0.108: v9(104.65,84.96) 104.33,84.65 103.73,84.65 99.05,79.96 99.05,68.58 98.13,67.66 98.13,49.07 101.43,45.76 101.43,23.91 101.3,23.77 101.3,23.58 101.43,23.44 101.43,23.03 101.36,22.95 101.36,22.82 101.43,22.75 101.43,21.71 101.22,21.51 100.58,21.51 100.43,21.66 100.43,21.87 100.53,21.97 v9(100.89,21.97)
  BOTTOM w0.133: P1.B36 101.52,21.34 v9(100.89,21.97) ; C77.1 105.45,84.64 104.97,84.64 v9(104.65,84.96)
SRXA_4N: length 48.2
  BOTTOM w0.127: 116,116.21 116,118.43 v4(115.9,118.53)
  BOTTOM w0.133: C90.2 115.6,73.57 114.97,73.57 114.77,73.76 114.68,73.76 114.55,73.9 114.55,73.99 114.45,74.09 114.23,74.09 114.14,74.18 114.14,74.39 114.05,74.48 113.84,74.48 113.75,74.57 113.75,74.79 113.64,74.9 113.42,74.9 113.33,74.99 113.33,75.21 113.16,75.38 113.16,95.98 115.37,98.2 115.39,98.2 116,98.81 116,116.21
SRXA_4N_FMC: length 45.4
  BOTTOM w0.133: P1.M27 113.51,34.52 113.51,35.15 113.33,35.33 113.33,35.59 113.48,35.73 113.48,35.92 113.31,36.09 113.31,36.28 113.44,36.41 113.44,36.59 113.33,36.71 113.33,36.9 113.51,37.08 113.51,37.34 113.35,37.5 113.35,37.68 113.51,37.84 113.51,52.42 110.31,55.62 110.31,63.83 117.29,70.81 117.29,73.35 117.07,73.57 116.46,73.57 C90.1
SRXA_4P: length 48.2
  BOTTOM w0.127: 116.32,116.75 116.32,118.79 115.9,119.2 v4(115.9,119.33)
  BOTTOM w0.133: C78.2 115.6,73.88 115.1,73.88 113.47,75.51 113.47,95.86 113.5,95.86 115.61,97.96 115.61,97.98 116.32,98.68 116.32,116.75
SRXA_4P_FMC: length 45.4
  BOTTOM w0.133: P1.M26 113.82,34.52 113.82,52.55 110.62,55.75 110.62,63.7 117.6,70.68 117.6,73.48 117.2,73.88 116.46,73.88 C78.1
SRXA_5N: length 24.6
  TOP w0.133: C91.2 106.41,95.42 106.85,95.42 v7(107.19,95.76)
  L3_SIGNAL w0.108: v7(107.19,95.76) 107.2,95.76 107.51,95.44 107.67,95.44 107.77,95.55 107.77,96.74 107.62,96.89 107.62,97.02 107.77,97.17 107.77,97.29 107.62,97.45 107.62,97.57 107.77,97.73 107.77,97.93 107.62,98.08 107.62,98.21 107.77,98.36 107.77,98.56 107.62,98.72 107.62,98.84 107.77,99 107.77,99.25 107.62,99.4 107.62,99.53 107.77,99.68 107.77,99.96 107.62,100.11 107.62,100.24 107.77,100.39 107.77,100.6 107.62,100.75 107.62,100.88 107.77,101.03 107.77,101.33 107.62,101.49 107.62,101.61 107.77,101.77 107.77,102.1 107.62,102.25 107.62,102.37 107.77,102.53 107.77,102.78 107.62,102.93 107.62,103.06 107.77,103.21 107.77,103.44 107.62,103.59 107.62,103.72 107.77,103.87 107.77,109.17 111.24,112.63 111.24,115.19 v7(111.1,115.33)
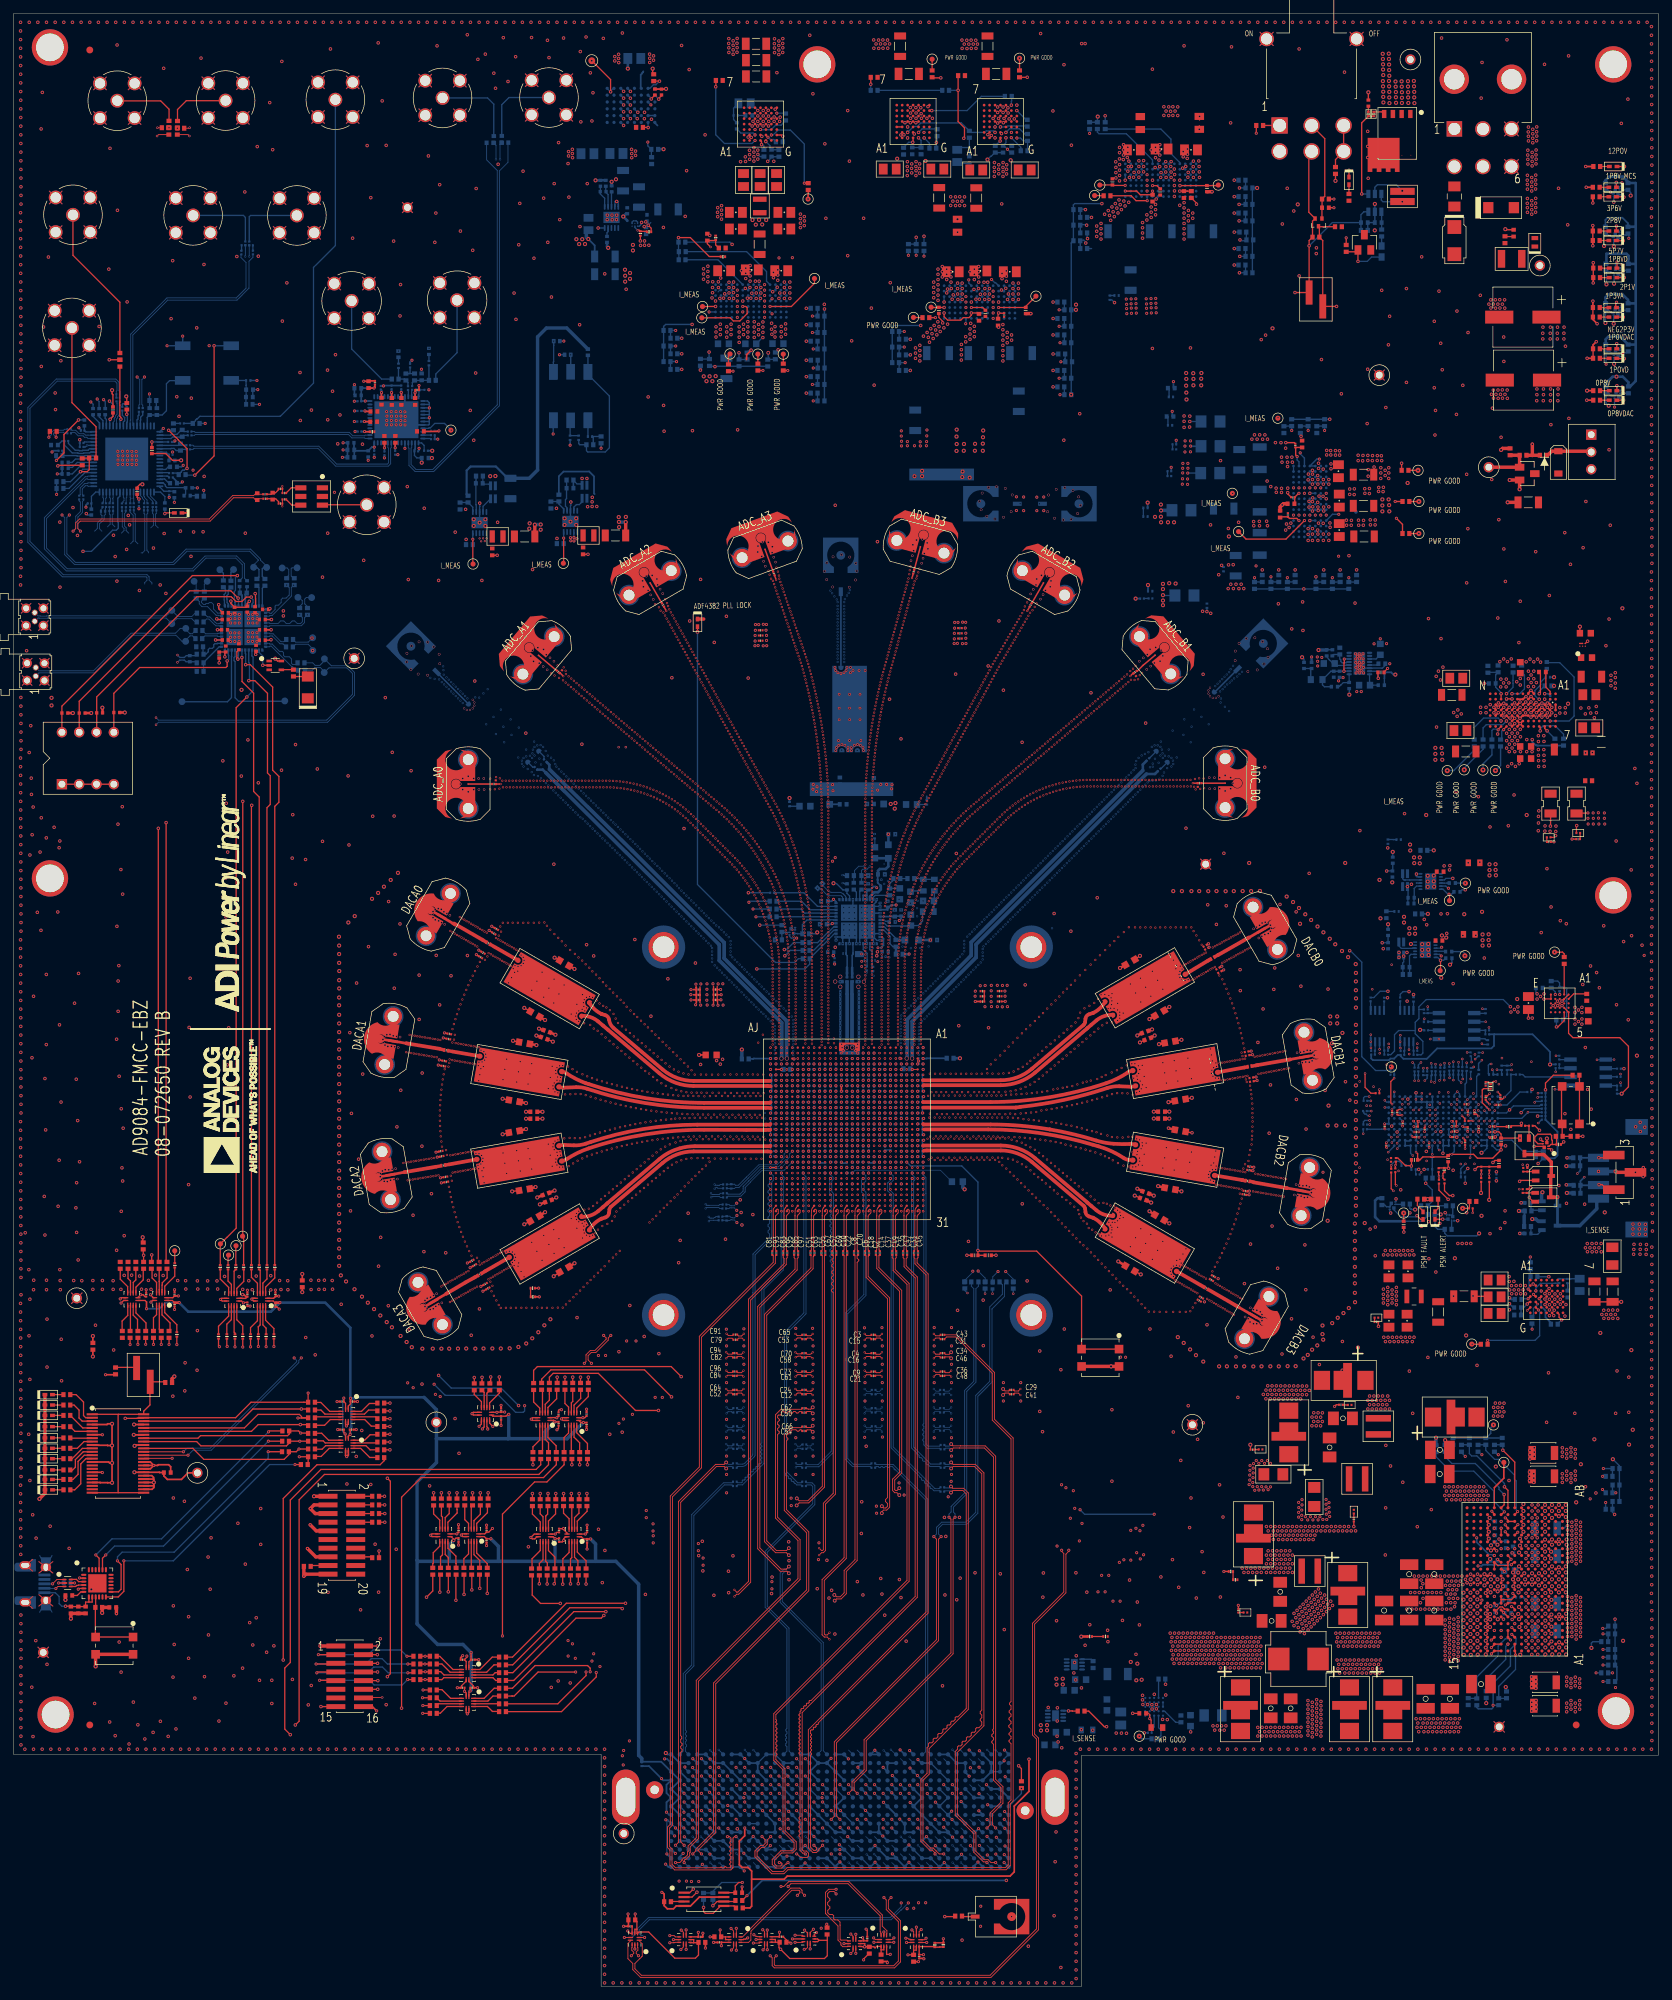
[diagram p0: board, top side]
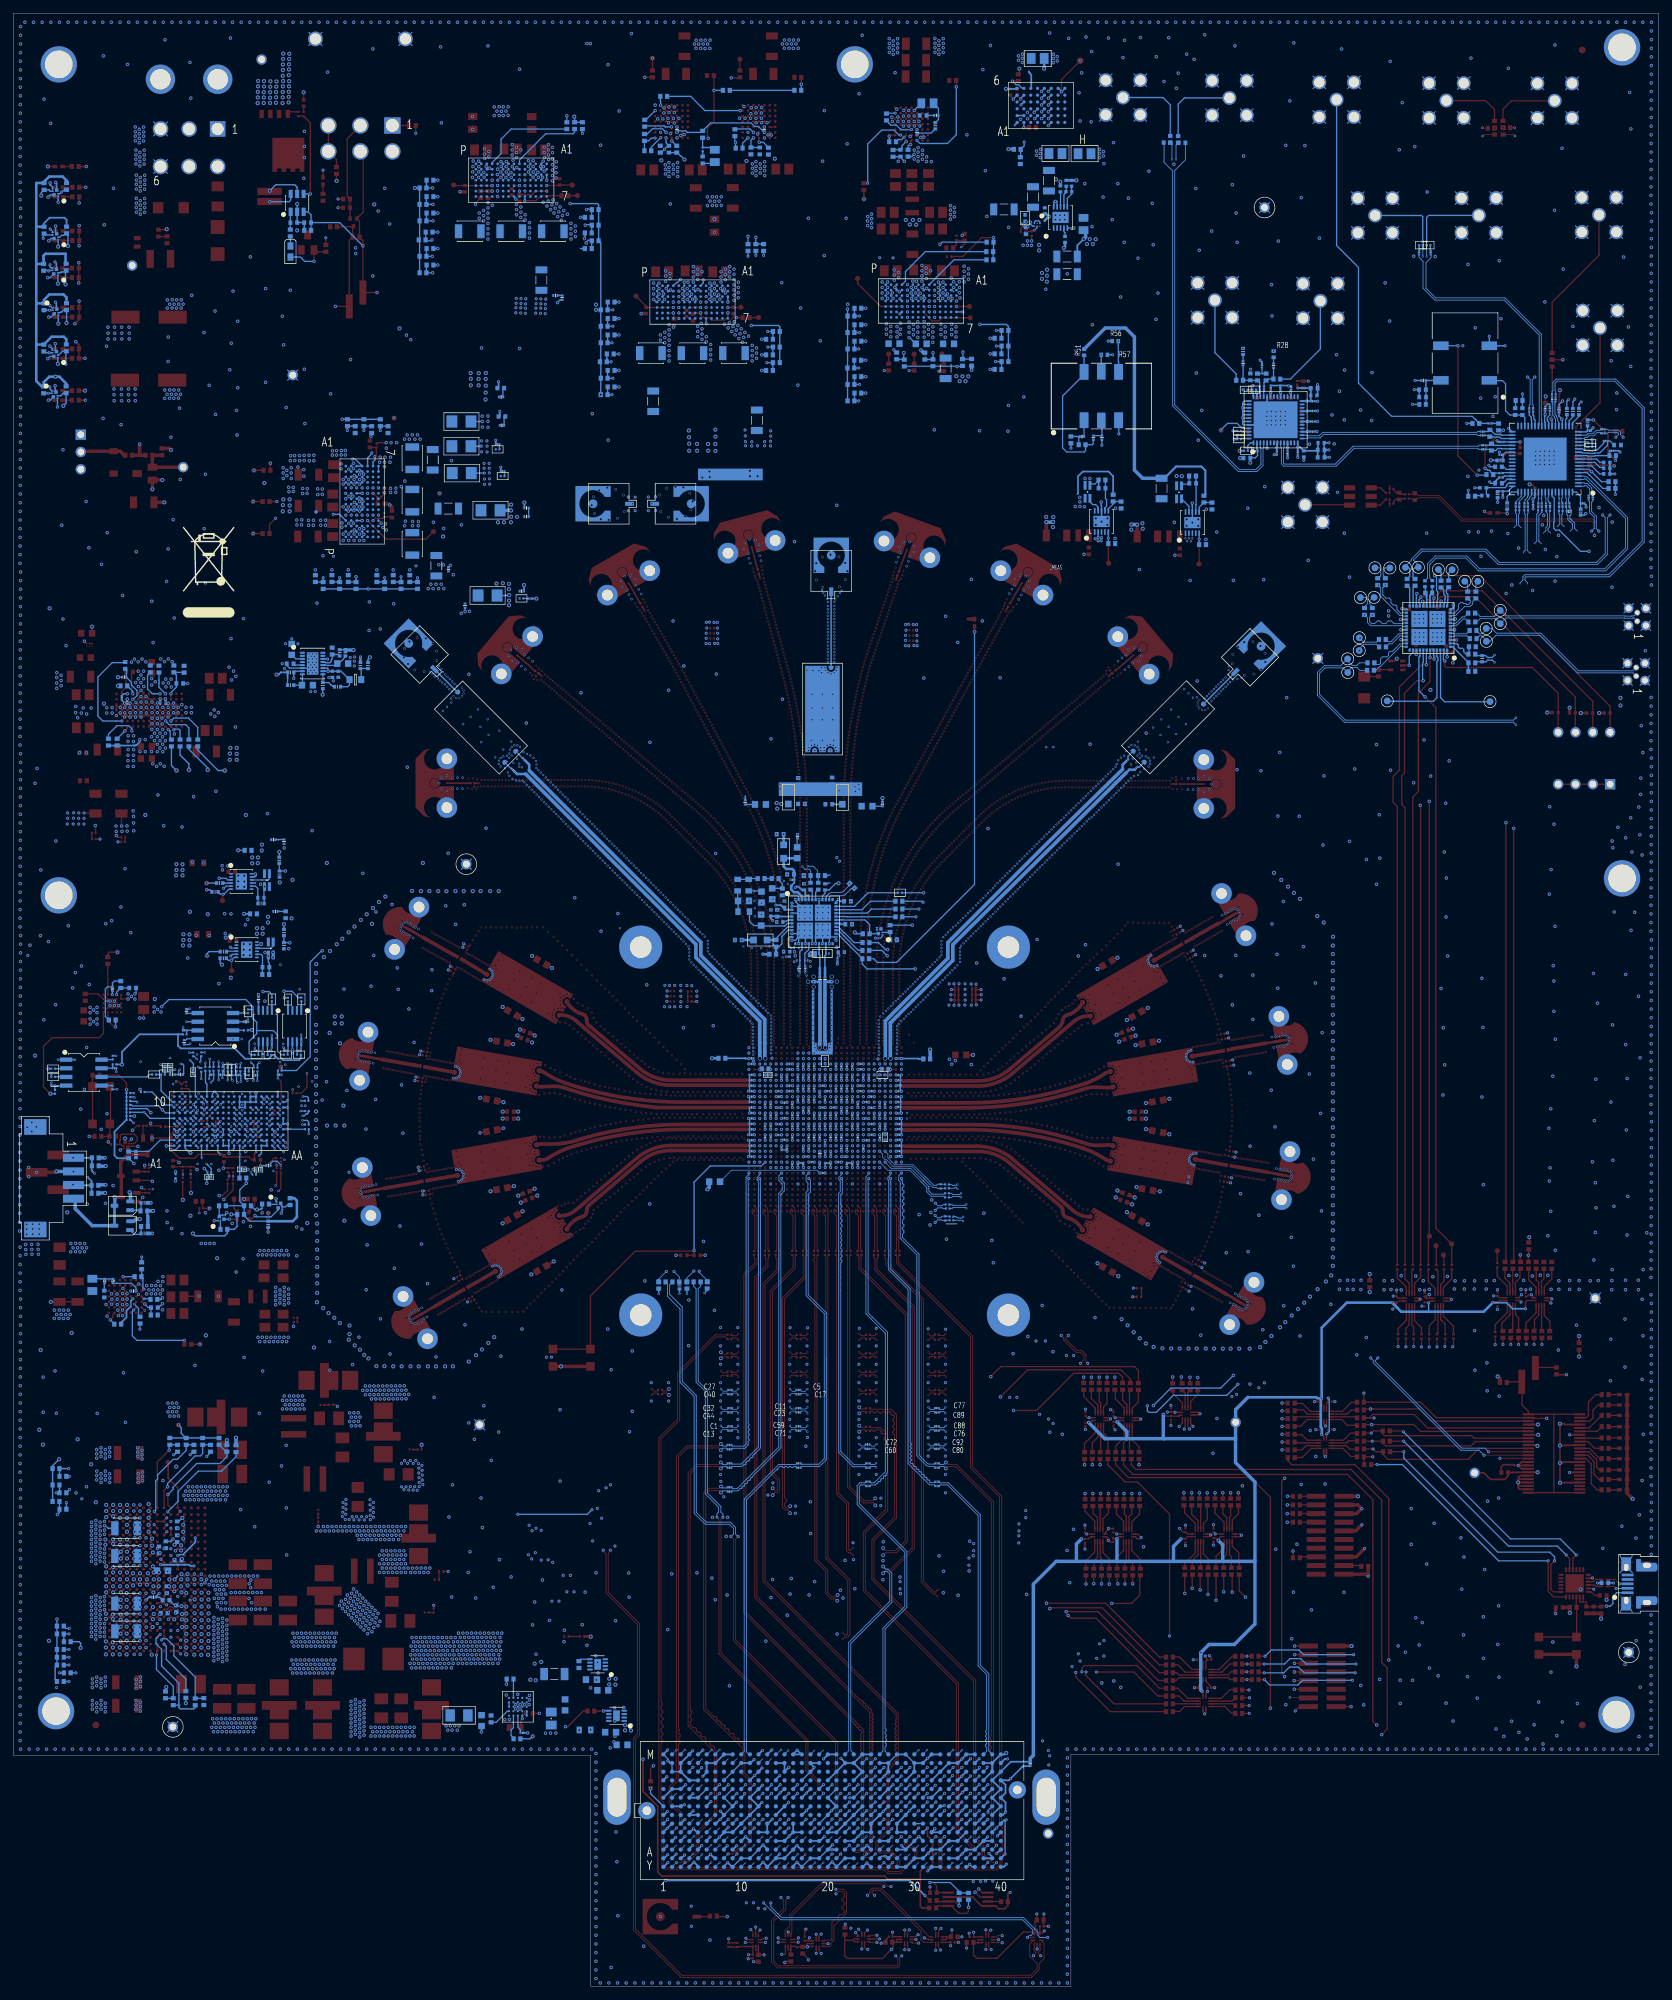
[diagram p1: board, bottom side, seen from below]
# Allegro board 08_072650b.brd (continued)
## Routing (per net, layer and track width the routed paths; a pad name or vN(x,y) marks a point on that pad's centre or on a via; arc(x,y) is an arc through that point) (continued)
SRXA_5N_FMC: length 86.2
  TOP w0.133: C91.1 105.54,95.5 104.9,95.5 v7(104.65,95.76)
  L3_SIGNAL w0.108: 102.24,20.7 102.24,20.95 102.67,21.39 102.67,36.48 99.31,39.84 95.96,43.19 95.85,62.26 95.74,81.58 95.74,91.01 100.19,95.46 104.35,95.46 v7(104.65,95.76)
  BOTTOM w0.127: P1.A35 102.24,20.7
SRXA_5P: length 24.6
  TOP w0.133: v7(107.2,94.83) 106.92,95.11 106.45,95.11 C79.2
  L3_SIGNAL w0.108: v7(107.2,94.83) 107.51,95.15 107.79,95.15 108.07,95.43 108.07,108.83 111.54,112.3 111.54,115.46 111.1,115.9 v7(111.1,116.13)
SRXA_5P_FMC: length 86.2
  TOP w0.133: v7(104.65,94.87) 104.87,95.09 105.44,95.09 C79.1
  L3_SIGNAL w0.108: v7(104.65,94.87) 104.35,95.16 100.31,95.16 96.04,90.89 96.04,81.59 96.15,62.27 96.26,43.32 102.97,36.6 102.97,36.02 103.04,35.95 103.04,35.8 102.97,35.73 102.97,35.5 103.12,35.34 103.12,35.22 102.97,35.06 102.97,34.79 103.12,34.63 103.12,34.51 102.97,34.35 102.97,33.97 103.12,33.82 103.12,33.69 102.97,33.54 102.97,21.24 103.5,20.7
  BOTTOM w0.127: P1.A34 103.5,20.7
SRXA_6N: length 45
  L24_SIGNAL w0.108: v9(107.14,79.57) 107.43,79.27 107.77,79.27 107.9,79.4 108.18,79.4 108.31,79.27 108.64,79.27 108.79,79.43 108.94,79.43 109.09,79.27 109.41,79.27 109.59,79.46 109.59,79.62 109.7,79.73 109.86,79.73 110.04,79.9 110.04,80.1 110.15,80.21 110.34,80.21 110.45,80.32 110.45,80.67 110.36,80.75 110.36,81.07 110.45,81.15 110.45,102.17 110.42,102.19 arc(110.4,102.44) 110.52,102.65 110.52,102.66 114.99,107.13 115.01,107.15 115.08,107.33 115.08,116.21 115.03,116.34 114.99,116.39 114.76,116.61 arc(114.66,116.77) 114.62,116.97 arc(114.64,117.06) 114.69,117.14 114.69,117.14 arc(114.84,117.22) 114.99,117.17 114.99,117.16 arc(115.07,117.06) U1A.AD27
  BOTTOM w0.133: C92.2 106.39,79.3 106.87,79.3 v9(107.14,79.57)
SRXA_6N_FMC: length 49.9
  L24_SIGNAL w0.108: v9(107.34,34.7) 107.75,35.11 107.75,35.15 107.8,35.2 107.8,48.97 103.38,53.4 103.38,78.89 103.77,79.28 104.31,79.28 v9(104.6,79.57)
  BOTTOM w0.108: P1.M31 107.34,34.65 v9(107.34,34.7)
  BOTTOM w0.133: v9(104.6,79.57) 104.86,79.3 105.45,79.3 C92.1
SRXA_6P: length 45
  L24_SIGNAL w0.108: v9(107.14,78.68) 107.43,78.97 107.44,78.97 109.53,78.97 110.74,80.19 110.74,102.29 110.69,102.34 arc(110.7,102.4) 110.73,102.44 115.21,106.92 arc(115.34,107.11) 115.38,107.33 115.38,116.21 arc(115.41,116.45) 115.51,116.67 arc(115.59,116.92) 115.53,117.17 arc(115.5,117.21) 115.49,117.25 arc(115.41,117.39) 115.32,117.51 U1A.AD26
  BOTTOM w0.133: v9(107.14,78.68) 106.82,78.99 106.39,78.99 106.26,78.87 C80.2
SRXA_6P_FMC: length 49.9
  L24_SIGNAL w0.108: v9(108.59,34.67) 108.1,35.15 108.1,35.79 108.19,35.88 108.19,36.03 108.12,36.11 108.12,36.26 108.23,36.37 108.23,36.53 108.14,36.61 108.14,36.77 108.23,36.86 108.23,37.01 108.1,37.13 108.1,37.31 108.2,37.41 108.2,37.57 108.1,37.67 108.1,37.82 108.19,37.91 108.19,38.06 108.1,38.15 108.1,38.38 108.2,38.48 108.2,38.66 108.1,38.76 108.1,49.1 103.68,53.52 103.68,78.77 103.89,78.99 104.29,78.99 v9(104.6,78.68)
  BOTTOM w0.108: v9(108.59,34.67) P1.M30
  BOTTOM w0.133: v9(104.6,78.68) 104.91,78.99 105.45,78.99 105.57,78.87 C80.1
SRXA_7N: length 6.8
  TOP w0.133: C93.2 111.84,108.18 111.84,113.03 112.24,113.44 112.24,113.94 112.16,114.02 112.03,114.02 111.9,113.89 U1A.AH31
SRXA_7N_FMC: length 111.6
  TOP w0.133: C93.1 111.89,107.27 111.81,107.19 111.81,106.1 100.97,95.25 100.97,76.07 96.7,71.81 96.7,23.65 96.29,23.24 96.29,20.5 96.64,20.15 96.64,17.91 97.16,17.4 103.68,17.4 103.77,17.48 103.89,17.48 103.97,17.4 104.25,17.4 104.41,17.55 104.53,17.55 104.69,17.4 105.15,17.4 105.25,17.5 105.25,17.58 105.28,17.61 105.28,17.74 105.13,17.89 105.13,18.01 105.28,18.17 105.28,18.3 105.13,18.45 105.13,18.58 105.28,18.73 105.28,19.04 105.13,19.19 105.13,19.32 105.28,19.47 105.28,19.62 105.13,19.77 105.13,19.9 105.28,20.05 105.28,20.26 105.13,20.41 105.13,20.54 105.28,20.69 105.28,20.87 105.13,21.02 105.13,21.15 105.28,21.3 105.28,21.76 105.07,21.97 v4(104.78,21.97)
  BOTTOM w0.127: P1.B33 v4(104.78,21.97)
SRXA_7P: length 6.8
  TOP w0.133: U1A.AH30 111.51,114.05 111.51,108.2 arc(111.45,108.03) C81.2
SRXA_7P_FMC: length 111.6
  TOP w0.133: v4(106.04,21.97) 105.82,21.97 105.59,21.75 105.59,17.48 105.56,17.45 105.56,17.37 105.28,17.09 97.03,17.09 96.33,17.78 96.33,20.02 95.98,20.37 95.98,23.37 96.39,23.78 96.39,71.94 100.65,76.2 100.65,95.38 111.5,106.23 111.5,107.19 C81.1
  BOTTOM w0.127: P1.B32 v4(106.04,21.97)
SRXA_8N: length 28
  TOP w0.133: C94.2 106.3,92.74 106.84,92.74 v7(107.14,93.04)
  L3_SIGNAL w0.108: v7(107.14,93.04) 107.43,92.74 107.59,92.74 107.73,92.88 107.73,93.1 107.82,93.19 108.03,93.19 108.22,93.38 108.22,93.59 108.31,93.68 108.53,93.68 108.79,93.95 108.79,94.2 108.64,94.35 108.64,94.48 108.79,94.63 108.79,94.86 108.64,95.01 108.64,95.14 108.79,95.29 108.79,95.49 108.64,95.64 108.64,95.77 108.79,95.92 108.79,96.28 108.64,96.43 108.64,96.56 108.79,96.71 108.79,97.02 108.64,97.17 108.64,97.29 108.79,97.45 108.79,97.75 108.64,97.9 108.64,98.03 108.79,98.18 108.79,98.51 108.64,98.67 108.64,98.79 108.79,98.95 108.79,99.28 108.64,99.43 108.64,99.56 108.79,99.71 108.79,99.79 109,99.99 109,100.26 109.13,100.39 109.39,100.39 112.81,103.81 112.81,115.22 v7(112.7,115.33)
SRXA_8N_FMC: length 86
  TOP w0.133: v7(104.6,93.04) 104.88,92.75 105.45,92.75 C94.1
  L3_SIGNAL w0.108: v7(104.6,93.04) 104.32,92.75 102.52,92.75 97.69,87.93 97.69,44 105.24,36.45 105.24,34.4 105.09,34.25 105.09,34.12 105.24,33.97 105.24,33.67 105.09,33.52 105.09,33.39 105.24,33.24 105.24,23.34 105.25,23.33 105.25,18.92 105.54,18.62 107.09,18.62 107.36,18.36 107.36,18.2 107.31,18.16
  BOTTOM w0.127: P1.Y31 107.31,18.16
SRXA_8P: length 28
  TOP w0.133: C82.2 106.3,92.43 106.85,92.43 v7(107.14,92.15)
  L3_SIGNAL w0.108: v7(107.14,92.15) 107.43,92.44 107.71,92.44 109.09,93.83 109.09,99.67 113.11,103.68 113.11,115.49 112.7,115.9 v7(112.7,116.13)
SRXA_8P_FMC: length 86.1
  TOP w0.133: C82.1 105.6,92.27 105.42,92.44 104.89,92.44 v7(104.6,92.15)
  L3_SIGNAL w0.108: v7(104.6,92.15) 104.29,92.46 102.64,92.46 97.99,87.81 97.99,44.12 105.54,36.58 105.54,23.46 105.55,23.45 105.55,19.04 105.66,18.92 107.21,18.92 107.98,18.16 108.59,18.16
  BOTTOM w0.127: P1.Y30 108.59,18.16
SRXA_9N: length 6.8
  TOP w0.133: U1A.AF31 113.5,113.85 arc(113.55,113.97) 113.66,114.02 arc(113.79,113.96) 113.84,113.84 113.84,113.59 arc(113.82,113.49) 113.77,113.42 113.55,113.2 arc(113.49,113.12) 113.44,113.04 arc(113.42,112.98) 113.43,112.91 113.43,108.16 arc(113.46,108) C95.2
SRXA_9N_FMC: length 85.1
  TOP w0.133: C95.1 113.55,106.9 113.41,106.77 113.41,105.92 108.18,100.69 108.18,59.29 106.43,57.53 106.13,57.53 v7(105.79,57.19)
  L3_SIGNAL w0.108: v7(105.79,57.19) 106.13,57.53 106.36,57.53 106.71,57.18 106.71,52.25 123.04,35.92 123.04,35.16 122.56,34.67
  BOTTOM w0.127: P1.M19 122.56,34.67
SRXA_9P: length 6.8
  TOP w0.133: U1A.AF30 113.32,114.29 113.23,114.18 arc(113.14,113.98) 113.11,113.77 113.09,113.06 113.09,113.05 113.09,108.16 arc(113.06,108) C83.2
SRXA_9P_FMC: length 85.1
  TOP w0.133: v7(105.79,58.18) 106.13,57.84 106.3,57.84 107.87,59.42 107.87,100.82 113.1,106.05 113.1,106.77 112.97,106.9 C83.1
  L3_SIGNAL w0.108: v7(105.79,58.18) 106.13,57.84 106.48,57.84 107.01,57.3 107.01,52.38 123.34,36.05 123.34,35.16 123.82,34.67
  BOTTOM w0.127: P1.M18 123.82,34.67
SRXA_10N: length 31.3
  TOP w0.133: C96.2 106.3,90.04 106.84,90.04 v7(107.14,90.34)
  L3_SIGNAL w0.108: v7(114.3,115.33) 114.36,115.27 114.36,104.56 114.25,104.44 114.25,104.32 114.36,104.2 114.36,103.87 114.21,103.72 114.21,103.59 114.36,103.44 114.36,103.06 114.21,102.91 114.21,102.78 114.36,102.63 114.36,102.13 114.05,101.82 113.84,101.82 113.75,101.73 113.75,101.52 113.48,101.25 113.26,101.25 113.17,101.16 113.17,100.95 112.96,100.73 112.74,100.73 112.65,100.64 112.65,100.43 112.41,100.19 112.2,100.19 112.11,100.1 112.11,99.88 111.82,99.59 111.6,99.59 111.51,99.5 111.51,99.28 111.28,99.06 111.07,99.06 110.98,98.97 110.98,98.75 110.71,98.48 110.5,98.48 110.41,98.39 110.41,98.18 110.23,98 110.01,98 109.92,97.91 109.92,97.7 109.58,97.35 109.58,93.62 108.48,92.52 108.48,90.85 107.68,90.04 107.44,90.04 v7(107.14,90.34)
SRXA_10N_FMC: length 81.2
  TOP w0.133: C96.1 105.44,90.05 104.89,90.05 v7(104.6,90.34)
  L3_SIGNAL w0.108: v7(104.6,90.34) 104.34,90.09 102.26,90.09 99.52,87.35 99.52,48.18 108.3,39.4 108.3,39.38 110.35,37.33 110.35,28.67 110.33,28.65 110.33,19.68 110.36,19.65 arc(110.3,19.49) 110.14,19.43 109.85,19.43
  BOTTOM w0.127: P1.Z29 109.85,19.43
SRXA_10P: length 31.3
  TOP w0.133: C84.2 106.23,89.66 106.93,89.66 v7(107.14,89.45)
  L3_SIGNAL w0.108: v7(114.3,116.13) 114.3,115.88 114.7,115.48 114.7,102.05 109.88,97.23 109.88,93.5 108.78,92.4 108.78,90.72 107.8,89.74 107.43,89.74 v7(107.14,89.45)
SRXA_10P_FMC: length 81.2
  TOP w0.133: v7(104.6,89.45) 104.81,89.66 105.51,89.66 C84.1
  L3_SIGNAL w0.108: v7(104.6,89.45) 104.26,89.79 102.39,89.79 99.82,87.22 99.82,48.3 110.66,37.46 110.66,36.17 110.74,36.1 110.74,35.97 110.66,35.9 110.66,35.62 110.82,35.47 110.82,35.34 110.66,35.19 110.66,34.84 110.82,34.68 110.82,34.56 110.66,34.4 110.66,34.12 110.82,33.97 110.82,33.85 110.66,33.69 110.66,33.39 110.82,33.24 110.82,33.11 110.66,32.96 110.66,28.55 110.64,28.52 110.64,19.8 110.64,19.79 arc(110.66,19.72) 110.66,19.64 arc(110.73,19.49) 110.88,19.43 111.12,19.43
  BOTTOM w0.127: P1.Z28 111.12,19.43
SRXA_11N: length 6.8
  TOP w0.133: U1A.AD31 115.1,113.85 arc(115.15,113.97) 115.26,114.02 arc(115.39,113.96) 115.44,113.84 115.44,113.59 arc(115.42,113.49) 115.37,113.42 115.15,113.2 arc(115.09,113.12) 115.04,113.04 arc(115.02,112.98) 115.03,112.91 115.03,108.16 arc(115.06,108) C97.2
SRXA_11N_FMC: length 82
  TOP w0.133: v10(113.79,61.59) 113.41,61.21 112.65,61.21 109.53,64.33 109.53,99.63 115.01,105.11 115.01,106.77 115.15,106.9 C97.1
  BOTTOM w0.133: v10(113.79,61.59) 113.41,61.21 113.1,61.21 112.52,60.64 112.52,56.33 118.54,50.31 118.54,34.59 118.11,34.16 P1.M23
SRXA_11P: length 6.8
  TOP w0.133: U1A.AD30 114.92,114.29 114.83,114.18 arc(114.74,113.98) 114.71,113.77 114.69,113.06 114.69,113.05 114.69,108.16 arc(114.66,108) C85.2
SRXA_11P_FMC: length 82
  TOP w0.133: v10(113.79,60.61) 113.65,60.75 113.65,60.77 113.52,60.9 112.52,60.9 111.67,61.76 109.22,64.2 109.22,99.75 114.7,105.24 114.7,106.77 114.57,106.9 C85.1
  BOTTOM w0.133: P1.M22 118.85,34.56 118.85,50.44 112.83,56.46 112.83,60.51 113.23,60.9 113.5,60.9 v10(113.79,60.61)
SRXB_0N: length 45.5
  BOTTOM w0.127: 131.8,116.68 131.8,116.71 131.8,116.72 131.8,116.81 131.8,116.82 131.8,118.29 131.9,118.39 v4(131.9,118.53)
  BOTTOM w0.133: C38.2 135.9,76.28 134.52,76.28 134.25,76.54 134.04,76.54 133.95,76.63 133.95,76.85 133.74,77.05 133.53,77.05 133.44,77.14 133.44,77.36 133.22,77.57 133.01,77.57 132.92,77.66 132.92,77.88 132.75,78.04 132.68,78.04 132.59,78.13 132.59,78.21 131.8,79 131.8,116.68
SRXB_0N_FMC: length 69.4
  TOP w0.133: v10(137.62,75.98) 137.91,76.27 141.04,76.27 142.11,75.2 142.11,40.54 141.88,40.31 141.88,40.03 142.11,39.8 142.11,39.42 141.89,39.2 141.89,39.01 142.11,38.79 142.11,38.36 141.7,37.95 141.35,37.95 141.22,37.81 141.22,37.47 141.04,37.29 140.7,37.29 140.56,37.15 140.56,36.81 140.35,36.6 139.99,36.6 139.85,36.47 139.85,36.13 139.69,35.97 139.35,35.97 139.22,35.83 139.22,35.47 139.03,35.28 138.69,35.28 138.56,35.15 138.56,34.81 138.22,34.47 138.22,25.11 140.94,22.4 140.94,19.68 142.35,18.27 142.76,18.27 v4(142.88,18.16)
  BOTTOM w0.127: P1.Y3 v4(142.88,18.16)
  BOTTOM w0.133: C38.1 136.79,76.27 137.33,76.27 v10(137.62,75.98)
SRXB_0P: length 45.5
  BOTTOM w0.127: 132.11,116.68 132.11,118.16 132.21,118.26 132.21,118.28 132.29,118.37 132.29,118.69 131.9,119.09 v4(131.9,119.33)
  BOTTOM w0.133: C25.2 135.97,76.63 134.6,76.63 132.11,79.13 132.11,116.68
SRXB_0P_FMC: length 69.4
  TOP w0.133: v10(137.62,76.87) 137.91,76.58 141.17,76.58 142.42,75.33 142.42,38.23 138.53,34.34 138.53,25.24 141.25,22.53 141.25,19.81 142.48,18.58 143.05,18.58 143.47,18.16 v4(144.15,18.16)
  BOTTOM w0.127: P1.Y2 v4(144.15,18.16)
  BOTTOM w0.133: C25.1 136.77,76.58 137.33,76.58 v10(137.62,76.87)
SRXB_1N: length 42.3
  BOTTOM w0.127: v4(133.5,118.53) 133.6,118.43 133.6,116.21
  BOTTOM w0.133: 133.6,116.21 133.6,116.2 133.6,82.58 133.49,82.46 133.49,82.27 133.6,82.16 133.6,81.88 133.45,81.72 133.45,81.6 133.6,81.45 133.6,81.19 133.45,81.04 133.45,80.91 133.6,80.76 133.6,80.38 133.45,80.23 133.45,80.1 133.6,79.95 133.6,79.45 134.11,78.94 135.93,78.94 C39.2
SRXB_1N_FMC: length 65.2
  TOP w0.133: v10(137.62,78.68) 137.93,78.99 138.84,78.99 138.84,78.99 142.5,78.99 143.83,77.65 143.83,37.79 143.73,37.68 143.73,37.5 143.83,37.4 143.83,37.15 143.58,36.9 143.58,36.71 143.83,36.46 143.83,36.19 143.59,35.95 143.59,35.76 143.83,35.52 143.83,30.25 144.91,29.18 144.91,27 143.33,25.43 143.33,23.7 v4(142.88,23.24)
  BOTTOM w0.127: P1.C3 v4(142.88,23.24)
  BOTTOM w0.133: C39.1 136.79,78.96 137.33,78.96 v10(137.62,78.68)
SRXB_1P: length 42.3
  BOTTOM w0.127: 133.91,118.62 133.89,118.63 133.89,118.69 133.66,118.92 133.6,118.92 133.5,119.03 v4(133.5,119.33)
  BOTTOM w0.133: 133.91,118.62 133.91,116.34 133.92,116.33 133.92,79.58 134.24,79.25 135.9,79.25 C26.2
SRXB_1P_FMC: length 65.2
  TOP w0.133: v10(137.62,79.57) 137.88,79.31 138.97,79.31 138.97,79.3 142.63,79.3 144.15,77.78 144.15,30.38 145.22,29.31 145.22,26.87 143.66,25.32 143.66,23.72 v4(144.15,23.24)
  BOTTOM w0.127: P1.C2 v4(144.15,23.24)
  BOTTOM w0.133: C26.1 136.77,79.27 137.32,79.27 v10(137.62,79.57)
SRXB_2N: length 34.3
  L24_SIGNAL w0.108: v9(135.08,86.76) 134.78,87.05 134.24,87.05 132.09,89.21 132.09,89.44 132.08,89.44 132.08,105.26 131.08,106.26 131.08,116.21 arc(131.06,116.29) 131.01,116.37 130.76,116.61 arc(130.66,116.77) 130.62,116.97 arc(130.64,117.06) 130.69,117.14 130.69,117.14 arc(130.84,117.22) 130.99,117.17 130.99,117.16 arc(131.07,117.06) U1A.D27
  BOTTOM w0.108: C40.2 135.83,87.04 135.29,87.04 135.08,86.83 v9(135.08,86.76)
SRXB_2N_FMC: length 78.8
  L24_SIGNAL w0.108: v9(140.39,19.35) 140.87,19.35 141.13,19.61 141.13,19.97 141.4,20.24 143.19,20.24 143.39,20.44 143.39,29.98 147.12,33.71 147.12,78.94 138.94,87.12 137.98,87.12 v9(137.62,86.76)
  BOTTOM w0.108: v9(137.62,86.76) 137.34,87.04 136.71,87.04 C40.1
  BOTTOM w0.127: v9(140.39,19.35) 140.94,18.8 P1.Z5
SRXB_2P: length 34.3
  L24_SIGNAL w0.108: v9(135.08,87.65) 134.78,87.35 134.37,87.35 134.13,87.59 134.13,87.81 134.04,87.9 133.82,87.9 133.73,87.99 133.73,88.2 133.64,88.29 133.42,88.29 133.33,88.38 133.33,88.6 133.24,88.69 133.03,88.69 132.84,88.87 132.84,89.09 132.75,89.18 132.54,89.18 132.38,89.33 132.38,89.56 132.38,89.57 132.38,105.38 131.37,106.39 131.37,116.26 131.38,116.3 131.47,116.59 arc(131.49,116.63) 131.51,116.67 arc(131.59,116.89) 131.55,117.11 arc(131.54,117.14) 131.53,117.17 arc(131.52,117.23) 131.49,117.29 131.43,117.39 arc(131.41,117.42) 131.39,117.44 U1A.D26
  BOTTOM w0.108: v9(135.08,87.65) 135.4,87.33 135.83,87.33 C27.2
SRXB_2P_FMC: length 78.8
  L24_SIGNAL w0.108: v9(141.71,19.43) 141.54,19.43 141.43,19.55 141.43,19.76 141.54,19.88 141.82,19.88 141.82,19.88 143.25,19.88 143.69,20.32 143.69,29.85 147.42,33.59 147.42,79.06 139.07,87.42 137.85,87.42 v9(137.62,87.65)
  BOTTOM w0.108: v9(137.62,87.65) 137.29,87.32 136.7,87.32 136.54,87.49 C27.1
  BOTTOM w0.114: v9(141.71,19.43) 142.24,18.9 P1.Z4
SRXB_3N: length 37.5
  TOP w0.133: v9(145.24,86.76) 145.53,87.05 146.07,87.05 C41.2
  L24_SIGNAL w0.108: U1A.B27 132.9,116.73 132.9,107.74 132.9,107.73 132.9,100.3 140.9,92.3 140.9,90.34 140.98,90.14 141.02,90.04 142.19,88.87 142.19,88.8 142.28,88.71 142.35,88.71 142.49,88.57 142.49,88.35 142.58,88.26 142.8,88.26 143,88.06 143,87.84 143.09,87.75 143.31,87.75 143.46,87.6 143.46,87.39 143.55,87.3 143.76,87.3 143.98,87.08 144.85,87.08 144.99,87 arc(145,86.99) 145.01,86.98 v9(145.24,86.76)
SRXB_3N_FMC: length 123.4
  TOP w0.133: v7(147.78,86.76) 147.5,87.03 146.94,87.03 C41.1
  L3_SIGNAL w0.108: v7(147.78,86.76) 147.48,87.05 146.79,87.05 146.6,86.87 146.6,35.06 148.84,32.82 148.84,28.55 146.57,26.29 146.57,24.75 147.35,23.98 147.35,15.72 145.92,14.3 123.14,14.3 121.26,12.42 113.52,12.42 109.05,16.89 109.05,19.58 108.77,19.87 108.16,19.87 107.8,20.22 107.8,20.59 107.69,20.7 107.31,20.7
  BOTTOM w0.127: P1.A31 107.31,20.7
SRXB_3P: length 37.5
  TOP w0.133: C29.2 146.08,87.36 145.53,87.36 v9(145.24,87.65)
  L24_SIGNAL w0.108: v9(145.24,87.65) 145.04,87.45 144.95,87.38 144.1,87.38 141.28,90.2 141.26,90.25 141.2,90.4 141.2,92.42 133.2,100.42 133.2,107.74 133.2,107.75 133.2,116.88 arc(133.19,116.94) 133.16,116.98 133.11,117.03 133.11,117.1 132.87,117.34 132.8,117.34 132.74,117.4 arc(132.71,117.44) 132.7,117.5 U1A.B26
SRXB_3P_FMC: length 123.4
  TOP w0.133: v7(147.78,87.65) 147.48,87.35 146.94,87.35 C29.1
  L3_SIGNAL w0.108: 108.59,20.7 108.21,20.7 108.1,20.59 108.1,20.35 108.28,20.16 108.89,20.16 109.06,19.99 109.35,19.71 109.35,17.02 109.68,16.69 109.86,16.69 109.97,16.58 109.97,16.41 110.08,16.31 110.2,16.31 110.31,16.2 110.31,16.08 110.42,15.98 110.51,15.98 110.62,15.87 110.62,15.75 110.77,15.6 110.92,15.6 111.07,15.44 111.07,15.34 111.24,15.18 111.41,15.18 111.52,15.07 111.52,14.9 111.66,14.76 111.79,14.76 111.9,14.65 111.9,14.52 113.7,12.72 121.14,12.72 123.02,14.6 145.8,14.6 147.05,15.85 147.05,23.85 146.27,24.63 146.27,26.41 148.54,28.68 148.54,32.7 146.3,34.93 146.3,87 146.66,87.35 147.48,87.35 v7(147.78,87.65)
  BOTTOM w0.127: P1.A30 108.59,20.7
SRXB_4N: length 50.3
  BOTTOM w0.127: v4(128.7,118.53) 128.7,118.27 128.35,117.91 128.35,117.91 128.3,117.86 128.3,116.72 128.71,116.31 128.71,116.3 128.78,116.24 128.78,116.23 128.8,116.21
  BOTTOM w0.133: 128.8,116.21 128.8,116.21 128.8,79.01 132.97,74.85 132.97,74.76 133.06,74.67 133.14,74.67 133.26,74.56 133.26,74.34 133.35,74.25 133.56,74.25 133.7,74.11 133.7,73.9 133.79,73.81 134.01,73.81 134.12,73.69 134.12,73.48 134.21,73.39 134.43,73.39 134.53,73.29 134.53,73.11 134.62,73.03 134.79,73.03 135.1,72.71 135.93,72.71 C42.2
SRXB_4N_FMC: length 62.6
  TOP w0.133: v10(137.59,72.45) 137.88,72.74 139.35,72.74 139.83,72.26 139.83,40.77 138.61,39.55 138.33,39.55 138.2,39.41 138.2,39.14 137.97,38.91 137.73,38.91 137.57,38.75 137.57,38.51 137.41,38.35 137.14,38.35 137.01,38.22 137.01,37.95 136.83,37.77 136.53,37.77 136.4,37.64 136.4,37.34 136.17,37.11 135.79,37.11 135.66,36.98 135.66,36.6 135.46,36.4 135.11,36.4 134.98,36.26 134.98,35.92 134.8,35.74 134.42,35.74 134.29,35.6 134.29,35.23 134.08,35.02 134.08,31.26 133.17,30.35 133.17,21.28 134.47,19.99 134.85,19.99 135.2,19.63 135.21,19.63 135.25,19.58 v4(135.25,19.43)
  BOTTOM w0.127: P1.Z9 v4(135.25,19.43)
  BOTTOM w0.133: v10(137.59,72.45) 137.35,72.69 136.7,72.69 C42.1
SRXB_4P: length 50.3
  BOTTOM w0.127: 129.02,116.43 128.6,116.85 128.6,117.73 128.65,117.78 128.65,117.78 129.1,118.24 129.1,118.93 v4(128.7,119.33)
  BOTTOM w0.133: 129.02,116.43 129.12,116.33 129.12,79.14 135.23,73.03 135.85,73.03 C30.2
SRXB_4P_FMC: length 62.6
  TOP w0.133: v10(137.59,73.34) 137.86,73.08 139.45,73.08 140.14,72.39 140.14,40.64 134.39,34.89 134.39,31.13 133.48,30.22 133.48,21.41 134.6,20.3 134.98,20.3 135.43,19.85 135.43,19.85 135.85,19.43 v4(136.53,19.43)
  BOTTOM w0.127: P1.Z8 v4(136.53,19.43)
  BOTTOM w0.133: C30.1 136.69,73.13 137.38,73.13 v10(137.59,73.34)
SRXB_5N: length 24.7
  TOP w0.133: v7(135.08,95.73) 135.35,95.45 135.94,95.45 C43.2
  L3_SIGNAL w0.108: v7(133.5,115.33) 133.5,115.59 133.33,115.76 133.18,115.76 133.07,115.65 133.07,115.15 133.32,114.89 133.39,114.89 133.58,114.7 133.58,113.9 133.74,113.75 133.74,113.64 133.84,113.53 133.95,113.53 136.14,111.34 136.14,95.54 136.03,95.43 135.37,95.43 v7(135.08,95.73)
SRXB_5N_FMC: length 127.2
  TOP w0.133: C43.1 138.45,95.59 143.97,90.08 143.97,83.21 146.72,80.46 146.72,27.22 146.3,26.8 146.3,17.72 145.7,17.11 113.66,17.11 113.07,16.53 111.28,16.53 108.82,18.99 108.82,19.86 109.64,20.68 110.04,20.68 110.31,20.95 110.31,21.52 v4(109.85,21.97)
  BOTTOM w0.127: P1.B29 v4(109.85,21.97)
SRXB_5P: length 24.7
  TOP w0.133: C31.2 136.08,94.96 135.92,95.12 135.36,95.12 v7(135.08,94.84)
  L3_SIGNAL w0.108: v7(133.5,116.13) 133.91,115.72 133.91,114 136.44,111.46 136.44,95.42 136.16,95.14 135.37,95.14 v7(135.08,94.84)
SRXB_5P_FMC: length 127.2
  TOP w0.133: C31.1 136.94,95.28 138.32,95.28 143.66,89.95 143.66,83.08 146.41,80.33 146.41,41.78 146.18,41.56 146.18,41.37 146.41,41.15 146.41,40.67 146.13,40.39 146.13,40.2 146.41,39.93 146.41,39.65 146.11,39.35 146.11,39.16 146.41,38.86 146.41,38.58 146.08,38.26 146.08,38.07 146.41,37.74 146.41,37.41 146.12,37.13 146.12,36.94 146.41,36.65 146.41,36.37 146.12,36.09 146.12,35.9 146.41,35.61 146.41,27.34 145.99,26.93 145.99,17.85 145.57,17.42 113.53,17.42 112.94,16.84 111.41,16.84 109.13,19.12 109.13,19.73 109.77,20.37 110.17,20.37 110.62,20.82 110.62,21.46 v4(111.12,21.97)
  BOTTOM w0.127: P1.B28 v4(111.12,21.97)
SRXB_6N: length 37.9
  L24_SIGNAL w0.108: v9(135.08,84.06) 134.78,84.36 133.8,84.36 132.61,85.55 132.61,86.75 130.52,88.84 arc(130.4,89.03) 130.35,89.26 130.35,105.56 129.48,106.44 129.48,116.21 arc(129.46,116.29) 129.41,116.37 129.16,116.61 arc(129.06,116.77) 129.02,116.97 arc(129.04,117.06) 129.09,117.14 129.09,117.14 arc(129.24,117.22) 129.39,117.17 129.39,117.16 arc(129.47,117.06) U1A.F27
  BOTTOM w0.108: C44.2 135.83,84.38 135.26,84.38 135.08,84.19 v9(135.08,84.06)
SRXB_6N_FMC: length 78.9
  L24_SIGNAL w0.108: v9(137.62,84.06) 137.9,84.35 139.68,84.35 146.05,77.98 146.05,34.64 145.24,33.83 144.53,33.83 144.1,33.4 143.95,33.4 143.84,33.29 143.84,33.15 143.73,33.05 143.57,33.05 143.41,32.89 143.41,32.75 143.3,32.64 143.14,32.64 143.03,32.53 143.03,32.33 142.88,32.18 142.67,32.18 142.54,32.05 142.54,31.88 142.42,31.75 142.32,31.75 142.09,31.52 142.09,29.3 142.14,29.25 142.14,21.81 141.8,21.47 139.97,21.47 139.56,21.06 139.56,20.49 139.28,20.2 138.75,20.2 138.29,19.75 138.29,19.11 138.3,19.1 138.3,18.64 v9(137.82,18.16)
  BOTTOM w0.108: v9(137.62,84.06) 137.62,84.09 137.34,84.37 136.71,84.37 C44.1
  BOTTOM w0.114: P1.Y7 138.43,17.55 v9(137.82,18.16)
SRXB_6P: length 37.9
  L24_SIGNAL w0.108: U1A.F26 129.73,117.5 arc(129.83,117.38) 129.89,117.24 arc(129.91,117.2) 129.93,117.16 arc(129.99,116.91) 129.91,116.67 arc(129.89,116.63) 129.86,116.59 129.79,116.42 129.77,116.37 129.77,106.6 129.81,106.54 130.66,105.69 130.66,92.54 130.81,92.39 130.81,92.27 130.66,92.11 130.66,91.83 130.81,91.68 130.81,91.55 130.66,91.4 130.66,91.17 130.81,91.02 130.81,90.89 130.66,90.74 130.66,90.51 130.81,90.36 130.81,90.23 130.66,90.08 130.66,89.26 arc(130.68,89.15) 130.74,89.06 131.95,87.85 131.95,87.84 132.91,86.88 132.91,85.67 133.92,84.66 134.79,84.66 v9(135.08,84.95)
  BOTTOM w0.108: C32.2 135.83,84.66 135.29,84.66 135.08,84.88
  BOTTOM w0.133: v9(135.08,84.95) 135.08,84.88
SRXB_6P_FMC: length 78.9
  L24_SIGNAL w0.108: v9(137.62,84.95) 137.9,84.67 139.81,84.67 146.35,78.14 146.35,34.51 145.37,33.53 144.65,33.53 142.39,31.27 142.39,29.42 142.44,29.37 142.44,21.69 141.9,21.15 140.11,21.15 139.89,20.93 139.89,20.38 139.39,19.88 138.88,19.88 138.62,19.62 138.62,19.25 138.63,19.24 138.63,18.6 v9(139.05,18.17)
  BOTTOM w0.108: v9(137.62,84.95) 137.32,84.66 136.7,84.66 136.54,84.82 C32.1
  BOTTOM w0.114: P1.Y6 v9(139.05,18.17)
SRXB_7N: length 6.8
  TOP w0.133: U1A.B31 132.7,113.85 arc(132.75,113.97) 132.86,114.02 arc(132.99,113.96) 133.04,113.84 133.04,113.59 arc(133.02,113.49) 132.97,113.42 132.75,113.2 arc(132.69,113.12) 132.64,113.04 arc(132.62,112.98) 132.63,112.91 132.63,108.16 arc(132.66,108) C45.2
SRXB_7N_FMC: length 98.7
  TOP w0.133: v4(117.47,20.7) 117.87,20.3 117.87,20.11 117.71,19.95 117.45,19.95 116.97,20.43 116.97,33.9 117.12,34.05 117.12,34.18 116.97,34.33 116.97,34.46 117.12,34.61 117.12,34.73 116.97,34.89 116.97,35.01 117.12,35.17 117.12,35.29 116.97,35.45 116.97,35.57 117.12,35.73 117.12,35.85 116.97,36 116.97,36.13 117.12,36.28 117.12,36.41 116.97,36.56 116.97,36.69 117.12,36.84 117.12,36.97 116.97,37.12 116.97,37.52 117.08,37.63 117.3,37.63 117.39,37.72 117.39,37.94 117.48,38.03 117.69,38.03 117.78,38.11 117.78,38.33 117.87,38.42 118.02,38.42 118.11,38.51 118.11,38.66 134.24,54.79 134.24,104.52 132.61,106.15 132.61,106.77 132.75,106.9 C45.1
  BOTTOM w0.127: P1.A23 v4(117.47,20.7)
SRXB_7P: length 6.8
  TOP w0.133: U1A.B30 132.52,114.29 132.43,114.18 arc(132.34,113.98) 132.31,113.77 132.29,113.06 132.29,113.05 132.29,108.16 arc(132.26,108) C33.2
SRXB_7P_FMC: length 98.7
  TOP w0.133: v4(118.75,20.7) 118.18,20.14 118.18,19.99 117.84,19.64 117.32,19.64 116.66,20.31 116.66,37.64 133.93,54.92 133.93,104.39 132.3,106.02 132.3,106.77 132.17,106.9 C33.1
  BOTTOM w0.127: P1.A22 v4(118.75,20.7)
SRXB_8N: length 27
  TOP w0.133: C46.2 135.91,92.44 135.37,92.44 v7(135.08,92.15)
  L3_SIGNAL w0.108: v7(135.08,92.15) 135.08,92.24 134.86,92.46 134.27,92.46 131.57,95.16 131.57,115.51 131.68,115.62 131.8,115.62 131.9,115.52 v7(131.9,115.33)
SRXB_8N_FMC: length 123
  TOP w0.133: C46.1 136.71,92.36 137.41,92.36 v9(137.62,92.15)
  L24_SIGNAL w0.108: v9(115.09,21.89) 115.52,22.33 115.52,22.48 115.18,22.82 114.66,22.82 114.53,22.68 114.53,18.75 116.3,16.98 116.65,16.98 116.8,17.13 116.93,17.13 117.08,16.98 117.21,16.98 117.36,17.13 117.49,17.13 117.64,16.98 117.77,16.98 117.92,17.13 118.05,17.13 118.2,16.98 118.33,16.98 118.48,17.13 118.61,17.13 118.76,16.98 118.88,16.98 119.04,17.13 119.16,17.13 119.32,16.98 119.44,16.98 119.6,17.13 119.72,17.13 119.88,16.98 120,16.98 120.15,17.13 120.28,17.13 120.43,16.98 120.56,16.98 120.71,17.13 120.84,17.13 120.99,16.98 121.12,16.98 121.27,17.13 121.4,17.13 121.55,16.98 121.7,16.98 121.86,17.13 121.98,17.13 122.14,16.98 122.26,16.98 122.42,17.13 122.54,17.13 122.69,16.98 122.82,16.98 122.97,17.13 123.1,17.13 123.25,16.98 123.38,16.98 123.53,17.13 123.66,17.13 123.81,16.98 123.94,16.98 124.09,17.13 124.22,17.13 124.37,16.98 124.5,16.98 124.65,17.13 124.78,17.13 124.93,16.98 125.06,16.98 125.21,17.13 125.34,17.13 125.49,16.98 125.62,16.98 125.77,17.13 125.9,17.13 126.05,16.98 126.17,16.98 126.33,17.13 126.45,17.13 126.61,16.98 126.73,16.98 126.89,17.13 127.01,17.13 127.17,16.98 127.29,16.98 127.44,17.13 127.57,17.13 127.72,16.98 127.85,16.98 128,17.13 128.13,17.13 128.28,16.98 143.76,16.98 144.68,17.9 144.68,28.35 148.16,31.83 148.16,79.8 139.32,88.65 139.32,92.2 139.08,92.44 137.91,92.44 v9(137.62,92.15)
  BOTTOM w0.114: P1.B25 115.57,21.41 v9(115.09,21.89)
SRXB_8P: length 27.1
  TOP w0.133: C34.2 135.92,92.75 135.37,92.75 v7(135.08,93.04)
  L3_SIGNAL w0.108: v7(135.08,93.04) 134.8,92.75 134.4,92.75 131.87,95.28 131.87,112.7 131.97,112.8 131.97,112.95 131.87,113.06 131.87,113.41 131.97,113.51 131.97,113.67 131.87,113.77 131.87,114.05 132,114.17 132,114.33 131.87,114.45 131.87,114.78 132.04,114.95 132.06,114.95 132.29,115.17 132.29,115.19 132.33,115.24 132.33,115.51 131.9,115.94 v7(131.9,116.13)
SRXB_8P_FMC: length 123
  TOP w0.133: C34.1 136.78,92.73 137.32,92.73 v9(137.62,93.04)
  L24_SIGNAL w0.108: v9(116.23,22) 116.13,22 115.82,22.31 115.82,22.6 115.31,23.11 114.54,23.11 114.23,22.8 114.23,18.87 114.23,18.87 114.23,18.63 116.18,16.68 143.88,16.68 144.98,17.78 144.98,28.23 148.46,31.71 148.46,79.92 139.62,88.77 139.62,92.33 139.2,92.74 137.91,92.74 v9(137.62,93.04)
  BOTTOM w0.114: v9(116.23,22) 116.84,21.39 P1.B24
SRXB_9N: length 6.8
  TOP w0.133: U1A.D31 131.1,113.85 arc(131.15,113.97) 131.26,114.02 arc(131.39,113.96) 131.44,113.84 131.44,113.59 arc(131.42,113.49) 131.37,113.42 131.15,113.2 arc(131.09,113.12) 131.04,113.04 arc(131.02,112.98) 131.03,112.91 131.03,108.16 arc(131.06,108) C47.2
SRXB_9N_FMC: length 99.5
  TOP w0.133: v4(114.94,19.43) 115.01,19.43 115.52,18.92 116.48,18.92 116.69,19.13 116.69,19.55 116.38,19.85 115.96,19.85 115.75,20.07 115.75,40.18 132.65,57.08 132.65,104.08 131.01,105.71 131.01,106.77 131.15,106.9 C47.1
  BOTTOM w0.127: P1.Z25 v4(114.94,19.43)
SRXB_9P: length 6.8
  TOP w0.133: U1A.D30 130.92,114.29 130.83,114.18 arc(130.74,113.98) 130.71,113.77 130.69,113.06 130.69,113.05 130.69,108.16 arc(130.66,108) C35.2
SRXB_9P_FMC: length 99.5
  TOP w0.133: C35.1 130.57,106.9 130.7,106.77 130.7,105.58 132.33,103.95 132.33,57.21 117.07,41.94 116.85,41.94 116.76,41.85 116.76,41.64 116.67,41.55 116.46,41.55 116.37,41.46 116.37,41.24 116.28,41.15 116.06,41.15 115.97,41.06 115.97,40.85 115.88,40.76 115.67,40.76 115.58,40.67 115.58,40.45 115.44,40.31 115.44,40.04 115.28,39.89 115.28,39.76 115.44,39.61 115.44,39.48 115.28,39.33 115.28,39.2 115.44,39.05 115.44,38.93 115.28,38.77 115.28,38.65 115.44,38.49 115.44,38.34 115.28,38.19 115.28,38.06 115.44,37.91 115.44,37.78 115.28,37.63 115.28,37.5 115.44,37.35 115.44,37.22 115.28,37.07 115.28,36.94 115.44,36.79 115.44,36.66 115.28,36.51 115.28,36.39 115.44,36.23 115.44,36.11 115.28,35.95 115.28,35.83 115.44,35.67 115.44,35.55 115.28,35.39 115.28,35.27 115.44,35.12 115.44,34.99 115.28,34.84 115.28,34.71 115.44,34.56 115.44,34.43 115.28,34.28 115.28,34.15 115.44,34 115.44,24.91 115.3,24.77 115.3,24.58 115.44,24.45 115.44,24.27 115.28,24.12 115.28,23.99 115.44,23.84 115.44,23.63 115.28,23.48 115.28,23.36 115.44,23.2 115.44,22.97 115.28,22.82 115.28,22.69 115.44,22.54 115.44,22.34 115.28,22.19 115.28,22.06 115.44,21.91 115.44,19.94 115.83,19.54 116.09,19.54 v4(116.21,19.43)
  BOTTOM w0.127: P1.Z24 v4(116.21,19.43)
SRXB_10N: length 30.4
  TOP w0.133: v7(135.08,89.45) 135.41,89.79 135.86,89.79 C48.2
  L3_SIGNAL w0.108: v7(130.3,115.33) 130.31,115.55 arc(130.28,115.64) 130.2,115.69 arc(130.14,115.69) 130.09,115.69 arc(129.98,115.63) 129.92,115.52 129.92,115.34 arc(129.92,115.21) 129.92,115.08 arc(129.92,115.08) 129.92,115.07 arc(129.95,114.96) 130,114.86 130.08,114.75 arc(130.09,114.72) 130.1,114.69 130.1,114.55 arc(130.1,114.55) 130.1,114.55 130.1,114.54 130.1,94.98 arc(130.16,94.75) 130.3,94.56 133.45,91.42 arc(133.51,91.33) 133.53,91.22 133.53,90.85 arc(133.59,90.55) 133.76,90.29 134.1,89.94 arc(134.4,89.76) 134.75,89.74 134.79,89.74 v7(135.08,89.45)
SRXB_10N_FMC: length 119.6
  TOP w0.133: v7(137.62,89.45) 137.41,89.66 136.71,89.66 C48.1
  L3_SIGNAL w0.108: 112.4,20.7 112.7,20.7 112.93,20.47 112.93,19.86 112.71,19.65 112.71,18.9 112.91,18.7 112.91,17.24 114.91,15.24 143.92,15.24 146.37,17.7 146.37,23.68 145.95,24.1 145.25,24.1 145.01,24.34 145.01,25.91 146.37,27.28 146.37,29.01 144.9,30.48 144.9,59.09 136.12,67.87 136.12,88 137.58,89.45 v7(137.62,89.45)
  BOTTOM w0.127: P1.A27 112.4,20.7
SRXB_10P: length 30.4
  TOP w0.133: C36.2 135.97,90.1 135.32,90.1 v7(135.08,90.34)
  L3_SIGNAL w0.108: v7(130.3,116.13) 130.43,116.01 arc(130.66,115.73) 130.74,115.37 130.74,115.03 130.4,114.7 arc(130.4,114.69) 130.4,114.69 130.4,114.55 130.53,114.43 130.53,114.27 130.43,114.17 130.43,114.02 130.49,113.96 130.49,113.8 130.4,113.71 130.4,113.54 130.49,113.45 130.49,113.29 130.4,113.2 130.4,113.03 130.52,112.92 130.52,112.76 130.4,112.65 130.4,112.47 130.49,112.38 130.49,112.23 130.4,112.14 130.4,111.91 130.53,111.79 130.53,111.63 130.4,111.51 130.4,95.03 130.51,94.78 133.66,91.63 arc(133.78,91.44) 133.83,91.22 133.83,90.85 arc(133.86,90.66) 133.97,90.5 134.32,90.15 arc(134.6,90.03) 134.89,90.15 v7(135.08,90.34)
SRXB_10P_FMC: length 119.5
  TOP w0.133: v7(137.62,90.34) 137.32,90.04 136.78,90.04 C36.1
  L3_SIGNAL w0.108: v7(137.62,90.34) 137.62,90.32 137,89.71 137,89.3 135.82,88.12 135.82,67.75 144.6,58.96 144.6,30.36 146.08,28.89 146.08,27.4 144.71,26.03 144.71,24.22 145.12,23.8 145.83,23.8 146.08,23.56 146.08,17.82 143.79,15.54 115.03,15.54 113.21,17.36 113.21,18.83 113.01,19.02 113.01,19.52 113.23,19.75 113.23,20.5 113.44,20.7 113.66,20.7
  BOTTOM w0.127: P1.A26 113.66,20.7
SRXB_11N: length 6.8
  TOP w0.133: U1A.F31 129.5,113.85 arc(129.55,113.97) 129.66,114.02 arc(129.79,113.96) 129.84,113.84 129.84,113.59 arc(129.82,113.49) 129.77,113.42 129.55,113.2 arc(129.49,113.12) 129.44,113.04 arc(129.42,112.98) 129.43,112.91 129.43,108.16 arc(129.46,108) C49.2
SRXB_11N_FMC: length 105.7
  TOP w0.133: C49.1 129.55,106.9 129.41,106.77 129.41,105.15 131.44,103.12 131.44,59.44 111.89,39.88 111.89,39.14 111.97,39.06 111.97,38.93 111.89,38.85 111.89,38.72 112.04,38.57 112.04,38.44 111.89,38.29 111.89,38.01 112.04,37.86 112.04,37.73 111.89,37.58 111.89,37.43 112.04,37.27 112.04,37.15 111.89,37 111.89,36.79 112.04,36.64 112.04,36.51 111.89,36.36 111.89,36.23 112.04,36.08 112.04,35.95 111.89,35.8 111.89,35.52 112.04,35.37 112.04,35.24 111.89,35.09 111.89,34.96 112.04,34.81 112.04,34.68 111.89,34.53 111.89,34.25 112.04,34.1 112.04,33.97 111.89,33.82 111.89,33.27 113.23,31.93 113.23,30.67 113.24,30.66 113.24,24.34 113.25,24.33 113.25,22.84 114.87,21.22 114.87,20.09 114.35,19.58 112.74,19.58 111.71,18.55 111.71,17.97 112.01,17.66 112.6,17.66 112.78,17.84 112.78,18.03 112.64,18.16 v4(112.4,18.16)
  BOTTOM w0.127: P1.Y27 v4(112.4,18.16)
SRXB_11P: length 6.8
  TOP w0.133: U1A.F30 129.32,114.29 129.23,114.18 arc(129.14,113.98) 129.11,113.77 129.09,113.06 129.09,113.05 129.09,108.16 arc(129.06,108) C37.2
SRXB_11P_FMC: length 105.7
  TOP w0.133: C37.1 128.97,106.9 129.1,106.77 129.1,105.03 131.13,102.99 131.13,59.56 111.58,40.01 111.58,33.14 112.92,31.8 112.92,30.54 112.93,30.53 112.93,24.21 112.94,24.2 112.94,22.71 114.56,21.09 114.56,20.22 114.22,19.89 112.61,19.89 111.35,18.63 111.35,17.88 111.88,17.35 112.73,17.35 113.32,17.94 113.44,17.94 v4(113.66,18.16)
  BOTTOM w0.127: P1.Y26 v4(113.66,18.16)
STATUS_LED: length 2.1
  TOP w0.191: v1(22.2,216.08) 22.3,216.18 DS1.A
  BOTTOM w0.191: R4.2 v1(22.2,216.08)
STXA_0N: length 38.1
  TOP w0.133: C62.2 116.31,84.82 116.61,84.7 arc(116.64,84.69) 116.68,84.68 116.94,84.68 arc(117.02,84.7) 117.09,84.74 v9(117.3,84.95)
  L24_SIGNAL w0.108: U1A.AA27 117.55,116.88 arc(117.58,116.83) 117.59,116.78 117.48,116.32 117.48,116.31 117.48,115.63 117.35,115.5 117.35,115.34 117.47,115.21 117.47,114.99 117.35,114.86 117.35,114.66 117.48,114.52 117.48,114.3 117.37,114.19 117.37,113.94 117.47,113.84 117.47,113.68 117.37,113.58 117.37,113.42 117.46,113.33 117.46,113.13 117.37,113.04 117.37,112.88 117.46,112.79 117.46,112.57 117.37,112.48 117.37,112.33 117.48,112.21 117.48,112.06 117.37,111.95 117.37,111.68 117.46,111.6 117.46,111.43 117.35,111.32 117.35,111.17 117.46,111.06 117.46,110.9 117.35,110.78 117.35,110.52 117.46,110.4 117.46,110.24 117.34,110.12 117.34,109.96 117.46,109.84 117.46,109.66 117.35,109.55 117.35,109.27 117.45,109.17 117.45,109.02 117.35,108.92 117.35,108.66 117.46,108.55 117.46,108.41 117.36,108.31 117.36,108.15 117.45,108.06 117.45,107.8 117.32,107.67 117.32,107.52 117.45,107.39 117.45,107.24 117.32,107.11 117.32,106.93 117.47,106.78 117.47,106.6 117.37,106.5 117.37,106.25 117.46,106.16 117.46,105.95 117.43,105.91 115.7,104.18 115.7,88.72 118.67,85.75 118.67,85.14 118.64,85.11 118.63,85.1 118.19,84.66 117.59,84.66 v9(117.3,84.95)
STXA_0N_FMC: length 80.2
  TOP w0.133: C62.1 115.61,84.67 112.63,84.67 111.83,83.86 111.83,68.7 115.13,65.4 115.13,59.82 100.21,44.89 100.21,21.8 99,20.6 99,19.81 98.92,19.73 98.92,19.3 98.55,18.92 98.43,18.92 98.11,18.61 98.11,18.49 97.79,18.16 v4(97.16,18.16)
  BOTTOM w0.127: P1.Y39 v4(97.16,18.16)
STXA_0P: length 38.1
  TOP w0.133: v9(117.3,84.06) 117.07,84.29 arc(117.01,84.33) 116.93,84.35 116.55,84.35 arc(116.47,84.33) 116.4,84.29 C50.2
  L24_SIGNAL w0.108: v9(117.3,84.06) 117.59,84.36 118.31,84.36 118.43,84.48 118.48,84.52 118.8,84.84 118.86,84.91 118.97,85.02 118.97,85.87 118.85,85.99 116,88.85 116,104.06 117.78,105.84 117.78,114.65 117.77,114.65 117.77,115.5 117.77,116.25 117.83,116.5 117.85,116.55 arc(117.86,116.57) 117.86,116.59 arc(117.91,116.77) 117.93,116.96 arc(117.85,117.29) 117.66,117.57 U1A.AA26
STXA_0P_FMC: length 80.2
  TOP w0.133: v4(98.42,18.16) 98.42,18.48 98.56,18.61 98.68,18.61 99.23,19.17 99.23,19.6 99.31,19.68 99.31,20.47 100.52,21.68 100.52,44.76 115.44,59.69 115.44,65.53 112.14,68.83 112.14,80.95 112.38,81.19 112.38,81.37 112.14,81.61 112.14,81.84 112.37,82.07 112.37,82.27 112.17,82.47 112.14,82.47 112.14,82.78 112.4,83.03 112.4,83.19 112.14,83.44 112.14,83.69 112.27,83.82 112.54,83.82 112.67,83.95 112.67,84.17 112.81,84.31 113.08,84.31 113.28,84.11 113.46,84.11 113.7,84.34 113.85,84.34 114.11,84.08 114.26,84.08 114.52,84.35 114.71,84.35 114.94,84.12 115.13,84.12 115.37,84.35 115.59,84.35 C50.1
  BOTTOM w0.127: P1.Y38 v4(98.42,18.16)
STXA_1N: length 6.8
  TOP w0.133: U1A.AA31 117.5,113.85 arc(117.55,113.97) 117.66,114.02 arc(117.79,113.96) 117.84,113.84 117.84,113.59 arc(117.82,113.49) 117.77,113.42 117.55,113.2 arc(117.49,113.12) 117.44,113.04 arc(117.42,112.98) 117.43,112.91 117.43,108.16 arc(117.46,108) C63.2
STXA_1N_FMC: length 102.1
  TOP w0.133: C63.1 117.45,107.23 117.45,107.14 117.39,107.08 117.39,107.07 117.35,107.03 117.35,105.29 110.55,98.48 110.55,65.36 111.97,63.94 113.44,63.94 v9(113.79,64.29)
  L24_SIGNAL w0.108: v9(113.79,64.29) 113.43,63.93 112.37,63.93 112.09,63.64 112.09,60.43 112.97,59.55 112.97,45.21 123.04,35.13 123.04,18.27 122.93,18.16 v9(122.58,18.16)
  BOTTOM w0.114: P1.Y19 123.19,17.55 v9(122.58,18.16)
STXA_1P: length 6.8
  TOP w0.133: U1A.AA30 117.32,114.29 117.23,114.18 arc(117.14,113.98) 117.11,113.77 117.09,113.06 117.09,113.05 117.09,108.16 arc(117.06,108) C51.2
STXA_1P_FMC: length 102.1
  TOP w0.133: C51.1 117.04,107.25 117.04,105.42 110.24,98.61 110.24,65.23 111.46,64.01 111.84,63.63 113.43,63.63 v9(113.79,63.26)
  L24_SIGNAL w0.108: v9(123.8,18.16) 123.45,18.16 123.34,18.27 123.34,35.26 113.27,45.33 113.27,59.67 112.39,60.55 112.39,63.52 112.5,63.63 113.43,63.63 v9(113.79,63.26)
  BOTTOM w0.114: P1.Y18 124.43,17.53 v9(123.8,18.16)
STXA_2N: length 35.2
  TOP w0.133: C64.2 106.27,87.38 106.87,87.38 v7(107.14,87.65)
  L3_SIGNAL w0.108: v7(107.14,87.65) 107.38,87.4 107.41,87.4 107.48,87.32 107.62,87.3 107.91,87.3 109.38,88.77 109.38,91.28 110.14,92.05 110.14,93.07 110.6,93.53 110.6,95.5 116.52,101.42 116.52,109.06 116.52,112.46 arc(116.49,112.53) 116.41,112.56 arc(116.3,112.62) 116.27,112.74 116.28,112.83 arc(116.31,112.95) 116.41,113 arc(116.49,113.03) 116.52,113.1 116.52,113.32 arc(116.49,113.4) 116.41,113.43 arc(116.34,113.46) 116.31,113.54 116.31,113.75 arc(116.34,113.83) 116.41,113.86 arc(116.49,113.89) 116.52,113.97 116.52,114.59 arc(116.5,114.71) 116.43,114.82 arc(116.36,114.94) 116.32,115.07 arc(116.32,115.08) 116.32,115.08 arc(116.32,115.21) 116.32,115.34 116.32,115.52 arc(116.38,115.63) 116.49,115.69 arc(116.54,115.69) 116.6,115.69 arc(116.68,115.64) 116.71,115.55 v7(116.7,115.33)
STXA_2N_FMC: length 80.8
  TOP w0.133: C64.1 105.46,87.38 104.87,87.38 v7(104.6,87.65)
  L3_SIGNAL w0.108: 117.47,18.16 117.7,18.16 arc(117.88,18.24) 117.96,18.42 117.96,35.02 arc(117.94,35.13) 117.88,35.22 101.85,51.24 101.85,86.74 102.49,87.38 104.27,87.38 arc(104.32,87.39) 104.36,87.42 104.6,87.65 v7(104.6,87.65)
  BOTTOM w0.127: P1.Y23 117.47,18.16
STXA_2P: length 35.2
  TOP w0.133: C52.2 106.3,87.04 106.85,87.04 v7(107.14,86.76)
  L3_SIGNAL w0.108: v7(116.7,116.13) 116.83,116.01 117.08,115.57 117.14,115.51 117.14,115.15 116.85,114.87 116.83,114.73 116.83,109.07 116.82,109.06 116.82,108.94 116.82,101.3 110.9,95.38 110.9,93.4 110.44,92.94 110.44,91.92 109.68,91.16 109.68,88.65 108.04,87 107.6,87 107.45,87.02 107.37,86.95 107.33,86.96 v7(107.14,86.76)
STXA_2P_FMC: length 80.8
  TOP w0.133: C52.1 105.6,86.88 105.42,87.05 104.89,87.05 v7(104.6,86.76)
  L3_SIGNAL w0.108: 118.75,18.16 118.48,18.16 arc(118.35,18.2) 118.27,18.31 arc(118.26,18.36) 118.26,18.42 118.26,35.02 arc(118.21,35.24) 118.09,35.43 102.15,51.36 102.15,85.04 102.24,85.13 102.24,85.28 102.17,85.36 102.17,85.51 102.28,85.63 102.28,85.78 102.17,85.89 102.17,86.05 102.24,86.12 102.24,86.27 102.16,86.36 102.16,86.51 102.27,86.63 102.43,86.63 102.54,86.73 102.54,86.89 102.7,87.05 102.84,87.05 102.96,86.94 103.11,86.94 103.23,87.05 103.5,87.05 103.63,86.92 103.81,86.92 103.94,87.05 104.17,87.05 arc(104.29,87.03) 104.4,86.96 v7(104.6,86.76)
  BOTTOM w0.127: P1.Y22 118.75,18.16
STXA_3N: length 23.3
  TOP w0.133: C65.2 116.37,95.52 arc(116.44,95.47) 116.51,95.46 116.94,95.46 arc(117.02,95.47) 117.09,95.52 v7(117.3,95.73)
  L3_SIGNAL w0.108: v7(118.3,115.33) 118.3,115.42 118.02,115.7 117.98,115.7 117.91,115.62 117.91,114.12 117.82,114.03 117.82,113.88 117.91,113.79 117.91,113.61 117.82,113.53 117.82,113.37 117.88,113.31 117.88,113.16 117.81,113.08 117.81,112.93 117.91,112.83 117.91,112.67 117.83,112.6 117.83,112.39 117.91,112.32 117.91,112.12 117.86,112.07 117.86,111.91 117.91,111.86 117.91,111.71 117.82,111.62 117.82,111.47 117.91,111.38 117.91,111.2 117.82,111.11 117.82,110.96 117.91,110.87 117.91,110.64 117.83,110.57 117.83,110.41 117.91,110.34 117.91,110.13 117.83,110.06 117.83,109.91 117.91,109.83 117.91,109.63 117.84,109.56 117.84,109.41 117.91,109.35 117.91,109.22 117.83,109.14 117.83,108.99 117.91,108.92 117.91,95.56 117.81,95.46 117.7,95.43 arc(117.6,95.45) 117.52,95.5 v7(117.3,95.73)
STXA_3N_FMC: length 88.2
  TOP w0.133: v7(114.76,95.73) 114.96,95.53 arc(115.02,95.49) 115.1,95.47 115.55,95.47 arc(115.63,95.49) 115.7,95.53 C65.1
  L3_SIGNAL w0.108: 122.56,20.7 122.99,21.14 122.99,32.48 123.47,32.97 124.01,32.97 124.49,33.45 124.49,36.67 108.77,52.39 108.77,85.09 109.04,85.36 110.27,86.59 110.27,90.34 111.08,91.16 111.08,92.07 111.92,92.91 111.92,94.59 112.81,95.47 114.1,95.47 114.27,95.45 114.27,95.45 114.38,95.44 arc(114.46,95.45) 114.53,95.5 v7(114.76,95.73)
  BOTTOM w0.127: P1.A19 122.56,20.7
STXA_3P: length 23.4
  TOP w0.133: C53.2 116.4,95.06 arc(116.47,95.11) 116.55,95.12 116.93,95.12 arc(117.01,95.11) 117.07,95.06 v7(117.3,94.84)
  L3_SIGNAL w0.108: v7(117.3,94.84) 117.4,94.95 arc(117.58,95.07) 117.79,95.13 117.8,95.13 117.9,95.13 118.21,95.44 118.21,113.49 118.21,114.73 118.42,114.95 118.46,114.95 118.69,115.17 118.69,115.49 118.66,115.51 118.66,115.55 118.3,115.91 v7(118.3,116.13)
STXA_3P_FMC: length 88.2
  TOP w0.133: C53.1 115.76,94.96 115.64,95.08 arc(115.58,95.12) 115.5,95.14 115.14,95.14 arc(115.06,95.12) 114.99,95.08 v7(114.76,94.84)
  L3_SIGNAL w0.108: 123.82,20.7 123.29,21.24 123.29,32.36 123.6,32.67 124.13,32.67 124.79,33.33 124.79,36.79 109.07,52.52 109.07,84.96 110.57,86.46 110.57,90.22 111.38,91.03 111.38,91.95 112.22,92.79 112.22,92.91 112.31,93 112.31,93.15 112.22,93.24 112.22,93.42 112.31,93.51 112.31,93.66 112.22,93.75 112.22,93.9 112.29,93.98 112.29,94.13 112.22,94.21 112.22,94.46 112.34,94.59 112.39,94.59 112.5,94.7 112.5,94.74 112.61,94.86 112.71,94.86 112.81,94.96 112.81,95.06 112.93,95.18 113.46,95.18 113.59,95.05 113.79,95.05 113.92,95.18 114.07,95.18 114.22,95.15 114.23,95.15 114.33,95.13 arc(114.45,95.11) 114.56,95.04 v7(114.76,94.84)
  BOTTOM w0.127: P1.A18 123.82,20.7
STXA_4N: length 39.5
  TOP w0.133: C66.2 116.37,82.05 arc(116.44,82.01) 116.51,81.99 116.94,81.99 arc(117.02,82.01) 117.09,82.05 v9(117.3,82.26)
  L24_SIGNAL w0.108: U1A.W27 119.21,116.82 119.21,116.38 119.18,116.28 119.18,116.04 119.16,115.94 119.16,115.68 119.01,115.53 119.01,115.4 119.16,115.25 119.16,115.07 119.01,114.92 119.01,114.8 119.16,114.64 119.16,114.26 119.01,114.11 119.01,113.98 119.16,113.83 119.16,113.68 119.01,113.53 119.01,113.4 119.16,113.25 119.16,112.99 119.01,112.84 119.01,112.71 119.16,112.56 119.16,112.33 119.01,112.18 119.01,112.05 119.16,111.9 119.16,111.7 119.01,111.54 119.01,111.42 119.16,111.26 119.16,111.04 119.01,110.88 119.01,110.76 119.16,110.6 119.16,110.4 119.01,110.25 119.01,110.1 119.16,109.95 119.16,109.79 119.01,109.64 119.01,109.51 119.16,109.36 119.16,109.23 119.01,109.08 119.01,108.95 119.16,108.8 119.16,108.6 119.09,108.52 119.09,108.37 119.16,108.3 119.16,87.86 119.61,87.41 119.61,83.22 arc(119.59,83.12) 119.53,83.03 118.57,82.07 arc(118.48,82.01) 118.38,81.99 117.57,81.99 v9(117.3,82.26)
STXA_4N_FMC: length 73.8
  TOP w0.133: C66.1 115.61,81.97 114.15,81.97 113.13,80.95 113.13,69.82 116.4,66.55 116.4,58.17 102.75,44.51 102.75,22.72 100.15,20.12 100.15,19.88 v4(99.69,19.43)
  BOTTOM w0.127: P1.Z37 v4(99.69,19.43)
STXA_4P: length 39.5
  TOP w0.133: v9(117.3,81.37) 117.07,81.59 arc(117.01,81.64) 116.93,81.65 116.55,81.65 arc(116.47,81.64) 116.4,81.59 C54.2
  L24_SIGNAL w0.108: v9(117.3,81.37) 117.61,81.69 118.38,81.69 arc(118.6,81.73) 118.79,81.86 119.74,82.81 arc(119.87,83) 119.91,83.22 119.91,87.53 119.46,87.98 119.46,115.92 119.47,116.02 119.47,116.23 119.51,116.33 119.51,116.57 arc(119.51,116.58) 119.51,116.59 arc(119.53,116.67) 119.56,116.76 arc(119.59,116.93) 119.55,117.11 119.55,117.11 arc(119.54,117.14) 119.53,117.17 arc(119.52,117.23) 119.49,117.29 119.43,117.39 arc(119.41,117.42) 119.39,117.44 U1A.W26
STXA_4P_FMC: length 73.8
  TOP w0.133: v4(100.97,19.43) 100.46,19.94 100.46,19.99 103.06,22.59 103.06,44.38 116.71,58.04 116.71,66.67 113.44,69.95 113.44,80.04 113.64,80.24 113.64,80.42 113.44,80.62 113.44,80.82 113.7,81.08 113.95,81.08 114.09,81.21 114.09,81.47 114.28,81.66 114.83,81.66 115.04,81.46 115.24,81.46 115.44,81.66 115.58,81.66 C54.1
  BOTTOM w0.127: P1.Z36 v4(100.97,19.43)
STXA_5N: length 6.8
  TOP w0.133: U1A.W31 119.1,113.85 arc(119.15,113.97) 119.26,114.02 arc(119.39,113.96) 119.44,113.84 119.44,113.59 arc(119.42,113.49) 119.37,113.42 119.15,113.2 arc(119.09,113.12) 119.04,113.04 arc(119.02,112.98) 119.03,112.91 119.03,108.16 arc(119.06,108) C67.2
STXA_5N_FMC: length 98.1
  TOP w0.133: v9(114.94,70.56) 115.31,70.94 116.72,70.94 119.01,73.24 119.01,107.19 C67.1
  L24_SIGNAL w0.108: v9(114.94,70.56) 115.32,70.94 115.45,70.94 116.39,70.01 116.39,68.55 114.81,66.97 114.81,45.81 125.63,34.98 125.63,19.77 v9(125.22,19.35)
  BOTTOM w0.133: v9(125.22,19.35) 125.73,18.85 P1.Z17
STXA_5P: length 6.8
  TOP w0.133: U1A.W30 118.92,114.29 118.83,114.18 arc(118.74,113.98) 118.71,113.77 118.69,113.06 118.69,113.05 118.69,108.16 arc(118.66,108) C55.2
STXA_5P_FMC: length 98.1
  TOP w0.133: v9(114.96,71.6) 115.31,71.25 116.59,71.25 118.7,73.36 118.7,107.19 C55.1
  L24_SIGNAL w0.108: v9(114.96,71.6) 115.32,71.24 115.58,71.24 116.69,70.13 116.69,68.43 115.11,66.85 115.11,45.93 125.93,35.1 125.93,19.79 v9(126.31,19.41)
  BOTTOM w0.133: v9(126.31,19.41) 126.92,18.8 P1.Z16
STXA_6N: length 46.3
  BOTTOM w0.127: v4(119.9,118.53) 119.9,118.4 119.79,118.29 119.79,116.36 120.02,116.13
  BOTTOM w0.133: C68.2 116.48,76.55 118.08,76.55 120.02,78.49 120.02,106.2 119.87,106.34 119.87,106.53 120.02,106.68 120.02,106.88 119.83,107.07 119.83,107.26 119.96,107.39 119.96,107.75 119.83,107.88 119.83,108.07 120.02,108.25 120.02,108.61 119.89,108.73 119.89,108.92 120.02,109.04 120.02,109.25 119.88,109.38 119.88,109.57 120.01,109.7 120.01,109.89 119.89,110 119.89,110.19 120.02,110.31 120.02,110.64 119.89,110.76 119.89,110.95 120.02,111.07 120.02,111.3 119.84,111.48 119.84,111.68 120.02,111.86 120.02,112.06 119.83,112.25 119.83,112.44 120.02,112.62 120.02,112.83 119.87,112.97 119.87,113.16 120.02,113.31 120.02,113.54 119.86,113.7 119.86,113.89 120.02,114.05 120.02,114.21 119.86,114.36 119.86,114.49 120.02,114.64 120.02,114.77 119.98,114.8 119.98,114.93 120.02,114.96 120.02,116.13
STXA_6N_FMC: length 71.3
  L24_SIGNAL w0.108: v9(102.24,18.16) 102.32,18.16 103.13,18.97 110.01,18.97 110.36,19.32 110.36,51.75 109.2,52.91 109.2,71.99 113.81,76.6 114.67,76.6 v9(114.83,76.76)
  BOTTOM w0.127: P1.Y35 v9(102.24,18.16)
  BOTTOM w0.133: v9(114.83,76.76) 115.01,76.58 115.6,76.58 C68.1
STXA_6P: length 46.3
  BOTTOM w0.127: 120.33,116.35 120.09,116.59 120.09,118.16 120.29,118.37 120.29,118.69 119.9,119.09 v4(119.9,119.33)
  BOTTOM w0.133: C56.2 116.43,76.24 118.21,76.24 120.33,78.36 120.33,116.35
STXA_6P_FMC: length 71.3
  L24_SIGNAL w0.108: v9(114.83,76.15) 114.68,76.3 113.93,76.3 113.84,76.21 113.84,75.99 113.75,75.9 113.54,75.9 113.44,75.81 113.44,75.6 113.35,75.51 113.14,75.51 112.95,75.32 112.95,75.1 112.86,75.01 112.64,75.01 112.45,74.82 112.45,74.69 112.36,74.6 112.23,74.6 109.5,71.87 109.5,53.04 110.66,51.87 110.66,19.2 110.13,18.67 103.28,18.67 103.09,18.48 103.09,18.33 103.3,18.11 103.45,18.11 v9(103.61,18.11)
  BOTTOM w0.133: v9(103.61,18.11) 104.14,17.58 P1.Y34 ; C56.1 115.59,76.27 114.95,76.27 v9(114.83,76.15)
STXA_7N: length 6.8
  TOP w0.133: U1A.U31 120.7,113.85 arc(120.75,113.97) 120.86,114.02 arc(120.99,113.96) 121.04,113.84 121.04,113.59 arc(121.02,113.49) 120.97,113.42 120.75,113.2 arc(120.69,113.12) 120.64,113.04 arc(120.62,112.98) 120.63,112.91 120.63,108.16 arc(120.66,108) C69.2
STXA_7N_FMC: length 110.9
  TOP w0.133: C69.1 120.63,107.21 120.63,72.22 119.17,70.76 119.17,63.94 118.85,63.63 118.59,63.63 v7(118.24,63.27)
  L3_SIGNAL w0.108: v7(118.24,63.27) 117.8,63.71 117.31,63.71 117.27,63.67 117.27,63.67 117.09,63.49 117.09,61.47 118.19,60.37 120.39,60.37 122.22,58.54 122.22,54.35 134.59,41.98 134.59,31.49 134.82,31.27 134.82,17.3 133.98,16.47 128.91,16.47 128.12,17.25 128.12,17.68 127.63,18.16
  BOTTOM w0.127: P1.Y15 127.63,18.16
STXA_7P: length 6.8
  TOP w0.133: U1A.U30 120.52,114.29 120.43,114.18 arc(120.34,113.98) 120.31,113.77 120.29,113.06 120.29,113.05 120.29,108.16 arc(120.26,108) C57.2
STXA_7P_FMC: length 110.8
  TOP w0.133: C57.1 120.3,107.19 120.3,106.84 120.14,106.68 120.14,106.45 120.3,106.29 120.3,106.03 120.11,105.83 120.11,105.65 120.3,105.45 120.3,105.09 120.12,104.9 120.12,104.67 120.3,104.49 120.3,104.28 120.06,104.03 120.06,103.84 120.3,103.6 120.3,103.39 120.08,103.17 120.08,102.98 120.3,102.76 120.3,102.41 120.29,102.41 120.04,102.16 120.04,102.04 120.3,101.78 120.3,72.33 118.86,70.89 118.86,64.07 118.73,63.94 118.59,63.94 v7(118.24,64.29)
  L3_SIGNAL w0.108: 128.91,18.16 128.42,17.68 128.42,17.38 129.03,16.76 133.86,16.76 134.52,17.43 134.52,31.14 134.3,31.37 134.3,41.85 121.92,54.23 121.92,58.42 120.27,60.07 118.07,60.07 116.8,61.34 116.8,63.62 116.97,63.79 116.97,63.79 117.18,64.01 117.95,64.01 v7(118.24,64.29)
  BOTTOM w0.127: P1.Y14 128.91,18.16
STXA_8N: length 26.9
  TOP w0.133: v7(117.3,93.04) 117.09,92.82 arc(116.98,92.75) 116.86,92.73 116.6,92.73 arc(116.48,92.75) 116.37,92.82 C70.2
  L3_SIGNAL w0.108: v7(117.3,93.04) 117.48,92.86 118.27,92.86 118.69,93.28 118.69,100.12 119.84,101.26 119.84,111.38 119.61,111.61 119.61,111.86 119.84,112.09 119.84,112.34 119.58,112.6 119.58,112.95 119.84,113.21 119.84,113.46 119.58,113.72 119.58,114.2 119.84,114.45 119.84,114.71 119.47,115.08 119.47,115.51 119.55,115.6 119.71,115.6 119.9,115.41 v7(119.9,115.33)
STXA_8N_FMC: length 82.4
  TOP w0.133: C70.1 115.7,92.84 arc(115.65,92.81) 115.59,92.8 115.08,92.8 arc(115,92.81) 114.94,92.86 v7(114.76,93.04)
  L3_SIGNAL w0.108: 125.09,21.97 125.37,21.97 arc(125.5,22.01) 125.58,22.12 arc(125.59,22.17) 125.6,22.23 125.6,37.5 arc(125.59,37.55) 125.56,37.6 110.4,52.76 arc(110.3,52.9) 110.27,53.07 110.27,84.86 arc(110.3,85.02) 110.4,85.16 111.23,86 111.23,89.83 112.55,91.16 112.55,92.17 113.12,92.74 114.33,92.74 arc(114.45,92.76) 114.55,92.83 v7(114.76,93.04)
  BOTTOM w0.127: P1.B17 125.09,21.97
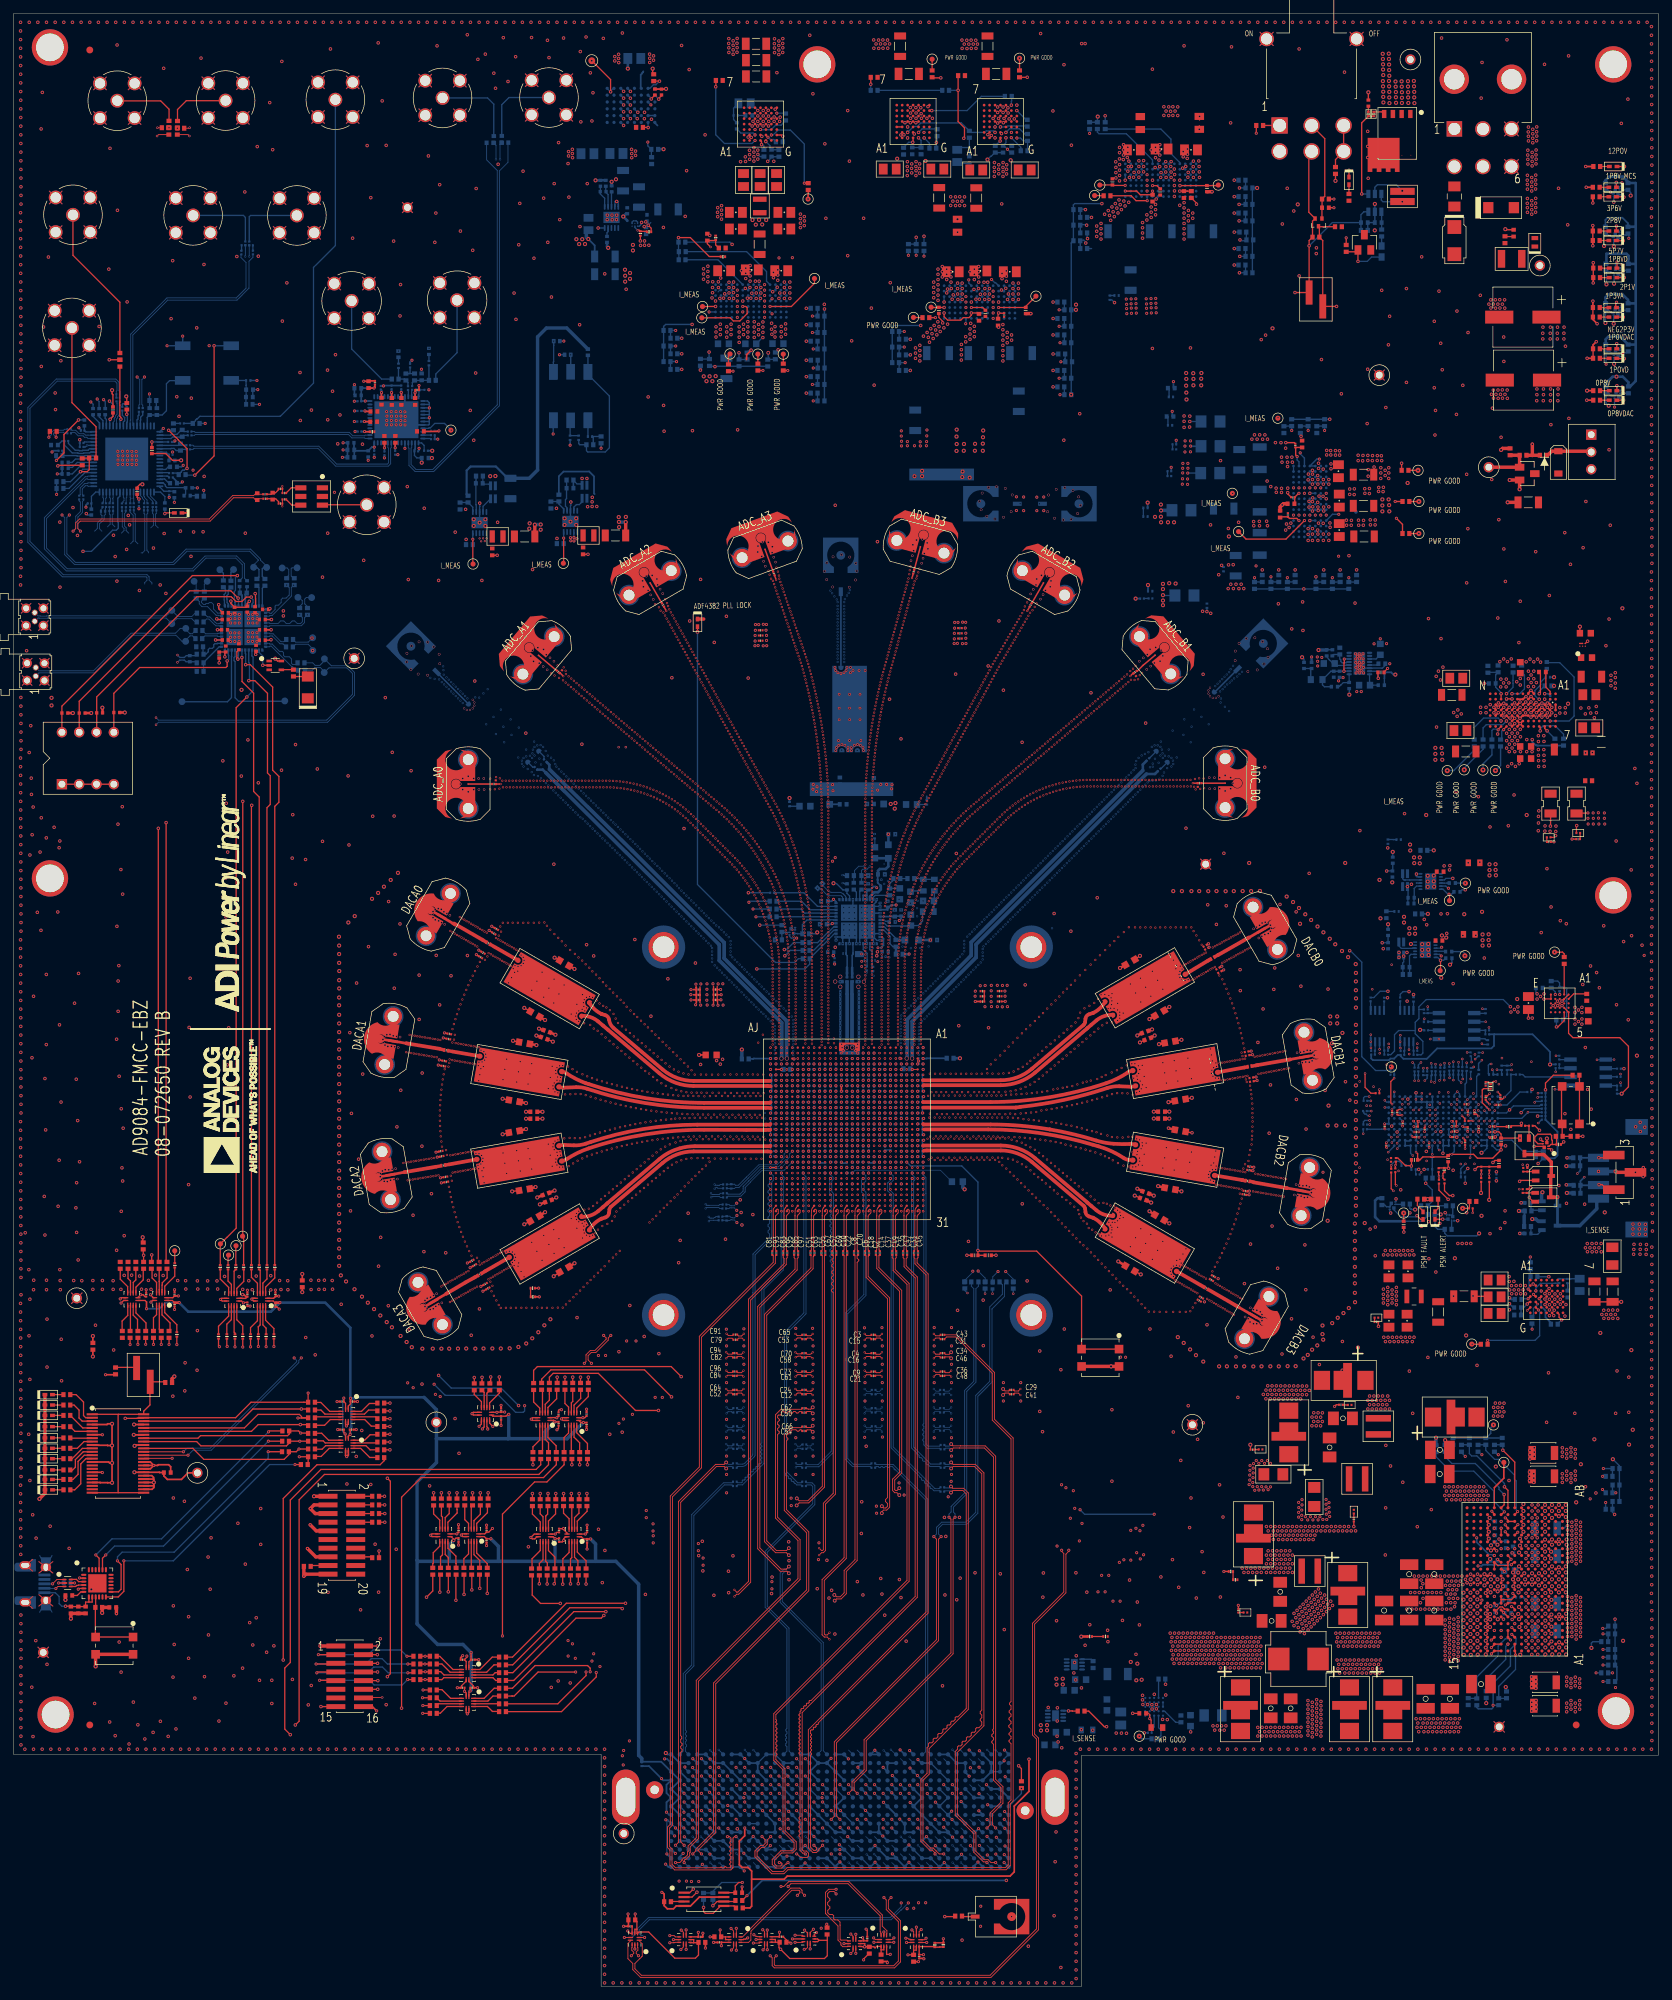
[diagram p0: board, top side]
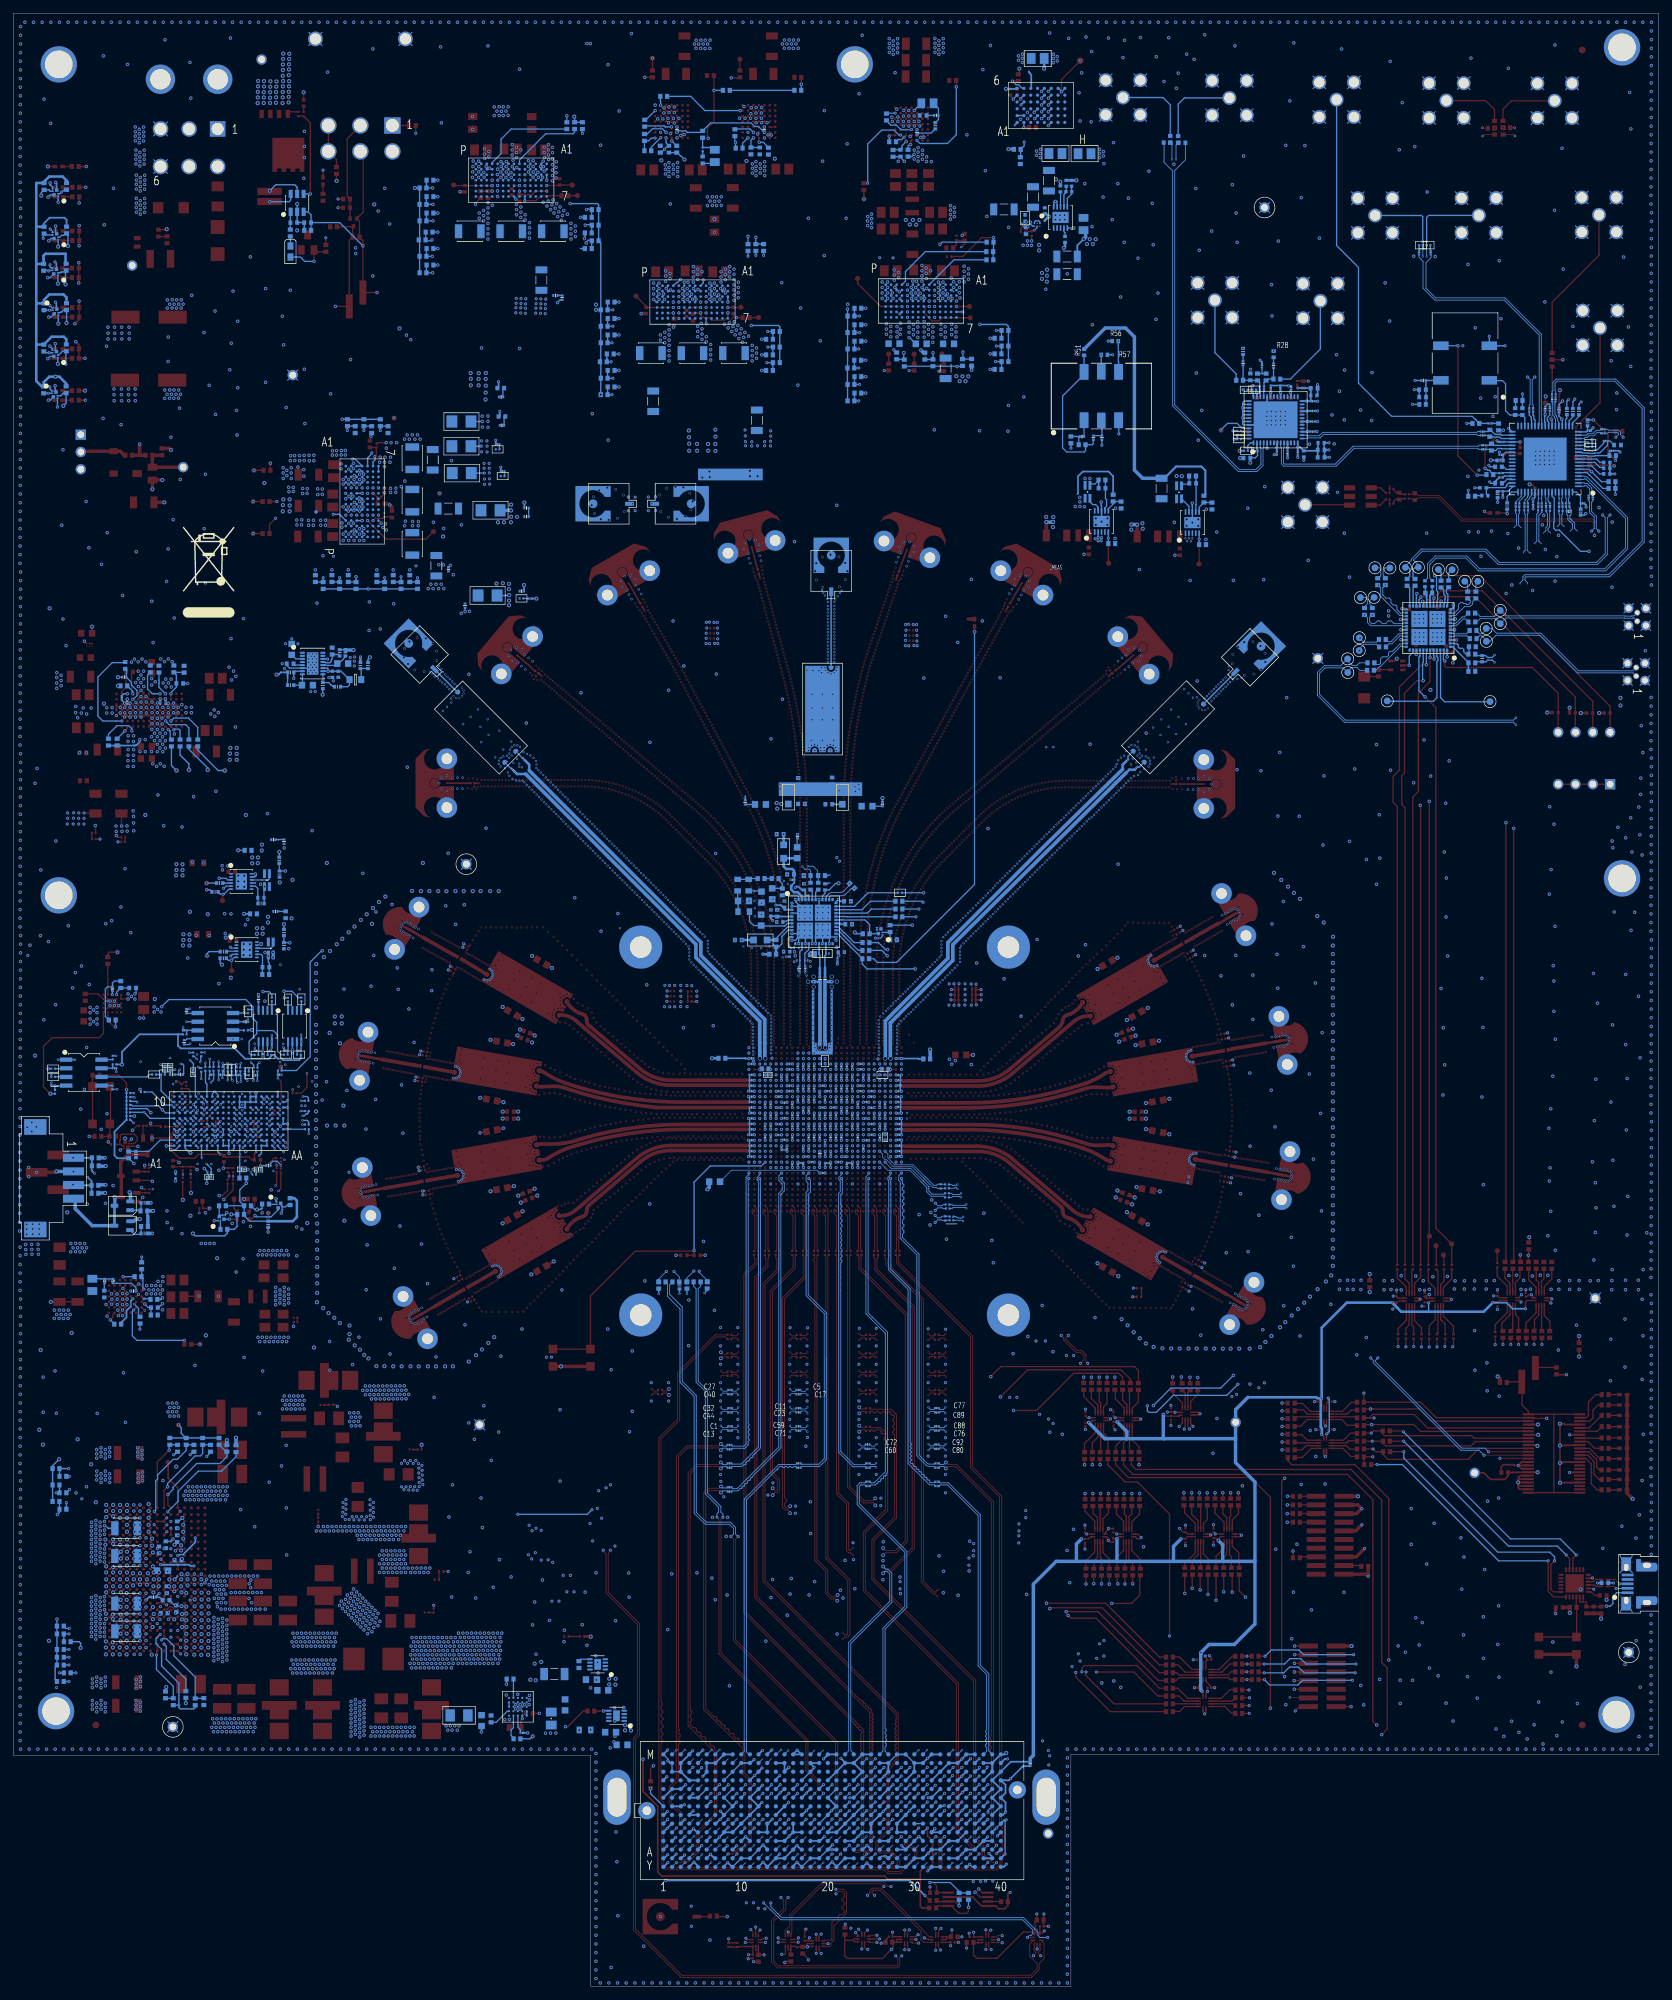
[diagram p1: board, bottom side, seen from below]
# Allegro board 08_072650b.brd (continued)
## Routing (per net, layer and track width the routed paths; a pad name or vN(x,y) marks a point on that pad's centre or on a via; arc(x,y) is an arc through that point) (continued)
STXA_8P: length 26.9
  TOP w0.133: C58.2 116.37,92.33 arc(116.43,92.38) 116.51,92.39 116.86,92.39 116.86,92.39 arc(117.04,92.36) 117.19,92.26 v7(117.3,92.15)
  L3_SIGNAL w0.108: v7(117.3,92.15) 117.71,92.56 118.39,92.56 118.99,93.16 118.99,99.99 120.14,101.14 120.14,115.02 120.29,115.17 120.29,115.49 119.9,115.87 v7(119.9,116.13)
STXA_8P_FMC: length 82.4
  TOP w0.133: C58.1 115.76,92.27 115.62,92.4 arc(115.56,92.44) 115.48,92.46 115.15,92.46 arc(115.08,92.44) 115.01,92.4 114.91,92.3 v7(114.78,92.3)
  L3_SIGNAL w0.108: 126.37,21.97 126.11,21.97 arc(125.96,22.03) 125.9,22.19 125.9,37.62 arc(125.88,37.68) 125.85,37.72 110.69,52.88 110.61,52.97 arc(110.58,53.01) 110.57,53.07 110.57,84.86 arc(110.58,84.91) 110.61,84.95 111.53,85.87 111.53,88.46 111.63,88.57 111.63,88.72 111.53,88.82 111.53,89.05 111.59,89.12 111.59,89.27 111.53,89.33 111.53,89.5 111.72,89.7 111.72,89.9 111.86,90.04 112.01,90.04 112.12,90.15 112.12,90.3 112.27,90.45 112.41,90.45 112.52,90.56 112.52,90.7 112.63,90.8 112.74,90.8 112.85,90.91 112.85,91.03 112.94,91.12 112.94,91.28 112.85,91.36 112.85,91.59 112.93,91.67 112.93,91.82 112.85,91.9 112.85,92.05 113.24,92.44 113.46,92.44 113.5,92.4 113.9,92.4 113.94,92.44 114.33,92.44 114.33,92.44 arc(114.45,92.41) 114.56,92.34 114.6,92.3 v7(114.78,92.3)
  BOTTOM w0.127: P1.B16 126.37,21.97
STXA_9N: length 39.8
  L24_SIGNAL w0.108: v9(124.92,81.37) 124.58,81.71 123.44,81.71 arc(123.22,81.76) 123.03,81.88 121.64,83.28 arc(121.51,83.46) 121.47,83.69 121.47,91.14 122.28,91.94 122.28,113.61 122.16,113.73 122.16,113.89 122.28,114.01 122.28,114.24 122.12,114.39 122.12,114.52 122.28,114.67 122.28,114.85 122.12,115 122.12,115.13 122.28,115.28 122.28,115.43 122.12,115.58 122.12,115.71 122.28,115.86 122.28,116.17 arc(122.27,116.23) 122.26,116.28 arc(122.26,116.35) 122.27,116.41 122.34,116.59 122.37,116.67 arc(122.38,116.72) 122.37,116.77 U1A.R27
  BOTTOM w0.108: v9(124.92,81.37) 125.22,81.67 125.83,81.67 C71.2
STXA_9N_FMC: length 76.4
  L24_SIGNAL w0.108: v9(130.23,21.95) 130.66,22.38 130.66,26.89 arc(130.62,27.14) 130.49,27.36 arc(130.32,27.51) 130.11,27.56 127.41,27.56 arc(127.01,27.72) 126.85,28.12 126.85,36.24 125.47,37.61 115.95,47.14 115.95,66.05 127.89,77.99 127.89,78.13 128,78.24 128.14,78.24 128.37,78.47 128.37,78.7 128.22,78.85 128.22,78.98 128.37,79.13 128.37,79.39 128.22,79.54 128.22,79.67 128.37,79.82 128.37,80.02 128.22,80.18 128.22,80.3 128.37,80.45 128.37,80.71 128.22,80.86 128.22,80.99 128.37,81.14 128.37,81.46 128.18,81.65 127.73,81.65 v9(127.46,81.37)
  BOTTOM w0.108: C71.1 126.64,81.67 127.24,81.67 127.46,81.45 v9(127.46,81.37)
  BOTTOM w0.114: v9(130.23,21.95) 130.81,21.36 P1.B13
STXA_9P: length 39.8
  L24_SIGNAL w0.108: U1A.R26 122.49,117.54 arc(122.59,117.42) 122.66,117.29 arc(122.68,117.24) 122.71,117.2 arc(122.79,116.93) 122.71,116.67 arc(122.61,116.45) 122.58,116.21 122.57,116.14 122.57,113.74 122.58,113.69 122.58,91.81 121.77,91.01 121.77,83.69 arc(121.8,83.58) 121.85,83.49 123.25,82.1 arc(123.34,82.04) 123.44,82.02 124.67,82.02 v9(124.92,82.26)
  BOTTOM w0.108: v9(124.92,82.26) 125.22,81.96 125.76,81.96 C59.2
STXA_9P_FMC: length 76.4
  L24_SIGNAL w0.108: v9(127.46,82.26) 127.77,81.95 128.3,81.95 128.67,81.58 128.67,78.35 128.58,78.26 116.25,65.93 116.25,47.26 125.77,37.74 127.12,36.39 127.15,36.29 127.15,28.12 arc(127.23,27.94) 127.41,27.86 130.11,27.86 arc(130.46,27.78) 130.74,27.55 arc(130.9,27.24) 130.96,26.89 130.96,22.5 v9(131.52,21.95)
  BOTTOM w0.108: v9(127.46,82.26) 127.46,82.17 127.24,81.96 126.72,81.96 C59.1
  BOTTOM w0.114: v9(131.52,21.95) 132.08,21.39 P1.B12
STXA_10N: length 42.6
  L24_SIGNAL w0.108: U1A.U27 120.78,116.85 120.78,116.63 120.76,116.56 120.76,115.74 120.61,115.58 120.61,115.46 120.76,115.3 120.76,115.1 120.61,114.95 120.61,114.82 120.76,114.67 120.76,114.36 120.61,114.21 120.61,114.08 120.76,113.93 120.76,113.6 120.61,113.45 120.61,113.32 120.76,113.17 120.76,112.86 120.61,112.71 120.61,112.59 120.76,112.43 120.76,112.1 120.61,111.95 120.61,111.82 120.76,111.67 120.76,111.37 120.61,111.21 120.61,111.09 120.76,110.93 120.76,110.6 120.61,110.45 120.61,110.32 120.76,110.17 120.76,109.87 120.61,109.72 120.61,109.59 120.76,109.44 120.76,109.11 120.61,108.95 120.61,108.83 120.76,108.67 120.76,108.37 120.61,108.22 120.61,108.09 120.76,107.94 120.76,106.52 120.63,106.35 arc(120.53,106.21) 120.5,106.04 120.5,81.14 arc(120.48,81.03) 120.42,80.95 118.83,79.35 arc(118.74,79.29) 118.63,79.27 117.59,79.27 v9(117.3,79.57)
  BOTTOM w0.108: v9(117.3,79.57) 117.02,79.29 116.56,79.29 C72.2
STXA_10N_FMC: length 69.5
  L24_SIGNAL w0.108: v9(114.76,79.57) 114.46,79.27 112.32,79.27 107.19,74.15 107.19,52.05 109.12,50.12 109.12,32.74 107.85,31.47 107.85,25.49 106.38,24.02 106.01,24.02 105.28,23.29 105.28,20.06 105.21,19.98 105.21,19.96 104.85,19.61 v9(104.85,19.41)
  BOTTOM w0.108: C72.1 115.7,79.5 115.44,79.25 115.08,79.25 v9(114.76,79.57)
  BOTTOM w0.114: v9(104.85,19.41) 105.41,18.85 P1.Z33
STXA_10P: length 42.6
  L24_SIGNAL w0.108: v9(117.3,78.68) 117.59,78.97 118.63,78.97 arc(118.85,79.01) 119.04,79.14 120.63,80.73 arc(120.76,80.92) 120.8,81.14 120.8,106.04 arc(120.81,106.09) 120.84,106.14 120.94,106.23 arc(121.03,106.36) 121.06,106.51 121.06,116.51 121.08,116.58 121.11,116.68 arc(121.12,116.69) 121.12,116.7 arc(121.13,116.73) 121.14,116.75 121.15,116.97 arc(121.14,117.01) 121.13,117.04 120.7,117.68 U1A.U26
  BOTTOM w0.108: C60.2 116.42,78.87 116.56,79 116.97,79 v9(117.3,78.68)
STXA_10P_FMC: length 69.4
  L24_SIGNAL w0.108: v9(114.76,78.68) 114.46,78.97 114.21,78.97 114.06,78.82 113.93,78.82 113.78,78.97 113.45,78.97 113.3,78.82 113.17,78.82 113.02,78.97 112.44,78.97 112.14,78.67 112.14,78.45 112.05,78.36 111.83,78.36 111.67,78.2 111.67,77.98 111.58,77.89 111.36,77.89 107.49,74.03 107.49,52.17 109.42,50.24 109.42,32.62 108.15,31.35 108.15,25.37 106.5,23.72 106.14,23.72 105.58,23.17 105.58,20 v9(106.07,19.51)
  BOTTOM w0.108: v9(114.76,78.68) 115.04,78.96 115.44,78.96 115.54,78.87 C60.1
  BOTTOM w0.114: 106.68,18.85 106.68,18.9 v9(106.07,19.51)
  BOTTOM w0.133: 106.68,18.85 P1.Z32
STXA_11N: length 30.5
  TOP w0.133: C73.2 116.37,90.13 arc(116.44,90.08) 116.52,90.07 116.94,90.07 arc(117.02,90.08) 117.09,90.13 v7(117.3,90.34)
  L3_SIGNAL w0.108: v7(121.5,115.33) 121.5,115.41 121.31,115.6 121.15,115.6 121.07,115.51 121.07,115.08 121.44,114.7 121.44,112.34 121.24,112.14 121.24,111.99 121.44,111.79 121.44,111.43 121.3,111.29 121.3,111.14 121.44,111 121.44,110.57 121.16,110.28 121.16,110.13 121.44,109.85 121.44,109.55 121.44,109.54 121.44,101.29 119.67,99.51 119.67,91.87 119.6,91.81 119.6,91.66 119.67,91.59 119.67,91.16 119.54,91.03 119.47,91.03 119.36,90.92 119.36,90.85 118.62,90.11 117.53,90.11 v7(117.3,90.34)
STXA_11N_FMC: length 80.1
  TOP w0.133: v7(114.76,90.34) 114.96,90.14 arc(115.02,90.1) 115.1,90.08 115.57,90.08 arc(115.63,90.1) 115.68,90.13 C73.1
  L3_SIGNAL w0.108: 127.63,20.7 128.13,21.2 128.13,37.36 127.56,37.94 127.56,37.96 112.8,52.72 arc(112.73,52.8) 112.67,52.9 112.55,53.18 112.42,53.47 arc(112.32,53.76) 112.29,54.06 112.29,89.04 113.3,90.05 114.46,90.05 v7(114.76,90.34)
  BOTTOM w0.127: P1.A15 127.63,20.7
STXA_11P: length 30.5
  TOP w0.133: v7(117.3,89.45) 117.07,89.68 arc(117.01,89.72) 116.92,89.74 116.55,89.74 arc(116.47,89.72) 116.4,89.68 C61.2
  L3_SIGNAL w0.108: v7(121.5,116.13) 121.5,115.89 121.87,115.52 121.87,115.51 121.89,115.49 121.89,115.17 121.74,115.03 121.74,109.43 121.74,109.42 121.74,101.16 119.96,99.39 119.96,99.27 119.96,91.03 118.75,89.81 117.66,89.81 v7(117.3,89.45)
STXA_11P_FMC: length 80.1
  TOP w0.133: C61.1 115.76,89.57 115.64,89.69 arc(115.58,89.73) 115.5,89.75 115.14,89.75 arc(115.06,89.73) 114.99,89.69 v7(114.76,89.45)
  L3_SIGNAL w0.108: 128.91,20.7 128.5,21.11 arc(128.47,21.15) 128.46,21.21 128.46,37.42 arc(128.45,37.48) 128.42,37.52 113.01,52.93 arc(112.97,52.97) 112.95,53.02 112.69,53.59 arc(112.62,53.82) 112.59,54.06 112.59,86.06 112.63,86.09 112.63,86.25 112.59,86.28 112.59,86.51 112.64,86.56 112.64,86.72 112.59,86.77 112.59,86.97 112.64,87.02 112.64,87.17 112.59,87.22 112.59,87.43 112.64,87.48 112.64,87.63 112.59,87.68 112.59,87.81 112.67,87.89 112.67,88.11 112.59,88.19 112.59,88.34 112.67,88.42 112.67,88.67 112.59,88.75 112.59,88.92 112.73,89.05 112.83,89.05 112.94,89.16 112.94,89.27 113.08,89.41 113.15,89.41 113.26,89.52 113.26,89.59 113.42,89.75 113.56,89.75 113.63,89.68 113.78,89.68 113.84,89.75 114.05,89.75 114.08,89.71 114.24,89.71 114.27,89.75 114.46,89.75 v7(114.76,89.45)
  BOTTOM w0.127: P1.A14 128.91,20.7
STXB_0N: length 41.5
  L24_SIGNAL w0.108: v9(135.08,81.37) 134.74,81.71 134.11,81.71 arc(133.89,81.76) 133.7,81.88 131.69,83.89 arc(131.57,84.08) 131.52,84.3 131.52,86.12 arc(131.5,86.22) 131.44,86.31 128.92,88.83 arc(128.8,89.02) 128.75,89.24 128.75,105.44 127.08,107.11 127.08,116.21 arc(127.06,116.29) 127.01,116.37 126.76,116.61 arc(126.66,116.77) 126.62,116.97 arc(126.64,117.06) 126.69,117.14 126.69,117.14 arc(126.84,117.22) 126.99,117.17 126.99,117.16 arc(127.07,117.06) U1A.J27
  BOTTOM w0.108: C13.2 135.83,81.71 135.26,81.71 135.08,81.52 v9(135.08,81.37)
STXB_0N_FMC: length 53.5
  L24_SIGNAL w0.108: v9(137.62,81.37) 137.9,81.65 138.18,81.65 138.37,81.46 138.58,81.46 138.78,81.65 139.45,81.65 139.62,81.48 139.62,81.29 139.73,81.18 139.93,81.18 140.08,81.03 140.08,80.83 140.19,80.72 140.39,80.72 140.53,80.58 140.53,80.42 140.63,80.31 140.79,80.31 143.38,77.72 143.38,35.18 v9(142.9,34.7)
  BOTTOM w0.108: C13.1 136.71,81.7 137.34,81.7 137.62,81.42 v9(137.62,81.37)
  BOTTOM w0.127: P1.M3 143.51,34.09 v9(142.9,34.7)
STXB_0P: length 41.5
  L24_SIGNAL w0.108: U1A.J26 127.39,117.44 arc(127.41,117.42) 127.43,117.39 127.49,117.29 arc(127.52,117.23) 127.53,117.17 arc(127.54,117.14) 127.55,117.11 arc(127.59,116.89) 127.51,116.67 arc(127.49,116.63) 127.46,116.59 127.37,116.35 127.37,115.86 127.48,115.75 127.48,115.54 127.37,115.43 127.37,115.07 127.53,114.92 127.53,114.8 127.37,114.64 127.37,114.52 127.53,114.36 127.53,114.24 127.37,114.08 127.37,113.91 127.53,113.75 127.53,113.63 127.37,113.47 127.37,113.3 127.53,113.14 127.53,113.02 127.37,112.86 127.37,107.3 127.38,107.24 129.06,105.56 129.06,89.24 arc(129.08,89.14) 129.14,89.05 131.66,86.53 arc(131.78,86.34) 131.83,86.12 131.83,84.3 arc(131.85,84.2) 131.91,84.11 133.92,82.1 arc(134.01,82.04) 134.11,82.02 134.83,82.02 v9(135.08,82.26)
  BOTTOM w0.108: C1.2 135.83,81.99 135.29,81.99 135.08,82.21 v9(135.08,82.26)
STXB_0P_FMC: length 53.5
  L24_SIGNAL w0.108: v9(137.62,82.26) 137.9,81.98 139.59,81.98 143.65,77.92 143.65,77.88 143.68,77.85 143.68,35.13 v9(144.12,34.7)
  BOTTOM w0.108: C1.1 136.54,82.15 136.7,81.99 137.35,81.99 v9(137.62,82.26)
  BOTTOM w0.114: P1.M2 v9(144.12,34.7)
STXB_1N: length 6.8
  TOP w0.133: U1A.J31 127.1,113.85 arc(127.15,113.97) 127.26,114.02 arc(127.39,113.96) 127.44,113.84 127.44,113.59 arc(127.42,113.49) 127.37,113.42 127.15,113.2 arc(127.09,113.12) 127.04,113.04 arc(127.02,112.98) 127.03,112.91 127.03,108.16 arc(127.06,108) C14.2
STXB_1N_FMC: length 95.2
  TOP w0.133: v9(130.01,73.1) 129.65,72.74 129.46,72.74 129.33,72.87 129.33,74.29 130.36,75.32 130.36,102.11 127.01,105.45 127.01,107.19 C14.1
  L24_SIGNAL w0.108: v9(130.01,73.1) 129.65,72.74 129.15,72.74 128.86,72.45 128.86,71.12 140.9,59.08 140.9,22.51 v9(140.4,22.01)
  BOTTOM w0.114: P1.B5 140.97,21.44 v9(140.4,22.01)
STXB_1P: length 6.8
  TOP w0.133: U1A.J30 126.92,114.29 126.83,114.18 arc(126.74,113.98) 126.71,113.77 126.69,113.06 126.69,113.05 126.69,108.16 arc(126.66,108) C2.2
STXB_1P_FMC: length 95.2
  TOP w0.133: C2.1 126.7,107.19 126.7,105.33 130.05,101.98 130.05,75.45 129.02,74.42 129.02,72.75 129.33,72.43 129.65,72.43 v9(130.01,72.07)
  L24_SIGNAL w0.108: v9(130.01,72.07) 129.65,72.44 129.27,72.44 129.16,72.32 129.16,71.25 141.2,59.21 141.2,22.53 141.54,22.19 v9(141.54,22.03)
  BOTTOM w0.114: v9(141.54,22.03) P1.B4
STXB_2N: length 25.4
  TOP w0.133: v7(124.92,94.84) 125.21,95.14 125.74,95.14 125.92,94.96 C15.2
  L3_SIGNAL w0.108: v7(127.9,115.33) 127.95,115.38 127.95,115.53 127.79,115.69 127.64,115.69 127.53,115.58 127.53,115.58 127.47,115.51 127.47,115.15 128.04,114.57 128.04,101.13 123.83,96.92 123.83,95.47 124.22,95.08 124.68,95.08 v7(124.92,94.84)
STXB_2N_FMC: length 85.6
  TOP w0.133: C15.1 126.62,95.12 127.18,95.12 v7(127.46,94.84)
  L3_SIGNAL w0.108: 142.88,20.7 143.21,20.7 143.36,20.85 143.36,26.37 144.68,27.69 144.68,29.17 143.36,30.49 143.36,43.46 132.54,54.27 132.54,90.81 131.11,92.24 130.97,92.24 130.86,92.35 130.86,92.48 130.73,92.61 130.58,92.61 130.45,92.74 130.45,92.88 130.27,93.07 130.16,93.07 130.05,93.17 130.05,93.26 129.94,93.37 129.88,93.37 129.77,93.48 129.77,93.57 129.66,93.68 129.6,93.68 129.49,93.78 129.49,93.86 129.37,93.98 129.27,93.98 129.16,94.09 129.16,94.18 129.06,94.28 128.91,94.28 128.8,94.39 128.8,94.51 128.7,94.61 128.61,94.61 128.5,94.72 128.5,94.84 128.3,95.04 arc(128.2,95.11) 128.08,95.13 127.88,95.13 arc(127.76,95.11) 127.65,95.04 v7(127.46,94.84)
  BOTTOM w0.127: P1.A3 142.88,20.7
STXB_2P: length 25.4
  TOP w0.133: v7(124.92,95.73) 125.14,95.5 125.83,95.5 C3.2
  L3_SIGNAL w0.108: v7(124.92,95.73) 124.59,95.4 124.44,95.4 124.13,95.71 124.13,96.8 128.4,101.07 128.4,109.47 128.47,109.55 128.47,109.7 128.4,109.78 128.4,109.93 128.46,109.99 128.46,110.15 128.4,110.21 128.4,110.41 128.47,110.49 128.47,110.64 128.4,110.72 128.4,110.92 128.5,111.02 128.5,111.18 128.4,111.28 128.4,111.48 128.49,111.57 128.49,111.72 128.4,111.81 128.4,111.96 128.47,112.04 128.47,112.19 128.4,112.27 128.4,112.47 128.56,112.64 128.56,112.79 128.42,112.93 128.42,113.08 128.55,113.21 128.55,113.36 128.4,113.51 128.4,113.74 128.51,113.86 128.51,114.01 128.35,114.17 128.35,114.33 128.49,114.46 128.49,114.62 128.3,114.81 128.3,115.61 127.9,116.01 v7(127.9,116.13)
STXB_2P_FMC: length 85.6
  TOP w0.133: v7(127.46,95.73) 127.16,95.43 126.62,95.43 C3.1
  L3_SIGNAL w0.108: v7(127.46,95.73) 127.65,95.53 arc(127.76,95.46) 127.88,95.44 128.25,95.44 arc(128.33,95.42) 128.4,95.37 132.84,90.93 132.84,54.48 143.66,43.67 143.66,30.61 144.98,29.29 144.98,27.57 143.66,26.24 143.66,22.9 143.67,22.89 143.67,20.83 143.81,20.7 144.15,20.7
  BOTTOM w0.127: P1.A2 144.15,20.7
STXB_3N: length 28.1
  TOP w0.133: C16.2 125.92,92.27 125.78,92.41 125.18,92.41 v7(124.92,92.15)
  L3_SIGNAL w0.108: v7(126.3,115.33) 126.3,115.41 126.11,115.6 125.95,115.6 125.87,115.51 125.87,115.08 126.24,114.71 126.24,106.37 126.23,106.1 126.23,101.15 122.69,97.61 122.69,93.72 123.98,92.43 124.5,92.43 arc(124.62,92.41) 124.73,92.34 v7(124.92,92.15)
STXB_3N_FMC: length 77.4
  TOP w0.133: v7(127.46,92.15) 127.17,92.43 126.62,92.43 C16.1
  L3_SIGNAL w0.108: v7(127.46,92.15) 127.65,92.34 127.81,92.44 127.99,92.44 128.07,92.35 128.24,92.35 128.32,92.44 128.57,92.44 128.75,92.25 128.75,92.11 128.86,92 129.01,92 129.16,91.85 129.16,91.7 129.27,91.59 129.41,91.59 129.57,91.44 129.57,91.33 129.67,91.22 129.78,91.22 129.96,91.05 129.96,90.94 130.07,90.83 130.18,90.83 130.31,90.69 130.31,90.57 130.42,90.46 130.54,90.46 130.68,90.32 130.68,90.23 130.79,90.12 130.9,90.12 131.15,89.86 131.15,89.7 131.09,89.64 131.09,89.48 131.16,89.41 131.16,51.93 138.26,44.83 138.26,23.46 arc(138.2,23.3) 138.05,23.24 137.79,23.24
  BOTTOM w0.127: P1.C7 137.79,23.24
STXB_3P: length 28.1
  TOP w0.133: C4.2 125.87,92.85 125.1,92.85 v7(124.92,93.04)
  L3_SIGNAL w0.108: v7(126.3,116.13) 126.3,115.84 126.42,115.71 126.46,115.71 126.69,115.49 126.69,115.17 126.66,115.15 126.66,114.75 126.54,114.62 126.54,114.45 126.67,114.32 126.67,114.17 126.55,114.06 126.55,113.9 126.65,113.8 126.65,113.65 126.54,113.53 126.54,113.36 126.67,113.23 126.67,113.08 126.54,112.95 126.54,112.75 126.68,112.61 126.68,112.46 126.54,112.31 126.54,112.12 126.62,112.03 126.62,111.72 126.54,111.63 126.54,106.37 126.53,106.1 126.53,101.03 122.99,97.49 122.99,93.84 124.1,92.73 124.54,92.73 arc(124.61,92.74) 124.66,92.78 v7(124.92,93.04)
STXB_3P_FMC: length 77.4
  TOP w0.133: C4.1 126.62,92.74 127.16,92.74 v7(127.46,93.04)
  L3_SIGNAL w0.108: v7(127.46,93.04) 127.65,92.84 arc(127.77,92.76) 127.9,92.74 127.9,92.74 128.69,92.74 129.22,92.21 129.23,92.21 131.46,89.97 131.46,52.05 138.56,44.95 138.56,41.66 138.57,41.65 138.57,23.46 arc(138.63,23.3) 138.79,23.24 139.06,23.24
  BOTTOM w0.127: P1.C6 139.06,23.24
STXB_4N: length 33.6
  L24_SIGNAL w0.108: v9(124.92,86.76) 124.59,87.09 124.38,87.09 123.86,87.61 123.86,89.16 123.86,89.53 124.36,90.04 124.36,90.05 125.48,91.16 125.48,99.85 125.48,99.85 125.48,116.21 arc(125.47,116.24) 125.47,116.26 125.18,116.56 arc(125.17,116.56) 125.17,116.56 125.15,116.59 125.15,116.6 125.01,116.73 arc(125,116.85) 125.01,116.96 arc(125.03,117.06) 125.09,117.14 125.09,117.14 arc(125.24,117.2) 125.39,117.17 125.39,117.16 arc(125.47,117.06) U1A.L27
  BOTTOM w0.108: v9(124.92,86.76) 125.16,87 125.76,87 125.89,86.87 C17.2
STXB_4N_FMC: length 65.1
  L24_SIGNAL w0.108: v9(127.46,86.76) 127.76,87.06 128.28,87.06 128.44,86.9 128.56,86.9 128.71,87.06 129.18,87.06 129.32,86.92 129.32,86.71 129.41,86.62 129.62,86.62 129.75,86.49 129.75,86.28 129.84,86.19 130.05,86.19 130.28,85.96 130.28,85.76 130.12,85.61 130.12,85.48 130.28,85.33 130.28,85.05 130.12,84.9 130.12,84.77 130.28,84.62 130.28,76.09 125.18,70.99 125.18,66.3 138.28,53.19 138.28,35.21 v9(137.79,34.72)
  BOTTOM w0.108: C17.1 126.62,86.87 126.75,87 127.22,87 v9(127.46,86.76)
  BOTTOM w0.114: v9(137.79,34.72) 138.43,34.09 P1.M7
STXB_4P: length 33.6
  L24_SIGNAL w0.108: U1A.L26 125.79,117.44 arc(125.81,117.42) 125.83,117.39 125.89,117.29 arc(125.92,117.23) 125.93,117.17 arc(125.94,117.14) 125.95,117.11 arc(125.99,116.89) 125.91,116.67 arc(125.89,116.63) 125.87,116.59 arc(125.8,116.39) 125.77,116.18 125.77,99.85 125.77,99.84 125.77,91.04 125.72,90.98 125.69,90.94 124.71,89.97 124.71,89.69 124.59,89.56 124.31,89.56 124.15,89.41 124.15,89.28 124.16,89.28 124.16,89.1 124.36,88.9 124.36,88.67 124.16,88.47 124.16,88.29 124.28,88.16 124.28,88.01 124.16,87.88 124.16,87.73 124.5,87.39 124.65,87.39 v9(124.92,87.65)
  BOTTOM w0.108: C5.2 125.76,87.29 125.27,87.29 v9(124.92,87.65)
STXB_4P_FMC: length 65.1
  L24_SIGNAL w0.108: v9(138.94,34.72) 138.58,35.08 138.58,53.32 125.48,66.42 125.48,70.87 130.58,75.97 130.58,86.09 129.31,87.36 127.75,87.36 v9(127.46,87.65)
  BOTTOM w0.108: C5.1 126.72,87.29 126.77,87.29 126.78,87.28 127.09,87.28 v9(127.46,87.65)
  BOTTOM w0.114: P1.M6 139.62,34.04 v9(138.94,34.72)
STXB_5N: length 6.8
  TOP w0.133: U1A.L31 125.5,113.85 arc(125.55,113.97) 125.66,114.02 arc(125.79,113.96) 125.84,113.84 125.84,113.59 arc(125.82,113.49) 125.77,113.42 125.55,113.2 arc(125.49,113.12) 125.44,113.04 arc(125.42,112.98) 125.43,112.91 125.43,108.16 arc(125.46,108) C18.2
STXB_5N_FMC: length 97.1
  TOP w0.133: C18.1 125.55,107.23 125.44,107.12 125.44,104.16 128.59,101.01 128.59,70.31 128.15,69.88 127.69,69.88 127.44,69.63 v9(127.44,69.43)
  L24_SIGNAL w0.108: v9(137.79,20.7) 138.33,21.24 138.33,25.17 139.54,26.38 139.54,28.71 138.76,29.49 138.76,33.06 139.54,33.83 139.54,57.44 128.78,68.2 128.78,69.45 128.44,69.79 127.8,69.79 v9(127.44,69.43)
  BOTTOM w0.114: P1.A7 v9(137.79,20.7)
STXB_5P: length 6.8
  TOP w0.133: U1A.L30 125.32,114.29 125.23,114.18 arc(125.14,113.98) 125.11,113.77 125.09,113.06 125.09,113.05 125.09,108.16 arc(125.06,108) C6.2
STXB_5P_FMC: length 97.1
  TOP w0.133: C6.1 125.13,107.17 125.13,104.03 128.28,100.88 128.28,71.71 127.99,71.42 127.99,71.12 128.28,70.83 128.28,70.44 128.02,70.19 127.7,70.19 v9(127.44,70.45)
  L24_SIGNAL w0.108: v9(139.04,20.73) 138.63,21.14 138.63,25.05 139.84,26.26 139.84,28.84 139.06,29.61 139.06,32.93 139.84,33.71 139.84,57.56 129.08,68.32 129.08,69.58 128.57,70.09 127.8,70.09 v9(127.44,70.45)
  BOTTOM w0.114: P1.A6 v9(139.04,20.73)
STXB_6N: length 47.3
  BOTTOM w0.127: 122.1,91.9 122.12,91.92 122.12,91.92 122.12,91.93 122.12,92.1 122.13,92.1 122.13,98.69 122.13,98.81 124.79,101.48 124.79,101.48 ; 124.46,116.55 124.46,118.29 v4(124.7,118.53)
  BOTTOM w0.133: 124.46,116.55 124.79,116.22 124.79,115.88 124.69,115.78 124.69,115.59 124.79,115.49 124.79,115.29 124.74,115.23 124.74,115.04 124.79,114.99 124.79,114.73 124.67,114.61 124.67,114.42 124.79,114.3 124.79,114.1 124.7,114 124.7,113.81 124.79,113.72 124.79,113.53 124.74,113.48 124.74,113.29 124.79,113.23 124.79,101.48 ; 122.1,91.9 122.09,91.89 122.09,77.32 122.69,76.72 122.69,76.71 122.83,76.58 122.83,76.58 123.13,76.29 125.73,76.29 C19.2
STXB_6N_FMC: length 47.5
  BOTTOM w0.133: C19.1 126.62,76.26 126.91,76.26 127.06,76.11 127.19,76.11 127.34,76.26 127.52,76.26 127.67,76.11 127.8,76.11 127.95,76.26 128.16,76.26 128.28,76.14 128.47,76.14 128.59,76.26 128.97,76.26 129.25,75.98 129.25,75.88 129.34,75.79 129.44,75.79 133.86,71.37 133.86,34.42 133.48,34.04 P1.M11
STXB_6P: length 47.3
  BOTTOM w0.127: 125.1,116.53 124.84,116.79 124.84,117.9 125.09,118.15 125.09,118.94 v4(124.7,119.33) ; 122.43,91.8 122.43,98.69 125.1,101.36
  BOTTOM w0.133: 122.43,91.8 122.43,77.42 123.26,76.6 125.78,76.6 C7.2 ; 125.1,116.53 125.1,101.36
STXB_6P_FMC: length 47.5
  BOTTOM w0.133: C7.1 126.62,76.57 129.1,76.57 134.17,71.5 134.17,71.44 134.18,71.43 134.18,34.47 P1.M10
STXB_7N: length 6.8
  TOP w0.127: U1A.N31 123.9,113.85 arc(123.95,113.97) 124.06,114.02 arc(124.19,113.96) 124.24,113.84 124.24,113.59 arc(124.22,113.49) 124.17,113.42 123.95,113.2 arc(123.89,113.12) 123.84,113.04 arc(123.82,112.98) 123.83,112.91
  TOP w0.133: 123.83,112.91 123.83,108.16 arc(123.86,108) C20.2
STXB_7N_FMC: length 96.5
  TOP w0.133: v9(120.52,56.59) 120.78,56.85 121.46,56.85 122.22,57.61 122.22,60.88 123.81,62.47 123.81,106.22 124.05,106.46 124.05,106.6 123.81,106.84 123.81,107.19 C20.1
  L24_SIGNAL w0.108: v9(120.52,56.59) 120.78,56.85 122.56,56.85 133.17,46.24 133.17,21.13 v9(132.74,20.7)
  BOTTOM w0.114: v9(132.74,20.7) 133.35,20.09 P1.A11
STXB_7P: length 6.8
  TOP w0.133: U1A.N30 123.72,114.29 123.63,114.18 arc(123.54,113.98) 123.51,113.77 123.49,113.06 123.49,113.05 123.49,108.16 arc(123.46,108) C8.2
STXB_7P_FMC: length 96.5
  TOP w0.133: v9(120.47,57.43) 120.55,57.43 120.82,57.16 121.33,57.16 121.91,57.74 121.91,61.01 123.5,62.6 123.5,107.19 C8.1
  L24_SIGNAL w0.108: v9(134.06,20.7) 133.96,20.7 133.47,21.19 133.47,46.06 133.5,46.09 133.5,46.33 122.69,57.14 120.76,57.14 v9(120.47,57.43)
  BOTTOM w0.114: v9(134.06,20.7) 134.62,20.14 P1.A10
STXB_8N: length 31.2
  TOP w0.133: v7(124.92,89.45) 125.2,89.74 125.75,89.74 C21.2
  L3_SIGNAL w0.108: v7(124.92,89.45) 124.57,89.8 123.52,89.8 121.75,91.57 121.75,97.96 124.64,100.85 124.64,114.71 124.27,115.08 124.27,115.51 124.35,115.6 124.51,115.6 124.7,115.41 v7(124.7,115.33)
STXB_8N_FMC: length 79.3
  TOP w0.133: v7(127.46,89.45) 127.25,89.66 126.55,89.66 C21.1
  L3_SIGNAL w0.108: 135.25,21.97 135.53,21.97 arc(135.69,22.03) 135.75,22.19 135.75,30.61 137.31,32.17 137.31,41.84 126.03,53.13 125.94,53.22 125.81,53.34 125.81,77.47 129.93,81.58 129.93,85.7 129.86,85.76 129.86,85.92 129.93,85.98 129.93,86.16 129.88,86.21 129.88,86.36 129.93,86.41 129.93,86.64 129.84,86.73 129.84,86.88 129.93,86.97 129.93,87.25 129.85,87.32 129.85,87.48 129.93,87.55 129.93,87.74 129.83,87.84 129.75,87.84 129.64,87.95 129.64,88.09 129.48,88.25 129.32,88.25 129.18,88.39 129.18,88.54 129.01,88.72 128.86,88.72 128.75,88.83 128.75,88.98 128.61,89.12 128.48,89.12 128.37,89.22 128.37,89.36 128.06,89.67 arc(127.99,89.72) 127.91,89.74 arc(127.89,89.74) 127.86,89.74 arc(127.75,89.72) 127.65,89.65 v7(127.46,89.45)
  BOTTOM w0.127: P1.B9 135.25,21.97
STXB_8P: length 31.1
  TOP w0.133: C9.2 125.81,90.09 125.17,90.09 v7(124.92,90.34)
  L3_SIGNAL w0.108: v7(124.7,116.13) 124.7,115.89 125.12,115.47 125.12,115.24 125.09,115.21 125.09,115.17 124.94,115.02 124.94,114.88 124.99,114.83 124.99,114.68 124.94,114.63 124.94,114.45 125.07,114.32 125.07,114.17 124.95,114.06 124.95,113.9 125.05,113.8 125.05,113.65 124.94,113.53 124.94,113.36 125.07,113.23 125.07,113.08 124.94,112.95 124.94,112.65 125.03,112.56 125.03,112.41 124.94,112.31 124.94,112.09 125.01,112.01 125.01,111.86 124.94,111.79 124.94,100.73 122.05,97.84 122.05,91.69 123.65,90.09 124.67,90.09 v7(124.92,90.34)
STXB_8P_FMC: length 79.3
  TOP w0.133: v7(127.46,90.34) 127.16,90.04 126.62,90.04 C9.1
  L3_SIGNAL w0.108: 136.53,21.97 136.27,21.97 arc(136.12,22.03) 136.06,22.19 136.05,22.19 136.05,30.48 137.61,32.05 137.61,41.97 137.27,42.31 126.15,53.43 arc(126.12,53.47) 126.11,53.52 126.11,77.34 130.23,81.46 130.23,87.93 128.27,89.88 arc(128.12,89.99) 127.95,90.04 arc(127.75,90.1) 127.58,90.22 v7(127.46,90.34)
  BOTTOM w0.127: P1.B8 136.53,21.97
STXB_9N: length 6.8
  TOP w0.133: U1A.R31 122.3,113.85 arc(122.35,113.97) 122.46,114.02 arc(122.59,113.96) 122.64,113.84 122.64,113.59 arc(122.62,113.49) 122.57,113.42 122.35,113.2 arc(122.29,113.12) 122.24,113.04 arc(122.22,112.98) 122.23,112.91 122.23,108.16 arc(122.26,108) C22.2
STXB_9N_FMC: length 97.2
  TOP w0.133: v7(119.76,51.9) 119.42,51.56 119.13,51.56 119,51.7 119,59.56 122.22,62.78 122.22,107.2 C22.1
  L3_SIGNAL w0.108: v7(119.76,51.9) 119.42,51.56 119.08,51.56 118.7,51.18 118.7,49.15 129.19,38.66 129.19,32.39 130.66,30.92 130.66,19.83 130.26,19.43 130.18,19.43
  BOTTOM w0.127: P1.Z13 130.18,19.43
STXB_9P: length 6.8
  TOP w0.133: U1A.R30 122.12,114.29 122.03,114.18 arc(121.94,113.98) 121.91,113.77 121.89,113.06 121.89,113.05 121.89,108.16 arc(121.86,108) C10.2
STXB_9P_FMC: length 97.2
  TOP w0.133: v7(119.76,50.91) 119.42,51.25 119,51.25 118.67,51.59 118.67,59.67 121.9,62.91 121.9,107.19 C10.1
  L3_SIGNAL w0.108: 131.44,19.43 130.96,19.92 130.96,31.05 129.49,32.51 129.49,38.79 119,49.28 119,51.05 119.2,51.26 119.42,51.26 v7(119.76,50.91)
  BOTTOM w0.127: P1.Z12 131.44,19.43
STXB_10N: length 36.8
  L24_SIGNAL w0.108: U1A.N27 123.99,116.73 124,116.71 arc(123.91,116.46) 123.88,116.18 123.88,115.96 123.72,115.81 123.72,115.68 123.88,115.53 123.88,115.38 123.72,115.23 123.72,115.1 123.88,114.95 123.88,114.77 123.79,114.69 123.79,114.56 123.88,114.48 123.88,90.96 122.43,89.51 122.43,85.67 arc(122.47,85.45) 122.6,85.26 123.31,84.55 arc(123.5,84.42) 123.72,84.38 124.6,84.38 v9(124.92,84.06)
  BOTTOM w0.108: v9(124.92,84.06) 124.92,84.2 125.13,84.41 125.76,84.41 C23.2
STXB_10N_FMC: length 63.9
  L24_SIGNAL w0.108: v9(127.46,84.06) 127.77,84.38 128.02,84.38 128.09,84.3 128.24,84.3 128.32,84.38 128.52,84.38 128.6,84.3 128.75,84.3 128.83,84.38 128.95,84.38 129.26,84.07 129.26,83.9 129.18,83.82 129.18,83.59 129.26,83.52 129.26,83.31 129.15,83.21 129.15,83.06 129.23,82.98 129.23,82.83 129.18,82.77 129.18,82.58 129.24,82.52 129.24,82.3 129.18,82.25 129.18,82.09 129.24,82.04 129.24,81.84 129.13,81.74 129.13,81.58 129.24,81.48 129.24,81.28 129.15,81.19 129.15,81.04 129.24,80.95 129.24,80.75 129.15,80.66 129.15,80.51 129.24,80.42 129.24,80.14 129.15,80.05 129.15,79.9 129.24,79.81 129.24,79.58 129.17,79.51 129.17,79.36 129.24,79.3 129.24,77.67 117.09,65.53 117.09,49.36 128.02,38.44 128.02,34.92 v9(127.71,34.62)
  BOTTOM w0.108: v9(127.46,84.06) 127.46,84.18 127.24,84.39 126.7,84.39 C23.1
  BOTTOM w0.114: v9(127.71,34.62) 128.27,34.06 P1.M15
STXB_10P: length 36.8
  L24_SIGNAL w0.108: U1A.N26 124.19,117.44 arc(124.21,117.42) 124.23,117.39 124.29,117.29 arc(124.32,117.23) 124.33,117.17 arc(124.34,117.14) 124.35,117.11 arc(124.39,116.89) 124.31,116.67 arc(124.29,116.63) 124.27,116.59 arc(124.2,116.39) 124.17,116.18 124.17,90.96 124.18,90.96 124.18,90.84 arc(124.17,90.78) 124.14,90.74 122.73,89.33 122.73,85.67 arc(122.75,85.57) 122.81,85.48 123.53,84.76 arc(123.62,84.7) 123.72,84.68 124.65,84.68 v9(124.92,84.95)
  BOTTOM w0.108: v9(124.92,84.95) 125.16,84.71 125.84,84.71 C11.2
STXB_10P_FMC: length 64
  L24_SIGNAL w0.108: v9(127.46,84.95) 127.73,84.68 129.08,84.68 129.55,84.2 129.55,77.57 117.39,65.41 117.39,49.49 128.31,38.56 128.31,34.91 128.5,34.72 v9(128.78,34.72)
  BOTTOM w0.108: C11.1 126.64,84.71 127.21,84.71 v9(127.46,84.95)
  BOTTOM w0.114: P1.M14 129.46,34.04 v9(128.78,34.72)
STXB_11N: length 34.6
  TOP w0.133: 116.39,87.42 116.48,87.33 117,87.33 117.04,87.37 117.16,87.37 117.3,87.51 v7(117.3,87.65) ; 116.39,87.42 116.39,87.42 ; 116.39,87.42 arc(116.39,87.42) 116.39,87.42 ; 116.39,87.42 C24.2
  L3_SIGNAL w0.108: v7(123.1,115.33) 123.1,115.41 122.91,115.6 122.75,115.6 122.67,115.51 122.67,115.08 123.04,114.71 123.04,113.13 122.9,112.99 122.9,112.84 123.02,112.71 123.02,112.56 122.81,112.34 122.81,112.19 123,112 123,111.85 122.78,111.63 122.78,111.4 123.01,111.18 123.01,101.44 120.71,99.13 120.71,88.36 119.7,87.36 117.66,87.36 117.51,87.44 v7(117.3,87.65)
STXB_11N_FMC: length 82.4
  TOP w0.133: C24.1 115.68,87.44 arc(115.63,87.4) 115.57,87.39 115.1,87.39 arc(115.02,87.41) 114.96,87.45 v7(114.76,87.65)
  L3_SIGNAL w0.108: 132.72,18.16 133.01,18.16 arc(133.14,18.2) 133.22,18.31 133.22,18.32 arc(133.23,18.35) 133.23,18.38 133.23,19.1 133.23,19.11 133.23,35.31 131.15,37.39 131.15,42.55 114.73,58.96 114.73,67.22 116.77,69.26 116.77,71.5 113.69,74.58 113.69,87.05 113.93,87.29 arc(114,87.33) 114.09,87.35 114.41,87.35 arc(114.46,87.36) 114.5,87.39 v7(114.76,87.65)
  BOTTOM w0.127: P1.Y11 132.72,18.16
STXB_11P: length 34.6
  TOP w0.133: C12.2 116.33,86.91 arc(116.43,86.97) 116.54,87 116.93,87 arc(117.05,86.97) 117.15,86.91 v7(117.3,86.76)
  L3_SIGNAL w0.108: v7(117.3,86.76) 117.49,86.96 arc(117.6,87.03) 117.72,87.05 117.73,87.06 117.93,87.06 118.02,86.97 118.21,86.97 118.3,87.06 119.82,87.06 121.01,88.24 121.01,99.01 123.34,101.34 123.34,115.02 123.49,115.17 123.49,115.49 123.42,115.56 123.42,115.62 123.1,115.94 v7(123.1,116.13)
STXB_11P_FMC: length 82.4
  TOP w0.133: v7(114.76,86.76) 114.99,86.99 arc(115.06,87.04) 115.14,87.05 115.5,87.05 arc(115.58,87.04) 115.64,86.99 115.76,86.88 C12.1
  L3_SIGNAL w0.108: v7(114.76,86.76) 114.56,86.96 arc(114.45,87.03) 114.33,87.05 114.23,87.05 arc(114.18,87.05) 114.13,87.03 arc(114.09,87.02) 114.07,87 113.99,86.92 113.99,85.55 114.18,85.36 114.18,85.2 113.99,85.01 113.99,84.73 114.17,84.55 114.17,84.35 113.99,84.17 113.99,83.85 114.12,83.71 114.12,83.49 113.99,83.36 113.99,74.7 117.07,71.62 117.07,69.14 115.03,67.1 115.03,59.09 131.44,42.67 131.44,37.51 133.44,35.51 133.52,35.51 133.52,19.17 133.53,19.16 133.53,18.38 arc(133.53,18.3) 133.51,18.23 133.51,18.23 arc(133.62,18.16) 133.75,18.16 133.75,18.16 133.99,18.16
  BOTTOM w0.127: P1.Y10 133.99,18.16
SYNC_B: length 1.3
  BOTTOM w0.191: R159.1 146.5,276.62 146.46,276.58 v1(146.46,276.01)
SYNC_IN: length 9.4
  TOP w0.191: v1(9.8,222.23) 10.8,222.23 11.1,222.53 R7.1 10.13,224.23 R5.2
  BOTTOM w0.191: R8.1 8.33,220.76 v1(9.8,222.23) 10.16,222.59 U1B.6
SYNCINB_A0_N: length 154.5
  TOP w0.133: v4(87.66,95.5) 87.29,95.14 87.29,94.82 85.46,92.99 84.79,92.99 84.33,92.53 84.33,91.9 v4(84.82,91.41) ; U12.8 98.31,7.93 v4(97.99,8.25)
  L5_MIXED w0.108: v4(87.66,95.5) 87.38,95.78 87.38,101.22 96.72,110.57 110.04,110.57 117.1,117.63 117.1,122.69 117.27,122.86 117.34,122.93 117.79,122.93 117.9,122.93 v4(118.3,123.33)
  L24_SIGNAL w0.108: v4(97.99,8.25) 97.99,7.09 98.1,6.98 98.45,6.98 99.12,7.65 99.12,8.63 98.68,9.07 94.74,9.07 87.18,16.63 87.18,52.4 87.66,52.88 87.66,78.12 91.32,81.78 91.32,85.72 85.38,91.66 85.07,91.66 v4(84.82,91.41)
SYNCINB_A0_N_FMC: length 71.5
  TOP w0.133: U12.7 v4(98.71,8.29)
  L3_SIGNAL w0.108: v4(132.83,12.27) 132.63,12.07 132.63,11.83 132.94,11.52 132.94,10.99 134.96,8.97 134.96,2.41 134.55,2.01 101.85,2.01 100.36,3.51 100.36,6.17 99.42,7.11 98.84,7.11 98.73,7.22 98.73,8.27 v4(98.71,8.29)
  L22_MIXED w0.102: v4(132.72,29.59) 133.23,29.08 133.23,12.67 v4(132.83,12.27)
  BOTTOM w0.127: P1.H11 v4(132.72,29.59)
SYNCINB_A0_N_GPIO_FMC: length 31
  TOP w0.133: v4(96.32,7.45) 96.95,7.45 97.14,7.26 U12.9
  L22_MIXED w0.102: v4(103.61,30.91) 103.97,30.55 103.97,26.94 103.98,26.94 103.98,25.88 103.98,25.88 103.98,12.56 98.45,7.04 97.26,7.04 97,7.29 96.48,7.29 v4(96.32,7.45)
  BOTTOM w0.133: P1.J34 104.14,30.38 v4(103.61,30.91)
SYNCINB_A0_P: length 157.5
  TOP w0.133: v4(86.61,95.5) 86.98,95.14 86.98,94.95 85.33,93.3 84.66,93.3 84.02,92.66 84.02,91.66 v4(83.77,91.41) ; v4(97.94,5.41) 98.31,5.78 U12.2
  L5_MIXED w0.108: v4(86.61,95.5) 86.89,95.78 86.89,101.42 96.52,111.06 109.84,111.06 116.31,117.52 116.31,119.96 116.3,119.97 116.3,120.29 116.31,120.3 116.31,120.76 116.3,120.77 116.3,121.09 116.31,121.1 116.31,121.56 116.3,121.57 116.3,121.89 116.31,121.9 116.31,122.36 116.3,122.37 116.3,122.69 116.31,122.7 116.31,123.16 116.3,123.17 116.3,123.49 116.54,123.73 117.1,123.73 v4(117.5,123.33)
  L24_SIGNAL w0.108: v4(97.94,5.41) 97.99,5.41 97.99,6.58 98.1,6.68 98.57,6.68 99.42,7.53 99.42,8.75 98.8,9.37 94.87,9.37 87.48,16.75 87.48,52.27 87.96,52.76 87.96,78 91.62,81.65 91.62,85.84 85.44,92.02 84.61,92.02 84,91.41 v4(83.77,91.41)
SYNCINB_A0_P_FMC: length 72.4
  TOP w0.133: U12.3 v4(98.71,5.43)
  L3_SIGNAL w0.108: v4(98.71,5.43) 98.62,5.52 98.62,6.71 98.73,6.81 99.29,6.81 100.06,6.05 100.06,3.38 101.73,1.71 134.68,1.71 135.25,2.29 135.25,9.1 133.24,11.11 133.24,11.64 v4(133.87,12.27)
  L22_MIXED w0.102: v4(133.87,12.27) 133.47,12.67 133.47,29.08 v4(133.99,29.59)
  BOTTOM w0.127: P1.H10 v4(133.99,29.59)
SYNCINB_A0_P_GPIO_FMC: length 31.4
  TOP w0.133: U12.1 97.08,6.46 97.04,6.41 96.83,6.41 96.82,6.4 v4(96.32,6.4)
  L22_MIXED w0.102: v4(96.32,6.4) 96.38,6.46 97.01,6.46 97.34,6.79 98.55,6.79 104.22,12.46 104.22,25.77 104.23,25.77 104.23,25.85 104.23,25.86 104.23,26.26 104.23,26.26 104.23,26.34 104.22,26.34 104.22,28.28 104.24,28.29 104.24,30.33 v4(104.78,30.86)
  BOTTOM w0.133: P1.J33 v4(104.78,30.86)
SYNCINB_A1_N: length 266
  TOP w0.133: v4(133.93,7.06) 133.71,6.84 U13.8 ; U35.35 19.13,77.47 v4(23.27,77.47)
  L5_MIXED w0.108: v4(118.3,122.53) 118.7,122.13 118.7,115.83 110.52,107.65 95.86,107.65 88.6,100.38 88.6,96.82 88.75,96.67 90.09,96.67 90.73,96.04 90.73,95.32 v4(91.36,94.69) 91.36,90.65 89.08,88.37 74.21,88.37 73.75,88.82 67.4,88.82 67.19,89.03 32.44,89.03 23.6,80.19 23.6,77.8 v4(23.27,77.47)
  L24_SIGNAL w0.108: v4(133.93,7.06) 132.71,7.06 132.6,7.17 132.6,7.45 132.25,7.8 131.06,7.8 126.01,12.85 97.28,12.85 94.16,15.98 94.16,21.39 97.41,24.64 97.41,35.37 93.57,39.21 93.57,49.04 91.76,50.85 91.76,77.27 93.57,79.07 93.57,84 94.86,85.29 95.28,85.29 96.11,86.13 96.11,86.17 96.13,86.19 96.13,88.44 96.11,88.46 96.11,88.54 90.98,93.68 90.98,94.32 v4(91.36,94.69)
SYNCINB_A1_N_FMC: length 41.8
  TOP w0.133: U13.7 v4(134.03,6.44)
  L22_MIXED w0.102: v4(111.12,25.78) 111.69,25.22 111.69,13.74 114.09,11.33 126.44,11.33 130,7.78 130,5.47 130.25,5.21 131.1,5.21 132.32,6.44 v4(134.03,6.44)
  BOTTOM w0.127: P1.E28 v4(111.12,25.78)
SYNCINB_A1_N_GPIO_FMC: length 35
  TOP w0.133: U13.9 132.91,8.02 v4(133.22,8.33)
  L22_MIXED w0.102: v4(133.22,8.33) 133.05,8.33 132.3,7.58 131.38,7.58 126.77,12.2 125.37,12.2 124.39,13.18 124.39,22.17 125.83,23.61 125.83,26.21 124.89,27.15 120.07,27.15 118.9,28.32 v4(118.75,28.32)
  BOTTOM w0.127: P1.G22 v4(118.75,28.32)
SYNCINB_A1_P: length 182.5
  TOP w0.133: U13.2 131.66,6.84 131.57,6.93 131.38,6.93 131.25,7.06 v4(130.96,7.06)
  L5_MIXED w0.108: v4(89.98,94.69) 90.17,94.69 90.38,94.91 90.38,94.97 90.24,95.12 90.24,95.83 89.89,96.18 88.54,96.18 88.11,96.62 88.11,100.58 95.66,108.13 110.12,108.13 117.89,115.91 117.89,116.76 117.9,116.77 117.9,117.51 117.89,117.52 117.89,117.56 117.9,117.57 117.9,117.73 117.9,117.73 117.9,122.16 117.53,122.53 v4(117.5,122.53)
  L24_SIGNAL w0.108: v4(89.98,94.69) 90.31,94.69 90.68,94.32 90.68,93.47 95.83,88.32 95.83,86.31 95.12,85.6 94.74,85.6 93.27,84.13 93.27,79.2 91.47,77.39 91.47,50.72 93.27,48.92 93.27,39.09 97.11,35.25 97.11,24.76 93.86,21.51 93.86,16.1 93.86,15.85 97.16,12.55 125.89,12.55 130.94,7.5 132.12,7.5 132.3,7.32 132.3,7.17 132.19,7.06 v4(130.96,7.06)
SYNCINB_A1_P_FMC: length 38.6
  TOP w0.133: U13.3 v4(131.07,6.44)
  L22_MIXED w0.102: v4(112.4,25.78) 111.94,25.32 111.94,13.84 114.19,11.58 126.54,11.58 130.24,7.88 130.24,5.57 130.35,5.47 130.51,5.47 130.51,5.46 130.85,5.46 131.07,5.68 v4(131.07,6.44)
  BOTTOM w0.127: P1.E27 v4(112.4,25.78)
SYNCINB_A1_P_GPIO_FMC: length 33.1
  TOP w0.133: U13.1 132.11,8.02 v4(131.85,8.28)
  L22_MIXED w0.102: v4(120.02,28.32) 119.64,27.94 119.64,27.93 120.17,27.4 124.78,27.4 124.78,27.4 124.99,27.4 125.05,27.35 125.08,27.35 126.09,26.34 126.09,23.59 126.08,23.59 126.08,23.51 125.94,23.36 125.93,23.36 124.63,22.07 124.63,13.29 125.48,12.45 126.87,12.45 131.48,7.83 131.75,7.83 131.95,8.04 131.95,8.18 v4(131.85,8.28)
  BOTTOM w0.127: P1.G21 v4(120.02,28.32)
SYNCINB_AB_SEL_0_FMC: length 44.3
  TOP w0.191: 91.49,8.38 91.49,9.5 R398.1 v4(91.24,10.62) ; 91.49,8.38 91.19,8.38 U14.5 ; 91.49,8.38 91.49,7.77 U14.4 91.79,7.98 93.22,7.98 97.05,4.14 100.08,4.14 100.53,4.59 100.53,6.4 ; 100.53,6.4 R396.1 ; 100.53,6.4 99.82,6.4 ; U12.4 99.31,6.4 99.82,6.4 ; U12.5 99.82,6.86 99.82,6.4
  L3_SIGNAL w0.114: v4(98.53,32.18) 97.71,31.37 97.71,17.09 v4(91.24,10.62)
  BOTTOM w0.191: 99.06,31.5 98.53,32.03 v4(98.53,32.18)
SYNCINB_AB_SEL_1_FMC: length 64.1
  TOP w0.191: 104.5,7.26 104.5,6.86 U15.5 ; 104.5,7.26 103.87,7.26 R399.1 103.71,7.42 v4(103.71,8.28) ; 104.5,7.26 U15.4 ; v4(131.27,4.63) R397.1 132.11,5.31 ; 132.11,5.31 132.11,5.84 U13.4 ; 132.11,5.31 132.49,5.31 132.49,5.84 U13.5
  L3_SIGNAL w0.114: v4(100.97,30.86) 100.38,30.28 100.38,17.22 103.71,13.89 v4(103.71,8.28)
  L5_MIXED w0.114: v4(103.71,8.28) 103.23,7.8 103.23,5.43 104.93,3.73 112.45,3.73 113,4.29 124.48,4.29 124.56,4.38 124.97,4.38 125.05,4.29 127.25,4.29 128.15,5.19 130.71,5.19 v4(131.27,4.63)
  BOTTOM w0.191: P1.J36 v4(100.97,30.86)
SYNCINB_B0_N: length 207.3
  TOP w0.133: U14.8 90.54,6.67 90.17,6.3 90.17,4.06 90.88,3.35 90.88,2.46 92.02,1.31 143.46,1.31 150.44,8.3 150.44,36.43 149.87,37 149.87,53.14 154.46,57.73 154.46,63.41 154.88,63.83 v4(154.88,63.99)
  L3_SIGNAL w0.108: v4(154.88,63.99) 154.88,63.31 154.95,63.24 155.47,63.24 157.17,64.95 157.17,67.7 157.22,67.75 157.22,68.09 157.17,68.14 157.17,100.36 139.4,118.13 128.51,118.13 127.5,119.14 127.5,119.15 127.5,121.89 127.51,121.9 127.51,122.36 127.5,122.37 127.5,122.7 127.27,122.93 126.92,122.93 126.87,122.99 126.64,122.99 v7(126.3,123.33)
SYNCINB_B0_N_FMC: length 61.6
  TOP w0.133: U14.7 v4(89.65,7.17)
  L22_MIXED w0.102: v4(130.29,12.24) 130.69,12.64 130.69,27.81 v4(130.18,28.32)
  BOTTOM w0.127: P1.G13 v4(130.18,28.32)
  BOTTOM w0.133: v4(89.65,7.17) 90.77,7.17 91.07,7.47 91.07,7.96 91.52,8.41 91.52,8.42 93.19,10.09 128.68,10.09 130.29,11.7 v4(130.29,12.24)
SYNCINB_B0_N_GPIO_FMC: length 38.6
  TOP w0.133: U14.9 90.79,5.72 90.74,5.67 90.74,5.3 91.02,5.01 91.02,4.85 v4(90.67,4.5)
  L22_MIXED w0.102: v4(102.24,32.13) 102.72,31.65 102.72,14.56 99.16,11 94.18,11 91.19,8.01 91.19,6.18 90.79,5.78 90.79,4.61 v4(90.67,4.5)
  BOTTOM w0.133: 102.87,31.5 v4(102.24,32.13)
SYNCINB_B0_P: length 208.5
  TOP w0.133: v4(153.83,63.99) 153.83,63.83 154.15,63.52 154.15,57.86 149.56,53.27 149.56,36.87 150.13,36.3 150.13,8.43 143.33,1.63 92.15,1.63 91.19,2.58 91.19,3.35 91.89,4.05 91.9,4.05 92.17,4.31 92.17,4.33 92.28,4.44 92.28,6.23 91.84,6.67 U14.2
  L3_SIGNAL w0.108: v7(127.1,123.33) 127.1,123.37 127.46,123.73 128.07,123.73 128.3,123.49 128.3,119.97 128.19,119.86 128.19,119.08 128.34,118.93 139.12,118.93 157.47,100.58 157.47,68.26 157.52,68.21 157.52,64.87 155.59,62.94 154.6,62.94 154.21,63.33 154.21,63.46 153.83,63.83 v4(153.83,63.99)
SYNCINB_B0_P_FMC: length 60.9
  TOP w0.133: U14.3 v4(92.62,7.17)
  L22_MIXED w0.102: v4(131.33,12.24) 130.93,12.64 130.93,27.81 v4(131.44,28.32)
  BOTTOM w0.127: P1.G12 v4(131.44,28.32)
  BOTTOM w0.133: v4(131.33,12.24) 130.29,11.2 130.23,11.2 128.81,9.78 93.32,9.78 91.83,8.29 91.83,7.73 92.1,7.47 92.32,7.47 v4(92.62,7.17)
SYNCINB_B0_P_GPIO_FMC: length 38.5
  TOP w0.133: U14.1 91.59,5.72 91.63,5.67 91.63,5.3 91.39,5.06 91.39,4.83 v4(91.72,4.5)
  L22_MIXED w0.102: v4(91.72,4.5) 91.58,4.63 91.58,5.8 91.44,5.94 91.44,7.9 94.29,10.75 99.26,10.75 102.97,14.46 102.97,31.59 v4(103.5,32.13)
  BOTTOM w0.133: 104.14,31.5 v4(103.5,32.13)
SYNCINB_B1_N: length 198.8
  TOP w0.133: U15.8 v4(106.08,5.3)
  L3_SIGNAL w0.108: v4(162.42,56.52) 162.05,56.14 162.05,55.91 161.76,55.63 155.1,55.63 152.07,58.65 152.07,74.52 155.45,77.9 155.45,99.69 138.35,116.8 134.17,116.8 133.91,116.53 133.33,116.53 133.33,116.53 132.07,116.53 132.07,116.53 131.73,116.53 131.73,116.53 130.47,116.53 130.47,116.53 130.13,116.53 130.13,116.53 129.06,116.53 125.9,119.69 125.9,122.13 v7(126.3,122.53)
  L24_SIGNAL w0.108: v4(162.42,56.52) 162.03,56.12 162.03,44.2 155.47,37.64 155.47,14.96 142.49,1.98 110.93,1.98 106.34,6.56 106.19,6.56 106.08,6.45 v4(106.08,5.3)
SYNCINB_B1_N_FMC: length 32.8
  TOP w0.133: v4(105.36,5.33) 105.68,5.65 U15.7
  L22_MIXED w0.102: v4(105.36,5.33) 105.36,6.48 104.84,6.99 103.07,6.99 102.96,7.1 102.96,7.1 102.92,7.13 102.92,7.14 102.44,7.63 102.44,9.38 105.31,12.25 105.31,29.99 106.43,31.1 106.43,31.75 v4(106.04,32.13)
  BOTTOM w0.133: 106.68,31.5 v4(106.04,32.13)
SYNCINB_B1_N_GPIO_FMC: length 29.7
  TOP w0.133: U15.9 107.88,6.46 108.21,6.79 108.21,7.76 108.24,7.78 108.24,8.1 114.24,14.1 115.28,14.1 115.41,13.97 115.41,13.73 v4(115.05,13.36)
  L22_MIXED w0.102: v4(114.94,28.32) 115.42,27.84 115.42,13.73 v4(115.05,13.36)
  BOTTOM w0.127: P1.G25 v4(114.94,28.32)
SYNCINB_B1_P: length 197.3
  TOP w0.133: U15.2 v4(106.08,8.52)
  L3_SIGNAL w0.108: v7(127.1,122.53) 126.7,122.13 126.7,119.4 128.77,117.33 133.85,117.33 134.08,117.1 138.48,117.1 155.75,99.83 155.75,77.78 152.37,74.41 152.37,58.77 155.22,55.92 161.64,55.92 161.75,56.03 161.75,56.14 v4(161.37,56.52)
  L24_SIGNAL w0.108: v4(106.08,8.52) 106.08,7.08 106.3,6.86 106.46,6.86 111.05,2.27 142.36,2.27 155.17,15.08 155.17,37.77 161.73,44.32 161.73,56.16 v4(161.37,56.52)
SYNCINB_B1_P_FMC: length 32.1
  TOP w0.133: U15.3 105.68,8.11 v4(105.31,8.48)
  L22_MIXED w0.102: v4(107.31,32.13) 106.67,31.49 106.67,31 105.56,29.89 105.56,12.15 102.69,9.27 102.69,7.73 103.18,7.24 104.83,7.24 105.31,7.72 v4(105.31,8.48)
  BOTTOM w0.127: 107.95,31.5 v4(107.31,32.13)
SYNCINB_B1_P_GPIO_FMC: length 29.3
  TOP w0.133: U15.1 107,7.26 107.79,8.05 107.79,8.13 114.08,14.41 115.41,14.41 115.73,14.1 115.73,13.73 v4(116.09,13.36)
  L22_MIXED w0.102: v4(116.21,28.32) 115.67,27.78 115.67,14.33 115.67,14.32 115.67,14.24 115.67,14.24 115.67,13.78 v4(116.09,13.36)
  BOTTOM w0.127: P1.G24 v4(116.21,28.32)
SYNCOUTB_A0_N: length 163
  TOP w0.133: U16.8 116.53,7.82 v4(116.1,8.25)
  L5_MIXED w0.108: v4(115.9,121.73) 115.51,121.34 115.51,121.1 115.5,121.09 115.5,118.74 114.88,118.13 107.94,118.13 102.13,112.32 96.67,112.32 86.06,101.7 86.06,94.97 86.61,94.42 86.61,92.84 v4(86.89,92.56)
  L24_SIGNAL w0.108: v4(86.89,92.56) 86.51,92.18 86.51,92.08 92.26,86.33 92.26,80.75 88.91,77.4 88.91,49.14 91.34,46.71 91.34,34.06 92.57,32.83 92.57,24.45 91.41,23.3 91.41,15.21 96.59,10.03 113.75,10.03 115.41,8.36 115.41,7.56 115.96,7.01 116.1,7.01 116.13,7.04 116.13,8.22 v4(116.1,8.25)
SYNCOUTB_A0_N_FMC: length 42.1
  TOP w0.133: v4(117.4,8.38) 116.93,7.91 U16.7
  L3_SIGNAL w0.108: v4(131.15,11.39) 131.45,11.09 131.45,10.27 130.21,9.03 130.21,3.23 129.92,2.95 118.82,2.95 118.34,3.43 118.34,6.78 118.01,7.11 117.63,7.11 117.4,7.35 v4(117.4,8.38)
  L22_MIXED w0.102: v4(131.15,11.39) 131.23,11.46 131.32,11.46 131.96,12.1 131.96,24 v4(131.44,24.51)
  BOTTOM w0.127: P1.D12 v4(131.44,24.51)
SYNCOUTB_A0_N_GPIO_FMC: length 27.6
  TOP w0.133: U16.9 115.79,7.5 v4(114.71,7.5)
  L22_MIXED w0.102: v4(107.31,25.82) 107.75,25.38 107.75,14.08 113.1,8.74 116.17,8.74 116.56,8.35 116.56,8.16 115.9,7.5 v4(114.71,7.5)
  BOTTOM w0.127: P1.E31 107.31,25.78 v4(107.31,25.82)
SYNCOUTB_A0_P: length 163.5
  TOP w0.133: v4(116.05,5.44) 116.26,5.44 116.53,5.7 U16.2
  L5_MIXED w0.108: v4(85.84,92.56) 86.12,92.84 86.12,94.22 85.57,94.77 85.57,101.9 96.47,112.81 101.93,112.81 108.06,118.93 114.46,118.93 114.7,119.17 114.7,121.09 114.73,121.12 115.03,121.42 115.03,121.55 115.11,121.64 115.11,121.72 v4(115.1,121.73)
  L24_SIGNAL w0.108: v4(116.05,5.44) 116.05,5.92 116.13,5.99 116.13,6.61 116.02,6.71 115.83,6.71 115.11,7.44 115.11,8.24 113.62,9.73 96.47,9.73 91.11,15.09 91.11,23.42 92.27,24.58 92.27,32.71 91.04,33.94 91.04,46.59 88.61,49.02 88.61,77.53 91.96,80.87 91.96,86.21 86.21,91.95 86.21,92.18 v4(85.84,92.56)
SYNCOUTB_A0_P_FMC: length 42.6
  TOP w0.133: U16.3 v4(116.93,5.5)
  L3_SIGNAL w0.108: v4(132.12,11.46) 131.75,11.09 131.75,10.15 130.51,8.91 130.51,3.11 130.04,2.65 118.7,2.65 118.04,3.31 118.04,6.65 117.88,6.81 117.53,6.81 116.93,6.21 v4(116.93,5.5)
  L22_MIXED w0.102: v4(132.12,11.46) 132.41,11.75 132.41,11.99 132.2,12.2 132.2,24 v4(132.72,24.51)
  BOTTOM w0.127: P1.D11 v4(132.72,24.51)
SYNCOUTB_A0_P_GPIO_FMC: length 28.4
  TOP w0.133: U16.1 115.82,6.45 v4(114.71,6.45)
  L22_MIXED w0.102: v4(114.71,6.45) 115.21,6.45 116.81,8.05 116.81,8.52 116.34,8.99 116.19,8.99 116.19,8.99 113.21,8.99 108,14.2 108,25.2 v4(108.59,25.78)
  BOTTOM w0.127: P1.E30 v4(108.59,25.78)
SYNCOUTB_A1_N: length 390.7
  TOP w0.133: P2.14 51.44,42.39 v2(54.1,42.39) ; U35.37 v4(24.92,78.43) ; v4(129.21,7.11) 128.97,6.87 U17.8
  L3_SIGNAL w0.108: v2(54.1,42.39) 41.35,42.39 38.66,45.08 38.66,90.09 40.77,92.2 v4(41.18,92.2)
  L5_MIXED w0.108: v4(41.18,92.2) 41.58,91.8 41.58,90.78 42.06,90.3 45.54,90.3 46.48,91.24 74.27,91.24 97.98,114.95 103.14,114.95 107.92,119.73 113.03,119.73 113.9,120.61 113.9,121.89 114.14,122.13 115.4,122.13 115.42,122.15 115.54,122.15 115.9,122.5 v4(115.9,122.53) ; v4(24.92,78.43) 24.92,78.42 23.72,77.22 23.72,74.32 25.4,72.64 40.87,72.64 45.64,77.41 45.64,81.31 48.77,84.43 52.3,84.43 54.36,86.48 59.84,86.48 61.33,84.99 67.44,84.99 68.25,85.79 94.61,85.79 95.22,86.4 v4(95.22,86.41)
  L24_SIGNAL w0.108: v4(95.22,86.41) 94.82,86.41 92.86,84.46 92.86,79.91 90.35,77.39 90.35,58 90.6,57.75 90.6,48.99 92.33,47.27 92.33,35.83 96.19,31.97 96.19,26.57 92.91,23.29 92.91,15.39 97.57,10.74 126.21,10.74 127.87,9.07 127.87,8.45 v4(129.21,7.11)
  BOTTOM w0.133: v4(41.18,92.2) 41.55,91.83 41.55,91.64 28.87,78.97 25.46,78.97 v4(24.92,78.43)
SYNCOUTB_A1_N_FMC: length 41.8
  TOP w0.133: U17.7 v4(129.2,6.47)
  L22_MIXED w0.102: v4(129.2,6.47) 129.15,6.52 128.08,6.52 127.97,6.41 127.97,5.17 127.72,4.93 125.96,4.93 125.51,5.38 125.51,7.63 125.81,7.93 125.81,9.37 124.63,10.54 113.68,10.54 110.39,13.84 110.39,26.52 v4(109.85,27.05)
  BOTTOM w0.127: P1.F29 v4(109.85,27.05)
SYNCOUTB_A1_N_GPIO_FMC: length 37.2
  TOP w0.133: U17.9 128.14,7.61 128.1,7.64 128.1,7.71 128.18,7.79 128.18,8.16 127.51,8.84 127.51,10.48 122.61,15.37 113.97,15.37 113.96,15.37 113.77,15.37 113.06,14.66 v4(112.64,14.66)
  L22_MIXED w0.102: v4(113.66,29.59) 114.05,29.21 114.05,29.06 112.93,27.94 112.93,19.42 112.87,19.37 112.87,18.84 112.93,18.78 112.93,14.94 v4(112.64,14.66)
  BOTTOM w0.127: P1.H26 v4(113.66,29.59)
SYNCOUTB_A1_P: length 320
  TOP w0.133: v4(126.24,7.11) 126.48,6.87 U17.2 ; U35.36 v4(25.6,77.93)
  L5_MIXED w0.108: v4(42.23,92.2) 41.93,91.9 41.93,91.13 42.27,90.79 45.34,90.79 46.28,91.73 74.07,91.73 97.78,115.44 102.58,115.44 107.67,120.53 112.58,120.53 113.13,121.08 113.13,122.34 113.1,122.37 113.1,122.69 113.68,123.27 114.5,123.27 ; v4(25.6,77.93) 25.06,77.39 24.59,77.39 24.21,77.01 24.21,74.52 25.6,73.13 40.67,73.13 45.15,77.62 45.15,81.51 48.57,84.92 52.1,84.92 54.15,86.97 60.04,86.97 61.54,85.48 67.24,85.48 68.05,86.28 94.06,86.28 94.17,86.39 v4(94.17,86.41)
  L5_MIXED w0.121: v4(115.1,122.53) 115.1,122.67 114.5,123.27
  L24_SIGNAL w0.108: v4(126.24,7.11) 127.57,8.45 127.57,8.95 126.09,10.44 97.44,10.44 92.61,15.27 92.61,23.42 95.89,26.69 95.89,31.85 92.03,35.71 92.03,47.15 90.31,48.87 90.31,57.62 90.05,57.88 90.05,77.52 92.56,80.03 92.56,84.8 v4(94.17,86.41)
  BOTTOM w0.133: v4(25.6,77.93) 26.33,78.66 29,78.66 41.86,91.52 41.86,91.83 v4(42.23,92.2)
SYNCOUTB_A1_P_FMC: length 40.5
  TOP w0.133: U17.3 v4(126.27,6.47)
  L22_MIXED w0.102: v4(126.27,6.47) 127.41,6.47 127.66,6.22 127.66,5.49 127.39,5.22 126.1,5.22 125.76,5.56 125.76,7.53 126.05,7.83 126.05,9.37 126.06,9.37 126.06,9.39 126.06,9.39 126.06,9.47 125.91,9.62 125.91,9.62 124.73,10.79 114.13,10.79 110.64,14.27 110.64,26.57 v4(111.12,27.05)
  BOTTOM w0.127: P1.F28 v4(111.12,27.05)
SYNCOUTB_A1_P_GPIO_FMC: length 35.4
  TOP w0.133: v4(113.69,14.66) 114.1,15.06 122.48,15.06 127.2,10.35 127.2,8.05 127.29,7.96 127.29,7.79 127.34,7.74 U17.1
  L22_MIXED w0.102: v4(114.94,29.59) 114.94,29.54 114.58,29.18 114.54,29.18 114.31,28.95 114.29,28.95 113.18,27.83 113.18,19.32 113.12,19.26 113.12,18.94 113.18,18.88 113.18,15.17 v4(113.69,14.66)
  BOTTOM w0.127: P1.H25 v4(114.94,29.59)
SYNCOUTB_AB_SEL_0_FMC: length 50.5
  TOP w0.191: U16.5 118.01,6.96 118.21,6.76 ; 118.21,6.76 118.01,6.56 U16.4 ; 118.21,6.76 119.41,6.76 119.43,6.73 ; R400.1 119.43,7.59 119.43,6.73 ; 119.43,6.73 119.43,4.5 119.02,4.09 113.92,4.09 v1(112.57,5.44) 112.34,5.66 112.34,6.38 R402.1 111.81,6.48 ; 111.81,6.48 111.23,6.48 U18.4 ; 111.81,6.48 111.81,6.88 U18.5
  L3_SIGNAL w0.114: v1(112.57,5.44) 112.57,7.04 111.43,8.18 111.43,8.69 101.52,18.59 101.52,31.37 101.24,31.65 100.48,31.65 v4(99.69,30.86)
  BOTTOM w0.191: P1.J37 v4(99.69,30.86)
SYNCOUTB_AB_SEL_1_FMC: length 42.1
  TOP w0.191: 127.33,5.87 126.67,5.87 126.44,5.64 126.27,5.81 R403.1 v1(124.92,5.81) ; 127.33,5.87 U17.4 ; 127.33,5.87 127.33,5.36 ; U19.5 124.94,6.27 124.94,5.83 v1(124.92,5.81) ; U19.4 124.22,5.84 124.69,5.84 124.69,5.81 v1(124.92,5.81) ; U17.5 127.74,5.36 127.33,5.36 ; 127.33,5.36 R401.1
  L3_SIGNAL w0.114: v4(104.78,25.78) 104.06,25.07 104.06,19.18 111.66,11.58 121.06,11.58 125.01,7.63 125.01,5.9 v1(124.92,5.81)
  BOTTOM w0.191: P1.E33 v4(104.78,25.78)
SYNCOUTB_B0_N: length 182.1
  TOP w0.133: U18.8 110.23,8.04 v4(109.96,8.31)
  L3_SIGNAL w0.108: v4(159.17,57.89) 159.54,58.26 159.54,58.37 159.44,58.48 159.08,58.48 158.54,59.02 158.54,100.6 139.53,119.61 134.04,119.61 133.92,119.73 131.28,119.73 130.91,119.35 129.31,119.35 129.1,119.56 129.1,121.31 128.7,121.72 v7(128.7,121.73)
  L24_SIGNAL w0.108: v4(109.96,8.31) 110.01,8.31 110.12,8.2 110.12,7.09 110.22,6.98 112.13,6.98 116.05,3.07 140.62,3.07 149.66,12.11 149.66,12.23 149.66,12.23 149.66,24.8 150,25.15 150,26.41 149.66,26.76 149.66,31.11 150.31,31.77 150.31,36.65 149.66,37.31 149.66,49.96 152.1,52.4 153.55,52.4 158.94,57.79 159.07,57.79 v4(159.17,57.89)
SYNCOUTB_B0_N_FMC: length 48.3
  TOP w0.133: U18.7 v4(110.63,8.26) ; v4(127.75,13.03) 128.09,12.68 128.09,11.27 129.86,9.5 129.86,3.71 129.18,3.03 111.79,3.03 111.66,3.16 111.66,4.19 v4(111.95,4.48)
  L3_SIGNAL w0.108: v4(111.95,4.48) 111.66,4.77 111.66,6.79 111.37,7.09 110.85,7.09 110.74,7.19 110.74,8.15 v4(110.63,8.26)
  L22_MIXED w0.102: v4(127.75,13.03) 128.15,13.43 128.15,24 v4(127.63,24.51)
  BOTTOM w0.127: P1.D15 v4(127.63,24.51)
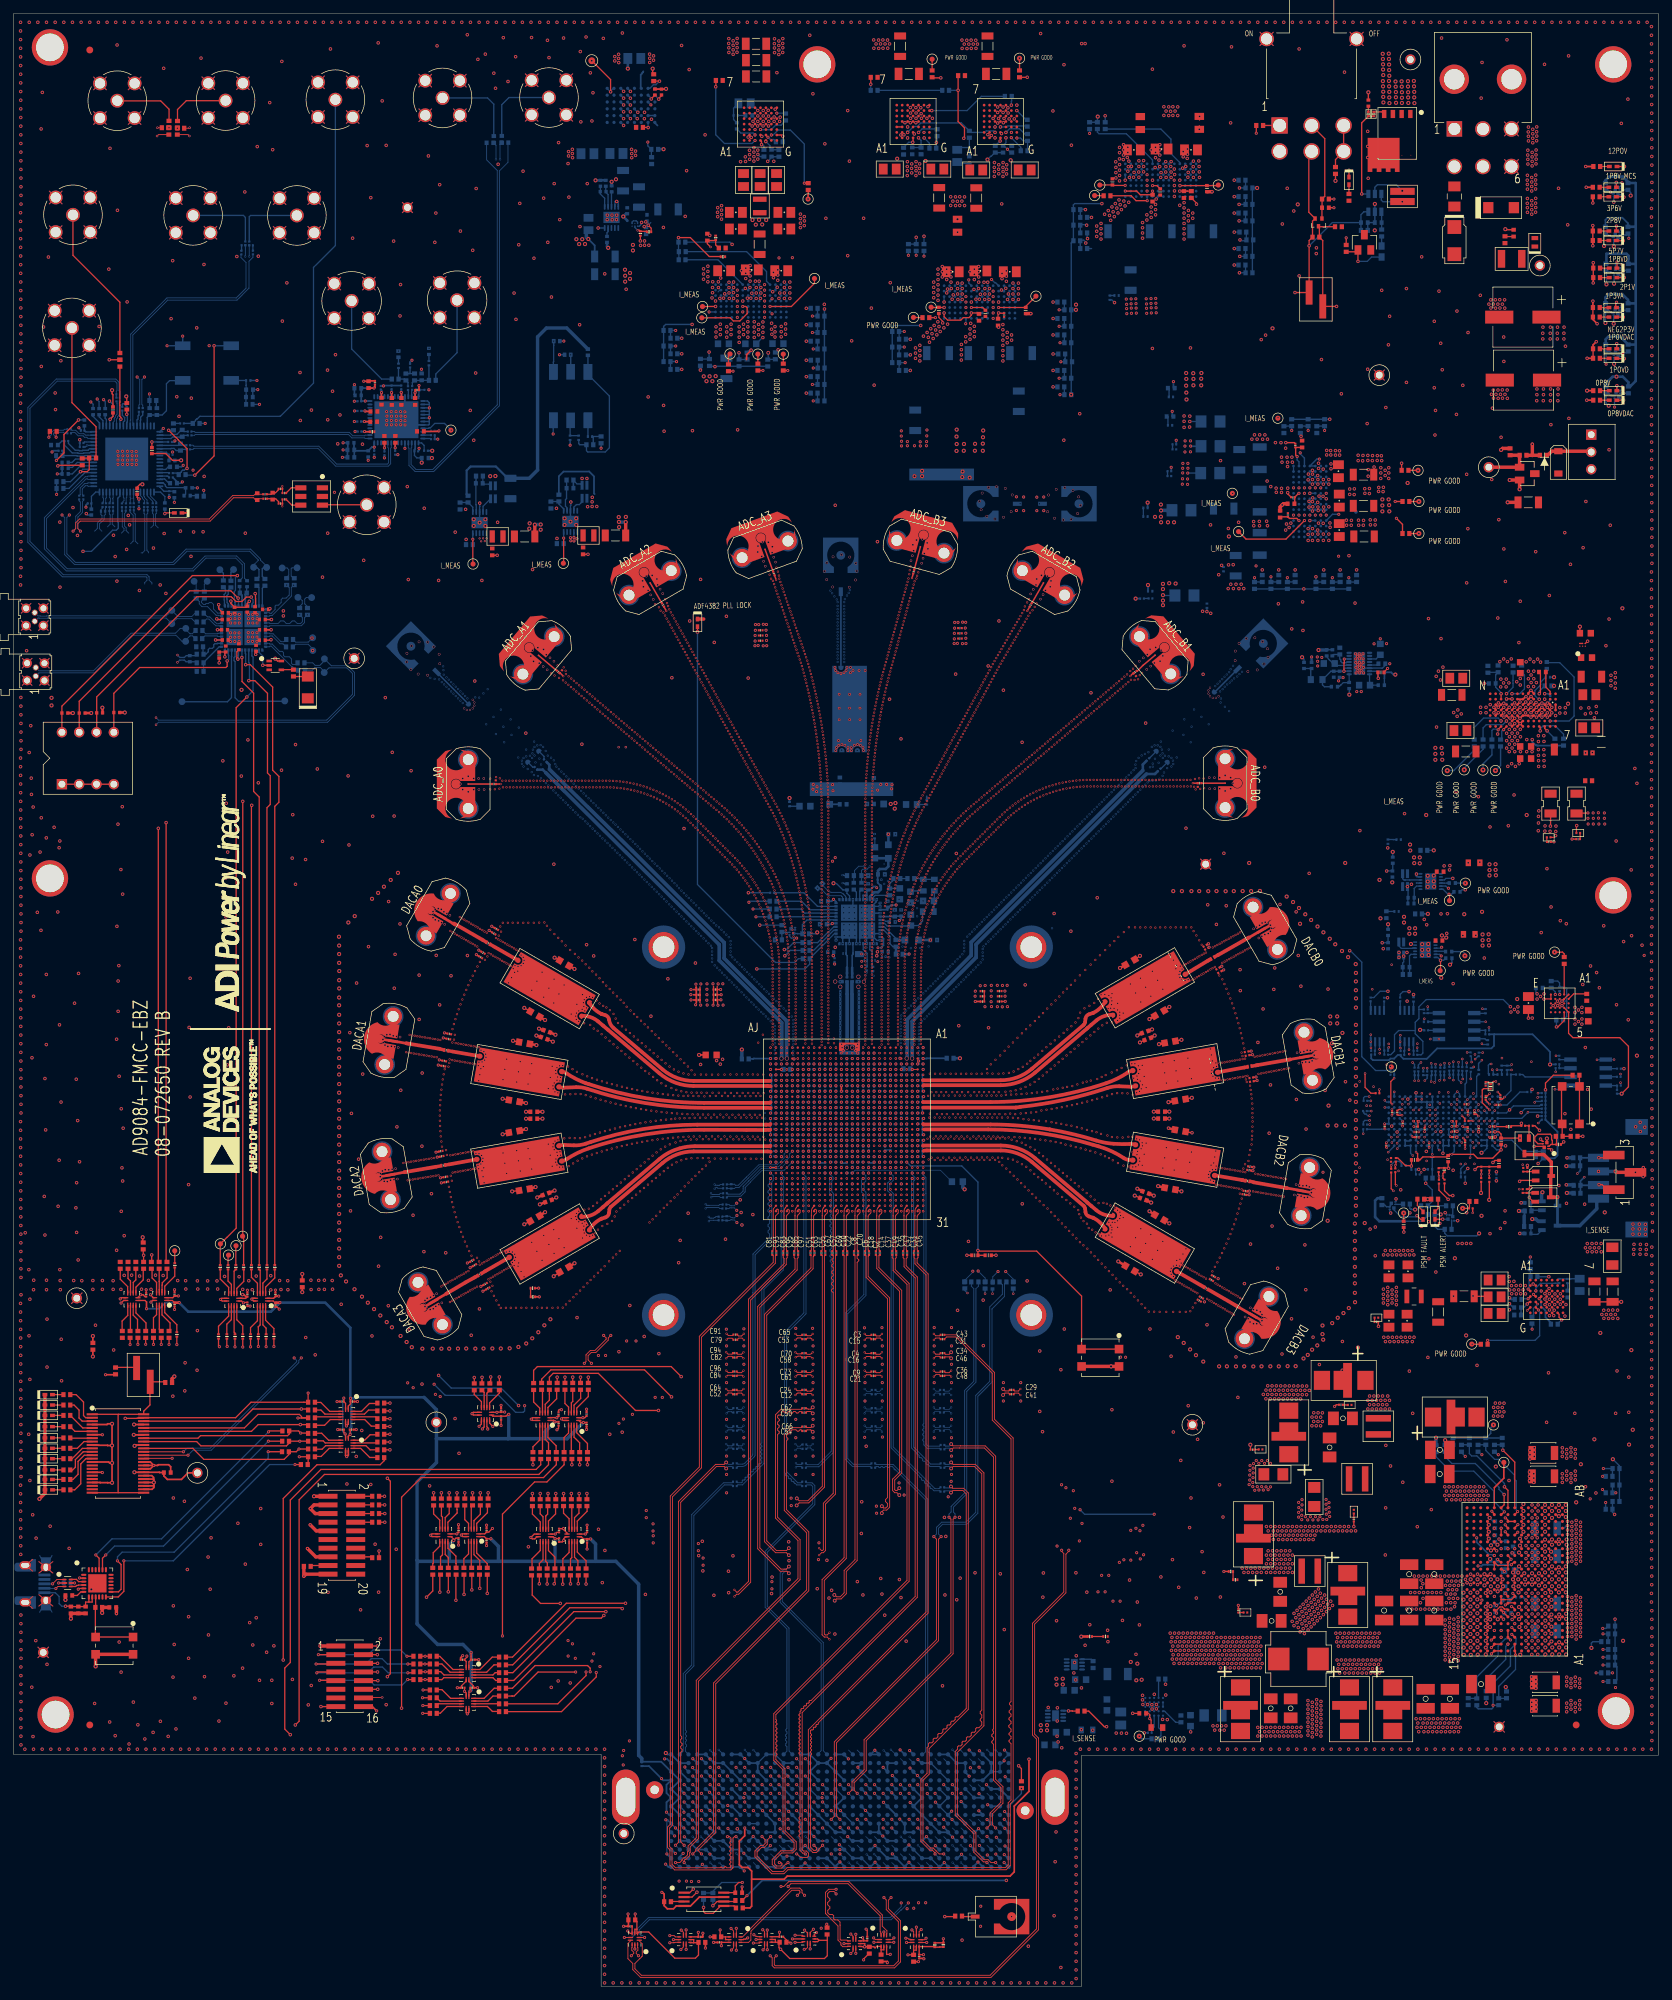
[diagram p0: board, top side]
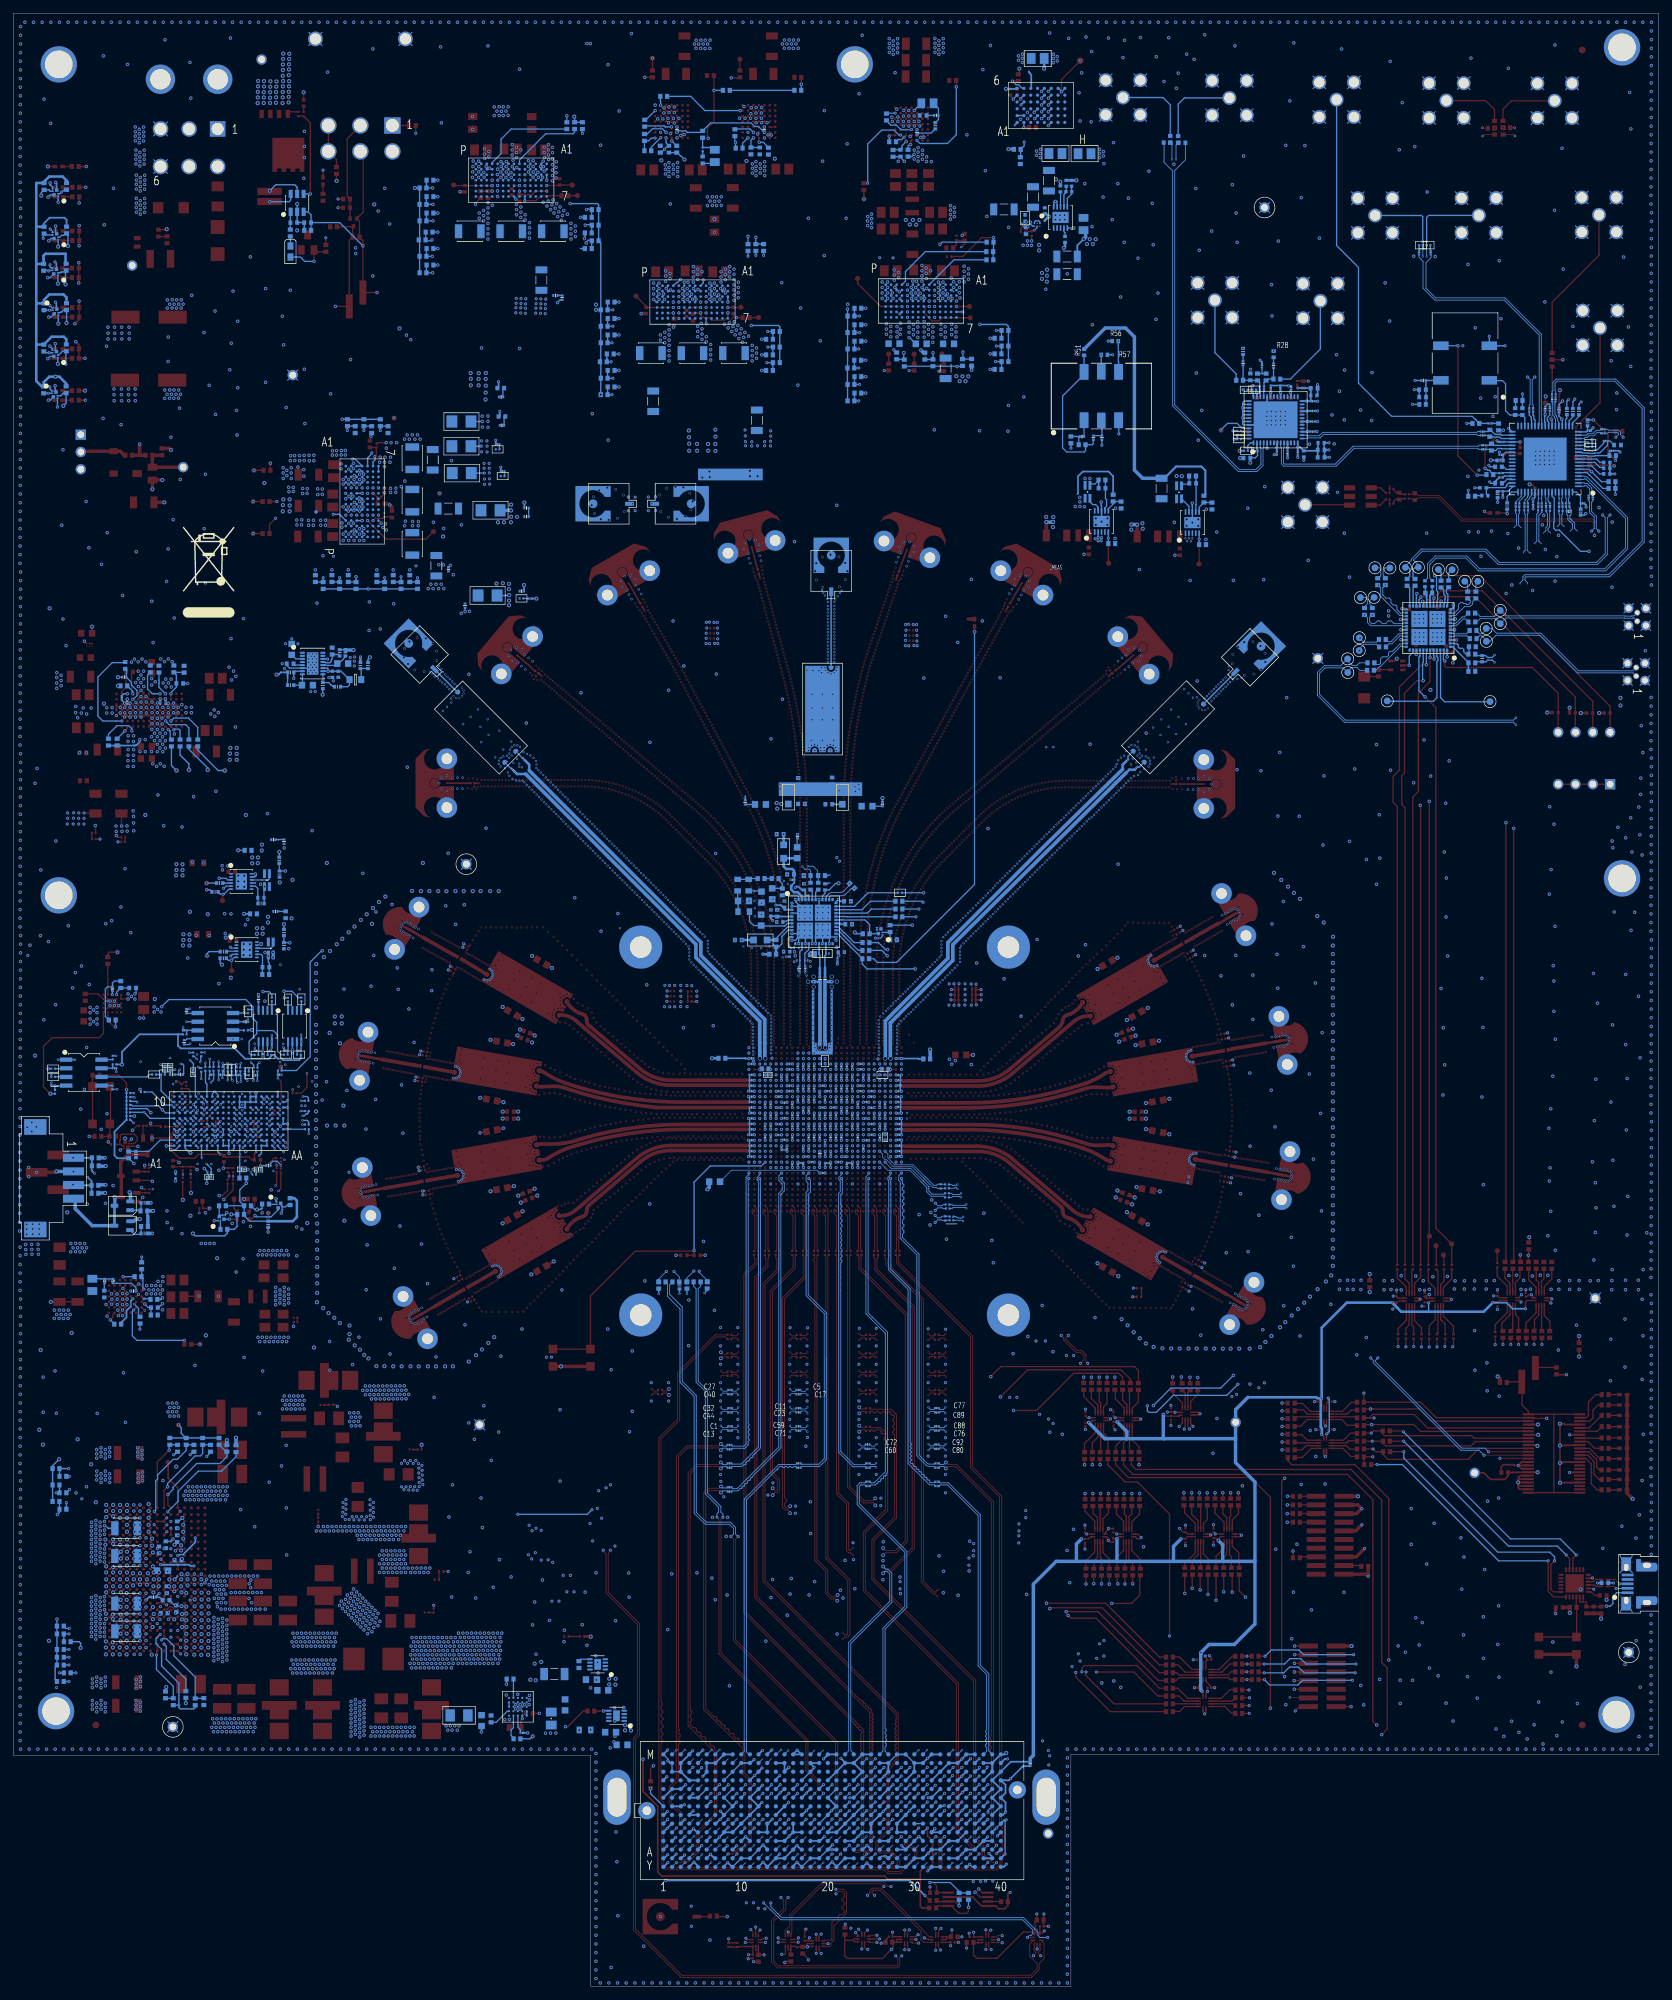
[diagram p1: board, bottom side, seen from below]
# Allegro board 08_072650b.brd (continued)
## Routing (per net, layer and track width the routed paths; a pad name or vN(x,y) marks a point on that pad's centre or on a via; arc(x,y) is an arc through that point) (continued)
SYNCOUTB_B0_N_GPIO_FMC: length 23.3
  TOP w0.133: v4(108.66,7.58) 108.87,7.37 109.01,7.37 109.04,7.33 109.16,7.33 109.21,7.28 U18.9
  L22_MIXED w0.102: v4(108.66,7.58) 109.07,7.98 109.07,8.74 106.17,11.64 106.17,20.97 106.66,21.47 106.66,22.98 106.64,23.01 106.64,25.27 106.53,25.37 106.53,26.56 v4(106.04,27.05)
  BOTTOM w0.127: P1.F32 v4(106.04,27.05)
SYNCOUTB_B0_P: length 182.5
  TOP w0.133: v4(110.01,5.36) 110.23,5.58 U18.2
  L3_SIGNAL w0.108: v4(160.22,57.89) 159.84,58.26 159.84,58.49 159.56,58.78 159.21,58.78 158.84,59.15 158.84,100.72 139.65,119.91 134.26,119.91 134.14,120.04 130.99,120.04 130.69,119.75 130.12,119.75 129.91,119.96 129.91,120.76 129.9,120.77 129.9,121.33 v7(129.5,121.73)
  L24_SIGNAL w0.108: v4(160.22,57.89) 159.73,57.89 159.33,57.49 159.06,57.49 153.68,52.1 152.22,52.1 149.96,49.84 149.96,37.43 150.61,36.77 150.61,31.64 149.96,30.99 149.96,26.88 150.3,26.54 150.3,25.02 149.96,24.68 149.96,11.98 140.74,2.77 140.49,2.77 115.93,2.77 112.01,6.68 110.22,6.68 110.12,6.58 110.12,5.47 v4(110.01,5.36)
SYNCOUTB_B0_P_FMC: length 49.2
  TOP w0.133: U18.3 v4(110.63,5.38) ; v4(128.79,13.03) 128.4,12.64 128.4,11.4 130.18,9.63 130.18,3.58 129.31,2.72 111.66,2.72 111.35,3.03 111.35,4.19 v4(111.06,4.48)
  L3_SIGNAL w0.108: v4(111.06,4.48) 111.34,4.77 111.34,6.65 111.23,6.76 110.74,6.76 110.63,6.65 v4(110.63,5.38)
  L22_MIXED w0.102: v4(128.91,24.51) 128.39,24 128.39,13.43 v4(128.79,13.03)
  BOTTOM w0.127: P1.D14 v4(128.91,24.51)
SYNCOUTB_B0_P_GPIO_FMC: length 25.4
  TOP w0.133: U18.1 109.49,6.35 v4(108.59,6.35)
  L22_MIXED w0.102: v4(108.59,6.35) 108.66,6.27 109.22,6.27 109.56,6.61 109.56,8.6 106.42,11.74 106.42,20.87 106.91,21.36 106.91,23.09 106.89,23.11 106.89,25.37 106.78,25.48 106.78,26.52 v4(107.31,27.05)
  BOTTOM w0.127: P1.F31 v4(107.31,27.05)
SYNCOUTB_B1_N: length 167.3
  TOP w0.133: v4(122.89,7.67) 123.22,7.34 U19.8
  L3_SIGNAL w0.108: v4(159.7,60.3) 160.08,60.67 160.08,100.24 140.1,120.22 134.34,120.22 134.19,120.37 131.09,120.37 130.7,120.76 130.7,121.89 130.47,122.13 130.13,122.13 130.1,122.1 129.71,122.1 129.67,122.13 129.1,122.13 v7(128.7,122.53)
  L24_SIGNAL w0.108: v4(159.7,60.3) 160.08,59.92 160.08,59.88 159.86,59.66 157.06,59.66 148.95,51.56 148.95,37.15 149.71,36.4 149.71,32.02 146.42,28.73 146.42,16.4 147.25,15.57 147.25,12.77 139.87,5.39 128.39,5.39 128.38,5.39 124.63,5.39 123.62,6.4 122.99,6.4 122.89,6.51 v4(122.89,7.67)
SYNCOUTB_B1_N_FMC: length 36.9
  TOP w0.133: U19.7 v4(123.62,7.64)
  L22_MIXED w0.102: v4(123.62,7.64) 123.49,7.77 123.49,8.05 123.59,8.15 123.59,8.29 122.23,9.66 113.38,9.66 109.14,13.89 109.14,26.11 108.96,26.29 108.96,26.29 107.94,27.31 107.94,30.23 v4(107.31,30.86)
  BOTTOM w0.127: P1.J31 v4(107.31,30.86)
SYNCOUTB_B1_N_GPIO_FMC: length 26
  TOP w0.133: v4(120.73,13.57) 120.73,13.61 120.4,13.93 119.8,13.93 119.49,13.62 119.49,13.15 119.82,12.82 119.82,12.63 119.49,12.3 119.49,11.98 119.81,11.66 119.81,11.46 119.51,11.15 119.51,10.8 119.76,10.54 120.19,10.54 120.37,10.36 120.37,9.93 120.55,9.75 120.98,9.75 121.3,9.43 121.3,9 121.32,8.98 121.32,6.92 121.45,6.78 122.33,6.78 122.43,6.67 U19.9
  L22_MIXED w0.102: v4(120.73,13.57) 119.22,13.57 116.74,16.05 116.74,23.98 v4(116.21,24.51)
  BOTTOM w0.127: P1.D24 v4(116.21,24.51)
SYNCOUTB_B1_P: length 167.7
  TOP w0.133: U19.2 123.22,5.16 v4(122.89,4.83)
  L3_SIGNAL w0.108: v7(129.5,122.53) 129.9,122.93 130.14,122.93 132.06,122.93 132.3,122.69 132.3,121.57 132.54,121.33 133.67,121.33 133.9,121.1 133.9,121.08 134.46,120.52 140.22,120.52 160.38,100.37 160.38,100.12 160.38,60.67 v4(160.75,60.3)
  L24_SIGNAL w0.108: v4(122.89,4.83) 122.89,5.99 122.99,6.1 123.49,6.1 124.5,5.09 128.51,5.09 128.51,5.1 139.99,5.1 147.55,12.65 147.55,15.7 146.72,16.53 146.72,28.61 150.01,31.9 150.01,36.52 149.25,37.28 149.25,51.43 157.18,59.37 159.98,59.37 160.38,59.76 160.38,59.92 v4(160.75,60.3)
SYNCOUTB_B1_P_FMC: length 41.1
  TOP w0.133: U19.3 v4(123.62,4.85)
  L22_MIXED w0.102: v4(123.62,4.85) 123.62,5.76 123.98,6.12 124.49,6.12 125.12,6.76 125.12,7.31 124.9,7.53 124.69,7.53 124.69,7.54 124.69,7.54 122.33,9.91 113.48,9.91 109.39,14 109.39,26.21 109.21,26.39 109.21,26.4 108.19,27.41 108.19,30.34 108.13,30.41 v4(108.59,30.86)
  BOTTOM w0.127: P1.J30 v4(108.59,30.86)
SYNCOUTB_B1_P_GPIO_FMC: length 26
  TOP w0.133: v4(120.73,14.24) 119.62,14.24 119.18,13.79 119.18,10.72 119.2,10.7 119.2,10.67 121.01,8.86 121.01,6.79 121.43,6.36 121.43,6.09 121.7,5.83 122.39,5.83 122.43,5.87 U19.1
  L22_MIXED w0.102: v4(117.47,24.51) 116.99,24.02 116.99,16.16 119.32,13.82 120.3,13.82 v4(120.73,14.24)
  BOTTOM w0.127: P1.D23 v4(117.47,24.51)
SYS_12V: length 60.8
  TOP w0.191: R631.1 219.93,126.26 R601.1
  TOP w0.197: v3(93.8,281.36) 93.8,280.69 R794.1
  TOP w0.198: R345.2 R354.2 ; R349.2 R350.2 ; R353.2 R352.2 ; R355.2 R351.2
  TOP w0.254: R356.2 v1(230.84,263.96) ; R346.2 v1(231.8,261.65) ; v1(222.66,117.2) 222.42,116.96 R685.1 ; R355.2 231.82,244.56 v1(232.44,243.94) ; R347.2 v3(230.96,234.12) ; R351.2 v1(231.82,247.25) ; R350.2 231.84,240.83 v1(232.31,241.3) ; R601.1 v1(221.32,126.63) ; R348.2 v1(230.92,232.72) ; R344.2 v1(230.76,267) ; R349.2 v1(230.96,238.87) ; R352.2 v1(231.87,252.89) ; v2(205.44,126.96) 205.53,126.96 R684.1 ; R353.2 v1(231.87,249.92) ; R659.1 v1(222.2,120.45) ; R345.2 v1(231.8,255.37) ; R354.2 v1(231.8,258.34) ; v2(211.07,126.92) R658.1
  TOP w0.508: R605.2 v3(207.57,115.49) R158.2
  L14_POWER w0.254: 210.03,129.69 209.63,130.1 207.81,130.1 207.34,129.63 207.34,128.36 206.73,127.75 205.81,127.75 205.44,127.39 v2(205.44,126.96) ; 210.03,129.69 210.03,129.72 211,130.68 212.34,130.68 213.49,131.83 214.76,131.83 ; 210.03,129.69 210.03,127.97 v2(211.07,126.92) ; v3(207.57,115.49) 208.53,114.53 211.61,114.53 212.57,115.49 214.88,115.49
  BOTTOM w0.191: U11.B5 v2(217.44,126.93) ; U11.T5 v2(205.44,126.96) ; 221.87,62.64 v1(222,62.76)
  BOTTOM w0.254: 92.43,280.95 92.41,280.93 92.41,280.85 92.25,280.69 92.25,280.66 92.05,280.46 92.05,278.5 ; v2(211.07,126.92) 211.45,126.55 U11.J5 ; v1(222.91,182.92) 222.91,182.6 223.42,182.09 223.54,182.09 223.58,182.05 223.74,182.05 223.75,182.05 R371.1 R367.1 ; R578.1 221.56,57.1 v1(222,56.67) ; 221.72,113.03 221.8,113.11 R446.1
  BOTTOM w0.508: R446.1 v3(220.95,113.77) ; 221.72,113.03 R448.1
  vias: v1(93.34,283.49) v1(93.37,282.88) v1(93.37,282.27) v1(93.93,283.24) v1(93.93,282.6) v1(104.98,285.77) v1(104.96,285.06) v1(104.98,284.42) v1(104.99,283.74) v1(105.61,285.44) v1(105.61,284.78) v1(105.61,284.12) v1(105.61,283.46) v1(106.18,285.08) v1(106.18,283.76) v1(106.2,285.79) v1(106.2,284.45) v1(126.25,285.57) v1(126.27,284.35) v1(126.59,284.99) v1(126.96,285.56) v1(126.98,284.34) v1(127.25,284.99) v1(127.59,285.57) v1(127.62,284.35) v1(127.91,284.99) v1(128.28,285.56) v1(128.3,284.36) v1(128.57,284.99) v1(139.2,285.55) v1(139.22,284.33) v1(139.55,284.96) v1(139.91,285.53) v1(139.94,284.31) v1(140.21,284.96) v1(140.55,285.55) v1(140.57,284.33) v1(140.87,284.96) v1(141.23,285.53) v1(141.26,284.34) v1(141.48,284.96) v1(176.05,38.23) v1(176.3,37.59) v1(176.68,38.23) v1(177.06,37.59) v1(177.32,38.23) v1(177.7,37.59) v1(177.95,38.23) v1(220.64,191.4) v1(221.16,191.88) v1(221.16,190.93) v1(221.96,52.71) v1(222,65.81) v1(222,64.67) v1(222,63.65) v1(222,61.75) v1(222,57.68) v1(222,55.65) v1(222,54.64) v1(222,53.62) v1(222,51.71) v1(222,50.72) v1(222,49.71) v1(222.11,182.92) v1(222.1,181.15) v1(222.58,78.64) v1(222.58,78) v1(222.58,77.37) v1(222.5,75.46) v1(222.5,74.83) v1(222.5,74.19) v1(222.88,181.15) v1(222.88,70.64) v1(222.88,69.75) v1(222.88,68.73) v1(222.88,67.72) v1(222.88,66.7) v1(222.88,65.81) v1(222.88,64.67) v1(222.88,63.65) v1(222.88,62.76) v1(222.88,61.75) v1(222.88,57.68) v1(222.88,56.67) v1(222.88,55.65) v1(222.88,54.64) v1(222.88,53.62) v1(222.88,52.73) v1(222.88,51.71) v1(222.88,50.7) v1(222.88,49.68) v1(222.85,48.71) v1(222.81,45.39) v1(222.81,44.75) v1(222.81,43.99) v1(222.83,41.68) v1(222.83,41.05) v1(222.83,40.41) v1(223.14,75.21) v1(223.14,74.57) v1(223.14,73.94) v1(223.22,79.02) v1(223.22,78.38) v1(223.22,77.75) v1(223.44,45.01) v1(223.44,44.37) v1(223.44,43.74) v1(223.47,41.94) v1(223.47,41.3) v1(223.47,40.67) v1(223.57,232.64) v1(223.6,234.37) v1(223.6,233.53) v1(223.65,68.73) v1(223.65,67.72) v1(223.65,66.7) v1(223.65,65.81) v1(223.77,70.64) v1(223.77,69.75) v1(223.77,64.67) v1(223.77,63.65) v1(223.77,62.76) v1(223.77,61.75) v1(223.77,57.68) v1(223.77,56.67) v1(223.77,55.65) v1(223.77,54.64) v1(223.77,53.62) v1(223.77,52.73) v1(223.77,51.71) v1(223.77,50.7) v1(223.77,49.68) v1(223.73,48.71) v1(224.49,243.43) v1(224.46,242.54) v1(224.46,241.71) v1(224.56,234.37) v1(224.56,233.53) v1(224.54,232.64) v1(225.58,243.43) v1(225.55,242.54) v1(225.55,241.71) v1(225.58,232.64) v1(225.6,234.37) v1(225.6,233.53) v1(226.62,243.43) v1(226.59,242.54) v1(226.59,241.71) v1(226.67,232.64) v1(226.69,234.37) v1(226.69,233.53) v1(227.58,243.43) v1(227.56,242.54) v1(227.56,241.71) v1(229.18,143.64) v1(229.18,142.88) v1(229.69,143.26) v1(230.2,143.64) v1(230.2,142.88) v1(230.72,108.36) v1(230.99,108.98) v1(231.02,107.79) v1(231.38,108.36) v1(231.68,108.99) v1(231.7,107.77) v1(232.04,108.36) v1(232.31,109.01) v1(232.34,107.79) v1(232.7,108.36) v1(233.03,108.99) v1(233.05,107.77) v3(200.96,283.54) v3(200.99,282.78) v3(201.02,281.99) v3(201.02,281.23) v3(201.04,280.42) v3(200.99,279.53) v3(201.02,278.76) v3(201.04,277.98) v3(201.04,277.22) v3(201.07,276.4) v3(201.85,283.57) v3(201.88,282.78) v3(201.88,279.55) v3(201.9,281.97) v3(201.9,281.15) v3(201.93,280.31) v3(201.9,278.76) v3(201.93,277.95) v3(201.93,277.14) v3(201.96,276.3) v3(202.84,279.48) v3(202.87,278.71) v3(202.9,277.93) v3(202.9,277.16) v3(202.92,276.35) v3(203.73,279.5) v3(203.76,278.71) v3(203.78,277.9) v3(203.78,277.09) v3(203.78,276.33) v3(204.67,279.53) v3(204.67,278.74) v3(204.7,277.9) v3(204.7,277.14) v3(204.72,276.33) v3(205.54,279.55) v3(205.56,278.76) v3(205.59,277.95) v3(205.59,277.14) v3(205.61,276.3)
SYSREF_A_N: length 58.3
  L24_SIGNAL w0.108: v4(140.79,104.93) 140.79,104.95 141.04,105.2 141.04,105.62 142.7,107.29 142.7,126.72 139.3,130.13 114.47,130.13 113.9,130.69 113.9,133.33 v4(113.5,133.73)
  BOTTOM w0.127: R589.1 139.58,103.56 140.79,104.77 v4(140.79,104.93)
SYSREF_A_N_FMC: length 83.9
  TOP w0.133: v4(137.3,68.83) 137.59,68.55 137.59,48.93 124.83,36.17 124.83,31.78 123.06,30.01 123.06,28.83 v4(122.56,28.32)
  BOTTOM w0.127: P1.G19 v4(122.56,28.32)
  BOTTOM w0.133: R589.2 140.58,102.72 140.94,102.36 140.94,88.78 139.59,87.43 139.59,72.39 137.64,70.44 137.64,70.43 137.62,70.41 137.62,69.6 137.3,69.28 v4(137.3,68.83)
SYSREF_A_P: length 58.5
  L24_SIGNAL w0.108: v4(141.58,104.95) 141.34,105.2 141.34,105.5 143,107.16 143,126.85 138.11,131.74 133.41,131.74 133.4,131.73 131.74,131.73 131.5,131.49 131.5,131.05 131.38,130.93 114.94,130.93 114.7,131.17 114.7,133.33 v4(114.3,133.73)
  BOTTOM w0.127: R561.1 142.61,103.92 v4(141.58,104.95)
SYSREF_A_P_FMC: length 83.9
  TOP w0.133: v4(138.19,68.83) 137.9,68.55 137.9,48.8 125.15,36.04 125.15,31.65 123.37,29.88 123.37,28.77 v4(123.82,28.32)
  BOTTOM w0.127: P1.G18 v4(123.82,28.32)
  BOTTOM w0.133: v4(138.19,68.83) 138.19,69.33 137.95,69.57 137.95,70.31 139.9,72.26 139.9,87.3 141.25,88.65 141.25,102.35 141.61,102.72 R561.2
SYSREF_B_N: length 40.6
  L24_SIGNAL w0.108: v4(144.49,104.88) 144.85,105.23 144.85,126.88 138.4,133.33 131.5,133.33 v4(131.1,133.73)
  BOTTOM w0.127: R588.1 143.72,104.1 v4(144.49,104.88)
SYSREF_B_N_FMC: length 92.7
  TOP w0.133: v4(135.08,65.99) 135.45,65.61 135.45,50.86 120.47,35.87 120.47,24.96 v4(120.02,24.51)
  BOTTOM w0.127: P1.D21 v4(120.02,24.51)
  BOTTOM w0.133: v4(135.08,65.99) 135.46,66.37 135.46,67.34 136.22,68.1 139.77,68.1 141.22,69.55 141.22,86.69 143.28,88.76 143.28,99.69 145.14,101.55 145.14,102.94 R588.2
SYSREF_B_P: length 42.3
  L24_SIGNAL w0.108: v4(145.62,104.88) 145.26,105.24 145.26,126.89 138.47,133.68 133.45,133.68 133,134.13 130.7,134.13 v4(130.3,133.73)
  BOTTOM w0.127: R587.1 146.73,103.77 v4(145.62,104.88)
SYSREF_B_P_FMC: length 92.7
  TOP w0.133: v4(121.28,24.51) 120.78,25.02 120.78,35.74 135.77,50.73 135.77,65.61 v4(136.14,65.99)
  BOTTOM w0.127: P1.D20 v4(121.28,24.51)
  BOTTOM w0.133: R587.2 145.45,103.07 145.45,101.23 143.61,99.39 143.61,88.65 141.53,86.56 141.53,69.42 139.9,67.79 136.35,67.79 135.77,67.21 135.77,66.36 v4(136.14,65.99)
SYSREF_IN_N_FMC: length 296.1
  L5_MIXED w0.108: v1(43.79,197.82) 43.31,197.34 39.83,197.34 39.12,196.63 21.36,196.63 13.47,188.73 5.88,188.73 v3(5.56,189.05)
  L22_MIXED w0.102: v4(99.69,28.32) 100.19,28.82 100.19,33.85 97.47,36.58 88.23,36.58 87.72,36.07 27.58,36.07 17.55,46.11 17.55,62.74 15.52,64.77 11.66,64.77 3.61,72.83 3.61,151.89 8.67,156.95 8.67,168.69 3.98,173.38 3.98,173.46 3.98,173.47 3.98,187.79 4.8,188.61 5.13,188.61 v3(5.56,189.05)
  BOTTOM w0.127: P1.G37 v4(99.69,28.32)
  BOTTOM w0.133: R742.2 41.4,197.22 43.25,197.22 TP47.1
SYSREF_IN_P_FMC: length 296
  L5_MIXED w0.108: v1(43.89,195.99) 43.03,196.85 40.03,196.85 39.32,196.14 21.56,196.14 13.67,188.25 5.88,188.25 v3(5.56,187.93)
  L22_MIXED w0.102: v4(100.97,28.32) 100.45,28.83 100.45,33.96 97.56,36.86 88.06,36.86 87.59,36.38 27.65,36.38 17.86,46.17 17.86,62.78 15.56,65.09 11.79,65.09 4.04,72.84 4.04,151.87 8.92,156.75 8.92,168.8 4.23,173.48 4.23,173.57 4.22,173.57 4.22,187.69 4.9,188.37 5.13,188.37 v3(5.56,187.93)
  BOTTOM w0.127: P1.G36 v4(100.97,28.32)
  BOTTOM w0.133: R741.2 41.01,196.52 41.4,196.91 43.22,196.91 43.92,196.21 TP46.1
SYSREF_N: length 205.7
  L3_SIGNAL w0.108: v7(22.81,272.7) 23,272.7 23.24,272.95 23.24,273.56 23.55,273.86 25.87,273.86 34.57,265.17 59.36,265.17 59.77,265.17 70.48,254.46 70.48,223.94 71.85,222.58 71.85,220.19 70.48,218.82 70.48,192.95 79.73,183.71 88.52,183.71 89.5,182.72 89.5,182.17 v2(89.86,181.81)
  L24_SIGNAL w0.108: v4(122.3,136.13) 122.26,136.09 117.96,136.09 110.66,143.39 110.66,158.76 110.66,158.76 110.66,159.8 89.51,180.95 89.51,181.75 89.57,181.81 v2(89.86,181.81)
SYSREF_N_FMC: length 364.4
  TOP w0.133: R783.2 21.27,271.69 v2(21.06,271.48)
  L22_MIXED w0.102: v2(21.06,271.48) 21.12,271.54 23.26,271.54 23.37,271.43 23.37,269.11 19.1,264.84 19.1,250.22 20.02,249.3 23.37,249.3 30.23,242.44 30.23,224.69 28.52,222.99 28.52,188.44 29.18,187.79 29.18,80.79 30.2,79.77 43.9,66.07 59.23,66.07 61.72,68.55 87,68.55 102.95,52.61 137.01,52.61 146.13,43.48 146.13,28.17 145.28,27.31 141.29,27.31 139.89,28.71 138.04,28.71 137.79,28.47 v4(137.79,28.32)
  BOTTOM w0.127: P1.G7 v4(137.79,28.32)
SYSREF_OUT_N_FMC: length 306.4
  L22_MIXED w0.102: v4(140.44,32.08) 140.85,32.1 140.94,32.21 140.93,32.36 140.93,32.53 140.74,32.72 139.19,32.72 138.89,33.02 138.89,38.86 132.51,45.24 97.31,45.24 87.89,54.66 87.89,55.65 86.71,56.83 72.06,56.83 70.99,55.76 55.37,55.76 54.05,57.08 38.99,57.08 34.88,61.19 34.88,62.89 20.94,76.83 20.94,88.04 16.08,92.89 16.08,96.01 18.24,98.16 20.9,98.16 22.36,99.63 22.36,108.25 20.48,110.13 20.48,167.26 19.67,168.07 19.67,182.58 21.34,184.25 21.34,185.4 21.23,185.5 21.01,185.5 20.9,185.4 v2(20.9,185.1)
  BOTTOM w0.133: 140.97,31.5 140.97,31.55 v4(140.44,32.08) ; v2(20.9,185.1) 21.27,185.47 46.08,185.47 50.04,189.43 50.04,192.76 49.05,193.76 46.63,193.76 TP45.1 45.62,194.49 44.94,193.81 44.27,193.81 43.89,194.18 R17.2
SYSREF_OUT_P_FMC: length 305.5
  L22_MIXED w0.102: v4(141.71,32.16) 141.3,32.13 141.19,32.23 141.18,32.37 141.18,32.63 140.84,32.97 139.29,32.97 139.14,33.12 139.14,38.96 132.61,45.49 97.41,45.49 88.14,54.76 88.14,55.75 86.82,57.07 71.96,57.07 70.89,56.01 55.47,56.01 54.15,57.33 39.09,57.33 35.13,61.29 35.13,62.99 21.18,76.94 21.18,88.14 16.33,92.99 16.33,95.91 18.34,97.92 21.01,97.92 22.61,99.52 22.61,108.35 20.73,110.24 20.73,167.36 19.91,168.17 19.91,182.47 21.58,184.14 21.58,185.5 21.34,185.75 21.01,185.75 20.9,185.85 v2(20.9,186.14)
  BOTTOM w0.133: 142.24,31.5 142.24,31.62 v4(141.71,32.16) ; v2(20.9,186.14) 21.27,185.78 45.95,185.78 49.73,189.56 49.73,192.63 48.92,193.45 46.28,193.45 TP44.1 45.6,192.91 45.02,193.5 44.22,193.5 43.81,193.09 R16.2
SYSREF_P: length 205.4
  L3_SIGNAL w0.108: v7(24.04,272.62) 23.93,272.62 23.6,272.95 23.6,273.46 23.7,273.56 25.75,273.56 34.44,264.87 59.23,264.87 59.65,264.87 70.15,254.37 70.15,223.85 71.55,222.45 71.55,220.31 70.15,218.91 70.15,212.38 70.19,212.35 70.19,192.83 79.6,183.41 88.39,183.41 89.21,182.6 89.21,182.21 v2(88.81,181.81)
  L24_SIGNAL w0.108: v4(122.3,135.33) 121.84,135.79 117.83,135.79 110.36,143.27 110.36,158.64 110.36,159.67 89.21,180.83 89.21,181.71 89.1,181.81 v2(88.81,181.81)
SYSREF_P_FMC: length 363.1
  TOP w0.133: R782.2 25.6,271.69 v2(25.81,271.48)
  L22_MIXED w0.102: v4(139.06,28.32) 139.88,28.32 141.13,27.07 145.38,27.07 146.38,28.07 146.38,43.59 137.11,52.86 103.05,52.86 87.1,68.8 61.61,68.8 59.14,66.33 43.99,66.33 29.43,80.89 29.43,187.89 28.77,188.54 28.77,222.88 30.47,224.59 30.47,242.55 23.47,249.55 22.99,249.55 22.98,249.56 20.11,249.56 19.35,250.32 19.35,264.74 23.62,269.01 23.62,271.34 23.85,271.58 25.7,271.58 v2(25.81,271.48)
  BOTTOM w0.127: P1.G6 v4(139.06,28.32)
TRIG_A0: length 307.7
  TOP w0.191: R593.1 v1(71.3,89.41) ; R525.2 v1(14.04,238.65)
  L3_SIGNAL w0.114: v1(84.1,152.83) 70.76,166.17 63.63,166.17 51.89,177.9 51.89,203.67 45.38,210.19 40.74,210.19 34.54,216.38 34.54,230.43 26.32,238.65 v1(14.04,238.65)
  L24_SIGNAL w0.108: v4(113.5,132.93) 113.45,132.93 113.05,133.33 108.8,133.33 108.79,133.35
  L24_SIGNAL w0.114: 107.09,133.35 100.97,133.35 84.1,150.22 v1(84.1,152.83) 80.98,152.83 69.16,164.64 55.55,164.64 42.84,151.94 42.84,99.86 50.34,92.37 66.48,92.37 69.37,89.48 69.37,89.1 69.8,88.67 70.56,88.67 v1(71.3,89.41)
  L24_SIGNAL w0.127: 107.09,133.35 108.79,133.35
TRIG_A0_FMC: length 137.7
  TOP w0.191: v4(70.34,82.15) 69.87,82.63 U41.12
  L3_SIGNAL w0.114: v4(89.48,32.49) 89.51,32.51 90.42,32.51 91.19,33.27 91.19,38.99 87.93,42.24 79.48,42.24 77.88,43.84 77.88,75.89 74.02,79.76 72.74,79.76 v4(70.34,82.15)
  L5_MIXED w0.114: v4(128.91,23.24) 129.51,22.63 129.51,16.76 122.36,9.61 119.15,9.61 118.71,9.17 95.45,9.17 92.15,12.47 92.15,30.94 90.55,32.54 89.53,32.54 v4(89.48,32.49)
  BOTTOM w0.191: P1.C14 v4(128.91,23.24)
TRIG_A1: length 169.6
  TOP w0.191: R591.1 69.9,88.72 70.03,88.85 v1(70.03,89.41)
  L24_SIGNAL w0.108: v4(113.5,132.13) 113.5,132.24 113.21,132.54 112.87,132.54 112.87,132.53 109.22,132.53
  L24_SIGNAL w0.114: 108,132.53 100.23,132.53 68.76,164.01 55.88,164.01 46.18,154.31 46.18,97.46 50.95,92.68 66.75,92.68 v1(70.03,89.41)
  L24_SIGNAL w0.127: 109.22,132.53 108,132.53
TRIG_A1_FMC: length 134.7
  TOP w0.191: v4(69.59,81.76) 69.6,81.76 69.6,81.97 69.47,82.1 U41.11
  L3_SIGNAL w0.114: v4(69.59,81.76) 69.59,80.83 72.42,78 72.42,41.28 74.8,38.89 85.42,38.89 88.19,36.12 88.19,35 v4(89.36,33.83)
  L5_MIXED w0.114: v4(127.63,23.24) 128.32,22.56 128.32,16.15 122.09,9.92 119.02,9.92 118.67,9.58 95.81,9.58 92.57,12.82 92.57,28.19 92.56,28.19 92.56,29.46 92.57,29.47 92.57,31.49 90.22,33.83 v4(89.36,33.83)
  BOTTOM w0.191: P1.C15 v4(127.63,23.24)
TRIG_B0: length 199.4
  TOP w0.191: R594.1 68.73,88.8 68.76,88.82 v1(68.76,89.36)
  L24_SIGNAL w0.114: v1(68.76,89.36) 68.76,88.84 68.49,88.57 67.69,88.57 64.85,91.41 49.25,91.41 40.75,99.91 40.75,104.74 40.26,105.23 40.26,151.79 54.74,166.27 70.41,166.27 81.28,155.4 83.85,155.4 99.39,139.85 112.83,139.85 116.3,136.38 116.3,132.76 116.53,132.53 130.68,132.53 131.08,132.93 v4(131.1,132.93)
TRIG_B0_FMC: length 137.3
  TOP w0.191: v4(68.81,81.78) 68.81,81.81 69.07,82.07 U41.10
  L3_SIGNAL w0.114: v4(68.81,81.78) 68.81,82.37 68.96,82.52 69.83,82.52 69.94,82.41 69.94,81.97 69.99,81.92 69.99,81.55 74.55,76.99 74.55,42.14 76.45,40.23 86.61,40.23 89.54,37.31 v4(89.54,34.61)
  L5_MIXED w0.114: v4(89.54,34.61) 92.4,34.61 95.92,31.09 95.92,27.6 93.28,24.96 93.28,14.64 97.23,10.69 121.72,10.69 125.78,14.76 125.78,23.83 v4(125.09,24.51)
  BOTTOM w0.191: P1.D17 v4(125.09,24.51)
TRIG_B1: length 195.2
  TOP w0.191: R592.1 v1(67.61,89.33)
  L24_SIGNAL w0.114: v4(131.1,132.13) 130.7,131.73 115.74,131.73 115.5,131.97 115.5,135.93 112.83,138.61 99.39,138.61 83.54,154.46 80.57,154.46 69.52,165.51 55.17,165.51 41.45,151.79 41.45,100.28 49.91,91.82 65.63,91.82 67.61,89.84 v1(67.61,89.33)
TRIG_B1_FMC: length 138
  TOP w0.191: v4(68.33,82.17) 68.65,82.49 68.65,82.76 68.67,82.78 U41.9
  L3_SIGNAL w0.114: v4(90.39,36.01) 90.44,35.96 90.44,33.74 89.96,33.26 89.12,33.26 84.48,37.9 74.22,37.9 70.74,41.38 70.74,77.98 68.33,80.39 v4(68.33,82.17)
  L5_MIXED w0.114: v4(90.39,36.01) 91.75,36.01 96.32,31.45 96.32,27.43 93.6,24.71 93.6,17.04 99.57,11.07 121.3,11.07 124.59,14.35 124.59,23.8 123.88,24.51 v4(123.82,24.51)
  BOTTOM w0.191: P1.D18 v4(123.82,24.51)
TRIG_IN_FMC: length 17.9
  TOP w0.191: v1(136.68,10.24) 138.13,10.24 R590.1
  L22_MIXED w0.114: v1(136.68,10.24) 134.59,12.32 134.59,22.48 135.25,23.14 v4(135.25,24.51)
  BOTTOM w0.191: P1.D9 v4(135.25,24.51)
UART_RST: length 11.4
  TOP w0.191: S1.1A S1.1B 12,51.29 R469.2 12.04,55.65 U22.9
UNNAMED_7_CAP_I46_N1: length 4.2
  TOP w0.546: T1WB.1 175.49,150.6
UNNAMED_7_CAP_I46_N2: length 5.2
  TOP w0.546: 181.31,153.89 176.79,151.31
UNNAMED_7_CAP_I61_N1: length 4.1
  TOP w0.546: T1XB.1 180.72,134.83
UNNAMED_7_CAP_I61_N2: length 5.7
  TOP w0.114: 182.33,135.12 C5XB.2
  TOP w0.546: 187.36,135.99 182.6,135.17 182.33,135.12
UNNAMED_7_CAP_I73_N1: length 4.1
  TOP w0.546: T1WA.1 70.55,152.54
UNNAMED_7_CAP_I73_N2: length 4.9
  TOP w0.546: 64.68,155.93 68.91,153.49
UNNAMED_7_CAP_I85_N1: length 4.1
  TOP w0.546: T1XA.1 64.46,137.15
UNNAMED_7_CAP_I85_N2: length 4.9
  TOP w0.546: 57.66,138.36 62.54,137.55
UNNAMED_7_CAP_I103_N1: length 4.2
  TOP w0.546: T1YA.1 63.97,120.61
UNNAMED_7_CAP_I103_N2: length 4.7
  TOP w0.546: 57.36,119.45 61.99,120.25
UNNAMED_7_CAP_I117_N1: length 4.2
  TOP w0.546: T1ZA.1 69.19,104.91
UNNAMED_7_CAP_I117_N2: length 4.9
  TOP w0.546: 67.74,104.06 66.32,103.28 63.53,101.63
UNNAMED_7_CAP_I131_N1: length 4.3
  TOP w0.546: 180.49,118.26 180.37,118.29 176.23,119 T1YB.1
UNNAMED_7_CAP_I131_N2: length 5.6
  TOP w0.114: 182.01,117.97 C5YB.2
  TOP w0.546: 186.92,117.11 182.01,117.97
UNNAMED_7_CAP_I145_N1: length 4.8
  TOP w0.254: C5ZB.1 174.7,102.61
  TOP w0.546: 174.7,102.61 T1ZB.1
UNNAMED_7_CAP_I145_N2: length 4.9
  TOP w0.254: C5ZB.2 175.54,102.13
  TOP w0.546: 175.54,102.13 179.52,99.82
UNNAMED_9_CAP_I66_N1: length 2.1
  TOP w0.191: L15.2 37.8,218.92 C319.1 38.45,219.14 38.9,219.59 C333.1
UNNAMED_9_CAP_I66_N2: length 2.2
  TOP w0.191: L16.2 37.9,218.26 C319.2 38.12,218.24 38.48,218.24 38.9,217.82 C331.1
UNNAMED_9_CAP_I76_N2: length 35.2
  L24_SIGNAL w0.318: v9(121.34,147.4) 122.12,147.4 122.38,147.66 122.38,179.82 122.25,179.95 122.25,180.14 121.54,180.85 v9(121.54,181.38)
UNNAMED_9_CAP_I78_N2: length 35.1
  L24_SIGNAL w0.318: v9(124,147.4) 123.32,147.4 123.01,147.71 123.01,179.82 123.14,179.95 123.14,180.14 123.82,180.82 v9(123.82,181.33)
UNNAMED_9_CAP_I79_N2: length 1.4
  BOTTOM w0.191: T2.3 76.18,178.89 C329.2
UNNAMED_9_CAP_I80_N2: length 1.6
  BOTTOM w0.191: C328.2 77.85,180.46 T2.2
UNNAMED_9_CAP_I81_N2: length 1.5
  BOTTOM w0.191: C327.2 166.71,180.19 T1.3
UNNAMED_9_CAP_I82_N2: length 1.4
  BOTTOM w0.191: T1.2 168.42,178.66 C326.2
UNNAMED_9_CAP_I85_N2: length 2.5
  TOP w0.191: C332.2 40.83,217.32 T4.4
UNNAMED_9_CAP_I87_N2: length 2.5
  TOP w0.191: C334.2 40.76,219.86 T4.6
UNNAMED_9_CNBNC2P_I100_CNTR: length 6.7
  BOTTOM w0.222: CLK_A.1 62.1,192.79 T2.1
UNNAMED_9_CNBNC2P_I101_CNTR: length 4.9
  BOTTOM w0.222: CLK_B.1 176.27,189.86 T1.1
UNNAMED_9_CNBNC2P_I102_CNTR: length 11.2
  BOTTOM w0.222: T3.1 121.44,204.57 121.41,204.59 CLK.1
UNNAMED_10_ADLTC6955_I209_FLT: length 1.8
  BOTTOM w0.191: U2.40 59.49,233.28 59.49,233.97 59.6,234.08 R311.2 59.63,234.24 R312.2
UNNAMED_10_ADLTC6955_I209_IN: length 1
  BOTTOM w0.191: U2.37 57.93,234.17 C106.2
UNNAMED_10_ADLTC6955_I209_IN_1: length 1
  BOTTOM w0.191: U2.38 58.43,233.24 58.43,234.18 C315.2
UNNAMED_10_ADLTC6955_I209_SEL0: length 1.3
  BOTTOM w0.191: R307.2 61.15,228.09 U2.50
UNNAMED_10_ADLTC6955_I209_SEL1: length 1.2
  BOTTOM w0.191: U2.51 61.26,227.59 R309.2
UNNAMED_10_ADLTC6955_I209_SEL2: length 1.2
  BOTTOM w0.191: R310.2 61.18,227.09 U2.52
UNNAMED_10_ADLTC6955_I209_SEL3: length 1.8
  BOTTOM w0.191: U2.1 59.88,226.46 60.26,226.08 R308.2
UNNAMED_10_ADLTC6955_I209_TEMP: length 4.9
  BOTTOM w0.191: v4(64.24,228.32) 63.25,229.31 61.82,229.31 61.18,228.67 61,228.67 60.93,228.59 U2.49
UNNAMED_10_CAP_I161_N2: length 2.2
  BOTTOM w0.191: C316.2 58.19,236.67 58.14,236.62 ; R306.1 58.14,236.62 ; 58.14,236.62 R305.2
UNNAMED_10_CAP_I193_N2: length 5.3
  BOTTOM w0.191: C315.1 58.53,234.82 58.53,235.3 R306.2 59.87,235.62 C322.2 59.9,235.64 R639.2 60.96,235.64 C766.2
UNNAMED_10_CAP_I207_N1: length 3.8
  BOTTOM w0.191: C106.1 57.89,235.31 R305.1 57.39,235.81 R638.2 56.49,235.83 C765.2
UNNAMED_10_CAP_I211_N2: length 2.4
  BOTTOM w0.191: C749.2 84.3,227.39 Y3.1
UNNAMED_10_CNBNC5P_I196_CNTR: length 14.8
  BOTTOM w0.191: R638.1 54.02,235.81 49.61,240.22 J17.1
UNNAMED_10_CNBNC5P_I201_CNTR: length 13
  BOTTOM w0.191: J18.1 65.09,239.69 61.97,236.57 R639.1
UNNAMED_10_RES_I166_N1: length 2.6
  BOTTOM w0.191: R52.2 85.09,227.22 C749.1 84.94,227.4 R53.1
UNNAMED_10_RES_I169_N1: length 21.2
  BOTTOM w0.191: R51.2 84.29,237.07 84.3,237.06 Y3.4 84.3,236.47 87.45,233.32 87.45,225.73 86.84,225.12 84.28,225.12 84.09,225.31 R52.1 83.11,226.18 82.96,226.34 82.96,226.86 R473.1
UNNAMED_10_RES_I171_N1: length 27.9
  L24_SIGNAL w0.114: v9(79.28,241.39) 57.95,241.39 v9(56.49,239.93)
  BOTTOM w0.191: v9(79.28,241.39) 79.28,240.77 79.27,240.77 79.27,238.37 79.22,238.32 Y3.3
UNNAMED_10_RES_I173_N1: length 24.1
  L24_SIGNAL w0.114: v9(60.99,240.33) 62.62,240.33 64.03,238.91 81.3,238.91 v9(81.77,239.38)
  BOTTOM w0.191: v9(81.77,239.38) 81.77,236.89 U49.5
UNNAMED_10_RES_I184_N2: length 3.5
  BOTTOM w0.191: U49.2 81.76,229.67 81.69,229.59 R474.1 R473.2
UNNAMED_11_ADHMC7044_I155_BGABYP1: length 4.2
  BOTTOM w0.191: C98.1 8.6,221.9 9.79,223.09 U1B.7
UNNAMED_11_ADHMC7044_I155_CLKIN0: length 4.1
  BOTTOM w0.191: U1B.39 24.24,226.09 R6.1 24.71,226.11 C216.2
UNNAMED_11_ADHMC7044_I155_CLKIN0N: length 4.1
  BOTTOM w0.191: U1B.40 23.06,225.59 23.11,225.64 23.55,225.64 23.86,225.33 R6.2 24.66,225.5 C217.2
UNNAMED_11_ADHMC7044_I155_CLKIN1: length 4.5
  BOTTOM w0.191: U1B.36 23.04,227.59 23.15,227.7 23.99,227.7 24.65,228.36 R132.1 24.99,228.12 C155.2
UNNAMED_11_ADHMC7044_I155_CLKIN1N: length 4.3
  BOTTOM w0.191: C156.2 24.93,227.56 R132.2 24.68,227.31 23.33,227.31 23.1,227.09 U1B.37
UNNAMED_11_ADHMC7044_I155_CLKOUT0: length 3
  BOTTOM w0.133: C230.1 10.08,218.86 10.08,219.71 10.56,220.18 10.83,220.18 10.93,220.09 U1B.1
UNNAMED_11_ADHMC7044_I155_CLKOUT0N: length 3.5
  BOTTOM w0.133: C231.1 9.77,218.86 9.77,219.84 10.43,220.49 10.83,220.49 10.93,220.59 U1B.2
UNNAMED_11_ADHMC7044_I155_CLKOUT4N: length 2.5
  BOTTOM w0.191: U1B.25 16.11,229.52 16.3,229.71 16.3,230.16 15.95,230.51 C748.1
UNNAMED_11_ADHMC7044_I155_CLKOUT6: length 38.5
  BOTTOM w0.133: U1B.27 17.11,229.73 17.18,229.8 17.18,242.41 22.5,247.73 32.68,247.73 34.11,249.16 34.11,252.91 33.38,253.64 33.38,254.06 C232.1
UNNAMED_11_ADHMC7044_I155_CLKOUT6N: length 38.5
  BOTTOM w0.133: C233.1 35.13,253.69 34.54,253.1 34.54,249.15 32.79,247.4 22.61,247.4 17.49,242.28 17.49,229.05 U1B.28
UNNAMED_11_ADHMC7044_I155_CPOUT2: length 5.4
  BOTTOM w0.191: U1B.50 21.95,220.59 22.28,220.26 22.28,220.11 22.5,219.89 25.21,219.89 C126.1 25.24,218.94 C127.1
UNNAMED_11_ADHMC7044_I155_GPIO2: length 2.8
  BOTTOM w0.191: R4.1 22.2,218.59 21.56,219.24 U1B.52
UNNAMED_11_ADHMC7044_I155_LDOBYP2: length 4.1
  BOTTOM w0.191: U1B.8 9.34,223.59 8.61,222.86 8.13,222.86 C99.1
UNNAMED_11_ADHMC7044_I155_LDOBYP3: length 4
  BOTTOM w0.191: C101.1 8.57,223.58 9.08,224.09 U1B.9
UNNAMED_11_ADHMC7044_I155_LDOBYP4: length 6.7
  BOTTOM w0.191: U1B.11 11.28,225.09 11.17,224.98 10.3,224.98 10.23,224.91 9.49,224.91 9.42,224.98 8.6,224.98 7.47,226.11 C212.2 7.09,226.73 C103.1
UNNAMED_11_ADHMC7044_I155_LDOBYP5: length 4.6
  BOTTOM w0.191: U1B.12 11.14,225.59 10.92,225.37 10.14,225.37 10.07,225.3 9.65,225.3 9.58,225.37 9.05,225.37 8.05,226.37 8.05,226.69 C212.1
UNNAMED_11_ADHMC7044_I155_LDOBYP6: length 1.7
  BOTTOM w0.191: U1B.46 21.49,222.55 22.33,222.55 22.72,222.94 C107.1
UNNAMED_11_ADHMC7044_I155_LDOBYP7: length 1.8
  BOTTOM w0.191: U1B.49 21.53,221.16 22.17,221.16 22.8,220.53 C110.1
UNNAMED_11_ADHMC7044_I155_OSCIN: length 1.4
  BOTTOM w0.191: U1B.47 22.75,222.09 C214.2
UNNAMED_11_ADHMC7044_I155_OSCINN: length 1.4
  BOTTOM w0.191: C215.2 22.65,221.56 22.54,221.56 22.51,221.59 U1B.48
UNNAMED_11_ADHMC7044_I155_RESET: length 5.4
  BOTTOM w0.191: U1B.5 10.45,222.09 10.13,221.76 10.12,221.76 8.12,219.77 R9.1
UNNAMED_11_ADHMC7044_I155_SCLK: length 1.9
  BOTTOM w0.191: U1B.19 13.11,229.72 12.55,230.28 R413.2
UNNAMED_11_ADHMC7044_I155_SDATA: length 1.7
  BOTTOM w0.191: U1B.20 13.61,229.9 13.44,230.07 R410.2
UNNAMED_11_ADHMC7044_I155_SLEN: length 2
  BOTTOM w0.191: U1B.18 12.61,229.38 11.66,230.33 R514.2
UNNAMED_11_ADHMC7044_I155_VCC1VCO: length 5.4
  BOTTOM w0.191: C218.2 7.18,225.25 E7.2 9.26,224.59 9.33,224.52 10.39,224.52 10.47,224.59 U1B.10
UNNAMED_11_ADHMC7044_I155_VCC2OUT: length 2.1
  BOTTOM w0.191: U1B.17 11.34,228.09 11.32,228.07 10.58,228.07 C219.2 10.39,228.26 E1.2
UNNAMED_11_ADHMC7044_I155_VCC3SYSREF: length 3.5
  TOP w0.191: E8.1 14.58,230.34 v1(14.16,229.92)
  BOTTOM w0.191: 14.16,229.98 14.11,229.92 v1(14.16,229.92) ; 14.16,229.98 14.58,230.39 C220.2 ; 14.16,229.98 v1(14.16,229.92) ; v1(14.16,229.92) 14.11,229.86 U1B.21
UNNAMED_11_ADHMC7044_I155_VCC4OUT: length 3
  TOP w0.191: v1(16.61,230.66) 16.61,230.67 E10.1
  BOTTOM w0.191: C221.2 16.61,230.67 v1(16.61,230.66) 16.61,230.41 16.69,230.33 16.69,229.54 16.61,229.46 U1B.26
UNNAMED_11_ADHMC7044_I155_VCC5PLL1: length 3.2
  TOP w0.191: E14.1 20.29,226.58 v1(20.3,226.59)
  BOTTOM w0.191: v1(20.3,226.59) U1B.38 21.47,226.59 C223.2
UNNAMED_11_ADHMC7044_I155_VCC6OSCOUT: length 2.3
  BOTTOM w0.191: E9.1 22.81,224.7 C226.2 22.78,224.71 22.41,225.09 U1B.41
UNNAMED_11_ADHMC7044_I155_VCC7PLL2: length 2.6
  BOTTOM w0.191: U1B.51 21.46,219.97 22.07,219.35 22.82,219.35 C229.1 23.51,219.37 E13.1
UNNAMED_11_ADHMC7044_I155_VCC8OUT: length 2.4
  TOP w0.191: E11.1 18.14,218.47 v1(18.39,218.21)
  BOTTOM w0.191: C228.1 v1(18.39,218.21) 18.11,218.49 U1B.57
UNNAMED_11_ADHMC7044_I155_VCC9OUT: length 3.3
  BOTTOM w0.191: U1B.68 12.05,219.24 11.42,218.61 C227.1 11.4,217.56 E12.1
UNNAMED_11_CAP_I254_N2: length 1
  BOTTOM w0.191: C127.2 26.81,218.72 R10.1
UNNAMED_11_CAP_I257_N2: length 1.2
  BOTTOM w0.191: R11.1 20.94,231.63 C129.2
UNNAMED_11_CAP_I291_N1: length 5.7
  BOTTOM w0.191: E2B.2 34.11,232.13 C104.1 34.13,233.2 C100.1 34.13,234.89 34.12,234.9 C208.1 31.94,235.61 Y1.4
UNNAMED_11_CAP_I307_N2: length 1
  BOTTOM w0.191: C213.2 23.46,229.31 R3.1
UNNAMED_11_CAP_I323_N1: length 10.1
  TOP w0.191: v1(22.75,228.3) 23.83,227.22 23.87,227.22 24.15,226.94 24.15,226.9 25.45,225.6 v1(25.45,222.71)
  BOTTOM w0.191: v1(25.45,222.71) 25.31,222.71 25.06,222.46 24.8,222.46 24.63,222.29 24.63,222.2 R1.2 24.02,222.02 C214.1 ; R3.2 v1(22.75,228.3)
UNNAMED_11_CNBNC2P_I350_CNTR: length 2
  TOP w0.191: J3.1 139.29,10.24 R590.2
UNNAMED_11_CNBNC5P_I351_CNTR: length 9.3
  TOP w0.191: R526.2 24.05,275.36 25.35,276.66 31.09,276.66 EXT_SYS_P.1
UNNAMED_11_CNBNC5P_I353_CNTR: length 9.8
  TOP w0.191: R15.2 22.81,275.41 21.59,276.63 15.24,276.63 EXT_SYS_N.1
UNNAMED_11_CNBNC5P_I356_CNTR: length 23.1
  TOP w0.191: R527.2 15.6,247.09 8.71,253.97 EXT_TRIG.1
UNNAMED_11_RES_I294_N1: length 24.1
  TOP w0.191: v1(26.59,221.72) 29.42,224.55 v1(29.42,240.71)
  BOTTOM w0.191: R1.1 25.32,221.72 v1(26.59,221.72) ; Y1.3 v1(29.42,240.71)
UNNAMED_14_ADLTC4210_I253_GATE: length 13.6
  TOP w0.203: R488.1 R489.2 197.88,273.41 v1(197.88,262.98)
  BOTTOM w0.203: U39.4 v1(197.88,262.98)
UNNAMED_14_ADLTC4210_I253_ON: length 36.3
  TOP w0.191: S4.5 190.12,268.81 190.12,260.29 Q7.2 190.66,258.99 R55.2 190.16,256.14 v1(190.16,255.37) PWRDBG.2 188.09,248.51 v1(188.09,248.51)
  BOTTOM w0.191: C640.2 197.76,258.78 197.76,259.92 198.2,260.36 U39.3 ; C640.2 193.56,258.78 v1(190.16,255.37) ; C640.2 R485.2
UNNAMED_14_ADLTC4210_I253_TIMER: length 2.6
  BOTTOM w0.191: R486.1 200.81,258.77 C607.2 200.8,260.32 U39.1
UNNAMED_14_ADLTC4210_I253_VCC: length 4.1
  BOTTOM w0.191: v1(203.84,261.84) 201,261.84 200.76,262.07 U39.6
UNNAMED_14_CAP_I258_N2: length 0.8
  TOP w0.191: C608.2 R489.1
UNNAMED_14_CAP_I283_N2: length 1.3
  TOP w0.191: R483.1 218.94,256.73 C136.2
UNNAMED_14_CN3P_I249_N2: length 6.8
  TOP w0.191: 225.2,224.66 R643.2 ; 231.46,225.23 P23.2
  TOP w0.508: 225.2,224.66 225.78,225.23 D1.C 231.46,225.23
UNNAMED_14_CN3P_I249_N3: length 0
  TOP w0.191: 223.3,221.96 Q17.3
UNNAMED_14_DIO_I266_N: length 1.4
  BOTTOM w0.191: R486.2 200.8,256.74 D5.C
UNNAMED_14_DIO_I266_P: length 7.2
  TOP w0.191: v1(197.33,253.09) 197.33,254.76 197.06,254.49 R487.2
  BOTTOM w0.191: D5.A 199.33,253.72 198.69,253.09 v1(197.33,253.09)
UNNAMED_14_DIOLED_I232_P: length 1.4
  TOP w0.191: DS3.A R344.1
UNNAMED_14_DIOLED_I233_P: length 1.4
  TOP w0.191: R345.1 DS4.A
UNNAMED_14_DIOLED_I234_P: length 1.4
  TOP w0.191: DS5.A R346.1
UNNAMED_14_DIOLED_I235_P: length 1.4
  TOP w0.191: R347.1 DS6.A
UNNAMED_14_DIOLED_I236_P: length 1.4
  TOP w0.191: R348.1 DS7.A
UNNAMED_14_DIOLED_I237_P: length 1.4
  TOP w0.191: R349.1 DS8.A
UNNAMED_14_DIOLED_I238_P: length 1.4
  TOP w0.191: DS9.A R350.1
UNNAMED_14_DIOLED_I239_P: length 1.4
  TOP w0.191: DS10.A R351.1
UNNAMED_14_DIOLED_I240_P: length 1.4
  TOP w0.191: DS11.A R352.1
UNNAMED_14_DIOLED_I241_P: length 1.4
  TOP w0.191: R353.1 DS12.A
UNNAMED_14_DIOLED_I242_P: length 1.4
  TOP w0.191: DS13.A R354.1
UNNAMED_14_DIOLED_I243_P: length 1.4
  TOP w0.191: R355.1 DS14.A
UNNAMED_14_DIOLED_I244_P: length 1.4
  TOP w0.191: DS15.A R356.1
UNNAMED_14_DIOLED_I280_P: length 1.4
  TOP w0.191: R65.1 DS16.A
UNNAMED_14_RES_I259_N2: length 1.7
  TOP w0.191: R488.2 200.87,275.02 Q16.4
UNNAMED_14_RES_I262_N1: length 16.4
  TOP w0.191: Q7.3 191.61,258.17 ; 191.61,258.17 R484.1 ; 191.61,258.17 191.66,258.11 R55.1 192.16,256.14 PWRDBG.1 v1(194.18,246.48) 194.21,246.46
UNNAMED_14_RES_I274_N1: length 6.6
  TOP w0.191: S4.3 S4.6 194.03,268.02 R64.1
UNNAMED_14_RES_I288_N2: length 2.4
  TOP w0.191: S4.1 R482.2
UNNAMED_14_RES_I322_N2: length 14.6
  TOP w0.191: Q7.1 192.04,260.94 C639.2 R529.2 192.46,262.63 192.46,271.09 S4.2
UNNAMED_15_ADLTM4681_I3_ALERT01N: length 63.6
  TOP w0.203: U33.W8 220.34,67.28 v4(220.8,67.74) ; U33.C11 216.96,50.83 216.94,50.83 216.92,50.81 v4(216.89,50.81)
  L3_SIGNAL w0.203: v3(229.36,71.02) 229.36,70.59 230.66,69.29 230.66,50.6 230.27,50.21 230.27,48.01 v4(232.28,46)
  L24_SIGNAL w0.203: v4(232.28,46) 232.28,45.12 230.42,43.26 221.03,43.26 217.76,46.53 217.76,49.14 217.71,49.19 217.71,49.26 217.54,49.42 217.54,49.78 216.89,50.43 v4(216.89,50.81) ; v4(220.8,67.74) 220.32,68.23 220.32,70.66 221.18,71.53 228.85,71.53 v3(229.36,71.02)
  BOTTOM w0.203: R528.1 v4(232.28,46)
UNNAMED_15_ADLTM4681_I3_ASEL01: length 8.2
  BOTTOM w0.191: v4(219.35,50.22) 219.02,49.89 219.02,47.98 216.15,45.11 R449.2
UNNAMED_15_ADLTM4681_I3_ASEL23: length 15.6
  TOP w0.191: U33.AA10 v4(218.82,69.62)
  BOTTOM w0.191: R450.2 208.79,77.7 210.9,75.59 214.33,75.59 217.27,72.64 217.27,71.17 v4(218.82,69.62)
UNNAMED_15_ADLTM4681_I3_COMP0A: length 3.2
  TOP w0.191: v4(217.68,54.76) 217.68,54.89 217.35,55.22 ; U33.G9 219.21,55.35 218.83,55.35 218.8,55.38 218.8,55.4 218.53,55.67 218.16,55.67 217.7,55.22 217.35,55.22 ; 217.35,55.22 U33.G11
  BOTTOM w0.191: v4(217.68,54.76) 217.68,54.77 C518.2
UNNAMED_15_ADLTM4681_I3_COMP0B: length 1.6
  TOP w0.191: U33.F9 v4(218.68,54.88) U33.G10
  BOTTOM w0.191: v4(218.68,54.88) 218.8,54.76 C519.2
UNNAMED_15_ADLTM4681_I3_COMP2A: length 0.4
  BOTTOM w0.191: v4(220.34,64.22) 220.34,64.28 C520.2
UNNAMED_15_ADLTM4681_I3_COMP2B: length 0.3
  BOTTOM w0.191: C521.2 219.15,64.22 v4(219.35,64.22)
UNNAMED_15_ADLTM4681_I3_COMP3A: length 0.1
  BOTTOM w0.191: C572.2 v4(217.3,66.18)
UNNAMED_15_ADLTM4681_I3_COMP3B:
  vias: v4(217.35,67.22)
UNNAMED_15_ADLTM4681_I3_FAULT0N: length 104.7
  TOP w0.203: v4(218.35,67.22) U33.V10 ; U33.A10 U33.A11 v4(216.91,48.78)
  L3_SIGNAL w0.203: v4(235.13,43.84) 235.46,43.84 237.08,45.47 237.08,79.45 v3(237.12,79.49)
  L14_POWER w0.203: v3(237.12,79.49) 237.11,79.48 237.11,76.5 236.58,75.97 v4(233.35,75.97)
  L24_SIGNAL w0.203: v4(216.91,48.78) 216.91,43.61 218.12,42.41 232.83,42.41 234.26,43.84 v4(235.13,43.84) ; v4(218.35,67.22) 217.53,68.03 217.53,70.89 217.35,71.07 217.35,73.81 216.64,74.52 216.64,75.97 217.04,76.38 217.04,76.48 217.35,76.78 217.45,76.78 220.15,79.49 v3(237.12,79.49)
  BOTTOM w0.203: v4(233.35,75.97) R428.1 234.69,75.96 R62.2
UNNAMED_15_ADLTM4681_I3_INTVCC01: length 0.6
  TOP w0.191: U33.J9 218.95,57.61 v4(218.95,57.68)
  BOTTOM w0.191: v4(218.95,57.68) C574.1
UNNAMED_15_ADLTM4681_I3_INTVCC23: length 0.7
  TOP w0.191: v4(217.82,62.65) 217.96,62.51 U33.P10
UNNAMED_15_ADLTM4681_I3_PGOOD0: length 28.5
  TOP w0.191: U33.H8 220.29,56.27 219.4,56.27 U33.H9 219.09,55.96 v4(218.96,55.96)
  L24_SIGNAL w0.108: 220.17,49.87 220.17,51.03 219.96,51.23 219.56,51.23 219.33,51.46
  L24_SIGNAL w0.203: v4(233.3,51.71) 232.88,51.71 228.49,47.32 219.84,47.32 219.48,47.68 219.48,49.19 220.17,49.87 ; 219.33,51.46 219.33,55.6 v4(218.96,55.96)
  BOTTOM w0.203: R530.2 234.05,51.7 R427.1 v4(233.3,51.71)
UNNAMED_15_ADLTM4681_I3_PGOOD2: length 26.8
  L5_MIXED w0.133: 218.35,63.23 218.85,63.73 218.85,64.5 220.22,65.87
  L5_MIXED w0.203: v4(218.35,63.22) 218.35,63.23 ; v1(235,69.24) 234.61,69.64 234.17,69.64 231.55,72.26 222.05,72.26 220.22,70.43 220.22,65.87
  BOTTOM w0.191: R426.1 234.69,71.13 R531.2
  BOTTOM w0.203: R531.2 234.69,69.55 v1(235,69.24)
UNNAMED_15_ADLTM4681_I3_PGOOD3: length 26
  L5_MIXED w0.203: v4(218.35,64.22) 218.42,64.29 218.42,64.88 219.81,66.27 219.81,71.07 221.49,72.75 231.37,72.75 232.26,73.63 233.96,73.63 v4(235.18,72.42)
  BOTTOM w0.203: v4(235.18,72.42) R532.2 234.69,73.54 R425.1
UNNAMED_15_ADLTM4681_I3_RUNP: length 16.8
  TOP w0.114: 218.89,61.74 217.99,61.74
  TOP w0.133: 219.64,56.73 218.94,56.73
  TOP w0.191: U33.N11 U33.P11 217.39,62.21 217.86,61.74 217.99,61.74 ; 218.35,56.74 U33.J10 ; 218.35,56.74 U33.H10 ; 218.35,56.74 218.92,56.74 218.94,56.73 ; 219.35,61.75 U33.N9 ; 219.35,61.75 U33.P9 219.79,62.66 v4(219.81,62.66) U33.R9 ; 219.35,61.75 218.9,61.75 218.89,61.74 ; 219.64,56.73 219.86,56.73 U33.J8 220.34,57.38 v4(220.07,57.66)
  L24_SIGNAL w0.191: v4(219.81,62.66) 219.35,62.2 219.35,58.37 v4(220.07,57.66)
  BOTTOM w0.191: 220.4,57.32 220.4,57.1 219.98,57.1 C517.1 ; 220.4,57.32 220.54,57.19 R578.2 ; 220.4,57.32 v4(220.07,57.66)
UNNAMED_15_ADLTM4681_I3_SCL01: length 110.5
  TOP w0.203: U33.W9 v4(218.95,67.72)
  L3_SIGNAL w0.254: v3(227.99,116.41) 227.99,115.8 227.36,115.16 227.36,104.28 229.05,102.59 229.05,86.89 231.08,84.86 231.08,84.82 231.17,84.73 231.17,74.55 232.26,73.46 v1(232.26,72.39) 232.26,71 232.64,70.61 232.64,50.09 v4(233.3,49.43)
  L24_SIGNAL w0.254: v1(232.26,72.39) 231.96,72.69 220.23,72.69 219.49,71.94 219.49,68.25 v4(218.95,67.72) ; v4(218.35,52.22) 218.8,51.76 218.8,51.43 218.81,51.41 218.81,49.88 218.94,49.76 218.94,49.69 218.99,49.64 218.99,47.45 219.62,46.81 229.59,46.81 232.21,49.43 v4(233.3,49.43)
  BOTTOM w0.203: R430.1 v4(233.3,49.43)
  BOTTOM w0.508: v3(227.99,116.41) 228.94,116.41 R149.1
UNNAMED_15_ADLTM4681_I3_SDA01: length 114.7
  TOP w0.191: U33.V8 v4(220.79,66.64)
  L3_SIGNAL w0.191: v4(233.3,48.29) 232.24,49.35 232.24,49.89 232.22,49.91 232.22,70.2 231.42,70.99 v4(231.42,71.53) 231.42,73.56 230.66,74.32 230.66,84.68 228.63,86.71 228.63,102.41 226.93,104.11 226.93,115.34 227.41,115.81 227.41,119.84 v3(227.91,120.35)
  L24_SIGNAL w0.191: v4(218.35,51.22) 218.35,49.75 218.52,49.58 218.52,49.51 218.56,49.47 218.56,47.17 219.43,46.3 230.45,46.3 232.46,48.31 232.75,48.31 232.77,48.29 v4(233.3,48.29)
  L24_SIGNAL w0.203: v4(231.42,71.53) 230.89,72.06 220.62,72.06 219.91,71.35 219.91,67.51 v4(220.79,66.64)
  BOTTOM w0.203: v4(233.3,48.29) R431.1
  BOTTOM w0.508: R374.1 228.89,120.35 v3(227.91,120.35)
UNNAMED_15_ADLTM4681_I3_SYNC01: length 70.2
  TOP w0.203: U33.V9 v4(218.95,66.7)
  L3_SIGNAL w0.203: v4(233.3,47.14) 231.08,49.36 231.08,49.87 231.63,50.42 231.63,70 230.73,70.89 v1(230.73,73.3) ; v4(218.95,66.7) 219.1,66.7 219.51,67.11 v1(219.51,74.22)
  L24_SIGNAL w0.203: v4(217.35,52.22) 217.35,50.55 217.95,49.95 217.95,49.59 218.11,49.42 218.11,49.36 218.17,49.3 218.17,47.01 219.27,45.91 231.35,45.91 232.59,47.14 v4(233.3,47.14) ; v1(219.51,74.22) 220.42,73.3 v1(230.73,73.3)
  BOTTOM w0.203: R432.1 v4(233.3,47.14)
UNNAMED_15_ADLTM4681_I3_VBIAS: length 0.6
  TOP w0.191: U33.N10 218.46,61.22 v4(218.82,60.86)
UNNAMED_15_ADLTM4681_I3_VOUT0CFG: length 10.2
  TOP w0.191: v4(220.45,48.62) 220.44,48.63 220.44,49.12 U33.A8 U33.B8
  BOTTOM w0.191: v4(220.45,48.62) 220.45,46.49 217.99,44.03 R438.2 219.12,42.26 R444.2
UNNAMED_15_ADLTM4681_I3_VOUT2CFG: length 13.8
  TOP w0.191: v4(220.76,69.66) 220.73,69.62 220.34,69.22 U33.AA8
  BOTTOM w0.191: R445.2 214.97,79.46 R439.2 216.1,78.62 217.4,77.32 218.01,77.32 220.29,75.03 220.29,74.42 220.57,74.14 220.57,69.85 v4(220.76,69.66)
UNNAMED_15_ADLTM4681_I3_VOUT3CFG: length 11.2
  TOP w0.191: v1(218.59,78.66) 220.34,76.91 U33.AB8
  BOTTOM w0.191: v1(218.59,78.66) 218.59,79.37 R440.2 217.38,79.46 R447.2
UNNAMED_15_ADLTM4681_I3_VTRIM0CFG: length 14.1
  TOP w0.191: v4(219.71,50.83) 219.35,51.19 U33.C9 U33.D9
  BOTTOM w0.191: R441.1 213.79,42.28 213.82,42.26 214.76,42.26 R435.2 214.77,45.38 217.91,48.51 217.91,49.94 218.97,51 219.53,51 v4(219.71,50.83)
UNNAMED_15_ADLTM4681_I3_VTRIM2CFG: length 15.6
  TOP w0.191: U33.AB10 218.78,70.65 v1(218.78,72.16)
  BOTTOM w0.191: R436.2 210.25,78.44 R442.1 210.13,77.71 211.12,76.71 214.55,76.71 218.03,73.23 218.03,72.91 v1(218.78,72.16)
UNNAMED_15_ADLTM4681_I3_VTRIM3CFG: length 13.2
  TOP w0.191: U33.AB9 219.35,72.78 v1(218.83,73.29)
  BOTTOM w0.191: v1(218.83,73.29) 218.83,73.77 214.78,77.83 214.02,77.83 213.68,78.16 R437.2 212.55,79.46 212.54,79.44 212.54,79.44 R443.1
UNNAMED_15_RES_I202_N2: length 2.8
  BOTTOM w0.191: Q14.1 222.91,113.88 R446.2 222.73,113.84 R490.1
UNNAMED_15_RES_I206_N2: length 3
  BOTTOM w0.191: 222.72,110.47 222.72,110.36 222.7,110.34 223.71,110.34 Q15.1 ; 222.72,110.47 R491.1 ; 222.72,110.47 R448.2
UNNAMED_32_CAP_I380_N2: length 1.5
  TOP w0.191: C660.2 C661.2 C662.2
UNNAMED_33_CAP_I144_N1: length 1.7
  TOP w0.191: C237.1 R556.1
UNNAMED_34_AD90888T8RSEB0_I517_VPLL1P0VREG:
  vias: v1(103.19,135.83) v1(103.73,135.31) v1(104.06,136.02) v4(122.3,129.73)
UNNAMED_34_AD90888T8RSEB0_I517_VSPLL1P0VREG: length 15.5
  BOTTOM w0.108: v4(123.1,119.33) 123.51,119.74 136.06,119.74 C429.1
UNNAMED_34_CAP_I450_N1: length 0.7
  BOTTOM w0.191: C619.1 R559.2
UNNAMED_34_CAP_I453_N1: length 0.7
  BOTTOM w0.191: C620.1 R560.2
UNNAMED_34_CAP_I473_N1: length 0.6
  TOP w0.191: R566.2 C626.1
UNNAMED_34_CAP_I476_N1: length 0.7
  TOP w0.191: R567.2 182.74,78.75 C627.1
UNNAMED_34_CAP_I479_N1: length 1.2
  TOP w0.191: C624.1 R564.1
UNNAMED_34_CAP_I483_N1: length 0.8
  TOP w0.191: R565.1 195.13,85.31 C625.1
UNNAMED_34_CAP_I486_N1: length 0.8
  BOTTOM w0.191: C628.1 160.88,248.07 160.87,248.08 R568.1
UNNAMED_34_CAP_I490_N1: length 0.6
  TOP w0.191: R563.1 C623.1
UNNAMED_34_CAP_I504_N1: length 1.5
  BOTTOM w0.191: C436.1 169.43,230.33 R557.2
UNNAMED_34_CAP_I505_N1: length 1.5
  BOTTOM w0.191: C439.1 169.61,234.49 169.61,233.25 R558.2
UNNAMED_35_CAP_I439_N1: length 1.3
  BOTTOM w0.191: C635.1 R575.2
UNNAMED_35_CAP_I451_N1: length 1.3
  TOP w0.191: R576.2 75.88,101.19 C636.1
UNNAMED_35_CAP_I457_N1: length 1.3
  BOTTOM w0.191: R570.1 202.5,168.25 202.48,168.26 C630.1
UNNAMED_35_CAP_I466_N1: length 0.8
  TOP w0.191: R571.1 179.78,54.85 C631.1
UNNAMED_35_CAP_I468_N1: length 0.9
  TOP w0.191: C633.1 229.94,168.35 R573.2
UNNAMED_35_CAP_I470_N1: length 0.7
  TOP w0.191: R574.2 225.05,167.94 C634.1
UNNAMED_35_CAP_I484_N1: length 1.2
  BOTTOM w0.191: R569.1 201.52,157.71 C356.1
UNNAMED_35_CAP_I524_N1: length 0.7
  BOTTOM w0.191: C632.1 165.93,203.63 R572.2
UNNAMED_36_ADF4382_I312_CP: length 2.9
  BOTTOM w0.191: U30.47 126.2,159.8 126.48,160.08 R291.2
UNNAMED_36_ADF4382_I312_CSB: length 8.8
  BOTTOM w0.191: R584.1 119.07,156.92 119.11,156.96 U30.32
UNNAMED_36_ADF4382_I312_REFN: length 1.6
  BOTTOM w0.191: C115.2 124.2,160.66 U30.43
UNNAMED_36_ADF4382_I312_REFP: length 1.6
  BOTTOM w0.191: C116.2 123.7,160.53 U30.42
UNNAMED_36_ADF4382_I312_RFOUT2N: length 3.6
  BOTTOM w0.191: U30.15 125.7,152.55 125.67,152.52 125.67,152.13 125.7,152.1 126.02,151.78 L1.2 126.02,149.71 C317.2
UNNAMED_36_ADF4382_I312_RFOUT2P: length 3.7
  BOTTOM w0.191: C28.2 125.22,149.65 125.29,149.72 L10.1 125.29,151.55 124.7,152.13 U30.17
UNNAMED_36_ADF4382_I312_SCLK: length 9.3
  BOTTOM w0.191: U30.34 116.89,157.96 115.65,159.21 R582.1
UNNAMED_36_ADF4382_I312_SDIO: length 9
  BOTTOM w0.191: U30.33 116.12,157.46 115.52,158.06 R583.1
UNNAMED_36_ADF4382_I312_SDO: length 10
  BOTTOM w0.191: U30.35 117.99,158.46 116,160.45 R581.1
UNNAMED_36_ADF4382_I312_SYNCN: length 165.9
  L24_SIGNAL w0.108: v9(118.72,161.82) 118.54,162 118.03,162 116.22,163.81 116.22,178.24 117.11,179.12 117.11,223.32 114.45,225.98 105.3,225.98 79.19,252.1 34.64,252.1 34.44,252.3 34.44,252.95 34.59,253.1 v9(34.59,253.8)
  BOTTOM w0.133: v9(118.72,161.82) 118.72,161.68 arc(118.74,161.58) 118.79,161.5 119.61,160.68 arc(119.78,160.57) 119.97,160.53 120,160.5 121.4,160.5 121.75,160.3 121.78,160.27 arc(121.78,160.27) 121.79,160.26 121.85,160.2 arc(121.88,160.18) 121.9,160.15 arc(121.94,160.11) 121.97,160.08 122.04,160.01 arc(122.08,159.95) 122.1,159.89 122.18,159.8 122.18,159.73 arc(122.2,159.68) 122.2,159.63 U30.39 ; R293.1 v9(34.59,253.8)
UNNAMED_36_ADF4382_I312_SYNCP: length 166.1
  L24_SIGNAL w0.108: v9(118.01,161.12) 117.7,161.42 117.7,161.82 116.81,162.71 116.81,162.8 115.93,163.69 115.93,178.36 116.81,179.25 116.81,223.2 114.33,225.69 105.18,225.69 79.07,251.8 34.25,251.8 34.14,251.91 34.14,252.95 33.99,253.1 v9(33.99,253.8)
  BOTTOM w0.133: R294.1 34.02,253.82 v9(33.99,253.8) ; v9(118.01,161.12) 118.31,161.12 arc(118.4,161.1) 118.48,161.04 119.38,160.15 arc(119.52,160.05) 119.69,160.02 121.46,160.02 121.58,159.91 arc(121.6,159.88) 121.63,159.86 121.68,159.8 121.68,159.76 arc(121.7,159.71) 121.7,159.65 U30.38
UNNAMED_36_ADF4382_I312_V5CAL: length 4.6
  BOTTOM w0.191: R288.1 129.51,153.74 127.8,155.46 U30.8
  BOTTOM w0.381: R288.1 129.53,153.52 E2.2
UNNAMED_36_ADF4382_I312_V5CP: length 10.4
  BOTTOM w0.254: 127.23,161.52 126.83,161.91 C113.2 126.83,163.09 C253.2
  BOTTOM w0.381: U30.46 125.7,159.89 126.34,160.53 126.88,160.53 127.29,160.94 127.29,161.44 127.28,161.45 127.28,161.46 127.23,161.52 ; C751.1 128.38,165.52 E3.2 128.4,164.31 128.02,163.93 127.13,163.93 126.88,163.69 C253.2
UNNAMED_36_ADF4382_I312_V5VCO: length 5.1
  BOTTOM w0.191: R288.2 129.07,152.53 128.65,152.96 128.65,154.05 127.74,154.96 U30.9
  BOTTOM w0.381: R290.1 129.51,151.45 R288.2
UNNAMED_36_ADF4382_I312_VGBIAS: length 1.5
  BOTTOM w0.191: C109.1 128.35,156.16 128.25,156.26 127.98,156.26 127.84,156.41 127.58,156.41 127.53,156.46 U30.6
UNNAMED_36_ADF4382_I312_VTUNE: length 8.1
  BOTTOM w0.191: U30.7 127.83,155.96 128.22,155.57 131.64,155.57 C242.1 132.78,155.64 133.41,156.27 R286.2
UNNAMED_36_CAP_I371_N1: length 150.1
  L24_SIGNAL w0.108: v9(70.81,268.05) 71.02,268.26 71.02,269.19 71.33,269.5 73.55,269.5 76.61,266.45 76.61,256.79 102.77,230.63 118.08,230.63 126.34,222.38 126.34,184.7 130.83,180.21 130.83,169.11 126.25,164.53 125.81,164.53 125.68,164.4 v9(125.68,164.31)
  BOTTOM w0.133: v9(70.81,268.05) 70.81,270.11 C311.2 ; C115.1 124.44,161.93 R292.1 124.44,163.71 124.64,163.9 125.27,163.9 v9(125.68,164.31)
UNNAMED_36_CAP_I372_N1: length 149.6
  L24_SIGNAL w0.108: v9(124.82,164.34) 124.82,164.38 124.92,164.49 125.24,164.49 125.5,164.75 125.61,164.75 125.69,164.83 126.13,164.83 130.53,169.23 130.53,180.09 126.04,184.58 126.04,222.25 117.96,230.33 102.64,230.33 76.31,256.67 76.31,266.32 73.42,269.21 71.49,269.21 71.32,269.03 71.32,268.13 v9(71.4,268.05)
  BOTTOM w0.133: C314.2 71.4,270.3 v9(71.4,268.05) ; C116.1 R296.2 123.42,163.05 123.42,163.7 124.05,164.34 v9(124.82,164.34)
UNNAMED_36_CAP_I396_N1: length 85.9
  L24_SIGNAL w0.108: v9(147.75,217.53) 148.76,217.53 148.87,217.42 148.87,215.34 143.59,210.06 143.59,159.27 131.53,147.22 126.23,147.22 125.8,147.65 125.8,148.51 v9(126.01,148.72)
  BOTTOM w0.133: v9(126.01,148.72) 126.14,148.84 C317.1
UNNAMED_36_CAP_I397_N1: length 87.2
  L24_SIGNAL w0.108: v9(150.57,217.53) 149.31,217.53 149.17,217.39 149.17,215.22 143.88,209.93 143.88,159.15 131.65,146.92 126.1,146.92 125.5,147.52 125.5,148.46 v9(125.22,148.74)
  BOTTOM w0.133: C28.1 v9(125.22,148.74)
UNNAMED_36_CAP_I403_N1: length 12.6
  BOTTOM w0.191: REFN.1 69.57,277.06 70.48,276.15 C312.1
UNNAMED_36_CAP_I404_N1: length 11.9
  BOTTOM w0.191: REFP.1 72.7,277.12 71.65,276.07 C313.1
UNNAMED_36_CAP_I433_N1: length 3.1
  BOTTOM w0.191: R286.1 135.09,157.71 C241.1 135.15,159.32 R287.1
UNNAMED_36_CAP_I434_N1: length 3.2
  BOTTOM w0.191: C252.1 128.62,161.1 R291.1 128.6,161.78 129.14,162.32 R315.2
UNNAMED_36_CAP_I436_N1: length 1.9
  BOTTOM w0.191: R289.2 132.67,160.72 132.67,160.72 131.75,160.72 C243.1
UNNAMED_36_CAP_I441_N2: length 1.4
  BOTTOM w0.191: R731.1 C752.2
UNNAMED_36_CAP_I444_N2: length 1.3
  BOTTOM w0.191: C751.2 126.42,168.39 R730.1
UNNAMED_36_CAP_I446_N2: length 1.5
  BOTTOM w0.191: C750.2 113.91,173.15 R729.1
UNNAMED_36_CNBNC5P_I422_CNTR: length 10.7
  BOTTOM w0.191: J12.1 34.78,259.82 34.59,259.63 R293.2
UNNAMED_36_CNBNC5P_I424_CNTR: length 11.3
  BOTTOM w0.191: R294.2 34.02,259.54 33.73,259.83 J13.1
UNNAMED_36_DIOLED_I317_P: length 58.3
  TOP w0.191: DS2.A v10(100.38,198.73)
  BOTTOM w0.191: v10(100.38,198.73) 100.38,161.67 111.83,150.23 114.64,150.23 115.19,150.77 R295.2
UNNAMED_36_RES_I357_N1: length 3
  BOTTOM w0.191: R13.1 133.41,162.53 R289.1 R287.2
UNNAMED_36_RES_I357_N2: length 1.1
  BOTTOM w0.191: R315.1 R13.2
UNNAMED_36_RES_I398_N2: length 2.3
  BOTTOM w0.191: R595.1 112.77,154.69 R318.2 112.84,154.63 Q8.2
UNNAMED_36_TRANNMOSFETV11_I414_G2: length 0.4
  BOTTOM w0.191: Q8.4 Q8.5
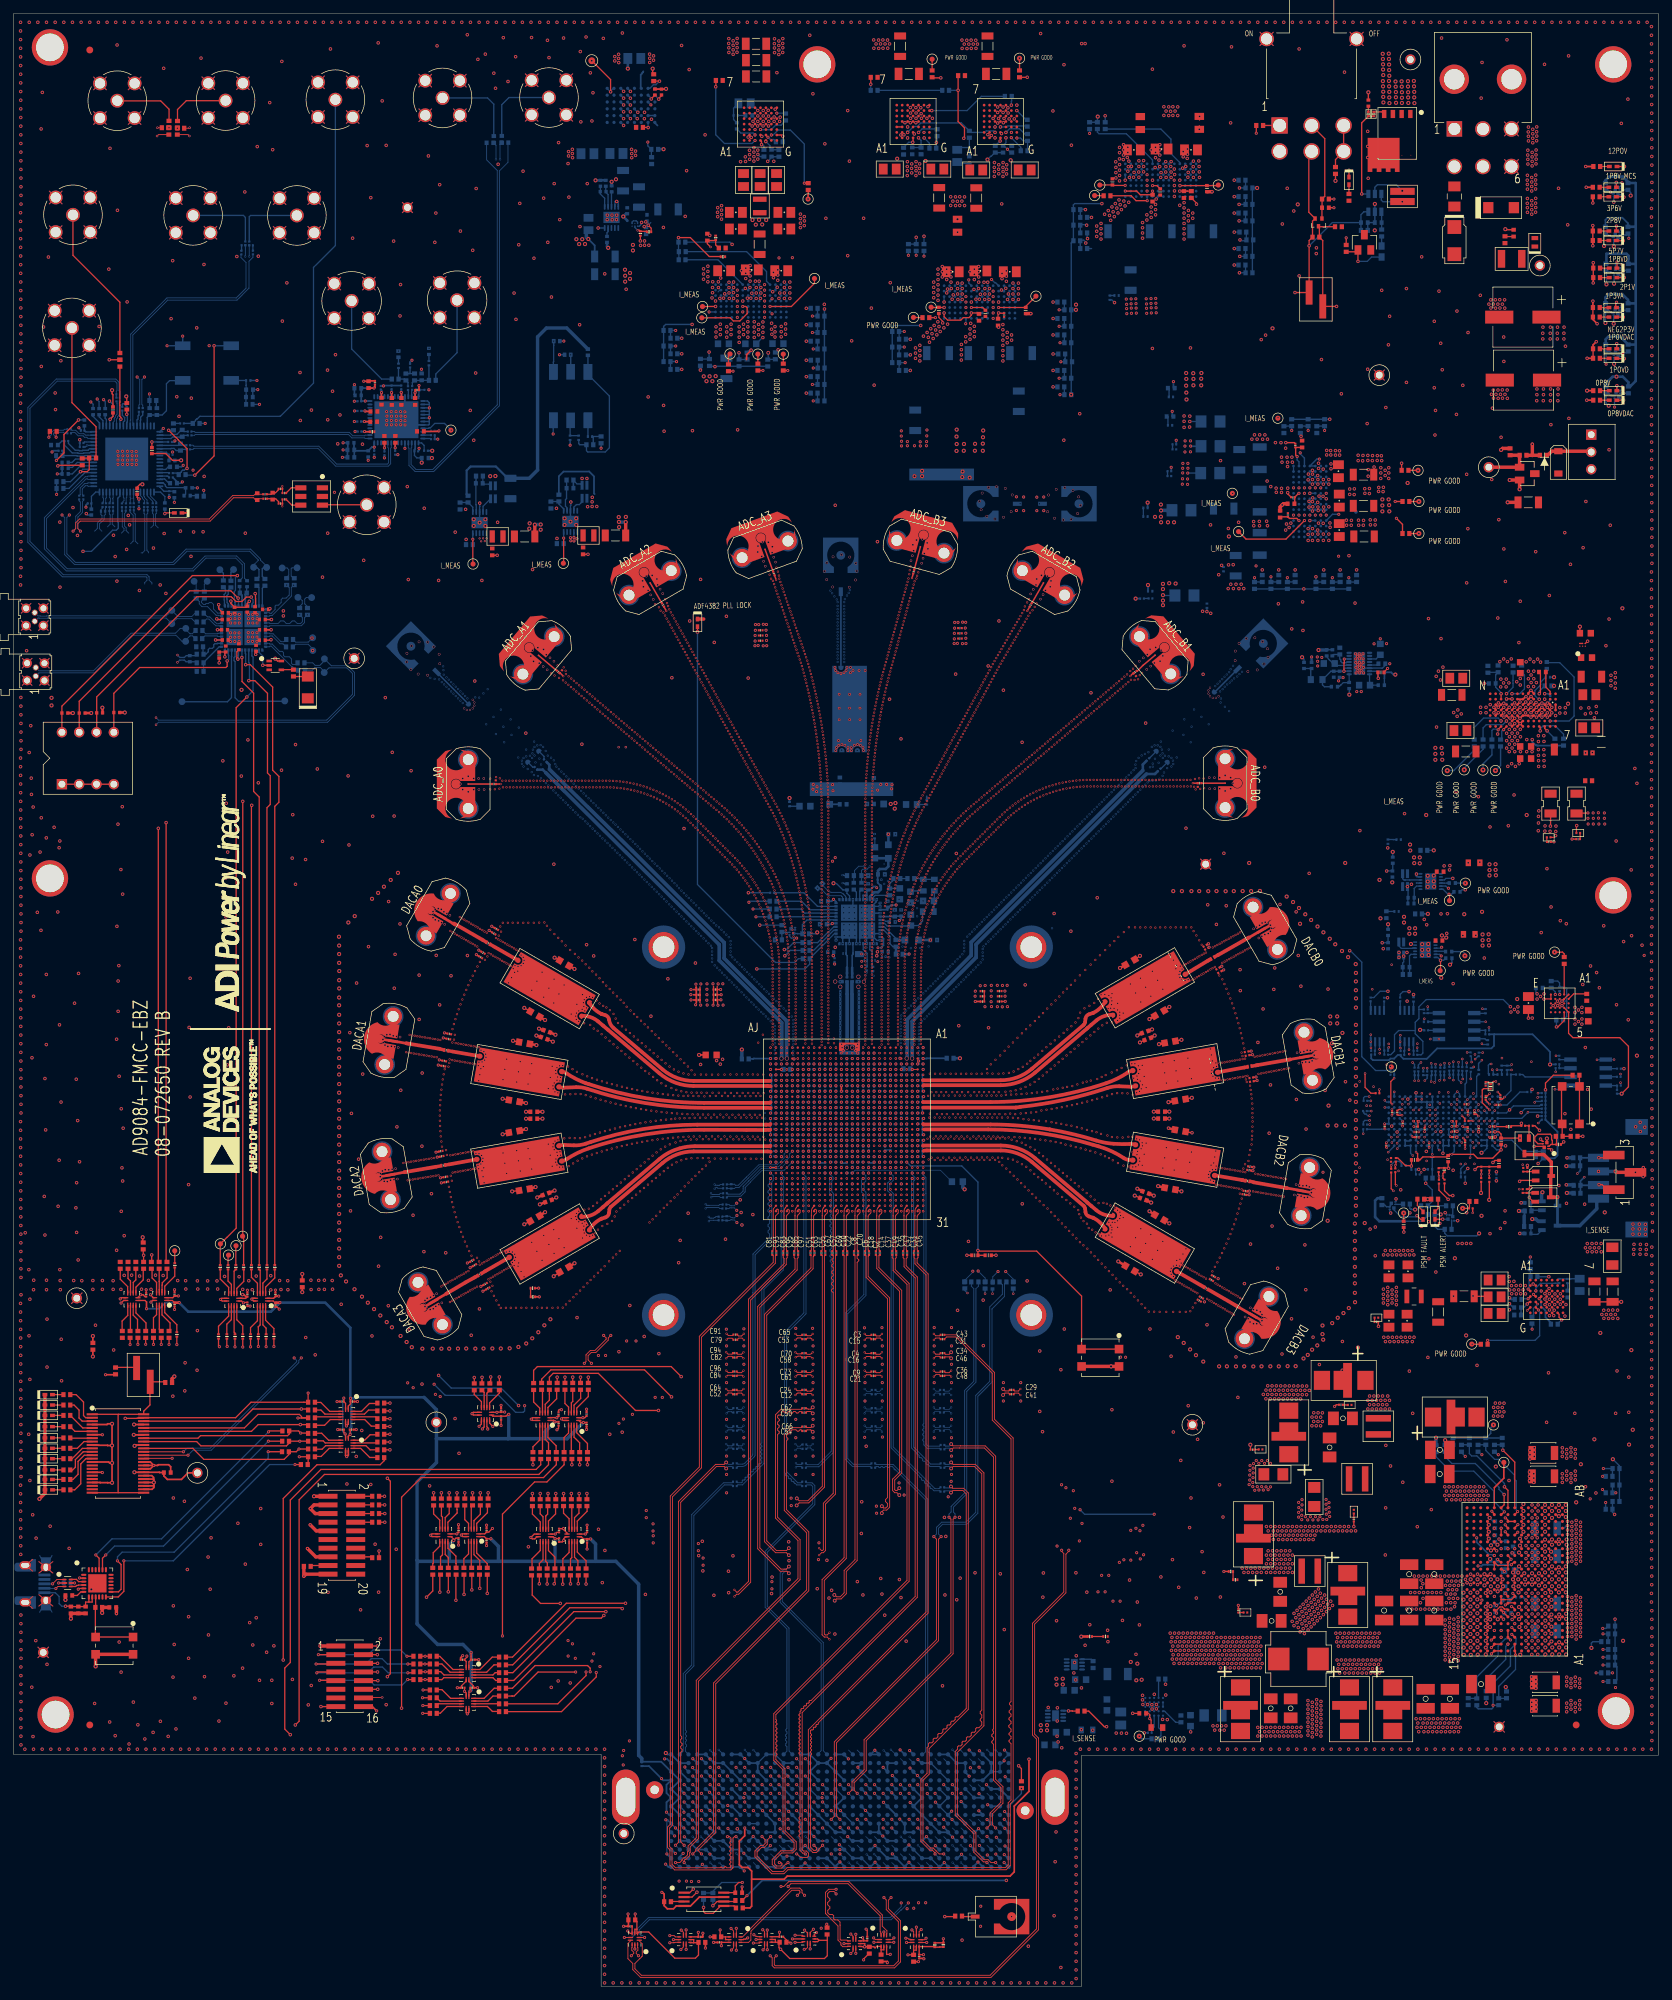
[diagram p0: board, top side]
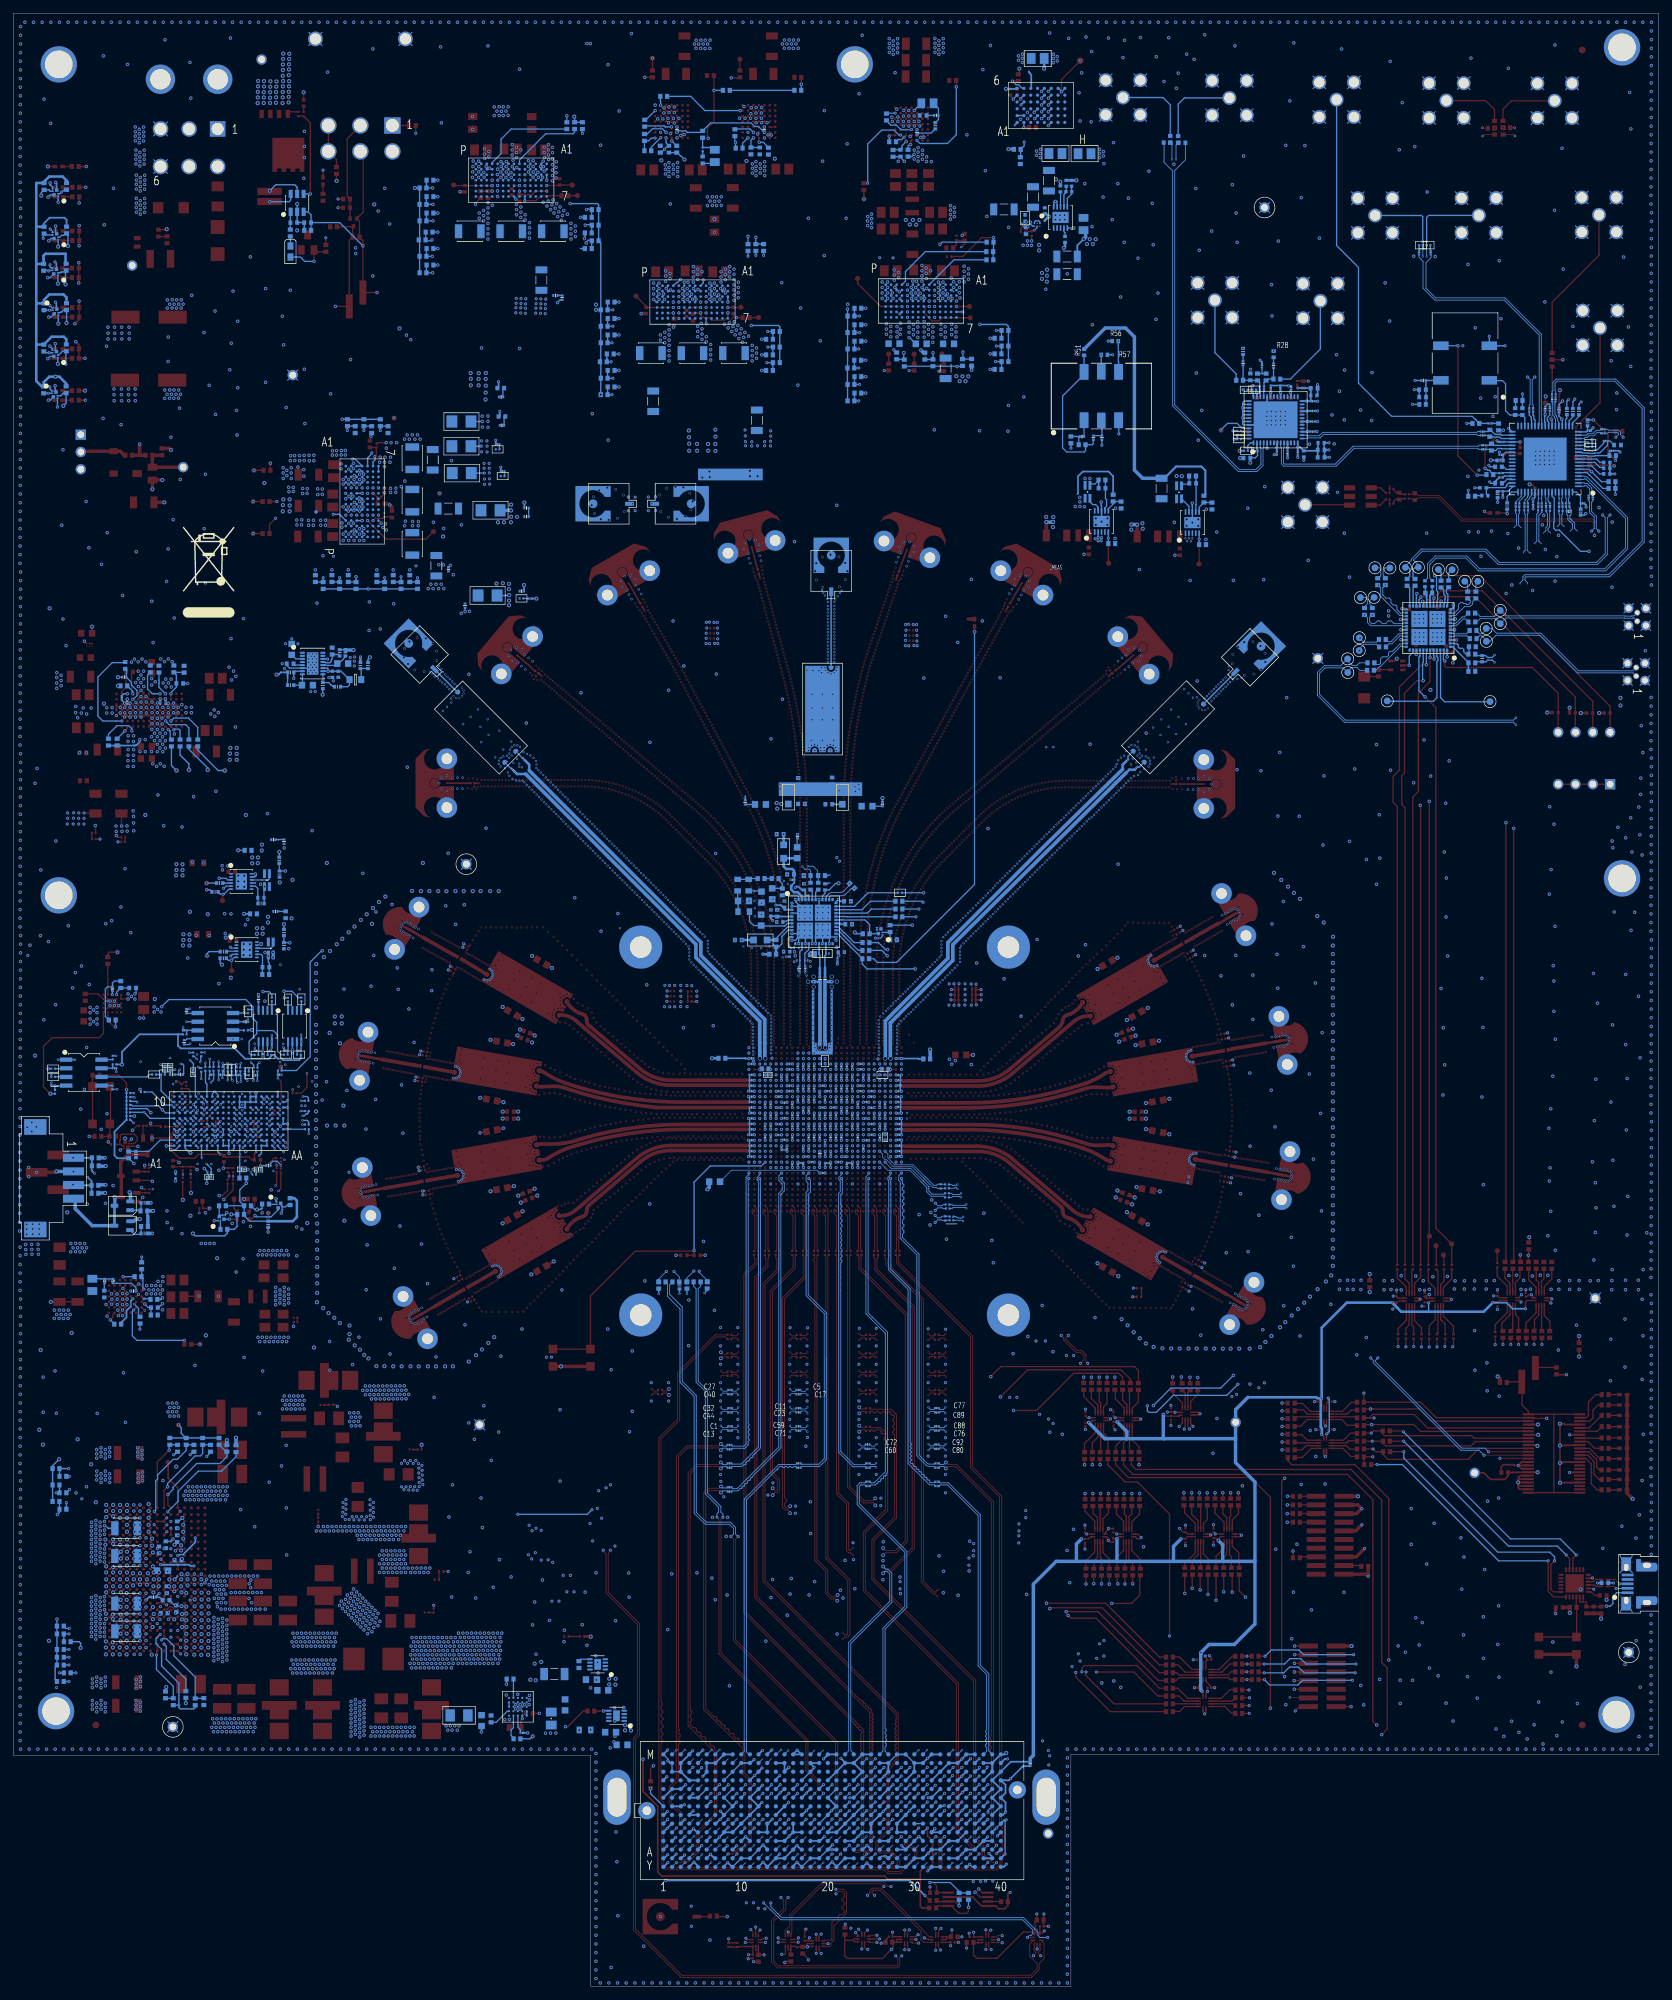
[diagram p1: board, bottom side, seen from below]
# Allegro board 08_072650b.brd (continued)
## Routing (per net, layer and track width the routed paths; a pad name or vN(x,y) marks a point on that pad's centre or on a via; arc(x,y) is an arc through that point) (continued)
UNNAMED_38_ADLTM4702_I15_COMPA: length 4.1
  BOTTOM w0.191: v4(223.44,102.06) 223.44,102.46 224.13,103.15 226.29,103.15 226.3,103.16 R73.1
UNNAMED_38_ADLTM4702_I15_COMPB:
  vias: v4(224.23,102.02)
UNNAMED_38_ADLTM4702_I15_PG: length 12.9
  TOP w0.191: U1.F2 223.81,99.24 v4(223.81,99.24) ; R522.1 v4(216.36,94.78)
  BOTTOM w0.191: v4(216.36,94.78) 223.33,94.78 224,95.45 224,99.05 v4(223.81,99.24)
UNNAMED_38_ADLTM4702_I15_PGSET: length 2.7
  TOP w0.191: v2(223.72,100.1) 223.43,100.39 U1.E2
  BOTTOM w0.191: v2(223.72,100.1) 223.09,99.47 223.09,98.45 R521.1
UNNAMED_38_ADLTM4702_I15_RT: length 1.5
  TOP w0.191: U1.D1 222.63,101.21 v4(222.31,100.89)
  BOTTOM w0.191: v4(222.31,100.89) 221.44,100.89 R518.2
UNNAMED_38_ADLTM4702_I15_RUN: length 3.5
  TOP w0.191: v4(222.3,102.3) 222.58,102.02 U1.C1
  BOTTOM w0.191: R517.2 222.63,104.16 R519.1 222.45,103.92 222.45,102.49 222.3,102.34 v4(222.3,102.3)
UNNAMED_38_ADLTM4702_I15_SET: length 2.8
  TOP w0.191: v1(222.17,100.11) 222.48,100.42 U1.E1
  BOTTOM w0.191: v1(222.17,100.11) 221.65,99.59 C191.2 221.26,98.51 R515.1
UNNAMED_38_ADLTM4702_I15_SVIN: length 1.7
  BOTTOM w0.191: R519.2 223.68,104.11 v1(225.35,104.11)
UNNAMED_38_ADLTM4702_I15_SYNC: length 2.2
  TOP w0.191: U1.G6 226.85,98.6 226.85,98.17 v1(227.23,97.79)
  BOTTOM w0.191: R520.2 226.65,97.21 v1(227.23,97.79)
UNNAMED_38_ADP124_I99_EN: length 2.2
  TOP w0.191: v1(154.84,40.41) 155.39,40.41 155.42,40.39 R534.2
  BOTTOM w0.191: U3.5 154.8,40.45 v1(154.84,40.41)
UNNAMED_38_ADP124_I100_EN: length 1.7
  BOTTOM w0.191: U54.5 158.17,47.99 R25.1
UNNAMED_38_CAP_I48_N2: length 0.6
  BOTTOM w0.191: U40.A3 U40.A4
UNNAMED_38_CAP_I49_N2: length 2.7
  BOTTOM w0.191: C234.2 167.05,37.68 167.41,38.04 U40.C1
UNNAMED_38_CAP_I52_N2: length 1.6
  TOP w0.191: C621.2 v1(164.26,40.06)
  BOTTOM w0.191: U40.E1 U40.E2
UNNAMED_38_CAP_I85_N2: length 3
  BOTTOM w0.191: R73.2 R66.2 228.57,103.8 228.59,103.82 C641.2
UNNAMED_38_CAP_I86_N2: length 1.1
  BOTTOM w0.191: C553.2 228.12,103.11 R66.1
UNNAMED_38_CAP_I92_N1: length 3
  TOP w0.191: C621.1 166.57,40.06 166.76,39.87 v4(166.76,39.28) 166.97,39.07 R538.1
  BOTTOM w0.191: U40.D1 v4(166.76,39.28)
UNNAMED_38_LINLTM8074_I46_PG: length 3.7
  BOTTOM w0.191: R537.1 168.04,36.44 168.41,36.82 168.41,37.61 168.06,37.96 U40.B1
UNNAMED_38_LINLTM8074_I46_RT: length 2.8
  BOTTOM w0.191: R536.2 168.06,45.08 U40.B5
UNNAMED_38_LINLTM8074_I46_RUN: length 3.3
  BOTTOM w0.191: R535.1 170.58,38.74 168.95,40.37 U40.A2
UNNAMED_39_ADLTM4702_I7_COMPB:
  vias: v1(144.06,272.81)
UNNAMED_39_ADLTM4702_I7_PG: length 10.5
  TOP w0.191: R340.1 v1(148.79,280.09)
  L3_SIGNAL w0.114: v1(148.79,280.09) 149.15,279.73 149.15,274.7 v4(146.46,272.01)
UNNAMED_39_ADLTM4702_I7_PGSET: length 3.7
  BOTTOM w0.191: R169.1 148.42,271.77 147.65,272.54 146.19,272.54 v1(145.66,272.01)
UNNAMED_39_ADLTM4702_I7_RT: length 1.5
  TOP w0.191: U31.D1 144.86,270.79 v1(144.81,270.74)
  BOTTOM w0.191: v1(144.81,270.74) 144.79,270.74 R140.2
UNNAMED_39_ADLTM4702_I7_RUN: length 15.9
  TOP w0.191: v1(139.47,271.15) 139.57,271.25 139.57,272.67 138.63,273.61 v1(138.63,278.18) 138.63,280.33 R22.1
  L24_SIGNAL w0.191: v1(144.06,271.21) 143.56,270.71 139.98,270.71 139.55,271.15 v1(139.47,271.15)
  BOTTOM w0.191: R146.2 v1(138.63,278.18)
UNNAMED_39_ADLTM4702_I7_SYNC: length 2.1
  BOTTOM w0.191: v1(147.26,275.21) 148.61,273.85 R147.2
UNNAMED_39_ADLTM4702_I7_VOSNS: length 2.5
  BOTTOM w0.191: R727.1 147.84,269.84 v4(146.43,271.25)
UNNAMED_39_ADLTM4702_I7_VOUT1: length 3.2
  BOTTOM w0.191: v4(147.27,271.17) 147.8,271.17 148.2,270.77 R169.2 148.84,270.75 R727.2
UNNAMED_39_ADLTM4702_I63_COMPA: length 14.2
  BOTTOM w0.191: v1(144.06,272.01) 143.83,272.23 142.77,272.23 142.55,272.01 140.5,272.01 R74.2 139.12,273.39 133.18,273.39 132.66,272.88 132.1,272.88 v1(131.23,272.01)
UNNAMED_39_ADLTM4702_I63_COMPB:
  vias: v1(131.23,272.81)
UNNAMED_39_ADLTM4702_I63_PG: length 10.3
  TOP w0.191: v1(136.09,280.01) 134.91,280.01 R341.1
  L3_SIGNAL w0.114: v4(133.63,272.01) 136.09,274.47 v1(136.09,280.01)
UNNAMED_39_ADLTM4702_I63_PGSET: length 3
  BOTTOM w0.191: R335.1 135.5,272.52 133.34,272.52 v1(132.83,272.01)
UNNAMED_39_ADLTM4702_I63_RT: length 2.4
  TOP w0.191: v1(131.98,270.56) 132.03,270.61 U5.D1
  BOTTOM w0.191: v1(131.98,270.56) 131.38,270.56 130.77,269.94 130.77,269.9 R145.1
UNNAMED_39_ADLTM4702_I63_RUN: length 14.2
  TOP w0.191: R512.1 v1(125.81,279.08)
  L24_SIGNAL w0.191: v1(131.22,271.2) 130.66,270.64 128.78,270.64 125.81,273.6 v1(125.81,279.08)
  BOTTOM w0.191: R148.2 v1(125.81,279.08)
UNNAMED_39_ADLTM4702_I63_SET: length 20.6
  L5_MIXED w0.114: v4(145.88,269.53) 145.49,269.93
  L5_MIXED w0.191: 145.49,269.93 132.8,269.93 132.61,270.12 132.61,270.99 v1(132.83,271.21)
  BOTTOM w0.191: C158.2 R144.1 133.2,270.84 v1(132.83,271.21) ; v1(145.66,271.21) 145.66,270.57 arc(145.64,270.47) 145.58,270.39 C157.2 145.37,270.04 v4(145.88,269.53) 146.37,269.04 R133.1
UNNAMED_39_ADLTM4702_I63_SYNC: length 11.9
  TOP w0.191: U5.G6 v1(134.77,275.21)
  BOTTOM w0.191: v1(134.77,275.21) 139.95,275.21 142.04,277.29 R159.2
UNNAMED_39_ADLTM4702_I63_VOSNS: length 1.8
  BOTTOM w0.191: R728.1 134.42,270.43 v1(133.65,271.2)
UNNAMED_39_ADLTM4702_I63_VOUT1: length 2.6
  TOP w0.191: U5.B3 U5.A3
  BOTTOM w0.191: R335.2 135.56,270.63 v1(135.45,270.52) 135.45,269.72 R728.2
UNNAMED_39_CAP_I75_N2: length 0.8
  BOTTOM w0.191: C642.2 R67.1
UNNAMED_39_CAP_I78_N2: length 3.4
  BOTTOM w0.191: R74.1 R67.2 138.84,269.79 C643.2
UNNAMED_39_NCTESTPAD_I70_N1: length 1.7
  TOP w0.191: TP3.1 R341.2
UNNAMED_39_RES_I53_N1: length 9.5
  BOTTOM w0.191: R148.1 R146.1
UNNAMED_40_ADLTM8051_I7_FB1: length 5.9
  TOP w0.191: v1(218.34,189.65) U32.L2
  BOTTOM w0.191: R380.1 216.46,192.79 R382.1 217.54,192.43 C760.2 217.54,190.61 218.34,189.81 v1(218.34,189.65)
UNNAMED_40_ADLTM8051_I7_FB2: length 5.5
  BOTTOM w0.191: C761.2 224.88,193.14 R381.1 224.14,191.34 224.14,190.95 223.32,190.12 223.32,189.36 223.83,188.85 v1(223.94,188.85)
UNNAMED_40_ADLTM8051_I7_FB3: length 4.8
  TOP w0.191: C762.1 224.11,192.63 224.11,189.82 v1(223.94,189.65)
  BOTTOM w0.191: v1(223.94,189.65) 223.94,190 R778.1
UNNAMED_40_ADLTM8051_I7_PG1: length 6.5
  BOTTOM w0.191: v1(218.33,185.66) 217.91,186.08 215.77,186.08 214.4,184.71 R386.1
UNNAMED_40_ADLTM8051_I7_PG2: length 5.6
  BOTTOM w0.191: R387.1 215.7,184.63 216.17,185.11 218.58,185.11 v1(219.13,185.65)
UNNAMED_40_ADLTM8051_I7_PG3: length 2.3
  TOP w0.191: v4(218.72,184.37) 218.74,184.4 218.74,184.45 U32.K7
  BOTTOM w0.191: R388.1 218.44,183.1 218.44,184.18 218.64,184.37 v4(218.72,184.37)
UNNAMED_40_ADLTM8051_I7_PG4: length 3.1
  TOP w0.191: U32.L7 217.91,184.42 v4(217.91,184.35)
  BOTTOM w0.191: R408.1 216.99,184.26 217.18,184.45 217.78,184.45 217.89,184.35 v4(217.91,184.35)
UNNAMED_40_ADLTM8051_I7_RT14: length 3.5
  BOTTOM w0.191: v1(219.14,189.65) 220.09,190.6 220.09,191.17 220.08,191.17 220.08,191.63 220.09,191.64 R368.2
UNNAMED_40_ADLTM8051_I7_RT23: length 4.7
  BOTTOM w0.191: v1(219.94,189.65) 221.07,189.65 221.77,190.35 221.77,192.39 R372.2
UNNAMED_40_ADLTM8051_I7_RUN14: length 5.8
  TOP w0.191: v1(224.08,184.2) 224.08,184.71 U32.D7
  BOTTOM w0.191: v1(224.08,184.2) 224.08,184.51 224.54,184.96 226.26,184.96 227.51,183.72 R367.2
UNNAMED_40_ADLTM8051_I7_RUN23: length 2.4
  TOP w0.191: U32.C7 224.74,184.56 v1(225.09,184.2)
  BOTTOM w0.191: v1(225.09,184.2) 225.09,184.19 R371.2
UNNAMED_40_ADLTM8051_I7_TRSS1: length 1.2
  TOP w0.191: v1(219.14,188.9) 219.89,188.9 U32.J2
  BOTTOM w0.191: C174.2 219.14,188.73 v1(219.14,188.9) ; C168.2 219.94,188.76 v1(219.94,188.9)
UNNAMED_40_ADLTM8051_I7_TRSS3: length 0.9
  BOTTOM w0.191: C173.2 225.23,189.65 v1(224.74,189.65)
UNNAMED_40_ADLTM8051_I7_VOUT11: length 0.7
  BOTTOM w0.191: C760.1 v1(215.87,191.16)
UNNAMED_40_ADLTM8051_I7_VOUT21: length 14.5
  BOTTOM w0.191: v4(225.54,185.65) 228.32,185.65 229.06,186.39 229.06,192.1 226.95,194.21 225.14,194.21 C761.1
UNNAMED_40_ADLTM8051_I7_VOUT31: length 3.4
  TOP w0.191: U32.B1 225.54,190 224.91,190.63 C762.2
UNNAMED_40_CAP_I214_N2: length 0.5
  BOTTOM w0.191: v4(226.95,145.52) 226.92,145.55 C176.2
UNNAMED_40_CAP_I312_N2: length 2.5
  BOTTOM w0.191: C622.2 225.7,146.48 R500.1 226.3,145.9 v4(226.3,145.52)
UNNAMED_40_LINLTM8074_I217_PG: length 4.5
  TOP w0.191: R540.1 227.6,150.01 U6.B1
UNNAMED_40_LINLTM8074_I217_RT: length 3.8
  TOP w0.191: v1(226.47,140.77) 226.67,140.77 227.6,141.7 U6.B5
  BOTTOM w0.191: R497.1 226.47,141.77 v1(226.47,140.77)
UNNAMED_40_LINLTM8074_I217_RUN: length 3
  TOP w0.191: R373.2 228.99,145.61 U6.A2
UNNAMED_41_ADLTM4709_I2_EN1: length 12.9
  L24_SIGNAL w0.191: 139.18,250.74 137.11,252.81 135.69,252.81
  L24_SIGNAL w0.198: v4(131.34,253.97) 132.51,252.81 135.69,252.81 ; v4(139.78,247.92) 139.78,248.06 139.79,248.07 139.79,249.33 139.79,249.34 139.79,250.13 139.18,250.74
  BOTTOM w0.191: v4(131.34,253.97) R58.2
UNNAMED_41_ADLTM4709_I2_EN2: length 10.9
  L24_SIGNAL w0.191: v4(132.49,253.97) 133.25,253.21 137.36,253.21
  L24_SIGNAL w0.198: v4(140.2,250.37) 137.36,253.21
  BOTTOM w0.191: v4(132.49,253.97) R21.2 ; U7.F1 140.2,249.91 v4(140.2,250.37)
UNNAMED_41_ADLTM4709_I2_EN3: length 14.7
  L24_SIGNAL w0.203: v4(133.63,253.85) 134.01,254.22 141.28,254.22 143.56,251.94 143.56,250.43 v4(143.55,250.42)
  BOTTOM w0.203: v4(133.63,253.85) R20.2 ; U7.L1 144.13,249.97 144,249.97 v4(143.55,250.42)
UNNAMED_41_ADLTM4709_I2_IMON1: length 2
  TOP w0.191: 135.84,246.32 134.95,246.32 134.91,246.35 TP15.1 ; 135.84,246.32 R642.2 ; 135.84,246.32 v1(136.58,246.32)
UNNAMED_41_ADLTM4709_I2_IMON2: length 2.2
  TOP w0.191: R640.2 142.25,246.32 v4(140.58,246.32)
UNNAMED_41_ADLTM4709_I2_IMON3: length 6.3
  TOP w0.191: v4(144.58,246.32) 148.56,246.32 R641.2 148.56,246.48 TP65.1
UNNAMED_41_ADLTM4709_I2_PG1: length 6.5
  TOP w0.203: R547.1 v4(135.31,244.83)
  L3_SIGNAL w0.203: v4(135.31,244.83) 135.41,244.73 136.42,244.73 136.73,244.42 139.27,244.42 v4(139.75,243.94)
  BOTTOM w0.203: v4(139.75,243.94) 139.78,243.97 U7.E7
UNNAMED_41_ADLTM4709_I2_VO10: length 20
  L24_SIGNAL w0.198: v4(139.78,247.12) 138.14,245.47 138.14,242.97 137.08,241.91 137.08,241.87 137.05,241.84 137.05,239.11 136.85,238.91 133.98,238.91 133.78,239.11 133.78,240.79 131.77,242.8 v4(130.73,242.8)
  BOTTOM w0.191: v4(130.73,242.8) R95.1 129.98,242.78 R96.2
UNNAMED_41_ADLTM4709_I2_VO11: length 20.2
  L24_SIGNAL w0.198: v4(139.78,246.32) 138.54,245.07 138.54,242.76 137.79,242.02 137.79,238.18 136.96,237.34 133.12,237.34 131.65,238.81 131.39,238.81 130.73,239.47 v4(130.73,240.51)
  BOTTOM w0.191: R90.2 129.98,240.5 R89.1 v4(130.73,240.51)
UNNAMED_41_ADLTM4709_I2_VO12: length 18.9
  L24_SIGNAL w0.198: v4(139.78,245.52) 139.1,244.84 139.1,242.53 138.33,241.75 138.33,237.82 137.21,236.7 133.02,236.7 131.5,238.23 v4(130.86,238.23)
  BOTTOM w0.191: R84.2 129.98,238.21 R83.1 v4(130.86,238.23)
UNNAMED_41_ADLTM4709_I2_VO20: length 23.3
  L24_SIGNAL w0.198: v4(153.59,233.53) 147.24,233.53 143.17,237.6 143.17,242.89 142.65,243.4 142.65,245.18 v4(143.78,246.32)
  BOTTOM w0.191: R98.2 154.24,234.65 R97.1 v4(153.59,233.53)
UNNAMED_41_ADLTM4709_I2_VO21: length 20.4
  L24_SIGNAL w0.198: v4(143.78,245.52) 143.22,244.95 143.22,243.56 143.77,243.01 143.77,238.14 145.97,235.94 v4(153.47,235.94)
  BOTTOM w0.191: R92.2 154.24,237.07 R91.1 v4(153.47,235.94)
UNNAMED_41_ADLTM4709_I2_VO22: length 14.4
  L24_SIGNAL w0.198: v4(143.78,244.72) 146.21,244.72 152.58,238.35 v4(153.72,238.35)
  BOTTOM w0.191: R86.2 154.35,238.83 154.26,238.74 154.26,238.46 R85.1 v4(153.72,238.35)
UNNAMED_41_ADLTM4709_I2_VO30: length 22.8
  L24_SIGNAL w0.198: v4(143.78,248.72) 143.78,249.25 144.03,249.49 144.03,253.55 144.58,254.1 148.89,254.1 150.67,252.32 150.67,247.37 152.07,245.97 v4(153.47,245.97)
  BOTTOM w0.191: R100.2 154.24,247.1 R99.1 v4(153.47,245.97)
UNNAMED_41_ADLTM4709_I2_VO31: length 24.3
  L24_SIGNAL w0.198: v4(153.47,243.56) 152.07,243.56 149.59,246.04 149.59,252.39 148.51,253.47 144.96,253.47 144.45,252.95 144.45,248.58 v4(143.78,247.92)
  BOTTOM w0.191: R94.2 154.24,244.69 R93.1 v4(153.47,243.56)
UNNAMED_41_ADLTM4709_I2_VO32: length 14.9
  L24_SIGNAL w0.198: v4(143.78,247.12) 144.39,247.73 145.08,247.73 145.29,247.52 145.29,247.04 151.18,241.15 v4(153.59,241.15)
  BOTTOM w0.191: v4(153.59,241.15) R87.1 154.24,242.27 R88.2
UNNAMED_41_ADLTM4709_I15_PG1: length 28.3
  TOP w0.203: v1(203.73,223.47) 203.74,223.46 R543.1
  L3_SIGNAL w0.203: v1(186.72,225.68) 187.81,226.77 200.43,226.77 v1(203.73,223.47)
  L24_SIGNAL w0.203: v1(186.72,225.68) 185.6,225.68 184.99,225.07 184.99,222.74 187.25,220.47 187.26,220.47 v4(187.87,219.86)
UNNAMED_41_ADLTM4709_I15_PG2: length 14.6
  TOP w0.203: v4(202.79,217.86) R544.1
  L22_MIXED w0.203: v4(202.79,217.86) 202.79,219.81 202.03,220.57 194.67,220.57 193.95,219.86 v4(191.87,219.86)
UNNAMED_41_ADLTM4709_I15_PG3: length 14
  TOP w0.203: R545.1 203.87,214.5 v4(202.97,215.39)
  L22_MIXED w0.203: v4(202.97,215.39) 200.99,215.39 200.06,216.32 195.41,216.32 194.84,216.89 193.71,216.89 v4(192.67,215.86)
UNNAMED_41_ADLTM4709_I15_VIN11:
  vias: v1(190.06,221.87) v1(190.02,221.03) v1(190.65,222.43) v1(190.65,221.87) v1(190.65,221.07) v1(190.65,220.4) v1(191.41,221.67) v1(191.45,221.07) v1(191.45,220.4) v1(192.25,221.07) v1(192.25,220.4) v1(193.05,221.07) v1(193.05,220.4)
UNNAMED_41_ADLTM4709_I15_VIN21:
  vias: v1(190.14,217.87) v1(190.14,217.04) v1(190.65,217.84) v1(190.65,216.46) v1(190.69,218.38) v1(190.69,217.07) v1(191.41,217.73) v1(191.45,217.04) v1(191.49,216.53) v1(192.29,217.04) v1(192.3,216.46) v1(193.05,217.07)
UNNAMED_41_ADLTM4709_I15_VIN31:
  vias: v1(190.02,213.87) v1(190.02,213.03) v1(190.02,212.14) v1(190.65,213.87) v1(190.65,213.07) v1(190.65,212.15) v1(191.41,213.66) v1(191.45,213.07) v1(191.45,212.15) v1(192.25,213.07) v1(192.25,212.15) v1(193.05,213.07) v1(193.05,212.15)
UNNAMED_41_ADLTM4709_I15_VO10: length 12.2
  L24_SIGNAL w0.114: v4(192.43,228.27) 190.8,226.64 190.8,225.32 189.12,223.64 189.12,220.78 190.05,219.86 v4(190.27,219.86)
  BOTTOM w0.191: R117.2 191.3,228.91 R116.1 v4(192.43,228.27)
UNNAMED_41_ADLTM4709_I15_VO11: length 11.1
  L24_SIGNAL w0.198: v4(190.02,228.27) 190.02,225.12 188.62,223.72 188.62,220.71 v4(189.47,219.86)
  BOTTOM w0.191: v4(190.02,228.27) R110.1 188.89,228.91 R111.2
UNNAMED_41_ADLTM4709_I15_VO12: length 13.1
  L24_SIGNAL w0.203: v4(187.6,228.27) 187.6,225.43 187.3,225.12 185.98,225.12 185.57,224.71 185.57,222.95 v4(188.67,219.86)
  BOTTOM w0.203: R105.2 186.48,228.91 R104.1 v4(187.6,228.27)
UNNAMED_41_ADLTM4709_I15_VO20: length 16.6
  L24_SIGNAL w0.108: 188.7,216.41 189.25,215.86 v4(189.47,215.86)
  L24_SIGNAL w0.191: 188.7,216.41 188.15,216.96 187.77,216.96
  L24_SIGNAL w0.198: v4(182.14,206.68) 182.14,207.49 185.29,210.64 185.29,214.48 187.77,216.96
  BOTTOM w0.191: v4(182.14,206.68) R118.1 182.16,206.05 R119.2
UNNAMED_41_ADLTM4709_I15_VO21: length 14
  L24_SIGNAL w0.191: 186.07,214.67 187.8,216.41 188.12,216.41 v4(188.67,215.86)
  L24_SIGNAL w0.198: v4(184.56,206.81) 184.56,208.61 185.88,209.93 185.88,214.48 186.07,214.67
  BOTTOM w0.191: R113.2 184.57,206.05 R112.1 v4(184.56,206.81)
UNNAMED_41_ADLTM4709_I15_VO22: length 11.5
  L24_SIGNAL w0.198: v4(187.87,215.86) 187.87,215.32 188.11,215.08 188.11,209.02 186.97,207.87 v4(186.97,206.68)
  BOTTOM w0.191: v4(186.97,206.68) R106.1 186.99,206.05 R107.2
UNNAMED_41_ADLTM4709_I15_VO30: length 13.8
  L3_SIGNAL w0.114: v4(191.87,215.86) 192.28,215.45 194.21,215.45 194.69,214.96 194.69,211.23 v1(196.01,209.91)
  L24_SIGNAL w0.114: v1(196.01,209.91) 196.01,207.19 195.99,207.17 v4(195.99,206.68)
  BOTTOM w0.191: v4(195.99,206.68) R120.1 197.11,206.04 R121.2
UNNAMED_41_ADLTM4709_I15_VO31: length 13.9
  L3_SIGNAL w0.114: v4(194.49,209.83) 193.98,210.34 193.98,214.83 193.68,215.13 191.8,215.13 v4(191.07,215.86)
  L24_SIGNAL w0.114: v4(194.49,209.83) 193.57,208.92 v4(193.57,206.68)
  BOTTOM w0.191: v4(193.57,206.68) R114.1 194.7,206.04 R115.2
UNNAMED_41_ADLTM4709_I15_VO32: length 26.3
  L3_SIGNAL w0.114: v4(182.37,208.41) 189.56,208.41 v1(191.16,206.81)
  L24_SIGNAL w0.108: 188.85,217.23 189.05,217.04 189.05,216.52 189.31,216.26 189.97,216.26 190.27,215.95 v4(190.27,215.86)
  L24_SIGNAL w0.133: v4(182.37,208.41) 184.76,210.79 184.76,214.66
  L24_SIGNAL w0.191: 185.48,215.37 187.53,217.42 188.66,217.42 188.85,217.23
  L24_SIGNAL w0.198: 184.76,214.66 185.48,215.37
  BOTTOM w0.191: v1(191.16,206.81) R108.1 192.29,206.04 R109.2
UNNAMED_41_CAP_I140_N1: length 1.8
  BOTTOM w0.191: C245.1 200,194.76 U37.3
UNNAMED_41_CAP_I142_N1: length 1.4
  BOTTOM w0.191: C246.1 200.14,193.86 U37.5
UNNAMED_41_CAP_I151_N1: length 2.8
  BOTTOM w0.191: U37.8 199.04,190.97 C247.1 R421.1
UNNAMED_41_CAP_I153_N1: length 4
  BOTTOM w0.191: U37.12 195.68,193.86 195.67,193.84 195.61,193.84 195.57,193.8 194.19,193.8 193.92,194.08 C248.1 193.7,194.08 193.08,194.66 192.72,195.11 R423.1
UNNAMED_41_CAP_I168_N2: length 3.3
  BOTTOM w0.191: U10.8 205.93,161.43 205.58,161.08 C196.2 205.56,159.69 R127.2
UNNAMED_41_CAP_I180_N2: length 3.7
  BOTTOM w0.191: R126.2 204.92,149.5 C195.2 204.89,151.2 205.12,151.42 U9.8
UNNAMED_41_CAP_I205_N1: length 10.3
  TOP w0.191: v1(195.28,192.96) 195.28,194.16 195.33,194.21 v4(195.33,194.74)
  BOTTOM w0.191: v4(195.33,194.74) 195.36,194.74 195.37,194.75 195.43,194.75 195.43,194.76 U37.14 ; U37.10 v1(195.28,192.96) ; v1(195.28,192.96) C244.1 194.63,192.94 C140.2 193.34,192.94 L2.2 192.12,190.96 192.41,190.68 R420.1 ; v1(195.28,192.96) 195.28,193.27 195.42,193.41 U37.11
UNNAMED_41_CAPSP_I345_N2: length 3.1
  BOTTOM w0.191: C197.2 203.33,152.66 203.69,152.29 205.32,152.29 205.37,152.35 205.68,152.35 U9.10
UNNAMED_41_CAPSP_I347_N2: length 3.4
  BOTTOM w0.191: U10.10 204.95,162.33 204.94,162.33 204.25,162.33 204.25,162.33 204.08,162.33 203.89,162.52 C198.2
UNNAMED_41_IND_I208_N1: length 2.8
  BOTTOM w0.191: R416.2 R417.2 190.4,193.23 L2.1
UNNAMED_41_LINLT3094_I169_ILIM: length 3.3
  TOP w0.191: v4(210.69,160.24) 210.77,160.16 TP17.1
  BOTTOM w0.191: U10.6 209.81,160.98 210.55,160.24 v4(210.69,160.24) 211.07,160.24 R124.1
UNNAMED_41_LINLT3094_I169_PG: length 1.2
  BOTTOM w0.191: U10.4 209.96,161.88 209.98,161.86 210.39,161.86 210.41,161.87 R549.1
UNNAMED_41_LINLT3094_I169_PGFB: length 15.2
  L24_SIGNAL w0.191: v4(210.62,161.11) 210.03,161.11 209.14,160.22 203.68,160.22 203.43,160.48 203.43,162.31 202.09,163.65 v1(201.54,163.65)
  BOTTOM w0.191: U10.5 210.22,161.43 210.54,161.11 v4(210.62,161.11) ; R131.1 202.44,163.7 R129.2 v1(201.54,163.65)
UNNAMED_41_LINLT3094_I176_ILIM: length 3.4
  TOP w0.191: v1(209.45,150.55) 209.45,149.07 TP23.1
  BOTTOM w0.191: U9.6 209.02,150.97 v1(209.45,150.55) 209.89,150.53 210.04,150.67 R125.1
UNNAMED_41_LINLT3094_I176_PG: length 1.5
  BOTTOM w0.191: U9.4 210.14,151.87 R548.1
UNNAMED_41_LINLT3094_I176_PGFB: length 14.6
  L24_SIGNAL w0.191: v4(209.55,151.18) 209.5,151.13 209.14,151.13 208.43,150.41 201.63,150.41 200.94,151.1 200.28,151.71 200.28,152.5 v1(200.89,153.11)
  BOTTOM w0.191: R130.1 R128.2 v1(200.89,153.11) ; v4(209.55,151.18) 209.31,151.42 U9.5
UNNAMED_41_LINLT6658_I148_ODN: length 3.2
  BOTTOM w0.191: U37.9 196.04,192.5 R418.2 196.01,191.28 195.17,191.28 194.8,190.91 194.78,190.91 194.61,190.74 194.61,190.73 194.38,190.73 R420.2
UNNAMED_41_LINLT6658_I148_VOUT1S: length 3.6
  BOTTOM w0.191: U37.13 195.73,194.31 195.62,194.19 195,194.19 194.81,194.38 194.81,194.62 194.67,194.76 R579.2 193.78,195.41 R424.1
UNNAMED_41_LINLT6658_I148_VOUT2S: length 3.1
  TOP w0.191: R507.2 200.26,191.97 v1(200.31,191.92)
  BOTTOM w0.191: v1(200.31,191.92) R422.1 200.14,192.96 U37.7
UNNAMED_41_NCTESTPAD_I283_N1: length 1.3
  TOP w0.191: TP16.1 132.76,244.86 132.79,244.83 R547.2
UNNAMED_41_NCTESTPAD_I289_N1: length 1.4
  TOP w0.191: R543.2 v1(206.15,222.43)
UNNAMED_41_NCTESTPAD_I290_N1: length 1.4
  TOP w0.191: R544.2 v1(206.27,217.86)
UNNAMED_41_NCTESTPAD_I291_N1: length 1.4
  TOP w0.191: R545.2 v1(206.27,213.16)
UNNAMED_42_ADLTM4709_I91_EN1: length 13
  L24_SIGNAL w0.191: v4(157.94,271.86) 158.8,270.99 163.4,270.99 166.45,267.94 166.45,266.48 166.37,266.4 166.37,265.8 v4(166.38,265.8)
  BOTTOM w0.191: v4(157.94,271.86) R761.2
UNNAMED_42_ADLTM4709_I91_EN2: length 10.8
  BOTTOM w0.191: U52.F1 167.18,267.96 163.33,271.81 159.32,271.81 159.08,272.05 R542.2
UNNAMED_42_ADLTM4709_I91_EN3: length 14.4
  BOTTOM w0.191: U52.L1 171.18,267.58 169.88,268.88 169.88,271.02 168.39,272.5 R763.2
UNNAMED_42_ADLTM4709_I91_IMON2: length 1.3
  TOP w0.191: v4(167.18,264.2) 167.82,264.2 R757.2
UNNAMED_42_ADLTM4709_I91_PG1: length 6.3
  TOP w0.191: R764.1 164.03,262.71 164.75,261.99 166.4,261.99 v4(166.4,261.99)
  BOTTOM w0.191: v4(166.4,261.99) 166.4,261.99 166.4,262.05 U52.E7
UNNAMED_42_ADLTM4709_I91_VO10: length 13.3
  L24_SIGNAL w0.198: v4(166.38,265) 166,264.62 164.92,264.62 164.19,263.88 164.19,263.55 163.42,262.79 162.03,262.79 159.58,260.34 157.67,260.34 v1(157.33,260.68)
  BOTTOM w0.191: R755.2 156.57,260.66 R754.1 156.63,260.76 157.25,260.76 v1(157.33,260.68)
UNNAMED_42_ADLTM4709_I91_VO11: length 18.4
  L24_SIGNAL w0.198: v4(166.38,264.2) 165.91,264.2 164.26,262.55 164.26,259.74 160.1,255.57 159.11,255.57 158.38,256.3 158.38,256.91 158.11,257.18 157.71,257.18 157.51,257.39 v1(157.51,258.39)
  BOTTOM w0.191: R753.2 156.57,258.38 R748.1 156.63,258.47 157.43,258.47 v1(157.51,258.39)
UNNAMED_42_ADLTM4709_I91_VO12: length 18.7
  L24_SIGNAL w0.198: v4(166.38,263.4) 165.7,262.72 165.7,260.41 165.1,259.81 165.1,256.51 163.17,254.58 158.57,254.58 v1(157.38,255.78)
  BOTTOM w0.191: v1(157.38,255.78) 157.38,255.9 157.09,256.18 156.63,256.18 R746.1 156.57,256.09 R747.2
UNNAMED_42_ADLTM4709_I91_VO20: length 24.2
  L24_SIGNAL w0.198: v1(179.93,251.41) 172.95,251.41 169.09,255.27 169.09,263.3 170,264.21 v1(170.38,264.21)
  BOTTOM w0.191: R774.2 180.83,252.54 R773.1 v1(179.93,251.41)
UNNAMED_42_ADLTM4709_I91_VO21: length 20.4
  L24_SIGNAL w0.198: v1(170.4,263.42) 169.81,262.83 169.81,256.58 172.57,253.82 v1(179.98,253.82)
  BOTTOM w0.191: v1(179.98,253.82) R769.1 180.83,254.95 R770.2
UNNAMED_42_ADLTM4709_I91_VO22: length 14.5
  L24_SIGNAL w0.198: v1(170.38,262.61) 173.18,262.61 179.55,256.24 v1(180.01,256.24)
  BOTTOM w0.191: R766.2 180.94,256.25 R765.1 180.83,256.11 180.14,256.11 v1(180.01,256.24)
UNNAMED_42_ADLTM4709_I91_VO30: length 22.8
  L24_SIGNAL w0.198: v1(170.38,266.63) 170.38,271.19 171.17,271.98 175.49,271.98 177.27,270.21 177.27,265.25 178.66,263.86 v1(179.93,263.86)
  BOTTOM w0.191: v1(179.93,263.86) R775.1 180.83,264.98 R776.2
UNNAMED_42_ADLTM4709_I91_VO31: length 22.6
  L24_SIGNAL w0.198: v1(179.88,261.44) 178.66,261.44 176.19,263.92 176.19,269.58 175.11,270.66 172.01,270.66 171.04,269.69 171.04,266.46 170.42,265.84 v1(170.42,265.83)
  BOTTOM w0.191: R772.2 180.83,262.57 R771.1 v1(179.88,261.44)
UNNAMED_42_ADLTM4709_I91_VO32: length 14.9
  L24_SIGNAL w0.198: v1(179.88,259.03) 177.77,259.03 171.88,264.92 171.88,265.4 171.68,265.61 170.97,265.61 v4(170.36,265)
  BOTTOM w0.191: R768.2 180.83,260.16 R767.1 v1(179.88,259.03)
UNNAMED_42_ADLTM4709_I91_VREF3: length 1.7
  TOP w0.191: 171.77,263.4 C764.2 ; 171.77,263.4 172.26,263.4 172.27,263.39 R789.2 ; 171.77,263.4 v1(171.18,263.4)
UNNAMED_42_NCTESTPAD_I74_N1: length 1.3
  TOP w0.191: TP37.1 159.35,262.74 159.38,262.71 R764.2
UNNAMED_43_ADLTM4702_I295_COMPA: length 3.1
  BOTTOM w0.191: v4(108.83,271.63) 108.54,271.91 106.76,271.91 R680.2
UNNAMED_43_ADLTM4702_I295_COMPB:
  vias: v4(108.83,272.43)
UNNAMED_43_ADLTM4702_I295_PG: length 12.3
  TOP w0.191: R63.1 v4(116.06,264.56)
  BOTTOM w0.191: v4(111.23,271.63) 111.48,271.63 112.19,272.34 114.02,272.34 116.06,270.3 v4(116.06,264.56)
UNNAMED_43_ADLTM4702_I295_PGSET: length 1.9
  TOP w0.191: U36.E2 110.43,271.6 v4(110.73,271.3)
  BOTTOM w0.191: v4(110.73,271.3) 110.74,271.3 111.07,270.97 111.56,270.97 R539.1
UNNAMED_43_ADLTM4702_I295_RT: length 1.7
  TOP w0.191: v1(109.78,270.23) 109.78,270.68 U36.D1
  BOTTOM w0.191: v1(109.78,270.23) 109.91,270.23 110.13,270 R504.1
UNNAMED_43_ADLTM4702_I295_RUN: length 14.5
  TOP w0.191: v1(103.06,278.7) 103.08,278.72 R453.2
  BOTTOM w0.191: v4(108.83,270.83) 108.38,270.38 104.34,270.38 103.06,271.67 v1(103.06,278.7)
UNNAMED_43_ADLTM4702_I295_SET: length 2.8
  TOP w0.191: v1(110.41,270.66) 110.43,270.68 U36.E1
  BOTTOM w0.191: R54.2 112.32,269.46 C163.2 111.02,269.69 111.02,270.05 v1(110.41,270.66)
UNNAMED_43_ADLTM4702_I295_SYNC: length 1.3
  BOTTOM w0.191: R60.2 113.11,274.77 113.05,274.83 v4(112.03,274.83)
UNNAMED_43_ADLTM4702_I295_VOSNS: length 1.8
  TOP w0.191: v1(112.9,271.46) 112.83,271.46 112.67,271.63 U36.G2
  BOTTOM w0.191: v1(112.9,271.46) R539.2
UNNAMED_43_ADLTM4709_I340_EN1: length 15.4
  L3_SIGNAL w0.114: v4(106.23,248.07) 106.91,248.75 106.91,251.01 105.61,252.3 105.61,255.42 v1(105.46,255.57)
  BOTTOM w0.191: R617.2 105.13,255.91 v1(105.46,255.57)
UNNAMED_43_ADLTM4709_I340_EN2: length 9.9
  BOTTOM w0.191: R619.2 103.38,253.31 U34.F1
UNNAMED_43_ADLTM4709_I340_EN3: length 15.2
  BOTTOM w0.191: R620.2 107.59,254.51 110.52,251.59 110.52,250.18 U34.L1
UNNAMED_43_ADLTM4709_I340_IMON1: length 1.9
  TOP w0.191: v1(103.03,246.47) 101.81,246.47 101.8,246.46 TP28.1
UNNAMED_43_ADLTM4709_I340_IMON2: length 8.9
  TOP w0.191: TP34.1 105.18,244.81 105.64,244.35 106.6,244.35 107.67,245.41 107.67,246.28 107.48,246.47 v4(107.03,246.47)
UNNAMED_43_ADLTM4709_I340_IMON3: length 8.6
  TOP w0.191: TP35.1 117.55,249.86 114.16,246.47 v4(111.03,246.47)
UNNAMED_43_ADLTM4709_I340_PG1: length 13.1
  TOP w0.191: R552.1 v4(105.6,236.97)
  L3_SIGNAL w0.114: v4(106.23,244.87) 103.37,244.87 102.51,244.02 102.51,241.27 105.6,238.19 v4(105.6,236.97)
UNNAMED_43_ADLTM4709_I340_PG2: length 34.7
  TOP w0.191: R553.1 v4(109.99,237.07)
  L3_SIGNAL w0.114: 105.16,235.76 108.68,235.76 v4(109.99,237.07) ; 100.69,241 100.69,252.2 101.85,253.37 103.3,253.37 106.23,250.44 v4(106.23,248.87)
  L3_SIGNAL w0.191: 100.69,241 100.69,239.06 101.04,238.71 103.63,238.71 104.29,238.05 104.29,236.63 105.16,235.76
UNNAMED_43_ADLTM4709_I340_PG3: length 55.8
  TOP w0.191: R554.1 v4(113.63,237.07)
  L3_SIGNAL w0.114: 96.22,251.54 101.12,256.44 108.23,256.44 108.92,255.75 108.92,251.41 110.23,250.09 v4(110.23,249.67) ; v4(113.63,237.07) 111.2,234.65 99.21,234.65 97.1,236.75
  L3_SIGNAL w0.191: 96.22,251.54 96.22,237.64 97.1,236.75
UNNAMED_43_ADLTM4709_I340_VIN11:
  vias: v1(103.66,247.65) v1(104.21,247.69) v1(104.38,248.32) v1(105.01,250.02) v1(105,249.25) v1(105.01,248.45) v1(105.05,247.65) v1(105.68,250.05) v1(105.68,249.25) v1(105.66,248.5) v1(105.68,247.65) v1(107.7,247.69) v1(108.21,247.69) v1(108.36,248.41) v1(108.88,250.18) v1(109.01,249.25) v1(109.01,248.45) v1(108.99,247.65) v1(109.43,250.18) v1(109.68,249.25) v1(109.68,248.45) v1(109.63,247.65) v1(112.34,247.65) v1(112.46,248.45) v1(113.14,250.05) v1(113.14,249.25) v1(113.14,248.45) v1(113.14,247.65) v1(113.94,250.05) v1(113.94,249.25) v1(113.94,248.45) v1(113.94,247.65)
UNNAMED_43_ADLTM4709_I340_VO10: length 12.8
  L24_SIGNAL w0.198: v4(106.23,247.27) 106.2,247.27 104.77,245.84 102.99,245.84 100.1,242.95 v4(97.18,242.95)
  BOTTOM w0.191: R45.2 96.43,242.94 R44.1 v4(97.18,242.95)
UNNAMED_43_ADLTM4709_I340_VO11: length 13.4
  L24_SIGNAL w0.198: v4(106.23,246.47) 105.2,245.44 103.56,245.44 98.78,240.67 v4(97.18,240.67)
  BOTTOM w0.191: v4(97.18,240.67) R38.1 96.43,240.65 R39.2
UNNAMED_43_ADLTM4709_I340_VO12: length 15.4
  L24_SIGNAL w0.198: v4(106.23,245.67) 105.44,244.88 103.71,244.88 102.24,243.41 102.24,242.52 98.09,238.38 v4(97.31,238.38)
  BOTTOM w0.191: 97.23,238.38 97.26,238.4 96.44,238.4 R31.1 ; 97.23,238.38 v4(97.31,238.38) ; 97.23,238.38 R31.1 ; R31.1 96.41,237.25 R32.2
UNNAMED_43_ADLTM4709_I340_VO20: length 21.8
  L24_SIGNAL w0.198: v4(110.23,246.47) 110.67,246.02 113.94,246.02 115.62,244.35 115.62,241.2 118.9,237.92 118.9,234.14 v4(117.37,232.61)
  BOTTOM w0.191: R47.2 118,232.63 R46.1 v4(117.37,232.61)
UNNAMED_43_ADLTM4709_I340_VO21: length 18.3
  L24_SIGNAL w0.198: v4(117.25,235.03) 118.31,236.09 118.31,237.69 115.22,240.78 115.22,243.93 114.17,244.98 111.55,244.98 111.51,244.95 111.15,244.95 111.11,244.98 110.92,244.98 110.68,245.23 110.67,245.23 v4(110.23,245.67)
  BOTTOM w0.191: v4(117.25,235.03) R40.1 118,235.04 R41.2
UNNAMED_43_ADLTM4709_I340_VO22: length 14.7
  L24_SIGNAL w0.198: v4(110.23,244.87) 110.23,244.86 110.57,244.53 113.69,244.53 113.73,244.56 114.57,243.72 114.57,239.32 116.48,237.41 117.35,237.41 v4(117.37,237.44)
  BOTTOM w0.191: v4(117.37,237.44) R33.1 118.03,237.45 R34.2
UNNAMED_43_ADLTM4709_I340_VO30: length 22.8
  L3_SIGNAL w0.203: v4(110.23,248.87) 110.82,249.46 110.82,250.01 109.73,251.1 109.73,252.91 111.4,254.58 113.35,254.58 v4(114.31,253.63)
  L24_SIGNAL w0.203: v4(117.25,245.06) 117.54,245.06 117.93,245.46 117.93,248.77 114.45,252.25 114.45,253.48 v4(114.31,253.63)
  BOTTOM w0.203: R50.2 118,245.07 R48.1 v4(117.25,245.06)
UNNAMED_43_ADLTM4709_I340_VO31: length 22.5
  L3_SIGNAL w0.203: v4(110.23,248.07) 110.9,248.74 110.9,248.79 111.33,249.22 111.33,250.16 110.9,250.6 110.9,251.71 112.34,253.16 v4(112.34,253.59)
  L24_SIGNAL w0.203: v4(117.25,242.65) 117.83,243.23 117.83,243.78 116.69,244.92 116.69,245.67 117.12,246.1 117.12,248.03 112.34,252.81 v4(112.34,253.59)
  BOTTOM w0.203: R43.2 118,242.66 R42.1 v4(117.25,242.65)
UNNAMED_43_ADLTM4709_I340_VO32: length 14.1
  L24_SIGNAL w0.191: v4(110.23,247.27) 110.59,246.91 111.21,246.91 111.28,246.84 114.15,246.84
  L24_SIGNAL w0.198: 114.15,246.84 116.82,244.16 116.82,243.23 116.46,242.86 116.46,242.01 116.82,241.65 116.82,240.78 v4(117.37,240.23)
  BOTTOM w0.191: R36.2 118,240.25 R35.1 v4(117.37,240.23)
UNNAMED_43_ADLTM4709_I340_VREF1: length 9.6
  L3_SIGNAL w0.203: v4(102.09,245.66) 101.63,245.2 101.63,240.24 v1(102.09,239.78)
  BOTTOM w0.203: R615.2 100.84,238.75 R23.2 102.14,238.98 102.09,239.03 v1(102.09,239.78) ; U34.A6 102.08,245.67 102.09,245.67 v4(102.09,245.66)
UNNAMED_43_ADLTM4709_I340_VREF2: length 8.8
  L3_SIGNAL w0.203: v1(106.48,239.67) 106.01,240.14 106.01,243.8 107.03,244.82 v4(107.03,245.67)
  BOTTOM w0.203: R616.2 106.49,238.69 R24.2 106.48,238.96 106.48,238.96 v1(106.48,239.67)
UNNAMED_43_ADLTM4709_I340_VREF3: length 8.5
  L3_SIGNAL w0.114: v10(110.77,239.67) 110.77,244.32 111.33,244.88 v4(111.33,245.39)
  BOTTOM w0.191: v4(111.33,245.39) 111.05,245.67 U34.L6 ; 110.73,238.72 110.77,238.75 v10(110.77,239.67) ; 110.73,238.72 R621.2 ; 110.73,238.72 R618.2
UNNAMED_43_CAP_I177_N2: length 0.8
  BOTTOM w0.191: 82.24,213.35 82.24,212.58 v4(82.25,212.57)
  vias: v4(81.74,212.55) v4(81.79,212.09) v4(82.25,212.06) v4(82.68,212.39)
UNNAMED_43_CAP_I180_N2: length 4.7
  BOTTOM w0.191: R59.2 81.17,219.83 81.16,219.82 C134.2 81.16,218.3 81,218.14 81,217.17 81.24,216.93 U4.7
UNNAMED_43_CAP_I257_N2:
  vias: v11(68.4,212.45) v11(68.63,212.01) v11(68.91,212.45) v11(69.16,212.04) v11(69.42,212.45)
UNNAMED_43_CAP_I261_N2: length 5.3
  BOTTOM w0.191: U38.7 67.9,217.35 67.85,217.4 C602.2 67.83,220.54 67.83,220.81 67.88,220.85 R456.2
UNNAMED_43_CAP_I418_N2: length 34.6
  TOP w0.191: v2(102.31,255.19) 101.83,255.68 C708.2 102.97,256.14 R786.1 103.05,255.51 R585.2
  L3_SIGNAL w0.191: v1(102.95,237.64) 100.46,237.64 98.76,239.34 98.76,251.61 102.31,255.17 v2(102.31,255.19)
  BOTTOM w0.191: R618.1 110.67,237.7 R24.1 103,237.7 v1(102.95,237.64) 102.89,237.7 102.19,237.7 R23.1
UNNAMED_43_CAP_I420_N2: length 1.1
  BOTTOM w0.191: R681.1 C644.2
UNNAMED_43_CAP_I423_N2: length 3.3
  BOTTOM w0.191: C645.2 105.68,275.56 R681.2 105.68,273.89 R680.1
UNNAMED_43_CAPSP_I428_N3: length 2.4
  BOTTOM w0.191: C603.3 68.9,217.15 U38.9
UNNAMED_43_CAPSP_I429_N3: length 2.6
  BOTTOM w0.191: C135.3 83.44,217.8 83.03,217.4 82.61,217.4 82.24,217.03 U4.9
UNNAMED_43_LINLT3045V2_I181_ILIM: length 5.4
  TOP w0.191: v4(80.74,212.49) 80.74,208.83 TP29.1
  BOTTOM w0.191: U4.5 v4(80.74,212.49) 80.74,212.49 R551.1
UNNAMED_43_LINLT3045V2_I181_PGFB: length 2.8
  BOTTOM w0.191: R26.1 78.88,217.86 R19.2 80.04,217.47 80.74,216.77 U4.6
UNNAMED_43_LINLT3045V2_I256_ILIM: length 5.3
  TOP w0.191: TP26.1 67.4,208.72 v4(67.4,212.32)
  BOTTOM w0.191: R533.1 v4(67.4,212.32) 67.4,213.2 U38.5
UNNAMED_43_LINLT3045V2_I256_PGFB: length 2.9
  BOTTOM w0.191: R455.1 65.55,217.71 R454.2 67.4,217.01 U38.6
UNNAMED_43_NCTESTPAD_I395_N1: length 1.6
  TOP w0.191: TP30.1 105.16,239.42 104.93,239.19 R552.2
UNNAMED_43_NCTESTPAD_I396_N1: length 1.4
  TOP w0.191: R553.2 TP31.1
UNNAMED_43_NCTESTPAD_I397_N1: length 1.4
  TOP w0.191: R554.2 TP32.1
UNNAMED_43_RES_I405_N1: length 10.7
  TOP w0.191: v1(97.59,256.57) 99.33,256.57 102.11,253.8 103.77,253.8 R787.2
  BOTTOM w0.191: v1(97.59,256.57) R617.1 97.59,254.56 R620.1 97.65,253.34 R619.1
UNNAMED_44_ADLT1990_I356_: length 1.6
  BOTTOM w0.191: R370.2 A3.2
UNNAMED_44_ADLT1990_I356__1: length 1.6
  BOTTOM w0.191: R682.2 A3.3
UNNAMED_44_ADLT1990_I356_GAIN1: length 2.1
  BOTTOM w0.191: R577.2 216.18,138.82 215.98,139.03 214.44,139.03 A3.8
UNNAMED_44_ADLT1990_I356_GAIN2: length 1.7
  BOTTOM w0.191: A3.5 214.44,142.76 R472.2
UNNAMED_44_ADLT1990_I356_OUT: length 10.9
  L5_MIXED w0.191: v2(216.08,141.53) 216.59,141.53 217.42,140.69 217.42,135.86 v2(216.89,135.33)
  BOTTOM w0.191: v2(216.89,135.33) 216.66,135.33 216.47,135.14 216.47,133.89 R609.1 ; v2(216.08,141.53) A3.6
UNNAMED_44_ADLT1990_I356_V: length 2.2
  BOTTOM w0.191: A3.4 207.58,142.8 C714.2 R596.2
UNNAMED_44_ADLT1990_I356_V_1: length 2.2
  BOTTOM w0.191: R606.2 C530.2 A3.7
UNNAMED_44_ADLT1990_I365_: length 1.7
  BOTTOM w0.191: A4.2 233.76,134.65 R683.2
UNNAMED_44_ADLT1990_I365__1: length 1.6
  BOTTOM w0.191: R419.2 233.73,133.45 A4.3
UNNAMED_44_ADLT1990_I365_GAIN1: length 1.7
  BOTTOM w0.191: A4.8 226.94,135.97 226.9,136 R511.2
UNNAMED_44_ADLT1990_I365_GAIN2: length 1.6
  BOTTOM w0.191: R510.2 226.96,132.16 A4.5
UNNAMED_44_ADLT1990_I365_OUT: length 7.6
  BOTTOM w0.191: R667.1 221.51,133.78 221.87,133.43 A4.6
UNNAMED_44_ADLT1990_I365_V: length 2.3
  BOTTOM w0.191: R607.2 235.37,131.52 C538.2 A4.4
UNNAMED_44_ADLT1990_I365_V_1: length 2.2
  BOTTOM w0.191: A4.7 228.5,134.72 C719.2 R608.2
UNNAMED_44_ADLTC298024_I313_PWRGD: length 30.1
  TOP w0.191: v1(204.06,110.67) 204.04,110.69 R555.1
  L3_SIGNAL w0.191: v1(216.71,110.44) 216.71,113.79 219.46,116.54 219.46,122.86 v1(219,123.32)
  L24_SIGNAL w0.191: v1(216.71,110.44) 215.8,111.35 214,111.35 213.31,110.67 v1(204.06,110.67)
  BOTTOM w0.191: v1(219,123.32) 217.89,123.32 U11.A1 ; R603.1 v1(204.06,110.67)
UNNAMED_44_ADLTC298024_I313_REFM: length 1
  TOP w0.191: C154.2 v2(213.06,122.91)
  BOTTOM w0.191: v2(213.06,122.91) 213.06,123.35 U11.G1
UNNAMED_44_ADLTC298024_I313_REFP: length 1
  TOP w0.191: C154.1 213.06,124.18 v2(212.78,124.46)
  BOTTOM w0.191: v2(212.78,124.46) 213.05,124.18 U11.G2
UNNAMED_44_ADLTC298024_I313_SCL: length 7.6
  TOP w0.191: R597.2 216.61,119.1 v2(216.59,119.13) 216.61,119.15 R599.2
  L22_MIXED w0.114: v2(215.06,123.72) 215.15,123.63 216.02,123.63 216.69,122.96 216.69,119.23 v2(216.59,119.13)
  BOTTOM w0.191: v2(215.06,123.72) 214.96,123.82 214.96,123.83 214.65,124.13 U11.E2
UNNAMED_44_ADLTC298024_I313_SDA: length 8.1
  TOP w0.191: R600.2 v2(215.44,119.18) 215.42,119.15 R598.2
  L22_MIXED w0.114: v2(214.35,123.04) 214.62,123.32 215.85,123.32 216.37,122.79 216.37,119.8 215.75,119.18 v2(215.44,119.18)
  BOTTOM w0.191: U11.E1 v2(214.35,123.04)
UNNAMED_44_ADLTC298024_I313_VDACP0: length 17.9
  TOP w0.191: R498.1 v2(200.47,131.58)
  L24_SIGNAL w0.191: v2(214.24,125.39) 214.24,125.84 213.21,126.87 212.01,126.87 211.58,127.3 211.24,127.3 211.23,127.31 210.99,127.31 208.58,129.72 205.47,129.72 205.28,129.91 205.28,130.35 204.88,130.76 201.29,130.76 v2(200.47,131.58)
  BOTTOM w0.191: v2(214.24,125.39) 213.87,125.75 U11.F4
UNNAMED_44_ADLTC298024_I313_VDACP1: length 1.2
  TOP w0.191: v2(214.24,126.99) 213.57,126.99 R499.1
  BOTTOM w0.191: U11.F6 213.87,127.35 v2(214.24,126.99)
UNNAMED_44_ADLTC298024_I313_VDACP3: length 3.9
  BOTTOM w0.191: U11.G10 213.05,132.38 213.26,132.59 213.26,134.3 R501.1
UNNAMED_44_ADLTC298024_I313_VDACP4: length 3.4
  BOTTOM w0.191: R502.1 214.76,133.52 214.76,130.65 U11.E10
UNNAMED_44_ADLTC298024_I313_VDACP7: length 5.2
  TOP w0.191: v2(216.64,128.59) 215.57,129.65 215.57,131.52 215.76,131.71 R505.1
  BOTTOM w0.191: U11.C8 216.27,128.95 v2(216.64,128.59)
UNNAMED_44_ADLTC298024_I313_VDD251: length 1.1
  BOTTOM w0.191: U11.A3 217.81,124.95 v1(217.49,124.63) 217.29,124.82 217.18,124.82 U11.B3
UNNAMED_44_ADLTC298024_I313_VPWR: length 2.6
  TOP w0.191: v2(217.5,126.21) 217.45,126.16 C209.1 217.34,126.14 R631.2
  BOTTOM w0.191: U11.A5 217.84,126.55 v2(217.5,126.21)
UNNAMED_44_ADLTC298024_I313_VSENSEP0: length 10.2
  L3_SIGNAL w0.191: v2(213.44,125.39) 213.45,125.39 214.1,124.74 215.72,124.74 216.48,123.98 216.48,123.01 218.49,121.01 218.49,120.35 v1(217.65,119.51)
  BOTTOM w0.191: U11.G4 213.07,125.75 v2(213.44,125.39) ; R134.2 v1(217.65,119.51)
UNNAMED_44_ADLTC298024_I313_VSENSEP1: length 19.6
  L22_MIXED w0.191: v2(215.04,126.19) 214.12,126.19 213.31,127 212.22,127 210.21,129.01 210.21,129.58 209.54,130.25 207.8,130.25 207.14,129.59 205.46,129.59 204.13,128.26 200.62,128.26 199.69,129.19 v2(199.15,129.19)
  BOTTOM w0.191: v2(215.04,126.19) 214.67,126.55 U11.E5
UNNAMED_44_ADLTC298024_I313_VSENSEP2: length 10
  L3_SIGNAL w0.191: v2(214.02,135.61) 213.94,135.53 213.94,134.35 214.66,133.62 214.66,130.39 214.69,130.36 214.69,129.9 213.8,129.01 213.8,128.44 213.77,128.41 213.77,128.05 v2(213.52,127.81)
  BOTTOM w0.191: R138.2 213.98,136.38 213.98,135.81 214.02,135.77 v2(214.02,135.61) ; U11.F7 213.52,127.82 v2(213.52,127.81)
UNNAMED_44_ADLTC298024_I313_VSENSEP3: length 9.8
  TOP w0.191: C149.1 v2(214.43,128.5)
  L3_SIGNAL w0.114: v2(214.43,128.5) 214.4,128.52
  L3_SIGNAL w0.191: 214.4,128.52 214.8,128.92 215.23,128.92 215.5,129.2 215.5,134.92 214.53,135.89 v2(214.53,136.04)
  BOTTOM w0.191: v2(214.43,128.5) 214.43,128.38 U11.E7 ; R139.2 214.94,136.46 v2(214.53,136.04)
UNNAMED_44_ADLTC298024_I313_VSENSEP4: length 5.4
  L3_SIGNAL w0.191: v2(213.54,129.44) 213.57,129.44 213.88,129.75 v2(213.88,133.14)
  BOTTOM w0.191: v2(213.88,133.14) 213.88,134.18 R141.2 ; U11.F9 213.73,129.75 213.54,129.56 v2(213.54,129.44)
UNNAMED_44_ADLTC298024_I313_VSENSEP5: length 9.9
  TOP w0.191: C147.1 216.08,130.02 v2(216.66,129.44)
  L5_MIXED w0.114: v2(216.66,129.44) 216.73,129.44 218.67,131.37 218.67,133.12 218.14,133.65 217.43,133.65 217.04,134.04 v2(217.04,134.49)
  BOTTOM w0.191: v2(216.66,129.44) 216.57,129.44 U11.C9 ; v2(217.04,134.49) 217.18,134.36 217.18,133.81 R609.2 R622.2
UNNAMED_44_ADLTC298024_I313_VSENSEP6: length 6.5
  TOP w0.191: v2(218.85,130.48) 218.85,130.48 218.55,130.18 C146.1
  BOTTOM w0.191: R667.2 R623.2 219.78,131.41 v2(218.85,130.48) 218.16,129.79 218.04,129.79 218,129.75 U11.A9
UNNAMED_44_ADLTC298024_I313_VSENSEP7: length 5.3
  BOTTOM w0.191: U11.A8 217.87,128.95 v2(218.24,129.31) 219.21,129.31 221.12,131.22 R492.2
UNNAMED_44_ADLTC298024_I313_WP: length 7.4
  BOTTOM w0.191: R626.2 R495.1 221.57,122.5 219.92,124.15 U11.A2
UNNAMED_44_CAP_I261_N1: length 8.5
  TOP w0.191: 225.86,123.52 225.86,124.12 225.76,124.22 225.76,124.83 225.57,125.03 223.71,125.03 223.29,124.61 223.29,124.08 223.74,123.63 Q9.5 ; 225.86,123.52 225.65,123.52 225.39,123.26 Q9.2 ; 225.86,123.52 C706.1 226.48,124.61 R627.1
UNNAMED_44_DIOLED_I227_N: length 5.3
  TOP w0.191: DS31.C 206.55,112.53 v1(205.99,113.08)
  BOTTOM w0.191: v1(205.99,113.08) 205.82,112.9 204.32,112.9 204.3,112.88 203.82,112.88 203.81,112.9 203.63,112.9 202.61,113.93 Q11.3
UNNAMED_44_DIOLED_I227_P: length 2.2
  TOP w0.191: R605.1 206.05,114.57 206.88,113.74 DS31.A
UNNAMED_44_DIOLED_I310_N: length 1.9
  TOP w0.191: DS17.C 208.64,112.56 v1(209.77,112.56)
  BOTTOM w0.191: Q10.3 v1(209.77,112.56)
UNNAMED_44_DIOLED_I310_P: length 2
  TOP w0.191: R158.1 209.08,114.11 DS17.A
UNNAMED_44_RES_I240_N2: length 2.4
  TOP w0.191: R601.2 R632.1 222.44,124.48 Q18.1
UNNAMED_44_RES_I260_N2: length 8.6
  TOP w0.191: S3.2B 227.21,131.94 227.21,126.63 S3.2A 227.3,124.78 R627.2 R630.2
UNNAMED_44_RES_I282_N2: length 7.1
  TOP w0.191: R629.2 229.84,133.01 229.84,133.01 S3.1B S3.1A
UNNAMED_44_RES_I286_N1: length 1.9
  BOTTOM w0.191: R636.1 201.26,114.64 201.53,114.37 Q11.5 202,114.47 202.22,114.69 Q11.6
UNNAMED_44_RES_I292_N1: length 2.2
  BOTTOM w0.191: Q10.5 211.02,113.16 Q10.6 211.24,114.5 R635.1
UNNAMED_44_RES_I295_N2: length 1.1
  BOTTOM w0.191: Q11.2 203.9,114.74 R634.2
UNNAMED_44_RES_I296_N2: length 1.3
  BOTTOM w0.191: R633.2 211.08,111.09 Q10.2
UNNAMED_45_ADLT199010_I200_: length 1.3
  BOTTOM w0.191: R80.2 201.17,143.21 A1.4
UNNAMED_45_ADLT199010_I200__1: length 1.3
  BOTTOM w0.191: A1.1 199.19,143.21 R79.2
UNNAMED_45_ADLT199010_I200_OUT: length 14.4
  L22_MIXED w0.114: v2(199.01,127.74) 198.15,127.74 197.71,128.17 197.71,131.39 199.69,133.38 199.69,136.66 v2(200.5,137.47)
  BOTTOM w0.191: R661.1 198.18,128.32 198.18,128.14 198.35,127.97 198.53,127.97 198.76,127.74 v2(199.01,127.74) ; A1.6 v2(200.5,137.47)
UNNAMED_45_ADLT199010_I200_V: length 1.9
  BOTTOM w0.191: R706.2 C522.2 199.85,137.3 A1.7
UNNAMED_45_ADLT199010_I200_V_1: length 1.9
  BOTTOM w0.191: R704.2 C523.2 201.15,137.34 A1.5
UNNAMED_45_ADLT199010_I201_: length 1.3
  BOTTOM w0.191: R671.2 205.49,143.21 A2.4
UNNAMED_45_ADLT199010_I201__1: length 1.3
  BOTTOM w0.191: A2.1 203.53,143.2 R81.2
UNNAMED_45_ADLT199010_I201_OUT: length 13
  L22_MIXED w0.191: v2(198.98,130.56) 199.26,130.84 201.37,130.84 204.01,133.48 204.01,136.61 v2(204.82,137.42)
  BOTTOM w0.191: A2.6 v2(204.82,137.42) ; R657.1 198.15,130.37 198.35,130.56 v2(198.98,130.56)
UNNAMED_45_ADLT199010_I201_V: length 2
  BOTTOM w0.191: A2.7 204.17,137.28 C526.2 R707.2
UNNAMED_45_ADLT199010_I201_V_1: length 1.9
  BOTTOM w0.191: R705.2 C527.2 205.47,137.29 A2.5
UNNAMED_45_ADLTC298024_I19_REFM: length 0.6
  TOP w0.191: C723.2 201.47,123.11 v2(201.54,123.04)
  BOTTOM w0.191: U11.AA1 v2(201.54,123.04)
UNNAMED_45_ADLTC298024_I19_REFP: length 0.6
  TOP w0.191: v2(201.5,123.8) 201.5,123.71 C723.1
  BOTTOM w0.191: U11.AA2 201.85,124.15 v2(201.5,123.8)
UNNAMED_45_ADLTC298024_I19_SCL: length 7
  TOP w0.191: R672.2 v2(202.21,120.45)
  L22_MIXED w0.114: v2(202.21,120.45) 202.39,120.62 202.39,122.1 202.75,122.46 202.75,123.06 203.08,123.39 v2(203.08,123.69)
  BOTTOM w0.191: v2(202.21,120.45) 202.21,120.54 202.73,121.06 203.38,121.06 203.72,120.71 R708.2 ; v2(203.08,123.69) 203.08,123.77 U11.W2
UNNAMED_45_ADLTC298024_I19_SDA: length 4.3
  TOP w0.191: R78.2 202.9,120.55 v2(202.82,120.47) R673.2
  L22_MIXED w0.114: v2(202.82,120.47) 202.7,120.59 202.7,121.83 203.1,122.22 v2(203.1,122.91)
  BOTTOM w0.191: v2(203.1,122.91) 203.1,122.99 U11.W1
UNNAMED_45_ADLTC298024_I19_VDD251: length 1.1
  BOTTOM w0.191: U11.R3 v2(206.31,124.6) 206.2,124.6 U11.T3
UNNAMED_45_ADLTC298024_I19_VPWR: length 1.6
  TOP w0.191: R684.2 206.11,126.92 v2(206.27,126.92) 206.14,126.79 C720.1
  BOTTOM w0.191: U11.R5 206.65,126.55 v2(206.27,126.92)
UNNAMED_45_ADLTC298024_I19_VSENSEM7: length 6.4
  L3_SIGNAL w0.191: v2(205.65,132.87) 205.65,131.58 205.33,131.27 205.33,128.73 v2(205.49,128.57)
  BOTTOM w0.191: R656.2 205.64,133.69 C547.2 v2(205.65,132.87) ; v2(205.49,128.57) 205.85,128.94 U11.T8
UNNAMED_45_ADLTC298024_I19_VSENSEP0: length 3.4
  TOP w0.191: v2(201.3,125.77) 201.24,125.83 C549.1
  BOTTOM w0.191: U11.AA4 201.33,125.75 v2(201.3,125.77) 200.82,125.77 200.81,125.76 R662.2
UNNAMED_45_ADLTC298024_I19_VSENSEP1: length 6.4
  TOP w0.191: C550.1 203.87,126.29 v2(203.87,126.2)
  L24_SIGNAL w0.198: v2(203.87,126.2) 203.07,127 199.62,127 v2(199.06,126.44)
  BOTTOM w0.191: R663.2 v2(199.06,126.44) ; v2(203.87,126.2) 203.68,126.4 203.66,126.4 203.5,126.55 U11.W5
UNNAMED_45_ADLTC298024_I19_VSENSEP2: length 4.6
  TOP w0.191: v2(202.31,127.8) 202.34,127.83 C551.1
  L24_SIGNAL w0.191: v2(202.31,127.8) 199.91,127.8 v2(199.29,128.42)
  BOTTOM w0.191: v2(199.29,128.42) R661.2 ; U11.Y7 v2(202.31,127.8)
UNNAMED_45_ADLTC298024_I19_VSENSEP3: length 7.2
  TOP w0.191: C548.1 203.22,127.81 v2(203.81,127.81)
  L24_SIGNAL w0.191: v2(199.23,129.92) 199.54,129.61 201.48,129.61 202.05,129.04 202.58,129.04 v2(203.81,127.81)
  BOTTOM w0.191: v2(203.81,127.81) 203.47,128.15 U11.W7 ; R657.2 v2(199.23,129.92)
UNNAMED_45_ADLTC298024_I19_VSENSEP4: length 5.7
  TOP w0.191: v2(202.64,133.25) 202.15,132.76 202.15,129.62 v2(202.34,129.44)
  BOTTOM w0.191: v2(202.64,133.25) 202.64,133.74 C552.1 202.63,133.78 R664.2 ; U11.Y9 202.65,129.75 v2(202.34,129.44)
UNNAMED_45_ADLTC298024_I19_VSENSEP7: length 6.2
  L3_SIGNAL w0.191: v2(206.3,128.6) 206.32,128.62 206.32,131.58 206.22,131.67 v2(206.22,132.87)
  BOTTOM w0.191: R655.2 206.2,133.69 C547.1 206.19,132.98 206.22,132.94 v2(206.22,132.87) ; v2(206.3,128.6) 206.65,128.95 U11.R8
UNNAMED_45_ADLTC298024_I19_WP: length 5.9
  L3_SIGNAL w0.191: v2(206.99,123.83) 206.99,122.94 206.76,122.71 206.76,121.76 206.29,121.29 206.29,120.87 206.31,120.86 206.31,119.92 v1(206.25,119.86)
  BOTTOM w0.191: v1(206.25,119.86) 205.83,119.86 R676.2 205.8,119.17 R677.2 ; U11.R2 206.98,123.83 v2(206.99,123.83)
UNNAMED_45_RES_I109_N1: length 1.8
  TOP w0.191: R686.1 R685.2 222.13,116.42 Q22.1
UNNAMED_46_ADLTC298024_I23_REFM: length 0.5
  BOTTOM w0.191: U11.P1 207.77,123.04 v2(207.78,123.04)
UNNAMED_46_ADLTC298024_I23_REFP: length 0.5
  BOTTOM w0.191: U11.P2 207.77,123.84 v2(207.77,123.83)
UNNAMED_46_ADLTC298024_I23_SCL: length 7.1
  TOP w0.191: R646.2 v2(209.22,118.86) 209.22,118.97 209.17,119.02 R68.2
  L3_SIGNAL w0.114: v2(209.22,118.86) 209.22,118.92 209.45,119.15 209.45,121.08 208.91,121.62 208.91,122.89 209.37,123.34 v2(209.37,123.8)
  BOTTOM w0.191: v2(209.37,123.8) 209.37,123.84 U11.M2
UNNAMED_46_ADLTC298024_I23_SDA: length 6.1
  TOP w0.191: R647.2 209.8,118.58 v2(209.8,118.88) 209.8,119.29 210.01,119.49 R703.2
  L3_SIGNAL w0.114: v2(209.8,118.88) 209.8,121.36 209.27,121.89 v2(209.27,122.71)
  BOTTOM w0.191: v2(209.27,122.71) 209.05,122.92 U11.M1
UNNAMED_46_ADLTC298024_I23_VDD251: length 1.4
  BOTTOM w0.191: 211.47,124.95 211.49,124.95 211.61,124.84 212.06,124.84 212.18,124.95 U11.H3 ; 211.47,124.95 v1(211.84,124.59) ; 211.47,124.95 U11.J3
UNNAMED_46_ADLTC298024_I23_VPWR: length 1.5
  TOP w0.191: R658.2 211.78,126.32 v2(211.91,126.19) C715.1
  BOTTOM w0.191: v2(211.91,126.19) 212.25,126.53 U11.H5
UNNAMED_46_ADLTC298024_I23_VSENSEM1: length 8.7
  L3_SIGNAL w0.191: v2(209.3,132.92) 209.75,132.46 209.75,127.52 209.24,127 v2(208.71,127)
  BOTTOM w0.191: v2(209.3,132.92) 209.46,133.08 C539.2 209.42,133.71 R669.2 ; U11.M6 v2(208.71,127)
UNNAMED_46_ADLTC298024_I23_VSENSEM3: length 6.4
  L3_SIGNAL w0.191: v2(208.56,132.61) 208.56,132.44 208.86,132.14 208.86,128.75 v2(208.71,128.6)
  BOTTOM w0.191: v2(208.56,132.61) 208.7,132.76 C541.2 208.71,133.71 R625.2 ; U11.M8 v2(208.71,128.6)
UNNAMED_46_ADLTC298024_I23_VSENSEM5: length 5.7
  L3_SIGNAL w0.191: v2(211.84,129.39) 211.46,129.77 211.46,132.85 v2(211.33,132.97)
  BOTTOM w0.191: R645.2 211.33,133.77 C542.2 211.33,133.74 v2(211.33,132.97) ; U11.J9 211.47,129.75 v2(211.84,129.39)
UNNAMED_46_ADLTC298024_I23_VSENSEM7: length 6.9
  L3_SIGNAL w0.191: v2(211.84,128.59) 212.05,128.59 212.55,129.08 212.55,132.54 v2(212.47,132.61)
  BOTTOM w0.191: v2(212.47,132.61) 212.07,133.01 C543.2 212.09,133.77 R648.2 ; v2(211.84,128.59) 211.47,128.95 U11.J8
UNNAMED_46_ADLTC298024_I23_VSENSEP0: length 17.7
  TOP w0.191: v2(214.17,113.49) 214.17,114.14 R654.1
  L5_MIXED w0.191: v2(214.17,113.49) 214.17,115.06 212.22,117.02 212.22,119.6 211.48,120.34 211.48,121.03 212.12,121.67 212.12,122.35 209.62,124.85 208.51,124.85 207.96,125.4 v2(207.11,125.4)
  BOTTOM w0.191: U11.P4 v2(207.11,125.4)
UNNAMED_46_ADLTC298024_I23_VSENSEP1: length 9.4
  L3_SIGNAL w0.191: v2(210,132.96) 210,132.78 210.16,132.62 210.16,127.37 208.99,126.2 v2(208.71,126.2)
  BOTTOM w0.191: U11.M5 v2(208.71,126.2) ; v2(210,132.96) C539.1 210,134.21 R668.2
UNNAMED_46_ADLTC298024_I23_VSENSEP2: length 7.4
  L3_SIGNAL w0.191: v2(207.91,127.8) 207.31,128.39 207.31,132.71 v2(207.14,132.89)
  BOTTOM w0.191: R670.2 C540.1 207.49,133.25 v2(207.14,132.89) ; U11.N7 v2(207.91,127.8)
UNNAMED_46_ADLTC298024_I23_VSENSEP3: length 7.4
  L3_SIGNAL w0.191: v2(208.08,132.74) 208.14,132.67 208.14,132.3 208.46,131.98 208.46,128.91 208.31,128.76 208.31,128.44 208.46,128.29 208.46,128.09 208.71,127.84 v2(208.71,127.8)
  BOTTOM w0.191: R624.2 208.15,133.71 C541.1 208.08,133.62 v2(208.08,132.74) ; U11.M7 v2(208.71,127.8)
UNNAMED_46_ADLTC298024_I23_VSENSEP5: length 5.6
  L3_SIGNAL w0.191: v2(211.04,129.39) 211.04,132.71 210.94,132.81 210.94,133.13 v2(210.78,133.29)
  BOTTOM w0.191: U11.K9 210.67,129.75 v2(211.04,129.39) ; v2(210.78,133.29) C542.1 210.74,133.79 R649.2
UNNAMED_46_ADLTC298024_I23_VSENSEP7: length 6.5
  L3_SIGNAL w0.191: v2(212.71,133.12) 212.71,133.06 212.94,132.83 212.94,128.89 v2(212.64,128.59)
  BOTTOM w0.191: U11.H8 212.27,128.95 v2(212.64,128.59) ; R652.2 212.65,133.79 C543.1 212.7,133.67 212.7,133.13 v2(212.71,133.12)
UNNAMED_46_ADLTC298024_I23_WP: length 6
  L3_SIGNAL w0.191: v2(212.57,123.8) 212.57,121.21 v2(213.11,120.68)
  BOTTOM w0.191: R650.2 212.43,119.38 R651.1 212.43,119.99 212.9,120.45 212.9,120.47 v2(213.11,120.68) ; U11.H2 212.57,123.83 v2(212.57,123.8)
UNNAMED_46_NCTESTPAD_I77_N1: length 2
  TOP w0.191: v4(212.7,114.15) R654.2 213.7,114.22 R788.1
UNNAMED_46_RES_I50_N2: length 1.8
  TOP w0.191: Q13.1 222.2,119.55 R659.2 R660.1
UNNAMED_47_CN560PYMV2_I18_TDI: length 1.3
  BOTTOM w0.191: P1.D30 P1.D31
UNNAMED_48_FXLA104_I244_A0: length 3.1
  TOP w0.191: R593.2 71.3,87.05 69.87,85.61 U41.3
UNNAMED_48_FXLA104_I244_A1: length 2.7
  TOP w0.191: R591.2 69.47,87.03 U41.4
UNNAMED_48_FXLA104_I244_A2: length 2.7
  TOP w0.191: R594.2 69.07,87.13 U41.5
UNNAMED_48_FXLA104_I244_A3: length 3
  TOP w0.191: U41.6 68.67,85.79 67.61,86.84 R592.2
UNNAMED_48_FXLA104_I257_A0: length 4.2
  TOP w0.191: R178.2 62.15,43.54 62.86,43.54 64.14,42.26 U24.3
UNNAMED_48_FXLA104_I257_A1: length 3.8
  TOP w0.191: R172.2 62.58,41.86 U24.4
UNNAMED_48_FXLA104_I257_A2: length 3.7
  TOP w0.191: R175.2 62.36,41.46 U24.5
UNNAMED_48_FXLA104_I257_A3: length 4
  TOP w0.191: U24.6 63.62,41.06 62.64,40.08 62.13,40.08 R179.2
UNNAMED_48_FXLA104_I257_B0: length 4.3
  TOP w0.191: R213.1 70.54,43.74 69.06,42.26 U24.12
UNNAMED_48_FXLA104_I257_B1: length 4
  TOP w0.191: U24.11 69.62,41.86 70.36,42.6 R221.1
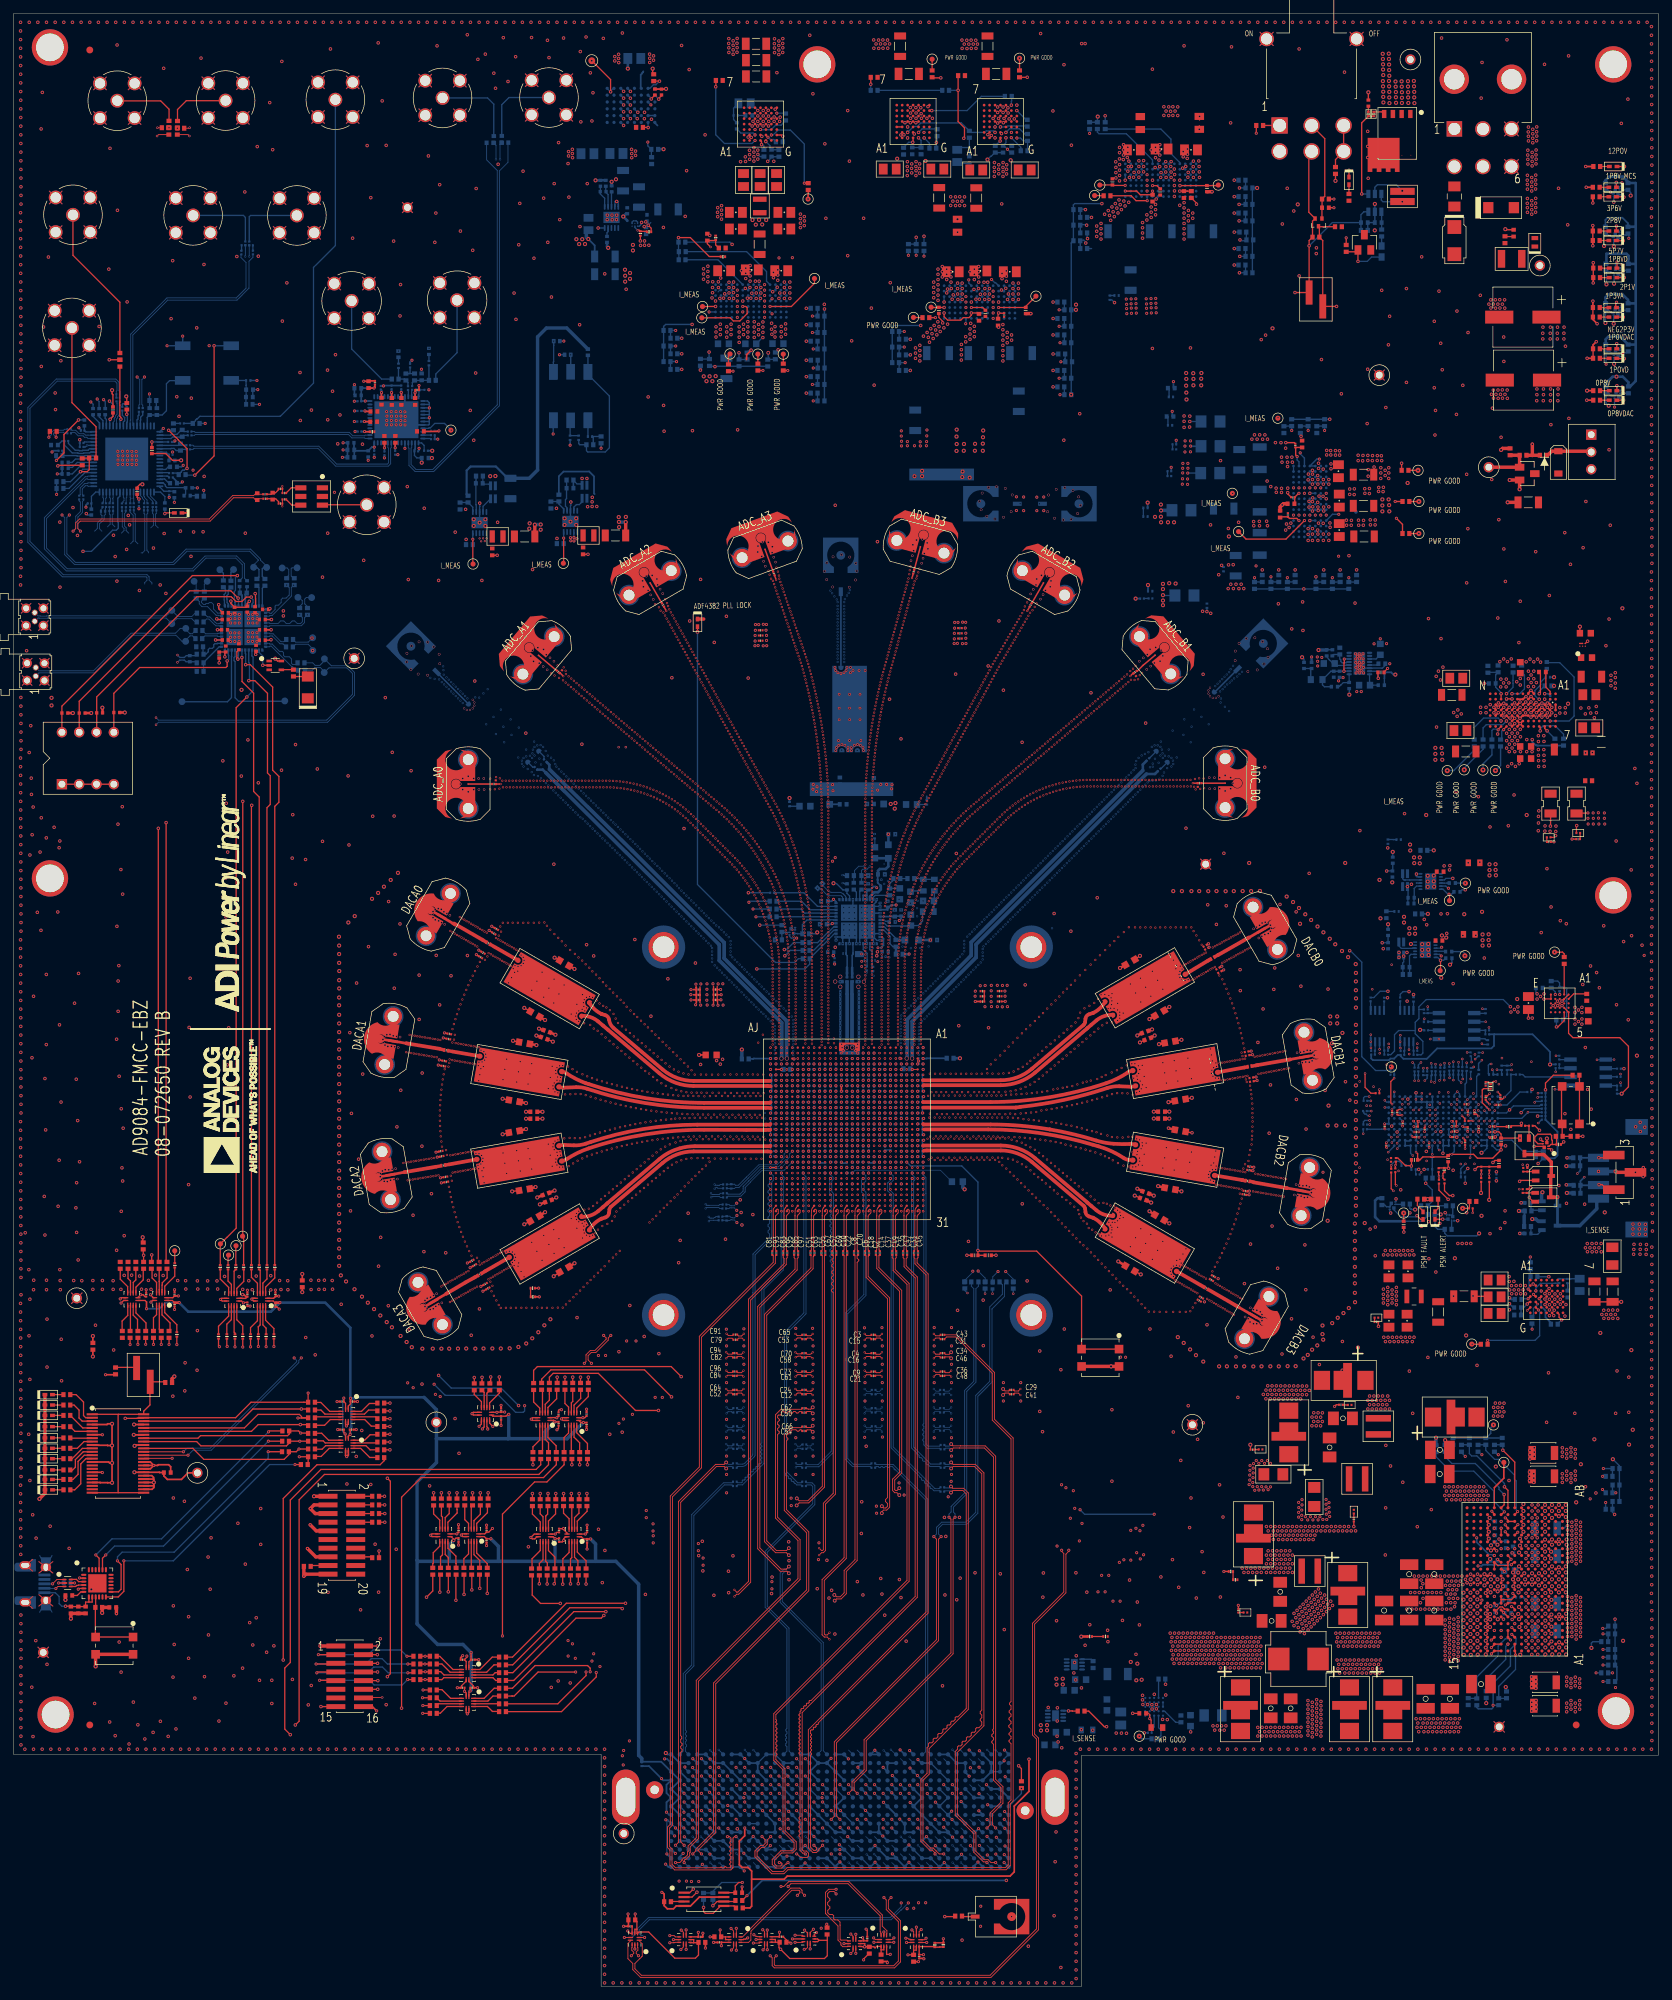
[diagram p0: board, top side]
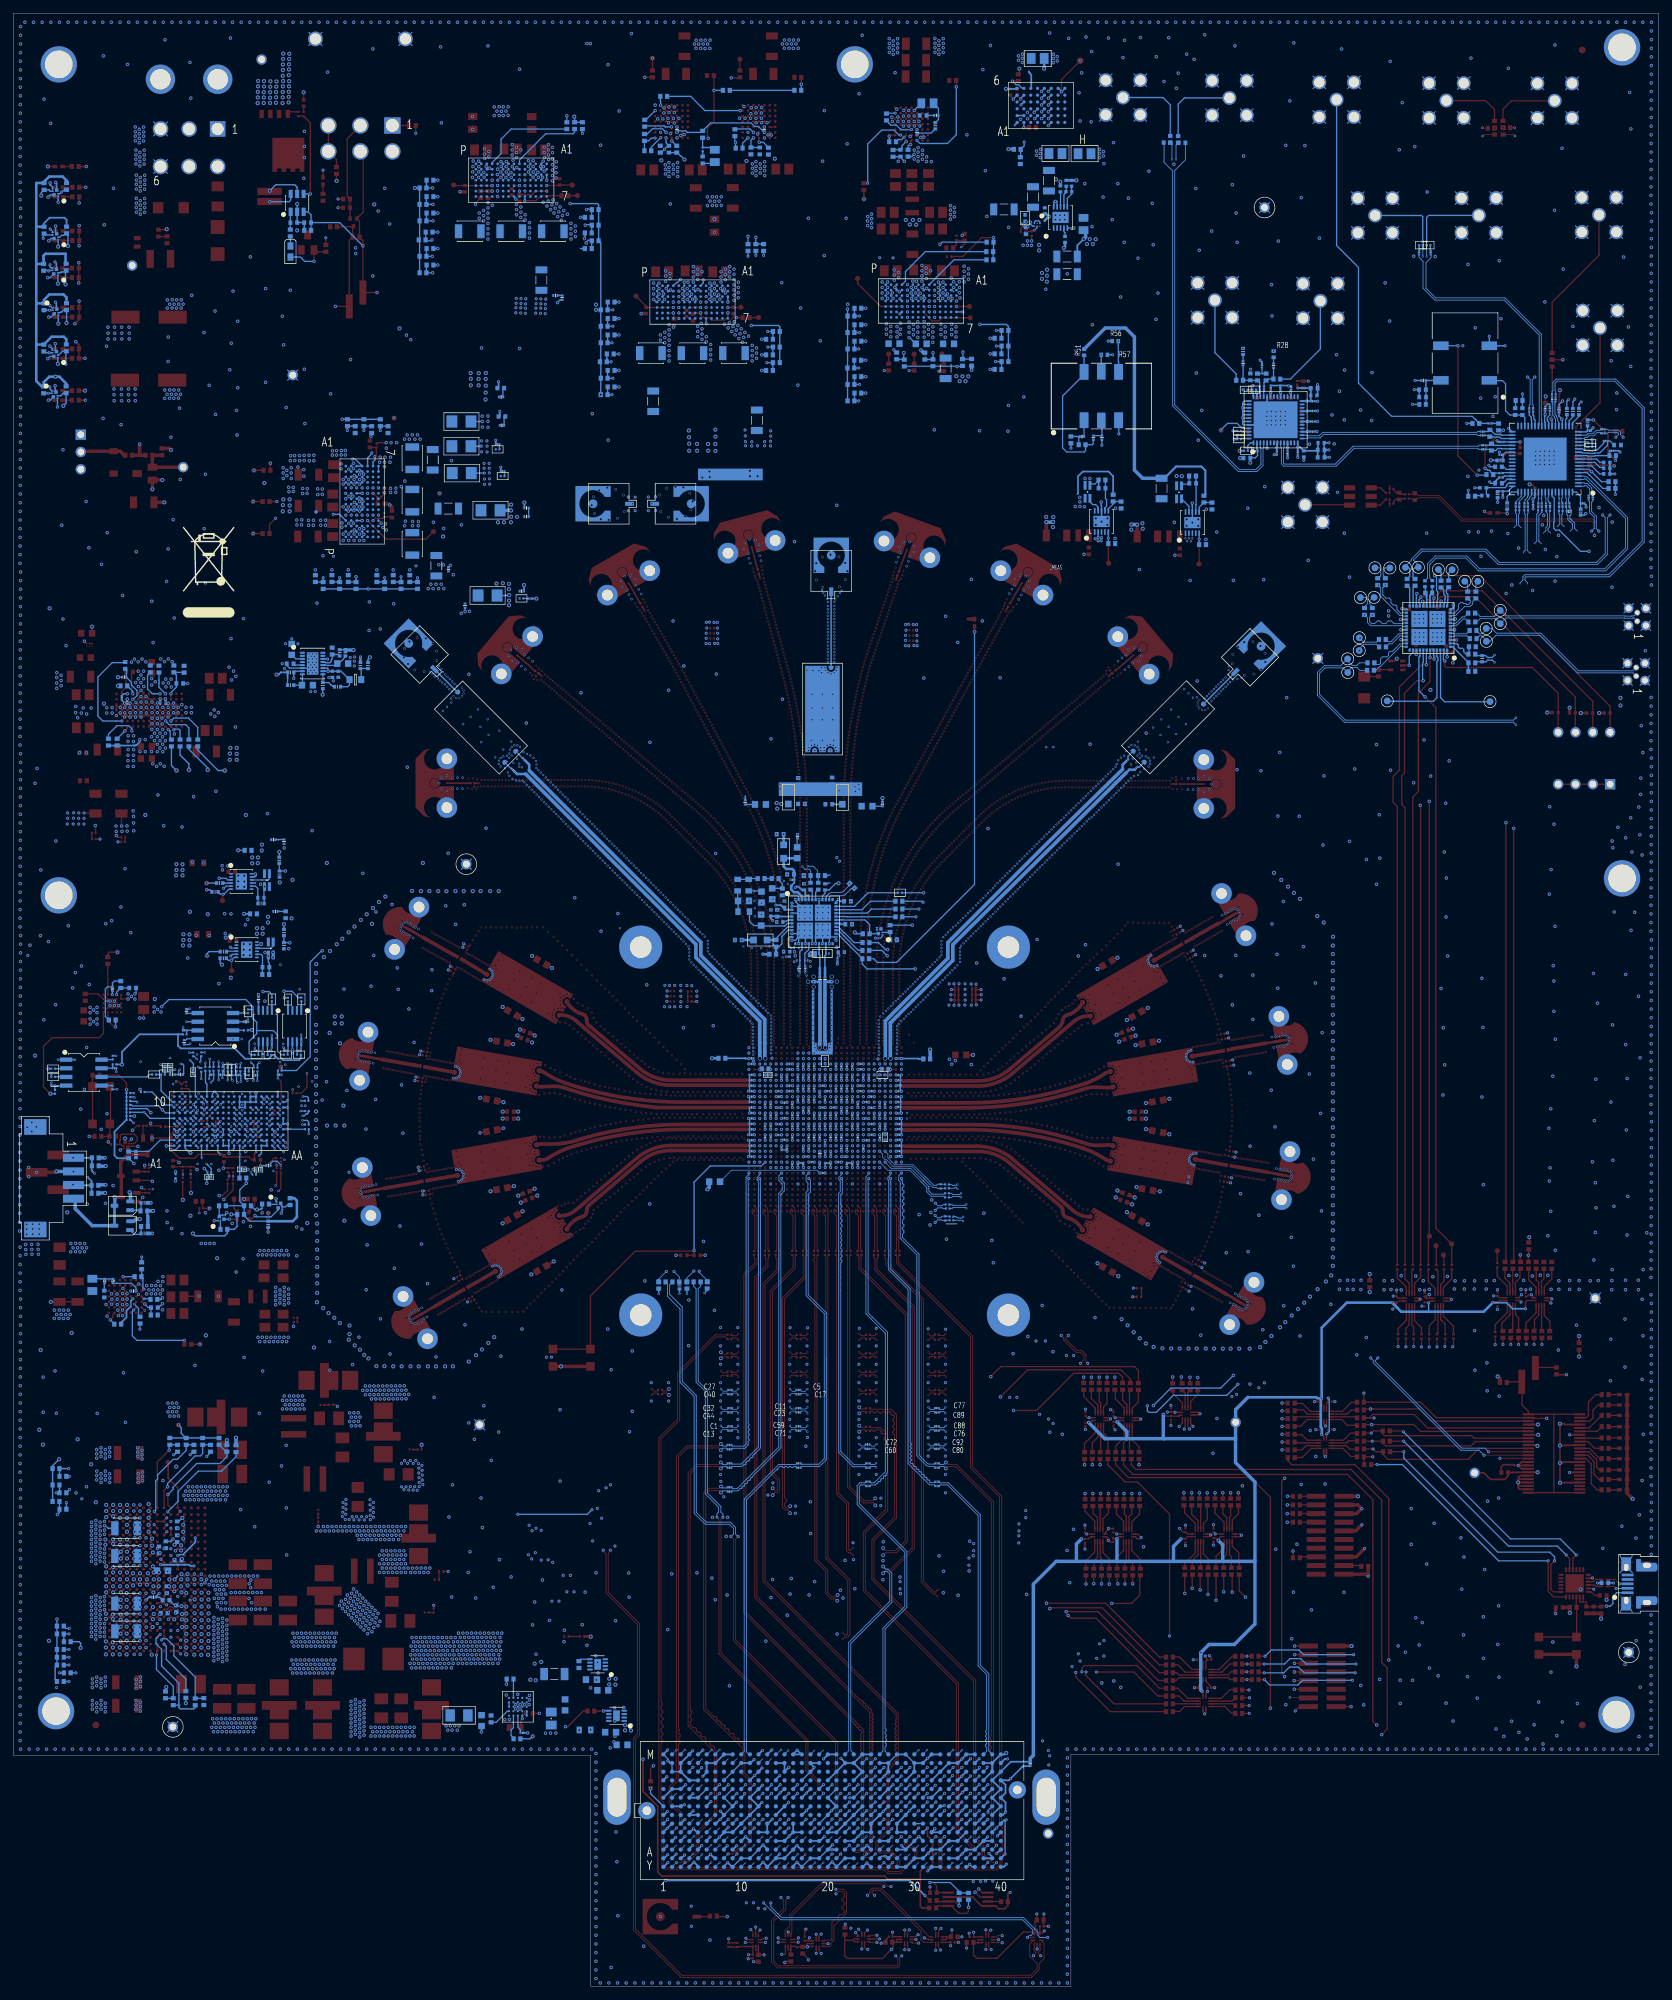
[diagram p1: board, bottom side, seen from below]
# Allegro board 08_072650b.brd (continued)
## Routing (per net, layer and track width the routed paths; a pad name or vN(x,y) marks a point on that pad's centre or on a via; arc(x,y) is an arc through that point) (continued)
UNNAMED_48_FXLA104_I257_B2: length 3.7
  TOP w0.191: R231.1 71.26,41.46 U24.10
UNNAMED_48_FXLA104_I257_B3: length 4
  TOP w0.191: R225.1 71.24,40.34 70.28,40.34 69.56,41.06 U24.9
UNNAMED_48_FXLA104_I258_A0: length 4.4
  TOP w0.191: U23.3 64.49,46.49 62.56,48.41 62.13,48.41 R181.2
UNNAMED_48_FXLA104_I258_A1: length 4.1
  TOP w0.191: R177.2 62.86,47.29 64.07,46.09 U23.4
UNNAMED_48_FXLA104_I258_A2: length 3.8
  TOP w0.191: R174.2 62.13,46.18 62.69,46.18 63.18,45.69 U23.5
UNNAMED_48_FXLA104_I258_A3: length 3.7
  TOP w0.191: U23.6 63.14,45.29 62.86,45.01 R171.2
UNNAMED_48_FXLA104_I258_B0: length 4.5
  TOP w0.191: R230.1 70.26,48.31 68.43,46.49 U23.12
UNNAMED_48_FXLA104_I258_B1: length 4.2
  TOP w0.191: R218.1 70.51,47.17 69.43,46.09 U23.11
UNNAMED_48_FXLA104_I258_B2: length 3.9
  TOP w0.191: U23.10 70.35,45.69 70.69,46.02 R210.1
UNNAMED_48_FXLA104_I258_B3: length 3.9
  TOP w0.191: R206.1 70.76,44.88 70.36,45.29 U23.9
UNNAMED_48_FXLA104_I264_A0: length 4.3
  TOP w0.191: U25.3 46.4,84.36 45.09,85.67 44.26,85.67 R191.2
UNNAMED_48_FXLA104_I264_A1: length 4
  TOP w0.191: U25.4 45.71,83.96 45.11,84.56 44.24,84.56 R182.2
UNNAMED_48_FXLA104_I264_A2: length 3.8
  TOP w0.191: U25.5 44.37,83.56 R197.2
UNNAMED_48_FXLA104_I264_A3: length 4.2
  TOP w0.191: R184.2 44.28,82.32 45.64,82.32 46.48,83.16 U25.6
UNNAMED_48_FXLA104_I264_B0: length 4.1
  TOP w0.191: U25.12 51.06,84.36 52.22,85.52 53.34,85.52 R232.1
UNNAMED_48_FXLA104_I264_B1: length 3.9
  TOP w0.191: R219.1 53.27,84.56 52.1,84.56 51.5,83.96 U25.11
UNNAMED_48_FXLA104_I264_B2: length 3.7
  TOP w0.191: U25.10 53.12,83.56 R211.1
UNNAMED_48_FXLA104_I264_B3: length 4
  TOP w0.191: U25.9 51.54,83.16 52.5,82.19 53.34,82.19 R207.1
UNNAMED_48_FXLA104_I265_A0: length 4.2
  TOP w0.191: R198.2 44.25,81.15 45.21,81.15 46.23,80.13 U26.3
UNNAMED_48_FXLA104_I265_A1: length 3.9
  TOP w0.191: U26.4 45.74,79.73 45.44,80.04 44.28,80.04 R185.2
UNNAMED_48_FXLA104_I265_A2: length 4
  TOP w0.191: R192.2 44.26,78.82 45.29,78.82 45.8,79.33 U26.5
UNNAMED_48_FXLA104_I265_A3: length 4.3
  TOP w0.191: U26.6 46.32,78.93 45.14,77.75 44.28,77.75 R199.2
UNNAMED_48_FXLA104_I265_B0: length 3.9
  TOP w0.191: R214.1 53.31,80.92 52.32,80.92 51.53,80.13 U26.12
UNNAMED_48_FXLA104_I265_B1: length 3.6
  TOP w0.191: R222.1 53.26,79.73 U26.11
UNNAMED_48_FXLA104_I265_B2: length 3.8
  TOP w0.191: U26.10 51.71,79.33 52.32,78.72 R233.1
UNNAMED_48_FXLA104_I265_B3: length 4.1
  TOP w0.191: R226.1 53.37,77.6 52.27,77.6 50.94,78.93 U26.9
UNNAMED_48_FXLA104_I271_A0: length 4
  TOP w0.191: U27.3 82.73,68.26 84.18,69.7 84.18,70.44 R193.2
UNNAMED_48_FXLA104_I271_A1: length 3.7
  TOP w0.191: U27.4 82.33,68.77 82.98,69.42 82.98,70.44 R183.2
UNNAMED_48_FXLA104_I271_A2: length 3.4
  TOP w0.191: R200.2 81.93,70.4 U27.5
UNNAMED_48_FXLA104_I271_A3: length 3.7
  TOP w0.191: U27.6 81.53,68.61 80.72,69.42 80.72,70.46 R186.2
UNNAMED_48_FXLA104_I271_B0: length 4.5
  TOP w0.191: R234.1 84.02,61.31 84.02,62.43 82.73,63.72 U27.12
UNNAMED_48_FXLA104_I271_B1: length 4.2
  TOP w0.191: R220.1 82.83,61.36 82.83,62.46 82.33,62.95 U27.11
UNNAMED_48_FXLA104_I271_B2: length 4
  TOP w0.191: R212.1 81.74,62.72 81.93,62.91 U27.10
UNNAMED_48_FXLA104_I271_B3: length 4.3
  TOP w0.191: U27.9 81.53,63.65 80.62,62.74 80.62,61.33 R208.1
UNNAMED_48_FXLA104_I276_A0: length 3.9
  TOP w0.191: U28.3 78.51,68.27 79.55,69.32 79.55,70.44 R201.2
UNNAMED_48_FXLA104_I276_A1: length 3.5
  TOP w0.191: R187.2 78.38,70.41 78.38,69.29 78.11,69.01 U28.4
UNNAMED_48_FXLA104_I276_A2: length 3.6
  TOP w0.191: U28.5 77.71,68.9 77.29,69.32 77.29,70.46 R194.2
UNNAMED_48_FXLA104_I276_A3: length 3.9
  TOP w0.191: R202.2 76.15,70.46 76.15,69.29 77.31,68.13 U28.6
UNNAMED_48_FXLA104_I276_B0: length 4.3
  TOP w0.191: R215.1 79.45,62.99 78.51,63.94 U28.12
UNNAMED_48_FXLA104_I276_B1: length 4.1
  TOP w0.191: R223.1 78.33,61.33 78.33,62.15 78.11,62.38 U28.11
UNNAMED_48_FXLA104_I276_B2: length 4.2
  TOP w0.191: R235.1 77.17,62.06 77.71,62.59 U28.10
UNNAMED_48_FXLA104_I276_B3: length 4.5
  TOP w0.191: R227.1 76.1,61.38 76.1,62.74 77.31,63.95 U28.9
UNNAMED_48_FXLA104_I281_A0: length 4.2
  TOP w0.191: U29.3 67.98,67.93 69.55,69.49 69.55,70.46 R195.2
UNNAMED_48_FXLA104_I281_A1: length 3.9
  TOP w0.191: U29.4 67.58,68.34 68.51,69.27 R188.2
UNNAMED_48_FXLA104_I281_A2: length 3.6
  TOP w0.191: U29.5 67.18,70.38 R203.2
UNNAMED_48_FXLA104_I281_A3: length 3.7
  TOP w0.191: R189.2 66.22,68.48 66.78,67.92 U29.6
UNNAMED_48_FXLA104_I281_B0: length 4.5
  TOP w0.191: U29.12 67.98,63.57 69.52,62.02 R236.1
UNNAMED_48_FXLA104_I281_B1: length 4.3
  TOP w0.191: U29.11 67.58,63.34 68.43,62.48 68.43,61.46 R224.1
UNNAMED_48_FXLA104_I281_B2: length 3.9
  TOP w0.191: U29.10 67.18,61.47 R216.1
UNNAMED_48_FXLA104_I281_B3: length 4.2
  TOP w0.191: U29.9 66.78,63.45 66.09,62.77 R209.1
UNNAMED_48_FXLA104_I287_A0: length 4
  TOP w0.191: U44.3 78.43,84.93 79.71,86.21 79.71,87.45 R254.2
UNNAMED_48_FXLA104_I287_A1: length 3.7
  TOP w0.191: U44.4 78.03,85.4 78.64,86 78.64,86.91 78.64,86.92 R242.2
UNNAMED_48_FXLA104_I287_A2: length 3.5
  TOP w0.191: R248.2 77.63,87.4 U44.5
UNNAMED_48_FXLA104_I287_A3: length 3.8
  TOP w0.191: U44.6 77.23,84.83 76.33,85.74 R255.2
UNNAMED_48_FXLA104_I287_B0: length 4.5
  TOP w0.191: U44.12 78.43,80.52 79.63,79.32 79.63,78.4 R268.1
UNNAMED_48_FXLA104_I287_B1: length 4.2
  TOP w0.191: R274.1 78.51,79.77 78.03,80.25 U44.11
UNNAMED_48_FXLA104_I287_B2: length 4.1
  TOP w0.191: U44.10 77.63,78.63 R281.1
UNNAMED_48_FXLA104_I287_B3: length 4.4
  TOP w0.191: U44.9 77.23,80.16 76.23,79.16 R277.1
UNNAMED_48_FXLA104_I293_A0: length 4
  TOP w0.191: U42.3 63.75,68.1 65.1,69.46 65.1,69.93 65.08,69.95 R204.2
UNNAMED_48_FXLA104_I293_A1: length 3.7
  TOP w0.191: U42.4 63.35,68.77 63.94,69.36 R190.2
UNNAMED_48_FXLA104_I293_A2: length 3.5
  TOP w0.191: U42.5 62.95,68.86 62.79,69.02 R196.2
UNNAMED_48_FXLA104_I293_A3: length 3.9
  TOP w0.191: R205.2 61.65,69.31 62.55,68.41 U42.6
UNNAMED_48_FXLA104_I293_B0: length 4.4
  TOP w0.191: U42.12 63.75,64.29 64.92,63.12 64.92,62.05 64.95,62.02 R217.1
UNNAMED_48_FXLA104_I293_B1: length 4.1
  TOP w0.191: R228.1 63.81,62.91 63.35,63.37 U42.11
UNNAMED_48_FXLA104_I293_B2: length 4
  TOP w0.191: U42.10 62.95,63.32 62.67,63.03 R237.1
UNNAMED_48_FXLA104_I293_B3: length 4.3
  TOP w0.191: R229.1 61.52,62.02 61.59,62.1 61.59,63.63 62.55,64.58 U42.9
UNNAMED_48_FXLA104_I296_A0: length 4.1
  TOP w0.191: R247.2 84.36,86.54 82.66,84.84 U43.3
UNNAMED_48_FXLA104_I296_A1: length 3.8
  TOP w0.191: R238.2 83.24,87.51 83.24,86.26 82.26,85.28 U43.4
UNNAMED_48_FXLA104_I296_A2: length 3.5
  TOP w0.191: R253.2 82.07,85.82 81.87,85.62 81.87,84.14 U43.5
UNNAMED_48_FXLA104_I296_A3: length 3.6
  TOP w0.191: R241.2 80.93,85.52 81.46,84.99 U43.6
UNNAMED_48_FXLA104_I296_B0: length 4.6
  TOP w0.191: U43.12 82.66,81.22 84.23,79.65 R280.1
UNNAMED_48_FXLA104_I296_B1: length 4.3
  TOP w0.191: R271.1 83.09,79.75 82.26,80.58 U43.11
UNNAMED_48_FXLA104_I296_B2: length 4
  TOP w0.191: R265.1 81.86,78.46 U43.10
UNNAMED_48_FXLA104_I296_B3: length 4.2
  TOP w0.191: R262.1 80.8,80.52 81.46,81.18 U43.9
UNNAMED_48_FXLA104_I300_A0: length 4.1
  TOP w0.191: U45.3 36.99,102.6 38.33,103.94 R249.2
UNNAMED_48_FXLA104_I300_A1: length 3.8
  TOP w0.191: U45.4 36.59,103.19 37.19,103.79 R239.2
UNNAMED_48_FXLA104_I300_A2: length 3.6
  TOP w0.191: U45.5 36.19,105.05 R256.2
UNNAMED_48_FXLA104_I300_A3: length 3.9
  TOP w0.191: U45.6 35.79,103.15 34.9,104.04 R243.2
UNNAMED_48_FXLA104_I300_B0: length 4.7
  TOP w0.191: U45.12 36.99,97.73 38.2,96.52 R282.1
UNNAMED_48_FXLA104_I300_B1: length 4.4
  TOP w0.191: R272.1 37.06,96.57 36.59,97.04 U45.11
UNNAMED_48_FXLA104_I300_B2: length 4.3
  TOP w0.191: U45.10 36.19,97.05 35.92,96.77 35.92,96.77 R266.1
UNNAMED_48_FXLA104_I300_B3: length 4.6
  TOP w0.191: R263.1 34.78,96.65 35.79,97.66 U45.9
UNNAMED_48_FXLA104_I305_A0: length 4
  TOP w0.191: R257.2 33.78,105.17 33.78,103.43 32.76,102.41 U46.3
UNNAMED_48_FXLA104_I305_A1: length 3.6
  TOP w0.191: U46.4 32.36,104.94 R244.2
UNNAMED_48_FXLA104_I305_A2: length 3.7
  TOP w0.191: R250.2 31.47,103.48 31.96,102.99 U46.5
UNNAMED_48_FXLA104_I305_A3: length 4
  TOP w0.191: U46.6 31.56,102.55 30.33,103.78 R258.2
UNNAMED_48_FXLA104_I305_B0: length 4.6
  TOP w0.191: R269.1 33.63,96.92 32.76,97.8 U46.12
UNNAMED_48_FXLA104_I305_B1: length 4.2
  TOP w0.191: R275.1 32.49,95.85 32.36,95.98 U46.11
UNNAMED_48_FXLA104_I305_B2: length 4.5
  TOP w0.191: U46.10 31.96,97.82 31.3,97.16 R283.1
UNNAMED_48_FXLA104_I305_B3: length 4.8
  TOP w0.191: R278.1 30.08,96.85 31.56,98.34 U46.9
UNNAMED_48_FXLA104_I312_A0: length 4
  TOP w0.191: R260.2 19.02,105.23 19.02,103.66 17.95,102.59 U48.3
UNNAMED_48_FXLA104_I312_A1: length 3.7
  TOP w0.191: R246.2 17.94,103.65 17.56,103.28 17.56,101.74 U48.4
UNNAMED_48_FXLA104_I312_A2: length 3.7
  TOP w0.191: U48.5 17.15,103.5 16.79,103.86 16.79,105.29 R252.2
UNNAMED_48_FXLA104_I312_A3: length 4
  TOP w0.191: U48.6 16.74,101.75 16.74,102.67 15.65,103.76 R261.2
UNNAMED_48_FXLA104_I312_B0: length 4.4
  TOP w0.191: U48.12 17.95,98.81 19.43,97.33 19.43,96.2 R270.1
UNNAMED_48_FXLA104_I312_B1: length 4.1
  TOP w0.191: U48.11 17.55,98.48 18.19,97.84 18.19,96.21 R276.1
UNNAMED_48_FXLA104_I312_B2: length 3.8
  TOP w0.191: R285.1 17.14,96.2 17.14,99.92 U48.10
UNNAMED_48_FXLA104_I312_B3: length 4.1
  TOP w0.191: R279.1 15.93,96.18 15.93,97.61 16.75,98.44 U48.9
UNNAMED_48_FXLA104_I318_A0: length 4.3
  TOP w0.191: R251.2 23.65,104.19 22.18,102.72 U47.3
UNNAMED_48_FXLA104_I318_A1: length 3.9
  TOP w0.191: U47.4 21.78,102.21 21.79,102.21 21.79,102.89 21.82,102.92 21.82,103.23 22.53,103.94 22.53,105.27 R240.2
UNNAMED_48_FXLA104_I318_A2: length 3.6
  TOP w0.191: R259.2 21.36,103.45 21.37,103.44 21.37,102.21 21.38,102.21 U47.5
UNNAMED_48_FXLA104_I318_A3: length 3.9
  TOP w0.191: U47.6 20.98,103.28 20.32,103.94 20.32,105.19 R245.2
UNNAMED_48_FXLA104_I318_B0: length 4.7
  TOP w0.191: R284.1 23.96,97.08 22.18,98.85 U47.12
UNNAMED_48_FXLA104_I318_B1: length 4.3
  TOP w0.191: R273.1 22.96,96.3 22.96,97.33 21.78,98.51 U47.11
UNNAMED_48_FXLA104_I318_B2: length 3.9
  TOP w0.191: R267.1 21.38,96.44 U47.10
UNNAMED_48_FXLA104_I318_B3: length 4
  TOP w0.191: U47.9 20.98,98.55 20.53,98.1 R264.1
UNNAMED_50_7416244V3_I101_O0: length 5.8
  TOP w0.191: R468.1 9.17,86.82 10.26,85.72 10.26,83.74 10.57,83.43 U35.2
UNNAMED_50_7416244V3_I101_O1: length 4.9
  TOP w0.191: U35.3 10.06,82.93 9.6,83.39 9.6,84.56 8.86,85.29 R467.1
UNNAMED_50_7416244V3_I101_O2: length 4
  TOP w0.191: U35.5 10.15,81.93 R466.1
UNNAMED_50_7416244V3_I101_O3: length 3.5
  TOP w0.191: R465.1 9,81.43 U35.6
UNNAMED_50_7416244V3_I101_O4: length 3.2
  TOP w0.191: U35.8 8.35,80.43 R464.1
UNNAMED_50_7416244V3_I101_O5: length 3.6
  TOP w0.191: R462.1 9.35,78.94 10.34,79.93 U35.9
UNNAMED_50_7416244V3_I101_O6: length 3.9
  TOP w0.191: R461.1 8.59,77.42 10.1,78.93 U35.11
UNNAMED_50_7416244V3_I101_O7: length 5
  TOP w0.191: U35.12 10.21,78.43 9.06,77.28 9.06,76.16 8.66,75.77 R463.1
UNNAMED_50_7416244V3_I101_O8: length 5.8
  TOP w0.191: U35.13 10.37,77.93 9.46,77.02 9.46,75.13 8.7,74.37 R460.1
UNNAMED_50_7416244V3_I101_O9: length 6.8
  TOP w0.191: R459.1 8.97,72.85 9.86,73.74 9.86,76.66 10.63,77.43 U35.14
UNNAMED_50_7416244V3_I101_OE1N: length 34
  TOP w0.191: R637.1 22.16,88.7 BUFDIS.2 20.05,87.68 20.02,87.64 20.02,85.31 19.09,84.38 U35.48 15.39,83.93 ; 15.39,83.93 U35.1 ; 15.39,83.93 15.34,83.88 15.34,72.43 ; 15.34,72.43 U35.24 ; 15.34,72.43 U35.25
UNNAMED_50_CAP_I45_N1: length 1.9
  TOP w0.191: U22.6 9.88,57.88 9.35,57.35 C225.1
UNNAMED_50_CAP_I132_N1: length 1.1
  TOP w0.191: U21.5 v4(8.94,59.18)
  BOTTOM w0.191: v4(8.94,59.18) 8.92,59.21 C124.1
UNNAMED_50_CN2P_I136_N1: length 3.1
  TOP w0.191: BUFDIS.1 17.96,90.82 14.98,90.82 R458.1
UNNAMED_50_CN20PV2_I15_N9: length 2.6
  TOP w0.191: R163.1 43.73,61.75 P3.17
UNNAMED_50_CN20PV2_I16_N1: length 2.4
  TOP w0.191: R164.1 P3.2
UNNAMED_50_CN20PV2_I16_N2: length 2.4
  TOP w0.191: R167.1 P3.4
UNNAMED_50_CN20PV2_I16_N3: length 2.4
  TOP w0.191: R165.1 P3.6
UNNAMED_50_CN20PV2_I16_N4: length 2.4
  TOP w0.191: R168.1 P3.8
UNNAMED_50_CN20PV2_I16_N8: length 2.5
  TOP w0.191: P3.16 52.51,63.02 R166.1
UNNAMED_50_DIOLED_I70_P: length 1.6
  TOP w0.191: DS27.A R468.2
UNNAMED_50_DIOLED_I73_P: length 1.6
  TOP w0.191: DS26.A R467.2
UNNAMED_50_DIOLED_I76_P: length 1.6
  TOP w0.191: DS25.A R466.2
UNNAMED_50_DIOLED_I79_P: length 1.6
  TOP w0.191: R465.2 DS24.A
UNNAMED_50_DIOLED_I82_P: length 1.6
  TOP w0.191: R464.2 DS23.A
UNNAMED_50_DIOLED_I85_P: length 1.6
  TOP w0.191: DS22.A R463.2
UNNAMED_50_DIOLED_I88_P: length 1.6
  TOP w0.191: DS21.A R462.2
UNNAMED_50_DIOLED_I91_P: length 1.6
  TOP w0.191: DS20.A R461.2
UNNAMED_50_DIOLED_I94_P: length 1.6
  TOP w0.191: DS19.A R460.2
UNNAMED_50_DIOLED_I97_P: length 1.6
  TOP w0.191: DS18.A R459.2
UNNAMED_50_ICM24CXX_I130_E2: length 1.9
  TOP w0.191: U20.3 96.52,12.45 R161.1
UNNAMED_50_ICM24CXX_I130_SCL: length 4.5
  TOP w0.191: v1(102.64,11.84) 103.26,12.45 U20.6 105.8,12.45 R160.1
  BOTTOM w0.191: R711.2 v1(102.64,11.84)
UNNAMED_50_ICM24CXX_I130_SDA: length 7.2
  TOP w0.191: v1(101.27,11.58) 101.27,10.97 101.52,10.72 102.69,10.72 103.77,11.8 U20.5 105.73,11.8 R162.2
  BOTTOM w0.191: R712.2 v1(101.27,11.58)
UNNAMED_51_ADP7112_I30_EN: length 1.4
  BOTTOM w0.191: U74.C1 91.59,258.84 91.39,259.04 90.98,259.04 90.79,258.85 U74.A1
UNNAMED_51_ADP7112_I30_SENSE: length 2.2
  TOP w0.191: v2(91.61,257.64) 91.85,257.64 R815.1 92.89,257.49 R816.2
  BOTTOM w0.191: U74.B2 91.19,258.06 v2(91.61,257.64)
UNNAMED_51_ADP7159V2_I59_BYP: length 1.3
  BOTTOM w0.191: C852.1 87.1,257.28 87.26,257.44 U73.4
UNNAMED_51_ADP7159V2_I59_EN: length 8.6
  L24_SIGNAL w0.114: v1(88.52,261.87) 88.47,261.82 87.45,261.82 85.8,260.17 v1(85.8,257.98)
  BOTTOM w0.191: v1(85.8,257.98) U73.5 ; U73.10 88.75,261.09 88.75,261.87 v1(88.52,261.87) 88.26,261.87 U73.9
UNNAMED_51_ADP7159V2_I59_REF: length 3.2
  BOTTOM w0.191: C857.1 86.92,263.37 R808.1 86.97,263.18 87.26,262.89 U73.7
UNNAMED_51_ADP7159V2_I59_REFSENSE: length 3.3
  BOTTOM w0.191: U73.6 86.76,262.34 86.11,262.99 R808.2 86.13,263.35 R809.1
UNNAMED_51_ADP7159V2_I59_VREG: length 2.2
  BOTTOM w0.191: C854.1 87.76,263.26 U73.8
UNNAMED_51_CAP_I15_N1: length 7.2
  TOP w0.191: v1(87.63,277.96) 87.63,279.76 v1(84.86,282.52)
  BOTTOM w0.191: 87.05,278.5 87.06,278.5 87.55,278 ; 88.05,278.5 88.05,278.5 87.55,278 ; 87.55,278 87.6,277.96 v1(87.63,277.96)
UNNAMED_51_CAP_I20_N1: length 1.6
  TOP w0.191: C847.1 93.6,276.96 v1(93.6,276.91)
  BOTTOM w0.191: U72.B5 93.6,277 v1(93.6,276.91)
UNNAMED_51_LINLTM8053_I4_AUX: length 1
  BOTTOM w0.191: U72.B2 93.37,274.47 93.4,274.49 93.85,274.49 93.87,274.47 U72.A2
UNNAMED_51_LINLTM8053_I4_FB: length 1.5
  TOP w0.191: v1(93.14,272.72) 93.12,272.75 R807.2
  BOTTOM w0.191: v1(93.14,272.72) 93.13,272.73 U72.B1
UNNAMED_51_LINLTM8053_I4_RT: length 1.6
  TOP w0.191: v1(94.69,276.89) 94.69,276.99 95.1,277.39 R797.1
  BOTTOM w0.191: v1(94.69,276.89) 94.69,276.91 U72.A5
UNNAMED_51_LINLTM8053_I4_RUN: length 3
  TOP w0.191: v1(94.81,279.53) 94.8,279.53 R794.2
  BOTTOM w0.191: v1(94.81,279.53) 94.28,279 93.91,279 93.38,278.47 U72.B6
UNNAMED_51_LINLTM8053_I4_SYNC: length 10.2
  L24_SIGNAL w0.191: v4(93.09,270.59) 94.12,270.59 94.31,270.78 94.31,275.79 94.06,276.05 v4(93.55,276.05)
  BOTTOM w0.191: v4(93.09,270.59) 93.09,270.04 R811.1 93.61,268.41 R810.2 ; v4(93.55,276.05) 93.13,276.47 U72.B4
UNNAMED_52_741G04_I115_A: length 3.4
  TOP w0.191: U50.2 37.49,193.83 v1(36.58,193.83)
  BOTTOM w0.191: v1(36.58,193.83) 36.58,195.17 36.01,195.74 U51.38
UNNAMED_52_741G04_I115_Y: length 1.8
  TOP w0.191: R734.2 39.33,193.18 U50.4
UNNAMED_52_ADF4030_I1_BSYNC0: length 4.9
  BOTTOM w0.191: U51.1 30.18,196.54 27.88,194.24 R721.1 R781.1
UNNAMED_52_ADF4030_I1_BSYNC0_1: length 4.8
  BOTTOM w0.191: R780.1 27.81,195.53 R720.1 27.93,195.5 28.27,195.5 28.58,195.81 28.58,196.13 28.77,196.32 29.18,196.32 29.37,196.51 29.37,196.83 29.52,196.99 29.87,196.99 29.93,197.04 U51.2
UNNAMED_52_ADF4030_I1_VDD18TDC: length 2.7
  TOP w0.191: E15.1 30.19,195.78 C786.1 31.01,195.64 v1(31.01,195.07)
  BOTTOM w0.191: U51.48 v1(31.01,195.07)
UNNAMED_52_CN2P4GNDV2_I35_N1: length 24.9
  BOTTOM w0.133: R752.2 26.64,200.18 26.15,200.67 23.96,200.67 TP63.1 22.38,200.76 5,200.76 4.97,200.73 3.77,200.73 3.73,200.76 3.58,200.76 P19.1
UNNAMED_52_CN2P4GNDV2_I35_N2: length 24.9
  BOTTOM w0.133: P19.2 3.58,201.07 3.86,201.07 3.89,201.04 4.84,201.04 4.88,201.07 22.41,201.07 TP62.1 24.11,200.98 26.15,200.98 26.64,201.47 R751.2
UNNAMED_52_CN2P4GNDV2_I39_N1: length 26.9
  BOTTOM w0.133: R745.2 26.27,198.14 25.89,198.14 25.25,197.5 TP61.1 24.71,197.33 23.83,198.22 17.37,198.22 11.86,192.71 3.73,192.71 P18.1
UNNAMED_52_CN2P4GNDV2_I39_N2: length 26.8
  BOTTOM w0.133: R740.2 26.22,198.45 25.89,198.45 25.27,199.07 TP60.1 24.46,199.24 23.76,198.53 17.24,198.53 11.73,193.02 3.73,193.02 P18.2
UNNAMED_52_DIOLED_I118_P: length 2.1
  TOP w0.191: DS29.A 41.08,192.18 R734.1
UNNAMED_52_NCTESTPAD_I164_N1: length 1.7
  BOTTOM w0.133: TP54.1 27.99,205.71 R732.2
UNNAMED_52_NCTESTPAD_I165_N1: length 1.8
  BOTTOM w0.191: R749.2 31.9,207.49 TP56.1
UNNAMED_52_NCTESTPAD_I167_N1: length 2.6
  BOTTOM w0.133: TP48.1 40.88,208.13 40.74,207.99 40.74,206.93 41.1,206.57 41.12,206.6 R743.2
UNNAMED_52_NCTESTPAD_I168_N1: length 1.6
  BOTTOM w0.133: TP55.1 26.8,205.84 R733.2
UNNAMED_52_NCTESTPAD_I170_N1: length 2.4
  BOTTOM w0.133: TP49.1 40.13,208.1 40.39,207.85 40.39,207.06 40.08,206.76 R744.2
UNNAMED_52_NCTESTPAD_I175_N1: length 2.6
  BOTTOM w0.133: R725.2 43.13,202.44 42.72,202.84 42.72,203.53 42.96,203.77 43.73,203.77 TP52.1
UNNAMED_52_NCTESTPAD_I176_N1: length 2.1
  BOTTOM w0.133: R726.2 41.99,202.46 42.37,202.84 42.37,203.32 41.9,203.78 TP53.1
UNNAMED_52_NCTESTPAD_I177_N1: length 1.8
  BOTTOM w0.191: R750.2 30.78,207.34 TP57.1
USB_DN: length 3.1
  TOP w0.133: v4(6.2,58.37) 6.5,58.67 7.44,58.67
  BOTTOM w0.133: v4(6.2,58.37) 4.56,58.37 P4.2
USB_DP: length 3.2
  TOP w0.133: v4(5.72,59.05) 6.35,59.69 U21.1
  BOTTOM w0.133: v4(5.72,59.05) P4.3
USB_UART_DN: length 2
  TOP w0.191: U22.4 9.54,58.88 9.48,58.82 9.26,58.82 9.11,58.67 8.41,58.67
USB_UART_DP: length 2
  TOP w0.191: U22.3 9.54,59.38 9.21,59.72 8.43,59.72 U21.6
VCMA_A0:
  vias: v4(117.5,134.53)
VCMA_A1: length 0.1
  BOTTOM w0.191: v4(117.48,135.33) 117.41,135.33 C489.1
VCMA_B0:
  vias: v4(127.09,134.53)
VCMA_B1:
  vias: v4(127.1,135.33)
VCMD_A: length 0.5
  BOTTOM w0.191: R476.2 v1(175.16,201.7)
  vias: v1(174.52,201.75) v1(175.72,201.45) v4(113.5,128.93) v4(113.5,127.33) v4(113.5,126.53) v4(113.5,124.93)
VCMD_B: length 0.9
  BOTTOM w0.191: C468.1 131.13,127.35 v4(131.1,127.33) ; C464.1 131.13,128.95 v4(131.1,128.93) ; v4(131.1,126.53) 131.13,126.51 C472.1 ; v4(131.1,124.93) 131.13,124.91 C475.1 ; R479.1 177.56,208.24 v1(177.32,208.48)
  vias: v1(178.33,208.56) v1(179.02,208.58)
VNEGM1P0_ADC: length 66.7
  TOP w0.254: v4(121.5,132.13) v4(121.5,131.33)
  L24_SIGNAL w0.191: 209.25,145.19 211.61,142.82 216.51,142.82 219.99,139.34 230.48,139.34 235.18,134.65 v1(236.37,134.65)
  L24_SIGNAL w0.254: 209.25,145.19 205.94,148.49 202.36,148.49 198.63,152.22 198.63,162.56 200.33,164.26 204.85,164.26 v1(205.92,163.19)
  BOTTOM w0.191: U10.11 206.18,162.78 206.16,162.8 205.96,162.8 205.77,162.99 ; R683.1 v1(236.37,134.65) ; R131.2 v3(202.44,166.45)
  vias: v3(204.98,167.51) v3(205,166.65) v3(205.56,165.63) v3(205.59,164.8) v3(206.4,165.63) v3(206.4,164.77) v4(117.5,132.13) v4(117.5,131.33) v4(123.1,132.13) v4(123.1,131.33) v4(127.1,132.13) v4(127.1,131.33)
VNEGM1P0_ADC_I+: length 46.7
  L24_SIGNAL w0.114: v1(205.49,145.52) 205.49,146.79 204.57,147.7 201.88,147.7 197.97,151.61 197.97,166.55 201.08,169.66 210.46,169.66 214.24,165.88 214.24,165.29 213.79,164.85 v1(213.51,164.85)
  BOTTOM w0.191: R671.1 v1(205.49,145.52)
  vias: v3(207.57,162.94) v3(207.57,162.1) v3(207.57,161.32) v3(208.46,162.97) v3(208.46,162.13) v3(208.51,161.34)
VNEGM1P0_ADC_PG: length 33.5
  L22_MIXED w0.191: v2(219.88,134.45) 219.3,135.03 219.3,137.21 217.25,139.27 217.25,154.94 216.46,155.73 215.54,155.73 213.88,157.39 213.88,161.07 v1(213.08,161.87)
  BOTTOM w0.191: v2(219.88,134.45) R665.1 219.23,133.79 R623.1 ; R549.2 v1(213.08,161.87)
VNEGM1P0_DAC: length 47.1
  TOP w0.381: C366.2 v3(167.36,128.34) ; C362.1 v3(169.64,127.32) ; C361.2 v3(164.94,139.51) ; C629.2 v3(164.94,117.03) ; C367.1 v3(166.98,115) ; C357.1 v3(167.48,139.51) ; C341.1 v3(75.21,127.3) ; 78.03,115.05 v3(77.24,114.73) ; C349.2 v3(79.4,116.76) ; C336.1 v3(76.74,139.49) ; C339.2 v3(79.53,139.62) ; C344.2 v3(77.63,128.32)
  L3_SIGNAL w0.203: v3(205.1,152.93) 205.38,152.65 205.38,147.98 206.45,146.91 206.45,144.7 205.38,143.64 205.38,141.4 v3(206.45,140.33)
  L24_SIGNAL w0.508: v3(206.45,140.33) 204.55,142.24 196.42,142.24 194.56,144.09 191.6,144.09 v1(188.96,146.74)
  BOTTOM w0.191: C702.1 111.67,127.33 v4(111.9,127.33) ; R370.1 206.99,140.33 v3(206.45,140.33)
  BOTTOM w0.203: R130.2 v3(201.75,155.83)
  BOTTOM w0.254: C375.2 132.84,133.73 v4(132.7,133.73) ; v4(111.9,124.93) 111.69,124.93 C699.1 ; C345.2 111.83,133.73 v4(111.9,133.73) ; C698.1 111.71,124.15 v4(111.9,124.15) ; C385.2 132.84,130.53 v4(132.7,130.53) ; v4(132.7,124.93) 132.84,124.93 C397.2 ; v4(128.7,124.13) 128.62,124.13 C694.1 ; v4(132.7,131.33) 132.84,131.33 C381.2 ; C700.1 111.71,121.73 v4(111.9,121.73) ; C393.2 132.84,127.33 v4(132.7,127.33) ; v4(132.7,124.13) 132.84,124.13 C401.2 ; v4(132.7,128.13) 132.84,128.13 C389.2 ; C703.1 128.72,126.53 v4(128.7,126.53)
  vias: v1(49.35,139.92) v1(49.45,113.78) v1(49.59,128.08) v1(50.34,147.2) v1(50.64,121.37) v1(51.24,133.85) v1(52.09,152.54) v1(53.57,105.66) v1(53.88,109.89) v1(55.04,159.16) v1(55,99.86) v1(55.88,146.45) v1(55.99,151.41) v1(56.26,126.1) v1(56.71,155.88) v1(56.83,131.48) v1(58.07,96.35) v1(58.63,113.14) v1(59.53,148.37) v1(59.53,141.86) v1(59.97,134) v1(59.93,123.27) v1(60.22,107.8) v1(61.33,116.3) v1(62.03,151.26) v1(62.54,144) v1(63.43,107.62) v1(64.2,148.27) v1(66.61,151.24) v1(67.17,95.53) v1(68.38,99.39) v1(180.02,149.17) v1(180.06,146.09) v1(183.4,143.4) v1(184.97,146.28) v1(185.11,149.42) v3(204.09,156.92) v3(204.09,156.08) v3(204.88,155.24) v3(204.88,154.43) v3(205.71,155.24) v3(205.71,154.43) v4(111.9,131.33) v4(111.9,130.53) v4(111.9,128.13) v4(115.9,129.73) v4(115.9,128.93) v4(115.9,127.33) v4(115.9,126.53) v4(115.9,124.93) v4(115.9,124.13) v4(128.7,129.73) v4(128.7,128.93) v4(128.7,127.33) v4(128.7,124.93) v4(132.7,121.73)
VNEGM1P0_DAC_I+: length 27.1
  L3_SIGNAL w0.114: v1(207.06,156.54) 206.93,156.54 206.82,156.65 206.82,156.72 205.2,158.33 203.47,158.33 203.11,157.97 203.11,155.8 203.61,155.3 203.61,153.95 202.62,152.96 202.62,150.64 202.94,150.31 202.94,146.14 201.84,145.05 v1(201.67,145.05)
  L24_SIGNAL w0.114: v1(212.72,154.18) 212.72,154.18 212.39,154.51 211.09,154.51 210.69,154.91 207.45,154.91 206.99,155.37 206.99,156.47 v1(207.06,156.54)
  BOTTOM w0.191: R80.1 v1(201.67,145.05)
  vias: v3(206.76,152.91) v3(206.76,152.07) v3(206.76,151.28) v3(207.65,152.93) v3(207.65,152.1) v3(207.7,151.31)
VNEGM1P0_DAC_PG: length 23
  L22_MIXED w0.191: v2(217.73,134.49) 217.73,136.12 215.91,137.94 215.91,138.46 214.55,139.82 214.55,150.62 213.97,151.21 v1(213.03,151.21)
  BOTTOM w0.191: R622.1 218.41,133.82 R666.1 217.77,134.45 v2(217.73,134.49) ; R548.2 212.75,151.82 213.03,151.54 v1(213.03,151.21)
VNEGM1P0_EN_ADC: length 51.9
  L22_MIXED w0.191: v1(221.28,128.19) 221.28,129.21 220.4,130.1 220.4,139.9 218.82,141.48 218.82,158.32 213.86,163.28 211.98,163.28 v1(211.25,162.56)
  L24_SIGNAL w0.191: v2(216.66,126.97) 217.12,127.43 220.52,127.43 v1(221.28,128.19)
  BOTTOM w0.191: R156.1 221.84,128.78 221.28,128.22 v1(221.28,128.19) ; v1(211.25,162.56) 210.24,162.56 210,162.33 U10.3 ; v2(216.66,126.97) 217.04,127.35 U11.B6
VNEGM1P0_EN_DAC: length 48.2
  L3_SIGNAL w0.191: v2(218.47,136.19) 218.47,138.13 215.04,141.55 215.04,150.04 v1(215.87,150.88)
  L5_MIXED w0.191: v2(222.78,135.66) 225.7,132.74 225.7,129.69 v1(223.7,127.69)
  L22_MIXED w0.191: v1(223.7,127.69) 216.59,127.69 215.87,126.97 v2(215.87,126.95)
  L24_SIGNAL w0.191: v1(215.87,150.88) 214.29,152.46 v4(209.61,152.46) ; v2(222.78,135.66) 222.28,136.17 218.49,136.17 v2(218.47,136.19)
  BOTTOM w0.191: v4(209.61,152.46) 209.47,152.32 U9.3 ; R155.1 v1(223.7,127.69) ; U11.C6 215.87,126.97 v2(215.87,126.95)
VREF_1P2_A: length 3.2
  BOTTOM w0.254: v4(111.1,136.13) 108.61,136.13 108.55,136.07 R302.1
VREF_1P2_A_F: length 128
  L16_POWER w0.508: v3(191.54,196.06) 192.35,196.06 193.01,195.4 193.01,180.04 182.85,169.88 173.94,169.88 156.38,152.31 156.38,146.09 149.69,139.41 108.85,139.41 v3(106.89,137.45)
  BOTTOM w0.191: R424.2 R423.2
  BOTTOM w0.508: R302.2 v3(106.89,137.45) ; v3(191.54,196.06) 192.69,196.06 R423.2
VREF_1P2_B: length 3.6
  BOTTOM w0.254: R301.1 134.07,136.17 134.03,136.13 v4(133.5,136.13) 133.49,136.15 C463.1
VREF_1P2_B_F: length 99.4
  L16_POWER w0.508: v3(202.82,192.46) 202.82,186.79 184.61,168.58 175.34,168.58 159.85,153.1 159.85,145.76 150.27,136.17 v3(138.91,136.17)
  BOTTOM w0.191: R421.2 201.21,191.9
  BOTTOM w0.254: v3(202.82,192.46) 202.54,192.46 202.21,192.79 R422.2 201.21,191.9
  BOTTOM w0.381: v3(138.91,136.17) R301.2
VSUP_VCXO: length 44.4
  BOTTOM w0.318: R457.2 72.52,221.26 70.79,222.99 67.08,222.99 66.5,222.4 66.5,218.91 R454.1
  BOTTOM w0.508: R457.2 75.69,221.26 76.91,222.48 76.91,242.01 78.21,243.31 81.19,243.31 R51.1
VUSB: length 10.6
  TOP w0.191: U22.7 11.05,57.13 11.05,56.39 ; 11.05,56.39 10.57,56.39 C222.1 C142.1 C224.1 8.35,55.78 v1(7.62,55.78) ; 11.05,56.39 11.53,56.39 11.53,57.13 U22.8
  BOTTOM w0.191: P4.1 6.13,57.76 6.68,57.2 6.68,56.16 7.06,55.78 v1(7.62,55.78)

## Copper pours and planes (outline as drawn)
5VBIAS on TOP: 229.36,199.21 229.36,196.9 230.45,196.9 230.45,199.21
5VBIAS on BOTTOM, L3_SIGNAL: 118.87,245.64 119.18,245.64 119.43,245.9 119.43,247.09 119.18,247.35 118.87,247.35 118.62,247.09 118.62,245.9
5VBIAS on L18_POWER: 154.86,246.99 154.86,233.07 157.2,233.07 157.2,246.99
AVDD1P0_CK on BOTTOM: 171.22,230.91 171.22,229.62 169.75,229.62 169.75,228.5 170.15,228.09 175.44,228.09 175.44,230.91
AVDD1P0_CK on L7_POWER: 186.99,202.84 186.99,230.89 166.17,230.89 163.55,228.27 163.55,221.08 167.54,221.08 174.37,214.25 174.37,191.39 163.55,180.57 163.55,159.14 139.7,136.32 135.91,136.32 133.76,134.16 126.75,134.16 126.75,133.5 126.67,133.43 123.49,133.43 123.49,134.16 121.13,134.16 121.13,133.5 121.06,133.43 117.93,133.43 117.93,134.16 115.44,134.16 115.42,132.46 138.15,132.46 140.79,129.82 168.07,129.82 169.7,131.44 171.5,131.44 188.67,148.62 188.67,202.49 188.65,202.84
AVDD1P0_MCS on BOTTOM: 171.3,227.34 171.3,225.83 170.38,225.83 170.38,224.99 170.85,224.52 175.51,224.52 175.51,227.34
AVDD1P0_MCS on L11_POWER: 129.13,130.84 129.13,129.57 128.83,129.26 81.64,129.26 81.64,151.36 76.48,156.51 76.48,189.13 76.38,189.13 82.32,195.07 82.32,223.52 145.54,223.52 150.11,228.09 174.09,228.09 174.09,224.38 168.63,224.38 158.67,214.43 97.41,214.43 87.98,204.77 87.99,187.74 85.62,185.37 85.9,185.37 85.9,165.89 85.83,163.12 89.97,159.15 89.97,137.26 100.18,137.26 103.71,133.73 106.58,133.73 110.08,130.23 113.18,130.23 113.16,130.84 116.33,130.84 116.33,130.2 128.19,130.2 128.24,130.25 128.24,130.84
AVDD1P0_PLL_SYN on BOTTOM: 170.56,223.93 170.56,221.97 169.77,221.97 169.65,221.84 169.65,220.04 170.13,219.56 175.69,219.56 175.67,223.93
AVDD1P0_PLL_SYN on L5_MIXED: 171.02,223.93 174.6,223.93 174.6,203.35 173.86,202.62 173.86,201.02 176.02,198.86 176.02,169.93 141.55,135.46 136.55,135.46 136.35,135.66 133.38,135.66 132.18,134.47 130.38,132.61 129.54,131.62 124.51,131.57 121.84,128.83 120.42,128.83 120.42,130.86 121.28,132.66 128.65,132.66 131.67,135.71 131.8,135.84 131.89,135.91 133.17,137.34 136.35,137.34 136.35,139.65 136.49,139.79 136.49,148.17 170.56,182.25 170.56,189.31 171.5,190.25 171.5,197.05 169.93,198.63 169.93,203.38 171.5,204.95 171.5,206.43 171.02,206.91
AVDD1P8 on BOTTOM: 168,202.92 168,202.26 171.53,202.26 171.53,206.35 167.69,206.35 166.9,205.56 166.9,203.17 167.16,202.92
AVDD1P8 on L18_POWER: 108.51,231.7 181.18,231.7 181.18,201.85 167.06,201.85 167.06,209.85 174.02,209.85 174.02,221.77 166.57,221.77 166.57,221.82 133.96,221.82 133.96,134.85 133.41,134.3 111.26,134.3 110.59,134.98 110.59,143.76 100.38,153.97 98.86,153.97 92.13,160.83 75.41,177.49 75.55,177.63 75.55,198.58 108.51,231.54 ; 4 cut-outs
AVDD1P8_ADC on BOTTOM: 167.73,218.2 167.73,216.13 166.45,216.13 166.32,216 166.32,214.3 166.51,214.11 171.26,214.11 171.26,218.2
AVDD1P8_ADC on L18_POWER: 117.53,133.78 117.53,130.76 150.75,130.76 150.75,143.79 163.04,156.08 163.04,201.37 163.12,201.37 163.12,210.67 171.78,210.67 171.78,219.86 135.94,219.86 135.97,133.78 ; 3 cut-outs
AVDD1P8_MCS on TOP: 228.14,173.33 228.14,169.95 234.49,169.95 234.49,173.33
AVDD1P8_MCS on L7_POWER: 136.27,131.7 114.91,131.7 114.91,130.23 134.37,130.23 134.37,125.04 137.2,122.21 146.95,122.21 150.52,118.64 173.05,118.64 175.29,120.88 187.55,120.88 200.25,133.58 239.14,133.58 239.14,174.55 207.39,174.55 203.23,170.38 203.23,156.97 171.6,125.35 153.37,125.35 150.22,128.5 139.47,128.5
AVDD1P8_PLL on TOP: 222.94,168.43 227.08,168.43 227.08,173.25 222.96,173.25 222.96,168.45
AVDD1P8_PLL on L18_POWER: 121.87,130.33 121.87,128.8 122.81,128.8 122.81,129.26 122.94,129.39 133.58,129.39 139.88,123.09 160.53,123.09 169.04,131.6 169.72,131.6 177.15,139.02 184.85,139.02 189.13,143.31 194.79,143.31 199.92,148.44 199.92,156.06 199.91,156.07 202.06,158.22 202.06,167.84 204.27,170.05 210.11,170.05 210.11,166.24 231.98,166.24 231.95,174.14 229.74,176.35 199.63,176.35 192.91,169.6 192.91,155.47 185.65,148.21 179.49,148.21 168.61,137.33 164.36,137.33 157.28,130.25 157.09,130.25 156.24,129.39 135.84,129.39 134.9,130.33 134.71,130.33
DGND on TOP (solid shape): 124.22,137.22 123.37,137.22 123.37,137.36 123.51,137.52 123.56,137.73 123.42,138.05 123.1,138.19 122.3,138.19 121.98,138.05 121.84,137.73 121.88,137.54 122,137.39 122,137.22 121.15,137.22 121.15,138.47 124.22,138.47
DGND on BOTTOM (solid shape): 140.97,220.95 131.47,220.95 131.47,222.68 140.97,222.68
DGND on BOTTOM (solid shape): 121.49,138.4 121.84,138.4 121.84,137.77 121.84,137.73 121.98,137.41 122.3,137.27 123.1,137.27 123.42,137.41 123.56,137.73 123.56,137.78 123.55,137.84 123.55,138.4 123.9,138.4 123.9,146.23 124.26,146.23 124.26,136.7 121.18,136.7 121.18,146.23 121.51,146.23
DGND on TOP: 100.62,143.73 101.83,143.73 101.85,143.7 102.9,143.7 102.9,147.26 102.81,147.35 100.62,147.35
DGND on TOP: 168.5,266.71 168.5,270.08 168.12,270.46 167.11,270.46 166.85,270.21 166.85,266.52 167.36,266.01 167.81,266.01
DGND on TOP: 137.97,248.89 137.97,252.07 137.46,252.58 133.78,252.58 133.53,252.32 133.53,248.39 134.92,246.99 136.07,246.99
DGND on TOP: outline of 84 points within 0.56,0.38 240.92,120.24 ; 67 cut-outs
DGND on TOP: 159.05,46 159.05,35.28 175.67,35.28 175.67,46
DGND on TOP: 114.5,288.82 164.85,288.87 240.56,288.47 240.59,275.54 240.79,197.38 240.87,176.99 240.89,138.25 240.81,110.13 197.72,110.13 197.74,99.64 194.14,96.2 193.81,95.92 191.95,94.06 188.29,90.42 175.03,90.42 170.43,95.02 168.86,96.52 167.26,98.42 145.21,120.47 132.89,120.47 132.64,120.73 132.64,123.14 131.75,123.14 131.75,123.9 126.82,123.9 126.82,124.69 126.8,124.71 126.19,124.71 126.16,124.74 126.16,128.4 126.72,128.4 126.72,129.44 123.49,129.44 123.49,128.78 121.21,128.78 121.21,129.46 117.86,129.46 117.86,128.42 118.67,128.42 118.67,124.71 117.7,124.71 117.68,124.69 117.68,123.9 112.98,123.9 112.98,123.14 112.12,123.14 112.12,120.73 102.54,120.73 74.6,92.84 58.62,92.84 47.88,103.23 0.56,103.28 0.56,103.78 0.81,288.72 17.12,288.72 27.53,288.77 28.42,288.77 31.29,288.8 ; 17 cut-outs
DGND on TOP: 141.91,248.83 141.91,252.2 141.53,252.58 140.51,252.58 140.26,252.32 140.26,248.64 140.77,248.13 141.21,248.13
DGND on TOP: 141.43,265.1 148.16,265.1 148.54,265.48 148.54,267.77 148.29,268.02 147.27,268.02 146,269.29 146,272.21 145.87,272.34 143.08,272.34 142.95,272.21 142.95,269.42 141.3,267.77 141.3,265.23
DGND on TOP: 109.8,196.44 111.01,196.44 111.04,196.42 111.34,196.42 111.34,200.04 111.32,200.06 109.8,200.06
DGND on TOP: 191.54,220.14 191.54,218.11 197.26,218.11 197.26,220.14
DGND on TOP: 228.98,140.72 231.75,140.72 232,140.97 232,142.04 231.75,142.29 228.98,142.29 228.73,142.04 228.73,140.97
DGND on TOP: 106.48,265.15 112.9,265.15 113.32,265.57 113.32,267.42 113.07,267.68 112.05,267.68 110.78,268.95 110.78,271.69 110.57,271.91 107.77,271.91 107.62,271.75 107.62,268.96 106.08,267.42 106.08,265.54
DGND on TOP: 191.29,223.95 191.29,222.53 191.92,221.89 193.17,221.89 193.57,222.3 195.35,222.3 196.11,223.06 196.11,225.6 195.99,225.73 193.07,225.73
DGND on TOP: 209.37,154.74 209.37,153.09 210.69,153.09 210.69,154.74
DGND on TOP: 221.51,144.42 225.37,144.42 225.83,144.88 225.83,145.95 221.51,145.95 221.26,145.69 221.26,144.68
DGND on TOP: 112.55,249.17 112.55,252.48 112.29,252.73 111.15,252.73 110.9,252.48 110.9,248.41 111.15,248.16 111.53,248.16
DGND on TOP: 146.1,249.02 146.1,252.32 145.85,252.58 144.7,252.58 144.45,252.32 144.45,248.26 144.7,248.01 145.08,248.01
DGND on TOP: 139.05,196.76 140.26,196.76 140.28,196.74 140.59,196.74 140.59,200.36 140.56,200.38 139.05,200.38
DGND on TOP: 217.41,104.42 217.41,97.99 217.88,97.52 219.23,97.52 219.48,97.78 219.48,98.79 220.75,100.06 223.49,100.06 223.71,100.28 223.71,103.07 223.56,103.23 220.76,103.23 219.23,104.76 217.75,104.76
DGND on TOP: 128.6,265.1 135.33,265.1 135.71,265.48 135.71,267.77 135.46,268.02 134.44,268.02 133.17,269.29 133.17,272.21 133.05,272.34 130.25,272.34 130.12,272.21 130.12,269.42 128.47,267.77 128.47,265.23
DGND on TOP: 209.55,164.77 209.55,163.17 211.07,163.17 211.07,164.77
DGND on TOP: 108.36,248.98 108.36,252.35 107.98,252.73 106.96,252.73 106.71,252.48 106.71,248.79 107.21,248.29 107.66,248.29
DGND on TOP: 128.61,265.14 135.34,265.14 135.72,265.52 135.72,267.8 135.47,268.06 134.45,268.06 133.18,269.33 133.18,272.25 133.06,272.38 130.26,272.38 130.14,272.25 130.14,269.46 128.49,267.8 128.49,265.26
DGND on TOP: 191.54,215.7 191.54,214.4 192.15,213.89 197.26,213.92 197.26,215.7
DGND on TOP: 142.35,143.5 143.56,143.5 143.59,143.47 144.63,143.47 144.63,147.03 144.54,147.12 142.35,147.12
DGND on BOTTOM: 67.07,188.77 67.26,187.68 66.17,187.87 65.71,187.41 74.72,178.45 75.25,178.99 75.07,180.06 76.14,179.89 76.16,179.89 76.89,180.62 76.87,180.61 76.7,181.68 77.76,181.49 78.3,182.03 69.29,191.01
DGND on BOTTOM: 110.74,245.01 110.74,240.56 111,240.31 111.84,240.31 112.09,240.56 112.09,245.01 111.84,245.26 111,245.26
DGND on BOTTOM: 164.85,288.87 240.56,288.47 240.59,275.54 240.79,197.38 240.87,176.99 240.89,138.25 240.81,110.13 197.72,110.13 197.74,99.64 194.14,96.2 193.81,95.92 191.95,94.06 188.29,90.42 175.03,90.42 170.43,95.02 168.86,96.52 167.26,98.42 145.21,120.47 132.89,120.47 132.64,120.73 132.64,123.14 131.75,123.14 131.75,123.9 126.82,123.9 126.82,124.69 126.8,124.71 126.19,124.71 126.16,124.74 126.16,128.4 126.72,128.4 126.72,129.44 123.49,129.44 123.49,128.78 121.21,128.78 121.21,129.46 117.86,129.46 117.86,128.42 118.67,128.42 118.67,124.71 117.7,124.71 117.68,124.69 117.68,123.9 112.98,123.9 112.98,123.14 112.12,123.14 112.12,120.73 102.54,120.73 74.6,92.84 58.62,92.84 47.88,103.23 0.56,103.28 0.56,103.78 0.81,288.72 17.12,288.72 27.53,288.77 28.42,288.77 31.29,288.8 114.5,288.82 ; 24 cut-outs
DGND on BOTTOM: 176.88,189.68 175.8,189.49 175.98,190.57 175.52,191.03 166.56,182.03 167.1,181.49 168.17,181.67 168,180.6 168.01,180.58 168.73,179.86 168.72,179.88 169.79,180.04 169.6,178.98 170.14,178.44 179.12,187.45
DGND on BOTTOM: 106.76,244.98 106.76,244.04 106.15,243.43 106.15,241.15 107.01,240.28 107.85,240.28 108.1,240.54 108.1,244.98 107.85,245.24 107.01,245.24
DGND on BOTTOM: 90.4,260.43 86.16,260.43 86.16,258.65 90.4,258.65
DGND on BOTTOM: 102.72,244.98 102.72,240.54 102.97,240.28 103.81,240.28 104.06,240.54 104.06,244.98 103.81,245.24 102.97,245.24
DGND on BOTTOM: 124.56,128.52 124.56,129.16 126.47,129.16 126.47,128.65 126.09,128.65 125.58,128.14 125.58,124.46 126.49,124.46 126.49,123.57 131.29,123.57 131.29,122.81 132.18,122.81 132.18,120.02 132.21,119.99 144.73,119.99 175.18,89.53 188.7,89.53 188.82,89.66 193.14,94.11 198.35,99.45 198.35,109.27 240.92,109.27 240.92,89.79 240.87,34.67 156.06,34.54 156.06,0.63 86.61,0.63 86.61,34.67 0.56,34.67 0.56,102.62 47.6,102.62 58.14,92.08 74.78,92.08 102.57,120.24 112.37,120.24 112.37,122.81 113.26,122.81 113.26,123.57 118.03,123.57 118.03,124.46 118.97,124.46 118.97,128.14 118.47,128.65 118.08,128.65 118.08,129.16 119.99,129.16 119.99,128.52 ; 6 cut-outs
DGND on L2_GROUND: 100.61,147.4 100.61,143.64 102.95,143.64 102.95,147.4
DGND on L2_GROUND: 114.5,288.82 164.85,288.87 240.56,288.47 240.59,275.54 240.79,197.38 240.87,176.99 240.89,138.25 240.81,110.13 197.72,110.13 197.74,99.64 194.14,96.2 193.81,95.92 191.95,94.06 188.29,90.42 175.03,90.42 170.43,95.02 168.86,96.52 167.26,98.42 145.21,120.47 132.89,120.47 132.64,120.73 132.64,123.14 131.75,123.14 131.75,123.9 126.82,123.9 126.82,124.69 126.8,124.71 126.19,124.71 126.16,124.74 126.16,128.4 126.72,128.4 126.72,129.44 123.49,129.44 123.49,128.78 121.21,128.78 121.21,129.46 117.86,129.46 117.86,128.42 118.67,128.42 118.67,124.71 117.7,124.71 117.68,124.69 117.68,123.9 112.98,123.9 112.98,123.14 112.12,123.14 112.12,120.73 102.54,120.73 74.6,92.84 58.62,92.84 47.88,103.23 0.56,103.28 0.56,103.78 0.81,288.72 17.12,288.72 27.53,288.77 28.42,288.77 31.29,288.8 ; 10 cut-outs
DGND on L2_GROUND: 240.87,34.67 156.06,34.54 156.06,0.25 86.61,0.25 86.61,34.67 0.56,34.67 0.56,102.62 47.6,102.62 58.14,92.08 74.78,92.08 102.57,120.24 112.37,120.24 112.37,122.81 113.26,122.81 113.26,123.57 118.03,123.57 118.03,124.46 118.97,124.46 118.97,128.14 118.47,128.65 118.08,128.65 118.08,129.16 119.99,129.16 119.99,128.52 124.56,128.52 124.56,129.16 126.47,129.16 126.47,128.65 126.09,128.65 125.58,128.14 125.58,124.46 126.49,124.46 126.49,123.57 131.29,123.57 131.29,122.81 132.18,122.81 132.18,120.24 144.48,120.24 175.18,89.53 188.7,89.53 188.82,89.66 193.14,94.11 198.35,99.45 198.35,109.27 240.92,109.27 240.92,89.79 ; 71 cut-outs
DGND on L3_SIGNAL: 74.32,156.77 71.66,156.77 70.56,154.76 69.4,152.77 68.79,151.67 68,150.28 67.47,149.27 66.65,147.59 66.07,146.32 65.39,144.62 64.98,143.52 64.44,141.89 63.93,140.12 63.78,139.5 62.92,134.71 62.68,133.54 62.54,132.72 62.37,131.27 62.21,128.93 62.18,127.12 62.21,126.11 62.35,124.38 62.51,123 63.39,118.08 63.59,116.83 63.86,115.44 64.23,113.96 64.69,112.38 65.19,110.82 65.73,109.42 66.47,107.78 67.05,106.6 69.07,103.11 69.51,102.35 70.33,100.81 71.43,98.89 80.82,98.89 74.6,92.92 58.6,92.92 47.4,104.32 47.4,154.86 56.42,163.88 70.51,163.88 74.32,160.07 ; 4 cut-outs
DGND on L3_SIGNAL: 170.2,98.3 172.86,98.3 173.96,100.3 175.12,102.29 175.74,103.39 176.53,104.79 177.06,105.79 177.88,107.47 178.45,108.74 179.14,110.45 179.54,111.54 180.08,113.18 180.6,114.94 180.75,115.56 181.61,120.36 181.84,121.52 181.98,122.35 182.16,123.8 182.32,126.14 182.34,127.95 182.32,128.96 182.18,130.69 182.01,132.07 181.14,136.99 180.94,138.23 180.66,139.62 180.29,141.11 179.84,142.68 179.33,144.25 178.79,145.64 178.05,147.28 177.47,148.46 175.46,151.96 175.02,152.72 174.2,154.25 173.1,156.17 163.7,156.17 169.92,162.14 185.93,162.14 197.13,150.75 197.13,100.2 188.11,91.19 174.01,91.19 170.2,95 ; 4 cut-outs
DGND on L3_SIGNAL: 164.85,288.87 240.56,288.47 240.59,275.54 240.79,197.38 240.87,176.99 240.89,138.25 240.81,110.13 197.72,110.13 197.74,99.64 194.14,96.2 193.81,95.92 191.95,94.06 188.29,90.42 175.03,90.42 170.43,95.02 168.86,96.52 167.26,98.42 145.21,120.47 132.89,120.47 132.64,120.73 132.64,123.14 131.75,123.14 131.75,123.9 126.82,123.9 126.82,124.69 126.8,124.71 126.19,124.71 126.16,124.74 126.16,128.4 126.72,128.4 126.72,129.44 123.49,129.44 123.49,128.78 121.21,128.78 121.21,129.46 117.86,129.46 117.86,128.42 118.67,128.42 118.67,124.71 117.7,124.71 117.68,124.69 117.68,123.9 112.98,123.9 112.98,123.14 112.12,123.14 112.12,120.73 102.54,120.73 74.6,92.84 58.62,92.84 47.88,103.23 0.56,103.28 0.56,103.78 0.81,288.72 17.12,288.72 27.53,288.77 28.42,288.77 31.29,288.8 114.5,288.82 ; 38 cut-outs
DGND on L4_GROUND: 240.87,34.67 156.06,34.54 156.06,0.63 86.61,0.63 86.61,34.67 0.56,34.67 0.56,102.62 47.6,102.62 58.14,92.08 74.78,92.08 102.57,120.24 112.37,120.24 112.37,122.81 113.26,122.81 113.26,123.57 118.03,123.57 118.03,124.46 118.97,124.46 118.97,128.14 118.47,128.65 118.08,128.65 118.08,129.16 119.99,129.16 119.99,128.52 124.56,128.52 124.56,129.16 126.47,129.16 126.47,128.65 126.09,128.65 125.58,128.14 125.58,124.46 126.49,124.46 126.49,123.57 131.29,123.57 131.29,122.81 132.18,122.81 132.18,120.02 132.21,119.99 144.73,119.99 175.18,89.53 188.7,89.53 188.82,89.66 193.14,94.11 198.35,99.45 198.35,109.27 240.92,109.27 240.92,89.79 ; 38 cut-outs
DGND on L4_GROUND: 114.5,288.82 164.85,288.87 240.56,288.47 240.59,275.54 240.79,197.38 240.87,176.99 240.89,138.25 240.81,110.13 197.72,110.13 197.74,99.64 194.14,96.2 193.81,95.92 191.95,94.06 188.29,90.42 175.03,90.42 170.43,95.02 168.86,96.52 167.26,98.42 145.21,120.47 132.89,120.47 132.64,120.73 132.64,123.14 131.75,123.14 131.75,123.9 126.82,123.9 126.82,124.69 126.8,124.71 126.19,124.71 126.16,124.74 126.16,128.4 126.72,128.4 126.72,129.44 123.49,129.44 123.49,128.78 121.21,128.78 121.21,129.46 117.86,129.46 117.86,128.42 118.67,128.42 118.67,124.71 117.7,124.71 117.68,124.69 117.68,123.9 112.98,123.9 112.98,123.14 112.12,123.14 112.12,120.73 102.54,120.73 74.6,92.84 58.62,92.84 47.88,103.23 0.56,103.28 0.56,103.78 0.81,288.72 17.12,288.72 27.53,288.77 28.42,288.77 31.29,288.8 ; 6 cut-outs
DGND on L5_MIXED: 164.85,288.87 240.56,288.47 240.59,275.54 240.79,197.38 240.87,176.99 240.89,138.25 240.81,110.13 197.72,110.13 197.74,99.64 194.14,96.2 193.81,95.92 191.95,94.06 188.29,90.42 175.03,90.42 170.43,95.02 168.86,96.52 167.26,98.42 145.21,120.47 132.89,120.47 132.64,120.73 132.64,123.14 131.75,123.14 131.75,123.9 126.82,123.9 126.82,124.69 126.8,124.71 126.19,124.71 126.16,124.74 126.16,128.4 126.72,128.4 126.72,129.44 123.49,129.44 123.49,128.78 121.21,128.78 121.21,129.46 117.86,129.46 117.86,128.42 118.67,128.42 118.67,124.71 117.7,124.71 117.68,124.69 117.68,123.9 112.98,123.9 112.98,123.14 112.12,123.14 112.12,120.73 102.54,120.73 74.6,92.84 58.62,92.84 47.88,103.23 0.56,103.28 0.56,103.78 0.81,288.72 17.12,288.72 27.53,288.77 28.42,288.77 31.29,288.8 114.5,288.82 ; 2 cut-outs
DGND on L5_MIXED: 124.56,128.52 124.56,129.16 126.47,129.16 126.47,128.65 126.09,128.65 125.58,128.14 125.58,124.46 126.49,124.46 126.49,123.57 131.29,123.57 131.29,122.81 132.18,122.81 132.18,120.02 132.21,119.99 144.73,119.99 175.18,89.53 188.7,89.53 188.82,89.66 193.14,94.11 198.35,99.45 198.35,109.27 240.92,109.27 240.92,89.79 240.87,34.67 156.06,34.54 156.06,0.63 86.61,0.63 86.61,34.67 0.56,34.67 0.56,102.62 47.6,102.62 58.14,92.08 74.78,92.08 102.57,120.24 112.37,120.24 112.37,122.81 113.26,122.81 113.26,123.57 118.03,123.57 118.03,124.46 118.97,124.46 118.97,128.14 118.47,128.65 118.08,128.65 118.08,129.16 119.99,129.16 119.99,128.52 ; 104 cut-outs
DGND on L5_MIXED: 121.16,138.61 121.16,136.91 124.28,136.91 124.28,138.61 ; 1 cut-out
DGND on L6_GROUND: 164.85,288.87 240.56,288.47 240.59,275.54 240.79,197.38 240.87,176.99 240.89,138.25 240.81,110.13 197.72,110.13 197.74,99.64 194.14,96.2 193.81,95.92 191.95,94.06 188.29,90.42 175.03,90.42 170.43,95.02 168.86,96.52 167.26,98.42 145.21,120.47 132.89,120.47 132.64,120.73 132.64,123.14 131.75,123.14 131.75,123.9 126.82,123.9 126.82,124.69 126.8,124.71 126.19,124.71 126.16,124.74 126.16,128.4 126.72,128.4 126.72,129.44 123.49,129.44 123.49,128.78 121.21,128.78 121.21,129.46 117.86,129.46 117.86,128.42 118.67,128.42 118.67,124.71 117.7,124.71 117.68,124.69 117.68,123.9 112.98,123.9 112.98,123.14 112.12,123.14 112.12,120.73 102.54,120.73 74.6,92.84 58.62,92.84 47.88,103.23 0.56,103.28 0.56,103.78 0.81,288.72 17.12,288.72 27.53,288.77 28.42,288.77 31.29,288.8 114.5,288.82 ; 6 cut-outs
DGND on L6_GROUND, L8_GROUND, L10_GROUND, L12_GROUND, L13_GROUND, L15_GROUND, L17_GROUND, L19_GROUND, L21_GROUND, L23_GROUND: 240.87,34.67 156.06,34.54 156.06,0.63 86.61,0.63 86.61,34.67 0.56,34.67 0.56,102.62 47.6,102.62 58.14,92.08 74.78,92.08 102.57,120.24 112.37,120.24 112.37,122.81 113.26,122.81 113.26,123.57 118.03,123.57 118.03,124.46 118.97,124.46 118.97,128.14 118.47,128.65 118.08,128.65 118.08,129.16 119.99,129.16 119.99,128.52 124.56,128.52 124.56,129.16 126.47,129.16 126.47,128.65 126.09,128.65 125.58,128.14 125.58,124.46 126.49,124.46 126.49,123.57 131.29,123.57 131.29,122.81 132.18,122.81 132.18,120.02 132.21,119.99 144.73,119.99 175.18,89.53 188.7,89.53 188.82,89.66 193.14,94.11 198.35,99.45 198.35,109.27 240.92,109.27 240.92,89.79 ; 16 cut-outs
DGND on L7_POWER: 121.16,138.61 121.16,136.91 124.28,136.91 124.28,138.61 ; 1 cut-out
DGND on L7_POWER: 164.85,288.87 240.56,288.47 240.59,275.54 240.79,197.38 240.87,176.99 240.89,138.25 240.81,110.13 197.72,110.13 197.74,99.64 194.14,96.2 193.81,95.92 191.95,94.06 188.29,90.42 175.03,90.42 170.43,95.02 168.86,96.52 167.26,98.42 145.21,120.47 132.89,120.47 132.64,120.73 132.64,123.14 131.75,123.14 131.75,123.9 126.82,123.9 126.82,124.69 126.8,124.71 126.19,124.71 126.16,124.74 126.16,128.4 126.72,128.4 126.72,129.44 123.49,129.44 123.49,128.78 121.21,128.78 121.21,129.46 117.86,129.46 117.86,128.42 118.67,128.42 118.67,124.71 117.7,124.71 117.68,124.69 117.68,123.9 112.98,123.9 112.98,123.14 112.12,123.14 112.12,120.73 102.54,120.73 74.6,92.84 58.62,92.84 47.88,103.23 0.56,103.28 0.56,103.78 0.81,288.72 17.12,288.72 27.53,288.77 28.42,288.77 31.29,288.8 114.5,288.82 ; 5 cut-outs
DGND on L7_POWER: 171.27,150.29 163.93,142.95 163.93,137.74 164.41,137.26 168.86,137.26 170.33,138.73 170.33,144.73 173.38,147.78 173.38,149.3 172.39,150.29
DGND on L7_POWER, L18_POWER, L20_POWER: 240.87,34.67 156.06,34.54 156.06,0.63 86.61,0.63 86.61,34.67 0.56,34.67 0.56,102.62 47.6,102.62 58.14,92.08 74.78,92.08 102.57,120.24 112.37,120.24 112.37,122.81 113.26,122.81 113.26,123.57 118.03,123.57 118.03,124.46 118.97,124.46 118.97,128.14 118.47,128.65 118.08,128.65 118.08,129.16 119.99,129.16 119.99,128.52 124.56,128.52 124.56,129.16 126.47,129.16 126.47,128.65 126.09,128.65 125.58,128.14 125.58,124.46 126.49,124.46 126.49,123.57 131.29,123.57 131.29,122.81 132.18,122.81 132.18,120.02 132.21,119.99 144.73,119.99 175.18,89.53 188.7,89.53 188.82,89.66 193.14,94.11 198.35,99.45 198.35,109.27 240.92,109.27 240.92,89.79
DGND on L8_GROUND, L17_GROUND: 164.85,288.87 240.56,288.47 240.59,275.54 240.79,197.38 240.87,176.99 240.89,138.25 240.81,110.13 197.72,110.13 197.74,99.64 194.14,96.2 193.81,95.92 191.95,94.06 188.29,90.42 175.03,90.42 170.43,95.02 168.86,96.52 167.26,98.42 145.21,120.47 132.89,120.47 132.64,120.73 132.64,123.14 131.75,123.14 131.75,123.9 126.82,123.9 126.82,124.69 126.8,124.71 126.19,124.71 126.16,124.74 126.16,128.4 126.72,128.4 126.72,129.44 123.49,129.44 123.49,128.78 121.21,128.78 121.21,129.46 117.86,129.46 117.86,128.42 118.67,128.42 118.67,124.71 117.7,124.71 117.68,124.69 117.68,123.9 112.98,123.9 112.98,123.14 112.12,123.14 112.12,120.73 102.54,120.73 74.6,92.84 58.62,92.84 47.88,103.23 0.56,103.28 0.56,103.78 0.81,288.72 17.12,288.72 27.53,288.77 28.42,288.77 31.29,288.8 114.5,288.82 ; 6 cut-outs
DGND on L9_POWER: 114.5,288.82 164.85,288.87 240.56,288.47 240.59,275.54 240.79,197.38 240.87,176.99 240.89,138.25 240.81,110.13 197.72,110.13 197.74,99.64 194.14,96.2 193.81,95.92 191.95,94.06 188.29,90.42 175.03,90.42 170.43,95.02 168.86,96.52 167.26,98.42 145.21,120.47 132.89,120.47 132.64,120.73 132.64,123.14 131.75,123.14 131.75,123.9 126.82,123.9 126.82,124.69 126.8,124.71 126.19,124.71 126.16,124.74 126.16,128.4 126.72,128.4 126.72,129.44 123.49,129.44 123.49,128.78 121.21,128.78 121.21,129.46 117.86,129.46 117.86,128.42 118.67,128.42 118.67,124.71 117.7,124.71 117.68,124.69 117.68,123.9 112.98,123.9 112.98,123.14 112.12,123.14 112.12,120.73 102.54,120.73 74.6,92.84 58.62,92.84 47.88,103.23 0.56,103.28 0.56,103.78 0.81,288.72 17.12,288.72 27.53,288.77 28.42,288.77 31.29,288.8 ; 5 cut-outs
DGND on L9_POWER: 240.87,34.67 156.06,34.54 156.06,0.63 86.61,0.63 86.61,34.67 0.56,34.67 0.56,102.62 47.6,102.62 58.14,92.08 74.78,92.08 102.57,120.24 112.37,120.24 112.37,122.81 113.26,122.81 113.26,123.57 118.03,123.57 118.03,124.46 118.97,124.46 118.97,128.14 118.47,128.65 118.08,128.65 118.08,129.16 119.99,129.16 119.99,128.52 124.56,128.52 124.56,129.16 126.47,129.16 126.47,128.65 126.09,128.65 125.58,128.14 125.58,124.46 126.49,124.46 126.49,123.57 131.29,123.57 131.29,122.81 132.18,122.81 132.18,120.02 132.21,119.99 144.73,119.99 175.18,89.53 188.7,89.53 188.82,89.66 193.14,94.11 198.35,99.45 198.35,109.27 240.92,109.27 240.92,89.79 ; 1 cut-out
DGND on L10_GROUND: 164.85,288.87 240.56,288.47 240.59,275.54 240.79,197.38 240.87,176.99 240.89,138.25 240.81,110.13 197.72,110.13 197.74,99.64 194.14,96.2 193.81,95.92 191.95,94.06 188.29,90.42 175.03,90.42 170.43,95.02 168.86,96.52 167.26,98.42 145.21,120.47 132.89,120.47 132.64,120.73 132.64,123.14 131.75,123.14 131.75,123.9 126.82,123.9 126.82,124.69 126.8,124.71 126.19,124.71 126.16,124.74 126.16,128.4 126.72,128.4 126.72,129.44 123.49,129.44 123.49,128.78 121.21,128.78 121.21,129.46 117.86,129.46 117.86,128.42 118.67,128.42 118.67,124.71 117.7,124.71 117.68,124.69 117.68,123.9 112.98,123.9 112.98,123.14 112.12,123.14 112.12,120.73 102.54,120.73 74.6,92.84 58.62,92.84 47.88,103.23 0.56,103.28 0.56,103.78 0.81,288.72 17.12,288.72 27.53,288.77 28.42,288.77 31.29,288.8 114.5,288.82 ; 6 cut-outs
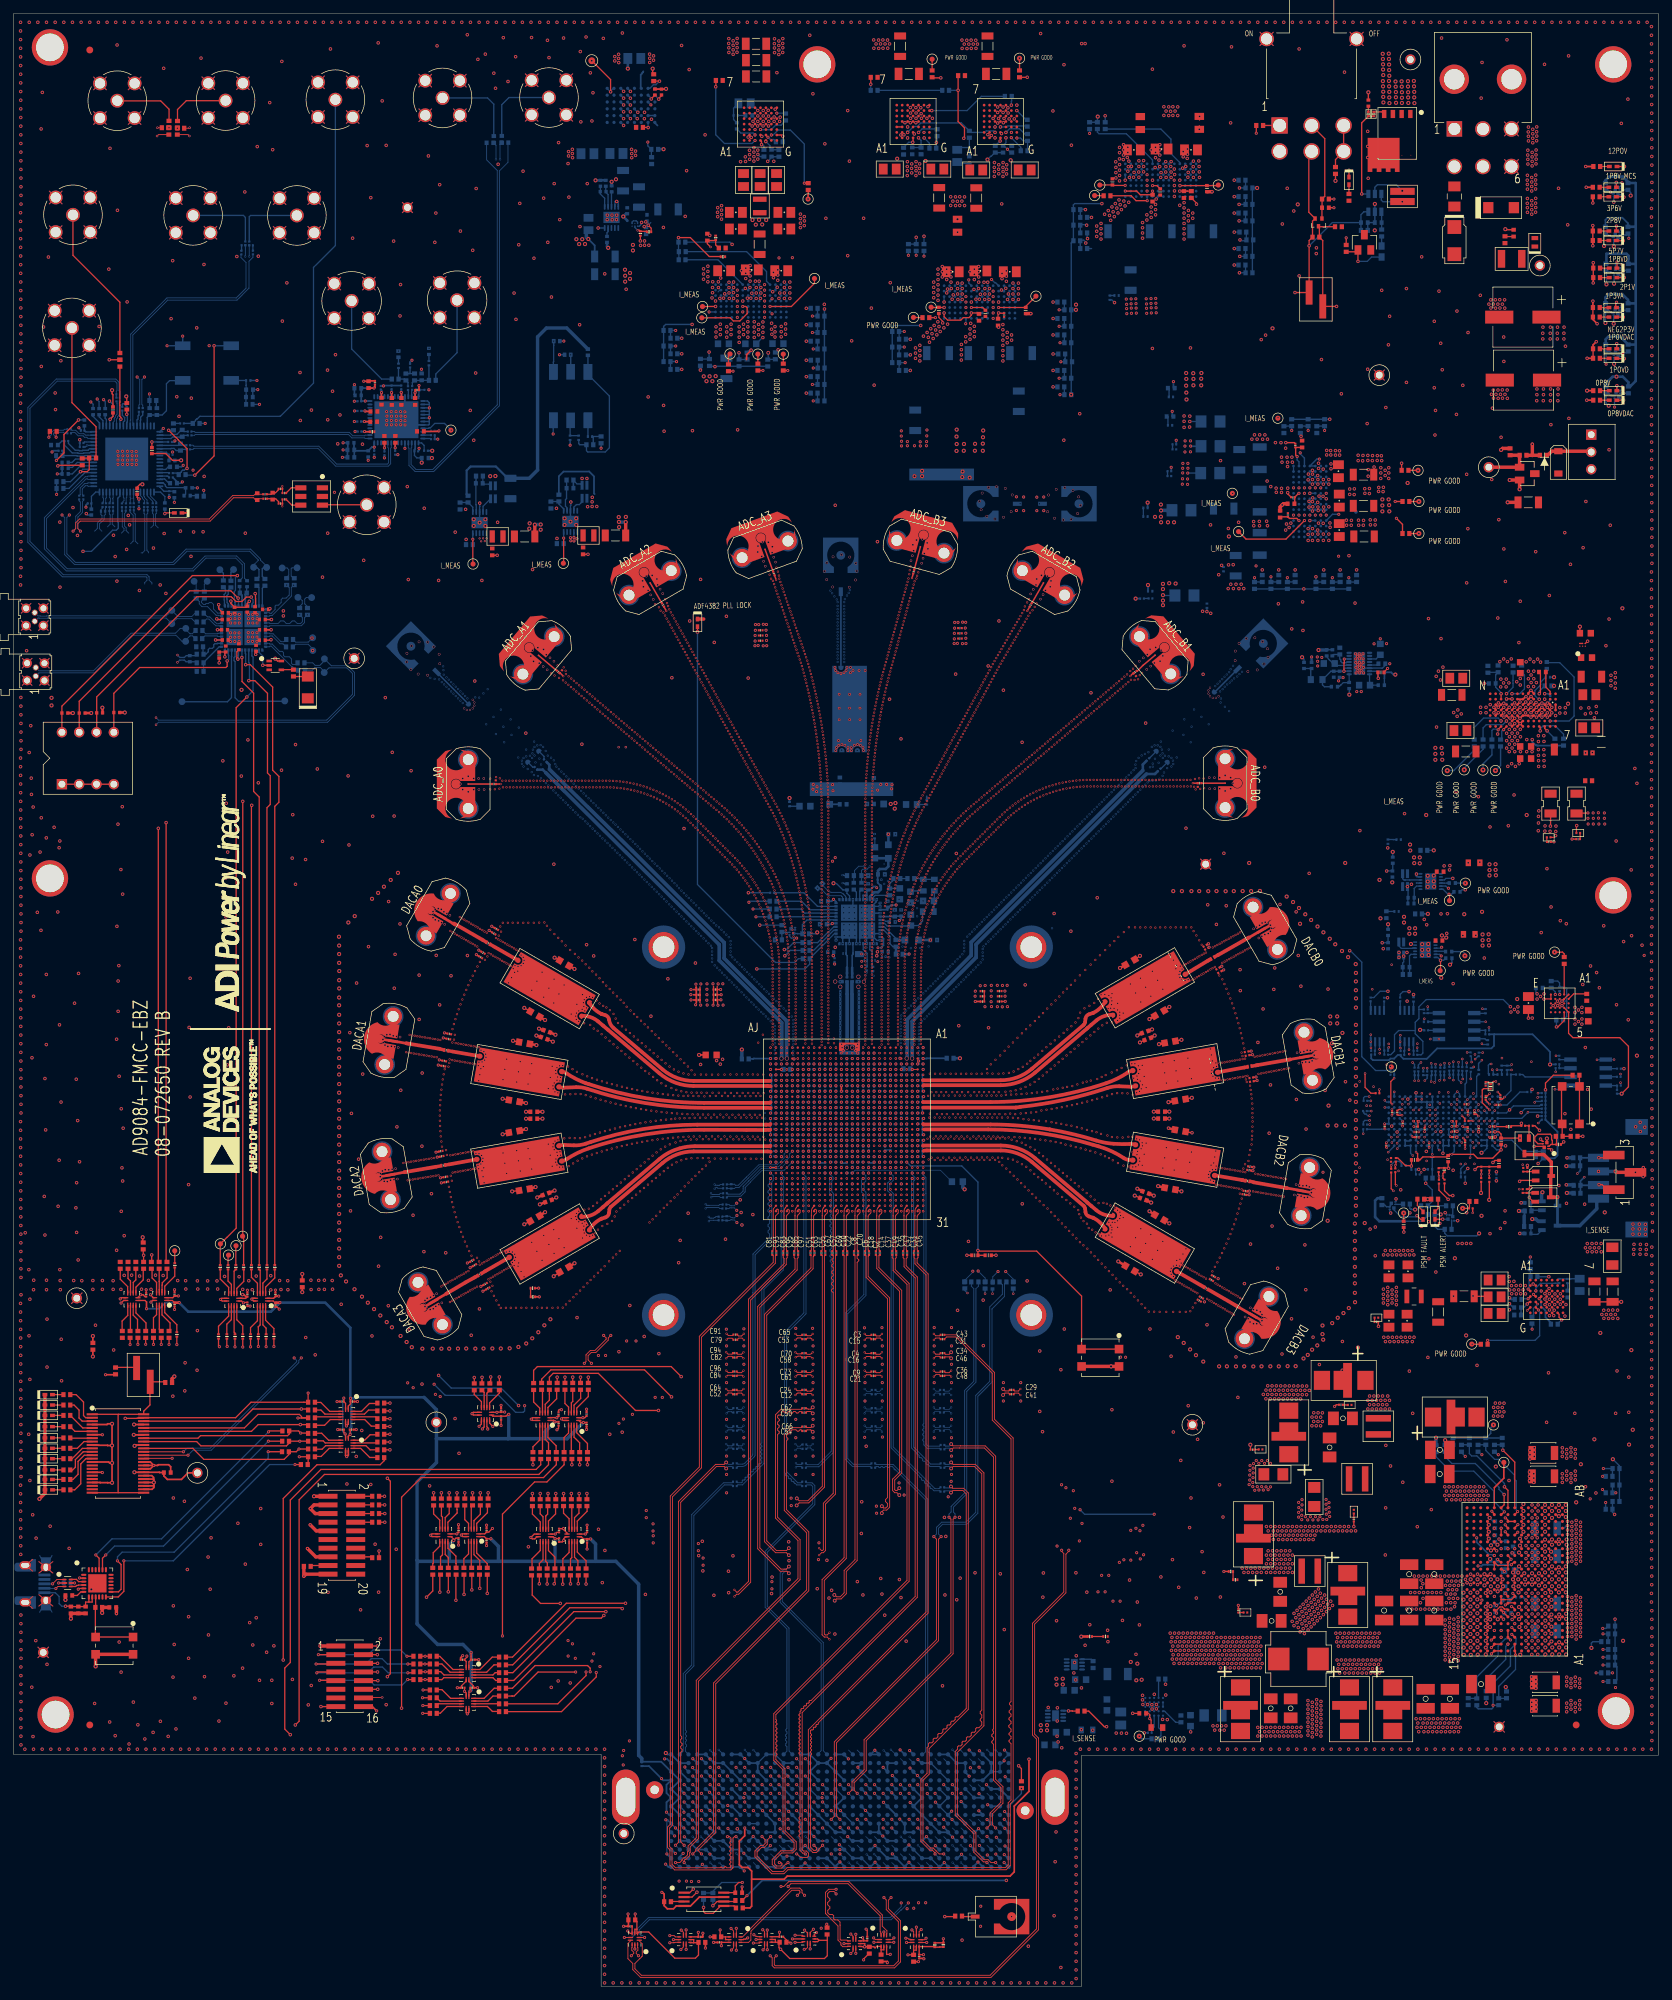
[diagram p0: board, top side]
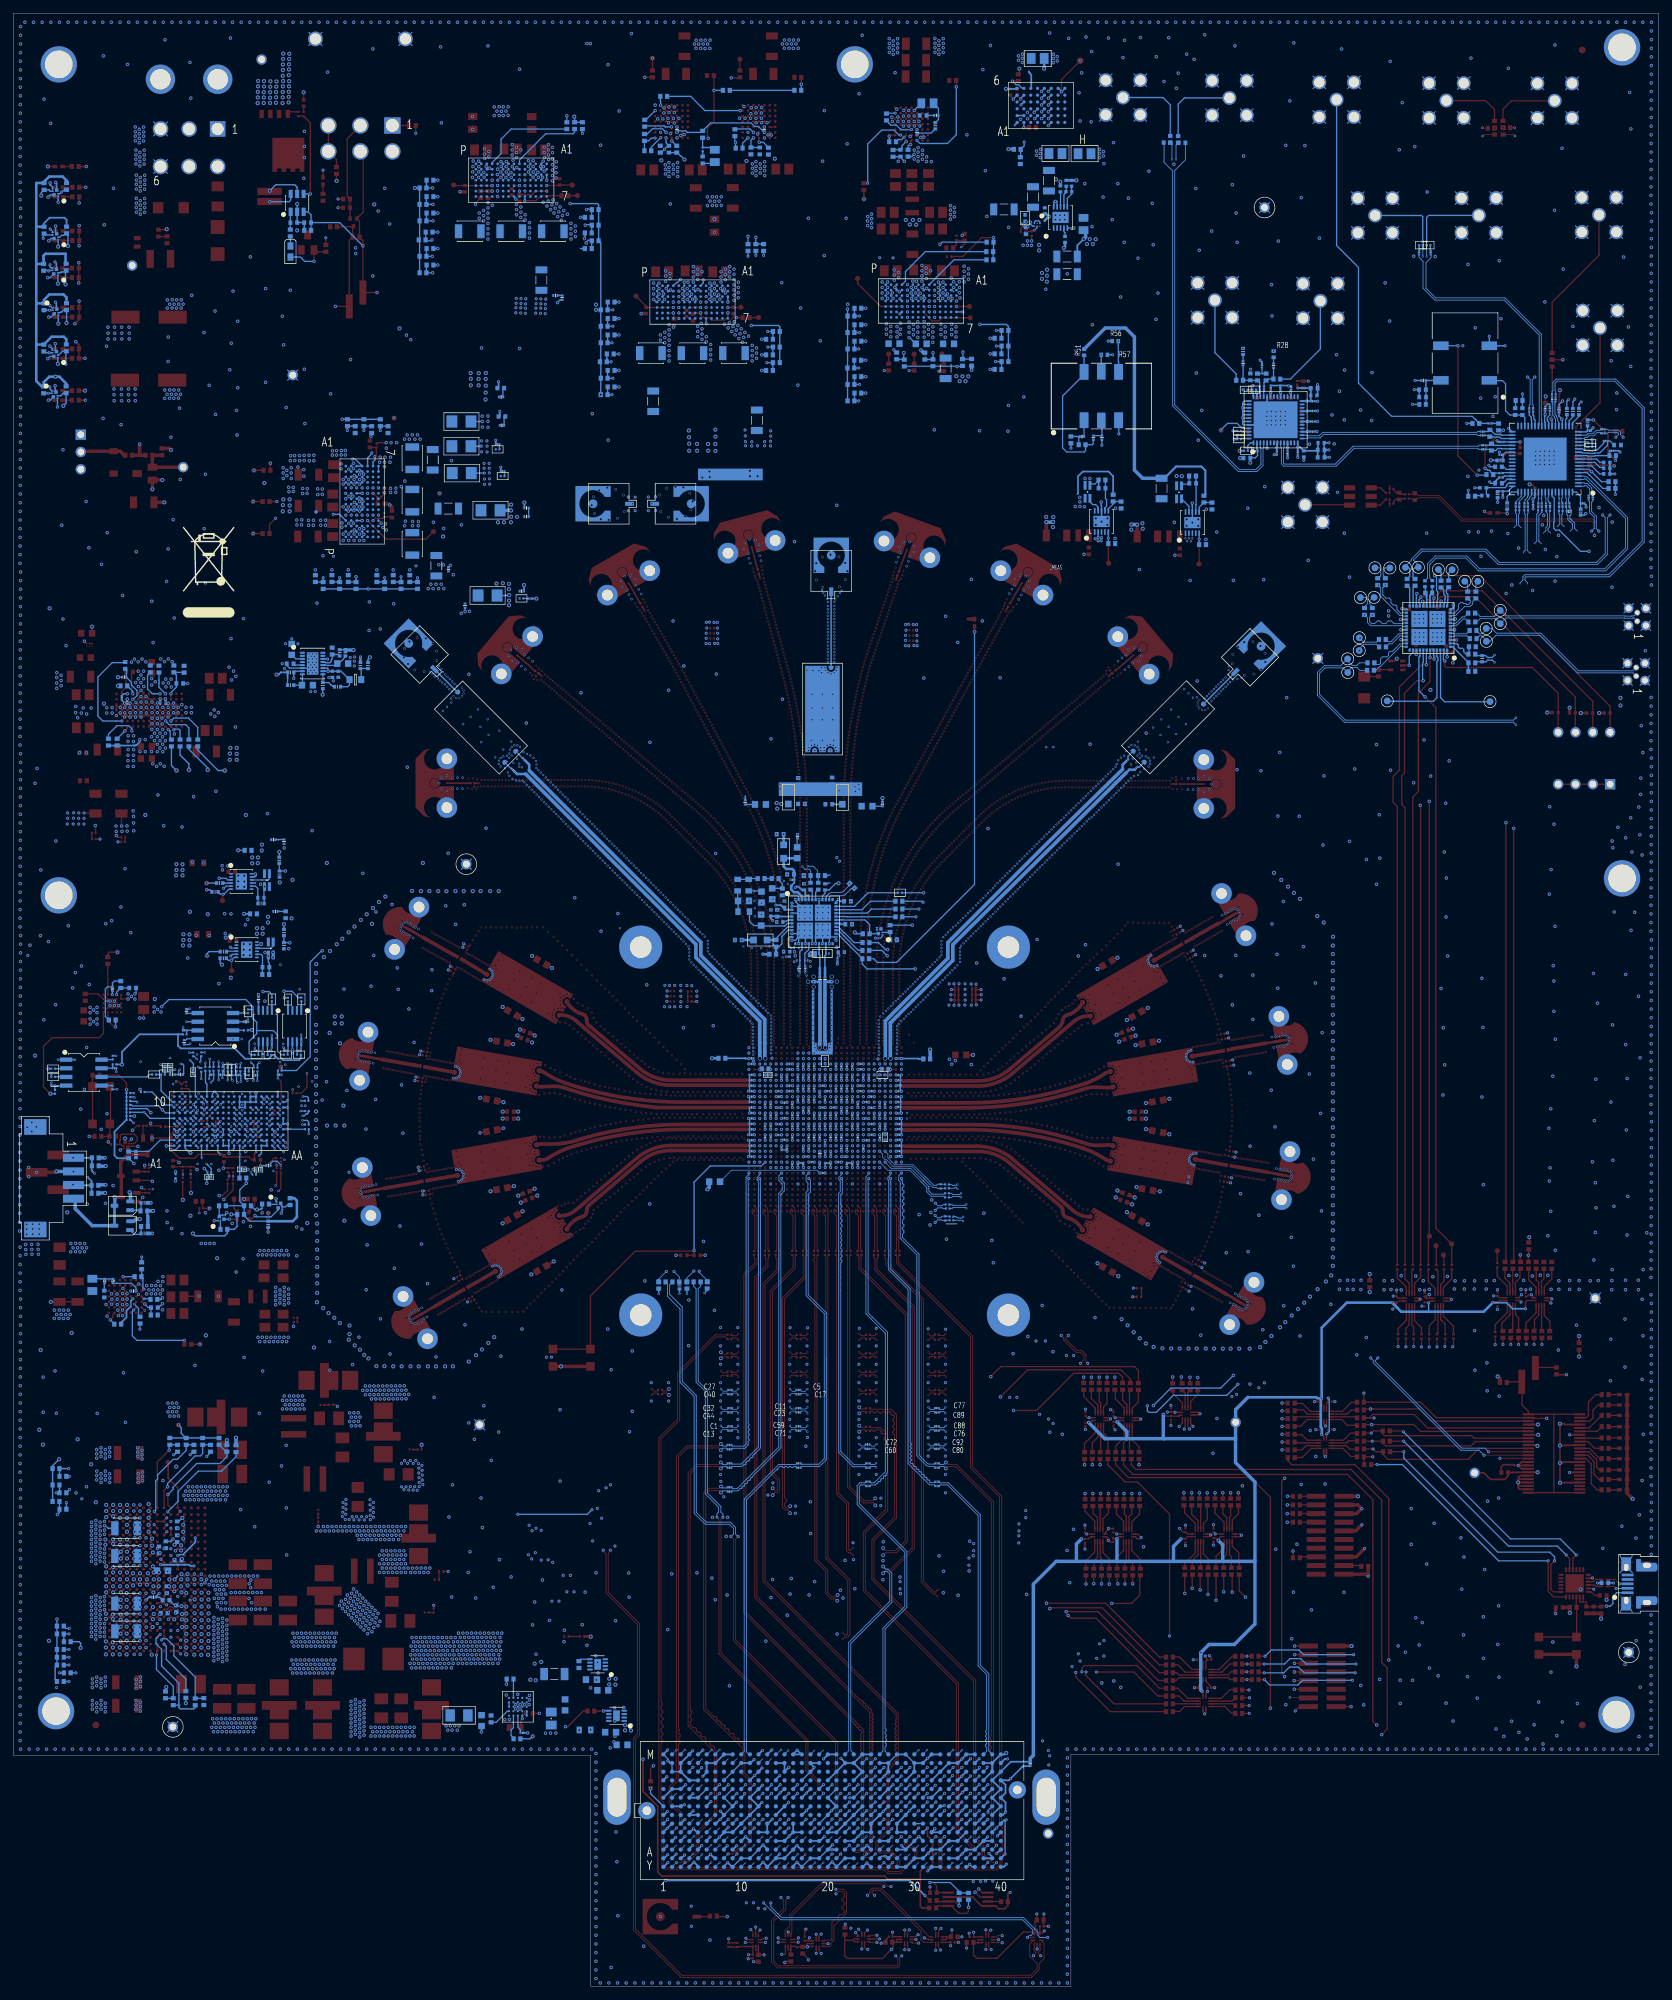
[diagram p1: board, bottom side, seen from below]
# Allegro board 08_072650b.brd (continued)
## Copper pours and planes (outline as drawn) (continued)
DGND on L11_POWER: 164.85,288.87 240.56,288.47 240.59,275.54 240.79,197.38 240.87,176.99 240.89,138.25 240.81,110.13 197.72,110.13 197.74,99.64 194.14,96.2 193.81,95.92 191.95,94.06 188.29,90.42 175.01,90.42 169.91,95.52 168.86,96.52 167.26,98.42 145.21,120.47 132.89,120.47 132.64,120.73 132.64,123.14 131.75,123.14 131.75,123.9 126.82,123.9 126.82,124.69 126.8,124.71 126.19,124.71 126.16,124.74 126.16,128.4 126.72,128.4 126.72,129.44 123.49,129.44 123.49,128.78 121.21,128.78 121.21,129.46 117.86,129.46 117.86,128.42 118.67,128.42 118.67,124.71 117.7,124.71 117.68,124.69 117.68,123.9 112.98,123.9 112.98,123.14 112.12,123.14 112.12,120.73 102.54,120.73 74.6,92.84 58.62,92.84 47.88,103.23 0.56,103.28 0.56,103.78 0.81,288.72 17.12,288.72 27.53,288.77 28.42,288.77 31.29,288.8 114.5,288.82 ; 1 cut-out
DGND on L11_POWER: 121.16,138.61 121.16,136.91 124.28,136.91 124.28,138.61 ; 1 cut-out
DGND on L11_POWER: 240.87,34.67 156.06,34.54 156.06,0.63 86.61,0.63 86.61,34.67 0.56,34.67 0.56,102.62 47.6,102.62 58.14,92.08 74.78,92.08 102.57,120.24 112.37,120.24 112.37,122.81 113.26,122.81 113.26,123.57 118.03,123.57 118.03,124.46 118.97,124.46 118.97,128.14 118.47,128.65 118.08,128.65 118.08,129.16 119.99,129.16 119.99,128.52 124.56,128.52 124.56,129.16 126.47,129.16 126.47,128.65 126.09,128.65 125.58,128.14 125.58,124.46 126.49,124.46 126.49,123.57 131.29,123.57 131.29,122.81 132.18,122.81 132.18,120.02 132.21,119.99 144.73,119.99 175.18,89.53 188.7,89.53 188.82,89.66 193.14,94.11 198.35,99.45 198.35,109.27 240.92,109.27 240.92,89.79 ; 3 cut-outs
DGND on L12_GROUND: 0.58,104.52 0.58,100.15 48.06,100.15 48.06,104.52
DGND on L12_GROUND: 164.85,288.87 240.56,288.47 240.59,275.54 240.79,197.38 240.87,176.99 240.89,138.25 240.81,110.13 197.72,110.13 197.74,99.64 194.14,96.2 193.81,95.92 191.95,94.06 188.29,90.42 175.03,90.42 170.43,95.02 168.86,96.52 167.26,98.42 145.21,120.47 132.89,120.47 132.64,120.73 132.64,123.14 131.75,123.14 131.75,123.9 126.82,123.9 126.82,124.69 126.8,124.71 126.19,124.71 126.16,124.74 126.16,128.4 126.72,128.4 126.72,129.44 123.49,129.44 123.49,128.78 121.21,128.78 121.21,129.46 117.86,129.46 117.86,128.42 118.67,128.42 118.67,124.71 117.7,124.71 117.68,124.69 117.68,123.9 112.98,123.9 112.98,123.14 112.12,123.14 112.12,120.73 102.54,120.73 74.6,92.84 58.62,92.84 47.88,103.23 0.56,103.28 0.56,103.78 0.81,288.72 17.12,288.72 27.53,288.77 28.42,288.77 31.29,288.8 114.5,288.82 ; 6 cut-outs
DGND on L12_GROUND: 197.54,110.92 197.54,108.33 240.89,108.33 240.89,110.92
DGND on L13_GROUND: 0.76,104.6 0.76,100 47.98,100 47.98,104.6
DGND on L13_GROUND: 197.66,111.4 197.66,108.69 240.79,108.69 240.79,111.4
DGND on L13_GROUND: 164.85,288.87 240.56,288.47 240.59,275.54 240.79,197.38 240.87,176.99 240.89,138.25 240.81,110.13 197.68,110.13 197.7,99.6 194.14,96.2 193.81,95.92 191.95,94.06 188.29,90.42 175.03,90.42 170.43,95.02 168.86,96.52 167.26,98.42 145.21,120.47 132.89,120.47 132.64,120.73 132.64,123.14 131.75,123.14 131.75,123.9 126.82,123.9 126.82,124.69 126.8,124.71 126.19,124.71 126.16,124.74 126.16,128.4 126.72,128.4 126.72,129.44 123.49,129.44 123.49,128.78 121.21,128.78 121.21,129.46 117.86,129.46 117.86,128.42 118.67,128.42 118.67,124.71 117.7,124.71 117.68,124.69 117.68,123.9 112.98,123.9 112.98,123.14 112.12,123.14 112.12,120.73 102.54,120.73 74.6,92.84 58.62,92.84 47.88,103.23 0.56,103.28 0.56,103.78 0.81,288.72 17.12,288.72 27.53,288.77 28.42,288.77 31.29,288.8 114.5,288.82 ; 6 cut-outs
DGND on L14_POWER: 164.85,288.87 240.56,288.47 240.59,275.54 240.79,197.38 240.87,176.99 240.89,138.25 240.81,110.13 197.72,110.13 197.74,99.64 194.14,96.2 193.81,95.92 191.95,94.06 188.29,90.42 175.03,90.42 170.43,95.02 168.86,96.52 167.26,98.42 145.21,120.47 132.89,120.47 132.64,120.73 132.64,123.14 131.75,123.14 131.75,123.9 126.82,123.9 126.82,124.69 126.8,124.71 126.19,124.71 126.16,124.74 126.16,128.4 126.72,128.4 126.72,129.44 123.49,129.44 123.49,128.78 121.21,128.78 121.21,129.46 117.86,129.46 117.86,128.42 118.67,128.42 118.67,124.71 117.7,124.71 117.68,124.69 117.68,123.9 112.98,123.9 112.98,123.14 112.12,123.14 112.12,120.73 102.54,120.73 74.6,92.84 58.62,92.84 47.88,103.23 0.56,103.28 0.56,103.78 0.81,288.72 17.12,288.72 27.53,288.77 28.42,288.77 31.29,288.8 114.5,288.82 ; 4 cut-outs
DGND on L14_POWER: 240.87,34.67 156.06,34.54 156.06,0.63 86.61,0.63 86.61,34.67 0.56,34.67 0.56,102.62 47.6,102.62 58.14,92.08 74.78,92.08 102.57,120.24 112.37,120.24 112.37,122.81 113.26,122.81 113.26,123.57 118.03,123.57 118.03,124.46 118.97,124.46 118.97,128.14 118.47,128.65 118.08,128.65 118.08,129.16 119.99,129.16 119.99,128.52 124.56,128.52 124.56,129.16 126.47,129.16 126.47,128.65 126.09,128.65 125.58,128.14 125.58,124.46 126.49,124.46 126.49,123.57 131.29,123.57 131.29,122.81 132.18,122.81 132.18,120.02 132.21,119.99 144.73,119.99 175.18,89.53 188.7,89.53 188.82,89.66 193.14,94.11 198.35,99.45 198.35,109.27 240.92,109.27 240.92,89.79 ; 3 cut-outs
DGND on L14_POWER, L18_POWER: 121.16,138.61 121.16,136.91 124.28,136.91 124.28,138.61 ; 1 cut-out
DGND on L15_GROUND: 164.85,288.87 240.56,288.47 240.59,275.54 240.79,197.38 240.87,176.99 240.89,138.25 240.81,110.13 197.72,110.13 197.74,99.64 194.14,96.2 193.81,95.92 191.95,94.06 188.29,90.42 175.03,90.42 170.43,95.02 168.86,96.52 167.26,98.42 145.21,120.47 132.89,120.47 132.64,120.73 132.64,123.14 131.75,123.14 131.75,123.9 126.82,123.9 126.82,124.69 126.8,124.71 126.19,124.71 126.16,124.74 126.16,128.4 126.72,128.4 126.72,129.44 123.49,129.44 123.49,128.78 121.21,128.78 121.21,129.46 117.86,129.46 117.86,128.42 118.67,128.42 118.67,124.71 117.7,124.71 117.68,124.69 117.68,123.9 112.98,123.9 112.98,123.14 112.12,123.14 112.12,120.73 102.54,120.73 74.6,92.84 58.62,92.84 47.88,103.23 0.56,103.28 0.56,103.78 0.81,288.72 17.12,288.72 27.53,288.77 28.42,288.77 31.29,288.8 114.5,288.82 ; 6 cut-outs
DGND on L16_POWER: 164.85,288.87 240.56,288.47 240.59,275.54 240.79,197.38 240.87,176.99 240.89,138.25 240.81,110.13 197.72,110.13 197.74,99.64 194.14,96.2 193.81,95.92 191.95,94.06 188.29,90.42 175.03,90.42 170.43,95.02 168.86,96.52 167.26,98.42 145.21,120.47 132.89,120.47 132.64,120.73 132.64,123.14 131.75,123.14 131.75,123.9 126.82,123.9 126.82,124.69 126.8,124.71 126.19,124.71 126.16,124.74 126.16,128.4 126.72,128.4 126.72,129.44 123.49,129.44 123.49,128.78 121.21,128.78 121.21,129.46 117.86,129.46 117.86,128.42 118.67,128.42 118.67,124.71 117.7,124.71 117.68,124.69 117.68,123.9 112.98,123.9 112.98,123.14 112.12,123.14 112.12,120.73 102.54,120.73 74.6,92.84 58.62,92.84 47.88,103.23 0.56,103.28 0.56,103.78 0.81,288.72 17.12,288.72 27.53,288.77 28.42,288.77 31.29,288.8 114.5,288.82 ; 7 cut-outs
DGND on L16_POWER: 174.98,120.19 175.72,120.93 182.55,120.93 183.85,119.63 183.85,117.17 181.69,115.01 177.65,115.01 174.75,117.91 174.75,119.99 174.96,120.19
DGND on L16_POWER: 240.87,34.67 156.06,34.54 156.06,0.63 86.61,0.63 86.61,34.67 0.56,34.67 0.56,102.62 47.6,102.62 58.14,92.08 74.78,92.08 102.57,120.24 112.37,120.24 112.37,122.81 113.26,122.81 113.26,123.57 118.03,123.57 118.03,124.46 118.97,124.46 118.97,128.14 118.47,128.65 118.08,128.65 118.08,129.16 119.99,129.16 119.99,128.52 124.56,128.52 124.56,129.16 126.47,129.16 126.47,128.65 126.09,128.65 125.58,128.14 125.58,124.46 126.49,124.46 126.49,123.57 131.29,123.57 131.29,122.81 132.18,122.81 132.18,120.02 132.21,119.99 144.73,119.99 175.18,89.53 188.7,89.53 188.82,89.66 193.14,94.11 198.35,99.45 198.35,109.27 240.92,109.27 240.92,89.79 ; 3 cut-outs
DGND on L18_POWER: 164.85,288.87 240.56,288.47 240.59,275.54 240.79,197.38 240.87,176.99 240.89,138.25 240.81,110.13 197.72,110.13 197.74,99.64 194.14,96.2 193.81,95.92 191.95,94.06 188.29,90.42 175.03,90.42 170.43,95.02 168.86,96.52 167.26,98.42 145.21,120.47 132.89,120.47 132.64,120.73 132.64,123.14 131.75,123.14 131.75,123.9 126.82,123.9 126.82,124.69 126.8,124.71 126.19,124.71 126.16,124.74 126.16,128.4 126.72,128.4 126.72,129.44 123.49,129.44 123.49,128.78 121.21,128.78 121.21,129.46 117.86,129.46 117.86,128.42 118.67,128.42 118.67,124.71 117.7,124.71 117.68,124.69 117.68,123.9 112.98,123.9 112.98,123.14 112.12,123.14 112.12,120.73 102.54,120.73 74.6,92.84 58.62,92.84 47.88,103.23 0.56,103.28 0.56,103.78 0.81,288.72 17.12,288.72 27.53,288.77 28.42,288.77 31.29,288.8 114.5,288.82 ; 3 cut-outs
DGND on L19_GROUND: 164.85,288.87 240.56,288.47 240.59,275.54 240.79,197.38 240.87,176.99 240.89,138.25 240.81,110.13 197.72,110.13 197.74,99.64 194.14,96.2 193.81,95.92 191.95,94.06 188.29,90.42 175.03,90.42 170.43,95.02 168.86,96.52 167.26,98.42 145.21,120.47 132.89,120.47 132.64,120.73 132.64,123.14 131.75,123.14 131.75,123.9 126.82,123.9 126.82,124.69 126.8,124.71 126.19,124.71 126.16,124.74 126.16,128.4 126.72,128.4 126.72,129.44 123.49,129.44 123.49,128.78 121.21,128.78 121.21,129.46 117.86,129.46 117.86,128.42 118.67,128.42 118.67,124.71 117.7,124.71 117.68,124.69 117.68,123.9 112.98,123.9 112.98,123.14 112.12,123.14 112.12,120.73 102.54,120.73 74.6,92.84 58.62,92.84 47.88,103.23 0.56,103.28 0.56,103.78 0.81,288.72 17.12,288.72 27.53,288.77 28.42,288.77 31.29,288.8 114.5,288.82 ; 6 cut-outs
DGND on L20_POWER: 114.5,288.82 164.85,288.87 240.56,288.47 240.59,275.54 240.79,197.38 240.87,176.99 240.89,138.25 240.81,110.13 197.72,110.13 197.74,99.64 194.14,96.2 193.81,95.92 191.95,94.06 188.29,90.42 175.03,90.42 170.43,95.02 168.86,96.52 167.26,98.42 145.21,120.47 132.89,120.47 132.64,120.73 132.64,123.14 131.75,123.14 131.75,123.9 126.82,123.9 126.82,124.69 126.8,124.71 126.19,124.71 126.16,124.74 126.16,128.4 126.72,128.4 126.72,129.44 123.49,129.44 123.49,128.78 121.21,128.78 121.21,129.46 117.86,129.46 117.86,128.42 118.67,128.42 118.67,124.71 117.7,124.71 117.68,124.69 117.68,123.9 112.98,123.9 112.98,123.14 112.12,123.14 112.12,120.73 102.54,120.73 74.6,92.84 58.62,92.84 47.88,103.23 0.56,103.28 0.56,103.78 0.81,288.72 17.12,288.72 27.53,288.77 28.42,288.77 31.29,288.8 ; 5 cut-outs
DGND on L20_POWER: 114.5,288.82 164.85,288.87 240.56,288.47 240.59,275.54 240.79,197.38 240.87,176.99 240.89,138.25 240.87,110.13 197.71,110.13 197.74,99.64 194.14,96.2 193.81,95.92 191.95,94.06 188.29,90.42 175.03,90.42 170.43,95.02 168.86,96.52 167.26,98.42 145.21,120.47 132.89,120.47 132.64,120.73 132.64,123.14 131.75,123.14 131.75,123.9 126.82,123.9 126.82,124.69 126.8,124.71 126.19,124.71 126.16,124.74 126.16,128.4 126.72,128.4 126.72,129.44 123.49,129.44 123.49,128.78 121.21,128.78 121.21,129.46 117.86,129.46 117.86,128.42 118.67,128.42 118.67,124.71 117.7,124.71 117.68,124.69 117.68,123.9 112.98,123.9 112.98,123.14 112.12,123.14 112.12,120.73 102.54,120.73 74.6,92.84 58.62,92.84 47.88,103.23 29.62,103.25 29.64,103.27 29.64,221.18 37.41,228.96 37.41,245.01 32.21,250.22 20.52,250.22 20.5,250.19 20.45,250.19 19.86,250.77 19.86,263.07 24.33,267.54 24.33,272.24 13.74,272.24 13.74,267.13 17.83,263.04 17.83,249.12 17.75,249.05 0.76,249.05 0.81,288.72 17.12,288.72 27.53,288.77 28.42,288.77 31.29,288.8 ; 5 cut-outs
DGND on L21_GROUND: 164.85,288.87 240.56,288.47 240.59,275.54 240.79,197.38 240.87,176.99 240.89,138.25 240.89,110.13 197.72,110.13 197.74,99.64 194.14,96.2 193.81,95.92 191.95,94.06 188.29,90.42 175.03,90.42 170.43,95.02 168.86,96.52 167.26,98.42 145.21,120.47 132.89,120.47 132.64,120.73 132.64,123.14 131.75,123.14 131.75,123.9 126.82,123.9 126.82,124.69 126.8,124.71 126.19,124.71 126.16,124.74 126.16,128.4 126.72,128.4 126.72,129.44 123.49,129.44 123.49,128.78 121.21,128.78 121.21,129.46 117.86,129.46 117.86,128.42 118.67,128.42 118.67,124.71 117.7,124.71 117.68,124.69 117.68,123.9 112.98,123.9 112.98,123.14 112.12,123.14 112.12,120.73 102.54,120.73 74.6,92.84 58.62,92.84 47.88,103.23 29.62,103.25 29.64,103.27 29.64,221.18 37.41,228.96 37.41,245.01 32.21,250.22 20.52,250.22 20.5,250.19 20.45,250.19 19.86,250.77 19.86,263.07 24.33,267.54 24.33,272.24 13.74,272.24 13.74,267.13 17.83,263.04 17.83,249.12 17.75,249.05 0.76,249.05 0.81,288.72 17.12,288.72 27.53,288.77 28.42,288.77 31.29,288.8 114.5,288.82 ; 6 cut-outs
DGND on L22_MIXED: outline of 82 points within 29.92,0.63 240.92,129.16 ; 42 cut-outs
DGND on L22_MIXED: 114.5,288.82 164.85,288.87 240.56,288.47 240.59,275.54 240.79,197.38 240.87,176.99 240.89,138.25 240.89,110.13 197.71,110.13 197.74,99.64 194.14,96.2 193.81,95.92 191.95,94.06 188.29,90.42 175.03,90.42 170.43,95.02 168.86,96.52 167.26,98.42 145.21,120.47 132.89,120.47 132.64,120.73 132.64,123.14 131.75,123.14 131.75,123.9 126.82,123.9 126.82,124.69 126.8,124.71 126.19,124.71 126.16,124.74 126.16,128.4 126.72,128.4 126.72,129.44 123.49,129.44 123.49,128.78 121.21,128.78 121.21,129.46 117.86,129.46 117.86,128.42 118.67,128.42 118.67,124.71 117.7,124.71 117.68,124.69 117.68,123.9 112.98,123.9 112.98,123.14 112.12,123.14 112.12,120.73 102.54,120.73 74.6,92.84 58.62,92.84 47.88,103.23 29.62,103.25 29.64,103.27 29.64,221.18 37.41,228.96 37.41,245.01 32.21,250.22 20.52,250.22 20.5,250.19 20.45,250.19 19.86,250.77 19.86,263.07 24.33,267.54 24.33,272.24 13.74,272.24 13.74,267.13 17.83,263.04 17.83,249.12 17.75,249.05 0.76,249.05 0.81,288.72 17.12,288.72 27.53,288.77 28.42,288.77 31.29,288.8 ; 6 cut-outs
DGND on L22_MIXED: 161.26,249.07 161.26,244.45 168.94,244.45 168.94,249.07
DGND on L23_GROUND: 164.85,288.87 240.56,288.47 240.59,275.54 240.79,197.38 240.87,176.99 240.89,138.25 240.81,110.13 197.72,110.13 197.74,99.64 194.14,96.2 193.81,95.92 191.95,94.06 188.29,90.42 175.03,90.42 170.43,95.02 168.86,96.52 167.26,98.42 145.21,120.47 132.89,120.47 132.64,120.73 132.64,123.14 131.75,123.14 131.75,123.9 126.82,123.9 126.82,124.69 126.8,124.71 126.19,124.71 126.16,124.74 126.16,128.4 126.72,128.4 126.72,129.44 123.49,129.44 123.49,128.78 121.21,128.78 121.21,129.46 117.86,129.46 117.86,128.42 118.67,128.42 118.67,124.71 117.7,124.71 117.68,124.69 117.68,123.9 112.98,123.9 112.98,123.14 112.12,123.14 112.12,120.73 102.54,120.73 74.6,92.84 58.62,92.84 47.88,103.23 0.56,103.28 0.56,103.78 0.81,288.72 17.12,288.72 27.53,288.77 28.42,288.77 31.29,288.8 114.5,288.82 ; 7 cut-outs
DGND on L24_SIGNAL: 114.5,288.82 164.85,288.87 240.56,288.47 240.59,275.54 240.79,197.38 240.87,176.99 240.89,138.25 240.81,110.13 197.72,110.13 197.74,99.64 194.14,96.2 193.81,95.92 191.95,94.06 188.29,90.42 175.03,90.42 170.43,95.02 168.86,96.52 167.26,98.42 145.21,120.47 132.89,120.47 132.64,120.73 132.64,123.14 131.75,123.14 131.75,123.9 126.82,123.9 126.82,124.69 126.8,124.71 126.19,124.71 126.16,124.74 126.16,128.4 126.72,128.4 126.72,129.44 123.49,129.44 123.49,128.78 121.21,128.78 121.21,129.46 117.86,129.46 117.86,128.42 118.67,128.42 118.67,124.71 117.7,124.71 117.68,124.69 117.68,123.9 112.98,123.9 112.98,123.14 112.12,123.14 112.12,120.73 102.54,120.73 74.6,92.84 58.62,92.84 47.88,103.23 0.56,103.28 0.56,103.78 0.81,288.72 17.12,288.72 27.53,288.77 28.42,288.77 31.29,288.8 ; 8 cut-outs
DGND on L25_GROUND: 240.87,34.67 156.06,34.54 156.06,0.63 86.61,0.63 86.61,34.67 0.56,34.67 0.56,102.62 47.6,102.62 58.14,92.08 74.78,92.08 102.57,120.24 112.37,120.24 112.37,122.81 113.26,122.81 113.26,123.57 118.03,123.57 118.03,124.46 118.97,124.46 118.97,128.14 118.47,128.65 118.08,128.65 118.08,129.16 119.99,129.16 119.99,128.52 124.56,128.52 124.56,129.16 126.47,129.16 126.47,128.65 126.09,128.65 125.58,128.14 125.58,124.46 126.49,124.46 126.49,123.57 131.29,123.57 131.29,122.81 132.18,122.81 132.18,120.02 132.21,119.99 144.73,119.99 175.18,89.53 188.7,89.53 188.82,89.66 193.14,94.11 198.35,99.45 198.35,109.27 240.92,109.27 240.92,89.79 ; 37 cut-outs
DGND on L25_GROUND: 164.85,288.87 240.56,288.47 240.59,275.54 240.79,197.38 240.87,176.99 240.89,138.25 240.81,110.13 197.72,110.13 197.74,99.64 194.14,96.2 193.81,95.92 191.95,94.06 188.29,90.42 175.03,90.42 170.43,95.02 168.86,96.52 167.26,98.42 145.21,120.47 132.89,120.47 132.64,120.73 132.64,123.14 131.75,123.14 131.75,123.9 126.82,123.9 126.82,124.69 126.8,124.71 126.19,124.71 126.16,124.74 126.16,128.4 126.72,128.4 126.72,129.44 123.49,129.44 123.49,128.78 121.21,128.78 121.21,129.46 117.86,129.46 117.86,128.42 118.67,128.42 118.67,124.71 117.7,124.71 117.68,124.69 117.68,123.9 112.98,123.9 112.98,123.14 112.12,123.14 112.12,120.73 102.54,120.73 74.6,92.84 58.62,92.84 47.88,103.23 0.56,103.28 0.56,103.78 0.81,288.72 17.12,288.72 27.53,288.77 28.42,288.77 31.29,288.8 114.5,288.82 ; 4 cut-outs
SVDD1P0_RX on TOP: 180.57,79.02 180.57,72.22 184.91,72.22 184.91,79.02
SVDD1P0_RX on L9_POWER: 114.6,121.26 127.51,121.16 127.51,118.92 141.81,118.92 172.59,88.14 185.67,88.14 185.8,88.01 185.8,70.66 175.74,60.6 175.69,60.6 175.31,60.22 101.27,60.22 101.27,118.95 114.59,118.96 ; 15 cut-outs
SVDD1P0_TX on TOP: 184.95,71.87 184.95,68.05 197.14,68.05 197.14,71.87
SVDD1P0_TX on L18_POWER: 114.68,121.31 129.16,121.14 129.16,119.61 141.12,119.61 172.59,88.14 196.8,88.14 196.8,69.62 196.89,69.53 195.43,68.07 173.28,68.07 173.28,35.1 154.36,35.1 151.38,38.07 92.66,38.07 92.63,38.05 83.72,38.05 83.72,83.9 110.79,110.97 110.79,119.66 114.68,119.66 ; 16 cut-outs
VDD_1P8_MCS_I+ on TOP: 228.5,182.52 228.5,180.59 231.06,180.59 231.06,182.52
VDD_1P8_MCS_I- on TOP: 234.37,176.28 231.42,176.28 231.42,181.41 234.37,181.41
VDD_1V8 on BOTTOM: 93.07,257.53 91.85,257.53 91.01,258.37 90.45,258.37 90.45,255.98 91.69,255.98 91.69,255.14 94.06,255.14 94.06,257.51 93.07,257.51
VDD_1V8 on L18_POWER: 91.31,257.28 91.31,252.53 60.08,221.3 60.08,221.28 59.42,220.62 59.42,216.45 48.03,205.05 48.03,191.11 36.45,191.11 34.26,193.29 34.26,195.68 34.09,195.86 28.93,195.86 28.02,194.94 28.02,183.67 25.17,180.82 5.33,180.82 4.45,179.93 4.45,173.86 4.62,173.69 54.64,173.69 54.64,199.87 71.02,216.26 78.82,216.26 96.47,233.91 96.47,257.28
VDD_3V3_ADF4030 on BOTTOM: 82.19,258.42 82.19,249.96 86.08,249.96 86.08,258.42
VDD_3V3_ADF4030 on L18_POWER: 27.56,238.96 27.56,196.44 34.82,196.44 34.82,195.2 35.81,194.21 44.68,194.21 46.18,195.71 46.18,241.33 75.49,241.33 85.98,251.82 85.98,258.42 85.93,258.47 47.07,258.47
VDDA1P0_ADC on TOP: 139.83,143.54 141.04,143.54 141.07,143.52 142.11,143.52 142.11,147.07 142.02,147.16 139.83,147.16
VDDA1P0_ADC on TOP: 98.1,143.77 99.31,143.77 99.33,143.74 100.37,143.74 100.37,147.3 100.29,147.39 98.1,147.39
VDDA1P0_ADC on BOTTOM: 146.51,231.95 150.75,231.95 150.75,224.66 147.07,224.66 147.07,224.56 137.44,224.56 137.44,228.9 146.51,228.9
VDDA1P0_ADC on L7_POWER: 94.03,231.8 154.64,231.8 157.63,228.8 157.63,194.51 157.42,194.65 157.18,194.69 156.51,194.03 157.18,193.37 157.42,193.42 157.63,193.55 157.63,165.23 146.58,165.23 141.43,160.07 141.43,142.04 137.26,137.87 137.26,137.87 132.56,137.87 128.09,134.25 116.37,134.25 115.86,134.63 112.64,137.86 112.6,137.82 105.89,137.82 86.28,157.43 86.28,164.11 86.33,164.16 86.33,224.1 ; 4 cut-outs
VDDA1P0_ADC_SCLK on TOP: 108.04,196.49 108.49,196.49 108.52,196.46 109.56,196.46 109.56,200.02 109.47,200.11 108.04,200.11
VDDA1P0_ADC_SCLK on TOP: 137.29,196.81 137.74,196.81 137.76,196.78 138.8,196.78 138.8,200.34 138.72,200.43 137.29,200.43
VDDA1P0_ADC_SCLK on BOTTOM: 171.58,264.39 174.32,264.39 174.32,262.94 177.06,260.2 177.06,239.4 175.59,237.92 175.59,231.93 170.15,231.93 169.9,232.18 169.9,233.78 171.25,233.78 171.25,243.69 173.84,243.69 173.84,259.92 172.52,261.24 172.52,263.09 171.58,263.09
VDDA1P0_ADC_SCLK on L5_MIXED: 124.51,237.69 175.82,237.69 175.82,231.65 167.72,231.65 167.67,231.6 167.67,227.15 167.69,227.13 167.69,191.62 132.08,156.01 132.08,139.22 127.48,134.62 127.13,134.62 126.75,134.24 126.75,133.35 123.7,133.35 123.7,133.99 123.32,134.37 121.28,134.37 120.9,133.99 120.9,133.35 117.86,133.35 117.86,134.37 117.6,134.62 113.16,134.62 113.16,135.74 113.51,135.74 113.51,136.52 113.16,136.52 113.16,157.86 99.78,171.23 99.78,213.27 101.73,215.21 102.03,215.21
VDDA1P0_ADCBK on TOP: 103.17,143.71 104.37,143.71 104.37,147.19 104.24,147.33 103.17,147.33
VDDA1P0_ADCBK on TOP: 144.9,143.48 146.11,143.48 146.11,146.96 145.97,147.1 144.9,147.1
VDDA1P0_ADCBK on BOTTOM: 129.29,229.1 129.29,224.75 135.18,224.75 135.18,229.1
VDDA1P0_ADCBK on L14_POWER: 76.4,202.84 76.4,230.81 75.26,231.95 169.77,231.95 169.77,168.45 169.98,168.25 169.98,167.28 137.06,134.37 132.69,134.37 132.44,134.11 132.44,131.06 132.31,130.94 131.67,130.94 131.67,130.18 126.72,130.18 126.72,129.26 123.44,129.24 117.98,129.24 117.96,130.18 113.51,130.18 113.51,130.94 112.62,130.94 112.62,133.99 112.5,134.11 109.45,134.11 76.43,167.13 76.43,202.82 ; 7 cut-outs
VDDA1P0_CK on BOTTOM: 175.87,237.08 175.87,220.73 178.26,220.73 178.26,224.64 181.05,224.64 181.05,237.08
VDDA1P0_DAC on BOTTOM: 162.08,249.73 162.08,243.48 162.15,243.41 163.58,243.41 163.58,244.32 169.01,244.32 169.01,249.73
VDDA1P0_DAC on L9_POWER: 158.47,251.51 169.82,251.51 171.04,250.29 171.04,241.81 167.87,238.63 167.87,219.43 166.17,217.73 166.17,203.91 197.74,172.34 197.74,170.76 197.78,170.73 197.78,100.04 188.16,90.42 176.48,90.42 146.13,120.78 132.54,120.78 132.54,123.19 131.65,123.19 131.65,123.95 128.35,123.95 128.32,123.93 126.9,123.93 126.87,123.95 126.87,124.66 126.85,124.69 126.09,124.69 126.01,124.76 126.01,128.52 126.8,128.52 126.8,129.97 126.87,130.05 132.41,130.05 132.41,134.11 133.68,134.11 135.08,135.51 135.08,141.38 147.47,141.38 153.75,147.65 153.75,154.99 150.55,158.19 92.25,158.19 89.43,155.37 89.48,148.62 91.77,146.13 97.74,140.16 109.55,140.16 109.55,134.11 112.22,134.11 112.22,130.05 117.86,130.02 117.86,128.63 118.77,128.65 118.77,128.45 118.75,124.84 118.67,124.76 117.86,124.76 117.86,123.88 113,123.88 113.03,123.14 111.96,123.14 111.96,121.16 98.5,121.16 70.31,92.96 58.34,92.96 46.81,104.5 46.81,154.2 61.87,169.27 68.28,169.27 104.14,205.13 111.76,205.13 126.42,219.79 139.32,219.79 143.74,224.21 143.74,232 156.92,231.98 156.97,233.17 157,235.32 157,250.04 ; 4 cut-outs
VDDA_1P8 on BOTTOM: 171.91,217.96 171.91,208 176.83,208 176.83,217.96
VDDA_1P8_DAC on TOP: 141.83,134.07 163.6,155.83 173.14,155.83 174.7,152.91 174.8,152.69 176.17,150.32 177.22,148.51 177.56,147.83 177.77,147.4 177.78,147.37 178.21,146.45 178.6,145.52 179.09,144.3 179.49,143.14 179.83,142.06 180.08,141.2 180.5,139.55 180.95,137.05 181.89,131.7 182.11,129.24 182.17,126.93 182.1,125.41 182.01,124.24 181.87,123.01 181.73,121.95 181.46,120.54 181.31,119.84 180.53,115.42 180.43,115.06 180.15,114.05 179.72,112.64 179.34,111.53 178.67,109.72 177.95,108.05 177.75,107.64 176.79,105.66 176.39,104.92 172.89,98.81 166.52,98.81 144.29,121.03 132.99,121.03 132.48,121.41 132.54,130.87 132.54,134.07
VDDA_1P8_DAC on TOP: 102.77,121.08 80.93,99.24 71.38,99.24 69.82,102.15 69.73,102.37 68.35,104.75 67.31,106.56 66.96,107.24 66.75,107.67 66.74,107.69 66.32,108.61 65.92,109.54 65.43,110.76 65.04,111.93 64.7,113.01 64.45,113.87 64.03,115.51 63.58,118.02 62.64,123.37 62.41,125.82 62.36,128.13 62.43,129.66 62.51,130.82 62.65,132.05 62.8,133.11 63.06,134.53 63.22,135.22 64,139.65 64.1,140 64.37,141.01 64.8,142.43 65.19,143.53 65.86,145.34 66.58,147.01 66.77,147.43 67.73,149.41 68.13,150.14 71.63,156.26 78.01,156.26 100.23,134.03 111.53,134.03 112.04,133.65 112.04,121.08
VDDA_1P8_DAC on BOTTOM: 172.09,207.77 172.09,202.67 181.18,202.67 181.18,207.77
VDDA_1P8_DAC on L2_GROUND: 112.07,134.04 112.07,121.12 102.8,121.12 74.63,92.9 58.57,92.92 47.45,104.23 47.42,154.77 56.39,163.87 70.46,163.89 100.29,134.04 ; 13 cut-outs
VDDA_1P8_DAC on L2_GROUND: 132.66,131.08 132.72,134.11 142.01,134.11 147.98,140.06 159.61,151.49 169.91,161.71 187.59,161.66 188.14,161.11 188.14,161.11 197.43,151.82 197.43,150.18 197.46,99.61 188.31,90.49 176.6,90.49 168.33,98.83 167.23,98.83 167.18,98.78 166.5,98.78 144.49,120.79 132.79,120.79 132.79,123.07 132.66,123.2 ; 12 cut-outs
VDDA_1P8_DAC on L3_SIGNAL: 102.77,121.08 80.93,99.24 71.38,99.24 69.82,102.15 69.73,102.37 68.35,104.75 67.31,106.56 66.96,107.24 66.75,107.67 66.74,107.69 66.32,108.61 65.92,109.54 65.43,110.76 65.04,111.93 64.7,113.01 64.45,113.87 64.03,115.51 63.58,118.02 62.64,123.37 62.41,125.82 62.36,128.13 62.43,129.66 62.51,130.82 62.65,132.05 62.8,133.11 63.06,134.53 63.22,135.22 64,139.65 64.1,140 64.37,141.01 64.8,142.43 65.19,143.53 65.86,145.34 66.58,147.01 66.77,147.43 67.73,149.41 68.13,150.14 71.63,156.26 78.01,156.26 100.23,134.03 111.53,134.03 112.04,133.65 112.04,130.81 113.08,130.81 113.08,130.1 113.11,130.07 117.02,130.07 117.25,129.84 117.25,123.93 117.2,123.88 113,123.88 113,123.16 113.03,123.14 112.04,123.14 112.04,121.08 ; 4 cut-outs
VDDA_1P8_DAC on L3_SIGNAL: 141.75,133.99 163.6,155.83 173.14,155.83 174.7,152.91 174.8,152.69 176.17,150.32 177.22,148.51 177.56,147.83 177.77,147.4 177.78,147.37 178.21,146.45 178.6,145.52 179.09,144.3 179.49,143.14 179.83,142.06 180.08,141.2 180.5,139.55 180.95,137.05 181.89,131.7 182.11,129.24 182.17,126.93 182.1,125.41 182.01,124.24 181.87,123.01 181.73,121.95 181.46,120.54 181.31,119.84 180.53,115.42 180.43,115.06 180.15,114.05 179.72,112.64 179.34,111.53 178.67,109.72 177.95,108.05 177.75,107.64 176.79,105.66 176.39,104.92 172.89,98.81 166.52,98.81 144.29,121.03 132.99,121.03 132.48,121.41 132.48,123.19 131.7,123.19 131.67,123.22 131.67,123.83 131.47,124.03 127.38,124.03 127.38,129.95 127.48,130.05 131.75,130.05 131.78,130.07 131.78,130.84 132.48,130.84 132.48,133.99 ; 4 cut-outs
VDDA_1P8_DAC on L4_GROUND: 141.75,133.99 163.6,155.83 173.14,155.83 174.7,152.91 174.8,152.69 176.17,150.32 177.22,148.51 177.56,147.83 177.77,147.4 177.78,147.37 178.21,146.45 178.6,145.52 179.09,144.3 179.49,143.14 179.83,142.06 180.08,141.2 180.5,139.55 180.95,137.05 181.89,131.7 182.11,129.24 182.17,126.93 182.1,125.41 182.01,124.24 181.87,123.01 181.73,121.95 181.46,120.54 181.31,119.84 180.53,115.42 180.43,115.06 180.15,114.05 179.72,112.64 179.34,111.53 178.67,109.72 177.95,108.05 177.75,107.64 176.79,105.66 176.39,104.92 172.89,98.81 166.52,98.81 144.29,121.03 132.99,121.03 132.48,121.41 132.48,123.19 131.7,123.19 131.67,123.22 131.67,123.83 131.47,124.03 127.38,124.03 127.38,129.95 127.48,130.05 131.75,130.05 131.78,130.07 131.78,130.84 132.48,130.84 132.48,133.99
VDDA_1P8_DAC on L4_GROUND: 102.77,121.08 80.93,99.24 71.38,99.24 69.82,102.15 69.73,102.37 68.35,104.75 67.31,106.56 66.96,107.24 66.75,107.67 66.74,107.69 66.32,108.61 65.92,109.54 65.43,110.76 65.04,111.93 64.7,113.01 64.45,113.87 64.03,115.51 63.58,118.02 62.64,123.37 62.41,125.82 62.36,128.13 62.43,129.66 62.51,130.82 62.65,132.05 62.8,133.11 63.06,134.53 63.22,135.22 64,139.65 64.1,140 64.37,141.01 64.8,142.43 65.19,143.53 65.86,145.34 66.58,147.01 66.77,147.43 67.73,149.41 68.13,150.14 71.63,156.26 78.01,156.26 100.23,134.03 111.53,134.03 112.04,133.65 112.04,130.81 113.08,130.81 113.08,130.1 113.11,130.07 117.02,130.07 117.25,129.84 117.25,123.93 117.2,123.88 113,123.88 113,123.16 113.03,123.14 112.04,123.14 112.04,121.08
VDDA_1P8_DAC on L20_POWER: 189.56,210.72 189.56,156.59 196.67,149.48 196.67,111.96 192.35,107.65 192.35,95.81 188.01,91.47 175.44,91.47 146.43,120.47 132.54,120.47 132.54,123.19 131.65,123.19 131.65,123.95 128.35,123.95 128.35,130.05 132.41,130.05 132.41,134.11 136.8,134.11 153.26,150.57 153.26,157.28 91.16,157.28 91.16,150.98 108.15,134.11 112.22,134.11 112.22,130.05 116.15,130.05 116.15,123.95 112.98,123.95 112.98,123.19 111.96,123.19 111.96,120.7 98.04,120.7 71.42,94.08 58.62,94.08 48.44,104.27 48.44,154.64 63.98,170.18 68,170.18 98.86,201.04 155.07,201.04 164.74,210.72 ; 4 cut-outs
VDDD_0P8 on TOP: 175.02,55.12 184.25,55.12 184.76,54.61 184.76,52.48 187.48,49.76 187.48,45.34 188.75,44.07 188.75,41.15 183.31,41.15 182.07,42.39 173.52,42.39 169.23,46.71 169.23,55.1
VDDD_0P8 on L11_POWER: 102.44,120.27 112.34,120.27 112.34,122.81 113.26,122.81 113.26,123.55 113.28,123.57 118.85,123.57 118.95,123.67 118.95,127.61 119.86,128.52 124.84,128.52 125.58,127.79 125.58,123.72 125.73,123.57 131.29,123.57 131.29,122.81 132.18,122.81 132.18,120.42 132.21,120.4 144.4,120.4 178.89,85.9 178.89,61.24 180.47,59.66 187.86,59.66 187.88,59.64 187.88,49.45 184.61,46.18 173.51,46.18 173.35,46.02 173.35,36.22 173.33,36.2 105.54,36.2 102.49,39.24 102.44,39.24
VDDD_0P8 on L14_POWER: 120.52,128.52 124.21,128.52 124.21,127.64 125.73,127.64 125.73,123.57 131.44,123.57 131.44,122.81 132.21,122.81 132.21,120.4 144.37,120.4 178.89,85.88 178.89,61.24 180.49,59.64 187.76,59.64 187.88,59.77 187.88,49.45 184.61,46.18 173.51,46.18 173.35,46.02 173.35,36.22 173.33,36.2 105.54,36.2 102.74,38.99 102.74,39.24 102.59,39.24 102.59,120.27 112.4,120.27 112.4,122.68 112.52,122.81 113.28,122.81 113.28,123.57 119,123.57 119,127.64 120.52,127.64 ; 17 cut-outs
VDDD_0P8 on L16_POWER: 120.52,128.52 124.21,128.52 124.21,127.64 125.73,127.64 125.73,123.57 131.44,123.57 131.44,122.81 132.21,122.81 132.21,119.99 144.78,119.99 178.92,85.85 178.92,61.21 180.52,59.61 187.88,59.61 187.88,45.64 149.02,45.64 147.98,44.6 147.98,38.28 103.45,38.28 102.74,38.99 102.74,39.24 102.72,39.24 102.72,120.27 112.4,120.27 112.4,122.68 112.52,122.81 113.28,122.81 113.28,123.57 118.87,123.57 118.87,127.64 120.52,127.64 ; 16 cut-outs
VDDD_1P0 on TOP: 197.36,82.19 202.78,82.19 202.78,90.87 201.64,92.01 197.08,92.01 197.08,86.94 197.1,86.94 197.1,85.59 194.98,85.59 194.81,85.41 194.81,82.16 197.32,82.16
VDDD_1P0 on L20_POWER: 90.04,66.98 90.28,67.21 90.28,106.8 103.18,119.89 112.4,119.89 112.4,122.81 113.28,122.81 113.28,123.57 131.32,123.57 131.32,122.81 132.21,122.81 132.24,119.64 142.56,119.59 172.49,89.66 172.67,89.66 172.67,89.61 174.45,87.83 207.09,87.83 207.54,87.38 207.54,67.28 207.43,67.17 198.08,67.17 198.27,66.98 153.31,66.98 153.31,67.03 151.66,65.38 90.2,65.38 90.04,65.53 ; 35 cut-outs
VDDD_1P0_ADC on TOP: 189.12,57.95 189.99,58.83 189.99,63.4 188.85,64.54 180.34,64.54 179.71,63.91 179.71,60.6 179.45,60.35 179.45,58.01 179.5,57.96 189.1,57.96
VDDD_1P0_ADC on L5_MIXED: 124.51,129.24 126.52,129.24 126.52,128.68 126.11,128.65 125.6,128.14 125.6,124.46 126.62,124.46 126.62,123.57 130.94,119.25 144.53,119.25 184.4,79.38 186.59,79.38 186.49,79.27 186.49,66.8 186.56,66.73 189.28,66.73 189.51,66.5 189.51,50.88 133.43,50.88 129.3,55 129.3,109.82 128.85,110.26 128.73,110.26 119.15,119.84 119.15,124.31 119,124.46 119,128.14 118.49,128.65 118.11,128.65 118.11,129.21 120.27,129.21 120.27,128.6 124.49,128.55 ; 8 cut-outs
VDDD_1P0_SERDES on TOP: 197.23,72.21 197.23,79.15 196.98,79.4 185.93,79.4 185.17,78.64 185.17,72.24 197.21,72.24
VDDD_1P8 on BOTTOM: 152.2,34.75 152.2,40.18 148.95,40.18 148.95,34.75
VDDD_1P8 on L7_POWER: 119.38,124.46 123.95,124.46 123.95,123.57 131.32,123.57 131.32,119.96 141.66,119.96 167.39,94.36 168.86,93.12 168.86,36.35 156.11,36.31 156.11,36.32 150.11,36.32 150.11,39.67 156.11,39.67 156.11,84.38 145.64,94.84 113.18,94.84 113.28,106.81 113.28,123.57 119.38,123.57
VDDD_1P8_GP on BOTTOM: 155.02,42.72 155.02,47.57 152.2,47.57 152.2,42.72
VDDD_1P8_GP on L7_POWER: 17.42,102.16 38.79,102.16 53.44,87.5 85.09,87.5 85.09,47.57 154.94,47.57 154.94,42.65 8.71,42.65 8.71,60.88 36.63,60.88 36.63,87.5 33.17,87.53 33.23,99.31 17.42,99.31
VDDD_1P8_I+ on BOTTOM: 156.44,47.14 161.09,47.14 161.09,41.45 159.49,41.45 159.49,36.98 157.96,36.98 157.96,43.41 156.44,44.93
VDDD_1P8_I- on BOTTOM: 157.1,36.78 157.1,39.6 153.64,39.6 153.64,36.78
VDDD_1P8_MCS on TOP: 224.31,173.91 224.31,177.52 231.11,177.52 231.11,173.91
1P0VD on TOP: 215.01,71.02 209.75,71.02 209.75,88.15 211.7,90.09 211.7,98.08 208.04,98.08 206.88,96.92 206.88,96.91 206.82,96.85 206.82,94.95 202.88,91.01 202.88,82.18 202.73,82.03 202.69,82.07 198.12,82.07 197.36,81.31 197.36,66.7 198.37,65.68 215.27,65.68 215.65,66.07 215.65,70.38
1P0VDAC on TOP: 199.49,104.9 199.49,97.82 205.84,97.82 205.84,104.9
1P0VDAC on L16_POWER: 118.49,125.27 115.42,125.27 115.42,131.01 211.56,131.01 211.63,130.94 211.63,97.74 211.58,97.79 198.25,97.79 198.3,97.84 198.3,110.13 178.16,110.13 174.68,106.65 167.11,106.65 151.92,121.84 138.3,121.84 136.68,123.47 136.68,124.43 135.66,125.45 126.16,125.45 126.16,128.47 128.19,128.47 128.27,128.55 128.27,129.34 117.98,129.34 117.86,129.21 117.86,128.6 118.03,128.42 118.49,128.42 ; 1 cut-out
1P0VDACDIG_I+ on TOP: 224.63,95.68 224.63,99.75 224.37,100 222.47,100 222.09,100.38 222.09,102.92 222.47,103.3 223.61,103.3 223.86,103.05 223.86,102.54 223.99,102.41 224.5,102.41 224.63,102.54 224.63,106.86 224.24,107.24 213.69,107.24 213.69,95.3 224.24,95.3
1P0VDACDIG_I- on TOP: 206.02,102.67 206.02,99.82 212.12,99.82 212.12,102.67
1P3V_I-_ADC1PO on TOP: 148.39,256.01 146.05,258.34 134.72,258.34 134.04,257.66 134.04,248.51 135.81,246.74 147.24,246.74 148.39,247.88
1P3V_I-_ADC1PO on BOTTOM: 147.88,250.04 147.62,250.29 146.48,250.29 145.97,249.78 145.97,248.79 145.08,247.9 145.08,246.99 145.34,246.74 147.24,246.74 147.88,247.37
1P3V_I-_ADC1PO on BOTTOM: 143.56,249.91 143.31,250.16 142.16,250.16 141.96,249.96 141.96,248.64 141,247.68 141,246.91 143.41,246.91 143.56,247.07
1P3V_I-_ADC1PO on BOTTOM: 139.45,250.22 139.37,250.29 138.23,250.29 137.97,250.04 137.97,248.72 136.93,247.68 136.93,247.14 137.16,246.91 138.99,246.91 139.45,247.37
1P3V_I-_DAC1PO on TOP: 170.74,273.02 160.63,273.02 160.63,270.87 164.34,270.87 164.34,266.6 162.36,264.62 170.74,264.62
1P3V_I-_DAC1PO on BOTTOM: 166.04,268.1 165.96,268.17 164.82,268.17 164.62,267.97 164.62,266.65 163.53,265.56 163.53,265.02 163.75,264.8 165.58,264.8 166.04,265.25
1P3V_I-_DAC1PO on BOTTOM: 170,268.05 168.71,268.05 168.71,266.67 167.59,265.56 167.59,264.69 169.75,264.69 170,264.95
1P3V_I-_SCLK on TOP: 171.81,265 175.16,265 175.16,272.97 172.97,272.97 172.97,266.9 171.81,265.73
1P3V_I-_SCLK on BOTTOM: 174.47,267.92 174.22,268.17 173.08,268.17 172.57,267.67 172.57,266.52 171.68,265.63 171.68,264.87 171.93,264.62 173.84,264.62 174.47,265.25
1P4V on TOP: 198.53,223.19 198.53,220.88 202.16,220.88 202.16,223.19
1P4V on TOP: 162.97,273.79 162.97,277.06 174.75,277.06 174.75,273.79
1P4V on TOP: 134.72,262.92 134.72,258.6 142.44,258.6 142.44,262.92
1P4V on L7_POWER: 136.88,263.65 136.88,258.67 158.72,258.67 158.72,263.58 161.19,266.04 161.19,269.49 162.86,271.17 176.33,271.17 180.97,266.52 180.97,241.38 184.89,241.38 193.98,232.28 193.98,232.21 201.57,224.61 201.57,223.37 201.47,223.27 198.32,223.27 198.32,220.5 207.54,220.5 213.08,226.03 213.08,257.25 189.66,280.67 162.89,280.67 162.89,280.67 159.31,280.67 142.29,263.65
2P1V on TOP: 198.93,218.52 202.34,218.52 202.34,211.73 198.78,211.73 198.78,213.84 200.53,213.84 200.53,215.75 200.3,215.98 198.93,215.98
2P1V on TOP: 212.34,179.5 212.34,182.32 210.46,182.32 210.46,190.58 206.91,190.58 206.91,179.5
2P1V on L7_POWER: 206.02,179.2 206.02,209.37 201.02,209.37 201.02,214.12 201.07,214.12 201.02,214.17 201.02,216.1 198.35,216.1 198.35,218.54 207.47,218.54 207.47,214.2 207.49,214.17 213.56,214.17 213.56,179.2
3P8V on TOP: 106.38,256.64 112.95,256.64 112.95,261.54 106.38,261.54 106.12,261.29 106.12,256.9
3P8V on BOTTOM: 96.39,262.15 96.39,259.82 98.65,257.56 110.74,257.56 111.84,258.65 111.84,262.66 111.07,263.42 97.66,263.42
3P8V on L16_POWER: 107.47,260.76 107.47,256.54 112.29,256.54 112.29,260.76
5P88V on TOP: 88.29,216.08 88.29,211.33 90.83,211.33 90.83,216.08
5P88V on TOP: 232.46,193.34 232.46,190.88 233.73,190.88 233.73,190.04 233.71,190.02 235.48,190.02 235.48,193.34
5P88V on TOP: 75.31,211.07 75.31,215.44 78.49,215.44 78.49,211.07
5P88V on L22_MIXED: 233.27,242.57 238.56,242.57 238.56,88.14 237.44,87.02 220.5,87.02 220.24,87.27 220.24,167.18 218.62,168.81 206.1,168.81 205.08,169.82 205.08,187.88 204.95,188.01 192.46,188.01 187.58,192.89 187.58,195.81 205.38,213.61 205.38,225.27 200.43,230.23 183.41,230.23 175.82,237.82 170.97,237.82 159.75,226.61 149.31,226.61 146.2,229.72 129.24,229.72 115.67,216.15 107.04,216.15 101.96,211.07 87.58,211.07 87.58,220.09 85.99,221.68 84.14,221.68 79.86,217.4 79.86,211.07 74.88,211.07 74.88,231.32 79.78,236.22 118.69,236.22 125.22,242.75 144.86,242.75 145.03,242.93 146.58,242.93 162.08,258.42 187.12,258.42 217.22,228.32 226.9,228.32 233.27,234.7 ; 3 cut-outs
ADF4030_3P3V on BOTTOM: 87.48,252.27 87.48,249.53 91.01,249.53 91.01,252.27
ADF4030_3P3V on BOTTOM: 100.56,236.86 100.56,234.49 106.1,234.49 106.1,236.86
ADF4030_3P3V on L11_POWER: 88.82,252.83 88.82,237.16 91.67,234.31 103.58,234.31 104.6,235.33 104.6,236.35 103.76,237.19 97.13,237.19 97.03,237.08 92.51,241.6 92.51,252.02 91.72,252.81 88.85,252.81
ADF4382_3P3_1 on BOTTOM: 125.81,174.14 125.81,172.44 131.62,172.44 131.62,174.14
ADF4382_3P3_1 on L22_MIXED: 116.52,165.46 116.5,153.29 129.95,153.29 129.95,163.58 127.15,166.37 127.15,168.99 128.24,170.07 131.98,170.07 131.98,174.27 126.77,174.27 126.77,172.21 120.02,165.46
ADF4382_3P3_2 on BOTTOM (solid shape): 124.84,151.57 124.84,151 123.49,151 123.49,151.89 124.52,151.89
ADF4382_3P3_2 on BOTTOM: 124.23,150.88 124.87,150.88 124.97,150.77 124.97,149.43 124.08,149.43 124.08,150.72
ADF4382_3P3_2 on BOTTOM: 116.48,174.07 116.48,164.87 121.69,164.87 121.69,174.07
ADF4382_3P3_2 on BOTTOM: 120.98,153.09 120.55,153.09 120.02,152.55 120.02,150.67 121.89,150.67 121.89,151.97 121.41,151.97 121.41,153.19 121.36,153.24 121.13,153.24
ADF4382_3P3_2 on BOTTOM: 126.52,153.24 126.77,153.24 127.74,152.27 127.74,150.16 127.46,149.89 126.37,149.89 126.31,149.94 126.31,151.74 126.52,151.94
ADF4382_3P3_2 on L16_POWER: 116.48,166.09 116.48,149.45 131.78,149.45 131.78,166.09
ADF4382_3P3V on BOTTOM (solid shape): 129.11,174.65 116.87,174.65 116.87,176.66 129.11,176.66
ADF4382_3P3V on BOTTOM: 104.29,245.29 104.29,239.98 103.78,239.98 103.63,239.83 103.63,238.3 103.68,238.25 104.22,238.25 104.29,238.33 105.69,238.33 105.69,246.56 105.54,246.71 103.73,246.71 103.58,246.56 103.58,245.59 103.71,245.47 104.11,245.47
ADF4382_3P3V on L16_POWER: 116.75,201.89 116.72,216.41 109,216.4 98.25,227.15 98.25,235.79 103.5,241.05 104.32,241.05 104.32,244.65 105.84,244.65 105.84,240.59 105.89,240.59 126.01,220.47 126.01,207.91 136.73,197.18 136.73,175.11 116.87,175.11 116.87,176.68 120.8,180.62 125.02,180.62 125.78,181.38 125.78,192.86
ADF4382_5P0V on BOTTOM: 83.87,217.04 83.87,219.1 86.11,219.1 86.11,216.03 82.55,216.03 82.55,217.04
ADF4382_5P0V on L16_POWER: 82.85,222.15 93.52,222.15 104.47,211.2 104.47,193.62 115.29,182.8 115.29,174.37 115.37,174.37 117.14,172.59 127.99,172.59 128.5,172.08 128.52,172.08 129.06,171.55 140.18,171.55 140.18,149.83 134.62,149.83 134.09,150.37 134.09,154.2 134.95,155.07 134.95,168.4 126.09,168.4 125.98,168.3 101.4,168.3 100.08,169.62 100.05,208.86 96.47,212.17 91.97,216.66 82.85,216.66
BRD_12V on TOP: 200.18,273.51 200.18,262.76 207.16,262.76 207.16,273.51
CLKC_N on BOTTOM (solid shape): 122.61,145.47 122.07,145.47 122.07,147.62 122.61,147.62
CLKC_P on BOTTOM (solid shape): 123.32,145.47 122.78,145.47 122.78,147.62 123.32,147.62
FMC_3P3V on L7_POWER: 88.06,3 138.61,3 138.61,9.04 101.8,9.04 101.8,24.08 99.72,26.16 94.56,26.16 88.06,19.66
FMC_3P3V on L16_POWER: 92.66,35.1 92.66,11.1 150.75,11.1 150.75,35.1
FMC_12P0V on L9_POWER: 87.88,20.14 87.88,34.77 101.93,34.77 101.93,20.14
HMC7044_3P3V on BOTTOM: 108.32,245.29 108.32,240.61 108.57,240.36 109.46,240.36 110.39,241.29 110.39,243.9 110.38,243.91 110.38,244.09 109.72,244.75 109.72,246.56 109.56,246.71 107.76,246.71 107.61,246.56 107.61,245.59 107.73,245.47 108.14,245.47
HMC7044_3P3V on L5_MIXED: 111.51,230.12 111.51,247.14 87.4,247.14 87.4,257.63 79.17,265.86 2.79,265.86 2.72,265.79 2.72,214.02 4.42,212.32 29.21,212.32 31.72,214.83 31.72,226.72 35.13,230.12 39.83,230.12 39.83,239.09 43.1,242.37 77.7,242.37 77.7,230.12 ; 1 cut-out
HMC7044_3P3V on L9_POWER: 111.51,230.12 111.51,247.14 86.92,247.14 76.07,257.99 27.79,257.99 2.72,232.92 2.72,214.02 4.42,212.32 29.21,212.32 31.72,214.83 31.72,226.72 35.13,230.12 39.83,230.12 46.28,236.58 58.85,236.58 65.3,230.12 ; 1 cut-out
LTC6955_3P3V on BOTTOM: 112.31,245.29 112.31,240.61 112.56,240.36 113.45,240.36 113.7,240.61 113.7,246.56 113.55,246.71 111.75,246.71 111.59,246.56 111.59,245.59 111.72,245.47 112.13,245.47
LTC6955_3P3V on L7_POWER: 43.28,244.63 43.28,222.86 43.33,222.81 68.91,222.81 69.55,223.44 69.55,233.32 115.09,233.32 115.09,244.63
LTM4681_VOUT01 on TOP: 193.34,42.44 215.52,42.44 215.77,42.7 215.77,58.32 215.39,58.7 213.23,58.7 212.47,57.94 212.47,55.91 211.33,54.76 198.91,54.76 198.91,52.76 198.78,52.63 192.56,52.63 192.49,52.69 189.48,49.68 189.48,46.3
LTM4681_VOUT01 on BOTTOM: 192.94,42.44 210.95,42.44 215.77,47.27 215.77,58.32 215.39,58.7 212.93,58.7 212.32,58.09 212.32,55.75 211.33,54.76 194.56,54.76 189.48,49.68 189.48,45.9
LTM4681_VOUT2 on TOP: 215.14,60.73 215.65,61.24 215.65,65.05 215.39,65.3 191.01,65.3 190.5,64.8 190.5,59.21 200.91,59.21 202.44,60.73
NEG2P4V on TOP: 225.32,145.24 225.32,142.6 227.91,142.6 227.91,145.24
NEG2P4V on TOP: 214.83,165.53 214.83,162.23 218.39,162.23 218.39,165.53
NEG2P4V on TOP: 214.17,154.99 214.17,152.12 216.99,152.12 216.99,154.99
NEG2P4V on TOP: 221.56,143.97 221.56,141.68 223.29,141.68 223.29,143.97
NEG2P4V on TOP: 219.25,140.18 228.45,140.18 228.45,145.08 226.62,145.08 225.58,146.13 225.6,146.15 225.6,150.52 219.25,150.52
NEG2P4V on BOTTOM: 227.66,142.9 227.66,144.91 225.22,144.91 225.22,144.3 222.83,144.3 222.83,147.14 223.29,147.14 223.29,151.61 223.27,151.64 217.98,151.64 217.98,140.59 225.55,140.59 225.55,142.9
NEG2P4V on L5_MIXED: 215.18,163.87 215.14,152.2 218.67,148.67 218.67,147.92 218.72,147.87 218.72,142.73 218.69,142.76 221.41,140.03 228.12,140.03 228.12,144.53 229.69,146.1 229.69,151.82 224.21,157.3 224.21,163.93 221.97,166.17 217.47,166.17
SYS_12V on TOP: 222,39.27 223.65,39.27 223.9,39.52 223.9,58.19 223.52,58.57 222.25,58.57 221.74,58.06 221.74,39.52
SYS_12V on TOP: 222.38,80.16 222.12,79.91 222.12,66.7 221.74,66.32 221.74,61.24 222.12,60.86 223.39,60.86 224.03,61.49 224.03,71.27 224.16,71.4 224.16,80.04 224.03,80.16
SYS_12V on TOP: 201.83,275.79 201.83,274.17 202.08,273.91 207.04,273.91 207.29,274.17 207.29,284.28 207.24,284.33 199.47,284.33 199.42,284.28 199.42,275.82 199.47,275.77 199.62,275.77 199.64,275.79
SYS_12V on TOP: 220.34,189.17 221.36,189.17 221.79,189.6 221.79,192.93 221.36,193.36 220.34,193.36 220.19,193.21 220.19,189.32
SYS_12V on TOP: 104.04,272.97 103.66,273.35 103.66,285.67 104.17,286.18 108.71,286.18 109.37,285.52 109.37,276.15 108.61,276.15 108.36,275.89 108.36,273.99 108.1,273.74 107.72,273.74 107.47,273.48 107.47,273.1 107.34,272.97
SYS_12V on TOP: 228.5,231.83 228.5,239.93 221.89,239.93 221.89,231.83
SYS_12V on TOP: 138.05,286.97 138.05,283.97 144.09,283.97 144.09,286.97
SYS_12V on TOP: 222.1,249.3 222.1,241.2 228.7,241.2 228.7,249.3
SYS_12V on TOP: 221.87,179.64 223.27,179.64 223.39,179.77 223.39,185.1 223.27,185.23 221.87,185.23 221.74,185.1 221.74,179.77
SYS_12V on TOP: 230.02,107.37 235.84,107.37 236.09,107.62 236.09,109.27 229.77,109.27 229.77,107.62
SYS_12V on TOP: 125.73,286.94 125.73,283.95 131.78,283.95 131.78,286.94
SYS_12V on TOP: 227.99,144.3 228.12,144.42 228.63,144.42 229.13,144.93 232.05,144.93 232.31,144.68 232.31,142.65 232.18,142.52 229.13,142.52 228.37,143.28 228.12,143.28 227.99,143.41
SYS_12V on BOTTOM: 222.5,80.16 223.65,80.16 223.9,79.91 223.9,61.37 223.39,60.86 222.12,60.86 221.74,61.24 221.74,62.13 221.62,62.26 218.69,62.26 218.44,62.51 218.44,62.89 218.69,63.14 221.62,63.14 221.74,63.27 221.74,66.07 222.25,66.57 222.25,79.91 ; 1 cut-out
SYS_12V on BOTTOM: 175.79,40.72 175.79,37.62 176.07,37.34 178.21,37.34 178.46,37.59 178.46,40.64 178.21,40.89 175.97,40.89
SYS_12V on BOTTOM: 222,39.27 223.65,39.27 223.9,39.52 223.9,58.19 223.52,58.57 222.25,58.57 221.74,58.06 221.74,57.3 221.62,57.18 221.74,57.18 221.74,56.29 221.62,56.29 221.74,56.16 221.74,39.52
SYS_12V on BOTTOM: 91.21,278.94 91.21,285.22 94.18,285.22 94.18,279.58 92.93,278.32 92.93,275.92 92.28,275.27 92.28,275.26 91.97,275.26 91.57,275.67 91.57,278.59
SYS_12V on L11_POWER: 90.5,285.9 90.5,265.28 156.26,265.28 156.26,276.58 157.2,277.52 178.56,277.52 179.04,277.04 179.04,265.35 179.12,265.28 208.43,265.28 214.27,259.44 214.27,87.07 214.1,86.89 214.1,46.61 175.36,46.61 174.96,46.2 174.96,36.5 174.9,35.86 181.1,35.79 211.15,35.84 214.12,35.86 223.19,35.84 239.75,35.84 239.75,47.73 239.73,57.18 239.7,71.75 239.73,82.68 239.73,97.84 239.75,108.84 239.73,122 239.67,129.87 239.67,140.54 239.73,151.05 239.67,166.52 239.67,179.07 239.62,190.5 239.62,271.04 239.6,285.8 ; 3 cut-outs
SYS_12V on L14_POWER: 90.5,265.48 90.5,286.74 239.6,286.64 239.62,271.04 239.62,190.5 239.67,179.07 239.67,166.52 239.73,151.05 239.67,140.54 239.67,129.87 239.73,122 239.75,108.84 239.73,97.84 239.73,82.68 239.7,71.75 239.73,57.18 239.75,47.73 239.75,35.84 223.19,35.84 214.12,35.86 211.15,35.84 181.1,35.79 174.9,35.86 174.96,36.5 174.96,44.17 185.72,44.17 188.16,46.61 214.1,46.61 214.1,86.89 214.3,87.1 214.3,231.65 214.1,231.85 214.1,247.17 195.78,265.48 180.34,265.48 180.01,265.81 180.01,277.67 178.87,278.82 156.74,278.82 156.06,278.13 156.06,265.51 156.03,265.48 ; 3 cut-outs
UNNAMED_7_CAP_I46_N2 on TOP (solid shape): 183.92,155.15 181.57,153.79 181.6,153.75 181.05,153.43 180.8,153.86 181.35,154.17 181.37,154.14 183.71,155.5
UNNAMED_7_CAP_I61_N2 on TOP (solid shape): 190.21,136.3 187.57,135.83 187.58,135.78 186.95,135.67 186.86,136.16 187.49,136.27 187.5,136.23 190.14,136.7
UNNAMED_7_CAP_I73_N2 on TOP (solid shape): 64.47,156.19 64.5,156.23 65.04,155.91 64.79,155.48 64.24,155.81 64.27,155.85 62.08,157.15 62.29,157.5
UNNAMED_7_CAP_I85_N2 on TOP (solid shape): 57.5,138.59 57.5,138.63 58.13,138.53 58.04,138.04 57.42,138.14 57.43,138.19 54.92,138.62 54.99,139.02
UNNAMED_7_CAP_I103_N2 on TOP (solid shape): 57.87,119.29 57.25,119.18 57.24,119.22 54.62,118.74 54.54,119.14 57.17,119.62 57.16,119.67 57.78,119.78
UNNAMED_7_CAP_I117_N2 on TOP (solid shape): 64.03,101.64 63.48,101.32 63.46,101.36 61.09,99.96 60.88,100.31 63.26,101.71 63.23,101.75 63.78,102.07
UNNAMED_7_CAP_I131_N2 on TOP (solid shape): 187.14,117.33 187.14,117.29 189.75,116.82 189.68,116.42 187.07,116.89 187.06,116.84 186.43,116.95 186.52,117.44
UNNAMED_7_CAP_I145_N2 on TOP (solid shape): 180.12,99.76 180.1,99.72 182.64,98.25 182.43,97.9 179.89,99.37 179.87,99.33 179.11,99.77 179.36,100.2
UNNAMED_14_ADLTC4210_I253_ON on TOP: 185.7,244.7 190.78,244.7 191.03,244.96 191.03,253.21 190.78,253.47 185.7,253.47 185.45,253.21 185.45,244.96
UNNAMED_14_ADLTC4210_I253_VCC on TOP: 217.45,256.64 217.45,262.1 217.07,262.48 195.1,262.48 194.46,261.85 194.46,256.64 194.91,256.2 217,256.2
UNNAMED_14_CN3P_I249_N3 on TOP: 222.38,223.63 222.38,221.17 222.43,221.17 222.43,216.33 223.57,215.19 227.58,215.19 227.91,215.52 227.91,221.17 232.49,221.17 232.49,223.63
UNNAMED_14_CN6P_I246_N1 on TOP: 207.47,262.84 213.51,262.84 213.51,273.79 213.26,274.04 207.47,274.04
UNNAMED_14_DIOSCHOTTKY_I285_P on TOP: 210.34,252.07 219.61,252.07 219.86,252.32 219.86,255.63 219.39,256.1 217.67,256.1 217.32,255.75 210.46,255.75 209.96,255.24 209.96,252.45
UNNAMED_14_DIOSCHOTTKY_I318_N on TOP: 220.37,251.31 225.83,251.31 226.09,251.56 226.09,255.37 225.83,255.63 220.37,255.63 220.12,255.37 220.12,251.56
UNNAMED_14_RES_I262_N1 on TOP: 191.54,241.4 196.62,241.4 196.88,241.66 196.88,249.91 196.62,250.16 191.54,250.16 191.29,249.91 191.29,241.66
UNNAMED_34_AD90888T8RSEB0_I517_VPLL1P0VREG on TOP: 102.44,137.21 102.44,135 104.57,135 104.57,137.21
UNNAMED_34_AD90888T8RSEB0_I517_VPLL1P0VREG on L7_POWER: 102.44,137.19 103.58,137.19 110.67,130.1 122.71,130.1 122.71,129.46 122.45,129.21 108.41,129.21 102.44,135.18
UNNAMED_38_ADLTM4702_I15_SVIN on TOP: 224.78,106.81 225.16,107.19 236.14,107.19 236.14,101.52 236.19,101.47 227.95,101.47 227.95,102.23 227.7,102.49 225.79,102.49 225.54,102.74 225.54,103.12 225.29,103.38 224.9,103.38 224.78,103.51
UNNAMED_38_CAP_I48_N2 on BOTTOM: 172.24,41.28 171.6,41.91 168.55,41.91 168.43,41.78 168.43,40.89 168.68,40.64 169.32,40.64 170.71,39.24 172.11,39.24 172.62,38.73 175.41,38.73 175.67,38.99 175.67,40.77 175.16,41.28
UNNAMED_38_CAP_I52_N2 on BOTTOM: 166.4,39.75 166.4,40.39 166.14,40.64 164.62,40.64 163.98,41.28 160.17,41.28 159.92,41.02 159.92,39.88 160.17,39.62 166.27,39.62
UNNAMED_39_ADLTM4702_I7_SVIN on TOP: 139.27,273.35 138.89,273.74 138.89,283.39 139.27,283.77 144.35,283.77 144.6,283.51 144.6,276.53 143.84,276.53 143.59,276.28 143.59,274.37 143.33,274.12 142.95,274.12 142.7,273.86 142.7,273.48 142.57,273.35
UNNAMED_39_ADLTM4702_I7_VOUT1 on TOP: 150.44,273.23 146.38,273.23 146.13,272.97 146.13,271.07 145.75,270.69 143.21,270.69 142.82,271.07 142.82,272.21 143.08,272.47 143.59,272.47 143.71,272.59 143.71,273.1 143.59,273.23 139.27,273.23 138.89,272.85 138.89,263.19 138.94,263.14 138.94,261.01 140.31,259.64 149.05,259.64 150.83,261.42 150.83,272.85
UNNAMED_39_ADLTM4702_I63_SVIN on TOP: 126.44,273.35 126.06,273.74 126.06,283.39 126.44,283.77 131.52,283.77 131.78,283.51 131.78,276.53 131.01,276.53 130.76,276.28 130.76,274.37 130.51,274.12 130.12,274.12 129.87,273.86 129.87,273.48 129.74,273.35
UNNAMED_39_ADLTM4702_I63_VOUT1 on TOP: 137.62,273.18 133.55,273.18 133.3,272.92 133.3,271.02 132.92,270.64 130.38,270.64 130,271.02 130,272.16 130.25,272.42 130.76,272.42 130.89,272.54 130.89,273.05 130.76,273.18 126.44,273.18 126.06,272.8 126.06,263.12 129.67,259.51 136.96,259.51 138,260.55 138,272.8
UNNAMED_40_ADLTM8051_I7_VOUT11 on TOP: 211.73,188.4 217.55,188.4 217.81,188.66 217.81,193.09 211.73,193.09
UNNAMED_40_ADLTM8051_I7_VOUT21 on TOP: 225.3,185.85 225.3,180.31 227.08,180.31 227.08,182.75 231.14,182.75 231.14,185.85
UNNAMED_40_ADLTM8051_I7_VOUT31 on TOP: 230.86,196.8 230.86,188.52 225.27,188.52 225.27,196.8
UNNAMED_40_ADLTM8051_I7_VOUT41 on TOP: 213.36,179.77 217.55,179.77 217.6,179.82 217.6,182.83 217.3,183.13 217.3,184.33 217.32,184.33 217.78,184.79 217.78,185.86 213.36,185.86 212.62,185.13 212.62,180.51
UNNAMED_41_ADLTM4709_I2_VOUT11 on BOTTOM: 144.4,230.15 129.92,230.15 129.92,233.96 132.16,233.96 132.16,237.97 135.25,237.97 135.25,241.27 137.85,243.87 137.85,244.98 137.69,245.14 137.26,245.14 137.03,245.36 137.03,246.46 137.21,246.63 139.17,246.63 139.4,246.41 139.4,242.42 138.25,241.27 138.25,238.02 141.27,238.02 141.27,241.25 141.82,241.8 141.82,244.98 141.67,245.14 141.24,245.14 141.01,245.36 141.01,246.46 141.14,246.58 143.19,246.58 143.37,246.41 143.37,244.07 144.37,243.07 144.37,238.02 144.4,238.02
UNNAMED_41_ADLTM4709_I2_VOUT31 on BOTTOM: 145.08,246.51 150.65,246.51 150.65,233.53 146.56,233.53 146.56,237.03 147.4,237.87 147.4,242.7 146.63,243.38 146.63,244.02 145.08,245.57
